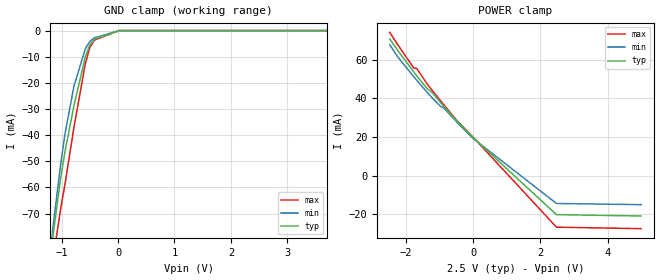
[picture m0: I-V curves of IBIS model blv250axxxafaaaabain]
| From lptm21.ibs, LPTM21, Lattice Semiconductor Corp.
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|   Model blv250axxxafaaaabain
[Model]   blv250axxxafaaaabain
Model_type   Input
Polarity   Non-Inverting
Enable   Active-Low
Vinl =   1.1500V
Vinh =   1.3500V
C_comp   4.2000pF   3.8000pF   7.5000pF
[Temperature Range]   25.0000   0.1050k   -40.0000
[Voltage Range]   2.5000V   2.3800V   2.6300V
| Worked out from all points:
|   GND clamp passes 1 mA (typ) near -0.13 V on its own axis
[GND_clamp]
|Voltage   I(typ)   I(min)   I(max)
-2.5V     -558.7mA   -538.8mA   -577.3mA
-1.22V    -91.65mA   -88.51mA   -100.2mA
-1.18V    -84.01mA   -80.7mA    -92.85mA
-1.14V    -76.64mA   -73.08mA   -85.95mA
-1.02V    -56.82mA   -51.79mA   -68.7mA
-940mV    -46.33mA   -39.59mA   -58.84mA
-780mV    -28.68mA   -21.23mA   -36.93mA
-580mV    -10.13mA   -7.016mA   -12.79mA
-500mV    -5.522mA   -4.164mA   -6.524mA
-420mV    -3.293mA   -2.799mA   -3.655mA
20mV      0A         0A         0A
5V        0A         0A         0A
[POWER_clamp]
|Voltage   I(typ)   I(min)   I(max)
-2.48V    70.8mA     67.79mA    74.22mA
-2.24V    64.81mA    61.5mA     67.79mA
-1.76V    53.56mA    51.12mA    55.62mA
-1.68V    51.75mA    49.46mA    55.62mA
-1.36V    44.95mA    43.02mA    47.29mA
-1.2V     42.73mA    39.97mA    43.79mA
-960mV    37.69mA    35.72mA    38.61mA
-880mV    36.09mA    35.18mA    36.9mA
-480mV    28.21mA    27.66mA    28.47mA
0V        19.67mA    19.21mA    19.91mA
2.48V     -20.27mA   -14.48mA   -26.76mA
5V        -20.96mA   -15.08mA   -27.53mA
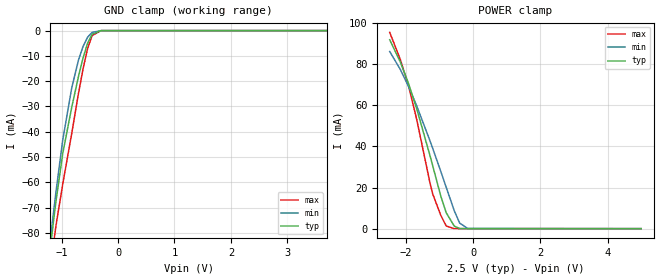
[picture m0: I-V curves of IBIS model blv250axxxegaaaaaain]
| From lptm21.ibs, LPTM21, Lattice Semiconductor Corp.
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|   Model blv250axxxegaaaaaain
[Model]   blv250axxxegaaaaaain
Model_type   Input
Polarity   Non-Inverting
Enable   Active-Low
Vinl =   1.1500V
Vinh =   1.3500V
C_comp   4.2000pF   3.8000pF   7.5000pF
[Temperature Range]   25.0000   0.1050k   -40.0000
[Voltage Range]   2.5000V   2.3800V   2.6300V
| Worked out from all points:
|   GND clamp passes 1 mA (typ) near -0.44 V on its own axis
|   POWER clamp passes 1 mA (typ) near -0.54 V on its own axis
[GND_clamp]
|Voltage   I(typ)   I(min)   I(max)
-2.5V     -564.7mA   -543.1mA   -585.2mA
-1.18V    -82.35mA   -79.03mA   -91.15mA
-1.14V    -74.88mA   -71.38mA   -83.96mA
-1.1V     -67.69mA   -63.94mA   -77.25mA
-980mV    -48.66mA   -43.36mA   -60.79mA
-820mV    -30.34mA   -22.65mA   -40.66mA
-700mV    -18.09mA   -11.63mA   -24.79mA
-620mV    -10.87mA   -6.335mA   -15.23mA
-540mV    -5.061mA   -2.654mA   -7.227mA
-460mV    -1.446mA   -714.8uA   -1.98mA
-300mV    -18.71uA   -15.93uA   -16.53uA
5V        0A         0A         0A
[POWER_clamp]
|Voltage   I(typ)   I(min)   I(max)
-2.48V    91.96mA    86.23mA    95.54mA
-2.16V    80.94mA    77.35mA    82.15mA
-1.92V    70.61mA    69.17mA    69.43mA
-1.68V    58.52mA    59.9mA     53.37mA
-1.28V    35.44mA    42.67mA    22.07mA
-1.2V     30.53mA    39.03mA    16.84mA
-960mV    15.8mA     27.82mA    6.447mA
-800mV    7.76mA     20.14mA    1.303mA
-560mV    1.23mA     8.728mA    11.53uA
-400mV    83.98uA    2.726mA    532.6nA
-160mV    776.1nA    102uA      144nA
5V        -44.09nA   -38.33nA   -118.7nA
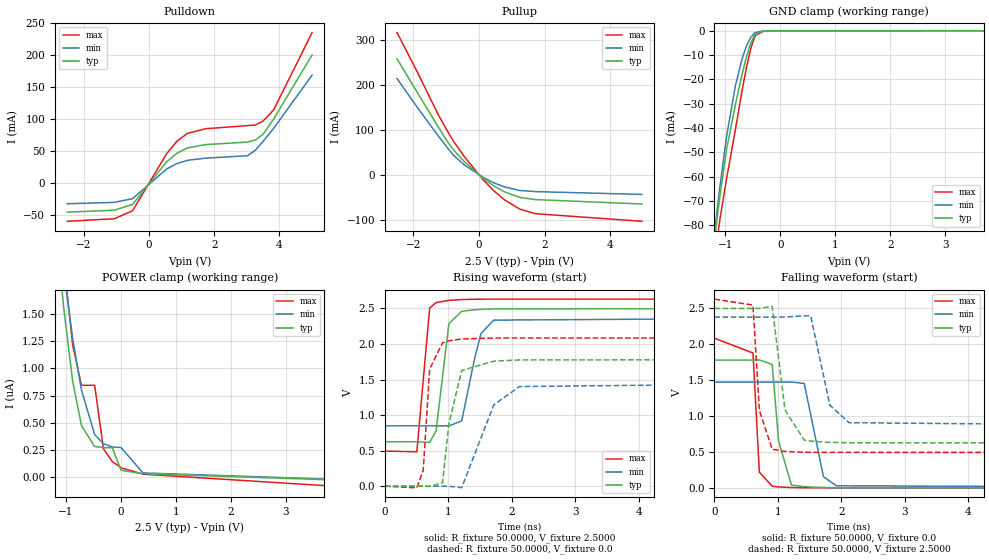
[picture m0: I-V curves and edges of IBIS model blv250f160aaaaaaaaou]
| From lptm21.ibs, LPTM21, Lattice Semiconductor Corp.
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|   Model blv250f160aaaaaaaaou
[Model]   blv250f160aaaaaaaaou
Model_type   Output
Polarity   Non-Inverting
Enable   Active-Low
Vmeas =   1.2500V
Cref =   3.0000pF
Rref =   50.0000
Vref =   1.2500V
C_comp   4.2000pF   3.8000pF   7.5000pF
[Temperature Range]   25.0000   0.1050k   -40.0000
[Voltage Range]   2.5000V   2.3800V   2.6300V
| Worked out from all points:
|   slope of the pulldown table from 0 to 0.375 V, typ, clamps not added: 15.3 ohm
|   slope of the pullup table from 0 to 0.375 V, typ, clamps not added: 18 ohm
|   GND clamp passes 1 mA (typ) near -0.44 V on its own axis
|   rising waveform, R_fixture 50.0000, V_fixture 2.5000: 20-80 % time 151ps typ, 227ps min, 128ps max; typ from 0.625 V to 2.5 V
|   rising waveform, R_fixture 50.0000, V_fixture 0.0: 20-80 % time 162ps typ, 247ps min, 94.8ps max; typ from 0 V to 1.78 V
|   falling waveform, R_fixture 50.0000, V_fixture 0.0: 20-80 % time 129ps typ, 166ps min, 76.1ps max; typ from 1.78 V to 0 V
|   falling waveform, R_fixture 50.0000, V_fixture 2.5000: 20-80 % time 161ps typ, 218ps min, 111ps max; typ from 2.5 V to 0.625 V
[Pulldown]
|Voltage   I(typ)   I(min)   I(max)
-2.5V     -45.01mA   -31.89mA   -59.32mA
-1.06V    -42.02mA   -29.78mA   -55.34mA
-500mV    -32.92mA   -23.97mA   -42.85mA
540mV     33.4mA     22.28mA    46.08mA
860mV     47.04mA    30.89mA    65.83mA
1.18V     55.26mA    35.92mA    77.97mA
1.74V     60.53mA    39.31mA    85.33mA
3.02V     64.43mA    43.11mA    90.12mA
3.26V     67.48mA    51.68mA    91mA
3.5V      76.79mA    65.62mA    97.37mA
3.82V     100.3mA    85.69mA    114.5mA
5V        200.4mA    169mA      235.5mA
[Pullup]
|Voltage   I(typ)   I(min)   I(max)
-2.5V     258.2mA    214.4mA    316.6mA
-1.88V    183.3mA    150mA      228.6mA
-1.24V    106.2mA    86.52mA    133.5mA
-920mV    69.28mA    56.27mA    92.01mA
-760mV    54.09mA    42.32mA    72.99mA
-440mV    29.04mA    21.78mA    39.92mA
120mV     -7.175mA   -5.214mA   -10.22mA
440mV     -23.93mA   -17.18mA   -34.6mA
760mV     -37.13mA   -26.3mA    -54.62mA
1.24V     -50.01mA   -34.55mA   -75.93mA
1.72V     -54.85mA   -37.09mA   -86.23mA
4.96V     -64.63mA   -43.33mA   -103.1mA
[GND_clamp]
|Voltage   I(typ)   I(min)   I(max)
-2.5V     -564.7mA   -543.1mA   -585.2mA
-1.18V    -82.35mA   -79.03mA   -91.15mA
-1.14V    -74.88mA   -71.38mA   -83.96mA
-1.1V     -67.69mA   -63.94mA   -77.25mA
-980mV    -48.66mA   -43.36mA   -60.79mA
-820mV    -30.34mA   -22.65mA   -40.66mA
-700mV    -18.09mA   -11.63mA   -24.79mA
-620mV    -10.87mA   -6.335mA   -15.23mA
-540mV    -5.061mA   -2.654mA   -7.227mA
-460mV    -1.446mA   -714.8uA   -1.98mA
-300mV    -18.71uA   -15.93uA   -16.53uA
5V        0A         0A         0A
[POWER_clamp]
|Voltage   I(typ)   I(min)   I(max)
-2.48V    16.67uA    13.46uA    27.27uA
-1.2V     2.437uA    2.654uA    3.193uA
-1.12V    1.961uA    2.256uA    2.523uA
-1.04V    1.543uA    1.893uA    1.968uA
-880mV    882.5nA    1.274uA    1.214uA
-720mV    473.9nA    800.3nA    844.3nA
-480mV    282.1nA    391.2nA    844.3nA
-320mV    271.3nA    307.6nA    260.6nA
-160mV    271.3nA    277.8nA    144nA
0V        63.22nA    272nA      86.34nA
400mV     31.61nA    39.07nA    27.38nA
5V        -44.09nA   -38.33nA   -118.7nA
[Ramp]
| variable   typ   min   max
dV/dt_r  1.0688/0.1604n   0.8847/0.2443n   1.2507/93.8258p
dV/dt_f  1.1250/0.1592n   0.9191/0.2160n   1.2817/0.1102n
R_load = 50.0000
[Rising Waveform]
R_fixture=   50.0000
V_fixture=   2.5000
V_fixture_min=   2.3800
V_fixture_max=   2.6300
|time   V(typ)   V(min)   V(max)
0s        625.1mV    848.2mV    493.8mV
505.1ps   625.1mV    848.2mV    483.9mV
707.1ps   617.1mV    848.2mV    2.504V
808.1ps   777mV      848.3mV    2.581V
1.01ns    2.285V     846.8mV    2.613V
1.212ns   2.459V     919.1mV    2.624V
1.414ns   2.481V     1.791V     2.628V
1.515ns   2.486V     2.145V     2.629V
1.717ns   2.493V     2.335V     2.63V
10ns      2.5V       2.38V      2.63V
[Rising Waveform]
R_fixture=   50.0000
V_fixture=   0.0
V_fixture_min=   0.0
V_fixture_max=   0.0
|time   V(typ)   V(min)   V(max)
0s        394.5nV    565.3nV    312nV
505.1ps   17.53uV    728.7nV    -23.3mV
606.1ps   -153.3uV   722.6nV    227.1mV
707.1ps   -3.764mV   9.302uV    1.646V
909.1ps   47.24mV    -32.83uV   2.015V
1.01ns    876.9mV    -402.3uV   2.044V
1.212ns   1.627V     -20.32mV   2.07V
1.717ns   1.758V     1.143V     2.083V
2.121ns   1.775V     1.401V     2.084V
10ns      1.781V     1.474V     2.084V
[Falling Waveform]
R_fixture=   50.0000
V_fixture=   0.0
V_fixture_min=   0.0
V_fixture_max=   0.0
|time   V(typ)   V(min)   V(max)
0s        1.781V     1.474V     2.085V
606.1ps   1.781V     1.474V     1.879V
707.1ps   1.782V     1.474V     218.8mV
909.1ps   1.721V     1.474V     23.28mV
1.01ns    651.4mV    1.474V     13.07mV
1.212ns   38.57mV    1.475V     4.117mV
1.414ns   15.95mV    1.455V     1.284mV
1.717ns   5.3mV      156.1mV    203.4uV
1.919ns   2.469mV    29.32mV    71.82uV
10ns      15.52uV    -1.266uV   20.45uV
[Falling Waveform]
R_fixture=   50.0000
V_fixture=   2.5000
V_fixture_min=   2.3800
V_fixture_max=   2.6300
|time   V(typ)   V(min)   V(max)
0s        2.5V       2.38V      2.63V
606.1ps   2.5V       2.38V      2.547V
707.1ps   2.501V     2.38V      1.082V
909.1ps   2.529V     2.38V      538.3mV
1.111ns   1.085V     2.381V     507.8mV
1.414ns   665.1mV    2.397V     496.4mV
1.515ns   652.2mV    2.397V     495.3mV
1.818ns   634.3mV    1.151V     494.1mV
2.121ns   628.4mV    907.9mV    493.9mV
10ns      625.1mV    848.2mV    493.8mV
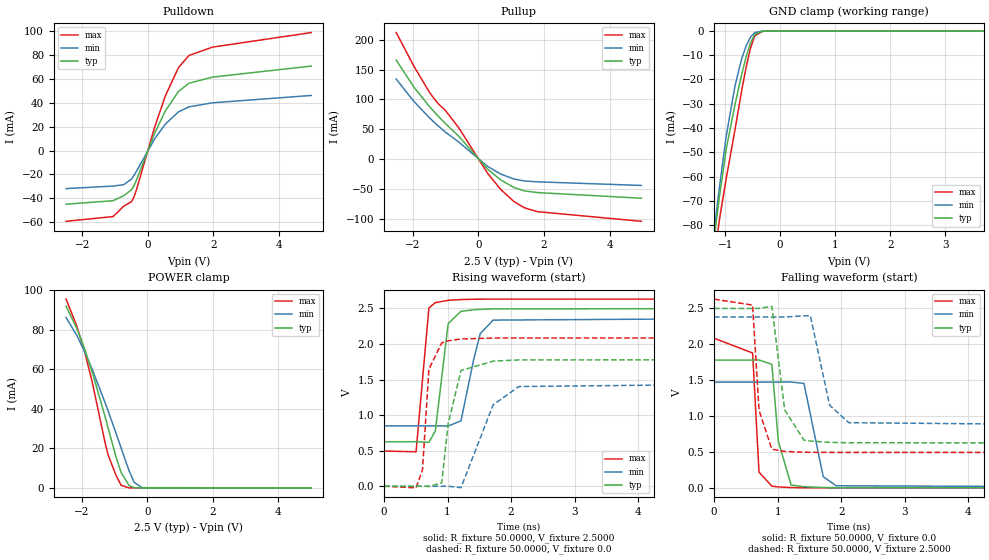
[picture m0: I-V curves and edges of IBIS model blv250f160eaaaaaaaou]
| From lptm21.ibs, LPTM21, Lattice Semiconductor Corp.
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|   Model blv250f160eaaaaaaaou
[Model]   blv250f160eaaaaaaaou
Model_type   Output
Polarity   Non-Inverting
Enable   Active-Low
Vmeas =   1.2500V
Cref =   3.0000pF
Rref =   50.0000
Vref =   1.2500V
C_comp   4.2000pF   3.8000pF   7.5000pF
[Temperature Range]   25.0000   0.1050k   -40.0000
[Voltage Range]   2.5000V   2.3800V   2.6300V
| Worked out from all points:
|   slope of the pulldown table from 0 to 0.375 V, typ, clamps not added: 15.3 ohm
|   slope of the pullup table from 0 to 0.375 V, typ, clamps not added: 18 ohm
|   GND clamp passes 1 mA (typ) near -0.44 V on its own axis
|   POWER clamp passes 1 mA (typ) near -0.54 V on its own axis
|   rising waveform, R_fixture 50.0000, V_fixture 2.5000: 20-80 % time 151ps typ, 227ps min, 128ps max; typ from 0.625 V to 2.5 V
|   rising waveform, R_fixture 50.0000, V_fixture 0.0: 20-80 % time 162ps typ, 247ps min, 94.8ps max; typ from 0 V to 1.78 V
|   falling waveform, R_fixture 50.0000, V_fixture 0.0: 20-80 % time 129ps typ, 166ps min, 76.1ps max; typ from 1.78 V to 0 V
|   falling waveform, R_fixture 50.0000, V_fixture 2.5000: 20-80 % time 161ps typ, 218ps min, 111ps max; typ from 2.5 V to 0.625 V
[Pulldown]
|Voltage   I(typ)   I(min)   I(max)
-2.5V     -45.01mA   -31.89mA   -59.32mA
-1.06V    -42.02mA   -29.78mA   -55.34mA
-740mV    -37.94mA   -28.65mA   -46.63mA
-500mV    -32.92mA   -23.97mA   -42.85mA
-420mV    -29.33mA   -20.8mA    -38.83mA
-340mV    -24.22mA   -16.99mA   -32.2mA
220mV     15.1mA     10.24mA    20.53mA
540mV     33.4mA     22.28mA    46.08mA
940mV     49.63mA    32.48mA    69.67mA
1.26V     56.49mA    36.69mA    79.75mA
1.98V     61.61mA    40.05mA    86.74mA
5V        70.84mA    46.21mA    98.95mA
[Pullup]
|Voltage   I(typ)   I(min)   I(max)
-2.5V     165.7mA    134mA      211.6mA
-1.96V    120.5mA    96.72mA    155.3mA
-1.48V    87.72mA    68.96mA    111.3mA
-1.24V    73.19mA    56.8mA     94mA
-1V       59.8mA     45.49mA    81.65mA
-600mV    38.92mA    29.24mA    53.03mA
280mV     -15.99mA   -11.55mA   -22.94mA
680mV     -34.17mA   -24.29mA   -50.04mA
1.08V     -46.66mA   -32.52mA   -70.04mA
1.4V      -52.41mA   -35.87mA   -80.58mA
1.8V      -55.2mA    -37.28mA   -87.03mA
4.96V     -64.63mA   -43.33mA   -103.1mA
[GND_clamp]
|Voltage   I(typ)   I(min)   I(max)
-2.5V     -564.7mA   -543.1mA   -585.2mA
-1.18V    -82.35mA   -79.03mA   -91.15mA
-1.14V    -74.88mA   -71.38mA   -83.96mA
-1.1V     -67.69mA   -63.94mA   -77.25mA
-980mV    -48.66mA   -43.36mA   -60.79mA
-820mV    -30.34mA   -22.65mA   -40.66mA
-700mV    -18.09mA   -11.63mA   -24.79mA
-620mV    -10.87mA   -6.335mA   -15.23mA
-540mV    -5.061mA   -2.654mA   -7.227mA
-460mV    -1.446mA   -714.8uA   -1.98mA
-300mV    -18.71uA   -15.93uA   -16.53uA
5V        0A         0A         0A
[POWER_clamp]
|Voltage   I(typ)   I(min)   I(max)
-2.48V    91.96mA    86.23mA    95.54mA
-2.16V    80.94mA    77.35mA    82.15mA
-1.92V    70.61mA    69.17mA    69.43mA
-1.68V    58.52mA    59.9mA     53.37mA
-1.28V    35.44mA    42.67mA    22.07mA
-1.2V     30.53mA    39.03mA    16.84mA
-960mV    15.8mA     27.82mA    6.447mA
-800mV    7.76mA     20.14mA    1.303mA
-560mV    1.23mA     8.728mA    11.53uA
-400mV    83.98uA    2.726mA    532.6nA
-160mV    776.1nA    102uA      144nA
5V        -44.09nA   -38.33nA   -118.7nA
[Ramp]
| variable   typ   min   max
dV/dt_r  1.0688/0.1604n   0.8847/0.2443n   1.2507/93.8258p
dV/dt_f  1.1250/0.1592n   0.9191/0.2160n   1.2817/0.1102n
R_load = 50.0000
[Rising Waveform]
R_fixture=   50.0000
V_fixture=   2.5000
V_fixture_min=   2.3800
V_fixture_max=   2.6300
|time   V(typ)   V(min)   V(max)
0s        625.1mV    848.2mV    493.8mV
505.1ps   625.1mV    848.2mV    483.9mV
707.1ps   617.1mV    848.2mV    2.504V
808.1ps   777mV      848.3mV    2.581V
1.01ns    2.285V     846.8mV    2.613V
1.212ns   2.459V     919.1mV    2.624V
1.414ns   2.481V     1.791V     2.628V
1.515ns   2.486V     2.145V     2.629V
1.717ns   2.493V     2.335V     2.63V
10ns      2.5V       2.38V      2.63V
[Rising Waveform]
R_fixture=   50.0000
V_fixture=   0.0
V_fixture_min=   0.0
V_fixture_max=   0.0
|time   V(typ)   V(min)   V(max)
0s        394.5nV    565.3nV    312nV
505.1ps   17.53uV    728.7nV    -23.3mV
606.1ps   -153.3uV   722.6nV    227.1mV
707.1ps   -3.764mV   9.302uV    1.646V
909.1ps   47.24mV    -32.83uV   2.015V
1.01ns    876.9mV    -402.3uV   2.044V
1.212ns   1.627V     -20.32mV   2.07V
1.717ns   1.758V     1.143V     2.083V
2.121ns   1.775V     1.401V     2.084V
10ns      1.781V     1.474V     2.084V
[Falling Waveform]
R_fixture=   50.0000
V_fixture=   0.0
V_fixture_min=   0.0
V_fixture_max=   0.0
|time   V(typ)   V(min)   V(max)
0s        1.781V     1.474V     2.085V
606.1ps   1.781V     1.474V     1.879V
707.1ps   1.782V     1.474V     218.8mV
909.1ps   1.721V     1.474V     23.28mV
1.01ns    651.4mV    1.474V     13.07mV
1.212ns   38.57mV    1.475V     4.117mV
1.414ns   15.95mV    1.455V     1.284mV
1.717ns   5.3mV      156.1mV    203.4uV
1.919ns   2.469mV    29.32mV    71.82uV
10ns      15.52uV    -1.266uV   20.45uV
[Falling Waveform]
R_fixture=   50.0000
V_fixture=   2.5000
V_fixture_min=   2.3800
V_fixture_max=   2.6300
|time   V(typ)   V(min)   V(max)
0s        2.5V       2.38V      2.63V
606.1ps   2.5V       2.38V      2.547V
707.1ps   2.501V     2.38V      1.082V
909.1ps   2.529V     2.38V      538.3mV
1.111ns   1.085V     2.381V     507.8mV
1.414ns   665.1mV    2.397V     496.4mV
1.515ns   652.2mV    2.397V     495.3mV
1.818ns   634.3mV    1.151V     494.1mV
2.121ns   628.4mV    907.9mV    493.9mV
10ns      625.1mV    848.2mV    493.8mV
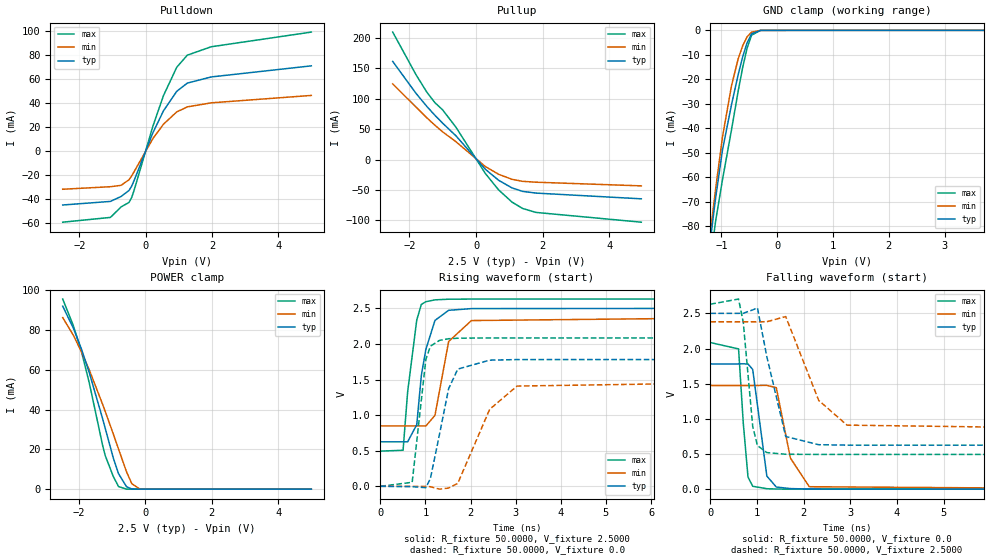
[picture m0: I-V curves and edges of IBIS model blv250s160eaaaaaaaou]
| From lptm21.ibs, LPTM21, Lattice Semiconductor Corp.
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|   Model blv250s160eaaaaaaaou
[Model]   blv250s160eaaaaaaaou
Model_type   Output
Polarity   Non-Inverting
Enable   Active-Low
Vmeas =   1.2500V
Cref =   3.0000pF
Rref =   50.0000
Vref =   1.2500V
C_comp   4.2000pF   3.8000pF   7.5000pF
[Temperature Range]   25.0000   0.1050k   -40.0000
[Voltage Range]   2.5000V   2.3800V   2.6300V
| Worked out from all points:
|   slope of the pulldown table from 0 to 0.375 V, typ, clamps not added: 15.3 ohm
|   slope of the pullup table from 0 to 0.375 V, typ, clamps not added: 18 ohm
|   GND clamp passes 1 mA (typ) near -0.44 V on its own axis
|   POWER clamp passes 1 mA (typ) near -0.54 V on its own axis
|   rising waveform, R_fixture 50.0000, V_fixture 2.5000: 20-80 % time 272ps typ, 308ps min, 221ps max; typ from 0.625 V to 2.5 V
|   rising waveform, R_fixture 50.0000, V_fixture 0.0: 20-80 % time 340ps typ, 590ps min, 210ps max; typ from 0 V to 1.78 V
|   falling waveform, R_fixture 50.0000, V_fixture 0.0: 20-80 % time 209ps typ, 295ps min, 139ps max; typ from 1.78 V to 0 V
|   falling waveform, R_fixture 50.0000, V_fixture 2.5000: 20-80 % time 297ps typ, 529ps min, 177ps max; typ from 2.5 V to 0.625 V
[Pulldown]
|Voltage   I(typ)   I(min)   I(max)
-2.5V     -45.01mA   -31.89mA   -59.32mA
-1.06V    -42.02mA   -29.78mA   -55.34mA
-740mV    -37.94mA   -28.65mA   -46.63mA
-500mV    -32.92mA   -23.97mA   -42.85mA
-420mV    -29.33mA   -20.8mA    -38.83mA
-340mV    -24.22mA   -16.99mA   -32.2mA
220mV     15.1mA     10.24mA    20.53mA
540mV     33.4mA     22.28mA    46.08mA
940mV     49.63mA    32.48mA    69.67mA
1.26V     56.49mA    36.69mA    79.75mA
1.98V     61.61mA    40.05mA    86.74mA
5V        70.84mA    46.21mA    98.95mA
[Pullup]
|Voltage   I(typ)   I(min)   I(max)
-2.5V     161.5mA    124.6mA    209.8mA
-1.8V     108.9mA    86.32mA    139.6mA
-1.48V    87.72mA    68.93mA    111.3mA
-1.24V    73.19mA    56.8mA     94mA
-1V       59.8mA     45.49mA    81.65mA
-600mV    38.92mA    29.24mA    53.03mA
280mV     -15.99mA   -11.55mA   -22.94mA
680mV     -34.17mA   -24.29mA   -50.04mA
1.08V     -46.66mA   -32.52mA   -70.04mA
1.4V      -52.41mA   -35.87mA   -80.58mA
1.8V      -55.2mA    -37.28mA   -87.03mA
4.96V     -64.63mA   -43.33mA   -103.1mA
[GND_clamp]
|Voltage   I(typ)   I(min)   I(max)
-2.5V     -564.7mA   -543.1mA   -585.2mA
-1.18V    -82.35mA   -79.03mA   -91.15mA
-1.14V    -74.88mA   -71.38mA   -83.96mA
-1.1V     -67.69mA   -63.94mA   -77.25mA
-980mV    -48.66mA   -43.36mA   -60.79mA
-820mV    -30.34mA   -22.65mA   -40.66mA
-700mV    -18.09mA   -11.63mA   -24.79mA
-620mV    -10.87mA   -6.335mA   -15.23mA
-540mV    -5.061mA   -2.654mA   -7.227mA
-460mV    -1.446mA   -714.8uA   -1.98mA
-300mV    -18.71uA   -15.93uA   -16.53uA
5V        0A         0A         0A
[POWER_clamp]
|Voltage   I(typ)   I(min)   I(max)
-2.48V    91.96mA    86.23mA    95.54mA
-2.16V    80.94mA    77.35mA    82.15mA
-1.92V    70.61mA    69.17mA    69.43mA
-1.68V    58.52mA    59.9mA     53.37mA
-1.28V    35.44mA    42.67mA    22.07mA
-1.2V     30.53mA    39.03mA    16.84mA
-960mV    15.8mA     27.82mA    6.447mA
-800mV    7.76mA     20.14mA    1.303mA
-560mV    1.23mA     8.728mA    11.53uA
-400mV    83.98uA    2.726mA    532.6nA
-160mV    776.1nA    102uA      144nA
5V        -44.09nA   -38.33nA   -118.7nA
[Ramp]
| variable   typ   min   max
dV/dt_r  1.0688/0.3361n   0.8847/0.5844n   1.2507/0.2078n
dV/dt_f  1.1250/0.2937n   0.9191/0.5242n   1.2817/0.1754n
R_load = 50.0000
[Rising Waveform]
R_fixture=   50.0000
V_fixture=   2.5000
V_fixture_min=   2.3800
V_fixture_max=   2.6300
|time   V(typ)   V(min)   V(max)
0s        625.1mV    848.2mV    493.8mV
505.1ps   625.1mV    848.2mV    506.6mV
606.1ps   625.1mV    848.2mV    1.325V
808.1ps   864.9mV    848.3mV    2.336V
909.1ps   1.554V     848.7mV    2.554V
1.01ns    1.922V     847.3mV    2.593V
1.212ns   2.33V      996.3mV    2.619V
1.515ns   2.472V     2.034V     2.628V
2.02ns    2.496V     2.328V     2.63V
10ns      2.5V       2.38V      2.63V
[Rising Waveform]
R_fixture=   50.0000
V_fixture=   0.0
V_fixture_min=   0.0
V_fixture_max=   0.0
|time   V(typ)   V(min)   V(max)
0s        394.5nV    565.3nV    312nV
707.1ps   -5.27mV    7.859uV    56.14mV
1.01ns    -19.04mV   -648.7uV   1.782V
1.111ns   109.3mV    -5.939mV   1.968V
1.313ns   731.5mV    -40.24mV   2.05V
1.515ns   1.372V     -24.24mV   2.073V
1.717ns   1.646V     41.02mV    2.08V
2.424ns   1.772V     1.081V     2.084V
3.03ns    1.78V      1.408V     2.084V
10ns      1.781V     1.474V     2.084V
[Falling Waveform]
R_fixture=   50.0000
V_fixture=   0.0
V_fixture_min=   0.0
V_fixture_max=   0.0
|time   V(typ)   V(min)   V(max)
0s        1.781V     1.474V     2.085V
606.1ps   1.781V     1.474V     1.994V
707.1ps   1.782V     1.474V     937.7mV
808.1ps   1.78V      1.474V     171.8mV
909.1ps   1.702V     1.474V     41.12mV
1.212ns   185.6mV    1.475V     6.403mV
1.414ns   30.45mV    1.443V     1.915mV
1.717ns   8.322mV    441.2mV    357.2uV
2.121ns   1.731mV    34.79mV    86.71uV
10ns      -26.63uV   17.43uV    -15.71uV
[Falling Waveform]
R_fixture=   50.0000
V_fixture=   2.5000
V_fixture_min=   2.3800
V_fixture_max=   2.6300
|time   V(typ)   V(min)   V(max)
0s        2.5V       2.38V      2.63V
606.1ps   2.5V       2.38V      2.703V
707.1ps   2.501V     2.38V      2.371V
909.1ps   2.549V     2.38V      891mV
1.01ns    2.579V     2.38V      620.9mV
1.212ns   1.882V     2.381V     520mV
1.616ns   748.9mV    2.454V     496.3mV
2.323ns   631.9mV    1.262V     493.9mV
2.929ns   625.8mV    910.5mV    493.8mV
10ns      625.1mV    848.2mV    493.8mV
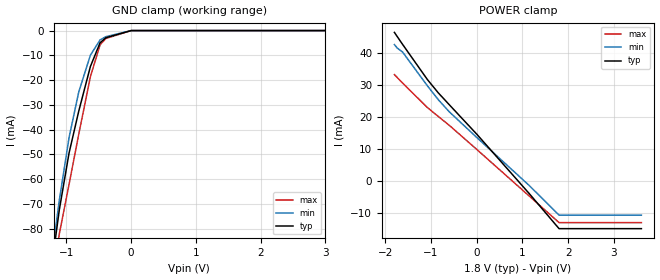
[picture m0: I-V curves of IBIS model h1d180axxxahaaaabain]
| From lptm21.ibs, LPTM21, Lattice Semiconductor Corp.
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|   Model h1d180axxxahaaaabain
[Model]   h1d180axxxahaaaabain
Model_type   Input
Polarity   Non-Inverting
Enable   Active-Low
Vinl =   0.8000V
Vinh =   1.0000V
C_comp   4.2000pF   3.8000pF   7.5000pF
[Temperature Range]   25.0000   0.1050k   -40.0000
[Voltage Range]   1.8000V   1.7100V   1.8900V
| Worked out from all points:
|   GND clamp passes 1 mA (typ) near -0.15 V on its own axis
[GND_clamp]
|Voltage   I(typ)   I(min)   I(max)
-1.8V     -238.8mA   -229.8mA   -251mA
-1.68V    -195.8mA   -191.3mA   -205.4mA
-1.59V    -171.3mA   -168.3mA   -180.2mA
-1.32V    -112.7mA   -109.7mA   -121.2mA
-1.11V    -72.3mA    -68.46mA   -82.04mA
-960mV    -49.45mA   -43.22mA   -62.1mA
-810mV    -32.53mA   -24.78mA   -41.85mA
-630mV    -14.51mA   -9.933mA   -18.63mA
-480mV    -4.901mA   -3.748mA   -5.697mA
-390mV    -2.877mA   -2.46mA    -3.176mA
0V        0A         0A         0A
3.6V      0A         0A         0A
[POWER_clamp]
|Voltage   I(typ)   I(min)   I(max)
-1.8V     46.34mA    42.53mA    33.16mA
-1.74V    45.07mA    41.47mA    32.27mA
-1.62V    42.57mA    40.18mA    30.5mA
-1.08V    31.63mA    29.68mA    22.88mA
-840mV    27.44mA    25.31mA    20.07mA
-600mV    23.74mA    21.53mA    17.3mA
0V        14.55mA    13.52mA    9.788mA
1.14V     -3.886mA   -1.395mA   -4.684mA
1.8V      -14.97mA   -10.75mA   -13.08mA
3.6V      -14.97mA   -10.75mA   -13.08mA
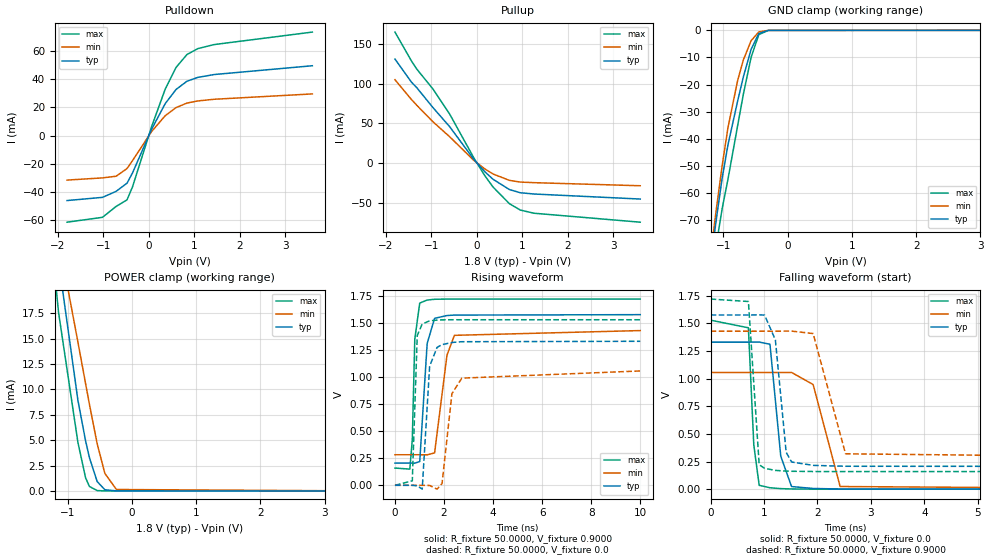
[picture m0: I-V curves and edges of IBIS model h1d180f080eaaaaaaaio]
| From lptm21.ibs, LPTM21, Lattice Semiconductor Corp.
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|   Model h1d180f080eaaaaaaaio
[Model]   h1d180f080eaaaaaaaio
Model_type   I/O
Polarity   Non-Inverting
Enable   Active-Low
Vinl =   0.8000V
Vinh =   1.0000V
Vmeas =   0.9000V
Cref =   20.0000pF
Rref =   50.0000
Vref =   0.9000V
C_comp   4.2000pF   3.8000pF   7.5000pF
[Temperature Range]   25.0000   0.1050k   -40.0000
[Voltage Range]   1.8000V   1.7100V   1.8900V
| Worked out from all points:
|   slope of the pulldown table from 0 to 0.27 V, typ, clamps not added: 15.3 ohm
|   slope of the pullup table from 0 to 0.27 V, typ, clamps not added: 16.6 ohm
|   GND clamp passes 1 mA (typ) near -0.44 V on its own axis
|   POWER clamp passes 1 mA (typ) near -0.54 V on its own axis
|   rising waveform, R_fixture 50.0000, V_fixture 0.9000: 20-80 % time 180ps typ, 330ps min, 116ps max; typ from 0.205 V to 1.58 V
|   rising waveform, R_fixture 50.0000, V_fixture 0.0: 20-80 % time 193ps typ, 313ps min, 138ps max; typ from 0 V to 1.33 V
|   falling waveform, R_fixture 50.0000, V_fixture 0.0: 20-80 % time 150ps typ, 219ps min, 105ps max; typ from 1.33 V to 0 V
|   falling waveform, R_fixture 50.0000, V_fixture 0.9000: 20-80 % time 157ps typ, 228ps min, 123ps max; typ from 1.58 V to 0.205 V
[Pulldown]
|Voltage   I(typ)   I(min)   I(max)
-1.8V     -45.94mA   -31.47mA   -61.23mA
-1.02V    -43.68mA   -29.93mA   -57.79mA
-720mV    -39.44mA   -28.75mA   -50.1mA
-480mV    -33.68mA   -23.32mA   -45.45mA
-360mV    -26.52mA   -17.8mA    -36.39mA
60mV      4.338mA    2.763mA    6.157mA
360mV     22.51mA    13.97mA    32.68mA
600mV     32.57mA    19.77mA    48.13mA
840mV     38.38mA    22.95mA    57.28mA
1.08V     41.11mA    24.46mA    61.43mA
1.44V     43.12mA    25.64mA    64.3mA
3.6V      49.33mA    29.42mA    73.11mA
[Pullup]
|Voltage   I(typ)   I(min)   I(max)
-1.8V     130.8mA    104.8mA    164.8mA
-1.44V    101.9mA    80.06mA    128.7mA
-1.32V    94.74mA    72.59mA    118.2mA
-960mV    69.42mA    51.57mA    92.77mA
-600mV    45.83mA    33.12mA    61.9mA
-60mV     4.151mA    2.888mA    5.883mA
180mV     -11.32mA   -7.745mA   -16.38mA
360mV     -20.77mA   -14.04mA   -30.53mA
720mV     -33.7mA    -22.13mA   -51.5mA
960mV     -37.7mA    -24.23mA   -59.52mA
1.26V     -39.29mA   -24.99mA   -63.51mA
3.6V      -45.64mA   -28.87mA   -74.81mA
[GND_clamp]
|Voltage   I(typ)   I(min)   I(max)
-1.8V     -240.2mA   -229.4mA   -254.3mA
-1.2V     -86.16mA   -82.91mA   -94.88mA
-1.17V    -80.45mA   -77.09mA   -89.3mA
-1.11V    -69.45mA   -65.77mA   -78.87mA
-1.02V    -54.48mA   -49.86mA   -65.69mA
-930mV    -42.25mA   -35.9mA    -54.92mA
-780mV    -26.14mA   -18.58mA   -35.25mA
-690mV    -17.13mA   -10.87mA   -23.53mA
-570mV    -7.024mA   -3.834mA   -9.978mA
-450mV    -1.176mA   -584.6uA   -1.582mA
-300mV    -18.65uA   -15.9uA    -16.44uA
3.6V      0A         0A         0A
[POWER_clamp]
|Voltage   I(typ)   I(min)   I(max)
-1.8V     52.51mA    44.24mA    59.69mA
-1.68V    47.44mA    41.17mA    52.62mA
-1.5V     39.45mA    36.1mA     41.14mA
-1.26V    28.3mA     28.66mA    24.99mA
-1.14V    22.57mA    24.76mA    17.52mA
-840mV    8.928mA    14.66mA    4.779mA
-720mV    4.91mA     10.55mA    1.28mA
-660mV    3.265mA    8.507mA    435.9uA
-540mV    921.6uA    4.64mA     35.01uA
-420mV    115.2uA    1.718mA    2.184uA
-240mV    3.289uA    139.9uA    57.44nA
3.6V      -31nA      -27.04nA   -40.53nA
[Ramp]
| variable   typ   min   max
dV/dt_r  0.7825/0.1911n   0.6334/0.3102n   0.9175/0.1364n
dV/dt_f  0.8078/0.1690n   0.6265/0.2657n   0.9309/0.1315n
R_load = 50.0000
[Rising Waveform]
R_fixture=   50.0000
V_fixture=   0.9000
V_fixture_min=   0.8560
V_fixture_max=   0.9460
|time   V(typ)   V(min)   V(max)
0s        205.4mV    282.1mV    159.2mV
606.1ps   205.5mV    282.1mV    149.5mV
707.1ps   205.5mV    282.1mV    420.4mV
808.1ps   204.2mV    282.1mV    1.349V
1.01ns    219.3mV    282.1mV    1.683V
1.313ns   1.31V      281.2mV    1.711V
1.616ns   1.542V     299.4mV    1.718V
2.121ns   1.568V     1.202V     1.72V
2.424ns   1.572V     1.385V     1.72V
10ns      1.576V     1.429V     1.72V
[Rising Waveform]
R_fixture=   50.0000
V_fixture=   0.0
V_fixture_min=   0.0
V_fixture_max=   0.0
|time   V(typ)   V(min)   V(max)
0s        291.2nV    449.5nV    213.5nV
707.1ps   -66.11uV   471.6nV    41.17mV
909.1ps   -5.379mV   13.43uV    1.383V
1.111ns   -35.38mV   1.878uV    1.49V
1.414ns   1.1V       -1.561mV   1.519V
1.717ns   1.274V     -35.75mV   1.526V
1.919ns   1.299V     16.28mV    1.528V
2.323ns   1.319V     846.2mV    1.529V
2.727ns   1.326V     989.7mV    1.529V
10ns      1.33V      1.056V     1.529V
[Falling Waveform]
R_fixture=   50.0000
V_fixture=   0.0
V_fixture_min=   0.0
V_fixture_max=   0.0
|time   V(typ)   V(min)   V(max)
0s        1.33V      1.056V     1.529V
707.1ps   1.33V      1.056V     1.46V
808.1ps   1.331V     1.056V     400.6mV
909.1ps   1.331V     1.056V     34.93mV
1.111ns   1.311V     1.056V     12.68mV
1.313ns   298.2mV    1.056V     4.841mV
1.515ns   23.7mV     1.056V     1.873mV
1.919ns   6.253mV    946.7mV    286.4uV
2.424ns   1.457mV    23.95mV    46.04uV
10ns      -31.16uV   8.476uV    8.918uV
[Falling Waveform]
R_fixture=   50.0000
V_fixture=   0.9000
V_fixture_min=   0.8560
V_fixture_max=   0.9460
|time   V(typ)   V(min)   V(max)
0s        1.576V     1.429V     1.72V
707.1ps   1.576V     1.429V     1.698V
909.1ps   1.577V     1.429V     221.1mV
1.01ns    1.575V     1.429V     188.4mV
1.212ns   1.351V     1.429V     169.9mV
1.414ns   334mV      1.43V      163.3mV
1.515ns   245.8mV    1.43V      161.8mV
1.919ns   215.3mV    1.408V     159.7mV
2.525ns   207.2mV    320mV      159.3mV
10ns      205.4mV    282.1mV    159.2mV
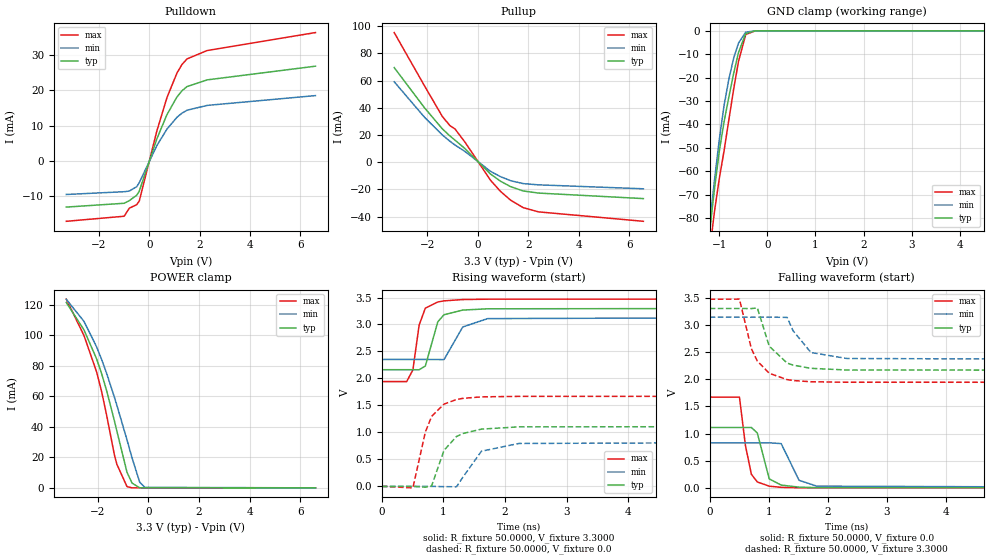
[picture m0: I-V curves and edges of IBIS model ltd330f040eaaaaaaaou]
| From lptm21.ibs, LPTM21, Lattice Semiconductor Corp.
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|   Model ltd330f040eaaaaaaaou
[Model]   ltd330f040eaaaaaaaou
Model_type   Output
Polarity   Non-Inverting
Enable   Active-Low
Vmeas =   1.6500V
Cref =   0.0F
Rref =   1.0000M
Vref =   0.0V
C_comp   4.2000pF   3.8000pF   7.5000pF
[Temperature Range]   25.0000   0.1050k   -40.0000
[Voltage Range]   3.3000V   3.1400V   3.4700V
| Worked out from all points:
|   slope of the pulldown table from 0 to 0.495 V, typ, clamps not added: 50.3 ohm
|   slope of the pullup table from 0 to 0.495 V, typ, clamps not added: 58.2 ohm
|   GND clamp passes 1 mA (typ) near -0.44 V on its own axis
|   POWER clamp passes 1 mA (typ) near -0.54 V on its own axis
|   rising waveform, R_fixture 50.0000, V_fixture 3.3000: 20-80 % time 185ps typ, 254ps min, 147ps max; typ from 2.16 V to 3.3 V
|   rising waveform, R_fixture 50.0000, V_fixture 0.0: 20-80 % time 304ps typ, 324ps min, 246ps max; typ from 0 V to 1.11 V
|   falling waveform, R_fixture 50.0000, V_fixture 0.0: 20-80 % time 159ps typ, 213ps min, 148ps max; typ from 1.11 V to 0 V
|   falling waveform, R_fixture 50.0000, V_fixture 3.3000: 20-80 % time 297ps typ, 309ps min, 289ps max; typ from 3.3 V to 2.16 V
[Pulldown]
|Voltage   I(typ)   I(min)   I(max)
-3.3V     -13.05mA   -9.484mA   -17.07mA
-1V       -11.97mA   -8.699mA   -15.64mA
-800mV    -11.24mA   -8.53mA    -13.38mA
-500mV    -9.688mA   -7.272mA   -12.36mA
-400mV    -8.535mA   -6.131mA   -11.32mA
300mV     6.289mA    4.363mA    8.526mA
700mV     13.11mA    9.021mA    17.92mA
1.1V      18.13mA    12.38mA    24.92mA
1.3V      19.87mA    13.54mA    27.32mA
1.5V      21.05mA    14.35mA    28.88mA
2.3V      22.94mA    15.72mA    31.24mA
6.6V      26.81mA    18.49mA    36.32mA
[Pullup]
|Voltage   I(typ)   I(min)   I(max)
-3.3V     69.63mA    59.18mA    95.38mA
-2.1V     40mA       33.06mA    56.09mA
-1.4V     24.61mA    20.13mA    33.74mA
-1.1V     19.35mA    15.48mA    26.98mA
-900mV    16.32mA    12.69mA    24.53mA
-500mV    9.988mA    7.902mA    14.72mA
500mV     -8.587mA   -6.601mA   -13.09mA
900mV     -13.93mA   -10.61mA   -21.42mA
1.3V      -17.94mA   -13.54mA   -27.88mA
1.8V      -21.14mA   -15.73mA   -33.39mA
2.4V      -22.68mA   -16.63mA   -36.5mA
6.55V     -26.75mA   -19.54mA   -43.45mA
[GND_clamp]
|Voltage   I(typ)   I(min)   I(max)
-3.3V     -955.3mA   -930.3mA   -978mA
-1.2V     -86.18mA   -82.93mA   -94.91mA
-1.15V    -76.73mA   -73.29mA   -85.74mA
-1.1V     -67.71mA   -63.95mA   -77.28mA
-1V       -51.52mA   -46.57mA   -63.21mA
-900mV    -38.87mA   -31.88mA   -51.26mA
-800mV    -28.25mA   -20.58mA   -37.97mA
-700mV    -18.1mA    -11.63mA   -24.81mA
-600mV    -9.267mA   -5.265mA   -13.06mA
-450mV    -1.181mA   -586.6uA   -1.592mA
-250mV    -3.532uA   -4.055uA   -3.003uA
6.6V      0A         0A         0A
[POWER_clamp]
|Voltage   I(typ)   I(min)   I(max)
-3.25V    121.6mA    123.7mA    123.8mA
-2.55V    103.6mA    109.2mA    99.91mA
-2.05V    84.55mA    92.42mA    76.01mA
-1.85V    74.75mA    84.09mA    62.98mA
-1.65V    63.47mA    74.86mA    47.24mA
-1.35V    44.14mA    59.56mA    21.79mA
-1.25V    37.23mA    54.16mA    15.46mA
-850mV    10.22mA    31.49mA    813uA
-650mV    3.122mA    19.66mA    19.66uA
-350mV    37.56uA    3.815mA    1.535uA
-150mV    934.2nA    336.7uA    1.026uA
6.6V      -57.56nA   -49.34nA   -232.5nA
[Ramp]
| variable   typ   min   max
dV/dt_r  0.7027/0.3013n   0.4966/0.3205n   1.0018/0.2438n
dV/dt_f  0.6827/0.2942n   0.4730/0.3057n   0.9168/0.2859n
R_load = 50.0000
[Rising Waveform]
R_fixture=   50.0000
V_fixture=   3.3000
V_fixture_min=   3.1400
V_fixture_max=   3.4700
|time   V(typ)   V(min)   V(max)
0s        2.162V     2.352V     1.942V
404ps     2.162V     2.352V     1.942V
505.1ps   2.162V     2.352V     2.158V
606.1ps   2.161V     2.352V     2.988V
707.1ps   2.231V     2.352V     3.303V
909.1ps   3.05V      2.351V     3.417V
1.01ns    3.181V     2.35V      3.438V
1.313ns   3.267V     2.954V     3.462V
1.717ns   3.291V     3.109V     3.469V
10ns      3.3V       3.14V      3.47V
[Rising Waveform]
R_fixture=   50.0000
V_fixture=   0.0
V_fixture_min=   0.0
V_fixture_max=   0.0
|time   V(typ)   V(min)   V(max)
0s        1.288uV    1.554uV    1.323uV
505.1ps   26.26uV    1.514uV    -27.26mV
707.1ps   -14.34mV   18.68uV    1.008V
808.1ps   7.053mV    87.81uV    1.296V
1.01ns    669mV      -4.761mV   1.525V
1.212ns   924mV      -7.52mV    1.61V
1.313ns   979.6mV    165.4mV    1.631V
1.616ns   1.061V     651.6mV    1.659V
2.222ns   1.103V     795.2mV    1.668V
10ns      1.111V     827.7mV    1.67V
[Falling Waveform]
R_fixture=   50.0000
V_fixture=   0.0
V_fixture_min=   0.0
V_fixture_max=   0.0
|time   V(typ)   V(min)   V(max)
0s        1.111V     827.7mV    1.67V
505.1ps   1.111V     827.7mV    1.669V
606.1ps   1.111V     827.7mV    781.7mV
707.1ps   1.111V     827.7mV    249.6mV
808.1ps   1.008V     827.7mV    108.5mV
1.01ns    164.9mV    828.2mV    31.11mV
1.212ns   51.1mV     814.5mV    9.451mV
1.515ns   13.32mV    139.2mV    1.692mV
1.818ns   3.881mV    31.12mV    402.4uV
10ns      -16.78uV   26.97uV    -5.658uV
[Falling Waveform]
R_fixture=   50.0000
V_fixture=   3.3000
V_fixture_min=   3.1400
V_fixture_max=   3.4700
|time   V(typ)   V(min)   V(max)
0s        3.3V       3.14V      3.47V
505.1ps   3.3V       3.14V      3.472V
707.1ps   3.298V     3.14V      2.56V
808.1ps   3.311V     3.14V      2.332V
1.01ns    2.606V     3.141V     2.108V
1.313ns   2.296V     3.136V     1.991V
1.414ns   2.258V     2.89V      1.975V
1.717ns   2.199V     2.49V      1.952V
2.323ns   2.168V     2.38V      1.943V
10ns      2.162V     2.352V     1.942V
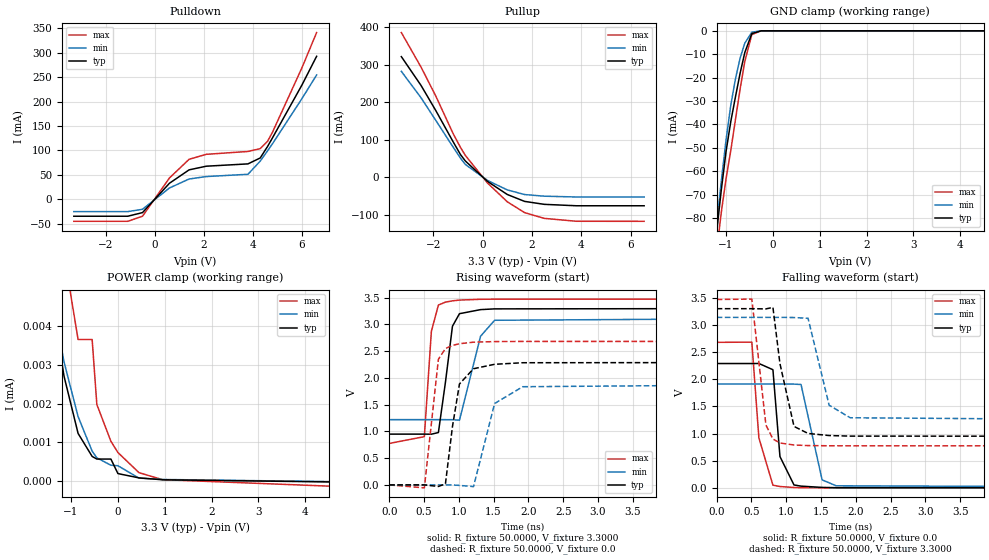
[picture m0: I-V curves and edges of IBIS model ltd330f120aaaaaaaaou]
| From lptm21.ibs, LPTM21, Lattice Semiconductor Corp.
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|   Model ltd330f120aaaaaaaaou
[Model]   ltd330f120aaaaaaaaou
Model_type   Output
Polarity   Non-Inverting
Enable   Active-Low
Vmeas =   1.6500V
Cref =   0.0F
Rref =   1.0000M
Vref =   0.0V
C_comp   4.2000pF   3.8000pF   7.5000pF
[Temperature Range]   25.0000   0.1050k   -40.0000
[Voltage Range]   3.3000V   3.1400V   3.4700V
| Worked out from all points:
|   slope of the pulldown table from 0 to 0.495 V, typ, clamps not added: 17.9 ohm
|   slope of the pullup table from 0 to 0.495 V, typ, clamps not added: 19.6 ohm
|   GND clamp passes 1 mA (typ) near -0.44 V on its own axis
|   rising waveform, R_fixture 50.0000, V_fixture 3.3000: 20-80 % time 142ps typ, 189ps min, 92.9ps max; typ from 0.948 V to 3.3 V
|   rising waveform, R_fixture 50.0000, V_fixture 0.0: 20-80 % time 154ps typ, 219ps min, 135ps max; typ from 0 V to 2.29 V
|   falling waveform, R_fixture 50.0000, V_fixture 0.0: 20-80 % time 106ps typ, 152ps min, 119ps max; typ from 2.29 V to 0 V
|   falling waveform, R_fixture 50.0000, V_fixture 3.3000: 20-80 % time 162ps typ, 221ps min, 138ps max; typ from 3.3 V to 0.948 V
[Pulldown]
|Voltage   I(typ)   I(min)   I(max)
-3.3V     -35.06mA   -25.56mA   -45.46mA
-1.1V     -35.06mA   -25.56mA   -45.46mA
-500mV    -27.6mA    -20.84mA   -35.05mA
600mV     32.61mA    22.93mA    43.45mA
1.4V      60.04mA    41.26mA    81.68mA
2.1V      67.54mA    46.31mA    91.93mA
3.8V      72.28mA    50.96mA    97.72mA
4.3V      84.4mA     77.91mA    103.6mA
4.6V      108mA      99.08mA    118.6mA
4.8V      125.6mA    113.5mA    137.2mA
6V        233.9mA    206mA      269.2mA
6.6V      292.9mA    254.6mA    341.6mA
[Pullup]
|Voltage   I(typ)   I(min)   I(max)
-3.3V     322mA      282.8mA    386.1mA
-2.5V     245.1mA    212.2mA    294mA
-1.9V     178mA      151.9mA    216.6mA
-1.2V     95.13mA    80.94mA    116.9mA
-900mV    60.91mA    51.43mA    79.98mA
-700mV    43.64mA    34.47mA    58.43mA
200mV     -10.87mA   -8.125mA   -15.16mA
1V        -45.47mA   -33.26mA   -64.98mA
1.7V      -63.84mA   -45.59mA   -93.77mA
2.5V      -71.72mA   -49.99mA   -109.1mA
3.8V      -75.49mA   -52.1mA    -116.8mA
6.55V     -75.49mA   -52.1mA    -116.9mA
[GND_clamp]
|Voltage   I(typ)   I(min)   I(max)
-3.3V     -955.3mA   -930.3mA   -978mA
-1.2V     -86.18mA   -82.93mA   -94.91mA
-1.15V    -76.73mA   -73.29mA   -85.74mA
-1.1V     -67.71mA   -63.95mA   -77.28mA
-1V       -51.52mA   -46.57mA   -63.21mA
-900mV    -38.87mA   -31.88mA   -51.26mA
-800mV    -28.25mA   -20.58mA   -37.97mA
-700mV    -18.1mA    -11.63mA   -24.81mA
-600mV    -9.267mA   -5.265mA   -13.06mA
-450mV    -1.181mA   -586.6uA   -1.592mA
-250mV    -3.532uA   -4.055uA   -3.003uA
6.6V      0A         0A         0A
[POWER_clamp]
|Voltage   I(typ)   I(min)   I(max)
-3.25V    664.8uA    749.4uA    597.1uA
-1.55V    5.917uA    5.715uA    11.4uA
-1.45V    4.99uA     4.976uA    9.754uA
-1.15V    2.706uA    3.076uA    5.866uA
-850mV    1.228uA    1.664uA    3.657uA
-550mV    633.7nA    768.9nA    3.657uA
-450mV    565.9nA    597.8nA    1.977uA
-150mV    565.9nA    406.5nA    1.026uA
0V        190.5nA    393.3nA    734.7nA
450mV     79.23nA    72.94nA    213.9nA
950mV     30.32nA    38.42nA    33.55nA
6.6V      -57.56nA   -49.34nA   -232.5nA
[Ramp]
| variable   typ   min   max
dV/dt_r  1.3741/0.1523n   1.1475/0.2167n   1.6081/0.1334n
dV/dt_f  1.4109/0.1604n   1.1528/0.2187n   1.6174/0.1371n
R_load = 50.0000
[Rising Waveform]
R_fixture=   50.0000
V_fixture=   3.3000
V_fixture_min=   3.1400
V_fixture_max=   3.4700
|time   V(typ)   V(min)   V(max)
0s        948.5mV    1.219V     774.4mV
505.1ps   948.6mV    1.219V     901.5mV
606.1ps   947.4mV    1.219V     2.868V
707.1ps   978.4mV    1.219V     3.359V
808.1ps   1.916V     1.219V     3.414V
909.1ps   2.964V     1.218V     3.438V
1.01ns    3.198V     1.209V     3.452V
1.313ns   3.274V     2.777V     3.467V
1.515ns   3.288V     3.075V     3.469V
10ns      3.3V       3.14V      3.47V
[Rising Waveform]
R_fixture=   50.0000
V_fixture=   0.0
V_fixture_min=   0.0
V_fixture_max=   0.0
|time   V(typ)   V(min)   V(max)
0s        612.2nV    810.3nV    586nV
505.1ps   6.89uV     581.8nV    -55.02mV
707.1ps   -28.66mV   21.56uV    2.347V
808.1ps   19.37mV    33.24uV    2.547V
909.1ps   1.09V      -246uV     2.605V
1.01ns    1.886V     -9.334mV   2.637V
1.212ns   2.17V      -31.42mV   2.666V
1.515ns   2.253V     1.521V     2.677V
1.919ns   2.282V     1.834V     2.68V
10ns      2.29V      1.913V     2.68V
[Falling Waveform]
R_fixture=   50.0000
V_fixture=   0.0
V_fixture_min=   0.0
V_fixture_max=   0.0
|time   V(typ)   V(min)   V(max)
0s        2.29V      1.913V     2.68V
505.1ps   2.29V      1.913V     2.684V
606.1ps   2.291V     1.913V     921.4mV
808.1ps   2.176V     1.913V     48.9mV
909.1ps   576.5mV    1.913V     24.86mV
1.111ns   53.25mV    1.911V     6.882mV
1.212ns   31.86mV    1.903V     3.558mV
1.515ns   8.387mV    147.3mV    528.7uV
1.717ns   3.408mV    38.01mV    195.1uV
10ns      -6.496uV   -3.412uV   -8.132uV
[Falling Waveform]
R_fixture=   50.0000
V_fixture=   3.3000
V_fixture_min=   3.1400
V_fixture_max=   3.4700
|time   V(typ)   V(min)   V(max)
0s        3.3V       3.14V      3.47V
505.1ps   3.3V       3.14V      3.476V
707.1ps   3.296V     3.14V      1.158V
808.1ps   3.324V     3.14V      900.6mV
909.1ps   2.287V     3.14V      826.5mV
1.111ns   1.132V     3.137V     789.5mV
1.313ns   1.002V     3.123V     778.8mV
1.616ns   963.4mV    1.522V     775.1mV
1.919ns   953mV      1.291V     774.6mV
10ns      948.5mV    1.219V     774.4mV
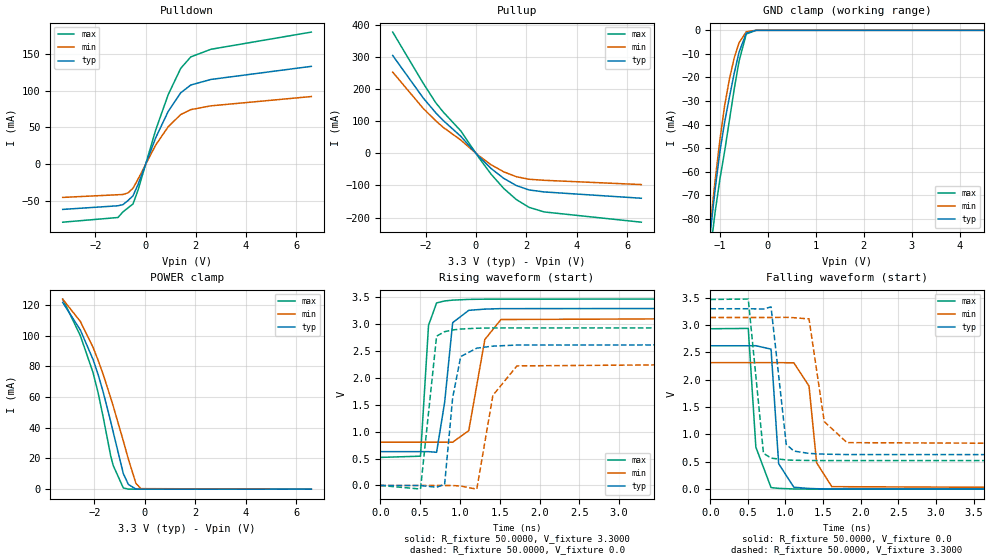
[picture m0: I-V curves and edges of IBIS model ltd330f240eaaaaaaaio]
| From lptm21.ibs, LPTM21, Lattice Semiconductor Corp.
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|   Model ltd330f240eaaaaaaaio
[Model]   ltd330f240eaaaaaaaio
Model_type   I/O
Polarity   Non-Inverting
Enable   Active-Low
Vinl =   0.8000V
Vinh =   2.0000V
Vmeas =   1.6500V
Cref =   0.0F
Rref =   1.0000M
Vref =   0.0V
C_comp   4.2000pF   3.8000pF   7.5000pF
[Temperature Range]   25.0000   0.1050k   -40.0000
[Voltage Range]   3.3000V   3.1400V   3.4700V
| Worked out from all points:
|   slope of the pulldown table from 0 to 0.495 V, typ, clamps not added: 11.5 ohm
|   slope of the pullup table from 0 to 0.495 V, typ, clamps not added: 12.5 ohm
|   GND clamp passes 1 mA (typ) near -0.44 V on its own axis
|   POWER clamp passes 1 mA (typ) near -0.54 V on its own axis
|   rising waveform, R_fixture 50.0000, V_fixture 3.3000: 20-80 % time 125ps typ, 166ps min, 73.3ps max; typ from 0.63 V to 3.3 V
|   rising waveform, R_fixture 50.0000, V_fixture 0.0: 20-80 % time 131ps typ, 168ps min, 125ps max; typ from 0 V to 2.62 V
|   falling waveform, R_fixture 50.0000, V_fixture 0.0: 20-80 % time 75.9ps typ, 104ps min, 99.7ps max; typ from 2.62 V to 0 V
|   falling waveform, R_fixture 50.0000, V_fixture 3.3000: 20-80 % time 129ps typ, 155ps min, 127ps max; typ from 3.3 V to 0.63 V
[Pulldown]
|Voltage   I(typ)   I(min)   I(max)
-3.3V     -62.13mA   -45.75mA   -79.59mA
-1.1V     -57.16mA   -42.08mA   -73.18mA
-900mV    -55.55mA   -41.75mA   -65.47mA
-700mV    -49.99mA   -39.59mA   -60.04mA
-500mV    -43.5mA    -33.15mA   -54.62mA
-300mV    -28.07mA   -20.76mA   -35.77mA
400mV     35.55mA    25.66mA    46.07mA
900mV     71.69mA    50.77mA    94.53mA
1.4V      97.22mA    67.5mA     130.6mA
1.8V      107.8mA    74.21mA    146.2mA
2.6V      115.4mA    79.34mA    156.6mA
6.6V      133.3mA    92.06mA    180.1mA
[Pullup]
|Voltage   I(typ)   I(min)   I(max)
-3.3V     305.6mA    253.6mA    378.6mA
-2.1V     173.9mA    141.2mA    220mA
-1.6V     127.2mA    102.2mA    158.8mA
-1.3V     102.8mA    81.41mA    129.4mA
-600mV    53.25mA    41.48mA    70.05mA
100mV     -8.617mA   -6.568mA   -11.67mA
600mV     -47.18mA   -35.45mA   -64.98mA
1.1V      -77.9mA    -57.55mA   -109.4mA
1.6V      -100.3mA   -72.65mA   -144.1mA
2.1V      -113.9mA   -80.61mA   -168.2mA
2.7V      -120.2mA   -83.87mA   -182.6mA
6.55V     -139.9mA   -97.22mA   -214.6mA
[GND_clamp]
|Voltage   I(typ)   I(min)   I(max)
-3.3V     -955.3mA   -930.3mA   -978mA
-1.2V     -86.18mA   -82.93mA   -94.91mA
-1.15V    -76.73mA   -73.29mA   -85.74mA
-1.1V     -67.71mA   -63.95mA   -77.28mA
-1V       -51.52mA   -46.57mA   -63.21mA
-900mV    -38.87mA   -31.88mA   -51.26mA
-800mV    -28.25mA   -20.58mA   -37.97mA
-700mV    -18.1mA    -11.63mA   -24.81mA
-600mV    -9.267mA   -5.265mA   -13.06mA
-450mV    -1.181mA   -586.6uA   -1.592mA
-250mV    -3.532uA   -4.055uA   -3.003uA
6.6V      0A         0A         0A
[POWER_clamp]
|Voltage   I(typ)   I(min)   I(max)
-3.25V    121.6mA    123.7mA    123.8mA
-2.55V    103.6mA    109.2mA    99.91mA
-2.05V    84.55mA    92.42mA    76.01mA
-1.85V    74.75mA    84.09mA    62.98mA
-1.65V    63.47mA    74.86mA    47.24mA
-1.35V    44.14mA    59.56mA    21.79mA
-1.25V    37.23mA    54.16mA    15.46mA
-850mV    10.22mA    31.49mA    813uA
-650mV    3.122mA    19.66mA    19.66uA
-350mV    37.56uA    3.815mA    1.535uA
-150mV    934.2nA    336.7uA    1.026uA
6.6V      -57.56nA   -49.34nA   -232.5nA
[Ramp]
| variable   typ   min   max
dV/dt_r  1.5736/0.1294n   1.3885/0.1665n   1.7602/0.1234n
dV/dt_f  1.6018/0.1273n   1.4002/0.1530n   1.7684/0.1254n
R_load = 50.0000
[Rising Waveform]
R_fixture=   50.0000
V_fixture=   3.3000
V_fixture_min=   3.1400
V_fixture_max=   3.4700
|time   V(typ)   V(min)   V(max)
0s        630.4mV    806.4mV    522.7mV
505.1ps   630.4mV    806.4mV    545.1mV
606.1ps   629.4mV    806.4mV    2.982V
707.1ps   617.4mV    806.4mV    3.398V
808.1ps   1.546V     806.7mV    3.435V
909.1ps   3.031V     805.7mV    3.45V
1.111ns   3.26V      1.021V     3.464V
1.313ns   3.283V     2.717V     3.468V
1.515ns   3.292V     3.089V     3.469V
10ns      3.3V       3.14V      3.47V
[Rising Waveform]
R_fixture=   50.0000
V_fixture=   0.0
V_fixture_min=   0.0
V_fixture_max=   0.0
|time   V(typ)   V(min)   V(max)
0s        401.5nV    548nV      376.4nV
505.1ps   -3.491uV   225.2nV    -66.27mV
707.1ps   -33.52mV   22.87uV    2.78V
808.1ps   22.39mV    2.363uV    2.863V
909.1ps   1.635V     -332.3uV   2.895V
1.01ns    2.4V       -10.53mV   2.912V
1.212ns   2.556V     -68.72mV   2.927V
1.414ns   2.594V     1.678V     2.932V
1.717ns   2.614V     2.226V     2.933V
10ns      2.623V     2.314V     2.934V
[Falling Waveform]
R_fixture=   50.0000
V_fixture=   0.0
V_fixture_min=   0.0
V_fixture_max=   0.0
|time   V(typ)   V(min)   V(max)
0s        2.623V     2.314V     2.934V
505.1ps   2.623V     2.314V     2.94V
606.1ps   2.624V     2.314V     767.1mV
808.1ps   2.561V     2.314V     29.09mV
909.1ps   465.6mV    2.314V     14.73mV
1.111ns   35.21mV    2.311V     3.87mV
1.313ns   13.04mV    1.886V     989.1uV
1.414ns   8.239mV    482mV      457.3uV
1.616ns   3.311mV    45.79mV    127.1uV
10ns      -17.41uV   5.463uV    -12.38uV
[Falling Waveform]
R_fixture=   50.0000
V_fixture=   3.3000
V_fixture_min=   3.1400
V_fixture_max=   3.4700
|time   V(typ)   V(min)   V(max)
0s        3.3V       3.14V      3.47V
505.1ps   3.3V       3.14V      3.477V
707.1ps   3.295V     3.14V      656.7mV
808.1ps   3.334V     3.14V      568mV
1.01ns    820.7mV    3.142V     534.4mV
1.111ns   697mV      3.136V     528.8mV
1.313ns   653.9mV    3.114V     524.3mV
1.515ns   640.1mV    1.236V     523.2mV
1.818ns   632.9mV    850.9mV    522.8mV
10ns      630.4mV    806.4mV    522.7mV
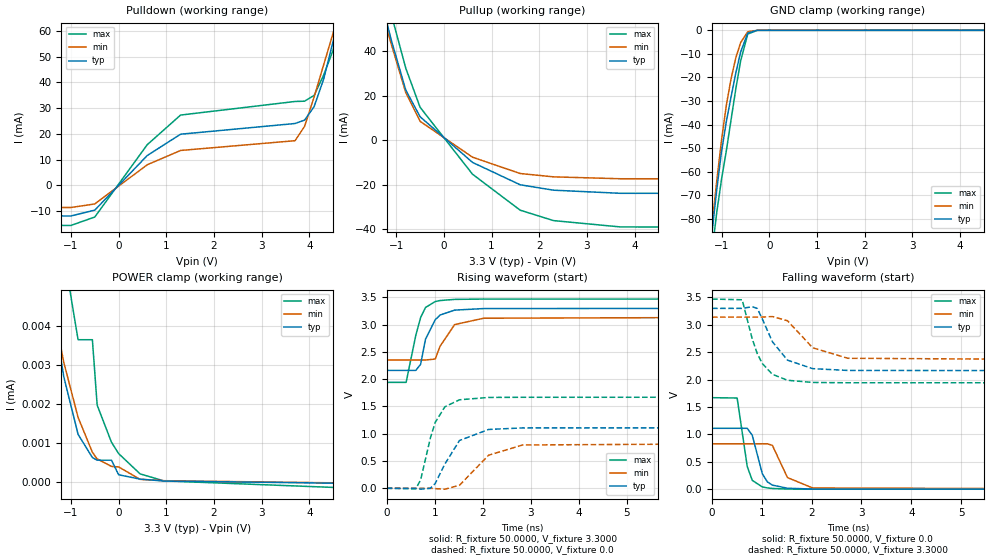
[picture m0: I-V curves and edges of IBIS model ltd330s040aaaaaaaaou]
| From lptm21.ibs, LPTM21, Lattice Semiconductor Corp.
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|   Model ltd330s040aaaaaaaaou
[Model]   ltd330s040aaaaaaaaou
Model_type   Output
Polarity   Non-Inverting
Enable   Active-Low
Vmeas =   1.6500V
Cref =   0.0F
Rref =   1.0000M
Vref =   0.0V
C_comp   4.2000pF   3.8000pF   7.5000pF
[Temperature Range]   25.0000   0.1050k   -40.0000
[Voltage Range]   3.3000V   3.1400V   3.4700V
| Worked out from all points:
|   slope of the pulldown table from 0 to 0.495 V, typ, clamps not added: 50.3 ohm
|   slope of the pullup table from 0 to 0.495 V, typ, clamps not added: 58.2 ohm
|   GND clamp passes 1 mA (typ) near -0.44 V on its own axis
|   rising waveform, R_fixture 50.0000, V_fixture 3.3000: 20-80 % time 264ps typ, 311ps min, 218ps max; typ from 2.16 V to 3.3 V
|   rising waveform, R_fixture 50.0000, V_fixture 0.0: 20-80 % time 438ps typ, 579ps min, 327ps max; typ from 0 V to 1.11 V
|   falling waveform, R_fixture 50.0000, V_fixture 0.0: 20-80 % time 219ps typ, 291ps min, 181ps max; typ from 1.11 V to 0 V
|   falling waveform, R_fixture 50.0000, V_fixture 3.3000: 20-80 % time 443ps typ, 565ps min, 361ps max; typ from 3.3 V to 2.16 V
[Pulldown]
|Voltage   I(typ)   I(min)   I(max)
-3.3V     -11.95mA   -8.665mA   -15.64mA
-1V       -11.95mA   -8.665mA   -15.64mA
-500mV    -9.688mA   -7.272mA   -12.36mA
600mV     11.57mA    7.979mA    15.78mA
1.3V      19.87mA    13.54mA    27.32mA
3.7V      24.03mA    17.34mA    32.61mA
3.9V      25.35mA    22.92mA    32.72mA
4.1V      30.57mA    34.32mA    34.98mA
4.3V      41.28mA    46.83mA    42.85mA
4.5V      56.15mA    59.31mA    52.63mA
4.6V      63.78mA    65.49mA    60.83mA
6.6V      186.7mA    170.5mA    212.2mA
[Pullup]
|Voltage   I(typ)   I(min)   I(max)
-3.3V     181.9mA    129.8mA    219mA
-1.4V     69.7mA     64.85mA    88.33mA
-1.3V     61.4mA     57.55mA    77.61mA
-1.2V     53.01mA    50.21mA    66.78mA
-1.1V     44.61mA    42.84mA    56.18mA
-800mV    22.47mA    21.3mA     32.3mA
-500mV    10.48mA    8.431mA    14.74mA
600mV     -10.05mA   -7.708mA   -15.35mA
1.6V      -20.1mA    -15.04mA   -31.52mA
2.3V      -22.53mA   -16.54mA   -36.2mA
3.7V      -23.93mA   -17.39mA   -39.04mA
6.55V     -23.93mA   -17.39mA   -39.15mA
[GND_clamp]
|Voltage   I(typ)   I(min)   I(max)
-3.3V     -955.3mA   -930.3mA   -978mA
-1.2V     -86.18mA   -82.93mA   -94.91mA
-1.15V    -76.73mA   -73.29mA   -85.74mA
-1.1V     -67.71mA   -63.95mA   -77.28mA
-1V       -51.52mA   -46.57mA   -63.21mA
-900mV    -38.87mA   -31.88mA   -51.26mA
-800mV    -28.25mA   -20.58mA   -37.97mA
-700mV    -18.1mA    -11.63mA   -24.81mA
-600mV    -9.267mA   -5.265mA   -13.06mA
-450mV    -1.181mA   -586.6uA   -1.592mA
-250mV    -3.532uA   -4.055uA   -3.003uA
6.6V      0A         0A         0A
[POWER_clamp]
|Voltage   I(typ)   I(min)   I(max)
-3.25V    664.8uA    749.4uA    597.1uA
-1.55V    5.916uA    5.714uA    11.4uA
-1.45V    4.989uA    4.975uA    9.753uA
-1.15V    2.705uA    3.075uA    5.865uA
-850mV    1.227uA    1.663uA    3.656uA
-550mV    632.7nA    767.9nA    3.656uA
-450mV    564.9nA    596.8nA    1.977uA
-150mV    564.9nA    405.6nA    1.026uA
0V        190.5nA    392.4nA    734.7nA
450mV     79.23nA    72.94nA    213.9nA
950mV     30.32nA    38.42nA    33.55nA
6.6V      -57.56nA   -49.34nA   -232.5nA
[Ramp]
| variable   typ   min   max
dV/dt_r  0.7026/0.4330n   0.4966/0.5731n   1.0018/0.3242n
dV/dt_f  0.6827/0.4387n   0.4730/0.5599n   0.9168/0.3576n
R_load = 50.0000
[Rising Waveform]
R_fixture=   50.0000
V_fixture=   3.3000
V_fixture_min=   3.1400
V_fixture_max=   3.4700
|time   V(typ)   V(min)   V(max)
0s        2.162V     2.352V     1.942V
404ps     2.162V     2.352V     1.942V
606.1ps   2.162V     2.352V     2.806V
707.1ps   2.276V     2.352V     3.134V
808.1ps   2.736V     2.352V     3.316V
1.01ns    3.091V     2.37V      3.424V
1.111ns   3.177V     2.605V     3.443V
1.414ns   3.267V     3.002V     3.464V
2.02ns    3.296V     3.119V     3.47V
10ns      3.3V       3.14V      3.47V
[Rising Waveform]
R_fixture=   50.0000
V_fixture=   0.0
V_fixture_min=   0.0
V_fixture_max=   0.0
|time   V(typ)   V(min)   V(max)
0s        1.288uV    1.554uV    1.323uV
606.1ps   -395.5uV   2.808uV    -9.94mV
707.1ps   -15.72mV   17.67uV    156.1mV
909.1ps   -458.6uV   -207.2uV   922.6mV
1.01ns    88.34mV    -6.184mV   1.209V
1.212ns   447.1mV    -16.04mV   1.495V
1.515ns   876.6mV    55.59mV    1.623V
2.121ns   1.079V     606.6mV    1.666V
2.828ns   1.107V     794.2mV    1.669V
10ns      1.111V     827.7mV    1.67V
[Falling Waveform]
R_fixture=   50.0000
V_fixture=   0.0
V_fixture_min=   0.0
V_fixture_max=   0.0
|time   V(typ)   V(min)   V(max)
0s        1.111V     827.7mV    1.67V
505.1ps   1.111V     827.7mV    1.664V
707.1ps   1.111V     827.7mV    415.7mV
808.1ps   985.1mV    827.7mV    161.2mV
1.01ns    281.4mV    828.2mV    40.87mV
1.111ns   132.9mV    828.5mV    22.94mV
1.212ns   73.68mV    799.7mV    12.45mV
1.515ns   17.1mV     211.6mV    2.151mV
2.02ns    2.152mV    21.8mV     239.2uV
10ns      -1.071uV   8.416uV    -6.671uV
[Falling Waveform]
R_fixture=   50.0000
V_fixture=   3.3000
V_fixture_min=   3.1400
V_fixture_max=   3.4700
|time   V(typ)   V(min)   V(max)
0s        3.3V       3.14V      3.47V
606.1ps   3.3V       3.14V      3.457V
808.1ps   3.33V      3.14V      2.74V
909.1ps   3.299V     3.14V      2.475V
1.01ns    3.108V     3.141V     2.293V
1.212ns   2.692V     3.151V     2.097V
1.515ns   2.355V     3.075V     1.988V
2.02ns    2.2V       2.581V     1.948V
2.727ns   2.167V     2.389V     1.942V
10ns      2.162V     2.352V     1.942V
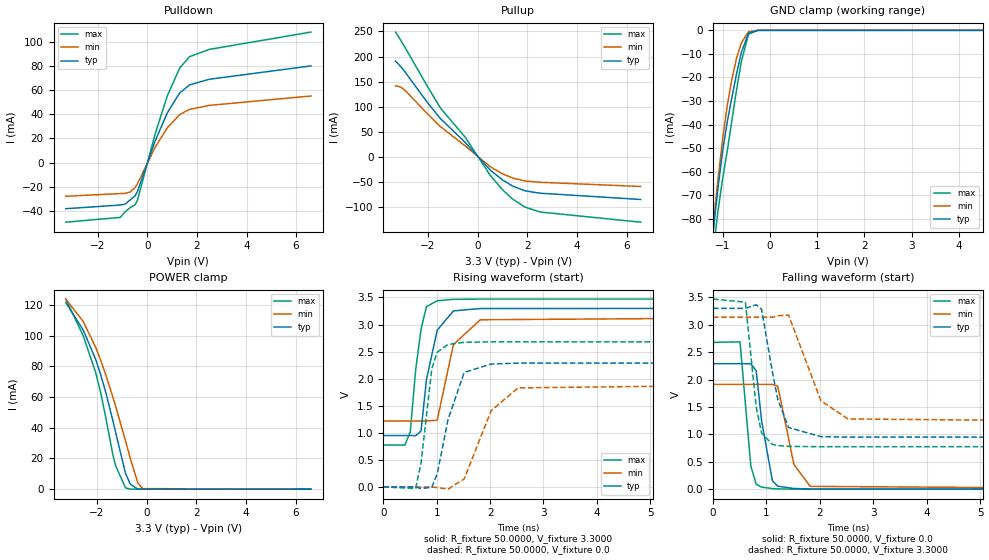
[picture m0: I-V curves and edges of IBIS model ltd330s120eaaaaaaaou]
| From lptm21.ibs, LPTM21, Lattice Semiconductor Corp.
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|   Model ltd330s120eaaaaaaaou
[Model]   ltd330s120eaaaaaaaou
Model_type   Output
Polarity   Non-Inverting
Enable   Active-Low
Vmeas =   1.6500V
Cref =   0.0F
Rref =   1.0000M
Vref =   0.0V
C_comp   4.2000pF   3.8000pF   7.5000pF
[Temperature Range]   25.0000   0.1050k   -40.0000
[Voltage Range]   3.3000V   3.1400V   3.4700V
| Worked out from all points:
|   slope of the pulldown table from 0 to 0.495 V, typ, clamps not added: 17.9 ohm
|   slope of the pullup table from 0 to 0.495 V, typ, clamps not added: 19.6 ohm
|   GND clamp passes 1 mA (typ) near -0.44 V on its own axis
|   POWER clamp passes 1 mA (typ) near -0.54 V on its own axis
|   rising waveform, R_fixture 50.0000, V_fixture 3.3000: 20-80 % time 244ps typ, 294ps min, 180ps max; typ from 0.948 V to 3.3 V
|   rising waveform, R_fixture 50.0000, V_fixture 0.0: 20-80 % time 304ps typ, 473ps min, 186ps max; typ from 0 V to 2.29 V
|   falling waveform, R_fixture 50.0000, V_fixture 0.0: 20-80 % time 168ps typ, 249ps min, 132ps max; typ from 2.29 V to 0 V
|   falling waveform, R_fixture 50.0000, V_fixture 3.3000: 20-80 % time 283ps typ, 451ps min, 193ps max; typ from 3.3 V to 0.948 V
[Pulldown]
|Voltage   I(typ)   I(min)   I(max)
-3.3V     -38.33mA   -27.99mA   -49.53mA
-1.1V     -35.27mA   -25.76mA   -45.55mA
-900mV    -34.49mA   -25.56mA   -40.86mA
-700mV    -31.05mA   -24.42mA   -37.39mA
-500mV    -27.6mA    -20.84mA   -35.05mA
-400mV    -23.76mA   -17.38mA   -30.85mA
300mV     17.51mA    12.42mA    23.12mA
800mV     41.31mA    28.86mA    55.36mA
1.3V      57.8mA     39.8mA     78.5mA
1.7V      64.56mA    44.24mA    87.98mA
2.5V      69.21mA    47.52mA    94.04mA
6.6V      80.3mA     55.3mA     108.4mA
[Pullup]
|Voltage   I(typ)   I(min)   I(max)
-3.3V     191mA      142.1mA    248.7mA
-3.1V     180.6mA    139.6mA    233.1mA
-2.9V     168.2mA    131.9mA    216.5mA
-2V       107.2mA    85.2mA     139.1mA
-1.5V     76.98mA    60.87mA    97.85mA
-500mV    29.12mA    22.27mA    39.58mA
500mV     -25.52mA   -18.93mA   -35.89mA
1V        -45.47mA   -33.26mA   -64.98mA
1.4V      -57.34mA   -41.4mA    -83.18mA
1.9V      -67.01mA   -47.47mA   -99.35mA
2.5V      -71.72mA   -49.99mA   -109.1mA
6.55V     -84.23mA   -58.44mA   -129.4mA
[GND_clamp]
|Voltage   I(typ)   I(min)   I(max)
-3.3V     -955.3mA   -930.3mA   -978mA
-1.2V     -86.18mA   -82.93mA   -94.91mA
-1.15V    -76.73mA   -73.29mA   -85.74mA
-1.1V     -67.71mA   -63.95mA   -77.28mA
-1V       -51.52mA   -46.57mA   -63.21mA
-900mV    -38.87mA   -31.88mA   -51.26mA
-800mV    -28.25mA   -20.58mA   -37.97mA
-700mV    -18.1mA    -11.63mA   -24.81mA
-600mV    -9.267mA   -5.265mA   -13.06mA
-450mV    -1.181mA   -586.6uA   -1.592mA
-250mV    -3.532uA   -4.055uA   -3.003uA
6.6V      0A         0A         0A
[POWER_clamp]
|Voltage   I(typ)   I(min)   I(max)
-3.25V    121.6mA    123.7mA    123.8mA
-2.55V    103.6mA    109.2mA    99.91mA
-2.05V    84.55mA    92.42mA    76.01mA
-1.85V    74.75mA    84.09mA    62.98mA
-1.65V    63.47mA    74.86mA    47.24mA
-1.35V    44.14mA    59.56mA    21.79mA
-1.25V    37.23mA    54.16mA    15.46mA
-850mV    10.22mA    31.49mA    813uA
-650mV    3.122mA    19.66mA    19.66uA
-350mV    37.56uA    3.815mA    1.535uA
-150mV    934.2nA    336.7uA    1.026uA
6.6V      -57.56nA   -49.34nA   -232.5nA
[Ramp]
| variable   typ   min   max
dV/dt_r  1.3741/0.3012n   1.1475/0.4684n   1.6081/0.1845n
dV/dt_f  1.4109/0.2806n   1.1527/0.4461n   1.6174/0.1908n
R_load = 50.0000
[Rising Waveform]
R_fixture=   50.0000
V_fixture=   3.3000
V_fixture_min=   3.1400
V_fixture_max=   3.4700
|time   V(typ)   V(min)   V(max)
0s        948.5mV    1.219V     774.4mV
404ps     948.5mV    1.219V     773.7mV
505.1ps   948.6mV    1.219V     1.014V
606.1ps   947.4mV    1.219V     2.161V
707.1ps   1.032V     1.219V     2.914V
808.1ps   1.981V     1.219V     3.33V
1.01ns    2.895V     1.232V     3.439V
1.313ns   3.251V     2.63V      3.465V
1.818ns   3.295V     3.088V     3.47V
10ns      3.3V       3.14V      3.47V
[Rising Waveform]
R_fixture=   50.0000
V_fixture=   0.0
V_fixture_min=   0.0
V_fixture_max=   0.0
|time   V(typ)   V(min)   V(max)
0s        612.2nV    810.3nV    586nV
606.1ps   -814.1uV   2.155uV    -28.5mV
707.1ps   -31.91mV   19.12uV    442.4mV
909.1ps   -3.978mV   -498.9uV   2.189V
1.01ns    240.4mV    -12.47mV   2.489V
1.212ns   1.244V     -41.1mV    2.631V
1.515ns   2.115V     148mV      2.671V
2.02ns    2.27V      1.408V     2.68V
2.525ns   2.287V     1.83V      2.68V
10ns      2.29V      1.913V     2.68V
[Falling Waveform]
R_fixture=   50.0000
V_fixture=   0.0
V_fixture_min=   0.0
V_fixture_max=   0.0
|time   V(typ)   V(min)   V(max)
0s        2.29V      1.913V     2.68V
505.1ps   2.29V      1.913V     2.689V
707.1ps   2.288V     1.913V     423.2mV
808.1ps   2.161V     1.913V     89.39mV
909.1ps   1.25V      1.913V     38.11mV
1.111ns   154.6mV    1.911V     10.1mV
1.212ns   54.48mV    1.881V     5.298mV
1.515ns   12.41mV    450.5mV    742.1uV
1.818ns   3.109mV    50.96mV    174.6uV
10ns      3.259uV    2.082uV    -608.2nV
[Falling Waveform]
R_fixture=   50.0000
V_fixture=   3.3000
V_fixture_min=   3.1400
V_fixture_max=   3.4700
|time   V(typ)   V(min)   V(max)
0s        3.3V       3.14V      3.47V
606.1ps   3.301V     3.14V      3.413V
808.1ps   3.366V     3.14V      1.496V
909.1ps   3.282V     3.14V      1.025V
1.111ns   2.142V     3.137V     816.9mV
1.212ns   1.64V      3.165V     797mV
1.414ns   1.125V     3.177V     781mV
2.02ns    958.8mV    1.614V     774.6mV
2.525ns   949.9mV    1.282V     774.5mV
10ns      948.5mV    1.219V     774.4mV
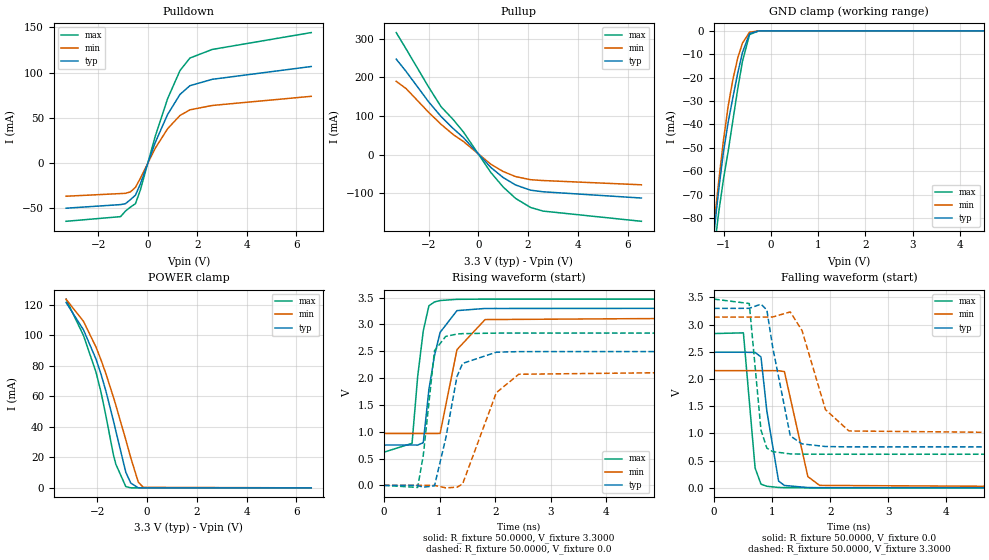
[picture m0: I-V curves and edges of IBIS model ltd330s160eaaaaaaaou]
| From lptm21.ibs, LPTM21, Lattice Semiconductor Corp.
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|   Model ltd330s160eaaaaaaaou
[Model]   ltd330s160eaaaaaaaou
Model_type   Output
Polarity   Non-Inverting
Enable   Active-Low
Vmeas =   1.6500V
Cref =   0.0F
Rref =   1.0000M
Vref =   0.0V
C_comp   4.2000pF   3.8000pF   7.5000pF
[Temperature Range]   25.0000   0.1050k   -40.0000
[Voltage Range]   3.3000V   3.1400V   3.4700V
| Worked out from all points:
|   slope of the pulldown table from 0 to 0.495 V, typ, clamps not added: 13.9 ohm
|   slope of the pullup table from 0 to 0.495 V, typ, clamps not added: 15.1 ohm
|   GND clamp passes 1 mA (typ) near -0.44 V on its own axis
|   POWER clamp passes 1 mA (typ) near -0.54 V on its own axis
|   rising waveform, R_fixture 50.0000, V_fixture 3.3000: 20-80 % time 241ps typ, 285ps min, 173ps max; typ from 0.752 V to 3.3 V
|   rising waveform, R_fixture 50.0000, V_fixture 0.0: 20-80 % time 262ps typ, 413ps min, 170ps max; typ from 0 V to 2.49 V
|   falling waveform, R_fixture 50.0000, V_fixture 0.0: 20-80 % time 158ps typ, 236ps min, 124ps max; typ from 2.49 V to 0 V
|   falling waveform, R_fixture 50.0000, V_fixture 3.3000: 20-80 % time 230ps typ, 378ps min, 152ps max; typ from 3.3 V to 0.752 V
[Pulldown]
|Voltage   I(typ)   I(min)   I(max)
-3.3V     -50.23mA   -36.96mA   -64.72mA
-1.1V     -46.23mA   -34.01mA   -59.55mA
-900mV    -45.2mA    -33.74mA   -53.38mA
-700mV    -40.7mA    -32.12mA   -48.95mA
-500mV    -35.8mA    -27.15mA   -45.23mA
-300mV    -23.31mA   -17.07mA   -30.01mA
300mV     22.52mA    16.15mA    29.41mA
800mV     53.61mA    37.79mA    71.12mA
1.3V      75.8mA     52.5mA     102.2mA
1.7V      85.44mA    58.7mA     116.1mA
2.6V      92.52mA    63.57mA    125.6mA
6.6V      106.7mA    73.69mA    144.3mA
[Pullup]
|Voltage   I(typ)   I(min)   I(max)
-3.3V     246.9mA    189.6mA    315.5mA
-2.9V     214.8mA    170.6mA    272.9mA
-2V       136.7mA    109.6mA    175mA
-1.5V     98.69mA    78.52mA    124.1mA
-1V       66.86mA    51.35mA    89.96mA
-600mV    44.14mA    34.11mA    58.68mA
500mV     -33.02mA   -24.69mA   -45.86mA
1V        -59.26mA   -43.64mA   -83.75mA
1.5V      -78.43mA   -56.74mA   -113.2mA
2.1V      -91.79mA   -64.71mA   -136.5mA
2.6V      -95.92mA   -66.88mA   -145.8mA
6.55V     -112.1mA   -77.85mA   -172.2mA
[GND_clamp]
|Voltage   I(typ)   I(min)   I(max)
-3.3V     -955.3mA   -930.3mA   -978mA
-1.2V     -86.18mA   -82.93mA   -94.91mA
-1.15V    -76.73mA   -73.29mA   -85.74mA
-1.1V     -67.71mA   -63.95mA   -77.28mA
-1V       -51.52mA   -46.57mA   -63.21mA
-900mV    -38.87mA   -31.88mA   -51.26mA
-800mV    -28.25mA   -20.58mA   -37.97mA
-700mV    -18.1mA    -11.63mA   -24.81mA
-600mV    -9.267mA   -5.265mA   -13.06mA
-450mV    -1.181mA   -586.6uA   -1.592mA
-250mV    -3.532uA   -4.055uA   -3.003uA
6.6V      0A         0A         0A
[POWER_clamp]
|Voltage   I(typ)   I(min)   I(max)
-3.25V    121.6mA    123.7mA    123.8mA
-2.55V    103.6mA    109.2mA    99.91mA
-2.05V    84.55mA    92.42mA    76.01mA
-1.85V    74.75mA    84.09mA    62.98mA
-1.65V    63.47mA    74.86mA    47.24mA
-1.35V    44.14mA    59.56mA    21.79mA
-1.25V    37.23mA    54.16mA    15.46mA
-850mV    10.22mA    31.49mA    813uA
-650mV    3.122mA    19.66mA    19.66uA
-350mV    37.56uA    3.815mA    1.535uA
-150mV    934.2nA    336.7uA    1.026uA
6.6V      -57.56nA   -49.34nA   -232.5nA
[Ramp]
| variable   typ   min   max
dV/dt_r  1.4966/0.2592n   1.2936/0.4087n   1.7021/0.1678n
dV/dt_f  1.5290/0.2281n   1.3043/0.3741n   1.7112/0.1501n
R_load = 50.0000
[Rising Waveform]
R_fixture=   50.0000
V_fixture=   3.3000
V_fixture_min=   3.1400
V_fixture_max=   3.4700
|time   V(typ)   V(min)   V(max)
0s        751.6mV    966.1mV    618mV
505.1ps   751.7mV    966.1mV    782.9mV
606.1ps   750.5mV    966.1mV    2.026V
707.1ps   795mV      966.1mV    2.88V
808.1ps   1.786V     966.4mV    3.346V
909.1ps   2.419V     965.5mV    3.418V
1.01ns    2.851V     968.1mV    3.444V
1.313ns   3.256V     2.529V     3.466V
1.818ns   3.296V     3.089V     3.47V
10ns      3.3V       3.14V      3.47V
[Rising Waveform]
R_fixture=   50.0000
V_fixture=   0.0
V_fixture_min=   0.0
V_fixture_max=   0.0
|time   V(typ)   V(min)   V(max)
0s        484.9nV    653.8nV    458.4nV
606.1ps   -928.3uV   2.015uV    -38.81mV
707.1ps   -36.03mV   19.4uV     559mV
909.1ps   -7.501mV   -591.8uV   2.51V
1.111ns   876.5mV    -46.71mV   2.776V
1.313ns   2.029V     -34.83mV   2.819V
1.414ns   2.272V     25.73mV    2.827V
2.02ns    2.481V     1.727V     2.837V
2.424ns   2.492V     2.07V      2.837V
10ns      2.494V     2.156V     2.837V
[Falling Waveform]
R_fixture=   50.0000
V_fixture=   0.0
V_fixture_min=   0.0
V_fixture_max=   0.0
|time   V(typ)   V(min)   V(max)
0s        2.494V     2.156V     2.837V
505.1ps   2.494V     2.156V     2.85V
707.1ps   2.49V      2.156V     363.7mV
808.1ps   2.407V     2.156V     67.81mV
909.1ps   1.413V     2.156V     29.42mV
1.111ns   126.2mV    2.154V     7.547mV
1.212ns   43.67mV    2.138V     3.842mV
1.616ns   6.181mV    206.6mV    298.8uV
1.818ns   2.479mV    45.08mV    130.9uV
10ns      9.129uV    5.31uV     7.474uV
[Falling Waveform]
R_fixture=   50.0000
V_fixture=   3.3000
V_fixture_min=   3.1400
V_fixture_max=   3.4700
|time   V(typ)   V(min)   V(max)
0s        3.3V       3.14V      3.47V
606.1ps   3.301V     3.14V      3.389V
808.1ps   3.378V     3.14V      1.064V
909.1ps   3.27V      3.14V      731.6mV
1.01ns    2.584V     3.142V     666.6mV
1.313ns   955.6mV    3.235V     624.4mV
1.515ns   808.3mV    2.893V     619.6mV
1.919ns   760.1mV    1.439V     618.1mV
2.323ns   753.1mV    1.046V     618mV
10ns      751.7mV    966.1mV    618mV
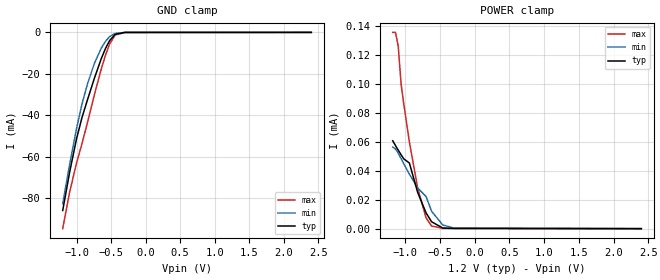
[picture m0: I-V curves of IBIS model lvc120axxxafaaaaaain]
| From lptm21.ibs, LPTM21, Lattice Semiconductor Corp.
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|   Model lvc120axxxafaaaaaain
[Model]   lvc120axxxafaaaaaain
Model_type   Input
Polarity   Non-Inverting
Enable   Active-Low
Vinl =   0.4200V
Vinh =   0.7800V
C_comp   4.2000pF   3.8000pF   7.5000pF
[Temperature Range]   25.0000   0.1050k   -40.0000
[Voltage Range]   1.2000V   1.1400V   1.2600V
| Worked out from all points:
|   GND clamp passes 1 mA (typ) near -0.44 V on its own axis
[GND_clamp]
|Voltage   I(typ)   I(min)   I(max)
-1.2V     -86.07mA   -82.81mA   -94.84mA
-1.1V     -67.62mA   -63.85mA   -77.22mA
-1V       -51.44mA   -46.49mA   -63.16mA
-920mV    -41.05mA   -34.47mA   -53.69mA
-840mV    -32.43mA   -24.76mA   -43.33mA
-740mV    -22.02mA   -14.88mA   -29.93mA
-640mV    -12.55mA   -7.499mA   -17.49mA
-580mV    -7.732mA   -4.278mA   -10.96mA
-520mV    -3.911mA   -2mA       -5.586mA
-440mV    -943.9uA   -474.2uA   -1.243mA
-300mV    -18.55uA   -15.85uA   -16.32uA
2.4V      0A         0A         0A
[POWER_clamp]
|Voltage   I(typ)   I(min)   I(max)
-1.18V    60.64uA    56.26uA    135.4uA
-1.14V    57.31uA    54.99uA    135.4uA
-1.1V     54.11uA    52uA       125.7uA
-1.06V    51.03uA    48.39uA    100.1uA
-1.02V    48.09uA    44.69uA    85.81uA
-940mV    45.28uA    37.56uA    59.84uA
-820mV    24.89uA    28uA       27.91uA
-700mV    10.88uA    22.15uA    7.487uA
-620mV    4.733uA    12.01uA    1.786uA
-460mV    415.9nA    2.532uA    159.1nA
-300mV    127.7nA    366.9nA    159.1nA
2.4V      -20.81nA   -18.5nA    -25.04nA
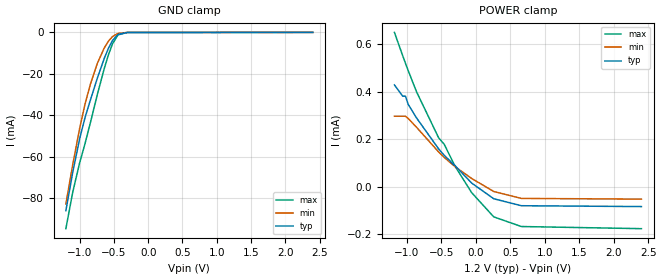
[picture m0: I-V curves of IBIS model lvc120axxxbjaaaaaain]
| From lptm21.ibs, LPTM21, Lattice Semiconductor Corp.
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|   Model lvc120axxxbjaaaaaain
[Model]   lvc120axxxbjaaaaaain
Model_type   Input
Polarity   Non-Inverting
Enable   Active-Low
Vinl =   0.4200V
Vinh =   0.7800V
C_comp   4.2000pF   3.8000pF   7.5000pF
[Temperature Range]   25.0000   0.1050k   -40.0000
[Voltage Range]   1.2000V   1.1400V   1.2600V
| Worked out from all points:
|   GND clamp passes 1 mA (typ) near -0.44 V on its own axis
[GND_clamp]
|Voltage   I(typ)   I(min)   I(max)
-1.2V     -86.02mA   -82.79mA   -94.71mA
-1.1V     -67.56mA   -63.82mA   -77.09mA
-1V       -51.39mA   -46.46mA   -63.03mA
-920mV    -41mA      -34.44mA   -53.57mA
-840mV    -32.38mA   -24.74mA   -43.21mA
-740mV    -21.97mA   -14.85mA   -29.81mA
-640mV    -12.51mA   -7.478mA   -17.38mA
-580mV    -7.694mA   -4.26mA    -10.86mA
-520mV    -3.881mA   -1.989mA   -5.509mA
-440mV    -930.4uA   -470.4uA   -1.205mA
-300mV    -18.88uA   -16.34uA   -15.3uA
2.4V      0A         0A         0A
[POWER_clamp]
|Voltage   I(typ)   I(min)   I(max)
-1.18V    428.9uA    296.9uA    650.2uA
-1.06V    381.4uA    296.9uA    551.8uA
-1.02V    381.4uA    296.9uA    520uA
-980mV    346.6uA    287.3uA    488.9uA
-860mV    289.9uA    250.4uA    400uA
-540mV    159.6uA    146.6uA    206.4uA
-460mV    132.4uA    123.9uA    179.3uA
-300mV    88.01uA    83.86uA    85.61uA
-60mV     15.09uA    34.5uA     -25.38uA
260mV     -50.94uA   -20.29uA   -127.3uA
660mV     -80.25uA   -49.46uA   -167.9uA
2.4V      -83.82uA   -52.45uA   -176.9uA
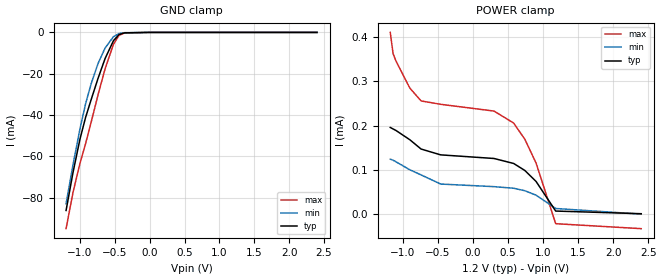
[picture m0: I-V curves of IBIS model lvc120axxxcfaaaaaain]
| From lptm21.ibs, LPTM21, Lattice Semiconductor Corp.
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|   Model lvc120axxxcfaaaaaain
[Model]   lvc120axxxcfaaaaaain
Model_type   Input
Polarity   Non-Inverting
Enable   Active-Low
Vinl =   0.4200V
Vinh =   0.7800V
C_comp   4.2000pF   3.8000pF   7.5000pF
[Temperature Range]   25.0000   0.1050k   -40.0000
[Voltage Range]   1.2000V   1.1400V   1.2600V
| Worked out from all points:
|   GND clamp passes 1 mA (typ) near -0.44 V on its own axis
[GND_clamp]
|Voltage   I(typ)   I(min)   I(max)
-1.2V     -86.12mA   -82.85mA   -94.91mA
-1.1V     -67.67mA   -63.89mA   -77.29mA
-1V       -51.5mA    -46.53mA   -63.23mA
-920mV    -41.11mA   -34.51mA   -53.77mA
-840mV    -32.49mA   -24.81mA   -43.41mA
-740mV    -22.08mA   -14.92mA   -30.01mA
-640mV    -12.62mA   -7.552mA   -17.58mA
-520mV    -4.002mA   -2.066mA   -5.717mA
-440mV    -1.052mA   -544.2uA   -1.412mA
-360mV    -224.4uA   -137uA     -297.4uA
0V        0A         0A         0A
2.4V      0A         0A         0A
[POWER_clamp]
|Voltage   I(typ)   I(min)   I(max)
-1.18V    195.7uA    123.7uA    411.4uA
-1.14V    192.3uA    121.4uA    363.5uA
-1.1V     189uA      117.9uA    346.9uA
-900mV    167.7uA    99.59uA    284.8uA
-740mV    146.7uA    87.99uA    255.9uA
-460mV    133.5uA    67.27uA    248.2uA
300mV     125.3uA    61.39uA    232.9uA
580mV     114uA      57.74uA    205.7uA
740mV     98.07uA    52.14uA    168.9uA
900mV     73.23uA    42.07uA    115uA
1.18V     6.005uA    11.83uA    -22.68uA
2.4V      -20.2nA    -1.007uA   -33.94uA
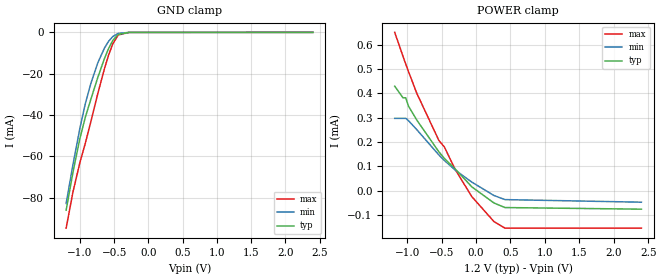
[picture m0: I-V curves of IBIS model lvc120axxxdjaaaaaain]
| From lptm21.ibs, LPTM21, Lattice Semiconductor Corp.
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|   Model lvc120axxxdjaaaaaain
[Model]   lvc120axxxdjaaaaaain
Model_type   Input
Polarity   Non-Inverting
Enable   Active-Low
Vinl =   0.4200V
Vinh =   0.7800V
C_comp   4.2000pF   3.8000pF   7.5000pF
[Temperature Range]   25.0000   0.1050k   -40.0000
[Voltage Range]   1.2000V   1.1400V   1.2600V
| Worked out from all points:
|   GND clamp passes 1 mA (typ) near -0.44 V on its own axis
[GND_clamp]
|Voltage   I(typ)   I(min)   I(max)
-1.2V     -86.05mA   -82.8mA    -94.75mA
-1.1V     -67.59mA   -63.84mA   -77.13mA
-1V       -51.42mA   -46.49mA   -63.08mA
-920mV    -41.03mA   -34.46mA   -53.61mA
-840mV    -32.42mA   -24.76mA   -43.26mA
-740mV    -22.01mA   -14.88mA   -29.85mA
-640mV    -12.55mA   -7.505mA   -17.43mA
-580mV    -7.735mA   -4.289mA   -10.91mA
-520mV    -3.926mA   -2.018mA   -5.563mA
-440mV    -975.9uA   -496.4uA   -1.258mA
-280mV    -21.15uA   -10.37uA   -5.4uA
2.4V      0A         0A         0A
[POWER_clamp]
|Voltage   I(typ)   I(min)   I(max)
-1.18V    428.9uA    296.9uA    650.2uA
-1.06V    381.4uA    296.9uA    551.8uA
-1.02V    381.4uA    296.9uA    520uA
-980mV    346.6uA    287.3uA    488.9uA
-860mV    289.9uA    250.4uA    400uA
-540mV    159.6uA    146.6uA    206.4uA
-460mV    132.4uA    123.9uA    179.3uA
-300mV    88.01uA    83.86uA    85.61uA
-60mV     15.09uA    34.5uA     -25.38uA
260mV     -50.94uA   -20.29uA   -127.3uA
420mV     -69.79uA   -37.12uA   -154.4uA
2.4V      -76.46uA   -47.78uA   -154.4uA
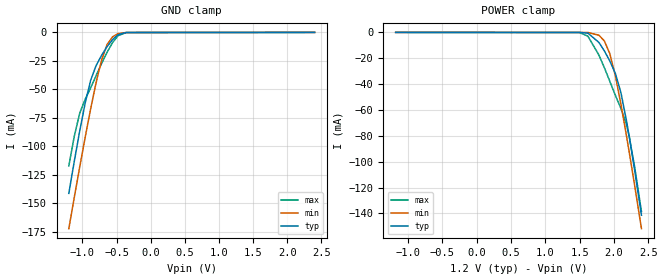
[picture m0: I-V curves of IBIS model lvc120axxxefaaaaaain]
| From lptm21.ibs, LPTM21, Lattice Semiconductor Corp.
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|   Model lvc120axxxefaaaaaain
[Model]   lvc120axxxefaaaaaain
Model_type   Input
Polarity   Non-Inverting
Enable   Active-Low
Vinl =   0.4200V
Vinh =   0.7800V
C_comp   4.2000pF   3.8000pF   7.5000pF
[Temperature Range]   25.0000   0.1050k   -40.0000
[Voltage Range]   1.2000V   1.1400V   1.2600V
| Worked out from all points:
|   GND clamp passes 1 mA (typ) near -0.44 V on its own axis
[GND_clamp]
|Voltage   I(typ)   I(min)   I(max)
-1.2V     -141.4mA   -172.4mA   -117.3mA
-1.12V    -113.3mA   -145mA     -91.23mA
-1.04V    -86.46mA   -118.1mA   -70.9mA
-960mV    -61.91mA   -92.06mA   -58.68mA
-880mV    -42.05mA   -67.11mA   -48.69mA
-800mV    -29.11mA   -44.02mA   -37.96mA
-720mV    -20.14mA   -24.33mA   -27.35mA
-640mV    -12.58mA   -10.7mA    -17.51mA
-560mV    -6.344mA   -3.935mA   -9.033mA
-480mV    -2.108mA   -1.103mA   -2.957mA
-360mV    -118.7uA   -77.16uA   -122.3uA
2.4V      271.4nA    296nA      292.1nA
[POWER_clamp]
|Voltage   I(typ)   I(min)   I(max)
-1.18V    263.8nA    310.3nA    245.7nA
1.5V      -19.41uA   -3.716uA   -122.3uA
1.62V     -595.5uA   -77.16uA   -2.957mA
1.78V     -7.749mA   -2.189mA   -17.51mA
1.86V     -14.36mA   -6.624mA   -27.35mA
1.94V     -22.22mA   -16.59mA   -37.96mA
2.02V     -31.79mA   -33.61mA   -48.69mA
2.1V      -46.39mA   -55.26mA   -58.68mA
2.18V     -67.73mA   -79.41mA   -70.9mA
2.22V     -80.04mA   -92.06mA   -80.05mA
2.3V      -106.4mA   -118.1mA   -103.8mA
2.4V      -141.4mA   -151.8mA   -138.6mA
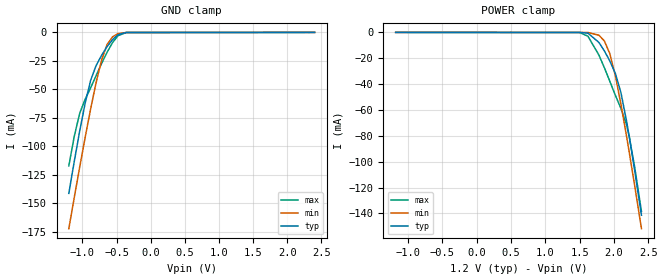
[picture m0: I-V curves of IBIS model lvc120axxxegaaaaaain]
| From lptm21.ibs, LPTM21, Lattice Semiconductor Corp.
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|   Model lvc120axxxegaaaaaain
[Model]   lvc120axxxegaaaaaain
Model_type   Input
Polarity   Non-Inverting
Enable   Active-Low
Vinl =   0.4200V
Vinh =   0.7800V
C_comp   4.2000pF   3.8000pF   7.5000pF
[Temperature Range]   25.0000   0.1050k   -40.0000
[Voltage Range]   1.2000V   1.1400V   1.2600V
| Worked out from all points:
|   GND clamp passes 1 mA (typ) near -0.44 V on its own axis
[GND_clamp]
|Voltage   I(typ)   I(min)   I(max)
-1.2V     -141.4mA   -172.4mA   -117.3mA
-1.12V    -113.3mA   -145mA     -91.22mA
-1.04V    -86.45mA   -118.1mA   -70.88mA
-960mV    -61.9mA    -92.06mA   -58.66mA
-880mV    -42.04mA   -67.11mA   -48.67mA
-800mV    -29.1mA    -44.02mA   -37.94mA
-720mV    -20.13mA   -24.33mA   -27.34mA
-640mV    -12.57mA   -10.7mA    -17.5mA
-560mV    -6.337mA   -3.932mA   -9.021mA
-480mV    -2.103mA   -1.101mA   -2.949mA
-360mV    -117.9uA   -76.82uA   -121.1uA
2.4V      409.8nA    468.7nA    437.2nA
[POWER_clamp]
|Voltage   I(typ)   I(min)   I(max)
-1.18V    402.1nA    556.8nA    390.7nA
1.5V      -19.17uA   -3.577uA   -121.1uA
1.62V     -593.2uA   -76.82uA   -2.949mA
1.78V     -7.741mA   -2.186mA   -17.5mA
1.86V     -14.35mA   -6.62mA    -27.34mA
1.94V     -22.2mA    -16.59mA   -37.94mA
2.02V     -31.78mA   -33.6mA    -48.67mA
2.1V      -46.38mA   -55.26mA   -58.66mA
2.18V     -67.72mA   -79.4mA    -70.88mA
2.22V     -80.03mA   -92.06mA   -80.03mA
2.3V      -106.4mA   -118.1mA   -103.8mA
2.4V      -141.4mA   -151.8mA   -138.5mA
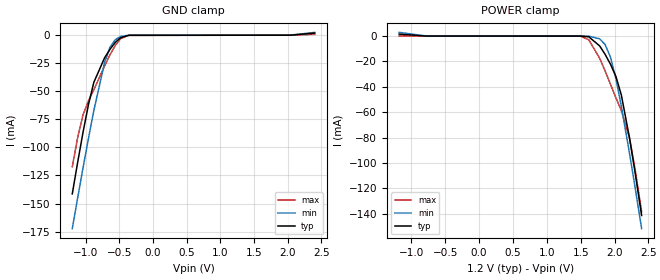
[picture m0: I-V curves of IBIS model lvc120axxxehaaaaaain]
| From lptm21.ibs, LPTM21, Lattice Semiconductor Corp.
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|   Model lvc120axxxehaaaaaain
[Model]   lvc120axxxehaaaaaain
Model_type   Input
Polarity   Non-Inverting
Enable   Active-Low
Vinl =   0.4200V
Vinh =   0.7800V
C_comp   4.2000pF   3.8000pF   7.5000pF
[Temperature Range]   25.0000   0.1050k   -40.0000
[Voltage Range]   1.2000V   1.1400V   1.2600V
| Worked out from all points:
|   GND clamp passes 1 mA (typ) near -0.44 V on its own axis
|   POWER clamp passes 1 mA (typ) near -1.15 V on its own axis
[GND_clamp]
|Voltage   I(typ)   I(min)   I(max)
-1.2V     -141.4mA   -172.4mA   -117.3mA
-1.12V    -113.3mA   -145mA     -91.21mA
-1.04V    -86.44mA   -118.1mA   -70.88mA
-960mV    -61.9mA    -92.05mA   -58.65mA
-880mV    -42.03mA   -67.1mA    -48.67mA
-720mV    -20.13mA   -24.33mA   -27.33mA
-640mV    -12.57mA   -10.7mA    -17.49mA
-560mV    -6.333mA   -3.93mA    -9.017mA
-480mV    -2.101mA   -1.1mA     -2.946mA
-360mV    -117.5uA   -76.58uA   -120.4uA
2.04V     3.654uA    34.92uA    621.6nA
2.4V      1.893mA    2.49mA     777.4uA
[POWER_clamp]
|Voltage   I(typ)   I(min)   I(max)
-1.18V    1.532mA    2.889mA    151.8uA
-780mV    1.282uA    34.92uA    351.1nA
1.5V      -19uA      -3.455uA   -120.4uA
1.62V     -592.1uA   -76.58uA   -2.946mA
1.78V     -7.737mA   -2.185mA   -17.49mA
1.86V     -14.35mA   -6.618mA   -27.33mA
1.94V     -22.2mA    -16.59mA   -37.94mA
2.02V     -31.77mA   -33.6mA    -48.67mA
2.1V      -46.37mA   -55.26mA   -58.65mA
2.22V     -80.03mA   -92.05mA   -80.02mA
2.3V      -106.4mA   -118.1mA   -103.8mA
2.4V      -141.4mA   -151.8mA   -138.5mA
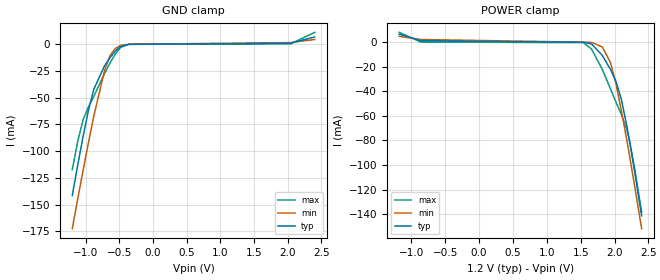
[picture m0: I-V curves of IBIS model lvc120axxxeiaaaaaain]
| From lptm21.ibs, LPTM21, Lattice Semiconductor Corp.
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|   Model lvc120axxxeiaaaaaain
[Model]   lvc120axxxeiaaaaaain
Model_type   Input
Polarity   Non-Inverting
Enable   Active-Low
Vinl =   0.4200V
Vinh =   0.7800V
C_comp   4.2000pF   3.8000pF   7.5000pF
[Temperature Range]   25.0000   0.1050k   -40.0000
[Voltage Range]   1.2000V   1.1400V   1.2600V
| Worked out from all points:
|   GND clamp passes 1 mA (typ) near -0.44 V on its own axis
|   POWER clamp passes 1 mA (typ) near -0.85 V on its own axis
[GND_clamp]
|Voltage   I(typ)   I(min)   I(max)
-1.2V     -141.4mA   -172.4mA   -117.3mA
-1.12V    -113.3mA   -145mA     -91.21mA
-1.04V    -86.44mA   -118.1mA   -70.88mA
-960mV    -61.9mA    -92.05mA   -58.65mA
-880mV    -42.03mA   -67.1mA    -48.66mA
-720mV    -20.13mA   -24.33mA   -27.33mA
-640mV    -12.57mA   -10.7mA    -17.49mA
-560mV    -6.332mA   -3.929mA   -9.015mA
-480mV    -2.1mA     -1.1mA     -2.945mA
-360mV    -117.3uA   -76.48uA   -120.2uA
2.04V     908.1uA    1.518mA    282.2uA
2.4V      6.725mA    4.384mA    11.02mA
[POWER_clamp]
|Voltage   I(typ)   I(min)   I(max)
-1.18V    6.432mA    4.704mA    7.939mA
-860mV    1.183mA    2.143mA    119.1uA
1.54V     -65.08uA   -9.731uA   -417.6uA
1.66V     -1.442mA   -201.1uA   -5.588mA
1.82V     -10.86mA   -3.929mA   -22.28mA
1.94V     -22.2mA    -16.59mA   -37.93mA
2.02V     -31.77mA   -33.6mA    -48.66mA
2.1V      -46.37mA   -55.26mA   -58.65mA
2.18V     -67.72mA   -79.4mA    -70.88mA
2.22V     -80.03mA   -92.05mA   -80.02mA
2.3V      -106.4mA   -118.1mA   -103.8mA
2.4V      -141.4mA   -151.8mA   -138.5mA
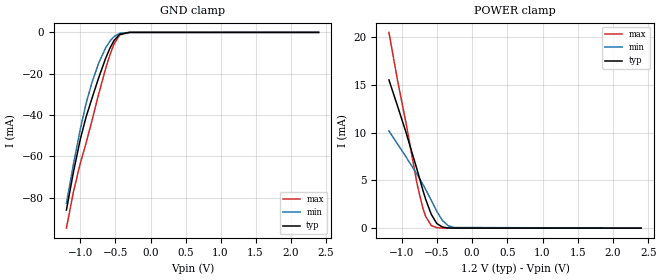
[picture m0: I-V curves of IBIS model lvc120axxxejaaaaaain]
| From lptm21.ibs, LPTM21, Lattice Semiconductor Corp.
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|   Model lvc120axxxejaaaaaain
[Model]   lvc120axxxejaaaaaain
Model_type   Input
Polarity   Non-Inverting
Enable   Active-Low
Vinl =   0.4200V
Vinh =   0.7800V
C_comp   4.2000pF   3.8000pF   7.5000pF
[Temperature Range]   25.0000   0.1050k   -40.0000
[Voltage Range]   1.2000V   1.1400V   1.2600V
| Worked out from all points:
|   GND clamp passes 1 mA (typ) near -0.44 V on its own axis
|   POWER clamp passes 1 mA (typ) near -0.55 V on its own axis
[GND_clamp]
|Voltage   I(typ)   I(min)   I(max)
-1.2V     -86.07mA   -82.81mA   -94.84mA
-1.1V     -67.62mA   -63.85mA   -77.22mA
-1V       -51.44mA   -46.49mA   -63.16mA
-920mV    -41.05mA   -34.47mA   -53.69mA
-840mV    -32.43mA   -24.76mA   -43.33mA
-740mV    -22.02mA   -14.88mA   -29.93mA
-640mV    -12.55mA   -7.499mA   -17.49mA
-580mV    -7.732mA   -4.278mA   -10.96mA
-520mV    -3.911mA   -2mA       -5.586mA
-440mV    -943.9uA   -474.2uA   -1.243mA
-300mV    -18.55uA   -15.85uA   -16.32uA
2.4V      0A         0A         0A
[POWER_clamp]
|Voltage   I(typ)   I(min)   I(max)
-1.18V    15.54mA    10.19mA    20.52mA
-1.06V    12.84mA    8.851mA    15.57mA
-940mV    10.09mA    7.491mA    11.12mA
-780mV    6.115mA    5.629mA    4.606mA
-700mV    4.023mA    4.616mA    2.131mA
-660mV    3.056mA    4.076mA    1.241mA
-580mV    1.457mA    2.922mA    275.5uA
-500mV    478.5uA    1.748mA    47.96uA
-420mV    109.5uA    796.1uA    7.509uA
-340mV    22.62uA    261.6uA    1.074uA
-260mV    4.285uA    65.97uA    166.7nA
2.4V      -20.81nA   -18.5nA    -25.04nA
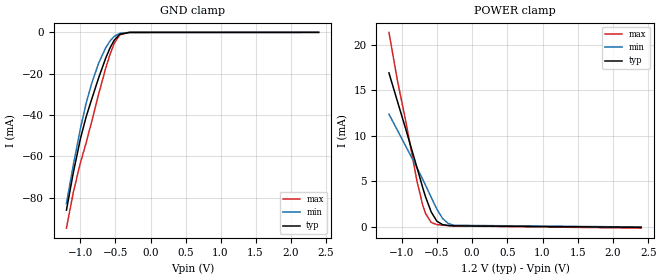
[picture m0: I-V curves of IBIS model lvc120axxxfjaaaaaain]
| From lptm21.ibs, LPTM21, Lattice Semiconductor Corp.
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|   Model lvc120axxxfjaaaaaain
[Model]   lvc120axxxfjaaaaaain
Model_type   Input
Polarity   Non-Inverting
Enable   Active-Low
Vinl =   0.4200V
Vinh =   0.7800V
C_comp   4.2000pF   3.8000pF   7.5000pF
[Temperature Range]   25.0000   0.1050k   -40.0000
[Voltage Range]   1.2000V   1.1400V   1.2600V
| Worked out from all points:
|   GND clamp passes 1 mA (typ) near -0.44 V on its own axis
|   POWER clamp passes 1 mA (typ) near -0.54 V on its own axis
[GND_clamp]
|Voltage   I(typ)   I(min)   I(max)
-1.2V     -86.02mA   -82.79mA   -94.71mA
-1.1V     -67.56mA   -63.82mA   -77.09mA
-1V       -51.39mA   -46.46mA   -63.03mA
-920mV    -41mA      -34.44mA   -53.57mA
-840mV    -32.38mA   -24.74mA   -43.21mA
-740mV    -21.97mA   -14.85mA   -29.81mA
-640mV    -12.51mA   -7.478mA   -17.38mA
-580mV    -7.694mA   -4.26mA    -10.86mA
-520mV    -3.881mA   -1.989mA   -5.509mA
-440mV    -930.4uA   -470.4uA   -1.205mA
-300mV    -18.88uA   -16.34uA   -15.3uA
2.4V      0A         0A         0A
[POWER_clamp]
|Voltage   I(typ)   I(min)   I(max)
-1.18V    16.9mA     12.36mA    21.36mA
-1.06V    13.79mA    10.6mA     16.09mA
-940mV    10.69mA    8.822mA    11.54mA
-780mV    6.439mA    6.432mA    4.901mA
-700mV    4.263mA    5.185mA    2.349mA
-660mV    3.26mA     4.54mA     1.432mA
-580mV    1.601mA    3.213mA    447.8uA
-500mV    588.9uA    1.919mA    217.5uA
-420mV    211.3uA    900.6uA    152uA
-340mV    113.8uA    341.1uA    106.5uA
-260mV    75.42uA    135.6uA    65.45uA
2.4V      -83.82uA   -52.45uA   -176.9uA
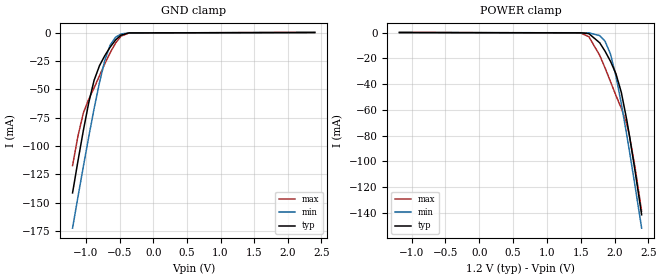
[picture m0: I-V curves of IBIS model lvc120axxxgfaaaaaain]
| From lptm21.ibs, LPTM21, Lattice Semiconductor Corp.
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|   Model lvc120axxxgfaaaaaain
[Model]   lvc120axxxgfaaaaaain
Model_type   Input
Polarity   Non-Inverting
Enable   Active-Low
Vinl =   0.4200V
Vinh =   0.7800V
C_comp   4.2000pF   3.8000pF   7.5000pF
[Temperature Range]   25.0000   0.1050k   -40.0000
[Voltage Range]   1.2000V   1.1400V   1.2600V
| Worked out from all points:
|   GND clamp passes 1 mA (typ) near -0.44 V on its own axis
[GND_clamp]
|Voltage   I(typ)   I(min)   I(max)
-1.2V     -141.4mA   -172.5mA   -117.3mA
-1.12V    -113.3mA   -145mA     -91.27mA
-1.04V    -86.48mA   -118.2mA   -70.96mA
-960mV    -61.94mA   -92.07mA   -58.75mA
-880mV    -42.09mA   -67.12mA   -48.77mA
-800mV    -29.16mA   -44.04mA   -38.03mA
-720mV    -20.2mA    -24.36mA   -27.43mA
-640mV    -12.65mA   -10.75mA   -17.6mA
-560mV    -6.424mA   -3.992mA   -9.143mA
-480mV    -2.205mA   -1.171mA   -3.1mA
-360mV    -225.5uA   -139.6uA   -298.5uA
2.4V      138.5uA    67.97uA    256uA
[POWER_clamp]
|Voltage   I(typ)   I(min)   I(max)
-1.18V    138.3uA    68.12uA    255.2uA
1.5V      -113uA     -45.17uA   -298.5uA
1.62V     -704.2uA   -139.6uA   -3.1mA
1.78V     -7.824mA   -2.252mA   -17.6mA
1.86V     -14.43mA   -6.673mA   -27.43mA
1.94V     -22.27mA   -16.63mA   -38.03mA
2.02V     -31.84mA   -33.63mA   -48.77mA
2.1V      -46.43mA   -55.28mA   -58.75mA
2.18V     -67.76mA   -79.42mA   -70.96mA
2.22V     -80.06mA   -92.07mA   -80.09mA
2.3V      -106.5mA   -118.2mA   -103.8mA
2.4V      -141.4mA   -151.8mA   -138.6mA
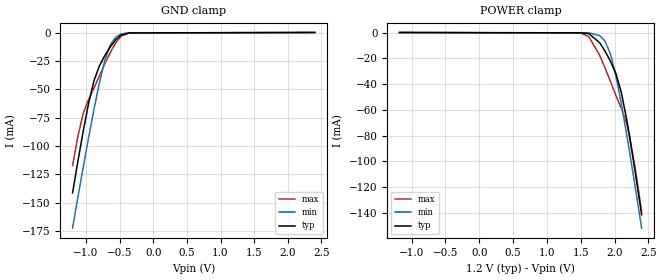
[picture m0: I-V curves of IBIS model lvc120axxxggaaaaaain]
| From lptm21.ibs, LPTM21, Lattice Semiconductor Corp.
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|   Model lvc120axxxggaaaaaain
[Model]   lvc120axxxggaaaaaain
Model_type   Input
Polarity   Non-Inverting
Enable   Active-Low
Vinl =   0.4200V
Vinh =   0.7800V
C_comp   4.2000pF   3.8000pF   7.5000pF
[Temperature Range]   25.0000   0.1050k   -40.0000
[Voltage Range]   1.2000V   1.1400V   1.2600V
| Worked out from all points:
|   GND clamp passes 1 mA (typ) near -0.44 V on its own axis
[GND_clamp]
|Voltage   I(typ)   I(min)   I(max)
-1.2V     -141.4mA   -172.5mA   -117.3mA
-1.12V    -113.3mA   -145mA     -91.26mA
-1.04V    -86.47mA   -118.2mA   -70.94mA
-960mV    -61.93mA   -92.07mA   -58.73mA
-880mV    -42.08mA   -67.12mA   -48.75mA
-800mV    -29.15mA   -44.04mA   -38.02mA
-720mV    -20.19mA   -24.36mA   -27.42mA
-640mV    -12.64mA   -10.74mA   -17.59mA
-560mV    -6.418mA   -3.989mA   -9.135mA
-480mV    -2.202mA   -1.169mA   -3.096mA
-360mV    -225.2uA   -139.4uA   -298.1uA
2.4V      138.6uA    68.13uA    256.2uA
[POWER_clamp]
|Voltage   I(typ)   I(min)   I(max)
-1.18V    138.5uA    68.33uA    255.3uA
1.5V      -112.9uA   -45.04uA   -298.1uA
1.62V     -703uA     -139.4uA   -3.096mA
1.78V     -7.818mA   -2.25mA    -17.59mA
1.86V     -14.42mA   -6.67mA    -27.42mA
1.94V     -22.26mA   -16.62mA   -38.02mA
2.02V     -31.83mA   -33.63mA   -48.75mA
2.1V      -46.42mA   -55.28mA   -58.73mA
2.18V     -67.75mA   -79.42mA   -70.94mA
2.22V     -80.06mA   -92.07mA   -80.07mA
2.3V      -106.5mA   -118.2mA   -103.8mA
2.4V      -141.4mA   -151.8mA   -138.6mA
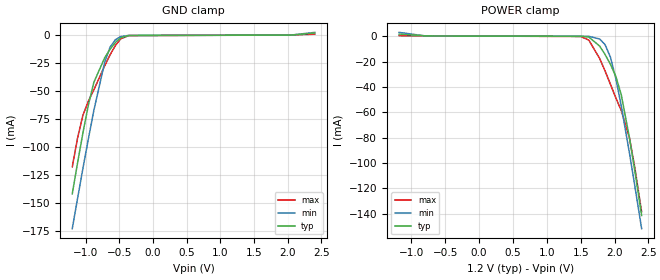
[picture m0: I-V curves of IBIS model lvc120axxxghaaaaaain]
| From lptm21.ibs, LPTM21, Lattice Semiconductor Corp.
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|   Model lvc120axxxghaaaaaain
[Model]   lvc120axxxghaaaaaain
Model_type   Input
Polarity   Non-Inverting
Enable   Active-Low
Vinl =   0.4200V
Vinh =   0.7800V
C_comp   4.2000pF   3.8000pF   7.5000pF
[Temperature Range]   25.0000   0.1050k   -40.0000
[Voltage Range]   1.2000V   1.1400V   1.2600V
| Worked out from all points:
|   GND clamp passes 1 mA (typ) near -0.44 V on its own axis
|   POWER clamp passes 1 mA (typ) near -1.14 V on its own axis
[GND_clamp]
|Voltage   I(typ)   I(min)   I(max)
-1.2V     -141.4mA   -172.5mA   -117.3mA
-1.12V    -113.3mA   -145mA     -91.25mA
-1.04V    -86.47mA   -118.2mA   -70.93mA
-960mV    -61.93mA   -92.07mA   -58.73mA
-880mV    -42.08mA   -67.12mA   -48.74mA
-720mV    -20.19mA   -24.36mA   -27.41mA
-640mV    -12.64mA   -10.74mA   -17.59mA
-560mV    -6.415mA   -3.988mA   -9.132mA
-480mV    -2.201mA   -1.169mA   -3.095mA
-360mV    -224.9uA   -139.2uA   -297.8uA
2.04V     138uA      97.33uA    252.5uA
2.4V      1.997mA    2.552mA    947uA
[POWER_clamp]
|Voltage   I(typ)   I(min)   I(max)
-1.18V    1.633mA    2.953mA    352.9uA
-780mV    136.3uA    97.33uA    251.1uA
1.5V      -112.7uA   -44.92uA   -297.8uA
1.62V     -702.4uA   -139.2uA   -3.095mA
1.78V     -7.815mA   -2.249mA   -17.59mA
1.86V     -14.42mA   -6.668mA   -27.41mA
1.94V     -22.26mA   -16.62mA   -38.01mA
2.02V     -31.82mA   -33.63mA   -48.74mA
2.1V      -46.41mA   -55.28mA   -58.73mA
2.22V     -80.05mA   -92.07mA   -80.07mA
2.3V      -106.4mA   -118.2mA   -103.8mA
2.4V      -141.4mA   -151.8mA   -138.6mA
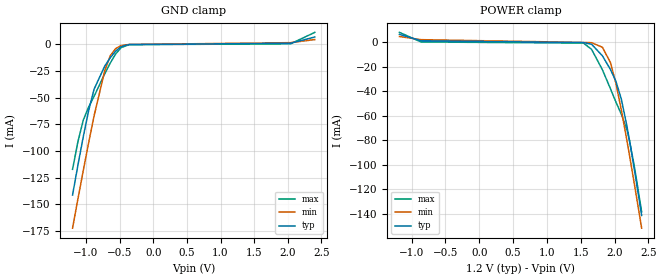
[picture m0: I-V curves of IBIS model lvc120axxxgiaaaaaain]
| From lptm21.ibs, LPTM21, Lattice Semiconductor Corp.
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|   Model lvc120axxxgiaaaaaain
[Model]   lvc120axxxgiaaaaaain
Model_type   Input
Polarity   Non-Inverting
Enable   Active-Low
Vinl =   0.4200V
Vinh =   0.7800V
C_comp   4.2000pF   3.8000pF   7.5000pF
[Temperature Range]   25.0000   0.1050k   -40.0000
[Voltage Range]   1.2000V   1.1400V   1.2600V
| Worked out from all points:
|   GND clamp passes 1 mA (typ) near -0.44 V on its own axis
|   POWER clamp passes 1 mA (typ) near -0.84 V on its own axis
[GND_clamp]
|Voltage   I(typ)   I(min)   I(max)
-1.2V     -141.4mA   -172.5mA   -117.3mA
-1.12V    -113.3mA   -145mA     -91.25mA
-1.04V    -86.47mA   -118.2mA   -70.93mA
-960mV    -61.93mA   -92.06mA   -58.72mA
-880mV    -42.07mA   -67.12mA   -48.74mA
-720mV    -20.19mA   -24.36mA   -27.41mA
-640mV    -12.64mA   -10.74mA   -17.58mA
-560mV    -6.414mA   -3.987mA   -9.13mA
-480mV    -2.2mA     -1.168mA   -3.094mA
-360mV    -224.8uA   -139.1uA   -297.7uA
2.04V     1.009mA    1.579mA    468uA
2.4V      6.866mA    4.471mA    11.23mA
[POWER_clamp]
|Voltage   I(typ)   I(min)   I(max)
-1.18V    6.57mA     4.794mA    8.172mA
-860mV    1.287mA    2.21mA     324.2uA
1.54V     -168.8uA   -58.61uA   -596.5uA
1.66V     -1.547mA   -268.6uA   -5.719mA
1.82V     -10.94mA   -3.987mA   -22.37mA
1.94V     -22.26mA   -16.62mA   -38.01mA
2.02V     -31.82mA   -33.63mA   -48.74mA
2.1V      -46.41mA   -55.27mA   -58.72mA
2.18V     -67.75mA   -79.42mA   -70.93mA
2.22V     -80.05mA   -92.06mA   -80.07mA
2.3V      -106.4mA   -118.2mA   -103.8mA
2.4V      -141.4mA   -151.8mA   -138.6mA
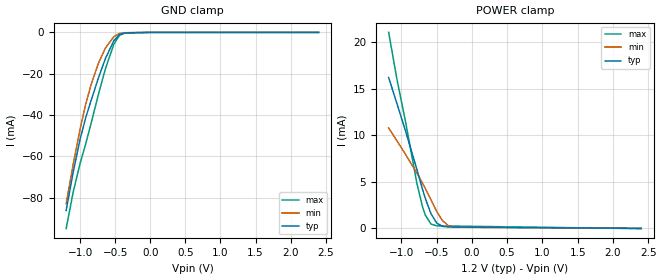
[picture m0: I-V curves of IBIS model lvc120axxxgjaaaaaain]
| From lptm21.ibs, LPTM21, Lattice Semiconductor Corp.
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|   Model lvc120axxxgjaaaaaain
[Model]   lvc120axxxgjaaaaaain
Model_type   Input
Polarity   Non-Inverting
Enable   Active-Low
Vinl =   0.4200V
Vinh =   0.7800V
C_comp   4.2000pF   3.8000pF   7.5000pF
[Temperature Range]   25.0000   0.1050k   -40.0000
[Voltage Range]   1.2000V   1.1400V   1.2600V
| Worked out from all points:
|   GND clamp passes 1 mA (typ) near -0.44 V on its own axis
|   POWER clamp passes 1 mA (typ) near -0.54 V on its own axis
[GND_clamp]
|Voltage   I(typ)   I(min)   I(max)
-1.2V     -86.12mA   -82.85mA   -94.91mA
-1.1V     -67.67mA   -63.89mA   -77.29mA
-1V       -51.5mA    -46.53mA   -63.23mA
-920mV    -41.11mA   -34.51mA   -53.77mA
-840mV    -32.49mA   -24.81mA   -43.41mA
-740mV    -22.08mA   -14.92mA   -30.01mA
-640mV    -12.62mA   -7.552mA   -17.58mA
-520mV    -4.002mA   -2.066mA   -5.717mA
-440mV    -1.052mA   -544.2uA   -1.412mA
-360mV    -224.4uA   -137uA     -297.4uA
0V        0A         0A         0A
2.4V      0A         0A         0A
[POWER_clamp]
|Voltage   I(typ)   I(min)   I(max)
-1.18V    16.21mA    10.79mA    21.06mA
-1.06V    13.35mA    9.386mA    15.93mA
-940mV    10.45mA    7.942mA    11.44mA
-780mV    6.343mA    5.946mA    4.852mA
-700mV    4.202mA    4.86mA     2.326mA
-660mV    3.213mA    4.284mA    1.42mA
-580mV    1.577mA    3.065mA    461uA
-500mV    580.8uA    1.84mA     269.7uA
-420mV    220.7uA    858.6uA    248.9uA
-340mV    147uA      315.9uA    245.9uA
-260mV    134.1uA    123.8uA    244.6uA
2.4V      -20.2nA    -1.007uA   -33.94uA
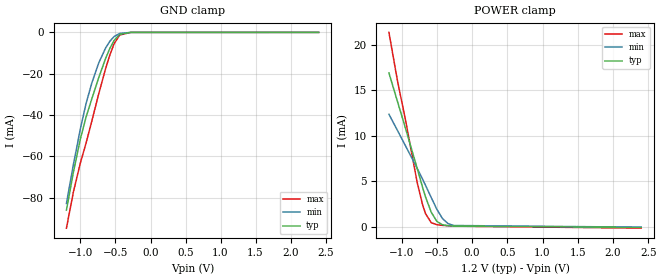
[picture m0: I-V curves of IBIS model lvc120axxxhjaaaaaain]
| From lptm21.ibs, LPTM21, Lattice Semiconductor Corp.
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|   Model lvc120axxxhjaaaaaain
[Model]   lvc120axxxhjaaaaaain
Model_type   Input
Polarity   Non-Inverting
Enable   Active-Low
Vinl =   0.4200V
Vinh =   0.7800V
C_comp   4.2000pF   3.8000pF   7.5000pF
[Temperature Range]   25.0000   0.1050k   -40.0000
[Voltage Range]   1.2000V   1.1400V   1.2600V
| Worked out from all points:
|   GND clamp passes 1 mA (typ) near -0.44 V on its own axis
|   POWER clamp passes 1 mA (typ) near -0.54 V on its own axis
[GND_clamp]
|Voltage   I(typ)   I(min)   I(max)
-1.2V     -86.05mA   -82.8mA    -94.75mA
-1.1V     -67.59mA   -63.84mA   -77.13mA
-1V       -51.42mA   -46.49mA   -63.08mA
-920mV    -41.03mA   -34.46mA   -53.61mA
-840mV    -32.42mA   -24.76mA   -43.26mA
-740mV    -22.01mA   -14.88mA   -29.85mA
-640mV    -12.55mA   -7.505mA   -17.43mA
-580mV    -7.735mA   -4.289mA   -10.91mA
-520mV    -3.926mA   -2.018mA   -5.563mA
-440mV    -975.9uA   -496.4uA   -1.258mA
-280mV    -21.15uA   -10.37uA   -5.4uA
2.4V      0A         0A         0A
[POWER_clamp]
|Voltage   I(typ)   I(min)   I(max)
-1.18V    16.9mA     12.36mA    21.36mA
-1.06V    13.79mA    10.6mA     16.09mA
-940mV    10.69mA    8.822mA    11.54mA
-780mV    6.439mA    6.432mA    4.901mA
-700mV    4.263mA    5.185mA    2.349mA
-660mV    3.26mA     4.54mA     1.432mA
-580mV    1.601mA    3.213mA    447.8uA
-500mV    588.9uA    1.919mA    217.5uA
-420mV    211.3uA    900.6uA    152uA
-340mV    113.8uA    341.1uA    106.5uA
-260mV    75.42uA    135.6uA    65.45uA
2.4V      -76.46uA   -47.78uA   -154.4uA
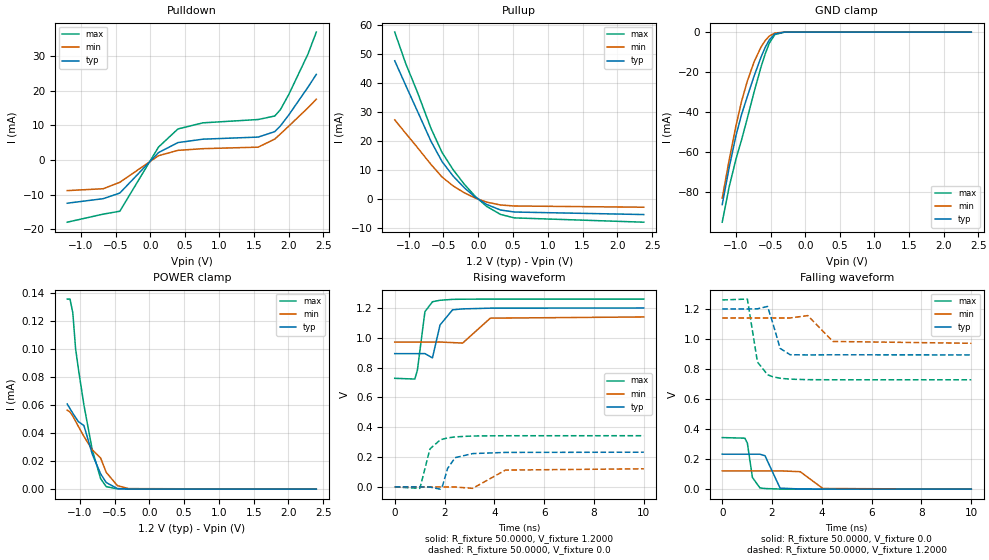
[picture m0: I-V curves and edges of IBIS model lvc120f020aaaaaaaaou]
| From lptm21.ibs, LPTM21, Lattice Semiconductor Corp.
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|   Model lvc120f020aaaaaaaaou
[Model]   lvc120f020aaaaaaaaou
Model_type   Output
Polarity   Non-Inverting
Enable   Active-Low
Vmeas =   0.6000V
Cref =   0.0F
Rref =   1.0000M
Vref =   0.0V
C_comp   4.2000pF   3.8000pF   7.5000pF
[Temperature Range]   25.0000   0.1050k   -40.0000
[Voltage Range]   1.2000V   1.1400V   1.2600V
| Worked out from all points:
|   slope of the pulldown table from 0 to 0.18 V, typ, clamps not added: 60.4 ohm
|   slope of the pullup table from 0 to 0.18 V, typ, clamps not added: 72.7 ohm
|   GND clamp passes 1 mA (typ) near -0.44 V on its own axis
|   rising waveform, R_fixture 50.0000, V_fixture 1.2000: 20-80 % time 320ps typ, 422ps min, 245ps max; typ from 0.894 V to 1.2 V
|   rising waveform, R_fixture 50.0000, V_fixture 0.0: 20-80 % time 349ps typ, 458ps min, 350ps max; typ from 0 V to 0.233 V
|   falling waveform, R_fixture 50.0000, V_fixture 0.0: 20-80 % time 223ps typ, 409ps min, 191ps max; typ from 0.233 V to 0 V
|   falling waveform, R_fixture 50.0000, V_fixture 1.2000: 20-80 % time 280ps typ, 411ps min, 299ps max; typ from 1.2 V to 0.894 V
[Pulldown]
|Voltage   I(typ)   I(min)   I(max)
-1.2V     -12.49mA   -8.854mA   -17.97mA
-680mV    -11.18mA   -8.31mA    -15.64mA
-440mV    -9.56mA    -6.459mA   -14.81mA
120mV     2.13mA     1.226mA    3.733mA
400mV     5.009mA    2.767mA    8.943mA
760mV     5.996mA    3.254mA    10.71mA
1.56V     6.602mA    3.693mA    11.67mA
1.8V      8.173mA    6.028mA    12.69mA
1.88V     9.796mA    7.482mA    14.48mA
2V        12.92mA    9.725mA    18.81mA
2.28V     21.01mA    15.06mA    30.57mA
2.4V      24.69mA    17.53mA    36.91mA
[Pullup]
|Voltage   I(typ)   I(min)   I(max)
-1.2V     47.59mA    27.28mA    57.45mA
-1.04V    39.03mA    22.6mA     46.51mA
-880mV    30.6mA     17.97mA    37.16mA
-680mV    19.99mA    12mA       24.41mA
-520mV    12.95mA    7.652mA    16.09mA
-360mV    7.951mA    4.572mA    10.14mA
-200mV    3.954mA    2.226mA    5.162mA
-40mV     694.9uA    382uA      933uA
120mV     -1.773mA   -961.5uA   -2.432mA
320mV     -3.686mA   -1.972mA   -5.2mA
520mV     -4.384mA   -2.311mA   -6.401mA
2.38V     -5.256mA   -2.734mA   -7.878mA
[GND_clamp]
|Voltage   I(typ)   I(min)   I(max)
-1.2V     -86.07mA   -82.81mA   -94.84mA
-1.1V     -67.62mA   -63.85mA   -77.22mA
-1V       -51.44mA   -46.49mA   -63.16mA
-920mV    -41.05mA   -34.47mA   -53.69mA
-840mV    -32.43mA   -24.76mA   -43.33mA
-740mV    -22.02mA   -14.88mA   -29.93mA
-640mV    -12.55mA   -7.499mA   -17.49mA
-580mV    -7.732mA   -4.278mA   -10.96mA
-520mV    -3.911mA   -2mA       -5.586mA
-440mV    -943.9uA   -474.2uA   -1.243mA
-300mV    -18.55uA   -15.85uA   -16.32uA
2.4V      0A         0A         0A
[POWER_clamp]
|Voltage   I(typ)   I(min)   I(max)
-1.18V    60.64uA    56.26uA    135.4uA
-1.14V    57.31uA    54.99uA    135.4uA
-1.1V     54.11uA    52uA       125.7uA
-1.06V    51.03uA    48.39uA    100.1uA
-1.02V    48.09uA    44.69uA    85.81uA
-940mV    45.28uA    37.56uA    59.84uA
-820mV    24.89uA    28uA       27.91uA
-700mV    10.88uA    22.15uA    7.486uA
-620mV    4.733uA    12.01uA    1.786uA
-460mV    415.3nA    2.532uA    158.5nA
-300mV    127.1nA    366.3nA    158.5nA
2.4V      -20.81nA   -18.5nA    -25.04nA
[Ramp]
| variable   typ   min   max
dV/dt_r  0.1165/0.3611n   73.0256m/0.4532n   0.2061/0.3466n
dV/dt_f  0.1955/0.3228n   0.1011/0.4074n   0.3190/0.2964n
R_load = 50.0000
[Rising Waveform]
R_fixture=   50.0000
V_fixture=   1.2000
V_fixture_min=   1.1400
V_fixture_max=   1.2600
|time   V(typ)   V(min)   V(max)
0s        894.1mV    971.4mV    728.4mV
808.1ps   894mV      971.4mV    723.7mV
909.1ps   894mV      971.4mV    782.4mV
1.212ns   894.3mV    971.4mV    1.175V
1.515ns   865.4mV    971.4mV    1.242V
1.818ns   1.086V     972mV      1.252V
2.323ns   1.188V     968mV      1.258V
2.727ns   1.194V     964.9mV    1.259V
3.838ns   1.199V     1.132V     1.26V
10ns      1.2V       1.14V      1.26V
[Rising Waveform]
R_fixture=   50.0000
V_fixture=   0.0
V_fixture_min=   0.0
V_fixture_max=   0.0
|time   V(typ)   V(min)   V(max)
0s        481.1nV    691.4nV    368.7nV
1.01ns    40.78uV    727.1nV    -9.713mV
1.414ns   -639.1uV   3.422uV    255mV
1.818ns   -14.89mV   22.38uV    314.3mV
1.919ns   7.356mV    -31.46uV   320.3mV
2.121ns   123.5mV    -199.6uV   328.7mV
2.424ns   196.3mV    -337.2uV   335.8mV
3.131ns   223.8mV    -9.31mV    341.8mV
4.444ns   231.6mV    113.1mV    343.5mV
10ns      233mV      121.7mV    343.6mV
[Falling Waveform]
R_fixture=   50.0000
V_fixture=   0.0
V_fixture_min=   0.0
V_fixture_max=   0.0
|time   V(typ)   V(min)   V(max)
0s        233mV      121.8mV    343.6mV
909.1ps   233mV      121.8mV    339.6mV
1.01ns    233mV      121.8mV    306.1mV
1.212ns   233mV      121.8mV    78.01mV
1.515ns   232.9mV    121.8mV    8.158mV
1.717ns   222.6mV    121.8mV    4.289mV
2.323ns   6.832mV    122mV      763.5uV
3.131ns   1.248mV    116.4mV    88.61uV
4.04ns    313.7uV    4.448mV    22.68uV
10ns      11.06uV    4.348uV    25.72uV
[Falling Waveform]
R_fixture=   50.0000
V_fixture=   1.2000
V_fixture_min=   1.1400
V_fixture_max=   1.2600
|time   V(typ)   V(min)   V(max)
0s        1.2V       1.14V      1.26V
1.01ns    1.2V       1.14V      1.266V
1.414ns   1.201V     1.14V      846.9mV
1.818ns   1.217V     1.14V      762.2mV
2.02ns    1.112V     1.14V      749.1mV
2.323ns   937.9mV    1.14V      738.7mV
2.727ns   895.3mV    1.14V      732.5mV
3.434ns   894.1mV    1.156V     729.2mV
4.444ns   894.8mV    983.6mV    728.5mV
10ns      894.1mV    971.5mV    728.4mV
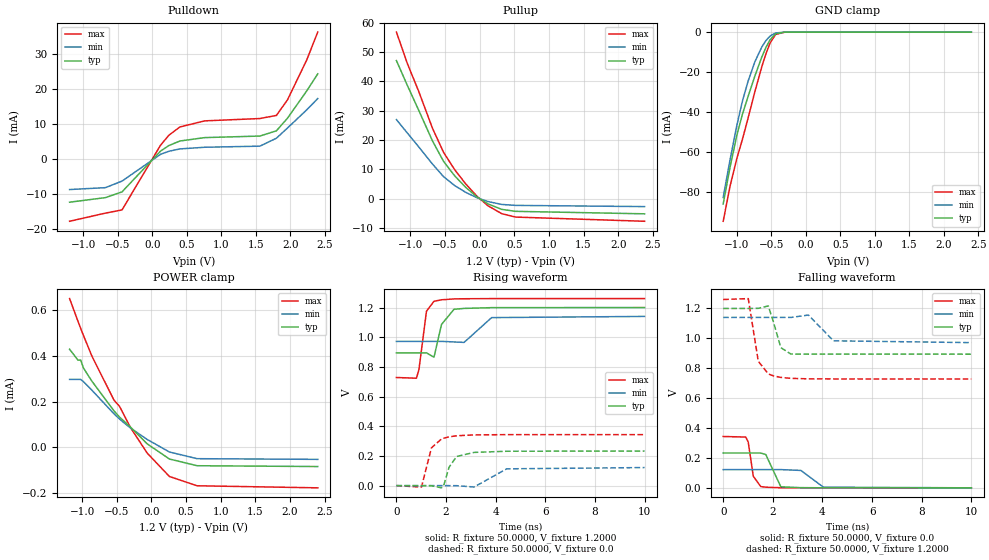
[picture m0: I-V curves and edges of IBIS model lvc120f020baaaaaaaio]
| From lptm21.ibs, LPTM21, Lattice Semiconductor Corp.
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|   Model lvc120f020baaaaaaaio
[Model]   lvc120f020baaaaaaaio
Model_type   I/O
Polarity   Non-Inverting
Enable   Active-Low
Vinl =   0.4200V
Vinh =   0.7800V
Vmeas =   0.6000V
Cref =   0.0F
Rref =   1.0000M
Vref =   0.0V
C_comp   4.2000pF   3.8000pF   7.5000pF
[Temperature Range]   25.0000   0.1050k   -40.0000
[Voltage Range]   1.2000V   1.1400V   1.2600V
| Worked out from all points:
|   slope of the pulldown table from 0 to 0.18 V, typ, clamps not added: 60.5 ohm
|   slope of the pullup table from 0 to 0.18 V, typ, clamps not added: 73.2 ohm
|   GND clamp passes 1 mA (typ) near -0.44 V on its own axis
|   rising waveform, R_fixture 50.0000, V_fixture 1.2000: 20-80 % time 320ps typ, 422ps min, 245ps max; typ from 0.894 V to 1.2 V
|   rising waveform, R_fixture 50.0000, V_fixture 0.0: 20-80 % time 349ps typ, 458ps min, 350ps max; typ from 0 V to 0.233 V
|   falling waveform, R_fixture 50.0000, V_fixture 0.0: 20-80 % time 223ps typ, 409ps min, 191ps max; typ from 0.233 V to 0 V
|   falling waveform, R_fixture 50.0000, V_fixture 1.2000: 20-80 % time 280ps typ, 411ps min, 299ps max; typ from 1.2 V to 0.894 V
[Pulldown]
|Voltage   I(typ)   I(min)   I(max)
-1.2V     -12.45mA   -8.826mA   -17.92mA
-680mV    -11.14mA   -8.281mA   -15.58mA
-440mV    -9.494mA   -6.411mA   -14.67mA
120mV     2.209mA    1.278mA    3.907mA
240mV     3.785mA    2.148mA    6.735mA
400mV     5.085mA    2.818mA    9.112mA
760mV     6.063mA    3.297mA    10.86mA
1.56V     6.508mA    3.61mA     11.53mA
1.8V      8.006mA    5.887mA    12.42mA
1.96V     11.61mA    8.8mA      16.86mA
2.24V     19.44mA    14.02mA    28.31mA
2.4V      24.34mA    17.26mA    36.32mA
[Pullup]
|Voltage   I(typ)   I(min)   I(max)
-1.2V     47.14mA    27.01mA    56.86mA
-1.04V    38.56mA    22.36mA    46.01mA
-880mV    30.28mA    17.77mA    36.74mA
-680mV    19.75mA    11.85mA    24.08mA
-520mV    12.77mA    7.545mA    15.84mA
-360mV    7.83mA     4.502mA    9.941mA
-200mV    3.89mA     2.189mA    5.067mA
-40mV     683uA      375.2uA    915.1uA
120mV     -1.742mA   -943.7uA   -2.383mA
320mV     -3.615mA   -1.934mA   -5.087mA
520mV     -4.292mA   -2.262mA   -6.249mA
2.38V     -5.138mA   -2.671mA   -7.678mA
[GND_clamp]
|Voltage   I(typ)   I(min)   I(max)
-1.2V     -86.02mA   -82.79mA   -94.71mA
-1.1V     -67.56mA   -63.82mA   -77.09mA
-1V       -51.39mA   -46.46mA   -63.03mA
-920mV    -41mA      -34.44mA   -53.57mA
-840mV    -32.38mA   -24.74mA   -43.21mA
-740mV    -21.97mA   -14.85mA   -29.81mA
-640mV    -12.51mA   -7.478mA   -17.38mA
-580mV    -7.694mA   -4.26mA    -10.86mA
-520mV    -3.881mA   -1.989mA   -5.509mA
-440mV    -930.4uA   -470.4uA   -1.205mA
-300mV    -18.88uA   -16.34uA   -15.3uA
2.4V      0A         0A         0A
[POWER_clamp]
|Voltage   I(typ)   I(min)   I(max)
-1.18V    428.9uA    296.9uA    650.2uA
-1.06V    381.4uA    296.9uA    551.8uA
-1.02V    381.4uA    296.9uA    520uA
-980mV    346.6uA    287.3uA    488.9uA
-860mV    289.9uA    250.4uA    400uA
-540mV    159.6uA    146.6uA    206.4uA
-460mV    132.4uA    123.9uA    179.3uA
-300mV    88.01uA    83.86uA    85.61uA
-60mV     15.09uA    34.5uA     -25.38uA
260mV     -50.94uA   -20.29uA   -127.3uA
660mV     -80.25uA   -49.46uA   -167.9uA
2.4V      -83.82uA   -52.45uA   -176.9uA
[Ramp]
| variable   typ   min   max
dV/dt_r  0.1165/0.3611n   73.0256m/0.4532n   0.2061/0.3466n
dV/dt_f  0.1955/0.3228n   0.1011/0.4074n   0.3190/0.2964n
R_load = 50.0000
[Rising Waveform]
R_fixture=   50.0000
V_fixture=   1.2000
V_fixture_min=   1.1400
V_fixture_max=   1.2600
|time   V(typ)   V(min)   V(max)
0s        894.1mV    971.4mV    728.4mV
808.1ps   894mV      971.4mV    723.7mV
909.1ps   894mV      971.4mV    782.4mV
1.212ns   894.3mV    971.4mV    1.175V
1.515ns   865.4mV    971.4mV    1.242V
1.818ns   1.086V     972mV      1.252V
2.323ns   1.188V     968mV      1.258V
2.727ns   1.194V     964.9mV    1.259V
3.838ns   1.199V     1.132V     1.26V
10ns      1.2V       1.14V      1.26V
[Rising Waveform]
R_fixture=   50.0000
V_fixture=   0.0
V_fixture_min=   0.0
V_fixture_max=   0.0
|time   V(typ)   V(min)   V(max)
0s        481.1nV    691.4nV    368.7nV
1.01ns    40.78uV    727.1nV    -9.713mV
1.414ns   -639.1uV   3.422uV    255mV
1.818ns   -14.89mV   22.38uV    314.3mV
1.919ns   7.356mV    -31.46uV   320.3mV
2.121ns   123.5mV    -199.6uV   328.7mV
2.424ns   196.3mV    -337.2uV   335.8mV
3.131ns   223.8mV    -9.31mV    341.8mV
4.444ns   231.6mV    113.1mV    343.5mV
10ns      233mV      121.7mV    343.6mV
[Falling Waveform]
R_fixture=   50.0000
V_fixture=   0.0
V_fixture_min=   0.0
V_fixture_max=   0.0
|time   V(typ)   V(min)   V(max)
0s        233mV      121.8mV    343.6mV
909.1ps   233mV      121.8mV    339.6mV
1.01ns    233mV      121.8mV    306.1mV
1.212ns   233mV      121.8mV    78.01mV
1.515ns   232.9mV    121.8mV    8.158mV
1.717ns   222.6mV    121.8mV    4.289mV
2.323ns   6.832mV    122mV      763.5uV
3.131ns   1.248mV    116.4mV    88.61uV
4.04ns    313.7uV    4.448mV    22.68uV
10ns      11.06uV    4.348uV    25.72uV
[Falling Waveform]
R_fixture=   50.0000
V_fixture=   1.2000
V_fixture_min=   1.1400
V_fixture_max=   1.2600
|time   V(typ)   V(min)   V(max)
0s        1.2V       1.14V      1.26V
1.01ns    1.2V       1.14V      1.266V
1.414ns   1.201V     1.14V      846.9mV
1.818ns   1.217V     1.14V      762.2mV
2.02ns    1.112V     1.14V      749.1mV
2.323ns   937.9mV    1.14V      738.7mV
2.727ns   895.3mV    1.14V      732.5mV
3.434ns   894.1mV    1.156V     729.2mV
4.444ns   894.8mV    983.6mV    728.5mV
10ns      894.1mV    971.5mV    728.4mV
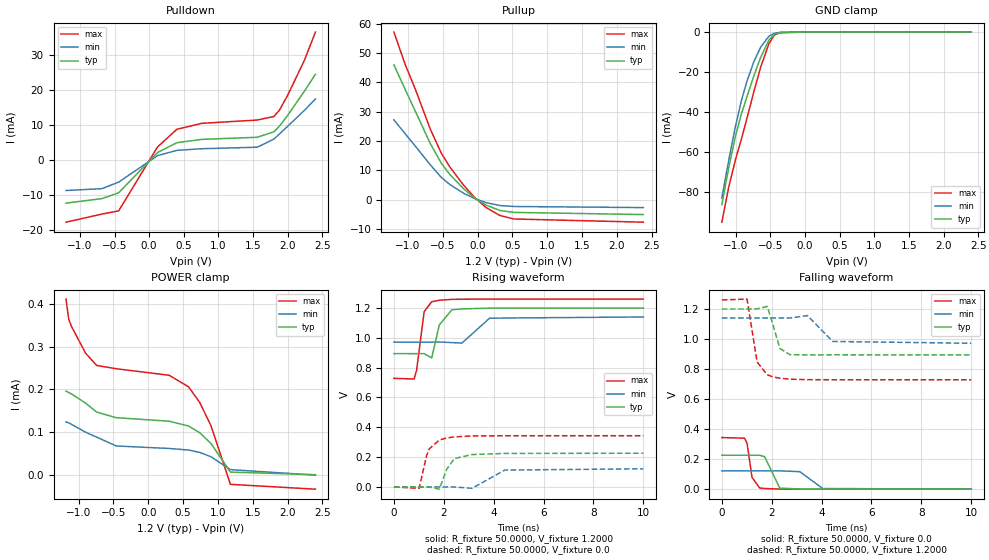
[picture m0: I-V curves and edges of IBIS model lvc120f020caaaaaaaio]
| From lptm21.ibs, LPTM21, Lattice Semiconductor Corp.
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|   Model lvc120f020caaaaaaaio
[Model]   lvc120f020caaaaaaaio
Model_type   I/O
Polarity   Non-Inverting
Enable   Active-Low
Vinl =   0.4200V
Vinh =   0.7800V
Vmeas =   0.6000V
Cref =   0.0F
Rref =   1.0000M
Vref =   0.0V
C_comp   4.2000pF   3.8000pF   7.5000pF
[Temperature Range]   25.0000   0.1050k   -40.0000
[Voltage Range]   1.2000V   1.1400V   1.2600V
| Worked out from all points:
|   slope of the pulldown table from 0 to 0.18 V, typ, clamps not added: 61.4 ohm
|   slope of the pullup table from 0 to 0.18 V, typ, clamps not added: 75 ohm
|   GND clamp passes 1 mA (typ) near -0.44 V on its own axis
|   rising waveform, R_fixture 50.0000, V_fixture 1.2000: 20-80 % time 320ps typ, 422ps min, 245ps max; typ from 0.894 V to 1.2 V
|   rising waveform, R_fixture 50.0000, V_fixture 0.0: 20-80 % time 351ps typ, 458ps min, 350ps max; typ from 0 V to 0.226 V
|   falling waveform, R_fixture 50.0000, V_fixture 0.0: 20-80 % time 228ps typ, 409ps min, 191ps max; typ from 0.226 V to 0 V
|   falling waveform, R_fixture 50.0000, V_fixture 1.2000: 20-80 % time 280ps typ, 411ps min, 299ps max; typ from 1.2 V to 0.894 V
[Pulldown]
|Voltage   I(typ)   I(min)   I(max)
-1.2V     -12.42mA   -8.806mA   -17.89mA
-680mV    -11.12mA   -8.26mA    -15.55mA
-440mV    -9.458mA   -6.389mA   -14.64mA
120mV     2.099mA    1.208mA    3.67mA
400mV     4.924mA    2.722mA    8.774mA
760mV     5.881mA    3.195mA    10.48mA
1.56V     6.478mA    3.628mA    11.43mA
1.8V      8.048mA    5.963mA    12.44mA
1.88V     9.671mA    7.418mA    14.24mA
2V        12.79mA    9.659mA    18.58mA
2.24V     19.69mA    14.2mA     28.54mA
2.4V      24.56mA    17.46mA    36.67mA
[Pullup]
|Voltage   I(typ)   I(min)   I(max)
-1.2V     46.01mA    27.21mA    57.21mA
-1.04V    37.7mA     22.53mA    46.27mA
-880mV    29.53mA    17.9mA     36.93mA
-680mV    19.24mA    11.93mA    24.17mA
-520mV    12.4mA     7.587mA    15.85mA
-400mV    8.649mA    5.186mA    11.22mA
-200mV    3.684mA    2.163mA    4.918mA
-40mV     523.1uA    319.2uA    689.8uA
120mV     -1.869mA   -1.023mA   -2.673mA
320mV     -3.721mA   -2.032mA   -5.436mA
520mV     -4.389mA   -2.367mA   -6.629mA
2.38V     -5.119mA   -2.743mA   -7.729mA
[GND_clamp]
|Voltage   I(typ)   I(min)   I(max)
-1.2V     -86.12mA   -82.85mA   -94.91mA
-1.1V     -67.67mA   -63.89mA   -77.29mA
-1V       -51.5mA    -46.53mA   -63.23mA
-920mV    -41.11mA   -34.51mA   -53.77mA
-840mV    -32.49mA   -24.81mA   -43.41mA
-740mV    -22.08mA   -14.92mA   -30.01mA
-640mV    -12.62mA   -7.552mA   -17.58mA
-520mV    -4.002mA   -2.066mA   -5.717mA
-440mV    -1.052mA   -544.2uA   -1.412mA
-360mV    -224.4uA   -137uA     -297.4uA
0V        0A         0A         0A
2.4V      0A         0A         0A
[POWER_clamp]
|Voltage   I(typ)   I(min)   I(max)
-1.18V    195.7uA    123.7uA    411.4uA
-1.14V    192.3uA    121.4uA    363.5uA
-1.1V     189uA      117.9uA    346.9uA
-900mV    167.7uA    99.59uA    284.8uA
-740mV    146.7uA    87.99uA    255.9uA
-460mV    133.5uA    67.27uA    248.2uA
300mV     125.3uA    61.39uA    232.9uA
580mV     114uA      57.74uA    205.7uA
740mV     98.07uA    52.14uA    168.9uA
900mV     73.23uA    42.07uA    115uA
1.18V     6.005uA    11.83uA    -22.68uA
2.4V      -20.2nA    -1.007uA   -33.94uA
[Ramp]
| variable   typ   min   max
dV/dt_r  0.1165/0.3611n   73.0256m/0.4532n   0.2061/0.3466n
dV/dt_f  0.1955/0.3228n   0.1011/0.4074n   0.3190/0.2964n
R_load = 50.0000
[Rising Waveform]
R_fixture=   50.0000
V_fixture=   1.2000
V_fixture_min=   1.1400
V_fixture_max=   1.2600
|time   V(typ)   V(min)   V(max)
0s        894.1mV    971.4mV    728.4mV
808.1ps   894mV      971.4mV    723.7mV
909.1ps   894mV      971.4mV    782.4mV
1.212ns   894.3mV    971.4mV    1.175V
1.515ns   865.4mV    971.4mV    1.242V
1.818ns   1.086V     972mV      1.252V
2.323ns   1.188V     968mV      1.258V
2.727ns   1.194V     964.9mV    1.259V
3.838ns   1.199V     1.132V     1.26V
10ns      1.2V       1.14V      1.26V
[Rising Waveform]
R_fixture=   50.0000
V_fixture=   0.0
V_fixture_min=   0.0
V_fixture_max=   0.0
|time   V(typ)   V(min)   V(max)
0s        481.1nV    691.4nV    368.7nV
1.01ns    40.78uV    727.1nV    -9.713mV
1.313ns   -263.2uV   2.297uV    212.4mV
1.414ns   -639.1uV   3.422uV    255mV
1.818ns   -14.89mV   22.38uV    314.3mV
2.121ns   119.8mV    -199.6uV   328.7mV
2.424ns   190.4mV    -337.2uV   335.8mV
3.131ns   217.1mV    -9.31mV    341.8mV
4.444ns   224.7mV    113.1mV    343.5mV
10ns      226mV      121.7mV    343.6mV
[Falling Waveform]
R_fixture=   50.0000
V_fixture=   0.0
V_fixture_min=   0.0
V_fixture_max=   0.0
|time   V(typ)   V(min)   V(max)
0s        226mV      121.8mV    343.6mV
909.1ps   226mV      121.8mV    339.6mV
1.01ns    226mV      121.8mV    306.1mV
1.212ns   226mV      121.8mV    78.01mV
1.515ns   225.9mV    121.8mV    8.158mV
1.717ns   215.9mV    121.8mV    4.289mV
2.323ns   6.832mV    122mV      763.5uV
3.131ns   1.248mV    116.4mV    88.61uV
4.04ns    313.7uV    4.448mV    22.68uV
10ns      11.06uV    4.348uV    25.72uV
[Falling Waveform]
R_fixture=   50.0000
V_fixture=   1.2000
V_fixture_min=   1.1400
V_fixture_max=   1.2600
|time   V(typ)   V(min)   V(max)
0s        1.2V       1.14V      1.26V
1.01ns    1.2V       1.14V      1.266V
1.414ns   1.201V     1.14V      846.9mV
1.818ns   1.217V     1.14V      762.2mV
2.02ns    1.112V     1.14V      749.1mV
2.323ns   937.9mV    1.14V      738.7mV
2.727ns   895.3mV    1.14V      732.5mV
3.434ns   894.1mV    1.156V     729.2mV
4.444ns   894.8mV    983.6mV    728.5mV
10ns      894.1mV    971.5mV    728.4mV
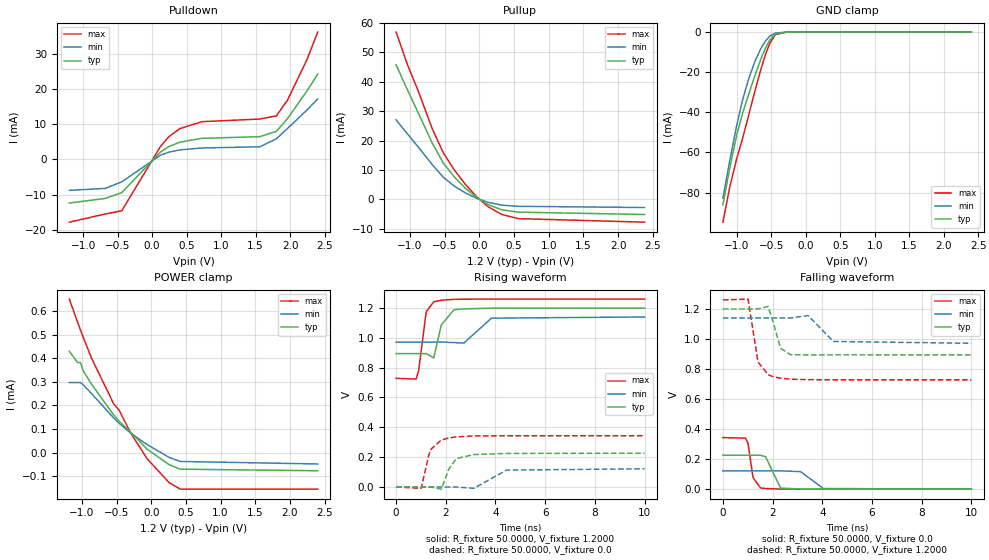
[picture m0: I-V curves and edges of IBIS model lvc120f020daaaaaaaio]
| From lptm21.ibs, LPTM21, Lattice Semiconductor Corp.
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|   Model lvc120f020daaaaaaaio
[Model]   lvc120f020daaaaaaaio
Model_type   I/O
Polarity   Non-Inverting
Enable   Active-Low
Vinl =   0.4200V
Vinh =   0.7800V
Vmeas =   0.6000V
Cref =   0.0F
Rref =   1.0000M
Vref =   0.0V
C_comp   4.2000pF   3.8000pF   7.5000pF
[Temperature Range]   25.0000   0.1050k   -40.0000
[Voltage Range]   1.2000V   1.1400V   1.2600V
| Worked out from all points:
|   slope of the pulldown table from 0 to 0.18 V, typ, clamps not added: 61.4 ohm
|   slope of the pullup table from 0 to 0.18 V, typ, clamps not added: 75.5 ohm
|   GND clamp passes 1 mA (typ) near -0.44 V on its own axis
|   rising waveform, R_fixture 50.0000, V_fixture 1.2000: 20-80 % time 320ps typ, 422ps min, 245ps max; typ from 0.894 V to 1.2 V
|   rising waveform, R_fixture 50.0000, V_fixture 0.0: 20-80 % time 351ps typ, 458ps min, 350ps max; typ from 0 V to 0.226 V
|   falling waveform, R_fixture 50.0000, V_fixture 0.0: 20-80 % time 228ps typ, 409ps min, 191ps max; typ from 0.226 V to 0 V
|   falling waveform, R_fixture 50.0000, V_fixture 1.2000: 20-80 % time 280ps typ, 411ps min, 299ps max; typ from 1.2 V to 0.894 V
[Pulldown]
|Voltage   I(typ)   I(min)   I(max)
-1.2V     -12.42mA   -8.806mA   -17.89mA
-680mV    -11.12mA   -8.26mA    -15.55mA
-440mV    -9.458mA   -6.389mA   -14.64mA
120mV     2.099mA    1.208mA    3.67mA
240mV     3.65mA     2.064mA    6.447mA
400mV     4.924mA    2.722mA    8.774mA
720mV     6.01mA     3.27mA     10.77mA
1.56V     6.508mA    3.61mA     11.53mA
1.8V      8.006mA    5.887mA    12.42mA
1.96V     11.61mA    8.8mA      16.86mA
2.24V     19.44mA    14.02mA    28.31mA
2.4V      24.34mA    17.26mA    36.32mA
[Pullup]
|Voltage   I(typ)   I(min)   I(max)
-1.2V     45.73mA    27.01mA    56.86mA
-1.04V    37.4mA     22.36mA    46.01mA
-880mV    29.38mA    17.77mA    36.74mA
-680mV    19.16mA    11.85mA    24.08mA
-520mV    12.38mA    7.545mA    15.84mA
-360mV    7.596mA    4.502mA    9.941mA
-200mV    3.773mA    2.189mA    5.067mA
-40mV     662.5uA    375.2uA    915.1uA
120mV     -1.689mA   -943.7uA   -2.383mA
320mV     -3.507mA   -1.933mA   -5.087mA
560mV     -4.313mA   -2.334mA   -6.518mA
2.38V     -5.119mA   -2.743mA   -7.729mA
[GND_clamp]
|Voltage   I(typ)   I(min)   I(max)
-1.2V     -86.05mA   -82.8mA    -94.75mA
-1.1V     -67.59mA   -63.84mA   -77.13mA
-1V       -51.42mA   -46.49mA   -63.08mA
-920mV    -41.03mA   -34.46mA   -53.61mA
-840mV    -32.42mA   -24.76mA   -43.26mA
-740mV    -22.01mA   -14.88mA   -29.85mA
-640mV    -12.55mA   -7.505mA   -17.43mA
-580mV    -7.735mA   -4.289mA   -10.91mA
-520mV    -3.926mA   -2.018mA   -5.563mA
-440mV    -975.9uA   -496.4uA   -1.258mA
-280mV    -21.15uA   -10.37uA   -5.4uA
2.4V      0A         0A         0A
[POWER_clamp]
|Voltage   I(typ)   I(min)   I(max)
-1.18V    428.9uA    296.9uA    650.2uA
-1.06V    381.4uA    296.9uA    551.8uA
-1.02V    381.4uA    296.9uA    520uA
-980mV    346.6uA    287.3uA    488.9uA
-860mV    289.9uA    250.4uA    400uA
-540mV    159.6uA    146.6uA    206.4uA
-460mV    132.4uA    123.9uA    179.3uA
-300mV    88.01uA    83.86uA    85.61uA
-60mV     15.09uA    34.5uA     -25.38uA
260mV     -50.94uA   -20.29uA   -127.3uA
420mV     -69.79uA   -37.12uA   -154.4uA
2.4V      -76.46uA   -47.78uA   -154.4uA
[Ramp]
| variable   typ   min   max
dV/dt_r  0.1165/0.3611n   73.0256m/0.4532n   0.2061/0.3466n
dV/dt_f  0.1955/0.3228n   0.1011/0.4074n   0.3190/0.2964n
R_load = 50.0000
[Rising Waveform]
R_fixture=   50.0000
V_fixture=   1.2000
V_fixture_min=   1.1400
V_fixture_max=   1.2600
|time   V(typ)   V(min)   V(max)
0s        894.1mV    971.4mV    728.4mV
808.1ps   894mV      971.4mV    723.7mV
909.1ps   894mV      971.4mV    782.4mV
1.212ns   894.3mV    971.4mV    1.175V
1.515ns   865.4mV    971.4mV    1.242V
1.818ns   1.086V     972mV      1.252V
2.323ns   1.188V     968mV      1.258V
2.727ns   1.194V     964.9mV    1.259V
3.838ns   1.199V     1.132V     1.26V
10ns      1.2V       1.14V      1.26V
[Rising Waveform]
R_fixture=   50.0000
V_fixture=   0.0
V_fixture_min=   0.0
V_fixture_max=   0.0
|time   V(typ)   V(min)   V(max)
0s        481.1nV    691.4nV    368.7nV
1.01ns    40.78uV    727.1nV    -9.713mV
1.313ns   -263.2uV   2.297uV    212.4mV
1.414ns   -639.1uV   3.422uV    255mV
1.818ns   -14.89mV   22.38uV    314.3mV
2.121ns   119.8mV    -199.6uV   328.7mV
2.424ns   190.4mV    -337.2uV   335.8mV
3.131ns   217.1mV    -9.31mV    341.8mV
4.444ns   224.7mV    113.1mV    343.5mV
10ns      226mV      121.7mV    343.6mV
[Falling Waveform]
R_fixture=   50.0000
V_fixture=   0.0
V_fixture_min=   0.0
V_fixture_max=   0.0
|time   V(typ)   V(min)   V(max)
0s        226mV      121.8mV    343.6mV
909.1ps   226mV      121.8mV    339.6mV
1.01ns    226mV      121.8mV    306.1mV
1.212ns   226mV      121.8mV    78.01mV
1.515ns   225.9mV    121.8mV    8.158mV
1.717ns   215.9mV    121.8mV    4.289mV
2.323ns   6.832mV    122mV      763.5uV
3.131ns   1.248mV    116.4mV    88.61uV
4.04ns    313.7uV    4.448mV    22.68uV
10ns      11.06uV    4.348uV    25.72uV
[Falling Waveform]
R_fixture=   50.0000
V_fixture=   1.2000
V_fixture_min=   1.1400
V_fixture_max=   1.2600
|time   V(typ)   V(min)   V(max)
0s        1.2V       1.14V      1.26V
1.01ns    1.2V       1.14V      1.266V
1.414ns   1.201V     1.14V      846.9mV
1.818ns   1.217V     1.14V      762.2mV
2.02ns    1.112V     1.14V      749.1mV
2.323ns   937.9mV    1.14V      738.7mV
2.727ns   895.3mV    1.14V      732.5mV
3.434ns   894.1mV    1.156V     729.2mV
4.444ns   894.8mV    983.6mV    728.5mV
10ns      894.1mV    971.5mV    728.4mV
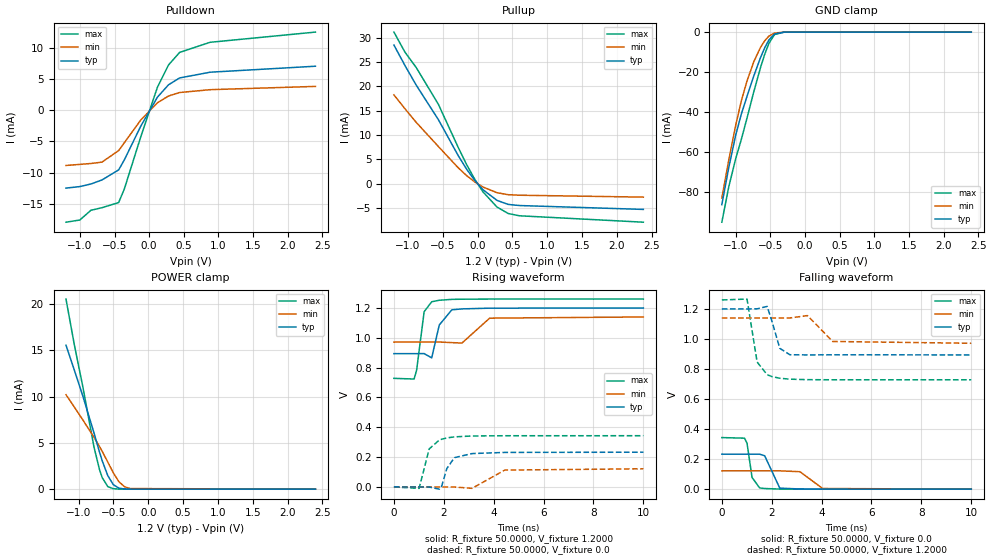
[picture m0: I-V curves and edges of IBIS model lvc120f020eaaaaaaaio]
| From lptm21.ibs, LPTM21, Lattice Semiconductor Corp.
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|   Model lvc120f020eaaaaaaaio
[Model]   lvc120f020eaaaaaaaio
Model_type   I/O
Polarity   Non-Inverting
Enable   Active-Low
Vinl =   0.4200V
Vinh =   0.7800V
Vmeas =   0.6000V
Cref =   0.0F
Rref =   1.0000M
Vref =   0.0V
C_comp   4.2000pF   3.8000pF   7.5000pF
[Temperature Range]   25.0000   0.1050k   -40.0000
[Voltage Range]   1.2000V   1.1400V   1.2600V
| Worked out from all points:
|   slope of the pulldown table from 0 to 0.18 V, typ, clamps not added: 60.4 ohm
|   slope of the pullup table from 0 to 0.18 V, typ, clamps not added: 72.7 ohm
|   GND clamp passes 1 mA (typ) near -0.44 V on its own axis
|   POWER clamp passes 1 mA (typ) near -0.55 V on its own axis
|   rising waveform, R_fixture 50.0000, V_fixture 1.2000: 20-80 % time 320ps typ, 422ps min, 245ps max; typ from 0.894 V to 1.2 V
|   rising waveform, R_fixture 50.0000, V_fixture 0.0: 20-80 % time 349ps typ, 458ps min, 350ps max; typ from 0 V to 0.233 V
|   falling waveform, R_fixture 50.0000, V_fixture 0.0: 20-80 % time 223ps typ, 409ps min, 191ps max; typ from 0.233 V to 0 V
|   falling waveform, R_fixture 50.0000, V_fixture 1.2000: 20-80 % time 280ps typ, 411ps min, 299ps max; typ from 1.2 V to 0.894 V
[Pulldown]
|Voltage   I(typ)   I(min)   I(max)
-1.2V     -12.49mA   -8.854mA   -17.97mA
-1V       -12.25mA   -8.683mA   -17.62mA
-840mV    -11.83mA   -8.537mA   -16.05mA
-680mV    -11.18mA   -8.31mA    -15.64mA
-440mV    -9.56mA    -6.459mA   -14.81mA
-360mV    -7.997mA   -5.224mA   -12.69mA
-120mV    -2.519mA   -1.54mA    -4.218mA
120mV     2.13mA     1.226mA    3.733mA
280mV     4.114mA    2.312mA    7.304mA
440mV     5.212mA    2.867mA    9.314mA
880mV     6.133mA    3.326mA    10.94mA
2.4V      7.094mA    3.851mA    12.58mA
[Pullup]
|Voltage   I(typ)   I(min)   I(max)
-1.2V     28.47mA    18.25mA    31.13mA
-1.04V    24.23mA    15.37mA    26.98mA
-880mV    20.25mA    12.61mA    23.86mA
-560mV    13.12mA    7.623mA    16.26mA
-280mV    5.853mA    3.325mA    7.553mA
-160mV    3.071mA    1.719mA    4.034mA
-40mV     694.9uA    382uA      933uA
80mV      -1.235mA   -670.8uA   -1.685mA
280mV     -3.408mA   -1.829mA   -4.776mA
440mV     -4.227mA   -2.24mA    -6.093mA
600mV     -4.46mA    -2.344mA   -6.562mA
2.38V     -5.256mA   -2.734mA   -7.878mA
[GND_clamp]
|Voltage   I(typ)   I(min)   I(max)
-1.2V     -86.07mA   -82.81mA   -94.84mA
-1.1V     -67.62mA   -63.85mA   -77.22mA
-1V       -51.44mA   -46.49mA   -63.16mA
-920mV    -41.05mA   -34.47mA   -53.69mA
-840mV    -32.43mA   -24.76mA   -43.33mA
-740mV    -22.02mA   -14.88mA   -29.93mA
-640mV    -12.55mA   -7.499mA   -17.49mA
-580mV    -7.732mA   -4.278mA   -10.96mA
-520mV    -3.911mA   -2mA       -5.586mA
-440mV    -943.9uA   -474.2uA   -1.243mA
-300mV    -18.55uA   -15.85uA   -16.32uA
2.4V      0A         0A         0A
[POWER_clamp]
|Voltage   I(typ)   I(min)   I(max)
-1.18V    15.54mA    10.19mA    20.52mA
-1.06V    12.84mA    8.851mA    15.57mA
-940mV    10.09mA    7.491mA    11.12mA
-780mV    6.115mA    5.629mA    4.606mA
-700mV    4.023mA    4.616mA    2.131mA
-660mV    3.056mA    4.076mA    1.241mA
-580mV    1.457mA    2.922mA    275.5uA
-500mV    478.5uA    1.748mA    47.96uA
-420mV    109.5uA    796.1uA    7.509uA
-340mV    22.62uA    261.6uA    1.074uA
-260mV    4.285uA    65.97uA    166.7nA
2.4V      -20.81nA   -18.5nA    -25.04nA
[Ramp]
| variable   typ   min   max
dV/dt_r  0.1165/0.3611n   73.0256m/0.4532n   0.2061/0.3466n
dV/dt_f  0.1955/0.3228n   0.1011/0.4074n   0.3190/0.2964n
R_load = 50.0000
[Rising Waveform]
R_fixture=   50.0000
V_fixture=   1.2000
V_fixture_min=   1.1400
V_fixture_max=   1.2600
|time   V(typ)   V(min)   V(max)
0s        894.1mV    971.4mV    728.4mV
808.1ps   894mV      971.4mV    723.7mV
909.1ps   894mV      971.4mV    782.4mV
1.212ns   894.3mV    971.4mV    1.175V
1.515ns   865.4mV    971.4mV    1.242V
1.818ns   1.086V     972mV      1.252V
2.323ns   1.188V     968mV      1.258V
2.727ns   1.194V     964.9mV    1.259V
3.838ns   1.199V     1.132V     1.26V
10ns      1.2V       1.14V      1.26V
[Rising Waveform]
R_fixture=   50.0000
V_fixture=   0.0
V_fixture_min=   0.0
V_fixture_max=   0.0
|time   V(typ)   V(min)   V(max)
0s        481.1nV    691.4nV    368.7nV
1.01ns    40.78uV    727.1nV    -9.713mV
1.414ns   -639.1uV   3.422uV    255mV
1.818ns   -14.89mV   22.38uV    314.3mV
1.919ns   7.356mV    -31.46uV   320.3mV
2.121ns   123.5mV    -199.6uV   328.7mV
2.424ns   196.3mV    -337.2uV   335.8mV
3.131ns   223.8mV    -9.31mV    341.8mV
4.444ns   231.6mV    113.1mV    343.5mV
10ns      233mV      121.7mV    343.6mV
[Falling Waveform]
R_fixture=   50.0000
V_fixture=   0.0
V_fixture_min=   0.0
V_fixture_max=   0.0
|time   V(typ)   V(min)   V(max)
0s        233mV      121.8mV    343.6mV
909.1ps   233mV      121.8mV    339.6mV
1.01ns    233mV      121.8mV    306.1mV
1.212ns   233mV      121.8mV    78.01mV
1.515ns   232.9mV    121.8mV    8.158mV
1.717ns   222.6mV    121.8mV    4.289mV
2.323ns   6.832mV    122mV      763.5uV
3.131ns   1.248mV    116.4mV    88.61uV
4.04ns    313.7uV    4.448mV    22.68uV
10ns      11.06uV    4.348uV    25.72uV
[Falling Waveform]
R_fixture=   50.0000
V_fixture=   1.2000
V_fixture_min=   1.1400
V_fixture_max=   1.2600
|time   V(typ)   V(min)   V(max)
0s        1.2V       1.14V      1.26V
1.01ns    1.2V       1.14V      1.266V
1.414ns   1.201V     1.14V      846.9mV
1.818ns   1.217V     1.14V      762.2mV
2.02ns    1.112V     1.14V      749.1mV
2.323ns   937.9mV    1.14V      738.7mV
2.727ns   895.3mV    1.14V      732.5mV
3.434ns   894.1mV    1.156V     729.2mV
4.444ns   894.8mV    983.6mV    728.5mV
10ns      894.1mV    971.5mV    728.4mV
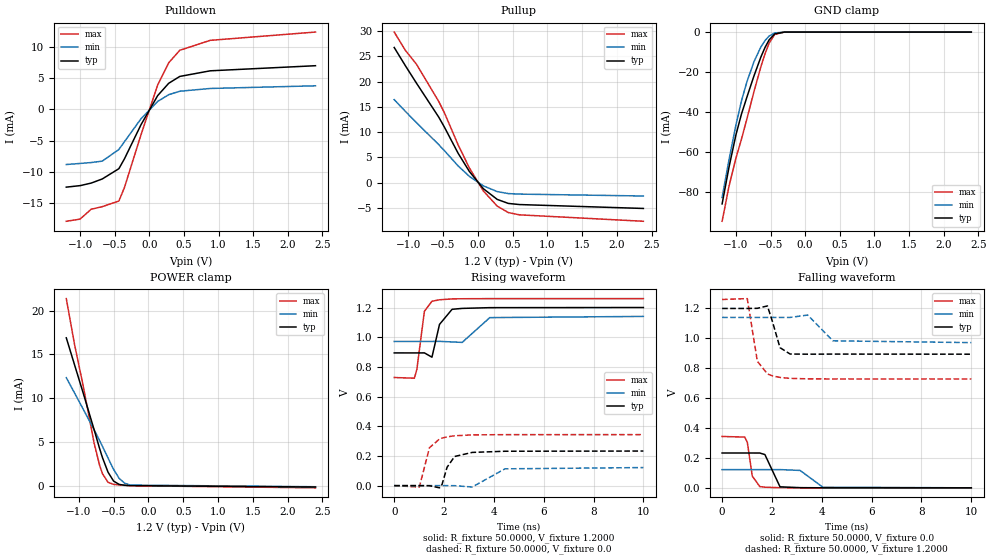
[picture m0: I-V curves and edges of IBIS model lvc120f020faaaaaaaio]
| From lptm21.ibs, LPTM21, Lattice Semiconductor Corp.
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|   Model lvc120f020faaaaaaaio
[Model]   lvc120f020faaaaaaaio
Model_type   I/O
Polarity   Non-Inverting
Enable   Active-Low
Vinl =   0.4200V
Vinh =   0.7800V
Vmeas =   0.6000V
Cref =   0.0F
Rref =   1.0000M
Vref =   0.0V
C_comp   4.2000pF   3.8000pF   7.5000pF
[Temperature Range]   25.0000   0.1050k   -40.0000
[Voltage Range]   1.2000V   1.1400V   1.2600V
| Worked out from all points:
|   slope of the pulldown table from 0 to 0.18 V, typ, clamps not added: 60.5 ohm
|   slope of the pullup table from 0 to 0.18 V, typ, clamps not added: 73.2 ohm
|   GND clamp passes 1 mA (typ) near -0.44 V on its own axis
|   POWER clamp passes 1 mA (typ) near -0.54 V on its own axis
|   rising waveform, R_fixture 50.0000, V_fixture 1.2000: 20-80 % time 320ps typ, 422ps min, 245ps max; typ from 0.894 V to 1.2 V
|   rising waveform, R_fixture 50.0000, V_fixture 0.0: 20-80 % time 349ps typ, 458ps min, 350ps max; typ from 0 V to 0.233 V
|   falling waveform, R_fixture 50.0000, V_fixture 0.0: 20-80 % time 223ps typ, 409ps min, 191ps max; typ from 0.233 V to 0 V
|   falling waveform, R_fixture 50.0000, V_fixture 1.2000: 20-80 % time 280ps typ, 411ps min, 299ps max; typ from 1.2 V to 0.894 V
[Pulldown]
|Voltage   I(typ)   I(min)   I(max)
-1.2V     -12.45mA   -8.826mA   -17.92mA
-1V       -12.21mA   -8.655mA   -17.57mA
-840mV    -11.8mA    -8.509mA   -15.99mA
-680mV    -11.14mA   -8.281mA   -15.58mA
-440mV    -9.494mA   -6.411mA   -14.67mA
-360mV    -7.921mA   -5.171mA   -12.52mA
-120mV    -2.44mA    -1.487mA   -4.04mA
120mV     2.209mA    1.278mA    3.907mA
280mV     4.192mA    2.363mA    7.476mA
440mV     5.289mA    2.918mA    9.483mA
880mV     6.189mA    3.36mA     11.07mA
2.4V      7.005mA    3.785mA    12.4mA
[Pullup]
|Voltage   I(typ)   I(min)   I(max)
-1.2V     26.76mA    16.43mA    29.82mA
-1.04V    23.16mA    14.11mA    26.2mA
-880mV    19.69mA    11.87mA    23.44mA
-560mV    12.96mA    7.506mA    16.06mA
-480mV    11.01mA    6.337mA    13.86mA
-280mV    5.76mA     3.271mA    7.418mA
-120mV    2.195mA    1.221mA    2.896mA
80mV      -1.213mA   -658.5uA   -1.652mA
280mV     -3.343mA   -1.793mA   -4.674mA
440mV     -4.141mA   -2.193mA   -5.953mA
600mV     -4.365mA   -2.294mA   -6.402mA
2.38V     -5.138mA   -2.671mA   -7.678mA
[GND_clamp]
|Voltage   I(typ)   I(min)   I(max)
-1.2V     -86.02mA   -82.79mA   -94.71mA
-1.1V     -67.56mA   -63.82mA   -77.09mA
-1V       -51.39mA   -46.46mA   -63.03mA
-920mV    -41mA      -34.44mA   -53.57mA
-840mV    -32.38mA   -24.74mA   -43.21mA
-740mV    -21.97mA   -14.85mA   -29.81mA
-640mV    -12.51mA   -7.478mA   -17.38mA
-580mV    -7.694mA   -4.26mA    -10.86mA
-520mV    -3.881mA   -1.989mA   -5.509mA
-440mV    -930.4uA   -470.4uA   -1.205mA
-300mV    -18.88uA   -16.34uA   -15.3uA
2.4V      0A         0A         0A
[POWER_clamp]
|Voltage   I(typ)   I(min)   I(max)
-1.18V    16.9mA     12.36mA    21.36mA
-1.06V    13.79mA    10.6mA     16.09mA
-940mV    10.69mA    8.822mA    11.54mA
-780mV    6.439mA    6.432mA    4.901mA
-700mV    4.263mA    5.185mA    2.349mA
-660mV    3.26mA     4.54mA     1.432mA
-580mV    1.601mA    3.213mA    447.8uA
-500mV    588.9uA    1.919mA    217.5uA
-420mV    211.3uA    900.6uA    152uA
-340mV    113.8uA    341.1uA    106.5uA
-260mV    75.42uA    135.6uA    65.45uA
2.4V      -83.82uA   -52.45uA   -176.9uA
[Ramp]
| variable   typ   min   max
dV/dt_r  0.1165/0.3611n   73.0256m/0.4532n   0.2061/0.3466n
dV/dt_f  0.1955/0.3228n   0.1011/0.4074n   0.3190/0.2964n
R_load = 50.0000
[Rising Waveform]
R_fixture=   50.0000
V_fixture=   1.2000
V_fixture_min=   1.1400
V_fixture_max=   1.2600
|time   V(typ)   V(min)   V(max)
0s        894.1mV    971.4mV    728.4mV
808.1ps   894mV      971.4mV    723.7mV
909.1ps   894mV      971.4mV    782.4mV
1.212ns   894.3mV    971.4mV    1.175V
1.515ns   865.4mV    971.4mV    1.242V
1.818ns   1.086V     972mV      1.252V
2.323ns   1.188V     968mV      1.258V
2.727ns   1.194V     964.9mV    1.259V
3.838ns   1.199V     1.132V     1.26V
10ns      1.2V       1.14V      1.26V
[Rising Waveform]
R_fixture=   50.0000
V_fixture=   0.0
V_fixture_min=   0.0
V_fixture_max=   0.0
|time   V(typ)   V(min)   V(max)
0s        481.1nV    691.4nV    368.7nV
1.01ns    40.78uV    727.1nV    -9.713mV
1.414ns   -639.1uV   3.422uV    255mV
1.818ns   -14.89mV   22.38uV    314.3mV
1.919ns   7.356mV    -31.46uV   320.3mV
2.121ns   123.5mV    -199.6uV   328.7mV
2.424ns   196.3mV    -337.2uV   335.8mV
3.131ns   223.8mV    -9.31mV    341.8mV
4.444ns   231.6mV    113.1mV    343.5mV
10ns      233mV      121.7mV    343.6mV
[Falling Waveform]
R_fixture=   50.0000
V_fixture=   0.0
V_fixture_min=   0.0
V_fixture_max=   0.0
|time   V(typ)   V(min)   V(max)
0s        233mV      121.8mV    343.6mV
909.1ps   233mV      121.8mV    339.6mV
1.01ns    233mV      121.8mV    306.1mV
1.212ns   233mV      121.8mV    78.01mV
1.515ns   232.9mV    121.8mV    8.158mV
1.717ns   222.6mV    121.8mV    4.289mV
2.323ns   6.832mV    122mV      763.5uV
3.131ns   1.248mV    116.4mV    88.61uV
4.04ns    313.7uV    4.448mV    22.68uV
10ns      11.06uV    4.348uV    25.72uV
[Falling Waveform]
R_fixture=   50.0000
V_fixture=   1.2000
V_fixture_min=   1.1400
V_fixture_max=   1.2600
|time   V(typ)   V(min)   V(max)
0s        1.2V       1.14V      1.26V
1.01ns    1.2V       1.14V      1.266V
1.414ns   1.201V     1.14V      846.9mV
1.818ns   1.217V     1.14V      762.2mV
2.02ns    1.112V     1.14V      749.1mV
2.323ns   937.9mV    1.14V      738.7mV
2.727ns   895.3mV    1.14V      732.5mV
3.434ns   894.1mV    1.156V     729.2mV
4.444ns   894.8mV    983.6mV    728.5mV
10ns      894.1mV    971.5mV    728.4mV
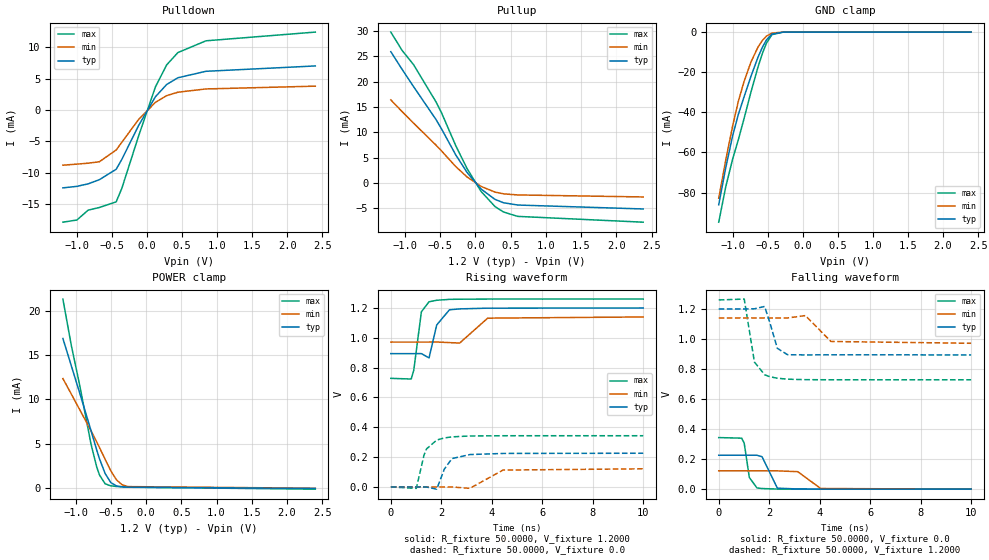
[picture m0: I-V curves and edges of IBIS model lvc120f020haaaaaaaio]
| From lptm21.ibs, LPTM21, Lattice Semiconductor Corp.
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|   Model lvc120f020haaaaaaaio
[Model]   lvc120f020haaaaaaaio
Model_type   I/O
Polarity   Non-Inverting
Enable   Active-Low
Vinl =   0.4200V
Vinh =   0.7800V
Vmeas =   0.6000V
Cref =   0.0F
Rref =   1.0000M
Vref =   0.0V
C_comp   4.2000pF   3.8000pF   7.5000pF
[Temperature Range]   25.0000   0.1050k   -40.0000
[Voltage Range]   1.2000V   1.1400V   1.2600V
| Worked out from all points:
|   slope of the pulldown table from 0 to 0.18 V, typ, clamps not added: 61.4 ohm
|   slope of the pullup table from 0 to 0.18 V, typ, clamps not added: 75.5 ohm
|   GND clamp passes 1 mA (typ) near -0.44 V on its own axis
|   POWER clamp passes 1 mA (typ) near -0.54 V on its own axis
|   rising waveform, R_fixture 50.0000, V_fixture 1.2000: 20-80 % time 320ps typ, 422ps min, 245ps max; typ from 0.894 V to 1.2 V
|   rising waveform, R_fixture 50.0000, V_fixture 0.0: 20-80 % time 351ps typ, 458ps min, 350ps max; typ from 0 V to 0.226 V
|   falling waveform, R_fixture 50.0000, V_fixture 0.0: 20-80 % time 228ps typ, 409ps min, 191ps max; typ from 0.226 V to 0 V
|   falling waveform, R_fixture 50.0000, V_fixture 1.2000: 20-80 % time 280ps typ, 411ps min, 299ps max; typ from 1.2 V to 0.894 V
[Pulldown]
|Voltage   I(typ)   I(min)   I(max)
-1.2V     -12.42mA   -8.806mA   -17.89mA
-1V       -12.18mA   -8.636mA   -17.54mA
-840mV    -11.78mA   -8.49mA    -15.97mA
-680mV    -11.12mA   -8.26mA    -15.55mA
-440mV    -9.458mA   -6.389mA   -14.64mA
-360mV    -7.896mA   -5.161mA   -12.51mA
-120mV    -2.484mA   -1.52mA    -4.151mA
120mV     2.099mA    1.208mA    3.67mA
280mV     4.049mA    2.276mA    7.174mA
440mV     5.122mA    2.819mA    9.134mA
840mV     6.151mA    3.341mA    11.01mA
2.4V      7.005mA    3.785mA    12.4mA
[Pullup]
|Voltage   I(typ)   I(min)   I(max)
-1.2V     25.95mA    16.43mA    29.82mA
-1.04V    22.46mA    14.11mA    26.2mA
-880mV    19.1mA     11.87mA    23.44mA
-560mV    12.57mA    7.506mA    16.06mA
-480mV    10.68mA    6.337mA    13.86mA
-280mV    5.588mA    3.271mA    7.418mA
-120mV    2.129mA    1.221mA    2.896mA
80mV      -1.176mA   -658.5uA   -1.652mA
280mV     -3.243mA   -1.793mA   -4.674mA
400mV     -3.892mA   -2.132mA   -5.725mA
600mV     -4.341mA   -2.347mA   -6.582mA
2.38V     -5.119mA   -2.743mA   -7.729mA
[GND_clamp]
|Voltage   I(typ)   I(min)   I(max)
-1.2V     -86.05mA   -82.8mA    -94.75mA
-1.1V     -67.59mA   -63.84mA   -77.13mA
-1V       -51.42mA   -46.49mA   -63.08mA
-920mV    -41.03mA   -34.46mA   -53.61mA
-840mV    -32.42mA   -24.76mA   -43.26mA
-740mV    -22.01mA   -14.88mA   -29.85mA
-640mV    -12.55mA   -7.505mA   -17.43mA
-580mV    -7.735mA   -4.289mA   -10.91mA
-520mV    -3.926mA   -2.018mA   -5.563mA
-440mV    -975.9uA   -496.4uA   -1.258mA
-280mV    -21.15uA   -10.37uA   -5.4uA
2.4V      0A         0A         0A
[POWER_clamp]
|Voltage   I(typ)   I(min)   I(max)
-1.18V    16.9mA     12.36mA    21.36mA
-1.06V    13.79mA    10.6mA     16.09mA
-940mV    10.69mA    8.822mA    11.54mA
-780mV    6.439mA    6.432mA    4.901mA
-700mV    4.263mA    5.185mA    2.349mA
-660mV    3.26mA     4.54mA     1.432mA
-580mV    1.601mA    3.213mA    447.8uA
-500mV    588.9uA    1.919mA    217.5uA
-420mV    211.3uA    900.6uA    152uA
-340mV    113.8uA    341.1uA    106.5uA
-260mV    75.42uA    135.6uA    65.45uA
2.4V      -76.46uA   -47.78uA   -154.4uA
[Ramp]
| variable   typ   min   max
dV/dt_r  0.1165/0.3611n   73.0256m/0.4532n   0.2061/0.3466n
dV/dt_f  0.1955/0.3228n   0.1011/0.4074n   0.3190/0.2964n
R_load = 50.0000
[Rising Waveform]
R_fixture=   50.0000
V_fixture=   1.2000
V_fixture_min=   1.1400
V_fixture_max=   1.2600
|time   V(typ)   V(min)   V(max)
0s        894.1mV    971.4mV    728.4mV
808.1ps   894mV      971.4mV    723.7mV
909.1ps   894mV      971.4mV    782.4mV
1.212ns   894.3mV    971.4mV    1.175V
1.515ns   865.4mV    971.4mV    1.242V
1.818ns   1.086V     972mV      1.252V
2.323ns   1.188V     968mV      1.258V
2.727ns   1.194V     964.9mV    1.259V
3.838ns   1.199V     1.132V     1.26V
10ns      1.2V       1.14V      1.26V
[Rising Waveform]
R_fixture=   50.0000
V_fixture=   0.0
V_fixture_min=   0.0
V_fixture_max=   0.0
|time   V(typ)   V(min)   V(max)
0s        481.1nV    691.4nV    368.7nV
1.01ns    40.78uV    727.1nV    -9.713mV
1.313ns   -263.2uV   2.297uV    212.4mV
1.414ns   -639.1uV   3.422uV    255mV
1.818ns   -14.89mV   22.38uV    314.3mV
2.121ns   119.8mV    -199.6uV   328.7mV
2.424ns   190.4mV    -337.2uV   335.8mV
3.131ns   217.1mV    -9.31mV    341.8mV
4.444ns   224.7mV    113.1mV    343.5mV
10ns      226mV      121.7mV    343.6mV
[Falling Waveform]
R_fixture=   50.0000
V_fixture=   0.0
V_fixture_min=   0.0
V_fixture_max=   0.0
|time   V(typ)   V(min)   V(max)
0s        226mV      121.8mV    343.6mV
909.1ps   226mV      121.8mV    339.6mV
1.01ns    226mV      121.8mV    306.1mV
1.212ns   226mV      121.8mV    78.01mV
1.515ns   225.9mV    121.8mV    8.158mV
1.717ns   215.9mV    121.8mV    4.289mV
2.323ns   6.832mV    122mV      763.5uV
3.131ns   1.248mV    116.4mV    88.61uV
4.04ns    313.7uV    4.448mV    22.68uV
10ns      11.06uV    4.348uV    25.72uV
[Falling Waveform]
R_fixture=   50.0000
V_fixture=   1.2000
V_fixture_min=   1.1400
V_fixture_max=   1.2600
|time   V(typ)   V(min)   V(max)
0s        1.2V       1.14V      1.26V
1.01ns    1.2V       1.14V      1.266V
1.414ns   1.201V     1.14V      846.9mV
1.818ns   1.217V     1.14V      762.2mV
2.02ns    1.112V     1.14V      749.1mV
2.323ns   937.9mV    1.14V      738.7mV
2.727ns   895.3mV    1.14V      732.5mV
3.434ns   894.1mV    1.156V     729.2mV
4.444ns   894.8mV    983.6mV    728.5mV
10ns      894.1mV    971.5mV    728.4mV
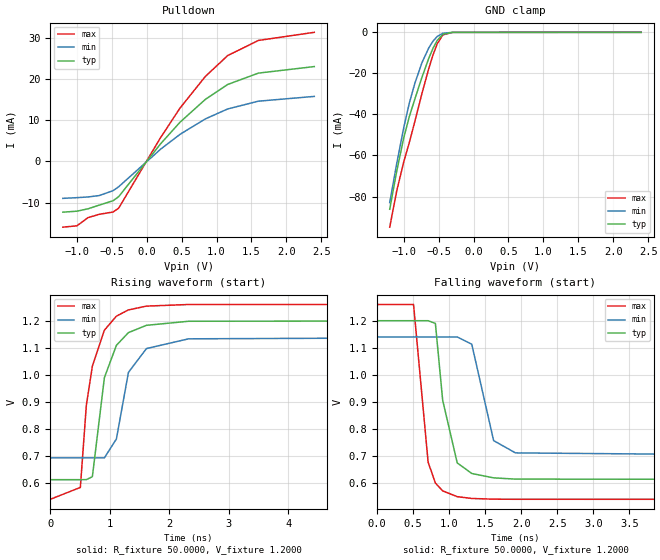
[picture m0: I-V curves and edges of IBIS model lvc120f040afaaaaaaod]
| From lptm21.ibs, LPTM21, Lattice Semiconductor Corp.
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|   Model lvc120f040afaaaaaaod
[Model]   lvc120f040afaaaaaaod
Model_type   I/O_open_drain
Polarity   Non-Inverting
Enable   Active-Low
Vinl =   0.4200V
Vinh =   0.7800V
Vmeas =   0.6000V
Cref =   0.0F
Rref =   1.0000M
Vref =   0.0V
C_comp   4.2000pF   3.8000pF   7.5000pF
[Temperature Range]   25.0000   0.1050k   -40.0000
[Voltage Range]   1.2000V   1.1400V   1.2600V
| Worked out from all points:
|   slope of the pulldown table from 0 to 0.18 V, typ, clamps not added: 46.2 ohm
|   GND clamp passes 1 mA (typ) near -0.44 V on its own axis
|   rising waveform, R_fixture 50.0000, V_fixture 1.2000: 20-80 % time 292ps typ, 283ps min, 269ps max; typ from 0.612 V to 1.2 V
|   falling waveform, R_fixture 50.0000, V_fixture 1.2000: 20-80 % time 179ps typ, 221ps min, 158ps max; typ from 1.2 V to 0.612 V
[Pulldown]
|Voltage   I(typ)   I(min)   I(max)
-1.2V     -12.32mA   -8.965mA   -15.96mA
-1V       -12.08mA   -8.792mA   -15.64mA
-840mV    -11.5mA    -8.628mA   -13.65mA
-680mV    -10.61mA   -8.29mA    -12.84mA
-480mV    -9.536mA   -7.087mA   -12.28mA
-400mV    -8.535mA   -6.131mA   -11.32mA
200mV     4.305mA    2.992mA    5.824mA
480mV     9.58mA     6.621mA    13.03mA
840mV     15.08mA    10.34mA    20.66mA
1.16V     18.71mA    12.76mA    25.73mA
1.6V      21.47mA    14.65mA    29.41mA
2.4V      23.06mA    15.81mA    31.38mA
[GND_clamp]
|Voltage   I(typ)   I(min)   I(max)
-1.2V     -86.19mA   -82.94mA   -94.91mA
-1.1V     -67.71mA   -63.95mA   -77.28mA
-1V       -51.52mA   -46.57mA   -63.21mA
-920mV    -41.11mA   -34.53mA   -53.74mA
-840mV    -32.47mA   -24.81mA   -43.38mA
-740mV    -22.05mA   -14.9mA    -29.96mA
-640mV    -12.58mA   -7.515mA   -17.52mA
-580mV    -7.752mA   -4.29mA    -10.99mA
-520mV    -3.927mA   -2.008mA   -5.609mA
-440mV    -951.3uA   -477uA     -1.256mA
-300mV    -18.83uA   -15.98uA   -16.74uA
2.4V      0A         0A         0A
[Ramp]
| variable   typ   min   max
dV/dt_r  0.3529/0.2894n   0.2684/0.2806n   0.4325/0.2665n
dV/dt_f  0.3529/0.1769n   0.2684/0.2190n   0.4325/0.1560n
R_load = 50.0000
[Rising Waveform]
R_fixture=   50.0000
V_fixture=   1.2000
V_fixture_min=   1.1400
V_fixture_max=   1.2600
|time   V(typ)   V(min)   V(max)
0s        611.9mV    692.6mV    539.2mV
505.1ps   611.9mV    692.6mV    583.3mV
606.1ps   612mV      692.6mV    887.7mV
707.1ps   623mV      692.7mV    1.032V
909.1ps   989.6mV    692.8mV    1.165V
1.111ns   1.109V     762.7mV    1.217V
1.313ns   1.156V     1.009V     1.24V
1.616ns   1.183V     1.097V     1.254V
2.323ns   1.198V     1.133V     1.26V
10ns      1.2V       1.14V      1.26V
[Falling Waveform]
R_fixture=   50.0000
V_fixture=   1.2000
V_fixture_min=   1.1400
V_fixture_max=   1.2600
|time   V(typ)   V(min)   V(max)
0s        1.2V       1.14V      1.26V
505.1ps   1.2V       1.14V      1.26V
707.1ps   1.2V       1.14V      676.8mV
808.1ps   1.19V      1.14V      599.5mV
909.1ps   906mV      1.14V      570.5mV
1.111ns   674mV      1.14V      549.1mV
1.313ns   634.8mV    1.113V     542.4mV
1.616ns   618.6mV    756.5mV    539.8mV
1.919ns   614mV      711mV      539.4mV
10ns      611.9mV    692.6mV    539.2mV
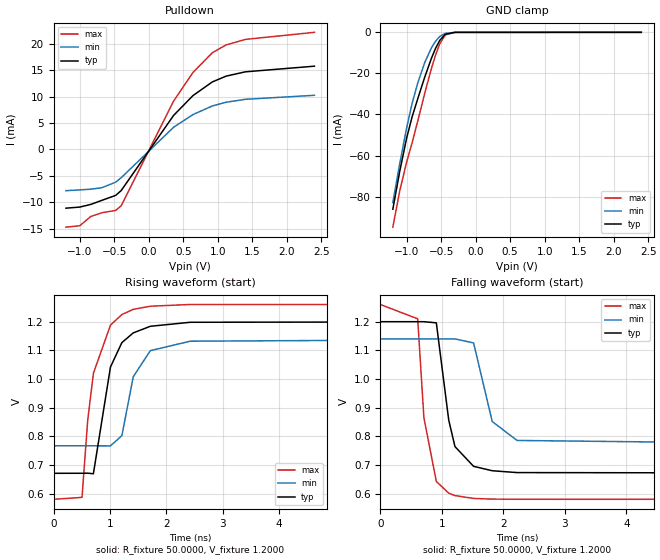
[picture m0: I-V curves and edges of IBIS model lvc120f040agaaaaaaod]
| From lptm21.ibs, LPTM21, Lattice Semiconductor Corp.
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|   Model lvc120f040agaaaaaaod
[Model]   lvc120f040agaaaaaaod
Model_type   I/O_open_drain
Polarity   Non-Inverting
Enable   Active-Low
Vinl =   0.4200V
Vinh =   0.7800V
Vmeas =   0.6000V
Cref =   0.0F
Rref =   1.0000M
Vref =   0.0V
C_comp   4.2000pF   3.8000pF   7.5000pF
[Temperature Range]   25.0000   0.1050k   -40.0000
[Voltage Range]   1.2000V   1.1400V   1.2600V
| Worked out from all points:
|   slope of the pulldown table from 0 to 0.18 V, typ, clamps not added: 52 ohm
|   GND clamp passes 1 mA (typ) near -0.44 V on its own axis
|   rising waveform, R_fixture 50.0000, V_fixture 1.2000: 20-80 % time 288ps typ, 301ps min, 293ps max; typ from 0.671 V to 1.2 V
|   falling waveform, R_fixture 50.0000, V_fixture 1.2000: 20-80 % time 222ps typ, 265ps min, 169ps max; typ from 1.2 V to 0.671 V
[Pulldown]
|Voltage   I(typ)   I(min)   I(max)
-1.2V     -11.13mA   -7.815mA   -14.73mA
-1V       -10.92mA   -7.664mA   -14.46mA
-840mV    -10.42mA   -7.527mA   -12.7mA
-680mV    -9.647mA   -7.252mA   -12mA
-480mV    -8.706mA   -6.207mA   -11.56mA
-400mV    -7.794mA   -5.358mA   -10.68mA
360mV     6.469mA    4.221mA    9.187mA
640mV     10.22mA    6.618mA    14.61mA
920mV     12.81mA    8.253mA    18.34mA
1.12V     13.91mA    8.964mA    19.83mA
1.4V      14.73mA    9.515mA    20.88mA
2.4V      15.8mA     10.28mA    22.22mA
[GND_clamp]
|Voltage   I(typ)   I(min)   I(max)
-1.2V     -86.17mA   -82.93mA   -94.89mA
-1.1V     -67.7mA    -63.94mA   -77.26mA
-1V       -51.5mA    -46.57mA   -63.19mA
-920mV    -41.09mA   -34.53mA   -53.72mA
-840mV    -32.46mA   -24.8mA    -43.36mA
-740mV    -22.04mA   -14.89mA   -29.94mA
-640mV    -12.57mA   -7.509mA   -17.5mA
-580mV    -7.744mA   -4.285mA   -10.97mA
-520mV    -3.92mA    -2.005mA   -5.598mA
-440mV    -948.2uA   -476uA     -1.25mA
-300mV    -18.71uA   -15.93uA   -16.55uA
2.4V      0A         0A         0A
[Ramp]
| variable   typ   min   max
dV/dt_r  0.3172/0.2849n   0.2237/0.2981n   0.4077/0.2902n
dV/dt_f  0.3172/0.2197n   0.2237/0.2626n   0.4077/0.1677n
R_load = 50.0000
[Rising Waveform]
R_fixture=   50.0000
V_fixture=   1.2000
V_fixture_min=   1.1400
V_fixture_max=   1.2600
|time   V(typ)   V(min)   V(max)
0s        671.3mV    767.2mV    580.5mV
505.1ps   671.4mV    767.2mV    587.3mV
606.1ps   671.7mV    767.2mV    855.8mV
707.1ps   669.7mV    767.2mV    1.02V
1.01ns    1.042V     767mV      1.188V
1.212ns   1.127V     802.5mV    1.225V
1.414ns   1.161V     1.008V     1.243V
1.717ns   1.184V     1.099V     1.254V
2.424ns   1.198V     1.132V     1.26V
10ns      1.2V       1.14V      1.26V
[Falling Waveform]
R_fixture=   50.0000
V_fixture=   1.2000
V_fixture_min=   1.1400
V_fixture_max=   1.2600
|time   V(typ)   V(min)   V(max)
0s        1.2V       1.14V      1.26V
606.1ps   1.2V       1.14V      1.21V
707.1ps   1.2V       1.14V      865.1mV
909.1ps   1.196V     1.14V      642.8mV
1.111ns   856.7mV    1.14V      601.8mV
1.212ns   764.4mV    1.14V      593.5mV
1.515ns   695.5mV    1.126V     583.5mV
1.818ns   680.1mV    851.7mV    581.2mV
2.222ns   673.7mV    785.8mV    580.6mV
10ns      671.3mV    767.2mV    580.4mV
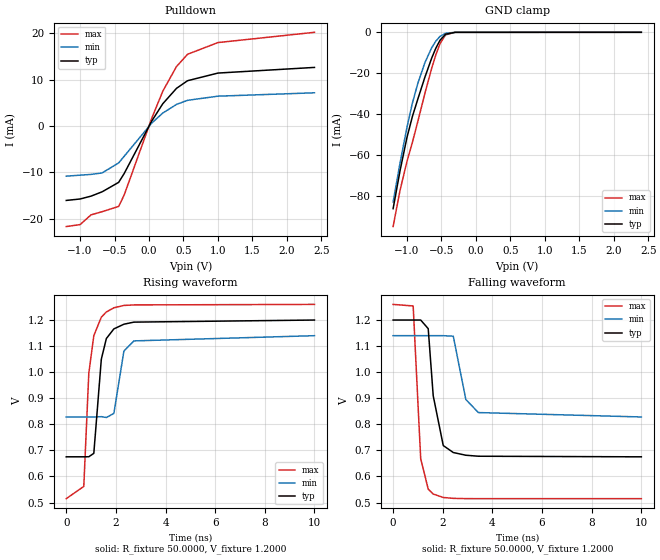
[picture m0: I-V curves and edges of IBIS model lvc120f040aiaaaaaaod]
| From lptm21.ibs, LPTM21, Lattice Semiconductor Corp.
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|   Model lvc120f040aiaaaaaaod
[Model]   lvc120f040aiaaaaaaod
Model_type   I/O_open_drain
Polarity   Non-Inverting
Enable   Active-Low
Vinl =   0.4200V
Vinh =   0.7800V
Vmeas =   0.6000V
Cref =   0.0F
Rref =   1.0000M
Vref =   0.0V
C_comp   4.2000pF   3.8000pF   7.5000pF
[Temperature Range]   25.0000   0.1050k   -40.0000
[Voltage Range]   1.2000V   1.1400V   1.2600V
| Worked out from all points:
|   slope of the pulldown table from 0 to 0.18 V, typ, clamps not added: 40.9 ohm
|   GND clamp passes 1 mA (typ) near -0.44 V on its own axis
|   rising waveform, R_fixture 50.0000, V_fixture 1.2000: 20-80 % time 306ps typ, 321ps min, 306ps max; typ from 0.675 V to 1.2 V
|   falling waveform, R_fixture 50.0000, V_fixture 1.2000: 20-80 % time 307ps typ, 370ps min, 229ps max; typ from 1.2 V to 0.675 V
[Pulldown]
|Voltage   I(typ)   I(min)   I(max)
-1.2V     -16.05mA   -10.81mA   -21.69mA
-1V       -15.74mA   -10.6mA    -21.27mA
-840mV    -15.12mA   -10.43mA   -19.16mA
-680mV    -14.19mA   -10.12mA   -18.48mA
-440mV    -12.15mA   -7.957mA   -17.34mA
-360mV    -10.25mA   -6.525mA   -14.9mA
40mV      1.083mA    639.4uA    1.672mA
200mV     4.818mA    2.81mA     7.514mA
400mV     8.156mA    4.68mA     12.87mA
560mV     9.792mA    5.559mA    15.5mA
1V        11.44mA    6.452mA    18.02mA
2.4V      12.66mA    7.182mA    20.24mA
[GND_clamp]
|Voltage   I(typ)   I(min)   I(max)
-1.2V     -86.15mA   -82.88mA   -94.87mA
-1.1V     -67.68mA   -63.91mA   -77.24mA
-1V       -51.49mA   -46.55mA   -63.18mA
-920mV    -41.08mA   -34.52mA   -53.71mA
-840mV    -32.45mA   -24.79mA   -43.35mA
-740mV    -22.03mA   -14.89mA   -29.94mA
-640mV    -12.56mA   -7.505mA   -17.5mA
-580mV    -7.739mA   -4.282mA   -10.97mA
-520mV    -3.916mA   -2.003mA   -5.593mA
-440mV    -946.1uA   -475uA     -1.247mA
-300mV    -18.63uA   -15.88uA   -16.42uA
2.4V      0A         0A         0A
[Ramp]
| variable   typ   min   max
dV/dt_r  0.3148/0.3028n   0.1871/0.3178n   0.4471/0.3030n
dV/dt_f  0.3148/0.3037n   0.1871/0.3661n   0.4471/0.2267n
R_load = 50.0000
[Rising Waveform]
R_fixture=   50.0000
V_fixture=   1.2000
V_fixture_min=   1.1400
V_fixture_max=   1.2600
|time   V(typ)   V(min)   V(max)
0s        675.3mV    828.2mV    514.8mV
707.1ps   675.4mV    828.2mV    561.8mV
909.1ps   675.6mV    828.2mV    995.7mV
1.111ns   688.6mV    828.1mV    1.14V
1.414ns   1.05V      829.4mV    1.211V
1.616ns   1.129V     826.2mV    1.231V
1.919ns   1.166V     841.7mV    1.247V
2.323ns   1.184V     1.081V     1.256V
2.727ns   1.192V     1.12V      1.258V
10ns      1.2V       1.14V      1.26V
[Falling Waveform]
R_fixture=   50.0000
V_fixture=   1.2000
V_fixture_min=   1.1400
V_fixture_max=   1.2600
|time   V(typ)   V(min)   V(max)
0s        1.2V       1.14V      1.26V
808.1ps   1.2V       1.14V      1.254V
1.111ns   1.2V       1.14V      668.5mV
1.414ns   1.167V     1.14V      551.4mV
1.616ns   909.2mV    1.14V      532.6mV
2.02ns    718.6mV    1.14V      519.4mV
2.424ns   691.8mV    1.138V     516mV
2.929ns   681.4mV    895.5mV    515mV
3.434ns   677.6mV    845.1mV    514.8mV
10ns      675.3mV    828.2mV    514.8mV
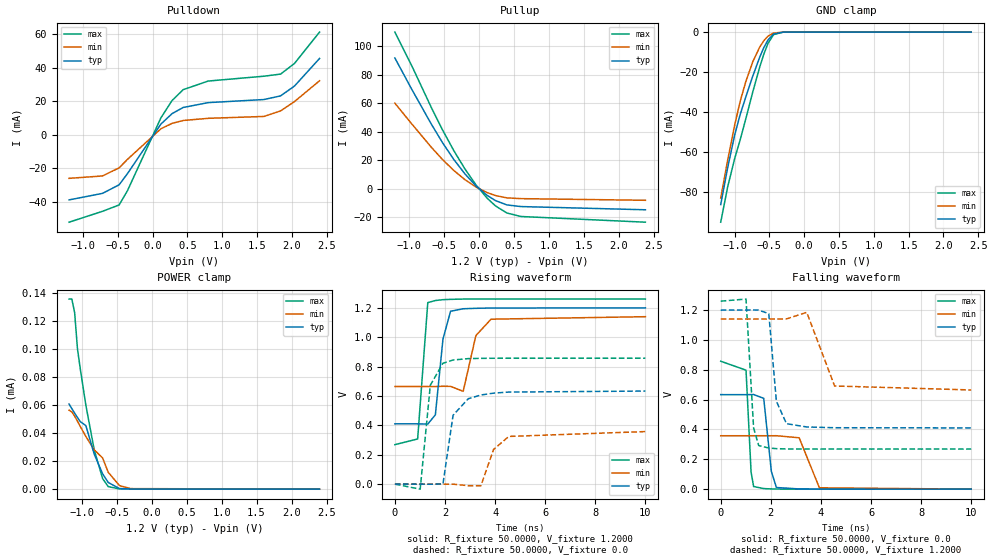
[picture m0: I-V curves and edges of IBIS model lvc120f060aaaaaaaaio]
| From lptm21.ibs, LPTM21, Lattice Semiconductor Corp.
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|   Model lvc120f060aaaaaaaaio
[Model]   lvc120f060aaaaaaaaio
Model_type   I/O
Polarity   Non-Inverting
Enable   Active-Low
Vinl =   0.4200V
Vinh =   0.7800V
Vmeas =   0.6000V
Cref =   0.0F
Rref =   1.0000M
Vref =   0.0V
C_comp   3.0000pF   2.7000pF   3.3000pF
[Temperature Range]   25.0000   0.1050k   -40.0000
[Voltage Range]   1.2000V   1.1400V   1.2600V
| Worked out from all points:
|   slope of the pulldown table from 0 to 0.18 V, typ, clamps not added: 20 ohm
|   slope of the pullup table from 0 to 0.18 V, typ, clamps not added: 26.6 ohm
|   GND clamp passes 1 mA (typ) near -0.44 V on its own axis
|   rising waveform, R_fixture 50.0000, V_fixture 1.2000: 20-80 % time 305ps typ, 426ps min, 204ps max; typ from 0.41 V to 1.2 V
|   rising waveform, R_fixture 50.0000, V_fixture 0.0: 20-80 % time 415ps typ, 518ps min, 281ps max; typ from 0 V to 0.634 V
|   falling waveform, R_fixture 50.0000, V_fixture 0.0: 20-80 % time 210ps typ, 375ps min, 152ps max; typ from 0.634 V to 0 V
|   falling waveform, R_fixture 50.0000, V_fixture 1.2000: 20-80 % time 264ps typ, 418ps min, 166ps max; typ from 1.2 V to 0.41 V
[Pulldown]
|Voltage   I(typ)   I(min)   I(max)
-1.2V     -38.96mA   -26.08mA   -52.29mA
-720mV    -35.07mA   -24.65mA   -45.8mA
-480mV    -29.93mA   -19.79mA   -41.97mA
-360mV    -23.22mA   -14.7mA    -33.4mA
120mV     6.376mA    3.552mA    10.08mA
280mV     12.61mA    6.797mA    20.43mA
440mV     16.3mA     8.521mA    26.95mA
800mV     19.2mA     9.815mA    32.1mA
1.6V      21.04mA    10.93mA    34.99mA
1.84V     23.22mA    14.24mA    36.25mA
2.04V     29.13mA    19.83mA    42.64mA
2.4V      45.61mA    32.28mA    61.37mA
[Pullup]
|Voltage   I(typ)   I(min)   I(max)
-1.2V     91.7mA     59.97mA    109.9mA
-960mV    69.84mA    45.51mA    86.39mA
-680mV    45.34mA    29.11mA    57.02mA
-520mV    32.33mA    20.46mA    41.29mA
-360mV    20.61mA    12.83mA    26.86mA
-200mV    10.41mA    6.349mA    13.9mA
-40mV     1.856mA    1.102mA    2.554mA
120mV     -4.812mA   -2.807mA   -6.806mA
240mV     -8.453mA   -4.875mA   -12.21mA
400mV     -11.43mA   -6.477mA   -17.09mA
600mV     -12.59mA   -7.023mA   -19.56mA
2.38V     -14.84mA   -8.183mA   -23.56mA
[GND_clamp]
|Voltage   I(typ)   I(min)   I(max)
-1.2V     -86.07mA   -82.81mA   -94.84mA
-1.1V     -67.62mA   -63.85mA   -77.22mA
-1V       -51.44mA   -46.49mA   -63.16mA
-920mV    -41.05mA   -34.47mA   -53.69mA
-840mV    -32.43mA   -24.76mA   -43.33mA
-740mV    -22.02mA   -14.88mA   -29.93mA
-640mV    -12.55mA   -7.499mA   -17.49mA
-580mV    -7.732mA   -4.278mA   -10.96mA
-520mV    -3.911mA   -2mA       -5.586mA
-440mV    -943.9uA   -474.2uA   -1.243mA
-300mV    -18.55uA   -15.85uA   -16.32uA
2.4V      0A         0A         0A
[POWER_clamp]
|Voltage   I(typ)   I(min)   I(max)
-1.18V    60.64uA    56.26uA    135.4uA
-1.14V    57.31uA    54.99uA    135.4uA
-1.1V     54.11uA    52uA       125.7uA
-1.06V    51.03uA    48.39uA    100.1uA
-1.02V    48.09uA    44.69uA    85.81uA
-940mV    45.28uA    37.56uA    59.84uA
-820mV    24.89uA    28uA       27.91uA
-700mV    10.88uA    22.15uA    7.487uA
-620mV    4.733uA    12.01uA    1.786uA
-460mV    415.9nA    2.532uA    159.1nA
-300mV    127.7nA    366.9nA    159.1nA
2.4V      -20.81nA   -18.5nA    -25.04nA
[Ramp]
| variable   typ   min   max
dV/dt_r  0.3358/0.4103n   0.2147/0.5128n   0.5144/0.2778n
dV/dt_f  0.4737/0.2611n   0.2851/0.4142n   0.5948/0.1638n
R_load = 50.0000
[Rising Waveform]
R_fixture=   50.0000
V_fixture=   1.2000
V_fixture_min=   1.1400
V_fixture_max=   1.2600
|time   V(typ)   V(min)   V(max)
0s        410.5mV    664.7mV    268.8mV
909.1ps   410.4mV    664.7mV    307.5mV
1.313ns   408.9mV    664.6mV    1.236V
1.616ns   471.8mV    664.5mV    1.25V
1.919ns   987.2mV    666.3mV    1.256V
2.222ns   1.177V     665.6mV    1.258V
2.727ns   1.194V     631.8mV    1.26V
3.232ns   1.197V     1.011V     1.26V
3.838ns   1.199V     1.123V     1.26V
10ns      1.2V       1.14V      1.26V
[Rising Waveform]
R_fixture=   50.0000
V_fixture=   0.0
V_fixture_min=   0.0
V_fixture_max=   0.0
|time   V(typ)   V(min)   V(max)
0s        231.9nV    390.7nV    158.8nV
1.01ns    24.41uV    189.3nV    -34.26mV
1.414ns   -738.6uV   4.55uV     673.1mV
1.919ns   1.27mV     -62.63uV   823mV
2.323ns   469mV      -222.1uV   845.1mV
2.929ns   581.4mV    -10.49mV   854.5mV
3.434ns   606.9mV    -10.68mV   856.4mV
3.939ns   619.5mV    236mV      857mV
4.546ns   626.9mV    324.8mV    857.2mV
10ns      633.6mV    357.8mV    857.3mV
[Falling Waveform]
R_fixture=   50.0000
V_fixture=   0.0
V_fixture_min=   0.0
V_fixture_max=   0.0
|time   V(typ)   V(min)   V(max)
0s        633.6mV    358mV      857.3mV
1.01ns    633.6mV    358mV      797.5mV
1.212ns   633.7mV    358mV      115.8mV
1.313ns   634.3mV    358mV      17.73mV
1.717ns   608.8mV    358.1mV    3.975mV
2.02ns    120.1mV    358mV      1.603mV
2.222ns   11.17mV    358.2mV    882.6uV
3.131ns   1.497mV    344.3mV    61.03uV
3.939ns   383.8uV    9.171mV    6.77uV
10ns      -593.6nV   -12.19uV   21.12uV
[Falling Waveform]
R_fixture=   50.0000
V_fixture=   1.2000
V_fixture_min=   1.1400
V_fixture_max=   1.2600
|time   V(typ)   V(min)   V(max)
0s        1.2V       1.14V      1.26V
1.01ns    1.2V       1.14V      1.274V
1.313ns   1.201V     1.14V      410.1mV
1.515ns   1.2V       1.14V      292.5mV
1.919ns   1.176V     1.14V      275.7mV
2.222ns   589.1mV    1.14V      271.6mV
2.626ns   438.8mV    1.141V     269.6mV
3.434ns   416.9mV    1.185V     268.9mV
4.546ns   411.7mV    691.5mV    268.8mV
10ns      410.5mV    664.8mV    268.8mV
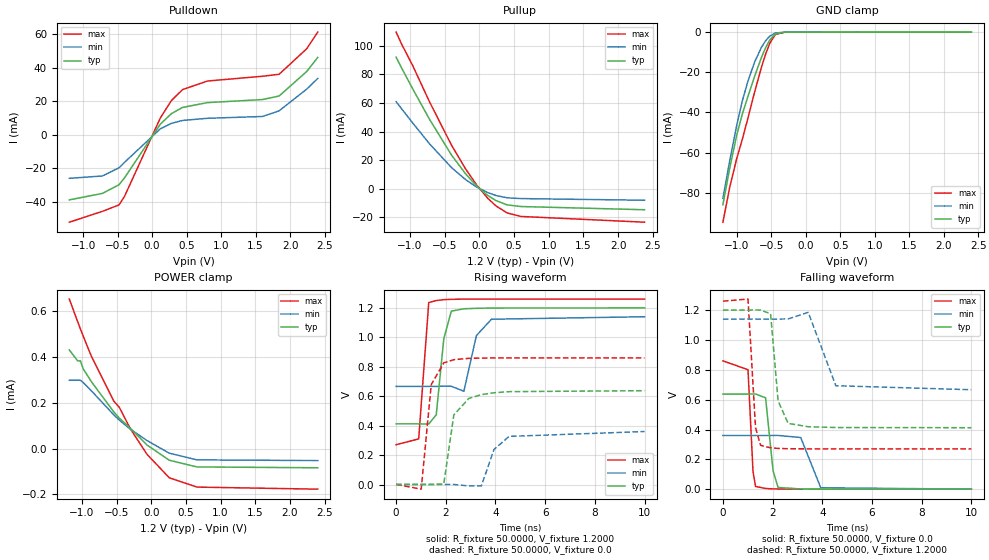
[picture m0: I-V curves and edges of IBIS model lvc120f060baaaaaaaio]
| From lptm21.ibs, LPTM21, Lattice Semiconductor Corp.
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|   Model lvc120f060baaaaaaaio
[Model]   lvc120f060baaaaaaaio
Model_type   I/O
Polarity   Non-Inverting
Enable   Active-Low
Vinl =   0.4200V
Vinh =   0.7800V
Vmeas =   0.6000V
Cref =   0.0F
Rref =   1.0000M
Vref =   0.0V
C_comp   3.0000pF   2.7000pF   3.3000pF
[Temperature Range]   25.0000   0.1050k   -40.0000
[Voltage Range]   1.2000V   1.1400V   1.2600V
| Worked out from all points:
|   slope of the pulldown table from 0 to 0.18 V, typ, clamps not added: 20 ohm
|   slope of the pullup table from 0 to 0.18 V, typ, clamps not added: 26.6 ohm
|   GND clamp passes 1 mA (typ) near -0.44 V on its own axis
|   rising waveform, R_fixture 50.0000, V_fixture 1.2000: 20-80 % time 303ps typ, 423ps min, 204ps max; typ from 0.412 V to 1.2 V
|   rising waveform, R_fixture 50.0000, V_fixture 0.0: 20-80 % time 415ps typ, 520ps min, 277ps max; typ from 0.001 V to 0.638 V
|   falling waveform, R_fixture 50.0000, V_fixture 0.0: 20-80 % time 210ps typ, 377ps min, 152ps max; typ from 0.638 V to 0.001 V
|   falling waveform, R_fixture 50.0000, V_fixture 1.2000: 20-80 % time 265ps typ, 418ps min, 166ps max; typ from 1.2 V to 0.412 V
[Pulldown]
|Voltage   I(typ)   I(min)   I(max)
-1.2V     -38.96mA   -26.08mA   -52.3mA
-720mV    -35.08mA   -24.66mA   -45.82mA
-480mV    -29.93mA   -19.79mA   -41.98mA
-400mV    -25.78mA   -16.51mA   -36.85mA
120mV     6.384mA    3.555mA    10.11mA
280mV     12.61mA    6.799mA    20.45mA
440mV     16.3mA     8.522mA    26.96mA
800mV     19.19mA    9.813mA    32.09mA
1.6V      21.03mA    10.91mA    34.96mA
1.84V     23.14mA    14.28mA    36.13mA
2.24V     37.79mA    27.26mA    51.4mA
2.4V      46.2mA     33.62mA    61.36mA
[Pullup]
|Voltage   I(typ)   I(min)   I(max)
-1.2V     92.06mA    60.98mA    109.7mA
-1.12V    84.48mA    55.88mA    101.2mA
-960mV    69.83mA    45.93mA    86.12mA
-720mV    48.68mA    31.45mA    60.96mA
-400mV    23.37mA    14.62mA    30.27mA
-200mV    10.4mA     6.343mA    13.88mA
-40mV     1.854mA    1.101mA    2.55mA
120mV     -4.808mA   -2.805mA   -6.796mA
240mV     -8.448mA   -4.873mA   -12.19mA
400mV     -11.43mA   -6.476mA   -17.07mA
600mV     -12.59mA   -7.023mA   -19.55mA
2.38V     -14.84mA   -8.183mA   -23.57mA
[GND_clamp]
|Voltage   I(typ)   I(min)   I(max)
-1.2V     -86.02mA   -82.79mA   -94.71mA
-1.1V     -67.56mA   -63.82mA   -77.09mA
-1V       -51.39mA   -46.46mA   -63.03mA
-920mV    -41mA      -34.44mA   -53.57mA
-840mV    -32.38mA   -24.74mA   -43.21mA
-740mV    -21.97mA   -14.85mA   -29.81mA
-640mV    -12.51mA   -7.478mA   -17.38mA
-580mV    -7.694mA   -4.26mA    -10.86mA
-520mV    -3.881mA   -1.989mA   -5.509mA
-440mV    -930.4uA   -470.4uA   -1.205mA
-300mV    -18.88uA   -16.34uA   -15.3uA
2.4V      0A         0A         0A
[POWER_clamp]
|Voltage   I(typ)   I(min)   I(max)
-1.18V    428.9uA    296.9uA    650.2uA
-1.06V    381.4uA    296.9uA    551.8uA
-1.02V    381.4uA    296.9uA    520uA
-980mV    346.6uA    287.3uA    488.9uA
-860mV    289.9uA    250.4uA    400uA
-540mV    159.6uA    146.6uA    206.4uA
-460mV    132.4uA    123.9uA    179.3uA
-300mV    88.01uA    83.86uA    85.61uA
-60mV     15.09uA    34.5uA     -25.38uA
260mV     -50.94uA   -20.29uA   -127.3uA
660mV     -80.25uA   -49.46uA   -167.9uA
2.4V      -83.82uA   -52.45uA   -176.9uA
[Ramp]
| variable   typ   min   max
dV/dt_r  0.3374/0.4108n   0.2156/0.5142n   0.5153/0.2738n
dV/dt_f  0.4725/0.2619n   0.2839/0.4142n   0.5935/0.1640n
R_load = 50.0000
[Rising Waveform]
R_fixture=   50.0000
V_fixture=   1.2000
V_fixture_min=   1.1400
V_fixture_max=   1.2600
|time   V(typ)   V(min)   V(max)
0s        412.5mV    666.8mV    270.8mV
909.1ps   412.4mV    666.8mV    310.1mV
1.313ns   410.9mV    666.7mV    1.236V
1.616ns   474.2mV    666.6mV    1.25V
1.919ns   990.2mV    668.4mV    1.256V
2.222ns   1.178V     667.7mV    1.258V
2.727ns   1.194V     633.9mV    1.26V
3.232ns   1.197V     1.012V     1.26V
3.838ns   1.199V     1.123V     1.26V
10ns      1.2V       1.14V      1.26V
[Rising Waveform]
R_fixture=   50.0000
V_fixture=   0.0
V_fixture_min=   0.0
V_fixture_max=   0.0
|time   V(typ)   V(min)   V(max)
0s        934.8uV    915.3uV    1.287mV
1.01ns    959.2uV    915.1uV    -31.21mV
1.414ns   177.6uV    919.4uV    679.1mV
1.919ns   4.394mV    854.2uV    826.7mV
2.323ns   472.8mV    688.2uV    848.3mV
2.929ns   585.4mV    -9.374mV   857.4mV
3.434ns   610.9mV    -8.295mV   859.3mV
3.939ns   623.6mV    238.3mV    859.9mV
4.546ns   631.1mV    327.1mV    860.1mV
10ns      637.7mV    360.3mV    860.1mV
[Falling Waveform]
R_fixture=   50.0000
V_fixture=   0.0
V_fixture_min=   0.0
V_fixture_max=   0.0
|time   V(typ)   V(min)   V(max)
0s        637.7mV    360.5mV    860.1mV
1.01ns    637.7mV    360.5mV    800.9mV
1.212ns   637.9mV    360.5mV    118.7mV
1.313ns   638.3mV    360.5mV    19.43mV
1.717ns   613mV      360.5mV    5.365mV
2.02ns    122.9mV    360.5mV    2.869mV
2.222ns   12.3mV     360.7mV    2.14mV
3.131ns   2.458mV    346.8mV    1.383mV
3.939ns   1.324mV    10.32mV    1.326mV
10ns      933.9uV    915uV      1.319mV
[Falling Waveform]
R_fixture=   50.0000
V_fixture=   1.2000
V_fixture_min=   1.1400
V_fixture_max=   1.2600
|time   V(typ)   V(min)   V(max)
0s        1.2V       1.14V      1.26V
1.01ns    1.2V       1.14V      1.274V
1.313ns   1.201V     1.14V      412.7mV
1.515ns   1.2V       1.14V      294.8mV
1.919ns   1.176V     1.14V      277.9mV
2.222ns   591.2mV    1.14V      273.8mV
2.626ns   441.2mV    1.141V     271.7mV
3.434ns   419mV      1.185V     270.9mV
4.546ns   413.7mV    693.5mV    270.8mV
10ns      412.5mV    666.9mV    270.8mV
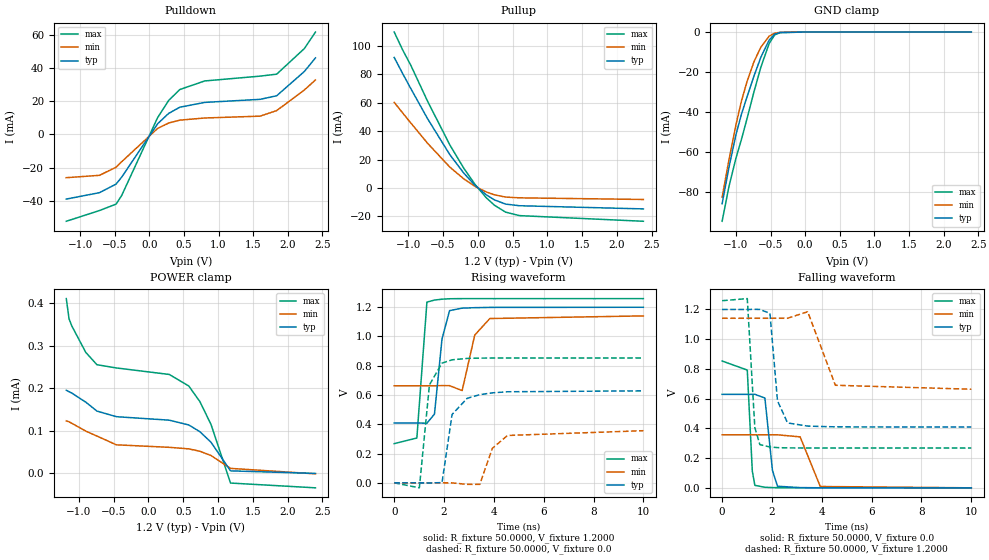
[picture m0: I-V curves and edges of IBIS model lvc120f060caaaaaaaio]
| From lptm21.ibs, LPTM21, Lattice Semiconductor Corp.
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|   Model lvc120f060caaaaaaaio
[Model]   lvc120f060caaaaaaaio
Model_type   I/O
Polarity   Non-Inverting
Enable   Active-Low
Vinl =   0.4200V
Vinh =   0.7800V
Vmeas =   0.6000V
Cref =   0.0F
Rref =   1.0000M
Vref =   0.0V
C_comp   3.0000pF   2.7000pF   3.3000pF
[Temperature Range]   25.0000   0.1050k   -40.0000
[Voltage Range]   1.2000V   1.1400V   1.2600V
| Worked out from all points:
|   slope of the pulldown table from 0 to 0.18 V, typ, clamps not added: 20 ohm
|   slope of the pullup table from 0 to 0.18 V, typ, clamps not added: 26.6 ohm
|   GND clamp passes 1 mA (typ) near -0.44 V on its own axis
|   rising waveform, R_fixture 50.0000, V_fixture 1.2000: 20-80 % time 307ps typ, 433ps min, 204ps max; typ from 0.408 V to 1.2 V
|   rising waveform, R_fixture 50.0000, V_fixture 0.0: 20-80 % time 411ps typ, 516ps min, 282ps max; typ from 0 V to 0.628 V
|   falling waveform, R_fixture 50.0000, V_fixture 0.0: 20-80 % time 210ps typ, 374ps min, 152ps max; typ from 0.628 V to 0 V
|   falling waveform, R_fixture 50.0000, V_fixture 1.2000: 20-80 % time 262ps typ, 418ps min, 165ps max; typ from 1.2 V to 0.408 V
[Pulldown]
|Voltage   I(typ)   I(min)   I(max)
-1.2V     -38.95mA   -26.08mA   -52.29mA
-720mV    -35.08mA   -24.66mA   -45.82mA
-480mV    -29.92mA   -19.78mA   -41.97mA
-400mV    -25.77mA   -16.5mA    -36.83mA
120mV     6.37mA     3.55mA     10.06mA
280mV     12.6mA     6.795mA    20.4mA
440mV     16.29mA    8.519mA    26.93mA
800mV     19.19mA    9.814mA    32.09mA
1.6V      21.03mA    10.92mA    34.99mA
1.84V     23.18mA    14.27mA    36.17mA
2.24V     37.81mA    26.68mA    51.59mA
2.4V      45.96mA    32.69mA    61.5mA
[Pullup]
|Voltage   I(typ)   I(min)   I(max)
-1.2V     91.97mA    60.32mA    109.9mA
-1.08V    80.77mA    52.94mA    97.45mA
-960mV    69.89mA    45.7mA     86.3mA
-720mV    48.74mA    31.44mA    61.05mA
-400mV    23.37mA    14.62mA    30.24mA
-200mV    10.4mA     6.344mA    13.86mA
-40mV     1.843mA    1.099mA    2.523mA
120mV     -4.821mA   -2.809mA   -6.83mA
240mV     -8.459mA   -4.877mA   -12.23mA
400mV     -11.43mA   -6.478mA   -17.1mA
600mV     -12.59mA   -7.023mA   -19.56mA
2.38V     -14.83mA   -8.18mA    -23.55mA
[GND_clamp]
|Voltage   I(typ)   I(min)   I(max)
-1.2V     -86.12mA   -82.85mA   -94.91mA
-1.1V     -67.67mA   -63.89mA   -77.29mA
-1V       -51.5mA    -46.53mA   -63.23mA
-920mV    -41.11mA   -34.51mA   -53.77mA
-840mV    -32.49mA   -24.81mA   -43.41mA
-740mV    -22.08mA   -14.92mA   -30.01mA
-640mV    -12.62mA   -7.552mA   -17.58mA
-520mV    -4.002mA   -2.066mA   -5.717mA
-440mV    -1.052mA   -544.2uA   -1.412mA
-360mV    -224.4uA   -137uA     -297.4uA
0V        0A         0A         0A
2.4V      0A         0A         0A
[POWER_clamp]
|Voltage   I(typ)   I(min)   I(max)
-1.18V    195.7uA    123.7uA    411.4uA
-1.14V    192.3uA    121.4uA    363.5uA
-1.1V     189uA      117.9uA    346.9uA
-900mV    167.7uA    99.59uA    284.8uA
-740mV    146.7uA    87.99uA    255.9uA
-460mV    133.5uA    67.27uA    248.2uA
300mV     125.3uA    61.39uA    232.9uA
580mV     114uA      57.74uA    205.7uA
740mV     98.07uA    52.14uA    168.9uA
900mV     73.23uA    42.07uA    115uA
1.18V     6.005uA    11.83uA    -22.68uA
2.4V      -20.2nA    -1.007uA   -33.94uA
[Ramp]
| variable   typ   min   max
dV/dt_r  0.3327/0.4071n   0.2134/0.5106n   0.5111/0.2789n
dV/dt_f  0.4738/0.2595n   0.2858/0.4140n   0.5940/0.1632n
R_load = 50.0000
[Rising Waveform]
R_fixture=   50.0000
V_fixture=   1.2000
V_fixture_min=   1.1400
V_fixture_max=   1.2600
|time   V(typ)   V(min)   V(max)
0s        408.3mV    662.2mV    267.4mV
909.1ps   408.2mV    662.2mV    305.9mV
1.313ns   406.7mV    662.1mV    1.233V
1.616ns   469.3mV    662mV      1.247V
1.919ns   982.2mV    663.8mV    1.253V
2.222ns   1.175V     663.1mV    1.256V
2.727ns   1.192V     629.4mV    1.257V
3.232ns   1.195V     1.008V     1.257V
3.838ns   1.197V     1.121V     1.257V
10ns      1.198V     1.139V     1.257V
[Rising Waveform]
R_fixture=   50.0000
V_fixture=   0.0
V_fixture_min=   0.0
V_fixture_max=   0.0
|time   V(typ)   V(min)   V(max)
0s        224.5nV    383.5nV    150.3nV
1.01ns    24.35uV    182.3nV    -34.08mV
1.414ns   -735.7uV   4.538uV    668.5mV
1.919ns   1.542mV    -62.58uV   817mV
2.323ns   466.5mV    -221uV     839.4mV
2.929ns   576.8mV    -10.47mV   849mV
3.434ns   601.7mV    -10.53mV   851mV
3.939ns   614mV      235.3mV    851.6mV
4.546ns   621.4mV    323.2mV    851.8mV
10ns      627.7mV    355.7mV    851.8mV
[Falling Waveform]
R_fixture=   50.0000
V_fixture=   0.0
V_fixture_min=   0.0
V_fixture_max=   0.0
|time   V(typ)   V(min)   V(max)
0s        627.8mV    356mV      851.9mV
1.01ns    627.8mV    356mV      791mV
1.212ns   627.9mV    356mV      112.3mV
1.313ns   628.5mV    356mV      16.66mV
1.717ns   603mV      356mV      3.779mV
2.02ns    117.2mV    355.9mV    1.59mV
2.222ns   10.79mV    356.1mV    892.9uV
3.131ns   1.461mV    342.3mV    22.75uV
3.939ns   375uV      8.969mV    -26.18uV
10ns      12.94uV    10.96uV    22.43uV
[Falling Waveform]
R_fixture=   50.0000
V_fixture=   1.2000
V_fixture_min=   1.1400
V_fixture_max=   1.2600
|time   V(typ)   V(min)   V(max)
0s        1.198V     1.139V     1.257V
1.01ns    1.198V     1.139V     1.271V
1.313ns   1.199V     1.139V     405.1mV
1.515ns   1.198V     1.139V     290.4mV
1.919ns   1.172V     1.139V     274.2mV
2.222ns   584.7mV    1.139V     270.2mV
2.626ns   436mV      1.139V     268.3mV
3.434ns   414.6mV    1.183V     267.5mV
4.546ns   409.5mV    688.9mV    267.4mV
10ns      408.3mV    662.3mV    267.4mV
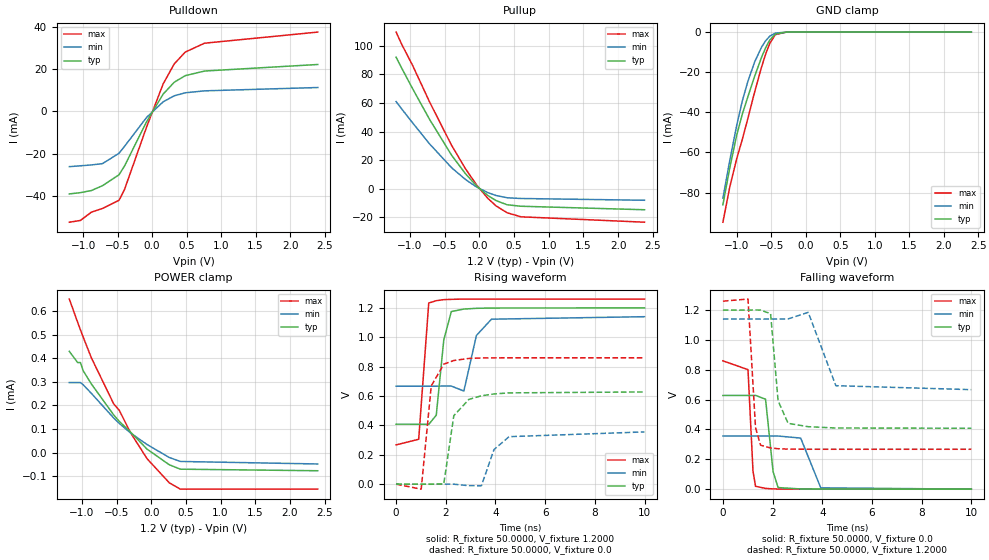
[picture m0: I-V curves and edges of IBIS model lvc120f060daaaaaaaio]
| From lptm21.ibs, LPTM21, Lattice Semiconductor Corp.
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|   Model lvc120f060daaaaaaaio
[Model]   lvc120f060daaaaaaaio
Model_type   I/O
Polarity   Non-Inverting
Enable   Active-Low
Vinl =   0.4200V
Vinh =   0.7800V
Vmeas =   0.6000V
Cref =   0.0F
Rref =   1.0000M
Vref =   0.0V
C_comp   3.0000pF   2.7000pF   3.3000pF
[Temperature Range]   25.0000   0.1050k   -40.0000
[Voltage Range]   1.2000V   1.1400V   1.2600V
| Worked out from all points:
|   slope of the pulldown table from 0 to 0.18 V, typ, clamps not added: 20 ohm
|   slope of the pullup table from 0 to 0.18 V, typ, clamps not added: 26.8 ohm
|   GND clamp passes 1 mA (typ) near -0.44 V on its own axis
|   rising waveform, R_fixture 50.0000, V_fixture 1.2000: 20-80 % time 308ps typ, 423ps min, 205ps max; typ from 0.408 V to 1.2 V
|   rising waveform, R_fixture 50.0000, V_fixture 0.0: 20-80 % time 411ps typ, 516ps min, 292ps max; typ from 0 V to 0.628 V
|   falling waveform, R_fixture 50.0000, V_fixture 0.0: 20-80 % time 210ps typ, 374ps min, 152ps max; typ from 0.628 V to 0 V
|   falling waveform, R_fixture 50.0000, V_fixture 1.2000: 20-80 % time 268ps typ, 418ps min, 167ps max; typ from 1.2 V to 0.408 V
[Pulldown]
|Voltage   I(typ)   I(min)   I(max)
-1.2V     -38.95mA   -26.08mA   -52.29mA
-1.04V    -38.35mA   -25.68mA   -51.47mA
-880mV    -37.35mA   -25.27mA   -47.56mA
-720mV    -35.08mA   -24.66mA   -45.82mA
-480mV    -29.92mA   -19.78mA   -41.97mA
-400mV    -25.77mA   -16.5mA    -36.83mA
-80mV     -4.846mA   -2.846mA   -7.361mA
160mV     8.172mA    4.519mA    12.99mA
320mV     13.75mA    7.353mA    22.4mA
480mV     16.87mA    8.775mA    27.99mA
760mV     19.04mA    9.693mA    32.18mA
2.4V      22.13mA    11.26mA    37.42mA
[Pullup]
|Voltage   I(typ)   I(min)   I(max)
-1.2V     92.06mA    60.98mA    109.7mA
-1.12V    84.48mA    55.88mA    101.2mA
-960mV    69.83mA    45.93mA    86.12mA
-720mV    48.68mA    31.45mA    60.96mA
-400mV    23.37mA    14.62mA    30.27mA
-200mV    10.4mA     6.343mA    13.88mA
-40mV     1.854mA    1.101mA    2.55mA
120mV     -4.782mA   -2.789mA   -6.757mA
240mV     -8.398mA   -4.843mA   -12.12mA
400mV     -11.35mA   -6.433mA   -16.96mA
600mV     -12.37mA   -6.936mA   -19.78mA
2.38V     -14.83mA   -8.18mA    -23.55mA
[GND_clamp]
|Voltage   I(typ)   I(min)   I(max)
-1.2V     -86.05mA   -82.8mA    -94.75mA
-1.1V     -67.59mA   -63.84mA   -77.13mA
-1V       -51.42mA   -46.49mA   -63.08mA
-920mV    -41.03mA   -34.46mA   -53.61mA
-840mV    -32.42mA   -24.76mA   -43.26mA
-740mV    -22.01mA   -14.88mA   -29.85mA
-640mV    -12.55mA   -7.505mA   -17.43mA
-580mV    -7.735mA   -4.289mA   -10.91mA
-520mV    -3.926mA   -2.018mA   -5.563mA
-440mV    -975.9uA   -496.4uA   -1.258mA
-280mV    -21.15uA   -10.37uA   -5.4uA
2.4V      0A         0A         0A
[POWER_clamp]
|Voltage   I(typ)   I(min)   I(max)
-1.18V    428.9uA    296.9uA    650.2uA
-1.06V    381.4uA    296.9uA    551.8uA
-1.02V    381.4uA    296.9uA    520uA
-980mV    346.6uA    287.3uA    488.9uA
-860mV    289.9uA    250.4uA    400uA
-540mV    159.6uA    146.6uA    206.4uA
-460mV    132.4uA    123.9uA    179.3uA
-300mV    88.01uA    83.86uA    85.61uA
-60mV     15.09uA    34.5uA     -25.38uA
260mV     -50.94uA   -20.29uA   -127.3uA
420mV     -69.79uA   -37.12uA   -154.4uA
2.4V      -76.46uA   -47.78uA   -154.4uA
[Ramp]
| variable   typ   min   max
dV/dt_r  0.3327/0.4071n   0.2134/0.5106n   0.5161/0.2890n
dV/dt_f  0.4750/0.2658n   0.2839/0.4142n   0.5955/0.1648n
R_load = 50.0000
[Rising Waveform]
R_fixture=   50.0000
V_fixture=   1.2000
V_fixture_min=   1.1400
V_fixture_max=   1.2600
|time   V(typ)   V(min)   V(max)
0s        408.3mV    666.8mV    267.4mV
909.1ps   408.2mV    666.8mV    305.9mV
1.313ns   406.7mV    666.7mV    1.233V
1.616ns   469.3mV    666.6mV    1.249V
1.919ns   982.2mV    668.4mV    1.256V
2.222ns   1.175V     667.7mV    1.258V
2.727ns   1.192V     633.9mV    1.26V
3.232ns   1.197V     1.012V     1.26V
3.838ns   1.199V     1.123V     1.26V
10ns      1.2V       1.14V      1.26V
[Rising Waveform]
R_fixture=   50.0000
V_fixture=   0.0
V_fixture_min=   0.0
V_fixture_max=   0.0
|time   V(typ)   V(min)   V(max)
0s        224.5nV    383.5nV    150.3nV
1.01ns    24.35uV    182.3nV    -34.08mV
1.414ns   -735.7uV   4.538uV    668.5mV
1.919ns   1.542mV    -62.58uV   817mV
2.323ns   466.5mV    -221uV     841.9mV
2.929ns   576.8mV    -10.47mV   855.7mV
3.434ns   601.7mV    -10.53mV   859.2mV
3.939ns   614mV      235.3mV    859.8mV
4.546ns   621.4mV    323.2mV    860.1mV
10ns      627.7mV    355.7mV    860.1mV
[Falling Waveform]
R_fixture=   50.0000
V_fixture=   0.0
V_fixture_min=   0.0
V_fixture_max=   0.0
|time   V(typ)   V(min)   V(max)
0s        627.8mV    356mV      860.1mV
1.01ns    627.8mV    356mV      800.9mV
1.212ns   627.9mV    356mV      118.7mV
1.313ns   628.5mV    356mV      19.43mV
1.717ns   603mV      356mV      5.037mV
2.02ns    117.2mV    355.9mV    1.889mV
2.222ns   10.79mV    356.1mV    987.1uV
3.131ns   1.461mV    342.3mV    62.26uV
3.939ns   375uV      8.969mV    4.473uV
10ns      12.94uV    10.96uV    19.66uV
[Falling Waveform]
R_fixture=   50.0000
V_fixture=   1.2000
V_fixture_min=   1.1400
V_fixture_max=   1.2600
|time   V(typ)   V(min)   V(max)
0s        1.2V       1.14V      1.26V
1.01ns    1.2V       1.14V      1.274V
1.313ns   1.201V     1.14V      412.7mV
1.515ns   1.2V       1.14V      294.8mV
1.919ns   1.176V     1.14V      276.3mV
2.222ns   591.2mV    1.14V      271mV
2.626ns   441.2mV    1.141V     268.4mV
3.434ns   418.7mV    1.185V     267.5mV
4.546ns   409.8mV    693.5mV    267.4mV
10ns      408.3mV    666.9mV    267.4mV
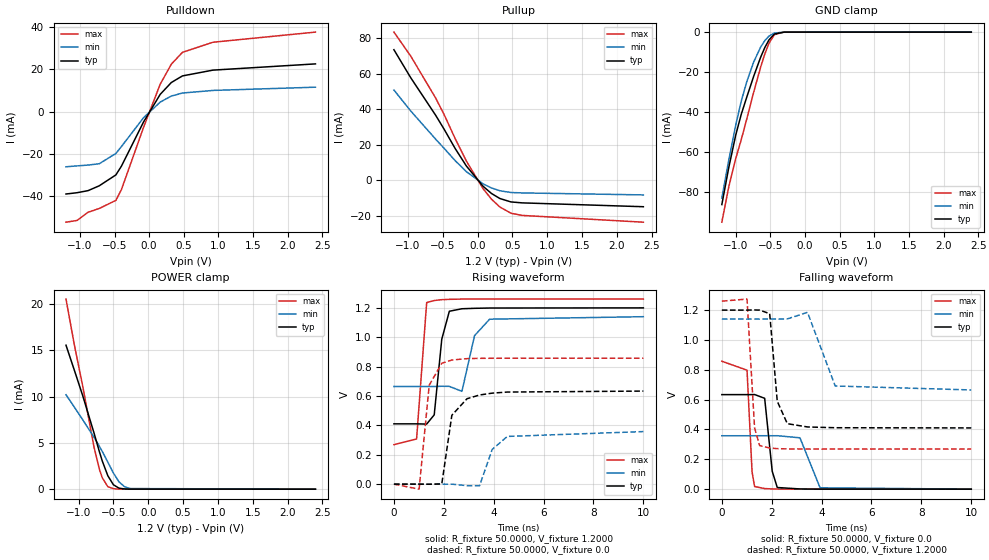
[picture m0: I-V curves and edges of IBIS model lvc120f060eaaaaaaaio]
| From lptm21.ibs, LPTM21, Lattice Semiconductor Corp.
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|   Model lvc120f060eaaaaaaaio
[Model]   lvc120f060eaaaaaaaio
Model_type   I/O
Polarity   Non-Inverting
Enable   Active-Low
Vinl =   0.4200V
Vinh =   0.7800V
Vmeas =   0.6000V
Cref =   0.0F
Rref =   1.0000M
Vref =   0.0V
C_comp   3.0000pF   2.7000pF   3.3000pF
[Temperature Range]   25.0000   0.1050k   -40.0000
[Voltage Range]   1.2000V   1.1400V   1.2600V
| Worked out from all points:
|   slope of the pulldown table from 0 to 0.18 V, typ, clamps not added: 20 ohm
|   slope of the pullup table from 0 to 0.18 V, typ, clamps not added: 26.6 ohm
|   GND clamp passes 1 mA (typ) near -0.44 V on its own axis
|   POWER clamp passes 1 mA (typ) near -0.55 V on its own axis
|   rising waveform, R_fixture 50.0000, V_fixture 1.2000: 20-80 % time 305ps typ, 426ps min, 204ps max; typ from 0.41 V to 1.2 V
|   rising waveform, R_fixture 50.0000, V_fixture 0.0: 20-80 % time 414ps typ, 518ps min, 281ps max; typ from 0 V to 0.634 V
|   falling waveform, R_fixture 50.0000, V_fixture 0.0: 20-80 % time 210ps typ, 375ps min, 152ps max; typ from 0.634 V to 0 V
|   falling waveform, R_fixture 50.0000, V_fixture 1.2000: 20-80 % time 264ps typ, 418ps min, 166ps max; typ from 1.2 V to 0.41 V
[Pulldown]
|Voltage   I(typ)   I(min)   I(max)
-1.2V     -38.96mA   -26.08mA   -52.29mA
-1.04V    -38.35mA   -25.67mA   -51.47mA
-880mV    -37.35mA   -25.27mA   -47.56mA
-720mV    -35.07mA   -24.65mA   -45.8mA
-480mV    -29.93mA   -19.79mA   -41.97mA
-400mV    -25.79mA   -16.51mA   -36.87mA
-80mV     -4.851mA   -2.848mA   -7.377mA
160mV     8.179mA    4.521mA    13.01mA
320mV     13.76mA    7.355mA    22.43mA
480mV     16.88mA    8.777mA    28.01mA
920mV     19.62mA    10.02mA    32.8mA
2.4V      22.57mA    11.55mA    37.61mA
[Pullup]
|Voltage   I(typ)   I(min)   I(max)
-1.2V     73.66mA    50.94mA    83.59mA
-960mV    57.95mA    39.19mA    70.14mA
-600mV    36.65mA    23.19mA    46.34mA
-480mV    28.88mA    18.09mA    37.13mA
-320mV    17.9mA     11.08mA    23.47mA
-160mV    8.111mA    4.917mA    10.9mA
80mV      -3.336mA   -1.952mA   -4.689mA
200mV     -7.372mA   -4.268mA   -10.57mA
320mV     -10.21mA   -5.84mA    -14.99mA
480mV     -12.14mA   -6.823mA   -18.5mA
640mV     -12.67mA   -7.06mA    -19.74mA
2.38V     -14.84mA   -8.183mA   -23.56mA
[GND_clamp]
|Voltage   I(typ)   I(min)   I(max)
-1.2V     -86.07mA   -82.81mA   -94.84mA
-1.1V     -67.62mA   -63.85mA   -77.22mA
-1V       -51.44mA   -46.49mA   -63.16mA
-920mV    -41.05mA   -34.47mA   -53.69mA
-840mV    -32.43mA   -24.76mA   -43.33mA
-740mV    -22.02mA   -14.88mA   -29.93mA
-640mV    -12.55mA   -7.499mA   -17.49mA
-580mV    -7.732mA   -4.278mA   -10.96mA
-520mV    -3.911mA   -2mA       -5.586mA
-440mV    -943.9uA   -474.2uA   -1.243mA
-300mV    -18.55uA   -15.85uA   -16.32uA
2.4V      0A         0A         0A
[POWER_clamp]
|Voltage   I(typ)   I(min)   I(max)
-1.18V    15.54mA    10.19mA    20.52mA
-1.06V    12.84mA    8.851mA    15.57mA
-940mV    10.09mA    7.491mA    11.12mA
-780mV    6.115mA    5.629mA    4.606mA
-700mV    4.023mA    4.616mA    2.131mA
-660mV    3.056mA    4.076mA    1.241mA
-580mV    1.457mA    2.922mA    275.5uA
-500mV    478.5uA    1.748mA    47.96uA
-420mV    109.5uA    796.1uA    7.509uA
-340mV    22.62uA    261.6uA    1.074uA
-260mV    4.285uA    65.97uA    166.7nA
2.4V      -20.81nA   -18.5nA    -25.04nA
[Ramp]
| variable   typ   min   max
dV/dt_r  0.3358/0.4103n   0.2147/0.5128n   0.5144/0.2778n
dV/dt_f  0.4737/0.2612n   0.2851/0.4143n   0.5948/0.1638n
R_load = 50.0000
[Rising Waveform]
R_fixture=   50.0000
V_fixture=   1.2000
V_fixture_min=   1.1400
V_fixture_max=   1.2600
|time   V(typ)   V(min)   V(max)
0s        410.5mV    664.7mV    268.8mV
909.1ps   410.4mV    664.7mV    307.5mV
1.313ns   408.9mV    664.6mV    1.236V
1.616ns   471.8mV    664.5mV    1.25V
1.919ns   987.2mV    666.3mV    1.256V
2.222ns   1.177V     665.6mV    1.258V
2.727ns   1.194V     631.8mV    1.26V
3.232ns   1.197V     1.011V     1.26V
3.838ns   1.199V     1.123V     1.26V
10ns      1.2V       1.14V      1.26V
[Rising Waveform]
R_fixture=   50.0000
V_fixture=   0.0
V_fixture_min=   0.0
V_fixture_max=   0.0
|time   V(typ)   V(min)   V(max)
0s        231.9nV    390.7nV    158.8nV
1.01ns    24.41uV    189.3nV    -34.26mV
1.414ns   -738.5uV   4.55uV     673.1mV
1.919ns   1.27mV     -62.63uV   823mV
2.323ns   469mV      -222.1uV   845.1mV
2.929ns   581.4mV    -10.49mV   854.5mV
3.434ns   606.9mV    -10.68mV   856.4mV
3.939ns   619.5mV    236mV      857mV
4.546ns   626.9mV    324.8mV    857.2mV
10ns      633.5mV    357.8mV    857.3mV
[Falling Waveform]
R_fixture=   50.0000
V_fixture=   0.0
V_fixture_min=   0.0
V_fixture_max=   0.0
|time   V(typ)   V(min)   V(max)
0s        633.6mV    358mV      857.3mV
1.01ns    633.6mV    358mV      797.5mV
1.212ns   633.7mV    358mV      115.8mV
1.313ns   634.3mV    358mV      17.73mV
1.717ns   608.8mV    358.1mV    3.975mV
2.02ns    120.1mV    358mV      1.603mV
2.222ns   11.17mV    358.2mV    882.6uV
3.131ns   1.497mV    344.3mV    61.03uV
3.939ns   383.8uV    9.171mV    6.771uV
10ns      9.635uV    3uV        21.34uV
[Falling Waveform]
R_fixture=   50.0000
V_fixture=   1.2000
V_fixture_min=   1.1400
V_fixture_max=   1.2600
|time   V(typ)   V(min)   V(max)
0s        1.2V       1.14V      1.26V
1.01ns    1.2V       1.14V      1.274V
1.313ns   1.201V     1.14V      410.1mV
1.515ns   1.2V       1.14V      292.5mV
1.919ns   1.176V     1.14V      275.7mV
2.222ns   589.1mV    1.14V      271.6mV
2.626ns   438.8mV    1.141V     269.6mV
3.434ns   416.9mV    1.185V     268.9mV
4.546ns   411.7mV    691.5mV    268.8mV
10ns      410.4mV    664.8mV    268.8mV
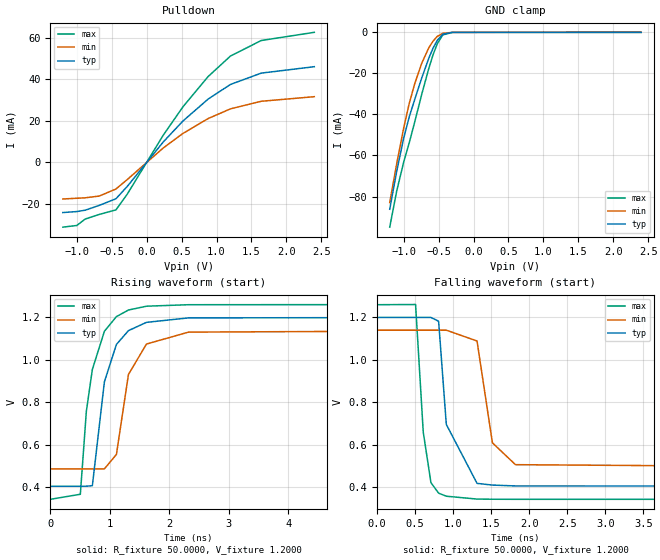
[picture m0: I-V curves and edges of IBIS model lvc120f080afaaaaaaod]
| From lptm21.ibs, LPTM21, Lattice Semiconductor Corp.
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|   Model lvc120f080afaaaaaaod
[Model]   lvc120f080afaaaaaaod
Model_type   I/O_open_drain
Polarity   Non-Inverting
Enable   Active-Low
Vinl =   0.4200V
Vinh =   0.7800V
Vmeas =   0.6000V
Cref =   0.0F
Rref =   1.0000M
Vref =   0.0V
C_comp   4.2000pF   3.8000pF   7.5000pF
[Temperature Range]   25.0000   0.1050k   -40.0000
[Voltage Range]   1.2000V   1.1400V   1.2600V
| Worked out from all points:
|   slope of the pulldown table from 0 to 0.18 V, typ, clamps not added: 24.1 ohm
|   GND clamp passes 1 mA (typ) near -0.44 V on its own axis
|   rising waveform, R_fixture 50.0000, V_fixture 1.2000: 20-80 % time 298ps typ, 285ps min, 277ps max; typ from 0.404 V to 1.2 V
|   falling waveform, R_fixture 50.0000, V_fixture 1.2000: 20-80 % time 138ps typ, 171ps min, 127ps max; typ from 1.2 V to 0.405 V
[Pulldown]
|Voltage   I(typ)   I(min)   I(max)
-1.2V     -24.3mA    -17.75mA   -31.34mA
-1V       -23.83mA   -17.41mA   -30.53mA
-880mV    -23.16mA   -17.2mA    -27.43mA
-680mV    -20.86mA   -16.36mA   -25.22mA
-440mV    -17.66mA   -12.95mA   -23.01mA
-280mV    -11.79mA   -8.451mA   -15.54mA
240mV     9.83mA     6.91mA     13.13mA
520mV     19.85mA    13.85mA    26.7mA
880mV     30.42mA    21.02mA    41.27mA
1.2V      37.47mA    25.7mA     51.17mA
1.64V     42.92mA    29.35mA    58.64mA
2.4V      46.02mA    31.56mA    62.59mA
[GND_clamp]
|Voltage   I(typ)   I(min)   I(max)
-1.2V     -86.19mA   -82.94mA   -94.91mA
-1.1V     -67.71mA   -63.95mA   -77.28mA
-1V       -51.52mA   -46.57mA   -63.21mA
-920mV    -41.11mA   -34.53mA   -53.74mA
-840mV    -32.47mA   -24.81mA   -43.38mA
-740mV    -22.05mA   -14.9mA    -29.96mA
-640mV    -12.58mA   -7.515mA   -17.52mA
-580mV    -7.752mA   -4.29mA    -10.99mA
-520mV    -3.927mA   -2.008mA   -5.609mA
-440mV    -951.3uA   -477uA     -1.256mA
-300mV    -18.83uA   -15.98uA   -16.74uA
2.4V      0A         0A         0A
[Ramp]
| variable   typ   min   max
dV/dt_r  0.4773/0.2949n   0.3923/0.2817n   0.5502/0.2743n
dV/dt_f  0.4772/0.1369n   0.3923/0.1695n   0.5502/0.1253n
R_load = 50.0000
[Rising Waveform]
R_fixture=   50.0000
V_fixture=   1.2000
V_fixture_min=   1.1400
V_fixture_max=   1.2600
|time   V(typ)   V(min)   V(max)
0s        404.5mV    486.1mV    343mV
505.1ps   404.6mV    486.1mV    366.8mV
606.1ps   404.8mV    486.1mV    757.5mV
707.1ps   407.4mV    486.1mV    954.7mV
909.1ps   896mV      486.4mV    1.134V
1.111ns   1.072V     554.2mV    1.203V
1.313ns   1.137V     930.6mV    1.234V
1.616ns   1.176V     1.074V     1.252V
2.323ns   1.197V     1.13V      1.259V
10ns      1.2V       1.14V      1.26V
[Falling Waveform]
R_fixture=   50.0000
V_fixture=   1.2000
V_fixture_min=   1.1400
V_fixture_max=   1.2600
|time   V(typ)   V(min)   V(max)
0s        1.2V       1.14V      1.26V
505.1ps   1.2V       1.14V      1.261V
606.1ps   1.2V       1.14V      659.4mV
707.1ps   1.2V       1.14V      421.5mV
808.1ps   1.182V     1.14V      372.1mV
909.1ps   696.1mV    1.14V      357.7mV
1.313ns   418.2mV    1.089V     344.2mV
1.515ns   410.2mV    609.4mV    343.4mV
1.818ns   406.1mV    506.3mV    343.1mV
10ns      404.6mV    486.1mV    343mV
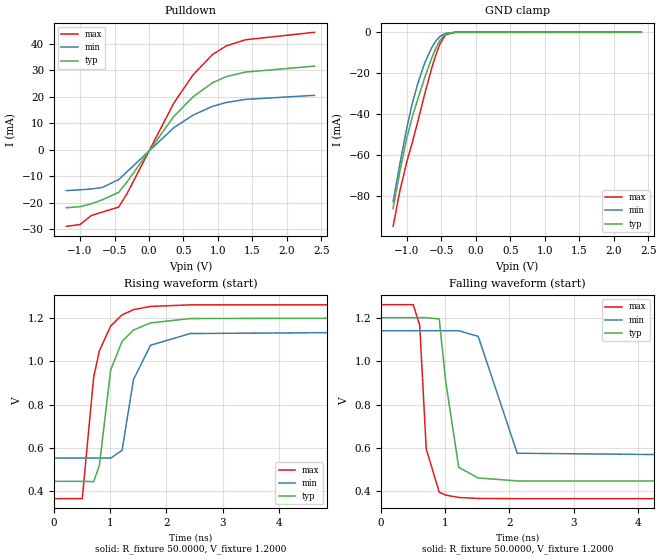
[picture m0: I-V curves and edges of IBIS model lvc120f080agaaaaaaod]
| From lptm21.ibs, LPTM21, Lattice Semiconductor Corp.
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|   Model lvc120f080agaaaaaaod
[Model]   lvc120f080agaaaaaaod
Model_type   I/O_open_drain
Polarity   Non-Inverting
Enable   Active-Low
Vinl =   0.4200V
Vinh =   0.7800V
Vmeas =   0.6000V
Cref =   0.0F
Rref =   1.0000M
Vref =   0.0V
C_comp   4.2000pF   3.8000pF   7.5000pF
[Temperature Range]   25.0000   0.1050k   -40.0000
[Voltage Range]   1.2000V   1.1400V   1.2600V
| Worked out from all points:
|   slope of the pulldown table from 0 to 0.18 V, typ, clamps not added: 26.9 ohm
|   GND clamp passes 1 mA (typ) near -0.44 V on its own axis
|   rising waveform, R_fixture 50.0000, V_fixture 1.2000: 20-80 % time 292ps typ, 304ps min, 296ps max; typ from 0.447 V to 1.2 V
|   falling waveform, R_fixture 50.0000, V_fixture 1.2000: 20-80 % time 167ps typ, 218ps min, 117ps max; typ from 1.2 V to 0.447 V
[Pulldown]
|Voltage   I(typ)   I(min)   I(max)
-1.2V     -21.98mA   -15.5mA    -29mA
-1V       -21.56mA   -15.2mA    -28.34mA
-840mV    -20.52mA   -14.9mA    -24.97mA
-680mV    -19.01mA   -14.34mA   -23.64mA
-440mV    -16.17mA   -11.36mA   -21.73mA
-320mV    -12.28mA   -8.42mA    -16.72mA
360mV     12.55mA    8.278mA    17.59mA
640mV     19.98mA    13.05mA    28.27mA
920mV     25.26mA    16.36mA    35.94mA
1.12V     27.59mA    17.83mA    39.21mA
1.4V      29.33mA    18.98mA    41.54mA
2.4V      31.57mA    20.53mA    44.37mA
[GND_clamp]
|Voltage   I(typ)   I(min)   I(max)
-1.2V     -86.17mA   -82.93mA   -94.89mA
-1.1V     -67.7mA    -63.94mA   -77.26mA
-1V       -51.5mA    -46.57mA   -63.19mA
-920mV    -41.09mA   -34.53mA   -53.72mA
-840mV    -32.46mA   -24.8mA    -43.36mA
-740mV    -22.04mA   -14.89mA   -29.94mA
-640mV    -12.57mA   -7.509mA   -17.5mA
-580mV    -7.744mA   -4.285mA   -10.97mA
-520mV    -3.92mA    -2.005mA   -5.598mA
-440mV    -948.2uA   -476uA     -1.25mA
-300mV    -18.71uA   -15.93uA   -16.55uA
2.4V      0A         0A         0A
[Ramp]
| variable   typ   min   max
dV/dt_r  0.4520/0.2894n   0.3519/0.3005n   0.5361/0.2932n
dV/dt_f  0.4520/0.1656n   0.3519/0.2162n   0.5361/0.1162n
R_load = 50.0000
[Rising Waveform]
R_fixture=   50.0000
V_fixture=   1.2000
V_fixture_min=   1.1400
V_fixture_max=   1.2600
|time   V(typ)   V(min)   V(max)
0s        446.6mV    553.5mV    366.5mV
505.1ps   446.6mV    553.5mV    366.9mV
707.1ps   445mV      553.5mV    925.6mV
808.1ps   518.7mV    553.6mV    1.047V
1.01ns    959.7mV    553.4mV    1.162V
1.212ns   1.091V     588.9mV    1.213V
1.414ns   1.143V     915mV      1.237V
1.717ns   1.176V     1.073V     1.252V
2.424ns   1.196V     1.127V     1.259V
10ns      1.2V       1.14V      1.26V
[Falling Waveform]
R_fixture=   50.0000
V_fixture=   1.2000
V_fixture_min=   1.1400
V_fixture_max=   1.2600
|time   V(typ)   V(min)   V(max)
0s        1.2V       1.14V      1.26V
505.1ps   1.2V       1.14V      1.26V
606.1ps   1.2V       1.14V      1.165V
707.1ps   1.2V       1.14V      596.2mV
909.1ps   1.194V     1.14V      396.6mV
1.01ns    906.5mV    1.14V      383.1mV
1.212ns   510.7mV    1.14V      372.1mV
1.515ns   462mV      1.114V     367.6mV
2.121ns   448.4mV    575.8mV    366.6mV
10ns      446.6mV    553.5mV    366.5mV
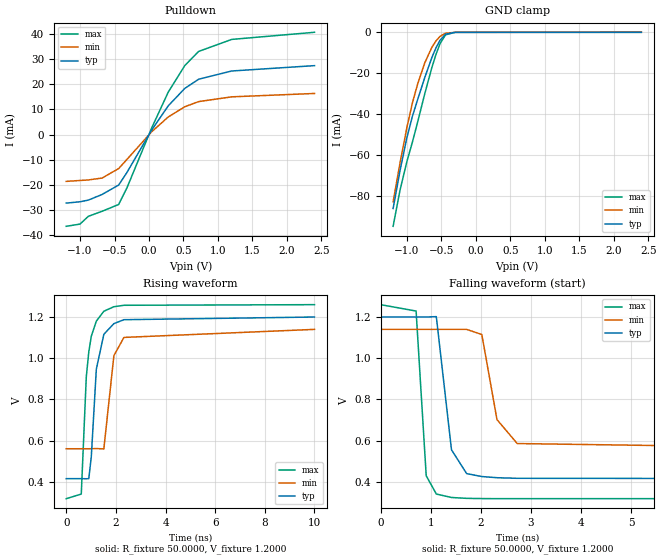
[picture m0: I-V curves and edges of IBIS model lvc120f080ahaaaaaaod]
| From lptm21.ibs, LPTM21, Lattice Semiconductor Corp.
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|   Model lvc120f080ahaaaaaaod
[Model]   lvc120f080ahaaaaaaod
Model_type   I/O_open_drain
Polarity   Non-Inverting
Enable   Active-Low
Vinl =   0.4200V
Vinh =   0.7800V
Vmeas =   0.6000V
Cref =   0.0F
Rref =   1.0000M
Vref =   0.0V
C_comp   4.2000pF   3.8000pF   7.5000pF
[Temperature Range]   25.0000   0.1050k   -40.0000
[Voltage Range]   1.2000V   1.1400V   1.2600V
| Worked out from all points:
|   slope of the pulldown table from 0 to 0.18 V, typ, clamps not added: 23.2 ohm
|   GND clamp passes 1 mA (typ) near -0.44 V on its own axis
|   rising waveform, R_fixture 50.0000, V_fixture 1.2000: 20-80 % time 297ps typ, 305ps min, 305ps max; typ from 0.415 V to 1.2 V
|   falling waveform, R_fixture 50.0000, V_fixture 1.2000: 20-80 % time 174ps typ, 267ps min, 145ps max; typ from 1.2 V to 0.415 V
[Pulldown]
|Voltage   I(typ)   I(min)   I(max)
-1.2V     -27.21mA   -18.58mA   -36.43mA
-1V       -26.68mA   -18.22mA   -35.54mA
-880mV    -26.03mA   -18.01mA   -32.47mA
-680mV    -23.78mA   -17.26mA   -30.46mA
-440mV    -20.04mA   -13.49mA   -27.75mA
-320mV    -15.06mA   -9.867mA   -21.18mA
40mV      1.857mA    1.159mA    2.701mA
280mV     11.46mA    7.034mA    16.91mA
520mV     18.37mA    11.08mA    27.46mA
720mV     22mA       13.12mA    33.05mA
1.2V      25.28mA    15.01mA    37.83mA
2.4V      27.41mA    16.35mA    40.66mA
[GND_clamp]
|Voltage   I(typ)   I(min)   I(max)
-1.2V     -86.17mA   -82.92mA   -94.88mA
-1.1V     -67.69mA   -63.94mA   -77.25mA
-1V       -51.5mA    -46.56mA   -63.18mA
-920mV    -41.08mA   -34.52mA   -53.71mA
-840mV    -32.45mA   -24.8mA    -43.35mA
-740mV    -22.04mA   -14.89mA   -29.94mA
-640mV    -12.56mA   -7.506mA   -17.5mA
-580mV    -7.74mA    -4.283mA   -10.97mA
-520mV    -3.917mA   -2.003mA   -5.594mA
-440mV    -946.7uA   -475.3uA   -1.248mA
-300mV    -18.65uA   -15.9uA    -16.46uA
2.4V      0A         0A         0A
[Ramp]
| variable   typ   min   max
dV/dt_r  0.4708/0.2937n   0.3477/0.3017n   0.5651/0.3020n
dV/dt_f  0.4708/0.1721n   0.3477/0.2644n   0.5651/0.1431n
R_load = 50.0000
[Rising Waveform]
R_fixture=   50.0000
V_fixture=   1.2000
V_fixture_min=   1.1400
V_fixture_max=   1.2600
|time   V(typ)   V(min)   V(max)
0s        415.4mV    560.5mV    318.1mV
606.1ps   415.4mV    560.5mV    340.5mV
808.1ps   414.8mV    560.5mV    909.8mV
909.1ps   415.4mV    560.5mV    1.031V
1.01ns    522.5mV    560.6mV    1.107V
1.212ns   946.7mV    561.5mV    1.18V
1.515ns   1.116V     559.6mV    1.228V
1.919ns   1.168V     1.012V     1.25V
2.323ns   1.187V     1.101V     1.257V
10ns      1.2V       1.14V      1.26V
[Falling Waveform]
R_fixture=   50.0000
V_fixture=   1.2000
V_fixture_min=   1.1400
V_fixture_max=   1.2600
|time   V(typ)   V(min)   V(max)
0s        1.2V       1.14V      1.26V
707.1ps   1.2V       1.14V      1.229V
909.1ps   1.2V       1.14V      429.5mV
1.111ns   1.202V     1.14V      340.6mV
1.414ns   555.5mV    1.14V      324mV
1.717ns   439.8mV    1.14V      319.7mV
2.02ns    425.6mV    1.115V     318.6mV
2.323ns   419.9mV    701.9mV    318.3mV
2.727ns   417mV      585.8mV    318.2mV
10ns      415.4mV    560.5mV    318.1mV
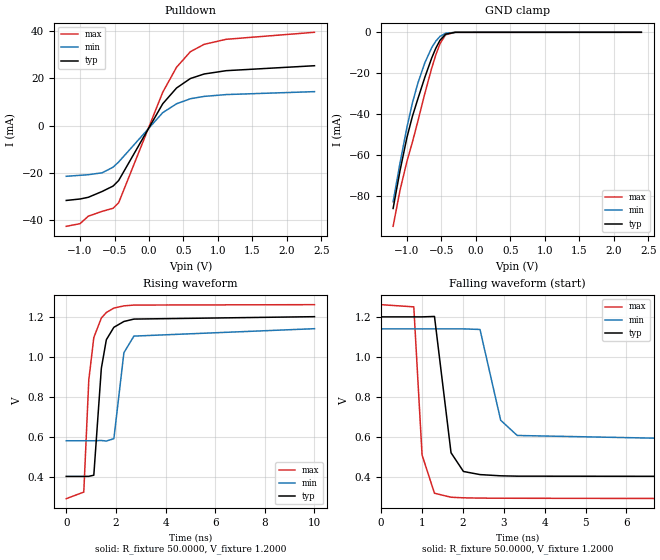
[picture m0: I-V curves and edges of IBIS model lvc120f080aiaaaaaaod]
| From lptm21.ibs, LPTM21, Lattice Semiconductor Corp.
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|   Model lvc120f080aiaaaaaaod
[Model]   lvc120f080aiaaaaaaod
Model_type   I/O_open_drain
Polarity   Non-Inverting
Enable   Active-Low
Vinl =   0.4200V
Vinh =   0.7800V
Vmeas =   0.6000V
Cref =   0.0F
Rref =   1.0000M
Vref =   0.0V
C_comp   4.2000pF   3.8000pF   7.5000pF
[Temperature Range]   25.0000   0.1050k   -40.0000
[Voltage Range]   1.2000V   1.1400V   1.2600V
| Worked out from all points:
|   slope of the pulldown table from 0 to 0.18 V, typ, clamps not added: 21.3 ohm
|   GND clamp passes 1 mA (typ) near -0.44 V on its own axis
|   rising waveform, R_fixture 50.0000, V_fixture 1.2000: 20-80 % time 303ps typ, 319ps min, 306ps max; typ from 0.402 V to 1.2 V
|   falling waveform, R_fixture 50.0000, V_fixture 1.2000: 20-80 % time 229ps typ, 334ps min, 165ps max; typ from 1.2 V to 0.402 V
[Pulldown]
|Voltage   I(typ)   I(min)   I(max)
-1.2V     -31.59mA   -21.4mA    -42.51mA
-1V       -30.98mA   -20.98mA   -41.41mA
-880mV    -30.26mA   -20.73mA   -38.23mA
-680mV    -27.81mA   -19.92mA   -36.21mA
-520mV    -25.51mA   -17.54mA   -34.87mA
-440mV    -23.18mA   -15.36mA   -32.59mA
200mV     9.256mA    5.491mA    14.11mA
400mV     15.89mA    9.227mA    24.66mA
600mV     19.88mA    11.34mA    31.21mA
800mV     21.8mA     12.34mA    34.32mA
1.12V     23.2mA     13.11mA    36.45mA
2.4V      25.29mA    14.35mA    39.41mA
[GND_clamp]
|Voltage   I(typ)   I(min)   I(max)
-1.2V     -86.15mA   -82.88mA   -94.87mA
-1.1V     -67.68mA   -63.91mA   -77.24mA
-1V       -51.49mA   -46.55mA   -63.18mA
-920mV    -41.08mA   -34.52mA   -53.71mA
-840mV    -32.45mA   -24.79mA   -43.35mA
-740mV    -22.03mA   -14.89mA   -29.94mA
-640mV    -12.56mA   -7.505mA   -17.5mA
-580mV    -7.739mA   -4.282mA   -10.97mA
-520mV    -3.916mA   -2.003mA   -5.593mA
-440mV    -946.1uA   -475uA     -1.247mA
-300mV    -18.63uA   -15.88uA   -16.42uA
2.4V      0A         0A         0A
[Ramp]
| variable   typ   min   max
dV/dt_r  0.4786/0.3001n   0.3357/0.3161n   0.5813/0.3033n
dV/dt_f  0.4785/0.2265n   0.3358/0.3308n   0.5813/0.1571n
R_load = 50.0000
[Rising Waveform]
R_fixture=   50.0000
V_fixture=   1.2000
V_fixture_min=   1.1400
V_fixture_max=   1.2600
|time   V(typ)   V(min)   V(max)
0s        402.4mV    580.4mV    291.1mV
707.1ps   402.4mV    580.4mV    324.2mV
909.1ps   402.7mV    580.4mV    884.1mV
1.111ns   408.4mV    580.3mV    1.096V
1.414ns   941.8mV    581.8mV    1.193V
1.616ns   1.085V     578.9mV    1.221V
1.919ns   1.147V     590.8mV    1.243V
2.323ns   1.176V     1.02V      1.254V
2.727ns   1.188V     1.103V     1.258V
10ns      1.2V       1.14V      1.26V
[Falling Waveform]
R_fixture=   50.0000
V_fixture=   1.2000
V_fixture_min=   1.1400
V_fixture_max=   1.2600
|time   V(typ)   V(min)   V(max)
0s        1.2V       1.14V      1.261V
808.1ps   1.2V       1.14V      1.25V
1.01ns    1.2V       1.14V      509.4mV
1.313ns   1.202V     1.14V      318.4mV
1.717ns   520.8mV    1.14V      298.4mV
2.02ns    427.2mV    1.14V      295.5mV
2.424ns   411.6mV    1.137V     294.1mV
2.929ns   405.5mV    683.2mV    293.5mV
3.333ns   403.8mV    607.1mV    293.3mV
10ns      402.4mV    580.4mV    291.2mV
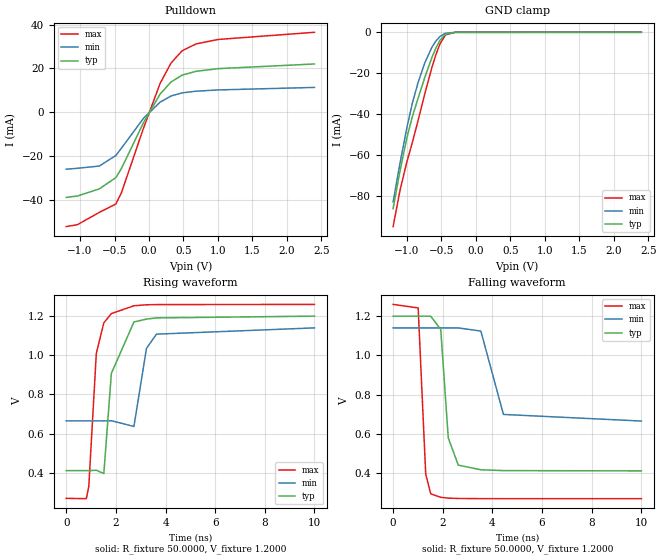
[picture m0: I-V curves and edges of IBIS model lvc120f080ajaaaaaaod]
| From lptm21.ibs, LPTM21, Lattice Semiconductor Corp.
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|   Model lvc120f080ajaaaaaaod
[Model]   lvc120f080ajaaaaaaod
Model_type   I/O_open_drain
Polarity   Non-Inverting
Enable   Active-Low
Vinl =   0.4200V
Vinh =   0.7800V
Vmeas =   0.6000V
Cref =   0.0F
Rref =   1.0000M
Vref =   0.0V
C_comp   4.2000pF   3.8000pF   7.5000pF
[Temperature Range]   25.0000   0.1050k   -40.0000
[Voltage Range]   1.2000V   1.1400V   1.2600V
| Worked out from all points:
|   slope of the pulldown table from 0 to 0.18 V, typ, clamps not added: 20 ohm
|   GND clamp passes 1 mA (typ) near -0.44 V on its own axis
|   rising waveform, R_fixture 50.0000, V_fixture 1.2000: 20-80 % time 303ps typ, 347ps min, 309ps max; typ from 0.41 V to 1.2 V
|   falling waveform, R_fixture 50.0000, V_fixture 1.2000: 20-80 % time 272ps typ, 426ps min, 173ps max; typ from 1.2 V to 0.41 V
[Pulldown]
|Voltage   I(typ)   I(min)   I(max)
-1.2V     -38.96mA   -26.08mA   -52.29mA
-1.04V    -38.35mA   -25.67mA   -51.47mA
-720mV    -35.07mA   -24.65mA   -45.8mA
-480mV    -29.92mA   -19.79mA   -41.97mA
-400mV    -25.79mA   -16.51mA   -36.87mA
-80mV     -4.851mA   -2.848mA   -7.377mA
160mV     8.179mA    4.521mA    13.01mA
320mV     13.76mA    7.355mA    22.43mA
480mV     16.88mA    8.777mA    28.01mA
680mV     18.62mA    9.547mA    31.12mA
1V        19.85mA    10.13mA    33.18mA
2.4V      21.99mA    11.28mA    36.46mA
[GND_clamp]
|Voltage   I(typ)   I(min)   I(max)
-1.2V     -86.08mA   -82.82mA   -94.85mA
-1.1V     -67.63mA   -63.86mA   -77.23mA
-1V       -51.45mA   -46.5mA    -63.17mA
-920mV    -41.06mA   -34.48mA   -53.7mA
-840mV    -32.44mA   -24.77mA   -43.34mA
-740mV    -22.03mA   -14.88mA   -29.93mA
-640mV    -12.56mA   -7.503mA   -17.49mA
-580mV    -7.737mA   -4.281mA   -10.96mA
-520mV    -3.915mA   -2.002mA   -5.591mA
-440mV    -945.4uA   -474.8uA   -1.246mA
-300mV    -18.6uA    -15.87uA   -16.39uA
2.4V      0A         0A         0A
[Ramp]
| variable   typ   min   max
dV/dt_r  0.4737/0.3000n   0.2851/0.3437n   0.5947/0.3057n
dV/dt_f  0.4731/0.2448n   0.2837/0.3780n   0.5940/0.1634n
R_load = 50.0000
[Rising Waveform]
R_fixture=   50.0000
V_fixture=   1.2000
V_fixture_min=   1.1400
V_fixture_max=   1.2600
|time   V(typ)   V(min)   V(max)
0s        410.5mV    664.7mV    268.8mV
808.1ps   410.4mV    664.7mV    267.1mV
909.1ps   410.4mV    664.7mV    329.7mV
1.212ns   412.4mV    664.7mV    1.01V
1.515ns   395.6mV    664.5mV    1.166V
1.818ns   907.4mV    665.5mV    1.213V
2.727ns   1.17V      636.1mV    1.253V
3.232ns   1.185V     1.035V     1.258V
3.636ns   1.191V     1.108V     1.259V
10ns      1.2V       1.14V      1.26V
[Falling Waveform]
R_fixture=   50.0000
V_fixture=   1.2000
V_fixture_min=   1.1400
V_fixture_max=   1.2600
|time   V(typ)   V(min)   V(max)
0s        1.2V       1.14V      1.26V
1.01ns    1.2V       1.14V      1.242V
1.313ns   1.2V       1.14V      394.4mV
1.515ns   1.2V       1.14V      293.4mV
1.919ns   1.132V     1.14V      275.6mV
2.222ns   578.7mV    1.14V      271.6mV
2.626ns   439.9mV    1.14V      269.7mV
3.535ns   416.2mV    1.124V     268.9mV
4.444ns   411.9mV    698.5mV    268.7mV
10ns      410.5mV    664.8mV    268.7mV
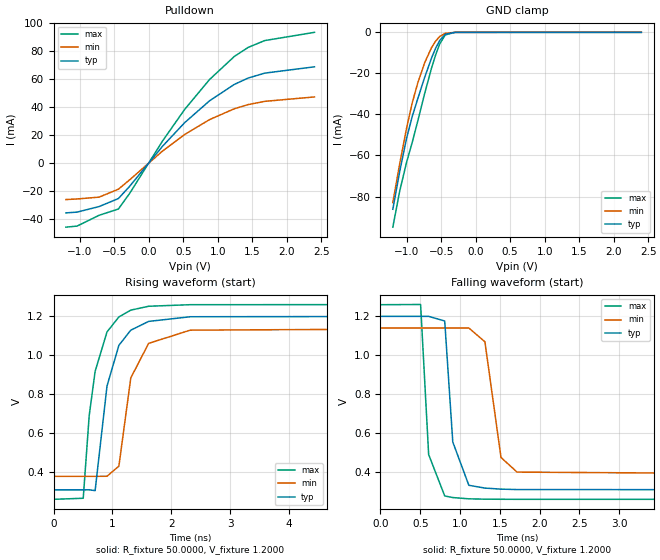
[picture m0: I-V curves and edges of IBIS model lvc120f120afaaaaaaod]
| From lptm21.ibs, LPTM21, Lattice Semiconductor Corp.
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|   Model lvc120f120afaaaaaaod
[Model]   lvc120f120afaaaaaaod
Model_type   I/O_open_drain
Polarity   Non-Inverting
Enable   Active-Low
Vinl =   0.4200V
Vinh =   0.7800V
Vmeas =   0.6000V
Cref =   0.0F
Rref =   1.0000M
Vref =   0.0V
C_comp   4.2000pF   3.8000pF   7.5000pF
[Temperature Range]   25.0000   0.1050k   -40.0000
[Voltage Range]   1.2000V   1.1400V   1.2600V
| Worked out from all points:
|   slope of the pulldown table from 0 to 0.18 V, typ, clamps not added: 16.7 ohm
|   GND clamp passes 1 mA (typ) near -0.44 V on its own axis
|   rising waveform, R_fixture 50.0000, V_fixture 1.2000: 20-80 % time 301ps typ, 293ps min, 279ps max; typ from 0.307 V to 1.2 V
|   falling waveform, R_fixture 50.0000, V_fixture 1.2000: 20-80 % time 113ps typ, 152ps min, 91ps max; typ from 1.2 V to 0.307 V
[Pulldown]
|Voltage   I(typ)   I(min)   I(max)
-1.2V     -35.91mA   -26.33mA   -46.13mA
-1.04V    -35.35mA   -25.92mA   -45.37mA
-720mV    -31.36mA   -24.6mA    -37.64mA
-440mV    -25.61mA   -18.91mA   -33.09mA
-280mV    -16.99mA   -12.31mA   -22.13mA
200mV     11.94mA    8.495mA    15.72mA
520mV     28.82mA    20.32mA    38.31mA
880mV     44.47mA    31mA       59.74mA
1.24V     56.27mA    38.8mA     76.33mA
1.44V     60.82mA    41.77mA    82.79mA
1.68V     64.34mA    44.1mA     87.69mA
2.4V      68.86mA    47.26mA    93.6mA
[GND_clamp]
|Voltage   I(typ)   I(min)   I(max)
-1.2V     -86.19mA   -82.94mA   -94.91mA
-1.1V     -67.71mA   -63.95mA   -77.28mA
-1V       -51.52mA   -46.57mA   -63.21mA
-920mV    -41.11mA   -34.53mA   -53.74mA
-840mV    -32.47mA   -24.81mA   -43.38mA
-740mV    -22.05mA   -14.9mA    -29.96mA
-640mV    -12.58mA   -7.515mA   -17.52mA
-580mV    -7.752mA   -4.29mA    -10.99mA
-520mV    -3.927mA   -2.008mA   -5.609mA
-440mV    -951.3uA   -477uA     -1.256mA
-300mV    -18.83uA   -15.98uA   -16.74uA
2.4V      0A         0A         0A
[Ramp]
| variable   typ   min   max
dV/dt_r  0.5360/0.2981n   0.4583/0.2901n   0.6013/0.2763n
dV/dt_f  0.5360/0.1116n   0.4583/0.1509n   0.6013/90.1348p
R_load = 50.0000
[Rising Waveform]
R_fixture=   50.0000
V_fixture=   1.2000
V_fixture_min=   1.1400
V_fixture_max=   1.2600
|time   V(typ)   V(min)   V(max)
0s        306.6mV    376.2mV    257.9mV
505.1ps   306.6mV    376.2mV    263.5mV
606.1ps   307mV      376.2mV    688.2mV
707.1ps   302.6mV    376.2mV    916.3mV
909.1ps   840.9mV    376.6mV    1.119V
1.111ns   1.05V      428.6mV    1.196V
1.313ns   1.128V     882.2mV    1.231V
1.616ns   1.173V     1.06V      1.251V
2.323ns   1.197V     1.128V     1.259V
10ns      1.2V       1.14V      1.26V
[Falling Waveform]
R_fixture=   50.0000
V_fixture=   1.2000
V_fixture_min=   1.1400
V_fixture_max=   1.2600
|time   V(typ)   V(min)   V(max)
0s        1.2V       1.14V      1.26V
505.1ps   1.2V       1.14V      1.261V
606.1ps   1.2V       1.14V      488.4mV
808.1ps   1.176V     1.14V      275.1mV
909.1ps   553.3mV    1.14V      267mV
1.111ns   330.1mV    1.14V      260.4mV
1.313ns   315.7mV    1.069V     258.6mV
1.515ns   310.3mV    473.3mV    258.1mV
1.717ns   308.1mV    398mV      257.9mV
10ns      306.6mV    376.2mV    257.8mV
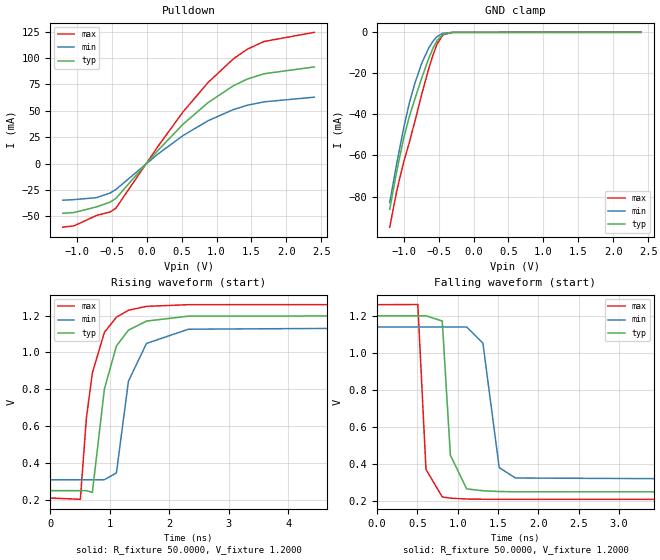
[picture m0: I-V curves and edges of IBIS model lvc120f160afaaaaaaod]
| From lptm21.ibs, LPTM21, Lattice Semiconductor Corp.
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|   Model lvc120f160afaaaaaaod
[Model]   lvc120f160afaaaaaaod
Model_type   I/O_open_drain
Polarity   Non-Inverting
Enable   Active-Low
Vinl =   0.4200V
Vinh =   0.7800V
Vmeas =   0.6000V
Cref =   0.0F
Rref =   1.0000M
Vref =   0.0V
C_comp   4.2000pF   3.8000pF   7.5000pF
[Temperature Range]   25.0000   0.1050k   -40.0000
[Voltage Range]   1.2000V   1.1400V   1.2600V
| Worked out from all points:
|   slope of the pulldown table from 0 to 0.18 V, typ, clamps not added: 13 ohm
|   GND clamp passes 1 mA (typ) near -0.44 V on its own axis
|   rising waveform, R_fixture 50.0000, V_fixture 1.2000: 20-80 % time 301ps typ, 298ps min, 282ps max; typ from 0.25 V to 1.2 V
|   falling waveform, R_fixture 50.0000, V_fixture 1.2000: 20-80 % time 83.9ps typ, 136ps min, 71.5ps max; typ from 1.2 V to 0.25 V
[Pulldown]
|Voltage   I(typ)   I(min)   I(max)
-1.2V     -47.17mA   -34.75mA   -60.31mA
-1.04V    -46.43mA   -34.21mA   -59.06mA
-720mV    -41.11mA   -32.38mA   -49.29mA
-520mV    -36.49mA   -27.87mA   -45.84mA
-440mV    -33.02mA   -24.56mA   -42.27mA
160mV     12.36mA    8.907mA    16.07mA
520mV     37.22mA    26.5mA     48.93mA
880mV     57.8mA     40.62mA    76.89mA
1.24V     73.68mA    51.13mA    99.18mA
1.44V     80.05mA    55.23mA    108.4mA
1.68V     85.13mA    58.5mA     115.7mA
2.4V      91.58mA    62.9mA     124.4mA
[GND_clamp]
|Voltage   I(typ)   I(min)   I(max)
-1.2V     -86.19mA   -82.94mA   -94.91mA
-1.1V     -67.71mA   -63.95mA   -77.28mA
-1V       -51.52mA   -46.57mA   -63.21mA
-920mV    -41.11mA   -34.53mA   -53.74mA
-840mV    -32.47mA   -24.81mA   -43.38mA
-740mV    -22.05mA   -14.9mA    -29.96mA
-640mV    -12.58mA   -7.515mA   -17.52mA
-580mV    -7.752mA   -4.29mA    -10.99mA
-520mV    -3.927mA   -2.008mA   -5.609mA
-440mV    -951.3uA   -477uA     -1.256mA
-300mV    -18.83uA   -15.98uA   -16.74uA
2.4V      0A         0A         0A
[Ramp]
| variable   typ   min   max
dV/dt_r  0.5698/0.2980n   0.4984/0.2952n   0.6296/0.2796n
dV/dt_f  0.5698/83.0919p   0.4984/0.1343n   0.6295/70.8316p
R_load = 50.0000
[Rising Waveform]
R_fixture=   50.0000
V_fixture=   1.2000
V_fixture_min=   1.1400
V_fixture_max=   1.2600
|time   V(typ)   V(min)   V(max)
0s        250.4mV    309.3mV    210.7mV
505.1ps   250.4mV    309.3mV    203.4mV
606.1ps   250.8mV    309.3mV    643.2mV
707.1ps   241.1mV    309.3mV    889.3mV
909.1ps   801.6mV    309.7mV    1.109V
1.111ns   1.035V     346.6mV    1.191V
1.313ns   1.121V     844.3mV    1.229V
1.616ns   1.17V      1.049V     1.25V
2.323ns   1.197V     1.126V     1.259V
10ns      1.2V       1.14V      1.26V
[Falling Waveform]
R_fixture=   50.0000
V_fixture=   1.2000
V_fixture_min=   1.1400
V_fixture_max=   1.2600
|time   V(typ)   V(min)   V(max)
0s        1.2V       1.14V      1.26V
505.1ps   1.2V       1.14V      1.261V
606.1ps   1.2V       1.14V      372.3mV
808.1ps   1.172V     1.14V      223.6mV
909.1ps   448.8mV    1.14V      217.2mV
1.111ns   267mV      1.14V      212.5mV
1.313ns   257.1mV    1.053V     211.2mV
1.515ns   253mV      382mV      210.9mV
1.717ns   251.5mV    325.7mV    210.8mV
10ns      250.3mV    309.3mV    210.8mV
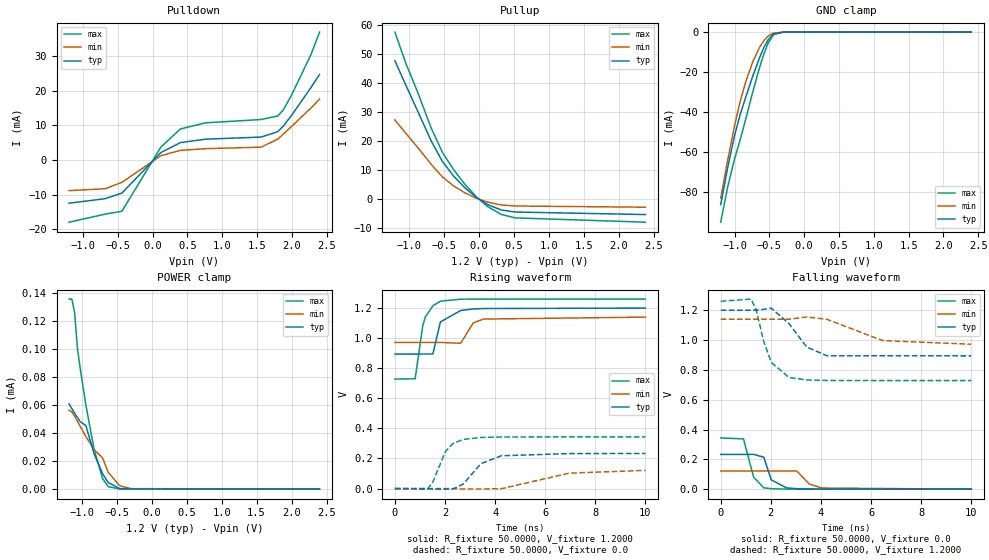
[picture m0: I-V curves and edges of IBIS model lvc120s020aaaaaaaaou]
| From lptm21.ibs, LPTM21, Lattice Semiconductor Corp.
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|   Model lvc120s020aaaaaaaaou
[Model]   lvc120s020aaaaaaaaou
Model_type   Output
Polarity   Non-Inverting
Enable   Active-Low
Vmeas =   0.6000V
Cref =   0.0F
Rref =   1.0000M
Vref =   0.0V
C_comp   4.2000pF   3.8000pF   7.5000pF
[Temperature Range]   25.0000   0.1050k   -40.0000
[Voltage Range]   1.2000V   1.1400V   1.2600V
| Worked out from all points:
|   slope of the pulldown table from 0 to 0.18 V, typ, clamps not added: 60.4 ohm
|   slope of the pullup table from 0 to 0.18 V, typ, clamps not added: 72.7 ohm
|   GND clamp passes 1 mA (typ) near -0.44 V on its own axis
|   rising waveform, R_fixture 50.0000, V_fixture 1.2000: 20-80 % time 314ps typ, 361ps min, 325ps max; typ from 0.894 V to 1.2 V
|   rising waveform, R_fixture 50.0000, V_fixture 0.0: 20-80 % time 802ps typ, 1.53ns min, 577ps max; typ from 0 V to 0.233 V
|   falling waveform, R_fixture 50.0000, V_fixture 0.0: 20-80 % time 318ps typ, 415ps min, 320ps max; typ from 0.233 V to 0 V
|   falling waveform, R_fixture 50.0000, V_fixture 1.2000: 20-80 % time 793ps typ, 1.33ns min, 586ps max; typ from 1.2 V to 0.894 V
[Pulldown]
|Voltage   I(typ)   I(min)   I(max)
-1.2V     -12.49mA   -8.854mA   -17.97mA
-680mV    -11.18mA   -8.31mA    -15.64mA
-440mV    -9.56mA    -6.459mA   -14.81mA
120mV     2.13mA     1.226mA    3.733mA
400mV     5.009mA    2.767mA    8.943mA
760mV     5.996mA    3.254mA    10.71mA
1.56V     6.602mA    3.693mA    11.67mA
1.8V      8.173mA    6.027mA    12.69mA
1.88V     9.796mA    7.482mA    14.48mA
2V        12.92mA    9.725mA    18.81mA
2.28V     21.01mA    15.06mA    30.57mA
2.4V      24.69mA    17.53mA    36.91mA
[Pullup]
|Voltage   I(typ)   I(min)   I(max)
-1.2V     47.59mA    27.24mA    57.45mA
-1.04V    39.03mA    22.59mA    46.51mA
-880mV    30.6mA     17.97mA    37.16mA
-680mV    19.99mA    12mA       24.41mA
-520mV    12.95mA    7.652mA    16.09mA
-360mV    7.951mA    4.572mA    10.14mA
-200mV    3.954mA    2.226mA    5.162mA
-40mV     694.9uA    381.9uA    933uA
120mV     -1.773mA   -961.4uA   -2.432mA
320mV     -3.686mA   -1.972mA   -5.2mA
520mV     -4.384mA   -2.311mA   -6.401mA
2.38V     -5.256mA   -2.733mA   -7.878mA
[GND_clamp]
|Voltage   I(typ)   I(min)   I(max)
-1.2V     -86.07mA   -82.81mA   -94.84mA
-1.1V     -67.62mA   -63.85mA   -77.22mA
-1V       -51.44mA   -46.49mA   -63.16mA
-920mV    -41.05mA   -34.47mA   -53.69mA
-840mV    -32.43mA   -24.76mA   -43.33mA
-740mV    -22.02mA   -14.88mA   -29.93mA
-640mV    -12.55mA   -7.499mA   -17.49mA
-580mV    -7.732mA   -4.278mA   -10.96mA
-520mV    -3.911mA   -2mA       -5.586mA
-440mV    -943.9uA   -474.2uA   -1.243mA
-300mV    -18.55uA   -15.85uA   -16.32uA
2.4V      0A         0A         0A
[POWER_clamp]
|Voltage   I(typ)   I(min)   I(max)
-1.18V    60.64uA    56.26uA    135.4uA
-1.14V    57.31uA    54.99uA    135.4uA
-1.1V     54.11uA    52uA       125.7uA
-1.06V    51.03uA    48.39uA    100.1uA
-1.02V    48.09uA    44.69uA    85.81uA
-940mV    45.28uA    37.56uA    59.84uA
-820mV    24.89uA    27.99uA    27.91uA
-700mV    10.88uA    22.15uA    7.486uA
-620mV    4.732uA    12.01uA    1.785uA
-460mV    414.6nA    2.531uA    157.8nA
-300mV    126.5nA    365.7nA    157.8nA
2.4V      -20.81nA   -18.5nA    -25.04nA
[Ramp]
| variable   typ   min   max
dV/dt_r  0.1165/0.8416n   72.6656m/1.5158n   0.2061/0.5713n
dV/dt_f  0.1956/0.8992n   0.1008/1.4168n   0.3189/0.5805n
R_load = 50.0000
[Rising Waveform]
R_fixture=   50.0000
V_fixture=   1.2000
V_fixture_min=   1.1400
V_fixture_max=   1.2600
|time   V(typ)   V(min)   V(max)
0s        894.1mV    971.4mV    728.4mV
808.1ps   894.1mV    971.4mV    729.9mV
1.111ns   894.6mV    971.4mV    1.081V
1.212ns   894.8mV    971.4mV    1.14V
1.515ns   894.9mV    971.4mV    1.215V
1.818ns   1.108V     971.7mV    1.246V
2.626ns   1.184V     966mV      1.259V
3.131ns   1.194V     1.102V     1.26V
3.535ns   1.197V     1.127V     1.26V
10ns      1.2V       1.14V      1.26V
[Rising Waveform]
R_fixture=   50.0000
V_fixture=   0.0
V_fixture_min=   0.0
V_fixture_max=   0.0
|time   V(typ)   V(min)   V(max)
0s        481.1nV    691.4nV    368.7nV
1.313ns   -390.8uV   1.767uV    -2.199mV
1.515ns   -3.162mV   10.89uV    44mV
2.02ns    -3.918mV   -153.5uV   247.7mV
2.323ns   -2.339mV   -298uV     299.9mV
2.727ns   29.79mV    -2.742mV   326.8mV
3.434ns   165.6mV    -2.355mV   340mV
4.242ns   217.8mV    -1.019mV   342.9mV
6.97ns    232.9mV    102.7mV    343.6mV
10ns      233mV      121.1mV    343.6mV
[Falling Waveform]
R_fixture=   50.0000
V_fixture=   0.0
V_fixture_min=   0.0
V_fixture_max=   0.0
|time   V(typ)   V(min)   V(max)
0s        233mV      121.8mV    343.6mV
909.1ps   233mV      121.8mV    337.1mV
1.313ns   233.4mV    121.8mV    81.19mV
1.717ns   214.4mV    121.8mV    9.228mV
2.02ns    62.32mV    121.7mV    2.953mV
2.626ns   8.825mV    121.5mV    478.3uV
3.03ns    3.152mV    122.6mV    155uV
3.535ns   1.157mV    34.4mV     41.61uV
4.04ns    459.7uV    7.434mV    18.66uV
10ns      20.93uV    682.7nV    25.58uV
[Falling Waveform]
R_fixture=   50.0000
V_fixture=   1.2000
V_fixture_min=   1.1400
V_fixture_max=   1.2600
|time   V(typ)   V(min)   V(max)
0s        1.2V       1.14V      1.26V
1.212ns   1.2V       1.14V      1.275V
1.414ns   1.201V     1.14V      1.204V
1.717ns   1.206V     1.14V      990.9mV
2.02ns    1.214V     1.14V      849.8mV
2.727ns   1.11V      1.14V      749.1mV
3.434ns   953.1mV    1.155V     732.4mV
4.242ns   894.3mV    1.139V     729.1mV
6.465ns   894.7mV    996.5mV    728.4mV
10ns      894.1mV    972.1mV    728.4mV
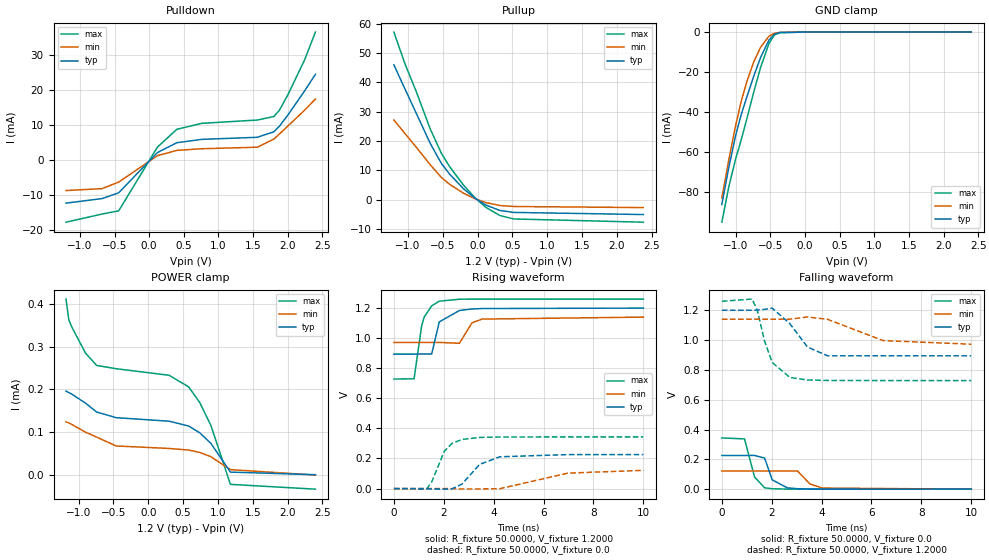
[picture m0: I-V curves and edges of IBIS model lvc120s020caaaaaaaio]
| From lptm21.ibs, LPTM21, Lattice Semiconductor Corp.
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|   Model lvc120s020caaaaaaaio
[Model]   lvc120s020caaaaaaaio
Model_type   I/O
Polarity   Non-Inverting
Enable   Active-Low
Vinl =   0.4200V
Vinh =   0.7800V
Vmeas =   0.6000V
Cref =   0.0F
Rref =   1.0000M
Vref =   0.0V
C_comp   4.2000pF   3.8000pF   7.5000pF
[Temperature Range]   25.0000   0.1050k   -40.0000
[Voltage Range]   1.2000V   1.1400V   1.2600V
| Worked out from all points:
|   slope of the pulldown table from 0 to 0.18 V, typ, clamps not added: 61.4 ohm
|   slope of the pullup table from 0 to 0.18 V, typ, clamps not added: 75 ohm
|   GND clamp passes 1 mA (typ) near -0.44 V on its own axis
|   rising waveform, R_fixture 50.0000, V_fixture 1.2000: 20-80 % time 314ps typ, 361ps min, 325ps max; typ from 0.894 V to 1.2 V
|   rising waveform, R_fixture 50.0000, V_fixture 0.0: 20-80 % time 811ps typ, 1.53ns min, 577ps max; typ from 0 V to 0.226 V
|   falling waveform, R_fixture 50.0000, V_fixture 0.0: 20-80 % time 324ps typ, 415ps min, 320ps max; typ from 0.226 V to 0 V
|   falling waveform, R_fixture 50.0000, V_fixture 1.2000: 20-80 % time 793ps typ, 1.33ns min, 586ps max; typ from 1.2 V to 0.894 V
[Pulldown]
|Voltage   I(typ)   I(min)   I(max)
-1.2V     -12.42mA   -8.806mA   -17.89mA
-680mV    -11.12mA   -8.26mA    -15.55mA
-440mV    -9.458mA   -6.389mA   -14.64mA
120mV     2.099mA    1.208mA    3.67mA
400mV     4.924mA    2.722mA    8.774mA
760mV     5.881mA    3.195mA    10.48mA
1.56V     6.478mA    3.628mA    11.43mA
1.8V      8.048mA    5.963mA    12.44mA
1.88V     9.671mA    7.418mA    14.24mA
2V        12.79mA    9.659mA    18.58mA
2.24V     19.69mA    14.2mA     28.54mA
2.4V      24.56mA    17.46mA    36.67mA
[Pullup]
|Voltage   I(typ)   I(min)   I(max)
-1.2V     46.01mA    27.17mA    57.21mA
-1.04V    37.7mA     22.53mA    46.27mA
-880mV    29.53mA    17.9mA     36.93mA
-680mV    19.24mA    11.93mA    24.17mA
-520mV    12.4mA     7.587mA    15.85mA
-400mV    8.649mA    5.186mA    11.22mA
-200mV    3.684mA    2.163mA    4.918mA
-40mV     523.1uA    319.2uA    689.8uA
120mV     -1.869mA   -1.023mA   -2.673mA
320mV     -3.721mA   -2.032mA   -5.436mA
520mV     -4.389mA   -2.367mA   -6.629mA
2.38V     -5.119mA   -2.743mA   -7.729mA
[GND_clamp]
|Voltage   I(typ)   I(min)   I(max)
-1.2V     -86.12mA   -82.85mA   -94.91mA
-1.1V     -67.67mA   -63.89mA   -77.29mA
-1V       -51.5mA    -46.53mA   -63.23mA
-920mV    -41.11mA   -34.51mA   -53.77mA
-840mV    -32.49mA   -24.81mA   -43.41mA
-740mV    -22.08mA   -14.92mA   -30.01mA
-640mV    -12.62mA   -7.552mA   -17.58mA
-520mV    -4.002mA   -2.066mA   -5.717mA
-440mV    -1.052mA   -544.2uA   -1.412mA
-360mV    -224.4uA   -137uA     -297.4uA
0V        0A         0A         0A
2.4V      0A         0A         0A
[POWER_clamp]
|Voltage   I(typ)   I(min)   I(max)
-1.18V    195.7uA    123.7uA    411.4uA
-1.14V    192.3uA    121.4uA    363.5uA
-1.1V     189uA      117.9uA    346.9uA
-900mV    167.7uA    99.59uA    284.8uA
-740mV    146.7uA    87.99uA    255.9uA
-460mV    133.5uA    67.27uA    248.2uA
300mV     125.3uA    61.39uA    232.9uA
580mV     114uA      57.74uA    205.7uA
740mV     98.07uA    52.14uA    168.9uA
900mV     73.23uA    42.07uA    115uA
1.18V     6.005uA    11.83uA    -22.68uA
2.4V      -20.2nA    -1.007uA   -33.94uA
[Ramp]
| variable   typ   min   max
dV/dt_r  0.1165/0.8416n   72.6656m/1.5158n   0.2061/0.5713n
dV/dt_f  0.1956/0.8992n   0.1008/1.4168n   0.3189/0.5805n
R_load = 50.0000
[Rising Waveform]
R_fixture=   50.0000
V_fixture=   1.2000
V_fixture_min=   1.1400
V_fixture_max=   1.2600
|time   V(typ)   V(min)   V(max)
0s        894.1mV    971.4mV    728.4mV
808.1ps   894.1mV    971.4mV    729.9mV
1.111ns   894.6mV    971.4mV    1.081V
1.212ns   894.8mV    971.4mV    1.14V
1.515ns   894.9mV    971.4mV    1.215V
1.818ns   1.108V     971.7mV    1.246V
2.626ns   1.184V     966mV      1.259V
3.131ns   1.194V     1.102V     1.26V
3.535ns   1.197V     1.127V     1.26V
10ns      1.2V       1.14V      1.26V
[Rising Waveform]
R_fixture=   50.0000
V_fixture=   0.0
V_fixture_min=   0.0
V_fixture_max=   0.0
|time   V(typ)   V(min)   V(max)
0s        481.1nV    691.4nV    368.7nV
1.313ns   -390.8uV   1.767uV    -2.199mV
1.515ns   -3.162mV   10.89uV    44mV
2.02ns    -3.918mV   -153.5uV   247.7mV
2.323ns   -2.339mV   -298uV     299.9mV
2.727ns   29.79mV    -2.742mV   326.8mV
3.434ns   160.6mV    -2.355mV   340mV
4.242ns   211.3mV    -1.019mV   342.9mV
6.97ns    225.9mV    102.7mV    343.6mV
10ns      226mV      121.1mV    343.6mV
[Falling Waveform]
R_fixture=   50.0000
V_fixture=   0.0
V_fixture_min=   0.0
V_fixture_max=   0.0
|time   V(typ)   V(min)   V(max)
0s        226mV      121.8mV    343.6mV
909.1ps   226mV      121.8mV    337.1mV
1.313ns   226.4mV    121.8mV    81.19mV
1.717ns   208mV      121.8mV    9.228mV
2.02ns    62.32mV    121.7mV    2.953mV
2.626ns   8.825mV    121.5mV    478.3uV
3.03ns    3.152mV    122.6mV    155uV
3.535ns   1.157mV    34.4mV     41.61uV
4.04ns    459.7uV    7.434mV    18.66uV
10ns      20.93uV    682.7nV    25.58uV
[Falling Waveform]
R_fixture=   50.0000
V_fixture=   1.2000
V_fixture_min=   1.1400
V_fixture_max=   1.2600
|time   V(typ)   V(min)   V(max)
0s        1.2V       1.14V      1.26V
1.212ns   1.2V       1.14V      1.275V
1.414ns   1.201V     1.14V      1.204V
1.717ns   1.206V     1.14V      990.9mV
2.02ns    1.214V     1.14V      849.8mV
2.727ns   1.11V      1.14V      749.1mV
3.434ns   953.1mV    1.155V     732.4mV
4.242ns   894.3mV    1.139V     729.1mV
6.465ns   894.7mV    996.5mV    728.4mV
10ns      894.1mV    972.1mV    728.4mV
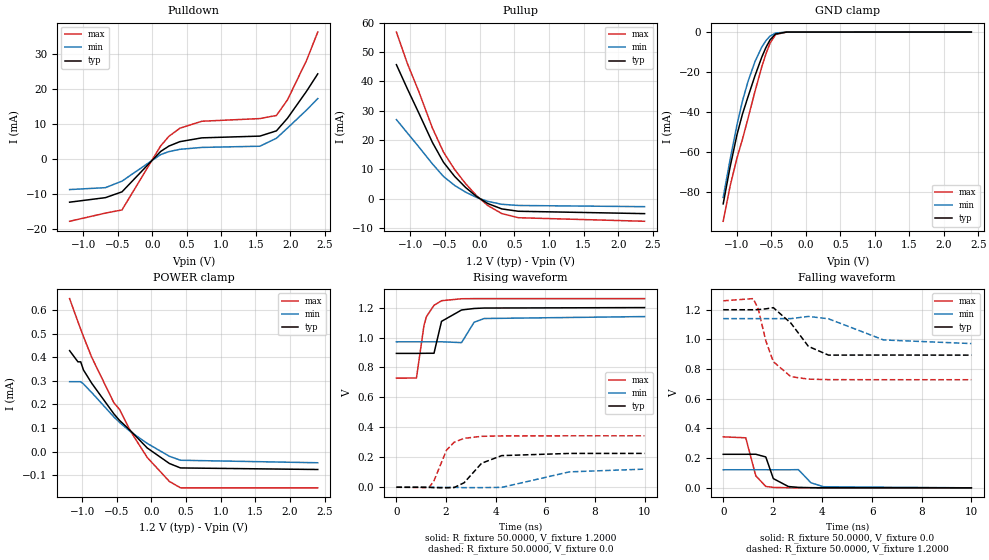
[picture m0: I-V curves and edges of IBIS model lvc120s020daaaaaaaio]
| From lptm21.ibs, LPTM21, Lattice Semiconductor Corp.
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|   Model lvc120s020daaaaaaaio
[Model]   lvc120s020daaaaaaaio
Model_type   I/O
Polarity   Non-Inverting
Enable   Active-Low
Vinl =   0.4200V
Vinh =   0.7800V
Vmeas =   0.6000V
Cref =   0.0F
Rref =   1.0000M
Vref =   0.0V
C_comp   4.2000pF   3.8000pF   7.5000pF
[Temperature Range]   25.0000   0.1050k   -40.0000
[Voltage Range]   1.2000V   1.1400V   1.2600V
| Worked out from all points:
|   slope of the pulldown table from 0 to 0.18 V, typ, clamps not added: 61.4 ohm
|   slope of the pullup table from 0 to 0.18 V, typ, clamps not added: 75.5 ohm
|   GND clamp passes 1 mA (typ) near -0.44 V on its own axis
|   rising waveform, R_fixture 50.0000, V_fixture 1.2000: 20-80 % time 314ps typ, 361ps min, 325ps max; typ from 0.894 V to 1.2 V
|   rising waveform, R_fixture 50.0000, V_fixture 0.0: 20-80 % time 811ps typ, 1.53ns min, 577ps max; typ from 0 V to 0.226 V
|   falling waveform, R_fixture 50.0000, V_fixture 0.0: 20-80 % time 324ps typ, 415ps min, 320ps max; typ from 0.226 V to 0 V
|   falling waveform, R_fixture 50.0000, V_fixture 1.2000: 20-80 % time 793ps typ, 1.33ns min, 586ps max; typ from 1.2 V to 0.894 V
[Pulldown]
|Voltage   I(typ)   I(min)   I(max)
-1.2V     -12.42mA   -8.806mA   -17.89mA
-680mV    -11.12mA   -8.26mA    -15.55mA
-440mV    -9.458mA   -6.389mA   -14.64mA
120mV     2.099mA    1.208mA    3.67mA
240mV     3.65mA     2.064mA    6.447mA
400mV     4.924mA    2.722mA    8.774mA
720mV     6.01mA     3.27mA     10.77mA
1.56V     6.508mA    3.61mA     11.53mA
1.8V      8.006mA    5.887mA    12.42mA
1.96V     11.61mA    8.8mA      16.86mA
2.24V     19.44mA    14.02mA    28.31mA
2.4V      24.34mA    17.26mA    36.32mA
[Pullup]
|Voltage   I(typ)   I(min)   I(max)
-1.2V     45.73mA    26.98mA    56.86mA
-1.04V    37.4mA     22.36mA    46.01mA
-880mV    29.38mA    17.76mA    36.74mA
-680mV    19.16mA    11.85mA    24.08mA
-520mV    12.38mA    7.545mA    15.84mA
-360mV    7.596mA    4.502mA    9.941mA
-200mV    3.773mA    2.188mA    5.067mA
-40mV     662.5uA    375.2uA    915.1uA
120mV     -1.689mA   -943.7uA   -2.383mA
320mV     -3.507mA   -1.933mA   -5.087mA
560mV     -4.313mA   -2.334mA   -6.518mA
2.38V     -5.119mA   -2.743mA   -7.729mA
[GND_clamp]
|Voltage   I(typ)   I(min)   I(max)
-1.2V     -86.05mA   -82.8mA    -94.75mA
-1.1V     -67.59mA   -63.84mA   -77.13mA
-1V       -51.42mA   -46.49mA   -63.08mA
-920mV    -41.03mA   -34.46mA   -53.61mA
-840mV    -32.42mA   -24.76mA   -43.26mA
-740mV    -22.01mA   -14.88mA   -29.85mA
-640mV    -12.55mA   -7.505mA   -17.43mA
-580mV    -7.735mA   -4.289mA   -10.91mA
-520mV    -3.926mA   -2.018mA   -5.563mA
-440mV    -975.9uA   -496.4uA   -1.258mA
-280mV    -21.15uA   -10.37uA   -5.4uA
2.4V      0A         0A         0A
[POWER_clamp]
|Voltage   I(typ)   I(min)   I(max)
-1.18V    428.9uA    296.9uA    650.2uA
-1.06V    381.4uA    296.9uA    551.8uA
-1.02V    381.4uA    296.9uA    520uA
-980mV    346.6uA    287.3uA    488.9uA
-860mV    289.9uA    250.4uA    400uA
-540mV    159.6uA    146.6uA    206.4uA
-460mV    132.4uA    123.9uA    179.3uA
-300mV    88.01uA    83.86uA    85.61uA
-60mV     15.09uA    34.5uA     -25.38uA
260mV     -50.94uA   -20.29uA   -127.3uA
420mV     -69.79uA   -37.12uA   -154.4uA
2.4V      -76.46uA   -47.78uA   -154.4uA
[Ramp]
| variable   typ   min   max
dV/dt_r  0.1165/0.8416n   72.6656m/1.5158n   0.2061/0.5713n
dV/dt_f  0.1956/0.8992n   0.1008/1.4168n   0.3189/0.5805n
R_load = 50.0000
[Rising Waveform]
R_fixture=   50.0000
V_fixture=   1.2000
V_fixture_min=   1.1400
V_fixture_max=   1.2600
|time   V(typ)   V(min)   V(max)
0s        894.1mV    971.4mV    728.4mV
808.1ps   894.1mV    971.4mV    729.9mV
1.111ns   894.6mV    971.4mV    1.081V
1.212ns   894.8mV    971.4mV    1.14V
1.515ns   894.9mV    971.4mV    1.215V
1.818ns   1.108V     971.7mV    1.246V
2.626ns   1.184V     966mV      1.259V
3.131ns   1.194V     1.102V     1.26V
3.535ns   1.197V     1.127V     1.26V
10ns      1.2V       1.14V      1.26V
[Rising Waveform]
R_fixture=   50.0000
V_fixture=   0.0
V_fixture_min=   0.0
V_fixture_max=   0.0
|time   V(typ)   V(min)   V(max)
0s        481.1nV    691.4nV    368.7nV
1.313ns   -390.8uV   1.767uV    -2.199mV
1.515ns   -3.162mV   10.89uV    44mV
2.02ns    -3.918mV   -153.5uV   247.7mV
2.323ns   -2.339mV   -298uV     299.9mV
2.727ns   29.79mV    -2.742mV   326.8mV
3.434ns   160.6mV    -2.355mV   340mV
4.242ns   211.3mV    -1.019mV   342.9mV
6.97ns    225.9mV    102.7mV    343.6mV
10ns      226mV      121.1mV    343.6mV
[Falling Waveform]
R_fixture=   50.0000
V_fixture=   0.0
V_fixture_min=   0.0
V_fixture_max=   0.0
|time   V(typ)   V(min)   V(max)
0s        226mV      121.8mV    343.6mV
909.1ps   226mV      121.8mV    337.1mV
1.313ns   226.4mV    121.8mV    81.19mV
1.717ns   208mV      121.8mV    9.228mV
2.02ns    62.32mV    121.7mV    2.953mV
2.626ns   8.825mV    121.5mV    478.3uV
3.03ns    3.152mV    122.6mV    155uV
3.535ns   1.157mV    34.4mV     41.61uV
4.04ns    459.7uV    7.434mV    18.66uV
10ns      20.93uV    682.7nV    25.58uV
[Falling Waveform]
R_fixture=   50.0000
V_fixture=   1.2000
V_fixture_min=   1.1400
V_fixture_max=   1.2600
|time   V(typ)   V(min)   V(max)
0s        1.2V       1.14V      1.26V
1.212ns   1.2V       1.14V      1.275V
1.414ns   1.201V     1.14V      1.204V
1.717ns   1.206V     1.14V      990.9mV
2.02ns    1.214V     1.14V      849.8mV
2.727ns   1.11V      1.14V      749.1mV
3.434ns   953.1mV    1.155V     732.4mV
4.242ns   894.3mV    1.139V     729.1mV
6.465ns   894.7mV    996.5mV    728.4mV
10ns      894.1mV    972.1mV    728.4mV
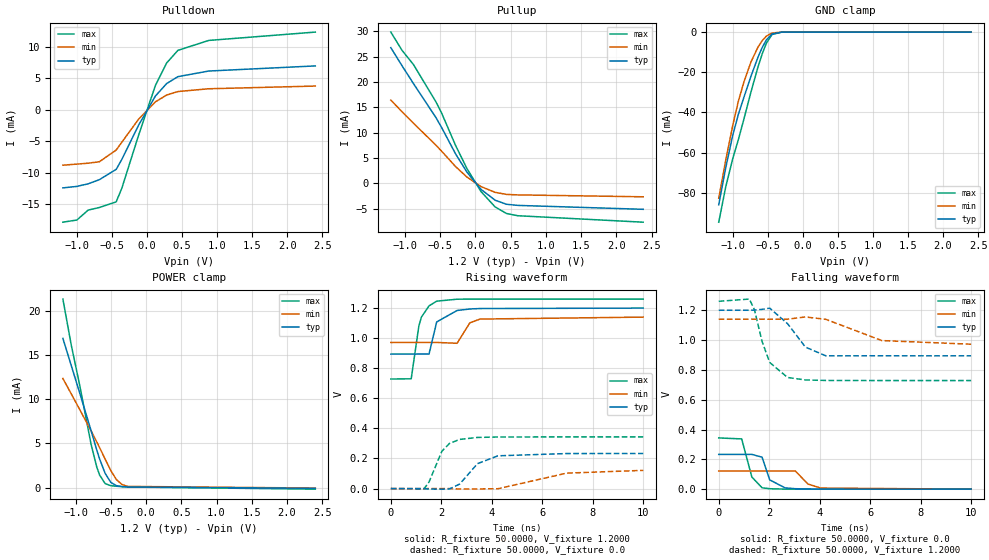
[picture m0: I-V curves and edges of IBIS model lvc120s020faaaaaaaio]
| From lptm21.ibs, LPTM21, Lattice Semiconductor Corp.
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|   Model lvc120s020faaaaaaaio
[Model]   lvc120s020faaaaaaaio
Model_type   I/O
Polarity   Non-Inverting
Enable   Active-Low
Vinl =   0.4200V
Vinh =   0.7800V
Vmeas =   0.6000V
Cref =   0.0F
Rref =   1.0000M
Vref =   0.0V
C_comp   4.2000pF   3.8000pF   7.5000pF
[Temperature Range]   25.0000   0.1050k   -40.0000
[Voltage Range]   1.2000V   1.1400V   1.2600V
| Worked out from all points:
|   slope of the pulldown table from 0 to 0.18 V, typ, clamps not added: 60.5 ohm
|   slope of the pullup table from 0 to 0.18 V, typ, clamps not added: 73.2 ohm
|   GND clamp passes 1 mA (typ) near -0.44 V on its own axis
|   POWER clamp passes 1 mA (typ) near -0.54 V on its own axis
|   rising waveform, R_fixture 50.0000, V_fixture 1.2000: 20-80 % time 314ps typ, 361ps min, 325ps max; typ from 0.894 V to 1.2 V
|   rising waveform, R_fixture 50.0000, V_fixture 0.0: 20-80 % time 802ps typ, 1.53ns min, 577ps max; typ from 0 V to 0.233 V
|   falling waveform, R_fixture 50.0000, V_fixture 0.0: 20-80 % time 318ps typ, 415ps min, 320ps max; typ from 0.233 V to 0 V
|   falling waveform, R_fixture 50.0000, V_fixture 1.2000: 20-80 % time 793ps typ, 1.33ns min, 586ps max; typ from 1.2 V to 0.894 V
[Pulldown]
|Voltage   I(typ)   I(min)   I(max)
-1.2V     -12.45mA   -8.826mA   -17.92mA
-1V       -12.21mA   -8.655mA   -17.57mA
-840mV    -11.8mA    -8.509mA   -15.99mA
-680mV    -11.14mA   -8.281mA   -15.58mA
-440mV    -9.494mA   -6.411mA   -14.67mA
-360mV    -7.921mA   -5.171mA   -12.52mA
-120mV    -2.44mA    -1.487mA   -4.04mA
120mV     2.209mA    1.278mA    3.907mA
280mV     4.192mA    2.363mA    7.476mA
440mV     5.289mA    2.918mA    9.483mA
880mV     6.189mA    3.36mA     11.07mA
2.4V      7.005mA    3.792mA    12.4mA
[Pullup]
|Voltage   I(typ)   I(min)   I(max)
-1.2V     26.75mA    16.4mA     29.82mA
-1.04V    23.16mA    14.1mA     26.2mA
-880mV    19.69mA    11.87mA    23.44mA
-560mV    12.96mA    7.506mA    16.06mA
-480mV    11.01mA    6.337mA    13.86mA
-280mV    5.76mA     3.271mA    7.418mA
-120mV    2.195mA    1.221mA    2.896mA
80mV      -1.213mA   -658.5uA   -1.652mA
280mV     -3.343mA   -1.793mA   -4.674mA
440mV     -4.141mA   -2.193mA   -5.953mA
600mV     -4.365mA   -2.293mA   -6.402mA
2.38V     -5.138mA   -2.671mA   -7.678mA
[GND_clamp]
|Voltage   I(typ)   I(min)   I(max)
-1.2V     -86.02mA   -82.79mA   -94.71mA
-1.1V     -67.56mA   -63.82mA   -77.09mA
-1V       -51.39mA   -46.46mA   -63.03mA
-920mV    -41mA      -34.44mA   -53.57mA
-840mV    -32.38mA   -24.74mA   -43.21mA
-740mV    -21.97mA   -14.85mA   -29.81mA
-640mV    -12.51mA   -7.478mA   -17.38mA
-580mV    -7.694mA   -4.26mA    -10.86mA
-520mV    -3.881mA   -1.989mA   -5.509mA
-440mV    -930.4uA   -470.4uA   -1.205mA
-300mV    -18.88uA   -16.34uA   -15.3uA
2.4V      0A         0A         0A
[POWER_clamp]
|Voltage   I(typ)   I(min)   I(max)
-1.18V    16.9mA     12.36mA    21.36mA
-1.06V    13.79mA    10.6mA     16.09mA
-940mV    10.69mA    8.822mA    11.54mA
-780mV    6.439mA    6.432mA    4.901mA
-700mV    4.263mA    5.185mA    2.349mA
-660mV    3.26mA     4.54mA     1.432mA
-580mV    1.601mA    3.213mA    447.8uA
-500mV    588.9uA    1.919mA    217.5uA
-420mV    211.3uA    900.6uA    152uA
-340mV    113.8uA    341.1uA    106.5uA
-260mV    75.42uA    135.6uA    65.45uA
2.4V      -83.82uA   -52.45uA   -176.9uA
[Ramp]
| variable   typ   min   max
dV/dt_r  0.1165/0.8416n   72.6656m/1.5158n   0.2061/0.5713n
dV/dt_f  0.1956/0.8992n   0.1008/1.4168n   0.3189/0.5805n
R_load = 50.0000
[Rising Waveform]
R_fixture=   50.0000
V_fixture=   1.2000
V_fixture_min=   1.1400
V_fixture_max=   1.2600
|time   V(typ)   V(min)   V(max)
0s        894.1mV    971.4mV    728.4mV
808.1ps   894.1mV    971.4mV    729.9mV
1.111ns   894.6mV    971.4mV    1.081V
1.212ns   894.8mV    971.4mV    1.14V
1.515ns   894.9mV    971.4mV    1.215V
1.818ns   1.108V     971.7mV    1.246V
2.626ns   1.184V     966mV      1.259V
3.131ns   1.194V     1.102V     1.26V
3.535ns   1.197V     1.127V     1.26V
10ns      1.2V       1.14V      1.26V
[Rising Waveform]
R_fixture=   50.0000
V_fixture=   0.0
V_fixture_min=   0.0
V_fixture_max=   0.0
|time   V(typ)   V(min)   V(max)
0s        481.1nV    691.4nV    368.7nV
1.313ns   -390.8uV   1.767uV    -2.199mV
1.515ns   -3.162mV   10.89uV    44mV
2.02ns    -3.918mV   -153.5uV   247.7mV
2.323ns   -2.339mV   -298uV     299.9mV
2.727ns   29.79mV    -2.742mV   326.8mV
3.434ns   165.6mV    -2.355mV   340mV
4.242ns   217.8mV    -1.019mV   342.9mV
6.97ns    232.9mV    102.7mV    343.6mV
10ns      233mV      121.1mV    343.6mV
[Falling Waveform]
R_fixture=   50.0000
V_fixture=   0.0
V_fixture_min=   0.0
V_fixture_max=   0.0
|time   V(typ)   V(min)   V(max)
0s        233mV      121.8mV    343.6mV
909.1ps   233mV      121.8mV    337.1mV
1.313ns   233.4mV    121.8mV    81.19mV
1.717ns   214.4mV    121.8mV    9.228mV
2.02ns    62.32mV    121.7mV    2.953mV
2.626ns   8.825mV    121.5mV    478.3uV
3.03ns    3.152mV    122.6mV    155uV
3.535ns   1.157mV    34.4mV     41.61uV
4.04ns    459.7uV    7.434mV    18.66uV
10ns      20.93uV    682.7nV    25.58uV
[Falling Waveform]
R_fixture=   50.0000
V_fixture=   1.2000
V_fixture_min=   1.1400
V_fixture_max=   1.2600
|time   V(typ)   V(min)   V(max)
0s        1.2V       1.14V      1.26V
1.212ns   1.2V       1.14V      1.275V
1.414ns   1.201V     1.14V      1.204V
1.717ns   1.206V     1.14V      990.9mV
2.02ns    1.214V     1.14V      849.8mV
2.727ns   1.11V      1.14V      749.1mV
3.434ns   953.1mV    1.155V     732.4mV
4.242ns   894.3mV    1.139V     729.1mV
6.465ns   894.7mV    996.5mV    728.4mV
10ns      894.1mV    972.1mV    728.4mV
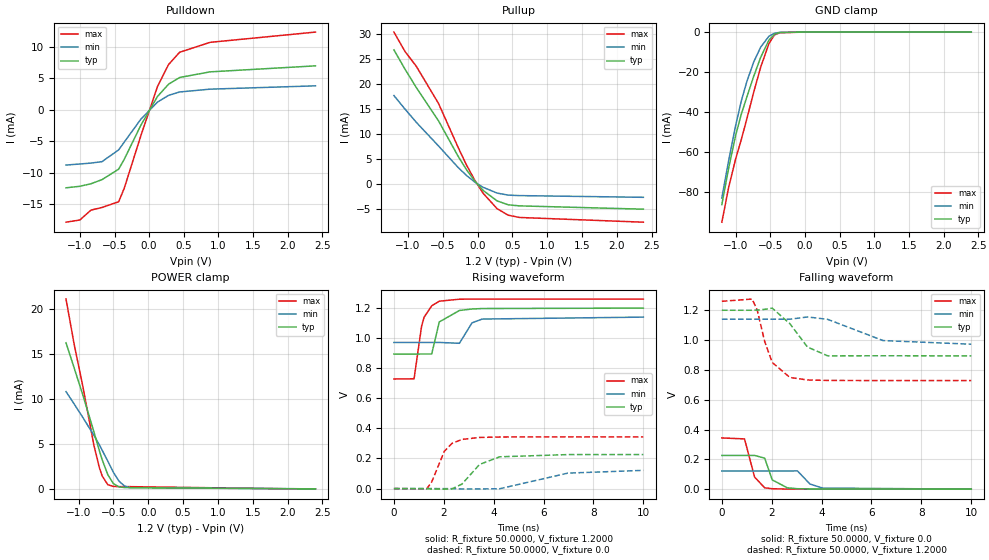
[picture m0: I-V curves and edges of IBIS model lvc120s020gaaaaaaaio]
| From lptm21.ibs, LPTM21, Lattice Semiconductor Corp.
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|   Model lvc120s020gaaaaaaaio
[Model]   lvc120s020gaaaaaaaio
Model_type   I/O
Polarity   Non-Inverting
Enable   Active-Low
Vinl =   0.4200V
Vinh =   0.7800V
Vmeas =   0.6000V
Cref =   0.0F
Rref =   1.0000M
Vref =   0.0V
C_comp   4.2000pF   3.8000pF   7.5000pF
[Temperature Range]   25.0000   0.1050k   -40.0000
[Voltage Range]   1.2000V   1.1400V   1.2600V
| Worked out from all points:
|   slope of the pulldown table from 0 to 0.18 V, typ, clamps not added: 61.4 ohm
|   slope of the pullup table from 0 to 0.18 V, typ, clamps not added: 75 ohm
|   GND clamp passes 1 mA (typ) near -0.44 V on its own axis
|   POWER clamp passes 1 mA (typ) near -0.54 V on its own axis
|   rising waveform, R_fixture 50.0000, V_fixture 1.2000: 20-80 % time 314ps typ, 361ps min, 325ps max; typ from 0.894 V to 1.2 V
|   rising waveform, R_fixture 50.0000, V_fixture 0.0: 20-80 % time 811ps typ, 1.53ns min, 577ps max; typ from 0 V to 0.226 V
|   falling waveform, R_fixture 50.0000, V_fixture 0.0: 20-80 % time 324ps typ, 415ps min, 320ps max; typ from 0.226 V to 0 V
|   falling waveform, R_fixture 50.0000, V_fixture 1.2000: 20-80 % time 793ps typ, 1.33ns min, 586ps max; typ from 1.2 V to 0.894 V
[Pulldown]
|Voltage   I(typ)   I(min)   I(max)
-1.2V     -12.42mA   -8.806mA   -17.89mA
-1V       -12.18mA   -8.636mA   -17.54mA
-840mV    -11.78mA   -8.49mA    -15.97mA
-680mV    -11.12mA   -8.26mA    -15.55mA
-440mV    -9.458mA   -6.389mA   -14.64mA
-360mV    -7.896mA   -5.161mA   -12.51mA
-120mV    -2.484mA   -1.52mA    -4.151mA
120mV     2.099mA    1.208mA    3.67mA
280mV     4.049mA    2.276mA    7.174mA
440mV     5.122mA    2.819mA    9.134mA
880mV     6.016mA    3.265mA    10.71mA
2.4V      6.97mA     3.792mA    12.34mA
[Pullup]
|Voltage   I(typ)   I(min)   I(max)
-1.2V     26.81mA    17.66mA    30.38mA
-1.04V    22.93mA    14.93mA    26.47mA
-880mV    19.29mA    12.31mA    23.55mA
-560mV    12.59mA    7.555mA    16.08mA
-280mV    5.527mA    3.262mA    7.31mA
-160mV    2.826mA    1.656mA    3.789mA
-40mV     523.1uA    319.2uA    689.8uA
80mV      -1.347mA   -732.8uA   -1.927mA
280mV     -3.452mA   -1.889mA   -5.013mA
440mV     -4.242mA   -2.298mA   -6.325mA
600mV     -4.457mA   -2.397mA   -6.782mA
2.38V     -5.119mA   -2.743mA   -7.729mA
[GND_clamp]
|Voltage   I(typ)   I(min)   I(max)
-1.2V     -86.12mA   -82.85mA   -94.91mA
-1.1V     -67.67mA   -63.89mA   -77.29mA
-1V       -51.5mA    -46.53mA   -63.23mA
-920mV    -41.11mA   -34.51mA   -53.77mA
-840mV    -32.49mA   -24.81mA   -43.41mA
-740mV    -22.08mA   -14.92mA   -30.01mA
-640mV    -12.62mA   -7.552mA   -17.58mA
-520mV    -4.002mA   -2.066mA   -5.717mA
-440mV    -1.052mA   -544.2uA   -1.412mA
-360mV    -224.4uA   -137uA     -297.4uA
0V        0A         0A         0A
2.4V      0A         0A         0A
[POWER_clamp]
|Voltage   I(typ)   I(min)   I(max)
-1.18V    16.21mA    10.79mA    21.06mA
-1.06V    13.35mA    9.386mA    15.93mA
-940mV    10.45mA    7.942mA    11.44mA
-780mV    6.343mA    5.946mA    4.852mA
-700mV    4.202mA    4.86mA     2.326mA
-660mV    3.213mA    4.284mA    1.42mA
-580mV    1.577mA    3.065mA    461uA
-500mV    580.8uA    1.84mA     269.7uA
-420mV    220.7uA    858.6uA    248.9uA
-340mV    147uA      315.9uA    245.9uA
-260mV    134.1uA    123.8uA    244.6uA
2.4V      -20.2nA    -1.007uA   -33.94uA
[Ramp]
| variable   typ   min   max
dV/dt_r  0.1165/0.8416n   72.6656m/1.5158n   0.2061/0.5713n
dV/dt_f  0.1956/0.8992n   0.1008/1.4168n   0.3189/0.5805n
R_load = 50.0000
[Rising Waveform]
R_fixture=   50.0000
V_fixture=   1.2000
V_fixture_min=   1.1400
V_fixture_max=   1.2600
|time   V(typ)   V(min)   V(max)
0s        894.1mV    971.4mV    728.4mV
808.1ps   894.1mV    971.4mV    729.9mV
1.111ns   894.6mV    971.4mV    1.081V
1.212ns   894.8mV    971.4mV    1.14V
1.515ns   894.9mV    971.4mV    1.215V
1.818ns   1.108V     971.7mV    1.246V
2.626ns   1.184V     966mV      1.259V
3.131ns   1.194V     1.102V     1.26V
3.535ns   1.197V     1.127V     1.26V
10ns      1.2V       1.14V      1.26V
[Rising Waveform]
R_fixture=   50.0000
V_fixture=   0.0
V_fixture_min=   0.0
V_fixture_max=   0.0
|time   V(typ)   V(min)   V(max)
0s        481.1nV    691.4nV    368.7nV
1.313ns   -390.8uV   1.767uV    -2.199mV
1.515ns   -3.162mV   10.89uV    44mV
2.02ns    -3.918mV   -153.5uV   247.7mV
2.323ns   -2.339mV   -298uV     299.9mV
2.727ns   29.79mV    -2.742mV   326.8mV
3.434ns   160.6mV    -2.355mV   340mV
4.242ns   211.3mV    -1.019mV   342.9mV
6.97ns    225.9mV    102.7mV    343.6mV
10ns      226mV      121.1mV    343.6mV
[Falling Waveform]
R_fixture=   50.0000
V_fixture=   0.0
V_fixture_min=   0.0
V_fixture_max=   0.0
|time   V(typ)   V(min)   V(max)
0s        226mV      121.8mV    343.6mV
909.1ps   226mV      121.8mV    337.1mV
1.313ns   226.4mV    121.8mV    81.19mV
1.717ns   208mV      121.8mV    9.228mV
2.02ns    62.32mV    121.7mV    2.953mV
2.626ns   8.825mV    121.5mV    478.3uV
3.03ns    3.152mV    122.6mV    155uV
3.535ns   1.157mV    34.4mV     41.61uV
4.04ns    459.7uV    7.434mV    18.66uV
10ns      20.93uV    682.7nV    25.58uV
[Falling Waveform]
R_fixture=   50.0000
V_fixture=   1.2000
V_fixture_min=   1.1400
V_fixture_max=   1.2600
|time   V(typ)   V(min)   V(max)
0s        1.2V       1.14V      1.26V
1.212ns   1.2V       1.14V      1.275V
1.414ns   1.201V     1.14V      1.204V
1.717ns   1.206V     1.14V      990.9mV
2.02ns    1.214V     1.14V      849.8mV
2.727ns   1.11V      1.14V      749.1mV
3.434ns   953.1mV    1.155V     732.4mV
4.242ns   894.3mV    1.139V     729.1mV
6.465ns   894.7mV    996.5mV    728.4mV
10ns      894.1mV    972.1mV    728.4mV
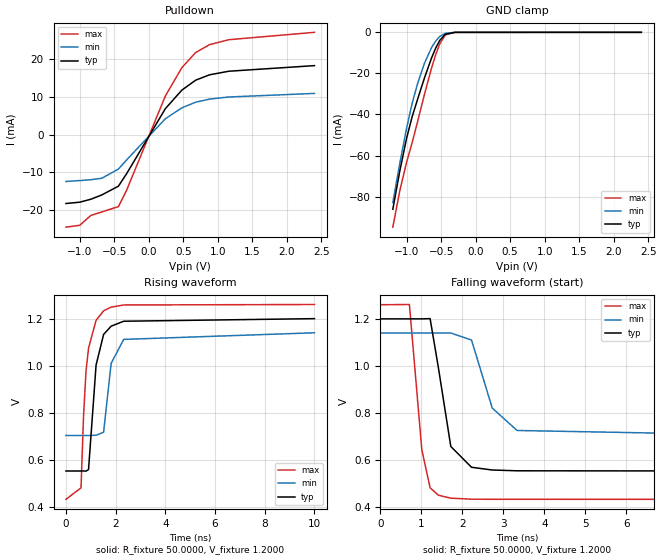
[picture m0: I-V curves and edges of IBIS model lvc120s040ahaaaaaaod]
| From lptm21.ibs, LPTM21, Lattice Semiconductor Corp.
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|   Model lvc120s040ahaaaaaaod
[Model]   lvc120s040ahaaaaaaod
Model_type   I/O_open_drain
Polarity   Non-Inverting
Enable   Active-Low
Vinl =   0.4200V
Vinh =   0.7800V
Vmeas =   0.6000V
Cref =   0.0F
Rref =   1.0000M
Vref =   0.0V
C_comp   4.2000pF   3.8000pF   7.5000pF
[Temperature Range]   25.0000   0.1050k   -40.0000
[Voltage Range]   1.2000V   1.1400V   1.2600V
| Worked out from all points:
|   slope of the pulldown table from 0 to 0.18 V, typ, clamps not added: 33.8 ohm
|   GND clamp passes 1 mA (typ) near -0.44 V on its own axis
|   rising waveform, R_fixture 50.0000, V_fixture 1.2000: 20-80 % time 301ps typ, 304ps min, 299ps max; typ from 0.554 V to 1.2 V
|   falling waveform, R_fixture 50.0000, V_fixture 1.2000: 20-80 % time 321ps typ, 500ps min, 223ps max; typ from 1.2 V to 0.554 V
[Pulldown]
|Voltage   I(typ)   I(min)   I(max)
-1.2V     -18.32mA   -12.47mA   -24.6mA
-1V       -17.97mA   -12.23mA   -24.1mA
-840mV    -17.19mA   -12.01mA   -21.49mA
-680mV    -16.04mA   -11.61mA   -20.56mA
-440mV    -13.72mA   -9.175mA   -19.14mA
-320mV    -10.37mA   -6.721mA   -14.74mA
240mV     6.859mA    4.183mA    10.22mA
480mV     11.8mA     7.089mA    17.77mA
680mV     14.43mA    8.584mA    21.78mA
880mV     15.85mA    9.395mA    23.85mA
1.16V     16.8mA     9.961mA    25.17mA
2.4V      18.29mA    10.91mA    27.13mA
[GND_clamp]
|Voltage   I(typ)   I(min)   I(max)
-1.2V     -86.17mA   -82.92mA   -94.88mA
-1.1V     -67.69mA   -63.94mA   -77.25mA
-1V       -51.5mA    -46.56mA   -63.18mA
-920mV    -41.08mA   -34.52mA   -53.71mA
-840mV    -32.45mA   -24.8mA    -43.35mA
-740mV    -22.04mA   -14.89mA   -29.94mA
-640mV    -12.56mA   -7.506mA   -17.5mA
-580mV    -7.74mA    -4.283mA   -10.97mA
-520mV    -3.917mA   -2.003mA   -5.594mA
-440mV    -946.7uA   -475.3uA   -1.248mA
-300mV    -18.65uA   -15.9uA    -16.46uA
2.4V      0A         0A         0A
[Ramp]
| variable   typ   min   max
dV/dt_r  0.3878/0.2979n   0.2614/0.3009n   0.4959/0.2962n
dV/dt_f  0.3878/0.3174n   0.2614/0.4944n   0.4959/0.2206n
R_load = 50.0000
[Rising Waveform]
R_fixture=   50.0000
V_fixture=   1.2000
V_fixture_min=   1.1400
V_fixture_max=   1.2600
|time   V(typ)   V(min)   V(max)
0s        553.7mV    704.3mV    433.5mV
606.1ps   553.7mV    704.3mV    482.1mV
707.1ps   554mV      704.3mV    784.9mV
808.1ps   553mV      704.3mV    978.5mV
909.1ps   559.9mV    704.3mV    1.075V
1.212ns   1.003V     705.2mV    1.193V
1.515ns   1.133V     718.3mV    1.233V
1.818ns   1.168V     1.01V      1.249V
2.323ns   1.189V     1.112V     1.258V
10ns      1.2V       1.14V      1.26V
[Falling Waveform]
R_fixture=   50.0000
V_fixture=   1.2000
V_fixture_min=   1.1400
V_fixture_max=   1.2600
|time   V(typ)   V(min)   V(max)
0s        1.2V       1.14V      1.26V
707.1ps   1.2V       1.14V      1.261V
1.01ns    1.2V       1.14V      644mV
1.212ns   1.201V     1.14V      482.4mV
1.414ns   992.9mV    1.14V      451.1mV
1.717ns   657.8mV    1.14V      438.4mV
2.222ns   569.7mV    1.11V      434.2mV
2.727ns   558mV      821.2mV    433.6mV
3.333ns   554.7mV    725.9mV    433.6mV
10ns      553.7mV    704.3mV    433.5mV
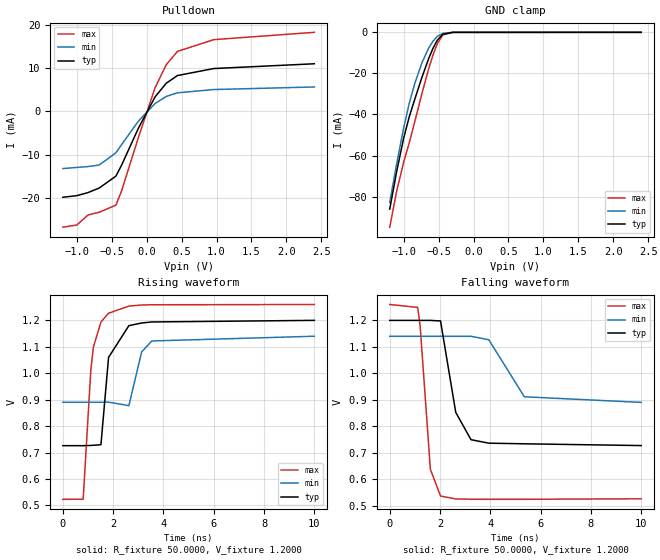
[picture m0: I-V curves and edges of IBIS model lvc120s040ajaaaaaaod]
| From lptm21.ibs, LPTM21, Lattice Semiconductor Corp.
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|   Model lvc120s040ajaaaaaaod
[Model]   lvc120s040ajaaaaaaod
Model_type   I/O_open_drain
Polarity   Non-Inverting
Enable   Active-Low
Vinl =   0.4200V
Vinh =   0.7800V
Vmeas =   0.6000V
Cref =   0.0F
Rref =   1.0000M
Vref =   0.0V
C_comp   4.2000pF   3.8000pF   7.5000pF
[Temperature Range]   25.0000   0.1050k   -40.0000
[Voltage Range]   1.2000V   1.1400V   1.2600V
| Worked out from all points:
|   slope of the pulldown table from 0 to 0.18 V, typ, clamps not added: 38.4 ohm
|   GND clamp passes 1 mA (typ) near -0.44 V on its own axis
|   rising waveform, R_fixture 50.0000, V_fixture 1.2000: 20-80 % time 300ps typ, 351ps min, 306ps max; typ from 0.726 V to 1.2 V
|   falling waveform, R_fixture 50.0000, V_fixture 1.2000: 20-80 % time 493ps typ, 830ps min, 320ps max; typ from 1.2 V to 0.728 V
[Pulldown]
|Voltage   I(typ)   I(min)   I(max)
-1.2V     -19.83mA   -13.2mA    -26.73mA
-1V       -19.45mA   -12.94mA   -26.24mA
-840mV    -18.75mA   -12.74mA   -23.92mA
-680mV    -17.7mA    -12.39mA   -23.29mA
-440mV    -14.94mA   -9.541mA   -21.64mA
-360mV    -12.45mA   -7.709mA   -18.4mA
-120mV    -3.929mA   -2.278mA   -6.111mA
120mV     3.345mA    1.822mA    5.45mA
280mV     6.5mA      3.45mA     10.77mA
440mV     8.276mA    4.29mA     13.85mA
960mV     9.897mA    5.047mA    16.57mA
2.4V      11mA       5.643mA    18.26mA
[GND_clamp]
|Voltage   I(typ)   I(min)   I(max)
-1.2V     -86.08mA   -82.82mA   -94.85mA
-1.1V     -67.63mA   -63.86mA   -77.23mA
-1V       -51.45mA   -46.5mA    -63.17mA
-920mV    -41.06mA   -34.48mA   -53.7mA
-840mV    -32.44mA   -24.77mA   -43.34mA
-740mV    -22.03mA   -14.88mA   -29.93mA
-640mV    -12.56mA   -7.503mA   -17.49mA
-580mV    -7.737mA   -4.281mA   -10.96mA
-520mV    -3.915mA   -2.002mA   -5.591mA
-440mV    -945.4uA   -474.8uA   -1.246mA
-300mV    -18.6uA    -15.87uA   -16.39uA
2.4V      0A         0A         0A
[Ramp]
| variable   typ   min   max
dV/dt_r  0.2844/0.2974n   0.1498/0.3471n   0.4421/0.3025n
dV/dt_f  0.2841/0.4740n   0.1497/0.8268n   0.4421/0.3746n
R_load = 50.0000
[Rising Waveform]
R_fixture=   50.0000
V_fixture=   1.2000
V_fixture_min=   1.1400
V_fixture_max=   1.2600
|time   V(typ)   V(min)   V(max)
0s        726.1mV    890.3mV    523.1mV
808.1ps   726mV      890.3mV    523.8mV
1.111ns   726.9mV    890.3mV    1.01V
1.212ns   727.6mV    890.3mV    1.098V
1.515ns   729.7mV    890.2mV    1.194V
1.818ns   1.06V      890.7mV    1.227V
2.626ns   1.18V      877.4mV    1.254V
3.131ns   1.19V      1.08V      1.258V
3.535ns   1.194V     1.122V     1.259V
10ns      1.2V       1.14V      1.26V
[Falling Waveform]
R_fixture=   50.0000
V_fixture=   1.2000
V_fixture_min=   1.1400
V_fixture_max=   1.2600
|time   V(typ)   V(min)   V(max)
0s        1.2V       1.14V      1.26V
1.111ns   1.2V       1.14V      1.249V
1.212ns   1.2V       1.14V      1.177V
1.616ns   1.2V       1.14V      638.3mV
2.02ns    1.198V     1.14V      537mV
2.626ns   852.8mV    1.14V      526.1mV
3.232ns   749.7mV    1.14V      525mV
3.939ns   736.6mV    1.127V     524.6mV
5.354ns   734.2mV    911.7mV    524.8mV
10ns      727.5mV    890.5mV    526.6mV
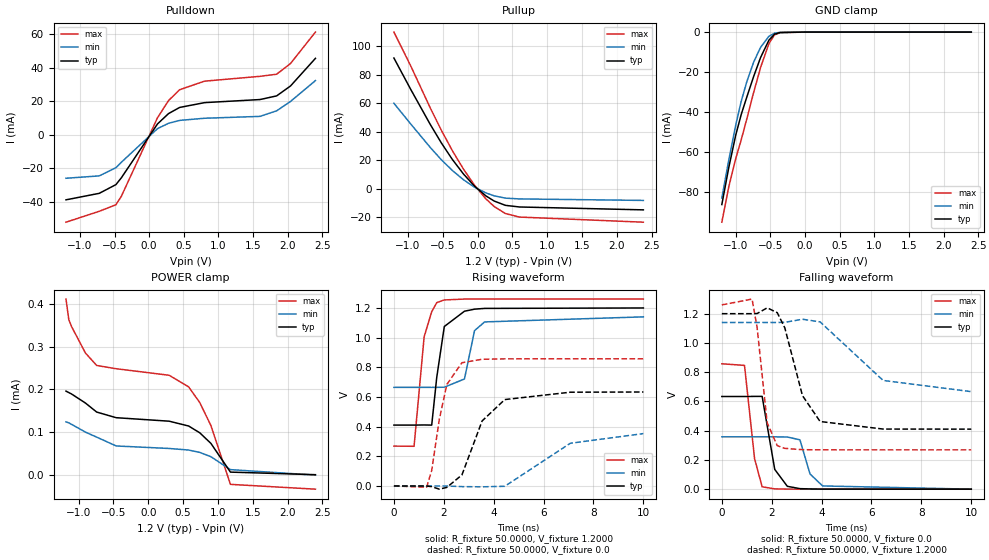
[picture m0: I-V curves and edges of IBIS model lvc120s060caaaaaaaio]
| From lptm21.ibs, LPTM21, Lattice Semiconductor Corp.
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|   Model lvc120s060caaaaaaaio
[Model]   lvc120s060caaaaaaaio
Model_type   I/O
Polarity   Non-Inverting
Enable   Active-Low
Vinl =   0.4200V
Vinh =   0.7800V
Vmeas =   0.6000V
Cref =   0.0F
Rref =   1.0000M
Vref =   0.0V
C_comp   3.0000pF   2.7000pF   3.3000pF
[Temperature Range]   25.0000   0.1050k   -40.0000
[Voltage Range]   1.2000V   1.1400V   1.2600V
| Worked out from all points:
|   slope of the pulldown table from 0 to 0.18 V, typ, clamps not added: 20.1 ohm
|   slope of the pullup table from 0 to 0.18 V, typ, clamps not added: 26.6 ohm
|   GND clamp passes 1 mA (typ) near -0.44 V on its own axis
|   rising waveform, R_fixture 50.0000, V_fixture 1.2000: 20-80 % time 317ps typ, 358ps min, 329ps max; typ from 0.41 V to 1.2 V
|   rising waveform, R_fixture 50.0000, V_fixture 0.0: 20-80 % time 1.01ns typ, 1.73ns min, 548ps max; typ from 0 V to 0.634 V
|   falling waveform, R_fixture 50.0000, V_fixture 0.0: 20-80 % time 354ps typ, 414ps min, 305ps max; typ from 0.634 V to 0 V
|   falling waveform, R_fixture 50.0000, V_fixture 1.2000: 20-80 % time 802ps typ, 1.41ns min, 368ps max; typ from 1.2 V to 0.41 V
[Pulldown]
|Voltage   I(typ)   I(min)   I(max)
-1.2V     -38.89mA   -26.03mA   -52.22mA
-720mV    -35.01mA   -24.61mA   -45.72mA
-480mV    -29.83mA   -19.72mA   -41.82mA
-400mV    -25.68mA   -16.44mA   -36.69mA
120mV     6.343mA    3.535mA    10.02mA
280mV     12.54mA    6.762mA    20.3mA
440mV     16.2mA     8.473mA    26.77mA
800mV     19.07mA    9.755mA    31.87mA
1.6V      20.91mA    10.87mA    34.75mA
1.84V     23.09mA    14.18mA    36.01mA
2.04V     29mA       19.77mA    42.4mA
2.4V      45.47mA    32.21mA    61.13mA
[Pullup]
|Voltage   I(typ)   I(min)   I(max)
-1.2V     91.54mA    59.87mA    109.7mA
-960mV    69.69mA    45.44mA    86.15mA
-680mV    45.19mA    29.04mA    56.78mA
-520mV    32.17mA    20.39mA    41.04mA
-360mV    20.46mA    12.77mA    26.6mA
-200mV    10.26mA    6.285mA    13.66mA
-40mV     1.709mA    1.039mA    2.311mA
120mV     -4.957mA   -2.868mA   -7.046mA
240mV     -8.596mA   -4.936mA   -12.45mA
400mV     -11.57mA   -6.536mA   -17.32mA
600mV     -12.72mA   -7.076mA   -19.78mA
2.38V     -14.74mA   -8.132mA   -23.37mA
[GND_clamp]
|Voltage   I(typ)   I(min)   I(max)
-1.2V     -86.12mA   -82.85mA   -94.91mA
-1.1V     -67.67mA   -63.89mA   -77.29mA
-1V       -51.5mA    -46.53mA   -63.23mA
-920mV    -41.11mA   -34.51mA   -53.77mA
-840mV    -32.49mA   -24.81mA   -43.41mA
-740mV    -22.08mA   -14.92mA   -30.01mA
-640mV    -12.62mA   -7.552mA   -17.58mA
-520mV    -4.002mA   -2.066mA   -5.717mA
-440mV    -1.052mA   -544.2uA   -1.412mA
-360mV    -224.4uA   -137uA     -297.4uA
0V        0A         0A         0A
2.4V      0A         0A         0A
[POWER_clamp]
|Voltage   I(typ)   I(min)   I(max)
-1.18V    195.7uA    123.7uA    411.4uA
-1.14V    192.3uA    121.4uA    363.5uA
-1.1V     189uA      117.9uA    346.9uA
-900mV    167.7uA    99.59uA    284.8uA
-740mV    146.7uA    87.99uA    255.9uA
-460mV    133.5uA    67.27uA    248.2uA
300mV     125.3uA    61.39uA    232.9uA
580mV     114uA      57.74uA    205.7uA
740mV     98.07uA    52.14uA    168.9uA
900mV     73.23uA    42.07uA    115uA
1.18V     6.005uA    11.83uA    -22.68uA
2.4V      -20.2nA    -1.007uA   -33.94uA
[Ramp]
| variable   typ   min   max
dV/dt_r  0.3358/0.9992n   0.2119/1.7173n   0.5144/0.5428n
dV/dt_f  0.4737/0.7939n   0.2838/1.4939n   0.5947/0.3645n
R_load = 50.0000
[Rising Waveform]
R_fixture=   50.0000
V_fixture=   1.2000
V_fixture_min=   1.1400
V_fixture_max=   1.2600
|time   V(typ)   V(min)   V(max)
0s        410.5mV    664.7mV    268.8mV
808.1ps   410.4mV    664.7mV    267.5mV
1.212ns   411.3mV    664.7mV    1.006V
1.515ns   410.3mV    664.5mV    1.175V
1.717ns   732.2mV    664.7mV    1.236V
2.02ns    1.075V     665.9mV    1.254V
2.828ns   1.178V     721.4mV    1.26V
3.232ns   1.192V     1.047V     1.26V
3.636ns   1.197V     1.106V     1.26V
10ns      1.2V       1.14V      1.26V
[Rising Waveform]
R_fixture=   50.0000
V_fixture=   0.0
V_fixture_min=   0.0
V_fixture_max=   0.0
|time   V(typ)   V(min)   V(max)
0s        231.9nV    390.7nV    158.8nV
1.313ns   -481.2uV   2.349uV    -8.377mV
1.515ns   -4.577mV   9.668uV    104.6mV
1.818ns   -21.53mV   11.11uV    446.9mV
2.121ns   -9.601mV   -355.6uV   684.2mV
2.727ns   74.64mV    -4.326mV   831mV
3.535ns   438.2mV    -5.924mV   854.1mV
4.444ns   582.5mV    -2.12mV    856.9mV
7.071ns   632.1mV    287.9mV    857.3mV
10ns      633.5mV    353.1mV    857.3mV
[Falling Waveform]
R_fixture=   50.0000
V_fixture=   0.0
V_fixture_min=   0.0
V_fixture_max=   0.0
|time   V(typ)   V(min)   V(max)
0s        633.6mV    358mV      857.3mV
909.1ps   633.6mV    358mV      846.5mV
1.313ns   634.3mV    358mV      208.2mV
1.616ns   634.6mV    358mV      16.31mV
2.121ns   135.2mV    358mV      2.021mV
2.626ns   19.44mV    356.7mV    419.9uV
3.131ns   3.598mV    337.3mV    77.69uV
3.535ns   1.522mV    104mV      20.84uV
4.04ns    573.9uV    22.04mV    26.66uV
10ns      1.994uV    5.359uV    -9.394uV
[Falling Waveform]
R_fixture=   50.0000
V_fixture=   1.2000
V_fixture_min=   1.1400
V_fixture_max=   1.2600
|time   V(typ)   V(min)   V(max)
0s        1.2V       1.14V      1.26V
1.212ns   1.2V       1.14V      1.3V
1.414ns   1.201V     1.14V      1.106V
1.818ns   1.24V      1.14V      453.5mV
2.222ns   1.207V     1.14V      297.6mV
2.525ns   1.103V     1.141V     279mV
3.232ns   639.7mV    1.162V     269.9mV
3.939ns   462.7mV    1.144V     268.9mV
6.465ns   411mV      743.6mV    268.8mV
10ns      410.5mV    666.9mV    268.8mV
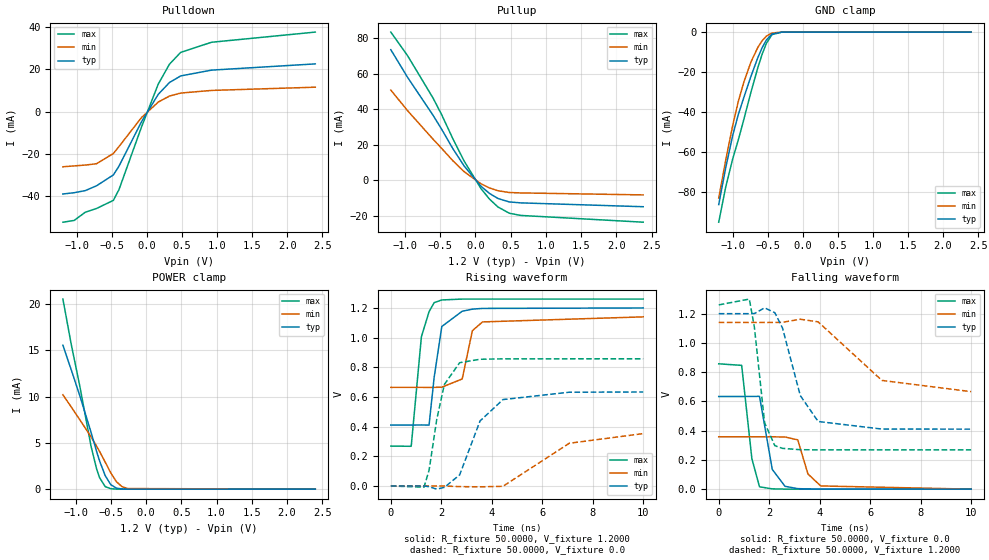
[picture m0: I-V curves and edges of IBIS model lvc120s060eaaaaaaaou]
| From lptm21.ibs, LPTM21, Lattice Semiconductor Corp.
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|   Model lvc120s060eaaaaaaaou
[Model]   lvc120s060eaaaaaaaou
Model_type   Output
Polarity   Non-Inverting
Enable   Active-Low
Vmeas =   0.6000V
Cref =   0.0F
Rref =   1.0000M
Vref =   0.0V
C_comp   3.0000pF   2.7000pF   3.3000pF
[Temperature Range]   25.0000   0.1050k   -40.0000
[Voltage Range]   1.2000V   1.1400V   1.2600V
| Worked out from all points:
|   slope of the pulldown table from 0 to 0.18 V, typ, clamps not added: 20 ohm
|   slope of the pullup table from 0 to 0.18 V, typ, clamps not added: 26.6 ohm
|   GND clamp passes 1 mA (typ) near -0.44 V on its own axis
|   POWER clamp passes 1 mA (typ) near -0.55 V on its own axis
|   rising waveform, R_fixture 50.0000, V_fixture 1.2000: 20-80 % time 317ps typ, 358ps min, 329ps max; typ from 0.41 V to 1.2 V
|   rising waveform, R_fixture 50.0000, V_fixture 0.0: 20-80 % time 1.01ns typ, 1.73ns min, 548ps max; typ from 0 V to 0.634 V
|   falling waveform, R_fixture 50.0000, V_fixture 0.0: 20-80 % time 354ps typ, 414ps min, 305ps max; typ from 0.634 V to 0 V
|   falling waveform, R_fixture 50.0000, V_fixture 1.2000: 20-80 % time 802ps typ, 1.41ns min, 368ps max; typ from 1.2 V to 0.41 V
[Pulldown]
|Voltage   I(typ)   I(min)   I(max)
-1.2V     -38.96mA   -26.08mA   -52.29mA
-1.04V    -38.35mA   -25.67mA   -51.47mA
-880mV    -37.35mA   -25.27mA   -47.56mA
-720mV    -35.07mA   -24.65mA   -45.8mA
-480mV    -29.93mA   -19.79mA   -41.97mA
-400mV    -25.79mA   -16.51mA   -36.87mA
-80mV     -4.851mA   -2.848mA   -7.377mA
160mV     8.179mA    4.521mA    13.01mA
320mV     13.76mA    7.355mA    22.43mA
480mV     16.88mA    8.777mA    28.01mA
920mV     19.62mA    10.02mA    32.8mA
2.4V      22.57mA    11.55mA    37.61mA
[Pullup]
|Voltage   I(typ)   I(min)   I(max)
-1.2V     73.66mA    50.91mA    83.59mA
-960mV    57.95mA    39.19mA    70.14mA
-600mV    36.65mA    23.19mA    46.34mA
-480mV    28.88mA    18.09mA    37.13mA
-320mV    17.9mA     11.08mA    23.47mA
-160mV    8.111mA    4.917mA    10.9mA
80mV      -3.336mA   -1.952mA   -4.689mA
200mV     -7.372mA   -4.268mA   -10.57mA
320mV     -10.21mA   -5.839mA   -14.99mA
480mV     -12.14mA   -6.822mA   -18.5mA
640mV     -12.67mA   -7.059mA   -19.74mA
2.38V     -14.84mA   -8.182mA   -23.56mA
[GND_clamp]
|Voltage   I(typ)   I(min)   I(max)
-1.2V     -86.07mA   -82.81mA   -94.84mA
-1.1V     -67.62mA   -63.85mA   -77.22mA
-1V       -51.44mA   -46.49mA   -63.16mA
-920mV    -41.05mA   -34.47mA   -53.69mA
-840mV    -32.43mA   -24.76mA   -43.33mA
-740mV    -22.02mA   -14.88mA   -29.93mA
-640mV    -12.55mA   -7.499mA   -17.49mA
-580mV    -7.732mA   -4.278mA   -10.96mA
-520mV    -3.911mA   -2mA       -5.586mA
-440mV    -943.9uA   -474.2uA   -1.243mA
-300mV    -18.55uA   -15.85uA   -16.32uA
2.4V      0A         0A         0A
[POWER_clamp]
|Voltage   I(typ)   I(min)   I(max)
-1.18V    15.54mA    10.19mA    20.52mA
-1.06V    12.84mA    8.851mA    15.57mA
-940mV    10.09mA    7.491mA    11.12mA
-780mV    6.115mA    5.629mA    4.606mA
-700mV    4.023mA    4.616mA    2.131mA
-660mV    3.056mA    4.076mA    1.241mA
-580mV    1.457mA    2.922mA    275.5uA
-500mV    478.5uA    1.748mA    47.96uA
-420mV    109.5uA    796.1uA    7.509uA
-340mV    22.62uA    261.6uA    1.074uA
-260mV    4.285uA    65.97uA    166.7nA
2.4V      -20.81nA   -18.5nA    -25.04nA
[Ramp]
| variable   typ   min   max
dV/dt_r  0.3358/0.9992n   0.2119/1.7173n   0.5144/0.5428n
dV/dt_f  0.4737/0.7939n   0.2838/1.4939n   0.5947/0.3645n
R_load = 50.0000
[Rising Waveform]
R_fixture=   50.0000
V_fixture=   1.2000
V_fixture_min=   1.1400
V_fixture_max=   1.2600
|time   V(typ)   V(min)   V(max)
0s        410.5mV    664.7mV    268.8mV
808.1ps   410.4mV    664.7mV    267.5mV
1.212ns   411.3mV    664.7mV    1.006V
1.515ns   410.3mV    664.5mV    1.175V
1.717ns   732.2mV    664.7mV    1.236V
2.02ns    1.075V     665.9mV    1.254V
2.828ns   1.178V     721.4mV    1.26V
3.232ns   1.192V     1.047V     1.26V
3.636ns   1.197V     1.106V     1.26V
10ns      1.2V       1.14V      1.26V
[Rising Waveform]
R_fixture=   50.0000
V_fixture=   0.0
V_fixture_min=   0.0
V_fixture_max=   0.0
|time   V(typ)   V(min)   V(max)
0s        231.9nV    390.7nV    158.8nV
1.313ns   -481.2uV   2.349uV    -8.377mV
1.515ns   -4.577mV   9.668uV    104.6mV
1.818ns   -21.53mV   11.11uV    446.9mV
2.121ns   -9.601mV   -355.6uV   684.2mV
2.727ns   74.64mV    -4.326mV   831mV
3.535ns   438.2mV    -5.924mV   854.1mV
4.444ns   582.5mV    -2.12mV    856.9mV
7.071ns   632.1mV    287.9mV    857.3mV
10ns      633.5mV    353.1mV    857.3mV
[Falling Waveform]
R_fixture=   50.0000
V_fixture=   0.0
V_fixture_min=   0.0
V_fixture_max=   0.0
|time   V(typ)   V(min)   V(max)
0s        633.6mV    358mV      857.3mV
909.1ps   633.6mV    358mV      846.5mV
1.313ns   634.3mV    358mV      208.2mV
1.616ns   634.6mV    358mV      16.31mV
2.121ns   135.2mV    358mV      2.021mV
2.626ns   19.44mV    356.7mV    419.9uV
3.131ns   3.598mV    337.3mV    77.69uV
3.535ns   1.522mV    104mV      20.84uV
4.04ns    573.9uV    22.04mV    26.66uV
10ns      1.994uV    5.359uV    -9.394uV
[Falling Waveform]
R_fixture=   50.0000
V_fixture=   1.2000
V_fixture_min=   1.1400
V_fixture_max=   1.2600
|time   V(typ)   V(min)   V(max)
0s        1.2V       1.14V      1.26V
1.212ns   1.2V       1.14V      1.3V
1.414ns   1.201V     1.14V      1.106V
1.818ns   1.24V      1.14V      453.5mV
2.222ns   1.207V     1.14V      297.6mV
2.525ns   1.103V     1.141V     279mV
3.232ns   639.7mV    1.162V     269.9mV
3.939ns   462.7mV    1.144V     268.9mV
6.465ns   411mV      743.6mV    268.8mV
10ns      410.5mV    666.9mV    268.8mV
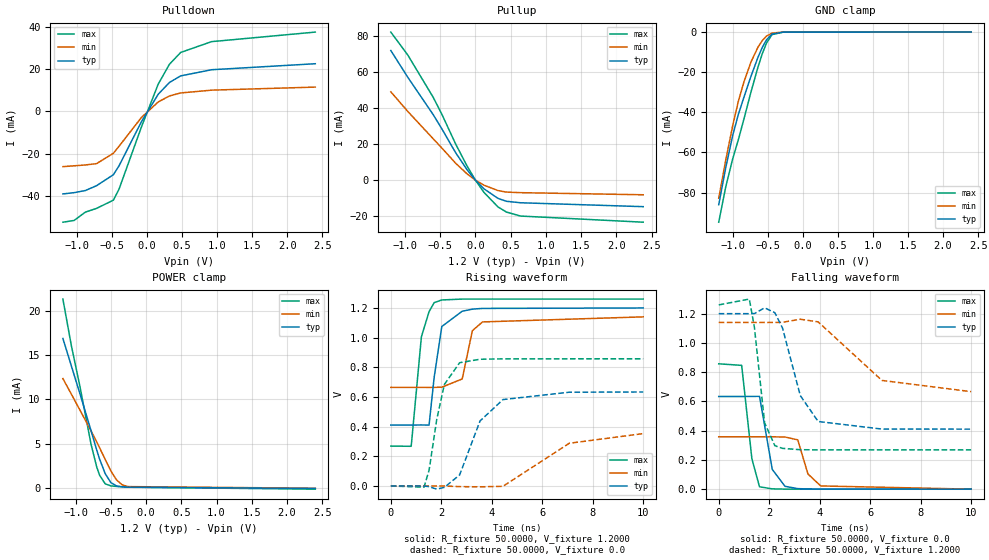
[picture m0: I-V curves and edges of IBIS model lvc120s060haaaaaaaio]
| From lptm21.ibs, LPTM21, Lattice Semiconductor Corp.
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|   Model lvc120s060haaaaaaaio
[Model]   lvc120s060haaaaaaaio
Model_type   I/O
Polarity   Non-Inverting
Enable   Active-Low
Vinl =   0.4200V
Vinh =   0.7800V
Vmeas =   0.6000V
Cref =   0.0F
Rref =   1.0000M
Vref =   0.0V
C_comp   3.0000pF   2.7000pF   3.3000pF
[Temperature Range]   25.0000   0.1050k   -40.0000
[Voltage Range]   1.2000V   1.1400V   1.2600V
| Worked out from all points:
|   slope of the pulldown table from 0 to 0.18 V, typ, clamps not added: 20.1 ohm
|   slope of the pullup table from 0 to 0.18 V, typ, clamps not added: 26.8 ohm
|   GND clamp passes 1 mA (typ) near -0.44 V on its own axis
|   POWER clamp passes 1 mA (typ) near -0.54 V on its own axis
|   rising waveform, R_fixture 50.0000, V_fixture 1.2000: 20-80 % time 317ps typ, 358ps min, 329ps max; typ from 0.41 V to 1.2 V
|   rising waveform, R_fixture 50.0000, V_fixture 0.0: 20-80 % time 1.01ns typ, 1.73ns min, 548ps max; typ from 0 V to 0.634 V
|   falling waveform, R_fixture 50.0000, V_fixture 0.0: 20-80 % time 354ps typ, 414ps min, 305ps max; typ from 0.634 V to 0 V
|   falling waveform, R_fixture 50.0000, V_fixture 1.2000: 20-80 % time 802ps typ, 1.41ns min, 368ps max; typ from 1.2 V to 0.41 V
[Pulldown]
|Voltage   I(typ)   I(min)   I(max)
-1.2V     -38.89mA   -26.03mA   -52.22mA
-1.04V    -38.29mA   -25.63mA   -51.4mA
-880mV    -37.29mA   -25.23mA   -47.48mA
-720mV    -35.01mA   -24.61mA   -45.72mA
-480mV    -29.83mA   -19.72mA   -41.82mA
-400mV    -25.68mA   -16.44mA   -36.69mA
-80mV     -4.827mA   -2.835mA   -7.331mA
160mV     8.136mA    4.499mA    12.93mA
320mV     13.68mA    7.316mA    22.28mA
480mV     16.78mA    8.727mA    27.82mA
920mV     19.67mA    10.05mA    32.92mA
2.4V      22.51mA    11.49mA    37.43mA
[Pullup]
|Voltage   I(typ)   I(min)   I(max)
-1.2V     72.04mA    49.09mA    82.28mA
-960mV    57.21mA    38.2mA     69.58mA
-600mV    36.47mA    23.04mA    46.11mA
-480mV    28.76mA    18.01mA    36.95mA
-280mV    15.22mA    9.379mA    20.05mA
-120mV    5.881mA    3.543mA    7.957mA
0V        -1.469nA   -1.14nA    -2.202nA
120mV     -4.782mA   -2.789mA   -6.757mA
320mV     -10.14mA   -5.8mA     -14.88mA
440mV     -11.76mA   -6.635mA   -17.74mA
640mV     -12.57mA   -6.96mA    -19.96mA
2.38V     -14.74mA   -8.132mA   -23.37mA
[GND_clamp]
|Voltage   I(typ)   I(min)   I(max)
-1.2V     -86.05mA   -82.8mA    -94.75mA
-1.1V     -67.59mA   -63.84mA   -77.13mA
-1V       -51.42mA   -46.49mA   -63.08mA
-920mV    -41.03mA   -34.46mA   -53.61mA
-840mV    -32.42mA   -24.76mA   -43.26mA
-740mV    -22.01mA   -14.88mA   -29.85mA
-640mV    -12.55mA   -7.505mA   -17.43mA
-580mV    -7.735mA   -4.289mA   -10.91mA
-520mV    -3.926mA   -2.018mA   -5.563mA
-440mV    -975.9uA   -496.4uA   -1.258mA
-280mV    -21.15uA   -10.37uA   -5.4uA
2.4V      0A         0A         0A
[POWER_clamp]
|Voltage   I(typ)   I(min)   I(max)
-1.18V    16.9mA     12.36mA    21.36mA
-1.06V    13.79mA    10.6mA     16.09mA
-940mV    10.69mA    8.822mA    11.54mA
-780mV    6.439mA    6.432mA    4.901mA
-700mV    4.263mA    5.185mA    2.349mA
-660mV    3.26mA     4.54mA     1.432mA
-580mV    1.601mA    3.213mA    447.8uA
-500mV    588.9uA    1.919mA    217.5uA
-420mV    211.3uA    900.6uA    152uA
-340mV    113.8uA    341.1uA    106.5uA
-260mV    75.42uA    135.6uA    65.45uA
2.4V      -76.46uA   -47.78uA   -154.4uA
[Ramp]
| variable   typ   min   max
dV/dt_r  0.3358/0.9992n   0.2119/1.7173n   0.5144/0.5428n
dV/dt_f  0.4737/0.7939n   0.2838/1.4939n   0.5947/0.3645n
R_load = 50.0000
[Rising Waveform]
R_fixture=   50.0000
V_fixture=   1.2000
V_fixture_min=   1.1400
V_fixture_max=   1.2600
|time   V(typ)   V(min)   V(max)
0s        410.5mV    664.7mV    268.8mV
808.1ps   410.4mV    664.7mV    267.5mV
1.212ns   411.3mV    664.7mV    1.006V
1.515ns   410.3mV    664.5mV    1.175V
1.717ns   732.2mV    664.7mV    1.236V
2.02ns    1.075V     665.9mV    1.254V
2.828ns   1.178V     721.4mV    1.26V
3.232ns   1.192V     1.047V     1.26V
3.636ns   1.197V     1.106V     1.26V
10ns      1.2V       1.14V      1.26V
[Rising Waveform]
R_fixture=   50.0000
V_fixture=   0.0
V_fixture_min=   0.0
V_fixture_max=   0.0
|time   V(typ)   V(min)   V(max)
0s        231.9nV    390.7nV    158.8nV
1.313ns   -481.2uV   2.349uV    -8.377mV
1.515ns   -4.577mV   9.668uV    104.6mV
1.818ns   -21.53mV   11.11uV    446.9mV
2.121ns   -9.601mV   -355.6uV   684.2mV
2.727ns   74.64mV    -4.326mV   831mV
3.535ns   438.2mV    -5.924mV   854.1mV
4.444ns   582.5mV    -2.12mV    856.9mV
7.071ns   632.1mV    287.9mV    857.3mV
10ns      633.5mV    353.1mV    857.3mV
[Falling Waveform]
R_fixture=   50.0000
V_fixture=   0.0
V_fixture_min=   0.0
V_fixture_max=   0.0
|time   V(typ)   V(min)   V(max)
0s        633.6mV    358mV      857.3mV
909.1ps   633.6mV    358mV      846.5mV
1.313ns   634.3mV    358mV      208.2mV
1.616ns   634.6mV    358mV      16.31mV
2.121ns   135.2mV    358mV      2.021mV
2.626ns   19.44mV    356.7mV    419.9uV
3.131ns   3.598mV    337.3mV    77.69uV
3.535ns   1.522mV    104mV      20.84uV
4.04ns    573.9uV    22.04mV    26.66uV
10ns      1.994uV    5.359uV    -9.394uV
[Falling Waveform]
R_fixture=   50.0000
V_fixture=   1.2000
V_fixture_min=   1.1400
V_fixture_max=   1.2600
|time   V(typ)   V(min)   V(max)
0s        1.2V       1.14V      1.26V
1.212ns   1.2V       1.14V      1.3V
1.414ns   1.201V     1.14V      1.106V
1.818ns   1.24V      1.14V      453.5mV
2.222ns   1.207V     1.14V      297.6mV
2.525ns   1.103V     1.141V     279mV
3.232ns   639.7mV    1.162V     269.9mV
3.939ns   462.7mV    1.144V     268.9mV
6.465ns   411mV      743.6mV    268.8mV
10ns      410.5mV    666.9mV    268.8mV
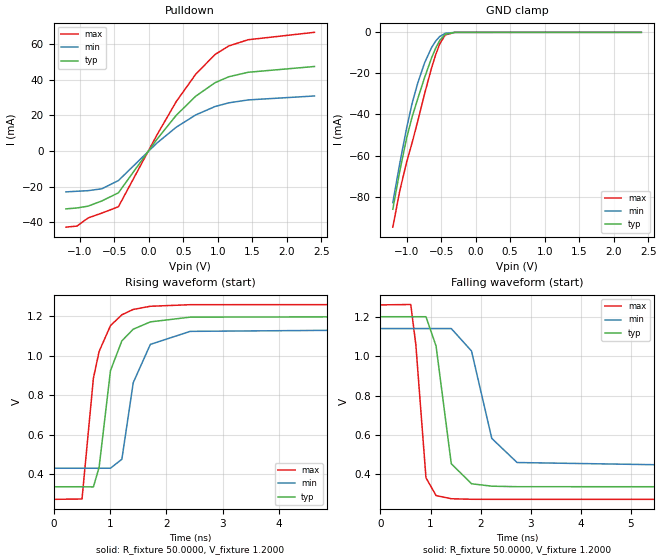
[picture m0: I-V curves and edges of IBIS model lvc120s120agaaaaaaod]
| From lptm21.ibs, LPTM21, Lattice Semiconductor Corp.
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|   Model lvc120s120agaaaaaaod
[Model]   lvc120s120agaaaaaaod
Model_type   I/O_open_drain
Polarity   Non-Inverting
Enable   Active-Low
Vinl =   0.4200V
Vinh =   0.7800V
Vmeas =   0.6000V
Cref =   0.0F
Rref =   1.0000M
Vref =   0.0V
C_comp   4.2000pF   3.8000pF   7.5000pF
[Temperature Range]   25.0000   0.1050k   -40.0000
[Voltage Range]   1.2000V   1.1400V   1.2600V
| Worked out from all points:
|   slope of the pulldown table from 0 to 0.18 V, typ, clamps not added: 18.6 ohm
|   GND clamp passes 1 mA (typ) near -0.44 V on its own axis
|   rising waveform, R_fixture 50.0000, V_fixture 1.2000: 20-80 % time 292ps typ, 305ps min, 299ps max; typ from 0.337 V to 1.2 V
|   falling waveform, R_fixture 50.0000, V_fixture 1.2000: 20-80 % time 248ps typ, 402ps min, 168ps max; typ from 1.2 V to 0.337 V
[Pulldown]
|Voltage   I(typ)   I(min)   I(max)
-1.2V     -32.53mA   -23.01mA   -42.78mA
-1.04V    -32.02mA   -22.65mA   -42.16mA
-880mV    -31.01mA   -22.33mA   -37.64mA
-680mV    -28.09mA   -21.26mA   -34.89mA
-440mV    -23.52mA   -16.65mA   -31.34mA
120mV     6.591mA    4.438mA    9.035mA
400mV     20.02mA    13.32mA    27.76mA
680mV     30.64mA    20.14mA    42.97mA
960mV     38.21mA    24.85mA    54.03mA
1.16V     41.54mA    26.93mA    58.83mA
1.44V     44.06mA    28.55mA    62.3mA
2.4V      47.29mA    30.77mA    66.45mA
[GND_clamp]
|Voltage   I(typ)   I(min)   I(max)
-1.2V     -86.17mA   -82.93mA   -94.89mA
-1.1V     -67.7mA    -63.94mA   -77.26mA
-1V       -51.5mA    -46.57mA   -63.19mA
-920mV    -41.09mA   -34.53mA   -53.72mA
-840mV    -32.46mA   -24.8mA    -43.36mA
-740mV    -22.04mA   -14.89mA   -29.94mA
-640mV    -12.57mA   -7.509mA   -17.5mA
-580mV    -7.744mA   -4.285mA   -10.97mA
-520mV    -3.92mA    -2.005mA   -5.598mA
-440mV    -948.2uA   -476uA     -1.25mA
-300mV    -18.71uA   -15.93uA   -16.55uA
2.4V      0A         0A         0A
[Ramp]
| variable   typ   min   max
dV/dt_r  0.5176/0.2891n   0.4253/0.3015n   0.5918/0.2956n
dV/dt_f  0.5176/0.2460n   0.4254/0.3979n   0.5918/0.1665n
R_load = 50.0000
[Rising Waveform]
R_fixture=   50.0000
V_fixture=   1.2000
V_fixture_min=   1.1400
V_fixture_max=   1.2600
|time   V(typ)   V(min)   V(max)
0s        337.3mV    431.1mV    273.7mV
505.1ps   337.4mV    431.1mV    275.3mV
707.1ps   336.4mV    431.1mV    886.6mV
808.1ps   435.4mV    431.1mV    1.022V
1.01ns    925.3mV    431.2mV    1.153V
1.212ns   1.076V     476.6mV    1.208V
1.414ns   1.135V     864.6mV    1.235V
1.717ns   1.172V     1.058V     1.251V
2.424ns   1.196V     1.124V     1.259V
10ns      1.2V       1.14V      1.26V
[Falling Waveform]
R_fixture=   50.0000
V_fixture=   1.2000
V_fixture_min=   1.1400
V_fixture_max=   1.2600
|time   V(typ)   V(min)   V(max)
0s        1.2V       1.14V      1.26V
606.1ps   1.2V       1.14V      1.262V
707.1ps   1.2V       1.14V      1.058V
909.1ps   1.2V       1.14V      383.3mV
1.111ns   1.051V     1.14V      292.7mV
1.414ns   454.4mV    1.14V      276.7mV
1.818ns   352.7mV    1.026V     274mV
2.222ns   340.4mV    582.9mV    273.7mV
2.727ns   337.8mV    460.4mV    273.7mV
10ns      337.3mV    431.1mV    273.7mV
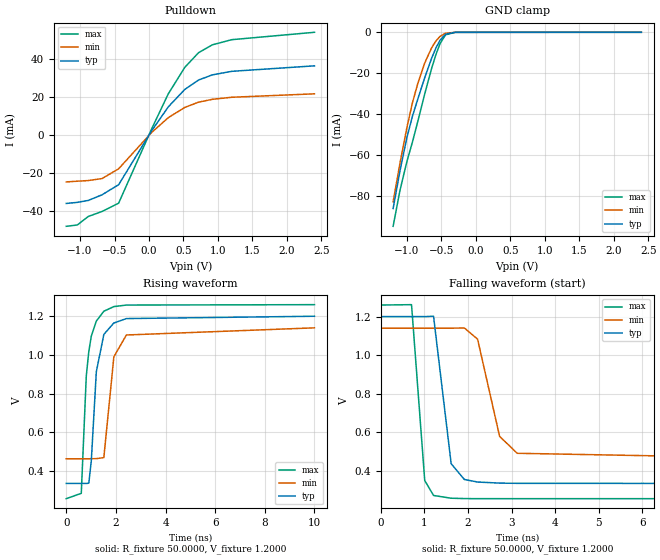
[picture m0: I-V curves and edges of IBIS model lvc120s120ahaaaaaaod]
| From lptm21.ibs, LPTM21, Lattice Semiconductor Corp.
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|   Model lvc120s120ahaaaaaaod
[Model]   lvc120s120ahaaaaaaod
Model_type   I/O_open_drain
Polarity   Non-Inverting
Enable   Active-Low
Vinl =   0.4200V
Vinh =   0.7800V
Vmeas =   0.6000V
Cref =   0.0F
Rref =   1.0000M
Vref =   0.0V
C_comp   4.2000pF   3.8000pF   7.5000pF
[Temperature Range]   25.0000   0.1050k   -40.0000
[Voltage Range]   1.2000V   1.1400V   1.2600V
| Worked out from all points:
|   slope of the pulldown table from 0 to 0.18 V, typ, clamps not added: 17.8 ohm
|   GND clamp passes 1 mA (typ) near -0.44 V on its own axis
|   rising waveform, R_fixture 50.0000, V_fixture 1.2000: 20-80 % time 302ps typ, 305ps min, 305ps max; typ from 0.334 V to 1.2 V
|   falling waveform, R_fixture 50.0000, V_fixture 1.2000: 20-80 % time 227ps typ, 400ps min, 164ps max; typ from 1.2 V to 0.334 V
[Pulldown]
|Voltage   I(typ)   I(min)   I(max)
-1.2V     -35.88mA   -24.56mA   -47.91mA
-1.04V    -35.32mA   -24.18mA   -47.22mA
-880mV    -34.3mA    -23.84mA   -42.73mA
-680mV    -31.32mA   -22.79mA   -40.09mA
-440mV    -26.02mA   -17.64mA   -35.73mA
40mV      2.403mA    1.517mA    3.448mA
280mV     14.93mA    9.25mA     21.78mA
520mV     24.12mA    14.65mA    35.75mA
720mV     29.07mA    17.41mA    43.46mA
920mV     31.77mA    18.91mA    47.58mA
1.2V      33.63mA    19.98mA    50.28mA
2.4V      36.52mA    21.79mA    54.17mA
[GND_clamp]
|Voltage   I(typ)   I(min)   I(max)
-1.2V     -86.17mA   -82.92mA   -94.88mA
-1.1V     -67.69mA   -63.94mA   -77.25mA
-1V       -51.5mA    -46.56mA   -63.18mA
-920mV    -41.08mA   -34.52mA   -53.71mA
-840mV    -32.45mA   -24.8mA    -43.35mA
-740mV    -22.04mA   -14.89mA   -29.94mA
-640mV    -12.56mA   -7.506mA   -17.5mA
-580mV    -7.74mA    -4.283mA   -10.97mA
-520mV    -3.917mA   -2.003mA   -5.594mA
-440mV    -946.7uA   -475.3uA   -1.248mA
-300mV    -18.65uA   -15.9uA    -16.46uA
2.4V      0A         0A         0A
[Ramp]
| variable   typ   min   max
dV/dt_r  0.5194/0.2991n   0.4067/0.3024n   0.6028/0.3024n
dV/dt_f  0.5194/0.2251n   0.4067/0.3959n   0.6028/0.1625n
R_load = 50.0000
[Rising Waveform]
R_fixture=   50.0000
V_fixture=   1.2000
V_fixture_min=   1.1400
V_fixture_max=   1.2600
|time   V(typ)   V(min)   V(max)
0s        334.4mV    462.1mV    255.4mV
606.1ps   334.4mV    462.1mV    283.2mV
808.1ps   334.1mV    462.1mV    891.7mV
909.1ps   335.9mV    462.1mV    1.017V
1.01ns    452.4mV    462.1mV    1.097V
1.212ns   912.3mV    462.8mV    1.175V
1.515ns   1.106V     468mV      1.226V
1.919ns   1.165V     990.2mV    1.25V
2.424ns   1.188V     1.103V     1.258V
10ns      1.2V       1.14V      1.26V
[Falling Waveform]
R_fixture=   50.0000
V_fixture=   1.2000
V_fixture_min=   1.1400
V_fixture_max=   1.2600
|time   V(typ)   V(min)   V(max)
0s        1.2V       1.14V      1.26V
707.1ps   1.2V       1.14V      1.262V
1.01ns    1.2V       1.14V      349.6mV
1.212ns   1.202V     1.14V      272.1mV
1.616ns   436.9mV    1.14V      257.8mV
1.919ns   355.1mV    1.141V     256mV
2.222ns   341.8mV    1.083V     255.5mV
2.727ns   336.2mV    578.7mV    255.4mV
3.131ns   335mV      490.9mV    255.4mV
10ns      334.4mV    462.1mV    255.4mV
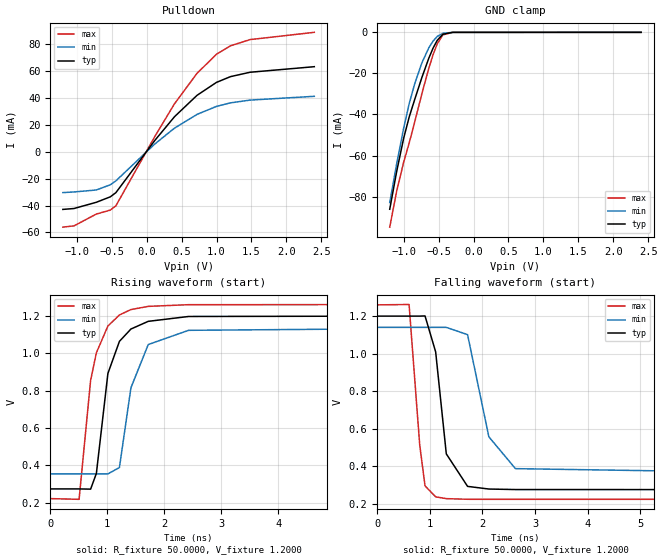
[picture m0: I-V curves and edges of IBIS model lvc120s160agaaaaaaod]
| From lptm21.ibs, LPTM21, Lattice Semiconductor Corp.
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|   Model lvc120s160agaaaaaaod
[Model]   lvc120s160agaaaaaaod
Model_type   I/O_open_drain
Polarity   Non-Inverting
Enable   Active-Low
Vinl =   0.4200V
Vinh =   0.7800V
Vmeas =   0.6000V
Cref =   0.0F
Rref =   1.0000M
Vref =   0.0V
C_comp   4.2000pF   3.8000pF   7.5000pF
[Temperature Range]   25.0000   0.1050k   -40.0000
[Voltage Range]   1.2000V   1.1400V   1.2600V
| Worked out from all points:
|   slope of the pulldown table from 0 to 0.18 V, typ, clamps not added: 14.4 ohm
|   GND clamp passes 1 mA (typ) near -0.44 V on its own axis
|   rising waveform, R_fixture 50.0000, V_fixture 1.2000: 20-80 % time 297ps typ, 304ps min, 301ps max; typ from 0.274 V to 1.2 V
|   falling waveform, R_fixture 50.0000, V_fixture 1.2000: 20-80 % time 211ps typ, 357ps min, 159ps max; typ from 1.2 V to 0.274 V
[Pulldown]
|Voltage   I(typ)   I(min)   I(max)
-1.2V     -42.89mA   -30.43mA   -56.05mA
-1.04V    -42.22mA   -29.95mA   -55.08mA
-720mV    -37.59mA   -28.47mA   -46.33mA
-520mV    -33.54mA   -24.61mA   -43.38mA
-440mV    -30.41mA   -21.68mA   -40.15mA
120mV     8.488mA    5.781mA    11.49mA
400mV     25.94mA    17.43mA    35.56mA
720mV     41.68mA    27.56mA    57.99mA
1V        51.34mA    33.53mA    72.2mA
1.2V      55.59mA    36.13mA    78.45mA
1.48V     58.84mA    38.19mA    83.05mA
2.4V      62.96mA    40.99mA    88.45mA
[GND_clamp]
|Voltage   I(typ)   I(min)   I(max)
-1.2V     -86.17mA   -82.93mA   -94.89mA
-1.1V     -67.7mA    -63.94mA   -77.26mA
-1V       -51.5mA    -46.57mA   -63.19mA
-920mV    -41.09mA   -34.53mA   -53.72mA
-840mV    -32.46mA   -24.8mA    -43.36mA
-740mV    -22.04mA   -14.89mA   -29.94mA
-640mV    -12.57mA   -7.509mA   -17.5mA
-580mV    -7.744mA   -4.285mA   -10.97mA
-520mV    -3.92mA    -2.005mA   -5.598mA
-440mV    -948.2uA   -476uA     -1.25mA
-300mV    -18.71uA   -15.93uA   -16.55uA
2.4V      0A         0A         0A
[Ramp]
| variable   typ   min   max
dV/dt_r  0.5555/0.2935n   0.4713/0.3013n   0.6225/0.2977n
dV/dt_f  0.5555/0.2090n   0.4714/0.3531n   0.6225/0.1574n
R_load = 50.0000
[Rising Waveform]
R_fixture=   50.0000
V_fixture=   1.2000
V_fixture_min=   1.1400
V_fixture_max=   1.2600
|time   V(typ)   V(min)   V(max)
0s        274.2mV    354.4mV    222.5mV
505.1ps   274.2mV    354.4mV    218.6mV
707.1ps   273.1mV    354.4mV    854.6mV
808.1ps   357.1mV    354.4mV    1.002V
1.01ns    891.5mV    354.5mV    1.145V
1.212ns   1.063V     388.6mV    1.204V
1.414ns   1.129V     815.5mV    1.233V
1.717ns   1.17V      1.046V     1.25V
2.424ns   1.196V     1.122V     1.259V
10ns      1.2V       1.14V      1.26V
[Falling Waveform]
R_fixture=   50.0000
V_fixture=   1.2000
V_fixture_min=   1.1400
V_fixture_max=   1.2600
|time   V(typ)   V(min)   V(max)
0s        1.2V       1.14V      1.26V
606.1ps   1.2V       1.14V      1.262V
808.1ps   1.2V       1.14V      512.8mV
909.1ps   1.201V     1.14V      294.3mV
1.111ns   1.009V     1.14V      235.7mV
1.313ns   465mV      1.14V      226.2mV
1.717ns   291.6mV    1.101V     222.8mV
2.121ns   277.4mV    556mV      222.5mV
2.626ns   274.7mV    386.2mV    222.5mV
10ns      274.2mV    354.4mV    222.5mV
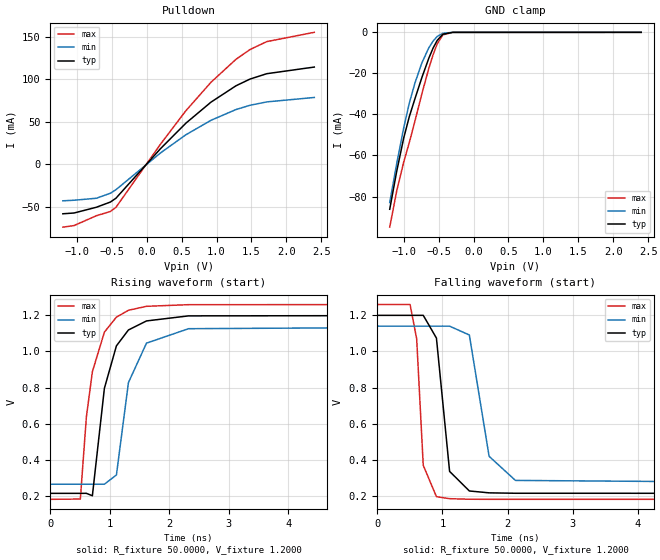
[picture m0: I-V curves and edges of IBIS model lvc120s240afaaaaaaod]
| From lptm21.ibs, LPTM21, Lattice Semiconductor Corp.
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|   Model lvc120s240afaaaaaaod
[Model]   lvc120s240afaaaaaaod
Model_type   I/O_open_drain
Polarity   Non-Inverting
Enable   Active-Low
Vinl =   0.4200V
Vinh =   0.7800V
Vmeas =   0.6000V
Cref =   0.0F
Rref =   1.0000M
Vref =   0.0V
C_comp   4.2000pF   3.8000pF   7.5000pF
[Temperature Range]   25.0000   0.1050k   -40.0000
[Voltage Range]   1.2000V   1.1400V   1.2600V
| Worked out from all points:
|   slope of the pulldown table from 0 to 0.18 V, typ, clamps not added: 10.8 ohm
|   GND clamp passes 1 mA (typ) near -0.44 V on its own axis
|   rising waveform, R_fixture 50.0000, V_fixture 1.2000: 20-80 % time 301ps typ, 297ps min, 278ps max; typ from 0.214 V to 1.2 V
|   falling waveform, R_fixture 50.0000, V_fixture 1.2000: 20-80 % time 160ps typ, 231ps min, 93.2ps max; typ from 1.2 V to 0.214 V
[Pulldown]
|Voltage   I(typ)   I(min)   I(max)
-1.2V     -58.19mA   -42.94mA   -73.91mA
-1.04V    -57.28mA   -42.27mA   -72.04mA
-720mV    -50.52mA   -39.95mA   -60.48mA
-520mV    -44.42mA   -34.08mA   -55.51mA
-440mV    -39.92mA   -29.91mA   -50.64mA
200mV     18.48mA    13.43mA    23.8mA
560mV     48.15mA    34.55mA    62.73mA
920mV     72.93mA    51.6mA     96.24mA
1.28V     92.25mA    64.33mA    123.4mA
1.48V     100.1mA    69.3mA     134.8mA
1.72V     106.4mA    73.26mA    144.1mA
2.4V      114.2mA    78.47mA    155mA
[GND_clamp]
|Voltage   I(typ)   I(min)   I(max)
-1.2V     -86.19mA   -82.94mA   -94.91mA
-1.1V     -67.71mA   -63.95mA   -77.28mA
-1V       -51.52mA   -46.57mA   -63.21mA
-920mV    -41.11mA   -34.53mA   -53.74mA
-840mV    -32.47mA   -24.81mA   -43.38mA
-740mV    -22.05mA   -14.9mA    -29.96mA
-640mV    -12.58mA   -7.515mA   -17.52mA
-580mV    -7.752mA   -4.29mA    -10.99mA
-520mV    -3.927mA   -2.008mA   -5.609mA
-440mV    -951.3uA   -477uA     -1.256mA
-300mV    -18.83uA   -15.98uA   -16.74uA
2.4V      0A         0A         0A
[Ramp]
| variable   typ   min   max
dV/dt_r  0.5916/0.2977n   0.5253/0.2938n   0.6475/0.2750n
dV/dt_f  0.5916/0.1580n   0.5253/0.2284n   0.6475/92.2982p
R_load = 50.0000
[Rising Waveform]
R_fixture=   50.0000
V_fixture=   1.2000
V_fixture_min=   1.1400
V_fixture_max=   1.2600
|time   V(typ)   V(min)   V(max)
0s        214mV      264.5mV    180.9mV
505.1ps   214mV      264.5mV    182.5mV
606.1ps   214.2mV    264.5mV    635.7mV
707.1ps   200.6mV    264.5mV    887.8mV
909.1ps   796mV      264.7mV    1.107V
1.111ns   1.031V     315.8mV    1.19V
1.313ns   1.119V     827.5mV    1.228V
1.616ns   1.169V     1.046V     1.25V
2.323ns   1.197V     1.126V     1.259V
10ns      1.2V       1.14V      1.26V
[Falling Waveform]
R_fixture=   50.0000
V_fixture=   1.2000
V_fixture_min=   1.1400
V_fixture_max=   1.2600
|time   V(typ)   V(min)   V(max)
0s        1.2V       1.14V      1.26V
505.1ps   1.2V       1.14V      1.26V
606.1ps   1.2V       1.14V      1.07V
707.1ps   1.2V       1.14V      368.9mV
909.1ps   1.074V     1.14V      195.5mV
1.111ns   335.6mV    1.14V      184.4mV
1.414ns   227.1mV    1.091V     181.3mV
1.717ns   216.7mV    419mV      180.9mV
2.121ns   214.4mV    285.6mV    180.9mV
10ns      213.9mV    264.5mV    180.8mV
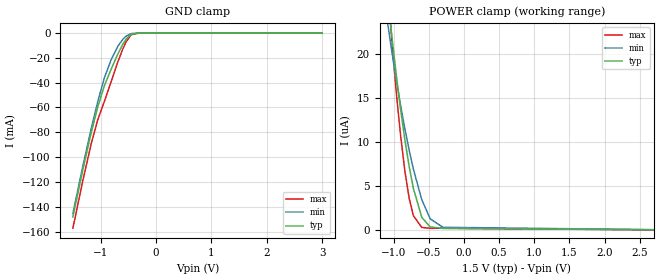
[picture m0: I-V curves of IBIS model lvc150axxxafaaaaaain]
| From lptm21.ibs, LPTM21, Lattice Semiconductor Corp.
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|   Model lvc150axxxafaaaaaain
[Model]   lvc150axxxafaaaaaain
Model_type   Input
Polarity   Non-Inverting
Enable   Active-Low
Vinl =   0.3750V
Vinh =   1.1250V
C_comp   4.2000pF   3.8000pF   7.5000pF
[Temperature Range]   25.0000   0.1050k   -40.0000
[Voltage Range]   1.5000V   1.4300V   1.5800V
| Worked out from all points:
|   GND clamp passes 1 mA (typ) near -0.44 V on its own axis
[GND_clamp]
|Voltage   I(typ)   I(min)   I(max)
-1.5V     -148mA     -145.1mA   -157.1mA
-1.32V    -110mA     -107mA     -118.7mA
-1.17V    -80.44mA   -77.06mA   -89.3mA
-1.05V    -59.22mA   -54.98mA   -69.71mA
-930mV    -42.25mA   -35.9mA    -54.91mA
-810mV    -29.28mA   -21.6mA    -39.29mA
-690mV    -17.12mA   -10.87mA   -23.53mA
-600mV    -9.252mA   -5.256mA   -13.04mA
-540mV    -5.056mA   -2.651mA   -7.221mA
-450mV    -1.176mA   -584.3uA   -1.582mA
-300mV    -18.62uA   -15.88uA   -16.42uA
3V        0A         0A         0A
[POWER_clamp]
|Voltage   I(typ)   I(min)   I(max)
-1.5V     65.71uA    49.01uA    83.9uA
-1.08V    26.11uA    23.2uA     27.01uA
-1.02V    21.59uA    19.96uA    20.86uA
-960mV    17.41uA    16.92uA    15.37uA
-900mV    13.6uA     14.08uA    10.6uA
-840mV    10.19uA    11.46uA    6.628uA
-780mV    7.212uA    9.063uA    3.588uA
-720mV    4.71uA     6.904uA    1.593uA
-600mV    1.399uA    3.406uA    253nA
-480mV    305.8nA    1.235uA    164nA
-300mV    148.5nA    272.9nA    164nA
3V        -25.84nA   -23.03nA   -33.01nA
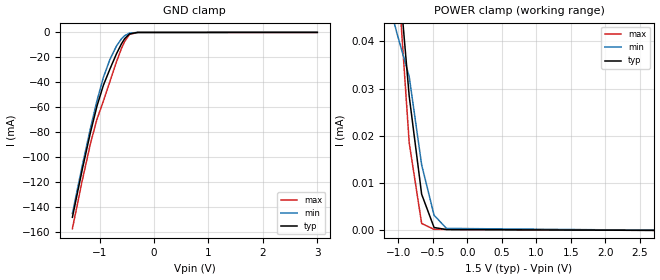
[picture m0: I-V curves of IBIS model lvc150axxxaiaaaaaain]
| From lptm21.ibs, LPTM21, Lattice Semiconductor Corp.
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|   Model lvc150axxxaiaaaaaain
[Model]   lvc150axxxaiaaaaaain
Model_type   Input
Polarity   Non-Inverting
Enable   Active-Low
Vinl =   0.3750V
Vinh =   1.1250V
C_comp   4.2000pF   3.8000pF   7.5000pF
[Temperature Range]   25.0000   0.1050k   -40.0000
[Voltage Range]   1.5000V   1.4300V   1.5800V
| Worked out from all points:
|   GND clamp passes 1 mA (typ) near -0.44 V on its own axis
[GND_clamp]
|Voltage   I(typ)   I(min)   I(max)
-1.5V     -148mA     -145mA     -157.1mA
-1.32V    -110mA     -106.9mA   -118.7mA
-1.17V    -80.43mA   -77.05mA   -89.29mA
-1.05V    -59.21mA   -54.97mA   -69.7mA
-930mV    -42.23mA   -35.89mA   -54.9mA
-810mV    -29.27mA   -21.59mA   -39.28mA
-690mV    -17.12mA   -10.87mA   -23.52mA
-600mV    -9.247mA   -5.253mA   -13.03mA
-540mV    -5.052mA   -2.649mA   -7.216mA
-450mV    -1.174mA   -583.6uA   -1.579mA
-300mV    -18.57uA   -15.86uA   -16.35uA
3V        0A         0A         0A
[POWER_clamp]
|Voltage   I(typ)   I(min)   I(max)
-1.5V     116.1uA    71.29uA    180.3uA
-1.44V    109.7uA    67.84uA    171.7uA
-1.32V    97.51uA    59.87uA    171.7uA
-1.26V    91.78uA    55.96uA    135.4uA
-1.2V     86.56uA    52.18uA    110.4uA
-1.14V    86.56uA    48.56uA    91.27uA
-1.02V    59.13uA    41.85uA    57.26uA
-840mV    28.38uA    32.53uA    18.54uA
-660mV    7.64uA     13.88uA    1.451uA
-480mV    597.8nA    3.189uA    202.3nA
-300mV    158.7nA    405.9nA    191.9nA
3V        -25.99nA   -23.13nA   -33.18nA
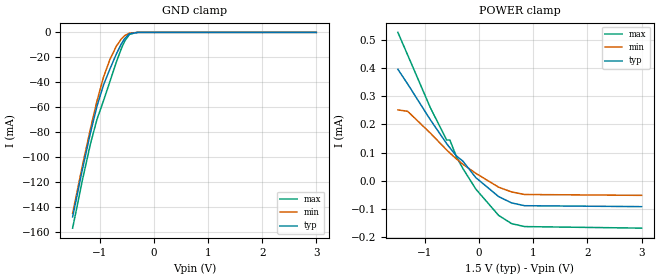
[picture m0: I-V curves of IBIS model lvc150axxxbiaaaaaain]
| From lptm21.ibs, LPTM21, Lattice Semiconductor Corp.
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|   Model lvc150axxxbiaaaaaain
[Model]   lvc150axxxbiaaaaaain
Model_type   Input
Polarity   Non-Inverting
Enable   Active-Low
Vinl =   0.3750V
Vinh =   1.1250V
C_comp   4.2000pF   3.8000pF   7.5000pF
[Temperature Range]   25.0000   0.1050k   -40.0000
[Voltage Range]   1.5000V   1.4300V   1.5800V
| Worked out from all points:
|   GND clamp passes 1 mA (typ) near -0.44 V on its own axis
[GND_clamp]
|Voltage   I(typ)   I(min)   I(max)
-1.5V     -147.9mA   -145mA     -156.9mA
-1.32V    -109.9mA   -106.9mA   -118.5mA
-1.17V    -80.37mA   -77.03mA   -89.17mA
-1.05V    -59.15mA   -54.95mA   -69.59mA
-930mV    -42.18mA   -35.87mA   -54.79mA
-810mV    -29.22mA   -21.57mA   -39.18mA
-690mV    -17.07mA   -10.85mA   -23.42mA
-600mV    -9.207mA   -5.237mA   -12.94mA
-540mV    -5.019mA   -2.637mA   -7.138mA
-450mV    -1.157mA   -579.1uA   -1.537mA
-300mV    -18.25uA   -15.97uA   -13.7uA
3V        0A         0A         0A
[POWER_clamp]
|Voltage   I(typ)   I(min)   I(max)
-1.5V     395.4uA    251.6uA    526.1uA
-1.32V    343.5uA    246.7uA    446.2uA
-900mV    216.4uA    169.3uA    259.1uA
-600mV    132.4uA    109.9uA    145uA
-540mV    117.3uA    98.92uA    145uA
-420mV    88.66uA    78.23uA    86.09uA
-300mV    70.18uA    59.14uA    44.18uA
-60mV     11.57uA    26.89uA    -29.01uA
360mV     -55.31uA   -22.01uA   -121.9uA
600mV     -77.75uA   -38.9uA    -151.1uA
840mV     -87.68uA   -48uA      -161.6uA
3V        -90.95uA   -50.99uA   -167.1uA
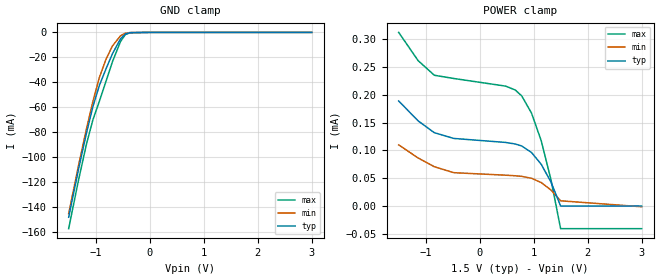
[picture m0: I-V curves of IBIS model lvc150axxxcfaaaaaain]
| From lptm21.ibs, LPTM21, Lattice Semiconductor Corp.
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|   Model lvc150axxxcfaaaaaain
[Model]   lvc150axxxcfaaaaaain
Model_type   Input
Polarity   Non-Inverting
Enable   Active-Low
Vinl =   0.3750V
Vinh =   1.1250V
C_comp   4.2000pF   3.8000pF   7.5000pF
[Temperature Range]   25.0000   0.1050k   -40.0000
[Voltage Range]   1.5000V   1.4300V   1.5800V
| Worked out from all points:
|   GND clamp passes 1 mA (typ) near -0.44 V on its own axis
[GND_clamp]
|Voltage   I(typ)   I(min)   I(max)
-1.5V     -148mA     -145.1mA   -157.1mA
-1.32V    -110mA     -107mA     -118.7mA
-1.17V    -80.48mA   -77.09mA   -89.35mA
-1.05V    -59.26mA   -55.01mA   -69.77mA
-930mV    -42.29mA   -35.93mA   -54.98mA
-810mV    -29.33mA   -21.63mA   -39.36mA
-690mV    -17.18mA   -10.91mA   -23.6mA
-540mV    -5.131mA   -2.707mA   -7.327mA
-450mV    -1.269mA   -646.6uA   -1.725mA
-360mV    -213.6uA   -130.7uA   -279.5uA
0V        0A         0A         0A
3V        0A         0A         0A
[POWER_clamp]
|Voltage   I(typ)   I(min)   I(max)
-1.5V     188.7uA    109.8uA    311.9uA
-1.14V    153uA      86.3uA     261.2uA
-840mV    131.7uA    70.61uA    234.9uA
-480mV    121.4uA    59.86uA    229.1uA
480mV     114.2uA    55.36uA    215.4uA
660mV     111.4uA    54.29uA    208.4uA
780mV     107.8uA    53.22uA    197.7uA
960mV     96.18uA    49.83uA    167uA
1.14V     75.06uA    42.11uA    117.4uA
1.32V     43.25uA    28.83uA    47.75uA
1.5V      -25.18nA   9.33uA     -40.71uA
3V        -25.18nA   -1.33uA    -40.71uA
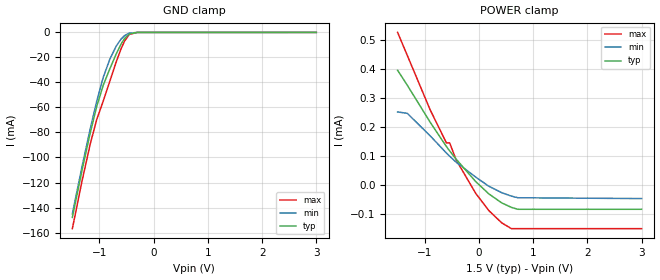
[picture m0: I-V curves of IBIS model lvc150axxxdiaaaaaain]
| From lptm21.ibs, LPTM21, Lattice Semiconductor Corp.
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|   Model lvc150axxxdiaaaaaain
[Model]   lvc150axxxdiaaaaaain
Model_type   Input
Polarity   Non-Inverting
Enable   Active-Low
Vinl =   0.3750V
Vinh =   1.1250V
C_comp   4.2000pF   3.8000pF   7.5000pF
[Temperature Range]   25.0000   0.1050k   -40.0000
[Voltage Range]   1.5000V   1.4300V   1.5800V
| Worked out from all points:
|   GND clamp passes 1 mA (typ) near -0.44 V on its own axis
[GND_clamp]
|Voltage   I(typ)   I(min)   I(max)
-1.5V     -147.9mA   -145.1mA   -156.9mA
-1.32V    -109.9mA   -107mA     -118.5mA
-1.17V    -80.39mA   -77.05mA   -89.2mA
-1.05V    -59.17mA   -54.96mA   -69.62mA
-930mV    -42.2mA    -35.88mA   -54.83mA
-810mV    -29.25mA   -21.58mA   -39.21mA
-690mV    -17.09mA   -10.87mA   -23.45mA
-600mV    -9.233mA   -5.258mA   -12.98mA
-540mV    -5.047mA   -2.659mA   -7.175mA
-450mV    -1.185mA   -599.1uA   -1.573mA
-300mV    -18.73uA   -15.61uA   -8.8uA
3V        0A         0A         0A
[POWER_clamp]
|Voltage   I(typ)   I(min)   I(max)
-1.5V     395.4uA    251.6uA    526.1uA
-1.32V    343.5uA    246.7uA    446.2uA
-900mV    216.4uA    169.3uA    259.1uA
-600mV    132.4uA    109.9uA    145uA
-540mV    117.3uA    98.92uA    145uA
-420mV    88.66uA    78.23uA    86.09uA
-60mV     11.57uA    26.89uA    -29.01uA
180mV     -30.73uA   -4.427uA   -88.14uA
420mV     -62.06uA   -26.95uA   -131uA
600mV     -77.75uA   -38.9uA    -151.1uA
720mV     -84.27uA   -44.44uA   -151.1uA
3V        -84.27uA   -47.29uA   -151.1uA
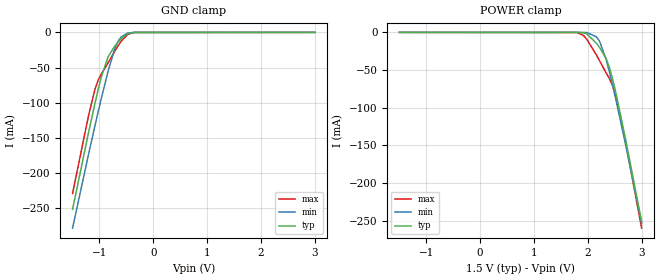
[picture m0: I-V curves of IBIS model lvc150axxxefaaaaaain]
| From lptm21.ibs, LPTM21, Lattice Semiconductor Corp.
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|   Model lvc150axxxefaaaaaain
[Model]   lvc150axxxefaaaaaain
Model_type   Input
Polarity   Non-Inverting
Enable   Active-Low
Vinl =   0.3750V
Vinh =   1.1250V
C_comp   4.2000pF   3.8000pF   7.5000pF
[Temperature Range]   25.0000   0.1050k   -40.0000
[Voltage Range]   1.5000V   1.4300V   1.5800V
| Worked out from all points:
|   GND clamp passes 1 mA (typ) near -0.44 V on its own axis
[GND_clamp]
|Voltage   I(typ)   I(min)   I(max)
-1.5V     -251.7mA   -278.5mA   -229.1mA
-1.2V     -141.4mA   -172.4mA   -117.3mA
-1.08V    -99.67mA   -131.5mA   -80.05mA
-1.02V    -80.04mA   -111.5mA   -67.21mA
-960mV    -61.91mA   -92.06mA   -58.68mA
-840mV    -34.79mA   -55.26mA   -43.37mA
-720mV    -20.14mA   -24.33mA   -27.35mA
-660mV    -14.36mA   -13.41mA   -19.87mA
-600mV    -9.264mA   -6.624mA   -13.05mA
-480mV    -2.108mA   -1.103mA   -2.957mA
-360mV    -118.6uA   -77.16uA   -122.3uA
3V        530.6nA    522.4nA    933.8nA
[POWER_clamp]
|Voltage   I(typ)   I(min)   I(max)
-1.5V     530.6nA    554.4nA    807.4nA
1.8V      -19.41uA   -2.946uA   -230.2uA
1.92V     -595.4uA   -60.19uA   -4.17mA
1.98V     -2.108mA   -255.1uA   -9.033mA
2.16V     -14.36mA   -5.841mA   -29.95mA
2.22V     -20.14mA   -12mA      -37.96mA
2.34V     -34.79mA   -36.12mA   -53.78mA
2.4V      -46.39mA   -52.39mA   -61.24mA
2.46V     -61.91mA   -70.14mA   -70.9mA
2.52V     -80.04mA   -88.87mA   -85.42mA
2.7V      -141.4mA   -148.4mA   -145.8mA
3V        -251.7mA   -253.4mA   -260.1mA
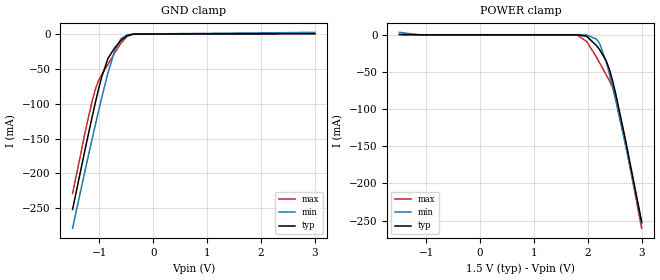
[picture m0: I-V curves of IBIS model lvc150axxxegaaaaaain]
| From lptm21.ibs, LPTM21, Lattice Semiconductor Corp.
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|   Model lvc150axxxegaaaaaain
[Model]   lvc150axxxegaaaaaain
Model_type   Input
Polarity   Non-Inverting
Enable   Active-Low
Vinl =   0.3750V
Vinh =   1.1250V
C_comp   4.2000pF   3.8000pF   7.5000pF
[Temperature Range]   25.0000   0.1050k   -40.0000
[Voltage Range]   1.5000V   1.4300V   1.5800V
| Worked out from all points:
|   GND clamp passes 1 mA (typ) near -0.44 V on its own axis
[GND_clamp]
|Voltage   I(typ)   I(min)   I(max)
-1.5V     -251.7mA   -278.5mA   -229mA
-1.26V    -162.9mA   -193.3mA   -138.5mA
-1.14V    -120.2mA   -151.8mA   -97.38mA
-1.08V    -99.67mA   -131.5mA   -80.03mA
-1.02V    -80.03mA   -111.5mA   -67.19mA
-960mV    -61.9mA    -92.06mA   -58.66mA
-840mV    -34.78mA   -55.26mA   -43.35mA
-720mV    -20.13mA   -24.33mA   -27.34mA
-600mV    -9.255mA   -6.62mA    -13.04mA
-480mV    -2.103mA   -1.101mA   -2.949mA
-360mV    -117.9uA   -76.82uA   -121uA
3V        510.9uA    2.326mA    50.14uA
[POWER_clamp]
|Voltage   I(typ)   I(min)   I(max)
-1.5V     510.9uA    3.27mA     9.767uA
-1.14V    952.4nA    36.87uA    550.6nA
1.8V      -19.17uA   -2.808uA   -228.2uA
1.98V     -2.103mA   -254.3uA   -9.021mA
2.16V     -14.35mA   -5.837mA   -29.94mA
2.22V     -20.13mA   -11.99mA   -37.94mA
2.34V     -34.78mA   -36.12mA   -53.76mA
2.4V      -46.38mA   -52.39mA   -61.22mA
2.46V     -61.9mA    -70.14mA   -70.88mA
2.52V     -80.03mA   -88.86mA   -85.41mA
2.7V      -141.4mA   -148.4mA   -145.8mA
3V        -251.7mA   -253.4mA   -260.1mA
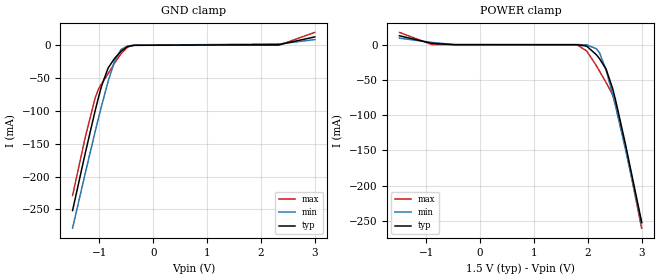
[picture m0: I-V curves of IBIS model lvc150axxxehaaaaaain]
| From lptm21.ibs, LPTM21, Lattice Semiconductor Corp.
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|   Model lvc150axxxehaaaaaain
[Model]   lvc150axxxehaaaaaain
Model_type   Input
Polarity   Non-Inverting
Enable   Active-Low
Vinl =   0.3750V
Vinh =   1.1250V
C_comp   4.2000pF   3.8000pF   7.5000pF
[Temperature Range]   25.0000   0.1050k   -40.0000
[Voltage Range]   1.5000V   1.4300V   1.5800V
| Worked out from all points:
|   GND clamp passes 1 mA (typ) near -0.44 V on its own axis
|   POWER clamp passes 1 mA (typ) near -0.84 V on its own axis
[GND_clamp]
|Voltage   I(typ)   I(min)   I(max)
-1.5V     -251.7mA   -278.5mA   -229mA
-1.26V    -162.9mA   -193.3mA   -138.5mA
-1.08V    -99.67mA   -131.5mA   -80.02mA
-1.02V    -80.03mA   -111.5mA   -67.18mA
-960mV    -61.9mA    -92.05mA   -58.65mA
-840mV    -34.77mA   -55.26mA   -43.34mA
-720mV    -20.13mA   -24.33mA   -27.33mA
-600mV    -9.252mA   -6.618mA   -13.03mA
-480mV    -2.101mA   -1.1mA     -2.946mA
-360mV    -117.5uA   -76.58uA   -120.4uA
2.34V     923.5uA    1.902mA    232.4uA
3V        12.62mA    8.573mA    19.57mA
[POWER_clamp]
|Voltage   I(typ)   I(min)   I(max)
-1.5V     12.62mA    9.257mA    17.43mA
-900mV    1.893mA    3.19mA     151.8uA
-480mV    1.282uA    43.16uA    340.2nA
1.8V      -19uA      -2.688uA   -227.3uA
1.98V     -2.101mA   -253.9uA   -9.017mA
2.16V     -14.35mA   -5.835mA   -29.93mA
2.22V     -20.13mA   -11.99mA   -37.94mA
2.34V     -34.77mA   -36.12mA   -53.75mA
2.46V     -61.9mA    -70.14mA   -70.88mA
2.52V     -80.03mA   -88.86mA   -85.4mA
2.7V      -141.4mA   -148.4mA   -145.8mA
3V        -251.7mA   -253.4mA   -260.1mA
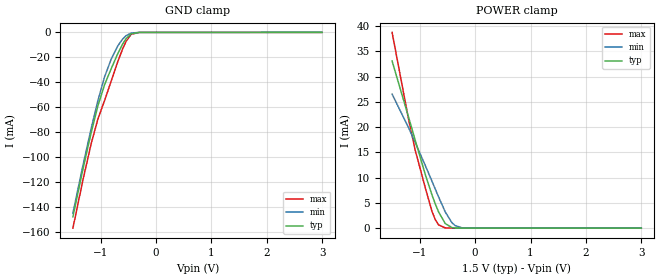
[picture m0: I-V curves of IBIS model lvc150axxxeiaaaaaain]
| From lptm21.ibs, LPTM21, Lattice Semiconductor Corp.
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|   Model lvc150axxxeiaaaaaain
[Model]   lvc150axxxeiaaaaaain
Model_type   Input
Polarity   Non-Inverting
Enable   Active-Low
Vinl =   0.3750V
Vinh =   1.1250V
C_comp   4.2000pF   3.8000pF   7.5000pF
[Temperature Range]   25.0000   0.1050k   -40.0000
[Voltage Range]   1.5000V   1.4300V   1.5800V
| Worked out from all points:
|   GND clamp passes 1 mA (typ) near -0.44 V on its own axis
|   POWER clamp passes 1 mA (typ) near -0.55 V on its own axis
[GND_clamp]
|Voltage   I(typ)   I(min)   I(max)
-1.5V     -148mA     -145.1mA   -157.1mA
-1.32V    -110mA     -107mA     -118.7mA
-1.17V    -80.44mA   -77.06mA   -89.3mA
-1.05V    -59.22mA   -54.98mA   -69.71mA
-930mV    -42.25mA   -35.9mA    -54.91mA
-810mV    -29.28mA   -21.6mA    -39.29mA
-690mV    -17.12mA   -10.87mA   -23.53mA
-600mV    -9.252mA   -5.256mA   -13.04mA
-540mV    -5.056mA   -2.651mA   -7.221mA
-450mV    -1.176mA   -584.3uA   -1.582mA
-300mV    -18.62uA   -15.88uA   -16.42uA
3V        0A         0A         0A
[POWER_clamp]
|Voltage   I(typ)   I(min)   I(max)
-1.5V     33.09mA    26.54mA    38.76mA
-1.2V     21.88mA    19.83mA    21.41mA
-1.08V    17.31mA    16.9mA     15.33mA
-900mV    10.59mA    12.38mA    7.966mA
-780mV    6.585mA    9.294mA    3.343mA
-720mV    4.798mA    7.731mA    1.687mA
-660mV    3.201mA    6.172mA    637.9uA
-540mV    907.7uA    3.212mA    50.7uA
-420mV    112.6uA    1.073mA    3.157uA
-360mV    35.33uA    495.5uA    755.6nA
-240mV    3.045uA    67.64uA    60.85nA
3V        -25.84nA   -23.03nA   -33.01nA
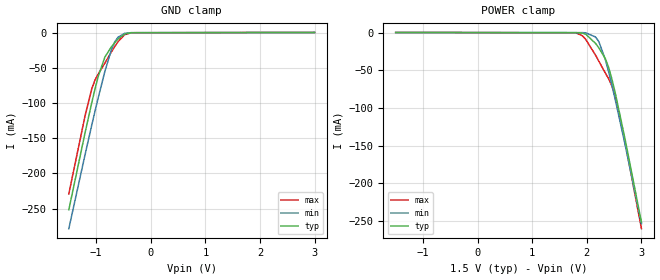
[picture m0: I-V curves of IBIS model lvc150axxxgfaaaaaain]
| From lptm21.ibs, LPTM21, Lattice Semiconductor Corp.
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|   Model lvc150axxxgfaaaaaain
[Model]   lvc150axxxgfaaaaaain
Model_type   Input
Polarity   Non-Inverting
Enable   Active-Low
Vinl =   0.3750V
Vinh =   1.1250V
C_comp   4.2000pF   3.8000pF   7.5000pF
[Temperature Range]   25.0000   0.1050k   -40.0000
[Voltage Range]   1.5000V   1.4300V   1.5800V
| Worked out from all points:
|   GND clamp passes 1 mA (typ) near -0.43 V on its own axis
[GND_clamp]
|Voltage   I(typ)   I(min)   I(max)
-1.5V     -251.7mA   -278.5mA   -229.1mA
-1.2V     -141.4mA   -172.5mA   -117.3mA
-1.08V    -99.69mA   -131.5mA   -80.08mA
-1.02V    -80.06mA   -111.5mA   -67.26mA
-960mV    -61.93mA   -92.07mA   -58.74mA
-840mV    -34.83mA   -55.28mA   -43.43mA
-720mV    -20.2mA    -24.36mA   -27.42mA
-660mV    -14.42mA   -13.44mA   -19.95mA
-600mV    -9.328mA   -6.667mA   -13.14mA
-480mV    -2.194mA   -1.163mA   -3.083mA
-360mV    -214.6uA   -133.3uA   -280.5uA
3V        126.9uA    61.94uA    238.3uA
[POWER_clamp]
|Voltage   I(typ)   I(min)   I(max)
-1.5V     126.9uA    62.16uA    237.5uA
1.8V      -103.7uA   -38.55uA   -389.1uA
1.92V     -692.3uA   -115uA     -4.287mA
1.98V     -2.194mA   -316uA     -9.129mA
2.16V     -14.42mA   -5.886mA   -30.02mA
2.22V     -20.2mA    -12.03mA   -38.02mA
2.34V     -34.83mA   -36.14mA   -53.84mA
2.4V      -46.42mA   -52.4mA    -61.3mA
2.46V     -61.93mA   -70.16mA   -70.95mA
2.52V     -80.06mA   -88.88mA   -85.46mA
2.7V      -141.4mA   -148.4mA   -145.9mA
3V        -251.7mA   -253.4mA   -260.1mA
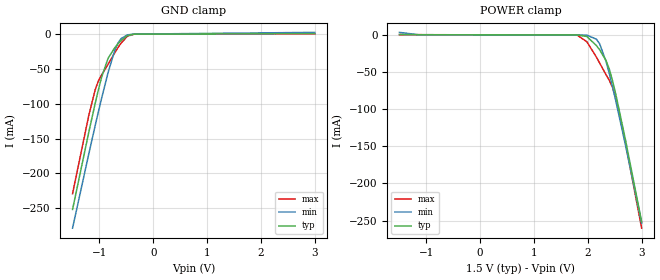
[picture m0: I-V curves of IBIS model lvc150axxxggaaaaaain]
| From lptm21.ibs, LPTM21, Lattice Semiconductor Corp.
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|   Model lvc150axxxggaaaaaain
[Model]   lvc150axxxggaaaaaain
Model_type   Input
Polarity   Non-Inverting
Enable   Active-Low
Vinl =   0.3750V
Vinh =   1.1250V
C_comp   4.2000pF   3.8000pF   7.5000pF
[Temperature Range]   25.0000   0.1050k   -40.0000
[Voltage Range]   1.5000V   1.4300V   1.5800V
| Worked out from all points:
|   GND clamp passes 1 mA (typ) near -0.43 V on its own axis
[GND_clamp]
|Voltage   I(typ)   I(min)   I(max)
-1.5V     -251.7mA   -278.5mA   -229.1mA
-1.2V     -141.4mA   -172.5mA   -117.3mA
-1.08V    -99.69mA   -131.5mA   -80.07mA
-1.02V    -80.05mA   -111.5mA   -67.24mA
-960mV    -61.93mA   -92.06mA   -58.72mA
-840mV    -34.82mA   -55.27mA   -43.42mA
-720mV    -20.18mA   -24.35mA   -27.41mA
-660mV    -14.41mA   -13.44mA   -19.93mA
-600mV    -9.32mA    -6.664mA   -13.13mA
-480mV    -2.191mA   -1.162mA   -3.079mA
-360mV    -214.1uA   -133uA     -280.1uA
3V        600.1uA    2.376mA    260.2uA
[POWER_clamp]
|Voltage   I(typ)   I(min)   I(max)
-1.5V     600.1uA    3.322mA    240.3uA
-1.14V    125.3uA    93.51uA    234.2uA
1.8V      -103.5uA   -38.42uA   -388.4uA
1.98V     -2.191mA   -315.4uA   -9.121mA
2.16V     -14.41mA   -5.883mA   -30.01mA
2.22V     -20.18mA   -12.03mA   -38.01mA
2.34V     -34.82mA   -36.13mA   -53.82mA
2.4V      -46.41mA   -52.4mA    -61.28mA
2.46V     -61.93mA   -70.15mA   -70.93mA
2.52V     -80.05mA   -88.87mA   -85.44mA
2.7V      -141.4mA   -148.4mA   -145.8mA
3V        -251.7mA   -253.4mA   -260.1mA
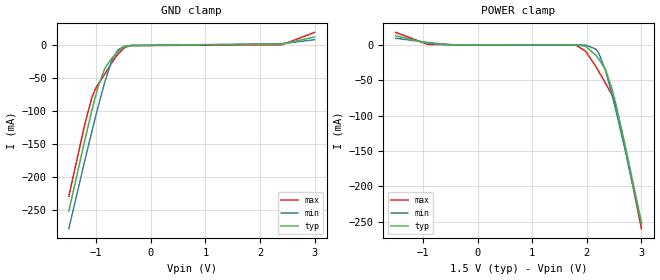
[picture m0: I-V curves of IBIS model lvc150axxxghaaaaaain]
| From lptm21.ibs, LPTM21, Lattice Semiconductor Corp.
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|   Model lvc150axxxghaaaaaain
[Model]   lvc150axxxghaaaaaain
Model_type   Input
Polarity   Non-Inverting
Enable   Active-Low
Vinl =   0.3750V
Vinh =   1.1250V
C_comp   4.2000pF   3.8000pF   7.5000pF
[Temperature Range]   25.0000   0.1050k   -40.0000
[Voltage Range]   1.5000V   1.4300V   1.5800V
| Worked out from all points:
|   GND clamp passes 1 mA (typ) near -0.43 V on its own axis
|   POWER clamp passes 1 mA (typ) near -0.84 V on its own axis
[GND_clamp]
|Voltage   I(typ)   I(min)   I(max)
-1.5V     -251.7mA   -278.5mA   -229.1mA
-1.2V     -141.4mA   -172.5mA   -117.3mA
-1.08V    -99.68mA   -131.5mA   -80.06mA
-1.02V    -80.05mA   -111.5mA   -67.24mA
-960mV    -61.92mA   -92.06mA   -58.72mA
-840mV    -34.81mA   -55.27mA   -43.41mA
-720mV    -20.18mA   -24.35mA   -27.4mA
-600mV    -9.317mA   -6.662mA   -13.12mA
-480mV    -2.189mA   -1.161mA   -3.077mA
-360mV    -213.9uA   -132.8uA   -279.8uA
2.4V      1.986mA    2.546mA    930.6uA
3V        12.76mA    8.66mA     19.77mA
[POWER_clamp]
|Voltage   I(typ)   I(min)   I(max)
-1.5V     12.76mA    9.346mA    17.61mA
-900mV    1.986mA    3.248mA    333.3uA
-480mV    122uA      97.87uA    228.2uA
1.8V      -103.4uA   -38.3uA    -388uA
1.98V     -2.189mA   -315.1uA   -9.117mA
2.16V     -14.41mA   -5.881mA   -30mA
2.22V     -20.18mA   -12.03mA   -38mA
2.34V     -34.81mA   -36.13mA   -53.82mA
2.46V     -61.92mA   -70.15mA   -70.93mA
2.52V     -80.05mA   -88.87mA   -85.44mA
2.7V      -141.4mA   -148.4mA   -145.8mA
3V        -251.7mA   -253.4mA   -260.1mA
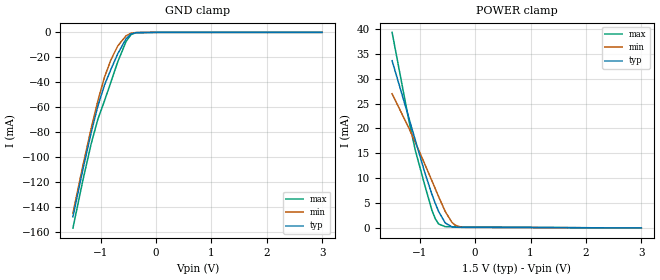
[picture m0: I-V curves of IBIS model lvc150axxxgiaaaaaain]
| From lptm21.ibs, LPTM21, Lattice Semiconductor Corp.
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|   Model lvc150axxxgiaaaaaain
[Model]   lvc150axxxgiaaaaaain
Model_type   Input
Polarity   Non-Inverting
Enable   Active-Low
Vinl =   0.3750V
Vinh =   1.1250V
C_comp   4.2000pF   3.8000pF   7.5000pF
[Temperature Range]   25.0000   0.1050k   -40.0000
[Voltage Range]   1.5000V   1.4300V   1.5800V
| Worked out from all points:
|   GND clamp passes 1 mA (typ) near -0.44 V on its own axis
|   POWER clamp passes 1 mA (typ) near -0.54 V on its own axis
[GND_clamp]
|Voltage   I(typ)   I(min)   I(max)
-1.5V     -148mA     -145.1mA   -157.1mA
-1.32V    -110mA     -107mA     -118.7mA
-1.17V    -80.48mA   -77.09mA   -89.35mA
-1.05V    -59.26mA   -55.01mA   -69.77mA
-930mV    -42.29mA   -35.93mA   -54.98mA
-810mV    -29.33mA   -21.63mA   -39.36mA
-690mV    -17.18mA   -10.91mA   -23.6mA
-540mV    -5.131mA   -2.707mA   -7.327mA
-450mV    -1.269mA   -646.6uA   -1.725mA
-360mV    -213.6uA   -130.7uA   -279.5uA
0V        0A         0A         0A
3V        0A         0A         0A
[POWER_clamp]
|Voltage   I(typ)   I(min)   I(max)
-1.5V     33.6mA     26.96mA    39.3mA
-1.2V     22.23mA    20.13mA    21.75mA
-1.08V    17.59mA    17.16mA    15.56mA
-900mV    10.78mA    12.58mA    8.18mA
-780mV    6.728mA    9.453mA    3.516mA
-720mV    4.925mA    7.87mA     1.844mA
-660mV    3.313mA    6.291mA    793.6uA
-540mV    997.8uA    3.293mA    253uA
-420mV    212.5uA    1.125mA    228.2uA
-360mV    145.3uA    543uA      226.9uA
-240mV    121.5uA    119.5uA    225.5uA
3V        -25.18nA   -1.33uA    -40.71uA
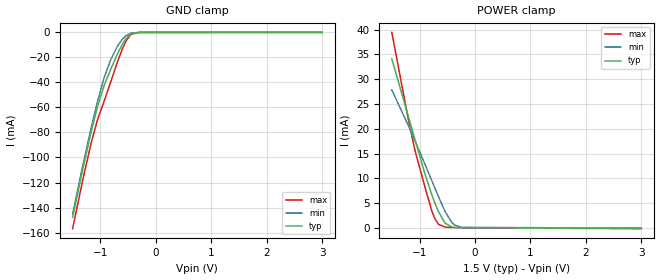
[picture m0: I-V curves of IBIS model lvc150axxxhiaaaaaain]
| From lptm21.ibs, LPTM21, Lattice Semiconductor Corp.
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|   Model lvc150axxxhiaaaaaain
[Model]   lvc150axxxhiaaaaaain
Model_type   Input
Polarity   Non-Inverting
Enable   Active-Low
Vinl =   0.3750V
Vinh =   1.1250V
C_comp   4.2000pF   3.8000pF   7.5000pF
[Temperature Range]   25.0000   0.1050k   -40.0000
[Voltage Range]   1.5000V   1.4300V   1.5800V
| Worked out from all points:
|   GND clamp passes 1 mA (typ) near -0.44 V on its own axis
|   POWER clamp passes 1 mA (typ) near -0.54 V on its own axis
[GND_clamp]
|Voltage   I(typ)   I(min)   I(max)
-1.5V     -147.9mA   -145.1mA   -156.9mA
-1.32V    -109.9mA   -107mA     -118.5mA
-1.17V    -80.39mA   -77.05mA   -89.2mA
-1.05V    -59.17mA   -54.96mA   -69.62mA
-930mV    -42.2mA    -35.88mA   -54.83mA
-810mV    -29.25mA   -21.58mA   -39.21mA
-690mV    -17.09mA   -10.87mA   -23.45mA
-600mV    -9.233mA   -5.258mA   -12.98mA
-540mV    -5.047mA   -2.659mA   -7.175mA
-450mV    -1.185mA   -599.1uA   -1.573mA
-300mV    -18.73uA   -15.61uA   -8.8uA
3V        0A         0A         0A
[POWER_clamp]
|Voltage   I(typ)   I(min)   I(max)
-1.5V     34.08mA    27.83mA    39.45mA
-1.2V     22.44mA    20.61mA    21.74mA
-1.08V    17.72mA    17.52mA    15.53mA
-900mV    10.82mA    12.79mA    8.145mA
-780mV    6.739mA    9.58mA     3.478mA
-720mV    4.93mA     7.965mA    1.803mA
-660mV    3.313mA    6.359mA    743.4uA
-540mV    987.9uA    3.323mA    158.4uA
-420mV    184.8uA    1.136mA    86.1uA
-360mV    103.6uA    547.9uA    64.36uA
-240mV    51.4uA     112.2uA    24.82uA
3V        -84.27uA   -47.29uA   -151.1uA
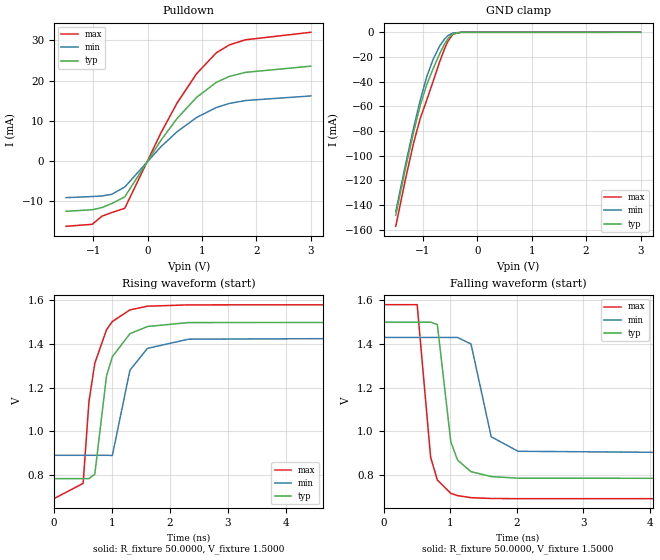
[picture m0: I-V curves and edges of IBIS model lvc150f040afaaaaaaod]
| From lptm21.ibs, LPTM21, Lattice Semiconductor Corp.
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|   Model lvc150f040afaaaaaaod
[Model]   lvc150f040afaaaaaaod
Model_type   I/O_open_drain
Polarity   Non-Inverting
Enable   Active-Low
Vinl =   0.3750V
Vinh =   1.1250V
Vmeas =   0.7500V
Cref =   0.0F
Rref =   1.0000M
Vref =   0.0V
C_comp   4.2000pF   3.8000pF   7.5000pF
[Temperature Range]   25.0000   0.1050k   -40.0000
[Voltage Range]   1.5000V   1.4300V   1.5800V
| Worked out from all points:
|   slope of the pulldown table from 0 to 0.225 V, typ, clamps not added: 46.8 ohm
|   GND clamp passes 1 mA (typ) near -0.44 V on its own axis
|   rising waveform, R_fixture 50.0000, V_fixture 1.5000: 20-80 % time 287ps typ, 282ps min, 269ps max; typ from 0.784 V to 1.5 V
|   falling waveform, R_fixture 50.0000, V_fixture 1.5000: 20-80 % time 191ps typ, 231ps min, 169ps max; typ from 1.5 V to 0.784 V
[Pulldown]
|Voltage   I(typ)   I(min)   I(max)
-1.5V     -12.44mA   -9.05mA    -16.17mA
-1.02V    -12.06mA   -8.773mA   -15.67mA
-840mV    -11.51mA   -8.628mA   -13.65mA
-660mV    -10.51mA   -8.22mA    -12.76mA
-420mV    -8.853mA   -6.399mA   -11.69mA
240mV     5.112mA    3.55mA     6.922mA
540mV     10.6mA     7.314mA    14.44mA
900mV     15.86mA    10.86mA    21.74mA
1.26V     19.57mA    13.34mA    26.91mA
1.5V      21.05mA    14.35mA    28.88mA
1.8V      22.08mA    15.08mA    30.17mA
3V        23.61mA    16.22mA    32.03mA
[GND_clamp]
|Voltage   I(typ)   I(min)   I(max)
-1.5V     -148.1mA   -145.2mA   -157.1mA
-1.32V    -110.1mA   -107mA     -118.7mA
-1.17V    -80.47mA   -77.11mA   -89.33mA
-1.05V    -59.24mA   -55.01mA   -69.75mA
-930mV    -42.27mA   -35.92mA   -54.95mA
-810mV    -29.3mA    -21.61mA   -39.32mA
-690mV    -17.14mA   -10.88mA   -23.55mA
-600mV    -9.267mA   -5.265mA   -13.06mA
-540mV    -5.068mA   -2.658mA   -7.239mA
-450mV    -1.182mA   -586.7uA   -1.592mA
-300mV    -18.83uA   -15.98uA   -16.74uA
3V        0A         0A         0A
[Ramp]
| variable   typ   min   max
dV/dt_r  0.4296/0.2842n   0.3235/0.2797n   0.5327/0.2663n
dV/dt_f  0.4296/0.1896n   0.3235/0.2286n   0.5327/0.1669n
R_load = 50.0000
[Rising Waveform]
R_fixture=   50.0000
V_fixture=   1.5000
V_fixture_min=   1.4300
V_fixture_max=   1.5800
|time   V(typ)   V(min)   V(max)
0s        784mV      890.8mV    692.2mV
505.1ps   784mV      890.8mV    762.1mV
606.1ps   784.1mV    890.8mV    1.136V
707.1ps   804.1mV    890.8mV    1.312V
909.1ps   1.253V     890.8mV    1.465V
1.01ns    1.342V     889.9mV    1.503V
1.313ns   1.447V     1.28V      1.556V
1.616ns   1.48V      1.38V      1.573V
2.323ns   1.498V     1.422V     1.579V
10ns      1.5V       1.43V      1.58V
[Falling Waveform]
R_fixture=   50.0000
V_fixture=   1.5000
V_fixture_min=   1.4300
V_fixture_max=   1.5800
|time   V(typ)   V(min)   V(max)
0s        1.5V       1.43V      1.58V
505.1ps   1.5V       1.43V      1.58V
707.1ps   1.5V       1.43V      881.9mV
808.1ps   1.489V     1.43V      777.3mV
1.01ns    952.3mV    1.43V      716.9mV
1.111ns   869.1mV    1.43V      706.2mV
1.313ns   815.8mV    1.4V       696.8mV
1.616ns   793.4mV    975.4mV    693.1mV
2.02ns    786mV      909.1mV    692.3mV
10ns      784mV      890.8mV    692.2mV
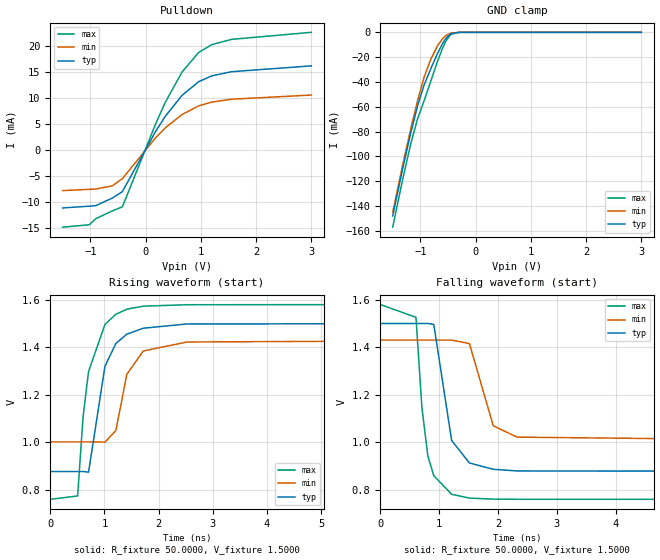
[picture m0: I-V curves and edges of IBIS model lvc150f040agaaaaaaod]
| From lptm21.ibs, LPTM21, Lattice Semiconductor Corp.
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|   Model lvc150f040agaaaaaaod
[Model]   lvc150f040agaaaaaaod
Model_type   I/O_open_drain
Polarity   Non-Inverting
Enable   Active-Low
Vinl =   0.3750V
Vinh =   1.1250V
Vmeas =   0.7500V
Cref =   0.0F
Rref =   1.0000M
Vref =   0.0V
C_comp   4.2000pF   3.8000pF   7.5000pF
[Temperature Range]   25.0000   0.1050k   -40.0000
[Voltage Range]   1.5000V   1.4300V   1.5800V
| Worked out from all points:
|   slope of the pulldown table from 0 to 0.225 V, typ, clamps not added: 52.9 ohm
|   GND clamp passes 1 mA (typ) near -0.44 V on its own axis
|   rising waveform, R_fixture 50.0000, V_fixture 1.5000: 20-80 % time 287ps typ, 295ps min, 287ps max; typ from 0.876 V to 1.5 V
|   falling waveform, R_fixture 50.0000, V_fixture 1.5000: 20-80 % time 243ps typ, 287ps min, 195ps max; typ from 1.5 V to 0.876 V
[Pulldown]
|Voltage   I(typ)   I(min)   I(max)
-1.5V     -11.23mA   -7.89mA    -14.93mA
-1.02V    -10.89mA   -7.649mA   -14.47mA
-900mV    -10.78mA   -7.588mA   -13.29mA
-600mV    -9.318mA   -6.96mA    -11.79mA
-420mV    -8.084mA   -5.596mA   -11.02mA
180mV     3.467mA    2.274mA    4.899mA
360mV     6.469mA    4.221mA    9.187mA
660mV     10.45mA    6.76mA     14.94mA
960mV     13.08mA    8.424mA    18.71mA
1.2V      14.21mA    9.162mA    20.22mA
1.56V     15.01mA    9.71mA     21.24mA
3V        16.13mA    10.51mA    22.59mA
[GND_clamp]
|Voltage   I(typ)   I(min)   I(max)
-1.5V     -148.1mA   -145.1mA   -157.1mA
-1.32V    -110mA     -107mA     -118.7mA
-1.17V    -80.46mA   -77.1mA    -89.31mA
-1.05V    -59.23mA   -55mA      -69.72mA
-930mV    -42.26mA   -35.91mA   -54.92mA
-810mV    -29.29mA   -21.6mA    -39.3mA
-690mV    -17.13mA   -10.88mA   -23.54mA
-600mV    -9.258mA   -5.26mA    -13.05mA
-540mV    -5.061mA   -2.654mA   -7.228mA
-450mV    -1.178mA   -585.4uA   -1.585mA
-300mV    -18.71uA   -15.93uA   -16.54uA
3V        0A         0A         0A
[Ramp]
| variable   typ   min   max
dV/dt_r  0.3746/0.2839n   0.2575/0.2921n   0.4927/0.2840n
dV/dt_f  0.3746/0.2402n   0.2575/0.2843n   0.4927/0.1934n
R_load = 50.0000
[Rising Waveform]
R_fixture=   50.0000
V_fixture=   1.5000
V_fixture_min=   1.4300
V_fixture_max=   1.5800
|time   V(typ)   V(min)   V(max)
0s        875.7mV    1.001V     758.8mV
505.1ps   875.7mV    1.001V     773mV
606.1ps   876.1mV    1.001V     1.108V
707.1ps   873.4mV    1.001V     1.298V
1.01ns    1.32V      1V         1.496V
1.212ns   1.416V     1.049V     1.539V
1.414ns   1.455V     1.286V     1.56V
1.717ns   1.48V      1.384V     1.573V
2.525ns   1.498V     1.422V     1.579V
10ns      1.5V       1.43V      1.58V
[Falling Waveform]
R_fixture=   50.0000
V_fixture=   1.5000
V_fixture_min=   1.4300
V_fixture_max=   1.5800
|time   V(typ)   V(min)   V(max)
0s        1.5V       1.43V      1.58V
606.1ps   1.5V       1.43V      1.526V
707.1ps   1.5V       1.43V      1.146V
808.1ps   1.5V       1.43V      941.5mV
909.1ps   1.496V     1.43V      858.5mV
1.212ns   1.007V     1.43V      780.2mV
1.515ns   911.9mV    1.415V     764mV
1.919ns   885.5mV    1.069V     759.6mV
2.323ns   878.5mV    1.021V     759mV
10ns      875.6mV    1.001V     758.8mV
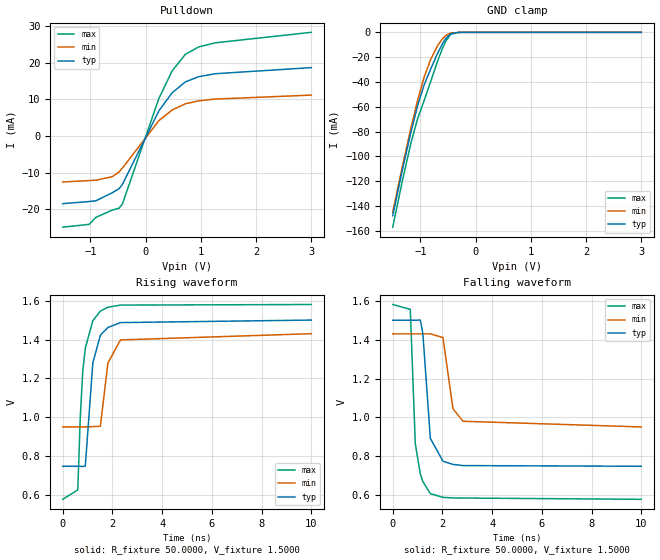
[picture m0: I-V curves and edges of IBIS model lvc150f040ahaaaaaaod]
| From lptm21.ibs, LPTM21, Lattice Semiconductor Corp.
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|   Model lvc150f040ahaaaaaaod
[Model]   lvc150f040ahaaaaaaod
Model_type   I/O_open_drain
Polarity   Non-Inverting
Enable   Active-Low
Vinl =   0.3750V
Vinh =   1.1250V
Vmeas =   0.7500V
Cref =   0.0F
Rref =   1.0000M
Vref =   0.0V
C_comp   4.2000pF   3.8000pF   7.5000pF
[Temperature Range]   25.0000   0.1050k   -40.0000
[Voltage Range]   1.5000V   1.4300V   1.5800V
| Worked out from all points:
|   slope of the pulldown table from 0 to 0.225 V, typ, clamps not added: 34.7 ohm
|   GND clamp passes 1 mA (typ) near -0.44 V on its own axis
|   rising waveform, R_fixture 50.0000, V_fixture 1.5000: 20-80 % time 293ps typ, 297ps min, 298ps max; typ from 0.749 V to 1.5 V
|   falling waveform, R_fixture 50.0000, V_fixture 1.5000: 20-80 % time 261ps typ, 313ps min, 236ps max; typ from 1.5 V to 0.749 V
[Pulldown]
|Voltage   I(typ)   I(min)   I(max)
-1.5V     -18.51mA   -12.59mA   -24.94mA
-1.02V    -17.94mA   -12.2mA    -24.17mA
-900mV    -17.73mA   -12.1mA    -22.27mA
-600mV    -15.51mA   -11.12mA   -20.25mA
-480mV    -14.4mA    -9.834mA   -19.76mA
-420mV    -13.27mA   -8.803mA   -18.63mA
240mV     6.859mA    4.183mA    10.22mA
480mV     11.8mA     7.089mA    17.77mA
720mV     14.79mA    8.792mA    22.32mA
960mV     16.2mA     9.6mA      24.34mA
1.26V     17.02mA    10.09mA    25.47mA
3V        18.69mA    11.17mA    28.34mA
[GND_clamp]
|Voltage   I(typ)   I(min)   I(max)
-1.5V     -148mA     -145.1mA   -157.1mA
-1.32V    -110mA     -107mA     -118.7mA
-1.17V    -80.45mA   -77.09mA   -89.3mA
-1.05V    -59.22mA   -54.99mA   -69.72mA
-930mV    -42.25mA   -35.9mA    -54.92mA
-810mV    -29.28mA   -21.6mA    -39.3mA
-690mV    -17.13mA   -10.87mA   -23.53mA
-600mV    -9.254mA   -5.257mA   -13.04mA
-540mV    -5.058mA   -2.652mA   -7.223mA
-450mV    -1.176mA   -584.6uA   -1.583mA
-300mV    -18.65uA   -15.9uA    -16.45uA
3V        0A         0A         0A
[Ramp]
| variable   typ   min   max
dV/dt_r  0.4508/0.2899n   0.2874/0.2936n   0.6007/0.2946n
dV/dt_f  0.4508/0.2581n   0.2874/0.3101n   0.6012/0.2337n
R_load = 50.0000
[Rising Waveform]
R_fixture=   50.0000
V_fixture=   1.5000
V_fixture_min=   1.4300
V_fixture_max=   1.5800
|time   V(typ)   V(min)   V(max)
0s        748.6mV    951mV      578.8mV
606.1ps   748.7mV    951.1mV    627.2mV
707.1ps   749.2mV    951.1mV    1.002V
808.1ps   747.2mV    951mV      1.239V
909.1ps   750.2mV    951mV      1.356V
1.212ns   1.28V      952.4mV    1.497V
1.515ns   1.422V     954.2mV    1.546V
1.818ns   1.462V     1.279V     1.566V
2.323ns   1.487V     1.398V     1.577V
10ns      1.5V       1.43V      1.58V
[Falling Waveform]
R_fixture=   50.0000
V_fixture=   1.5000
V_fixture_min=   1.4300
V_fixture_max=   1.5800
|time   V(typ)   V(min)   V(max)
0s        1.5V       1.43V      1.581V
707.1ps   1.5V       1.43V      1.556V
909.1ps   1.5V       1.43V      864.1mV
1.111ns   1.501V     1.43V      708.9mV
1.212ns   1.432V     1.43V      670.6mV
1.515ns   892mV      1.43V      607.9mV
2.02ns    774.9mV    1.411V     588.8mV
2.424ns   758.4mV    1.045V     586mV
2.828ns   752.4mV    980.3mV    585.4mV
10ns      748.7mV    951.1mV    578.7mV
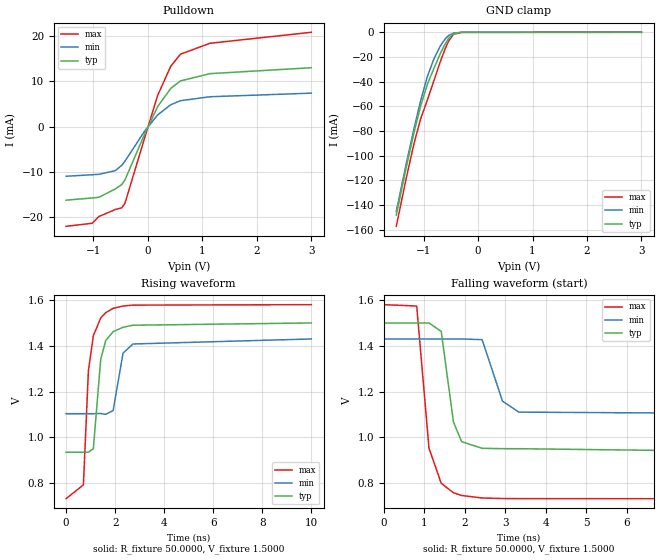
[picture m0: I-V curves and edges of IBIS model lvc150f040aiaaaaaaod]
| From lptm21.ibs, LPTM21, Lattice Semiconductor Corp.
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|   Model lvc150f040aiaaaaaaod
[Model]   lvc150f040aiaaaaaaod
Model_type   I/O_open_drain
Polarity   Non-Inverting
Enable   Active-Low
Vinl =   0.3750V
Vinh =   1.1250V
Vmeas =   0.7500V
Cref =   0.0F
Rref =   1.0000M
Vref =   0.0V
C_comp   4.2000pF   3.8000pF   7.5000pF
[Temperature Range]   25.0000   0.1050k   -40.0000
[Voltage Range]   1.5000V   1.4300V   1.5800V
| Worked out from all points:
|   slope of the pulldown table from 0 to 0.225 V, typ, clamps not added: 42.4 ohm
|   GND clamp passes 1 mA (typ) near -0.44 V on its own axis
|   rising waveform, R_fixture 50.0000, V_fixture 1.5000: 20-80 % time 308ps typ, 322ps min, 306ps max; typ from 0.934 V to 1.5 V
|   falling waveform, R_fixture 50.0000, V_fixture 1.5000: 20-80 % time 275ps typ, 325ps min, 280ps max; typ from 1.5 V to 0.936 V
[Pulldown]
|Voltage   I(typ)   I(min)   I(max)
-1.5V     -16.19mA   -10.92mA   -21.94mA
-1.02V    -15.7mA    -10.59mA   -21.27mA
-900mV    -15.56mA   -10.5mA    -19.8mA
-600mV    -13.74mA   -9.7mA     -18.26mA
-480mV    -12.77mA   -8.548mA   -17.88mA
-420mV    -11.75mA   -7.622mA   -16.89mA
-60mV     -1.68mA    -1.008mA   -2.556mA
180mV     4.403mA    2.572mA    6.858mA
420mV     8.409mA    4.818mA    13.28mA
600mV     10.07mA    5.709mA    15.95mA
1.14V     11.66mA    6.58mA     18.35mA
3V        12.97mA    7.372mA    20.77mA
[GND_clamp]
|Voltage   I(typ)   I(min)   I(max)
-1.5V     -148mA     -145.1mA   -157.1mA
-1.32V    -110mA     -107mA     -118.7mA
-1.17V    -80.44mA   -77.06mA   -89.3mA
-1.05V    -59.22mA   -54.98mA   -69.71mA
-930mV    -42.25mA   -35.9mA    -54.91mA
-810mV    -29.28mA   -21.6mA    -39.29mA
-690mV    -17.12mA   -10.87mA   -23.53mA
-600mV    -9.252mA   -5.256mA   -13.04mA
-540mV    -5.056mA   -2.651mA   -7.221mA
-450mV    -1.176mA   -584.3uA   -1.582mA
-300mV    -18.62uA   -15.88uA   -16.42uA
3V        0A         0A         0A
[Ramp]
| variable   typ   min   max
dV/dt_r  0.3394/0.3046n   0.1964/0.3190n   0.5091/0.3033n
dV/dt_f  0.3394/0.3230n   0.1947/0.3246n   0.5091/0.2772n
R_load = 50.0000
[Rising Waveform]
R_fixture=   50.0000
V_fixture=   1.5000
V_fixture_min=   1.4300
V_fixture_max=   1.5800
|time   V(typ)   V(min)   V(max)
0s        934.4mV    1.103V     731.4mV
707.1ps   934.5mV    1.103V     792.1mV
909.1ps   934.8mV    1.103V     1.289V
1.111ns   949.7mV    1.103V     1.444V
1.414ns   1.342V     1.104V     1.522V
1.616ns   1.423V     1.1V       1.545V
1.919ns   1.462V     1.117V     1.564V
2.323ns   1.481V     1.368V     1.574V
2.727ns   1.49V      1.408V     1.578V
10ns      1.5V       1.43V      1.58V
[Falling Waveform]
R_fixture=   50.0000
V_fixture=   1.5000
V_fixture_min=   1.4300
V_fixture_max=   1.5800
|time   V(typ)   V(min)   V(max)
0s        1.5V       1.43V      1.58V
808.1ps   1.5V       1.43V      1.574V
1.111ns   1.5V       1.43V      952.8mV
1.414ns   1.463V     1.43V      799mV
1.717ns   1.066V     1.43V      757.3mV
1.919ns   980.8mV    1.43V      745.5mV
2.424ns   951.8mV    1.427V     734.6mV
2.929ns   950.2mV    1.158V     732.2mV
3.333ns   950.1mV    1.11V      731.7mV
10ns      935.7mV    1.103V     731.5mV
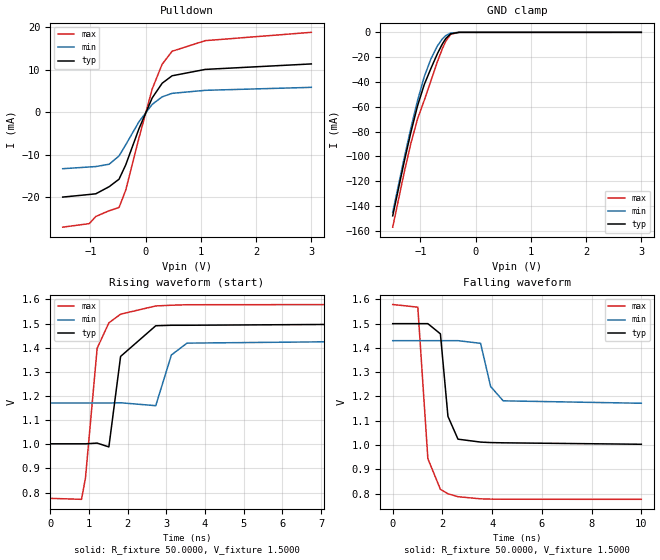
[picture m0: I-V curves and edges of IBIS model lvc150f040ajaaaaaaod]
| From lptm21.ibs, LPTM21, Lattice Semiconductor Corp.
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|   Model lvc150f040ajaaaaaaod
[Model]   lvc150f040ajaaaaaaod
Model_type   I/O_open_drain
Polarity   Non-Inverting
Enable   Active-Low
Vinl =   0.3750V
Vinh =   1.1250V
Vmeas =   0.7500V
Cref =   0.0F
Rref =   1.0000M
Vref =   0.0V
C_comp   4.2000pF   3.8000pF   7.5000pF
[Temperature Range]   25.0000   0.1050k   -40.0000
[Voltage Range]   1.5000V   1.4300V   1.5800V
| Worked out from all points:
|   slope of the pulldown table from 0 to 0.225 V, typ, clamps not added: 40.5 ohm
|   GND clamp passes 1 mA (typ) near -0.44 V on its own axis
|   rising waveform, R_fixture 50.0000, V_fixture 1.5000: 20-80 % time 252ps typ, 302ps min, 310ps max; typ from 1 V to 1.5 V
|   falling waveform, R_fixture 50.0000, V_fixture 1.5000: 20-80 % time 290ps typ, 376ps min, 293ps max; typ from 1.5 V to 1 V
[Pulldown]
|Voltage   I(typ)   I(min)   I(max)
-1.5V     -20.01mA   -13.33mA   -27.09mA
-1.02V    -19.4mA    -12.92mA   -26.26mA
-900mV    -19.23mA   -12.82mA   -24.57mA
-660mV    -17.57mA   -12.28mA   -23.23mA
-480mV    -15.79mA   -10.32mA   -22.45mA
-360mV    -12.45mA   -7.709mA   -18.4mA
-120mV    -3.929mA   -2.278mA   -6.111mA
120mV     3.345mA    1.822mA    5.45mA
300mV     6.792mA    3.593mA    11.27mA
480mV     8.549mA    4.413mA    14.32mA
1.08V     10.05mA    5.125mA    16.82mA
3V        11.34mA    5.826mA    18.78mA
[GND_clamp]
|Voltage   I(typ)   I(min)   I(max)
-1.5V     -147.9mA   -145mA     -157mA
-1.29V    -103.8mA   -100.8mA   -112.5mA
-1.17V    -80.38mA   -77mA      -89.28mA
-1.05V    -59.17mA   -54.93mA   -69.71mA
-930mV    -42.22mA   -35.86mA   -54.91mA
-810mV    -29.28mA   -21.58mA   -39.29mA
-690mV    -17.12mA   -10.87mA   -23.53mA
-600mV    -9.251mA   -5.255mA   -13.04mA
-540mV    -5.055mA   -2.651mA   -7.219mA
-450mV    -1.175mA   -584uA     -1.58mA
-300mV    -18.6uA    -15.87uA   -16.38uA
3V        0A         0A         0A
[Ramp]
| variable   typ   min   max
dV/dt_r  0.2977/0.2498n   0.1547/0.2991n   0.4820/0.3065n
dV/dt_f  0.2980/0.2868n   0.1547/0.3718n   0.4820/0.2900n
R_load = 50.0000
[Rising Waveform]
R_fixture=   50.0000
V_fixture=   1.5000
V_fixture_min=   1.4300
V_fixture_max=   1.5800
|time   V(typ)   V(min)   V(max)
0s        1.002V     1.171V     776.1mV
808.1ps   1.002V     1.171V     772.1mV
909.1ps   1.002V     1.171V     859.9mV
1.212ns   1.005V     1.171V     1.398V
1.515ns   989.1mV    1.171V     1.503V
1.818ns   1.364V     1.172V     1.539V
2.727ns   1.491V     1.16V      1.573V
3.131ns   1.493V     1.37V      1.576V
3.535ns   1.493V     1.419V     1.578V
10ns      1.499V     1.429V     1.579V
[Falling Waveform]
R_fixture=   50.0000
V_fixture=   1.5000
V_fixture_min=   1.4300
V_fixture_max=   1.5800
|time   V(typ)   V(min)   V(max)
0s        1.5V       1.43V      1.579V
1.01ns    1.5V       1.43V      1.568V
1.414ns   1.5V       1.43V      943.8mV
1.919ns   1.458V     1.43V      817.2mV
2.222ns   1.118V     1.43V      799.1mV
2.626ns   1.024V     1.43V      786.9mV
3.535ns   1.012V     1.419V     778.1mV
3.939ns   1.01V      1.241V     777mV
4.444ns   1.009V     1.182V     776.5mV
10ns      1.003V     1.172V     776.1mV
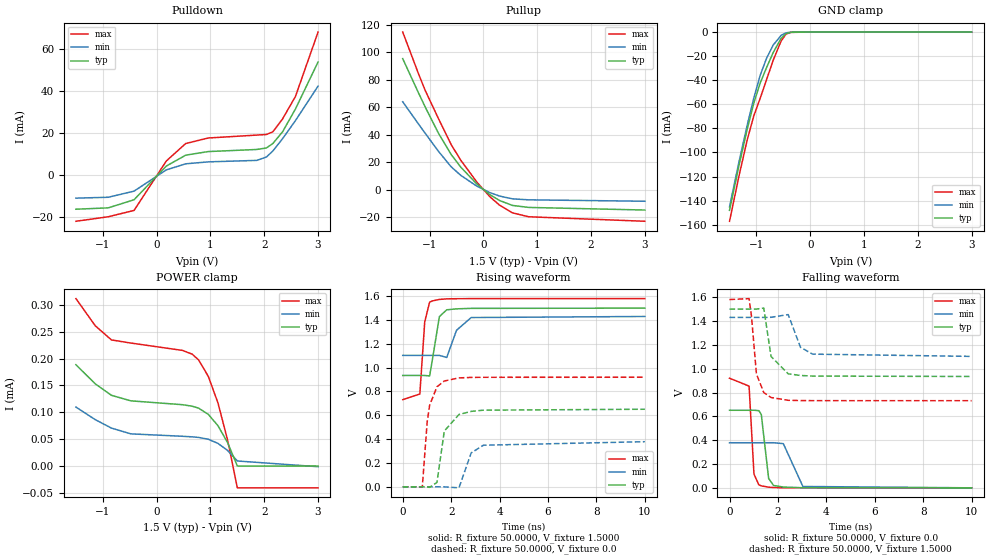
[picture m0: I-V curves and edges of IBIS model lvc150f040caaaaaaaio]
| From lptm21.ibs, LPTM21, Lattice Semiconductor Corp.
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|   Model lvc150f040caaaaaaaio
[Model]   lvc150f040caaaaaaaio
Model_type   I/O
Polarity   Non-Inverting
Enable   Active-Low
Vinl =   0.3750V
Vinh =   1.1250V
Vmeas =   0.7500V
Cref =   0.0F
Rref =   1.0000M
Vref =   0.0V
C_comp   3.0000pF   2.7000pF   3.3000pF
[Temperature Range]   25.0000   0.1050k   -40.0000
[Voltage Range]   1.5000V   1.4300V   1.5800V
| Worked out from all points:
|   slope of the pulldown table from 0 to 0.225 V, typ, clamps not added: 42.8 ohm
|   slope of the pullup table from 0 to 0.225 V, typ, clamps not added: 36.2 ohm
|   GND clamp passes 1 mA (typ) near -0.44 V on its own axis
|   rising waveform, R_fixture 50.0000, V_fixture 1.5000: 20-80 % time 262ps typ, 394ps min, 178ps max; typ from 0.934 V to 1.5 V
|   rising waveform, R_fixture 50.0000, V_fixture 0.0: 20-80 % time 359ps typ, 425ps min, 296ps max; typ from 0 V to 0.651 V
|   falling waveform, R_fixture 50.0000, V_fixture 0.0: 20-80 % time 209ps typ, 312ps min, 152ps max; typ from 0.651 V to 0 V
|   falling waveform, R_fixture 50.0000, V_fixture 1.5000: 20-80 % time 298ps typ, 359ps min, 263ps max; typ from 1.5 V to 0.934 V
[Pulldown]
|Voltage   I(typ)   I(min)   I(max)
-1.5V     -16.15mA   -10.89mA   -21.88mA
-900mV    -15.51mA   -10.47mA   -19.73mA
-420mV    -11.65mA   -7.561mA   -16.73mA
180mV     4.36mA     2.55mA     6.777mA
540mV     9.538mA    5.428mA    15.07mA
960mV     11.25mA    6.355mA    17.7mA
1.86V     12.24mA    7.056mA    19.08mA
2.04V     12.97mA    8.653mA    19.36mA
2.16V     15.08mA    11.52mA    20.63mA
2.34V     20.61mA    17.37mA    26.74mA
2.58V     31.49mA    25.98mA    37.46mA
3V        53.83mA    42.34mA    68.05mA
[Pullup]
|Voltage   I(typ)   I(min)   I(max)
-1.5V     95.49mA    64.04mA    114.9mA
-1.2V     69.96mA    47.45mA    83.78mA
-1.08V    60.05mA    40.95mA    72.14mA
-840mV    41.42mA    28.13mA    52.1mA
-600mV    25.59mA    16.62mA    32.85mA
-420mV    16.32mA    10.35mA    21.33mA
-120mV    3.987mA    2.469mA    5.382mA
120mV     -3.716mA   -2.21mA    -5.232mA
300mV     -7.977mA   -4.726mA   -11.38mA
540mV     -11.56mA   -6.751mA   -16.96mA
840mV     -13.01mA   -7.475mA   -19.82mA
3V        -14.91mA   -8.505mA   -23.11mA
[GND_clamp]
|Voltage   I(typ)   I(min)   I(max)
-1.5V     -148mA     -145.1mA   -157.1mA
-1.32V    -110mA     -107mA     -118.7mA
-1.17V    -80.48mA   -77.09mA   -89.35mA
-1.05V    -59.26mA   -55.01mA   -69.77mA
-930mV    -42.29mA   -35.93mA   -54.98mA
-810mV    -29.33mA   -21.63mA   -39.36mA
-690mV    -17.18mA   -10.91mA   -23.6mA
-540mV    -5.131mA   -2.707mA   -7.327mA
-450mV    -1.269mA   -646.6uA   -1.725mA
-360mV    -213.6uA   -130.7uA   -279.5uA
0V        0A         0A         0A
3V        0A         0A         0A
[POWER_clamp]
|Voltage   I(typ)   I(min)   I(max)
-1.5V     188.7uA    109.8uA    311.9uA
-1.14V    153uA      86.3uA     261.2uA
-840mV    131.7uA    70.61uA    234.9uA
-480mV    121.4uA    59.86uA    229.1uA
480mV     114.2uA    55.36uA    215.4uA
660mV     111.4uA    54.29uA    208.4uA
780mV     107.8uA    53.22uA    197.7uA
960mV     96.18uA    49.83uA    167uA
1.14V     75.06uA    42.11uA    117.4uA
1.32V     43.25uA    28.83uA    47.75uA
1.5V      -25.18nA   9.33uA     -40.71uA
3V        -25.18nA   -1.33uA    -40.71uA
[Ramp]
| variable   typ   min   max
dV/dt_r  0.3479/0.3566n   0.2270/0.4205n   0.5518/0.2935n
dV/dt_f  0.3393/0.2952n   0.1964/0.3558n   0.5091/0.2603n
R_load = 50.0000
[Rising Waveform]
R_fixture=   50.0000
V_fixture=   1.5000
V_fixture_min=   1.4300
V_fixture_max=   1.5800
|time   V(typ)   V(min)   V(max)
0s        934.4mV    1.103V     731.4mV
707.1ps   934.5mV    1.103V     778.8mV
909.1ps   934.3mV    1.103V     1.385V
1.111ns   930.9mV    1.103V     1.55V
1.212ns   1.051V     1.103V     1.56V
1.515ns   1.429V     1.103V     1.573V
1.818ns   1.486V     1.086V     1.578V
2.222ns   1.494V     1.314V     1.579V
2.828ns   1.498V     1.421V     1.58V
10ns      1.5V       1.43V      1.58V
[Rising Waveform]
R_fixture=   50.0000
V_fixture=   0.0
V_fixture_min=   0.0
V_fixture_max=   0.0
|time   V(typ)   V(min)   V(max)
0s        510.1nV    728.2nV    394.5nV
808.1ps   16.55uV    729.1nV    -2.471mV
1.01ns    -1.181mV   4.906uV    544.3mV
1.111ns   -4.804mV   13.28uV    683.8mV
1.414ns   36.79mV    -95.87uV   840.1mV
1.717ns   467.7mV    -1.056mV   888.2mV
2.323ns   607mV      -8.972mV   914.2mV
2.828ns   632.8mV    284.6mV    918.2mV
3.333ns   643.2mV    348.9mV    919.3mV
10ns      651mV      378.4mV    919.7mV
[Falling Waveform]
R_fixture=   50.0000
V_fixture=   0.0
V_fixture_min=   0.0
V_fixture_max=   0.0
|time   V(typ)   V(min)   V(max)
0s        651mV      378.4mV    919.7mV
808.1ps   651mV      378.4mV    853.7mV
1.01ns    651.4mV    378.4mV    115.5mV
1.212ns   647.7mV    378.4mV    24.95mV
1.313ns   615.3mV    378.4mV    16.43mV
1.616ns   78.33mV    378.4mV    5.492mV
1.818ns   20mV       378.6mV    2.627mV
2.222ns   6.495mV    370.9mV    611.3uV
3.03ns    1.111mV    11.44mV    66.9uV
10ns      5.629uV    8.525uV    25.17uV
[Falling Waveform]
R_fixture=   50.0000
V_fixture=   1.5000
V_fixture_min=   1.4300
V_fixture_max=   1.5800
|time   V(typ)   V(min)   V(max)
0s        1.5V       1.43V      1.58V
808.1ps   1.5V       1.43V      1.588V
909.1ps   1.5V       1.43V      1.437V
1.111ns   1.5V       1.43V      956.1mV
1.414ns   1.508V     1.43V      799.6mV
1.717ns   1.102V     1.431V     757.7mV
2.424ns   956.8mV    1.454V     734.6mV
2.929ns   943mV      1.18V      732.3mV
3.434ns   937.8mV    1.122V     731.7mV
10ns      934.4mV    1.103V     731.4mV
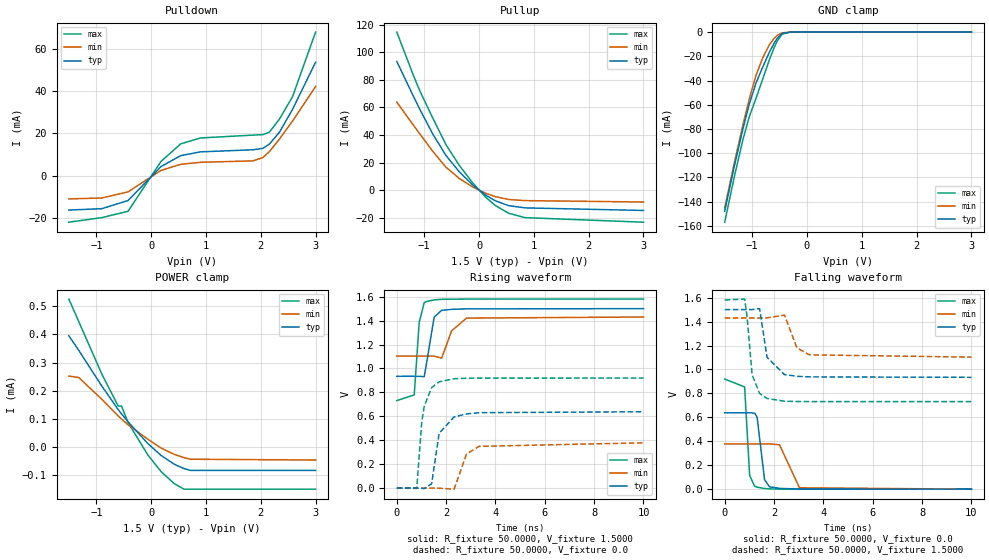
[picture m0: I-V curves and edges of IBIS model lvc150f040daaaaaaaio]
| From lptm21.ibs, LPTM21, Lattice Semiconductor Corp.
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|   Model lvc150f040daaaaaaaio
[Model]   lvc150f040daaaaaaaio
Model_type   I/O
Polarity   Non-Inverting
Enable   Active-Low
Vinl =   0.3750V
Vinh =   1.1250V
Vmeas =   0.7500V
Cref =   0.0F
Rref =   1.0000M
Vref =   0.0V
C_comp   3.0000pF   2.7000pF   3.3000pF
[Temperature Range]   25.0000   0.1050k   -40.0000
[Voltage Range]   1.5000V   1.4300V   1.5800V
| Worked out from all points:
|   slope of the pulldown table from 0 to 0.225 V, typ, clamps not added: 42.8 ohm
|   slope of the pullup table from 0 to 0.225 V, typ, clamps not added: 37.2 ohm
|   GND clamp passes 1 mA (typ) near -0.44 V on its own axis
|   rising waveform, R_fixture 50.0000, V_fixture 1.5000: 20-80 % time 262ps typ, 394ps min, 178ps max; typ from 0.934 V to 1.5 V
|   rising waveform, R_fixture 50.0000, V_fixture 0.0: 20-80 % time 359ps typ, 425ps min, 296ps max; typ from 0 V to 0.638 V
|   falling waveform, R_fixture 50.0000, V_fixture 0.0: 20-80 % time 210ps typ, 312ps min, 152ps max; typ from 0.638 V to 0 V
|   falling waveform, R_fixture 50.0000, V_fixture 1.5000: 20-80 % time 298ps typ, 359ps min, 263ps max; typ from 1.5 V to 0.934 V
[Pulldown]
|Voltage   I(typ)   I(min)   I(max)
-1.5V     -16.15mA   -10.89mA   -21.88mA
-900mV    -15.51mA   -10.47mA   -19.73mA
-420mV    -11.65mA   -7.561mA   -16.73mA
180mV     4.36mA     2.55mA     6.777mA
540mV     9.538mA    5.428mA    15.07mA
900mV     11.31mA    6.38mA     17.87mA
1.86V     12.29mA    7.057mA    19.21mA
2.04V     12.98mA    8.626mA    19.43mA
2.16V     15.06mA    11.47mA    20.67mA
2.34V     20.54mA    17.3mA     26.71mA
2.58V     31.37mA    25.87mA    37.35mA
3V        53.63mA    42.19mA    67.82mA
[Pullup]
|Voltage   I(typ)   I(min)   I(max)
-1.5V     93.35mA    63.89mA    114.6mA
-1.2V     68.4mA     47.33mA    83.61mA
-1.08V    58.71mA    40.85mA    72mA
-840mV    40.51mA    28.06mA    52.05mA
-600mV    25.07mA    16.6mA     32.88mA
-360mV    13.39mA    8.597mA    18.05mA
-120mV    4.012mA    2.512mA    5.57mA
120mV     -3.489mA   -2.141mA   -4.974mA
300mV     -7.638mA   -4.642mA   -11.08mA
540mV     -11.12mA   -6.654mA   -16.62mA
840mV     -12.75mA   -7.475mA   -19.82mA
3V        -14.61mA   -8.505mA   -23.11mA
[GND_clamp]
|Voltage   I(typ)   I(min)   I(max)
-1.5V     -147.9mA   -145.1mA   -156.9mA
-1.32V    -109.9mA   -107mA     -118.5mA
-1.17V    -80.39mA   -77.05mA   -89.2mA
-1.05V    -59.17mA   -54.96mA   -69.62mA
-930mV    -42.2mA    -35.88mA   -54.83mA
-810mV    -29.25mA   -21.58mA   -39.21mA
-690mV    -17.09mA   -10.87mA   -23.45mA
-600mV    -9.233mA   -5.258mA   -12.98mA
-540mV    -5.047mA   -2.659mA   -7.175mA
-450mV    -1.185mA   -599.1uA   -1.573mA
-300mV    -18.73uA   -15.61uA   -8.8uA
3V        0A         0A         0A
[POWER_clamp]
|Voltage   I(typ)   I(min)   I(max)
-1.5V     395.4uA    251.6uA    526.1uA
-1.32V    343.5uA    246.7uA    446.2uA
-900mV    216.4uA    169.3uA    259.1uA
-600mV    132.4uA    109.9uA    145uA
-540mV    117.3uA    98.92uA    145uA
-420mV    88.66uA    78.23uA    86.09uA
-60mV     11.57uA    26.89uA    -29.01uA
180mV     -30.73uA   -4.427uA   -88.14uA
420mV     -62.06uA   -26.95uA   -131uA
600mV     -77.75uA   -38.9uA    -151.1uA
720mV     -84.27uA   -44.44uA   -151.1uA
3V        -84.27uA   -47.29uA   -151.1uA
[Ramp]
| variable   typ   min   max
dV/dt_r  0.3479/0.3566n   0.2270/0.4205n   0.5518/0.2935n
dV/dt_f  0.3393/0.2952n   0.1964/0.3558n   0.5091/0.2603n
R_load = 50.0000
[Rising Waveform]
R_fixture=   50.0000
V_fixture=   1.5000
V_fixture_min=   1.4300
V_fixture_max=   1.5800
|time   V(typ)   V(min)   V(max)
0s        934.4mV    1.103V     731.4mV
707.1ps   934.5mV    1.103V     778.8mV
909.1ps   934.3mV    1.103V     1.385V
1.111ns   930.9mV    1.103V     1.55V
1.212ns   1.051V     1.103V     1.56V
1.515ns   1.429V     1.103V     1.573V
1.818ns   1.486V     1.086V     1.578V
2.222ns   1.494V     1.314V     1.579V
2.828ns   1.498V     1.421V     1.58V
10ns      1.5V       1.43V      1.58V
[Rising Waveform]
R_fixture=   50.0000
V_fixture=   0.0
V_fixture_min=   0.0
V_fixture_max=   0.0
|time   V(typ)   V(min)   V(max)
0s        510.1nV    728.2nV    394.5nV
808.1ps   16.55uV    729.1nV    -2.471mV
1.01ns    -1.181mV   4.906uV    544.3mV
1.111ns   -4.804mV   13.28uV    683.8mV
1.414ns   36.79mV    -95.87uV   840.1mV
1.717ns   458.3mV    -1.056mV   888.2mV
2.323ns   594.9mV    -8.972mV   914.2mV
2.828ns   620.1mV    284.6mV    918.2mV
3.333ns   630.3mV    348.9mV    919.3mV
10ns      638mV      378.4mV    919.7mV
[Falling Waveform]
R_fixture=   50.0000
V_fixture=   0.0
V_fixture_min=   0.0
V_fixture_max=   0.0
|time   V(typ)   V(min)   V(max)
0s        638mV      378.4mV    919.7mV
808.1ps   638mV      378.4mV    853.7mV
1.01ns    638.4mV    378.4mV    115.5mV
1.212ns   634.7mV    378.4mV    24.95mV
1.313ns   603mV      378.4mV    16.43mV
1.616ns   78.33mV    378.4mV    5.492mV
1.818ns   20mV       378.6mV    2.627mV
2.222ns   6.495mV    370.9mV    611.3uV
3.03ns    1.111mV    11.44mV    66.9uV
10ns      5.629uV    8.525uV    25.17uV
[Falling Waveform]
R_fixture=   50.0000
V_fixture=   1.5000
V_fixture_min=   1.4300
V_fixture_max=   1.5800
|time   V(typ)   V(min)   V(max)
0s        1.5V       1.43V      1.58V
808.1ps   1.5V       1.43V      1.588V
909.1ps   1.5V       1.43V      1.437V
1.111ns   1.5V       1.43V      956.1mV
1.414ns   1.508V     1.43V      799.6mV
1.717ns   1.102V     1.431V     757.7mV
2.424ns   956.8mV    1.454V     734.6mV
2.929ns   943mV      1.18V      732.3mV
3.434ns   937.8mV    1.122V     731.7mV
10ns      934.4mV    1.103V     731.4mV
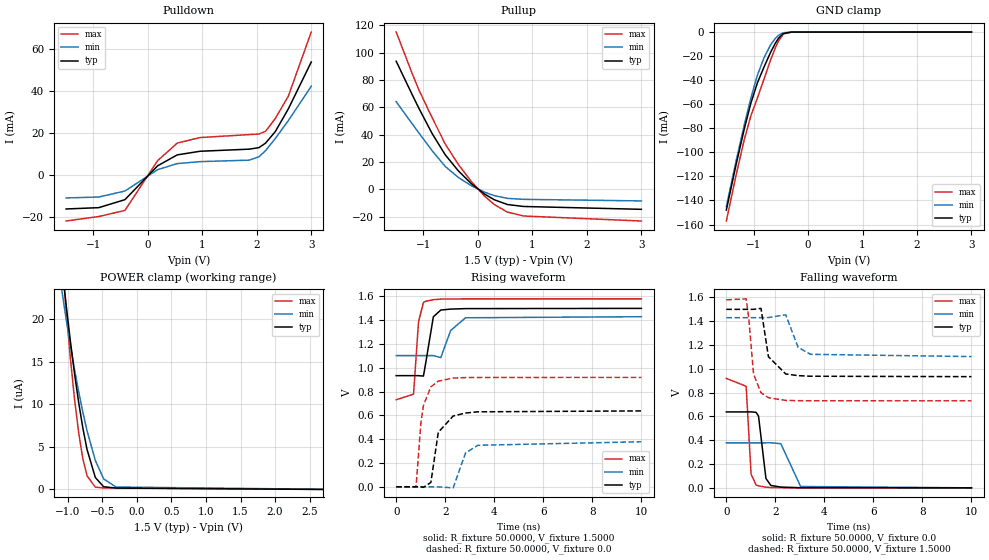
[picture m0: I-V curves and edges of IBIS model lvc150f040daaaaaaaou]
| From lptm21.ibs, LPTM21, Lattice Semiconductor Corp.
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|   Model lvc150f040daaaaaaaou
[Model]   lvc150f040daaaaaaaou
Model_type   Output
Polarity   Non-Inverting
Enable   Active-Low
Vmeas =   0.7500V
Cref =   0.0F
Rref =   1.0000M
Vref =   0.0V
C_comp   3.0000pF   2.7000pF   3.3000pF
[Temperature Range]   25.0000   0.1050k   -40.0000
[Voltage Range]   1.5000V   1.4300V   1.5800V
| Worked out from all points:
|   slope of the pulldown table from 0 to 0.225 V, typ, clamps not added: 42.4 ohm
|   slope of the pullup table from 0 to 0.225 V, typ, clamps not added: 36.9 ohm
|   GND clamp passes 1 mA (typ) near -0.44 V on its own axis
|   rising waveform, R_fixture 50.0000, V_fixture 1.5000: 20-80 % time 262ps typ, 394ps min, 178ps max; typ from 0.934 V to 1.5 V
|   rising waveform, R_fixture 50.0000, V_fixture 0.0: 20-80 % time 359ps typ, 425ps min, 296ps max; typ from 0 V to 0.638 V
|   falling waveform, R_fixture 50.0000, V_fixture 0.0: 20-80 % time 210ps typ, 312ps min, 152ps max; typ from 0.638 V to 0 V
|   falling waveform, R_fixture 50.0000, V_fixture 1.5000: 20-80 % time 298ps typ, 359ps min, 263ps max; typ from 1.5 V to 0.934 V
[Pulldown]
|Voltage   I(typ)   I(min)   I(max)
-1.5V     -16.19mA   -10.92mA   -21.94mA
-900mV    -15.56mA   -10.5mA    -19.8mA
-420mV    -11.75mA   -7.622mA   -16.89mA
180mV     4.403mA    2.572mA    6.858mA
540mV     9.634mA    5.475mA    15.25mA
960mV     11.36mA    6.409mA    17.91mA
1.86V     12.36mA    7.114mA    19.3mA
2.04V     13.09mA    8.711mA    19.59mA
2.16V     15.21mA    11.58mA    20.86mA
2.34V     20.73mA    17.43mA    26.97mA
2.58V     31.61mA    26.04mA    37.69mA
3V        53.96mA    42.4mA     68.28mA
[Pullup]
|Voltage   I(typ)   I(min)   I(max)
-1.5V     93.71mA    64.1mA     115.1mA
-1.2V     68.69mA    47.51mA    84.01mA
-1.08V    58.98mA    41.01mA    72.36mA
-840mV    40.72mA    28.19mA    52.33mA
-600mV    25.21mA    16.68mA    33.08mA
-360mV    13.47mA    8.644mA    18.16mA
-120mV    4.038mA    2.527mA    5.608mA
120mV     -3.512mA   -2.154mA   -5.009mA
300mV     -7.69mA    -4.67mA    -11.16mA
540mV     -11.2mA    -6.697mA   -16.74mA
840mV     -12.64mA   -7.425mA   -19.62mA
3V        -14.72mA   -8.563mA   -23.28mA
[GND_clamp]
|Voltage   I(typ)   I(min)   I(max)
-1.5V     -148mA     -145.1mA   -157.1mA
-1.32V    -110mA     -107mA     -118.7mA
-1.17V    -80.44mA   -77.06mA   -89.3mA
-1.05V    -59.22mA   -54.98mA   -69.71mA
-930mV    -42.25mA   -35.9mA    -54.91mA
-810mV    -29.28mA   -21.6mA    -39.29mA
-690mV    -17.12mA   -10.87mA   -23.53mA
-600mV    -9.252mA   -5.256mA   -13.04mA
-540mV    -5.056mA   -2.651mA   -7.221mA
-450mV    -1.176mA   -584.3uA   -1.582mA
-300mV    -18.62uA   -15.88uA   -16.42uA
3V        0A         0A         0A
[POWER_clamp]
|Voltage   I(typ)   I(min)   I(max)
-1.5V     65.71uA    49.01uA    83.9uA
-1.08V    26.1uA     23.2uA     27.01uA
-1.02V    21.58uA    19.96uA    20.86uA
-960mV    17.41uA    16.92uA    15.37uA
-900mV    13.6uA     14.08uA    10.59uA
-840mV    10.19uA    11.46uA    6.627uA
-780mV    7.211uA    9.062uA    3.587uA
-720mV    4.708uA    6.903uA    1.592uA
-600mV    1.397uA    3.405uA    252nA
-480mV    304.8nA    1.234uA    163nA
-300mV    147.6nA    271.9nA    163nA
3V        -25.84nA   -23.03nA   -33.01nA
[Ramp]
| variable   typ   min   max
dV/dt_r  0.3479/0.3566n   0.2270/0.4205n   0.5518/0.2935n
dV/dt_f  0.3393/0.2952n   0.1964/0.3558n   0.5091/0.2603n
R_load = 50.0000
[Rising Waveform]
R_fixture=   50.0000
V_fixture=   1.5000
V_fixture_min=   1.4300
V_fixture_max=   1.5800
|time   V(typ)   V(min)   V(max)
0s        934.4mV    1.103V     731.4mV
707.1ps   934.5mV    1.103V     778.8mV
909.1ps   934.3mV    1.103V     1.385V
1.111ns   930.9mV    1.103V     1.55V
1.212ns   1.051V     1.103V     1.56V
1.515ns   1.429V     1.103V     1.573V
1.818ns   1.486V     1.086V     1.578V
2.222ns   1.494V     1.314V     1.579V
2.828ns   1.498V     1.421V     1.58V
10ns      1.5V       1.43V      1.58V
[Rising Waveform]
R_fixture=   50.0000
V_fixture=   0.0
V_fixture_min=   0.0
V_fixture_max=   0.0
|time   V(typ)   V(min)   V(max)
0s        510.1nV    728.2nV    394.5nV
808.1ps   16.55uV    729.1nV    -2.471mV
1.01ns    -1.181mV   4.906uV    544.3mV
1.111ns   -4.804mV   13.28uV    683.8mV
1.414ns   36.79mV    -95.87uV   840.1mV
1.717ns   458.3mV    -1.056mV   888.2mV
2.323ns   594.9mV    -8.972mV   914.2mV
2.828ns   620.1mV    284.6mV    918.2mV
3.333ns   630.3mV    348.9mV    919.3mV
10ns      638mV      378.4mV    919.7mV
[Falling Waveform]
R_fixture=   50.0000
V_fixture=   0.0
V_fixture_min=   0.0
V_fixture_max=   0.0
|time   V(typ)   V(min)   V(max)
0s        638mV      378.4mV    919.7mV
808.1ps   638mV      378.4mV    853.7mV
1.01ns    638.4mV    378.4mV    115.5mV
1.212ns   634.7mV    378.4mV    24.95mV
1.313ns   603mV      378.4mV    16.43mV
1.616ns   78.33mV    378.4mV    5.492mV
1.818ns   20mV       378.6mV    2.627mV
2.222ns   6.495mV    370.9mV    611.3uV
3.03ns    1.111mV    11.44mV    66.9uV
10ns      5.629uV    8.525uV    25.17uV
[Falling Waveform]
R_fixture=   50.0000
V_fixture=   1.5000
V_fixture_min=   1.4300
V_fixture_max=   1.5800
|time   V(typ)   V(min)   V(max)
0s        1.5V       1.43V      1.58V
808.1ps   1.5V       1.43V      1.588V
909.1ps   1.5V       1.43V      1.437V
1.111ns   1.5V       1.43V      956.1mV
1.414ns   1.508V     1.43V      799.6mV
1.717ns   1.102V     1.431V     757.7mV
2.424ns   956.8mV    1.454V     734.6mV
2.929ns   943mV      1.18V      732.3mV
3.434ns   937.8mV    1.122V     731.7mV
10ns      934.4mV    1.103V     731.4mV
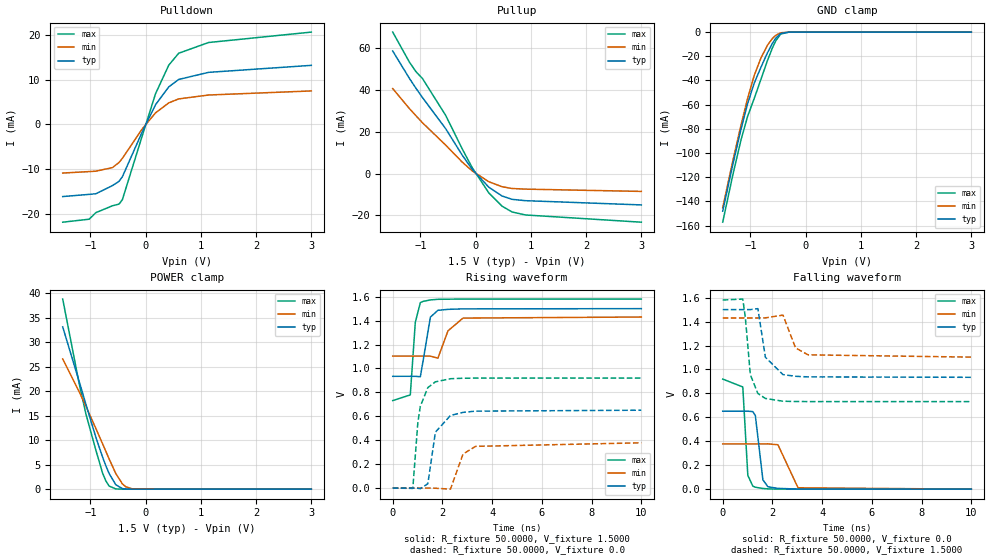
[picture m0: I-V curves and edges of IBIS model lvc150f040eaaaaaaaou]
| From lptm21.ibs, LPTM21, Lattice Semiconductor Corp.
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|   Model lvc150f040eaaaaaaaou
[Model]   lvc150f040eaaaaaaaou
Model_type   Output
Polarity   Non-Inverting
Enable   Active-Low
Vmeas =   0.7500V
Cref =   0.0F
Rref =   1.0000M
Vref =   0.0V
C_comp   3.0000pF   2.7000pF   3.3000pF
[Temperature Range]   25.0000   0.1050k   -40.0000
[Voltage Range]   1.5000V   1.4300V   1.5800V
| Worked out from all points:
|   slope of the pulldown table from 0 to 0.225 V, typ, clamps not added: 42.4 ohm
|   slope of the pullup table from 0 to 0.225 V, typ, clamps not added: 36.2 ohm
|   GND clamp passes 1 mA (typ) near -0.44 V on its own axis
|   POWER clamp passes 1 mA (typ) near -0.55 V on its own axis
|   rising waveform, R_fixture 50.0000, V_fixture 1.5000: 20-80 % time 262ps typ, 394ps min, 178ps max; typ from 0.934 V to 1.5 V
|   rising waveform, R_fixture 50.0000, V_fixture 0.0: 20-80 % time 359ps typ, 425ps min, 296ps max; typ from 0 V to 0.651 V
|   falling waveform, R_fixture 50.0000, V_fixture 0.0: 20-80 % time 209ps typ, 312ps min, 152ps max; typ from 0.651 V to 0 V
|   falling waveform, R_fixture 50.0000, V_fixture 1.5000: 20-80 % time 298ps typ, 359ps min, 263ps max; typ from 1.5 V to 0.934 V
[Pulldown]
|Voltage   I(typ)   I(min)   I(max)
-1.5V     -16.19mA   -10.92mA   -21.94mA
-1.02V    -15.7mA    -10.59mA   -21.27mA
-900mV    -15.56mA   -10.5mA    -19.8mA
-600mV    -13.74mA   -9.7mA     -18.26mA
-480mV    -12.77mA   -8.548mA   -17.88mA
-420mV    -11.75mA   -7.622mA   -16.89mA
-60mV     -1.68mA    -1.008mA   -2.556mA
180mV     4.403mA    2.572mA    6.858mA
420mV     8.409mA    4.818mA    13.28mA
600mV     10.07mA    5.709mA    15.95mA
1.14V     11.66mA    6.58mA     18.35mA
3V        13.23mA    7.494mA    20.69mA
[Pullup]
|Voltage   I(typ)   I(min)   I(max)
-1.5V     58.55mA    40.59mA    67.61mA
-1.2V     45.58mA    31.13mA    53.37mA
-1.08V    40.79mA    27.63mA    48.71mA
-960mV    36.27mA    24.24mA    45.37mA
-540mV    21.37mA    13.54mA    27.73mA
-240mV    8.702mA    5.403mA    11.68mA
-60mV     2mA        1.218mA    2.744mA
240mV     -6.575mA   -3.927mA   -9.294mA
480mV     -10.76mA   -6.331mA   -15.63mA
660mV     -12.34mA   -7.164mA   -18.39mA
900mV     -12.99mA   -7.471mA   -19.82mA
3V        -15.02mA   -8.563mA   -23.28mA
[GND_clamp]
|Voltage   I(typ)   I(min)   I(max)
-1.5V     -148mA     -145.1mA   -157.1mA
-1.32V    -110mA     -107mA     -118.7mA
-1.17V    -80.44mA   -77.06mA   -89.3mA
-1.05V    -59.22mA   -54.98mA   -69.71mA
-930mV    -42.25mA   -35.9mA    -54.91mA
-810mV    -29.28mA   -21.6mA    -39.29mA
-690mV    -17.12mA   -10.87mA   -23.53mA
-600mV    -9.252mA   -5.256mA   -13.04mA
-540mV    -5.056mA   -2.651mA   -7.221mA
-450mV    -1.176mA   -584.3uA   -1.582mA
-300mV    -18.62uA   -15.88uA   -16.42uA
3V        0A         0A         0A
[POWER_clamp]
|Voltage   I(typ)   I(min)   I(max)
-1.5V     33.09mA    26.54mA    38.76mA
-1.2V     21.88mA    19.83mA    21.41mA
-1.08V    17.31mA    16.9mA     15.33mA
-900mV    10.59mA    12.38mA    7.966mA
-780mV    6.585mA    9.294mA    3.343mA
-720mV    4.798mA    7.731mA    1.687mA
-660mV    3.201mA    6.172mA    637.9uA
-540mV    907.7uA    3.212mA    50.7uA
-420mV    112.6uA    1.073mA    3.157uA
-360mV    35.33uA    495.5uA    755.6nA
-240mV    3.045uA    67.64uA    60.85nA
3V        -25.84nA   -23.03nA   -33.01nA
[Ramp]
| variable   typ   min   max
dV/dt_r  0.3479/0.3566n   0.2270/0.4205n   0.5518/0.2935n
dV/dt_f  0.3393/0.2952n   0.1964/0.3558n   0.5091/0.2603n
R_load = 50.0000
[Rising Waveform]
R_fixture=   50.0000
V_fixture=   1.5000
V_fixture_min=   1.4300
V_fixture_max=   1.5800
|time   V(typ)   V(min)   V(max)
0s        934.4mV    1.103V     731.4mV
707.1ps   934.5mV    1.103V     778.8mV
909.1ps   934.3mV    1.103V     1.385V
1.111ns   930.9mV    1.103V     1.55V
1.212ns   1.051V     1.103V     1.56V
1.515ns   1.429V     1.103V     1.573V
1.818ns   1.486V     1.086V     1.578V
2.222ns   1.494V     1.314V     1.579V
2.828ns   1.498V     1.421V     1.58V
10ns      1.5V       1.43V      1.58V
[Rising Waveform]
R_fixture=   50.0000
V_fixture=   0.0
V_fixture_min=   0.0
V_fixture_max=   0.0
|time   V(typ)   V(min)   V(max)
0s        510.1nV    728.2nV    394.5nV
808.1ps   16.55uV    729.1nV    -2.471mV
1.01ns    -1.181mV   4.906uV    544.3mV
1.111ns   -4.804mV   13.28uV    683.8mV
1.414ns   36.79mV    -95.87uV   840.1mV
1.717ns   467.7mV    -1.056mV   888.2mV
2.323ns   607mV      -8.972mV   914.2mV
2.828ns   632.8mV    284.6mV    918.2mV
3.333ns   643.2mV    348.9mV    919.3mV
10ns      651mV      378.4mV    919.7mV
[Falling Waveform]
R_fixture=   50.0000
V_fixture=   0.0
V_fixture_min=   0.0
V_fixture_max=   0.0
|time   V(typ)   V(min)   V(max)
0s        651mV      378.4mV    919.7mV
808.1ps   651mV      378.4mV    853.7mV
1.01ns    651.4mV    378.4mV    115.5mV
1.212ns   647.7mV    378.4mV    24.95mV
1.313ns   615.3mV    378.4mV    16.43mV
1.616ns   78.33mV    378.4mV    5.492mV
1.818ns   20mV       378.6mV    2.627mV
2.222ns   6.495mV    370.9mV    611.3uV
3.03ns    1.111mV    11.44mV    66.9uV
10ns      5.629uV    8.525uV    25.17uV
[Falling Waveform]
R_fixture=   50.0000
V_fixture=   1.5000
V_fixture_min=   1.4300
V_fixture_max=   1.5800
|time   V(typ)   V(min)   V(max)
0s        1.5V       1.43V      1.58V
808.1ps   1.5V       1.43V      1.588V
909.1ps   1.5V       1.43V      1.437V
1.111ns   1.5V       1.43V      956.1mV
1.414ns   1.508V     1.43V      799.6mV
1.717ns   1.102V     1.431V     757.7mV
2.424ns   956.8mV    1.454V     734.6mV
2.929ns   943mV      1.18V      732.3mV
3.434ns   937.8mV    1.122V     731.7mV
10ns      934.4mV    1.103V     731.4mV
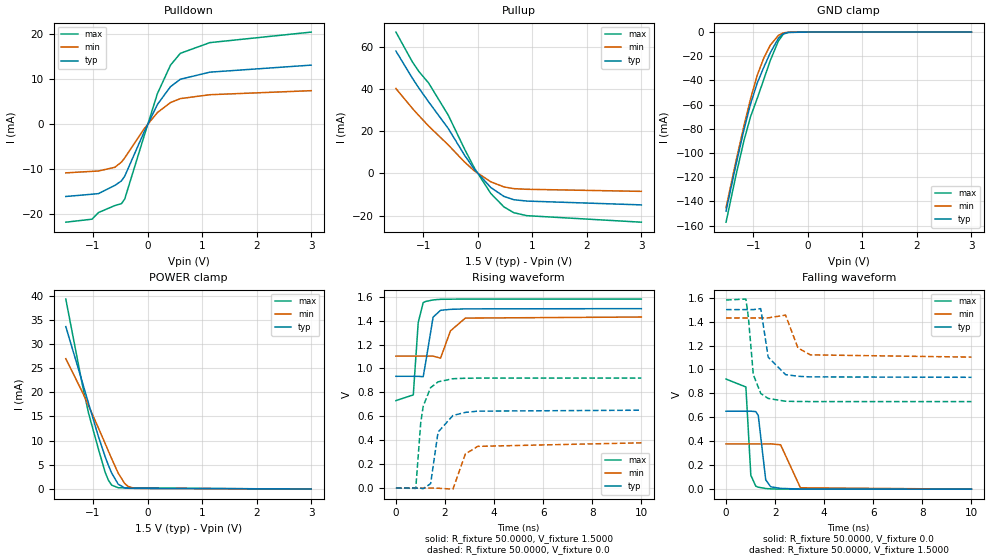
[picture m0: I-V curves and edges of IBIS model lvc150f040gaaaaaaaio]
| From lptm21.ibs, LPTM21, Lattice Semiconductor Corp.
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|   Model lvc150f040gaaaaaaaio
[Model]   lvc150f040gaaaaaaaio
Model_type   I/O
Polarity   Non-Inverting
Enable   Active-Low
Vinl =   0.3750V
Vinh =   1.1250V
Vmeas =   0.7500V
Cref =   0.0F
Rref =   1.0000M
Vref =   0.0V
C_comp   3.0000pF   2.7000pF   3.3000pF
[Temperature Range]   25.0000   0.1050k   -40.0000
[Voltage Range]   1.5000V   1.4300V   1.5800V
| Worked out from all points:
|   slope of the pulldown table from 0 to 0.225 V, typ, clamps not added: 42.8 ohm
|   slope of the pullup table from 0 to 0.225 V, typ, clamps not added: 36.2 ohm
|   GND clamp passes 1 mA (typ) near -0.44 V on its own axis
|   POWER clamp passes 1 mA (typ) near -0.54 V on its own axis
|   rising waveform, R_fixture 50.0000, V_fixture 1.5000: 20-80 % time 262ps typ, 394ps min, 178ps max; typ from 0.934 V to 1.5 V
|   rising waveform, R_fixture 50.0000, V_fixture 0.0: 20-80 % time 359ps typ, 425ps min, 296ps max; typ from 0 V to 0.651 V
|   falling waveform, R_fixture 50.0000, V_fixture 0.0: 20-80 % time 209ps typ, 312ps min, 152ps max; typ from 0.651 V to 0 V
|   falling waveform, R_fixture 50.0000, V_fixture 1.5000: 20-80 % time 298ps typ, 359ps min, 263ps max; typ from 1.5 V to 0.934 V
[Pulldown]
|Voltage   I(typ)   I(min)   I(max)
-1.5V     -16.15mA   -10.89mA   -21.88mA
-1.02V    -15.65mA   -10.55mA   -21.21mA
-900mV    -15.51mA   -10.47mA   -19.73mA
-600mV    -13.68mA   -9.651mA   -18.17mA
-480mV    -12.68mA   -8.487mA   -17.75mA
-420mV    -11.65mA   -7.561mA   -16.73mA
-60mV     -1.663mA   -999.7uA   -2.526mA
180mV     4.36mA     2.55mA     6.777mA
420mV     8.326mA    4.776mA    13.12mA
600mV     9.972mA    5.659mA    15.75mA
1.14V     11.55mA    6.524mA    18.13mA
3V        13.12mA    7.426mA    20.48mA
[Pullup]
|Voltage   I(typ)   I(min)   I(max)
-1.5V     57.98mA    40.23mA    66.97mA
-1.2V     45.18mA    30.87mA    52.92mA
-1.08V    40.47mA    27.41mA    48.34mA
-900mV    33.9mA     22.44mA    42.82mA
-540mV    21.27mA    13.49mA    27.58mA
-240mV    8.569mA    5.346mA    11.45mA
-60mV     1.867mA    1.161mA    2.519mA
240mV     -6.706mA   -3.982mA   -9.516mA
480mV     -10.89mA   -6.386mA   -15.85mA
660mV     -12.46mA   -7.217mA   -18.61mA
900mV     -13.1mA    -7.518mA   -20.02mA
3V        -14.91mA   -8.505mA   -23.11mA
[GND_clamp]
|Voltage   I(typ)   I(min)   I(max)
-1.5V     -148mA     -145.1mA   -157.1mA
-1.32V    -110mA     -107mA     -118.7mA
-1.17V    -80.48mA   -77.09mA   -89.35mA
-1.05V    -59.26mA   -55.01mA   -69.77mA
-930mV    -42.29mA   -35.93mA   -54.98mA
-810mV    -29.33mA   -21.63mA   -39.36mA
-690mV    -17.18mA   -10.91mA   -23.6mA
-540mV    -5.131mA   -2.707mA   -7.327mA
-450mV    -1.269mA   -646.6uA   -1.725mA
-360mV    -213.6uA   -130.7uA   -279.5uA
0V        0A         0A         0A
3V        0A         0A         0A
[POWER_clamp]
|Voltage   I(typ)   I(min)   I(max)
-1.5V     33.6mA     26.96mA    39.3mA
-1.2V     22.23mA    20.13mA    21.75mA
-1.08V    17.59mA    17.16mA    15.56mA
-900mV    10.78mA    12.58mA    8.18mA
-780mV    6.728mA    9.453mA    3.516mA
-720mV    4.925mA    7.87mA     1.844mA
-660mV    3.313mA    6.291mA    793.6uA
-540mV    997.8uA    3.293mA    253uA
-420mV    212.5uA    1.125mA    228.2uA
-360mV    145.3uA    543uA      226.9uA
-240mV    121.5uA    119.5uA    225.5uA
3V        -25.18nA   -1.33uA    -40.71uA
[Ramp]
| variable   typ   min   max
dV/dt_r  0.3479/0.3566n   0.2270/0.4205n   0.5518/0.2935n
dV/dt_f  0.3393/0.2952n   0.1964/0.3558n   0.5091/0.2603n
R_load = 50.0000
[Rising Waveform]
R_fixture=   50.0000
V_fixture=   1.5000
V_fixture_min=   1.4300
V_fixture_max=   1.5800
|time   V(typ)   V(min)   V(max)
0s        934.4mV    1.103V     731.4mV
707.1ps   934.5mV    1.103V     778.8mV
909.1ps   934.3mV    1.103V     1.385V
1.111ns   930.9mV    1.103V     1.55V
1.212ns   1.051V     1.103V     1.56V
1.515ns   1.429V     1.103V     1.573V
1.818ns   1.486V     1.086V     1.578V
2.222ns   1.494V     1.314V     1.579V
2.828ns   1.498V     1.421V     1.58V
10ns      1.5V       1.43V      1.58V
[Rising Waveform]
R_fixture=   50.0000
V_fixture=   0.0
V_fixture_min=   0.0
V_fixture_max=   0.0
|time   V(typ)   V(min)   V(max)
0s        510.1nV    728.2nV    394.5nV
808.1ps   16.55uV    729.1nV    -2.471mV
1.01ns    -1.181mV   4.906uV    544.3mV
1.111ns   -4.804mV   13.28uV    683.8mV
1.414ns   36.79mV    -95.87uV   840.1mV
1.717ns   467.7mV    -1.056mV   888.2mV
2.323ns   607mV      -8.972mV   914.2mV
2.828ns   632.8mV    284.6mV    918.2mV
3.333ns   643.2mV    348.9mV    919.3mV
10ns      651mV      378.4mV    919.7mV
[Falling Waveform]
R_fixture=   50.0000
V_fixture=   0.0
V_fixture_min=   0.0
V_fixture_max=   0.0
|time   V(typ)   V(min)   V(max)
0s        651mV      378.4mV    919.7mV
808.1ps   651mV      378.4mV    853.7mV
1.01ns    651.4mV    378.4mV    115.5mV
1.212ns   647.7mV    378.4mV    24.95mV
1.313ns   615.3mV    378.4mV    16.43mV
1.616ns   78.33mV    378.4mV    5.492mV
1.818ns   20mV       378.6mV    2.627mV
2.222ns   6.495mV    370.9mV    611.3uV
3.03ns    1.111mV    11.44mV    66.9uV
10ns      5.629uV    8.525uV    25.17uV
[Falling Waveform]
R_fixture=   50.0000
V_fixture=   1.5000
V_fixture_min=   1.4300
V_fixture_max=   1.5800
|time   V(typ)   V(min)   V(max)
0s        1.5V       1.43V      1.58V
808.1ps   1.5V       1.43V      1.588V
909.1ps   1.5V       1.43V      1.437V
1.111ns   1.5V       1.43V      956.1mV
1.414ns   1.508V     1.43V      799.6mV
1.717ns   1.102V     1.431V     757.7mV
2.424ns   956.8mV    1.454V     734.6mV
2.929ns   943mV      1.18V      732.3mV
3.434ns   937.8mV    1.122V     731.7mV
10ns      934.4mV    1.103V     731.4mV
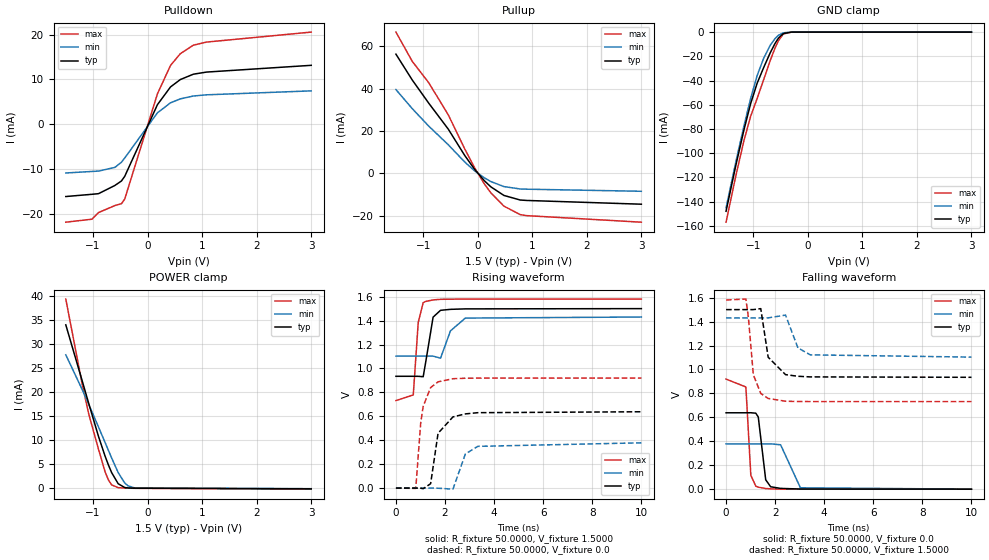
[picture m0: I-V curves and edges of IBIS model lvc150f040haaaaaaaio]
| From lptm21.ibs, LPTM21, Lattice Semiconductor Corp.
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|   Model lvc150f040haaaaaaaio
[Model]   lvc150f040haaaaaaaio
Model_type   I/O
Polarity   Non-Inverting
Enable   Active-Low
Vinl =   0.3750V
Vinh =   1.1250V
Vmeas =   0.7500V
Cref =   0.0F
Rref =   1.0000M
Vref =   0.0V
C_comp   3.0000pF   2.7000pF   3.3000pF
[Temperature Range]   25.0000   0.1050k   -40.0000
[Voltage Range]   1.5000V   1.4300V   1.5800V
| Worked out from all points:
|   slope of the pulldown table from 0 to 0.225 V, typ, clamps not added: 42.8 ohm
|   slope of the pullup table from 0 to 0.225 V, typ, clamps not added: 37.2 ohm
|   GND clamp passes 1 mA (typ) near -0.44 V on its own axis
|   POWER clamp passes 1 mA (typ) near -0.54 V on its own axis
|   rising waveform, R_fixture 50.0000, V_fixture 1.5000: 20-80 % time 262ps typ, 394ps min, 178ps max; typ from 0.934 V to 1.5 V
|   rising waveform, R_fixture 50.0000, V_fixture 0.0: 20-80 % time 359ps typ, 425ps min, 296ps max; typ from 0 V to 0.638 V
|   falling waveform, R_fixture 50.0000, V_fixture 0.0: 20-80 % time 210ps typ, 312ps min, 152ps max; typ from 0.638 V to 0 V
|   falling waveform, R_fixture 50.0000, V_fixture 1.5000: 20-80 % time 298ps typ, 359ps min, 263ps max; typ from 1.5 V to 0.934 V
[Pulldown]
|Voltage   I(typ)   I(min)   I(max)
-1.5V     -16.15mA   -10.89mA   -21.88mA
-1.02V    -15.65mA   -10.55mA   -21.21mA
-900mV    -15.51mA   -10.47mA   -19.73mA
-600mV    -13.68mA   -9.651mA   -18.17mA
-480mV    -12.68mA   -8.487mA   -17.75mA
-420mV    -11.65mA   -7.561mA   -16.73mA
180mV     4.36mA     2.55mA     6.777mA
420mV     8.326mA    4.776mA    13.12mA
600mV     9.972mA    5.659mA    15.75mA
840mV     11.17mA    6.299mA    17.65mA
1.08V     11.64mA    6.561mA    18.34mA
3V        13.15mA    7.444mA    20.57mA
[Pullup]
|Voltage   I(typ)   I(min)   I(max)
-1.5V     56.29mA    39.55mA    66.71mA
-1.2V     44.05mA    30.53mA    52.86mA
-900mV    33.18mA    22.32mA    42.84mA
-540mV    20.85mA    13.48mA    27.62mA
-240mV    8.475mA    5.373mA    11.6mA
-60mV     1.948mA    1.211mA    2.726mA
120mV     -3.489mA   -2.141mA   -4.974mA
240mV     -6.4mA     -3.903mA   -9.229mA
480mV     -10.47mA   -6.291mA   -15.52mA
780mV     -12.64mA   -7.42mA    -19.55mA
900mV     -12.84mA   -7.518mA   -20.02mA
3V        -14.61mA   -8.505mA   -23.11mA
[GND_clamp]
|Voltage   I(typ)   I(min)   I(max)
-1.5V     -147.9mA   -145.1mA   -156.9mA
-1.32V    -109.9mA   -107mA     -118.5mA
-1.17V    -80.39mA   -77.05mA   -89.2mA
-1.05V    -59.17mA   -54.96mA   -69.62mA
-930mV    -42.2mA    -35.88mA   -54.83mA
-810mV    -29.25mA   -21.58mA   -39.21mA
-690mV    -17.09mA   -10.87mA   -23.45mA
-600mV    -9.233mA   -5.258mA   -12.98mA
-540mV    -5.047mA   -2.659mA   -7.175mA
-450mV    -1.185mA   -599.1uA   -1.573mA
-300mV    -18.73uA   -15.61uA   -8.8uA
3V        0A         0A         0A
[POWER_clamp]
|Voltage   I(typ)   I(min)   I(max)
-1.5V     34.08mA    27.83mA    39.45mA
-1.2V     22.44mA    20.61mA    21.74mA
-1.08V    17.72mA    17.52mA    15.53mA
-900mV    10.82mA    12.79mA    8.145mA
-780mV    6.739mA    9.58mA     3.478mA
-720mV    4.93mA     7.965mA    1.803mA
-660mV    3.313mA    6.359mA    743.4uA
-540mV    987.9uA    3.323mA    158.4uA
-420mV    184.8uA    1.136mA    86.1uA
-360mV    103.6uA    547.9uA    64.36uA
-240mV    51.4uA     112.2uA    24.82uA
3V        -84.27uA   -47.29uA   -151.1uA
[Ramp]
| variable   typ   min   max
dV/dt_r  0.3479/0.3566n   0.2270/0.4205n   0.5518/0.2935n
dV/dt_f  0.3393/0.2952n   0.1964/0.3558n   0.5091/0.2603n
R_load = 50.0000
[Rising Waveform]
R_fixture=   50.0000
V_fixture=   1.5000
V_fixture_min=   1.4300
V_fixture_max=   1.5800
|time   V(typ)   V(min)   V(max)
0s        934.4mV    1.103V     731.4mV
707.1ps   934.5mV    1.103V     778.8mV
909.1ps   934.3mV    1.103V     1.385V
1.111ns   930.9mV    1.103V     1.55V
1.212ns   1.051V     1.103V     1.56V
1.515ns   1.429V     1.103V     1.573V
1.818ns   1.486V     1.086V     1.578V
2.222ns   1.494V     1.314V     1.579V
2.828ns   1.498V     1.421V     1.58V
10ns      1.5V       1.43V      1.58V
[Rising Waveform]
R_fixture=   50.0000
V_fixture=   0.0
V_fixture_min=   0.0
V_fixture_max=   0.0
|time   V(typ)   V(min)   V(max)
0s        510.1nV    728.2nV    394.5nV
808.1ps   16.55uV    729.1nV    -2.471mV
1.01ns    -1.181mV   4.906uV    544.3mV
1.111ns   -4.804mV   13.28uV    683.8mV
1.414ns   36.79mV    -95.87uV   840.1mV
1.717ns   458.3mV    -1.056mV   888.2mV
2.323ns   594.9mV    -8.972mV   914.2mV
2.828ns   620.1mV    284.6mV    918.2mV
3.333ns   630.3mV    348.9mV    919.3mV
10ns      638mV      378.4mV    919.7mV
[Falling Waveform]
R_fixture=   50.0000
V_fixture=   0.0
V_fixture_min=   0.0
V_fixture_max=   0.0
|time   V(typ)   V(min)   V(max)
0s        638mV      378.4mV    919.7mV
808.1ps   638mV      378.4mV    853.7mV
1.01ns    638.4mV    378.4mV    115.5mV
1.212ns   634.7mV    378.4mV    24.95mV
1.313ns   603mV      378.4mV    16.43mV
1.616ns   78.33mV    378.4mV    5.492mV
1.818ns   20mV       378.6mV    2.627mV
2.222ns   6.495mV    370.9mV    611.3uV
3.03ns    1.111mV    11.44mV    66.9uV
10ns      5.629uV    8.525uV    25.17uV
[Falling Waveform]
R_fixture=   50.0000
V_fixture=   1.5000
V_fixture_min=   1.4300
V_fixture_max=   1.5800
|time   V(typ)   V(min)   V(max)
0s        1.5V       1.43V      1.58V
808.1ps   1.5V       1.43V      1.588V
909.1ps   1.5V       1.43V      1.437V
1.111ns   1.5V       1.43V      956.1mV
1.414ns   1.508V     1.43V      799.6mV
1.717ns   1.102V     1.431V     757.7mV
2.424ns   956.8mV    1.454V     734.6mV
2.929ns   943mV      1.18V      732.3mV
3.434ns   937.8mV    1.122V     731.7mV
10ns      934.4mV    1.103V     731.4mV
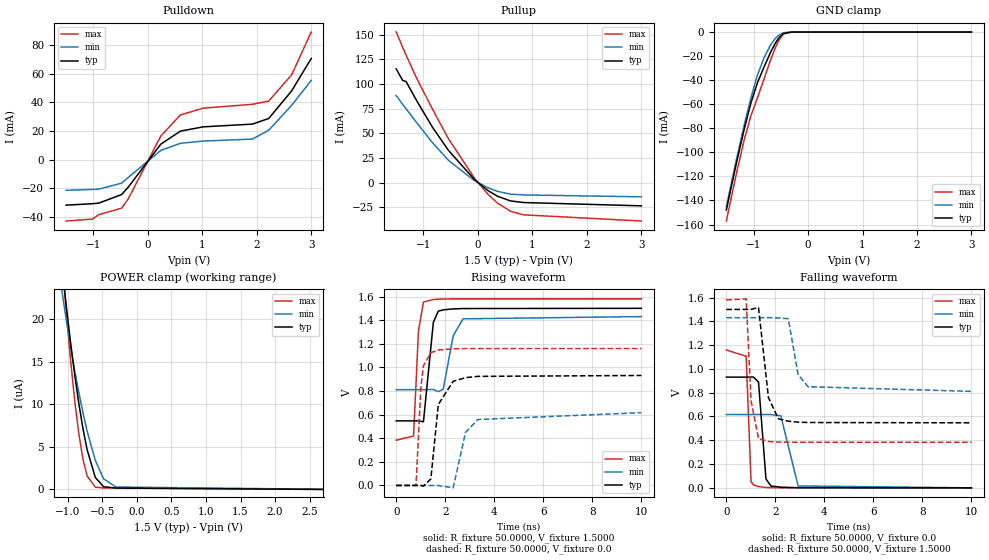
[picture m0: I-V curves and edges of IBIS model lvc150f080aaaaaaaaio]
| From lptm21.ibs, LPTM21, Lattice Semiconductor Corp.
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|   Model lvc150f080aaaaaaaaio
[Model]   lvc150f080aaaaaaaaio
Model_type   I/O
Polarity   Non-Inverting
Enable   Active-Low
Vinl =   0.3750V
Vinh =   1.1250V
Vmeas =   0.7500V
Cref =   0.0F
Rref =   1.0000M
Vref =   0.0V
C_comp   4.2000pF   3.8000pF   7.5000pF
[Temperature Range]   25.0000   0.1050k   -40.0000
[Voltage Range]   1.5000V   1.4300V   1.5800V
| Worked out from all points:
|   slope of the pulldown table from 0 to 0.225 V, typ, clamps not added: 22 ohm
|   slope of the pullup table from 0 to 0.225 V, typ, clamps not added: 23.8 ohm
|   GND clamp passes 1 mA (typ) near -0.44 V on its own axis
|   rising waveform, R_fixture 50.0000, V_fixture 1.5000: 20-80 % time 245ps typ, 366ps min, 159ps max; typ from 0.547 V to 1.5 V
|   rising waveform, R_fixture 50.0000, V_fixture 0.0: 20-80 % time 331ps typ, 448ps min, 190ps max; typ from 0 V to 0.931 V
|   falling waveform, R_fixture 50.0000, V_fixture 0.0: 20-80 % time 189ps typ, 282ps min, 132ps max; typ from 0.931 V to 0 V
|   falling waveform, R_fixture 50.0000, V_fixture 1.5000: 20-80 % time 244ps typ, 352ps min, 164ps max; typ from 1.5 V to 0.547 V
[Pulldown]
|Voltage   I(typ)   I(min)   I(max)
-1.5V     -31.94mA   -21.59mA   -43.05mA
-1.02V    -30.96mA   -20.93mA   -41.73mA
-900mV    -30.53mA   -20.76mA   -38.64mA
-480mV    -24.53mA   -16.55mA   -34.07mA
-360mV    -19.4mA    -12.57mA   -27.61mA
240mV     10.79mA    6.377mA    16.51mA
600mV     19.88mA    11.34mA    31.21mA
1.02V     22.87mA    12.92mA    35.96mA
1.92V     24.77mA    14.29mA    38.63mA
2.22V     28.71mA    20.51mA    40.92mA
2.64V     48.01mA    37.89mA    59.29mA
3V        70.72mA    55.4mA     89.22mA
[Pullup]
|Voltage   I(typ)   I(min)   I(max)
-1.5V     115.2mA    88.18mA    152.5mA
-1.38V    103.4mA    79.27mA    136.9mA
-1.32V    102.5mA    74.88mA    129.3mA
-1.14V    84.56mA    61.92mA    107.4mA
-840mV    56.63mA    40.92mA    75.08mA
-540mV    32.65mA    22.61mA    44.4mA
-60mV     2.996mA    1.975mA    4.306mA
180mV     -7.802mA   -5.046mA   -11.52mA
360mV     -13.69mA   -8.747mA   -20.66mA
600mV     -18.46mA   -11.56mA   -28.88mA
840mV     -20.06mA   -12.36mA   -32.51mA
3V        -23.39mA   -14.27mA   -38.75mA
[GND_clamp]
|Voltage   I(typ)   I(min)   I(max)
-1.5V     -148mA     -145.1mA   -157.1mA
-1.32V    -110mA     -107mA     -118.7mA
-1.17V    -80.44mA   -77.06mA   -89.3mA
-1.05V    -59.22mA   -54.98mA   -69.71mA
-930mV    -42.25mA   -35.9mA    -54.91mA
-810mV    -29.28mA   -21.6mA    -39.29mA
-690mV    -17.12mA   -10.87mA   -23.53mA
-600mV    -9.252mA   -5.256mA   -13.04mA
-540mV    -5.056mA   -2.651mA   -7.221mA
-450mV    -1.176mA   -584.3uA   -1.582mA
-300mV    -18.62uA   -15.88uA   -16.42uA
3V        0A         0A         0A
[POWER_clamp]
|Voltage   I(typ)   I(min)   I(max)
-1.5V     65.71uA    49.01uA    83.9uA
-1.08V    26.11uA    23.2uA     27.01uA
-1.02V    21.59uA    19.96uA    20.86uA
-960mV    17.41uA    16.92uA    15.37uA
-900mV    13.6uA     14.08uA    10.6uA
-840mV    10.19uA    11.46uA    6.628uA
-780mV    7.212uA    9.063uA    3.588uA
-720mV    4.71uA     6.904uA    1.593uA
-600mV    1.399uA    3.406uA    253nA
-480mV    305.8nA    1.235uA    164nA
-300mV    148.5nA    272.9nA    164nA
3V        -25.84nA   -23.03nA   -33.01nA
[Ramp]
| variable   typ   min   max
dV/dt_r  0.5321/0.3282n   0.3696/0.4432n   0.6955/0.1881n
dV/dt_f  0.5719/0.2417n   0.3713/0.3486n   0.7179/0.1621n
R_load = 50.0000
[Rising Waveform]
R_fixture=   50.0000
V_fixture=   1.5000
V_fixture_min=   1.4300
V_fixture_max=   1.5800
|time   V(typ)   V(min)   V(max)
0s        546.8mV    811.1mV    383.5mV
707.1ps   546.9mV    811.1mV    418.6mV
909.1ps   546.9mV    811.1mV    1.31V
1.111ns   539mV      810.9mV    1.553V
1.515ns   1.381V     812.7mV    1.575V
1.717ns   1.476V     794mV      1.577V
1.919ns   1.487V     815.2mV    1.579V
2.323ns   1.495V     1.267V     1.58V
2.727ns   1.498V     1.411V     1.58V
10ns      1.5V       1.43V      1.58V
[Rising Waveform]
R_fixture=   50.0000
V_fixture=   0.0
V_fixture_min=   0.0
V_fixture_max=   0.0
|time   V(typ)   V(min)   V(max)
0s        317.8nV    495.5nV    230.8nV
808.1ps   -23.16uV   344.4nV    34.73uV
1.01ns    -1.136mV   5.897uV    841.5mV
1.111ns   -5.649mV   12.27uV    1.013V
1.414ns   55.26mV    -129.9uV   1.124V
1.717ns   685.7mV    -990.7uV   1.147V
2.323ns   881.7mV    -20.42mV   1.157V
2.828ns   912.6mV    448.9mV    1.159V
3.333ns   923.7mV    558.4mV    1.159V
10ns      931.1mV    616.1mV    1.159V
[Falling Waveform]
R_fixture=   50.0000
V_fixture=   0.0
V_fixture_min=   0.0
V_fixture_max=   0.0
|time   V(typ)   V(min)   V(max)
0s        931.1mV    616.1mV    1.159V
808.1ps   931.1mV    616.1mV    1.107V
1.01ns    931.9mV    616.1mV    51.87mV
1.111ns   931.2mV    616.1mV    24.85mV
1.313ns   889.8mV    616.1mV    10.44mV
1.616ns   75.74mV    616.2mV    3.319mV
1.818ns   15.45mV    616.2mV    1.49mV
2.222ns   5.655mV    605.6mV    297.8uV
2.929ns   1.2mV      15.92mV    72.72uV
10ns      6.63uV     10.1uV     -20.07uV
[Falling Waveform]
R_fixture=   50.0000
V_fixture=   1.5000
V_fixture_min=   1.4300
V_fixture_max=   1.5800
|time   V(typ)   V(min)   V(max)
0s        1.5V       1.43V      1.58V
808.1ps   1.5V       1.43V      1.589V
1.01ns    1.501V     1.43V      730.1mV
1.313ns   1.516V     1.43V      414.1mV
1.717ns   759.8mV    1.431V     389.9mV
2.121ns   581.4mV    1.429V     385mV
2.525ns   560.2mV    1.422V     383.9mV
2.929ns   552.6mV    952.1mV    383.6mV
3.333ns   549.3mV    850.4mV    383.5mV
10ns      546.8mV    811.1mV    383.5mV
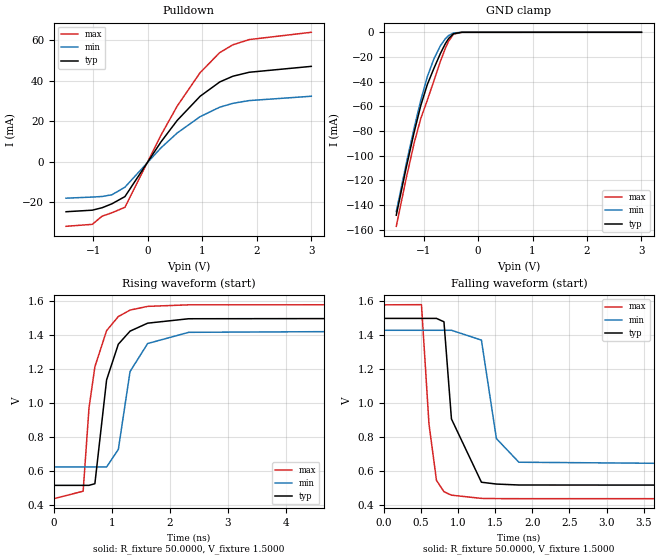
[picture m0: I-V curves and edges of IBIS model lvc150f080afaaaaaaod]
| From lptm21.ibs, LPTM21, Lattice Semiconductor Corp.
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|   Model lvc150f080afaaaaaaod
[Model]   lvc150f080afaaaaaaod
Model_type   I/O_open_drain
Polarity   Non-Inverting
Enable   Active-Low
Vinl =   0.3750V
Vinh =   1.1250V
Vmeas =   0.7500V
Cref =   0.0F
Rref =   1.0000M
Vref =   0.0V
C_comp   4.2000pF   3.8000pF   7.5000pF
[Temperature Range]   25.0000   0.1050k   -40.0000
[Voltage Range]   1.5000V   1.4300V   1.5800V
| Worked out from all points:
|   slope of the pulldown table from 0 to 0.225 V, typ, clamps not added: 24.3 ohm
|   GND clamp passes 1 mA (typ) near -0.44 V on its own axis
|   rising waveform, R_fixture 50.0000, V_fixture 1.5000: 20-80 % time 291ps typ, 280ps min, 269ps max; typ from 0.515 V to 1.5 V
|   falling waveform, R_fixture 50.0000, V_fixture 1.5000: 20-80 % time 144ps typ, 179ps min, 132ps max; typ from 1.5 V to 0.515 V
[Pulldown]
|Voltage   I(typ)   I(min)   I(max)
-1.5V     -24.56mA   -17.88mA   -31.75mA
-1.02V    -23.8mA    -17.33mA   -30.78mA
-840mV    -22.6mA    -17.05mA   -26.77mA
-660mV    -20.66mA   -16.21mA   -25.08mA
-420mV    -17.09mA   -12.45mA   -22.36mA
240mV     9.83mA     6.91mA     13.13mA
540mV     20.51mA    14.3mA     27.59mA
960mV     32.4mA     22.34mA    44.05mA
1.32V     39.45mA    27.01mA    53.94mA
1.56V     42.27mA    28.9mA     57.78mA
1.86V     44.23mA    30.26mA    60.35mA
3V        47.14mA    32.4mA     63.95mA
[GND_clamp]
|Voltage   I(typ)   I(min)   I(max)
-1.5V     -148.1mA   -145.2mA   -157.1mA
-1.32V    -110.1mA   -107mA     -118.7mA
-1.17V    -80.47mA   -77.11mA   -89.33mA
-1.05V    -59.24mA   -55.01mA   -69.75mA
-930mV    -42.27mA   -35.92mA   -54.95mA
-810mV    -29.3mA    -21.61mA   -39.32mA
-690mV    -17.14mA   -10.88mA   -23.55mA
-600mV    -9.267mA   -5.265mA   -13.06mA
-540mV    -5.068mA   -2.658mA   -7.239mA
-450mV    -1.182mA   -586.7uA   -1.592mA
-300mV    -18.83uA   -15.98uA   -16.74uA
3V        0A         0A         0A
[Ramp]
| variable   typ   min   max
dV/dt_r  0.5908/0.2883n   0.4837/0.2770n   0.6859/0.2660n
dV/dt_f  0.5908/0.1423n   0.4837/0.1775n   0.6859/0.1311n
R_load = 50.0000
[Rising Waveform]
R_fixture=   50.0000
V_fixture=   1.5000
V_fixture_min=   1.4300
V_fixture_max=   1.5800
|time   V(typ)   V(min)   V(max)
0s        515.3mV    623.8mV    436.8mV
505.1ps   515.3mV    623.8mV    480.9mV
606.1ps   515.5mV    623.8mV    972mV
707.1ps   525mV      623.8mV    1.214V
909.1ps   1.137V     624mV      1.427V
1.111ns   1.347V     726.8mV    1.51V
1.313ns   1.424V     1.186V     1.548V
1.616ns   1.471V     1.351V     1.57V
2.323ns   1.497V     1.417V     1.579V
10ns      1.5V       1.43V      1.58V
[Falling Waveform]
R_fixture=   50.0000
V_fixture=   1.5000
V_fixture_min=   1.4300
V_fixture_max=   1.5800
|time   V(typ)   V(min)   V(max)
0s        1.5V       1.43V      1.58V
505.1ps   1.5V       1.43V      1.581V
606.1ps   1.5V       1.43V      877.2mV
707.1ps   1.5V       1.43V      544.9mV
808.1ps   1.48V      1.43V      478mV
909.1ps   907mV      1.43V      457.5mV
1.313ns   533.9mV    1.372V     438.5mV
1.515ns   523.1mV    791.2mV    437.3mV
1.818ns   517.5mV    651.8mV    436.9mV
10ns      515.3mV    623.8mV    436.8mV
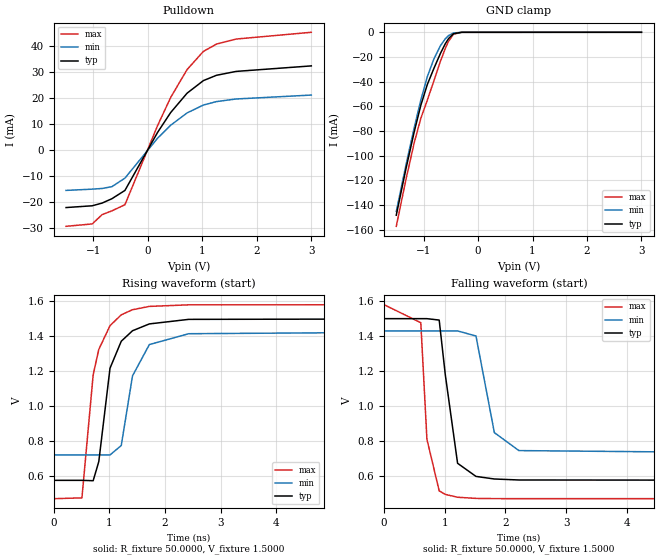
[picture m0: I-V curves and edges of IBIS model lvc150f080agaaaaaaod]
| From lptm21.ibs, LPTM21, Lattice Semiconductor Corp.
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|   Model lvc150f080agaaaaaaod
[Model]   lvc150f080agaaaaaaod
Model_type   I/O_open_drain
Polarity   Non-Inverting
Enable   Active-Low
Vinl =   0.3750V
Vinh =   1.1250V
Vmeas =   0.7500V
Cref =   0.0F
Rref =   1.0000M
Vref =   0.0V
C_comp   4.2000pF   3.8000pF   7.5000pF
[Temperature Range]   25.0000   0.1050k   -40.0000
[Voltage Range]   1.5000V   1.4300V   1.5800V
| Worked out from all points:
|   slope of the pulldown table from 0 to 0.225 V, typ, clamps not added: 27.4 ohm
|   GND clamp passes 1 mA (typ) near -0.44 V on its own axis
|   rising waveform, R_fixture 50.0000, V_fixture 1.5000: 20-80 % time 280ps typ, 298ps min, 293ps max; typ from 0.576 V to 1.5 V
|   falling waveform, R_fixture 50.0000, V_fixture 1.5000: 20-80 % time 186ps typ, 230ps min, 133ps max; typ from 1.5 V to 0.576 V
[Pulldown]
|Voltage   I(typ)   I(min)   I(max)
-1.5V     -22.23mA   -15.64mA   -29.44mA
-1.02V    -21.55mA   -15.16mA   -28.53mA
-840mV    -20.52mA   -14.9mA    -24.97mA
-660mV    -18.84mA   -14.21mA   -23.51mA
-420mV    -15.65mA   -10.92mA   -21.14mA
180mV     6.692mA    4.443mA    9.321mA
420mV     14.31mA    9.422mA    20.11mA
720mV     21.72mA    14.14mA    30.8mA
1.02V     26.57mA    17.18mA    37.8mA
1.26V     28.61mA    18.5mA     40.6mA
1.62V     30.1mA     19.5mA     42.54mA
3V        32.22mA    21.01mA    45.14mA
[GND_clamp]
|Voltage   I(typ)   I(min)   I(max)
-1.5V     -148.1mA   -145.1mA   -157.1mA
-1.32V    -110mA     -107mA     -118.7mA
-1.17V    -80.46mA   -77.1mA    -89.31mA
-1.05V    -59.23mA   -55mA      -69.72mA
-930mV    -42.26mA   -35.91mA   -54.92mA
-810mV    -29.29mA   -21.6mA    -39.3mA
-690mV    -17.13mA   -10.88mA   -23.54mA
-600mV    -9.258mA   -5.26mA    -13.05mA
-540mV    -5.061mA   -2.654mA   -7.228mA
-450mV    -1.178mA   -585.4uA   -1.585mA
-300mV    -18.71uA   -15.93uA   -16.54uA
3V        0A         0A         0A
[Ramp]
| variable   typ   min   max
dV/dt_r  0.5542/0.2774n   0.4250/0.2949n   0.6651/0.2897n
dV/dt_f  0.5542/0.1841n   0.4249/0.2280n   0.6651/0.1315n
R_load = 50.0000
[Rising Waveform]
R_fixture=   50.0000
V_fixture=   1.5000
V_fixture_min=   1.4300
V_fixture_max=   1.5800
|time   V(typ)   V(min)   V(max)
0s        576.3mV    721.7mV    471.5mV
505.1ps   576.3mV    721.7mV    476.1mV
707.1ps   574.2mV    721.7mV    1.179V
808.1ps   683.1mV    721.8mV    1.324V
1.01ns    1.217V     721.5mV    1.46V
1.212ns   1.371V     775.2mV    1.522V
1.414ns   1.431V     1.173V     1.551V
1.717ns   1.47V      1.352V     1.57V
2.424ns   1.496V     1.414V     1.579V
10ns      1.5V       1.43V      1.58V
[Falling Waveform]
R_fixture=   50.0000
V_fixture=   1.5000
V_fixture_min=   1.4300
V_fixture_max=   1.5800
|time   V(typ)   V(min)   V(max)
0s        1.5V       1.43V      1.58V
606.1ps   1.5V       1.43V      1.477V
707.1ps   1.5V       1.43V      810.8mV
909.1ps   1.492V     1.43V      516.3mV
1.01ns    1.179V     1.43V      495.9mV
1.212ns   673.7mV    1.43V      479.7mV
1.515ns   598.8mV    1.401V     473.1mV
1.818ns   584mV      849mV      471.9mV
2.222ns   578.3mV    746.3mV    471.6mV
10ns      576.3mV    721.7mV    471.5mV
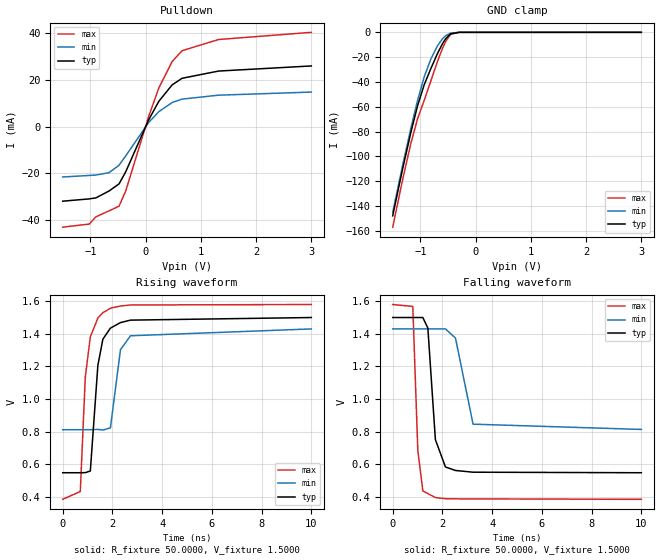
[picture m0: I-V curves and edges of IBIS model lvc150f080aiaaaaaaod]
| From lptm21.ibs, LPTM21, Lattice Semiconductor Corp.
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|   Model lvc150f080aiaaaaaaod
[Model]   lvc150f080aiaaaaaaod
Model_type   I/O_open_drain
Polarity   Non-Inverting
Enable   Active-Low
Vinl =   0.3750V
Vinh =   1.1250V
Vmeas =   0.7500V
Cref =   0.0F
Rref =   1.0000M
Vref =   0.0V
C_comp   4.2000pF   3.8000pF   7.5000pF
[Temperature Range]   25.0000   0.1050k   -40.0000
[Voltage Range]   1.5000V   1.4300V   1.5800V
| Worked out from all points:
|   slope of the pulldown table from 0 to 0.225 V, typ, clamps not added: 22 ohm
|   GND clamp passes 1 mA (typ) near -0.44 V on its own axis
|   rising waveform, R_fixture 50.0000, V_fixture 1.5000: 20-80 % time 297ps typ, 315ps min, 305ps max; typ from 0.547 V to 1.5 V
|   falling waveform, R_fixture 50.0000, V_fixture 1.5000: 20-80 % time 262ps typ, 330ps min, 170ps max; typ from 1.5 V to 0.547 V
[Pulldown]
|Voltage   I(typ)   I(min)   I(max)
-1.5V     -31.94mA   -21.59mA   -43.05mA
-1.02V    -30.96mA   -20.93mA   -41.73mA
-900mV    -30.53mA   -20.76mA   -38.64mA
-660mV    -27.57mA   -19.73mA   -36.06mA
-480mV    -24.53mA   -16.55mA   -34.07mA
-360mV    -19.4mA    -12.57mA   -27.61mA
60mV      3.049mA    1.834mA    4.587mA
240mV     10.79mA    6.377mA    16.51mA
480mV     17.79mA    10.25mA    27.78mA
660mV     20.62mA    11.72mA    32.42mA
1.32V     23.72mA    13.4mA     37.21mA
3V        25.91mA    14.73mA    40.29mA
[GND_clamp]
|Voltage   I(typ)   I(min)   I(max)
-1.5V     -148mA     -145.1mA   -157.1mA
-1.32V    -110mA     -107mA     -118.7mA
-1.17V    -80.44mA   -77.06mA   -89.3mA
-1.05V    -59.22mA   -54.98mA   -69.71mA
-930mV    -42.25mA   -35.9mA    -54.91mA
-810mV    -29.28mA   -21.6mA    -39.29mA
-690mV    -17.12mA   -10.87mA   -23.53mA
-600mV    -9.252mA   -5.256mA   -13.04mA
-540mV    -5.056mA   -2.651mA   -7.221mA
-450mV    -1.176mA   -584.3uA   -1.582mA
-300mV    -18.62uA   -15.88uA   -16.42uA
3V        0A         0A         0A
[Ramp]
| variable   typ   min   max
dV/dt_r  0.5719/0.2944n   0.3713/0.3115n   0.7179/0.3018n
dV/dt_f  0.5719/0.2591n   0.3713/0.3666n   0.7179/0.1824n
R_load = 50.0000
[Rising Waveform]
R_fixture=   50.0000
V_fixture=   1.5000
V_fixture_min=   1.4300
V_fixture_max=   1.5800
|time   V(typ)   V(min)   V(max)
0s        546.8mV    811.1mV    383.5mV
707.1ps   546.9mV    811.1mV    431.4mV
909.1ps   547.4mV    811.1mV    1.135V
1.111ns   557.4mV    810.9mV    1.381V
1.414ns   1.206V     813mV      1.497V
1.616ns   1.367V     809.1mV    1.53V
1.919ns   1.435V     822.5mV    1.557V
2.323ns   1.469V     1.302V     1.571V
2.727ns   1.484V     1.388V     1.577V
10ns      1.5V       1.43V      1.58V
[Falling Waveform]
R_fixture=   50.0000
V_fixture=   1.5000
V_fixture_min=   1.4300
V_fixture_max=   1.5800
|time   V(typ)   V(min)   V(max)
0s        1.5V       1.43V      1.58V
808.1ps   1.5V       1.43V      1.568V
1.01ns    1.5V       1.43V      684.1mV
1.212ns   1.5V       1.43V      435mV
1.414ns   1.435V     1.43V      418.6mV
1.717ns   749.9mV    1.43V      394.4mV
2.121ns   582.3mV    1.43V      387.5mV
2.525ns   560.7mV    1.374V     386.4mV
3.232ns   550.1mV    845.1mV    386.2mV
10ns      546.8mV    812.7mV    383.5mV
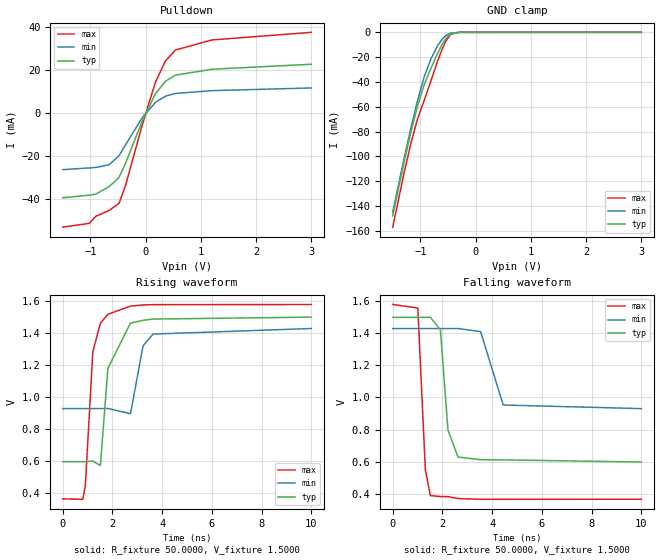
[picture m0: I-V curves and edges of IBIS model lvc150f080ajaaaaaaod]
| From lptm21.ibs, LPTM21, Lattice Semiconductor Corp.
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|   Model lvc150f080ajaaaaaaod
[Model]   lvc150f080ajaaaaaaod
Model_type   I/O_open_drain
Polarity   Non-Inverting
Enable   Active-Low
Vinl =   0.3750V
Vinh =   1.1250V
Vmeas =   0.7500V
Cref =   0.0F
Rref =   1.0000M
Vref =   0.0V
C_comp   4.2000pF   3.8000pF   7.5000pF
[Temperature Range]   25.0000   0.1050k   -40.0000
[Voltage Range]   1.5000V   1.4300V   1.5800V
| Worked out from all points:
|   slope of the pulldown table from 0 to 0.225 V, typ, clamps not added: 21 ohm
|   GND clamp passes 1 mA (typ) near -0.44 V on its own axis
|   rising waveform, R_fixture 50.0000, V_fixture 1.5000: 20-80 % time 299ps typ, 345ps min, 306ps max; typ from 0.597 V to 1.5 V
|   falling waveform, R_fixture 50.0000, V_fixture 1.5000: 20-80 % time 280ps typ, 382ps min, 179ps max; typ from 1.5 V to 0.598 V
[Pulldown]
|Voltage   I(typ)   I(min)   I(max)
-1.5V     -39.38mA   -26.31mA   -53.02mA
-1.02V    -38.16mA   -25.51mA   -51.27mA
-900mV    -37.65mA   -25.3mA    -47.97mA
-660mV    -34.19mA   -24.03mA   -45.25mA
-480mV    -29.92mA   -19.79mA   -41.97mA
-360mV    -23.22mA   -14.7mA    -33.4mA
-60mV     -3.617mA   -2.108mA   -5.527mA
180mV     9.019mA    4.965mA    14.39mA
360mV     14.75mA    7.822mA    24.18mA
540mV     17.57mA    9.078mA    29.25mA
1.2V      20.32mA    10.38mA    33.93mA
3V        22.64mA    11.64mA    37.47mA
[GND_clamp]
|Voltage   I(typ)   I(min)   I(max)
-1.5V     -147.9mA   -145mA     -157mA
-1.29V    -103.8mA   -100.8mA   -112.5mA
-1.17V    -80.38mA   -77mA      -89.28mA
-1.05V    -59.17mA   -54.93mA   -69.71mA
-930mV    -42.22mA   -35.86mA   -54.91mA
-810mV    -29.28mA   -21.58mA   -39.29mA
-690mV    -17.12mA   -10.87mA   -23.53mA
-600mV    -9.251mA   -5.255mA   -13.04mA
-540mV    -5.055mA   -2.651mA   -7.219mA
-450mV    -1.175mA   -584uA     -1.58mA
-300mV    -18.6uA    -15.87uA   -16.38uA
3V        0A         0A         0A
[Ramp]
| variable   typ   min   max
dV/dt_r  0.5417/0.2960n   0.3005/0.3421n   0.7294/0.3031n
dV/dt_f  0.5415/0.2776n   0.2996/0.3786n   0.7287/0.1768n
R_load = 50.0000
[Rising Waveform]
R_fixture=   50.0000
V_fixture=   1.5000
V_fixture_min=   1.4300
V_fixture_max=   1.5800
|time   V(typ)   V(min)   V(max)
0s        596.6mV    928.4mV    363.7mV
808.1ps   596.5mV    928.4mV    361mV
909.1ps   596.4mV    928.4mV    445.6mV
1.212ns   599.7mV    928.3mV    1.284V
1.515ns   572.3mV    928.1mV    1.462V
1.818ns   1.18V      929.3mV    1.518V
2.727ns   1.463V     895.9mV    1.569V
3.232ns   1.48V      1.321V     1.576V
3.636ns   1.488V     1.394V     1.578V
10ns      1.5V       1.429V     1.579V
[Falling Waveform]
R_fixture=   50.0000
V_fixture=   1.5000
V_fixture_min=   1.4300
V_fixture_max=   1.5800
|time   V(typ)   V(min)   V(max)
0s        1.5V       1.43V      1.58V
1.01ns    1.5V       1.43V      1.558V
1.313ns   1.5V       1.43V      549mV
1.515ns   1.5V       1.43V      388.4mV
1.919ns   1.422V     1.43V      382.4mV
2.222ns   797.9mV    1.43V      381.5mV
2.626ns   628.6mV    1.43V      369.8mV
3.535ns   612.1mV    1.411V     365.1mV
4.444ns   610.9mV    953mV      364.9mV
10ns      597.5mV    930.7mV    365.5mV
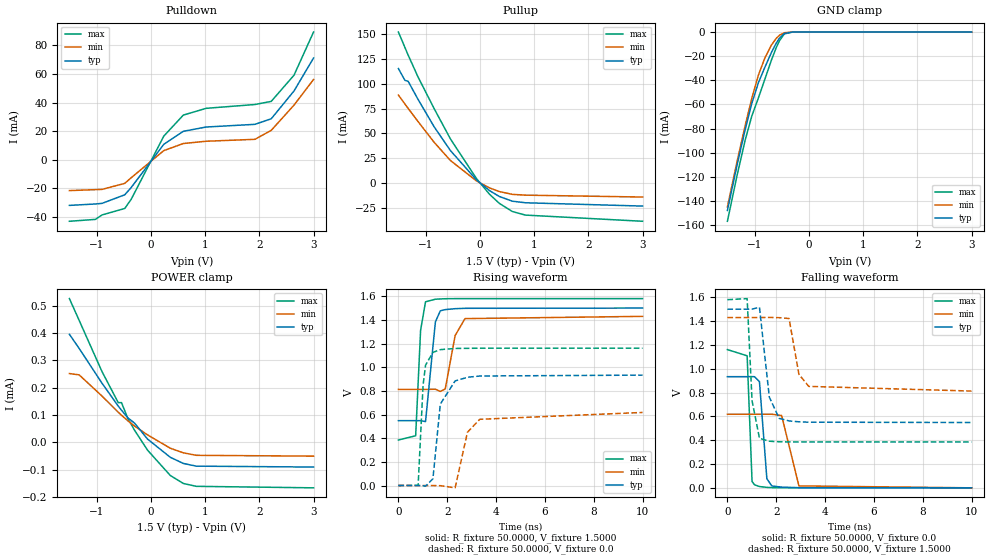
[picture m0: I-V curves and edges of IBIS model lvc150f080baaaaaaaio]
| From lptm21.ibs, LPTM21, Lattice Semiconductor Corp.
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|   Model lvc150f080baaaaaaaio
[Model]   lvc150f080baaaaaaaio
Model_type   I/O
Polarity   Non-Inverting
Enable   Active-Low
Vinl =   0.3750V
Vinh =   1.1250V
Vmeas =   0.7500V
Cref =   0.0F
Rref =   1.0000M
Vref =   0.0V
C_comp   4.2000pF   3.8000pF   7.5000pF
[Temperature Range]   25.0000   0.1050k   -40.0000
[Voltage Range]   1.5000V   1.4300V   1.5800V
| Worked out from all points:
|   slope of the pulldown table from 0 to 0.225 V, typ, clamps not added: 22 ohm
|   slope of the pullup table from 0 to 0.225 V, typ, clamps not added: 23.9 ohm
|   GND clamp passes 1 mA (typ) near -0.44 V on its own axis
|   rising waveform, R_fixture 50.0000, V_fixture 1.5000: 20-80 % time 244ps typ, 366ps min, 158ps max; typ from 0.549 V to 1.5 V
|   rising waveform, R_fixture 50.0000, V_fixture 0.0: 20-80 % time 330ps typ, 448ps min, 189ps max; typ from 0.001 V to 0.934 V
|   falling waveform, R_fixture 50.0000, V_fixture 0.0: 20-80 % time 190ps typ, 283ps min, 132ps max; typ from 0.934 V to 0.001 V
|   falling waveform, R_fixture 50.0000, V_fixture 1.5000: 20-80 % time 245ps typ, 352ps min, 164ps max; typ from 1.5 V to 0.549 V
[Pulldown]
|Voltage   I(typ)   I(min)   I(max)
-1.5V     -31.94mA   -21.59mA   -43.05mA
-1.02V    -30.96mA   -20.93mA   -41.73mA
-900mV    -30.53mA   -20.76mA   -38.64mA
-480mV    -24.54mA   -16.55mA   -34.09mA
-360mV    -19.39mA   -12.56mA   -27.6mA
240mV     10.8mA     6.379mA    16.53mA
600mV     19.88mA    11.34mA    31.22mA
1.02V     22.87mA    12.92mA    35.95mA
1.92V     24.75mA    14.27mA    38.61mA
2.22V     28.63mA    20.54mA    40.8mA
2.64V     48.1mA     38.21mA    59.12mA
3V        71.15mA    56.11mA    89.3mA
[Pullup]
|Voltage   I(typ)   I(min)   I(max)
-1.5V     115.5mA    88.73mA    152.4mA
-1.38V    103.6mA    79.69mA    136.8mA
-1.32V    102.6mA    75.24mA    129.1mA
-1.14V    84.57mA    62.12mA    107.2mA
-840mV    56.55mA    40.94mA    74.93mA
-540mV    32.6mA     22.59mA    44.32mA
-60mV     2.994mA    1.974mA    4.301mA
180mV     -7.798mA   -5.045mA   -11.51mA
360mV     -13.69mA   -8.745mA   -20.64mA
600mV     -18.46mA   -11.56mA   -28.87mA
840mV     -20.06mA   -12.36mA   -32.5mA
3V        -23.4mA    -14.27mA   -38.75mA
[GND_clamp]
|Voltage   I(typ)   I(min)   I(max)
-1.5V     -147.9mA   -145mA     -156.9mA
-1.32V    -109.9mA   -106.9mA   -118.5mA
-1.17V    -80.37mA   -77.03mA   -89.17mA
-1.05V    -59.15mA   -54.95mA   -69.59mA
-930mV    -42.18mA   -35.87mA   -54.79mA
-810mV    -29.22mA   -21.57mA   -39.18mA
-690mV    -17.07mA   -10.85mA   -23.42mA
-600mV    -9.207mA   -5.237mA   -12.94mA
-540mV    -5.019mA   -2.637mA   -7.138mA
-450mV    -1.157mA   -579.1uA   -1.537mA
-300mV    -18.25uA   -15.97uA   -13.7uA
3V        0A         0A         0A
[POWER_clamp]
|Voltage   I(typ)   I(min)   I(max)
-1.5V     395.4uA    251.6uA    526.1uA
-1.32V    343.5uA    246.7uA    446.2uA
-900mV    216.4uA    169.3uA    259.1uA
-600mV    132.4uA    109.9uA    145uA
-540mV    117.3uA    98.92uA    145uA
-420mV    88.66uA    78.23uA    86.09uA
-300mV    70.18uA    59.14uA    44.18uA
-60mV     11.57uA    26.89uA    -29.01uA
360mV     -55.31uA   -22.01uA   -121.9uA
600mV     -77.75uA   -38.9uA    -151.1uA
840mV     -87.68uA   -48uA      -161.6uA
3V        -90.95uA   -50.99uA   -167.1uA
[Ramp]
| variable   typ   min   max
dV/dt_r  0.5328/0.3271n   0.3705/0.4434n   0.6956/0.1871n
dV/dt_f  0.5705/0.2423n   0.3701/0.3488n   0.7165/0.1625n
R_load = 50.0000
[Rising Waveform]
R_fixture=   50.0000
V_fixture=   1.5000
V_fixture_min=   1.4300
V_fixture_max=   1.5800
|time   V(typ)   V(min)   V(max)
0s        549.2mV    813.1mV    385.8mV
707.1ps   549.2mV    813.1mV    421.3mV
909.1ps   549.2mV    813.1mV    1.313V
1.111ns   541.3mV    812.9mV    1.553V
1.515ns   1.383V     814.6mV    1.575V
1.717ns   1.477V     796mV      1.577V
1.919ns   1.487V     817.2mV    1.579V
2.323ns   1.495V     1.268V     1.58V
2.727ns   1.498V     1.411V     1.58V
10ns      1.5V       1.43V      1.58V
[Rising Waveform]
R_fixture=   50.0000
V_fixture=   0.0
V_fixture_min=   0.0
V_fixture_max=   0.0
|time   V(typ)   V(min)   V(max)
0s        1.119mV    921.9uV    1.42mV
808.1ps   1.097mV    921.7uV    3.157mV
1.01ns    -23.12uV   927.3uV    846.5mV
1.111ns   -4.526mV   933.6uV    1.017V
1.414ns   58.34mV    793.5uV    1.126V
1.717ns   689.3mV    -79.86uV   1.149V
2.323ns   884.7mV    -18.39mV   1.159V
2.828ns   915.3mV    451.1mV    1.16V
3.333ns   926.3mV    560.6mV    1.161V
10ns      933.7mV    618.4mV    1.161V
[Falling Waveform]
R_fixture=   50.0000
V_fixture=   0.0
V_fixture_min=   0.0
V_fixture_max=   0.0
|time   V(typ)   V(min)   V(max)
0s        933.7mV    618.4mV    1.161V
808.1ps   933.7mV    618.4mV    1.109V
1.01ns    934.4mV    618.4mV    54.07mV
1.111ns   933.8mV    618.4mV    26.49mV
1.313ns   892.5mV    618.4mV    11.91mV
1.616ns   77.56mV    618.5mV    4.743mV
1.818ns   16.72mV    618.5mV    2.922mV
2.222ns   6.805mV    607.8mV    1.716mV
2.929ns   2.313mV    17.02mV    1.495mV
10ns      1.128mV    928.5uV    1.44mV
[Falling Waveform]
R_fixture=   50.0000
V_fixture=   1.5000
V_fixture_min=   1.4300
V_fixture_max=   1.5800
|time   V(typ)   V(min)   V(max)
0s        1.5V       1.43V      1.58V
808.1ps   1.5V       1.43V      1.589V
1.01ns    1.501V     1.43V      732.3mV
1.313ns   1.516V     1.43V      416.7mV
1.717ns   762.1mV    1.431V     392.2mV
2.121ns   584mV      1.429V     387.4mV
2.525ns   562.7mV    1.422V     386.2mV
2.929ns   555mV      953.6mV    385.9mV
3.333ns   551.7mV    852.3mV    385.8mV
10ns      549.2mV    813.1mV    385.8mV
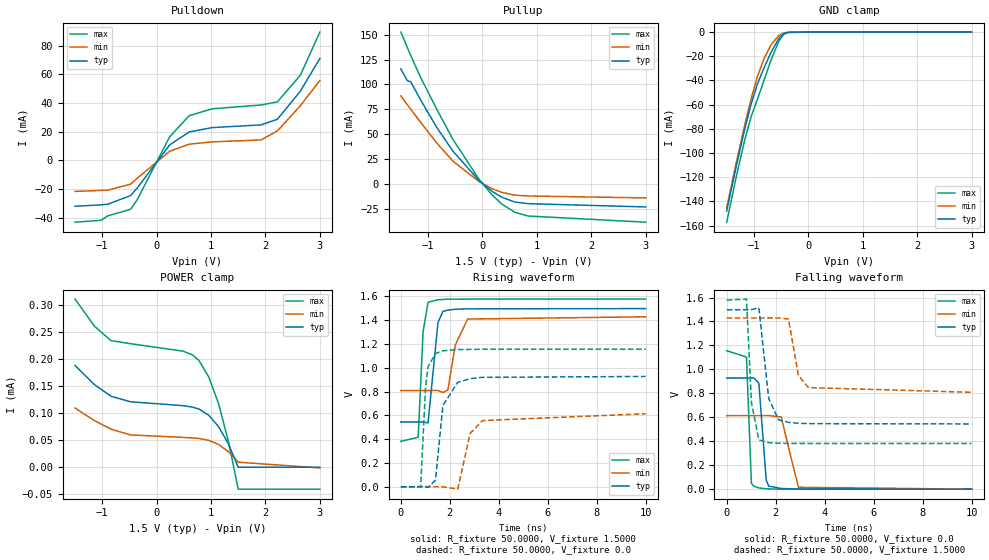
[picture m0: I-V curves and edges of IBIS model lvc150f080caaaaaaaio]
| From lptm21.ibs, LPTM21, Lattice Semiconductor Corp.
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|   Model lvc150f080caaaaaaaio
[Model]   lvc150f080caaaaaaaio
Model_type   I/O
Polarity   Non-Inverting
Enable   Active-Low
Vinl =   0.3750V
Vinh =   1.1250V
Vmeas =   0.7500V
Cref =   0.0F
Rref =   1.0000M
Vref =   0.0V
C_comp   4.2000pF   3.8000pF   7.5000pF
[Temperature Range]   25.0000   0.1050k   -40.0000
[Voltage Range]   1.5000V   1.4300V   1.5800V
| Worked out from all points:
|   slope of the pulldown table from 0 to 0.225 V, typ, clamps not added: 22.1 ohm
|   slope of the pullup table from 0 to 0.225 V, typ, clamps not added: 23.8 ohm
|   GND clamp passes 1 mA (typ) near -0.44 V on its own axis
|   rising waveform, R_fixture 50.0000, V_fixture 1.5000: 20-80 % time 245ps typ, 368ps min, 160ps max; typ from 0.544 V to 1.5 V
|   rising waveform, R_fixture 50.0000, V_fixture 0.0: 20-80 % time 331ps typ, 446ps min, 190ps max; typ from 0 V to 0.928 V
|   falling waveform, R_fixture 50.0000, V_fixture 0.0: 20-80 % time 189ps typ, 282ps min, 132ps max; typ from 0.928 V to 0 V
|   falling waveform, R_fixture 50.0000, V_fixture 1.5000: 20-80 % time 243ps typ, 352ps min, 163ps max; typ from 1.5 V to 0.544 V
[Pulldown]
|Voltage   I(typ)   I(min)   I(max)
-1.5V     -31.94mA   -21.59mA   -43.05mA
-1.02V    -30.96mA   -20.93mA   -41.74mA
-900mV    -30.53mA   -20.76mA   -38.64mA
-480mV    -24.53mA   -16.55mA   -34.08mA
-360mV    -19.38mA   -12.56mA   -27.58mA
240mV     10.79mA    6.374mA    16.49mA
600mV     19.87mA    11.34mA    31.19mA
1.02V     22.87mA    12.92mA    35.96mA
1.92V     24.76mA    14.28mA    38.64mA
2.22V     28.67mA    20.55mA    40.83mA
2.64V     48.13mA    38.05mA    59.27mA
3V        71.01mA    55.66mA    89.43mA
[Pullup]
|Voltage   I(typ)   I(min)   I(max)
-1.5V     115.5mA    88.41mA    152.6mA
-1.38V    103.6mA    79.47mA    137mA
-1.32V    102.7mA    75.06mA    129.3mA
-1.14V    84.64mA    62.04mA    107.3mA
-840mV    56.62mA    40.96mA    75.01mA
-540mV    32.61mA    22.6mA     44.32mA
-60mV     2.984mA    1.971mA    4.273mA
180mV     -7.811mA   -5.049mA   -11.54mA
360mV     -13.7mA    -8.749mA   -20.68mA
600mV     -18.47mA   -11.56mA   -28.89mA
840mV     -20.06mA   -12.36mA   -32.51mA
3V        -23.38mA   -14.26mA   -38.72mA
[GND_clamp]
|Voltage   I(typ)   I(min)   I(max)
-1.5V     -148mA     -145.1mA   -157.1mA
-1.32V    -110mA     -107mA     -118.7mA
-1.17V    -80.48mA   -77.09mA   -89.35mA
-1.05V    -59.26mA   -55.01mA   -69.77mA
-930mV    -42.29mA   -35.93mA   -54.98mA
-810mV    -29.33mA   -21.63mA   -39.36mA
-690mV    -17.18mA   -10.91mA   -23.6mA
-540mV    -5.131mA   -2.707mA   -7.327mA
-450mV    -1.269mA   -646.6uA   -1.725mA
-360mV    -213.6uA   -130.7uA   -279.5uA
0V        0A         0A         0A
3V        0A         0A         0A
[POWER_clamp]
|Voltage   I(typ)   I(min)   I(max)
-1.5V     188.7uA    109.8uA    311.9uA
-1.14V    153uA      86.3uA     261.2uA
-840mV    131.7uA    70.61uA    234.9uA
-480mV    121.4uA    59.86uA    229.1uA
480mV     114.2uA    55.36uA    215.4uA
660mV     111.4uA    54.29uA    208.4uA
780mV     107.8uA    53.22uA    197.7uA
960mV     96.18uA    49.83uA    167uA
1.14V     75.06uA    42.11uA    117.4uA
1.32V     43.25uA    28.83uA    47.75uA
1.5V      -25.18nA   9.33uA     -40.71uA
3V        -25.18nA   -1.33uA    -40.71uA
[Ramp]
| variable   typ   min   max
dV/dt_r  0.5300/0.3284n   0.3682/0.4418n   0.6935/0.1884n
dV/dt_f  0.5724/0.2407n   0.3721/0.3485n   0.7178/0.1614n
R_load = 50.0000
[Rising Waveform]
R_fixture=   50.0000
V_fixture=   1.5000
V_fixture_min=   1.4300
V_fixture_max=   1.5800
|time   V(typ)   V(min)   V(max)
0s        544.4mV    808.9mV    381.6mV
707.1ps   544.4mV    808.9mV    416.4mV
909.1ps   544.5mV    808.8mV    1.305V
1.111ns   536.7mV    808.7mV    1.551V
1.515ns   1.379V     810.4mV    1.572V
1.717ns   1.475V     791.8mV    1.575V
1.919ns   1.485V     812.9mV    1.577V
2.222ns   1.492V     1.191V     1.577V
2.727ns   1.496V     1.41V      1.578V
10ns      1.498V     1.429V     1.578V
[Rising Waveform]
R_fixture=   50.0000
V_fixture=   0.0
V_fixture_min=   0.0
V_fixture_max=   0.0
|time   V(typ)   V(min)   V(max)
0s        308.7nV    487.3nV    219.7nV
808.1ps   -23.19uV   336.3nV    188uV
1.01ns    -1.133mV   5.885uV    838.9mV
1.111ns   -5.638mV   12.26uV    1.009V
1.414ns   55.4mV     -129.8uV   1.12V
1.717ns   683.3mV    -988.6uV   1.143V
2.323ns   877.8mV    -20.29mV   1.154V
2.828ns   908.7mV    447.7mV    1.155V
3.333ns   919.9mV    556.5mV    1.156V
10ns      927.5mV    613.7mV    1.156V
[Falling Waveform]
R_fixture=   50.0000
V_fixture=   0.0
V_fixture_min=   0.0
V_fixture_max=   0.0
|time   V(typ)   V(min)   V(max)
0s        927.5mV    613.8mV    1.156V
808.1ps   927.5mV    613.8mV    1.103V
1.01ns    928.1mV    613.8mV    49.56mV
1.111ns   927.6mV    613.8mV    24.1mV
1.313ns   885.8mV    613.8mV    10.23mV
1.616ns   74.16mV    613.9mV    3.23mV
1.717ns   25.35mV    614.2mV    2.221mV
2.222ns   5.568mV    603.2mV    269.9uV
2.929ns   1.163mV    15.66mV    85.69uV
10ns      10.06uV    -24.41uV   -22.16uV
[Falling Waveform]
R_fixture=   50.0000
V_fixture=   1.5000
V_fixture_min=   1.4300
V_fixture_max=   1.5800
|time   V(typ)   V(min)   V(max)
0s        1.498V     1.429V     1.578V
808.1ps   1.498V     1.429V     1.587V
1.01ns    1.499V     1.429V     724.3mV
1.313ns   1.514V     1.429V     411.5mV
1.717ns   755.8mV    1.43V      388.1mV
2.121ns   578.4mV    1.429V     383.1mV
2.525ns   557.6mV    1.42V      382mV
2.929ns   550.1mV    949.7mV    381.7mV
3.333ns   546.8mV    848mV      381.6mV
10ns      544.4mV    808.8mV    381.6mV
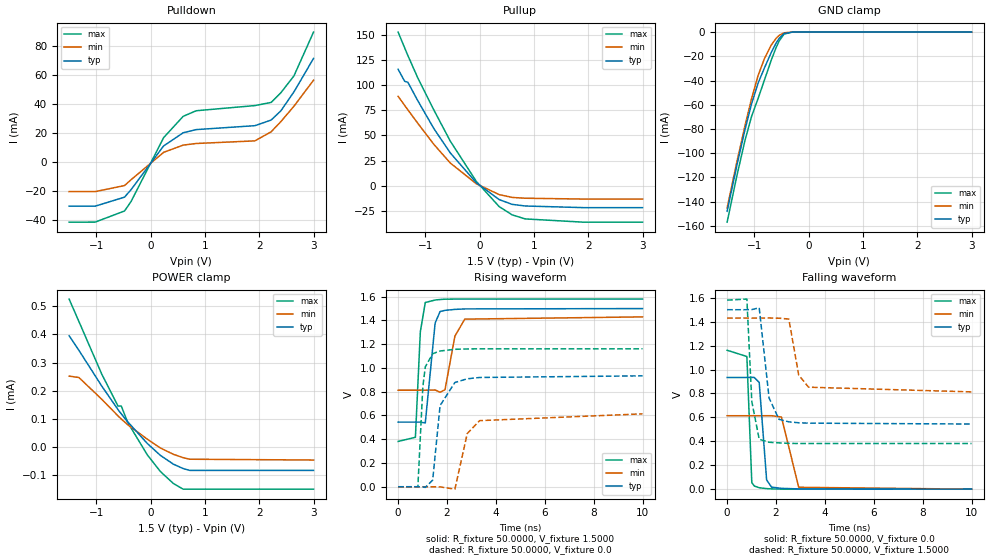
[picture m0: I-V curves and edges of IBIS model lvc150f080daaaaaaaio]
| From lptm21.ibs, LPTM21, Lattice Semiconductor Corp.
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|   Model lvc150f080daaaaaaaio
[Model]   lvc150f080daaaaaaaio
Model_type   I/O
Polarity   Non-Inverting
Enable   Active-Low
Vinl =   0.3750V
Vinh =   1.1250V
Vmeas =   0.7500V
Cref =   0.0F
Rref =   1.0000M
Vref =   0.0V
C_comp   4.2000pF   3.8000pF   7.5000pF
[Temperature Range]   25.0000   0.1050k   -40.0000
[Voltage Range]   1.5000V   1.4300V   1.5800V
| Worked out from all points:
|   slope of the pulldown table from 0 to 0.225 V, typ, clamps not added: 22.1 ohm
|   slope of the pullup table from 0 to 0.225 V, typ, clamps not added: 23.9 ohm
|   GND clamp passes 1 mA (typ) near -0.44 V on its own axis
|   rising waveform, R_fixture 50.0000, V_fixture 1.5000: 20-80 % time 246ps typ, 366ps min, 160ps max; typ from 0.544 V to 1.5 V
|   rising waveform, R_fixture 50.0000, V_fixture 0.0: 20-80 % time 337ps typ, 446ps min, 192ps max; typ from 0 V to 0.934 V
|   falling waveform, R_fixture 50.0000, V_fixture 0.0: 20-80 % time 190ps typ, 282ps min, 133ps max; typ from 0.934 V to 0 V
|   falling waveform, R_fixture 50.0000, V_fixture 1.5000: 20-80 % time 248ps typ, 352ps min, 165ps max; typ from 1.5 V to 0.544 V
[Pulldown]
|Voltage   I(typ)   I(min)   I(max)
-1.5V     -30.77mA   -20.72mA   -41.81mA
-1.02V    -30.77mA   -20.72mA   -41.74mA
-480mV    -24.53mA   -16.55mA   -34.08mA
-360mV    -19.38mA   -12.56mA   -27.58mA
240mV     10.79mA    6.374mA    16.49mA
600mV     19.87mA    11.34mA    31.19mA
840mV     22.05mA    12.47mA    35.06mA
1.92V     24.75mA    14.27mA    38.61mA
2.22V     28.63mA    20.54mA    40.8mA
2.4V      35.06mA    27.62mA    47.54mA
2.64V     48.1mA     38.21mA    59.12mA
3V        71.15mA    56.11mA    89.3mA
[Pullup]
|Voltage   I(typ)   I(min)   I(max)
-1.5V     115.5mA    88.73mA    152.4mA
-1.38V    103.6mA    79.69mA    136.8mA
-1.32V    102.6mA    75.24mA    129.1mA
-1.14V    84.57mA    62.12mA    107.2mA
-840mV    56.55mA    40.94mA    74.93mA
-540mV    32.6mA     22.59mA    44.32mA
-60mV     2.994mA    1.974mA    4.301mA
360mV     -13.69mA   -8.745mA   -20.64mA
600mV     -18.46mA   -11.56mA   -28.87mA
840mV     -20.06mA   -12.36mA   -32.87mA
1.92V     -21.69mA   -13.18mA   -36.12mA
3V        -21.69mA   -13.18mA   -36.12mA
[GND_clamp]
|Voltage   I(typ)   I(min)   I(max)
-1.5V     -147.9mA   -145.1mA   -156.9mA
-1.32V    -109.9mA   -107mA     -118.5mA
-1.17V    -80.39mA   -77.05mA   -89.2mA
-1.05V    -59.17mA   -54.96mA   -69.62mA
-930mV    -42.2mA    -35.88mA   -54.83mA
-810mV    -29.25mA   -21.58mA   -39.21mA
-690mV    -17.09mA   -10.87mA   -23.45mA
-600mV    -9.233mA   -5.258mA   -12.98mA
-540mV    -5.047mA   -2.659mA   -7.175mA
-450mV    -1.185mA   -599.1uA   -1.573mA
-300mV    -18.73uA   -15.61uA   -8.8uA
3V        0A         0A         0A
[POWER_clamp]
|Voltage   I(typ)   I(min)   I(max)
-1.5V     395.4uA    251.6uA    526.1uA
-1.32V    343.5uA    246.7uA    446.2uA
-900mV    216.4uA    169.3uA    259.1uA
-600mV    132.4uA    109.9uA    145uA
-540mV    117.3uA    98.92uA    145uA
-420mV    88.66uA    78.23uA    86.09uA
-60mV     11.57uA    26.89uA    -29.01uA
180mV     -30.73uA   -4.427uA   -88.14uA
420mV     -62.06uA   -26.95uA   -131uA
600mV     -77.75uA   -38.9uA    -151.1uA
720mV     -84.27uA   -44.44uA   -151.1uA
3V        -84.27uA   -47.29uA   -151.1uA
[Ramp]
| variable   typ   min   max
dV/dt_r  0.5335/0.3346n   0.3682/0.4418n   0.6964/0.1905n
dV/dt_f  0.5734/0.2459n   0.3701/0.3488n   0.7190/0.1637n
R_load = 50.0000
[Rising Waveform]
R_fixture=   50.0000
V_fixture=   1.5000
V_fixture_min=   1.4300
V_fixture_max=   1.5800
|time   V(typ)   V(min)   V(max)
0s        544.4mV    813.1mV    381.6mV
707.1ps   544.4mV    813.1mV    416.4mV
909.1ps   544.5mV    813.1mV    1.305V
1.111ns   536.7mV    812.9mV    1.551V
1.515ns   1.379V     814.6mV    1.572V
1.717ns   1.475V     796mV      1.576V
1.919ns   1.485V     817.2mV    1.579V
2.323ns   1.493V     1.268V     1.58V
2.727ns   1.497V     1.411V     1.58V
10ns      1.5V       1.43V      1.58V
[Rising Waveform]
R_fixture=   50.0000
V_fixture=   0.0
V_fixture_min=   0.0
V_fixture_max=   0.0
|time   V(typ)   V(min)   V(max)
0s        308.7nV    487.3nV    219.7nV
808.1ps   -23.19uV   336.3nV    188uV
1.01ns    -1.133mV   5.885uV    838.9mV
1.111ns   -5.638mV   12.26uV    1.009V
1.414ns   55.4mV     -129.8uV   1.12V
1.717ns   683.3mV    -988.6uV   1.143V
2.323ns   877.8mV    -20.29mV   1.157V
2.828ns   908.7mV    447.7mV    1.16V
3.333ns   919.9mV    556.5mV    1.161V
10ns      933.7mV    613.7mV    1.161V
[Falling Waveform]
R_fixture=   50.0000
V_fixture=   0.0
V_fixture_min=   0.0
V_fixture_max=   0.0
|time   V(typ)   V(min)   V(max)
0s        933.7mV    613.8mV    1.161V
808.1ps   933.7mV    613.8mV    1.109V
1.01ns    934.4mV    613.8mV    54.07mV
1.111ns   933.8mV    613.8mV    26.49mV
1.313ns   892.5mV    613.8mV    11.91mV
1.616ns   77.56mV    613.9mV    4.743mV
1.818ns   16.72mV    613.9mV    2.399mV
2.222ns   6.805mV    603.2mV    542uV
2.929ns   2.185mV    15.66mV    33.25uV
10ns      6.023uV    -24.41uV   -14.89uV
[Falling Waveform]
R_fixture=   50.0000
V_fixture=   1.5000
V_fixture_min=   1.4300
V_fixture_max=   1.5800
|time   V(typ)   V(min)   V(max)
0s        1.5V       1.43V      1.58V
808.1ps   1.5V       1.43V      1.589V
1.01ns    1.501V     1.43V      732.3mV
1.313ns   1.516V     1.43V      416.7mV
1.717ns   762.1mV    1.431V     392.2mV
2.121ns   584mV      1.429V     387mV
2.525ns   562.7mV    1.422V     382.6mV
2.929ns   555mV      953.6mV    381.8mV
3.333ns   551.7mV    852.3mV    381.7mV
10ns      544.4mV    813.1mV    381.6mV
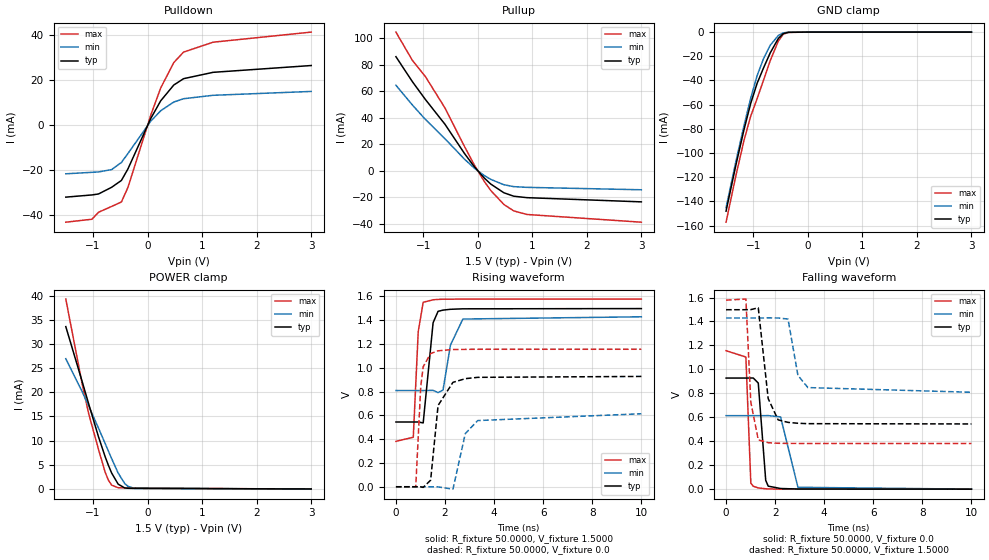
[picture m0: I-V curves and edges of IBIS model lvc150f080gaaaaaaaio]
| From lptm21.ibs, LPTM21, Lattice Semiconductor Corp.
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|   Model lvc150f080gaaaaaaaio
[Model]   lvc150f080gaaaaaaaio
Model_type   I/O
Polarity   Non-Inverting
Enable   Active-Low
Vinl =   0.3750V
Vinh =   1.1250V
Vmeas =   0.7500V
Cref =   0.0F
Rref =   1.0000M
Vref =   0.0V
C_comp   4.2000pF   3.8000pF   7.5000pF
[Temperature Range]   25.0000   0.1050k   -40.0000
[Voltage Range]   1.5000V   1.4300V   1.5800V
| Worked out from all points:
|   slope of the pulldown table from 0 to 0.225 V, typ, clamps not added: 22.1 ohm
|   slope of the pullup table from 0 to 0.225 V, typ, clamps not added: 23.8 ohm
|   GND clamp passes 1 mA (typ) near -0.44 V on its own axis
|   POWER clamp passes 1 mA (typ) near -0.54 V on its own axis
|   rising waveform, R_fixture 50.0000, V_fixture 1.5000: 20-80 % time 245ps typ, 368ps min, 160ps max; typ from 0.544 V to 1.5 V
|   rising waveform, R_fixture 50.0000, V_fixture 0.0: 20-80 % time 331ps typ, 446ps min, 190ps max; typ from 0 V to 0.928 V
|   falling waveform, R_fixture 50.0000, V_fixture 0.0: 20-80 % time 189ps typ, 282ps min, 132ps max; typ from 0.928 V to 0 V
|   falling waveform, R_fixture 50.0000, V_fixture 1.5000: 20-80 % time 243ps typ, 352ps min, 163ps max; typ from 1.5 V to 0.544 V
[Pulldown]
|Voltage   I(typ)   I(min)   I(max)
-1.5V     -31.94mA   -21.59mA   -43.05mA
-1.02V    -30.96mA   -20.93mA   -41.74mA
-900mV    -30.53mA   -20.76mA   -38.64mA
-660mV    -27.57mA   -19.73mA   -36.07mA
-480mV    -24.53mA   -16.55mA   -34.08mA
-360mV    -19.38mA   -12.56mA   -27.58mA
60mV      3.046mA    1.833mA    4.579mA
240mV     10.79mA    6.374mA    16.49mA
480mV     17.79mA    10.25mA    27.75mA
660mV     20.61mA    11.72mA    32.41mA
1.2V      23.42mA    13.23mA    36.78mA
3V        26.44mA    14.95mA    41.27mA
[Pullup]
|Voltage   I(typ)   I(min)   I(max)
-1.5V     86.14mA    64.6mA     104.7mA
-1.2V     67.41mA    49.77mA    83.49mA
-960mV    53.88mA    38.85mA    71.17mA
-600mV    35.11mA    24.2mA     47.39mA
-240mV    12.94mA    8.707mA    18.16mA
-60mV     2.984mA    1.971mA    4.273mA
120mV     -5.42mA    -3.515mA   -7.964mA
240mV     -9.99mA    -6.433mA   -14.86mA
480mV     -16.53mA   -10.46mA   -25.37mA
660mV     -19.11mA   -11.9mA    -30.21mA
900mV     -20.21mA   -12.44mA   -32.89mA
3V        -23.38mA   -14.26mA   -38.72mA
[GND_clamp]
|Voltage   I(typ)   I(min)   I(max)
-1.5V     -148mA     -145.1mA   -157.1mA
-1.32V    -110mA     -107mA     -118.7mA
-1.17V    -80.48mA   -77.09mA   -89.35mA
-1.05V    -59.26mA   -55.01mA   -69.77mA
-930mV    -42.29mA   -35.93mA   -54.98mA
-810mV    -29.33mA   -21.63mA   -39.36mA
-690mV    -17.18mA   -10.91mA   -23.6mA
-540mV    -5.131mA   -2.707mA   -7.327mA
-450mV    -1.269mA   -646.6uA   -1.725mA
-360mV    -213.6uA   -130.7uA   -279.5uA
0V        0A         0A         0A
3V        0A         0A         0A
[POWER_clamp]
|Voltage   I(typ)   I(min)   I(max)
-1.5V     33.6mA     26.96mA    39.3mA
-1.2V     22.23mA    20.13mA    21.75mA
-1.08V    17.59mA    17.16mA    15.56mA
-900mV    10.78mA    12.58mA    8.18mA
-780mV    6.728mA    9.453mA    3.516mA
-720mV    4.925mA    7.87mA     1.844mA
-660mV    3.313mA    6.291mA    793.6uA
-540mV    997.8uA    3.293mA    253uA
-420mV    212.5uA    1.125mA    228.2uA
-360mV    145.3uA    543uA      226.9uA
-240mV    121.5uA    119.5uA    225.5uA
3V        -25.18nA   -1.33uA    -40.71uA
[Ramp]
| variable   typ   min   max
dV/dt_r  0.5300/0.3284n   0.3682/0.4418n   0.6935/0.1884n
dV/dt_f  0.5724/0.2407n   0.3721/0.3485n   0.7178/0.1614n
R_load = 50.0000
[Rising Waveform]
R_fixture=   50.0000
V_fixture=   1.5000
V_fixture_min=   1.4300
V_fixture_max=   1.5800
|time   V(typ)   V(min)   V(max)
0s        544.4mV    808.9mV    381.6mV
707.1ps   544.4mV    808.9mV    416.4mV
909.1ps   544.5mV    808.8mV    1.305V
1.111ns   536.7mV    808.7mV    1.551V
1.515ns   1.379V     810.4mV    1.572V
1.717ns   1.475V     791.8mV    1.575V
1.919ns   1.485V     812.9mV    1.577V
2.222ns   1.492V     1.191V     1.577V
2.727ns   1.496V     1.41V      1.578V
10ns      1.498V     1.429V     1.578V
[Rising Waveform]
R_fixture=   50.0000
V_fixture=   0.0
V_fixture_min=   0.0
V_fixture_max=   0.0
|time   V(typ)   V(min)   V(max)
0s        308.7nV    487.3nV    219.7nV
808.1ps   -23.19uV   336.3nV    188uV
1.01ns    -1.133mV   5.885uV    838.9mV
1.111ns   -5.638mV   12.26uV    1.009V
1.414ns   55.4mV     -129.8uV   1.12V
1.717ns   683.3mV    -988.6uV   1.143V
2.323ns   877.8mV    -20.29mV   1.154V
2.828ns   908.7mV    447.7mV    1.155V
3.333ns   919.9mV    556.5mV    1.156V
10ns      927.5mV    613.7mV    1.156V
[Falling Waveform]
R_fixture=   50.0000
V_fixture=   0.0
V_fixture_min=   0.0
V_fixture_max=   0.0
|time   V(typ)   V(min)   V(max)
0s        927.5mV    613.8mV    1.156V
808.1ps   927.5mV    613.8mV    1.103V
1.01ns    928.1mV    613.8mV    49.56mV
1.111ns   927.6mV    613.8mV    24.1mV
1.313ns   885.8mV    613.8mV    10.23mV
1.616ns   74.16mV    613.9mV    3.23mV
1.717ns   25.35mV    614.2mV    2.221mV
2.222ns   5.568mV    603.2mV    269.9uV
2.929ns   1.163mV    15.66mV    85.69uV
10ns      10.09uV    5.657uV    -22.13uV
[Falling Waveform]
R_fixture=   50.0000
V_fixture=   1.5000
V_fixture_min=   1.4300
V_fixture_max=   1.5800
|time   V(typ)   V(min)   V(max)
0s        1.498V     1.429V     1.578V
808.1ps   1.498V     1.429V     1.587V
1.01ns    1.499V     1.429V     724.3mV
1.313ns   1.514V     1.429V     411.5mV
1.717ns   755.8mV    1.43V      388.1mV
2.121ns   578.4mV    1.429V     383.1mV
2.525ns   557.6mV    1.42V      382mV
2.929ns   550.1mV    949.7mV    381.7mV
3.333ns   546.8mV    848mV      381.6mV
10ns      544.4mV    808.9mV    381.6mV
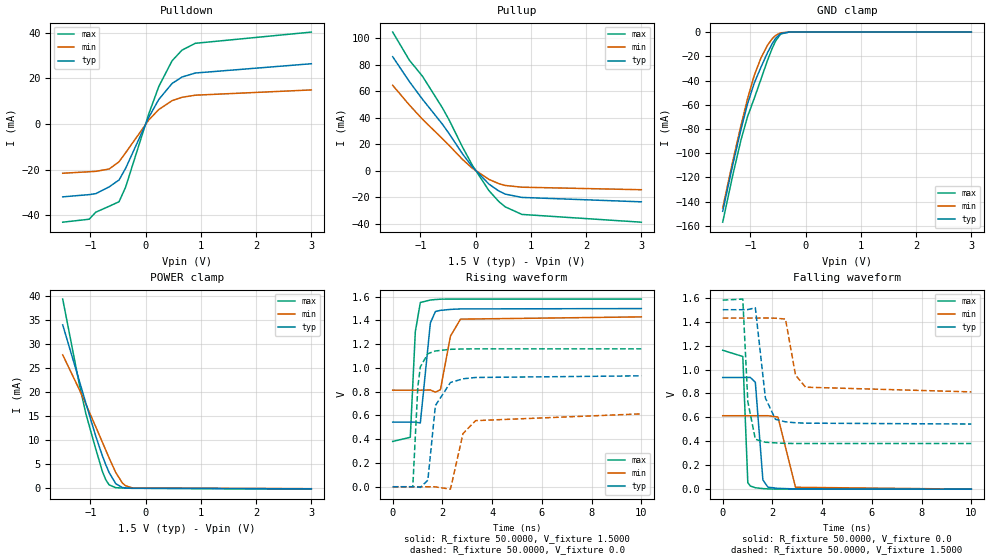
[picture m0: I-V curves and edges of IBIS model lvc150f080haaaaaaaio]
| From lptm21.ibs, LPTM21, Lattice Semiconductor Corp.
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|   Model lvc150f080haaaaaaaio
[Model]   lvc150f080haaaaaaaio
Model_type   I/O
Polarity   Non-Inverting
Enable   Active-Low
Vinl =   0.3750V
Vinh =   1.1250V
Vmeas =   0.7500V
Cref =   0.0F
Rref =   1.0000M
Vref =   0.0V
C_comp   4.2000pF   3.8000pF   7.5000pF
[Temperature Range]   25.0000   0.1050k   -40.0000
[Voltage Range]   1.5000V   1.4300V   1.5800V
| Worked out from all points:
|   slope of the pulldown table from 0 to 0.225 V, typ, clamps not added: 22.1 ohm
|   slope of the pullup table from 0 to 0.225 V, typ, clamps not added: 23.9 ohm
|   GND clamp passes 1 mA (typ) near -0.44 V on its own axis
|   POWER clamp passes 1 mA (typ) near -0.54 V on its own axis
|   rising waveform, R_fixture 50.0000, V_fixture 1.5000: 20-80 % time 246ps typ, 366ps min, 160ps max; typ from 0.544 V to 1.5 V
|   rising waveform, R_fixture 50.0000, V_fixture 0.0: 20-80 % time 337ps typ, 446ps min, 192ps max; typ from 0 V to 0.934 V
|   falling waveform, R_fixture 50.0000, V_fixture 0.0: 20-80 % time 190ps typ, 282ps min, 133ps max; typ from 0.934 V to 0 V
|   falling waveform, R_fixture 50.0000, V_fixture 1.5000: 20-80 % time 248ps typ, 352ps min, 165ps max; typ from 1.5 V to 0.544 V
[Pulldown]
|Voltage   I(typ)   I(min)   I(max)
-1.5V     -31.94mA   -21.59mA   -43.05mA
-1.02V    -30.96mA   -20.93mA   -41.74mA
-900mV    -30.53mA   -20.76mA   -38.64mA
-660mV    -27.57mA   -19.73mA   -36.07mA
-480mV    -24.53mA   -16.55mA   -34.08mA
-360mV    -19.38mA   -12.56mA   -27.58mA
60mV      3.046mA    1.833mA    4.579mA
240mV     10.79mA    6.374mA    16.49mA
480mV     17.79mA    10.25mA    27.75mA
660mV     20.61mA    11.72mA    32.41mA
900mV     22.36mA    12.64mA    35.39mA
3V        26.43mA    14.95mA    40.31mA
[Pullup]
|Voltage   I(typ)   I(min)   I(max)
-1.5V     85.91mA    64.39mA    104.5mA
-1.2V     67.29mA    49.66mA    83.42mA
-960mV    53.84mA    38.79mA    71.17mA
-600mV    35.1mA     24.19mA    47.39mA
-480mV    28.01mA    19.18mA    38.4mA
-240mV    12.94mA    8.707mA    18.17mA
-60mV     2.994mA    1.974mA    4.301mA
240mV     -9.977mA   -6.429mA   -14.83mA
420mV     -15.22mA   -9.675mA   -23.14mA
540mV     -17.6mA    -11.08mA   -27.25mA
840mV     -20.06mA   -12.36mA   -32.87mA
3V        -23.38mA   -14.26mA   -38.72mA
[GND_clamp]
|Voltage   I(typ)   I(min)   I(max)
-1.5V     -147.9mA   -145.1mA   -156.9mA
-1.32V    -109.9mA   -107mA     -118.5mA
-1.17V    -80.39mA   -77.05mA   -89.2mA
-1.05V    -59.17mA   -54.96mA   -69.62mA
-930mV    -42.2mA    -35.88mA   -54.83mA
-810mV    -29.25mA   -21.58mA   -39.21mA
-690mV    -17.09mA   -10.87mA   -23.45mA
-600mV    -9.233mA   -5.258mA   -12.98mA
-540mV    -5.047mA   -2.659mA   -7.175mA
-450mV    -1.185mA   -599.1uA   -1.573mA
-300mV    -18.73uA   -15.61uA   -8.8uA
3V        0A         0A         0A
[POWER_clamp]
|Voltage   I(typ)   I(min)   I(max)
-1.5V     34.08mA    27.83mA    39.45mA
-1.2V     22.44mA    20.61mA    21.74mA
-1.08V    17.72mA    17.52mA    15.53mA
-900mV    10.82mA    12.79mA    8.145mA
-780mV    6.739mA    9.58mA     3.478mA
-720mV    4.93mA     7.965mA    1.803mA
-660mV    3.313mA    6.359mA    743.4uA
-540mV    987.9uA    3.323mA    158.4uA
-420mV    184.8uA    1.136mA    86.1uA
-360mV    103.6uA    547.9uA    64.36uA
-240mV    51.4uA     112.2uA    24.82uA
3V        -84.27uA   -47.29uA   -151.1uA
[Ramp]
| variable   typ   min   max
dV/dt_r  0.5335/0.3346n   0.3682/0.4418n   0.6964/0.1905n
dV/dt_f  0.5734/0.2459n   0.3702/0.3488n   0.7190/0.1637n
R_load = 50.0000
[Rising Waveform]
R_fixture=   50.0000
V_fixture=   1.5000
V_fixture_min=   1.4300
V_fixture_max=   1.5800
|time   V(typ)   V(min)   V(max)
0s        544.4mV    813.1mV    381.6mV
707.1ps   544.4mV    813.1mV    416.4mV
909.1ps   544.5mV    813.1mV    1.305V
1.111ns   536.7mV    812.9mV    1.551V
1.515ns   1.379V     814.6mV    1.572V
1.717ns   1.475V     796mV      1.576V
1.919ns   1.485V     817.2mV    1.579V
2.323ns   1.493V     1.268V     1.58V
2.727ns   1.497V     1.411V     1.58V
10ns      1.5V       1.43V      1.58V
[Rising Waveform]
R_fixture=   50.0000
V_fixture=   0.0
V_fixture_min=   0.0
V_fixture_max=   0.0
|time   V(typ)   V(min)   V(max)
0s        308.7nV    487.3nV    219.7nV
808.1ps   -23.19uV   336.3nV    188uV
1.01ns    -1.133mV   5.885uV    838.9mV
1.111ns   -5.638mV   12.26uV    1.009V
1.414ns   55.4mV     -129.8uV   1.12V
1.717ns   683.3mV    -988.6uV   1.143V
2.323ns   877.8mV    -20.29mV   1.157V
2.828ns   908.7mV    447.7mV    1.16V
3.333ns   919.9mV    556.5mV    1.161V
10ns      933.7mV    613.7mV    1.161V
[Falling Waveform]
R_fixture=   50.0000
V_fixture=   0.0
V_fixture_min=   0.0
V_fixture_max=   0.0
|time   V(typ)   V(min)   V(max)
0s        933.7mV    613.8mV    1.161V
808.1ps   933.7mV    613.8mV    1.109V
1.01ns    934.4mV    613.8mV    54.07mV
1.111ns   933.8mV    613.8mV    26.49mV
1.313ns   892.5mV    613.8mV    11.91mV
1.616ns   77.56mV    613.9mV    4.743mV
1.818ns   16.72mV    613.9mV    2.399mV
2.222ns   6.805mV    603.2mV    542uV
2.929ns   2.185mV    15.66mV    33.25uV
10ns      -3.025uV   5.657uV    -15.77uV
[Falling Waveform]
R_fixture=   50.0000
V_fixture=   1.5000
V_fixture_min=   1.4300
V_fixture_max=   1.5800
|time   V(typ)   V(min)   V(max)
0s        1.5V       1.43V      1.58V
808.1ps   1.5V       1.43V      1.589V
1.01ns    1.501V     1.43V      732.3mV
1.313ns   1.516V     1.43V      416.7mV
1.717ns   762.1mV    1.431V     392.2mV
2.121ns   584mV      1.429V     387mV
2.525ns   562.7mV    1.422V     382.6mV
2.929ns   555mV      953.6mV    381.8mV
3.333ns   551.7mV    852.3mV    381.7mV
10ns      544.4mV    813.1mV    381.6mV
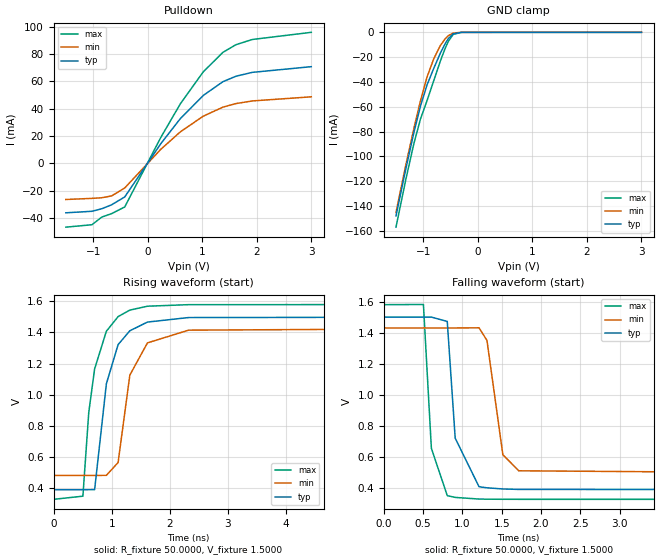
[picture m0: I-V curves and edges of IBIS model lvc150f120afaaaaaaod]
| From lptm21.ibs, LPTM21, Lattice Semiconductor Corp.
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|   Model lvc150f120afaaaaaaod
[Model]   lvc150f120afaaaaaaod
Model_type   I/O_open_drain
Polarity   Non-Inverting
Enable   Active-Low
Vinl =   0.3750V
Vinh =   1.1250V
Vmeas =   0.7500V
Cref =   0.0F
Rref =   1.0000M
Vref =   0.0V
C_comp   4.2000pF   3.8000pF   7.5000pF
[Temperature Range]   25.0000   0.1050k   -40.0000
[Voltage Range]   1.5000V   1.4300V   1.5800V
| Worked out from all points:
|   slope of the pulldown table from 0 to 0.225 V, typ, clamps not added: 16.9 ohm
|   GND clamp passes 1 mA (typ) near -0.44 V on its own axis
|   rising waveform, R_fixture 50.0000, V_fixture 1.5000: 20-80 % time 296ps typ, 285ps min, 272ps max; typ from 0.389 V to 1.5 V
|   falling waveform, R_fixture 50.0000, V_fixture 1.5000: 20-80 % time 119ps typ, 157ps min, 103ps max; typ from 1.5 V to 0.389 V
[Pulldown]
|Voltage   I(typ)   I(min)   I(max)
-1.5V     -36.33mA   -26.58mA   -46.82mA
-1.02V    -35.21mA   -25.76mA   -45.04mA
-840mV    -33.33mA   -25.3mA    -39.43mA
-660mV    -30.45mA   -23.96mA   -36.92mA
-420mV    -24.73mA   -18.16mA   -32.05mA
240mV     14.2mA     10.09mA    18.72mA
600mV     32.61mA    22.93mA    43.45mA
1.02V     49.55mA    34.38mA    66.84mA
1.38V     59.62mA    40.99mA    81.09mA
1.62V     63.63mA    43.62mA    86.71mA
1.92V     66.45mA    45.54mA    90.51mA
3V        70.61mA    48.55mA    95.74mA
[GND_clamp]
|Voltage   I(typ)   I(min)   I(max)
-1.5V     -148.1mA   -145.2mA   -157.1mA
-1.32V    -110.1mA   -107mA     -118.7mA
-1.17V    -80.47mA   -77.11mA   -89.33mA
-1.05V    -59.24mA   -55.01mA   -69.75mA
-930mV    -42.27mA   -35.92mA   -54.95mA
-810mV    -29.3mA    -21.61mA   -39.32mA
-690mV    -17.14mA   -10.88mA   -23.55mA
-600mV    -9.267mA   -5.265mA   -13.06mA
-540mV    -5.068mA   -2.658mA   -7.239mA
-450mV    -1.182mA   -586.7uA   -1.592mA
-300mV    -18.83uA   -15.98uA   -16.74uA
3V        0A         0A         0A
[Ramp]
| variable   typ   min   max
dV/dt_r  0.6668/0.2934n   0.5695/0.2827n   0.7519/0.2694n
dV/dt_f  0.6668/0.1177n   0.5695/0.1551n   0.7519/0.1020n
R_load = 50.0000
[Rising Waveform]
R_fixture=   50.0000
V_fixture=   1.5000
V_fixture_min=   1.4300
V_fixture_max=   1.5800
|time   V(typ)   V(min)   V(max)
0s        388.7mV    480.7mV    326.9mV
505.1ps   388.7mV    480.7mV    347.2mV
606.1ps   389.1mV    480.7mV    885.2mV
707.1ps   389.5mV    480.7mV    1.166V
909.1ps   1.07V      481.1mV    1.408V
1.111ns   1.322V     563.5mV    1.502V
1.313ns   1.411V     1.126V     1.544V
1.616ns   1.467V     1.333V     1.569V
2.323ns   1.496V     1.415V     1.579V
10ns      1.5V       1.43V      1.58V
[Falling Waveform]
R_fixture=   50.0000
V_fixture=   1.5000
V_fixture_min=   1.4300
V_fixture_max=   1.5800
|time   V(typ)   V(min)   V(max)
0s        1.5V       1.43V      1.58V
505.1ps   1.5V       1.43V      1.581V
606.1ps   1.5V       1.43V      655.5mV
808.1ps   1.472V     1.43V      350.6mV
909.1ps   720.5mV    1.43V      339.3mV
1.212ns   408.1mV    1.431V     328.7mV
1.313ns   401mV      1.35V      327.8mV
1.515ns   393.7mV    614.4mV    327.2mV
1.717ns   390.7mV    510.6mV    327mV
10ns      388.7mV    480.7mV    326.9mV
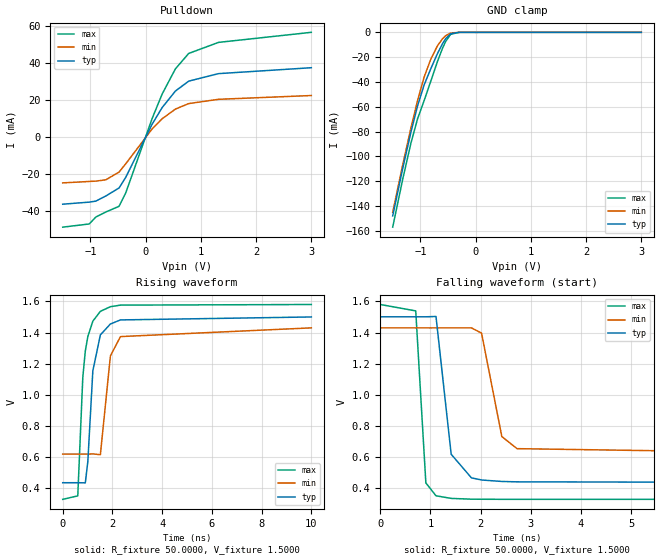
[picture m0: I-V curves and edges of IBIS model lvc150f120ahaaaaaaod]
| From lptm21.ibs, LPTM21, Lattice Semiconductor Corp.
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|   Model lvc150f120ahaaaaaaod
[Model]   lvc150f120ahaaaaaaod
Model_type   I/O_open_drain
Polarity   Non-Inverting
Enable   Active-Low
Vinl =   0.3750V
Vinh =   1.1250V
Vmeas =   0.7500V
Cref =   0.0F
Rref =   1.0000M
Vref =   0.0V
C_comp   4.2000pF   3.8000pF   7.5000pF
[Temperature Range]   25.0000   0.1050k   -40.0000
[Voltage Range]   1.5000V   1.4300V   1.5800V
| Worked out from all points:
|   slope of the pulldown table from 0 to 0.225 V, typ, clamps not added: 18.2 ohm
|   GND clamp passes 1 mA (typ) near -0.44 V on its own axis
|   rising waveform, R_fixture 50.0000, V_fixture 1.5000: 20-80 % time 294ps typ, 300ps min, 302ps max; typ from 0.436 V to 1.5 V
|   falling waveform, R_fixture 50.0000, V_fixture 1.5000: 20-80 % time 173ps typ, 271ps min, 137ps max; typ from 1.5 V to 0.437 V
[Pulldown]
|Voltage   I(typ)   I(min)   I(max)
-1.5V     -36.29mA   -24.8mA    -48.68mA
-1.02V    -35.18mA   -24.04mA   -46.96mA
-900mV    -34.63mA   -23.85mA   -43.22mA
-720mV    -31.87mA   -23.14mA   -40.51mA
-480mV    -27.54mA   -18.97mA   -37.42mA
-360mV    -21.84mA   -14.53mA   -30.28mA
120mV     6.941mA    4.355mA    10.02mA
300mV     15.83mA    9.789mA    23.12mA
540mV     24.73mA    14.99mA    36.7mA
780mV     30.08mA    17.97mA    45.01mA
1.32V     34.13mA    20.28mA    50.98mA
3V        37.32mA    22.32mA    56.41mA
[GND_clamp]
|Voltage   I(typ)   I(min)   I(max)
-1.5V     -148mA     -145.1mA   -157.1mA
-1.32V    -110mA     -107mA     -118.7mA
-1.17V    -80.45mA   -77.09mA   -89.3mA
-1.05V    -59.22mA   -54.99mA   -69.72mA
-930mV    -42.25mA   -35.9mA    -54.92mA
-810mV    -29.28mA   -21.6mA    -39.3mA
-690mV    -17.13mA   -10.87mA   -23.53mA
-600mV    -9.254mA   -5.257mA   -13.04mA
-540mV    -5.058mA   -2.652mA   -7.223mA
-450mV    -1.176mA   -584.6uA   -1.583mA
-300mV    -18.65uA   -15.9uA    -16.45uA
3V        0A         0A         0A
[Ramp]
| variable   typ   min   max
dV/dt_r  0.6385/0.2911n   0.4863/0.2970n   0.7505/0.2989n
dV/dt_f  0.6386/0.1713n   0.4863/0.2682n   0.7505/0.1360n
R_load = 50.0000
[Rising Waveform]
R_fixture=   50.0000
V_fixture=   1.5000
V_fixture_min=   1.4300
V_fixture_max=   1.5800
|time   V(typ)   V(min)   V(max)
0s        435.8mV    619.5mV    329.1mV
606.1ps   435.8mV    619.5mV    351.2mV
808.1ps   435.2mV    619.5mV    1.112V
909.1ps   434.9mV    619.4mV    1.281V
1.01ns    570.2mV    619.5mV    1.374V
1.212ns   1.154V     620.9mV    1.473V
1.515ns   1.385V     615.8mV    1.536V
1.919ns   1.455V     1.25V      1.566V
2.323ns   1.481V     1.374V     1.576V
10ns      1.5V       1.43V      1.58V
[Falling Waveform]
R_fixture=   50.0000
V_fixture=   1.5000
V_fixture_min=   1.4300
V_fixture_max=   1.5800
|time   V(typ)   V(min)   V(max)
0s        1.501V     1.43V      1.58V
707.1ps   1.501V     1.43V      1.539V
909.1ps   1.501V     1.43V      434.4mV
1.111ns   1.503V     1.43V      351.9mV
1.414ns   618.7mV    1.43V      335.1mV
1.818ns   467mV      1.43V      330.1mV
2.02ns    453.2mV    1.396V     329.6mV
2.424ns   443.8mV    732.4mV    329.2mV
2.727ns   441.4mV    654.5mV    329.2mV
10ns      436.7mV    619.5mV    329.1mV
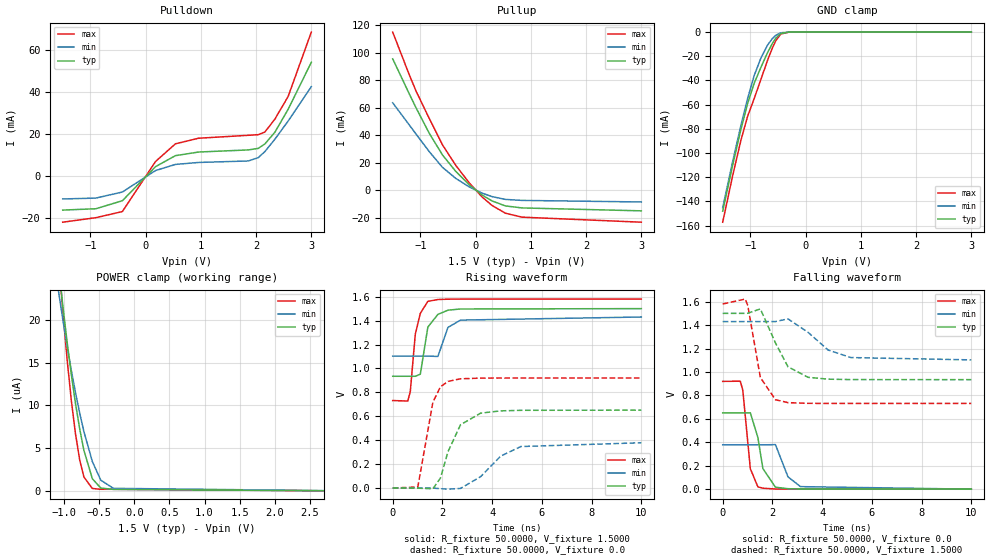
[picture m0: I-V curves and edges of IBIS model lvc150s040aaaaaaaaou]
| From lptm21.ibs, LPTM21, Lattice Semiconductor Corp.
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|   Model lvc150s040aaaaaaaaou
[Model]   lvc150s040aaaaaaaaou
Model_type   Output
Polarity   Non-Inverting
Enable   Active-Low
Vmeas =   0.7500V
Cref =   0.0F
Rref =   1.0000M
Vref =   0.0V
C_comp   3.0000pF   2.7000pF   3.3000pF
[Temperature Range]   25.0000   0.1050k   -40.0000
[Voltage Range]   1.5000V   1.4300V   1.5800V
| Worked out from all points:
|   slope of the pulldown table from 0 to 0.225 V, typ, clamps not added: 42.4 ohm
|   slope of the pullup table from 0 to 0.225 V, typ, clamps not added: 36.2 ohm
|   GND clamp passes 1 mA (typ) near -0.44 V on its own axis
|   rising waveform, R_fixture 50.0000, V_fixture 1.5000: 20-80 % time 322ps typ, 339ps min, 303ps max; typ from 0.934 V to 1.5 V
|   rising waveform, R_fixture 50.0000, V_fixture 0.0: 20-80 % time 719ps typ, 1.17ns min, 468ps max; typ from 0 V to 0.651 V
|   falling waveform, R_fixture 50.0000, V_fixture 0.0: 20-80 % time 330ps typ, 378ps min, 256ps max; typ from 0.651 V to 0 V
|   falling waveform, R_fixture 50.0000, V_fixture 1.5000: 20-80 % time 707ps typ, 1.1ns min, 466ps max; typ from 1.5 V to 0.934 V
[Pulldown]
|Voltage   I(typ)   I(min)   I(max)
-1.5V     -16.19mA   -10.92mA   -21.94mA
-900mV    -15.56mA   -10.5mA    -19.8mA
-420mV    -11.75mA   -7.622mA   -16.89mA
180mV     4.403mA    2.572mA    6.858mA
540mV     9.634mA    5.475mA    15.25mA
960mV     11.36mA    6.409mA    17.91mA
1.86V     12.36mA    7.114mA    19.3mA
2.04V     13.09mA    8.711mA    19.59mA
2.16V     15.21mA    11.58mA    20.86mA
2.34V     20.73mA    17.43mA    26.97mA
2.58V     31.61mA    26.04mA    37.69mA
3V        53.95mA    42.39mA    68.28mA
[Pullup]
|Voltage   I(typ)   I(min)   I(max)
-1.5V     95.61mA    63.63mA    115.1mA
-1.2V     70.1mA     47.5mA     84.01mA
-1.08V    60.19mA    41.01mA    72.36mA
-840mV    41.55mA    28.18mA    52.33mA
-600mV    25.73mA    16.68mA    33.08mA
-360mV    13.75mA    8.644mA    18.16mA
-120mV    4.12mA     2.526mA    5.608mA
120mV     -3.584mA   -2.154mA   -5.009mA
300mV     -7.847mA   -4.67mA    -11.16mA
540mV     -11.43mA   -6.696mA   -16.74mA
840mV     -12.9mA    -7.425mA   -19.62mA
3V        -15.02mA   -8.563mA   -23.28mA
[GND_clamp]
|Voltage   I(typ)   I(min)   I(max)
-1.5V     -148mA     -145.1mA   -157.1mA
-1.32V    -110mA     -107mA     -118.7mA
-1.17V    -80.44mA   -77.06mA   -89.3mA
-1.05V    -59.22mA   -54.98mA   -69.71mA
-930mV    -42.25mA   -35.9mA    -54.91mA
-810mV    -29.28mA   -21.6mA    -39.29mA
-690mV    -17.12mA   -10.87mA   -23.53mA
-600mV    -9.252mA   -5.256mA   -13.04mA
-540mV    -5.056mA   -2.651mA   -7.221mA
-450mV    -1.176mA   -584.3uA   -1.582mA
-300mV    -18.62uA   -15.88uA   -16.42uA
3V        0A         0A         0A
[POWER_clamp]
|Voltage   I(typ)   I(min)   I(max)
-1.5V     65.7uA     49.01uA    83.9uA
-1.08V    26.1uA     23.2uA     27.01uA
-1.02V    21.58uA    19.96uA    20.86uA
-960mV    17.41uA    16.92uA    15.37uA
-900mV    13.6uA     14.08uA    10.59uA
-840mV    10.19uA    11.46uA    6.626uA
-780mV    7.21uA     9.061uA    3.586uA
-720mV    4.707uA    6.902uA    1.591uA
-600mV    1.397uA    3.404uA    251.1nA
-480mV    304nA      1.233uA    162.2nA
-300mV    146.9nA    271.2nA    162.2nA
3V        -25.84nA   -23.03nA   -33.01nA
[Ramp]
| variable   typ   min   max
dV/dt_r  0.3479/0.7174n   0.2270/1.1600n   0.5518/0.4629n
dV/dt_f  0.3393/0.7002n   0.1964/1.0879n   0.5091/0.4615n
R_load = 50.0000
[Rising Waveform]
R_fixture=   50.0000
V_fixture=   1.5000
V_fixture_min=   1.4300
V_fixture_max=   1.5800
|time   V(typ)   V(min)   V(max)
0s        934.4mV    1.103V     731.4mV
606.1ps   934.4mV    1.103V     727mV
707.1ps   934.5mV    1.103V     806.3mV
909.1ps   934.2mV    1.103V     1.287V
1.111ns   951.6mV    1.103V     1.461V
1.414ns   1.346V     1.103V     1.561V
1.818ns   1.452V     1.1V       1.576V
2.222ns   1.487V     1.343V     1.579V
2.727ns   1.497V     1.404V     1.58V
10ns      1.5V       1.43V      1.58V
[Rising Waveform]
R_fixture=   50.0000
V_fixture=   0.0
V_fixture_min=   0.0
V_fixture_max=   0.0
|time   V(typ)   V(min)   V(max)
0s        510.1nV    728.2nV    394.5nV
1.01ns    -1.515mV   4.149uV    8.18mV
1.616ns   -6.47mV    -638.9uV   717mV
1.919ns   82.42mV    -6.075mV   846.4mV
2.222ns   302.8mV    -9.841mV   891.2mV
2.727ns   528.6mV    -3.695mV   913.2mV
3.535ns   625.8mV    94.3mV     918.9mV
4.343ns   644.9mV    266.7mV    919.6mV
5.152ns   649.6mV    346.6mV    919.7mV
10ns      651mV      378.3mV    919.7mV
[Falling Waveform]
R_fixture=   50.0000
V_fixture=   0.0
V_fixture_min=   0.0
V_fixture_max=   0.0
|time   V(typ)   V(min)   V(max)
0s        651mV      378.4mV    919.7mV
707.1ps   651mV      378.4mV    921.3mV
808.1ps   651mV      378.4mV    845mV
1.111ns   651.3mV    378.4mV    174.6mV
1.414ns   441.7mV    378.3mV    19.62mV
1.616ns   176mV      378.3mV    8.27mV
2.121ns   16.7mV     379.9mV    1.212mV
2.626ns   3.936mV    104.9mV    215uV
3.131ns   1.205mV    21.66mV    60.66uV
10ns      -12.95uV   14.81uV    3.658uV
[Falling Waveform]
R_fixture=   50.0000
V_fixture=   1.5000
V_fixture_min=   1.4300
V_fixture_max=   1.5800
|time   V(typ)   V(min)   V(max)
0s        1.5V       1.43V      1.58V
909.1ps   1.5V       1.43V      1.622V
1.01ns    1.501V     1.43V      1.565V
1.515ns   1.538V     1.43V      952.7mV
2.121ns   1.248V     1.43V      763.1mV
2.626ns   1.044V     1.453V     738.4mV
3.434ns   954.4mV    1.338V     732.2mV
4.242ns   938.5mV    1.187V     731.6mV
5.152ns   935mV      1.123V     731.6mV
10ns      934.4mV    1.103V     731.5mV
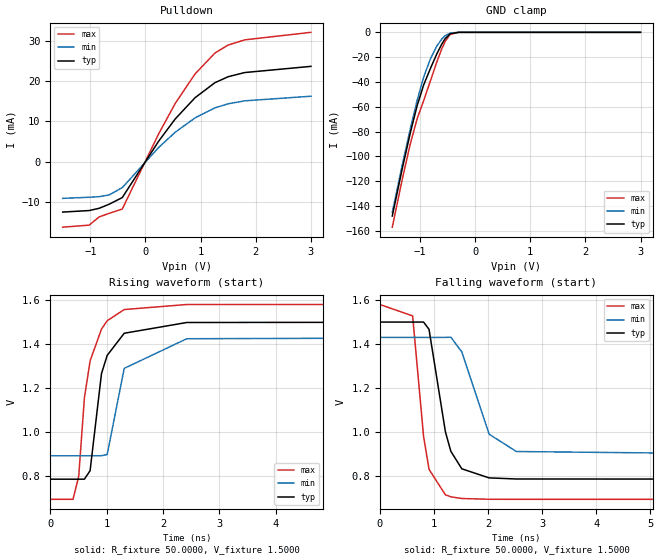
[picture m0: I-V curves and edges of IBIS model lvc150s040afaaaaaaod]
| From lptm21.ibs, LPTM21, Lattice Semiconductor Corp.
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|   Model lvc150s040afaaaaaaod
[Model]   lvc150s040afaaaaaaod
Model_type   I/O_open_drain
Polarity   Non-Inverting
Enable   Active-Low
Vinl =   0.3750V
Vinh =   1.1250V
Vmeas =   0.7500V
Cref =   0.0F
Rref =   1.0000M
Vref =   0.0V
C_comp   4.2000pF   3.8000pF   7.5000pF
[Temperature Range]   25.0000   0.1050k   -40.0000
[Voltage Range]   1.5000V   1.4300V   1.5800V
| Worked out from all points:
|   slope of the pulldown table from 0 to 0.225 V, typ, clamps not added: 46.8 ohm
|   GND clamp passes 1 mA (typ) near -0.44 V on its own axis
|   rising waveform, R_fixture 50.0000, V_fixture 1.5000: 20-80 % time 284ps typ, 295ps min, 272ps max; typ from 0.784 V to 1.5 V
|   falling waveform, R_fixture 50.0000, V_fixture 1.5000: 20-80 % time 309ps typ, 435ps min, 231ps max; typ from 1.5 V to 0.784 V
[Pulldown]
|Voltage   I(typ)   I(min)   I(max)
-1.5V     -12.44mA   -9.05mA    -16.17mA
-1.02V    -12.06mA   -8.773mA   -15.67mA
-840mV    -11.51mA   -8.628mA   -13.65mA
-660mV    -10.51mA   -8.22mA    -12.76mA
-420mV    -8.853mA   -6.399mA   -11.69mA
240mV     5.112mA    3.55mA     6.922mA
540mV     10.6mA     7.314mA    14.44mA
900mV     15.86mA    10.86mA    21.74mA
1.26V     19.57mA    13.34mA    26.91mA
1.5V      21.05mA    14.35mA    28.88mA
1.8V      22.08mA    15.08mA    30.17mA
3V        23.61mA    16.22mA    32.03mA
[GND_clamp]
|Voltage   I(typ)   I(min)   I(max)
-1.5V     -148.1mA   -145.2mA   -157.1mA
-1.32V    -110.1mA   -107mA     -118.7mA
-1.17V    -80.47mA   -77.11mA   -89.33mA
-1.05V    -59.24mA   -55.01mA   -69.75mA
-930mV    -42.27mA   -35.92mA   -54.95mA
-810mV    -29.3mA    -21.61mA   -39.32mA
-690mV    -17.14mA   -10.88mA   -23.55mA
-600mV    -9.267mA   -5.265mA   -13.06mA
-540mV    -5.068mA   -2.658mA   -7.239mA
-450mV    -1.182mA   -586.7uA   -1.592mA
-300mV    -18.83uA   -15.98uA   -16.74uA
3V        0A         0A         0A
[Ramp]
| variable   typ   min   max
dV/dt_r  0.4296/0.2816n   0.3235/0.2918n   0.5327/0.2692n
dV/dt_f  0.4296/0.3063n   0.3235/0.4311n   0.5327/0.2285n
R_load = 50.0000
[Rising Waveform]
R_fixture=   50.0000
V_fixture=   1.5000
V_fixture_min=   1.4300
V_fixture_max=   1.5800
|time   V(typ)   V(min)   V(max)
0s        784mV      890.8mV    692.2mV
404ps     784mV      890.8mV    692.3mV
505.1ps   784mV      890.8mV    798mV
606.1ps   784.1mV    890.8mV    1.155V
707.1ps   822.8mV    890.8mV    1.323V
909.1ps   1.265V     891mV      1.468V
1.01ns    1.348V     896.2mV    1.506V
1.313ns   1.449V     1.289V     1.557V
2.424ns   1.498V     1.424V     1.58V
10ns      1.5V       1.43V      1.58V
[Falling Waveform]
R_fixture=   50.0000
V_fixture=   1.5000
V_fixture_min=   1.4300
V_fixture_max=   1.5800
|time   V(typ)   V(min)   V(max)
0s        1.5V       1.43V      1.58V
606.1ps   1.5V       1.43V      1.528V
808.1ps   1.5V       1.43V      979.4mV
909.1ps   1.467V     1.43V      829.1mV
1.212ns   1V         1.43V      712.7mV
1.313ns   911mV      1.431V     703.7mV
1.515ns   831.3mV    1.364V     695.9mV
2.02ns    789.9mV    989.1mV    692.5mV
2.525ns   784.9mV    910.1mV    692.2mV
10ns      784mV      890.8mV    692.2mV
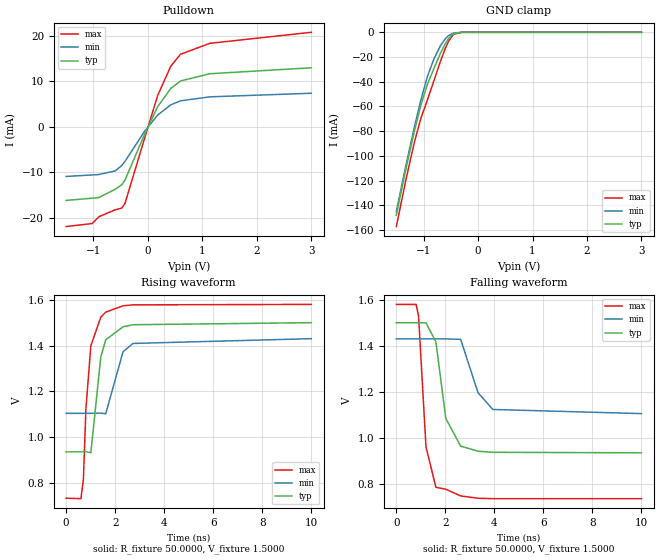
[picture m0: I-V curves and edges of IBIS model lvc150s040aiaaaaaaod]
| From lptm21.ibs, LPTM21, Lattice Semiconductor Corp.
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|   Model lvc150s040aiaaaaaaod
[Model]   lvc150s040aiaaaaaaod
Model_type   I/O_open_drain
Polarity   Non-Inverting
Enable   Active-Low
Vinl =   0.3750V
Vinh =   1.1250V
Vmeas =   0.7500V
Cref =   0.0F
Rref =   1.0000M
Vref =   0.0V
C_comp   4.2000pF   3.8000pF   7.5000pF
[Temperature Range]   25.0000   0.1050k   -40.0000
[Voltage Range]   1.5000V   1.4300V   1.5800V
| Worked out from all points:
|   slope of the pulldown table from 0 to 0.225 V, typ, clamps not added: 42.4 ohm
|   GND clamp passes 1 mA (typ) near -0.44 V on its own axis
|   rising waveform, R_fixture 50.0000, V_fixture 1.5000: 20-80 % time 313ps typ, 329ps min, 297ps max; typ from 0.934 V to 1.5 V
|   falling waveform, R_fixture 50.0000, V_fixture 1.5000: 20-80 % time 464ps typ, 583ps min, 293ps max; typ from 1.5 V to 0.934 V
[Pulldown]
|Voltage   I(typ)   I(min)   I(max)
-1.5V     -16.19mA   -10.92mA   -21.94mA
-1.02V    -15.7mA    -10.59mA   -21.27mA
-900mV    -15.56mA   -10.5mA    -19.8mA
-600mV    -13.74mA   -9.7mA     -18.26mA
-480mV    -12.77mA   -8.548mA   -17.88mA
-420mV    -11.75mA   -7.622mA   -16.89mA
-60mV     -1.68mA    -1.008mA   -2.556mA
180mV     4.403mA    2.572mA    6.858mA
420mV     8.409mA    4.818mA    13.28mA
600mV     10.07mA    5.709mA    15.95mA
1.14V     11.66mA    6.58mA     18.35mA
3V        12.97mA    7.372mA    20.77mA
[GND_clamp]
|Voltage   I(typ)   I(min)   I(max)
-1.5V     -148mA     -145.1mA   -157.1mA
-1.32V    -110mA     -107mA     -118.7mA
-1.17V    -80.44mA   -77.06mA   -89.3mA
-1.05V    -59.22mA   -54.98mA   -69.71mA
-930mV    -42.25mA   -35.9mA    -54.91mA
-810mV    -29.28mA   -21.6mA    -39.29mA
-690mV    -17.12mA   -10.87mA   -23.53mA
-600mV    -9.252mA   -5.256mA   -13.04mA
-540mV    -5.056mA   -2.651mA   -7.221mA
-450mV    -1.176mA   -584.3uA   -1.582mA
-300mV    -18.62uA   -15.88uA   -16.42uA
3V        0A         0A         0A
[Ramp]
| variable   typ   min   max
dV/dt_r  0.3394/0.3102n   0.1964/0.3257n   0.5091/0.2942n
dV/dt_f  0.3386/0.4002n   0.1964/0.6473n   0.5070/0.2902n
R_load = 50.0000
[Rising Waveform]
R_fixture=   50.0000
V_fixture=   1.5000
V_fixture_min=   1.4300
V_fixture_max=   1.5800
|time   V(typ)   V(min)   V(max)
0s        934.4mV    1.103V     731.4mV
606.1ps   934.4mV    1.103V     729.3mV
707.1ps   934.5mV    1.103V     815mV
808.1ps   934.9mV    1.103V     1.122V
1.01ns    930.7mV    1.103V     1.399V
1.414ns   1.349V     1.104V     1.524V
1.616ns   1.425V     1.101V     1.546V
2.323ns   1.482V     1.373V     1.574V
2.727ns   1.491V     1.409V     1.578V
10ns      1.5V       1.43V      1.58V
[Falling Waveform]
R_fixture=   50.0000
V_fixture=   1.5000
V_fixture_min=   1.4300
V_fixture_max=   1.5800
|time   V(typ)   V(min)   V(max)
0s        1.5V       1.43V      1.58V
808.1ps   1.5V       1.43V      1.58V
909.1ps   1.5V       1.43V      1.529V
1.212ns   1.5V       1.43V      959.6mV
1.616ns   1.417V     1.43V      784.4mV
2.02ns    1.084V     1.43V      776mV
2.626ns   963.5mV    1.428V     747mV
3.333ns   941.5mV    1.196V     736.8mV
3.939ns   936.7mV    1.123V     735mV
10ns      934.4mV    1.105V     735mV
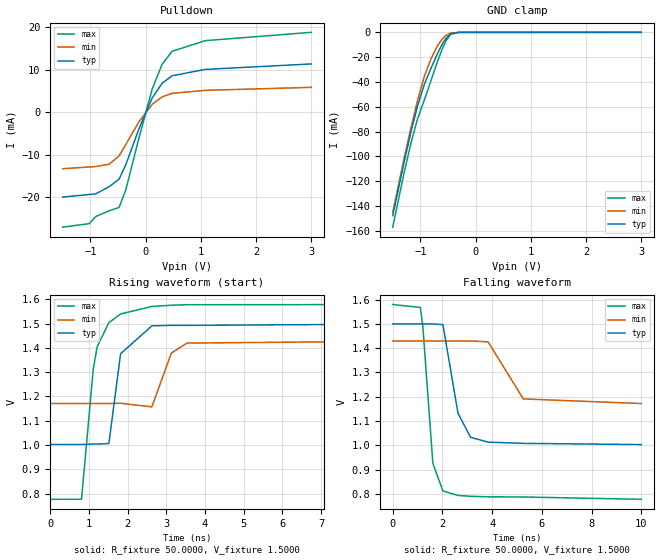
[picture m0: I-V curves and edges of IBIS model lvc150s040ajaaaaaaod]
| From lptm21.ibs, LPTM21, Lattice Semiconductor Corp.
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|   Model lvc150s040ajaaaaaaod
[Model]   lvc150s040ajaaaaaaod
Model_type   I/O_open_drain
Polarity   Non-Inverting
Enable   Active-Low
Vinl =   0.3750V
Vinh =   1.1250V
Vmeas =   0.7500V
Cref =   0.0F
Rref =   1.0000M
Vref =   0.0V
C_comp   4.2000pF   3.8000pF   7.5000pF
[Temperature Range]   25.0000   0.1050k   -40.0000
[Voltage Range]   1.5000V   1.4300V   1.5800V
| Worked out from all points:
|   slope of the pulldown table from 0 to 0.225 V, typ, clamps not added: 40.5 ohm
|   GND clamp passes 1 mA (typ) near -0.44 V on its own axis
|   rising waveform, R_fixture 50.0000, V_fixture 1.5000: 20-80 % time 258ps typ, 302ps min, 307ps max; typ from 1 V to 1.5 V
|   falling waveform, R_fixture 50.0000, V_fixture 1.5000: 20-80 % time 492ps typ, 756ps min, 346ps max; typ from 1.5 V to 1 V
[Pulldown]
|Voltage   I(typ)   I(min)   I(max)
-1.5V     -20.01mA   -13.33mA   -27.09mA
-1.02V    -19.4mA    -12.92mA   -26.26mA
-900mV    -19.23mA   -12.82mA   -24.57mA
-660mV    -17.57mA   -12.28mA   -23.23mA
-480mV    -15.79mA   -10.32mA   -22.45mA
-360mV    -12.45mA   -7.709mA   -18.4mA
-120mV    -3.929mA   -2.278mA   -6.111mA
120mV     3.345mA    1.822mA    5.45mA
300mV     6.792mA    3.593mA    11.27mA
480mV     8.549mA    4.413mA    14.32mA
1.08V     10.05mA    5.125mA    16.82mA
3V        11.34mA    5.826mA    18.78mA
[GND_clamp]
|Voltage   I(typ)   I(min)   I(max)
-1.5V     -147.9mA   -145mA     -157mA
-1.29V    -103.8mA   -100.8mA   -112.5mA
-1.17V    -80.38mA   -77mA      -89.28mA
-1.05V    -59.17mA   -54.93mA   -69.71mA
-930mV    -42.22mA   -35.86mA   -54.91mA
-810mV    -29.28mA   -21.58mA   -39.29mA
-690mV    -17.12mA   -10.87mA   -23.53mA
-600mV    -9.251mA   -5.255mA   -13.04mA
-540mV    -5.055mA   -2.651mA   -7.219mA
-450mV    -1.175mA   -584uA     -1.58mA
-300mV    -18.6uA    -15.87uA   -16.38uA
3V        0A         0A         0A
[Ramp]
| variable   typ   min   max
dV/dt_r  0.2983/0.3011n   0.1548/0.2990n   0.4820/0.3043n
dV/dt_f  0.2980/0.4867n   0.1546/0.7480n   0.4816/0.3423n
R_load = 50.0000
[Rising Waveform]
R_fixture=   50.0000
V_fixture=   1.5000
V_fixture_min=   1.4300
V_fixture_max=   1.5800
|time   V(typ)   V(min)   V(max)
0s        1.002V     1.171V     776.1mV
808.1ps   1.002V     1.171V     776.6mV
1.111ns   1.004V     1.171V     1.313V
1.212ns   1.004V     1.171V     1.405V
1.515ns   1.006V     1.171V     1.504V
1.818ns   1.376V     1.172V     1.54V
2.626ns   1.491V     1.157V     1.571V
3.131ns   1.493V     1.379V     1.576V
3.535ns   1.493V     1.42V      1.578V
10ns      1.499V     1.429V     1.579V
[Falling Waveform]
R_fixture=   50.0000
V_fixture=   1.5000
V_fixture_min=   1.4300
V_fixture_max=   1.5800
|time   V(typ)   V(min)   V(max)
0s        1.5V       1.43V      1.58V
1.111ns   1.5V       1.43V      1.568V
1.212ns   1.5V       1.43V      1.49V
1.616ns   1.5V       1.43V      925.3mV
2.02ns    1.497V     1.43V      811.7mV
2.626ns   1.132V     1.43V      793.4mV
3.131ns   1.033V     1.43V      789.9mV
3.838ns   1.013V     1.426V     787.8mV
5.253ns   1.008V     1.191V     787.1mV
10ns      1.003V     1.172V     777.4mV
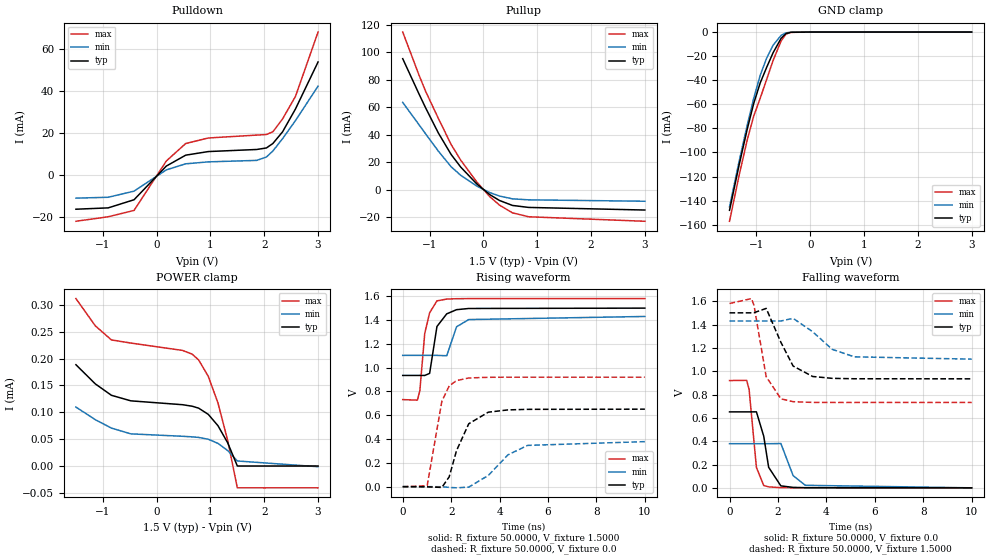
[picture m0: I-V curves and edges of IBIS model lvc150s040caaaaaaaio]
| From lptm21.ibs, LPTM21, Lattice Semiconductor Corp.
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|   Model lvc150s040caaaaaaaio
[Model]   lvc150s040caaaaaaaio
Model_type   I/O
Polarity   Non-Inverting
Enable   Active-Low
Vinl =   0.3750V
Vinh =   1.1250V
Vmeas =   0.7500V
Cref =   0.0F
Rref =   1.0000M
Vref =   0.0V
C_comp   3.0000pF   2.7000pF   3.3000pF
[Temperature Range]   25.0000   0.1050k   -40.0000
[Voltage Range]   1.5000V   1.4300V   1.5800V
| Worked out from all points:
|   slope of the pulldown table from 0 to 0.225 V, typ, clamps not added: 42.8 ohm
|   slope of the pullup table from 0 to 0.225 V, typ, clamps not added: 36.2 ohm
|   GND clamp passes 1 mA (typ) near -0.44 V on its own axis
|   rising waveform, R_fixture 50.0000, V_fixture 1.5000: 20-80 % time 322ps typ, 339ps min, 303ps max; typ from 0.934 V to 1.5 V
|   rising waveform, R_fixture 50.0000, V_fixture 0.0: 20-80 % time 719ps typ, 1.17ns min, 468ps max; typ from 0 V to 0.651 V
|   falling waveform, R_fixture 50.0000, V_fixture 0.0: 20-80 % time 330ps typ, 378ps min, 256ps max; typ from 0.651 V to 0 V
|   falling waveform, R_fixture 50.0000, V_fixture 1.5000: 20-80 % time 707ps typ, 1.1ns min, 466ps max; typ from 1.5 V to 0.934 V
[Pulldown]
|Voltage   I(typ)   I(min)   I(max)
-1.5V     -16.15mA   -10.89mA   -21.88mA
-900mV    -15.51mA   -10.47mA   -19.73mA
-420mV    -11.65mA   -7.561mA   -16.73mA
180mV     4.36mA     2.55mA     6.777mA
540mV     9.538mA    5.428mA    15.07mA
960mV     11.25mA    6.355mA    17.7mA
1.86V     12.24mA    7.056mA    19.08mA
2.04V     12.97mA    8.653mA    19.36mA
2.16V     15.08mA    11.52mA    20.63mA
2.34V     20.61mA    17.37mA    26.74mA
2.58V     31.49mA    25.98mA    37.46mA
3V        53.83mA    42.33mA    68.05mA
[Pullup]
|Voltage   I(typ)   I(min)   I(max)
-1.5V     95.47mA    63.57mA    114.9mA
-1.2V     69.96mA    47.44mA    83.78mA
-1.08V    60.05mA    40.95mA    72.14mA
-840mV    41.42mA    28.13mA    52.1mA
-600mV    25.59mA    16.62mA    32.85mA
-420mV    16.32mA    10.35mA    21.33mA
-120mV    3.987mA    2.469mA    5.382mA
120mV     -3.716mA   -2.21mA    -5.232mA
300mV     -7.977mA   -4.726mA   -11.38mA
540mV     -11.56mA   -6.75mA    -16.96mA
840mV     -13.01mA   -7.474mA   -19.82mA
3V        -14.91mA   -8.505mA   -23.11mA
[GND_clamp]
|Voltage   I(typ)   I(min)   I(max)
-1.5V     -148mA     -145.1mA   -157.1mA
-1.32V    -110mA     -107mA     -118.7mA
-1.17V    -80.48mA   -77.09mA   -89.35mA
-1.05V    -59.26mA   -55.01mA   -69.77mA
-930mV    -42.29mA   -35.93mA   -54.98mA
-810mV    -29.33mA   -21.63mA   -39.36mA
-690mV    -17.18mA   -10.91mA   -23.6mA
-540mV    -5.131mA   -2.707mA   -7.327mA
-450mV    -1.269mA   -646.6uA   -1.725mA
-360mV    -213.6uA   -130.7uA   -279.5uA
0V        0A         0A         0A
3V        0A         0A         0A
[POWER_clamp]
|Voltage   I(typ)   I(min)   I(max)
-1.5V     188.7uA    109.8uA    311.9uA
-1.14V    153uA      86.3uA     261.2uA
-840mV    131.7uA    70.61uA    234.9uA
-480mV    121.4uA    59.86uA    229.1uA
480mV     114.2uA    55.36uA    215.4uA
660mV     111.4uA    54.29uA    208.4uA
780mV     107.8uA    53.22uA    197.7uA
960mV     96.18uA    49.83uA    167uA
1.14V     75.06uA    42.11uA    117.4uA
1.32V     43.25uA    28.83uA    47.75uA
1.5V      -25.18nA   9.33uA     -40.71uA
3V        -25.18nA   -1.33uA    -40.71uA
[Ramp]
| variable   typ   min   max
dV/dt_r  0.3479/0.7174n   0.2270/1.1600n   0.5518/0.4629n
dV/dt_f  0.3393/0.7002n   0.1964/1.0879n   0.5091/0.4615n
R_load = 50.0000
[Rising Waveform]
R_fixture=   50.0000
V_fixture=   1.5000
V_fixture_min=   1.4300
V_fixture_max=   1.5800
|time   V(typ)   V(min)   V(max)
0s        934.4mV    1.103V     731.4mV
606.1ps   934.4mV    1.103V     727mV
707.1ps   934.5mV    1.103V     806.3mV
909.1ps   934.2mV    1.103V     1.287V
1.111ns   951.6mV    1.103V     1.461V
1.414ns   1.346V     1.103V     1.561V
1.818ns   1.452V     1.1V       1.576V
2.222ns   1.487V     1.343V     1.579V
2.727ns   1.497V     1.404V     1.58V
10ns      1.5V       1.43V      1.58V
[Rising Waveform]
R_fixture=   50.0000
V_fixture=   0.0
V_fixture_min=   0.0
V_fixture_max=   0.0
|time   V(typ)   V(min)   V(max)
0s        510.1nV    728.2nV    394.5nV
1.01ns    -1.515mV   4.149uV    8.18mV
1.616ns   -6.47mV    -638.9uV   717mV
1.919ns   82.42mV    -6.075mV   846.4mV
2.222ns   302.8mV    -9.841mV   891.2mV
2.727ns   528.6mV    -3.695mV   913.2mV
3.535ns   625.8mV    94.3mV     918.9mV
4.343ns   644.9mV    266.7mV    919.6mV
5.152ns   649.6mV    346.6mV    919.7mV
10ns      651mV      378.3mV    919.7mV
[Falling Waveform]
R_fixture=   50.0000
V_fixture=   0.0
V_fixture_min=   0.0
V_fixture_max=   0.0
|time   V(typ)   V(min)   V(max)
0s        651mV      378.4mV    919.7mV
707.1ps   651mV      378.4mV    921.3mV
808.1ps   651mV      378.4mV    845mV
1.111ns   651.3mV    378.4mV    174.6mV
1.414ns   441.7mV    378.3mV    19.62mV
1.616ns   176mV      378.3mV    8.27mV
2.121ns   16.7mV     379.9mV    1.212mV
2.626ns   3.936mV    104.9mV    215uV
3.131ns   1.205mV    21.66mV    60.66uV
10ns      -12.95uV   14.81uV    3.658uV
[Falling Waveform]
R_fixture=   50.0000
V_fixture=   1.5000
V_fixture_min=   1.4300
V_fixture_max=   1.5800
|time   V(typ)   V(min)   V(max)
0s        1.5V       1.43V      1.58V
909.1ps   1.5V       1.43V      1.622V
1.01ns    1.501V     1.43V      1.565V
1.515ns   1.538V     1.43V      952.7mV
2.121ns   1.248V     1.43V      763.1mV
2.626ns   1.044V     1.453V     738.4mV
3.434ns   954.4mV    1.338V     732.2mV
4.242ns   938.5mV    1.187V     731.6mV
5.152ns   935mV      1.123V     731.6mV
10ns      934.4mV    1.103V     731.5mV
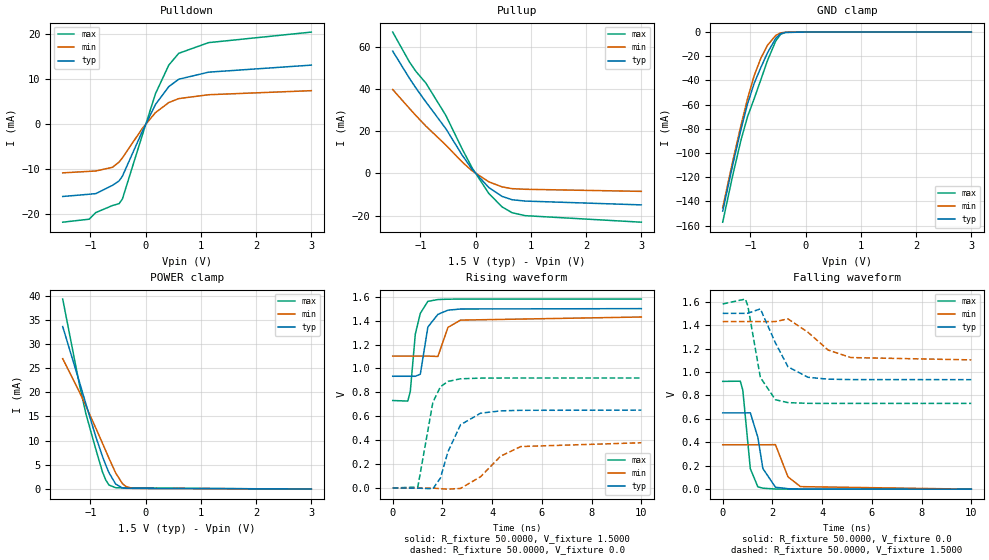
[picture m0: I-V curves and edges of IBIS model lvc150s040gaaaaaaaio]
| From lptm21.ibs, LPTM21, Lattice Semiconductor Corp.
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|   Model lvc150s040gaaaaaaaio
[Model]   lvc150s040gaaaaaaaio
Model_type   I/O
Polarity   Non-Inverting
Enable   Active-Low
Vinl =   0.3750V
Vinh =   1.1250V
Vmeas =   0.7500V
Cref =   0.0F
Rref =   1.0000M
Vref =   0.0V
C_comp   3.0000pF   2.7000pF   3.3000pF
[Temperature Range]   25.0000   0.1050k   -40.0000
[Voltage Range]   1.5000V   1.4300V   1.5800V
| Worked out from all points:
|   slope of the pulldown table from 0 to 0.225 V, typ, clamps not added: 42.8 ohm
|   slope of the pullup table from 0 to 0.225 V, typ, clamps not added: 36.2 ohm
|   GND clamp passes 1 mA (typ) near -0.44 V on its own axis
|   POWER clamp passes 1 mA (typ) near -0.54 V on its own axis
|   rising waveform, R_fixture 50.0000, V_fixture 1.5000: 20-80 % time 322ps typ, 339ps min, 303ps max; typ from 0.934 V to 1.5 V
|   rising waveform, R_fixture 50.0000, V_fixture 0.0: 20-80 % time 719ps typ, 1.17ns min, 468ps max; typ from 0 V to 0.651 V
|   falling waveform, R_fixture 50.0000, V_fixture 0.0: 20-80 % time 330ps typ, 378ps min, 256ps max; typ from 0.651 V to 0 V
|   falling waveform, R_fixture 50.0000, V_fixture 1.5000: 20-80 % time 707ps typ, 1.1ns min, 466ps max; typ from 1.5 V to 0.934 V
[Pulldown]
|Voltage   I(typ)   I(min)   I(max)
-1.5V     -16.15mA   -10.89mA   -21.88mA
-1.02V    -15.65mA   -10.55mA   -21.21mA
-900mV    -15.51mA   -10.47mA   -19.73mA
-600mV    -13.68mA   -9.651mA   -18.17mA
-480mV    -12.68mA   -8.487mA   -17.75mA
-420mV    -11.65mA   -7.561mA   -16.73mA
-60mV     -1.663mA   -999.7uA   -2.526mA
180mV     4.36mA     2.55mA     6.777mA
420mV     8.326mA    4.776mA    13.12mA
600mV     9.972mA    5.659mA    15.75mA
1.14V     11.55mA    6.524mA    18.13mA
3V        13.12mA    7.426mA    20.48mA
[Pullup]
|Voltage   I(typ)   I(min)   I(max)
-1.5V     57.96mA    39.76mA    66.97mA
-1.2V     45.18mA    30.87mA    52.92mA
-1.08V    40.47mA    27.41mA    48.34mA
-900mV    33.9mA     22.44mA    42.82mA
-540mV    21.27mA    13.49mA    27.58mA
-240mV    8.569mA    5.346mA    11.45mA
-60mV     1.867mA    1.161mA    2.519mA
240mV     -6.706mA   -3.982mA   -9.516mA
480mV     -10.89mA   -6.386mA   -15.85mA
660mV     -12.46mA   -7.217mA   -18.61mA
900mV     -13.1mA    -7.518mA   -20.02mA
3V        -14.91mA   -8.505mA   -23.11mA
[GND_clamp]
|Voltage   I(typ)   I(min)   I(max)
-1.5V     -148mA     -145.1mA   -157.1mA
-1.32V    -110mA     -107mA     -118.7mA
-1.17V    -80.48mA   -77.09mA   -89.35mA
-1.05V    -59.26mA   -55.01mA   -69.77mA
-930mV    -42.29mA   -35.93mA   -54.98mA
-810mV    -29.33mA   -21.63mA   -39.36mA
-690mV    -17.18mA   -10.91mA   -23.6mA
-540mV    -5.131mA   -2.707mA   -7.327mA
-450mV    -1.269mA   -646.6uA   -1.725mA
-360mV    -213.6uA   -130.7uA   -279.5uA
0V        0A         0A         0A
3V        0A         0A         0A
[POWER_clamp]
|Voltage   I(typ)   I(min)   I(max)
-1.5V     33.6mA     26.96mA    39.3mA
-1.2V     22.23mA    20.13mA    21.75mA
-1.08V    17.59mA    17.16mA    15.56mA
-900mV    10.78mA    12.58mA    8.18mA
-780mV    6.728mA    9.453mA    3.516mA
-720mV    4.925mA    7.87mA     1.844mA
-660mV    3.313mA    6.291mA    793.6uA
-540mV    997.8uA    3.293mA    253uA
-420mV    212.5uA    1.125mA    228.2uA
-360mV    145.3uA    543uA      226.9uA
-240mV    121.5uA    119.5uA    225.5uA
3V        -25.18nA   -1.33uA    -40.71uA
[Ramp]
| variable   typ   min   max
dV/dt_r  0.3479/0.7174n   0.2270/1.1600n   0.5518/0.4629n
dV/dt_f  0.3393/0.7002n   0.1964/1.0879n   0.5091/0.4615n
R_load = 50.0000
[Rising Waveform]
R_fixture=   50.0000
V_fixture=   1.5000
V_fixture_min=   1.4300
V_fixture_max=   1.5800
|time   V(typ)   V(min)   V(max)
0s        934.4mV    1.103V     731.4mV
606.1ps   934.4mV    1.103V     727mV
707.1ps   934.5mV    1.103V     806.3mV
909.1ps   934.2mV    1.103V     1.287V
1.111ns   951.6mV    1.103V     1.461V
1.414ns   1.346V     1.103V     1.561V
1.818ns   1.452V     1.1V       1.576V
2.222ns   1.487V     1.343V     1.579V
2.727ns   1.497V     1.404V     1.58V
10ns      1.5V       1.43V      1.58V
[Rising Waveform]
R_fixture=   50.0000
V_fixture=   0.0
V_fixture_min=   0.0
V_fixture_max=   0.0
|time   V(typ)   V(min)   V(max)
0s        510.1nV    728.2nV    394.5nV
1.01ns    -1.515mV   4.149uV    8.18mV
1.616ns   -6.47mV    -638.9uV   717mV
1.919ns   82.42mV    -6.075mV   846.4mV
2.222ns   302.8mV    -9.841mV   891.2mV
2.727ns   528.6mV    -3.695mV   913.2mV
3.535ns   625.8mV    94.3mV     918.9mV
4.343ns   644.9mV    266.7mV    919.6mV
5.152ns   649.6mV    346.6mV    919.7mV
10ns      651mV      378.3mV    919.7mV
[Falling Waveform]
R_fixture=   50.0000
V_fixture=   0.0
V_fixture_min=   0.0
V_fixture_max=   0.0
|time   V(typ)   V(min)   V(max)
0s        651mV      378.4mV    919.7mV
707.1ps   651mV      378.4mV    921.3mV
808.1ps   651mV      378.4mV    845mV
1.111ns   651.3mV    378.4mV    174.6mV
1.414ns   441.7mV    378.3mV    19.62mV
1.616ns   176mV      378.3mV    8.27mV
2.121ns   16.7mV     379.9mV    1.212mV
2.626ns   3.936mV    104.9mV    215uV
3.131ns   1.205mV    21.66mV    60.66uV
10ns      -12.95uV   14.81uV    3.658uV
[Falling Waveform]
R_fixture=   50.0000
V_fixture=   1.5000
V_fixture_min=   1.4300
V_fixture_max=   1.5800
|time   V(typ)   V(min)   V(max)
0s        1.5V       1.43V      1.58V
909.1ps   1.5V       1.43V      1.622V
1.01ns    1.501V     1.43V      1.565V
1.515ns   1.538V     1.43V      952.7mV
2.121ns   1.248V     1.43V      763.1mV
2.626ns   1.044V     1.453V     738.4mV
3.434ns   954.4mV    1.338V     732.2mV
4.242ns   938.5mV    1.187V     731.6mV
5.152ns   935mV      1.123V     731.6mV
10ns      934.4mV    1.103V     731.5mV
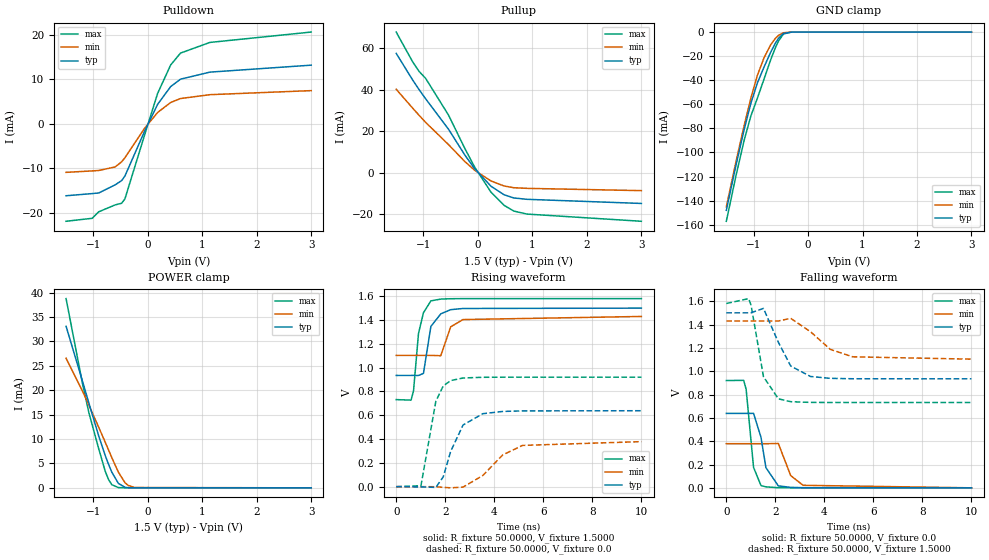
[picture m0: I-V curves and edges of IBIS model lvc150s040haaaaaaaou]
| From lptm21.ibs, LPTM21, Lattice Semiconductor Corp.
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|   Model lvc150s040haaaaaaaou
[Model]   lvc150s040haaaaaaaou
Model_type   Output
Polarity   Non-Inverting
Enable   Active-Low
Vmeas =   0.7500V
Cref =   0.0F
Rref =   1.0000M
Vref =   0.0V
C_comp   3.0000pF   2.7000pF   3.3000pF
[Temperature Range]   25.0000   0.1050k   -40.0000
[Voltage Range]   1.5000V   1.4300V   1.5800V
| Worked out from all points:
|   slope of the pulldown table from 0 to 0.225 V, typ, clamps not added: 42.4 ohm
|   slope of the pullup table from 0 to 0.225 V, typ, clamps not added: 36.9 ohm
|   GND clamp passes 1 mA (typ) near -0.44 V on its own axis
|   POWER clamp passes 1 mA (typ) near -0.55 V on its own axis
|   rising waveform, R_fixture 50.0000, V_fixture 1.5000: 20-80 % time 322ps typ, 339ps min, 303ps max; typ from 0.934 V to 1.5 V
|   rising waveform, R_fixture 50.0000, V_fixture 0.0: 20-80 % time 720ps typ, 1.17ns min, 468ps max; typ from 0 V to 0.638 V
|   falling waveform, R_fixture 50.0000, V_fixture 0.0: 20-80 % time 330ps typ, 378ps min, 256ps max; typ from 0.638 V to 0 V
|   falling waveform, R_fixture 50.0000, V_fixture 1.5000: 20-80 % time 707ps typ, 1.1ns min, 466ps max; typ from 1.5 V to 0.934 V
[Pulldown]
|Voltage   I(typ)   I(min)   I(max)
-1.5V     -16.19mA   -10.92mA   -21.94mA
-1.02V    -15.7mA    -10.59mA   -21.27mA
-900mV    -15.56mA   -10.5mA    -19.8mA
-600mV    -13.74mA   -9.7mA     -18.26mA
-480mV    -12.77mA   -8.548mA   -17.88mA
-420mV    -11.75mA   -7.622mA   -16.89mA
-60mV     -1.68mA    -1.008mA   -2.556mA
180mV     4.403mA    2.572mA    6.858mA
420mV     8.409mA    4.818mA    13.28mA
600mV     10.07mA    5.709mA    15.95mA
1.14V     11.66mA    6.58mA     18.35mA
3V        13.23mA    7.494mA    20.69mA
[Pullup]
|Voltage   I(typ)   I(min)   I(max)
-1.5V     57.37mA    40.12mA    67.61mA
-1.2V     44.66mA    31.12mA    53.37mA
-1.08V    39.97mA    27.63mA    48.71mA
-960mV    35.54mA    24.24mA    45.37mA
-540mV    20.94mA    13.54mA    27.73mA
-240mV    8.528mA    5.403mA    11.68mA
-60mV     1.96mA     1.218mA    2.744mA
240mV     -6.444mA   -3.927mA   -9.294mA
480mV     -10.55mA   -6.331mA   -15.63mA
660mV     -12.09mA   -7.164mA   -18.39mA
900mV     -12.73mA   -7.471mA   -19.82mA
3V        -14.72mA   -8.563mA   -23.28mA
[GND_clamp]
|Voltage   I(typ)   I(min)   I(max)
-1.5V     -148mA     -145.1mA   -157.1mA
-1.32V    -110mA     -107mA     -118.7mA
-1.17V    -80.44mA   -77.06mA   -89.3mA
-1.05V    -59.22mA   -54.98mA   -69.71mA
-930mV    -42.25mA   -35.9mA    -54.91mA
-810mV    -29.28mA   -21.6mA    -39.29mA
-690mV    -17.12mA   -10.87mA   -23.53mA
-600mV    -9.252mA   -5.256mA   -13.04mA
-540mV    -5.056mA   -2.651mA   -7.221mA
-450mV    -1.176mA   -584.3uA   -1.582mA
-300mV    -18.62uA   -15.88uA   -16.42uA
3V        0A         0A         0A
[POWER_clamp]
|Voltage   I(typ)   I(min)   I(max)
-1.5V     33.09mA    26.54mA    38.76mA
-1.2V     21.88mA    19.83mA    21.41mA
-1.08V    17.31mA    16.9mA     15.33mA
-900mV    10.59mA    12.38mA    7.966mA
-780mV    6.585mA    9.294mA    3.343mA
-720mV    4.798mA    7.731mA    1.687mA
-660mV    3.201mA    6.172mA    637.9uA
-540mV    907.7uA    3.212mA    50.7uA
-420mV    112.6uA    1.073mA    3.157uA
-360mV    35.33uA    495.5uA    755.6nA
-240mV    3.045uA    67.64uA    60.85nA
3V        -25.84nA   -23.03nA   -33.01nA
[Ramp]
| variable   typ   min   max
dV/dt_r  0.3479/0.7174n   0.2270/1.1600n   0.5518/0.4629n
dV/dt_f  0.3393/0.7002n   0.1964/1.0879n   0.5091/0.4615n
R_load = 50.0000
[Rising Waveform]
R_fixture=   50.0000
V_fixture=   1.5000
V_fixture_min=   1.4300
V_fixture_max=   1.5800
|time   V(typ)   V(min)   V(max)
0s        934.4mV    1.103V     731.4mV
606.1ps   934.4mV    1.103V     727mV
707.1ps   934.5mV    1.103V     806.3mV
909.1ps   934.2mV    1.103V     1.287V
1.111ns   951.6mV    1.103V     1.461V
1.414ns   1.346V     1.103V     1.561V
1.818ns   1.452V     1.1V       1.576V
2.222ns   1.487V     1.343V     1.579V
2.727ns   1.497V     1.404V     1.58V
10ns      1.5V       1.43V      1.58V
[Rising Waveform]
R_fixture=   50.0000
V_fixture=   0.0
V_fixture_min=   0.0
V_fixture_max=   0.0
|time   V(typ)   V(min)   V(max)
0s        510.1nV    728.2nV    394.5nV
1.01ns    -1.515mV   4.149uV    8.18mV
1.616ns   -6.47mV    -638.9uV   717mV
1.919ns   82.42mV    -6.075mV   846.4mV
2.222ns   296.7mV    -9.841mV   891.2mV
2.727ns   518mV      -3.695mV   913.2mV
3.535ns   613.3mV    94.3mV     918.9mV
4.343ns   632mV      266.7mV    919.6mV
5.152ns   636.6mV    346.6mV    919.7mV
10ns      638mV      378.3mV    919.7mV
[Falling Waveform]
R_fixture=   50.0000
V_fixture=   0.0
V_fixture_min=   0.0
V_fixture_max=   0.0
|time   V(typ)   V(min)   V(max)
0s        638mV      378.4mV    919.7mV
707.1ps   638mV      378.4mV    921.3mV
808.1ps   638mV      378.4mV    845mV
1.111ns   638.3mV    378.4mV    174.6mV
1.414ns   432.9mV    378.3mV    19.62mV
1.616ns   172.5mV    378.3mV    8.27mV
2.121ns   16.7mV     379.9mV    1.212mV
2.626ns   3.936mV    104.9mV    215uV
3.131ns   1.205mV    21.66mV    60.66uV
10ns      -12.95uV   14.81uV    3.658uV
[Falling Waveform]
R_fixture=   50.0000
V_fixture=   1.5000
V_fixture_min=   1.4300
V_fixture_max=   1.5800
|time   V(typ)   V(min)   V(max)
0s        1.5V       1.43V      1.58V
909.1ps   1.5V       1.43V      1.622V
1.01ns    1.501V     1.43V      1.565V
1.515ns   1.538V     1.43V      952.7mV
2.121ns   1.248V     1.43V      763.1mV
2.626ns   1.044V     1.453V     738.4mV
3.434ns   954.4mV    1.338V     732.2mV
4.242ns   938.5mV    1.187V     731.6mV
5.152ns   935mV      1.123V     731.6mV
10ns      934.4mV    1.103V     731.5mV
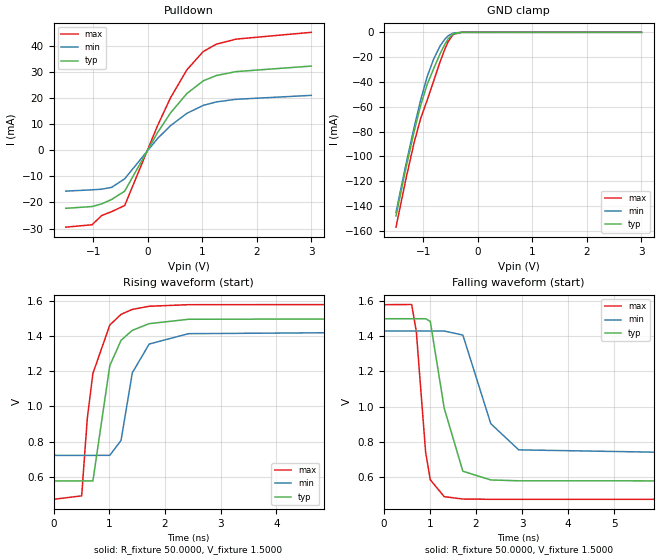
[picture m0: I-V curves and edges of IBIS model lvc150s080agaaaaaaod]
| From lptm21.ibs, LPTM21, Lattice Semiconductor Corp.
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|   Model lvc150s080agaaaaaaod
[Model]   lvc150s080agaaaaaaod
Model_type   I/O_open_drain
Polarity   Non-Inverting
Enable   Active-Low
Vinl =   0.3750V
Vinh =   1.1250V
Vmeas =   0.7500V
Cref =   0.0F
Rref =   1.0000M
Vref =   0.0V
C_comp   4.2000pF   3.8000pF   7.5000pF
[Temperature Range]   25.0000   0.1050k   -40.0000
[Voltage Range]   1.5000V   1.4300V   1.5800V
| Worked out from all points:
|   slope of the pulldown table from 0 to 0.225 V, typ, clamps not added: 27.4 ohm
|   GND clamp passes 1 mA (typ) near -0.44 V on its own axis
|   rising waveform, R_fixture 50.0000, V_fixture 1.5000: 20-80 % time 287ps typ, 295ps min, 288ps max; typ from 0.576 V to 1.5 V
|   falling waveform, R_fixture 50.0000, V_fixture 1.5000: 20-80 % time 326ps typ, 522ps min, 213ps max; typ from 1.5 V to 0.576 V
[Pulldown]
|Voltage   I(typ)   I(min)   I(max)
-1.5V     -22.23mA   -15.64mA   -29.44mA
-1.02V    -21.55mA   -15.16mA   -28.53mA
-840mV    -20.52mA   -14.9mA    -24.97mA
-660mV    -18.84mA   -14.21mA   -23.51mA
-420mV    -15.65mA   -10.92mA   -21.14mA
180mV     6.692mA    4.443mA    9.321mA
420mV     14.31mA    9.422mA    20.11mA
720mV     21.72mA    14.14mA    30.8mA
1.02V     26.57mA    17.18mA    37.8mA
1.26V     28.61mA    18.5mA     40.6mA
1.62V     30.1mA     19.5mA     42.54mA
3V        32.22mA    21.01mA    45.14mA
[GND_clamp]
|Voltage   I(typ)   I(min)   I(max)
-1.5V     -148.1mA   -145.1mA   -157.1mA
-1.32V    -110mA     -107mA     -118.7mA
-1.17V    -80.46mA   -77.1mA    -89.31mA
-1.05V    -59.23mA   -55mA      -69.72mA
-930mV    -42.26mA   -35.91mA   -54.92mA
-810mV    -29.29mA   -21.6mA    -39.3mA
-690mV    -17.13mA   -10.88mA   -23.54mA
-600mV    -9.258mA   -5.26mA    -13.05mA
-540mV    -5.061mA   -2.654mA   -7.228mA
-450mV    -1.178mA   -585.4uA   -1.585mA
-300mV    -18.71uA   -15.93uA   -16.54uA
3V        0A         0A         0A
[Ramp]
| variable   typ   min   max
dV/dt_r  0.5542/0.2843n   0.4250/0.2918n   0.6651/0.2853n
dV/dt_f  0.5542/0.3229n   0.4250/0.5172n   0.6651/0.2113n
R_load = 50.0000
[Rising Waveform]
R_fixture=   50.0000
V_fixture=   1.5000
V_fixture_min=   1.4300
V_fixture_max=   1.5800
|time   V(typ)   V(min)   V(max)
0s        576.3mV    721.7mV    471.5mV
505.1ps   576.3mV    721.7mV    491.3mV
606.1ps   576.6mV    721.7mV    931.8mV
707.1ps   576.3mV    721.7mV    1.188V
1.01ns    1.232V     721.8mV    1.463V
1.212ns   1.376V     806.5mV    1.524V
1.414ns   1.433V     1.191V     1.552V
1.717ns   1.471V     1.355V     1.57V
2.424ns   1.496V     1.414V     1.579V
10ns      1.5V       1.43V      1.58V
[Falling Waveform]
R_fixture=   50.0000
V_fixture=   1.5000
V_fixture_min=   1.4300
V_fixture_max=   1.5800
|time   V(typ)   V(min)   V(max)
0s        1.5V       1.43V      1.58V
606.1ps   1.5V       1.43V      1.581V
707.1ps   1.5V       1.43V      1.428V
909.1ps   1.5V       1.43V      739.9mV
1.01ns    1.485V     1.43V      582.7mV
1.313ns   989.8mV    1.43V      486.6mV
1.717ns   631.5mV    1.407V     473.2mV
2.323ns   581.8mV    902.2mV    471.6mV
2.929ns   577mV      753.2mV    471.5mV
10ns      576.3mV    721.7mV    471.5mV
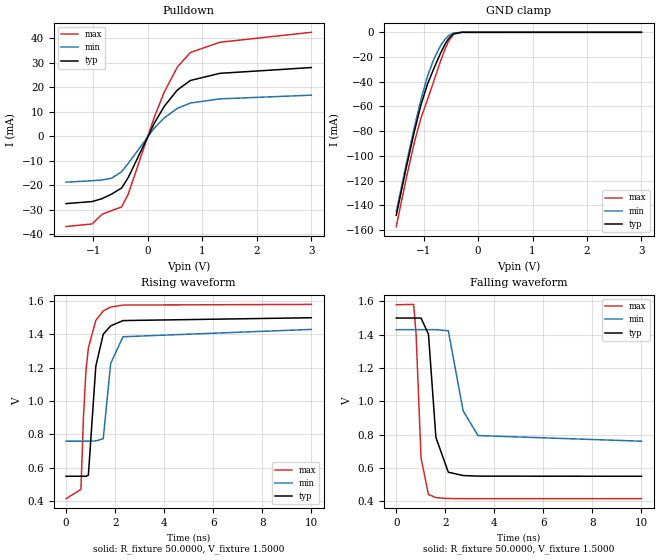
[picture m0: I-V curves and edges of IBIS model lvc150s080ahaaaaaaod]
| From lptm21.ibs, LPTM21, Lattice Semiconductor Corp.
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|   Model lvc150s080ahaaaaaaod
[Model]   lvc150s080ahaaaaaaod
Model_type   I/O_open_drain
Polarity   Non-Inverting
Enable   Active-Low
Vinl =   0.3750V
Vinh =   1.1250V
Vmeas =   0.7500V
Cref =   0.0F
Rref =   1.0000M
Vref =   0.0V
C_comp   4.2000pF   3.8000pF   7.5000pF
[Temperature Range]   25.0000   0.1050k   -40.0000
[Voltage Range]   1.5000V   1.4300V   1.5800V
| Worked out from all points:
|   slope of the pulldown table from 0 to 0.225 V, typ, clamps not added: 23.7 ohm
|   GND clamp passes 1 mA (typ) near -0.44 V on its own axis
|   rising waveform, R_fixture 50.0000, V_fixture 1.5000: 20-80 % time 296ps typ, 296ps min, 297ps max; typ from 0.549 V to 1.5 V
|   falling waveform, R_fixture 50.0000, V_fixture 1.5000: 20-80 % time 304ps typ, 509ps min, 196ps max; typ from 1.5 V to 0.549 V
[Pulldown]
|Voltage   I(typ)   I(min)   I(max)
-1.5V     -27.51mA   -18.75mA   -36.88mA
-1.02V    -26.67mA   -18.17mA   -35.8mA
-840mV    -25.49mA   -17.88mA   -31.86mA
-660mV    -23.57mA   -17.1mA    -30.33mA
-480mV    -21.13mA   -14.49mA   -28.87mA
-360mV    -16.89mA   -11.13mA   -23.66mA
120mV     5.351mA    3.322mA    7.82mA
300mV     12.14mA    7.44mA     17.93mA
540mV     18.82mA    11.34mA    28.16mA
780mV     22.73mA    13.53mA    34.14mA
1.32V     25.65mA    15.23mA    38.33mA
3V        28.01mA    16.74mA    42.4mA
[GND_clamp]
|Voltage   I(typ)   I(min)   I(max)
-1.5V     -148mA     -145.1mA   -157.1mA
-1.32V    -110mA     -107mA     -118.7mA
-1.17V    -80.45mA   -77.09mA   -89.3mA
-1.05V    -59.22mA   -54.99mA   -69.72mA
-930mV    -42.25mA   -35.9mA    -54.92mA
-810mV    -29.28mA   -21.6mA    -39.3mA
-690mV    -17.13mA   -10.87mA   -23.53mA
-600mV    -9.254mA   -5.257mA   -13.04mA
-540mV    -5.058mA   -2.652mA   -7.223mA
-450mV    -1.176mA   -584.6uA   -1.583mA
-300mV    -18.65uA   -15.9uA    -16.45uA
3V        0A         0A         0A
[Ramp]
| variable   typ   min   max
dV/dt_r  0.5706/0.2931n   0.4021/0.2930n   0.6992/0.2941n
dV/dt_f  0.5699/0.3183n   0.4021/0.5040n   0.6992/0.1939n
R_load = 50.0000
[Rising Waveform]
R_fixture=   50.0000
V_fixture=   1.5000
V_fixture_min=   1.4300
V_fixture_max=   1.5800
|time   V(typ)   V(min)   V(max)
0s        549.1mV    759.9mV    414.6mV
606.1ps   549.1mV    759.9mV    470.4mV
707.1ps   549.4mV    759.9mV    897.9mV
808.1ps   548.4mV    759.9mV    1.179V
909.1ps   555.5mV    759.8mV    1.319V
1.212ns   1.209V     761.1mV    1.484V
1.515ns   1.401V     774.3mV    1.541V
1.818ns   1.451V     1.226V     1.564V
2.323ns   1.483V     1.386V     1.576V
10ns      1.5V       1.43V      1.58V
[Falling Waveform]
R_fixture=   50.0000
V_fixture=   1.5000
V_fixture_min=   1.4300
V_fixture_max=   1.5800
|time   V(typ)   V(min)   V(max)
0s        1.5V       1.43V      1.58V
707.1ps   1.5V       1.43V      1.582V
808.1ps   1.5V       1.43V      1.403V
1.01ns    1.5V       1.43V      659.2mV
1.313ns   1.403V     1.43V      439.6mV
1.616ns   782.6mV    1.43V      420.9mV
2.121ns   573.8mV    1.424V     415.4mV
2.727ns   553.7mV    942.4mV    414.7mV
3.333ns   550.1mV    793.9mV    414.6mV
10ns      549.1mV    759.9mV    414.6mV
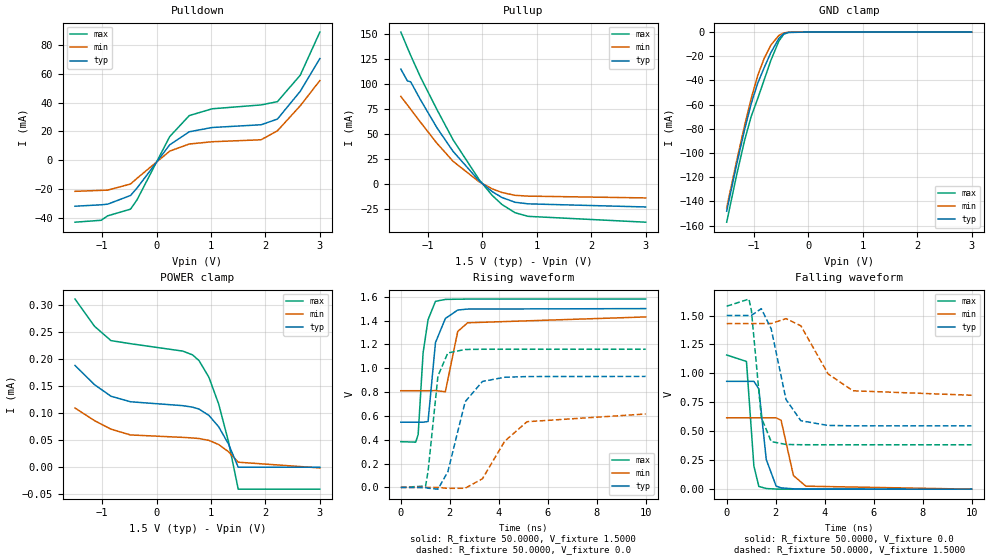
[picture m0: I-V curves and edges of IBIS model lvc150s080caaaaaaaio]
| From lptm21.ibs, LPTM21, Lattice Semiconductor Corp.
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|   Model lvc150s080caaaaaaaio
[Model]   lvc150s080caaaaaaaio
Model_type   I/O
Polarity   Non-Inverting
Enable   Active-Low
Vinl =   0.3750V
Vinh =   1.1250V
Vmeas =   0.7500V
Cref =   0.0F
Rref =   1.0000M
Vref =   0.0V
C_comp   4.2000pF   3.8000pF   7.5000pF
[Temperature Range]   25.0000   0.1050k   -40.0000
[Voltage Range]   1.5000V   1.4300V   1.5800V
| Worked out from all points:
|   slope of the pulldown table from 0 to 0.225 V, typ, clamps not added: 22.2 ohm
|   slope of the pullup table from 0 to 0.225 V, typ, clamps not added: 23.8 ohm
|   GND clamp passes 1 mA (typ) near -0.44 V on its own axis
|   rising waveform, R_fixture 50.0000, V_fixture 1.5000: 20-80 % time 308ps typ, 333ps min, 302ps max; typ from 0.547 V to 1.5 V
|   rising waveform, R_fixture 50.0000, V_fixture 0.0: 20-80 % time 710ps typ, 1.26ns min, 352ps max; typ from 0 V to 0.931 V
|   falling waveform, R_fixture 50.0000, V_fixture 0.0: 20-80 % time 326ps typ, 377ps min, 235ps max; typ from 0.931 V to 0 V
|   falling waveform, R_fixture 50.0000, V_fixture 1.5000: 20-80 % time 609ps typ, 1.11ns min, 313ps max; typ from 1.5 V to 0.547 V
[Pulldown]
|Voltage   I(typ)   I(min)   I(max)
-1.5V     -31.9mA    -21.56mA   -42.99mA
-1.02V    -30.91mA   -20.89mA   -41.67mA
-900mV    -30.48mA   -20.73mA   -38.58mA
-480mV    -24.44mA   -16.49mA   -33.94mA
-360mV    -19.3mA    -12.51mA   -27.45mA
240mV     10.74mA    6.349mA    16.41mA
600mV     19.78mA    11.29mA    31.02mA
1.02V     22.75mA    12.86mA    35.74mA
1.92V     24.65mA    14.23mA    38.42mA
2.22V     28.59mA    20.45mA    40.69mA
2.64V     47.88mA    37.83mA    59.06mA
3V        70.6mA     55.33mA    88.99mA
[Pullup]
|Voltage   I(typ)   I(min)   I(max)
-1.5V     115.1mA    87.71mA    152.3mA
-1.38V    103.3mA    79.12mA    136.7mA
-1.32V    102.4mA    74.78mA    129mA
-1.14V    84.43mA    61.86mA    107.2mA
-840mV    56.51mA    40.86mA    74.85mA
-540mV    32.52mA    22.55mA    44.18mA
-60mV     2.872mA    1.918mA    4.08mA
180mV     -7.925mA   -5.102mA   -11.74mA
360mV     -13.82mA   -8.802mA   -20.88mA
600mV     -18.58mA   -11.61mA   -29.1mA
840mV     -20.17mA   -12.41mA   -32.72mA
3V        -23.29mA   -14.21mA   -38.58mA
[GND_clamp]
|Voltage   I(typ)   I(min)   I(max)
-1.5V     -148mA     -145.1mA   -157.1mA
-1.32V    -110mA     -107mA     -118.7mA
-1.17V    -80.48mA   -77.09mA   -89.35mA
-1.05V    -59.26mA   -55.01mA   -69.77mA
-930mV    -42.29mA   -35.93mA   -54.98mA
-810mV    -29.33mA   -21.63mA   -39.36mA
-690mV    -17.18mA   -10.91mA   -23.6mA
-540mV    -5.131mA   -2.707mA   -7.327mA
-450mV    -1.269mA   -646.6uA   -1.725mA
-360mV    -213.6uA   -130.7uA   -279.5uA
0V        0A         0A         0A
3V        0A         0A         0A
[POWER_clamp]
|Voltage   I(typ)   I(min)   I(max)
-1.5V     188.7uA    109.8uA    311.9uA
-1.14V    153uA      86.3uA     261.2uA
-840mV    131.7uA    70.61uA    234.9uA
-480mV    121.4uA    59.86uA    229.1uA
480mV     114.2uA    55.36uA    215.4uA
660mV     111.4uA    54.29uA    208.4uA
780mV     107.8uA    53.22uA    197.7uA
960mV     96.18uA    49.83uA    167uA
1.14V     75.06uA    42.11uA    117.4uA
1.32V     43.25uA    28.83uA    47.75uA
1.5V      -25.18nA   9.33uA     -40.71uA
3V        -25.18nA   -1.33uA    -40.71uA
[Ramp]
| variable   typ   min   max
dV/dt_r  0.5321/0.7031n   0.3695/1.2521n   0.6955/0.3480n
dV/dt_f  0.5719/0.6025n   0.3713/1.0970n   0.7179/0.3094n
R_load = 50.0000
[Rising Waveform]
R_fixture=   50.0000
V_fixture=   1.5000
V_fixture_min=   1.4300
V_fixture_max=   1.5800
|time   V(typ)   V(min)   V(max)
0s        546.8mV    811.1mV    383.5mV
606.1ps   546.8mV    811.1mV    379.9mV
707.1ps   546.9mV    811.1mV    443.6mV
909.1ps   546.6mV    811.1mV    1.13V
1.111ns   553mV      811mV      1.407V
1.414ns   1.215V     812.1mV    1.561V
1.818ns   1.417V     802.5mV    1.577V
2.323ns   1.488V     1.308V     1.579V
2.727ns   1.496V     1.381V     1.58V
10ns      1.5V       1.43V      1.58V
[Rising Waveform]
R_fixture=   50.0000
V_fixture=   0.0
V_fixture_min=   0.0
V_fixture_max=   0.0
|time   V(typ)   V(min)   V(max)
0s        317.8nV    495.5nV    230.8nV
1.01ns    -1.573mV   4.676uV    11.35mV
1.111ns   -6.67mV    12.66uV    133.5mV
1.515ns   -14.72mV   -426.5uV   934.3mV
1.919ns   131mV      -7.982mV   1.128V
2.626ns   718.5mV    -6.986mV   1.157V
3.333ns   888.9mV    72.93mV    1.159V
4.242ns   924.1mV    387.3mV    1.159V
5.152ns   929.9mV    551.1mV    1.159V
10ns      931.1mV    615.8mV    1.159V
[Falling Waveform]
R_fixture=   50.0000
V_fixture=   0.0
V_fixture_min=   0.0
V_fixture_max=   0.0
|time   V(typ)   V(min)   V(max)
0s        931.1mV    616.1mV    1.159V
808.1ps   931.1mV    616.1mV    1.103V
1.111ns   931.5mV    616.1mV    199.6mV
1.313ns   866mV      616.1mV    23.79mV
1.616ns   256.5mV    616.2mV    5.489mV
2.02ns    26.33mV    616.1mV    1.088mV
2.222ns   11.36mV    595.1mV    502uV
2.727ns   2.894mV    117.4mV    77.08uV
3.232ns   866.9uV    25.77mV    39.91uV
10ns      -3.498uV   24.86uV    -16.26uV
[Falling Waveform]
R_fixture=   50.0000
V_fixture=   1.5000
V_fixture_min=   1.4300
V_fixture_max=   1.5800
|time   V(typ)   V(min)   V(max)
0s        1.5V       1.43V      1.58V
909.1ps   1.5V       1.43V      1.642V
1.01ns    1.501V     1.43V      1.542V
1.414ns   1.559V     1.43V      619.4mV
1.818ns   1.385V     1.431V     411.1mV
2.424ns   774.5mV    1.473V     386.1mV
3.03ns    590.9mV    1.411V     383.8mV
4.141ns   550.3mV    995.7mV    383.5mV
5.152ns   547.3mV    850mV      383.5mV
10ns      546.8mV    811.1mV    383.5mV
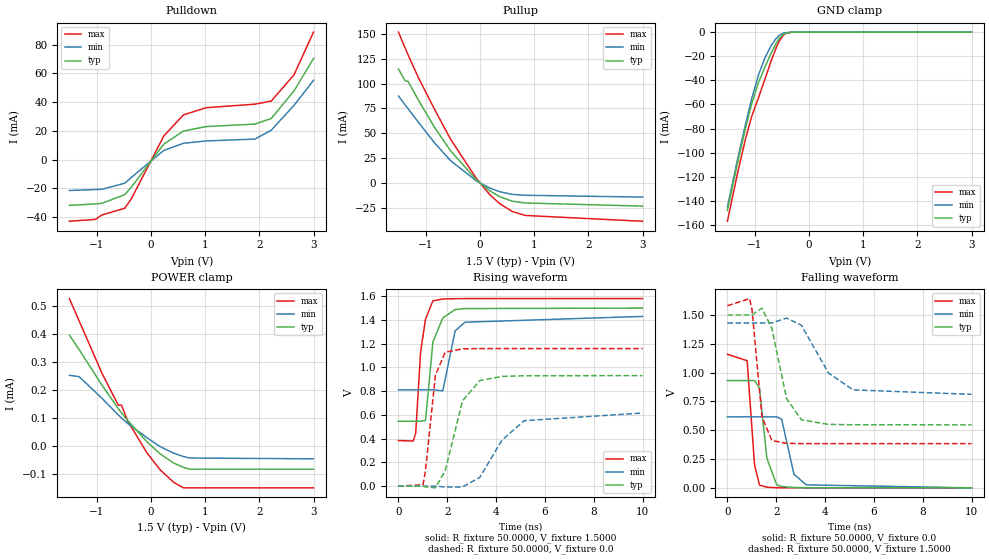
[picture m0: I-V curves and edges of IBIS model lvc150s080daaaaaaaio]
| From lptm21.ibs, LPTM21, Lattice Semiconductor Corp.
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|   Model lvc150s080daaaaaaaio
[Model]   lvc150s080daaaaaaaio
Model_type   I/O
Polarity   Non-Inverting
Enable   Active-Low
Vinl =   0.3750V
Vinh =   1.1250V
Vmeas =   0.7500V
Cref =   0.0F
Rref =   1.0000M
Vref =   0.0V
C_comp   4.2000pF   3.8000pF   7.5000pF
[Temperature Range]   25.0000   0.1050k   -40.0000
[Voltage Range]   1.5000V   1.4300V   1.5800V
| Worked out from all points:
|   slope of the pulldown table from 0 to 0.225 V, typ, clamps not added: 22.2 ohm
|   slope of the pullup table from 0 to 0.225 V, typ, clamps not added: 23.9 ohm
|   GND clamp passes 1 mA (typ) near -0.44 V on its own axis
|   rising waveform, R_fixture 50.0000, V_fixture 1.5000: 20-80 % time 308ps typ, 333ps min, 302ps max; typ from 0.547 V to 1.5 V
|   rising waveform, R_fixture 50.0000, V_fixture 0.0: 20-80 % time 710ps typ, 1.26ns min, 352ps max; typ from 0 V to 0.931 V
|   falling waveform, R_fixture 50.0000, V_fixture 0.0: 20-80 % time 326ps typ, 377ps min, 235ps max; typ from 0.931 V to 0 V
|   falling waveform, R_fixture 50.0000, V_fixture 1.5000: 20-80 % time 609ps typ, 1.11ns min, 313ps max; typ from 1.5 V to 0.547 V
[Pulldown]
|Voltage   I(typ)   I(min)   I(max)
-1.5V     -31.9mA    -21.56mA   -42.99mA
-1.02V    -30.91mA   -20.89mA   -41.67mA
-900mV    -30.48mA   -20.73mA   -38.58mA
-480mV    -24.44mA   -16.49mA   -33.94mA
-360mV    -19.3mA    -12.51mA   -27.45mA
240mV     10.74mA    6.349mA    16.41mA
600mV     19.78mA    11.29mA    31.02mA
1.02V     22.94mA    12.95mA    36.09mA
1.92V     24.69mA    14.23mA    38.53mA
2.22V     28.55mA    20.4mA     40.7mA
2.64V     47.75mA    37.71mA    58.93mA
3V        70.39mA    55.17mA    88.75mA
[Pullup]
|Voltage   I(typ)   I(min)   I(max)
-1.5V     114.9mA    87.56mA    152mA
-1.38V    103.1mA    78.98mA    136.5mA
-1.32V    102.2mA    74.65mA    128.8mA
-1.14V    84.28mA    61.75mA    107mA
-840mV    56.43mA    40.79mA    74.8mA
-540mV    32.53mA    22.54mA    44.23mA
-60mV     2.984mA    1.968mA    4.287mA
180mV     -7.77mA    -5.028mA   -11.47mA
360mV     -13.64mA   -8.714mA   -20.57mA
600mV     -18.38mA   -11.51mA   -28.75mA
840mV     -20.17mA   -12.41mA   -32.72mA
3V        -23.29mA   -14.21mA   -38.58mA
[GND_clamp]
|Voltage   I(typ)   I(min)   I(max)
-1.5V     -147.9mA   -145.1mA   -156.9mA
-1.32V    -109.9mA   -107mA     -118.5mA
-1.17V    -80.39mA   -77.05mA   -89.2mA
-1.05V    -59.17mA   -54.96mA   -69.62mA
-930mV    -42.2mA    -35.88mA   -54.83mA
-810mV    -29.25mA   -21.58mA   -39.21mA
-690mV    -17.09mA   -10.87mA   -23.45mA
-600mV    -9.233mA   -5.258mA   -12.98mA
-540mV    -5.047mA   -2.659mA   -7.175mA
-450mV    -1.185mA   -599.1uA   -1.573mA
-300mV    -18.73uA   -15.61uA   -8.8uA
3V        0A         0A         0A
[POWER_clamp]
|Voltage   I(typ)   I(min)   I(max)
-1.5V     395.4uA    251.6uA    526.1uA
-1.32V    343.5uA    246.7uA    446.2uA
-900mV    216.4uA    169.3uA    259.1uA
-600mV    132.4uA    109.9uA    145uA
-540mV    117.3uA    98.92uA    145uA
-420mV    88.66uA    78.23uA    86.09uA
-60mV     11.57uA    26.89uA    -29.01uA
180mV     -30.73uA   -4.427uA   -88.14uA
420mV     -62.06uA   -26.95uA   -131uA
600mV     -77.75uA   -38.9uA    -151.1uA
720mV     -84.27uA   -44.44uA   -151.1uA
3V        -84.27uA   -47.29uA   -151.1uA
[Ramp]
| variable   typ   min   max
dV/dt_r  0.5321/0.7031n   0.3695/1.2521n   0.6955/0.3480n
dV/dt_f  0.5719/0.6025n   0.3713/1.0970n   0.7179/0.3094n
R_load = 50.0000
[Rising Waveform]
R_fixture=   50.0000
V_fixture=   1.5000
V_fixture_min=   1.4300
V_fixture_max=   1.5800
|time   V(typ)   V(min)   V(max)
0s        546.8mV    811.1mV    383.5mV
606.1ps   546.8mV    811.1mV    379.9mV
707.1ps   546.9mV    811.1mV    443.6mV
909.1ps   546.6mV    811.1mV    1.13V
1.111ns   553mV      811mV      1.407V
1.414ns   1.215V     812.1mV    1.561V
1.818ns   1.417V     802.5mV    1.577V
2.323ns   1.488V     1.308V     1.579V
2.727ns   1.496V     1.381V     1.58V
10ns      1.5V       1.43V      1.58V
[Rising Waveform]
R_fixture=   50.0000
V_fixture=   0.0
V_fixture_min=   0.0
V_fixture_max=   0.0
|time   V(typ)   V(min)   V(max)
0s        317.8nV    495.5nV    230.8nV
1.01ns    -1.573mV   4.676uV    11.35mV
1.111ns   -6.67mV    12.66uV    133.5mV
1.515ns   -14.72mV   -426.5uV   934.3mV
1.919ns   131mV      -7.982mV   1.128V
2.626ns   718.5mV    -6.986mV   1.157V
3.333ns   888.9mV    72.93mV    1.159V
4.242ns   924.1mV    387.3mV    1.159V
5.152ns   929.9mV    551.1mV    1.159V
10ns      931.1mV    615.8mV    1.159V
[Falling Waveform]
R_fixture=   50.0000
V_fixture=   0.0
V_fixture_min=   0.0
V_fixture_max=   0.0
|time   V(typ)   V(min)   V(max)
0s        931.1mV    616.1mV    1.159V
808.1ps   931.1mV    616.1mV    1.103V
1.111ns   931.5mV    616.1mV    199.6mV
1.313ns   866mV      616.1mV    23.79mV
1.616ns   256.5mV    616.2mV    5.489mV
2.02ns    26.33mV    616.1mV    1.088mV
2.222ns   11.36mV    595.1mV    502uV
2.727ns   2.894mV    117.4mV    77.08uV
3.232ns   866.9uV    25.77mV    39.91uV
10ns      -3.498uV   24.86uV    -16.26uV
[Falling Waveform]
R_fixture=   50.0000
V_fixture=   1.5000
V_fixture_min=   1.4300
V_fixture_max=   1.5800
|time   V(typ)   V(min)   V(max)
0s        1.5V       1.43V      1.58V
909.1ps   1.5V       1.43V      1.642V
1.01ns    1.501V     1.43V      1.542V
1.414ns   1.559V     1.43V      619.4mV
1.818ns   1.385V     1.431V     411.1mV
2.424ns   774.5mV    1.473V     386.1mV
3.03ns    590.9mV    1.411V     383.8mV
4.141ns   550.3mV    995.7mV    383.5mV
5.152ns   547.3mV    850mV      383.5mV
10ns      546.8mV    811.1mV    383.5mV
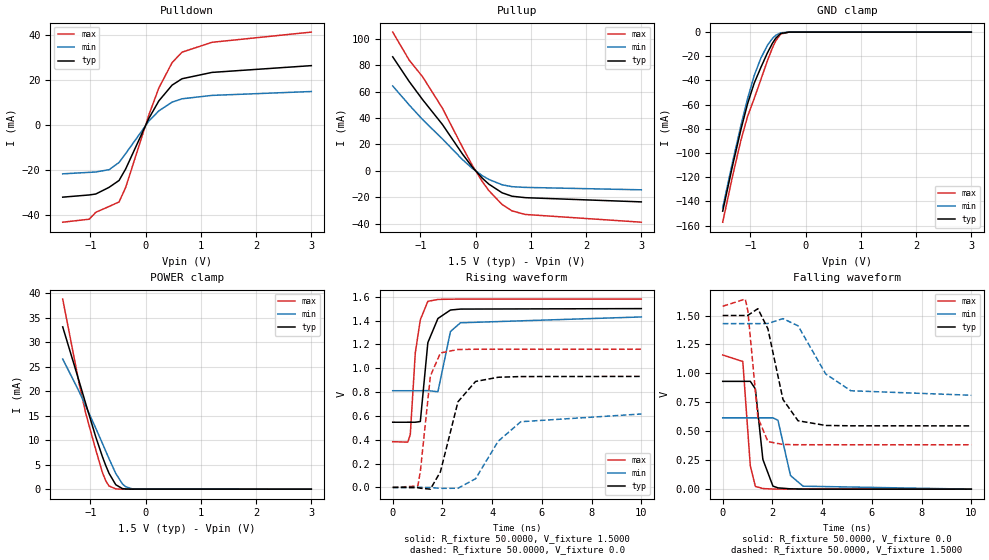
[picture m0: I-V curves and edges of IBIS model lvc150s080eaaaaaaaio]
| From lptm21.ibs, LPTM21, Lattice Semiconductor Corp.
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|   Model lvc150s080eaaaaaaaio
[Model]   lvc150s080eaaaaaaaio
Model_type   I/O
Polarity   Non-Inverting
Enable   Active-Low
Vinl =   0.3750V
Vinh =   1.1250V
Vmeas =   0.7500V
Cref =   0.0F
Rref =   1.0000M
Vref =   0.0V
C_comp   4.2000pF   3.8000pF   7.5000pF
[Temperature Range]   25.0000   0.1050k   -40.0000
[Voltage Range]   1.5000V   1.4300V   1.5800V
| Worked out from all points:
|   slope of the pulldown table from 0 to 0.225 V, typ, clamps not added: 22 ohm
|   slope of the pullup table from 0 to 0.225 V, typ, clamps not added: 23.8 ohm
|   GND clamp passes 1 mA (typ) near -0.44 V on its own axis
|   POWER clamp passes 1 mA (typ) near -0.55 V on its own axis
|   rising waveform, R_fixture 50.0000, V_fixture 1.5000: 20-80 % time 308ps typ, 333ps min, 302ps max; typ from 0.547 V to 1.5 V
|   rising waveform, R_fixture 50.0000, V_fixture 0.0: 20-80 % time 710ps typ, 1.26ns min, 352ps max; typ from 0 V to 0.931 V
|   falling waveform, R_fixture 50.0000, V_fixture 0.0: 20-80 % time 326ps typ, 377ps min, 235ps max; typ from 0.931 V to 0 V
|   falling waveform, R_fixture 50.0000, V_fixture 1.5000: 20-80 % time 609ps typ, 1.11ns min, 313ps max; typ from 1.5 V to 0.547 V
[Pulldown]
|Voltage   I(typ)   I(min)   I(max)
-1.5V     -31.94mA   -21.59mA   -43.05mA
-1.02V    -30.96mA   -20.93mA   -41.73mA
-900mV    -30.53mA   -20.76mA   -38.64mA
-660mV    -27.57mA   -19.73mA   -36.06mA
-480mV    -24.53mA   -16.55mA   -34.07mA
-360mV    -19.4mA    -12.57mA   -27.61mA
60mV      3.049mA    1.834mA    4.587mA
240mV     10.79mA    6.377mA    16.51mA
480mV     17.79mA    10.25mA    27.78mA
660mV     20.62mA    11.72mA    32.42mA
1.2V      23.43mA    13.23mA    36.79mA
3V        26.44mA    14.95mA    41.33mA
[Pullup]
|Voltage   I(typ)   I(min)   I(max)
-1.5V     86.3mA     64.26mA    105mA
-1.2V     67.54mA    49.82mA    83.72mA
-960mV    53.98mA    38.89mA    71.29mA
-600mV    35.13mA    24.21mA    47.42mA
-240mV    12.95mA    8.711mA    18.19mA
-60mV     2.996mA    1.975mA    4.306mA
120mV     -5.41mA    -3.512mA   -7.936mA
240mV     -9.982mA   -6.431mA   -14.84mA
480mV     -16.52mA   -10.45mA   -25.36mA
660mV     -19.11mA   -11.9mA    -30.2mA
900mV     -20.21mA   -12.44mA   -32.9mA
3V        -23.39mA   -14.27mA   -38.75mA
[GND_clamp]
|Voltage   I(typ)   I(min)   I(max)
-1.5V     -148mA     -145.1mA   -157.1mA
-1.32V    -110mA     -107mA     -118.7mA
-1.17V    -80.44mA   -77.06mA   -89.3mA
-1.05V    -59.22mA   -54.98mA   -69.71mA
-930mV    -42.25mA   -35.9mA    -54.91mA
-810mV    -29.28mA   -21.6mA    -39.29mA
-690mV    -17.12mA   -10.87mA   -23.53mA
-600mV    -9.252mA   -5.256mA   -13.04mA
-540mV    -5.056mA   -2.651mA   -7.221mA
-450mV    -1.176mA   -584.3uA   -1.582mA
-300mV    -18.62uA   -15.88uA   -16.42uA
3V        0A         0A         0A
[POWER_clamp]
|Voltage   I(typ)   I(min)   I(max)
-1.5V     33.09mA    26.54mA    38.76mA
-1.2V     21.88mA    19.83mA    21.41mA
-1.08V    17.31mA    16.9mA     15.33mA
-900mV    10.59mA    12.38mA    7.966mA
-780mV    6.585mA    9.294mA    3.343mA
-720mV    4.798mA    7.731mA    1.687mA
-660mV    3.201mA    6.172mA    637.9uA
-540mV    907.7uA    3.212mA    50.7uA
-420mV    112.6uA    1.073mA    3.157uA
-360mV    35.33uA    495.5uA    755.6nA
-240mV    3.045uA    67.64uA    60.85nA
3V        -25.84nA   -23.03nA   -33.01nA
[Ramp]
| variable   typ   min   max
dV/dt_r  0.5321/0.7031n   0.3695/1.2521n   0.6955/0.3480n
dV/dt_f  0.5719/0.6025n   0.3713/1.0970n   0.7179/0.3094n
R_load = 50.0000
[Rising Waveform]
R_fixture=   50.0000
V_fixture=   1.5000
V_fixture_min=   1.4300
V_fixture_max=   1.5800
|time   V(typ)   V(min)   V(max)
0s        546.8mV    811.1mV    383.5mV
606.1ps   546.8mV    811.1mV    379.9mV
707.1ps   546.9mV    811.1mV    443.6mV
909.1ps   546.6mV    811.1mV    1.13V
1.111ns   553mV      811mV      1.407V
1.414ns   1.215V     812.1mV    1.561V
1.818ns   1.417V     802.5mV    1.577V
2.323ns   1.488V     1.308V     1.579V
2.727ns   1.496V     1.381V     1.58V
10ns      1.5V       1.43V      1.58V
[Rising Waveform]
R_fixture=   50.0000
V_fixture=   0.0
V_fixture_min=   0.0
V_fixture_max=   0.0
|time   V(typ)   V(min)   V(max)
0s        317.8nV    495.5nV    230.8nV
1.01ns    -1.573mV   4.676uV    11.35mV
1.111ns   -6.67mV    12.66uV    133.5mV
1.515ns   -14.72mV   -426.5uV   934.3mV
1.919ns   131mV      -7.982mV   1.128V
2.626ns   718.5mV    -6.986mV   1.157V
3.333ns   888.9mV    72.93mV    1.159V
4.242ns   924.1mV    387.3mV    1.159V
5.152ns   929.9mV    551.1mV    1.159V
10ns      931.1mV    615.8mV    1.159V
[Falling Waveform]
R_fixture=   50.0000
V_fixture=   0.0
V_fixture_min=   0.0
V_fixture_max=   0.0
|time   V(typ)   V(min)   V(max)
0s        931.1mV    616.1mV    1.159V
808.1ps   931.1mV    616.1mV    1.103V
1.111ns   931.5mV    616.1mV    199.6mV
1.313ns   866mV      616.1mV    23.79mV
1.616ns   256.5mV    616.2mV    5.489mV
2.02ns    26.33mV    616.1mV    1.088mV
2.222ns   11.36mV    595.1mV    502uV
2.727ns   2.894mV    117.4mV    77.08uV
3.232ns   866.9uV    25.77mV    39.91uV
10ns      -3.498uV   24.86uV    -16.26uV
[Falling Waveform]
R_fixture=   50.0000
V_fixture=   1.5000
V_fixture_min=   1.4300
V_fixture_max=   1.5800
|time   V(typ)   V(min)   V(max)
0s        1.5V       1.43V      1.58V
909.1ps   1.5V       1.43V      1.642V
1.01ns    1.501V     1.43V      1.542V
1.414ns   1.559V     1.43V      619.4mV
1.818ns   1.385V     1.431V     411.1mV
2.424ns   774.5mV    1.473V     386.1mV
3.03ns    590.9mV    1.411V     383.8mV
4.141ns   550.3mV    995.7mV    383.5mV
5.152ns   547.3mV    850mV      383.5mV
10ns      546.8mV    811.1mV    383.5mV
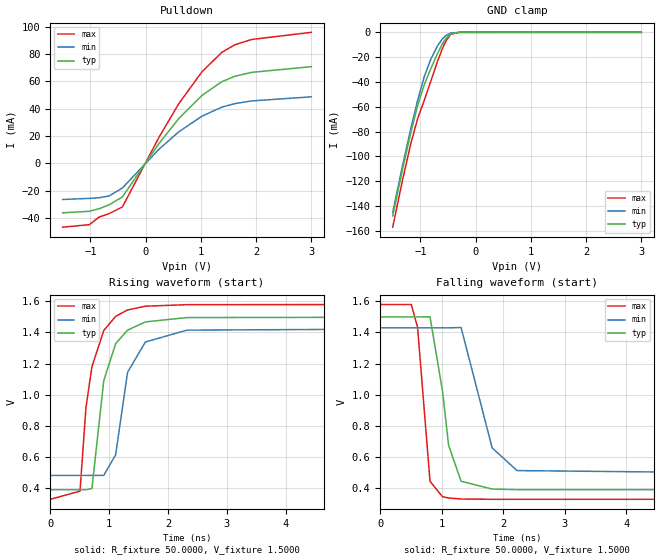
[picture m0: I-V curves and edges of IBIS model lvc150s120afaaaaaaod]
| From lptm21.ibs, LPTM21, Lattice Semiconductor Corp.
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|   Model lvc150s120afaaaaaaod
[Model]   lvc150s120afaaaaaaod
Model_type   I/O_open_drain
Polarity   Non-Inverting
Enable   Active-Low
Vinl =   0.3750V
Vinh =   1.1250V
Vmeas =   0.7500V
Cref =   0.0F
Rref =   1.0000M
Vref =   0.0V
C_comp   4.2000pF   3.8000pF   7.5000pF
[Temperature Range]   25.0000   0.1050k   -40.0000
[Voltage Range]   1.5000V   1.4300V   1.5800V
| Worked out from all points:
|   slope of the pulldown table from 0 to 0.225 V, typ, clamps not added: 16.9 ohm
|   GND clamp passes 1 mA (typ) near -0.44 V on its own axis
|   rising waveform, R_fixture 50.0000, V_fixture 1.5000: 20-80 % time 292ps typ, 280ps min, 267ps max; typ from 0.389 V to 1.5 V
|   falling waveform, R_fixture 50.0000, V_fixture 1.5000: 20-80 % time 204ps typ, 291ps min, 146ps max; typ from 1.5 V to 0.389 V
[Pulldown]
|Voltage   I(typ)   I(min)   I(max)
-1.5V     -36.33mA   -26.58mA   -46.82mA
-1.02V    -35.21mA   -25.76mA   -45.04mA
-840mV    -33.33mA   -25.3mA    -39.43mA
-660mV    -30.45mA   -23.96mA   -36.92mA
-420mV    -24.73mA   -18.16mA   -32.05mA
240mV     14.2mA     10.09mA    18.72mA
600mV     32.61mA    22.93mA    43.45mA
1.02V     49.55mA    34.38mA    66.84mA
1.38V     59.62mA    40.99mA    81.09mA
1.62V     63.63mA    43.62mA    86.71mA
1.92V     66.45mA    45.54mA    90.51mA
3V        70.61mA    48.55mA    95.74mA
[GND_clamp]
|Voltage   I(typ)   I(min)   I(max)
-1.5V     -148.1mA   -145.2mA   -157.1mA
-1.32V    -110.1mA   -107mA     -118.7mA
-1.17V    -80.47mA   -77.11mA   -89.33mA
-1.05V    -59.24mA   -55.01mA   -69.75mA
-930mV    -42.27mA   -35.92mA   -54.95mA
-810mV    -29.3mA    -21.61mA   -39.32mA
-690mV    -17.14mA   -10.88mA   -23.55mA
-600mV    -9.267mA   -5.265mA   -13.06mA
-540mV    -5.068mA   -2.658mA   -7.239mA
-450mV    -1.182mA   -586.7uA   -1.592mA
-300mV    -18.83uA   -15.98uA   -16.74uA
3V        0A         0A         0A
[Ramp]
| variable   typ   min   max
dV/dt_r  0.6668/0.2894n   0.5695/0.2769n   0.7519/0.2648n
dV/dt_f  0.6668/0.2022n   0.5695/0.2880n   0.7519/0.1442n
R_load = 50.0000
[Rising Waveform]
R_fixture=   50.0000
V_fixture=   1.5000
V_fixture_min=   1.4300
V_fixture_max=   1.5800
|time   V(typ)   V(min)   V(max)
0s        388.7mV    480.7mV    326.9mV
505.1ps   388.7mV    480.7mV    379.8mV
606.1ps   388.9mV    480.7mV    916.8mV
707.1ps   395.9mV    480.8mV    1.179V
909.1ps   1.091V     481mV      1.413V
1.111ns   1.328V     613.9mV    1.504V
1.313ns   1.415V     1.144V     1.545V
1.616ns   1.468V     1.339V     1.569V
2.323ns   1.496V     1.415V     1.579V
10ns      1.5V       1.43V      1.58V
[Falling Waveform]
R_fixture=   50.0000
V_fixture=   1.5000
V_fixture_min=   1.4300
V_fixture_max=   1.5800
|time   V(typ)   V(min)   V(max)
0s        1.5V       1.43V      1.58V
505.1ps   1.5V       1.43V      1.58V
606.1ps   1.5V       1.43V      1.433V
808.1ps   1.501V     1.43V      443.1mV
1.01ns    1.026V     1.43V      343.9mV
1.111ns   674.1mV    1.43V      335.5mV
1.313ns   443.3mV    1.432V     329.1mV
1.818ns   392.9mV    657.6mV    327mV
2.222ns   389.4mV    511.8mV    326.9mV
10ns      388.7mV    480.7mV    326.9mV
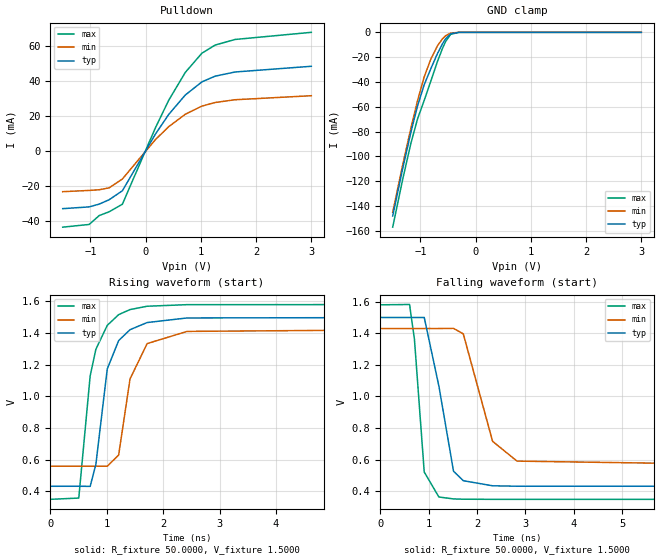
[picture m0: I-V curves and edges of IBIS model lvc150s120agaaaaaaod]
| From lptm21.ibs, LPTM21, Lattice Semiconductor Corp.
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|   Model lvc150s120agaaaaaaod
[Model]   lvc150s120agaaaaaaod
Model_type   I/O_open_drain
Polarity   Non-Inverting
Enable   Active-Low
Vinl =   0.3750V
Vinh =   1.1250V
Vmeas =   0.7500V
Cref =   0.0F
Rref =   1.0000M
Vref =   0.0V
C_comp   4.2000pF   3.8000pF   7.5000pF
[Temperature Range]   25.0000   0.1050k   -40.0000
[Voltage Range]   1.5000V   1.4300V   1.5800V
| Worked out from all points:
|   slope of the pulldown table from 0 to 0.225 V, typ, clamps not added: 18.8 ohm
|   GND clamp passes 1 mA (typ) near -0.44 V on its own axis
|   rising waveform, R_fixture 50.0000, V_fixture 1.5000: 20-80 % time 283ps typ, 299ps min, 292ps max; typ from 0.432 V to 1.5 V
|   falling waveform, R_fixture 50.0000, V_fixture 1.5000: 20-80 % time 266ps typ, 444ps min, 174ps max; typ from 1.5 V to 0.432 V
[Pulldown]
|Voltage   I(typ)   I(min)   I(max)
-1.5V     -32.91mA   -23.23mA   -43.46mA
-1.02V    -31.9mA    -22.52mA   -41.92mA
-840mV    -30.32mA   -22.14mA   -36.85mA
-660mV    -27.83mA   -21.05mA   -34.7mA
-420mV    -22.72mA   -15.98mA   -30.38mA
180mV     9.699mA    6.515mA    13.33mA
420mV     20.87mA    13.88mA    28.97mA
720mV     31.92mA    20.94mA    44.83mA
1.02V     39.39mA    25.58mA    55.75mA
1.26V     42.65mA    27.63mA    60.38mA
1.62V     45.02mA    29.2mA     63.57mA
3V        48.28mA    31.49mA    67.64mA
[GND_clamp]
|Voltage   I(typ)   I(min)   I(max)
-1.5V     -148.1mA   -145.1mA   -157.1mA
-1.32V    -110mA     -107mA     -118.7mA
-1.17V    -80.46mA   -77.1mA    -89.31mA
-1.05V    -59.23mA   -55mA      -69.72mA
-930mV    -42.26mA   -35.91mA   -54.92mA
-810mV    -29.29mA   -21.6mA    -39.3mA
-690mV    -17.13mA   -10.88mA   -23.54mA
-600mV    -9.258mA   -5.26mA    -13.05mA
-540mV    -5.061mA   -2.654mA   -7.228mA
-450mV    -1.178mA   -585.4uA   -1.585mA
-300mV    -18.71uA   -15.93uA   -16.54uA
3V        0A         0A         0A
[Ramp]
| variable   typ   min   max
dV/dt_r  0.6410/0.2803n   0.5229/0.2960n   0.7385/0.2887n
dV/dt_f  0.6410/0.2633n   0.5229/0.4393n   0.7384/0.1728n
R_load = 50.0000
[Rising Waveform]
R_fixture=   50.0000
V_fixture=   1.5000
V_fixture_min=   1.4300
V_fixture_max=   1.5800
|time   V(typ)   V(min)   V(max)
0s        431.7mV    558.4mV    349.2mV
505.1ps   431.8mV    558.4mV    357.2mV
707.1ps   431.1mV    558.4mV    1.129V
808.1ps   569.6mV    558.5mV    1.297V
1.01ns    1.173V     558.5mV    1.448V
1.212ns   1.352V     629mV      1.516V
1.414ns   1.421V     1.11V      1.548V
1.717ns   1.466V     1.333V     1.569V
2.424ns   1.495V     1.41V      1.579V
10ns      1.5V       1.43V      1.58V
[Falling Waveform]
R_fixture=   50.0000
V_fixture=   1.5000
V_fixture_min=   1.4300
V_fixture_max=   1.5800
|time   V(typ)   V(min)   V(max)
0s        1.5V       1.43V      1.58V
606.1ps   1.5V       1.43V      1.582V
707.1ps   1.5V       1.43V      1.36V
909.1ps   1.5V       1.43V      522.2mV
1.212ns   1.066V     1.43V      364.1mV
1.515ns   527.3mV    1.431V     351.8mV
1.717ns   467.2mV    1.396V     350mV
2.323ns   434.9mV    716.2mV    349.3mV
2.828ns   432.3mV    591.1mV    349.3mV
10ns      431.7mV    558.5mV    349.3mV
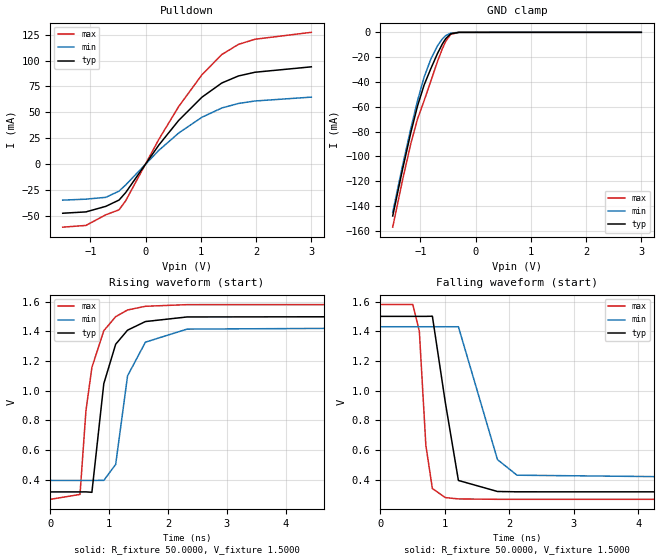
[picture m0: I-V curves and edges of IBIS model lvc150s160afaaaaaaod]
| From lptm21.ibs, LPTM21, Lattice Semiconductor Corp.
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|   Model lvc150s160afaaaaaaod
[Model]   lvc150s160afaaaaaaod
Model_type   I/O_open_drain
Polarity   Non-Inverting
Enable   Active-Low
Vinl =   0.3750V
Vinh =   1.1250V
Vmeas =   0.7500V
Cref =   0.0F
Rref =   1.0000M
Vref =   0.0V
C_comp   4.2000pF   3.8000pF   7.5000pF
[Temperature Range]   25.0000   0.1050k   -40.0000
[Voltage Range]   1.5000V   1.4300V   1.5800V
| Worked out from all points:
|   slope of the pulldown table from 0 to 0.225 V, typ, clamps not added: 13.1 ohm
|   GND clamp passes 1 mA (typ) near -0.44 V on its own axis
|   rising waveform, R_fixture 50.0000, V_fixture 1.5000: 20-80 % time 295ps typ, 280ps min, 268ps max; typ from 0.316 V to 1.5 V
|   falling waveform, R_fixture 50.0000, V_fixture 1.5000: 20-80 % time 172ps typ, 265ps min, 125ps max; typ from 1.5 V to 0.316 V
[Pulldown]
|Voltage   I(typ)   I(min)   I(max)
-1.5V     -47.78mA   -35.09mA   -61.26mA
-1.08V    -46.49mA   -34.15mA   -59.6mA
-720mV    -41.11mA   -32.38mA   -49.29mA
-480mV    -35mA      -26.35mA   -44.46mA
-360mV    -27.76mA   -20.4mA    -35.71mA
240mV     18.25mA    13.11mA    23.78mA
600mV     42.17mA    29.94mA    55.58mA
1.02V     64.58mA    45.16mA    86.31mA
1.38V     78.35mA    54.14mA    105.9mA
1.68V     85.13mA    58.5mA     115.7mA
1.98V     88.74mA    60.91mA    120.7mA
3V        93.99mA    64.65mA    127.4mA
[GND_clamp]
|Voltage   I(typ)   I(min)   I(max)
-1.5V     -148.1mA   -145.2mA   -157.1mA
-1.32V    -110.1mA   -107mA     -118.7mA
-1.17V    -80.47mA   -77.11mA   -89.33mA
-1.05V    -59.24mA   -55.01mA   -69.75mA
-930mV    -42.27mA   -35.92mA   -54.95mA
-810mV    -29.3mA    -21.61mA   -39.32mA
-690mV    -17.14mA   -10.88mA   -23.55mA
-600mV    -9.267mA   -5.265mA   -13.06mA
-540mV    -5.068mA   -2.658mA   -7.239mA
-450mV    -1.182mA   -586.7uA   -1.592mA
-300mV    -18.83uA   -15.98uA   -16.74uA
3V        0A         0A         0A
[Ramp]
| variable   typ   min   max
dV/dt_r  0.7102/0.2917n   0.6217/0.2775n   0.7881/0.2650n
dV/dt_f  0.7102/0.1704n   0.6217/0.2625n   0.7882/0.1240n
R_load = 50.0000
[Rising Waveform]
R_fixture=   50.0000
V_fixture=   1.5000
V_fixture_min=   1.4300
V_fixture_max=   1.5800
|time   V(typ)   V(min)   V(max)
0s        316.4mV    393.9mV    266.4mV
505.1ps   316.4mV    393.9mV    299.4mV
606.1ps   316.6mV    393.9mV    864.4mV
707.1ps   313.7mV    393.9mV    1.156V
909.1ps   1.046V     394.1mV    1.403V
1.111ns   1.312V     501.7mV    1.498V
1.313ns   1.407V     1.099V     1.543V
1.616ns   1.465V     1.326V     1.568V
2.323ns   1.496V     1.414V     1.579V
10ns      1.5V       1.43V      1.58V
[Falling Waveform]
R_fixture=   50.0000
V_fixture=   1.5000
V_fixture_min=   1.4300
V_fixture_max=   1.5800
|time   V(typ)   V(min)   V(max)
0s        1.5V       1.43V      1.58V
505.1ps   1.5V       1.43V      1.58V
606.1ps   1.5V       1.43V      1.399V
707.1ps   1.5V       1.43V      630.2mV
808.1ps   1.501V     1.43V      339.1mV
1.01ns    916.7mV    1.43V      278mV
1.212ns   393.7mV    1.43V      269.2mV
1.818ns   319.3mV    534.2mV    266.5mV
2.121ns   317.1mV    429.1mV    266.5mV
10ns      316.4mV    393.9mV    266.4mV
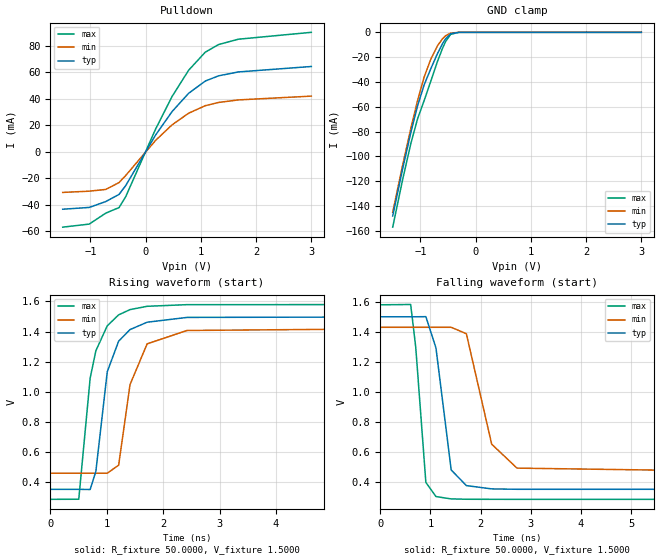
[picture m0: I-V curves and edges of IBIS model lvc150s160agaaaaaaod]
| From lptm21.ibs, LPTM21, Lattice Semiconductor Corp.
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|   Model lvc150s160agaaaaaaod
[Model]   lvc150s160agaaaaaaod
Model_type   I/O_open_drain
Polarity   Non-Inverting
Enable   Active-Low
Vinl =   0.3750V
Vinh =   1.1250V
Vmeas =   0.7500V
Cref =   0.0F
Rref =   1.0000M
Vref =   0.0V
C_comp   4.2000pF   3.8000pF   7.5000pF
[Temperature Range]   25.0000   0.1050k   -40.0000
[Voltage Range]   1.5000V   1.4300V   1.5800V
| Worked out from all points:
|   slope of the pulldown table from 0 to 0.225 V, typ, clamps not added: 14.6 ohm
|   GND clamp passes 1 mA (typ) near -0.44 V on its own axis
|   rising waveform, R_fixture 50.0000, V_fixture 1.5000: 20-80 % time 289ps typ, 300ps min, 295ps max; typ from 0.349 V to 1.5 V
|   falling waveform, R_fixture 50.0000, V_fixture 1.5000: 20-80 % time 234ps typ, 383ps min, 163ps max; typ from 1.5 V to 0.349 V
[Pulldown]
|Voltage   I(typ)   I(min)   I(max)
-1.5V     -43.39mA   -30.72mA   -56.93mA
-1.02V    -42.05mA   -29.78mA   -54.61mA
-720mV    -37.59mA   -28.47mA   -46.33mA
-480mV    -32.21mA   -23.27mA   -42.16mA
-360mV    -25.58mA   -17.97mA   -33.97mA
180mV     12.51mA    8.495mA    16.97mA
480mV     30.31mA    20.29mA    41.7mA
780mV     44.1mA     29.07mA    61.52mA
1.08V     53.3mA     34.72mA    75.1mA
1.32V     57.26mA    37.17mA    80.85mA
1.68V     60.2mA     39.09mA    84.9mA
3V        64.31mA    41.95mA    90.09mA
[GND_clamp]
|Voltage   I(typ)   I(min)   I(max)
-1.5V     -148.1mA   -145.1mA   -157.1mA
-1.32V    -110mA     -107mA     -118.7mA
-1.17V    -80.46mA   -77.1mA    -89.31mA
-1.05V    -59.23mA   -55mA      -69.72mA
-930mV    -42.26mA   -35.91mA   -54.92mA
-810mV    -29.29mA   -21.6mA    -39.3mA
-690mV    -17.13mA   -10.88mA   -23.54mA
-600mV    -9.258mA   -5.26mA    -13.05mA
-540mV    -5.061mA   -2.654mA   -7.228mA
-450mV    -1.178mA   -585.4uA   -1.585mA
-300mV    -18.71uA   -15.93uA   -16.54uA
3V        0A         0A         0A
[Ramp]
| variable   typ   min   max
dV/dt_r  0.6905/0.2861n   0.5841/0.2969n   0.7784/0.2923n
dV/dt_f  0.6905/0.2321n   0.5841/0.3788n   0.7784/0.1615n
R_load = 50.0000
[Rising Waveform]
R_fixture=   50.0000
V_fixture=   1.5000
V_fixture_min=   1.4300
V_fixture_max=   1.5800
|time   V(typ)   V(min)   V(max)
0s        349.1mV    456.5mV    282.6mV
505.1ps   349.1mV    456.5mV    283.2mV
707.1ps   348.1mV    456.5mV    1.09V
808.1ps   468.6mV    456.5mV    1.272V
1.01ns    1.132V     456.7mV    1.438V
1.212ns   1.336V     509.9mV    1.511V
1.414ns   1.413V     1.047V     1.546V
1.717ns   1.462V     1.318V     1.568V
2.424ns   1.494V     1.407V     1.579V
10ns      1.5V       1.43V      1.58V
[Falling Waveform]
R_fixture=   50.0000
V_fixture=   1.5000
V_fixture_min=   1.4300
V_fixture_max=   1.5800
|time   V(typ)   V(min)   V(max)
0s        1.5V       1.43V      1.58V
606.1ps   1.5V       1.43V      1.582V
707.1ps   1.5V       1.43V      1.298V
909.1ps   1.501V     1.43V      395.7mV
1.111ns   1.292V     1.43V      300.9mV
1.414ns   478.6mV    1.43V      285.5mV
1.717ns   374.2mV    1.387V     283.1mV
2.222ns   352.2mV    650.4mV    282.7mV
2.727ns   349.6mV    490.7mV    282.6mV
10ns      349.1mV    456.5mV    282.6mV
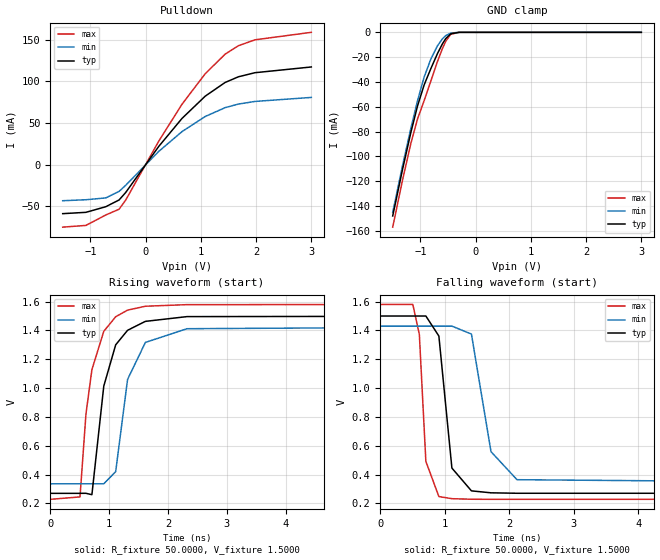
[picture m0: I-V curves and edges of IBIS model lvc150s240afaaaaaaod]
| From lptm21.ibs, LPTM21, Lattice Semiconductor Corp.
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|   Model lvc150s240afaaaaaaod
[Model]   lvc150s240afaaaaaaod
Model_type   I/O_open_drain
Polarity   Non-Inverting
Enable   Active-Low
Vinl =   0.3750V
Vinh =   1.1250V
Vmeas =   0.7500V
Cref =   0.0F
Rref =   1.0000M
Vref =   0.0V
C_comp   4.2000pF   3.8000pF   7.5000pF
[Temperature Range]   25.0000   0.1050k   -40.0000
[Voltage Range]   1.5000V   1.4300V   1.5800V
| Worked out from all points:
|   slope of the pulldown table from 0 to 0.225 V, typ, clamps not added: 10.9 ohm
|   GND clamp passes 1 mA (typ) near -0.44 V on its own axis
|   rising waveform, R_fixture 50.0000, V_fixture 1.5000: 20-80 % time 295ps typ, 286ps min, 271ps max; typ from 0.27 V to 1.5 V
|   falling waveform, R_fixture 50.0000, V_fixture 1.5000: 20-80 % time 163ps typ, 235ps min, 93.1ps max; typ from 1.5 V to 0.27 V
[Pulldown]
|Voltage   I(typ)   I(min)   I(max)
-1.5V     -58.88mA   -43.34mA   -75.09mA
-1.08V    -57.29mA   -42.17mA   -73mA
-720mV    -50.52mA   -39.95mA   -60.48mA
-480mV    -42.45mA   -32.15mA   -53.52mA
-360mV    -33.46mA   -24.81mA   -42.61mA
240mV     22.01mA    15.98mA    28.37mA
660mV     55.54mA    39.7mA     72.61mA
1.08V     82.25mA    57.82mA    109.2mA
1.44V     98.69mA    68.43mA    132.7mA
1.68V     105.5mA    72.73mA    142.8mA
1.98V     110.4mA    75.9mA     149.9mA
3V        117.3mA    80.72mA    158.9mA
[GND_clamp]
|Voltage   I(typ)   I(min)   I(max)
-1.5V     -148.1mA   -145.2mA   -157.1mA
-1.32V    -110.1mA   -107mA     -118.7mA
-1.17V    -80.47mA   -77.11mA   -89.33mA
-1.05V    -59.24mA   -55.01mA   -69.75mA
-930mV    -42.27mA   -35.92mA   -54.95mA
-810mV    -29.3mA    -21.61mA   -39.32mA
-690mV    -17.14mA   -10.88mA   -23.55mA
-600mV    -9.267mA   -5.265mA   -13.06mA
-540mV    -5.068mA   -2.658mA   -7.239mA
-450mV    -1.182mA   -586.7uA   -1.592mA
-300mV    -18.83uA   -15.98uA   -16.74uA
3V        0A         0A         0A
[Ramp]
| variable   typ   min   max
dV/dt_r  0.7381/0.2924n   0.6564/0.2834n   0.8110/0.2685n
dV/dt_f  0.7381/0.1614n   0.6564/0.2327n   0.8110/92.1376p
R_load = 50.0000
[Rising Waveform]
R_fixture=   50.0000
V_fixture=   1.5000
V_fixture_min=   1.4300
V_fixture_max=   1.5800
|time   V(typ)   V(min)   V(max)
0s        269.8mV    336mV      228.2mV
505.1ps   269.8mV    336mV      245mV
606.1ps   270mV      336mV      819.9mV
707.1ps   260.5mV    336mV      1.128V
909.1ps   1.014V     336.2mV    1.394V
1.111ns   1.3V       420.2mV    1.495V
1.313ns   1.401V     1.06V      1.541V
1.616ns   1.463V     1.317V     1.568V
2.323ns   1.496V     1.412V     1.579V
10ns      1.5V       1.43V      1.58V
[Falling Waveform]
R_fixture=   50.0000
V_fixture=   1.5000
V_fixture_min=   1.4300
V_fixture_max=   1.5800
|time   V(typ)   V(min)   V(max)
0s        1.5V       1.43V      1.58V
505.1ps   1.5V       1.43V      1.58V
606.1ps   1.5V       1.43V      1.372V
707.1ps   1.5V       1.43V      491.4mV
909.1ps   1.361V     1.43V      247.4mV
1.111ns   445.1mV    1.43V      232.7mV
1.414ns   287mV      1.375V     228.8mV
1.717ns   273.4mV    559.2mV    228.3mV
2.121ns   270.3mV    364.4mV    228.3mV
10ns      269.8mV    336mV      228.2mV
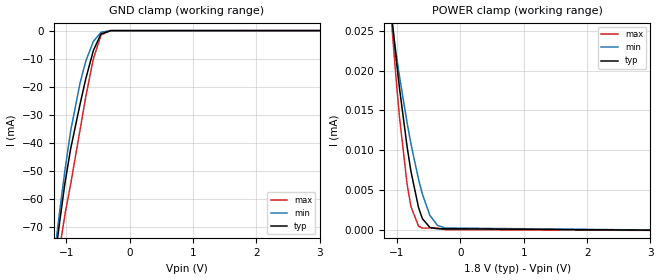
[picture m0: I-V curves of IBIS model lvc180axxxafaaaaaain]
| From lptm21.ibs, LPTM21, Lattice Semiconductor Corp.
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|   Model lvc180axxxafaaaaaain
[Model]   lvc180axxxafaaaaaain
Model_type   Input
Polarity   Non-Inverting
Enable   Active-Low
Vinl =   0.6300V
Vinh =   1.1700V
C_comp   4.2000pF   3.8000pF   7.5000pF
[Temperature Range]   25.0000   0.1050k   -40.0000
[Voltage Range]   1.8000V   1.7100V   1.8900V
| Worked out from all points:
|   GND clamp passes 1 mA (typ) near -0.44 V on its own axis
[GND_clamp]
|Voltage   I(typ)   I(min)   I(max)
-1.8V     -240.2mA   -229.4mA   -254.3mA
-1.2V     -86.16mA   -82.91mA   -94.88mA
-1.17V    -80.45mA   -77.09mA   -89.3mA
-1.11V    -69.45mA   -65.77mA   -78.87mA
-1.02V    -54.48mA   -49.86mA   -65.69mA
-930mV    -42.25mA   -35.9mA    -54.92mA
-780mV    -26.14mA   -18.58mA   -35.25mA
-690mV    -17.13mA   -10.87mA   -23.53mA
-570mV    -7.024mA   -3.834mA   -9.978mA
-450mV    -1.176mA   -584.6uA   -1.582mA
-300mV    -18.65uA   -15.9uA    -16.44uA
3.6V      0A         0A         0A
[POWER_clamp]
|Voltage   I(typ)   I(min)   I(max)
-1.8V     102.4uA    78.03uA    133.9uA
-1.08V    26.57uA    25.91uA    25.52uA
-1.02V    21.97uA    22.48uA    19.47uA
-960mV    17.73uA    19.24uA    14.09uA
-840mV    10.4uA     13.41uA    5.722uA
-780mV    7.368uA    10.82uA    2.954uA
-660mV    2.829uA    6.357uA    503.7nA
-600mV    1.451uA    4.527uA    262.8nA
-480mV    333.1nA    1.844uA    262.8nA
-360mV    178.5nA    588.1nA    262.8nA
-240mV    178.5nA    271.5nA    57.44nA
3.6V      -31nA      -27.04nA   -40.53nA
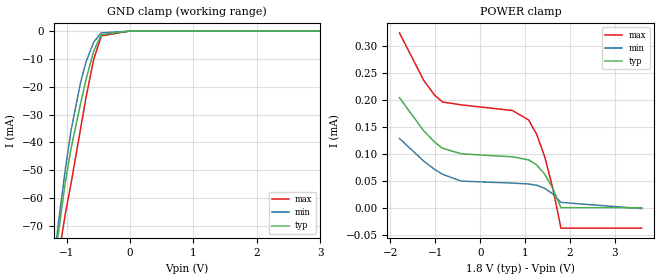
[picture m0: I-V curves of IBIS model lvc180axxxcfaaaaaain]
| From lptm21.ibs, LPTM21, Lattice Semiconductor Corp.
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|   Model lvc180axxxcfaaaaaain
[Model]   lvc180axxxcfaaaaaain
Model_type   Input
Polarity   Non-Inverting
Enable   Active-Low
Vinl =   0.6300V
Vinh =   1.1700V
C_comp   4.2000pF   3.8000pF   7.5000pF
[Temperature Range]   25.0000   0.1050k   -40.0000
[Voltage Range]   1.8000V   1.7100V   1.8900V
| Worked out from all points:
|   GND clamp passes 1 mA (typ) near -0.44 V on its own axis
[GND_clamp]
|Voltage   I(typ)   I(min)   I(max)
-1.8V     -240.2mA   -229.4mA   -254.3mA
-1.2V     -86.19mA   -82.93mA   -94.91mA
-1.17V    -80.47mA   -77.11mA   -89.34mA
-1.11V    -69.48mA   -65.79mA   -78.91mA
-1.02V    -54.51mA   -49.88mA   -65.73mA
-930mV    -42.28mA   -35.92mA   -54.97mA
-780mV    -26.18mA   -18.61mA   -35.3mA
-690mV    -17.17mA   -10.9mA    -23.59mA
-570mV    -7.078mA   -3.876mA   -10.05mA
-450mV    -1.251mA   -635.5uA   -1.696mA
0V        0A         0A         0A
3.6V      0A         0A         0A
[POWER_clamp]
|Voltage   I(typ)   I(min)   I(max)
-1.8V     203.7uA    128.2uA    323.8uA
-1.26V    142.4uA    86.29uA    236uA
-1.02V    121.8uA    71.14uA    208.7uA
-840mV    110.1uA    61.88uA    195.8uA
-420mV    99.75uA    49.18uA    190.5uA
720mV     94.2uA     45.56uA    180uA
1.08V     88.67uA    43.9uA     162.5uA
1.26V     79.17uA    41.55uA    135.8uA
1.44V     61.82uA    35.76uA    94.02uA
1.62V     35.65uA    25.36uA    35.72uA
1.8V      -30.34nA   9.798uA    -37.95uA
3.6V      -30.34nA   -1.798uA   -37.95uA
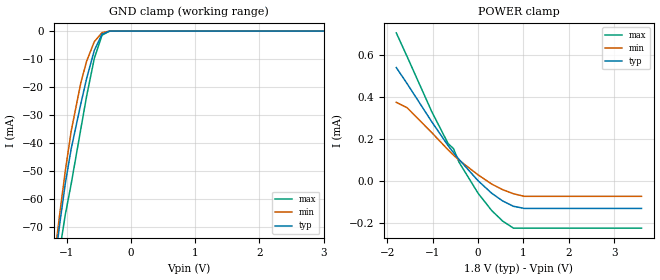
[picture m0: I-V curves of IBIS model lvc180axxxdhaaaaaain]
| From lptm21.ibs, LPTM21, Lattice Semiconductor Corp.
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|   Model lvc180axxxdhaaaaaain
[Model]   lvc180axxxdhaaaaaain
Model_type   Input
Polarity   Non-Inverting
Enable   Active-Low
Vinl =   0.6300V
Vinh =   1.1700V
C_comp   4.2000pF   3.8000pF   7.5000pF
[Temperature Range]   25.0000   0.1050k   -40.0000
[Voltage Range]   1.8000V   1.7100V   1.8900V
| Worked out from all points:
|   GND clamp passes 1 mA (typ) near -0.44 V on its own axis
[GND_clamp]
|Voltage   I(typ)   I(min)   I(max)
-1.8V     -240.1mA   -229.3mA   -254.1mA
-1.2V     -86.06mA   -82.86mA   -94.69mA
-1.17V    -80.34mA   -77.04mA   -89.11mA
-1.11V    -69.35mA   -65.72mA   -78.69mA
-1.02V    -54.38mA   -49.81mA   -65.51mA
-930mV    -42.15mA   -35.85mA   -54.74mA
-780mV    -26.05mA   -18.53mA   -35.08mA
-690mV    -17.04mA   -10.83mA   -23.36mA
-570mV    -6.946mA   -3.801mA   -9.827mA
-450mV    -1.119mA   -561.2uA   -1.47mA
-330mV    0A         -3.874uA   0A
3.6V      0A         0A         0A
[POWER_clamp]
|Voltage   I(typ)   I(min)   I(max)
-1.8V     538.6uA    373.2uA    703.6uA
-1.56V    461.4uA    347.2uA    589.9uA
-1.02V    280.9uA    229uA      329.2uA
-660mV    167.1uA    147.2uA    177.1uA
-540mV    133.5uA    121.8uA    152.7uA
-420mV    101.7uA    98.16uA    88.49uA
0V        38.11nA    27.94uA    -59.25uA
300mV     -59.54uA   -15.82uA   -141.8uA
540mV     -96.02uA   -42.44uA   -191.8uA
780mV     -121.8uA   -62.04uA   -225.9uA
1.02V     -132uA     -74.33uA   -225.9uA
3.6V      -132uA     -74.33uA   -225.9uA
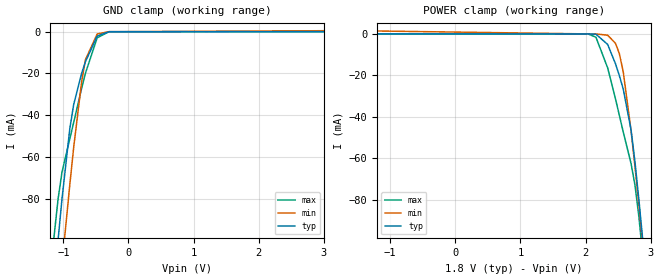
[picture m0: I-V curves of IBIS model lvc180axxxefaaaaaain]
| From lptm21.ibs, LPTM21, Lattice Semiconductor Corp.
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|   Model lvc180axxxefaaaaaain
[Model]   lvc180axxxefaaaaaain
Model_type   Input
Polarity   Non-Inverting
Enable   Active-Low
Vinl =   0.6300V
Vinh =   1.1700V
C_comp   4.2000pF   3.8000pF   7.5000pF
[Temperature Range]   25.0000   0.1050k   -40.0000
[Voltage Range]   1.8000V   1.7100V   1.8900V
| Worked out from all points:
|   GND clamp passes 1 mA (typ) near -0.44 V on its own axis
[GND_clamp]
|Voltage   I(typ)   I(min)   I(max)
-1.8V     -365.5mA   -387.4mA   -346.6mA
-1.2V     -141.4mA   -172.4mA   -117.3mA
-1.14V    -120.2mA   -151.8mA   -97.39mA
-1.08V    -99.68mA   -131.5mA   -80.05mA
-1.02V    -80.04mA   -111.5mA   -67.22mA
-900mV    -46.39mA   -73.21mA   -51.28mA
-840mV    -34.79mA   -55.27mA   -43.38mA
-720mV    -20.15mA   -24.34mA   -27.36mA
-660mV    -14.37mA   -13.41mA   -19.88mA
-480mV    -2.111mA   -1.105mA   -2.962mA
-300mV    -19.49uA   -16.9uA    -17.45uA
3.6V      15.74uA    548uA      2.733uA
[POWER_clamp]
|Voltage   I(typ)   I(min)   I(max)
-1.8V     15.74uA    1.672mA    2.197uA
2.04V     -3.145uA   -819.4nA   -46.53uA
2.16V     -119.1uA   -7.821uA   -1.593mA
2.34V     -5.068mA   -613uA     -16.37mA
2.46V     -14.37mA   -4.507mA   -31.28mA
2.52V     -20.15mA   -9.529mA   -39.32mA
2.58V     -26.67mA   -18.37mA   -47.39mA
2.7V      -46.39mA   -46.77mA   -62.61mA
2.76V     -61.91mA   -64.1mA    -72.98mA
2.82V     -80.04mA   -82.54mA   -88.29mA
2.88V     -99.68mA   -101.7mA   -107.1mA
3.6V      -365.5mA   -354.5mA   -382.3mA
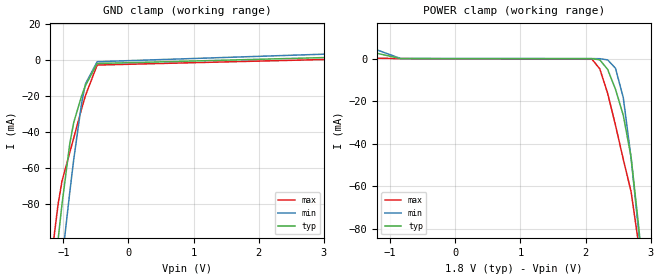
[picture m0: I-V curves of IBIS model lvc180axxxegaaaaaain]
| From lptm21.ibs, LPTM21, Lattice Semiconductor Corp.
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|   Model lvc180axxxegaaaaaain
[Model]   lvc180axxxegaaaaaain
Model_type   Input
Polarity   Non-Inverting
Enable   Active-Low
Vinl =   0.6300V
Vinh =   1.1700V
C_comp   4.2000pF   3.8000pF   7.5000pF
[Temperature Range]   25.0000   0.1050k   -40.0000
[Voltage Range]   1.8000V   1.7100V   1.8900V
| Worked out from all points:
|   GND clamp passes 1 mA (typ) near -0.44 V on its own axis
|   POWER clamp passes 1 mA (typ) near -1.24 V on its own axis
[GND_clamp]
|Voltage   I(typ)   I(min)   I(max)
-1.8V     -365.5mA   -387.4mA   -346.6mA
-1.2V     -141.4mA   -172.4mA   -117.3mA
-1.14V    -120.2mA   -151.8mA   -97.38mA
-1.08V    -99.67mA   -131.5mA   -80.04mA
-1.02V    -80.04mA   -111.5mA   -67.2mA
-900mV    -46.38mA   -73.21mA   -51.26mA
-840mV    -34.78mA   -55.26mA   -43.36mA
-720mV    -20.14mA   -24.33mA   -27.34mA
-660mV    -14.36mA   -13.41mA   -19.86mA
-480mV    -2.106mA   -1.103mA   -2.953mA
3.06V     1.235mA    3.133mA    161.7uA
3.6V      13.15mA    10.82mA    16.75mA
[POWER_clamp]
|Voltage   I(typ)   I(min)   I(max)
-1.8V     13.15mA    12.1mA     13.7mA
-1.38V    3.737mA    6.084mA    299.2uA
-840mV    952.3nA    56.04uA    542.5nA
2.1V      -19.24uA   -1.787uA   -311.8uA
2.22V     -594.5uA   -36.2uA    -4.856mA
2.34V     -5.062mA   -611.7uA   -16.35mA
2.46V     -14.36mA   -4.503mA   -31.26mA
2.58V     -26.66mA   -18.36mA   -47.37mA
2.7V      -46.38mA   -46.77mA   -62.59mA
2.82V     -80.04mA   -82.54mA   -88.27mA
2.88V     -99.67mA   -101.7mA   -107.1mA
3.6V      -365.5mA   -354.5mA   -382.3mA
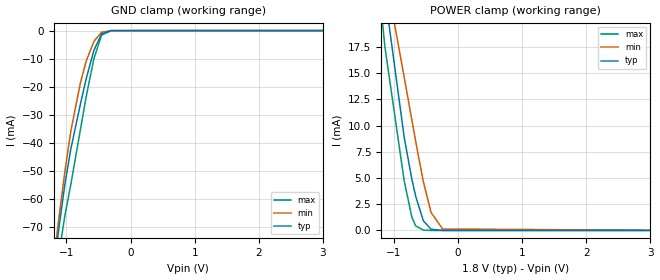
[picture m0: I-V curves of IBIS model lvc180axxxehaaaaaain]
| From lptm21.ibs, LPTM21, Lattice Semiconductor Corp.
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|   Model lvc180axxxehaaaaaain
[Model]   lvc180axxxehaaaaaain
Model_type   Input
Polarity   Non-Inverting
Enable   Active-Low
Vinl =   0.6300V
Vinh =   1.1700V
C_comp   4.2000pF   3.8000pF   7.5000pF
[Temperature Range]   25.0000   0.1050k   -40.0000
[Voltage Range]   1.8000V   1.7100V   1.8900V
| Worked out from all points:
|   GND clamp passes 1 mA (typ) near -0.44 V on its own axis
|   POWER clamp passes 1 mA (typ) near -0.54 V on its own axis
[GND_clamp]
|Voltage   I(typ)   I(min)   I(max)
-1.8V     -240.2mA   -229.4mA   -254.3mA
-1.2V     -86.16mA   -82.91mA   -94.88mA
-1.17V    -80.45mA   -77.09mA   -89.3mA
-1.11V    -69.45mA   -65.77mA   -78.87mA
-1.02V    -54.48mA   -49.86mA   -65.69mA
-930mV    -42.25mA   -35.9mA    -54.92mA
-780mV    -26.14mA   -18.58mA   -35.25mA
-690mV    -17.13mA   -10.87mA   -23.53mA
-570mV    -7.024mA   -3.834mA   -9.978mA
-450mV    -1.176mA   -584.6uA   -1.582mA
-300mV    -18.65uA   -15.9uA    -16.44uA
3.6V      0A         0A         0A
[POWER_clamp]
|Voltage   I(typ)   I(min)   I(max)
-1.8V     52.51mA    44.24mA    59.69mA
-1.68V    47.44mA    41.17mA    52.62mA
-1.5V     39.45mA    36.1mA     41.14mA
-1.26V    28.3mA     28.66mA    24.99mA
-1.14V    22.57mA    24.76mA    17.52mA
-840mV    8.928mA    14.66mA    4.779mA
-720mV    4.91mA     10.55mA    1.28mA
-660mV    3.265mA    8.507mA    435.9uA
-540mV    921.6uA    4.64mA     35.01uA
-420mV    115.2uA    1.718mA    2.184uA
-240mV    3.289uA    139.9uA    57.44nA
3.6V      -31nA      -27.04nA   -40.53nA
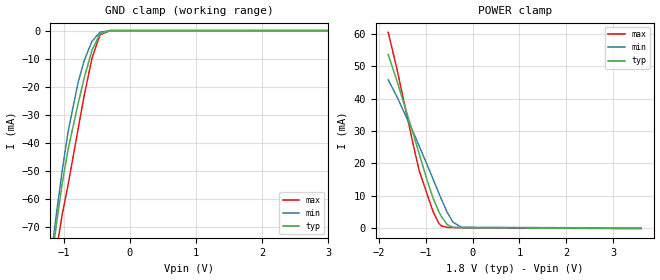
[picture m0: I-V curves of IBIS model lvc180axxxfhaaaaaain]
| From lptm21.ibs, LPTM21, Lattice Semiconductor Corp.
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|   Model lvc180axxxfhaaaaaain
[Model]   lvc180axxxfhaaaaaain
Model_type   Input
Polarity   Non-Inverting
Enable   Active-Low
Vinl =   0.6300V
Vinh =   1.1700V
C_comp   4.2000pF   3.8000pF   7.5000pF
[Temperature Range]   25.0000   0.1050k   -40.0000
[Voltage Range]   1.8000V   1.7100V   1.8900V
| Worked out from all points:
|   GND clamp passes 1 mA (typ) near -0.44 V on its own axis
|   POWER clamp passes 1 mA (typ) near -0.54 V on its own axis
[GND_clamp]
|Voltage   I(typ)   I(min)   I(max)
-1.8V     -240.1mA   -229.3mA   -254mA
-1.2V     -86.06mA   -82.86mA   -94.68mA
-1.17V    -80.34mA   -77.04mA   -89.1mA
-1.11V    -69.35mA   -65.72mA   -78.68mA
-1.02V    -54.38mA   -49.81mA   -65.5mA
-930mV    -42.15mA   -35.85mA   -54.73mA
-780mV    -26.05mA   -18.53mA   -35.07mA
-690mV    -17.04mA   -10.83mA   -23.37mA
-570mV    -6.958mA   -3.808mA   -9.842mA
-450mV    -1.149mA   -576.7uA   -1.52mA
-300mV    -18.2uA    -16.01uA   -13uA
3.6V      0A         0A         0A
[POWER_clamp]
|Voltage   I(typ)   I(min)   I(max)
-1.8V     53.66mA    45.8mA     60.51mA
-1.62V    45.76mA    40.78mA    49.57mA
-1.26V    28.84mA    29.42mA    25.34mA
-1.14V    22.99mA    25.38mA    17.77mA
-960mV    14.31mA    19.19mA    10.02mA
-840mV    9.109mA    15mA       4.931mA
-720mV    5.041mA    10.79mA    1.399mA
-660mV    3.38mA     8.712mA    551.7uA
-540mV    1.01mA     4.773mA    153.1uA
-420mV    197.6uA    1.797mA    88.49uA
-240mV    59.36uA    194.4uA    21.2uA
3.6V      -142.9uA   -81.03uA   -252.6uA
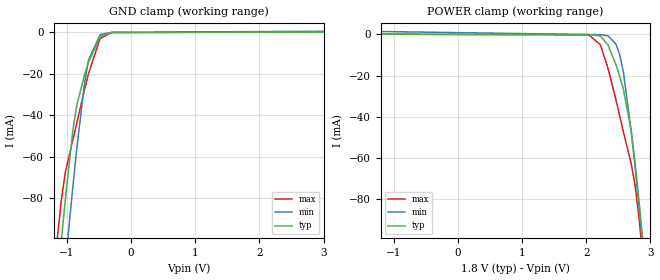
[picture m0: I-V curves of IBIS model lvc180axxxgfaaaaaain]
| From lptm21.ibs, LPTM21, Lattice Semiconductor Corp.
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|   Model lvc180axxxgfaaaaaain
[Model]   lvc180axxxgfaaaaaain
Model_type   Input
Polarity   Non-Inverting
Enable   Active-Low
Vinl =   0.6300V
Vinh =   1.1700V
C_comp   4.2000pF   3.8000pF   7.5000pF
[Temperature Range]   25.0000   0.1050k   -40.0000
[Voltage Range]   1.8000V   1.7100V   1.8900V
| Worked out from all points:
|   GND clamp passes 1 mA (typ) near -0.43 V on its own axis
[GND_clamp]
|Voltage   I(typ)   I(min)   I(max)
-1.8V     -365.5mA   -387.4mA   -346.6mA
-1.2V     -141.4mA   -172.5mA   -117.3mA
-1.14V    -120.2mA   -151.8mA   -97.42mA
-1.08V    -99.69mA   -131.5mA   -80.08mA
-1.02V    -80.06mA   -111.5mA   -67.26mA
-900mV    -46.42mA   -73.22mA   -51.33mA
-840mV    -34.83mA   -55.28mA   -43.43mA
-720mV    -20.19mA   -24.35mA   -27.41mA
-660mV    -14.41mA   -13.44mA   -19.94mA
-480mV    -2.179mA   -1.153mA   -3.06mA
-300mV    -89.25uA   -56.23uA   -136.3uA
3.6V      115.4uA    588.8uA    201.7uA
[POWER_clamp]
|Voltage   I(typ)   I(min)   I(max)
-1.8V     115.4uA    1.712mA    200.5uA
2.04V     -59.59uA   -19.59uA   -171.9uA
2.22V     -674.9uA   -79.63uA   -4.953mA
2.34V     -5.125mA   -663.2uA   -16.43mA
2.46V     -14.41mA   -4.545mA   -31.33mA
2.52V     -20.19mA   -9.558mA   -39.37mA
2.58V     -26.7mA    -18.39mA   -47.44mA
2.7V      -46.42mA   -46.78mA   -62.65mA
2.76V     -61.93mA   -64.11mA   -73.01mA
2.82V     -80.06mA   -82.55mA   -88.31mA
2.88V     -99.69mA   -101.7mA   -107.1mA
3.6V      -365.5mA   -354.5mA   -382.3mA
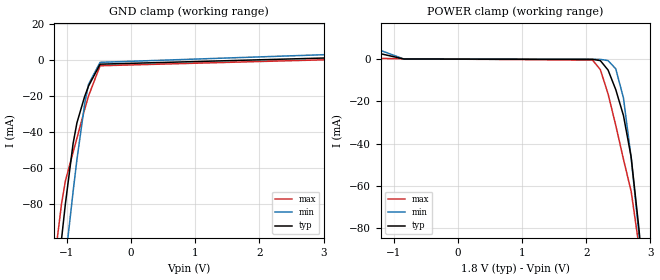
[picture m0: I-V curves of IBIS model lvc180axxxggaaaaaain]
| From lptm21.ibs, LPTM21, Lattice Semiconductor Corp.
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|   Model lvc180axxxggaaaaaain
[Model]   lvc180axxxggaaaaaain
Model_type   Input
Polarity   Non-Inverting
Enable   Active-Low
Vinl =   0.6300V
Vinh =   1.1700V
C_comp   4.2000pF   3.8000pF   7.5000pF
[Temperature Range]   25.0000   0.1050k   -40.0000
[Voltage Range]   1.8000V   1.7100V   1.8900V
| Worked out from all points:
|   GND clamp passes 1 mA (typ) near -0.43 V on its own axis
|   POWER clamp passes 1 mA (typ) near -1.23 V on its own axis
[GND_clamp]
|Voltage   I(typ)   I(min)   I(max)
-1.8V     -365.5mA   -387.4mA   -346.6mA
-1.2V     -141.4mA   -172.5mA   -117.3mA
-1.14V    -120.2mA   -151.8mA   -97.4mA
-1.08V    -99.69mA   -131.5mA   -80.07mA
-1.02V    -80.05mA   -111.5mA   -67.24mA
-900mV    -46.41mA   -73.22mA   -51.31mA
-840mV    -34.81mA   -55.27mA   -43.41mA
-720mV    -20.18mA   -24.35mA   -27.4mA
-660mV    -14.4mA    -13.43mA   -19.92mA
-480mV    -2.175mA   -1.151mA   -3.054mA
3.06V     1.305mA    3.175mA    310.5uA
3.6V      13.24mA    10.88mA    16.89mA
[POWER_clamp]
|Voltage   I(typ)   I(min)   I(max)
-1.8V     13.24mA    12.16mA    13.83mA
-1.38V    3.811mA    6.131mA    436.9uA
-840mV    101.8uA    100.9uA    192.8uA
2.1V      -89.05uA   -28.7uA    -440.3uA
2.22V     -673.3uA   -79.43uA   -4.946mA
2.34V     -5.12mA    -662.2uA   -16.42mA
2.46V     -14.4mA    -4.542mA   -31.31mA
2.58V     -26.69mA   -18.38mA   -47.42mA
2.7V      -46.41mA   -46.78mA   -62.63mA
2.82V     -80.05mA   -82.55mA   -88.3mA
2.88V     -99.69mA   -101.7mA   -107.1mA
3.6V      -365.5mA   -354.5mA   -382.3mA
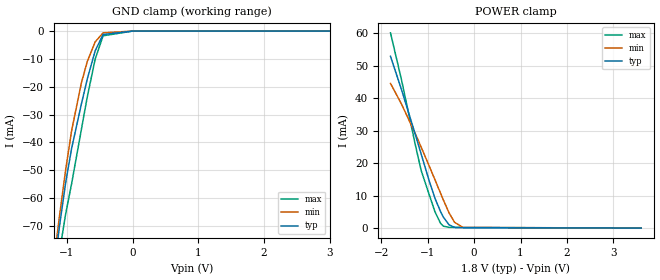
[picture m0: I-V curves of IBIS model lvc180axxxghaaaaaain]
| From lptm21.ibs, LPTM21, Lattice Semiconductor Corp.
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|   Model lvc180axxxghaaaaaain
[Model]   lvc180axxxghaaaaaain
Model_type   Input
Polarity   Non-Inverting
Enable   Active-Low
Vinl =   0.6300V
Vinh =   1.1700V
C_comp   4.2000pF   3.8000pF   7.5000pF
[Temperature Range]   25.0000   0.1050k   -40.0000
[Voltage Range]   1.8000V   1.7100V   1.8900V
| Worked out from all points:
|   GND clamp passes 1 mA (typ) near -0.44 V on its own axis
|   POWER clamp passes 1 mA (typ) near -0.54 V on its own axis
[GND_clamp]
|Voltage   I(typ)   I(min)   I(max)
-1.8V     -240.2mA   -229.4mA   -254.3mA
-1.2V     -86.19mA   -82.93mA   -94.91mA
-1.17V    -80.47mA   -77.11mA   -89.34mA
-1.11V    -69.48mA   -65.79mA   -78.91mA
-1.02V    -54.51mA   -49.88mA   -65.73mA
-930mV    -42.28mA   -35.92mA   -54.97mA
-780mV    -26.18mA   -18.61mA   -35.3mA
-690mV    -17.17mA   -10.9mA    -23.59mA
-570mV    -7.078mA   -3.876mA   -10.05mA
-450mV    -1.251mA   -635.5uA   -1.696mA
0V        0A         0A         0A
3.6V      0A         0A         0A
[POWER_clamp]
|Voltage   I(typ)   I(min)   I(max)
-1.8V     52.89mA    44.55mA    60.11mA
-1.56V    42.48mA    38.1mA     45.43mA
-1.26V    28.54mA    28.86mA    25.25mA
-1.14V    22.78mA    24.93mA    17.72mA
-960mV    14.19mA    18.89mA    9.998mA
-840mV    9.044mA    14.79mA    4.921mA
-720mV    5.001mA    10.65mA    1.403mA
-660mV    3.348mA    8.596mA    566.5uA
-540mV    992.7uA    4.706mA    207.6uA
-420mV    196.7uA    1.763mA    190.5uA
-240mV    100.9uA    180.2uA    188.6uA
3.6V      -30.34nA   -1.798uA   -37.95uA
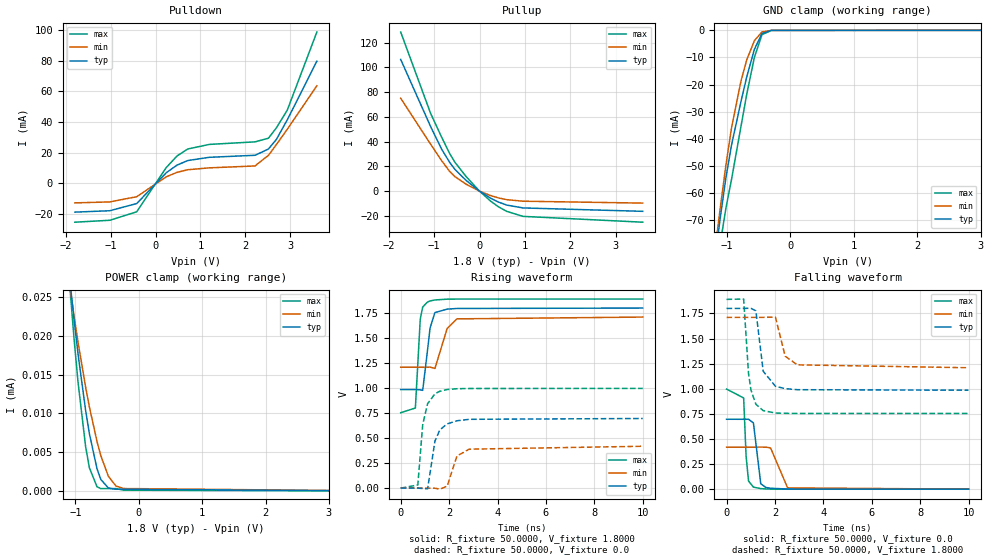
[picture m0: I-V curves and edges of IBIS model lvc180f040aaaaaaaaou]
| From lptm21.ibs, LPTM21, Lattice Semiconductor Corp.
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|   Model lvc180f040aaaaaaaaou
[Model]   lvc180f040aaaaaaaaou
Model_type   Output
Polarity   Non-Inverting
Enable   Active-Low
Vmeas =   0.9000V
Cref =   0.0F
Rref =   1.0000M
Vref =   0.0V
C_comp   4.2000pF   3.8000pF   7.5000pF
[Temperature Range]   25.0000   0.1050k   -40.0000
[Voltage Range]   1.8000V   1.7100V   1.8900V
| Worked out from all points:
|   slope of the pulldown table from 0 to 0.27 V, typ, clamps not added: 35.7 ohm
|   slope of the pullup table from 0 to 0.27 V, typ, clamps not added: 43.5 ohm
|   GND clamp passes 1 mA (typ) near -0.44 V on its own axis
|   rising waveform, R_fixture 50.0000, V_fixture 1.8000: 20-80 % time 226ps typ, 322ps min, 156ps max; typ from 0.985 V to 1.8 V
|   rising waveform, R_fixture 50.0000, V_fixture 0.0: 20-80 % time 342ps typ, 383ps min, 295ps max; typ from 0 V to 0.696 V
|   falling waveform, R_fixture 50.0000, V_fixture 0.0: 20-80 % time 185ps typ, 263ps min, 134ps max; typ from 0.696 V to 0 V
|   falling waveform, R_fixture 50.0000, V_fixture 1.8000: 20-80 % time 289ps typ, 336ps min, 246ps max; typ from 1.8 V to 0.985 V
[Pulldown]
|Voltage   I(typ)   I(min)   I(max)
-1.8V     -18.86mA   -12.83mA   -25.42mA
-1.02V    -17.94mA   -12.2mA    -24.17mA
-420mV    -13.27mA   -8.803mA   -18.63mA
240mV     6.859mA    4.183mA    10.22mA
480mV     11.8mA     7.089mA    17.77mA
720mV     14.79mA    8.792mA    22.32mA
1.2V      16.89mA    10.02mA    25.3mA
2.22V     18.21mA    11.25mA    26.96mA
2.52V     22.3mA     18.23mA    29.35mA
2.7V      28.7mA     25.29mA    36.22mA
2.94V     41.31mA    35.2mA     47.65mA
3.6V      79.58mA    63.51mA    98.55mA
[Pullup]
|Voltage   I(typ)   I(min)   I(max)
-1.74V    106.5mA    75.09mA    128.6mA
-1.08V    52.19mA    37.94mA    62.86mA
-840mV    34.13mA    24.81mA    43.88mA
-660mV    23.3mA     16mA       30.46mA
-540mV    17.49mA    11.68mA    23.16mA
-300mV    8.802mA    5.707mA    11.97mA
0V        -1.899nA   -1.714nA   -2.809nA
240mV     -5.62mA    -3.504mA   -7.961mA
420mV     -8.851mA   -5.472mA   -12.69mA
600mV     -11.24mA   -6.879mA   -16.33mA
960mV     -13.56mA   -8.118mA   -20.38mA
3.6V      -16.3mA    -9.648mA   -25.08mA
[GND_clamp]
|Voltage   I(typ)   I(min)   I(max)
-1.8V     -240.2mA   -229.4mA   -254.3mA
-1.2V     -86.16mA   -82.91mA   -94.88mA
-1.17V    -80.45mA   -77.09mA   -89.3mA
-1.11V    -69.45mA   -65.77mA   -78.87mA
-1.02V    -54.48mA   -49.86mA   -65.69mA
-930mV    -42.25mA   -35.9mA    -54.92mA
-780mV    -26.14mA   -18.58mA   -35.25mA
-690mV    -17.13mA   -10.87mA   -23.53mA
-570mV    -7.024mA   -3.834mA   -9.978mA
-450mV    -1.176mA   -584.6uA   -1.582mA
-300mV    -18.65uA   -15.9uA    -16.44uA
3.6V      0A         0A         0A
[POWER_clamp]
|Voltage   I(typ)   I(min)   I(max)
-1.8V     102.4uA    78.03uA    133.9uA
-1.08V    26.57uA    25.91uA    25.52uA
-1.02V    21.97uA    22.48uA    19.46uA
-960mV    17.73uA    19.24uA    14.09uA
-840mV    10.4uA     13.41uA    5.722uA
-780mV    7.367uA    10.82uA    2.953uA
-660mV    2.829uA    6.356uA    503.2nA
-600mV    1.45uA     4.527uA    262.3nA
-480mV    332.6nA    1.844uA    262.3nA
-360mV    178.1nA    587.7nA    262.3nA
-240mV    178.1nA    271.1nA    57.44nA
3.6V      -31nA      -27.04nA   -40.53nA
[Ramp]
| variable   typ   min   max
dV/dt_r  0.3835/0.3388n   0.2511/0.3796n   0.5981/0.2919n
dV/dt_f  0.4887/0.2859n   0.3008/0.3326n   0.6817/0.2435n
R_load = 50.0000
[Rising Waveform]
R_fixture=   50.0000
V_fixture=   1.8000
V_fixture_min=   1.7100
V_fixture_max=   1.8900
|time   V(typ)   V(min)   V(max)
0s        985.4mV    1.209V     753.8mV
606.1ps   985.5mV    1.209V     800.8mV
808.1ps   982.4mV    1.209V     1.69V
909.1ps   977.4mV    1.208V     1.811V
1.111ns   1.385V     1.209V     1.861V
1.212ns   1.6V       1.21V      1.871V
1.414ns   1.755V     1.196V     1.881V
1.919ns   1.789V     1.596V     1.889V
2.323ns   1.796V     1.692V     1.89V
10ns      1.8V       1.71V      1.89V
[Rising Waveform]
R_fixture=   50.0000
V_fixture=   0.0
V_fixture_min=   0.0
V_fixture_max=   0.0
|time   V(typ)   V(min)   V(max)
0s        551.1nV    773.6nV    431.5nV
707.1ps   -1.87uV    1.052uV    31.45mV
909.1ps   -3.608mV   12.81uV    635.8mV
1.111ns   -7.309mV   42.81uV    843.2mV
1.414ns   469.3mV    -1.116mV   942.7mV
1.616ns   582mV      -10.43mV   968.7mV
1.919ns   642.1mV    19.49mV    986mV
2.323ns   673.2mV    320.3mV    993.5mV
2.828ns   687.9mV    389.4mV    995.9mV
10ns      696.1mV    418.5mV    996.8mV
[Falling Waveform]
R_fixture=   50.0000
V_fixture=   0.0
V_fixture_min=   0.0
V_fixture_max=   0.0
|time   V(typ)   V(min)   V(max)
0s        696.1mV    418.5mV    996.8mV
707.1ps   696mV      418.5mV    908.3mV
808.1ps   696.1mV    418.5mV    329.1mV
909.1ps   696.4mV    418.5mV    81.02mV
1.111ns   659.7mV    418.5mV    20.39mV
1.414ns   54.24mV    418.8mV    5.526mV
1.616ns   17.56mV    418.3mV    2.28mV
1.818ns   9.098mV    411.5mV    956.7uV
2.525ns   1.367mV    12.84mV    86.45uV
10ns      30.2uV     4.654uV    -875.3nV
[Falling Waveform]
R_fixture=   50.0000
V_fixture=   1.8000
V_fixture_min=   1.7100
V_fixture_max=   1.8900
|time   V(typ)   V(min)   V(max)
0s        1.8V       1.71V      1.89V
707.1ps   1.8V       1.71V      1.893V
909.1ps   1.801V     1.71V      1.15V
1.01ns    1.8V       1.71V      986.7mV
1.212ns   1.776V     1.71V      846mV
1.515ns   1.174V     1.711V     782.2mV
2.02ns    1.025V     1.713V     758.2mV
2.424ns   1.001V     1.324V     755.1mV
2.929ns   990.4mV    1.238V     754.2mV
10ns      985.4mV    1.209V     753.8mV
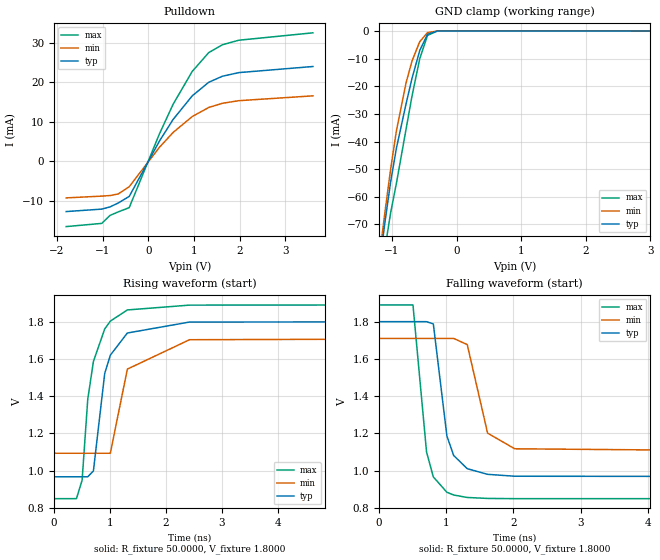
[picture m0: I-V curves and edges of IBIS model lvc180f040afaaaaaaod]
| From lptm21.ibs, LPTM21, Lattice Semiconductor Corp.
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|   Model lvc180f040afaaaaaaod
[Model]   lvc180f040afaaaaaaod
Model_type   I/O_open_drain
Polarity   Non-Inverting
Enable   Active-Low
Vinl =   0.6300V
Vinh =   1.1700V
Vmeas =   0.9000V
Cref =   0.0F
Rref =   1.0000M
Vref =   0.0V
C_comp   4.2000pF   3.8000pF   7.5000pF
[Temperature Range]   25.0000   0.1050k   -40.0000
[Voltage Range]   1.8000V   1.7100V   1.8900V
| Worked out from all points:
|   slope of the pulldown table from 0 to 0.27 V, typ, clamps not added: 47.4 ohm
|   GND clamp passes 1 mA (typ) near -0.44 V on its own axis
|   rising waveform, R_fixture 50.0000, V_fixture 1.8000: 20-80 % time 284ps typ, 284ps min, 265ps max; typ from 0.967 V to 1.8 V
|   falling waveform, R_fixture 50.0000, V_fixture 1.8000: 20-80 % time 208ps typ, 242ps min, 185ps max; typ from 1.8 V to 0.967 V
[Pulldown]
|Voltage   I(typ)   I(min)   I(max)
-1.8V     -12.68mA   -9.223mA   -16.48mA
-1.02V    -12.06mA   -8.773mA   -15.67mA
-840mV    -11.5mA    -8.628mA   -13.65mA
-660mV    -10.51mA   -8.221mA   -12.76mA
-420mV    -8.853mA   -6.399mA   -11.69mA
240mV     5.112mA    3.55mA     6.922mA
540mV     10.6mA     7.314mA    14.44mA
960mV     16.59mA    11.35mA    22.77mA
1.32V     20.01mA    13.64mA    27.51mA
1.62V     21.54mA    14.7mA     29.5mA
1.98V     22.46mA    15.36mA    30.65mA
3.6V      24mA       16.58mA    32.52mA
[GND_clamp]
|Voltage   I(typ)   I(min)   I(max)
-1.8V     -240.2mA   -229.4mA   -254.3mA
-1.2V     -86.18mA   -82.93mA   -94.91mA
-1.17V    -80.47mA   -77.11mA   -89.33mA
-1.11V    -69.47mA   -65.79mA   -78.9mA
-1.02V    -54.51mA   -49.88mA   -65.72mA
-930mV    -42.27mA   -35.92mA   -54.95mA
-780mV    -26.16mA   -18.59mA   -35.28mA
-690mV    -17.14mA   -10.88mA   -23.55mA
-570mV    -7.035mA   -3.841mA   -9.995mA
-450mV    -1.181mA   -586.6uA   -1.592mA
-300mV    -18.83uA   -15.98uA   -16.73uA
3.6V      0A         0A         0A
[Ramp]
| variable   typ   min   max
dV/dt_r  0.5000/0.2809n   0.3699/0.2815n   0.6247/0.2628n
dV/dt_f  0.5000/0.2064n   0.3699/0.2393n   0.6247/0.1833n
R_load = 50.0000
[Rising Waveform]
R_fixture=   50.0000
V_fixture=   1.8000
V_fixture_min=   1.7100
V_fixture_max=   1.8900
|time   V(typ)   V(min)   V(max)
0s        966.6mV    1.093V     848.8mV
404ps     966.6mV    1.093V     849.1mV
505.1ps   966.7mV    1.093V     947.9mV
606.1ps   966.6mV    1.093V     1.383V
707.1ps   997.7mV    1.093V     1.586V
909.1ps   1.522V     1.093V     1.761V
1.01ns    1.62V      1.093V     1.803V
1.313ns   1.739V     1.545V     1.863V
2.424ns   1.798V     1.703V     1.889V
10ns      1.8V       1.71V      1.89V
[Falling Waveform]
R_fixture=   50.0000
V_fixture=   1.8000
V_fixture_min=   1.7100
V_fixture_max=   1.8900
|time   V(typ)   V(min)   V(max)
0s        1.8V       1.71V      1.89V
505.1ps   1.8V       1.71V      1.89V
707.1ps   1.8V       1.71V      1.1V
808.1ps   1.788V     1.71V      965.8mV
1.01ns    1.186V     1.71V      883.3mV
1.111ns   1.081V     1.71V      868.6mV
1.313ns   1.01V      1.677V     855.4mV
1.616ns   979.7mV    1.201V     850.2mV
2.02ns    969.5mV    1.117V     849mV
10ns      966.6mV    1.093V     848.8mV
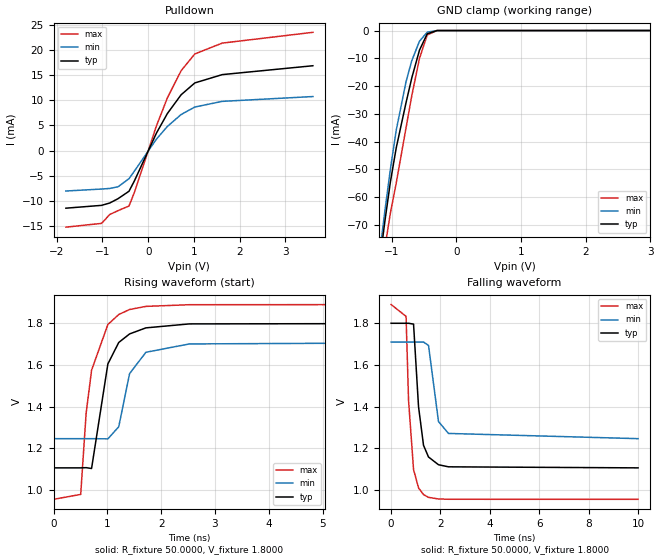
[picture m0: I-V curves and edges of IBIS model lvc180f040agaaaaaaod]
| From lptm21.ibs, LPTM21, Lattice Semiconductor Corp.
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|   Model lvc180f040agaaaaaaod
[Model]   lvc180f040agaaaaaaod
Model_type   I/O_open_drain
Polarity   Non-Inverting
Enable   Active-Low
Vinl =   0.6300V
Vinh =   1.1700V
Vmeas =   0.9000V
Cref =   0.0F
Rref =   1.0000M
Vref =   0.0V
C_comp   4.2000pF   3.8000pF   7.5000pF
[Temperature Range]   25.0000   0.1050k   -40.0000
[Voltage Range]   1.8000V   1.7100V   1.8900V
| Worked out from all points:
|   slope of the pulldown table from 0 to 0.27 V, typ, clamps not added: 53.8 ohm
|   GND clamp passes 1 mA (typ) near -0.44 V on its own axis
|   rising waveform, R_fixture 50.0000, V_fixture 1.8000: 20-80 % time 287ps typ, 293ps min, 287ps max; typ from 1.11 V to 1.8 V
|   falling waveform, R_fixture 50.0000, V_fixture 1.8000: 20-80 % time 275ps typ, 303ps min, 228ps max; typ from 1.8 V to 1.11 V
[Pulldown]
|Voltage   I(typ)   I(min)   I(max)
-1.8V     -11.45mA   -8.041mA   -15.22mA
-1.02V    -10.89mA   -7.649mA   -14.47mA
-840mV    -10.42mA   -7.527mA   -12.7mA
-660mV    -9.564mA   -7.194mA   -11.94mA
-420mV    -8.084mA   -5.596mA   -11.02mA
-300mV    -5.993mA   -4.055mA   -8.278mA
180mV     3.467mA    2.274mA    4.899mA
420mV     7.367mA    4.799mA    10.48mA
720mV     11.09mA    7.163mA    15.87mA
1.02V     13.44mA    8.653mA    19.2mA
1.62V     15.09mA    9.771mA    21.35mA
3.6V      16.85mA    10.73mA    23.49mA
[GND_clamp]
|Voltage   I(typ)   I(min)   I(max)
-1.8V     -240.2mA   -229.4mA   -254.3mA
-1.2V     -86.17mA   -82.92mA   -94.88mA
-1.17V    -80.46mA   -77.1mA    -89.31mA
-1.11V    -69.46mA   -65.78mA   -78.88mA
-1.02V    -54.49mA   -49.87mA   -65.69mA
-930mV    -42.26mA   -35.91mA   -54.92mA
-780mV    -26.15mA   -18.58mA   -35.26mA
-690mV    -17.13mA   -10.88mA   -23.54mA
-570mV    -7.027mA   -3.837mA   -9.983mA
-450mV    -1.178mA   -585.4uA   -1.585mA
-300mV    -18.71uA   -15.93uA   -16.53uA
3.6V      0A         0A         0A
[Ramp]
| variable   typ   min   max
dV/dt_r  0.4157/0.2842n   0.2778/0.2898n   0.5603/0.2844n
dV/dt_f  0.4157/0.2719n   0.2778/0.3001n   0.5603/0.2260n
R_load = 50.0000
[Rising Waveform]
R_fixture=   50.0000
V_fixture=   1.8000
V_fixture_min=   1.7100
V_fixture_max=   1.8900
|time   V(typ)   V(min)   V(max)
0s        1.107V     1.247V     956.2mV
505.1ps   1.107V     1.247V     979.8mV
606.1ps   1.108V     1.247V     1.369V
707.1ps   1.104V     1.247V     1.575V
1.01ns    1.605V     1.246V     1.794V
1.212ns   1.708V     1.304V     1.842V
1.414ns   1.749V     1.559V     1.866V
1.717ns   1.778V     1.661V     1.881V
2.525ns   1.797V     1.701V     1.889V
10ns      1.8V       1.71V      1.89V
[Falling Waveform]
R_fixture=   50.0000
V_fixture=   1.8000
V_fixture_min=   1.7100
V_fixture_max=   1.8900
|time   V(typ)   V(min)   V(max)
0s        1.8V       1.71V      1.89V
606.1ps   1.8V       1.71V      1.833V
707.1ps   1.8V       1.71V      1.43V
909.1ps   1.796V     1.71V      1.099V
1.111ns   1.4V       1.71V      1.011V
1.313ns   1.215V     1.71V      978.9mV
1.515ns   1.159V     1.694V     965.7mV
1.919ns   1.122V     1.329V     957.9mV
2.323ns   1.112V     1.272V     956.5mV
10ns      1.107V     1.247V     956.2mV
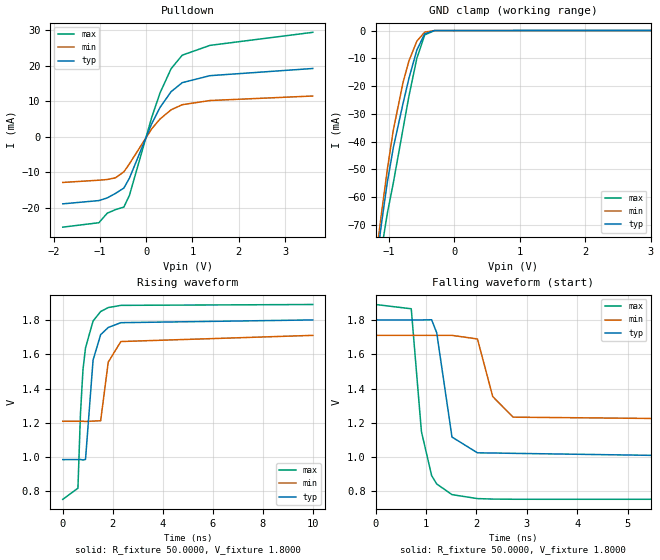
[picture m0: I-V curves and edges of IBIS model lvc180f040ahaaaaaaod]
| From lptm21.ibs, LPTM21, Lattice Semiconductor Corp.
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|   Model lvc180f040ahaaaaaaod
[Model]   lvc180f040ahaaaaaaod
Model_type   I/O_open_drain
Polarity   Non-Inverting
Enable   Active-Low
Vinl =   0.6300V
Vinh =   1.1700V
Vmeas =   0.9000V
Cref =   0.0F
Rref =   1.0000M
Vref =   0.0V
C_comp   4.2000pF   3.8000pF   7.5000pF
[Temperature Range]   25.0000   0.1050k   -40.0000
[Voltage Range]   1.8000V   1.7100V   1.8900V
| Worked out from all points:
|   slope of the pulldown table from 0 to 0.27 V, typ, clamps not added: 35.7 ohm
|   GND clamp passes 1 mA (typ) near -0.44 V on its own axis
|   rising waveform, R_fixture 50.0000, V_fixture 1.8000: 20-80 % time 294ps typ, 299ps min, 300ps max; typ from 0.985 V to 1.8 V
|   falling waveform, R_fixture 50.0000, V_fixture 1.8000: 20-80 % time 238ps typ, 290ps min, 247ps max; typ from 1.8 V to 0.991 V
[Pulldown]
|Voltage   I(typ)   I(min)   I(max)
-1.8V     -18.86mA   -12.83mA   -25.42mA
-1.02V    -17.94mA   -12.2mA    -24.17mA
-840mV    -17.19mA   -12.01mA   -21.49mA
-660mV    -15.91mA   -11.52mA   -20.48mA
-480mV    -14.4mA    -9.834mA   -19.76mA
-360mV    -11.61mA   -7.578mA   -16.45mA
120mV     3.67mA     2.253mA    5.436mA
300mV     8.275mA    5.027mA    12.37mA
540mV     12.73mA    7.623mA    19.2mA
780mV     15.26mA    9.056mA    23mA
1.38V     17.23mA    10.23mA    25.76mA
3.6V      19.25mA    11.5mA     29.43mA
[GND_clamp]
|Voltage   I(typ)   I(min)   I(max)
-1.8V     -240.2mA   -229.4mA   -254.3mA
-1.2V     -86.16mA   -82.91mA   -94.88mA
-1.17V    -80.45mA   -77.09mA   -89.3mA
-1.11V    -69.45mA   -65.77mA   -78.87mA
-1.02V    -54.48mA   -49.86mA   -65.69mA
-930mV    -42.25mA   -35.9mA    -54.92mA
-780mV    -26.14mA   -18.58mA   -35.25mA
-690mV    -17.13mA   -10.87mA   -23.53mA
-570mV    -7.024mA   -3.834mA   -9.978mA
-450mV    -1.176mA   -584.6uA   -1.582mA
-300mV    -18.65uA   -15.9uA    -16.44uA
3.6V      0A         0A         0A
[Ramp]
| variable   typ   min   max
dV/dt_r  0.4887/0.2912n   0.3008/0.2956n   0.6817/0.2968n
dV/dt_f  0.4887/0.2920n   0.2981/0.2782n   0.6817/0.2444n
R_load = 50.0000
[Rising Waveform]
R_fixture=   50.0000
V_fixture=   1.8000
V_fixture_min=   1.7100
V_fixture_max=   1.8900
|time   V(typ)   V(min)   V(max)
0s        985.4mV    1.209V     753.8mV
606.1ps   985.5mV    1.209V     818.7mV
707.1ps   986.1mV    1.209V     1.253V
808.1ps   983.5mV    1.209V     1.51V
909.1ps   986.5mV    1.208V     1.637V
1.212ns   1.566V     1.21V      1.794V
1.515ns   1.714V     1.212V     1.849V
1.818ns   1.756V     1.554V     1.872V
2.323ns   1.784V     1.674V     1.885V
10ns      1.8V       1.71V      1.89V
[Falling Waveform]
R_fixture=   50.0000
V_fixture=   1.8000
V_fixture_min=   1.7100
V_fixture_max=   1.8900
|time   V(typ)   V(min)   V(max)
0s        1.8V       1.71V      1.89V
707.1ps   1.8V       1.71V      1.865V
909.1ps   1.8V       1.71V      1.149V
1.111ns   1.801V     1.71V      892.4mV
1.212ns   1.725V     1.71V      843.4mV
1.515ns   1.117V     1.71V      781.3mV
2.02ns    1.025V     1.689V     758.1mV
2.323ns   1.024V     1.353V     755.3mV
2.727ns   1.022V     1.233V     754.2mV
10ns      990.9mV    1.213V     753.8mV
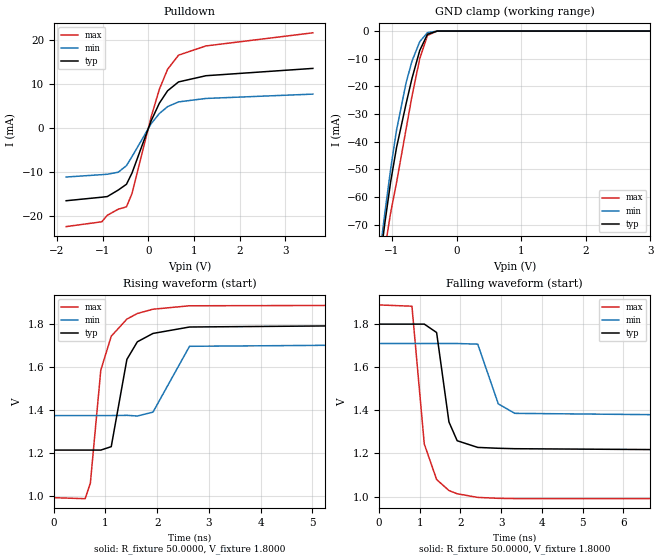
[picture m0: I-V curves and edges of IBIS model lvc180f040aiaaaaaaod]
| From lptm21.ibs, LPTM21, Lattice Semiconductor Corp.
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|   Model lvc180f040aiaaaaaaod
[Model]   lvc180f040aiaaaaaaod
Model_type   I/O_open_drain
Polarity   Non-Inverting
Enable   Active-Low
Vinl =   0.6300V
Vinh =   1.1700V
Vmeas =   0.9000V
Cref =   0.0F
Rref =   1.0000M
Vref =   0.0V
C_comp   4.2000pF   3.8000pF   7.5000pF
[Temperature Range]   25.0000   0.1050k   -40.0000
[Voltage Range]   1.8000V   1.7100V   1.8900V
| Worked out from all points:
|   slope of the pulldown table from 0 to 0.27 V, typ, clamps not added: 44 ohm
|   GND clamp passes 1 mA (typ) near -0.44 V on its own axis
|   rising waveform, R_fixture 50.0000, V_fixture 1.8000: 20-80 % time 313ps typ, 280ps min, 310ps max; typ from 1.21 V to 1.8 V
|   falling waveform, R_fixture 50.0000, V_fixture 1.8000: 20-80 % time 271ps typ, 325ps min, 301ps max; typ from 1.8 V to 1.21 V
[Pulldown]
|Voltage   I(typ)   I(min)   I(max)
-1.8V     -16.5mA    -11.13mA   -22.36mA
-1.02V    -15.7mA    -10.59mA   -21.27mA
-900mV    -15.56mA   -10.5mA    -19.8mA
-660mV    -14.08mA   -10.04mA   -18.42mA
-480mV    -12.77mA   -8.548mA   -17.88mA
-360mV    -10.25mA   -6.525mA   -14.9mA
60mV      1.602mA    944.5uA    2.476mA
240mV     5.603mA    3.257mA    8.761mA
420mV     8.409mA    4.818mA    13.28mA
660mV     10.42mA    5.892mA    16.48mA
1.26V     11.82mA    6.67mA     18.57mA
3.6V      13.48mA    7.653mA    21.54mA
[GND_clamp]
|Voltage   I(typ)   I(min)   I(max)
-1.8V     -240.2mA   -229.3mA   -254.3mA
-1.2V     -86.15mA   -82.88mA   -94.87mA
-1.17V    -80.44mA   -77.06mA   -89.3mA
-1.11V    -69.45mA   -65.75mA   -78.87mA
-1.02V    -54.48mA   -49.85mA   -65.68mA
-930mV    -42.24mA   -35.9mA    -54.91mA
-780mV    -26.14mA   -18.58mA   -35.25mA
-690mV    -17.12mA   -10.87mA   -23.53mA
-570mV    -7.022mA   -3.833mA   -9.976mA
-450mV    -1.175mA   -584.3uA   -1.581mA
-300mV    -18.62uA   -15.88uA   -16.41uA
3.6V      0A         0A         0A
[Ramp]
| variable   typ   min   max
dV/dt_r  0.3524/0.3100n   0.2020/0.2705n   0.5396/0.3071n
dV/dt_f  0.3517/0.2684n   0.2017/0.3219n   0.5396/0.2980n
R_load = 50.0000
[Rising Waveform]
R_fixture=   50.0000
V_fixture=   1.8000
V_fixture_min=   1.7100
V_fixture_max=   1.8900
|time   V(typ)   V(min)   V(max)
0s        1.212V     1.373V     990.1mV
606.1ps   1.212V     1.373V     985.3mV
707.1ps   1.212V     1.373V     1.058V
909.1ps   1.212V     1.373V     1.585V
1.111ns   1.228V     1.373V     1.743V
1.414ns   1.635V     1.374V     1.823V
1.616ns   1.717V     1.371V     1.849V
1.919ns   1.756V     1.389V     1.869V
2.626ns   1.786V     1.696V     1.885V
10ns      1.8V       1.709V     1.889V
[Falling Waveform]
R_fixture=   50.0000
V_fixture=   1.8000
V_fixture_min=   1.7100
V_fixture_max=   1.8900
|time   V(typ)   V(min)   V(max)
0s        1.8V       1.71V      1.889V
808.1ps   1.8V       1.71V      1.883V
1.111ns   1.8V       1.71V      1.244V
1.414ns   1.761V     1.71V      1.079V
1.717ns   1.346V     1.71V      1.028V
1.919ns   1.259V     1.71V      1.013V
2.424ns   1.228V     1.707V     996.1mV
2.929ns   1.224V     1.43V      991.8mV
3.333ns   1.222V     1.386V     990.7mV
10ns      1.214V     1.374V     990.1mV
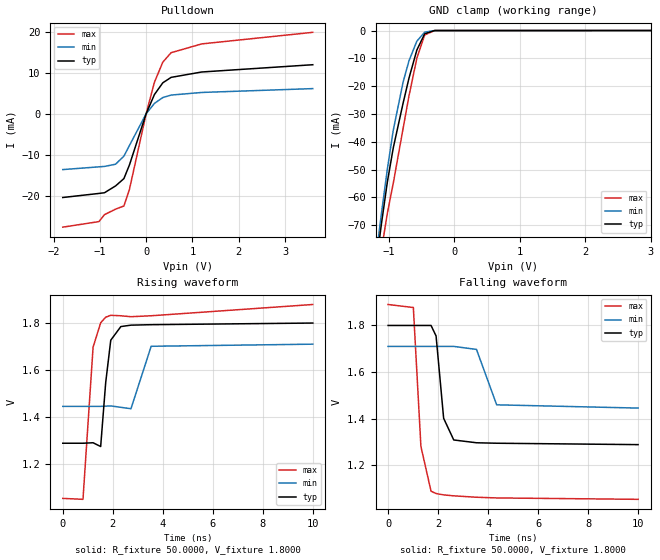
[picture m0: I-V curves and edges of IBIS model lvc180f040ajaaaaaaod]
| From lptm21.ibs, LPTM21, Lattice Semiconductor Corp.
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|   Model lvc180f040ajaaaaaaod
[Model]   lvc180f040ajaaaaaaod
Model_type   I/O_open_drain
Polarity   Non-Inverting
Enable   Active-Low
Vinl =   0.6300V
Vinh =   1.1700V
Vmeas =   0.9000V
Cref =   0.0F
Rref =   1.0000M
Vref =   0.0V
C_comp   4.2000pF   3.8000pF   7.5000pF
[Temperature Range]   25.0000   0.1050k   -40.0000
[Voltage Range]   1.8000V   1.7100V   1.8900V
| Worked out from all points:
|   slope of the pulldown table from 0 to 0.27 V, typ, clamps not added: 42.7 ohm
|   GND clamp passes 1 mA (typ) near -0.44 V on its own axis
|   rising waveform, R_fixture 50.0000, V_fixture 1.8000: 20-80 % time 246ps typ, 294ps min, 303ps max; typ from 1.29 V to 1.8 V
|   falling waveform, R_fixture 50.0000, V_fixture 1.8000: 20-80 % time 282ps typ, 370ps min, 242ps max; typ from 1.8 V to 1.29 V
[Pulldown]
|Voltage   I(typ)   I(min)   I(max)
-1.8V     -20.39mA   -13.59mA   -27.61mA
-1.02V    -19.4mA    -12.92mA   -26.26mA
-900mV    -19.23mA   -12.82mA   -24.57mA
-660mV    -17.57mA   -12.28mA   -23.23mA
-480mV    -15.79mA   -10.32mA   -22.45mA
-360mV    -12.45mA   -7.709mA   -18.4mA
0V        1.3nA      780pA      2.185nA
180mV     4.7mA      2.537mA    7.708mA
360mV     7.543mA    3.952mA    12.57mA
540mV     8.87mA     4.559mA    14.88mA
1.2V      10.18mA    5.194mA    17.02mA
3.6V      11.95mA    6.134mA    19.84mA
[GND_clamp]
|Voltage   I(typ)   I(min)   I(max)
-1.8V     -240.2mA   -229.3mA   -254.2mA
-1.2V     -86.08mA   -82.81mA   -94.85mA
-1.17V    -80.37mA   -77mA      -89.28mA
-1.11V    -69.39mA   -65.69mA   -78.86mA
-1.02V    -54.44mA   -49.8mA    -65.68mA
-930mV    -42.22mA   -35.86mA   -54.91mA
-780mV    -26.13mA   -18.57mA   -35.24mA
-690mV    -17.12mA   -10.87mA   -23.53mA
-570mV    -7.021mA   -3.832mA   -9.974mA
-450mV    -1.175mA   -584uA     -1.58mA
-300mV    -18.6uA    -15.87uA   -16.37uA
3.6V      0A         0A         0A
[Ramp]
| variable   typ   min   max
dV/dt_r  0.2991/0.2816n   0.1588/0.2909n   0.5023/0.2387n
dV/dt_f  0.3074/0.2789n   0.1588/0.3660n   0.5024/0.2398n
R_load = 50.0000
[Rising Waveform]
R_fixture=   50.0000
V_fixture=   1.8000
V_fixture_min=   1.7100
V_fixture_max=   1.8900
|time   V(typ)   V(min)   V(max)
0s        1.287V     1.444V     1.052V
808.1ps   1.287V     1.444V     1.048V
1.212ns   1.289V     1.444V     1.696V
1.515ns   1.273V     1.444V     1.8V
1.717ns   1.546V     1.445V     1.824V
1.919ns   1.726V     1.446V     1.832V
2.323ns   1.784V     1.44V      1.83V
2.727ns   1.79V      1.434V     1.826V
3.535ns   1.792V     1.7V       1.83V
10ns      1.799V     1.709V     1.878V
[Falling Waveform]
R_fixture=   50.0000
V_fixture=   1.8000
V_fixture_min=   1.7100
V_fixture_max=   1.8900
|time   V(typ)   V(min)   V(max)
0s        1.8V       1.71V      1.89V
1.01ns    1.8V       1.71V      1.877V
1.313ns   1.8V       1.71V      1.28V
1.717ns   1.8V       1.71V      1.088V
1.919ns   1.755V     1.71V      1.078V
2.222ns   1.401V     1.71V      1.072V
2.626ns   1.308V     1.71V      1.068V
3.535ns   1.296V     1.697V     1.062V
4.343ns   1.294V     1.459V     1.059V
10ns      1.288V     1.445V     1.053V
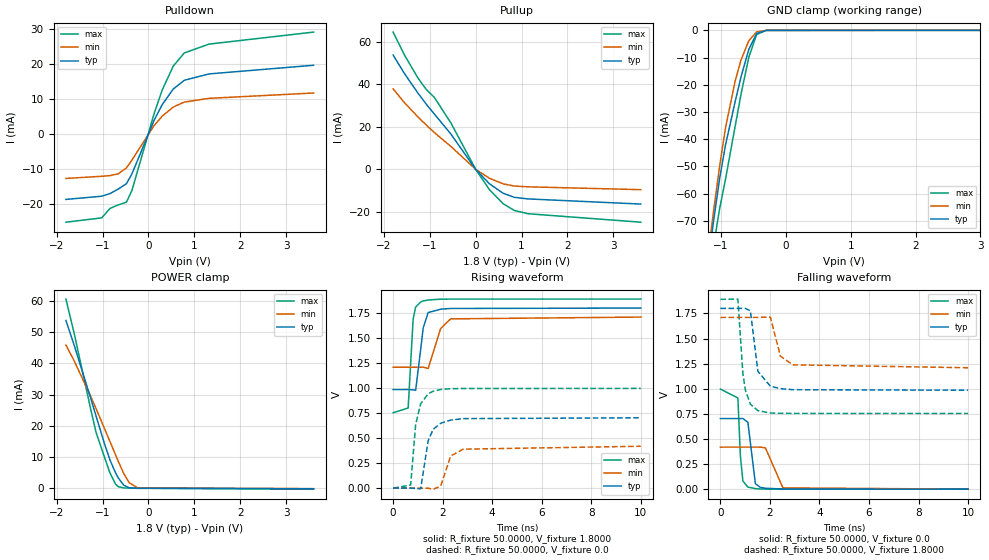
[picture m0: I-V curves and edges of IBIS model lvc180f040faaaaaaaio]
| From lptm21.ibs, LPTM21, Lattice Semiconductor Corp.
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|   Model lvc180f040faaaaaaaio
[Model]   lvc180f040faaaaaaaio
Model_type   I/O
Polarity   Non-Inverting
Enable   Active-Low
Vinl =   0.6300V
Vinh =   1.1700V
Vmeas =   0.9000V
Cref =   0.0F
Rref =   1.0000M
Vref =   0.0V
C_comp   4.2000pF   3.8000pF   7.5000pF
[Temperature Range]   25.0000   0.1050k   -40.0000
[Voltage Range]   1.8000V   1.7100V   1.8900V
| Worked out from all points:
|   slope of the pulldown table from 0 to 0.27 V, typ, clamps not added: 35.7 ohm
|   slope of the pullup table from 0 to 0.27 V, typ, clamps not added: 43.5 ohm
|   GND clamp passes 1 mA (typ) near -0.44 V on its own axis
|   POWER clamp passes 1 mA (typ) near -0.54 V on its own axis
|   rising waveform, R_fixture 50.0000, V_fixture 1.8000: 20-80 % time 226ps typ, 322ps min, 156ps max; typ from 0.985 V to 1.8 V
|   rising waveform, R_fixture 50.0000, V_fixture 0.0: 20-80 % time 342ps typ, 383ps min, 295ps max; typ from 0 V to 0.703 V
|   falling waveform, R_fixture 50.0000, V_fixture 0.0: 20-80 % time 185ps typ, 263ps min, 134ps max; typ from 0.703 V to 0 V
|   falling waveform, R_fixture 50.0000, V_fixture 1.8000: 20-80 % time 289ps typ, 336ps min, 246ps max; typ from 1.8 V to 0.985 V
[Pulldown]
|Voltage   I(typ)   I(min)   I(max)
-1.8V     -18.81mA   -12.79mA   -25.35mA
-1.02V    -17.89mA   -12.17mA   -24.11mA
-840mV    -17.14mA   -11.98mA   -21.42mA
-660mV    -15.85mA   -11.47mA   -20.39mA
-480mV    -14.3mA    -9.765mA   -19.59mA
-360mV    -11.47mA   -7.497mA   -16.22mA
120mV     3.812mA    2.334mA    5.687mA
300mV     8.416mA    5.108mA    12.62mA
540mV     12.87mA    7.703mA    19.45mA
780mV     15.39mA    9.133mA    23.24mA
1.32V     17.22mA    10.21mA    25.78mA
3.6V      19.71mA    11.74mA    29.23mA
[Pullup]
|Voltage   I(typ)   I(min)   I(max)
-1.8V     53.68mA    37.8mA     64.47mA
-1.56V    45.22mA    31.5mA     53.95mA
-1.26V    35.84mA    24.63mA    42.93mA
-1.08V    30.67mA    20.85mA    37.56mA
-900mV    25.95mA    17.26mA    33.76mA
-540mV    16.56mA    10.75mA    21.77mA
0V        -1.054nA   -772pA     -1.857nA
300mV     -6.794mA   -4.186mA   -9.561mA
600mV     -11.24mA   -6.817mA   -16.16mA
840mV     -13.12mA   -7.834mA   -19.28mA
1.14V     -13.88mA   -8.195mA   -20.84mA
3.6V      -16.3mA    -9.54mA    -24.81mA
[GND_clamp]
|Voltage   I(typ)   I(min)   I(max)
-1.8V     -240.1mA   -229.3mA   -254mA
-1.2V     -86.06mA   -82.86mA   -94.68mA
-1.17V    -80.34mA   -77.04mA   -89.1mA
-1.11V    -69.35mA   -65.72mA   -78.68mA
-1.02V    -54.38mA   -49.81mA   -65.5mA
-930mV    -42.15mA   -35.85mA   -54.73mA
-780mV    -26.05mA   -18.53mA   -35.07mA
-690mV    -17.04mA   -10.83mA   -23.37mA
-570mV    -6.958mA   -3.808mA   -9.842mA
-450mV    -1.149mA   -576.7uA   -1.52mA
-300mV    -18.2uA    -16.01uA   -13uA
3.6V      0A         0A         0A
[POWER_clamp]
|Voltage   I(typ)   I(min)   I(max)
-1.8V     53.66mA    45.8mA     60.51mA
-1.62V    45.76mA    40.78mA    49.57mA
-1.26V    28.84mA    29.42mA    25.34mA
-1.14V    22.99mA    25.38mA    17.77mA
-960mV    14.31mA    19.19mA    10.02mA
-840mV    9.109mA    15mA       4.931mA
-720mV    5.041mA    10.79mA    1.399mA
-660mV    3.38mA     8.712mA    551.7uA
-540mV    1.01mA     4.773mA    153.1uA
-420mV    197.6uA    1.797mA    88.49uA
-240mV    59.36uA    194.4uA    21.2uA
3.6V      -142.9uA   -81.03uA   -252.6uA
[Ramp]
| variable   typ   min   max
dV/dt_r  0.3835/0.3388n   0.2511/0.3796n   0.5981/0.2919n
dV/dt_f  0.4887/0.2859n   0.3008/0.3326n   0.6817/0.2435n
R_load = 50.0000
[Rising Waveform]
R_fixture=   50.0000
V_fixture=   1.8000
V_fixture_min=   1.7100
V_fixture_max=   1.8900
|time   V(typ)   V(min)   V(max)
0s        985.4mV    1.209V     753.8mV
606.1ps   985.5mV    1.209V     800.8mV
808.1ps   982.4mV    1.209V     1.69V
909.1ps   977.4mV    1.208V     1.811V
1.111ns   1.385V     1.209V     1.861V
1.212ns   1.6V       1.21V      1.871V
1.414ns   1.755V     1.196V     1.881V
1.919ns   1.789V     1.596V     1.889V
2.323ns   1.796V     1.692V     1.89V
10ns      1.8V       1.71V      1.89V
[Rising Waveform]
R_fixture=   50.0000
V_fixture=   0.0
V_fixture_min=   0.0
V_fixture_max=   0.0
|time   V(typ)   V(min)   V(max)
0s        551.1nV    773.6nV    431.5nV
707.1ps   -1.87uV    1.052uV    31.45mV
909.1ps   -3.608mV   12.81uV    635.8mV
1.111ns   -7.309mV   42.81uV    843.2mV
1.414ns   474mV      -1.116mV   942.7mV
1.616ns   587.8mV    -10.43mV   968.7mV
1.919ns   648.6mV    19.49mV    986mV
2.323ns   680mV      320.3mV    993.5mV
2.828ns   694.9mV    389.4mV    995.9mV
10ns      703.1mV    418.5mV    996.8mV
[Falling Waveform]
R_fixture=   50.0000
V_fixture=   0.0
V_fixture_min=   0.0
V_fixture_max=   0.0
|time   V(typ)   V(min)   V(max)
0s        703.1mV    418.5mV    996.8mV
707.1ps   703mV      418.5mV    908.3mV
808.1ps   703.1mV    418.5mV    329.1mV
909.1ps   703.5mV    418.5mV    81.02mV
1.111ns   666.4mV    418.5mV    20.39mV
1.414ns   54.24mV    418.8mV    5.526mV
1.616ns   17.56mV    418.3mV    2.28mV
1.818ns   9.098mV    411.5mV    956.7uV
2.525ns   1.367mV    12.84mV    86.45uV
10ns      30.2uV     4.654uV    -875.3nV
[Falling Waveform]
R_fixture=   50.0000
V_fixture=   1.8000
V_fixture_min=   1.7100
V_fixture_max=   1.8900
|time   V(typ)   V(min)   V(max)
0s        1.8V       1.71V      1.89V
707.1ps   1.8V       1.71V      1.893V
909.1ps   1.801V     1.71V      1.15V
1.01ns    1.8V       1.71V      986.7mV
1.212ns   1.776V     1.71V      846mV
1.515ns   1.174V     1.711V     782.2mV
2.02ns    1.025V     1.713V     758.2mV
2.424ns   1.001V     1.324V     755.1mV
2.929ns   990.4mV    1.238V     754.2mV
10ns      985.4mV    1.209V     753.8mV
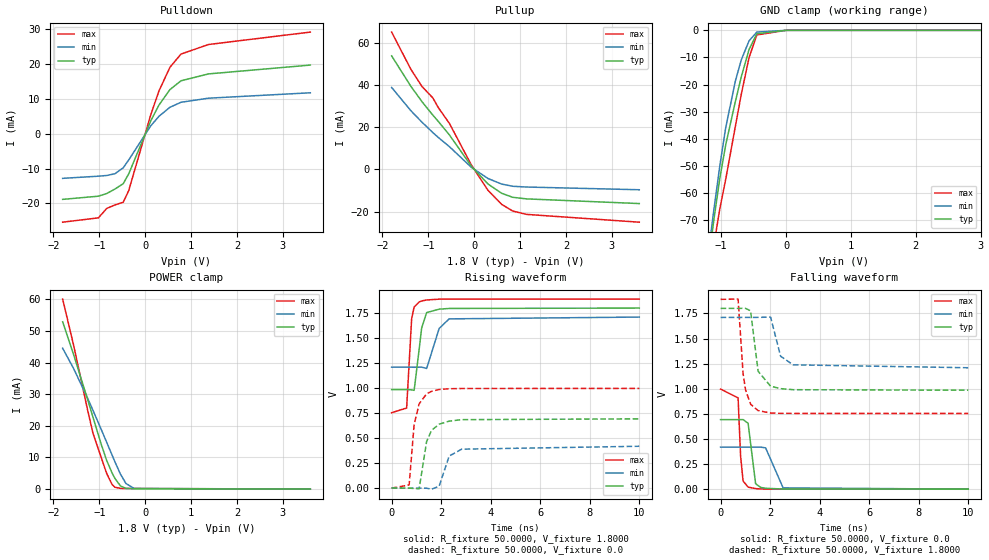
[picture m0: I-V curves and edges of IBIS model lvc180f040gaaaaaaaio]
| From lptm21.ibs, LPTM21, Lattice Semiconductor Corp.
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|   Model lvc180f040gaaaaaaaio
[Model]   lvc180f040gaaaaaaaio
Model_type   I/O
Polarity   Non-Inverting
Enable   Active-Low
Vinl =   0.6300V
Vinh =   1.1700V
Vmeas =   0.9000V
Cref =   0.0F
Rref =   1.0000M
Vref =   0.0V
C_comp   4.2000pF   3.8000pF   7.5000pF
[Temperature Range]   25.0000   0.1050k   -40.0000
[Voltage Range]   1.8000V   1.7100V   1.8900V
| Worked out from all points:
|   slope of the pulldown table from 0 to 0.27 V, typ, clamps not added: 35.9 ohm
|   slope of the pullup table from 0 to 0.27 V, typ, clamps not added: 43.7 ohm
|   GND clamp passes 1 mA (typ) near -0.44 V on its own axis
|   POWER clamp passes 1 mA (typ) near -0.54 V on its own axis
|   rising waveform, R_fixture 50.0000, V_fixture 1.8000: 20-80 % time 226ps typ, 322ps min, 156ps max; typ from 0.985 V to 1.8 V
|   rising waveform, R_fixture 50.0000, V_fixture 0.0: 20-80 % time 342ps typ, 383ps min, 295ps max; typ from 0 V to 0.693 V
|   falling waveform, R_fixture 50.0000, V_fixture 0.0: 20-80 % time 185ps typ, 263ps min, 134ps max; typ from 0.693 V to 0 V
|   falling waveform, R_fixture 50.0000, V_fixture 1.8000: 20-80 % time 289ps typ, 336ps min, 246ps max; typ from 1.8 V to 0.985 V
[Pulldown]
|Voltage   I(typ)   I(min)   I(max)
-1.8V     -18.83mA   -12.8mA    -25.37mA
-1.02V    -17.91mA   -12.18mA   -24.12mA
-840mV    -17.16mA   -11.98mA   -21.44mA
-660mV    -15.87mA   -11.48mA   -20.42mA
-480mV    -14.33mA   -9.784mA   -19.66mA
-360mV    -11.53mA   -7.531mA   -16.32mA
120mV     3.645mA    2.241mA    5.39mA
300mV     8.221mA    5mA        12.27mA
540mV     12.65mA    7.584mA    19.05mA
780mV     15.17mA    9.012mA    22.83mA
1.38V     17.14mA    10.18mA    25.57mA
3.6V      19.67mA    11.73mA    29.13mA
[Pullup]
|Voltage   I(typ)   I(min)   I(max)
-1.8V     53.71mA    38.78mA    64.95mA
-1.38V    39.31mA    27.77mA    47.34mA
-1.14V    32.1mA     22.39mA    39.28mA
-900mV    25.65mA    17.4mA     33.79mA
-780mV    22.65mA    15.08mA    29.18mA
-540mV    16.33mA    10.78mA    21.76mA
-60mV     1.513mA    983.3uA    2.072mA
300mV     -6.862mA   -4.269mA   -9.842mA
600mV     -11.28mA   -6.924mA   -16.51mA
840mV     -13.16mA   -7.953mA   -19.67mA
1.14V     -13.92mA   -8.315mA   -21.25mA
3.6V      -16.13mA   -9.599mA   -24.94mA
[GND_clamp]
|Voltage   I(typ)   I(min)   I(max)
-1.8V     -240.2mA   -229.4mA   -254.3mA
-1.2V     -86.19mA   -82.93mA   -94.91mA
-1.17V    -80.47mA   -77.11mA   -89.34mA
-1.11V    -69.48mA   -65.79mA   -78.91mA
-1.02V    -54.51mA   -49.88mA   -65.73mA
-930mV    -42.28mA   -35.92mA   -54.97mA
-780mV    -26.18mA   -18.61mA   -35.3mA
-690mV    -17.17mA   -10.9mA    -23.59mA
-570mV    -7.078mA   -3.876mA   -10.05mA
-450mV    -1.251mA   -635.5uA   -1.696mA
0V        0A         0A         0A
3.6V      0A         0A         0A
[POWER_clamp]
|Voltage   I(typ)   I(min)   I(max)
-1.8V     52.89mA    44.55mA    60.11mA
-1.56V    42.48mA    38.1mA     45.43mA
-1.26V    28.54mA    28.86mA    25.25mA
-1.14V    22.78mA    24.93mA    17.72mA
-960mV    14.19mA    18.89mA    9.998mA
-840mV    9.044mA    14.79mA    4.921mA
-720mV    5.001mA    10.65mA    1.403mA
-660mV    3.348mA    8.596mA    566.5uA
-540mV    992.7uA    4.706mA    207.6uA
-420mV    196.7uA    1.763mA    190.5uA
-240mV    100.9uA    180.2uA    188.6uA
3.6V      -30.34nA   -1.798uA   -37.95uA
[Ramp]
| variable   typ   min   max
dV/dt_r  0.3835/0.3388n   0.2511/0.3796n   0.5981/0.2919n
dV/dt_f  0.4887/0.2859n   0.3008/0.3326n   0.6817/0.2435n
R_load = 50.0000
[Rising Waveform]
R_fixture=   50.0000
V_fixture=   1.8000
V_fixture_min=   1.7100
V_fixture_max=   1.8900
|time   V(typ)   V(min)   V(max)
0s        985.4mV    1.209V     753.8mV
606.1ps   985.5mV    1.209V     800.8mV
808.1ps   982.4mV    1.209V     1.69V
909.1ps   977.4mV    1.208V     1.811V
1.111ns   1.385V     1.209V     1.861V
1.212ns   1.6V       1.21V      1.871V
1.414ns   1.755V     1.196V     1.881V
1.919ns   1.789V     1.596V     1.889V
2.323ns   1.796V     1.692V     1.89V
10ns      1.8V       1.71V      1.89V
[Rising Waveform]
R_fixture=   50.0000
V_fixture=   0.0
V_fixture_min=   0.0
V_fixture_max=   0.0
|time   V(typ)   V(min)   V(max)
0s        551.1nV    773.6nV    431.5nV
707.1ps   -1.87uV    1.052uV    31.45mV
909.1ps   -3.608mV   12.81uV    635.8mV
1.111ns   -7.309mV   42.81uV    843.2mV
1.414ns   466.9mV    -1.116mV   942.7mV
1.616ns   579mV      -10.43mV   968.7mV
1.919ns   638.8mV    19.49mV    986mV
2.323ns   669.8mV    320.3mV    993.5mV
2.828ns   684.4mV    389.4mV    995.9mV
10ns      692.6mV    418.5mV    996.8mV
[Falling Waveform]
R_fixture=   50.0000
V_fixture=   0.0
V_fixture_min=   0.0
V_fixture_max=   0.0
|time   V(typ)   V(min)   V(max)
0s        692.6mV    418.5mV    996.8mV
707.1ps   692.5mV    418.5mV    908.3mV
808.1ps   692.6mV    418.5mV    329.1mV
909.1ps   692.9mV    418.5mV    81.02mV
1.111ns   656.4mV    418.5mV    20.39mV
1.414ns   54.24mV    418.8mV    5.526mV
1.616ns   17.56mV    418.3mV    2.28mV
1.818ns   9.098mV    411.5mV    956.7uV
2.525ns   1.367mV    12.84mV    86.45uV
10ns      30.2uV     4.654uV    -875.3nV
[Falling Waveform]
R_fixture=   50.0000
V_fixture=   1.8000
V_fixture_min=   1.7100
V_fixture_max=   1.8900
|time   V(typ)   V(min)   V(max)
0s        1.8V       1.71V      1.89V
707.1ps   1.8V       1.71V      1.893V
909.1ps   1.801V     1.71V      1.15V
1.01ns    1.8V       1.71V      986.7mV
1.212ns   1.776V     1.71V      846mV
1.515ns   1.174V     1.711V     782.2mV
2.02ns    1.025V     1.713V     758.2mV
2.424ns   1.001V     1.324V     755.1mV
2.929ns   990.4mV    1.238V     754.2mV
10ns      985.4mV    1.209V     753.8mV
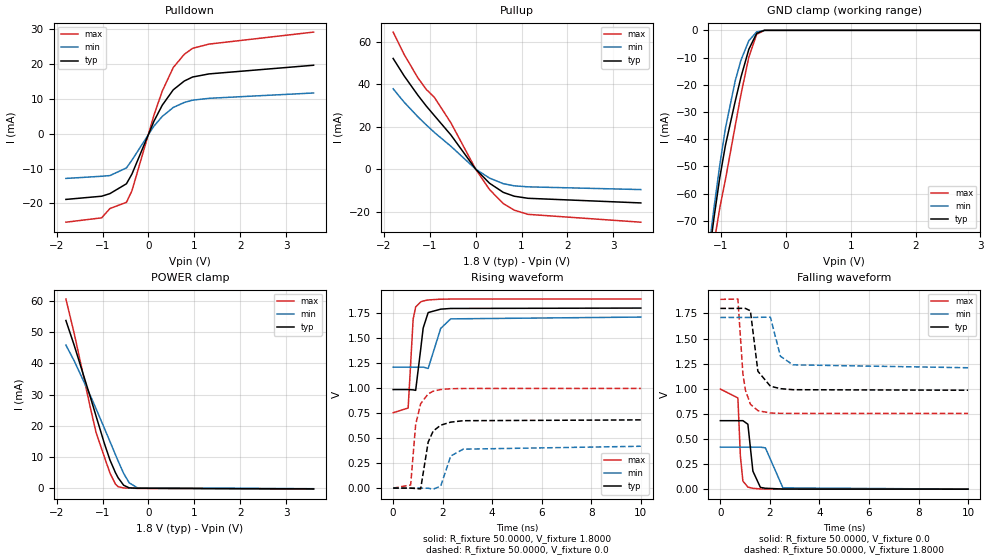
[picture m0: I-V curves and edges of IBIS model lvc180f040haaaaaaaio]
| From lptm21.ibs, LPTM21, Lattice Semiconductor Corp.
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|   Model lvc180f040haaaaaaaio
[Model]   lvc180f040haaaaaaaio
Model_type   I/O
Polarity   Non-Inverting
Enable   Active-Low
Vinl =   0.6300V
Vinh =   1.1700V
Vmeas =   0.9000V
Cref =   0.0F
Rref =   1.0000M
Vref =   0.0V
C_comp   4.2000pF   3.8000pF   7.5000pF
[Temperature Range]   25.0000   0.1050k   -40.0000
[Voltage Range]   1.8000V   1.7100V   1.8900V
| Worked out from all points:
|   slope of the pulldown table from 0 to 0.27 V, typ, clamps not added: 35.9 ohm
|   slope of the pullup table from 0 to 0.27 V, typ, clamps not added: 44.8 ohm
|   GND clamp passes 1 mA (typ) near -0.44 V on its own axis
|   POWER clamp passes 1 mA (typ) near -0.54 V on its own axis
|   rising waveform, R_fixture 50.0000, V_fixture 1.8000: 20-80 % time 226ps typ, 322ps min, 156ps max; typ from 0.985 V to 1.8 V
|   rising waveform, R_fixture 50.0000, V_fixture 0.0: 20-80 % time 342ps typ, 383ps min, 295ps max; typ from 0 V to 0.682 V
|   falling waveform, R_fixture 50.0000, V_fixture 0.0: 20-80 % time 186ps typ, 263ps min, 134ps max; typ from 0.682 V to 0 V
|   falling waveform, R_fixture 50.0000, V_fixture 1.8000: 20-80 % time 289ps typ, 336ps min, 246ps max; typ from 1.8 V to 0.985 V
[Pulldown]
|Voltage   I(typ)   I(min)   I(max)
-1.8V     -18.83mA   -12.8mA    -25.37mA
-1.02V    -17.91mA   -12.18mA   -24.12mA
-840mV    -17.16mA   -11.98mA   -21.44mA
-480mV    -14.33mA   -9.784mA   -19.66mA
-360mV    -11.53mA   -7.531mA   -16.32mA
120mV     3.645mA    2.241mA    5.39mA
300mV     8.221mA    5mA        12.27mA
540mV     12.65mA    7.584mA    19.05mA
780mV     15.17mA    9.012mA    22.83mA
960mV     16.32mA    9.67mA     24.56mA
1.32V     17.22mA    10.21mA    25.78mA
3.6V      19.71mA    11.74mA    29.23mA
[Pullup]
|Voltage   I(typ)   I(min)   I(max)
-1.8V     52.07mA    37.8mA     64.47mA
-1.56V    43.86mA    31.5mA     53.95mA
-1.26V    34.76mA    24.63mA    42.93mA
-1.08V    29.75mA    20.85mA    37.56mA
-900mV    25.17mA    17.26mA    33.76mA
-540mV    16.06mA    10.75mA    21.77mA
0V        -1.054nA   -772pA     -1.857nA
300mV     -6.591mA   -4.186mA   -9.561mA
600mV     -10.9mA    -6.817mA   -16.16mA
840mV     -12.72mA   -7.834mA   -19.28mA
1.14V     -13.7mA    -8.315mA   -21.25mA
3.6V      -15.88mA   -9.599mA   -24.94mA
[GND_clamp]
|Voltage   I(typ)   I(min)   I(max)
-1.8V     -240.1mA   -229.3mA   -254.1mA
-1.2V     -86.06mA   -82.86mA   -94.69mA
-1.17V    -80.34mA   -77.04mA   -89.11mA
-1.11V    -69.35mA   -65.72mA   -78.69mA
-1.02V    -54.38mA   -49.81mA   -65.51mA
-930mV    -42.15mA   -35.85mA   -54.74mA
-780mV    -26.05mA   -18.53mA   -35.08mA
-690mV    -17.04mA   -10.83mA   -23.36mA
-570mV    -6.946mA   -3.801mA   -9.827mA
-450mV    -1.119mA   -561.2uA   -1.47mA
-330mV    0A         -3.874uA   0A
3.6V      0A         0A         0A
[POWER_clamp]
|Voltage   I(typ)   I(min)   I(max)
-1.8V     53.66mA    45.8mA     60.51mA
-1.62V    45.76mA    40.78mA    49.57mA
-1.26V    28.84mA    29.42mA    25.34mA
-1.14V    22.99mA    25.38mA    17.77mA
-960mV    14.31mA    19.19mA    10.02mA
-840mV    9.109mA    15mA       4.931mA
-720mV    5.041mA    10.79mA    1.399mA
-660mV    3.38mA     8.712mA    551.7uA
-540mV    1.01mA     4.773mA    153.1uA
-420mV    197.6uA    1.797mA    88.49uA
-240mV    59.36uA    194.4uA    21.2uA
3.6V      -132uA     -74.33uA   -225.9uA
[Ramp]
| variable   typ   min   max
dV/dt_r  0.3835/0.3388n   0.2511/0.3796n   0.5981/0.2919n
dV/dt_f  0.4887/0.2859n   0.3008/0.3326n   0.6817/0.2435n
R_load = 50.0000
[Rising Waveform]
R_fixture=   50.0000
V_fixture=   1.8000
V_fixture_min=   1.7100
V_fixture_max=   1.8900
|time   V(typ)   V(min)   V(max)
0s        985.4mV    1.209V     753.8mV
606.1ps   985.5mV    1.209V     800.8mV
808.1ps   982.4mV    1.209V     1.69V
909.1ps   977.4mV    1.208V     1.811V
1.111ns   1.385V     1.209V     1.861V
1.212ns   1.6V       1.21V      1.871V
1.414ns   1.755V     1.196V     1.881V
1.919ns   1.789V     1.596V     1.889V
2.323ns   1.796V     1.692V     1.89V
10ns      1.8V       1.71V      1.89V
[Rising Waveform]
R_fixture=   50.0000
V_fixture=   0.0
V_fixture_min=   0.0
V_fixture_max=   0.0
|time   V(typ)   V(min)   V(max)
0s        551.1nV    773.6nV    431.5nV
707.1ps   -1.87uV    1.052uV    31.45mV
909.1ps   -3.608mV   12.81uV    635.8mV
1.111ns   -7.309mV   42.81uV    843.2mV
1.414ns   459.8mV    -1.116mV   942.7mV
1.616ns   570.2mV    -10.43mV   968.7mV
1.919ns   629.1mV    19.49mV    986mV
2.323ns   659.6mV    320.3mV    993.5mV
2.828ns   674mV      389.4mV    995.9mV
10ns      682mV      418.5mV    996.8mV
[Falling Waveform]
R_fixture=   50.0000
V_fixture=   0.0
V_fixture_min=   0.0
V_fixture_max=   0.0
|time   V(typ)   V(min)   V(max)
0s        682mV      418.5mV    996.8mV
707.1ps   681.9mV    418.5mV    908.3mV
808.1ps   682mV      418.5mV    329.1mV
909.1ps   682.3mV    418.5mV    81.02mV
1.111ns   646.4mV    418.5mV    20.39mV
1.313ns   179.6mV    418.5mV    8.492mV
1.616ns   17.56mV    418.3mV    2.28mV
1.818ns   9.098mV    411.5mV    956.7uV
2.525ns   1.367mV    12.84mV    86.45uV
10ns      30.2uV     4.654uV    -875.3nV
[Falling Waveform]
R_fixture=   50.0000
V_fixture=   1.8000
V_fixture_min=   1.7100
V_fixture_max=   1.8900
|time   V(typ)   V(min)   V(max)
0s        1.8V       1.71V      1.89V
707.1ps   1.8V       1.71V      1.893V
909.1ps   1.801V     1.71V      1.15V
1.01ns    1.8V       1.71V      986.7mV
1.212ns   1.776V     1.71V      846mV
1.515ns   1.174V     1.711V     782.2mV
2.02ns    1.025V     1.713V     758.2mV
2.424ns   1.001V     1.324V     755.1mV
2.929ns   990.4mV    1.238V     754.2mV
10ns      985.4mV    1.209V     753.8mV
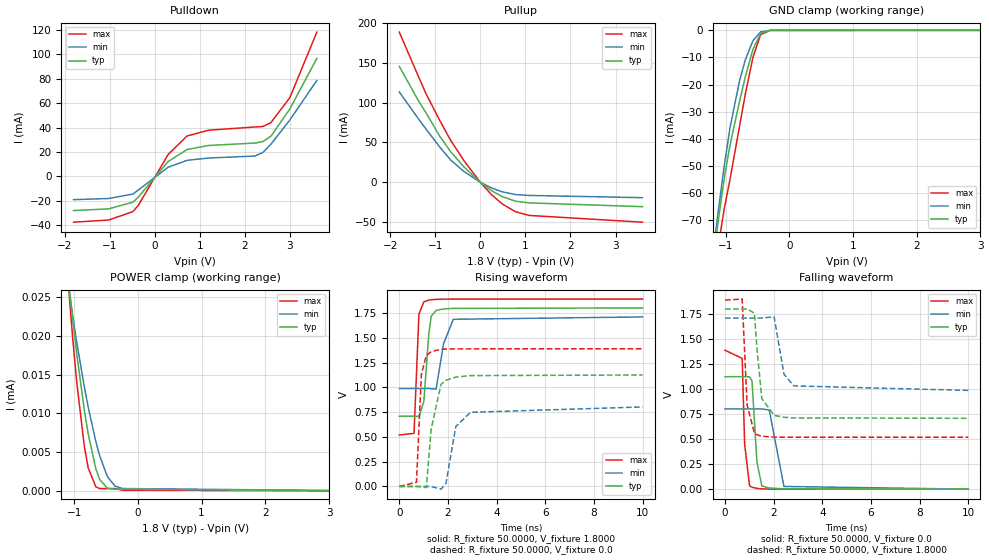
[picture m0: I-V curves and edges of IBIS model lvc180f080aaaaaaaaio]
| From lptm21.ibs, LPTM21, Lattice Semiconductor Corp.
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|   Model lvc180f080aaaaaaaaio
[Model]   lvc180f080aaaaaaaaio
Model_type   I/O
Polarity   Non-Inverting
Enable   Active-Low
Vinl =   0.6300V
Vinh =   1.1700V
Vmeas =   0.9000V
Cref =   0.0F
Rref =   1.0000M
Vref =   0.0V
C_comp   4.2000pF   3.8000pF   7.5000pF
[Temperature Range]   25.0000   0.1050k   -40.0000
[Voltage Range]   1.8000V   1.7100V   1.8900V
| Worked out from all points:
|   slope of the pulldown table from 0 to 0.27 V, typ, clamps not added: 24.3 ohm
|   slope of the pullup table from 0 to 0.27 V, typ, clamps not added: 24.1 ohm
|   GND clamp passes 1 mA (typ) near -0.44 V on its own axis
|   rising waveform, R_fixture 50.0000, V_fixture 1.8000: 20-80 % time 208ps typ, 314ps min, 136ps max; typ from 0.708 V to 1.8 V
|   rising waveform, R_fixture 50.0000, V_fixture 0.0: 20-80 % time 276ps typ, 394ps min, 161ps max; typ from 0 V to 1.12 V
|   falling waveform, R_fixture 50.0000, V_fixture 0.0: 20-80 % time 168ps typ, 247ps min, 125ps max; typ from 1.12 V to 0 V
|   falling waveform, R_fixture 50.0000, V_fixture 1.8000: 20-80 % time 240ps typ, 322ps min, 173ps max; typ from 1.8 V to 0.708 V
[Pulldown]
|Voltage   I(typ)   I(min)   I(max)
-1.8V     -28.04mA   -19.11mA   -37.59mA
-1.02V    -26.67mA   -18.17mA   -35.8mA
-480mV    -21.13mA   -14.49mA   -28.87mA
-360mV    -16.89mA   -11.13mA   -23.66mA
300mV     12.14mA    7.44mA     17.93mA
720mV     22mA       13.12mA    33.05mA
1.2V      25.28mA    15.01mA    37.83mA
2.22V     27.25mA    16.59mA    40.4mA
2.4V      28.42mA    19.5mA     40.82mA
2.58V     32.82mA    26.26mA    43.97mA
3V        55.16mA    46.16mA    64.46mA
3.6V      96.67mA    78.6mA     118.2mA
[Pullup]
|Voltage   I(typ)   I(min)   I(max)
-1.8V     145.4mA    113.2mA    188.3mA
-1.38V    102.7mA    79.96mA    133.3mA
-1.2V     86.47mA    66.31mA    110.3mA
-900mV    57.64mA    44.09mA    77.35mA
-660mV    38.42mA    28.01mA    52.66mA
-360mV    19.03mA    13.42mA    26.77mA
0V        -3.621nA   -3.321nA   -5.23nA
240mV     -10.15mA   -6.836mA   -15.04mA
480mV     -17.78mA   -11.81mA   -26.87mA
780mV     -23.67mA   -15.37mA   -36.89mA
1.08V     -25.78mA   -16.44mA   -41.49mA
3.6V      -30.51mA   -19.25mA   -49.97mA
[GND_clamp]
|Voltage   I(typ)   I(min)   I(max)
-1.8V     -240.2mA   -229.4mA   -254.3mA
-1.2V     -86.16mA   -82.91mA   -94.88mA
-1.17V    -80.45mA   -77.09mA   -89.3mA
-1.11V    -69.45mA   -65.77mA   -78.87mA
-1.02V    -54.48mA   -49.86mA   -65.69mA
-930mV    -42.25mA   -35.9mA    -54.92mA
-780mV    -26.14mA   -18.58mA   -35.25mA
-690mV    -17.13mA   -10.87mA   -23.53mA
-570mV    -7.024mA   -3.834mA   -9.978mA
-450mV    -1.176mA   -584.6uA   -1.582mA
-300mV    -18.65uA   -15.9uA    -16.44uA
3.6V      0A         0A         0A
[POWER_clamp]
|Voltage   I(typ)   I(min)   I(max)
-1.8V     102.4uA    78.03uA    133.9uA
-1.08V    26.57uA    25.91uA    25.52uA
-1.02V    21.97uA    22.48uA    19.47uA
-960mV    17.73uA    19.24uA    14.09uA
-840mV    10.4uA     13.41uA    5.722uA
-780mV    7.368uA    10.82uA    2.954uA
-660mV    2.829uA    6.357uA    503.7nA
-600mV    1.451uA    4.527uA    262.8nA
-480mV    333.1nA    1.844uA    262.8nA
-360mV    178.5nA    588.1nA    262.8nA
-240mV    178.5nA    271.5nA    57.44nA
3.6V      -31nA      -27.04nA   -40.53nA
[Ramp]
| variable   typ   min   max
dV/dt_r  0.6610/0.2727n   0.4811/0.3899n   0.8331/0.1596n
dV/dt_f  0.6551/0.2377n   0.4337/0.3185n   0.8227/0.1713n
R_load = 50.0000
[Rising Waveform]
R_fixture=   50.0000
V_fixture=   1.8000
V_fixture_min=   1.7100
V_fixture_max=   1.8900
|time   V(typ)   V(min)   V(max)
0s        708.2mV    987.1mV    518.8mV
606.1ps   708.2mV    987.1mV    535.6mV
808.1ps   705.1mV    987.1mV    1.738V
1.01ns    857.5mV    987.1mV    1.863V
1.212ns   1.533V     988.7mV    1.879V
1.313ns   1.717V     984.6mV    1.883V
1.515ns   1.776V     982.4mV    1.887V
1.818ns   1.79V      1.438V     1.889V
2.222ns   1.796V     1.686V     1.89V
10ns      1.8V       1.71V      1.89V
[Rising Waveform]
R_fixture=   50.0000
V_fixture=   0.0
V_fixture_min=   0.0
V_fixture_max=   0.0
|time   V(typ)   V(min)   V(max)
0s        416.8nV    613.5nV    315.6nV
707.1ps   -43.83uV   739.1nV    42.13mV
909.1ps   -4.797mV   13.25uV    1.131V
1.111ns   -12.22mV   23.29uV    1.321V
1.313ns   582.7mV    -542uV     1.36V
1.717ns   1.031V     -27.73mV   1.383V
1.919ns   1.071V     30.53mV    1.386V
2.323ns   1.103V     603.9mV    1.388V
2.929ns   1.118V     747.5mV    1.388V
10ns      1.124V     801.8mV    1.389V
[Falling Waveform]
R_fixture=   50.0000
V_fixture=   0.0
V_fixture_min=   0.0
V_fixture_max=   0.0
|time   V(typ)   V(min)   V(max)
0s        1.124V     801.8mV    1.389V
707.1ps   1.124V     801.8mV    1.307V
808.1ps   1.124V     801.8mV    450.3mV
1.01ns    1.123V     801.8mV    33.5mV
1.111ns   1.083V     801.8mV    19.63mV
1.313ns   272.3mV    801.9mV    7.872mV
1.515ns   31.84mV    802.1mV    3.154mV
1.818ns   11.39mV    791mV      801.3uV
2.424ns   2.244mV    27.1mV     89.53uV
10ns      16.85uV    -10.34uV   -6.094uV
[Falling Waveform]
R_fixture=   50.0000
V_fixture=   1.8000
V_fixture_min=   1.7100
V_fixture_max=   1.8900
|time   V(typ)   V(min)   V(max)
0s        1.8V       1.71V      1.89V
707.1ps   1.8V       1.71V      1.9V
909.1ps   1.801V     1.71V      842.5mV
1.212ns   1.758V     1.71V      558mV
1.313ns   1.403V     1.71V      543.3mV
1.515ns   905.4mV    1.711V     529mV
2.02ns    737.8mV    1.722V     520.2mV
2.424ns   718.8mV    1.149V     519.1mV
2.828ns   712.1mV    1.032V     518.9mV
10ns      708.2mV    987.1mV    518.8mV
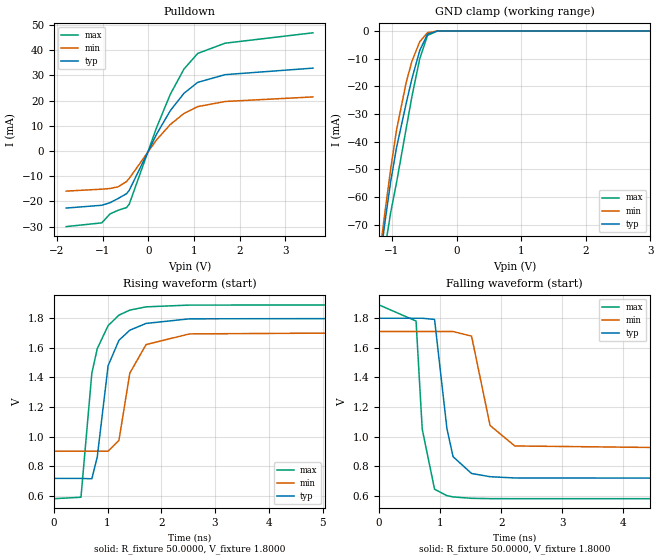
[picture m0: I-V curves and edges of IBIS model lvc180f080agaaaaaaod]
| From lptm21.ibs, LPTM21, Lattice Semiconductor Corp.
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|   Model lvc180f080agaaaaaaod
[Model]   lvc180f080agaaaaaaod
Model_type   I/O_open_drain
Polarity   Non-Inverting
Enable   Active-Low
Vinl =   0.6300V
Vinh =   1.1700V
Vmeas =   0.9000V
Cref =   0.0F
Rref =   1.0000M
Vref =   0.0V
C_comp   4.2000pF   3.8000pF   7.5000pF
[Temperature Range]   25.0000   0.1050k   -40.0000
[Voltage Range]   1.8000V   1.7100V   1.8900V
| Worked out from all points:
|   slope of the pulldown table from 0 to 0.27 V, typ, clamps not added: 27.8 ohm
|   GND clamp passes 1 mA (typ) near -0.44 V on its own axis
|   rising waveform, R_fixture 50.0000, V_fixture 1.8000: 20-80 % time 283ps typ, 294ps min, 290ps max; typ from 0.717 V to 1.8 V
|   falling waveform, R_fixture 50.0000, V_fixture 1.8000: 20-80 % time 203ps typ, 253ps min, 147ps max; typ from 1.8 V to 0.717 V
[Pulldown]
|Voltage   I(typ)   I(min)   I(max)
-1.8V     -22.66mA   -15.94mA   -30.01mA
-1.02V    -21.55mA   -15.16mA   -28.53mA
-840mV    -20.52mA   -14.9mA    -24.97mA
-660mV    -18.84mA   -14.21mA   -23.51mA
-480mV    -16.98mA   -12.15mA   -22.48mA
-420mV    -15.65mA   -10.92mA   -21.14mA
180mV     6.692mA    4.443mA    9.321mA
480mV     15.99mA    10.5mA     22.5mA
780mV     22.91mA    14.89mA    32.53mA
1.08V     27.21mA    17.59mA    38.69mA
1.68V     30.27mA    19.62mA    42.75mA
3.6V      32.85mA    21.43mA    46.86mA
[GND_clamp]
|Voltage   I(typ)   I(min)   I(max)
-1.8V     -240.2mA   -229.4mA   -254.3mA
-1.2V     -86.17mA   -82.92mA   -94.88mA
-1.17V    -80.46mA   -77.1mA    -89.31mA
-1.11V    -69.46mA   -65.78mA   -78.88mA
-1.02V    -54.49mA   -49.87mA   -65.69mA
-930mV    -42.26mA   -35.91mA   -54.92mA
-780mV    -26.15mA   -18.58mA   -35.26mA
-690mV    -17.13mA   -10.88mA   -23.54mA
-570mV    -7.027mA   -3.837mA   -9.983mA
-450mV    -1.178mA   -585.4uA   -1.585mA
-300mV    -18.71uA   -15.93uA   -16.53uA
3.6V      0A         0A         0A
[Ramp]
| variable   typ   min   max
dV/dt_r  0.6498/0.2800n   0.4854/0.2913n   0.7862/0.2868n
dV/dt_f  0.6498/0.2007n   0.4854/0.2509n   0.7862/0.1454n
R_load = 50.0000
[Rising Waveform]
R_fixture=   50.0000
V_fixture=   1.8000
V_fixture_min=   1.7100
V_fixture_max=   1.8900
|time   V(typ)   V(min)   V(max)
0s        717mV      901mV      579.7mV
505.1ps   717mV      901mV      589.5mV
707.1ps   714.2mV    901mV      1.428V
808.1ps   861.7mV    901.1mV    1.594V
1.01ns    1.479V     900.5mV    1.75V
1.212ns   1.651V     974.3mV    1.821V
1.414ns   1.719V     1.429V     1.855V
1.717ns   1.765V     1.622V     1.877V
2.525ns   1.796V     1.694V     1.889V
10ns      1.8V       1.71V      1.89V
[Falling Waveform]
R_fixture=   50.0000
V_fixture=   1.8000
V_fixture_min=   1.7100
V_fixture_max=   1.8900
|time   V(typ)   V(min)   V(max)
0s        1.8V       1.71V      1.89V
606.1ps   1.8V       1.71V      1.781V
707.1ps   1.8V       1.71V      1.05V
909.1ps   1.792V     1.71V      643.7mV
1.111ns   1.055V     1.71V      600.2mV
1.212ns   863.8mV    1.71V      591.7mV
1.515ns   750.1mV    1.679V     582.2mV
1.818ns   728.4mV    1.075V     580.2mV
2.222ns   719.9mV    936.3mV    579.8mV
10ns      716.9mV    901mV      579.7mV
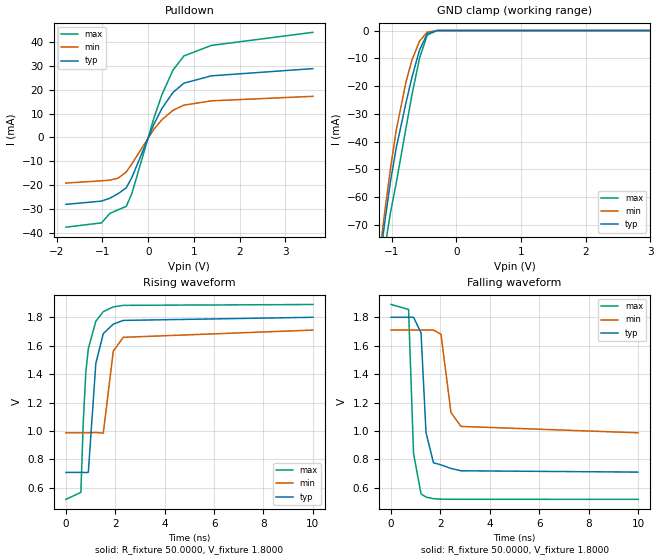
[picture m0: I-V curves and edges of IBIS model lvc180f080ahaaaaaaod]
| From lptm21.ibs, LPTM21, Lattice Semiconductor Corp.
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|   Model lvc180f080ahaaaaaaod
[Model]   lvc180f080ahaaaaaaod
Model_type   I/O_open_drain
Polarity   Non-Inverting
Enable   Active-Low
Vinl =   0.6300V
Vinh =   1.1700V
Vmeas =   0.9000V
Cref =   0.0F
Rref =   1.0000M
Vref =   0.0V
C_comp   4.2000pF   3.8000pF   7.5000pF
[Temperature Range]   25.0000   0.1050k   -40.0000
[Voltage Range]   1.8000V   1.7100V   1.8900V
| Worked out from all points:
|   slope of the pulldown table from 0 to 0.27 V, typ, clamps not added: 24.3 ohm
|   GND clamp passes 1 mA (typ) near -0.44 V on its own axis
|   rising waveform, R_fixture 50.0000, V_fixture 1.8000: 20-80 % time 290ps typ, 296ps min, 298ps max; typ from 0.708 V to 1.8 V
|   falling waveform, R_fixture 50.0000, V_fixture 1.8000: 20-80 % time 214ps typ, 315ps min, 183ps max; typ from 1.8 V to 0.71 V
[Pulldown]
|Voltage   I(typ)   I(min)   I(max)
-1.8V     -28.04mA   -19.11mA   -37.59mA
-1.02V    -26.67mA   -18.17mA   -35.8mA
-840mV    -25.49mA   -17.88mA   -31.86mA
-660mV    -23.57mA   -17.1mA    -30.33mA
-480mV    -21.13mA   -14.49mA   -28.87mA
-360mV    -16.89mA   -11.13mA   -23.66mA
120mV     5.351mA    3.322mA    7.82mA
300mV     12.14mA    7.44mA     17.93mA
540mV     18.82mA    11.34mA    28.16mA
780mV     22.73mA    13.53mA    34.14mA
1.38V     25.81mA    15.33mA    38.55mA
3.6V      28.83mA    17.23mA    44.04mA
[GND_clamp]
|Voltage   I(typ)   I(min)   I(max)
-1.8V     -240.2mA   -229.4mA   -254.3mA
-1.2V     -86.16mA   -82.91mA   -94.88mA
-1.17V    -80.45mA   -77.09mA   -89.3mA
-1.11V    -69.45mA   -65.77mA   -78.87mA
-1.02V    -54.48mA   -49.86mA   -65.69mA
-930mV    -42.25mA   -35.9mA    -54.92mA
-780mV    -26.14mA   -18.58mA   -35.25mA
-690mV    -17.13mA   -10.87mA   -23.53mA
-570mV    -7.024mA   -3.834mA   -9.978mA
-450mV    -1.176mA   -584.6uA   -1.582mA
-300mV    -18.65uA   -15.9uA    -16.44uA
3.6V      0A         0A         0A
[Ramp]
| variable   typ   min   max
dV/dt_r  0.6551/0.2874n   0.4337/0.2933n   0.8227/0.2951n
dV/dt_f  0.6551/0.2443n   0.4325/0.2773n   0.8227/0.1551n
R_load = 50.0000
[Rising Waveform]
R_fixture=   50.0000
V_fixture=   1.8000
V_fixture_min=   1.7100
V_fixture_max=   1.8900
|time   V(typ)   V(min)   V(max)
0s        708.2mV    987.1mV    518.8mV
606.1ps   708.2mV    987.1mV    567.4mV
707.1ps   708.8mV    987.1mV    1.074V
808.1ps   706.7mV    987.1mV    1.414V
909.1ps   709.1mV    987mV      1.579V
1.212ns   1.474V     989mV      1.772V
1.515ns   1.685V     984.9mV    1.84V
1.919ns   1.752V     1.561V     1.873V
2.323ns   1.778V     1.659V     1.884V
10ns      1.8V       1.71V      1.89V
[Falling Waveform]
R_fixture=   50.0000
V_fixture=   1.8000
V_fixture_min=   1.7100
V_fixture_max=   1.8900
|time   V(typ)   V(min)   V(max)
0s        1.8V       1.71V      1.89V
707.1ps   1.8V       1.71V      1.855V
909.1ps   1.8V       1.71V      841.4mV
1.212ns   1.691V     1.71V      557mV
1.414ns   987.6mV    1.71V      534.4mV
1.717ns   775.9mV    1.71V      523.2mV
2.02ns    761.6mV    1.681V     520.1mV
2.424ns   736mV      1.13V      519.1mV
2.828ns   719.7mV    1.032V     518.9mV
10ns      710.5mV    987.1mV    518.8mV
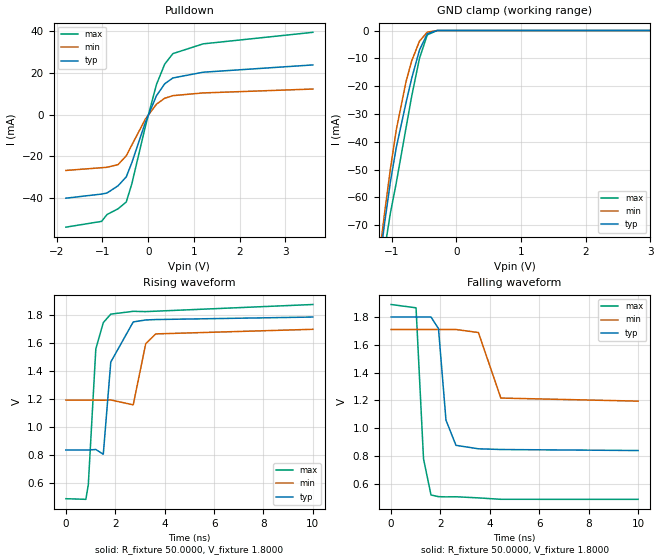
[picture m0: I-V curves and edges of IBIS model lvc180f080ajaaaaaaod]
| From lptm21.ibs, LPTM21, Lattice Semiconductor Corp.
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|   Model lvc180f080ajaaaaaaod
[Model]   lvc180f080ajaaaaaaod
Model_type   I/O_open_drain
Polarity   Non-Inverting
Enable   Active-Low
Vinl =   0.6300V
Vinh =   1.1700V
Vmeas =   0.9000V
Cref =   0.0F
Rref =   1.0000M
Vref =   0.0V
C_comp   4.2000pF   3.8000pF   7.5000pF
[Temperature Range]   25.0000   0.1050k   -40.0000
[Voltage Range]   1.8000V   1.7100V   1.8900V
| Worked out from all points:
|   slope of the pulldown table from 0 to 0.27 V, typ, clamps not added: 22 ohm
|   GND clamp passes 1 mA (typ) near -0.44 V on its own axis
|   rising waveform, R_fixture 50.0000, V_fixture 1.8000: 20-80 % time 288ps typ, 333ps min, 296ps max; typ from 0.834 V to 1.79 V
|   falling waveform, R_fixture 50.0000, V_fixture 1.8000: 20-80 % time 287ps typ, 376ps min, 197ps max; typ from 1.8 V to 0.838 V
[Pulldown]
|Voltage   I(typ)   I(min)   I(max)
-1.8V     -40.14mA   -26.82mA   -54.04mA
-1.02V    -38.16mA   -25.51mA   -51.27mA
-900mV    -37.65mA   -25.3mA    -47.97mA
-660mV    -34.19mA   -24.03mA   -45.25mA
-480mV    -29.92mA   -19.79mA   -41.97mA
-360mV    -23.22mA   -14.7mA    -33.4mA
-60mV     -3.617mA   -2.108mA   -5.527mA
180mV     9.019mA    4.965mA    14.39mA
360mV     14.75mA    7.822mA    24.18mA
540mV     17.57mA    9.078mA    29.25mA
1.2V      20.32mA    10.38mA    33.93mA
3.6V      23.82mA    12.25mA    39.47mA
[GND_clamp]
|Voltage   I(typ)   I(min)   I(max)
-1.8V     -240.2mA   -229.3mA   -254.2mA
-1.2V     -86.08mA   -82.81mA   -94.85mA
-1.17V    -80.37mA   -77mA      -89.28mA
-1.11V    -69.39mA   -65.69mA   -78.86mA
-1.02V    -54.44mA   -49.8mA    -65.68mA
-930mV    -42.22mA   -35.86mA   -54.91mA
-780mV    -26.13mA   -18.57mA   -35.24mA
-690mV    -17.12mA   -10.87mA   -23.53mA
-570mV    -7.021mA   -3.832mA   -9.974mA
-450mV    -1.175mA   -584uA     -1.58mA
-300mV    -18.6uA    -15.87uA   -16.37uA
3.6V      0A         0A         0A
[Ramp]
| variable   typ   min   max
dV/dt_r  0.5727/0.2850n   0.3099/0.3022n   0.8359/0.2931n
dV/dt_f  0.5771/0.2840n   0.3098/0.3726n   0.8421/0.1947n
R_load = 50.0000
[Rising Waveform]
R_fixture=   50.0000
V_fixture=   1.8000
V_fixture_min=   1.7100
V_fixture_max=   1.8900
|time   V(typ)   V(min)   V(max)
0s        833.7mV    1.192V     484.4mV
808.1ps   833.7mV    1.192V     479.9mV
909.1ps   833.5mV    1.192V     586.5mV
1.212ns   837.5mV    1.192V     1.559V
1.515ns   803.4mV    1.191V     1.748V
1.818ns   1.465V     1.193V     1.809V
2.727ns   1.753V     1.158V     1.829V
3.232ns   1.767V     1.596V     1.827V
3.636ns   1.77V      1.667V     1.83V
10ns      1.788V     1.7V       1.878V
[Falling Waveform]
R_fixture=   50.0000
V_fixture=   1.8000
V_fixture_min=   1.7100
V_fixture_max=   1.8900
|time   V(typ)   V(min)   V(max)
0s        1.8V       1.71V      1.89V
1.01ns    1.8V       1.71V      1.866V
1.313ns   1.8V       1.71V      778.2mV
1.616ns   1.8V       1.71V      517.9mV
1.919ns   1.716V     1.71V      505.9mV
2.222ns   1.057V     1.71V      504.2mV
2.626ns   875.5mV    1.71V      505.1mV
3.535ns   850.7mV    1.688V     497mV
4.444ns   845.4mV    1.216V     486.8mV
10ns      838.1mV    1.194V     486.6mV
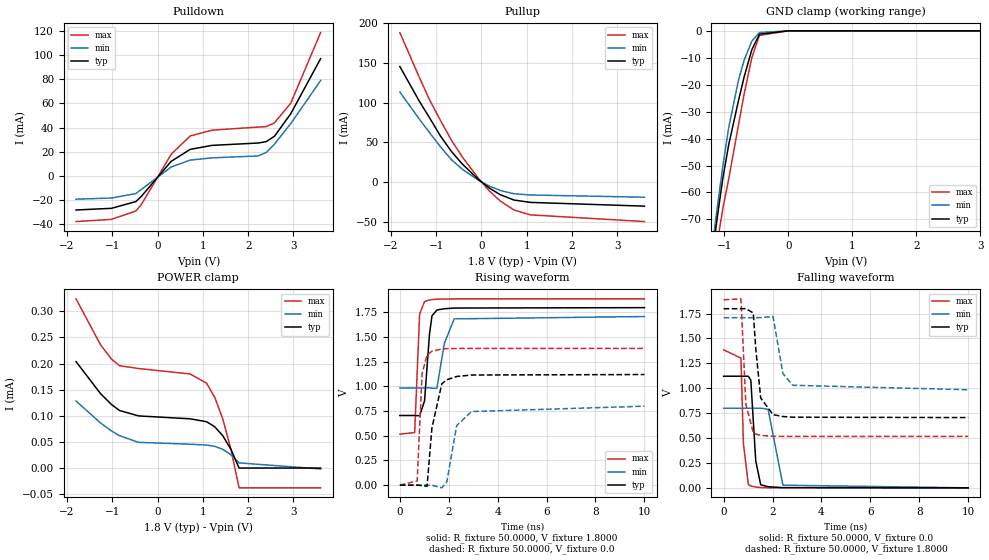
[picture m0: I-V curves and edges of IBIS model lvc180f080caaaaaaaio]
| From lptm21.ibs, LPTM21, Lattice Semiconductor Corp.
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|   Model lvc180f080caaaaaaaio
[Model]   lvc180f080caaaaaaaio
Model_type   I/O
Polarity   Non-Inverting
Enable   Active-Low
Vinl =   0.6300V
Vinh =   1.1700V
Vmeas =   0.9000V
Cref =   0.0F
Rref =   1.0000M
Vref =   0.0V
C_comp   4.2000pF   3.8000pF   7.5000pF
[Temperature Range]   25.0000   0.1050k   -40.0000
[Voltage Range]   1.8000V   1.7100V   1.8900V
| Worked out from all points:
|   slope of the pulldown table from 0 to 0.27 V, typ, clamps not added: 24.4 ohm
|   slope of the pullup table from 0 to 0.27 V, typ, clamps not added: 24.1 ohm
|   GND clamp passes 1 mA (typ) near -0.44 V on its own axis
|   rising waveform, R_fixture 50.0000, V_fixture 1.8000: 20-80 % time 208ps typ, 315ps min, 136ps max; typ from 0.706 V to 1.8 V
|   rising waveform, R_fixture 50.0000, V_fixture 0.0: 20-80 % time 276ps typ, 394ps min, 161ps max; typ from 0 V to 1.12 V
|   falling waveform, R_fixture 50.0000, V_fixture 0.0: 20-80 % time 168ps typ, 247ps min, 124ps max; typ from 1.12 V to 0 V
|   falling waveform, R_fixture 50.0000, V_fixture 1.8000: 20-80 % time 240ps typ, 322ps min, 172ps max; typ from 1.8 V to 0.706 V
[Pulldown]
|Voltage   I(typ)   I(min)   I(max)
-1.8V     -28.04mA   -19.11mA   -37.59mA
-1.02V    -26.67mA   -18.17mA   -35.8mA
-480mV    -21.13mA   -14.49mA   -28.88mA
-360mV    -16.88mA   -11.12mA   -23.63mA
300mV     12.13mA    7.438mA    17.91mA
720mV     21.99mA    13.12mA    33.04mA
1.2V      25.28mA    15mA       37.83mA
2.22V     27.24mA    16.57mA    40.4mA
2.4V      28.39mA    19.5mA     40.78mA
2.58V     32.79mA    26.29mA    43.89mA
2.94V     51.36mA    43.26mA    60.07mA
3.6V      96.88mA    78.79mA    118.4mA
[Pullup]
|Voltage   I(typ)   I(min)   I(max)
-1.8V     145.6mA    113.4mA    188.4mA
-1.38V    102.8mA    80.07mA    133.3mA
-1.14V    80.53mA    61.88mA    103.1mA
-900mV    57.63mA    44.12mA    77.3mA
-660mV    38.39mA    28.01mA    52.58mA
-420mV    22.56mA    16.01mA    31.52mA
-60mV     2.891mA    1.987mA    4.173mA
180mV     -7.851mA   -5.303mA   -11.59mA
420mV     -16.12mA   -10.74mA   -24.24mA
720mV     -22.82mA   -14.89mA   -35.34mA
1.08V     -25.78mA   -16.44mA   -41.49mA
3.6V      -30.5mA    -19.25mA   -49.95mA
[GND_clamp]
|Voltage   I(typ)   I(min)   I(max)
-1.8V     -240.2mA   -229.4mA   -254.3mA
-1.2V     -86.19mA   -82.93mA   -94.91mA
-1.17V    -80.47mA   -77.11mA   -89.34mA
-1.11V    -69.48mA   -65.79mA   -78.91mA
-1.02V    -54.51mA   -49.88mA   -65.73mA
-930mV    -42.28mA   -35.92mA   -54.97mA
-780mV    -26.18mA   -18.61mA   -35.3mA
-690mV    -17.17mA   -10.9mA    -23.59mA
-570mV    -7.078mA   -3.876mA   -10.05mA
-450mV    -1.251mA   -635.5uA   -1.696mA
0V        0A         0A         0A
3.6V      0A         0A         0A
[POWER_clamp]
|Voltage   I(typ)   I(min)   I(max)
-1.8V     203.7uA    128.2uA    323.8uA
-1.26V    142.4uA    86.29uA    236uA
-1.02V    121.8uA    71.14uA    208.7uA
-840mV    110.1uA    61.88uA    195.8uA
-420mV    99.75uA    49.18uA    190.5uA
720mV     94.2uA     45.56uA    180uA
1.08V     88.67uA    43.9uA     162.5uA
1.26V     79.17uA    41.55uA    135.8uA
1.44V     61.82uA    35.76uA    94.02uA
1.62V     35.65uA    25.36uA    35.72uA
1.8V      -30.34nA   9.798uA    -37.95uA
3.6V      -30.34nA   -1.798uA   -37.95uA
[Ramp]
| variable   typ   min   max
dV/dt_r  0.6595/0.2731n   0.4800/0.3897n   0.8315/0.1598n
dV/dt_f  0.6558/0.2373n   0.4344/0.3184n   0.8230/0.1701n
R_load = 50.0000
[Rising Waveform]
R_fixture=   50.0000
V_fixture=   1.8000
V_fixture_min=   1.7100
V_fixture_max=   1.8900
|time   V(typ)   V(min)   V(max)
0s        705.7mV    985.2mV    516.5mV
606.1ps   705.7mV    985.2mV    533mV
808.1ps   702.7mV    985.2mV    1.735V
1.01ns    854.5mV    985.2mV    1.861V
1.212ns   1.53V      986.7mV    1.877V
1.313ns   1.715V     982.7mV    1.881V
1.515ns   1.775V     980.5mV    1.885V
1.818ns   1.788V     1.436V     1.887V
2.222ns   1.795V     1.685V     1.888V
10ns      1.799V     1.709V     1.888V
[Rising Waveform]
R_fixture=   50.0000
V_fixture=   0.0
V_fixture_min=   0.0
V_fixture_max=   0.0
|time   V(typ)   V(min)   V(max)
0s        406.8nV    605nV      302.9nV
707.1ps   -44.05uV   730.6nV    42.27mV
909.1ps   -4.79mV    13.23uV    1.128V
1.111ns   -12.1mV    23.23uV    1.318V
1.313ns   581.8mV    -541.2uV   1.357V
1.717ns   1.028V     -27.68mV   1.38V
1.919ns   1.068V     30.61mV    1.383V
2.323ns   1.101V     602.8mV    1.385V
2.929ns   1.116V     745.8mV    1.386V
10ns      1.121V     799.9mV    1.386V
[Falling Waveform]
R_fixture=   50.0000
V_fixture=   0.0
V_fixture_min=   0.0
V_fixture_max=   0.0
|time   V(typ)   V(min)   V(max)
0s        1.121V     800mV      1.386V
707.1ps   1.121V     800mV      1.303V
808.1ps   1.121V     800mV      446.4mV
1.01ns    1.121V     800mV      32.71mV
1.111ns   1.081V     800mV      19.26mV
1.313ns   269.8mV    800mV      7.705mV
1.515ns   31.28mV    800.3mV    3.12mV
1.818ns   11.26mV    789.1mV    796.5uV
2.424ns   2.171mV    26.73mV    92.1uV
10ns      -16.23uV   -10.35uV   184.5nV
[Falling Waveform]
R_fixture=   50.0000
V_fixture=   1.8000
V_fixture_min=   1.7100
V_fixture_max=   1.8900
|time   V(typ)   V(min)   V(max)
0s        1.799V     1.709V     1.888V
707.1ps   1.799V     1.709V     1.898V
909.1ps   1.8V       1.709V     837.3mV
1.212ns   1.756V     1.709V     555mV
1.313ns   1.4V       1.709V     540.6mV
1.515ns   902.1mV    1.71V      526.7mV
2.02ns    735mV      1.721V     517.8mV
2.424ns   716.2mV    1.147V     516.8mV
2.828ns   709.5mV    1.03V      516.6mV
10ns      705.7mV    985.2mV    516.5mV
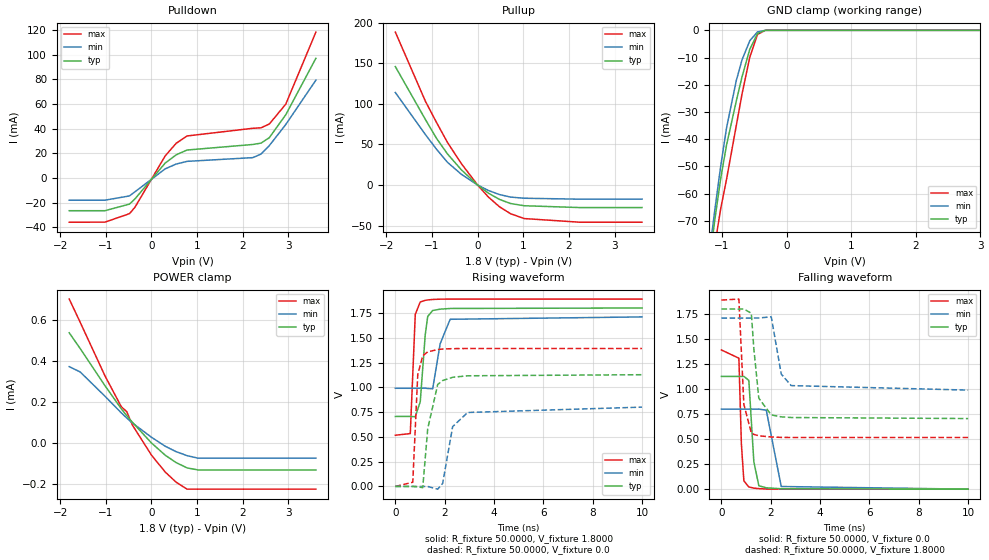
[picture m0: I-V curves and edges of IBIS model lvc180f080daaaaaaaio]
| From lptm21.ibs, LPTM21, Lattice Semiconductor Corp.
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|   Model lvc180f080daaaaaaaio
[Model]   lvc180f080daaaaaaaio
Model_type   I/O
Polarity   Non-Inverting
Enable   Active-Low
Vinl =   0.6300V
Vinh =   1.1700V
Vmeas =   0.9000V
Cref =   0.0F
Rref =   1.0000M
Vref =   0.0V
C_comp   4.2000pF   3.8000pF   7.5000pF
[Temperature Range]   25.0000   0.1050k   -40.0000
[Voltage Range]   1.8000V   1.7100V   1.8900V
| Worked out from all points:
|   slope of the pulldown table from 0 to 0.27 V, typ, clamps not added: 24.4 ohm
|   slope of the pullup table from 0 to 0.27 V, typ, clamps not added: 24.1 ohm
|   GND clamp passes 1 mA (typ) near -0.44 V on its own axis
|   rising waveform, R_fixture 50.0000, V_fixture 1.8000: 20-80 % time 209ps typ, 313ps min, 136ps max; typ from 0.706 V to 1.8 V
|   rising waveform, R_fixture 50.0000, V_fixture 0.0: 20-80 % time 279ps typ, 394ps min, 162ps max; typ from 0 V to 1.13 V
|   falling waveform, R_fixture 50.0000, V_fixture 0.0: 20-80 % time 169ps typ, 247ps min, 126ps max; typ from 1.13 V to 0 V
|   falling waveform, R_fixture 50.0000, V_fixture 1.8000: 20-80 % time 243ps typ, 321ps min, 176ps max; typ from 1.8 V to 0.706 V
[Pulldown]
|Voltage   I(typ)   I(min)   I(max)
-1.8V     -26.51mA   -17.99mA   -35.82mA
-1.02V    -26.51mA   -17.99mA   -35.8mA
-480mV    -21.13mA   -14.49mA   -28.88mA
-360mV    -16.88mA   -11.12mA   -23.63mA
300mV     12.13mA    7.438mA    17.91mA
540mV     18.81mA    11.34mA    28.14mA
780mV     22.72mA    13.53mA    34.13mA
2.22V     27.23mA    16.56mA    40.37mA
2.4V      28.35mA    19.48mA    40.75mA
2.58V     32.73mA    26.3mA     43.83mA
2.94V     51.33mA    43.41mA    59.91mA
3.6V      97.14mA    79.42mA    118.4mA
[Pullup]
|Voltage   I(typ)   I(min)   I(max)
-1.8V     145.8mA    113.9mA    188.3mA
-1.14V    80.46mA    61.95mA    102.9mA
-900mV    57.55mA    44.12mA    77.17mA
-660mV    38.35mA    27.98mA    52.52mA
-360mV    18.98mA    13.41mA    26.74mA
0V        -3.54nA    -3.258nA   -5.095nA
240mV     -10.14mA   -6.833mA   -15.02mA
480mV     -17.77mA   -11.8mA    -26.85mA
720mV     -22.81mA   -14.89mA   -35.3mA
1.02V     -25.57mA   -16.33mA   -41.35mA
2.22V     -27.78mA   -17.47mA   -45.81mA
3.6V      -27.78mA   -17.47mA   -45.83mA
[GND_clamp]
|Voltage   I(typ)   I(min)   I(max)
-1.8V     -240.1mA   -229.3mA   -254.1mA
-1.2V     -86.06mA   -82.86mA   -94.69mA
-1.17V    -80.34mA   -77.04mA   -89.11mA
-1.11V    -69.35mA   -65.72mA   -78.69mA
-1.02V    -54.38mA   -49.81mA   -65.51mA
-930mV    -42.15mA   -35.85mA   -54.74mA
-780mV    -26.05mA   -18.53mA   -35.08mA
-690mV    -17.04mA   -10.83mA   -23.36mA
-570mV    -6.946mA   -3.801mA   -9.827mA
-450mV    -1.119mA   -561.2uA   -1.47mA
-330mV    0A         -3.874uA   0A
3.6V      0A         0A         0A
[POWER_clamp]
|Voltage   I(typ)   I(min)   I(max)
-1.8V     538.6uA    373.2uA    703.6uA
-1.56V    461.4uA    347.2uA    589.9uA
-1.02V    280.9uA    229uA      329.2uA
-660mV    167.1uA    147.2uA    177.1uA
-540mV    133.5uA    121.8uA    152.7uA
-420mV    101.7uA    98.16uA    88.49uA
0V        38.11nA    27.94uA    -59.25uA
300mV     -59.54uA   -15.82uA   -141.8uA
540mV     -96.02uA   -42.44uA   -191.8uA
780mV     -121.8uA   -62.04uA   -225.9uA
1.02V     -132uA     -74.33uA   -225.9uA
3.6V      -132uA     -74.33uA   -225.9uA
[Ramp]
| variable   typ   min   max
dV/dt_r  0.6627/0.2764n   0.4800/0.3897n   0.8343/0.1605n
dV/dt_f  0.6566/0.2407n   0.4319/0.3182n   0.8241/0.1744n
R_load = 50.0000
[Rising Waveform]
R_fixture=   50.0000
V_fixture=   1.8000
V_fixture_min=   1.7100
V_fixture_max=   1.8900
|time   V(typ)   V(min)   V(max)
0s        705.7mV    990.1mV    516.5mV
606.1ps   705.7mV    990.1mV    533mV
808.1ps   702.7mV    990.1mV    1.735V
1.01ns    854.5mV    990.1mV    1.861V
1.212ns   1.53V      991.7mV    1.877V
1.313ns   1.715V     987.6mV    1.881V
1.515ns   1.775V     985.5mV    1.886V
1.818ns   1.788V     1.44V      1.889V
2.222ns   1.795V     1.686V     1.89V
10ns      1.8V       1.71V      1.89V
[Rising Waveform]
R_fixture=   50.0000
V_fixture=   0.0
V_fixture_min=   0.0
V_fixture_max=   0.0
|time   V(typ)   V(min)   V(max)
0s        406.8nV    605nV      302.9nV
707.1ps   -44.05uV   730.6nV    42.27mV
909.1ps   -4.79mV    13.23uV    1.128V
1.111ns   -12.1mV    23.23uV    1.318V
1.313ns   581.8mV    -541.2uV   1.357V
1.717ns   1.028V     -27.68mV   1.381V
1.919ns   1.068V     30.61mV    1.386V
2.323ns   1.101V     602.8mV    1.39V
2.929ns   1.116V     745.8mV    1.391V
10ns      1.127V     799.9mV    1.391V
[Falling Waveform]
R_fixture=   50.0000
V_fixture=   0.0
V_fixture_min=   0.0
V_fixture_max=   0.0
|time   V(typ)   V(min)   V(max)
0s        1.127V     800mV      1.391V
707.1ps   1.127V     800mV      1.309V
808.1ps   1.127V     800mV      454.3mV
909.1ps   1.127V     800mV      82.83mV
1.111ns   1.087V     800mV      22.14mV
1.313ns   276.1mV    800mV      10.37mV
1.515ns   34.13mV    800.3mV    5.31mV
1.818ns   13.37mV    789.1mV    1.531mV
2.424ns   4.191mV    26.73mV    119.1uV
10ns      11.79uV    -10.35uV   -8.485uV
[Falling Waveform]
R_fixture=   50.0000
V_fixture=   1.8000
V_fixture_min=   1.7100
V_fixture_max=   1.8900
|time   V(typ)   V(min)   V(max)
0s        1.8V       1.71V      1.89V
707.1ps   1.8V       1.71V      1.9V
909.1ps   1.801V     1.71V      846.4mV
1.212ns   1.758V     1.71V      562.6mV
1.313ns   1.404V     1.71V      547.8mV
1.515ns   909mV      1.711V     533.1mV
2.02ns    742mV      1.722V     521.8mV
2.424ns   722.8mV    1.151V     517.3mV
2.828ns   716.1mV    1.035V     516.7mV
10ns      705.7mV    990.1mV    516.6mV
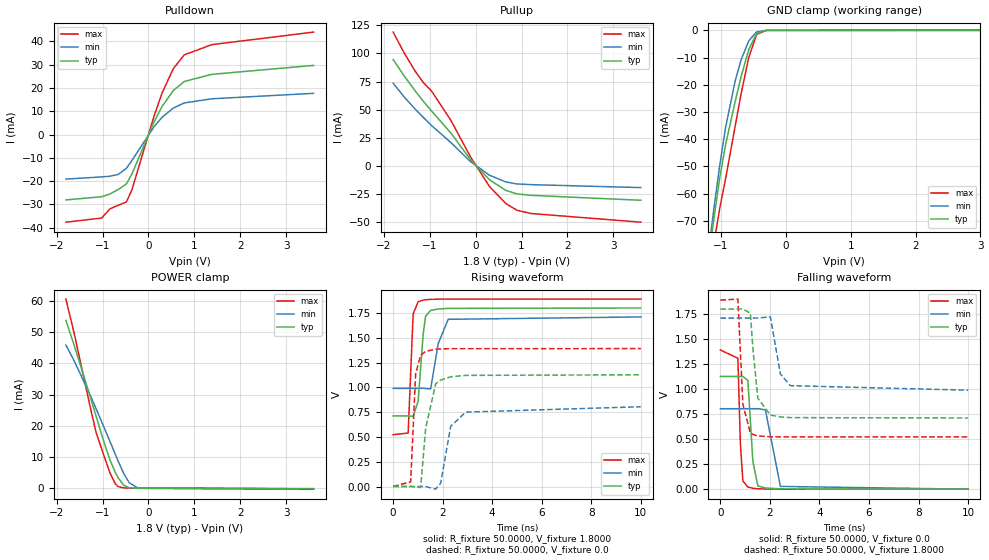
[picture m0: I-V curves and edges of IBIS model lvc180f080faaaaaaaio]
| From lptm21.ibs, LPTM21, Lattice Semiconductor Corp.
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|   Model lvc180f080faaaaaaaio
[Model]   lvc180f080faaaaaaaio
Model_type   I/O
Polarity   Non-Inverting
Enable   Active-Low
Vinl =   0.6300V
Vinh =   1.1700V
Vmeas =   0.9000V
Cref =   0.0F
Rref =   1.0000M
Vref =   0.0V
C_comp   4.2000pF   3.8000pF   7.5000pF
[Temperature Range]   25.0000   0.1050k   -40.0000
[Voltage Range]   1.8000V   1.7100V   1.8900V
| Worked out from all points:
|   slope of the pulldown table from 0 to 0.27 V, typ, clamps not added: 24.4 ohm
|   slope of the pullup table from 0 to 0.27 V, typ, clamps not added: 24.1 ohm
|   GND clamp passes 1 mA (typ) near -0.44 V on its own axis
|   POWER clamp passes 1 mA (typ) near -0.54 V on its own axis
|   rising waveform, R_fixture 50.0000, V_fixture 1.8000: 20-80 % time 207ps typ, 313ps min, 136ps max; typ from 0.712 V to 1.8 V
|   rising waveform, R_fixture 50.0000, V_fixture 0.0: 20-80 % time 275ps typ, 394ps min, 161ps max; typ from 0.002 V to 1.13 V
|   falling waveform, R_fixture 50.0000, V_fixture 0.0: 20-80 % time 169ps typ, 247ps min, 125ps max; typ from 1.13 V to 0.002 V
|   falling waveform, R_fixture 50.0000, V_fixture 1.8000: 20-80 % time 240ps typ, 321ps min, 174ps max; typ from 1.8 V to 0.712 V
[Pulldown]
|Voltage   I(typ)   I(min)   I(max)
-1.8V     -28.04mA   -19.11mA   -37.59mA
-1.02V    -26.67mA   -18.17mA   -35.8mA
-840mV    -25.49mA   -17.88mA   -31.86mA
-660mV    -23.58mA   -17.1mA    -30.34mA
-480mV    -21.14mA   -14.49mA   -28.89mA
-360mV    -16.88mA   -11.12mA   -23.64mA
120mV     5.363mA    3.327mA    7.851mA
300mV     12.15mA    7.443mA    17.96mA
540mV     18.83mA    11.34mA    28.18mA
780mV     22.73mA    13.53mA    34.15mA
1.38V     25.8mA     15.32mA    38.53mA
3.6V      29.63mA    17.66mA    43.92mA
[Pullup]
|Voltage   I(typ)   I(min)   I(max)
-1.8V     94.52mA    73.43mA    118.9mA
-1.56V    79.99mA    61.31mA    100.4mA
-1.32V    66.68mA    50.51mA    84.19mA
-1.14V    57.34mA    42.97mA    73.98mA
-960mV    48.67mA    35.8mA     66.37mA
-540mV    29.17mA    20.74mA    40.46mA
-120mV    5.906mA    4.078mA    8.497mA
300mV     -12.29mA   -8.251mA   -18.28mA
660mV     -21.8mA    -14.29mA   -33.52mA
900mV     -24.88mA   -16mA      -39.33mA
1.2V      -26.11mA   -16.61mA   -42.24mA
3.6V      -30.51mA   -19.25mA   -49.98mA
[GND_clamp]
|Voltage   I(typ)   I(min)   I(max)
-1.8V     -240.1mA   -229.3mA   -254mA
-1.2V     -86.06mA   -82.86mA   -94.68mA
-1.17V    -80.34mA   -77.04mA   -89.1mA
-1.11V    -69.35mA   -65.72mA   -78.68mA
-1.02V    -54.38mA   -49.81mA   -65.5mA
-930mV    -42.15mA   -35.85mA   -54.73mA
-780mV    -26.05mA   -18.53mA   -35.07mA
-690mV    -17.04mA   -10.83mA   -23.37mA
-570mV    -6.958mA   -3.808mA   -9.842mA
-450mV    -1.149mA   -576.7uA   -1.52mA
-300mV    -18.2uA    -16.01uA   -13uA
3.6V      0A         0A         0A
[POWER_clamp]
|Voltage   I(typ)   I(min)   I(max)
-1.8V     53.66mA    45.8mA     60.51mA
-1.62V    45.76mA    40.78mA    49.57mA
-1.26V    28.84mA    29.42mA    25.34mA
-1.14V    22.99mA    25.38mA    17.77mA
-960mV    14.31mA    19.19mA    10.02mA
-840mV    9.109mA    15mA       4.931mA
-720mV    5.041mA    10.79mA    1.399mA
-660mV    3.38mA     8.712mA    551.7uA
-540mV    1.01mA     4.773mA    153.1uA
-420mV    197.6uA    1.797mA    88.49uA
-240mV    59.36uA    194.4uA    21.2uA
3.6V      -142.9uA   -81.03uA   -252.6uA
[Ramp]
| variable   typ   min   max
dV/dt_r  0.6615/0.2719n   0.4821/0.3897n   0.8328/0.1592n
dV/dt_f  0.6527/0.2380n   0.4319/0.3182n   0.8202/0.1719n
R_load = 50.0000
[Rising Waveform]
R_fixture=   50.0000
V_fixture=   1.8000
V_fixture_min=   1.7100
V_fixture_max=   1.8900
|time   V(typ)   V(min)   V(max)
0s        712.2mV    990.1mV    523mV
606.1ps   712.2mV    990.1mV    540.2mV
808.1ps   709.1mV    990.1mV    1.741V
1.01ns    862.2mV    990.1mV    1.863V
1.212ns   1.537V     991.7mV    1.879V
1.313ns   1.719V     987.6mV    1.883V
1.515ns   1.776V     985.5mV    1.887V
1.818ns   1.79V      1.44V      1.889V
2.222ns   1.796V     1.686V     1.89V
10ns      1.8V       1.71V      1.89V
[Rising Waveform]
R_fixture=   50.0000
V_fixture=   0.0
V_fixture_min=   0.0
V_fixture_max=   0.0
|time   V(typ)   V(min)   V(max)
0s        1.923mV    1.54mV     2.453mV
707.1ps   1.879mV    1.541mV    47.58mV
909.1ps   -2.884mV   1.553mV    1.137V
1.111ns   -8.391mV   1.564mV    1.324V
1.313ns   588.3mV    995.9uV    1.363V
1.717ns   1.035V     -25.54mV   1.385V
1.919ns   1.074V     33.78mV    1.388V
2.323ns   1.107V     607.4mV    1.39V
2.929ns   1.121V     750.9mV    1.39V
10ns      1.127V     805mV      1.391V
[Falling Waveform]
R_fixture=   50.0000
V_fixture=   0.0
V_fixture_min=   0.0
V_fixture_max=   0.0
|time   V(typ)   V(min)   V(max)
0s        1.127V     805mV      1.391V
707.1ps   1.127V     805mV      1.309V
808.1ps   1.127V     805mV      454.3mV
909.1ps   1.127V     805mV      82.83mV
1.111ns   1.087V     805mV      22.14mV
1.313ns   276.1mV    805mV      10.37mV
1.515ns   34.13mV    805.3mV    5.669mV
1.818ns   13.37mV    794.2mV    3.272mV
2.424ns   4.198mV    28.84mV    2.543mV
10ns      1.934mV    1.543mV    2.443mV
[Falling Waveform]
R_fixture=   50.0000
V_fixture=   1.8000
V_fixture_min=   1.7100
V_fixture_max=   1.8900
|time   V(typ)   V(min)   V(max)
0s        1.8V       1.71V      1.89V
707.1ps   1.8V       1.71V      1.9V
909.1ps   1.801V     1.71V      846.4mV
1.212ns   1.758V     1.71V      562.6mV
1.313ns   1.404V     1.71V      547.8mV
1.515ns   909mV      1.711V     533.1mV
2.02ns    742mV      1.722V     524.4mV
2.424ns   722.8mV    1.151V     523.3mV
2.828ns   716.1mV    1.035V     523mV
10ns      712.2mV    990.1mV    522.9mV
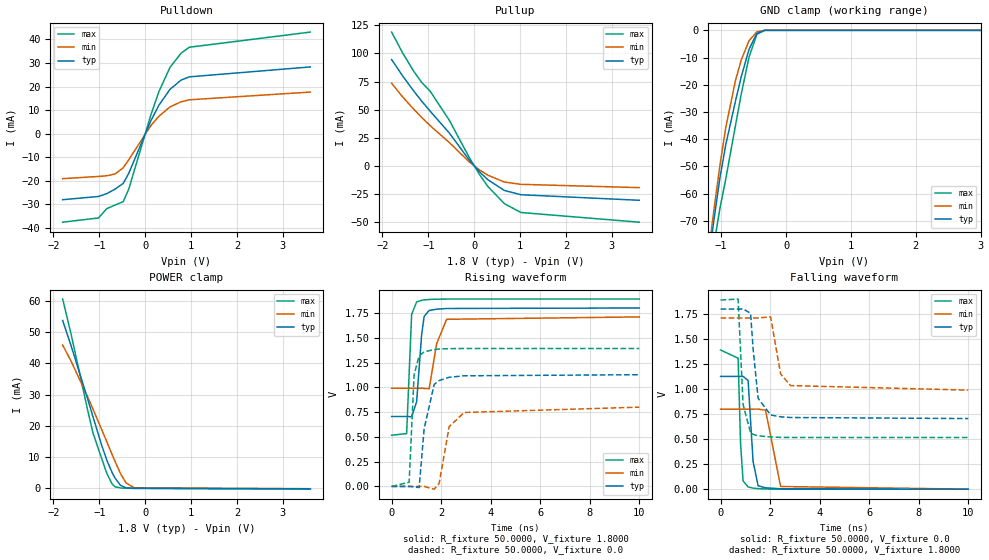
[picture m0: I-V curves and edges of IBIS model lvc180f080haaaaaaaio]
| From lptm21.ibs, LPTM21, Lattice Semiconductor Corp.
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|   Model lvc180f080haaaaaaaio
[Model]   lvc180f080haaaaaaaio
Model_type   I/O
Polarity   Non-Inverting
Enable   Active-Low
Vinl =   0.6300V
Vinh =   1.1700V
Vmeas =   0.9000V
Cref =   0.0F
Rref =   1.0000M
Vref =   0.0V
C_comp   4.2000pF   3.8000pF   7.5000pF
[Temperature Range]   25.0000   0.1050k   -40.0000
[Voltage Range]   1.8000V   1.7100V   1.8900V
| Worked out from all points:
|   slope of the pulldown table from 0 to 0.27 V, typ, clamps not added: 24.4 ohm
|   slope of the pullup table from 0 to 0.27 V, typ, clamps not added: 24.1 ohm
|   GND clamp passes 1 mA (typ) near -0.44 V on its own axis
|   POWER clamp passes 1 mA (typ) near -0.54 V on its own axis
|   rising waveform, R_fixture 50.0000, V_fixture 1.8000: 20-80 % time 209ps typ, 313ps min, 136ps max; typ from 0.706 V to 1.8 V
|   rising waveform, R_fixture 50.0000, V_fixture 0.0: 20-80 % time 279ps typ, 394ps min, 162ps max; typ from 0 V to 1.13 V
|   falling waveform, R_fixture 50.0000, V_fixture 0.0: 20-80 % time 169ps typ, 247ps min, 126ps max; typ from 1.13 V to 0 V
|   falling waveform, R_fixture 50.0000, V_fixture 1.8000: 20-80 % time 243ps typ, 321ps min, 176ps max; typ from 1.8 V to 0.706 V
[Pulldown]
|Voltage   I(typ)   I(min)   I(max)
-1.8V     -28.04mA   -19.11mA   -37.59mA
-1.02V    -26.67mA   -18.17mA   -35.8mA
-840mV    -25.49mA   -17.88mA   -31.86mA
-660mV    -23.58mA   -17.1mA    -30.33mA
-480mV    -21.13mA   -14.49mA   -28.88mA
-360mV    -16.88mA   -11.12mA   -23.63mA
120mV     5.347mA    3.321mA    7.81mA
300mV     12.13mA    7.438mA    17.91mA
540mV     18.81mA    11.34mA    28.14mA
780mV     22.72mA    13.53mA    34.13mA
960mV     24.12mA    14.37mA    36.7mA
3.6V      28.34mA    17.66mA    43.13mA
[Pullup]
|Voltage   I(typ)   I(min)   I(max)
-1.8V     94.52mA    73.43mA    118.9mA
-1.56V    79.99mA    61.31mA    100.4mA
-1.32V    66.68mA    50.51mA    84.19mA
-1.14V    57.34mA    42.97mA    73.98mA
-960mV    48.67mA    35.8mA     66.37mA
-540mV    29.17mA    20.74mA    40.46mA
-120mV    5.906mA    4.078mA    8.497mA
120mV     -5.379mA   -3.648mA   -7.897mA
300mV     -12.29mA   -8.251mA   -18.28mA
660mV     -21.8mA    -14.29mA   -33.52mA
1.02V     -25.57mA   -16.33mA   -41.35mA
3.6V      -30.5mA    -19.25mA   -49.95mA
[GND_clamp]
|Voltage   I(typ)   I(min)   I(max)
-1.8V     -240.1mA   -229.3mA   -254.1mA
-1.2V     -86.06mA   -82.86mA   -94.69mA
-1.17V    -80.34mA   -77.04mA   -89.11mA
-1.11V    -69.35mA   -65.72mA   -78.69mA
-1.02V    -54.38mA   -49.81mA   -65.51mA
-930mV    -42.15mA   -35.85mA   -54.74mA
-780mV    -26.05mA   -18.53mA   -35.08mA
-690mV    -17.04mA   -10.83mA   -23.36mA
-570mV    -6.946mA   -3.801mA   -9.827mA
-450mV    -1.119mA   -561.2uA   -1.47mA
-330mV    0A         -3.874uA   0A
3.6V      0A         0A         0A
[POWER_clamp]
|Voltage   I(typ)   I(min)   I(max)
-1.8V     53.66mA    45.8mA     60.51mA
-1.62V    45.76mA    40.78mA    49.57mA
-1.26V    28.84mA    29.42mA    25.34mA
-1.14V    22.99mA    25.38mA    17.77mA
-960mV    14.31mA    19.19mA    10.02mA
-840mV    9.109mA    15mA       4.931mA
-720mV    5.041mA    10.79mA    1.399mA
-660mV    3.38mA     8.712mA    551.7uA
-540mV    1.01mA     4.773mA    153.1uA
-420mV    197.6uA    1.797mA    88.49uA
-240mV    59.36uA    194.4uA    21.2uA
3.6V      -132uA     -74.33uA   -225.9uA
[Ramp]
| variable   typ   min   max
dV/dt_r  0.6627/0.2764n   0.4800/0.3897n   0.8343/0.1605n
dV/dt_f  0.6566/0.2407n   0.4319/0.3182n   0.8241/0.1744n
R_load = 50.0000
[Rising Waveform]
R_fixture=   50.0000
V_fixture=   1.8000
V_fixture_min=   1.7100
V_fixture_max=   1.8900
|time   V(typ)   V(min)   V(max)
0s        705.7mV    990.1mV    516.5mV
606.1ps   705.7mV    990.1mV    533mV
808.1ps   702.7mV    990.1mV    1.735V
1.01ns    854.5mV    990.1mV    1.861V
1.212ns   1.53V      991.7mV    1.877V
1.313ns   1.715V     987.6mV    1.881V
1.515ns   1.775V     985.5mV    1.886V
1.818ns   1.788V     1.44V      1.889V
2.222ns   1.795V     1.686V     1.89V
10ns      1.8V       1.71V      1.89V
[Rising Waveform]
R_fixture=   50.0000
V_fixture=   0.0
V_fixture_min=   0.0
V_fixture_max=   0.0
|time   V(typ)   V(min)   V(max)
0s        406.8nV    605nV      302.9nV
707.1ps   -44.05uV   730.6nV    42.27mV
909.1ps   -4.79mV    13.23uV    1.128V
1.111ns   -12.1mV    23.23uV    1.318V
1.313ns   581.8mV    -541.2uV   1.357V
1.717ns   1.028V     -27.68mV   1.381V
1.919ns   1.068V     30.61mV    1.386V
2.323ns   1.101V     602.8mV    1.39V
2.929ns   1.116V     745.8mV    1.391V
10ns      1.127V     799.9mV    1.391V
[Falling Waveform]
R_fixture=   50.0000
V_fixture=   0.0
V_fixture_min=   0.0
V_fixture_max=   0.0
|time   V(typ)   V(min)   V(max)
0s        1.127V     800mV      1.391V
707.1ps   1.127V     800mV      1.309V
808.1ps   1.127V     800mV      454.3mV
909.1ps   1.127V     800mV      82.83mV
1.111ns   1.087V     800mV      22.14mV
1.313ns   276.1mV    800mV      10.37mV
1.515ns   34.13mV    800.3mV    5.31mV
1.818ns   13.37mV    789.1mV    1.531mV
2.424ns   4.191mV    26.73mV    119.1uV
10ns      6.875uV    -14.25uV   -8.239uV
[Falling Waveform]
R_fixture=   50.0000
V_fixture=   1.8000
V_fixture_min=   1.7100
V_fixture_max=   1.8900
|time   V(typ)   V(min)   V(max)
0s        1.8V       1.71V      1.89V
707.1ps   1.8V       1.71V      1.9V
909.1ps   1.801V     1.71V      846.4mV
1.212ns   1.758V     1.71V      562.6mV
1.313ns   1.404V     1.71V      547.8mV
1.515ns   909mV      1.711V     533.1mV
2.02ns    742mV      1.722V     521.8mV
2.424ns   722.8mV    1.151V     517.3mV
2.828ns   716.1mV    1.035V     516.7mV
10ns      705.7mV    990.1mV    516.6mV
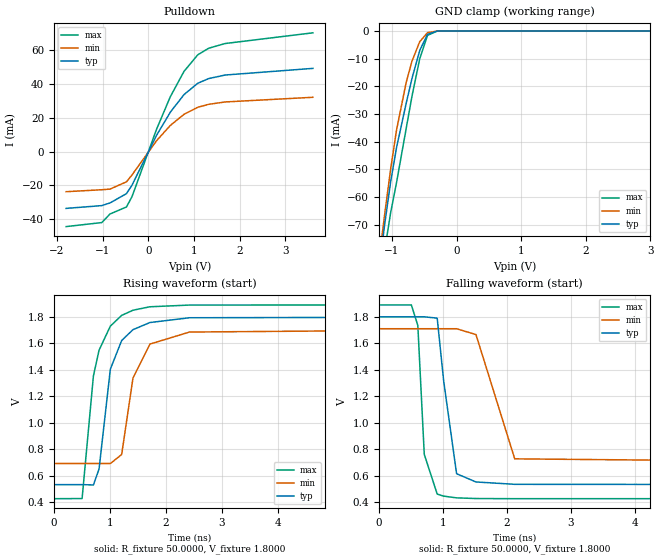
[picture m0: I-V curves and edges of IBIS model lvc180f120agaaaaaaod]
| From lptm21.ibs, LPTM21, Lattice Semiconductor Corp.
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|   Model lvc180f120agaaaaaaod
[Model]   lvc180f120agaaaaaaod
Model_type   I/O_open_drain
Polarity   Non-Inverting
Enable   Active-Low
Vinl =   0.6300V
Vinh =   1.1700V
Vmeas =   0.9000V
Cref =   0.0F
Rref =   1.0000M
Vref =   0.0V
C_comp   4.2000pF   3.8000pF   7.5000pF
[Temperature Range]   25.0000   0.1050k   -40.0000
[Voltage Range]   1.8000V   1.7100V   1.8900V
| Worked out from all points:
|   slope of the pulldown table from 0 to 0.27 V, typ, clamps not added: 19.1 ohm
|   GND clamp passes 1 mA (typ) near -0.44 V on its own axis
|   rising waveform, R_fixture 50.0000, V_fixture 1.8000: 20-80 % time 280ps typ, 299ps min, 293ps max; typ from 0.532 V to 1.8 V
|   falling waveform, R_fixture 50.0000, V_fixture 1.8000: 20-80 % time 151ps typ, 216ps min, 103ps max; typ from 1.8 V to 0.532 V
[Pulldown]
|Voltage   I(typ)   I(min)   I(max)
-1.8V     -33.54mA   -23.67mA   -44.3mA
-1.02V    -31.9mA    -22.52mA   -41.92mA
-840mV    -30.32mA   -22.14mA   -36.85mA
-480mV    -24.82mA   -17.84mA   -32.7mA
-360mV    -19.86mA   -13.82mA   -26.67mA
180mV     9.699mA    6.515mA    13.33mA
480mV     23.34mA    15.48mA    32.48mA
780mV     33.72mA    22.07mA    47.46mA
1.08V     40.41mA    26.21mA    57.22mA
1.32V     43.19mA    27.98mA    61.12mA
1.68V     45.28mA    29.37mA    63.91mA
3.6V      49.21mA    32.13mA    70.23mA
[GND_clamp]
|Voltage   I(typ)   I(min)   I(max)
-1.8V     -240.2mA   -229.4mA   -254.3mA
-1.2V     -86.17mA   -82.92mA   -94.88mA
-1.17V    -80.46mA   -77.1mA    -89.31mA
-1.11V    -69.46mA   -65.78mA   -78.88mA
-1.02V    -54.49mA   -49.87mA   -65.69mA
-930mV    -42.26mA   -35.91mA   -54.92mA
-780mV    -26.15mA   -18.58mA   -35.26mA
-690mV    -17.13mA   -10.88mA   -23.54mA
-570mV    -7.027mA   -3.837mA   -9.983mA
-450mV    -1.178mA   -585.4uA   -1.585mA
-300mV    -18.71uA   -15.93uA   -16.53uA
3.6V      0A         0A         0A
[Ramp]
| variable   typ   min   max
dV/dt_r  0.7610/0.2772n   0.6111/0.2958n   0.8787/0.2900n
dV/dt_f  0.7610/0.1492n   0.6111/0.2136n   0.8787/0.1022n
R_load = 50.0000
[Rising Waveform]
R_fixture=   50.0000
V_fixture=   1.8000
V_fixture_min=   1.7100
V_fixture_max=   1.8900
|time   V(typ)   V(min)   V(max)
0s        531.6mV    691.5mV    425.4mV
505.1ps   531.6mV    691.5mV    426.5mV
707.1ps   529.3mV    691.4mV    1.353V
808.1ps   650.1mV    691.5mV    1.548V
1.01ns    1.405V     691.2mV    1.73V
1.212ns   1.621V     759.4mV    1.811V
1.414ns   1.703V     1.338V     1.85V
1.717ns   1.757V     1.594V     1.876V
2.424ns   1.793V     1.685V     1.889V
10ns      1.8V       1.71V      1.89V
[Falling Waveform]
R_fixture=   50.0000
V_fixture=   1.8000
V_fixture_min=   1.7100
V_fixture_max=   1.8900
|time   V(typ)   V(min)   V(max)
0s        1.8V       1.71V      1.89V
505.1ps   1.8V       1.71V      1.89V
606.1ps   1.8V       1.71V      1.735V
707.1ps   1.8V       1.71V      760mV
909.1ps   1.79V      1.71V      460.5mV
1.01ns    1.316V     1.71V      444.7mV
1.212ns   614.3mV    1.71V      431.7mV
1.515ns   551.9mV    1.666V     426.6mV
2.121ns   534mV      726.6mV    425.5mV
10ns      531.6mV    691.5mV    425.4mV
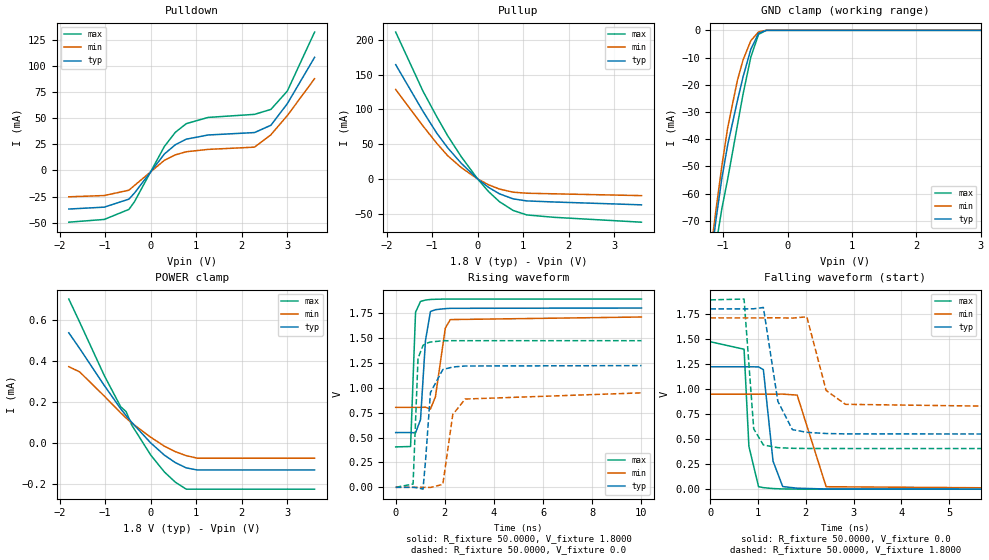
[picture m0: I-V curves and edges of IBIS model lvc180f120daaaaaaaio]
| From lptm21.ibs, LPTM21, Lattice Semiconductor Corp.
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|   Model lvc180f120daaaaaaaio
[Model]   lvc180f120daaaaaaaio
Model_type   I/O
Polarity   Non-Inverting
Enable   Active-Low
Vinl =   0.6300V
Vinh =   1.1700V
Vmeas =   0.9000V
Cref =   0.0F
Rref =   1.0000M
Vref =   0.0V
C_comp   4.2000pF   3.8000pF   7.5000pF
[Temperature Range]   25.0000   0.1050k   -40.0000
[Voltage Range]   1.8000V   1.7100V   1.8900V
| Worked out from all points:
|   slope of the pulldown table from 0 to 0.27 V, typ, clamps not added: 18.8 ohm
|   slope of the pullup table from 0 to 0.27 V, typ, clamps not added: 20.1 ohm
|   GND clamp passes 1 mA (typ) near -0.44 V on its own axis
|   rising waveform, R_fixture 50.0000, V_fixture 1.8000: 20-80 % time 202ps typ, 308ps min, 128ps max; typ from 0.55 V to 1.8 V
|   rising waveform, R_fixture 50.0000, V_fixture 0.0: 20-80 % time 229ps typ, 363ps min, 143ps max; typ from 0 V to 1.22 V
|   falling waveform, R_fixture 50.0000, V_fixture 0.0: 20-80 % time 157ps typ, 235ps min, 114ps max; typ from 1.22 V to 0 V
|   falling waveform, R_fixture 50.0000, V_fixture 1.8000: 20-80 % time 203ps typ, 295ps min, 139ps max; typ from 1.8 V to 0.55 V
[Pulldown]
|Voltage   I(typ)   I(min)   I(max)
-1.8V     -36.96mA   -25.25mA   -49.57mA
-1.02V    -35.15mA   -24.02mA   -46.92mA
-480mV    -27.47mA   -18.92mA   -37.31mA
-360mV    -21.77mA   -14.48mA   -30.15mA
300mV     15.77mA    9.762mA    23.02mA
540mV     24.65mA    14.95mA    36.55mA
780mV     29.98mA    17.92mA    44.84mA
1.26V     33.99mA    20.19mA    50.82mA
2.28V     36.32mA    22.34mA    53.77mA
2.64V     43.31mA    34.21mA    58.5mA
3V        63.95mA    52.53mA    76.03mA
3.6V      108.4mA    87.98mA    132.6mA
[Pullup]
|Voltage   I(typ)   I(min)   I(max)
-1.8V     164.5mA    128.8mA    211.4mA
-1.2V     97.3mA     76.26mA    126.3mA
-900mV    66.15mA    51.48mA    89.91mA
-660mV    45.02mA    33.58mA    62.38mA
-360mV    22.55mA    16.37mA    32.07mA
0V        -3.578nA   -3.138nA   -5.367nA
240mV     -12.17mA   -8.411mA   -18.2mA
480mV     -21.42mA   -14.58mA   -32.75mA
780mV     -28.7mA    -19.07mA   -45.35mA
1.08V     -31.64mA   -20.57mA   -51.83mA
1.68V     -33.19mA   -21.42mA   -55.25mA
3.6V      -37.29mA   -24.01mA   -62.27mA
[GND_clamp]
|Voltage   I(typ)   I(min)   I(max)
-1.8V     -240.1mA   -229.3mA   -254.1mA
-1.2V     -86.06mA   -82.86mA   -94.69mA
-1.17V    -80.34mA   -77.04mA   -89.11mA
-1.11V    -69.35mA   -65.72mA   -78.69mA
-1.02V    -54.38mA   -49.81mA   -65.51mA
-930mV    -42.15mA   -35.85mA   -54.74mA
-780mV    -26.05mA   -18.53mA   -35.08mA
-690mV    -17.04mA   -10.83mA   -23.36mA
-570mV    -6.946mA   -3.801mA   -9.827mA
-450mV    -1.119mA   -561.2uA   -1.47mA
-330mV    0A         -3.874uA   0A
3.6V      0A         0A         0A
[POWER_clamp]
|Voltage   I(typ)   I(min)   I(max)
-1.8V     538.6uA    373.2uA    703.6uA
-1.56V    461.4uA    347.2uA    589.9uA
-1.02V    280.9uA    229uA      329.2uA
-660mV    167.1uA    147.2uA    177.1uA
-540mV    133.5uA    121.8uA    152.7uA
-420mV    101.7uA    98.16uA    88.49uA
0V        38.11nA    27.94uA    -59.25uA
300mV     -59.54uA   -15.82uA   -141.8uA
540mV     -96.02uA   -42.44uA   -191.8uA
780mV     -121.8uA   -62.04uA   -225.9uA
1.02V     -132uA     -74.33uA   -225.9uA
3.6V      -132uA     -74.33uA   -225.9uA
[Ramp]
| variable   typ   min   max
dV/dt_r  0.7331/0.2268n   0.5691/0.3594n   0.8835/0.1420n
dV/dt_f  0.7502/0.2007n   0.5444/0.2916n   0.8906/0.1381n
R_load = 50.0000
[Rising Waveform]
R_fixture=   50.0000
V_fixture=   1.8000
V_fixture_min=   1.7100
V_fixture_max=   1.8900
|time   V(typ)   V(min)   V(max)
0s        549.6mV    802.6mV    405.7mV
606.1ps   549.6mV    802.6mV    409.8mV
808.1ps   547.2mV    802.6mV    1.758V
1.01ns    679.3mV    802.6mV    1.866V
1.212ns   1.474V     804.2mV    1.88V
1.414ns   1.765V     785.4mV    1.886V
1.616ns   1.783V     908.3mV    1.888V
2.02ns    1.794V     1.599V     1.89V
2.222ns   1.797V     1.684V     1.89V
10ns      1.8V       1.71V      1.89V
[Rising Waveform]
R_fixture=   50.0000
V_fixture=   0.0
V_fixture_min=   0.0
V_fixture_max=   0.0
|time   V(typ)   V(min)   V(max)
0s        335.1nV    508.3nV    248.8nV
707.1ps   -57.36uV   614.4nV    32.97mV
909.1ps   -4.993mV   13.4uV     1.296V
1.111ns   -18.57mV   11.2uV     1.424V
1.212ns   258.9mV    -255.2uV   1.442V
1.414ns   951.4mV    -1.605mV   1.459V
1.919ns   1.183V     30mV       1.471V
2.323ns   1.208V     731mV      1.472V
2.828ns   1.218V     886.2mV    1.472V
10ns      1.222V     948.4mV    1.472V
[Falling Waveform]
R_fixture=   50.0000
V_fixture=   0.0
V_fixture_min=   0.0
V_fixture_max=   0.0
|time   V(typ)   V(min)   V(max)
0s        1.222V     948.4mV    1.472V
707.1ps   1.222V     948.4mV    1.397V
808.1ps   1.222V     948.4mV    427.5mV
1.01ns    1.221V     948.4mV    24.99mV
1.111ns   1.193V     948.4mV    15.28mV
1.313ns   279.8mV    948.5mV    6.02mV
1.515ns   26.18mV    948.9mV    2.383mV
1.818ns   9.629mV    939mV      586.8uV
2.424ns   1.858mV    24.36mV    67.33uV
10ns      -7.862uV   -27.3uV    22uV
[Falling Waveform]
R_fixture=   50.0000
V_fixture=   1.8000
V_fixture_min=   1.7100
V_fixture_max=   1.8900
|time   V(typ)   V(min)   V(max)
0s        1.8V       1.71V      1.89V
707.1ps   1.8V       1.71V      1.898V
909.1ps   1.801V     1.71V      601.8mV
1.111ns   1.814V     1.71V      441.1mV
1.414ns   877.3mV    1.711V     414.3mV
1.717ns   594.6mV    1.708V     408.1mV
2.02ns    567.4mV    1.721V     406.3mV
2.424ns   555.7mV    985.7mV    405.8mV
2.828ns   551.9mV    847mV      405.7mV
10ns      549.6mV    802.7mV    405.7mV
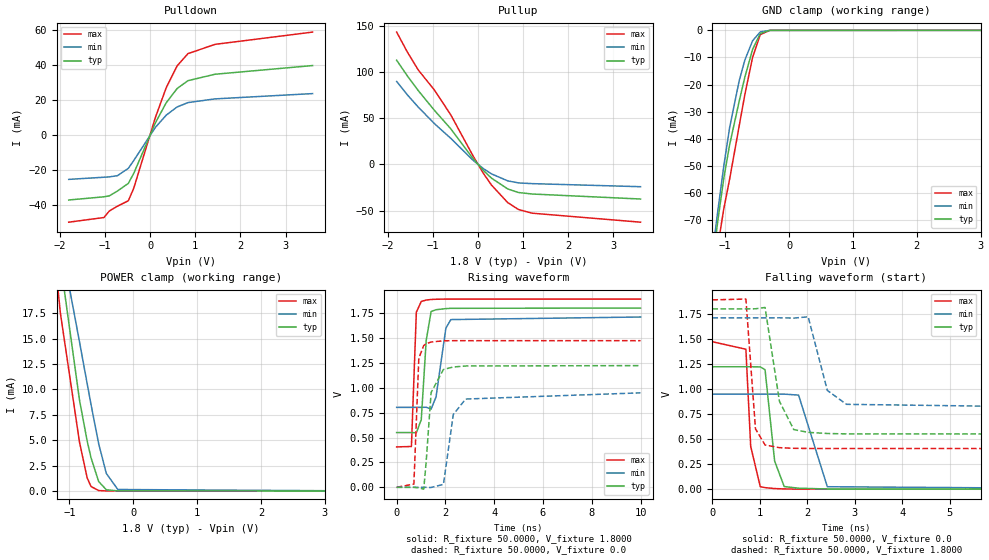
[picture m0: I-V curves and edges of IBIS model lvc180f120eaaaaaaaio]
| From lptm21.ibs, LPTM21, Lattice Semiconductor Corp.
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|   Model lvc180f120eaaaaaaaio
[Model]   lvc180f120eaaaaaaaio
Model_type   I/O
Polarity   Non-Inverting
Enable   Active-Low
Vinl =   0.6300V
Vinh =   1.1700V
Vmeas =   0.9000V
Cref =   0.0F
Rref =   1.0000M
Vref =   0.0V
C_comp   4.2000pF   3.8000pF   7.5000pF
[Temperature Range]   25.0000   0.1050k   -40.0000
[Voltage Range]   1.8000V   1.7100V   1.8900V
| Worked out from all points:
|   slope of the pulldown table from 0 to 0.27 V, typ, clamps not added: 18.7 ohm
|   slope of the pullup table from 0 to 0.27 V, typ, clamps not added: 20 ohm
|   GND clamp passes 1 mA (typ) near -0.44 V on its own axis
|   POWER clamp passes 1 mA (typ) near -0.54 V on its own axis
|   rising waveform, R_fixture 50.0000, V_fixture 1.8000: 20-80 % time 202ps typ, 308ps min, 128ps max; typ from 0.55 V to 1.8 V
|   rising waveform, R_fixture 50.0000, V_fixture 0.0: 20-80 % time 229ps typ, 363ps min, 143ps max; typ from 0 V to 1.22 V
|   falling waveform, R_fixture 50.0000, V_fixture 0.0: 20-80 % time 157ps typ, 235ps min, 114ps max; typ from 1.22 V to 0 V
|   falling waveform, R_fixture 50.0000, V_fixture 1.8000: 20-80 % time 203ps typ, 295ps min, 139ps max; typ from 1.8 V to 0.55 V
[Pulldown]
|Voltage   I(typ)   I(min)   I(max)
-1.8V     -36.99mA   -25.27mA   -49.62mA
-1.02V    -35.18mA   -24.04mA   -46.96mA
-900mV    -34.63mA   -23.85mA   -43.22mA
-720mV    -31.87mA   -23.14mA   -40.51mA
-480mV    -27.54mA   -18.97mA   -37.42mA
-360mV    -21.84mA   -14.53mA   -30.28mA
120mV     6.941mA    4.355mA    10.02mA
360mV     18.37mA    11.31mA    26.96mA
600mV     26.4mA     15.94mA    39.3mA
840mV     30.9mA     18.42mA    46.27mA
1.44V     34.55mA    20.53mA    51.55mA
3.6V      39.49mA    23.54mA    58.53mA
[Pullup]
|Voltage   I(typ)   I(min)   I(max)
-1.8V     112.6mA    89.66mA    143mA
-1.56V    95.47mA    75.02mA    121.2mA
-1.32V    79.68mA    61.9mA     102mA
-960mV    58.24mA    43.92mA    80.12mA
-600mV    38.45mA    28.15mA    53.46mA
-120mV    7.067mA    5.012mA    10.26mA
120mV     -6.463mA   -4.498mA   -9.583mA
300mV     -14.82mA   -10.2mA    -22.29mA
660mV     -26.48mA   -17.77mA   -41.26mA
900mV     -30.38mA   -19.97mA   -48.76mA
1.2V      -31.96mA   -20.75mA   -52.67mA
3.6V      -37.37mA   -24.06mA   -62.41mA
[GND_clamp]
|Voltage   I(typ)   I(min)   I(max)
-1.8V     -240.2mA   -229.4mA   -254.3mA
-1.2V     -86.16mA   -82.91mA   -94.88mA
-1.17V    -80.45mA   -77.09mA   -89.3mA
-1.11V    -69.45mA   -65.77mA   -78.87mA
-1.02V    -54.48mA   -49.86mA   -65.69mA
-930mV    -42.25mA   -35.9mA    -54.92mA
-780mV    -26.14mA   -18.58mA   -35.25mA
-690mV    -17.13mA   -10.87mA   -23.53mA
-570mV    -7.024mA   -3.834mA   -9.978mA
-450mV    -1.176mA   -584.6uA   -1.582mA
-300mV    -18.65uA   -15.9uA    -16.44uA
3.6V      0A         0A         0A
[POWER_clamp]
|Voltage   I(typ)   I(min)   I(max)
-1.8V     52.51mA    44.24mA    59.69mA
-1.68V    47.44mA    41.17mA    52.62mA
-1.5V     39.45mA    36.1mA     41.14mA
-1.26V    28.3mA     28.66mA    24.99mA
-1.14V    22.57mA    24.76mA    17.52mA
-840mV    8.928mA    14.66mA    4.779mA
-720mV    4.91mA     10.55mA    1.28mA
-660mV    3.265mA    8.507mA    435.9uA
-540mV    921.6uA    4.64mA     35.01uA
-420mV    115.2uA    1.718mA    2.184uA
-240mV    3.289uA    139.9uA    57.44nA
3.6V      -31nA      -27.04nA   -40.53nA
[Ramp]
| variable   typ   min   max
dV/dt_r  0.7331/0.2268n   0.5691/0.3594n   0.8835/0.1420n
dV/dt_f  0.7502/0.2007n   0.5444/0.2916n   0.8906/0.1381n
R_load = 50.0000
[Rising Waveform]
R_fixture=   50.0000
V_fixture=   1.8000
V_fixture_min=   1.7100
V_fixture_max=   1.8900
|time   V(typ)   V(min)   V(max)
0s        549.6mV    802.6mV    405.7mV
606.1ps   549.6mV    802.6mV    409.8mV
808.1ps   547.2mV    802.6mV    1.758V
1.01ns    679.3mV    802.6mV    1.866V
1.212ns   1.474V     804.2mV    1.88V
1.414ns   1.765V     785.4mV    1.886V
1.616ns   1.783V     908.3mV    1.888V
2.02ns    1.794V     1.599V     1.89V
2.222ns   1.797V     1.684V     1.89V
10ns      1.8V       1.71V      1.89V
[Rising Waveform]
R_fixture=   50.0000
V_fixture=   0.0
V_fixture_min=   0.0
V_fixture_max=   0.0
|time   V(typ)   V(min)   V(max)
0s        335.1nV    508.3nV    248.8nV
707.1ps   -57.36uV   614.4nV    32.97mV
909.1ps   -4.993mV   13.4uV     1.296V
1.111ns   -18.57mV   11.2uV     1.424V
1.212ns   258.9mV    -255.2uV   1.442V
1.414ns   951.4mV    -1.605mV   1.459V
1.919ns   1.183V     30mV       1.471V
2.323ns   1.208V     731mV      1.472V
2.828ns   1.218V     886.2mV    1.472V
10ns      1.222V     948.4mV    1.472V
[Falling Waveform]
R_fixture=   50.0000
V_fixture=   0.0
V_fixture_min=   0.0
V_fixture_max=   0.0
|time   V(typ)   V(min)   V(max)
0s        1.222V     948.4mV    1.472V
707.1ps   1.222V     948.4mV    1.397V
808.1ps   1.222V     948.4mV    427.5mV
1.01ns    1.221V     948.4mV    24.99mV
1.111ns   1.193V     948.4mV    15.28mV
1.313ns   279.8mV    948.5mV    6.02mV
1.515ns   26.18mV    948.9mV    2.383mV
1.818ns   9.629mV    939mV      586.8uV
2.424ns   1.858mV    24.36mV    67.33uV
10ns      -7.862uV   -27.3uV    22uV
[Falling Waveform]
R_fixture=   50.0000
V_fixture=   1.8000
V_fixture_min=   1.7100
V_fixture_max=   1.8900
|time   V(typ)   V(min)   V(max)
0s        1.8V       1.71V      1.89V
707.1ps   1.8V       1.71V      1.898V
909.1ps   1.801V     1.71V      601.8mV
1.111ns   1.814V     1.71V      441.1mV
1.414ns   877.3mV    1.711V     414.3mV
1.717ns   594.6mV    1.708V     408.1mV
2.02ns    567.4mV    1.721V     406.3mV
2.424ns   555.7mV    985.7mV    405.8mV
2.828ns   551.9mV    847mV      405.7mV
10ns      549.6mV    802.7mV    405.7mV
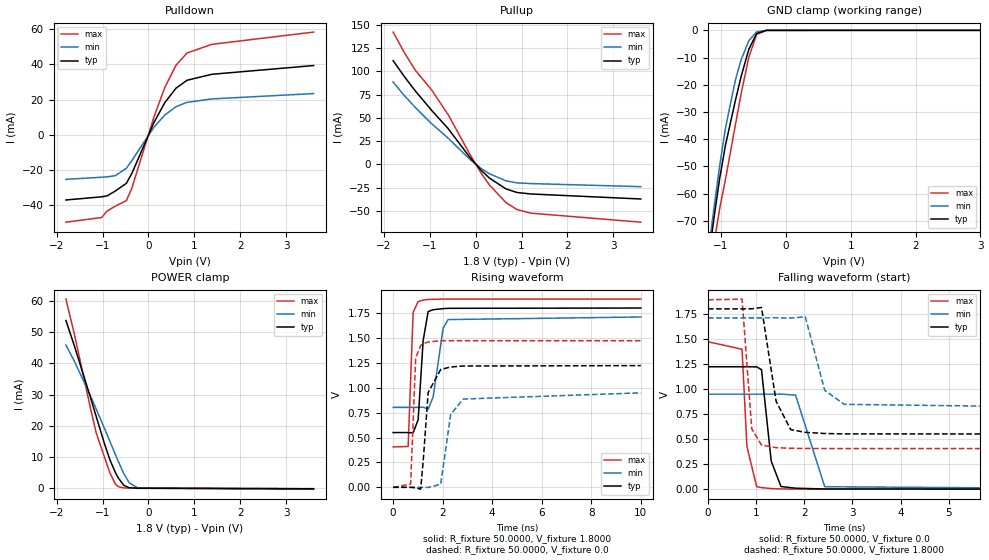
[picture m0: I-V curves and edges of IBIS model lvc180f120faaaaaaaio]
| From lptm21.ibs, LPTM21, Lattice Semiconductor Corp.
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|   Model lvc180f120faaaaaaaio
[Model]   lvc180f120faaaaaaaio
Model_type   I/O
Polarity   Non-Inverting
Enable   Active-Low
Vinl =   0.6300V
Vinh =   1.1700V
Vmeas =   0.9000V
Cref =   0.0F
Rref =   1.0000M
Vref =   0.0V
C_comp   4.2000pF   3.8000pF   7.5000pF
[Temperature Range]   25.0000   0.1050k   -40.0000
[Voltage Range]   1.8000V   1.7100V   1.8900V
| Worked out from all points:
|   slope of the pulldown table from 0 to 0.27 V, typ, clamps not added: 18.7 ohm
|   slope of the pullup table from 0 to 0.27 V, typ, clamps not added: 20.1 ohm
|   GND clamp passes 1 mA (typ) near -0.44 V on its own axis
|   POWER clamp passes 1 mA (typ) near -0.54 V on its own axis
|   rising waveform, R_fixture 50.0000, V_fixture 1.8000: 20-80 % time 202ps typ, 308ps min, 128ps max; typ from 0.55 V to 1.8 V
|   rising waveform, R_fixture 50.0000, V_fixture 0.0: 20-80 % time 229ps typ, 363ps min, 143ps max; typ from 0 V to 1.22 V
|   falling waveform, R_fixture 50.0000, V_fixture 0.0: 20-80 % time 157ps typ, 235ps min, 114ps max; typ from 1.22 V to 0 V
|   falling waveform, R_fixture 50.0000, V_fixture 1.8000: 20-80 % time 203ps typ, 295ps min, 139ps max; typ from 1.8 V to 0.55 V
[Pulldown]
|Voltage   I(typ)   I(min)   I(max)
-1.8V     -36.94mA   -25.24mA   -49.55mA
-1.02V    -35.14mA   -24.01mA   -46.9mA
-900mV    -34.58mA   -23.82mA   -43.15mA
-720mV    -31.81mA   -23.1mA    -40.42mA
-480mV    -27.43mA   -18.9mA    -37.25mA
-360mV    -21.71mA   -14.45mA   -30.04mA
120mV     7.084mA    4.436mA    10.27mA
360mV     18.51mA    11.39mA    27.2mA
600mV     26.54mA    16.01mA    39.55mA
840mV     31.04mA    18.5mA     46.51mA
1.38V     34.43mA    20.45mA    51.43mA
3.6V      39.4mA     23.48mA    58.4mA
[Pullup]
|Voltage   I(typ)   I(min)   I(max)
-1.8V     111.4mA    88.42mA    142.1mA
-1.56V    94.6mA     74.12mA    120.4mA
-1.32V    79.08mA    61.28mA    101.4mA
-960mV    57.98mA    43.63mA    79.88mA
-600mV    38.35mA    28.07mA    53.32mA
-120mV    7.04mA     4.994mA    10.22mA
120mV     -6.437mA   -4.482mA   -9.543mA
300mV     -14.76mA   -10.17mA   -22.19mA
660mV     -26.37mA   -17.71mA   -41.08mA
900mV     -30.25mA   -19.89mA   -48.54mA
1.2V      -31.82mA   -20.66mA   -52.43mA
3.6V      -37.22mA   -23.97mA   -62.15mA
[GND_clamp]
|Voltage   I(typ)   I(min)   I(max)
-1.8V     -240.1mA   -229.3mA   -254mA
-1.2V     -86.06mA   -82.86mA   -94.68mA
-1.17V    -80.34mA   -77.04mA   -89.1mA
-1.11V    -69.35mA   -65.72mA   -78.68mA
-1.02V    -54.38mA   -49.81mA   -65.5mA
-930mV    -42.15mA   -35.85mA   -54.73mA
-780mV    -26.05mA   -18.53mA   -35.07mA
-690mV    -17.04mA   -10.83mA   -23.37mA
-570mV    -6.958mA   -3.808mA   -9.842mA
-450mV    -1.149mA   -576.7uA   -1.52mA
-300mV    -18.2uA    -16.01uA   -13uA
3.6V      0A         0A         0A
[POWER_clamp]
|Voltage   I(typ)   I(min)   I(max)
-1.8V     53.66mA    45.8mA     60.51mA
-1.62V    45.76mA    40.78mA    49.57mA
-1.26V    28.84mA    29.42mA    25.34mA
-1.14V    22.99mA    25.38mA    17.77mA
-960mV    14.31mA    19.19mA    10.02mA
-840mV    9.109mA    15mA       4.931mA
-720mV    5.041mA    10.79mA    1.399mA
-660mV    3.38mA     8.712mA    551.7uA
-540mV    1.01mA     4.773mA    153.1uA
-420mV    197.6uA    1.797mA    88.49uA
-240mV    59.36uA    194.4uA    21.2uA
3.6V      -142.9uA   -81.03uA   -252.6uA
[Ramp]
| variable   typ   min   max
dV/dt_r  0.7331/0.2268n   0.5691/0.3594n   0.8835/0.1420n
dV/dt_f  0.7502/0.2007n   0.5444/0.2916n   0.8906/0.1381n
R_load = 50.0000
[Rising Waveform]
R_fixture=   50.0000
V_fixture=   1.8000
V_fixture_min=   1.7100
V_fixture_max=   1.8900
|time   V(typ)   V(min)   V(max)
0s        549.6mV    802.6mV    405.7mV
606.1ps   549.6mV    802.6mV    409.8mV
808.1ps   547.2mV    802.6mV    1.758V
1.01ns    679.3mV    802.6mV    1.866V
1.212ns   1.474V     804.2mV    1.88V
1.414ns   1.765V     785.4mV    1.886V
1.616ns   1.783V     908.3mV    1.888V
2.02ns    1.794V     1.599V     1.89V
2.222ns   1.797V     1.684V     1.89V
10ns      1.8V       1.71V      1.89V
[Rising Waveform]
R_fixture=   50.0000
V_fixture=   0.0
V_fixture_min=   0.0
V_fixture_max=   0.0
|time   V(typ)   V(min)   V(max)
0s        335.1nV    508.3nV    248.8nV
707.1ps   -57.36uV   614.4nV    32.97mV
909.1ps   -4.993mV   13.4uV     1.296V
1.111ns   -18.57mV   11.2uV     1.424V
1.212ns   258.9mV    -255.2uV   1.442V
1.414ns   951.4mV    -1.605mV   1.459V
1.919ns   1.183V     30mV       1.471V
2.323ns   1.208V     731mV      1.472V
2.828ns   1.218V     886.2mV    1.472V
10ns      1.222V     948.4mV    1.472V
[Falling Waveform]
R_fixture=   50.0000
V_fixture=   0.0
V_fixture_min=   0.0
V_fixture_max=   0.0
|time   V(typ)   V(min)   V(max)
0s        1.222V     948.4mV    1.472V
707.1ps   1.222V     948.4mV    1.397V
808.1ps   1.222V     948.4mV    427.5mV
1.01ns    1.221V     948.4mV    24.99mV
1.111ns   1.193V     948.4mV    15.28mV
1.313ns   279.8mV    948.5mV    6.02mV
1.515ns   26.18mV    948.9mV    2.383mV
1.818ns   9.629mV    939mV      586.8uV
2.424ns   1.858mV    24.36mV    67.33uV
10ns      -7.862uV   -27.3uV    22uV
[Falling Waveform]
R_fixture=   50.0000
V_fixture=   1.8000
V_fixture_min=   1.7100
V_fixture_max=   1.8900
|time   V(typ)   V(min)   V(max)
0s        1.8V       1.71V      1.89V
707.1ps   1.8V       1.71V      1.898V
909.1ps   1.801V     1.71V      601.8mV
1.111ns   1.814V     1.71V      441.1mV
1.414ns   877.3mV    1.711V     414.3mV
1.717ns   594.6mV    1.708V     408.1mV
2.02ns    567.4mV    1.721V     406.3mV
2.424ns   555.7mV    985.7mV    405.8mV
2.828ns   551.9mV    847mV      405.7mV
10ns      549.6mV    802.7mV    405.7mV
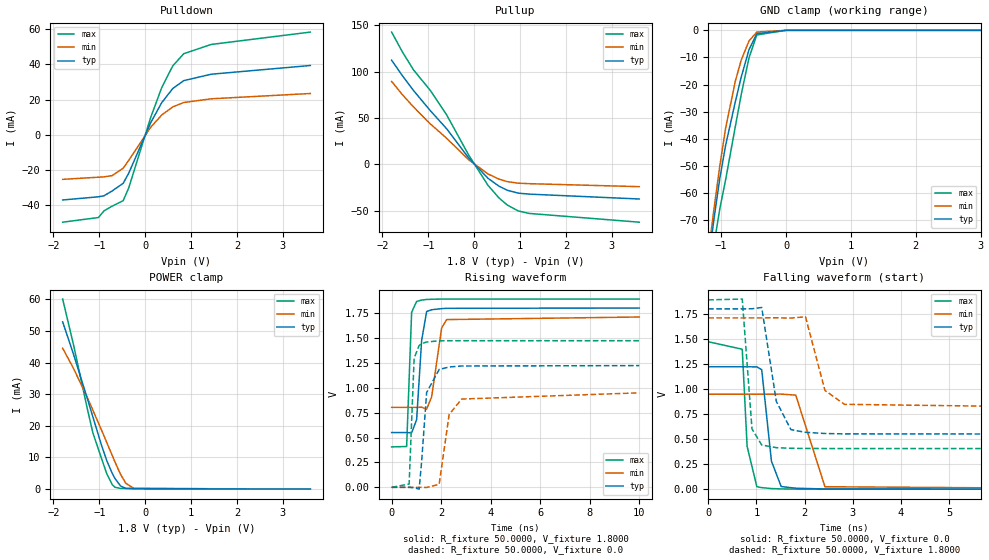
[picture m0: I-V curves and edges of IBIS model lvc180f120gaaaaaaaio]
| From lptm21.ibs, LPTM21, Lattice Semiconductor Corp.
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|   Model lvc180f120gaaaaaaaio
[Model]   lvc180f120gaaaaaaaio
Model_type   I/O
Polarity   Non-Inverting
Enable   Active-Low
Vinl =   0.6300V
Vinh =   1.1700V
Vmeas =   0.9000V
Cref =   0.0F
Rref =   1.0000M
Vref =   0.0V
C_comp   4.2000pF   3.8000pF   7.5000pF
[Temperature Range]   25.0000   0.1050k   -40.0000
[Voltage Range]   1.8000V   1.7100V   1.8900V
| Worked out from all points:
|   slope of the pulldown table from 0 to 0.27 V, typ, clamps not added: 18.8 ohm
|   slope of the pullup table from 0 to 0.27 V, typ, clamps not added: 20 ohm
|   GND clamp passes 1 mA (typ) near -0.44 V on its own axis
|   POWER clamp passes 1 mA (typ) near -0.54 V on its own axis
|   rising waveform, R_fixture 50.0000, V_fixture 1.8000: 20-80 % time 202ps typ, 308ps min, 128ps max; typ from 0.55 V to 1.8 V
|   rising waveform, R_fixture 50.0000, V_fixture 0.0: 20-80 % time 229ps typ, 363ps min, 143ps max; typ from 0 V to 1.22 V
|   falling waveform, R_fixture 50.0000, V_fixture 0.0: 20-80 % time 157ps typ, 235ps min, 114ps max; typ from 1.22 V to 0 V
|   falling waveform, R_fixture 50.0000, V_fixture 1.8000: 20-80 % time 203ps typ, 295ps min, 139ps max; typ from 1.8 V to 0.55 V
[Pulldown]
|Voltage   I(typ)   I(min)   I(max)
-1.8V     -36.96mA   -25.25mA   -49.57mA
-1.02V    -35.15mA   -24.02mA   -46.92mA
-900mV    -34.59mA   -23.83mA   -43.17mA
-720mV    -31.83mA   -23.11mA   -40.45mA
-480mV    -27.47mA   -18.92mA   -37.31mA
-360mV    -21.77mA   -14.48mA   -30.15mA
120mV     6.916mA    4.342mA    9.968mA
360mV     18.31mA    11.28mA    26.84mA
600mV     26.32mA    15.89mA    39.15mA
840mV     30.81mA    18.38mA    46.1mA
1.44V     34.45mA    20.49mA    51.36mA
3.6V      39.4mA     23.5mA     58.37mA
[Pullup]
|Voltage   I(typ)   I(min)   I(max)
-1.8V     112.2mA    89.39mA    142.5mA
-1.56V    95.15mA    74.8mA     120.7mA
-1.32V    79.42mA    61.72mA    101.6mA
-960mV    58.09mA    43.81mA    79.92mA
-600mV    38.38mA    28.11mA    53.33mA
-120mV    6.969mA    4.965mA    10.07mA
300mV     -14.91mA   -10.25mA   -22.47mA
540mV     -23.46mA   -15.87mA   -36.12mA
720mV     -27.84mA   -18.57mA   -43.72mA
960mV     -30.99mA   -20.26mA   -50.15mA
1.2V      -32.04mA   -20.78mA   -52.84mA
3.6V      -37.29mA   -24.01mA   -62.27mA
[GND_clamp]
|Voltage   I(typ)   I(min)   I(max)
-1.8V     -240.2mA   -229.4mA   -254.3mA
-1.2V     -86.19mA   -82.93mA   -94.91mA
-1.17V    -80.47mA   -77.11mA   -89.34mA
-1.11V    -69.48mA   -65.79mA   -78.91mA
-1.02V    -54.51mA   -49.88mA   -65.73mA
-930mV    -42.28mA   -35.92mA   -54.97mA
-780mV    -26.18mA   -18.61mA   -35.3mA
-690mV    -17.17mA   -10.9mA    -23.59mA
-570mV    -7.078mA   -3.876mA   -10.05mA
-450mV    -1.251mA   -635.5uA   -1.696mA
0V        0A         0A         0A
3.6V      0A         0A         0A
[POWER_clamp]
|Voltage   I(typ)   I(min)   I(max)
-1.8V     52.89mA    44.55mA    60.11mA
-1.56V    42.48mA    38.1mA     45.43mA
-1.26V    28.54mA    28.86mA    25.25mA
-1.14V    22.78mA    24.93mA    17.72mA
-960mV    14.19mA    18.89mA    9.998mA
-840mV    9.044mA    14.79mA    4.921mA
-720mV    5.001mA    10.65mA    1.403mA
-660mV    3.348mA    8.596mA    566.5uA
-540mV    992.7uA    4.706mA    207.6uA
-420mV    196.7uA    1.763mA    190.5uA
-240mV    100.9uA    180.2uA    188.6uA
3.6V      -30.34nA   -1.798uA   -37.95uA
[Ramp]
| variable   typ   min   max
dV/dt_r  0.7331/0.2268n   0.5691/0.3594n   0.8835/0.1420n
dV/dt_f  0.7502/0.2007n   0.5444/0.2916n   0.8906/0.1381n
R_load = 50.0000
[Rising Waveform]
R_fixture=   50.0000
V_fixture=   1.8000
V_fixture_min=   1.7100
V_fixture_max=   1.8900
|time   V(typ)   V(min)   V(max)
0s        549.6mV    802.6mV    405.7mV
606.1ps   549.6mV    802.6mV    409.8mV
808.1ps   547.2mV    802.6mV    1.758V
1.01ns    679.3mV    802.6mV    1.866V
1.212ns   1.474V     804.2mV    1.88V
1.414ns   1.765V     785.4mV    1.886V
1.616ns   1.783V     908.3mV    1.888V
2.02ns    1.794V     1.599V     1.89V
2.222ns   1.797V     1.684V     1.89V
10ns      1.8V       1.71V      1.89V
[Rising Waveform]
R_fixture=   50.0000
V_fixture=   0.0
V_fixture_min=   0.0
V_fixture_max=   0.0
|time   V(typ)   V(min)   V(max)
0s        335.1nV    508.3nV    248.8nV
707.1ps   -57.36uV   614.4nV    32.97mV
909.1ps   -4.993mV   13.4uV     1.296V
1.111ns   -18.57mV   11.2uV     1.424V
1.212ns   258.9mV    -255.2uV   1.442V
1.414ns   951.4mV    -1.605mV   1.459V
1.919ns   1.183V     30mV       1.471V
2.323ns   1.208V     731mV      1.472V
2.828ns   1.218V     886.2mV    1.472V
10ns      1.222V     948.4mV    1.472V
[Falling Waveform]
R_fixture=   50.0000
V_fixture=   0.0
V_fixture_min=   0.0
V_fixture_max=   0.0
|time   V(typ)   V(min)   V(max)
0s        1.222V     948.4mV    1.472V
707.1ps   1.222V     948.4mV    1.397V
808.1ps   1.222V     948.4mV    427.5mV
1.01ns    1.221V     948.4mV    24.99mV
1.111ns   1.193V     948.4mV    15.28mV
1.313ns   279.8mV    948.5mV    6.02mV
1.515ns   26.18mV    948.9mV    2.383mV
1.818ns   9.629mV    939mV      586.8uV
2.424ns   1.858mV    24.36mV    67.33uV
10ns      -7.862uV   -27.3uV    22uV
[Falling Waveform]
R_fixture=   50.0000
V_fixture=   1.8000
V_fixture_min=   1.7100
V_fixture_max=   1.8900
|time   V(typ)   V(min)   V(max)
0s        1.8V       1.71V      1.89V
707.1ps   1.8V       1.71V      1.898V
909.1ps   1.801V     1.71V      601.8mV
1.111ns   1.814V     1.71V      441.1mV
1.414ns   877.3mV    1.711V     414.3mV
1.717ns   594.6mV    1.708V     408.1mV
2.02ns    567.4mV    1.721V     406.3mV
2.424ns   555.7mV    985.7mV    405.8mV
2.828ns   551.9mV    847mV      405.7mV
10ns      549.6mV    802.7mV    405.7mV
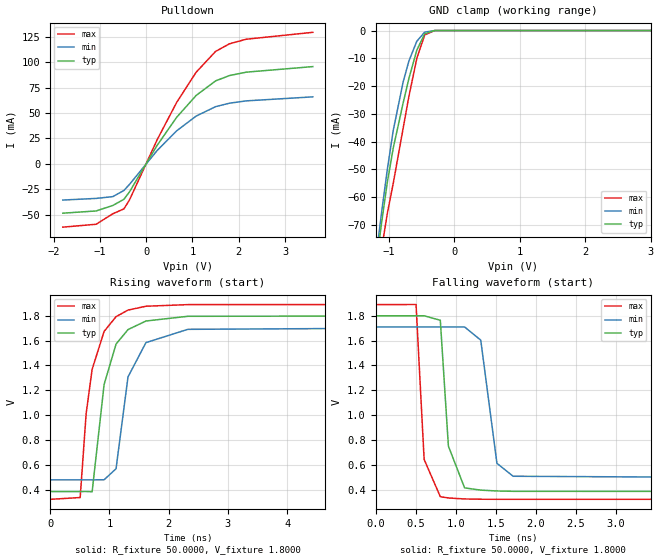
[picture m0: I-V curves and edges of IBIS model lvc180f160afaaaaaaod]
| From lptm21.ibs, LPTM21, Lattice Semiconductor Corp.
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|   Model lvc180f160afaaaaaaod
[Model]   lvc180f160afaaaaaaod
Model_type   I/O_open_drain
Polarity   Non-Inverting
Enable   Active-Low
Vinl =   0.6300V
Vinh =   1.1700V
Vmeas =   0.9000V
Cref =   0.0F
Rref =   1.0000M
Vref =   0.0V
C_comp   4.2000pF   3.8000pF   7.5000pF
[Temperature Range]   25.0000   0.1050k   -40.0000
[Voltage Range]   1.8000V   1.7100V   1.8900V
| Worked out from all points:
|   slope of the pulldown table from 0 to 0.27 V, typ, clamps not added: 13.2 ohm
|   GND clamp passes 1 mA (typ) near -0.44 V on its own axis
|   rising waveform, R_fixture 50.0000, V_fixture 1.8000: 20-80 % time 295ps typ, 286ps min, 271ps max; typ from 0.384 V to 1.8 V
|   falling waveform, R_fixture 50.0000, V_fixture 1.8000: 20-80 % time 105ps typ, 146ps min, 78.5ps max; typ from 1.8 V to 0.384 V
[Pulldown]
|Voltage   I(typ)   I(min)   I(max)
-1.8V     -48.7mA    -35.76mA   -62.45mA
-1.08V    -46.49mA   -34.15mA   -59.6mA
-720mV    -41.11mA   -32.38mA   -49.29mA
-480mV    -35mA      -26.35mA   -44.46mA
-360mV    -27.76mA   -20.4mA    -35.71mA
240mV     18.25mA    13.11mA    23.78mA
660mV     45.74mA    32.41mA    60.41mA
1.08V     67.25mA    46.93mA    90.07mA
1.5V      81.57mA    56.2mA     110.6mA
1.8V      86.83mA    59.62mA    118.1mA
2.16V     90.16mA    61.89mA    122.6mA
3.6V      95.65mA    65.86mA    129.4mA
[GND_clamp]
|Voltage   I(typ)   I(min)   I(max)
-1.8V     -240.2mA   -229.4mA   -254.3mA
-1.2V     -86.18mA   -82.93mA   -94.91mA
-1.17V    -80.47mA   -77.11mA   -89.33mA
-1.11V    -69.47mA   -65.79mA   -78.9mA
-1.02V    -54.51mA   -49.88mA   -65.72mA
-930mV    -42.27mA   -35.92mA   -54.95mA
-780mV    -26.16mA   -18.59mA   -35.28mA
-690mV    -17.14mA   -10.88mA   -23.55mA
-570mV    -7.035mA   -3.841mA   -9.995mA
-450mV    -1.181mA   -586.6uA   -1.592mA
-300mV    -18.83uA   -15.98uA   -16.73uA
3.6V      0A         0A         0A
[Ramp]
| variable   typ   min   max
dV/dt_r  0.8496/0.2920n   0.7390/0.2828n   0.9412/0.2678n
dV/dt_f  0.8496/0.1036n   0.7390/0.1443n   0.9412/77.6883p
R_load = 50.0000
[Rising Waveform]
R_fixture=   50.0000
V_fixture=   1.8000
V_fixture_min=   1.7100
V_fixture_max=   1.8900
|time   V(typ)   V(min)   V(max)
0s        384mV      478.3mV    321.3mV
505.1ps   384mV      478.3mV    335.8mV
606.1ps   384.4mV    478.3mV    1.012V
707.1ps   382.1mV    478.3mV    1.368V
909.1ps   1.246V     478.7mV    1.673V
1.111ns   1.571V     567.7mV    1.792V
1.313ns   1.688V     1.307V     1.845V
1.616ns   1.757V     1.583V     1.876V
2.323ns   1.795V     1.69V      1.889V
10ns      1.8V       1.71V      1.89V
[Falling Waveform]
R_fixture=   50.0000
V_fixture=   1.8000
V_fixture_min=   1.7100
V_fixture_max=   1.8900
|time   V(typ)   V(min)   V(max)
0s        1.8V       1.71V      1.89V
505.1ps   1.8V       1.71V      1.891V
606.1ps   1.8V       1.71V      642.9mV
808.1ps   1.764V     1.71V      342.5mV
909.1ps   750.1mV    1.71V      332.3mV
1.111ns   413.7mV    1.71V      324.3mV
1.313ns   395.4mV    1.604V     322.1mV
1.515ns   388.6mV    611.6mV    321.6mV
1.717ns   385.9mV    507.2mV    321.4mV
10ns      384mV      478.3mV    321.3mV
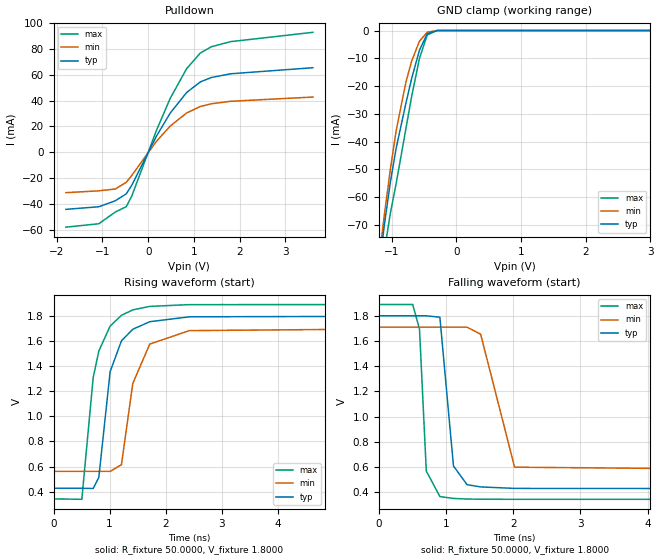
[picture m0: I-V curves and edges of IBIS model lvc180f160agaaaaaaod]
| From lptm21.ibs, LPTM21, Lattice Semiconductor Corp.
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|   Model lvc180f160agaaaaaaod
[Model]   lvc180f160agaaaaaaod
Model_type   I/O_open_drain
Polarity   Non-Inverting
Enable   Active-Low
Vinl =   0.6300V
Vinh =   1.1700V
Vmeas =   0.9000V
Cref =   0.0F
Rref =   1.0000M
Vref =   0.0V
C_comp   4.2000pF   3.8000pF   7.5000pF
[Temperature Range]   25.0000   0.1050k   -40.0000
[Voltage Range]   1.8000V   1.7100V   1.8900V
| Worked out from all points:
|   slope of the pulldown table from 0 to 0.27 V, typ, clamps not added: 14.8 ohm
|   GND clamp passes 1 mA (typ) near -0.44 V on its own axis
|   rising waveform, R_fixture 50.0000, V_fixture 1.8000: 20-80 % time 284ps typ, 296ps min, 294ps max; typ from 0.427 V to 1.8 V
|   falling waveform, R_fixture 50.0000, V_fixture 1.8000: 20-80 % time 142ps typ, 189ps min, 83.2ps max; typ from 1.8 V to 0.427 V
[Pulldown]
|Voltage   I(typ)   I(min)   I(max)
-1.8V     -44.23mA   -31.31mA   -58.03mA
-1.08V    -42.22mA   -29.89mA   -55.39mA
-720mV    -37.59mA   -28.47mA   -46.33mA
-480mV    -32.21mA   -23.27mA   -42.16mA
-360mV    -25.58mA   -17.97mA   -33.97mA
180mV     12.51mA    8.495mA    16.97mA
480mV     30.31mA    20.29mA    41.7mA
840mV     46.33mA    30.45mA    64.8mA
1.14V     54.53mA    35.48mA    76.92mA
1.38V     57.92mA    37.59mA    81.78mA
1.8V      60.83mA    39.51mA    85.73mA
3.6V      65.53mA    42.8mA     92.96mA
[GND_clamp]
|Voltage   I(typ)   I(min)   I(max)
-1.8V     -240.2mA   -229.4mA   -254.3mA
-1.2V     -86.17mA   -82.92mA   -94.88mA
-1.17V    -80.46mA   -77.1mA    -89.31mA
-1.11V    -69.46mA   -65.78mA   -78.88mA
-1.02V    -54.49mA   -49.87mA   -65.69mA
-930mV    -42.26mA   -35.91mA   -54.92mA
-780mV    -26.15mA   -18.58mA   -35.26mA
-690mV    -17.13mA   -10.88mA   -23.54mA
-570mV    -7.027mA   -3.837mA   -9.983mA
-450mV    -1.178mA   -585.4uA   -1.585mA
-300mV    -18.71uA   -15.93uA   -16.53uA
3.6V      0A         0A         0A
[Ramp]
| variable   typ   min   max
dV/dt_r  0.8237/0.2807n   0.6891/0.2931n   0.9284/0.2913n
dV/dt_f  0.8237/0.1402n   0.6891/0.1874n   0.9284/82.3770p
R_load = 50.0000
[Rising Waveform]
R_fixture=   50.0000
V_fixture=   1.8000
V_fixture_min=   1.7100
V_fixture_max=   1.8900
|time   V(typ)   V(min)   V(max)
0s        427.2mV    561.5mV    342.6mV
505.1ps   427.2mV    561.5mV    338.9mV
707.1ps   425.3mV    561.5mV    1.306V
808.1ps   512.8mV    561.5mV    1.519V
1.01ns    1.355V     561.4mV    1.718V
1.212ns   1.601V     615mV      1.804V
1.414ns   1.693V     1.261V     1.847V
1.717ns   1.753V     1.575V     1.875V
2.424ns   1.792V     1.682V     1.889V
10ns      1.8V       1.71V      1.89V
[Falling Waveform]
R_fixture=   50.0000
V_fixture=   1.8000
V_fixture_min=   1.7100
V_fixture_max=   1.8900
|time   V(typ)   V(min)   V(max)
0s        1.8V       1.71V      1.89V
505.1ps   1.8V       1.71V      1.89V
606.1ps   1.8V       1.71V      1.694V
707.1ps   1.8V       1.71V      567.2mV
909.1ps   1.789V     1.71V      364.9mV
1.111ns   607.7mV    1.71V      349.7mV
1.313ns   459mV      1.71V      344.9mV
1.515ns   441.3mV    1.654V     343.4mV
2.02ns    429.4mV    597.8mV    342.7mV
10ns      427.2mV    561.5mV    342.6mV
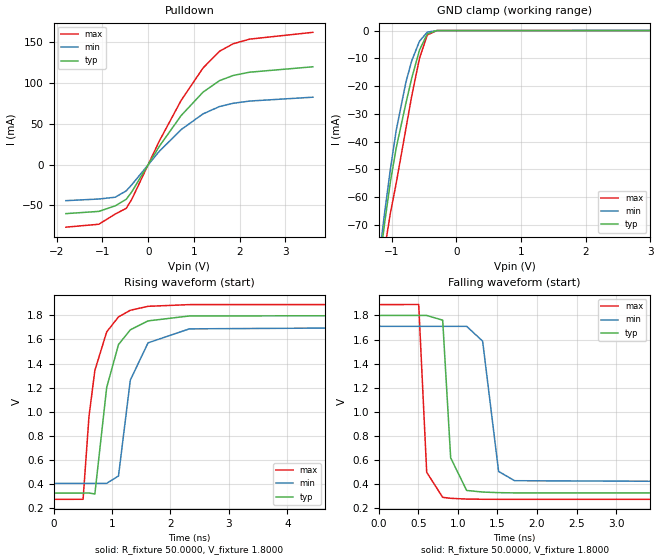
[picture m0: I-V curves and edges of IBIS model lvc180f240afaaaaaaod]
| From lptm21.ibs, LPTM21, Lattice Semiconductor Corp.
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|   Model lvc180f240afaaaaaaod
[Model]   lvc180f240afaaaaaaod
Model_type   I/O_open_drain
Polarity   Non-Inverting
Enable   Active-Low
Vinl =   0.6300V
Vinh =   1.1700V
Vmeas =   0.9000V
Cref =   0.0F
Rref =   1.0000M
Vref =   0.0V
C_comp   4.2000pF   3.8000pF   7.5000pF
[Temperature Range]   25.0000   0.1050k   -40.0000
[Voltage Range]   1.8000V   1.7100V   1.8900V
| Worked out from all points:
|   slope of the pulldown table from 0 to 0.27 V, typ, clamps not added: 11 ohm
|   GND clamp passes 1 mA (typ) near -0.44 V on its own axis
|   rising waveform, R_fixture 50.0000, V_fixture 1.8000: 20-80 % time 293ps typ, 289ps min, 273ps max; typ from 0.327 V to 1.8 V
|   falling waveform, R_fixture 50.0000, V_fixture 1.8000: 20-80 % time 78.2ps typ, 132ps min, 70.3ps max; typ from 1.8 V to 0.327 V
[Pulldown]
|Voltage   I(typ)   I(min)   I(max)
-1.8V     -60.02mA   -44.17mA   -76.55mA
-1.08V    -57.29mA   -42.17mA   -73mA
-720mV    -50.52mA   -39.95mA   -60.48mA
-480mV    -42.45mA   -32.15mA   -53.52mA
-360mV    -33.46mA   -24.81mA   -42.61mA
240mV     22.01mA    15.98mA    28.37mA
720mV     59.79mA    42.64mA    78.33mA
1.2V      88.49mA    61.91mA    118mA
1.56V     102.5mA    70.84mA    138.4mA
1.86V     108.8mA    74.83mA    147.6mA
2.22V     112.8mA    77.53mA    153.2mA
3.6V      119.4mA    82.24mA    161.5mA
[GND_clamp]
|Voltage   I(typ)   I(min)   I(max)
-1.8V     -240.2mA   -229.4mA   -254.3mA
-1.2V     -86.18mA   -82.93mA   -94.91mA
-1.17V    -80.47mA   -77.11mA   -89.33mA
-1.11V    -69.47mA   -65.79mA   -78.9mA
-1.02V    -54.51mA   -49.88mA   -65.72mA
-930mV    -42.27mA   -35.92mA   -54.95mA
-780mV    -26.16mA   -18.59mA   -35.28mA
-690mV    -17.14mA   -10.88mA   -23.55mA
-570mV    -7.035mA   -3.841mA   -9.995mA
-450mV    -1.181mA   -586.6uA   -1.592mA
-300mV    -18.83uA   -15.98uA   -16.73uA
3.6V      0A         0A         0A
[Ramp]
| variable   typ   min   max
dV/dt_r  0.8840/0.2904n   0.7818/0.2857n   0.9691/0.2704n
dV/dt_f  0.8839/77.4003p   0.7818/0.1303n   0.9691/69.6157p
R_load = 50.0000
[Rising Waveform]
R_fixture=   50.0000
V_fixture=   1.8000
V_fixture_min=   1.7100
V_fixture_max=   1.8900
|time   V(typ)   V(min)   V(max)
0s        326.7mV    406.9mV    274.8mV
505.1ps   326.7mV    406.9mV    275.1mV
606.1ps   327.2mV    406.9mV    960.7mV
707.1ps   319.1mV    407mV      1.344V
909.1ps   1.202V     407.4mV    1.663V
1.111ns   1.558V     468.4mV    1.787V
1.313ns   1.68V      1.263V     1.842V
1.616ns   1.754V     1.572V     1.875V
2.323ns   1.795V     1.688V     1.889V
10ns      1.8V       1.71V      1.89V
[Falling Waveform]
R_fixture=   50.0000
V_fixture=   1.8000
V_fixture_min=   1.7100
V_fixture_max=   1.8900
|time   V(typ)   V(min)   V(max)
0s        1.8V       1.71V      1.89V
505.1ps   1.8V       1.71V      1.891V
606.1ps   1.8V       1.71V      499.2mV
808.1ps   1.761V     1.71V      291.4mV
909.1ps   618.7mV    1.71V      283.2mV
1.111ns   348.5mV    1.71V      277.1mV
1.313ns   335.3mV    1.587V     275.4mV
1.515ns   330.2mV    506.1mV    275mV
1.717ns   328.2mV    429.3mV    274.8mV
10ns      326.7mV    407mV      274.8mV
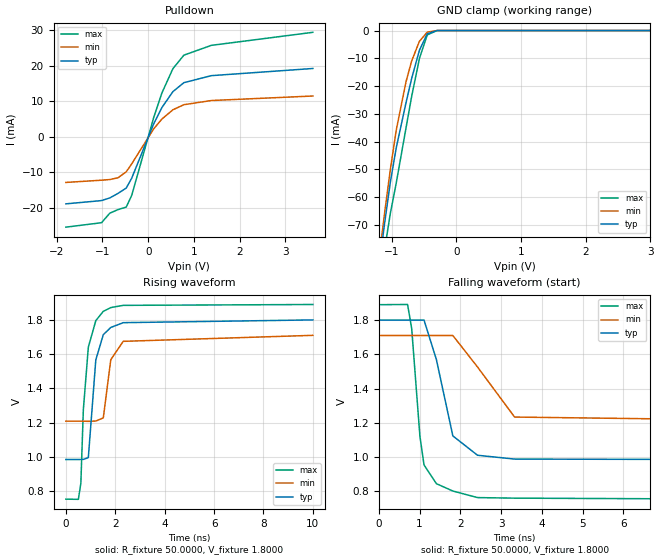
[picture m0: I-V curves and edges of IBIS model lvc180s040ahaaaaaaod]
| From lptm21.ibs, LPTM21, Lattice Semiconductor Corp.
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|   Model lvc180s040ahaaaaaaod
[Model]   lvc180s040ahaaaaaaod
Model_type   I/O_open_drain
Polarity   Non-Inverting
Enable   Active-Low
Vinl =   0.6300V
Vinh =   1.1700V
Vmeas =   0.9000V
Cref =   0.0F
Rref =   1.0000M
Vref =   0.0V
C_comp   4.2000pF   3.8000pF   7.5000pF
[Temperature Range]   25.0000   0.1050k   -40.0000
[Voltage Range]   1.8000V   1.7100V   1.8900V
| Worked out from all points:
|   slope of the pulldown table from 0 to 0.27 V, typ, clamps not added: 35.7 ohm
|   GND clamp passes 1 mA (typ) near -0.44 V on its own axis
|   rising waveform, R_fixture 50.0000, V_fixture 1.8000: 20-80 % time 307ps typ, 309ps min, 300ps max; typ from 0.985 V to 1.8 V
|   falling waveform, R_fixture 50.0000, V_fixture 1.8000: 20-80 % time 405ps typ, 486ps min, 260ps max; typ from 1.8 V to 0.985 V
[Pulldown]
|Voltage   I(typ)   I(min)   I(max)
-1.8V     -18.86mA   -12.83mA   -25.42mA
-1.02V    -17.94mA   -12.2mA    -24.17mA
-840mV    -17.19mA   -12.01mA   -21.49mA
-660mV    -15.91mA   -11.52mA   -20.48mA
-480mV    -14.4mA    -9.834mA   -19.76mA
-360mV    -11.61mA   -7.578mA   -16.45mA
120mV     3.67mA     2.253mA    5.436mA
300mV     8.275mA    5.027mA    12.37mA
540mV     12.73mA    7.623mA    19.2mA
780mV     15.26mA    9.056mA    23mA
1.38V     17.23mA    10.23mA    25.76mA
3.6V      19.25mA    11.5mA     29.43mA
[GND_clamp]
|Voltage   I(typ)   I(min)   I(max)
-1.8V     -240.2mA   -229.4mA   -254.3mA
-1.2V     -86.16mA   -82.91mA   -94.88mA
-1.17V    -80.45mA   -77.09mA   -89.3mA
-1.11V    -69.45mA   -65.77mA   -78.87mA
-1.02V    -54.48mA   -49.86mA   -65.69mA
-930mV    -42.25mA   -35.9mA    -54.92mA
-780mV    -26.14mA   -18.58mA   -35.25mA
-690mV    -17.13mA   -10.87mA   -23.53mA
-570mV    -7.024mA   -3.834mA   -9.978mA
-450mV    -1.176mA   -584.6uA   -1.582mA
-300mV    -18.65uA   -15.9uA    -16.44uA
3.6V      0A         0A         0A
[Ramp]
| variable   typ   min   max
dV/dt_r  0.4887/0.3036n   0.3008/0.3058n   0.6817/0.2969n
dV/dt_f  0.4887/0.4004n   0.3009/0.5542n   0.6817/0.2997n
R_load = 50.0000
[Rising Waveform]
R_fixture=   50.0000
V_fixture=   1.8000
V_fixture_min=   1.7100
V_fixture_max=   1.8900
|time   V(typ)   V(min)   V(max)
0s        985.4mV    1.209V     753.8mV
505.1ps   985.4mV    1.209V     752.9mV
606.1ps   985.5mV    1.209V     845.3mV
707.1ps   986mV      1.209V     1.275V
909.1ps   996.4mV    1.208V     1.641V
1.212ns   1.567V     1.21V      1.796V
1.515ns   1.714V     1.228V     1.85V
1.818ns   1.756V     1.568V     1.872V
2.323ns   1.784V     1.675V     1.885V
10ns      1.8V       1.71V      1.89V
[Falling Waveform]
R_fixture=   50.0000
V_fixture=   1.8000
V_fixture_min=   1.7100
V_fixture_max=   1.8900
|time   V(typ)   V(min)   V(max)
0s        1.8V       1.71V      1.89V
707.1ps   1.8V       1.71V      1.891V
808.1ps   1.8V       1.71V      1.752V
1.01ns    1.8V       1.71V      1.122V
1.111ns   1.8V       1.71V      954.6mV
1.414ns   1.57V      1.71V      845.2mV
1.818ns   1.124V     1.71V      802.3mV
2.424ns   1.011V     1.526V     764mV
3.333ns   988.7mV    1.234V     760.7mV
10ns      985.4mV    1.214V     753.8mV
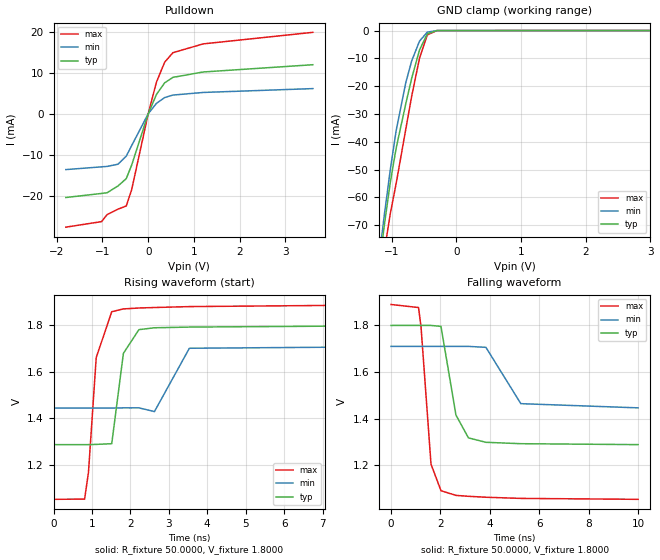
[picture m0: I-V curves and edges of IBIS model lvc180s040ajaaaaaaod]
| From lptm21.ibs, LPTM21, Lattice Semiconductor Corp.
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|   Model lvc180s040ajaaaaaaod
[Model]   lvc180s040ajaaaaaaod
Model_type   I/O_open_drain
Polarity   Non-Inverting
Enable   Active-Low
Vinl =   0.6300V
Vinh =   1.1700V
Vmeas =   0.9000V
Cref =   0.0F
Rref =   1.0000M
Vref =   0.0V
C_comp   4.2000pF   3.8000pF   7.5000pF
[Temperature Range]   25.0000   0.1050k   -40.0000
[Voltage Range]   1.8000V   1.7100V   1.8900V
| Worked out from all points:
|   slope of the pulldown table from 0 to 0.27 V, typ, clamps not added: 42.7 ohm
|   GND clamp passes 1 mA (typ) near -0.44 V on its own axis
|   rising waveform, R_fixture 50.0000, V_fixture 1.8000: 20-80 % time 252ps typ, 299ps min, 240ps max; typ from 1.29 V to 1.8 V
|   falling waveform, R_fixture 50.0000, V_fixture 1.8000: 20-80 % time 482ps typ, 742ps min, 344ps max; typ from 1.8 V to 1.29 V
[Pulldown]
|Voltage   I(typ)   I(min)   I(max)
-1.8V     -20.39mA   -13.59mA   -27.61mA
-1.02V    -19.4mA    -12.92mA   -26.26mA
-900mV    -19.23mA   -12.82mA   -24.57mA
-660mV    -17.57mA   -12.28mA   -23.23mA
-480mV    -15.79mA   -10.32mA   -22.45mA
-360mV    -12.45mA   -7.709mA   -18.4mA
0V        1.3nA      780pA      2.185nA
180mV     4.7mA      2.537mA    7.708mA
360mV     7.543mA    3.952mA    12.57mA
540mV     8.87mA     4.559mA    14.88mA
1.2V      10.18mA    5.194mA    17.02mA
3.6V      11.95mA    6.134mA    19.84mA
[GND_clamp]
|Voltage   I(typ)   I(min)   I(max)
-1.8V     -240.2mA   -229.3mA   -254.2mA
-1.2V     -86.08mA   -82.81mA   -94.85mA
-1.17V    -80.37mA   -77mA      -89.28mA
-1.11V    -69.39mA   -65.69mA   -78.86mA
-1.02V    -54.44mA   -49.8mA    -65.68mA
-930mV    -42.22mA   -35.86mA   -54.91mA
-780mV    -26.13mA   -18.57mA   -35.24mA
-690mV    -17.12mA   -10.87mA   -23.53mA
-570mV    -7.021mA   -3.832mA   -9.974mA
-450mV    -1.175mA   -584uA     -1.58mA
-300mV    -18.6uA    -15.87uA   -16.37uA
3.6V      0A         0A         0A
[Ramp]
| variable   typ   min   max
dV/dt_r  0.3074/0.2492n   0.1589/0.2961n   0.4956/0.2975n
dV/dt_f  0.3074/0.4774n   0.1586/0.7341n   0.5024/0.3406n
R_load = 50.0000
[Rising Waveform]
R_fixture=   50.0000
V_fixture=   1.8000
V_fixture_min=   1.7100
V_fixture_max=   1.8900
|time   V(typ)   V(min)   V(max)
0s        1.287V     1.444V     1.052V
808.1ps   1.287V     1.444V     1.053V
909.1ps   1.287V     1.444V     1.167V
1.111ns   1.288V     1.444V     1.661V
1.515ns   1.291V     1.444V     1.858V
1.818ns   1.679V     1.445V     1.87V
2.222ns   1.781V     1.445V     1.874V
2.626ns   1.789V     1.429V     1.876V
3.535ns   1.792V     1.701V     1.88V
10ns      1.799V     1.709V     1.889V
[Falling Waveform]
R_fixture=   50.0000
V_fixture=   1.8000
V_fixture_min=   1.7100
V_fixture_max=   1.8900
|time   V(typ)   V(min)   V(max)
0s        1.8V       1.71V      1.89V
1.111ns   1.8V       1.71V      1.877V
1.212ns   1.8V       1.71V      1.794V
1.616ns   1.8V       1.71V      1.204V
2.02ns    1.796V     1.71V      1.09V
2.626ns   1.415V     1.71V      1.07V
3.131ns   1.317V     1.71V      1.066V
3.838ns   1.298V     1.706V     1.062V
5.253ns   1.292V     1.464V     1.057V
10ns      1.288V     1.446V     1.053V
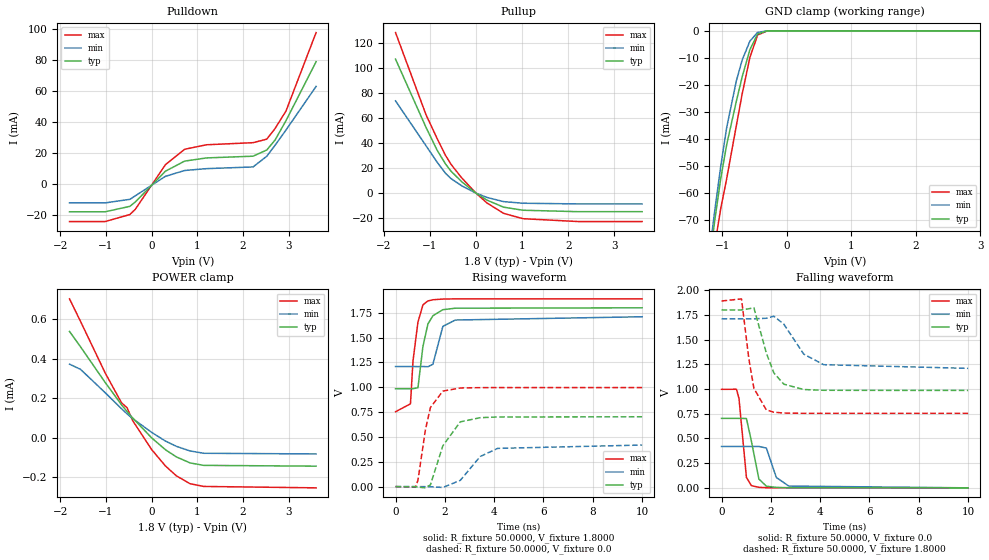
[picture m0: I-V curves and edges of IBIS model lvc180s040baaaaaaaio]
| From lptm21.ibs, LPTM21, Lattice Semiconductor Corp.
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|   Model lvc180s040baaaaaaaio
[Model]   lvc180s040baaaaaaaio
Model_type   I/O
Polarity   Non-Inverting
Enable   Active-Low
Vinl =   0.6300V
Vinh =   1.1700V
Vmeas =   0.9000V
Cref =   0.0F
Rref =   1.0000M
Vref =   0.0V
C_comp   4.2000pF   3.8000pF   7.5000pF
[Temperature Range]   25.0000   0.1050k   -40.0000
[Voltage Range]   1.8000V   1.7100V   1.8900V
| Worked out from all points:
|   slope of the pulldown table from 0 to 0.27 V, typ, clamps not added: 35.7 ohm
|   slope of the pullup table from 0 to 0.27 V, typ, clamps not added: 43.5 ohm
|   GND clamp passes 1 mA (typ) near -0.44 V on its own axis
|   rising waveform, R_fixture 50.0000, V_fixture 1.8000: 20-80 % time 316ps typ, 320ps min, 273ps max; typ from 0.985 V to 1.8 V
|   rising waveform, R_fixture 50.0000, V_fixture 0.0: 20-80 % time 605ps typ, 927ps min, 417ps max; typ from 0 V to 0.703 V
|   falling waveform, R_fixture 50.0000, V_fixture 0.0: 20-80 % time 292ps typ, 366ps min, 216ps max; typ from 0.703 V to 0 V
|   falling waveform, R_fixture 50.0000, V_fixture 1.8000: 20-80 % time 600ps typ, 912ps min, 394ps max; typ from 1.8 V to 0.985 V
[Pulldown]
|Voltage   I(typ)   I(min)   I(max)
-1.8V     -17.79mA   -12.05mA   -24.11mA
-1.02V    -17.79mA   -12.05mA   -24.11mA
-480mV    -14.3mA    -9.765mA   -19.59mA
-360mV    -11.47mA   -7.497mA   -16.22mA
300mV     8.416mA    5.108mA    12.62mA
720mV     14.93mA    8.87mA     22.57mA
1.2V      17mA       10.07mA    25.48mA
2.22V     18.11mA    11.17mA    26.84mA
2.52V     22.12mA    18.09mA    29.11mA
2.7V      28.48mA    25.12mA    35.92mA
2.94V     41.02mA    34.99mA    47.26mA
3.6V      79.13mA    63.17mA    97.95mA
[Pullup]
|Voltage   I(typ)   I(min)   I(max)
-1.74V    106.8mA    73.53mA    128mA
-1.08V    52.41mA    37.75mA    62.46mA
-840mV    34.24mA    24.67mA    43.57mA
-660mV    23.36mA    15.89mA    30.21mA
-540mV    17.52mA    11.6mA     22.97mA
-300mV    8.814mA    5.648mA    11.86mA
0V        -1.053nA   -765pA     -1.857nA
240mV     -5.624mA   -3.474mA   -7.884mA
600mV     -11.24mA   -6.816mA   -16.16mA
1.02V     -13.69mA   -8.102mA   -20.44mA
2.22V     -14.84mA   -8.658mA   -22.72mA
3.6V      -14.84mA   -8.658mA   -22.72mA
[GND_clamp]
|Voltage   I(typ)   I(min)   I(max)
-1.8V     -240.1mA   -229.3mA   -254mA
-1.2V     -86.06mA   -82.86mA   -94.68mA
-1.17V    -80.34mA   -77.04mA   -89.1mA
-1.11V    -69.35mA   -65.72mA   -78.68mA
-1.02V    -54.38mA   -49.81mA   -65.5mA
-930mV    -42.15mA   -35.85mA   -54.73mA
-780mV    -26.05mA   -18.53mA   -35.07mA
-690mV    -17.04mA   -10.83mA   -23.37mA
-570mV    -6.958mA   -3.808mA   -9.842mA
-450mV    -1.149mA   -576.7uA   -1.52mA
-300mV    -18.2uA    -16.01uA   -13uA
3.6V      0A         0A         0A
[POWER_clamp]
|Voltage   I(typ)   I(min)   I(max)
-1.8V     538.6uA    373.2uA    703.6uA
-1.56V    461.4uA    347.2uA    589.9uA
-1.02V    280.9uA    229uA      329.2uA
-660mV    167.1uA    147.2uA    177.1uA
-540mV    133.5uA    121.8uA    152.7uA
-420mV    101.7uA    98.16uA    88.49uA
0V        38.11nA    27.94uA    -59.25uA
300mV     -59.54uA   -15.82uA   -141.8uA
540mV     -96.02uA   -42.44uA   -191.8uA
840mV     -126.4uA   -65.81uA   -231.7uA
1.14V     -138.9uA   -77.7uA    -245.5uA
3.6V      -142.9uA   -81.03uA   -252.6uA
[Ramp]
| variable   typ   min   max
dV/dt_r  0.3835/0.6002n   0.2511/0.9175n   0.5981/0.4134n
dV/dt_f  0.4887/0.5938n   0.3008/0.9028n   0.6817/0.3902n
R_load = 50.0000
[Rising Waveform]
R_fixture=   50.0000
V_fixture=   1.8000
V_fixture_min=   1.7100
V_fixture_max=   1.8900
|time   V(typ)   V(min)   V(max)
0s        985.4mV    1.209V     753.8mV
606.1ps   985.5mV    1.209V     833.5mV
707.1ps   985.8mV    1.209V     1.263V
909.1ps   995.1mV    1.208V     1.657V
1.111ns   1.411V     1.209V     1.829V
1.313ns   1.637V     1.207V     1.869V
1.515ns   1.72V      1.232V     1.881V
1.919ns   1.781V     1.613V     1.888V
2.424ns   1.796V     1.677V     1.89V
10ns      1.8V       1.71V      1.89V
[Rising Waveform]
R_fixture=   50.0000
V_fixture=   0.0
V_fixture_min=   0.0
V_fixture_max=   0.0
|time   V(typ)   V(min)   V(max)
0s        551.1nV    773.6nV    431.5nV
808.1ps   -676.1uV   1.137uV    -5.572mV
909.1ps   -4.556mV   11.92uV    64.26mV
1.212ns   -12.34mV   -127.3uV   572.3mV
1.414ns   17.64mV    -1.571mV   795.9mV
1.919ns   411.4mV    -8.516mV   961.7mV
2.626ns   652mV      62.91mV    992.9mV
3.434ns   694mV      303.2mV    996.3mV
4.141ns   700.9mV    384.9mV    996.7mV
10ns      703mV      418.5mV    996.8mV
[Falling Waveform]
R_fixture=   50.0000
V_fixture=   0.0
V_fixture_min=   0.0
V_fixture_max=   0.0
|time   V(typ)   V(min)   V(max)
0s        703.1mV    418.5mV    996.8mV
606.1ps   703.1mV    418.5mV    997.5mV
707.1ps   703mV      418.5mV    905.3mV
1.01ns    701.4mV    418.5mV    105.1mV
1.212ns   471.7mV    418.5mV    22.1mV
1.515ns   89.09mV    418.9mV    5.28mV
1.818ns   16.88mV    402.4mV    1.353mV
2.222ns   4.48mV     105.3mV    263.1uV
2.727ns   1.104mV    17.89mV    67.09uV
10ns      5.228uV    -1.51uV    13.75uV
[Falling Waveform]
R_fixture=   50.0000
V_fixture=   1.8000
V_fixture_min=   1.7100
V_fixture_max=   1.8900
|time   V(typ)   V(min)   V(max)
0s        1.8V       1.71V      1.89V
808.1ps   1.8V       1.71V      1.912V
1.111ns   1.812V     1.71V      1.301V
1.313ns   1.822V     1.71V      1.006V
1.818ns   1.363V     1.716V     788.4mV
2.121ns   1.163V     1.736V     765.3mV
2.525ns   1.049V     1.657V     756.7mV
3.333ns   994.7mV    1.353V     754.1mV
4.141ns   987mV      1.246V     753.8mV
10ns      985.4mV    1.209V     753.8mV
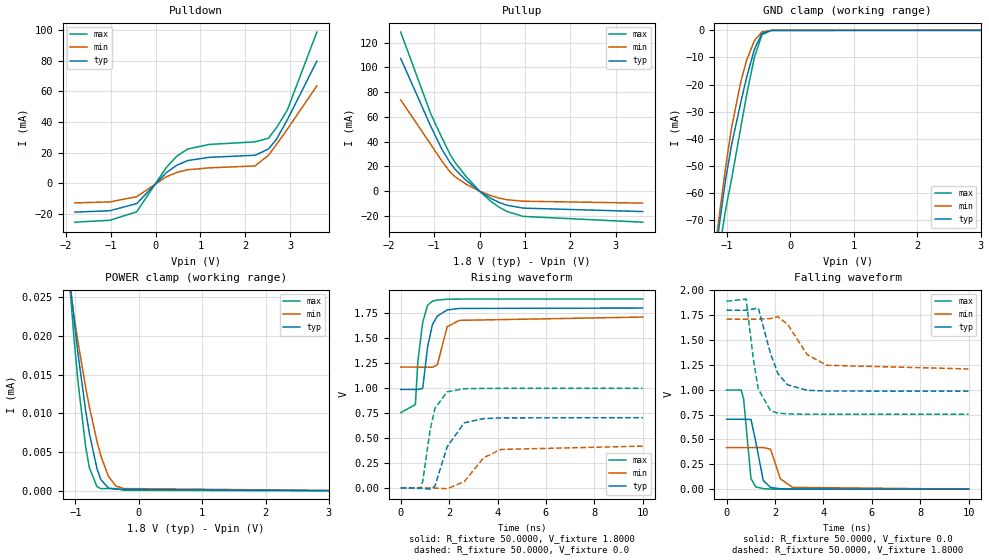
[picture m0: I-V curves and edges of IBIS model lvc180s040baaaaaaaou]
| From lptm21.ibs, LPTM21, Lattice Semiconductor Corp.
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|   Model lvc180s040baaaaaaaou
[Model]   lvc180s040baaaaaaaou
Model_type   Output
Polarity   Non-Inverting
Enable   Active-Low
Vmeas =   0.9000V
Cref =   0.0F
Rref =   1.0000M
Vref =   0.0V
C_comp   4.2000pF   3.8000pF   7.5000pF
[Temperature Range]   25.0000   0.1050k   -40.0000
[Voltage Range]   1.8000V   1.7100V   1.8900V
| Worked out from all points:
|   slope of the pulldown table from 0 to 0.27 V, typ, clamps not added: 35.7 ohm
|   slope of the pullup table from 0 to 0.27 V, typ, clamps not added: 43.1 ohm
|   GND clamp passes 1 mA (typ) near -0.44 V on its own axis
|   rising waveform, R_fixture 50.0000, V_fixture 1.8000: 20-80 % time 316ps typ, 320ps min, 273ps max; typ from 0.985 V to 1.8 V
|   rising waveform, R_fixture 50.0000, V_fixture 0.0: 20-80 % time 605ps typ, 927ps min, 417ps max; typ from 0 V to 0.703 V
|   falling waveform, R_fixture 50.0000, V_fixture 0.0: 20-80 % time 292ps typ, 366ps min, 216ps max; typ from 0.703 V to 0 V
|   falling waveform, R_fixture 50.0000, V_fixture 1.8000: 20-80 % time 600ps typ, 912ps min, 394ps max; typ from 1.8 V to 0.985 V
[Pulldown]
|Voltage   I(typ)   I(min)   I(max)
-1.8V     -18.86mA   -12.83mA   -25.42mA
-1.02V    -17.94mA   -12.2mA    -24.17mA
-420mV    -13.27mA   -8.803mA   -18.63mA
240mV     6.859mA    4.183mA    10.22mA
480mV     11.8mA     7.089mA    17.77mA
720mV     14.79mA    8.792mA    22.32mA
1.2V      16.89mA    10.02mA    25.3mA
2.22V     18.21mA    11.25mA    26.96mA
2.52V     22.3mA     18.23mA    29.35mA
2.7V      28.7mA     25.29mA    36.22mA
2.94V     41.31mA    35.2mA     47.65mA
3.6V      79.56mA    63.47mA    98.55mA
[Pullup]
|Voltage   I(typ)   I(min)   I(max)
-1.74V    107.3mA    73.81mA    128.6mA
-1.08V    52.71mA    37.94mA    62.86mA
-840mV    34.47mA    24.81mA    43.88mA
-660mV    23.54mA    16mA       30.46mA
-540mV    17.67mA    11.68mA    23.16mA
-300mV    8.89mA     5.707mA    11.97mA
0V        -1.899nA   -1.713nA   -2.809nA
240mV     -5.677mA   -3.504mA   -7.961mA
420mV     -8.941mA   -5.471mA   -12.69mA
600mV     -11.35mA   -6.879mA   -16.33mA
960mV     -13.7mA    -8.118mA   -20.38mA
3.6V      -16.47mA   -9.647mA   -25.08mA
[GND_clamp]
|Voltage   I(typ)   I(min)   I(max)
-1.8V     -240.2mA   -229.4mA   -254.3mA
-1.2V     -86.16mA   -82.91mA   -94.88mA
-1.17V    -80.45mA   -77.09mA   -89.3mA
-1.11V    -69.45mA   -65.77mA   -78.87mA
-1.02V    -54.48mA   -49.86mA   -65.69mA
-930mV    -42.25mA   -35.9mA    -54.92mA
-780mV    -26.14mA   -18.58mA   -35.25mA
-690mV    -17.13mA   -10.87mA   -23.53mA
-570mV    -7.024mA   -3.834mA   -9.978mA
-450mV    -1.176mA   -584.6uA   -1.582mA
-300mV    -18.65uA   -15.9uA    -16.44uA
3.6V      0A         0A         0A
[POWER_clamp]
|Voltage   I(typ)   I(min)   I(max)
-1.8V     102.4uA    78.03uA    133.9uA
-1.08V    26.57uA    25.91uA    25.52uA
-1.02V    21.97uA    22.48uA    19.46uA
-960mV    17.73uA    19.24uA    14.09uA
-840mV    10.4uA     13.4uA     5.721uA
-780mV    7.366uA    10.82uA    2.952uA
-660mV    2.828uA    6.355uA    502.3nA
-600mV    1.449uA    4.526uA    261.4nA
-480mV    331.7nA    1.843uA    261.4nA
-360mV    177.2nA    586.8nA    261.4nA
-240mV    177.2nA    270.3nA    57.44nA
3.6V      -31nA      -27.04nA   -40.53nA
[Ramp]
| variable   typ   min   max
dV/dt_r  0.3835/0.6002n   0.2511/0.9175n   0.5981/0.4134n
dV/dt_f  0.4887/0.5938n   0.3008/0.9028n   0.6817/0.3902n
R_load = 50.0000
[Rising Waveform]
R_fixture=   50.0000
V_fixture=   1.8000
V_fixture_min=   1.7100
V_fixture_max=   1.8900
|time   V(typ)   V(min)   V(max)
0s        985.4mV    1.209V     753.8mV
606.1ps   985.5mV    1.209V     833.5mV
707.1ps   985.8mV    1.209V     1.263V
909.1ps   995.1mV    1.208V     1.657V
1.111ns   1.411V     1.209V     1.829V
1.313ns   1.637V     1.207V     1.869V
1.515ns   1.72V      1.232V     1.881V
1.919ns   1.781V     1.613V     1.888V
2.424ns   1.796V     1.677V     1.89V
10ns      1.8V       1.71V      1.89V
[Rising Waveform]
R_fixture=   50.0000
V_fixture=   0.0
V_fixture_min=   0.0
V_fixture_max=   0.0
|time   V(typ)   V(min)   V(max)
0s        551.1nV    773.6nV    431.5nV
808.1ps   -676.1uV   1.137uV    -5.572mV
909.1ps   -4.556mV   11.92uV    64.26mV
1.212ns   -12.34mV   -127.3uV   572.3mV
1.414ns   17.64mV    -1.571mV   795.9mV
1.919ns   411.4mV    -8.516mV   961.7mV
2.626ns   652mV      62.91mV    992.9mV
3.434ns   694mV      303.2mV    996.3mV
4.141ns   700.9mV    384.9mV    996.7mV
10ns      703mV      418.5mV    996.8mV
[Falling Waveform]
R_fixture=   50.0000
V_fixture=   0.0
V_fixture_min=   0.0
V_fixture_max=   0.0
|time   V(typ)   V(min)   V(max)
0s        703.1mV    418.5mV    996.8mV
606.1ps   703.1mV    418.5mV    997.5mV
707.1ps   703mV      418.5mV    905.3mV
1.01ns    701.4mV    418.5mV    105.1mV
1.212ns   471.7mV    418.5mV    22.1mV
1.515ns   89.09mV    418.9mV    5.28mV
1.818ns   16.88mV    402.4mV    1.353mV
2.222ns   4.48mV     105.3mV    263.1uV
2.727ns   1.104mV    17.89mV    67.09uV
10ns      5.228uV    -1.51uV    13.75uV
[Falling Waveform]
R_fixture=   50.0000
V_fixture=   1.8000
V_fixture_min=   1.7100
V_fixture_max=   1.8900
|time   V(typ)   V(min)   V(max)
0s        1.8V       1.71V      1.89V
808.1ps   1.8V       1.71V      1.912V
1.111ns   1.812V     1.71V      1.301V
1.313ns   1.822V     1.71V      1.006V
1.818ns   1.363V     1.716V     788.4mV
2.121ns   1.163V     1.736V     765.3mV
2.525ns   1.049V     1.657V     756.7mV
3.333ns   994.7mV    1.353V     754.1mV
4.141ns   987mV      1.246V     753.8mV
10ns      985.4mV    1.209V     753.8mV
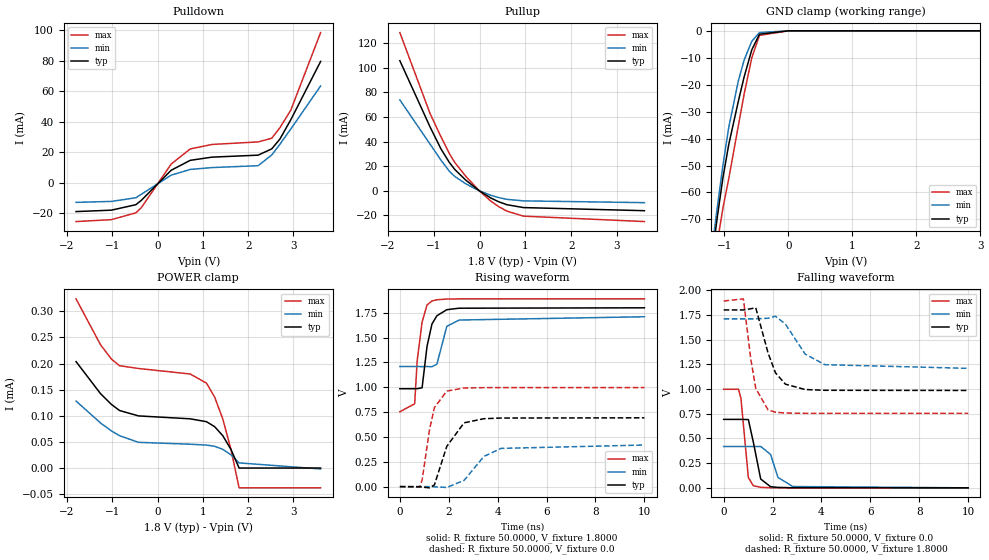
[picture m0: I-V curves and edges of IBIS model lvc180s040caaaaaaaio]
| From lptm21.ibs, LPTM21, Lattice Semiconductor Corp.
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|   Model lvc180s040caaaaaaaio
[Model]   lvc180s040caaaaaaaio
Model_type   I/O
Polarity   Non-Inverting
Enable   Active-Low
Vinl =   0.6300V
Vinh =   1.1700V
Vmeas =   0.9000V
Cref =   0.0F
Rref =   1.0000M
Vref =   0.0V
C_comp   4.2000pF   3.8000pF   7.5000pF
[Temperature Range]   25.0000   0.1050k   -40.0000
[Voltage Range]   1.8000V   1.7100V   1.8900V
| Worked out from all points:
|   slope of the pulldown table from 0 to 0.27 V, typ, clamps not added: 35.9 ohm
|   slope of the pullup table from 0 to 0.27 V, typ, clamps not added: 43.7 ohm
|   GND clamp passes 1 mA (typ) near -0.44 V on its own axis
|   rising waveform, R_fixture 50.0000, V_fixture 1.8000: 20-80 % time 316ps typ, 320ps min, 273ps max; typ from 0.985 V to 1.8 V
|   rising waveform, R_fixture 50.0000, V_fixture 0.0: 20-80 % time 605ps typ, 927ps min, 417ps max; typ from 0 V to 0.692 V
|   falling waveform, R_fixture 50.0000, V_fixture 0.0: 20-80 % time 293ps typ, 366ps min, 216ps max; typ from 0.693 V to 0 V
|   falling waveform, R_fixture 50.0000, V_fixture 1.8000: 20-80 % time 600ps typ, 912ps min, 394ps max; typ from 1.8 V to 0.985 V
[Pulldown]
|Voltage   I(typ)   I(min)   I(max)
-1.8V     -18.83mA   -12.8mA    -25.37mA
-1.02V    -17.91mA   -12.18mA   -24.12mA
-480mV    -14.33mA   -9.784mA   -19.66mA
-360mV    -11.53mA   -7.531mA   -16.32mA
300mV     8.221mA    5mA        12.27mA
720mV     14.71mA    8.749mA    22.15mA
1.2V      16.8mA     9.971mA    25.11mA
2.22V     18.11mA    11.2mA     26.78mA
2.52V     22.2mA     18.18mA    29.16mA
2.7V      28.6mA     25.24mA    36.03mA
2.94V     41.21mA    35.15mA    47.46mA
3.6V      79.46mA    63.42mA    98.36mA
[Pullup]
|Voltage   I(typ)   I(min)   I(max)
-1.74V    105.6mA    73.76mA    128.4mA
-1.08V    51.81mA    37.89mA    62.67mA
-840mV    33.85mA    24.76mA    43.69mA
-660mV    23.08mA    15.95mA    30.27mA
-540mV    17.3mA     11.64mA    22.97mA
-300mV    8.653mA    5.646mA    11.78mA
0V        -97.91uA   -46.98uA   -188.2uA
240mV     -5.697mA   -3.55mA    -8.148mA
420mV     -8.911mA   -5.517mA   -12.87mA
600mV     -11.28mA   -6.924mA   -16.51mA
960mV     -13.6mA    -8.161mA   -20.55mA
3.6V      -16.13mA   -9.599mA   -24.94mA
[GND_clamp]
|Voltage   I(typ)   I(min)   I(max)
-1.8V     -240.2mA   -229.4mA   -254.3mA
-1.2V     -86.19mA   -82.93mA   -94.91mA
-1.17V    -80.47mA   -77.11mA   -89.34mA
-1.11V    -69.48mA   -65.79mA   -78.91mA
-1.02V    -54.51mA   -49.88mA   -65.73mA
-930mV    -42.28mA   -35.92mA   -54.97mA
-780mV    -26.18mA   -18.61mA   -35.3mA
-690mV    -17.17mA   -10.9mA    -23.59mA
-570mV    -7.078mA   -3.876mA   -10.05mA
-450mV    -1.251mA   -635.5uA   -1.696mA
0V        0A         0A         0A
3.6V      0A         0A         0A
[POWER_clamp]
|Voltage   I(typ)   I(min)   I(max)
-1.8V     203.7uA    128.2uA    323.8uA
-1.26V    142.4uA    86.29uA    236uA
-1.02V    121.8uA    71.14uA    208.7uA
-840mV    110.1uA    61.88uA    195.8uA
-420mV    99.75uA    49.18uA    190.5uA
720mV     94.2uA     45.56uA    180uA
1.08V     88.67uA    43.9uA     162.5uA
1.26V     79.17uA    41.55uA    135.8uA
1.44V     61.82uA    35.76uA    94.02uA
1.62V     35.65uA    25.36uA    35.72uA
1.8V      -30.34nA   9.798uA    -37.95uA
3.6V      -30.34nA   -1.798uA   -37.95uA
[Ramp]
| variable   typ   min   max
dV/dt_r  0.3835/0.6002n   0.2511/0.9175n   0.5981/0.4134n
dV/dt_f  0.4887/0.5938n   0.3008/0.9028n   0.6817/0.3902n
R_load = 50.0000
[Rising Waveform]
R_fixture=   50.0000
V_fixture=   1.8000
V_fixture_min=   1.7100
V_fixture_max=   1.8900
|time   V(typ)   V(min)   V(max)
0s        985.4mV    1.209V     753.8mV
606.1ps   985.5mV    1.209V     833.5mV
707.1ps   985.8mV    1.209V     1.263V
909.1ps   995.1mV    1.208V     1.657V
1.111ns   1.411V     1.209V     1.829V
1.313ns   1.637V     1.207V     1.869V
1.515ns   1.72V      1.232V     1.881V
1.919ns   1.781V     1.613V     1.888V
2.424ns   1.796V     1.677V     1.89V
10ns      1.8V       1.71V      1.89V
[Rising Waveform]
R_fixture=   50.0000
V_fixture=   0.0
V_fixture_min=   0.0
V_fixture_max=   0.0
|time   V(typ)   V(min)   V(max)
0s        551.1nV    773.6nV    431.5nV
808.1ps   -676.1uV   1.137uV    -5.572mV
909.1ps   -4.556mV   11.92uV    64.26mV
1.212ns   -12.34mV   -127.3uV   572.3mV
1.414ns   17.64mV    -1.571mV   795.9mV
1.919ns   405.2mV    -8.516mV   961.7mV
2.626ns   642.2mV    62.91mV    992.9mV
3.434ns   683.6mV    303.2mV    996.3mV
4.141ns   690.4mV    384.9mV    996.7mV
10ns      692.5mV    418.5mV    996.8mV
[Falling Waveform]
R_fixture=   50.0000
V_fixture=   0.0
V_fixture_min=   0.0
V_fixture_max=   0.0
|time   V(typ)   V(min)   V(max)
0s        692.6mV    418.5mV    996.8mV
606.1ps   692.6mV    418.5mV    997.5mV
707.1ps   692.5mV    418.5mV    905.3mV
1.01ns    690.8mV    418.5mV    105.1mV
1.212ns   464.6mV    418.5mV    22.1mV
1.515ns   89.09mV    418.9mV    5.28mV
1.919ns   11.5mV     337.8mV    876.3uV
2.222ns   4.48mV     105.3mV    263.1uV
2.828ns   834.7uV    13.29mV    53.28uV
10ns      5.228uV    -1.51uV    13.75uV
[Falling Waveform]
R_fixture=   50.0000
V_fixture=   1.8000
V_fixture_min=   1.7100
V_fixture_max=   1.8900
|time   V(typ)   V(min)   V(max)
0s        1.8V       1.71V      1.89V
808.1ps   1.8V       1.71V      1.912V
1.111ns   1.812V     1.71V      1.301V
1.313ns   1.822V     1.71V      1.006V
1.818ns   1.363V     1.716V     788.4mV
2.121ns   1.163V     1.736V     765.3mV
2.525ns   1.049V     1.657V     756.7mV
3.333ns   994.7mV    1.353V     754.1mV
4.141ns   987mV      1.246V     753.8mV
10ns      985.4mV    1.209V     753.8mV
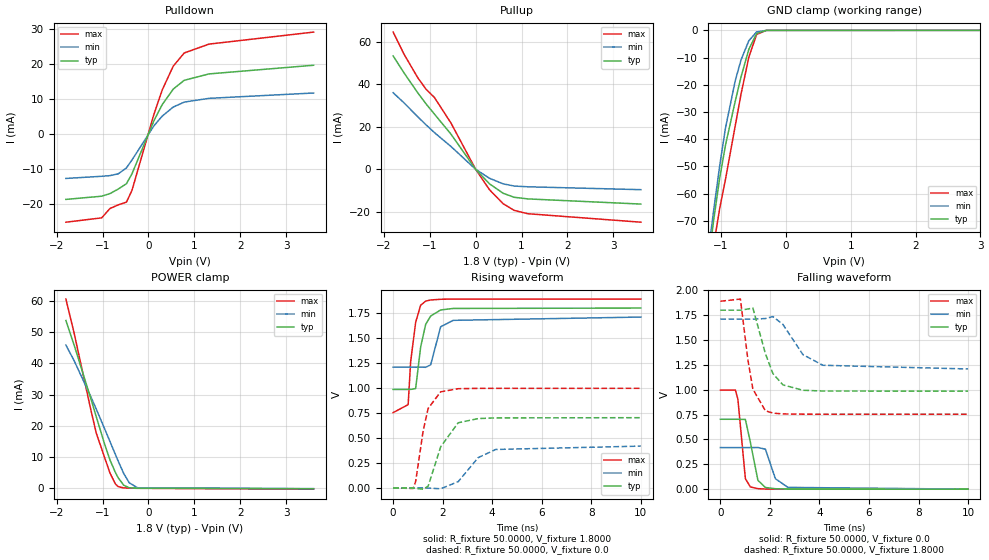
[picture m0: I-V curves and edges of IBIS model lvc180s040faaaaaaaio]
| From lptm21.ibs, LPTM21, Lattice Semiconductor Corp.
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|   Model lvc180s040faaaaaaaio
[Model]   lvc180s040faaaaaaaio
Model_type   I/O
Polarity   Non-Inverting
Enable   Active-Low
Vinl =   0.6300V
Vinh =   1.1700V
Vmeas =   0.9000V
Cref =   0.0F
Rref =   1.0000M
Vref =   0.0V
C_comp   4.2000pF   3.8000pF   7.5000pF
[Temperature Range]   25.0000   0.1050k   -40.0000
[Voltage Range]   1.8000V   1.7100V   1.8900V
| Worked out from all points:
|   slope of the pulldown table from 0 to 0.27 V, typ, clamps not added: 35.7 ohm
|   slope of the pullup table from 0 to 0.27 V, typ, clamps not added: 43.5 ohm
|   GND clamp passes 1 mA (typ) near -0.44 V on its own axis
|   POWER clamp passes 1 mA (typ) near -0.54 V on its own axis
|   rising waveform, R_fixture 50.0000, V_fixture 1.8000: 20-80 % time 316ps typ, 320ps min, 273ps max; typ from 0.985 V to 1.8 V
|   rising waveform, R_fixture 50.0000, V_fixture 0.0: 20-80 % time 605ps typ, 927ps min, 417ps max; typ from 0 V to 0.703 V
|   falling waveform, R_fixture 50.0000, V_fixture 0.0: 20-80 % time 292ps typ, 366ps min, 216ps max; typ from 0.703 V to 0 V
|   falling waveform, R_fixture 50.0000, V_fixture 1.8000: 20-80 % time 600ps typ, 912ps min, 394ps max; typ from 1.8 V to 0.985 V
[Pulldown]
|Voltage   I(typ)   I(min)   I(max)
-1.8V     -18.81mA   -12.79mA   -25.35mA
-1.02V    -17.89mA   -12.17mA   -24.11mA
-840mV    -17.14mA   -11.98mA   -21.42mA
-660mV    -15.85mA   -11.47mA   -20.39mA
-480mV    -14.3mA    -9.765mA   -19.59mA
-360mV    -11.47mA   -7.497mA   -16.22mA
120mV     3.812mA    2.334mA    5.687mA
300mV     8.416mA    5.108mA    12.62mA
540mV     12.87mA    7.703mA    19.45mA
780mV     15.39mA    9.133mA    23.24mA
1.32V     17.22mA    10.21mA    25.78mA
3.6V      19.71mA    11.74mA    29.23mA
[Pullup]
|Voltage   I(typ)   I(min)   I(max)
-1.8V     53.25mA    35.99mA    64.45mA
-1.56V    45.2mA     31.17mA    53.95mA
-1.26V    35.84mA    24.62mA    42.93mA
-1.08V    30.67mA    20.85mA    37.56mA
-900mV    25.95mA    17.26mA    33.76mA
-540mV    16.56mA    10.75mA    21.77mA
0V        -1.054nA   -771pA     -1.857nA
300mV     -6.794mA   -4.186mA   -9.561mA
600mV     -11.24mA   -6.816mA   -16.16mA
840mV     -13.12mA   -7.834mA   -19.28mA
1.14V     -13.88mA   -8.194mA   -20.84mA
3.6V      -16.3mA    -9.54mA    -24.81mA
[GND_clamp]
|Voltage   I(typ)   I(min)   I(max)
-1.8V     -240.1mA   -229.3mA   -254mA
-1.2V     -86.06mA   -82.86mA   -94.68mA
-1.17V    -80.34mA   -77.04mA   -89.1mA
-1.11V    -69.35mA   -65.72mA   -78.68mA
-1.02V    -54.38mA   -49.81mA   -65.5mA
-930mV    -42.15mA   -35.85mA   -54.73mA
-780mV    -26.05mA   -18.53mA   -35.07mA
-690mV    -17.04mA   -10.83mA   -23.37mA
-570mV    -6.958mA   -3.808mA   -9.842mA
-450mV    -1.149mA   -576.7uA   -1.52mA
-300mV    -18.2uA    -16.01uA   -13uA
3.6V      0A         0A         0A
[POWER_clamp]
|Voltage   I(typ)   I(min)   I(max)
-1.8V     53.66mA    45.8mA     60.51mA
-1.62V    45.76mA    40.78mA    49.57mA
-1.26V    28.84mA    29.42mA    25.34mA
-1.14V    22.99mA    25.38mA    17.77mA
-960mV    14.31mA    19.19mA    10.02mA
-840mV    9.109mA    15mA       4.931mA
-720mV    5.041mA    10.79mA    1.399mA
-660mV    3.38mA     8.712mA    551.7uA
-540mV    1.01mA     4.773mA    153.1uA
-420mV    197.6uA    1.797mA    88.49uA
-240mV    59.36uA    194.4uA    21.2uA
3.6V      -142.9uA   -81.03uA   -252.6uA
[Ramp]
| variable   typ   min   max
dV/dt_r  0.3835/0.6002n   0.2511/0.9175n   0.5981/0.4134n
dV/dt_f  0.4887/0.5938n   0.3008/0.9028n   0.6817/0.3902n
R_load = 50.0000
[Rising Waveform]
R_fixture=   50.0000
V_fixture=   1.8000
V_fixture_min=   1.7100
V_fixture_max=   1.8900
|time   V(typ)   V(min)   V(max)
0s        985.4mV    1.209V     753.8mV
606.1ps   985.5mV    1.209V     833.5mV
707.1ps   985.8mV    1.209V     1.263V
909.1ps   995.1mV    1.208V     1.657V
1.111ns   1.411V     1.209V     1.829V
1.313ns   1.637V     1.207V     1.869V
1.515ns   1.72V      1.232V     1.881V
1.919ns   1.781V     1.613V     1.888V
2.424ns   1.796V     1.677V     1.89V
10ns      1.8V       1.71V      1.89V
[Rising Waveform]
R_fixture=   50.0000
V_fixture=   0.0
V_fixture_min=   0.0
V_fixture_max=   0.0
|time   V(typ)   V(min)   V(max)
0s        551.1nV    773.6nV    431.5nV
808.1ps   -676.1uV   1.137uV    -5.572mV
909.1ps   -4.556mV   11.92uV    64.26mV
1.212ns   -12.34mV   -127.3uV   572.3mV
1.414ns   17.64mV    -1.571mV   795.9mV
1.919ns   411.4mV    -8.516mV   961.7mV
2.626ns   652mV      62.91mV    992.9mV
3.434ns   694mV      303.2mV    996.3mV
4.141ns   700.9mV    384.9mV    996.7mV
10ns      703mV      418.5mV    996.8mV
[Falling Waveform]
R_fixture=   50.0000
V_fixture=   0.0
V_fixture_min=   0.0
V_fixture_max=   0.0
|time   V(typ)   V(min)   V(max)
0s        703.1mV    418.5mV    996.8mV
606.1ps   703.1mV    418.5mV    997.5mV
707.1ps   703mV      418.5mV    905.3mV
1.01ns    701.4mV    418.5mV    105.1mV
1.212ns   471.7mV    418.5mV    22.1mV
1.515ns   89.09mV    418.9mV    5.28mV
1.818ns   16.88mV    402.4mV    1.353mV
2.222ns   4.48mV     105.3mV    263.1uV
2.727ns   1.104mV    17.89mV    67.09uV
10ns      5.228uV    -1.51uV    13.75uV
[Falling Waveform]
R_fixture=   50.0000
V_fixture=   1.8000
V_fixture_min=   1.7100
V_fixture_max=   1.8900
|time   V(typ)   V(min)   V(max)
0s        1.8V       1.71V      1.89V
808.1ps   1.8V       1.71V      1.912V
1.111ns   1.812V     1.71V      1.301V
1.313ns   1.822V     1.71V      1.006V
1.818ns   1.363V     1.716V     788.4mV
2.121ns   1.163V     1.736V     765.3mV
2.525ns   1.049V     1.657V     756.7mV
3.333ns   994.7mV    1.353V     754.1mV
4.141ns   987mV      1.246V     753.8mV
10ns      985.4mV    1.209V     753.8mV
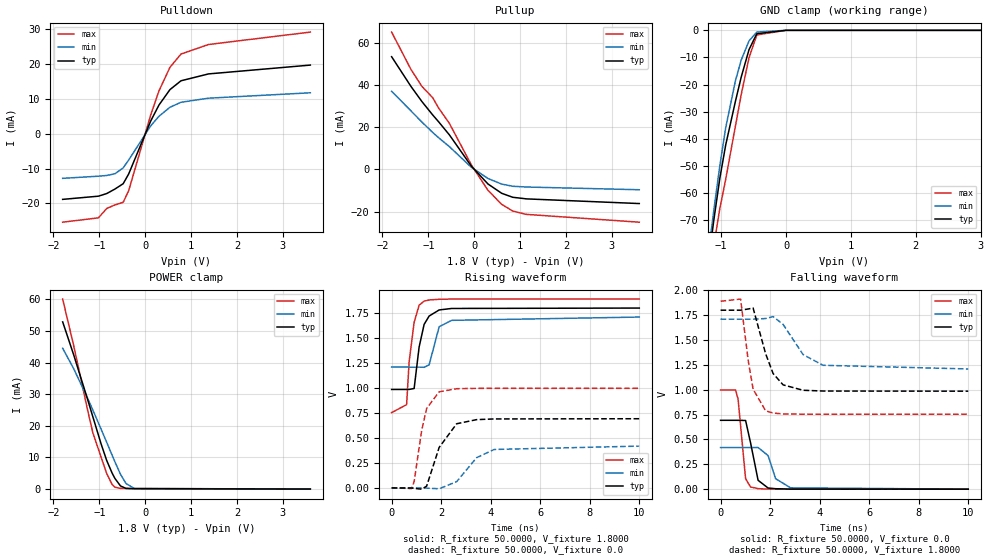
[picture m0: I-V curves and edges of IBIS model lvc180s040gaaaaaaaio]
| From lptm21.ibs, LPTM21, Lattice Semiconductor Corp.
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|   Model lvc180s040gaaaaaaaio
[Model]   lvc180s040gaaaaaaaio
Model_type   I/O
Polarity   Non-Inverting
Enable   Active-Low
Vinl =   0.6300V
Vinh =   1.1700V
Vmeas =   0.9000V
Cref =   0.0F
Rref =   1.0000M
Vref =   0.0V
C_comp   4.2000pF   3.8000pF   7.5000pF
[Temperature Range]   25.0000   0.1050k   -40.0000
[Voltage Range]   1.8000V   1.7100V   1.8900V
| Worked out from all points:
|   slope of the pulldown table from 0 to 0.27 V, typ, clamps not added: 35.9 ohm
|   slope of the pullup table from 0 to 0.27 V, typ, clamps not added: 43.7 ohm
|   GND clamp passes 1 mA (typ) near -0.44 V on its own axis
|   POWER clamp passes 1 mA (typ) near -0.54 V on its own axis
|   rising waveform, R_fixture 50.0000, V_fixture 1.8000: 20-80 % time 316ps typ, 320ps min, 273ps max; typ from 0.985 V to 1.8 V
|   rising waveform, R_fixture 50.0000, V_fixture 0.0: 20-80 % time 605ps typ, 927ps min, 417ps max; typ from 0 V to 0.692 V
|   falling waveform, R_fixture 50.0000, V_fixture 0.0: 20-80 % time 293ps typ, 366ps min, 216ps max; typ from 0.693 V to 0 V
|   falling waveform, R_fixture 50.0000, V_fixture 1.8000: 20-80 % time 600ps typ, 912ps min, 394ps max; typ from 1.8 V to 0.985 V
[Pulldown]
|Voltage   I(typ)   I(min)   I(max)
-1.8V     -18.83mA   -12.8mA    -25.37mA
-1.02V    -17.91mA   -12.18mA   -24.12mA
-840mV    -17.16mA   -11.98mA   -21.44mA
-660mV    -15.87mA   -11.48mA   -20.42mA
-480mV    -14.33mA   -9.784mA   -19.66mA
-360mV    -11.53mA   -7.531mA   -16.32mA
120mV     3.645mA    2.241mA    5.39mA
300mV     8.221mA    5mA        12.27mA
540mV     12.65mA    7.584mA    19.05mA
780mV     15.17mA    9.012mA    22.83mA
1.38V     17.14mA    10.18mA    25.57mA
3.6V      19.67mA    11.73mA    29.13mA
[Pullup]
|Voltage   I(typ)   I(min)   I(max)
-1.8V     53.29mA    36.97mA    64.93mA
-1.38V    39.3mA     27.73mA    47.34mA
-1.14V    32.1mA     22.39mA    39.28mA
-900mV    25.65mA    17.4mA     33.79mA
-780mV    22.65mA    15.08mA    29.18mA
-540mV    16.33mA    10.78mA    21.76mA
-60mV     1.513mA    983.3uA    2.072mA
300mV     -6.862mA   -4.269mA   -9.842mA
600mV     -11.28mA   -6.924mA   -16.51mA
840mV     -13.16mA   -7.953mA   -19.67mA
1.14V     -13.92mA   -8.314mA   -21.25mA
3.6V      -16.13mA   -9.599mA   -24.94mA
[GND_clamp]
|Voltage   I(typ)   I(min)   I(max)
-1.8V     -240.2mA   -229.4mA   -254.3mA
-1.2V     -86.19mA   -82.93mA   -94.91mA
-1.17V    -80.47mA   -77.11mA   -89.34mA
-1.11V    -69.48mA   -65.79mA   -78.91mA
-1.02V    -54.51mA   -49.88mA   -65.73mA
-930mV    -42.28mA   -35.92mA   -54.97mA
-780mV    -26.18mA   -18.61mA   -35.3mA
-690mV    -17.17mA   -10.9mA    -23.59mA
-570mV    -7.078mA   -3.876mA   -10.05mA
-450mV    -1.251mA   -635.5uA   -1.696mA
0V        0A         0A         0A
3.6V      0A         0A         0A
[POWER_clamp]
|Voltage   I(typ)   I(min)   I(max)
-1.8V     52.89mA    44.55mA    60.11mA
-1.56V    42.48mA    38.1mA     45.43mA
-1.26V    28.54mA    28.86mA    25.25mA
-1.14V    22.78mA    24.93mA    17.72mA
-960mV    14.19mA    18.89mA    9.998mA
-840mV    9.044mA    14.79mA    4.921mA
-720mV    5.001mA    10.65mA    1.403mA
-660mV    3.348mA    8.596mA    566.5uA
-540mV    992.7uA    4.706mA    207.6uA
-420mV    196.7uA    1.763mA    190.5uA
-240mV    100.9uA    180.2uA    188.6uA
3.6V      -30.34nA   -1.798uA   -37.95uA
[Ramp]
| variable   typ   min   max
dV/dt_r  0.3835/0.6002n   0.2511/0.9175n   0.5981/0.4134n
dV/dt_f  0.4887/0.5938n   0.3008/0.9028n   0.6817/0.3902n
R_load = 50.0000
[Rising Waveform]
R_fixture=   50.0000
V_fixture=   1.8000
V_fixture_min=   1.7100
V_fixture_max=   1.8900
|time   V(typ)   V(min)   V(max)
0s        985.4mV    1.209V     753.8mV
606.1ps   985.5mV    1.209V     833.5mV
707.1ps   985.8mV    1.209V     1.263V
909.1ps   995.1mV    1.208V     1.657V
1.111ns   1.411V     1.209V     1.829V
1.313ns   1.637V     1.207V     1.869V
1.515ns   1.72V      1.232V     1.881V
1.919ns   1.781V     1.613V     1.888V
2.424ns   1.796V     1.677V     1.89V
10ns      1.8V       1.71V      1.89V
[Rising Waveform]
R_fixture=   50.0000
V_fixture=   0.0
V_fixture_min=   0.0
V_fixture_max=   0.0
|time   V(typ)   V(min)   V(max)
0s        551.1nV    773.6nV    431.5nV
808.1ps   -676.1uV   1.137uV    -5.572mV
909.1ps   -4.556mV   11.92uV    64.26mV
1.212ns   -12.34mV   -127.3uV   572.3mV
1.414ns   17.64mV    -1.571mV   795.9mV
1.919ns   405.2mV    -8.516mV   961.7mV
2.626ns   642.2mV    62.91mV    992.9mV
3.434ns   683.6mV    303.2mV    996.3mV
4.141ns   690.4mV    384.9mV    996.7mV
10ns      692.5mV    418.5mV    996.8mV
[Falling Waveform]
R_fixture=   50.0000
V_fixture=   0.0
V_fixture_min=   0.0
V_fixture_max=   0.0
|time   V(typ)   V(min)   V(max)
0s        692.6mV    418.5mV    996.8mV
606.1ps   692.6mV    418.5mV    997.5mV
707.1ps   692.5mV    418.5mV    905.3mV
1.01ns    690.8mV    418.5mV    105.1mV
1.212ns   464.6mV    418.5mV    22.1mV
1.515ns   89.09mV    418.9mV    5.28mV
1.919ns   11.5mV     337.8mV    876.3uV
2.222ns   4.48mV     105.3mV    263.1uV
2.828ns   834.7uV    13.29mV    53.28uV
10ns      5.228uV    -1.51uV    13.75uV
[Falling Waveform]
R_fixture=   50.0000
V_fixture=   1.8000
V_fixture_min=   1.7100
V_fixture_max=   1.8900
|time   V(typ)   V(min)   V(max)
0s        1.8V       1.71V      1.89V
808.1ps   1.8V       1.71V      1.912V
1.111ns   1.812V     1.71V      1.301V
1.313ns   1.822V     1.71V      1.006V
1.818ns   1.363V     1.716V     788.4mV
2.121ns   1.163V     1.736V     765.3mV
2.525ns   1.049V     1.657V     756.7mV
3.333ns   994.7mV    1.353V     754.1mV
4.141ns   987mV      1.246V     753.8mV
10ns      985.4mV    1.209V     753.8mV
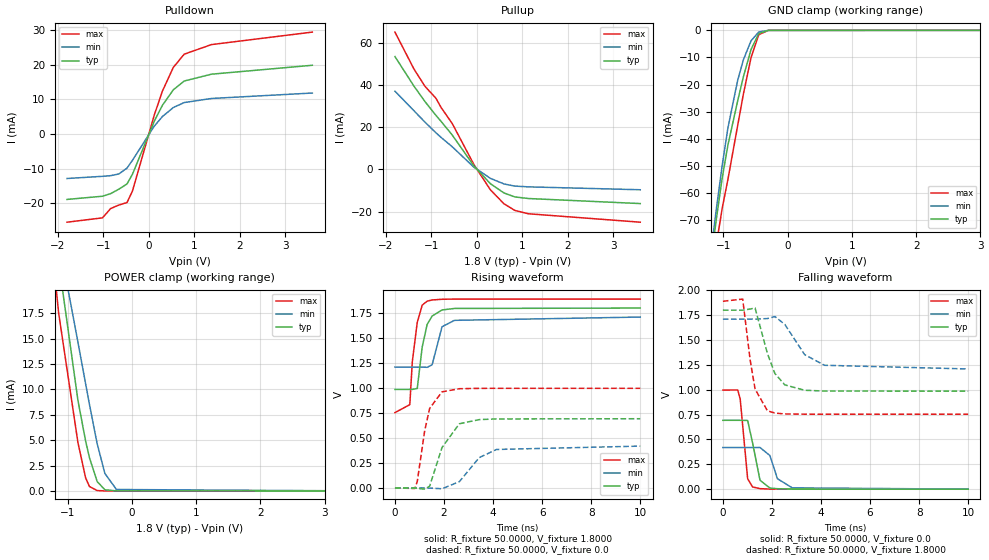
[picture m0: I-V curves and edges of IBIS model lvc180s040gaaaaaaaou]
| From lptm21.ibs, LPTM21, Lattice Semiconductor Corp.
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|   Model lvc180s040gaaaaaaaou
[Model]   lvc180s040gaaaaaaaou
Model_type   Output
Polarity   Non-Inverting
Enable   Active-Low
Vmeas =   0.9000V
Cref =   0.0F
Rref =   1.0000M
Vref =   0.0V
C_comp   4.2000pF   3.8000pF   7.5000pF
[Temperature Range]   25.0000   0.1050k   -40.0000
[Voltage Range]   1.8000V   1.7100V   1.8900V
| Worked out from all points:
|   slope of the pulldown table from 0 to 0.27 V, typ, clamps not added: 35.7 ohm
|   slope of the pullup table from 0 to 0.27 V, typ, clamps not added: 43.7 ohm
|   GND clamp passes 1 mA (typ) near -0.44 V on its own axis
|   POWER clamp passes 1 mA (typ) near -0.54 V on its own axis
|   rising waveform, R_fixture 50.0000, V_fixture 1.8000: 20-80 % time 316ps typ, 320ps min, 273ps max; typ from 0.985 V to 1.8 V
|   rising waveform, R_fixture 50.0000, V_fixture 0.0: 20-80 % time 605ps typ, 927ps min, 417ps max; typ from 0 V to 0.692 V
|   falling waveform, R_fixture 50.0000, V_fixture 0.0: 20-80 % time 293ps typ, 366ps min, 216ps max; typ from 0.693 V to 0 V
|   falling waveform, R_fixture 50.0000, V_fixture 1.8000: 20-80 % time 600ps typ, 912ps min, 394ps max; typ from 1.8 V to 0.985 V
[Pulldown]
|Voltage   I(typ)   I(min)   I(max)
-1.8V     -18.86mA   -12.83mA   -25.42mA
-1.02V    -17.94mA   -12.2mA    -24.17mA
-840mV    -17.19mA   -12.01mA   -21.49mA
-660mV    -15.91mA   -11.52mA   -20.48mA
-480mV    -14.4mA    -9.834mA   -19.76mA
-360mV    -11.61mA   -7.578mA   -16.45mA
120mV     3.67mA     2.253mA    5.436mA
300mV     8.275mA    5.027mA    12.37mA
540mV     12.73mA    7.623mA    19.2mA
780mV     15.26mA    9.056mA    23mA
1.38V     17.23mA    10.23mA    25.76mA
3.6V      19.8mA     11.8mA     29.36mA
[Pullup]
|Voltage   I(typ)   I(min)   I(max)
-1.8V     53.7mA     37.24mA    65.36mA
-1.38V    39.6mA     27.91mA    47.71mA
-1.14V    32.33mA    22.53mA    39.57mA
-900mV    25.8mA     17.5mA     33.95mA
-780mV    22.76mA    15.16mA    29.34mA
-540mV    16.41mA    10.82mA    21.89mA
-60mV     1.619mA    1.03mA     2.26mA
300mV     -6.757mA   -4.222mA   -9.656mA
600mV     -11.18mA   -6.879mA   -16.33mA
840mV     -13.06mA   -7.908mA   -19.49mA
1.14V     -13.82mA   -8.274mA   -21.08mA
3.6V      -16.22mA   -9.647mA   -25.08mA
[GND_clamp]
|Voltage   I(typ)   I(min)   I(max)
-1.8V     -240.2mA   -229.4mA   -254.3mA
-1.2V     -86.16mA   -82.91mA   -94.88mA
-1.17V    -80.45mA   -77.09mA   -89.3mA
-1.11V    -69.45mA   -65.77mA   -78.87mA
-1.02V    -54.48mA   -49.86mA   -65.69mA
-930mV    -42.25mA   -35.9mA    -54.92mA
-780mV    -26.14mA   -18.58mA   -35.25mA
-690mV    -17.13mA   -10.87mA   -23.53mA
-570mV    -7.024mA   -3.834mA   -9.978mA
-450mV    -1.176mA   -584.6uA   -1.582mA
-300mV    -18.65uA   -15.9uA    -16.44uA
3.6V      0A         0A         0A
[POWER_clamp]
|Voltage   I(typ)   I(min)   I(max)
-1.8V     52.51mA    44.24mA    59.69mA
-1.68V    47.44mA    41.17mA    52.62mA
-1.5V     39.45mA    36.1mA     41.14mA
-1.26V    28.3mA     28.66mA    24.99mA
-1.14V    22.57mA    24.76mA    17.52mA
-840mV    8.928mA    14.66mA    4.779mA
-720mV    4.91mA     10.55mA    1.28mA
-660mV    3.265mA    8.507mA    435.9uA
-540mV    921.6uA    4.64mA     35.01uA
-420mV    115.2uA    1.718mA    2.184uA
-240mV    3.289uA    139.9uA    57.44nA
3.6V      -31nA      -27.04nA   -40.53nA
[Ramp]
| variable   typ   min   max
dV/dt_r  0.3835/0.6002n   0.2511/0.9175n   0.5981/0.4134n
dV/dt_f  0.4887/0.5938n   0.3008/0.9028n   0.6817/0.3902n
R_load = 50.0000
[Rising Waveform]
R_fixture=   50.0000
V_fixture=   1.8000
V_fixture_min=   1.7100
V_fixture_max=   1.8900
|time   V(typ)   V(min)   V(max)
0s        985.4mV    1.209V     753.8mV
606.1ps   985.5mV    1.209V     833.5mV
707.1ps   985.8mV    1.209V     1.263V
909.1ps   995.1mV    1.208V     1.657V
1.111ns   1.411V     1.209V     1.829V
1.313ns   1.637V     1.207V     1.869V
1.515ns   1.72V      1.232V     1.881V
1.919ns   1.781V     1.613V     1.888V
2.424ns   1.796V     1.677V     1.89V
10ns      1.8V       1.71V      1.89V
[Rising Waveform]
R_fixture=   50.0000
V_fixture=   0.0
V_fixture_min=   0.0
V_fixture_max=   0.0
|time   V(typ)   V(min)   V(max)
0s        551.1nV    773.6nV    431.5nV
808.1ps   -676.1uV   1.137uV    -5.572mV
909.1ps   -4.556mV   11.92uV    64.26mV
1.212ns   -12.34mV   -127.3uV   572.3mV
1.414ns   17.64mV    -1.571mV   795.9mV
1.919ns   405.2mV    -8.516mV   961.7mV
2.626ns   642.2mV    62.91mV    992.9mV
3.434ns   683.6mV    303.2mV    996.3mV
4.141ns   690.4mV    384.9mV    996.7mV
10ns      692.5mV    418.5mV    996.8mV
[Falling Waveform]
R_fixture=   50.0000
V_fixture=   0.0
V_fixture_min=   0.0
V_fixture_max=   0.0
|time   V(typ)   V(min)   V(max)
0s        692.6mV    418.5mV    996.8mV
606.1ps   692.6mV    418.5mV    997.5mV
707.1ps   692.5mV    418.5mV    905.3mV
1.01ns    690.8mV    418.5mV    105.1mV
1.212ns   464.6mV    418.5mV    22.1mV
1.515ns   89.09mV    418.9mV    5.28mV
1.919ns   11.5mV     337.8mV    876.3uV
2.222ns   4.48mV     105.3mV    263.1uV
2.828ns   834.7uV    13.29mV    53.28uV
10ns      5.228uV    -1.51uV    13.75uV
[Falling Waveform]
R_fixture=   50.0000
V_fixture=   1.8000
V_fixture_min=   1.7100
V_fixture_max=   1.8900
|time   V(typ)   V(min)   V(max)
0s        1.8V       1.71V      1.89V
808.1ps   1.8V       1.71V      1.912V
1.111ns   1.812V     1.71V      1.301V
1.313ns   1.822V     1.71V      1.006V
1.818ns   1.363V     1.716V     788.4mV
2.121ns   1.163V     1.736V     765.3mV
2.525ns   1.049V     1.657V     756.7mV
3.333ns   994.7mV    1.353V     754.1mV
4.141ns   987mV      1.246V     753.8mV
10ns      985.4mV    1.209V     753.8mV
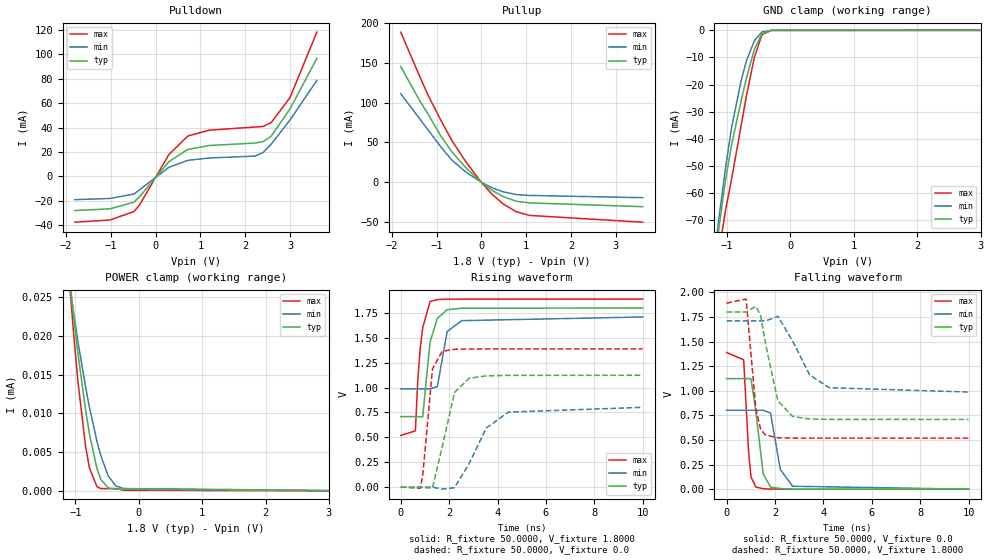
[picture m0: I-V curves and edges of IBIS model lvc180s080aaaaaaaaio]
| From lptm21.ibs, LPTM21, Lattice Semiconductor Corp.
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|   Model lvc180s080aaaaaaaaio
[Model]   lvc180s080aaaaaaaaio
Model_type   I/O
Polarity   Non-Inverting
Enable   Active-Low
Vinl =   0.6300V
Vinh =   1.1700V
Vmeas =   0.9000V
Cref =   0.0F
Rref =   1.0000M
Vref =   0.0V
C_comp   4.2000pF   3.8000pF   7.5000pF
[Temperature Range]   25.0000   0.1050k   -40.0000
[Voltage Range]   1.8000V   1.7100V   1.8900V
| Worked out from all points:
|   slope of the pulldown table from 0 to 0.27 V, typ, clamps not added: 24.3 ohm
|   slope of the pullup table from 0 to 0.27 V, typ, clamps not added: 24.1 ohm
|   GND clamp passes 1 mA (typ) near -0.44 V on its own axis
|   rising waveform, R_fixture 50.0000, V_fixture 1.8000: 20-80 % time 317ps typ, 313ps min, 267ps max; typ from 0.708 V to 1.8 V
|   rising waveform, R_fixture 50.0000, V_fixture 0.0: 20-80 % time 550ps typ, 995ps min, 303ps max; typ from 0 V to 1.12 V
|   falling waveform, R_fixture 50.0000, V_fixture 0.0: 20-80 % time 290ps typ, 361ps min, 202ps max; typ from 1.12 V to 0 V
|   falling waveform, R_fixture 50.0000, V_fixture 1.8000: 20-80 % time 532ps typ, 904ps min, 295ps max; typ from 1.8 V to 0.708 V
[Pulldown]
|Voltage   I(typ)   I(min)   I(max)
-1.8V     -28.04mA   -19.11mA   -37.59mA
-1.02V    -26.67mA   -18.17mA   -35.8mA
-480mV    -21.13mA   -14.49mA   -28.87mA
-360mV    -16.89mA   -11.13mA   -23.66mA
300mV     12.14mA    7.44mA     17.93mA
720mV     22mA       13.12mA    33.05mA
1.2V      25.28mA    15.01mA    37.83mA
2.22V     27.25mA    16.59mA    40.4mA
2.4V      28.42mA    19.5mA     40.82mA
2.58V     32.82mA    26.26mA    43.97mA
3V        55.16mA    46.16mA    64.46mA
3.6V      96.65mA    78.54mA    118.2mA
[Pullup]
|Voltage   I(typ)   I(min)   I(max)
-1.8V     145.2mA    111mA      188.3mA
-1.38V    102.7mA    79.92mA    133.3mA
-1.2V     86.47mA    66.31mA    110.3mA
-900mV    57.64mA    44.09mA    77.35mA
-660mV    38.42mA    28.01mA    52.66mA
-360mV    19.03mA    13.42mA    26.77mA
0V        -3.621nA   -3.321nA   -5.23nA
240mV     -10.15mA   -6.836mA   -15.04mA
480mV     -17.78mA   -11.81mA   -26.87mA
780mV     -23.67mA   -15.37mA   -36.89mA
1.08V     -25.78mA   -16.44mA   -41.49mA
3.6V      -30.51mA   -19.25mA   -49.97mA
[GND_clamp]
|Voltage   I(typ)   I(min)   I(max)
-1.8V     -240.2mA   -229.4mA   -254.3mA
-1.2V     -86.16mA   -82.91mA   -94.88mA
-1.17V    -80.45mA   -77.09mA   -89.3mA
-1.11V    -69.45mA   -65.77mA   -78.87mA
-1.02V    -54.48mA   -49.86mA   -65.69mA
-930mV    -42.25mA   -35.9mA    -54.92mA
-780mV    -26.14mA   -18.58mA   -35.25mA
-690mV    -17.13mA   -10.87mA   -23.53mA
-570mV    -7.024mA   -3.834mA   -9.978mA
-450mV    -1.176mA   -584.6uA   -1.582mA
-300mV    -18.65uA   -15.9uA    -16.44uA
3.6V      0A         0A         0A
[POWER_clamp]
|Voltage   I(typ)   I(min)   I(max)
-1.8V     102.4uA    78.03uA    133.9uA
-1.08V    26.57uA    25.91uA    25.52uA
-1.02V    21.97uA    22.48uA    19.46uA
-960mV    17.73uA    19.24uA    14.09uA
-840mV    10.4uA     13.41uA    5.721uA
-780mV    7.367uA    10.82uA    2.953uA
-660mV    2.828uA    6.356uA    502.7nA
-600mV    1.45uA     4.526uA    261.9nA
-480mV    332.2nA    1.843uA    261.9nA
-360mV    177.6nA    587.2nA    261.9nA
-240mV    177.6nA    270.7nA    57.44nA
3.6V      -31nA      -27.04nA   -40.53nA
[Ramp]
| variable   typ   min   max
dV/dt_r  0.6610/0.5441n   0.4811/0.9851n   0.8331/0.2999n
dV/dt_f  0.6551/0.5269n   0.4337/0.8944n   0.8227/0.2917n
R_load = 50.0000
[Rising Waveform]
R_fixture=   50.0000
V_fixture=   1.8000
V_fixture_min=   1.7100
V_fixture_max=   1.8900
|time   V(typ)   V(min)   V(max)
0s        708.2mV    987.1mV    518.8mV
606.1ps   708.2mV    987.1mV    565.4mV
707.1ps   708.5mV    987.1mV    1.08V
808.1ps   705.9mV    987.1mV    1.399V
909.1ps   707mV      987.1mV    1.601V
1.212ns   1.459V     988.1mV    1.865V
1.515ns   1.696V     1.011V     1.885V
1.919ns   1.783V     1.564V     1.889V
2.525ns   1.798V     1.673V     1.89V
10ns      1.8V       1.71V      1.89V
[Rising Waveform]
R_fixture=   50.0000
V_fixture=   0.0
V_fixture_min=   0.0
V_fixture_max=   0.0
|time   V(typ)   V(min)   V(max)
0s        416.8nV    613.5nV    315.6nV
808.1ps   -1.039mV   1.182uV    -11.37mV
909.1ps   -6.19mV    12.11uV    116.2mV
1.313ns   -8.391mV   -721.4uV   1.187V
1.717ns   406.1mV    -20.81mV   1.365V
2.222ns   950.3mV    -5.742mV   1.385V
2.828ns   1.094V     235.6mV    1.388V
3.535ns   1.118V     593.3mV    1.389V
4.444ns   1.123V     753.5mV    1.389V
10ns      1.124V     801.8mV    1.389V
[Falling Waveform]
R_fixture=   50.0000
V_fixture=   0.0
V_fixture_min=   0.0
V_fixture_max=   0.0
|time   V(typ)   V(min)   V(max)
0s        1.124V     801.8mV    1.389V
707.1ps   1.124V     801.8mV    1.315V
909.1ps   1.124V     801.8mV    387.8mV
1.01ns    1.122V     801.8mV    123.7mV
1.212ns   788.3mV    801.8mV    21.25mV
1.515ns   155.1mV    802.2mV    4.899mV
1.818ns   22.23mV    773.6mV    1.2mV
2.222ns   5.808mV    201.3mV    223.4uV
2.727ns   1.36mV     29.64mV    55.95uV
10ns      -7.639uV   31.92uV    -3.753uV
[Falling Waveform]
R_fixture=   50.0000
V_fixture=   1.8000
V_fixture_min=   1.7100
V_fixture_max=   1.8900
|time   V(typ)   V(min)   V(max)
0s        1.8V       1.71V      1.89V
808.1ps   1.8V       1.71V      1.932V
1.212ns   1.857V     1.71V      814.1mV
1.414ns   1.761V     1.711V     603.6mV
1.616ns   1.471V     1.71V      549.8mV
2.121ns   896.9mV    1.757V     522.5mV
2.727ns   739.1mV    1.507V     519.2mV
3.434ns   713.1mV    1.161V     518.9mV
4.242ns   709mV      1.031V     518.8mV
10ns      708.2mV    987.1mV    518.8mV
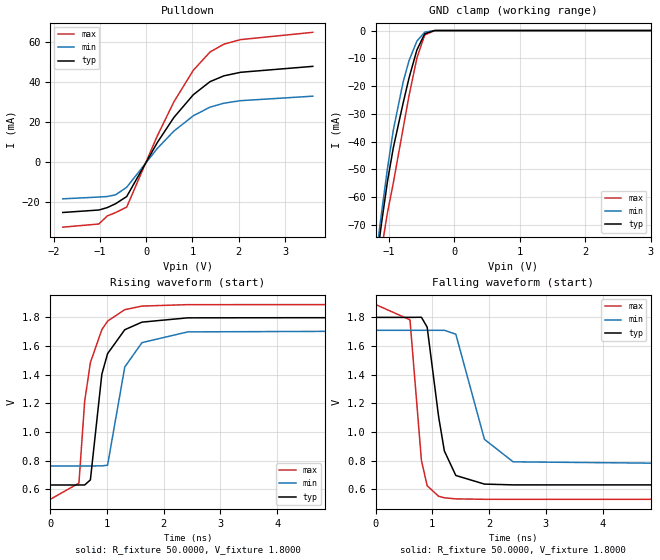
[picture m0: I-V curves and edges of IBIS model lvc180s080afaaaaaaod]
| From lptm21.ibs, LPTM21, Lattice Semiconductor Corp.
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|   Model lvc180s080afaaaaaaod
[Model]   lvc180s080afaaaaaaod
Model_type   I/O_open_drain
Polarity   Non-Inverting
Enable   Active-Low
Vinl =   0.6300V
Vinh =   1.1700V
Vmeas =   0.9000V
Cref =   0.0F
Rref =   1.0000M
Vref =   0.0V
C_comp   4.2000pF   3.8000pF   7.5000pF
[Temperature Range]   25.0000   0.1050k   -40.0000
[Voltage Range]   1.8000V   1.7100V   1.8900V
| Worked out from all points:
|   slope of the pulldown table from 0 to 0.27 V, typ, clamps not added: 24.6 ohm
|   GND clamp passes 1 mA (typ) near -0.44 V on its own axis
|   rising waveform, R_fixture 50.0000, V_fixture 1.8000: 20-80 % time 283ps typ, 283ps min, 267ps max; typ from 0.631 V to 1.8 V
|   falling waveform, R_fixture 50.0000, V_fixture 1.8000: 20-80 % time 249ps typ, 370ps min, 171ps max; typ from 1.8 V to 0.631 V
[Pulldown]
|Voltage   I(typ)   I(min)   I(max)
-1.8V     -25.03mA   -18.22mA   -32.36mA
-1.02V    -23.8mA    -17.33mA   -30.78mA
-840mV    -22.6mA    -17.06mA   -26.77mA
-660mV    -20.66mA   -16.21mA   -25.08mA
-420mV    -17.09mA   -12.45mA   -22.36mA
240mV     9.83mA     6.91mA     13.13mA
600mV     22.43mA    15.62mA    30.22mA
1.02V     33.79mA    23.27mA    46mA
1.38V     40.3mA     27.57mA    55.11mA
1.68V     43.2mA     29.54mA    59.02mA
2.04V     44.97mA    30.8mA     61.29mA
3.6V      47.94mA    33.04mA    64.93mA
[GND_clamp]
|Voltage   I(typ)   I(min)   I(max)
-1.8V     -240.2mA   -229.4mA   -254.3mA
-1.2V     -86.18mA   -82.93mA   -94.91mA
-1.17V    -80.47mA   -77.11mA   -89.33mA
-1.11V    -69.47mA   -65.79mA   -78.9mA
-1.02V    -54.51mA   -49.88mA   -65.72mA
-930mV    -42.27mA   -35.92mA   -54.95mA
-780mV    -26.16mA   -18.59mA   -35.28mA
-690mV    -17.14mA   -10.88mA   -23.55mA
-570mV    -7.035mA   -3.841mA   -9.995mA
-450mV    -1.181mA   -586.6uA   -1.592mA
-300mV    -18.83uA   -15.98uA   -16.73uA
3.6V      0A         0A         0A
[Ramp]
| variable   typ   min   max
dV/dt_r  0.7015/0.2800n   0.5677/0.2803n   0.8155/0.2642n
dV/dt_f  0.7015/0.2465n   0.5677/0.3663n   0.8155/0.1698n
R_load = 50.0000
[Rising Waveform]
R_fixture=   50.0000
V_fixture=   1.8000
V_fixture_min=   1.7100
V_fixture_max=   1.8900
|time   V(typ)   V(min)   V(max)
0s        630.8mV    763.8mV    530.8mV
505.1ps   630.8mV    763.8mV    643.9mV
606.1ps   631mV      763.8mV    1.214V
707.1ps   666.4mV    763.8mV    1.485V
909.1ps   1.404V     764mV      1.715V
1.01ns    1.547V     768.9mV    1.774V
1.313ns   1.714V     1.454V     1.854V
1.616ns   1.767V     1.624V     1.879V
2.424ns   1.797V     1.699V     1.889V
10ns      1.8V       1.71V      1.89V
[Falling Waveform]
R_fixture=   50.0000
V_fixture=   1.8000
V_fixture_min=   1.7100
V_fixture_max=   1.8900
|time   V(typ)   V(min)   V(max)
0s        1.8V       1.71V      1.89V
606.1ps   1.8V       1.71V      1.783V
808.1ps   1.801V     1.71V      802.2mV
909.1ps   1.732V     1.71V      625.6mV
1.111ns   1.107V     1.71V      551.9mV
1.212ns   868.6mV    1.71V      541.6mV
1.414ns   697.2mV    1.683V     533.9mV
1.919ns   637.1mV    949.3mV    531mV
2.424ns   631.6mV    792.4mV    530.9mV
10ns      630.8mV    763.8mV    530.8mV
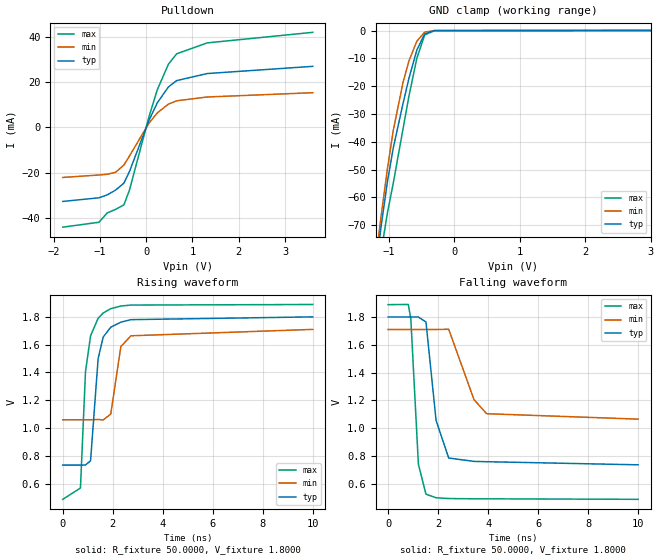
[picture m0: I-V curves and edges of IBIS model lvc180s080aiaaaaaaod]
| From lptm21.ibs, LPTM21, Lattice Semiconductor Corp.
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|   Model lvc180s080aiaaaaaaod
[Model]   lvc180s080aiaaaaaaod
Model_type   I/O_open_drain
Polarity   Non-Inverting
Enable   Active-Low
Vinl =   0.6300V
Vinh =   1.1700V
Vmeas =   0.9000V
Cref =   0.0F
Rref =   1.0000M
Vref =   0.0V
C_comp   4.2000pF   3.8000pF   7.5000pF
[Temperature Range]   25.0000   0.1050k   -40.0000
[Voltage Range]   1.8000V   1.7100V   1.8900V
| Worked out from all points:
|   slope of the pulldown table from 0 to 0.27 V, typ, clamps not added: 22.8 ohm
|   GND clamp passes 1 mA (typ) near -0.44 V on its own axis
|   rising waveform, R_fixture 50.0000, V_fixture 1.8000: 20-80 % time 305ps typ, 326ps min, 301ps max; typ from 0.734 V to 1.8 V
|   falling waveform, R_fixture 50.0000, V_fixture 1.8000: 20-80 % time 386ps typ, 598ps min, 240ps max; typ from 1.8 V to 0.736 V
[Pulldown]
|Voltage   I(typ)   I(min)   I(max)
-1.8V     -32.56mA   -22mA      -43.88mA
-1.02V    -30.96mA   -20.93mA   -41.73mA
-840mV    -29.69mA   -20.61mA   -37.62mA
-660mV    -27.57mA   -19.73mA   -36.06mA
-480mV    -24.53mA   -16.55mA   -34.07mA
-360mV    -19.4mA    -12.57mA   -27.61mA
60mV      3.049mA    1.834mA    4.587mA
240mV     10.79mA    6.377mA    16.51mA
480mV     17.79mA    10.25mA    27.78mA
660mV     20.62mA    11.72mA    32.42mA
1.32V     23.72mA    13.4mA     37.21mA
3.6V      26.89mA    15.29mA    41.86mA
[GND_clamp]
|Voltage   I(typ)   I(min)   I(max)
-1.8V     -240.2mA   -229.3mA   -254.3mA
-1.2V     -86.15mA   -82.88mA   -94.87mA
-1.17V    -80.44mA   -77.06mA   -89.3mA
-1.11V    -69.45mA   -65.75mA   -78.87mA
-1.02V    -54.48mA   -49.85mA   -65.68mA
-930mV    -42.24mA   -35.9mA    -54.91mA
-780mV    -26.14mA   -18.58mA   -35.25mA
-690mV    -17.12mA   -10.87mA   -23.53mA
-570mV    -7.022mA   -3.833mA   -9.976mA
-450mV    -1.175mA   -584.3uA   -1.581mA
-300mV    -18.62uA   -15.88uA   -16.41uA
3.6V      0A         0A         0A
[Ramp]
| variable   typ   min   max
dV/dt_r  0.6393/0.3021n   0.3896/0.3230n   0.8410/0.2976n
dV/dt_f  0.6383/0.3817n   0.3870/0.5925n   0.8412/0.2336n
R_load = 50.0000
[Rising Waveform]
R_fixture=   50.0000
V_fixture=   1.8000
V_fixture_min=   1.7100
V_fixture_max=   1.8900
|time   V(typ)   V(min)   V(max)
0s        734mV      1.06V      487.8mV
707.1ps   734mV      1.06V      569.1mV
909.1ps   734.5mV    1.06V      1.407V
1.111ns   765.2mV    1.06V      1.664V
1.414ns   1.5V       1.062V     1.79V
1.616ns   1.655V     1.059V     1.828V
1.919ns   1.726V     1.101V     1.859V
2.323ns   1.762V     1.587V     1.878V
2.727ns   1.78V      1.664V     1.885V
10ns      1.8V       1.71V      1.889V
[Falling Waveform]
R_fixture=   50.0000
V_fixture=   1.8000
V_fixture_min=   1.7100
V_fixture_max=   1.8900
|time   V(typ)   V(min)   V(max)
0s        1.8V       1.71V      1.889V
808.1ps   1.8V       1.71V      1.89V
909.1ps   1.8V       1.71V      1.788V
1.212ns   1.8V       1.71V      739.5mV
1.515ns   1.764V     1.71V      524.7mV
1.919ns   1.056V     1.71V      499.2mV
2.424ns   785mV      1.712V     493.5mV
3.434ns   760.9mV    1.206V     491.6mV
3.939ns   758.6mV    1.104V     491.5mV
10ns      736.2mV    1.065V     487.8mV
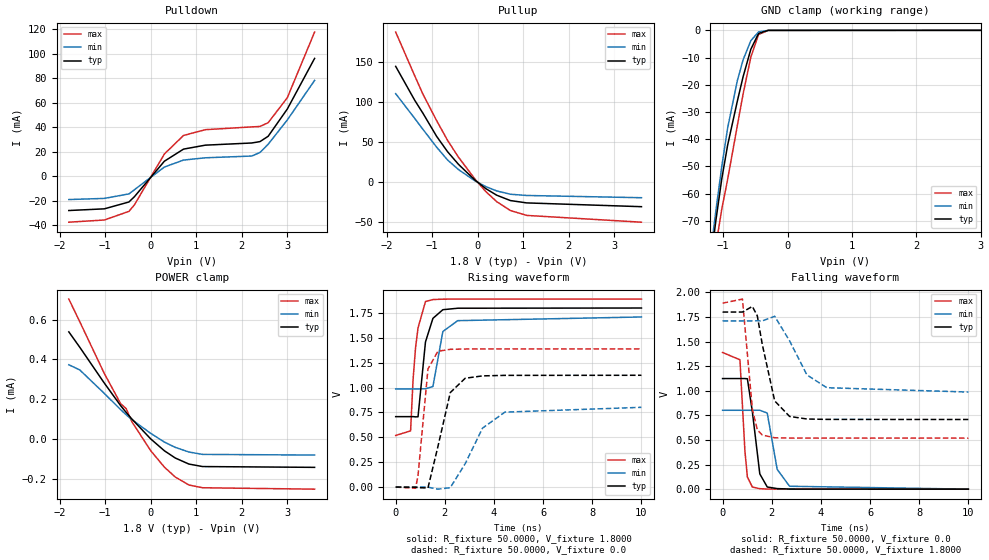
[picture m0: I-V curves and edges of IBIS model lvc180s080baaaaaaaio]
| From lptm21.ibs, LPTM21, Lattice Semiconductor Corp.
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|   Model lvc180s080baaaaaaaio
[Model]   lvc180s080baaaaaaaio
Model_type   I/O
Polarity   Non-Inverting
Enable   Active-Low
Vinl =   0.6300V
Vinh =   1.1700V
Vmeas =   0.9000V
Cref =   0.0F
Rref =   1.0000M
Vref =   0.0V
C_comp   4.2000pF   3.8000pF   7.5000pF
[Temperature Range]   25.0000   0.1050k   -40.0000
[Voltage Range]   1.8000V   1.7100V   1.8900V
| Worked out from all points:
|   slope of the pulldown table from 0 to 0.27 V, typ, clamps not added: 24.4 ohm
|   slope of the pullup table from 0 to 0.27 V, typ, clamps not added: 24.2 ohm
|   GND clamp passes 1 mA (typ) near -0.44 V on its own axis
|   rising waveform, R_fixture 50.0000, V_fixture 1.8000: 20-80 % time 317ps typ, 313ps min, 267ps max; typ from 0.708 V to 1.8 V
|   rising waveform, R_fixture 50.0000, V_fixture 0.0: 20-80 % time 550ps typ, 995ps min, 303ps max; typ from 0 V to 1.12 V
|   falling waveform, R_fixture 50.0000, V_fixture 0.0: 20-80 % time 290ps typ, 361ps min, 202ps max; typ from 1.12 V to 0 V
|   falling waveform, R_fixture 50.0000, V_fixture 1.8000: 20-80 % time 532ps typ, 904ps min, 295ps max; typ from 1.8 V to 0.708 V
[Pulldown]
|Voltage   I(typ)   I(min)   I(max)
-1.8V     -27.99mA   -19.03mA   -37.52mA
-1.02V    -26.62mA   -18.1mA    -35.74mA
-480mV    -21.03mA   -14.42mA   -28.71mA
-360mV    -16.75mA   -11.05mA   -23.42mA
300mV     12.28mA    7.521mA    18.18mA
720mV     22.14mA    13.2mA     33.29mA
1.2V      25.38mA    15.06mA    38.02mA
2.22V     27.15mA    16.5mA     40.28mA
2.4V      28.27mA    19.39mA    40.64mA
2.58V     32.63mA    26.11mA    43.72mA
3V        54.85mA    45.93mA    64.05mA
3.6V      96.21mA    78.24mA    117.7mA
[Pullup]
|Voltage   I(typ)   I(min)   I(max)
-1.8V     144.8mA    110.7mA    187.6mA
-1.38V    102.3mA    79.69mA    132.8mA
-1.2V     86.16mA    66.1mA     109.9mA
-900mV    57.4mA     43.94mA    77.02mA
-660mV    38.26mA    27.91mA    52.42mA
-420mV    22.48mA    15.95mA    31.41mA
-60mV     2.887mA    1.982mA    4.179mA
180mV     -7.805mA   -5.278mA   -11.51mA
420mV     -16.03mA   -10.69mA   -24.1mA
720mV     -22.7mA    -14.82mA   -35.13mA
1.08V     -25.64mA   -16.36mA   -41.26mA
3.6V      -30.35mA   -19.16mA   -49.71mA
[GND_clamp]
|Voltage   I(typ)   I(min)   I(max)
-1.8V     -240.1mA   -229.3mA   -254mA
-1.2V     -86.06mA   -82.86mA   -94.68mA
-1.17V    -80.34mA   -77.04mA   -89.1mA
-1.11V    -69.35mA   -65.72mA   -78.68mA
-1.02V    -54.38mA   -49.81mA   -65.5mA
-930mV    -42.15mA   -35.85mA   -54.73mA
-780mV    -26.05mA   -18.53mA   -35.07mA
-690mV    -17.04mA   -10.83mA   -23.37mA
-570mV    -6.958mA   -3.808mA   -9.842mA
-450mV    -1.149mA   -576.7uA   -1.52mA
-300mV    -18.2uA    -16.01uA   -13uA
3.6V      0A         0A         0A
[POWER_clamp]
|Voltage   I(typ)   I(min)   I(max)
-1.8V     538.6uA    373.2uA    703.6uA
-1.56V    461.4uA    347.2uA    589.9uA
-1.02V    280.9uA    229uA      329.2uA
-660mV    167.1uA    147.2uA    177.1uA
-540mV    133.5uA    121.8uA    152.7uA
-420mV    101.7uA    98.16uA    88.49uA
0V        38.11nA    27.94uA    -59.25uA
300mV     -59.54uA   -15.82uA   -141.8uA
540mV     -96.02uA   -42.44uA   -191.8uA
840mV     -126.4uA   -65.81uA   -231.7uA
1.14V     -138.9uA   -77.7uA    -245.5uA
3.6V      -142.9uA   -81.03uA   -252.6uA
[Ramp]
| variable   typ   min   max
dV/dt_r  0.6610/0.5441n   0.4811/0.9851n   0.8331/0.2999n
dV/dt_f  0.6551/0.5269n   0.4337/0.8944n   0.8227/0.2917n
R_load = 50.0000
[Rising Waveform]
R_fixture=   50.0000
V_fixture=   1.8000
V_fixture_min=   1.7100
V_fixture_max=   1.8900
|time   V(typ)   V(min)   V(max)
0s        708.2mV    987.1mV    518.8mV
606.1ps   708.2mV    987.1mV    565.4mV
707.1ps   708.5mV    987.1mV    1.08V
808.1ps   705.9mV    987.1mV    1.399V
909.1ps   707mV      987.1mV    1.601V
1.212ns   1.459V     988.1mV    1.865V
1.515ns   1.696V     1.011V     1.885V
1.919ns   1.783V     1.564V     1.889V
2.525ns   1.798V     1.673V     1.89V
10ns      1.8V       1.71V      1.89V
[Rising Waveform]
R_fixture=   50.0000
V_fixture=   0.0
V_fixture_min=   0.0
V_fixture_max=   0.0
|time   V(typ)   V(min)   V(max)
0s        416.8nV    613.5nV    315.6nV
808.1ps   -1.039mV   1.182uV    -11.37mV
909.1ps   -6.19mV    12.11uV    116.2mV
1.313ns   -8.391mV   -721.4uV   1.187V
1.717ns   406.1mV    -20.81mV   1.365V
2.222ns   950.3mV    -5.742mV   1.385V
2.828ns   1.094V     235.6mV    1.388V
3.535ns   1.118V     593.3mV    1.389V
4.444ns   1.123V     753.5mV    1.389V
10ns      1.124V     801.8mV    1.389V
[Falling Waveform]
R_fixture=   50.0000
V_fixture=   0.0
V_fixture_min=   0.0
V_fixture_max=   0.0
|time   V(typ)   V(min)   V(max)
0s        1.124V     801.8mV    1.389V
707.1ps   1.124V     801.8mV    1.315V
909.1ps   1.124V     801.8mV    387.8mV
1.01ns    1.122V     801.8mV    123.7mV
1.212ns   788.3mV    801.8mV    21.25mV
1.515ns   155.1mV    802.2mV    4.899mV
1.818ns   22.23mV    773.6mV    1.2mV
2.222ns   5.808mV    201.3mV    223.4uV
2.727ns   1.36mV     29.64mV    55.95uV
10ns      -7.639uV   31.92uV    -3.753uV
[Falling Waveform]
R_fixture=   50.0000
V_fixture=   1.8000
V_fixture_min=   1.7100
V_fixture_max=   1.8900
|time   V(typ)   V(min)   V(max)
0s        1.8V       1.71V      1.89V
808.1ps   1.8V       1.71V      1.932V
1.212ns   1.857V     1.71V      814.1mV
1.414ns   1.761V     1.711V     603.6mV
1.616ns   1.471V     1.71V      549.8mV
2.121ns   896.9mV    1.757V     522.5mV
2.727ns   739.1mV    1.507V     519.2mV
3.434ns   713.1mV    1.161V     518.9mV
4.242ns   709mV      1.031V     518.8mV
10ns      708.2mV    987.1mV    518.8mV
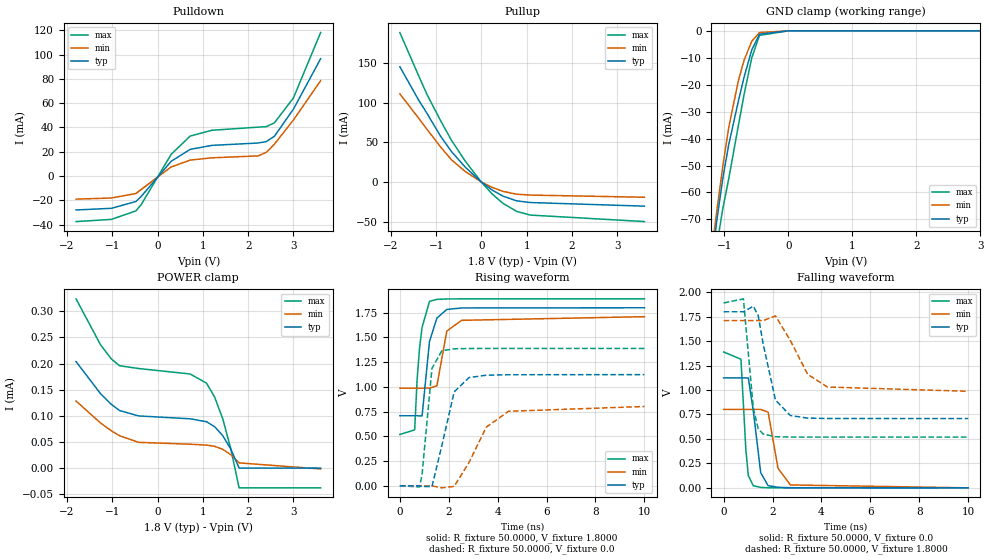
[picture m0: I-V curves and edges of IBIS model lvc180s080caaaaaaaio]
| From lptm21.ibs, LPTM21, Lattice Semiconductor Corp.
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|   Model lvc180s080caaaaaaaio
[Model]   lvc180s080caaaaaaaio
Model_type   I/O
Polarity   Non-Inverting
Enable   Active-Low
Vinl =   0.6300V
Vinh =   1.1700V
Vmeas =   0.9000V
Cref =   0.0F
Rref =   1.0000M
Vref =   0.0V
C_comp   4.2000pF   3.8000pF   7.5000pF
[Temperature Range]   25.0000   0.1050k   -40.0000
[Voltage Range]   1.8000V   1.7100V   1.8900V
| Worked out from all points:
|   slope of the pulldown table from 0 to 0.27 V, typ, clamps not added: 24.5 ohm
|   slope of the pullup table from 0 to 0.27 V, typ, clamps not added: 24.1 ohm
|   GND clamp passes 1 mA (typ) near -0.44 V on its own axis
|   rising waveform, R_fixture 50.0000, V_fixture 1.8000: 20-80 % time 317ps typ, 313ps min, 267ps max; typ from 0.708 V to 1.8 V
|   rising waveform, R_fixture 50.0000, V_fixture 0.0: 20-80 % time 550ps typ, 995ps min, 303ps max; typ from 0 V to 1.12 V
|   falling waveform, R_fixture 50.0000, V_fixture 0.0: 20-80 % time 290ps typ, 361ps min, 202ps max; typ from 1.12 V to 0 V
|   falling waveform, R_fixture 50.0000, V_fixture 1.8000: 20-80 % time 532ps typ, 904ps min, 295ps max; typ from 1.8 V to 0.708 V
[Pulldown]
|Voltage   I(typ)   I(min)   I(max)
-1.8V     -28.01mA   -19.08mA   -37.54mA
-1.02V    -26.63mA   -18.15mA   -35.76mA
-480mV    -21.06mA   -14.44mA   -28.77mA
-360mV    -16.81mA   -11.08mA   -23.53mA
300mV     12.08mA    7.413mA    17.83mA
720mV     21.91mA    13.08mA    32.88mA
1.2V      25.19mA    14.96mA    37.65mA
2.22V     27.15mA    16.54mA    40.22mA
2.4V      28.32mA    19.46mA    40.63mA
2.58V     32.72mA    26.21mA    43.78mA
3V        55.06mA    46.11mA    64.27mA
3.6V      96.55mA    78.49mA    118.1mA
[Pullup]
|Voltage   I(typ)   I(min)   I(max)
-1.8V     145.1mA    111mA      188.1mA
-1.38V    102.6mA    79.87mA    133.1mA
-1.2V     86.37mA    66.26mA    110.1mA
-900mV    57.53mA    44.04mA    77.17mA
-660mV    38.32mA    27.97mA    52.47mA
-360mV    18.9mA     13.37mA    26.59mA
0V        -97.92uA   -46.98uA   -188.2uA
240mV     -10.25mA   -6.882mA   -15.22mA
480mV     -17.88mA   -11.85mA   -27.06mA
780mV     -23.76mA   -15.41mA   -37.07mA
1.08V     -25.87mA   -16.48mA   -41.67mA
3.6V      -30.43mA   -19.23mA   -49.83mA
[GND_clamp]
|Voltage   I(typ)   I(min)   I(max)
-1.8V     -240.2mA   -229.4mA   -254.3mA
-1.2V     -86.19mA   -82.93mA   -94.91mA
-1.17V    -80.47mA   -77.11mA   -89.34mA
-1.11V    -69.48mA   -65.79mA   -78.91mA
-1.02V    -54.51mA   -49.88mA   -65.73mA
-930mV    -42.28mA   -35.92mA   -54.97mA
-780mV    -26.18mA   -18.61mA   -35.3mA
-690mV    -17.17mA   -10.9mA    -23.59mA
-570mV    -7.078mA   -3.876mA   -10.05mA
-450mV    -1.251mA   -635.5uA   -1.696mA
0V        0A         0A         0A
3.6V      0A         0A         0A
[POWER_clamp]
|Voltage   I(typ)   I(min)   I(max)
-1.8V     203.7uA    128.2uA    323.8uA
-1.26V    142.4uA    86.29uA    236uA
-1.02V    121.8uA    71.14uA    208.7uA
-840mV    110.1uA    61.88uA    195.8uA
-420mV    99.75uA    49.18uA    190.5uA
720mV     94.2uA     45.56uA    180uA
1.08V     88.67uA    43.9uA     162.5uA
1.26V     79.17uA    41.55uA    135.8uA
1.44V     61.82uA    35.76uA    94.02uA
1.62V     35.65uA    25.36uA    35.72uA
1.8V      -30.34nA   9.798uA    -37.95uA
3.6V      -30.34nA   -1.798uA   -37.95uA
[Ramp]
| variable   typ   min   max
dV/dt_r  0.6610/0.5441n   0.4811/0.9851n   0.8331/0.2999n
dV/dt_f  0.6551/0.5269n   0.4337/0.8944n   0.8227/0.2917n
R_load = 50.0000
[Rising Waveform]
R_fixture=   50.0000
V_fixture=   1.8000
V_fixture_min=   1.7100
V_fixture_max=   1.8900
|time   V(typ)   V(min)   V(max)
0s        708.2mV    987.1mV    518.8mV
606.1ps   708.2mV    987.1mV    565.4mV
707.1ps   708.5mV    987.1mV    1.08V
808.1ps   705.9mV    987.1mV    1.399V
909.1ps   707mV      987.1mV    1.601V
1.212ns   1.459V     988.1mV    1.865V
1.515ns   1.696V     1.011V     1.885V
1.919ns   1.783V     1.564V     1.889V
2.525ns   1.798V     1.673V     1.89V
10ns      1.8V       1.71V      1.89V
[Rising Waveform]
R_fixture=   50.0000
V_fixture=   0.0
V_fixture_min=   0.0
V_fixture_max=   0.0
|time   V(typ)   V(min)   V(max)
0s        416.8nV    613.5nV    315.6nV
808.1ps   -1.039mV   1.182uV    -11.37mV
909.1ps   -6.19mV    12.11uV    116.2mV
1.313ns   -8.391mV   -721.4uV   1.187V
1.717ns   406.1mV    -20.81mV   1.365V
2.222ns   950.3mV    -5.742mV   1.385V
2.828ns   1.094V     235.6mV    1.388V
3.535ns   1.118V     593.3mV    1.389V
4.444ns   1.123V     753.5mV    1.389V
10ns      1.124V     801.8mV    1.389V
[Falling Waveform]
R_fixture=   50.0000
V_fixture=   0.0
V_fixture_min=   0.0
V_fixture_max=   0.0
|time   V(typ)   V(min)   V(max)
0s        1.124V     801.8mV    1.389V
707.1ps   1.124V     801.8mV    1.315V
909.1ps   1.124V     801.8mV    387.8mV
1.01ns    1.122V     801.8mV    123.7mV
1.212ns   788.3mV    801.8mV    21.25mV
1.515ns   155.1mV    802.2mV    4.899mV
1.818ns   22.23mV    773.6mV    1.2mV
2.222ns   5.808mV    201.3mV    223.4uV
2.727ns   1.36mV     29.64mV    55.95uV
10ns      -7.639uV   31.92uV    -3.753uV
[Falling Waveform]
R_fixture=   50.0000
V_fixture=   1.8000
V_fixture_min=   1.7100
V_fixture_max=   1.8900
|time   V(typ)   V(min)   V(max)
0s        1.8V       1.71V      1.89V
808.1ps   1.8V       1.71V      1.932V
1.212ns   1.857V     1.71V      814.1mV
1.414ns   1.761V     1.711V     603.6mV
1.616ns   1.471V     1.71V      549.8mV
2.121ns   896.9mV    1.757V     522.5mV
2.727ns   739.1mV    1.507V     519.2mV
3.434ns   713.1mV    1.161V     518.9mV
4.242ns   709mV      1.031V     518.8mV
10ns      708.2mV    987.1mV    518.8mV
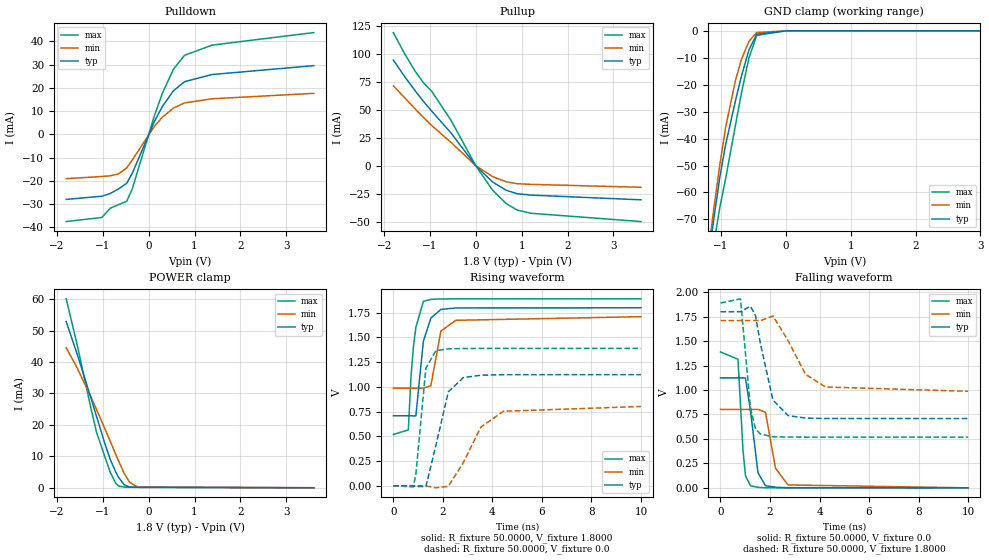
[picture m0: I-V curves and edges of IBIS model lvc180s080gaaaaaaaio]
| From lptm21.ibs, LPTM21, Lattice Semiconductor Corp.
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|   Model lvc180s080gaaaaaaaio
[Model]   lvc180s080gaaaaaaaio
Model_type   I/O
Polarity   Non-Inverting
Enable   Active-Low
Vinl =   0.6300V
Vinh =   1.1700V
Vmeas =   0.9000V
Cref =   0.0F
Rref =   1.0000M
Vref =   0.0V
C_comp   4.2000pF   3.8000pF   7.5000pF
[Temperature Range]   25.0000   0.1050k   -40.0000
[Voltage Range]   1.8000V   1.7100V   1.8900V
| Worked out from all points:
|   slope of the pulldown table from 0 to 0.27 V, typ, clamps not added: 24.5 ohm
|   slope of the pullup table from 0 to 0.27 V, typ, clamps not added: 24.1 ohm
|   GND clamp passes 1 mA (typ) near -0.44 V on its own axis
|   POWER clamp passes 1 mA (typ) near -0.54 V on its own axis
|   rising waveform, R_fixture 50.0000, V_fixture 1.8000: 20-80 % time 317ps typ, 313ps min, 267ps max; typ from 0.708 V to 1.8 V
|   rising waveform, R_fixture 50.0000, V_fixture 0.0: 20-80 % time 550ps typ, 995ps min, 303ps max; typ from 0 V to 1.12 V
|   falling waveform, R_fixture 50.0000, V_fixture 0.0: 20-80 % time 290ps typ, 361ps min, 202ps max; typ from 1.12 V to 0 V
|   falling waveform, R_fixture 50.0000, V_fixture 1.8000: 20-80 % time 532ps typ, 904ps min, 295ps max; typ from 1.8 V to 0.708 V
[Pulldown]
|Voltage   I(typ)   I(min)   I(max)
-1.8V     -28.01mA   -19.08mA   -37.54mA
-1.02V    -26.63mA   -18.15mA   -35.76mA
-840mV    -25.45mA   -17.85mA   -31.8mA
-660mV    -23.53mA   -17.07mA   -30.27mA
-480mV    -21.06mA   -14.44mA   -28.77mA
-360mV    -16.81mA   -11.08mA   -23.53mA
120mV     5.327mA    3.309mA    7.774mA
300mV     12.08mA    7.413mA    17.83mA
540mV     18.74mA    11.3mA     28.01mA
780mV     22.63mA    13.49mA    33.97mA
1.38V     25.71mA    15.28mA    38.36mA
3.6V      29.54mA    17.62mA    43.76mA
[Pullup]
|Voltage   I(typ)   I(min)   I(max)
-1.8V     94.27mA    71.26mA    118.8mA
-1.56V    79.95mA    60.96mA    100.3mA
-1.32V    66.63mA    50.46mA    84.1mA
-1.14V    57.28mA    42.93mA    73.91mA
-960mV    48.61mA    35.76mA    66.26mA
-540mV    29.11mA    20.71mA    40.35mA
0V        -97.92uA   -46.98uA   -188.2uA
360mV     -14.38mA   -9.602mA   -21.55mA
660mV     -21.9mA    -14.34mA   -33.72mA
900mV     -24.98mA   -16.05mA   -39.53mA
1.2V      -26.2mA    -16.64mA   -42.42mA
3.6V      -30.43mA   -19.23mA   -49.83mA
[GND_clamp]
|Voltage   I(typ)   I(min)   I(max)
-1.8V     -240.2mA   -229.4mA   -254.3mA
-1.2V     -86.19mA   -82.93mA   -94.91mA
-1.17V    -80.47mA   -77.11mA   -89.34mA
-1.11V    -69.48mA   -65.79mA   -78.91mA
-1.02V    -54.51mA   -49.88mA   -65.73mA
-930mV    -42.28mA   -35.92mA   -54.97mA
-780mV    -26.18mA   -18.61mA   -35.3mA
-690mV    -17.17mA   -10.9mA    -23.59mA
-570mV    -7.078mA   -3.876mA   -10.05mA
-450mV    -1.251mA   -635.5uA   -1.696mA
0V        0A         0A         0A
3.6V      0A         0A         0A
[POWER_clamp]
|Voltage   I(typ)   I(min)   I(max)
-1.8V     52.89mA    44.55mA    60.11mA
-1.56V    42.48mA    38.1mA     45.43mA
-1.26V    28.54mA    28.86mA    25.25mA
-1.14V    22.78mA    24.93mA    17.72mA
-960mV    14.19mA    18.89mA    9.998mA
-840mV    9.044mA    14.79mA    4.921mA
-720mV    5.001mA    10.65mA    1.403mA
-660mV    3.348mA    8.596mA    566.5uA
-540mV    992.7uA    4.706mA    207.6uA
-420mV    196.7uA    1.763mA    190.5uA
-240mV    100.9uA    180.2uA    188.6uA
3.6V      -30.34nA   -1.798uA   -37.95uA
[Ramp]
| variable   typ   min   max
dV/dt_r  0.6610/0.5441n   0.4811/0.9851n   0.8331/0.2999n
dV/dt_f  0.6551/0.5269n   0.4337/0.8944n   0.8227/0.2917n
R_load = 50.0000
[Rising Waveform]
R_fixture=   50.0000
V_fixture=   1.8000
V_fixture_min=   1.7100
V_fixture_max=   1.8900
|time   V(typ)   V(min)   V(max)
0s        708.2mV    987.1mV    518.8mV
606.1ps   708.2mV    987.1mV    565.4mV
707.1ps   708.5mV    987.1mV    1.08V
808.1ps   705.9mV    987.1mV    1.399V
909.1ps   707mV      987.1mV    1.601V
1.212ns   1.459V     988.1mV    1.865V
1.515ns   1.696V     1.011V     1.885V
1.919ns   1.783V     1.564V     1.889V
2.525ns   1.798V     1.673V     1.89V
10ns      1.8V       1.71V      1.89V
[Rising Waveform]
R_fixture=   50.0000
V_fixture=   0.0
V_fixture_min=   0.0
V_fixture_max=   0.0
|time   V(typ)   V(min)   V(max)
0s        416.8nV    613.5nV    315.6nV
808.1ps   -1.039mV   1.182uV    -11.37mV
909.1ps   -6.19mV    12.11uV    116.2mV
1.313ns   -8.391mV   -721.4uV   1.187V
1.717ns   406.1mV    -20.81mV   1.365V
2.222ns   950.3mV    -5.742mV   1.385V
2.828ns   1.094V     235.6mV    1.388V
3.535ns   1.118V     593.3mV    1.389V
4.444ns   1.123V     753.5mV    1.389V
10ns      1.124V     801.8mV    1.389V
[Falling Waveform]
R_fixture=   50.0000
V_fixture=   0.0
V_fixture_min=   0.0
V_fixture_max=   0.0
|time   V(typ)   V(min)   V(max)
0s        1.124V     801.8mV    1.389V
707.1ps   1.124V     801.8mV    1.315V
909.1ps   1.124V     801.8mV    387.8mV
1.01ns    1.122V     801.8mV    123.7mV
1.212ns   788.3mV    801.8mV    21.25mV
1.515ns   155.1mV    802.2mV    4.899mV
1.818ns   22.23mV    773.6mV    1.2mV
2.222ns   5.808mV    201.3mV    223.4uV
2.727ns   1.36mV     29.64mV    55.95uV
10ns      -7.639uV   31.92uV    -3.753uV
[Falling Waveform]
R_fixture=   50.0000
V_fixture=   1.8000
V_fixture_min=   1.7100
V_fixture_max=   1.8900
|time   V(typ)   V(min)   V(max)
0s        1.8V       1.71V      1.89V
808.1ps   1.8V       1.71V      1.932V
1.212ns   1.857V     1.71V      814.1mV
1.414ns   1.761V     1.711V     603.6mV
1.616ns   1.471V     1.71V      549.8mV
2.121ns   896.9mV    1.757V     522.5mV
2.727ns   739.1mV    1.507V     519.2mV
3.434ns   713.1mV    1.161V     518.9mV
4.242ns   709mV      1.031V     518.8mV
10ns      708.2mV    987.1mV    518.8mV
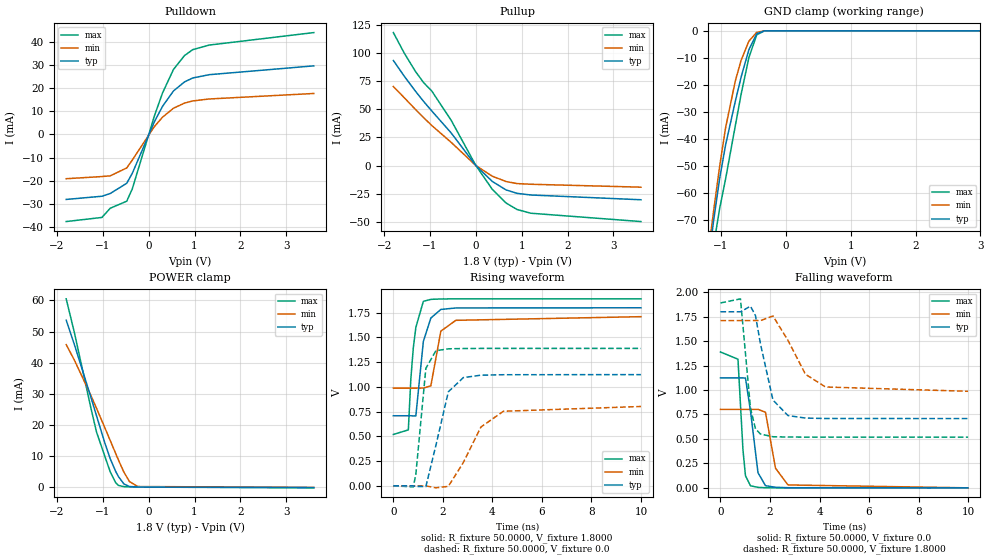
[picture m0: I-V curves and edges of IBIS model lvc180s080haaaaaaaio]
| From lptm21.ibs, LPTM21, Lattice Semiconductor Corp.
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|   Model lvc180s080haaaaaaaio
[Model]   lvc180s080haaaaaaaio
Model_type   I/O
Polarity   Non-Inverting
Enable   Active-Low
Vinl =   0.6300V
Vinh =   1.1700V
Vmeas =   0.9000V
Cref =   0.0F
Rref =   1.0000M
Vref =   0.0V
C_comp   4.2000pF   3.8000pF   7.5000pF
[Temperature Range]   25.0000   0.1050k   -40.0000
[Voltage Range]   1.8000V   1.7100V   1.8900V
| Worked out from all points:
|   slope of the pulldown table from 0 to 0.27 V, typ, clamps not added: 24.5 ohm
|   slope of the pullup table from 0 to 0.27 V, typ, clamps not added: 24.2 ohm
|   GND clamp passes 1 mA (typ) near -0.44 V on its own axis
|   POWER clamp passes 1 mA (typ) near -0.54 V on its own axis
|   rising waveform, R_fixture 50.0000, V_fixture 1.8000: 20-80 % time 317ps typ, 313ps min, 267ps max; typ from 0.708 V to 1.8 V
|   rising waveform, R_fixture 50.0000, V_fixture 0.0: 20-80 % time 550ps typ, 995ps min, 303ps max; typ from 0 V to 1.12 V
|   falling waveform, R_fixture 50.0000, V_fixture 0.0: 20-80 % time 290ps typ, 361ps min, 202ps max; typ from 1.12 V to 0 V
|   falling waveform, R_fixture 50.0000, V_fixture 1.8000: 20-80 % time 532ps typ, 904ps min, 295ps max; typ from 1.8 V to 0.708 V
[Pulldown]
|Voltage   I(typ)   I(min)   I(max)
-1.8V     -28.01mA   -19.08mA   -37.54mA
-1.02V    -26.63mA   -18.15mA   -35.76mA
-840mV    -25.45mA   -17.85mA   -31.8mA
-480mV    -21.06mA   -14.44mA   -28.77mA
-360mV    -16.81mA   -11.08mA   -23.53mA
120mV     5.327mA    3.309mA    7.774mA
300mV     12.08mA    7.413mA    17.83mA
540mV     18.74mA    11.3mA     28.01mA
780mV     22.63mA    13.49mA    33.97mA
960mV     24.33mA    14.44mA    36.53mA
1.32V     25.74mA    15.27mA    38.5mA
3.6V      29.54mA    17.64mA    43.88mA
[Pullup]
|Voltage   I(typ)   I(min)   I(max)
-1.8V     93.48mA    70.29mA    118.3mA
-1.56V    79.39mA    60.28mA    99.91mA
-1.32V    66.27mA    50.02mA    83.88mA
-1.14V    57.06mA    42.64mA    73.79mA
-960mV    48.5mA     35.58mA    66.22mA
-540mV    29.09mA    20.68mA    40.36mA
0V        -2.776nA   -2.379nA   -4.278nA
360mV     -14.21mA   -9.513mA   -21.25mA
660mV     -21.69mA   -14.23mA   -33.36mA
900mV     -24.75mA   -16.05mA   -39.13mA
1.2V      -26.2mA    -16.64mA   -42.42mA
3.6V      -30.43mA   -19.23mA   -49.83mA
[GND_clamp]
|Voltage   I(typ)   I(min)   I(max)
-1.8V     -240.1mA   -229.3mA   -254.1mA
-1.2V     -86.06mA   -82.86mA   -94.69mA
-1.17V    -80.34mA   -77.04mA   -89.11mA
-1.11V    -69.35mA   -65.72mA   -78.69mA
-1.02V    -54.38mA   -49.81mA   -65.51mA
-930mV    -42.15mA   -35.85mA   -54.74mA
-780mV    -26.05mA   -18.53mA   -35.08mA
-690mV    -17.04mA   -10.83mA   -23.36mA
-570mV    -6.946mA   -3.801mA   -9.827mA
-450mV    -1.119mA   -561.2uA   -1.47mA
-330mV    0A         -3.874uA   0A
3.6V      0A         0A         0A
[POWER_clamp]
|Voltage   I(typ)   I(min)   I(max)
-1.8V     53.66mA    45.8mA     60.51mA
-1.62V    45.76mA    40.78mA    49.57mA
-1.26V    28.84mA    29.42mA    25.34mA
-1.14V    22.99mA    25.38mA    17.77mA
-960mV    14.31mA    19.19mA    10.02mA
-840mV    9.109mA    15mA       4.931mA
-720mV    5.041mA    10.79mA    1.399mA
-660mV    3.38mA     8.712mA    551.7uA
-540mV    1.01mA     4.773mA    153.1uA
-420mV    197.6uA    1.797mA    88.49uA
-240mV    59.36uA    194.4uA    21.2uA
3.6V      -132uA     -74.33uA   -225.9uA
[Ramp]
| variable   typ   min   max
dV/dt_r  0.6610/0.5441n   0.4811/0.9851n   0.8331/0.2999n
dV/dt_f  0.6551/0.5269n   0.4337/0.8944n   0.8227/0.2917n
R_load = 50.0000
[Rising Waveform]
R_fixture=   50.0000
V_fixture=   1.8000
V_fixture_min=   1.7100
V_fixture_max=   1.8900
|time   V(typ)   V(min)   V(max)
0s        708.2mV    987.1mV    518.8mV
606.1ps   708.2mV    987.1mV    565.4mV
707.1ps   708.5mV    987.1mV    1.08V
808.1ps   705.9mV    987.1mV    1.399V
909.1ps   707mV      987.1mV    1.601V
1.212ns   1.459V     988.1mV    1.865V
1.515ns   1.696V     1.011V     1.885V
1.919ns   1.783V     1.564V     1.889V
2.525ns   1.798V     1.673V     1.89V
10ns      1.8V       1.71V      1.89V
[Rising Waveform]
R_fixture=   50.0000
V_fixture=   0.0
V_fixture_min=   0.0
V_fixture_max=   0.0
|time   V(typ)   V(min)   V(max)
0s        416.8nV    613.5nV    315.6nV
808.1ps   -1.039mV   1.182uV    -11.37mV
909.1ps   -6.19mV    12.11uV    116.2mV
1.313ns   -8.391mV   -721.4uV   1.187V
1.717ns   406.1mV    -20.81mV   1.365V
2.222ns   950.3mV    -5.742mV   1.385V
2.828ns   1.094V     235.6mV    1.388V
3.535ns   1.118V     593.3mV    1.389V
4.444ns   1.123V     753.5mV    1.389V
10ns      1.124V     801.8mV    1.389V
[Falling Waveform]
R_fixture=   50.0000
V_fixture=   0.0
V_fixture_min=   0.0
V_fixture_max=   0.0
|time   V(typ)   V(min)   V(max)
0s        1.124V     801.8mV    1.389V
707.1ps   1.124V     801.8mV    1.315V
909.1ps   1.124V     801.8mV    387.8mV
1.01ns    1.122V     801.8mV    123.7mV
1.212ns   788.3mV    801.8mV    21.25mV
1.515ns   155.1mV    802.2mV    4.899mV
1.818ns   22.23mV    773.6mV    1.2mV
2.222ns   5.808mV    201.3mV    223.4uV
2.727ns   1.36mV     29.64mV    55.95uV
10ns      -7.639uV   31.92uV    -3.753uV
[Falling Waveform]
R_fixture=   50.0000
V_fixture=   1.8000
V_fixture_min=   1.7100
V_fixture_max=   1.8900
|time   V(typ)   V(min)   V(max)
0s        1.8V       1.71V      1.89V
808.1ps   1.8V       1.71V      1.932V
1.212ns   1.857V     1.71V      814.1mV
1.414ns   1.761V     1.711V     603.6mV
1.616ns   1.471V     1.71V      549.8mV
2.121ns   896.9mV    1.757V     522.5mV
2.727ns   739.1mV    1.507V     519.2mV
3.434ns   713.1mV    1.161V     518.9mV
4.242ns   709mV      1.031V     518.8mV
10ns      708.2mV    987.1mV    518.8mV
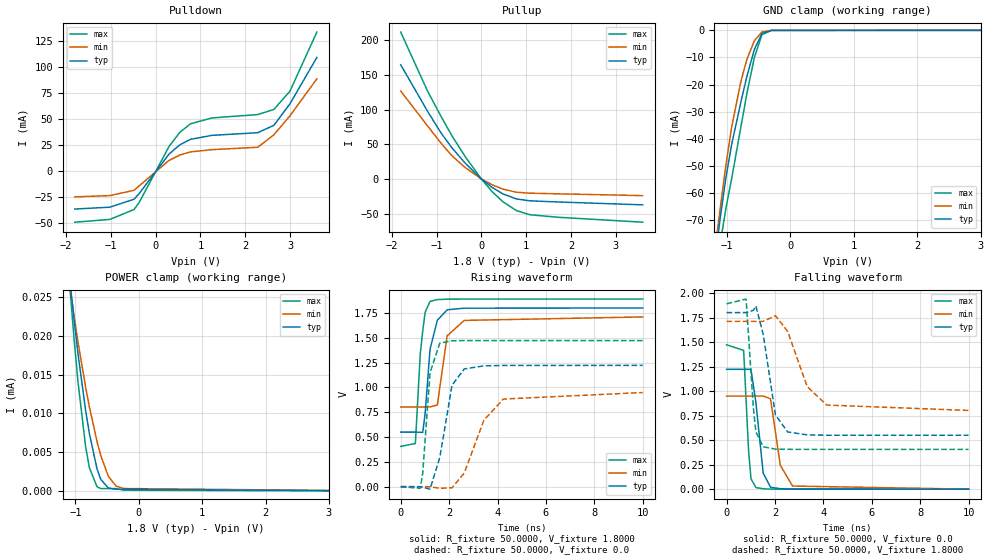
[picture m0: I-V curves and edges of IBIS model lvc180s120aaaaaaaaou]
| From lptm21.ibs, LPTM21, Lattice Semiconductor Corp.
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|   Model lvc180s120aaaaaaaaou
[Model]   lvc180s120aaaaaaaaou
Model_type   Output
Polarity   Non-Inverting
Enable   Active-Low
Vmeas =   0.9000V
Cref =   0.0F
Rref =   1.0000M
Vref =   0.0V
C_comp   4.2000pF   3.8000pF   7.5000pF
[Temperature Range]   25.0000   0.1050k   -40.0000
[Voltage Range]   1.8000V   1.7100V   1.8900V
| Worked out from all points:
|   slope of the pulldown table from 0 to 0.27 V, typ, clamps not added: 18.7 ohm
|   slope of the pullup table from 0 to 0.27 V, typ, clamps not added: 20 ohm
|   GND clamp passes 1 mA (typ) near -0.44 V on its own axis
|   rising waveform, R_fixture 50.0000, V_fixture 1.8000: 20-80 % time 319ps typ, 312ps min, 266ps max; typ from 0.55 V to 1.8 V
|   rising waveform, R_fixture 50.0000, V_fixture 0.0: 20-80 % time 491ps typ, 957ps min, 269ps max; typ from 0 V to 1.22 V
|   falling waveform, R_fixture 50.0000, V_fixture 0.0: 20-80 % time 282ps typ, 360ps min, 192ps max; typ from 1.22 V to 0 V
|   falling waveform, R_fixture 50.0000, V_fixture 1.8000: 20-80 % time 449ps typ, 865ps min, 243ps max; typ from 1.8 V to 0.55 V
[Pulldown]
|Voltage   I(typ)   I(min)   I(max)
-1.8V     -36.99mA   -25.27mA   -49.62mA
-1.02V    -35.18mA   -24.04mA   -46.96mA
-480mV    -27.54mA   -18.97mA   -37.42mA
-360mV    -21.84mA   -14.53mA   -30.28mA
300mV     15.83mA    9.789mA    23.12mA
540mV     24.73mA    14.99mA    36.7mA
780mV     30.08mA    17.97mA    45.01mA
1.26V     33.9mA     20.14mA    50.65mA
2.28V     36.44mA    22.43mA    53.89mA
2.64V     43.52mA    34.37mA    58.78mA
3V        64.26mA    52.75mA    76.44mA
3.6V      108.8mA    88.21mA    133.2mA
[Pullup]
|Voltage   I(typ)   I(min)   I(max)
-1.8V     164.8mA    127mA      212mA
-1.2V     97.61mA    76.46mA    126.7mA
-900mV    66.38mA    51.64mA    90.24mA
-660mV    45.19mA    33.69mA    62.63mA
-360mV    22.67mA    16.42mA    32.18mA
0V        -4.424nA   -4.086nA   -6.319nA
240mV     -12.21mA   -8.441mA   -18.28mA
480mV     -21.51mA   -14.63mA   -32.89mA
780mV     -28.82mA   -19.14mA   -45.55mA
1.08V     -31.55mA   -20.53mA   -51.65mA
1.74V     -33.3mA    -21.5mA    -55.43mA
3.6V      -37.37mA   -24.06mA   -62.41mA
[GND_clamp]
|Voltage   I(typ)   I(min)   I(max)
-1.8V     -240.2mA   -229.4mA   -254.3mA
-1.2V     -86.16mA   -82.91mA   -94.88mA
-1.17V    -80.45mA   -77.09mA   -89.3mA
-1.11V    -69.45mA   -65.77mA   -78.87mA
-1.02V    -54.48mA   -49.86mA   -65.69mA
-930mV    -42.25mA   -35.9mA    -54.92mA
-780mV    -26.14mA   -18.58mA   -35.25mA
-690mV    -17.13mA   -10.87mA   -23.53mA
-570mV    -7.024mA   -3.834mA   -9.978mA
-450mV    -1.176mA   -584.6uA   -1.582mA
-300mV    -18.65uA   -15.9uA    -16.44uA
3.6V      0A         0A         0A
[POWER_clamp]
|Voltage   I(typ)   I(min)   I(max)
-1.8V     102.4uA    78.03uA    133.9uA
-1.08V    26.57uA    25.91uA    25.52uA
-1.02V    21.97uA    22.48uA    19.47uA
-960mV    17.73uA    19.24uA    14.09uA
-840mV    10.4uA     13.41uA    5.722uA
-780mV    7.367uA    10.82uA    2.953uA
-660mV    2.829uA    6.356uA    503.5nA
-600mV    1.451uA    4.527uA    262.6nA
-480mV    332.9nA    1.844uA    262.6nA
-360mV    178.3nA    587.9nA    262.6nA
-240mV    178.3nA    271.4nA    57.44nA
3.6V      -31nA      -27.04nA   -40.53nA
[Ramp]
| variable   typ   min   max
dV/dt_r  0.7331/0.4863n   0.5690/0.9478n   0.8835/0.2663n
dV/dt_f  0.7502/0.4450n   0.5444/0.8564n   0.8906/0.2404n
R_load = 50.0000
[Rising Waveform]
R_fixture=   50.0000
V_fixture=   1.8000
V_fixture_min=   1.7100
V_fixture_max=   1.8900
|time   V(typ)   V(min)   V(max)
0s        549.6mV    802.6mV    405.7mV
606.1ps   549.6mV    802.6mV    435mV
808.1ps   547.6mV    802.6mV    1.336V
909.1ps   545.7mV    802.6mV    1.565V
1.01ns    739mV      802.6mV    1.758V
1.212ns   1.385V     803.6mV    1.866V
1.515ns   1.677V     823mV      1.885V
1.919ns   1.782V     1.52V      1.889V
2.626ns   1.798V     1.675V     1.89V
10ns      1.8V       1.71V      1.89V
[Rising Waveform]
R_fixture=   50.0000
V_fixture=   0.0
V_fixture_min=   0.0
V_fixture_max=   0.0
|time   V(typ)   V(min)   V(max)
0s        335.1nV    508.3nV    248.8nV
808.1ps   -1.082mV   1.168uV    -16.66mV
909.1ps   -6.496mV   11.98uV    135.8mV
1.212ns   -25.35mV   -259.5uV   1.149V
1.616ns   295.2mV    -16.56mV   1.446V
2.121ns   1.022V     -11.34mV   1.47V
2.626ns   1.186V     136.8mV    1.472V
3.434ns   1.217V     668.5mV    1.472V
4.242ns   1.221V     882.6mV    1.472V
10ns      1.222V     948.3mV    1.472V
[Falling Waveform]
R_fixture=   50.0000
V_fixture=   0.0
V_fixture_min=   0.0
V_fixture_max=   0.0
|time   V(typ)   V(min)   V(max)
0s        1.222V     948.4mV    1.472V
707.1ps   1.222V     948.4mV    1.415V
909.1ps   1.222V     948.4mV    397.9mV
1.01ns    1.221V     948.4mV    106.2mV
1.212ns   887.2mV    948.4mV    16.61mV
1.515ns   163.4mV    948.9mV    3.79mV
1.818ns   19.57mV    921.8mV    892.2uV
2.222ns   5.049mV    243.2mV    164.5uV
2.727ns   1.156mV    31.72mV    43.93uV
10ns      23.99uV    18.48uV    3.663uV
[Falling Waveform]
R_fixture=   50.0000
V_fixture=   1.8000
V_fixture_min=   1.7100
V_fixture_max=   1.8900
|time   V(typ)   V(min)   V(max)
0s        1.8V       1.71V      1.89V
808.1ps   1.8V       1.71V      1.938V
1.111ns   1.823V     1.71V      821.3mV
1.212ns   1.867V     1.71V      583.8mV
1.515ns   1.579V     1.711V     432.3mV
2.02ns    757.4mV    1.768V     408.3mV
2.525ns   583.5mV    1.609V     406mV
3.333ns   553.2mV    1.045V     405.7mV
4.141ns   550.1mV    857.4mV    405.7mV
10ns      549.6mV    802.6mV    405.7mV
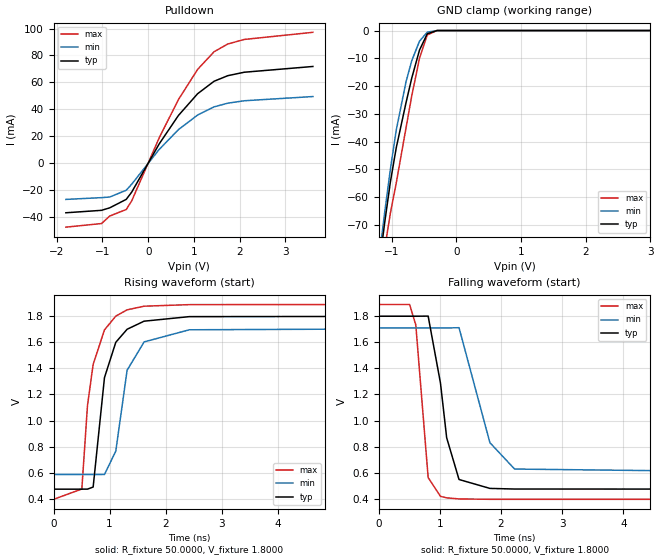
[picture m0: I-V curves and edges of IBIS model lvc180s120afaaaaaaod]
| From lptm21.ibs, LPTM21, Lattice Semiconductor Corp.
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|   Model lvc180s120afaaaaaaod
[Model]   lvc180s120afaaaaaaod
Model_type   I/O_open_drain
Polarity   Non-Inverting
Enable   Active-Low
Vinl =   0.6300V
Vinh =   1.1700V
Vmeas =   0.9000V
Cref =   0.0F
Rref =   1.0000M
Vref =   0.0V
C_comp   4.2000pF   3.8000pF   7.5000pF
[Temperature Range]   25.0000   0.1050k   -40.0000
[Voltage Range]   1.8000V   1.7100V   1.8900V
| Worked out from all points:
|   slope of the pulldown table from 0 to 0.27 V, typ, clamps not added: 17 ohm
|   GND clamp passes 1 mA (typ) near -0.44 V on its own axis
|   rising waveform, R_fixture 50.0000, V_fixture 1.8000: 20-80 % time 287ps typ, 279ps min, 266ps max; typ from 0.473 V to 1.8 V
|   falling waveform, R_fixture 50.0000, V_fixture 1.8000: 20-80 % time 217ps typ, 311ps min, 152ps max; typ from 1.8 V to 0.473 V
[Pulldown]
|Voltage   I(typ)   I(min)   I(max)
-1.8V     -37.03mA   -27.09mA   -47.73mA
-1.02V    -35.21mA   -25.76mA   -45.04mA
-840mV    -33.33mA   -25.3mA    -39.43mA
-480mV    -27.04mA   -20.25mA   -34.57mA
-360mV    -21.62mA   -15.73mA   -28.11mA
240mV     14.2mA     10.09mA    18.72mA
660mV     35.33mA    24.8mA     47.16mA
1.08V     51.54mA    35.7mA     69.64mA
1.44V     60.82mA    41.77mA    82.79mA
1.74V     64.97mA    44.52mA    88.54mA
2.1V      67.54mA    46.31mA    91.93mA
3.6V      71.82mA    49.45mA    97.23mA
[GND_clamp]
|Voltage   I(typ)   I(min)   I(max)
-1.8V     -240.2mA   -229.4mA   -254.3mA
-1.2V     -86.18mA   -82.93mA   -94.91mA
-1.17V    -80.47mA   -77.11mA   -89.33mA
-1.11V    -69.47mA   -65.79mA   -78.9mA
-1.02V    -54.51mA   -49.88mA   -65.72mA
-930mV    -42.27mA   -35.92mA   -54.95mA
-780mV    -26.16mA   -18.59mA   -35.28mA
-690mV    -17.14mA   -10.88mA   -23.55mA
-570mV    -7.035mA   -3.841mA   -9.995mA
-450mV    -1.181mA   -586.6uA   -1.592mA
-300mV    -18.83uA   -15.98uA   -16.73uA
3.6V      0A         0A         0A
[Ramp]
| variable   typ   min   max
dV/dt_r  0.7960/0.2839n   0.6744/0.2765n   0.8968/0.2633n
dV/dt_f  0.7960/0.2146n   0.6744/0.3082n   0.8968/0.1506n
R_load = 50.0000
[Rising Waveform]
R_fixture=   50.0000
V_fixture=   1.8000
V_fixture_min=   1.7100
V_fixture_max=   1.8900
|time   V(typ)   V(min)   V(max)
0s        473.4mV    585.9mV    395.3mV
505.1ps   473.4mV    585.9mV    474.4mV
606.1ps   473.6mV    585.9mV    1.115V
707.1ps   489.7mV    585.9mV    1.431V
909.1ps   1.329V     586.2mV    1.695V
1.111ns   1.6V       764.8mV    1.801V
1.313ns   1.7V       1.386V     1.849V
1.616ns   1.762V     1.603V     1.877V
2.424ns   1.797V     1.696V     1.889V
10ns      1.8V       1.71V      1.89V
[Falling Waveform]
R_fixture=   50.0000
V_fixture=   1.8000
V_fixture_min=   1.7100
V_fixture_max=   1.8900
|time   V(typ)   V(min)   V(max)
0s        1.8V       1.71V      1.89V
505.1ps   1.8V       1.71V      1.89V
606.1ps   1.8V       1.71V      1.733V
808.1ps   1.801V     1.71V      562.3mV
1.01ns    1.286V     1.71V      417.8mV
1.111ns   867.7mV    1.71V      406.8mV
1.313ns   547.4mV    1.712V     398.4mV
1.818ns   479.1mV    830.1mV    395.5mV
2.222ns   474.3mV    627.6mV    395.4mV
10ns      473.4mV    585.9mV    395.3mV
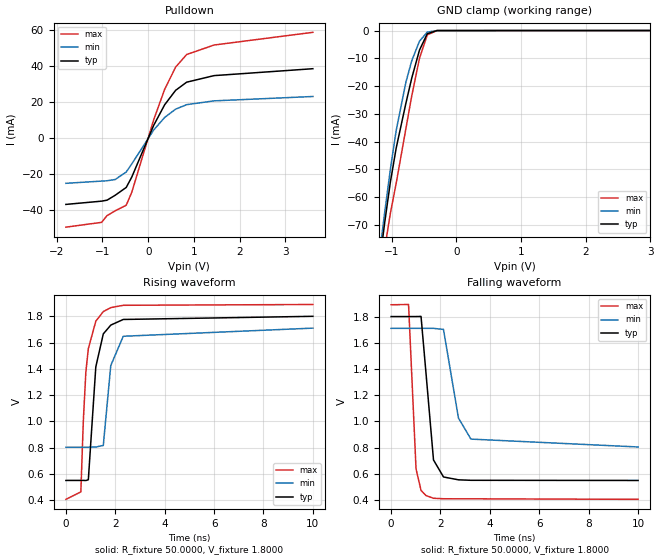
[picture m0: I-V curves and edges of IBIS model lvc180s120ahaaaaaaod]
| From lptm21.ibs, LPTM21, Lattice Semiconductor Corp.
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|   Model lvc180s120ahaaaaaaod
[Model]   lvc180s120ahaaaaaaod
Model_type   I/O_open_drain
Polarity   Non-Inverting
Enable   Active-Low
Vinl =   0.6300V
Vinh =   1.1700V
Vmeas =   0.9000V
Cref =   0.0F
Rref =   1.0000M
Vref =   0.0V
C_comp   4.2000pF   3.8000pF   7.5000pF
[Temperature Range]   25.0000   0.1050k   -40.0000
[Voltage Range]   1.8000V   1.7100V   1.8900V
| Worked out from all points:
|   slope of the pulldown table from 0 to 0.27 V, typ, clamps not added: 18.7 ohm
|   GND clamp passes 1 mA (typ) near -0.44 V on its own axis
|   rising waveform, R_fixture 50.0000, V_fixture 1.8000: 20-80 % time 292ps typ, 293ps min, 298ps max; typ from 0.55 V to 1.8 V
|   falling waveform, R_fixture 50.0000, V_fixture 1.8000: 20-80 % time 293ps typ, 481ps min, 179ps max; typ from 1.8 V to 0.55 V
[Pulldown]
|Voltage   I(typ)   I(min)   I(max)
-1.8V     -36.99mA   -25.27mA   -49.62mA
-1.02V    -35.18mA   -24.04mA   -46.96mA
-900mV    -34.63mA   -23.85mA   -43.22mA
-720mV    -31.87mA   -23.14mA   -40.51mA
-480mV    -27.54mA   -18.97mA   -37.42mA
-360mV    -21.84mA   -14.53mA   -30.28mA
120mV     6.941mA    4.355mA    10.02mA
360mV     18.37mA    11.31mA    26.96mA
600mV     26.4mA     15.93mA    39.3mA
840mV     30.9mA     18.42mA    46.27mA
1.44V     34.55mA    20.53mA    51.55mA
3.6V      38.39mA    22.96mA    58.6mA
[GND_clamp]
|Voltage   I(typ)   I(min)   I(max)
-1.8V     -240.2mA   -229.4mA   -254.3mA
-1.2V     -86.16mA   -82.91mA   -94.88mA
-1.17V    -80.45mA   -77.09mA   -89.3mA
-1.11V    -69.45mA   -65.77mA   -78.87mA
-1.02V    -54.48mA   -49.86mA   -65.69mA
-930mV    -42.25mA   -35.9mA    -54.92mA
-780mV    -26.14mA   -18.58mA   -35.25mA
-690mV    -17.13mA   -10.87mA   -23.53mA
-570mV    -7.024mA   -3.834mA   -9.978mA
-450mV    -1.176mA   -584.6uA   -1.582mA
-300mV    -18.65uA   -15.9uA    -16.44uA
3.6V      0A         0A         0A
[Ramp]
| variable   typ   min   max
dV/dt_r  0.7502/0.2895n   0.5444/0.2901n   0.8906/0.2951n
dV/dt_f  0.7497/0.2628n   0.5429/0.4763n   0.8906/0.1769n
R_load = 50.0000
[Rising Waveform]
R_fixture=   50.0000
V_fixture=   1.8000
V_fixture_min=   1.7100
V_fixture_max=   1.8900
|time   V(typ)   V(min)   V(max)
0s        549.6mV    802.6mV    405.7mV
606.1ps   549.6mV    802.6mV    462.3mV
707.1ps   549.9mV    802.6mV    1.005V
808.1ps   548.9mV    802.6mV    1.374V
909.1ps   554.9mV    802.6mV    1.553V
1.212ns   1.415V     804.2mV    1.763V
1.515ns   1.666V     816.2mV    1.836V
1.818ns   1.733V     1.425V     1.866V
2.323ns   1.776V     1.648V     1.884V
10ns      1.8V       1.71V      1.89V
[Falling Waveform]
R_fixture=   50.0000
V_fixture=   1.8000
V_fixture_min=   1.7100
V_fixture_max=   1.8900
|time   V(typ)   V(min)   V(max)
0s        1.8V       1.71V      1.89V
707.1ps   1.8V       1.71V      1.892V
1.01ns    1.8V       1.71V      637.8mV
1.212ns   1.801V     1.71V      473.6mV
1.414ns   1.366V     1.71V      434.5mV
1.717ns   706.1mV    1.71V      413.7mV
2.121ns   576.3mV    1.702V     410.1mV
2.727ns   554.5mV    1.026V     409.6mV
3.232ns   550.9mV    865.2mV    409.6mV
10ns      549.6mV    805.1mV    405.7mV
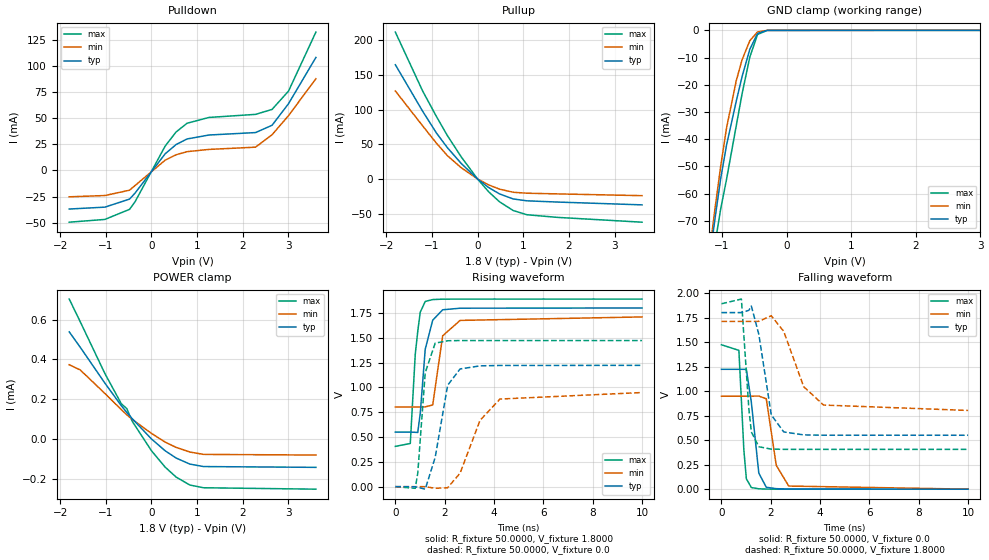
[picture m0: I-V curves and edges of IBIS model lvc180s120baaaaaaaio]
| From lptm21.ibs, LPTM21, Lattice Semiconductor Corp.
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|   Model lvc180s120baaaaaaaio
[Model]   lvc180s120baaaaaaaio
Model_type   I/O
Polarity   Non-Inverting
Enable   Active-Low
Vinl =   0.6300V
Vinh =   1.1700V
Vmeas =   0.9000V
Cref =   0.0F
Rref =   1.0000M
Vref =   0.0V
C_comp   4.2000pF   3.8000pF   7.5000pF
[Temperature Range]   25.0000   0.1050k   -40.0000
[Voltage Range]   1.8000V   1.7100V   1.8900V
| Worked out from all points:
|   slope of the pulldown table from 0 to 0.27 V, typ, clamps not added: 18.7 ohm
|   slope of the pullup table from 0 to 0.27 V, typ, clamps not added: 20.1 ohm
|   GND clamp passes 1 mA (typ) near -0.44 V on its own axis
|   rising waveform, R_fixture 50.0000, V_fixture 1.8000: 20-80 % time 319ps typ, 312ps min, 266ps max; typ from 0.55 V to 1.8 V
|   rising waveform, R_fixture 50.0000, V_fixture 0.0: 20-80 % time 491ps typ, 957ps min, 269ps max; typ from 0 V to 1.22 V
|   falling waveform, R_fixture 50.0000, V_fixture 0.0: 20-80 % time 282ps typ, 360ps min, 192ps max; typ from 1.22 V to 0 V
|   falling waveform, R_fixture 50.0000, V_fixture 1.8000: 20-80 % time 449ps typ, 865ps min, 243ps max; typ from 1.8 V to 0.55 V
[Pulldown]
|Voltage   I(typ)   I(min)   I(max)
-1.8V     -36.94mA   -25.24mA   -49.55mA
-1.02V    -35.14mA   -24.01mA   -46.9mA
-480mV    -27.43mA   -18.9mA    -37.25mA
-360mV    -21.71mA   -14.45mA   -30.04mA
300mV     15.97mA    9.87mA     23.37mA
540mV     24.87mA    15.07mA    36.94mA
780mV     30.21mA    18.04mA    45.25mA
1.26V     33.99mA    20.19mA    50.82mA
2.28V     36.32mA    22.34mA    53.77mA
2.64V     43.31mA    34.21mA    58.5mA
3V        63.95mA    52.53mA    76.03mA
3.6V      108.3mA    87.91mA    132.6mA
[Pullup]
|Voltage   I(typ)   I(min)   I(max)
-1.8V     164.4mA    126.7mA    211.4mA
-1.2V     97.3mA     76.26mA    126.3mA
-900mV    66.15mA    51.48mA    89.91mA
-660mV    45.02mA    33.58mA    62.38mA
-360mV    22.55mA    16.37mA    32.07mA
0V        -3.578nA   -3.138nA   -5.367nA
240mV     -12.17mA   -8.411mA   -18.2mA
480mV     -21.42mA   -14.58mA   -32.75mA
780mV     -28.7mA    -19.07mA   -45.35mA
1.08V     -31.41mA   -20.45mA   -51.42mA
1.74V     -33.15mA   -21.41mA   -55.18mA
3.6V      -37.22mA   -23.97mA   -62.15mA
[GND_clamp]
|Voltage   I(typ)   I(min)   I(max)
-1.8V     -240.1mA   -229.3mA   -254mA
-1.2V     -86.06mA   -82.86mA   -94.68mA
-1.17V    -80.34mA   -77.04mA   -89.1mA
-1.11V    -69.35mA   -65.72mA   -78.68mA
-1.02V    -54.38mA   -49.81mA   -65.5mA
-930mV    -42.15mA   -35.85mA   -54.73mA
-780mV    -26.05mA   -18.53mA   -35.07mA
-690mV    -17.04mA   -10.83mA   -23.37mA
-570mV    -6.958mA   -3.808mA   -9.842mA
-450mV    -1.149mA   -576.7uA   -1.52mA
-300mV    -18.2uA    -16.01uA   -13uA
3.6V      0A         0A         0A
[POWER_clamp]
|Voltage   I(typ)   I(min)   I(max)
-1.8V     538.6uA    373.2uA    703.6uA
-1.56V    461.4uA    347.2uA    589.9uA
-1.02V    280.9uA    229uA      329.2uA
-660mV    167.1uA    147.2uA    177.1uA
-540mV    133.5uA    121.8uA    152.7uA
-420mV    101.7uA    98.16uA    88.49uA
0V        38.11nA    27.94uA    -59.25uA
300mV     -59.54uA   -15.82uA   -141.8uA
540mV     -96.02uA   -42.44uA   -191.8uA
840mV     -126.4uA   -65.81uA   -231.7uA
1.14V     -138.9uA   -77.7uA    -245.5uA
3.6V      -142.9uA   -81.03uA   -252.6uA
[Ramp]
| variable   typ   min   max
dV/dt_r  0.7331/0.4863n   0.5690/0.9478n   0.8835/0.2663n
dV/dt_f  0.7502/0.4450n   0.5444/0.8564n   0.8906/0.2404n
R_load = 50.0000
[Rising Waveform]
R_fixture=   50.0000
V_fixture=   1.8000
V_fixture_min=   1.7100
V_fixture_max=   1.8900
|time   V(typ)   V(min)   V(max)
0s        549.6mV    802.6mV    405.7mV
606.1ps   549.6mV    802.6mV    435mV
808.1ps   547.6mV    802.6mV    1.336V
909.1ps   545.7mV    802.6mV    1.565V
1.01ns    739mV      802.6mV    1.758V
1.212ns   1.385V     803.6mV    1.866V
1.515ns   1.677V     823mV      1.885V
1.919ns   1.782V     1.52V      1.889V
2.626ns   1.798V     1.675V     1.89V
10ns      1.8V       1.71V      1.89V
[Rising Waveform]
R_fixture=   50.0000
V_fixture=   0.0
V_fixture_min=   0.0
V_fixture_max=   0.0
|time   V(typ)   V(min)   V(max)
0s        335.1nV    508.3nV    248.8nV
808.1ps   -1.082mV   1.168uV    -16.66mV
909.1ps   -6.496mV   11.98uV    135.8mV
1.212ns   -25.35mV   -259.5uV   1.149V
1.616ns   295.2mV    -16.56mV   1.446V
2.121ns   1.022V     -11.34mV   1.47V
2.626ns   1.186V     136.8mV    1.472V
3.434ns   1.217V     668.5mV    1.472V
4.242ns   1.221V     882.6mV    1.472V
10ns      1.222V     948.3mV    1.472V
[Falling Waveform]
R_fixture=   50.0000
V_fixture=   0.0
V_fixture_min=   0.0
V_fixture_max=   0.0
|time   V(typ)   V(min)   V(max)
0s        1.222V     948.4mV    1.472V
707.1ps   1.222V     948.4mV    1.415V
909.1ps   1.222V     948.4mV    397.9mV
1.01ns    1.221V     948.4mV    106.2mV
1.212ns   887.2mV    948.4mV    16.61mV
1.515ns   163.4mV    948.9mV    3.79mV
1.818ns   19.57mV    921.8mV    892.2uV
2.222ns   5.049mV    243.2mV    164.5uV
2.727ns   1.156mV    31.72mV    43.93uV
10ns      23.99uV    18.48uV    3.663uV
[Falling Waveform]
R_fixture=   50.0000
V_fixture=   1.8000
V_fixture_min=   1.7100
V_fixture_max=   1.8900
|time   V(typ)   V(min)   V(max)
0s        1.8V       1.71V      1.89V
808.1ps   1.8V       1.71V      1.938V
1.111ns   1.823V     1.71V      821.3mV
1.212ns   1.867V     1.71V      583.8mV
1.515ns   1.579V     1.711V     432.3mV
2.02ns    757.4mV    1.768V     408.3mV
2.525ns   583.5mV    1.609V     406mV
3.333ns   553.2mV    1.045V     405.7mV
4.141ns   550.1mV    857.4mV    405.7mV
10ns      549.6mV    802.6mV    405.7mV
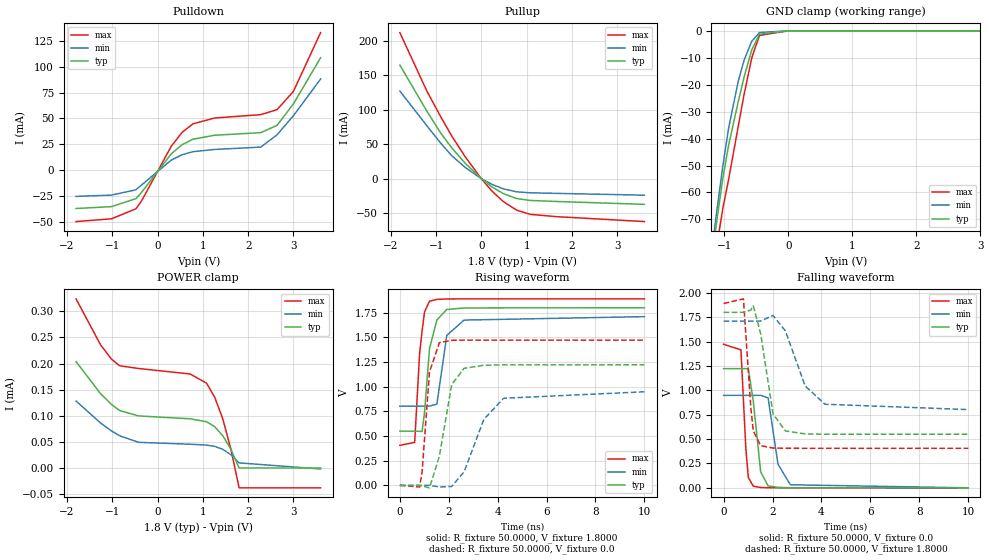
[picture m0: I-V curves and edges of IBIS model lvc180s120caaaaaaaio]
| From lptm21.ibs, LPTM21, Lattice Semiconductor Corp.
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|   Model lvc180s120caaaaaaaio
[Model]   lvc180s120caaaaaaaio
Model_type   I/O
Polarity   Non-Inverting
Enable   Active-Low
Vinl =   0.6300V
Vinh =   1.1700V
Vmeas =   0.9000V
Cref =   0.0F
Rref =   1.0000M
Vref =   0.0V
C_comp   4.2000pF   3.8000pF   7.5000pF
[Temperature Range]   25.0000   0.1050k   -40.0000
[Voltage Range]   1.8000V   1.7100V   1.8900V
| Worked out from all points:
|   slope of the pulldown table from 0 to 0.27 V, typ, clamps not added: 18.8 ohm
|   slope of the pullup table from 0 to 0.27 V, typ, clamps not added: 20 ohm
|   GND clamp passes 1 mA (typ) near -0.44 V on its own axis
|   rising waveform, R_fixture 50.0000, V_fixture 1.8000: 20-80 % time 319ps typ, 312ps min, 266ps max; typ from 0.55 V to 1.8 V
|   rising waveform, R_fixture 50.0000, V_fixture 0.0: 20-80 % time 491ps typ, 957ps min, 269ps max; typ from 0 V to 1.22 V
|   falling waveform, R_fixture 50.0000, V_fixture 0.0: 20-80 % time 282ps typ, 360ps min, 192ps max; typ from 1.22 V to 0 V
|   falling waveform, R_fixture 50.0000, V_fixture 1.8000: 20-80 % time 449ps typ, 865ps min, 243ps max; typ from 1.8 V to 0.55 V
[Pulldown]
|Voltage   I(typ)   I(min)   I(max)
-1.8V     -36.96mA   -25.25mA   -49.57mA
-1.02V    -35.15mA   -24.02mA   -46.92mA
-480mV    -27.47mA   -18.92mA   -37.31mA
-360mV    -21.77mA   -14.48mA   -30.15mA
300mV     15.77mA    9.762mA    23.02mA
540mV     24.65mA    14.95mA    36.55mA
780mV     29.98mA    17.92mA    44.84mA
1.26V     33.8mA     20.09mA    50.46mA
2.28V     36.34mA    22.38mA    53.73mA
2.64V     43.42mA    34.32mA    58.59mA
3V        64.16mA    52.7mA     76.25mA
3.6V      108.7mA    88.16mA    133mA
[Pullup]
|Voltage   I(typ)   I(min)   I(max)
-1.8V     164.7mA    127mA      211.8mA
-1.2V     97.51mA    76.41mA    126.5mA
-900mV    66.28mA    51.59mA    90.05mA
-660mV    45.09mA    33.64mA    62.44mA
-360mV    22.54mA    16.38mA    32.01mA
0V        -97.92uA   -46.98uA   -188.2uA
240mV     -12.31mA   -8.487mA   -18.47mA
480mV     -21.6mA    -14.68mA   -33.07mA
780mV     -28.91mA   -19.19mA   -45.73mA
1.08V     -31.64mA   -20.57mA   -51.83mA
1.68V     -33.19mA   -21.42mA   -55.25mA
3.6V      -37.29mA   -24.01mA   -62.27mA
[GND_clamp]
|Voltage   I(typ)   I(min)   I(max)
-1.8V     -240.2mA   -229.4mA   -254.3mA
-1.2V     -86.19mA   -82.93mA   -94.91mA
-1.17V    -80.47mA   -77.11mA   -89.34mA
-1.11V    -69.48mA   -65.79mA   -78.91mA
-1.02V    -54.51mA   -49.88mA   -65.73mA
-930mV    -42.28mA   -35.92mA   -54.97mA
-780mV    -26.18mA   -18.61mA   -35.3mA
-690mV    -17.17mA   -10.9mA    -23.59mA
-570mV    -7.078mA   -3.876mA   -10.05mA
-450mV    -1.251mA   -635.5uA   -1.696mA
0V        0A         0A         0A
3.6V      0A         0A         0A
[POWER_clamp]
|Voltage   I(typ)   I(min)   I(max)
-1.8V     203.7uA    128.2uA    323.8uA
-1.26V    142.4uA    86.29uA    236uA
-1.02V    121.8uA    71.14uA    208.7uA
-840mV    110.1uA    61.88uA    195.8uA
-420mV    99.75uA    49.18uA    190.5uA
720mV     94.2uA     45.56uA    180uA
1.08V     88.67uA    43.9uA     162.5uA
1.26V     79.17uA    41.55uA    135.8uA
1.44V     61.82uA    35.76uA    94.02uA
1.62V     35.65uA    25.36uA    35.72uA
1.8V      -30.34nA   9.798uA    -37.95uA
3.6V      -30.34nA   -1.798uA   -37.95uA
[Ramp]
| variable   typ   min   max
dV/dt_r  0.7331/0.4863n   0.5690/0.9478n   0.8835/0.2663n
dV/dt_f  0.7502/0.4450n   0.5444/0.8564n   0.8906/0.2404n
R_load = 50.0000
[Rising Waveform]
R_fixture=   50.0000
V_fixture=   1.8000
V_fixture_min=   1.7100
V_fixture_max=   1.8900
|time   V(typ)   V(min)   V(max)
0s        549.6mV    802.6mV    405.7mV
606.1ps   549.6mV    802.6mV    435mV
808.1ps   547.6mV    802.6mV    1.336V
909.1ps   545.7mV    802.6mV    1.565V
1.01ns    739mV      802.6mV    1.758V
1.212ns   1.385V     803.6mV    1.866V
1.515ns   1.677V     823mV      1.885V
1.919ns   1.782V     1.52V      1.889V
2.626ns   1.798V     1.675V     1.89V
10ns      1.8V       1.71V      1.89V
[Rising Waveform]
R_fixture=   50.0000
V_fixture=   0.0
V_fixture_min=   0.0
V_fixture_max=   0.0
|time   V(typ)   V(min)   V(max)
0s        335.1nV    508.3nV    248.8nV
808.1ps   -1.082mV   1.168uV    -16.66mV
909.1ps   -6.496mV   11.98uV    135.8mV
1.212ns   -25.35mV   -259.5uV   1.149V
1.616ns   295.2mV    -16.56mV   1.446V
2.121ns   1.022V     -11.34mV   1.47V
2.626ns   1.186V     136.8mV    1.472V
3.434ns   1.217V     668.5mV    1.472V
4.242ns   1.221V     882.6mV    1.472V
10ns      1.222V     948.3mV    1.472V
[Falling Waveform]
R_fixture=   50.0000
V_fixture=   0.0
V_fixture_min=   0.0
V_fixture_max=   0.0
|time   V(typ)   V(min)   V(max)
0s        1.222V     948.4mV    1.472V
707.1ps   1.222V     948.4mV    1.415V
909.1ps   1.222V     948.4mV    397.9mV
1.01ns    1.221V     948.4mV    106.2mV
1.212ns   887.2mV    948.4mV    16.61mV
1.515ns   163.4mV    948.9mV    3.79mV
1.818ns   19.57mV    921.8mV    892.2uV
2.222ns   5.049mV    243.2mV    164.5uV
2.727ns   1.156mV    31.72mV    43.93uV
10ns      23.99uV    18.48uV    3.663uV
[Falling Waveform]
R_fixture=   50.0000
V_fixture=   1.8000
V_fixture_min=   1.7100
V_fixture_max=   1.8900
|time   V(typ)   V(min)   V(max)
0s        1.8V       1.71V      1.89V
808.1ps   1.8V       1.71V      1.938V
1.111ns   1.823V     1.71V      821.3mV
1.212ns   1.867V     1.71V      583.8mV
1.515ns   1.579V     1.711V     432.3mV
2.02ns    757.4mV    1.768V     408.3mV
2.525ns   583.5mV    1.609V     406mV
3.333ns   553.2mV    1.045V     405.7mV
4.141ns   550.1mV    857.4mV    405.7mV
10ns      549.6mV    802.6mV    405.7mV
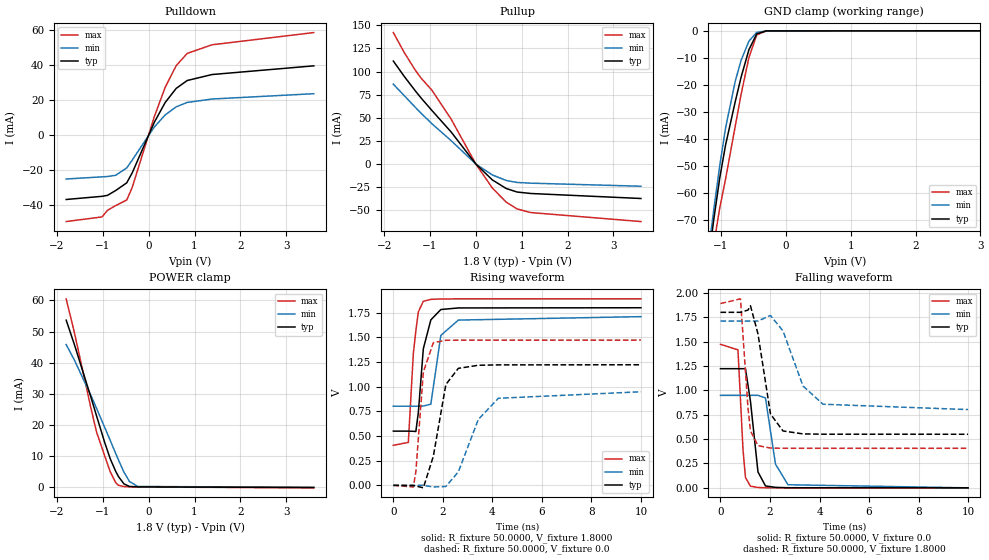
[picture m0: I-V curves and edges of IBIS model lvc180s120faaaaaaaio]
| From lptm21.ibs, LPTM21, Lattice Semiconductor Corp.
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|   Model lvc180s120faaaaaaaio
[Model]   lvc180s120faaaaaaaio
Model_type   I/O
Polarity   Non-Inverting
Enable   Active-Low
Vinl =   0.6300V
Vinh =   1.1700V
Vmeas =   0.9000V
Cref =   0.0F
Rref =   1.0000M
Vref =   0.0V
C_comp   4.2000pF   3.8000pF   7.5000pF
[Temperature Range]   25.0000   0.1050k   -40.0000
[Voltage Range]   1.8000V   1.7100V   1.8900V
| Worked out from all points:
|   slope of the pulldown table from 0 to 0.27 V, typ, clamps not added: 18.7 ohm
|   slope of the pullup table from 0 to 0.27 V, typ, clamps not added: 20.1 ohm
|   GND clamp passes 1 mA (typ) near -0.44 V on its own axis
|   POWER clamp passes 1 mA (typ) near -0.54 V on its own axis
|   rising waveform, R_fixture 50.0000, V_fixture 1.8000: 20-80 % time 319ps typ, 312ps min, 266ps max; typ from 0.55 V to 1.8 V
|   rising waveform, R_fixture 50.0000, V_fixture 0.0: 20-80 % time 491ps typ, 957ps min, 269ps max; typ from 0 V to 1.22 V
|   falling waveform, R_fixture 50.0000, V_fixture 0.0: 20-80 % time 282ps typ, 360ps min, 192ps max; typ from 1.22 V to 0 V
|   falling waveform, R_fixture 50.0000, V_fixture 1.8000: 20-80 % time 449ps typ, 865ps min, 243ps max; typ from 1.8 V to 0.55 V
[Pulldown]
|Voltage   I(typ)   I(min)   I(max)
-1.8V     -36.94mA   -25.24mA   -49.55mA
-1.02V    -35.14mA   -24.01mA   -46.9mA
-900mV    -34.58mA   -23.82mA   -43.15mA
-720mV    -31.81mA   -23.1mA    -40.42mA
-480mV    -27.43mA   -18.9mA    -37.25mA
-360mV    -21.71mA   -14.45mA   -30.04mA
120mV     7.084mA    4.436mA    10.27mA
360mV     18.51mA    11.39mA    27.2mA
600mV     26.54mA    16.01mA    39.55mA
840mV     31.03mA    18.5mA     46.51mA
1.38V     34.43mA    20.45mA    51.43mA
3.6V      39.4mA     23.48mA    58.4mA
[Pullup]
|Voltage   I(typ)   I(min)   I(max)
-1.8V     111.3mA    86.32mA    142.1mA
-1.56V    94.59mA    73.83mA    120.4mA
-1.32V    79.08mA    61.27mA    101.4mA
-1.2V     71.72mA    55.22mA    93.21mA
-960mV    57.98mA    43.63mA    79.88mA
-540mV    34.7mA     25.34mA    48.59mA
0V        -3.579nA   -3.144nA   -5.367nA
360mV     -17.17mA   -11.78mA   -25.95mA
660mV     -26.37mA   -17.71mA   -41.08mA
900mV     -30.25mA   -19.89mA   -48.54mA
1.2V      -31.82mA   -20.66mA   -52.43mA
3.6V      -37.22mA   -23.97mA   -62.15mA
[GND_clamp]
|Voltage   I(typ)   I(min)   I(max)
-1.8V     -240.1mA   -229.3mA   -254mA
-1.2V     -86.06mA   -82.86mA   -94.68mA
-1.17V    -80.34mA   -77.04mA   -89.1mA
-1.11V    -69.35mA   -65.72mA   -78.68mA
-1.02V    -54.38mA   -49.81mA   -65.5mA
-930mV    -42.15mA   -35.85mA   -54.73mA
-780mV    -26.05mA   -18.53mA   -35.07mA
-690mV    -17.04mA   -10.83mA   -23.37mA
-570mV    -6.958mA   -3.808mA   -9.842mA
-450mV    -1.149mA   -576.7uA   -1.52mA
-300mV    -18.2uA    -16.01uA   -13uA
3.6V      0A         0A         0A
[POWER_clamp]
|Voltage   I(typ)   I(min)   I(max)
-1.8V     53.66mA    45.8mA     60.51mA
-1.62V    45.76mA    40.78mA    49.57mA
-1.26V    28.84mA    29.42mA    25.34mA
-1.14V    22.99mA    25.38mA    17.77mA
-960mV    14.31mA    19.19mA    10.02mA
-840mV    9.109mA    15mA       4.931mA
-720mV    5.041mA    10.79mA    1.399mA
-660mV    3.38mA     8.712mA    551.7uA
-540mV    1.01mA     4.773mA    153.1uA
-420mV    197.6uA    1.797mA    88.49uA
-240mV    59.36uA    194.4uA    21.2uA
3.6V      -142.9uA   -81.03uA   -252.6uA
[Ramp]
| variable   typ   min   max
dV/dt_r  0.7331/0.4863n   0.5690/0.9478n   0.8835/0.2663n
dV/dt_f  0.7502/0.4450n   0.5444/0.8564n   0.8906/0.2404n
R_load = 50.0000
[Rising Waveform]
R_fixture=   50.0000
V_fixture=   1.8000
V_fixture_min=   1.7100
V_fixture_max=   1.8900
|time   V(typ)   V(min)   V(max)
0s        549.6mV    802.6mV    405.7mV
606.1ps   549.6mV    802.6mV    435mV
808.1ps   547.6mV    802.6mV    1.336V
909.1ps   545.7mV    802.6mV    1.565V
1.01ns    739mV      802.6mV    1.758V
1.212ns   1.385V     803.6mV    1.866V
1.515ns   1.677V     823mV      1.885V
1.919ns   1.782V     1.52V      1.889V
2.626ns   1.798V     1.675V     1.89V
10ns      1.8V       1.71V      1.89V
[Rising Waveform]
R_fixture=   50.0000
V_fixture=   0.0
V_fixture_min=   0.0
V_fixture_max=   0.0
|time   V(typ)   V(min)   V(max)
0s        335.1nV    508.3nV    248.8nV
808.1ps   -1.082mV   1.168uV    -16.66mV
909.1ps   -6.496mV   11.98uV    135.8mV
1.212ns   -25.35mV   -259.5uV   1.149V
1.616ns   295.2mV    -16.56mV   1.446V
2.121ns   1.022V     -11.34mV   1.47V
2.626ns   1.186V     136.8mV    1.472V
3.434ns   1.217V     668.5mV    1.472V
4.242ns   1.221V     882.6mV    1.472V
10ns      1.222V     948.3mV    1.472V
[Falling Waveform]
R_fixture=   50.0000
V_fixture=   0.0
V_fixture_min=   0.0
V_fixture_max=   0.0
|time   V(typ)   V(min)   V(max)
0s        1.222V     948.4mV    1.472V
707.1ps   1.222V     948.4mV    1.415V
909.1ps   1.222V     948.4mV    397.9mV
1.01ns    1.221V     948.4mV    106.2mV
1.212ns   887.2mV    948.4mV    16.61mV
1.515ns   163.4mV    948.9mV    3.79mV
1.818ns   19.57mV    921.8mV    892.2uV
2.222ns   5.049mV    243.2mV    164.5uV
2.727ns   1.156mV    31.72mV    43.93uV
10ns      23.99uV    18.48uV    3.663uV
[Falling Waveform]
R_fixture=   50.0000
V_fixture=   1.8000
V_fixture_min=   1.7100
V_fixture_max=   1.8900
|time   V(typ)   V(min)   V(max)
0s        1.8V       1.71V      1.89V
808.1ps   1.8V       1.71V      1.938V
1.111ns   1.823V     1.71V      821.3mV
1.212ns   1.867V     1.71V      583.8mV
1.515ns   1.579V     1.711V     432.3mV
2.02ns    757.4mV    1.768V     408.3mV
2.525ns   583.5mV    1.609V     406mV
3.333ns   553.2mV    1.045V     405.7mV
4.141ns   550.1mV    857.4mV    405.7mV
10ns      549.6mV    802.6mV    405.7mV
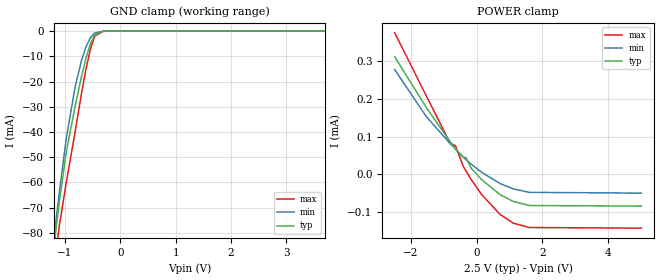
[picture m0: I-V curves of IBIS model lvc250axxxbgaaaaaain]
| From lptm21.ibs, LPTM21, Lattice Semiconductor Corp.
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|   Model lvc250axxxbgaaaaaain
[Model]   lvc250axxxbgaaaaaain
Model_type   Input
Polarity   Non-Inverting
Enable   Active-Low
Vinl =   0.7000V
Vinh =   1.7000V
C_comp   4.2000pF   3.8000pF   7.5000pF
[Temperature Range]   25.0000   0.1050k   -40.0000
[Voltage Range]   2.5000V   2.3800V   2.6300V
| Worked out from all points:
|   GND clamp passes 1 mA (typ) near -0.44 V on its own axis
[GND_clamp]
|Voltage   I(typ)   I(min)   I(max)
-2.5V     -564.6mA   -543.1mA   -585.1mA
-1.18V    -82.28mA   -79mA      -91.03mA
-1.14V    -74.81mA   -71.35mA   -83.85mA
-1.1V     -67.63mA   -63.91mA   -77.15mA
-980mV    -48.6mA    -43.33mA   -60.69mA
-820mV    -30.29mA   -22.62mA   -40.55mA
-700mV    -18.04mA   -11.6mA    -24.7mA
-620mV    -10.82mA   -6.314mA   -15.14mA
-540mV    -5.025mA   -2.64mA    -7.154mA
-460mV    -1.426mA   -708.3uA   -1.934mA
-300mV    -17.76uA   -15.73uA   -12.8uA
5V        0A         0A         0A
[POWER_clamp]
|Voltage   I(typ)   I(min)   I(max)
-2.48V    310.4uA    276.7uA    373.7uA
-1.52V    176.3uA    152.3uA    206.9uA
-800mV    86.61uA    81.35uA    82.18uA
-640mV    66.94uA    66.91uA    75.79uA
-400mV    44.51uA    45.44uA    20.86uA
-320mV    44.51uA    38.99uA    8.918uA
-160mV    16.15uA    26.85uA    -13.85uA
160mV     -14.29uA   5.152uA    -53.97uA
720mV     -53.87uA   -24.56uA   -106.2uA
1.12V     -71.9uA    -38.53uA   -129.1uA
1.6V      -82.26uA   -47.53uA   -140.4uA
5V        -83.86uA   -49.55uA   -142.1uA
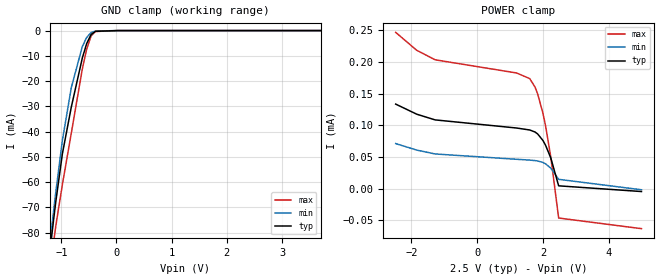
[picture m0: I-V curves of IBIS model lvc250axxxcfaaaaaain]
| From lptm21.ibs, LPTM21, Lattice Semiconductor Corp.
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|   Model lvc250axxxcfaaaaaain
[Model]   lvc250axxxcfaaaaaain
Model_type   Input
Polarity   Non-Inverting
Enable   Active-Low
Vinl =   0.7000V
Vinh =   1.7000V
C_comp   4.2000pF   3.8000pF   7.5000pF
[Temperature Range]   25.0000   0.1050k   -40.0000
[Voltage Range]   2.5000V   2.3800V   2.6300V
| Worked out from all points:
|   GND clamp passes 1 mA (typ) near -0.44 V on its own axis
[GND_clamp]
|Voltage   I(typ)   I(min)   I(max)
-2.5V     -564.7mA   -543.1mA   -585.2mA
-1.18V    -82.37mA   -79.05mA   -91.19mA
-1.14V    -74.91mA   -71.4mA    -84.01mA
-1.1V     -67.72mA   -63.96mA   -77.3mA
-980mV    -48.69mA   -43.39mA   -60.85mA
-820mV    -30.38mA   -22.68mA   -40.71mA
-620mV    -10.92mA   -6.374mA   -15.3mA
-540mV    -5.123mA   -2.7mA     -7.317mA
-460mV    -1.524mA   -767.4uA   -2.097mA
-380mV    -292.5uA   -172.6uA   -366.3uA
20mV      0A         0A         0A
5V        0A         0A         0A
[POWER_clamp]
|Voltage   I(typ)   I(min)   I(max)
-2.48V    133.3uA    71.04uA    246.4uA
-1.84V    117.4uA    60.8uA     218.2uA
-1.28V    108.4uA    54.67uA    203.2uA
1.2V      95.59uA    46.28uA    182.4uA
1.6V      92.47uA    45.01uA    173.5uA
1.76V     89.3uA     44.22uA    160.2uA
1.84V     86.28uA    43.64uA    149.5uA
2V        76.02uA    41.32uA    119.2uA
2.08V     68.53uA    39.17uA    99.45uA
2.24V     48.41uA    32.29uA    50.16uA
2.48V     4.411uA    14.65uA    -46.36uA
5V        -4.578uA   -1.793uA   -63.13uA
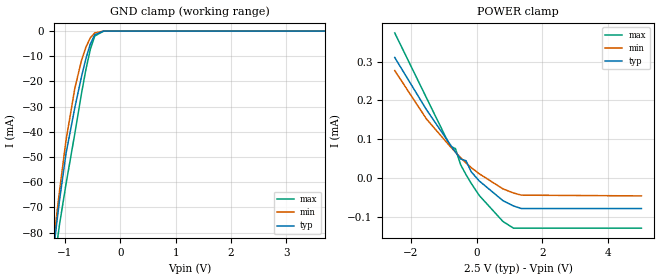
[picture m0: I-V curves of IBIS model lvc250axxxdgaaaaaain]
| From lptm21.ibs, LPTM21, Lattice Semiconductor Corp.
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|   Model lvc250axxxdgaaaaaain
[Model]   lvc250axxxdgaaaaaain
Model_type   Input
Polarity   Non-Inverting
Enable   Active-Low
Vinl =   0.7000V
Vinh =   1.7000V
C_comp   4.2000pF   3.8000pF   7.5000pF
[Temperature Range]   25.0000   0.1050k   -40.0000
[Voltage Range]   2.5000V   2.3800V   2.6300V
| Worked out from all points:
|   GND clamp passes 1 mA (typ) near -0.44 V on its own axis
[GND_clamp]
|Voltage   I(typ)   I(min)   I(max)
-2.5V     -564.6mA   -543.1mA   -585.1mA
-1.18V    -82.29mA   -79mA      -91.05mA
-1.14V    -74.82mA   -71.35mA   -83.87mA
-1.1V     -67.64mA   -63.91mA   -77.16mA
-980mV    -48.61mA   -43.34mA   -60.71mA
-820mV    -30.3mA    -22.63mA   -40.57mA
-700mV    -18.05mA   -11.61mA   -24.72mA
-620mV    -10.84mA   -6.326mA   -15.16mA
-540mV    -5.04mA    -2.652mA   -7.178mA
-460mV    -1.44mA    -719uA     -1.958mA
-300mV    -9.986uA   -9.27uA    -5.3uA
5V        0A         0A         0A
[POWER_clamp]
|Voltage   I(typ)   I(min)   I(max)
-2.48V    310.4uA    276.7uA    373.7uA
-1.52V    176.3uA    152.3uA    206.9uA
-800mV    86.61uA    81.35uA    82.18uA
-640mV    66.94uA    66.91uA    75.79uA
-480mV    48.86uA    52.22uA    34.01uA
-320mV    44.51uA    38.99uA    8.918uA
-160mV    16.15uA    26.85uA    -13.85uA
80mV      -7.284uA   11.17uA    -44.64uA
800mV     -58.16uA   -27.83uA   -111.7uA
1.12V     -71.9uA    -38.53uA   -129.1uA
1.36V     -78.59uA   -44.07uA   -129.1uA
5V        -78.59uA   -46.05uA   -129.1uA
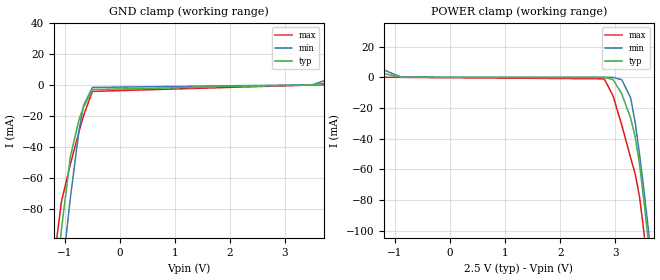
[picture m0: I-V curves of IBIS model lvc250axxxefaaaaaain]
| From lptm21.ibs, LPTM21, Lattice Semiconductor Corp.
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|   Model lvc250axxxefaaaaaain
[Model]   lvc250axxxefaaaaaain
Model_type   Input
Polarity   Non-Inverting
Enable   Active-Low
Vinl =   0.7000V
Vinh =   1.7000V
C_comp   4.2000pF   3.8000pF   7.5000pF
[Temperature Range]   25.0000   0.1050k   -40.0000
[Voltage Range]   2.5000V   2.3800V   2.6300V
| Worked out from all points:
|   GND clamp passes 1 mA (typ) near -0.43 V on its own axis
|   POWER clamp passes 1 mA (typ) near -1.34 V on its own axis
[GND_clamp]
|Voltage   I(typ)   I(min)   I(max)
-2.5V     -636.2mA   -646.6mA   -627.4mA
-1.3V     -177.5mA   -207.3mA   -153.2mA
-1.22V    -148.5mA   -179.4mA   -124.3mA
-1.14V    -120.2mA   -151.8mA   -97.39mA
-1.06V    -93.01mA   -124.8mA   -75.19mA
-900mV    -46.4mA    -73.21mA   -51.29mA
-740mV    -22.22mA   -28.81mA   -29.96mA
-660mV    -14.37mA   -13.41mA   -19.88mA
-500mV    -2.938mA   -1.578mA   -4.175mA
3.5V      2.888uA    72.56uA    2.155uA
3.9V      1.993mA    5.173mA    175.3uA
5V        28.93mA    24.67mA    36.2mA
[POWER_clamp]
|Voltage   I(typ)   I(min)   I(max)
-2.48V    28.48mA    26.33mA    31.35mA
-1.52V    4.936mA    9.466mA    145.3uA
-880mV    876.8nA    72.56uA    1.44uA
2.8V      -19.49uA   -1.147uA   -977uA
2.96V     -1.451mA   -46.93uA   -12.01mA
3.12V     -10.89mA   -1.578mA   -31.28mA
3.28V     -26.67mA   -13.41mA   -52.55mA
3.36V     -38.2mA    -28.81mA   -62.61mA
3.44V     -56.38mA   -49.56mA   -77.55mA
3.52V     -80.05mA   -73.21mA   -100.6mA
3.6V      -106.4mA   -98.49mA   -127.8mA
5V        -636.2mA   -601.8mA   -681.8mA
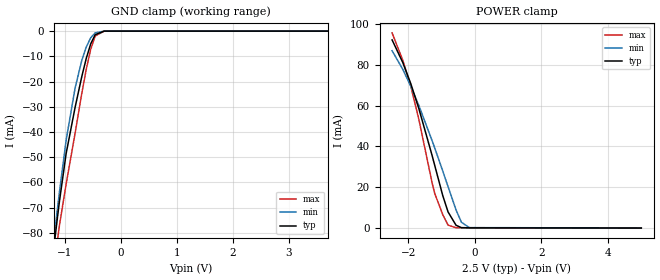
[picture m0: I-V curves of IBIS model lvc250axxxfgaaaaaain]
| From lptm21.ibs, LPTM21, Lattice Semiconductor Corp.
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|   Model lvc250axxxfgaaaaaain
[Model]   lvc250axxxfgaaaaaain
Model_type   Input
Polarity   Non-Inverting
Enable   Active-Low
Vinl =   0.7000V
Vinh =   1.7000V
C_comp   4.2000pF   3.8000pF   7.5000pF
[Temperature Range]   25.0000   0.1050k   -40.0000
[Voltage Range]   2.5000V   2.3800V   2.6300V
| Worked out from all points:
|   GND clamp passes 1 mA (typ) near -0.44 V on its own axis
|   POWER clamp passes 1 mA (typ) near -0.54 V on its own axis
[GND_clamp]
|Voltage   I(typ)   I(min)   I(max)
-2.5V     -564.6mA   -543.1mA   -585.1mA
-1.18V    -82.28mA   -79mA      -91.03mA
-1.14V    -74.81mA   -71.35mA   -83.85mA
-1.1V     -67.63mA   -63.91mA   -77.15mA
-980mV    -48.6mA    -43.33mA   -60.69mA
-820mV    -30.29mA   -22.62mA   -40.55mA
-700mV    -18.04mA   -11.6mA    -24.7mA
-620mV    -10.82mA   -6.314mA   -15.14mA
-540mV    -5.025mA   -2.64mA    -7.154mA
-460mV    -1.426mA   -708.3uA   -1.934mA
-300mV    -17.76uA   -15.73uA   -12.8uA
5V        0A         0A         0A
[POWER_clamp]
|Voltage   I(typ)   I(min)   I(max)
-2.48V    92.38mA    87.03mA    95.82mA
-2.16V    81.29mA    77.94mA    82.39mA
-1.92V    70.92mA    69.63mA    69.65mA
-1.68V    58.78mA    60.26mA    53.56mA
-1.28V    35.62mA    42.91mA    22.18mA
-1.2V     30.69mA    39.25mA    16.92mA
-960mV    15.9mA     27.98mA    6.508mA
-800mV    7.821mA    20.25mA    1.349mA
-560mV    1.267mA    8.796mA    53.58uA
-400mV    117.5uA    2.764mA    20.86uA
-160mV    16.15uA    125.2uA    -13.85uA
5V        -83.86uA   -49.55uA   -142.1uA
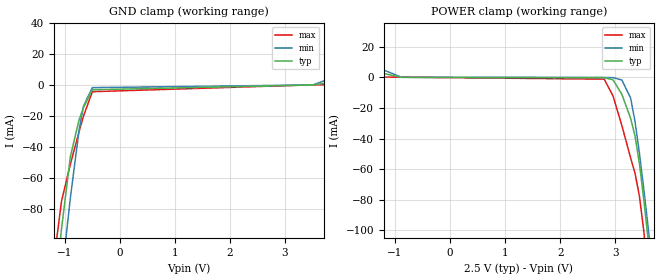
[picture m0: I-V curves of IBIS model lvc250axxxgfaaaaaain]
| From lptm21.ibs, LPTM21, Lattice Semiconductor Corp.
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|   Model lvc250axxxgfaaaaaain
[Model]   lvc250axxxgfaaaaaain
Model_type   Input
Polarity   Non-Inverting
Enable   Active-Low
Vinl =   0.7000V
Vinh =   1.7000V
C_comp   4.2000pF   3.8000pF   7.5000pF
[Temperature Range]   25.0000   0.1050k   -40.0000
[Voltage Range]   2.5000V   2.3800V   2.6300V
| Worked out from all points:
|   GND clamp passes 1 mA (typ) near -0.43 V on its own axis
|   POWER clamp passes 1 mA (typ) near -1.33 V on its own axis
[GND_clamp]
|Voltage   I(typ)   I(min)   I(max)
-2.5V     -636.2mA   -646.6mA   -627.4mA
-1.3V     -177.5mA   -207.3mA   -153.2mA
-1.22V    -148.5mA   -179.4mA   -124.3mA
-1.14V    -120.2mA   -151.8mA   -97.42mA
-1.06V    -93.03mA   -124.8mA   -75.23mA
-900mV    -46.42mA   -73.22mA   -51.33mA
-740mV    -22.26mA   -28.82mA   -30.02mA
-660mV    -14.41mA   -13.44mA   -19.94mA
-500mV    -3.002mA   -1.624mA   -4.265mA
3.5V      106.3uA    118uA      200.4uA
3.9V      2.063mA    5.215mA    326.6uA
5V        29.03mA    24.74mA    36.36mA
[POWER_clamp]
|Voltage   I(typ)   I(min)   I(max)
-2.48V    28.58mA    26.4mA     31.5mA
-1.52V    5.01mA     9.513mA    300.5uA
-880mV    104.5uA    118uA      197.9uA
2.8V      -89.24uA   -23.95uA   -1.094mA
2.96V     -1.523mA   -91.32uA   -12.08mA
3.12V     -10.93mA   -1.624mA   -31.33mA
3.28V     -26.7mA    -13.44mA   -52.6mA
3.36V     -38.23mA   -28.82mA   -62.65mA
3.44V     -56.4mA    -49.57mA   -77.58mA
3.52V     -80.06mA   -73.22mA   -100.6mA
3.6V      -106.5mA   -98.5mA    -127.8mA
5V        -636.2mA   -601.8mA   -681.8mA
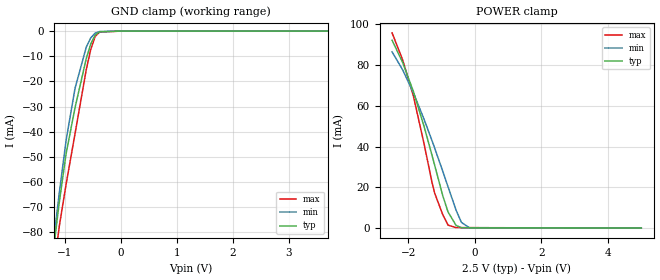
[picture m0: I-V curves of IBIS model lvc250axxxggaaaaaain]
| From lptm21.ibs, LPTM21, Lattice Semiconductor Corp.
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|   Model lvc250axxxggaaaaaain
[Model]   lvc250axxxggaaaaaain
Model_type   Input
Polarity   Non-Inverting
Enable   Active-Low
Vinl =   0.7000V
Vinh =   1.7000V
C_comp   4.2000pF   3.8000pF   7.5000pF
[Temperature Range]   25.0000   0.1050k   -40.0000
[Voltage Range]   2.5000V   2.3800V   2.6300V
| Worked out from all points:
|   GND clamp passes 1 mA (typ) near -0.44 V on its own axis
|   POWER clamp passes 1 mA (typ) near -0.53 V on its own axis
[GND_clamp]
|Voltage   I(typ)   I(min)   I(max)
-2.5V     -564.7mA   -543.1mA   -585.2mA
-1.18V    -82.37mA   -79.05mA   -91.19mA
-1.14V    -74.91mA   -71.4mA    -84.01mA
-1.1V     -67.72mA   -63.96mA   -77.3mA
-980mV    -48.69mA   -43.39mA   -60.85mA
-820mV    -30.38mA   -22.68mA   -40.71mA
-620mV    -10.92mA   -6.374mA   -15.3mA
-540mV    -5.123mA   -2.7mA     -7.317mA
-460mV    -1.524mA   -767.4uA   -2.097mA
-380mV    -292.5uA   -172.6uA   -366.3uA
20mV      0A         0A         0A
5V        0A         0A         0A
[POWER_clamp]
|Voltage   I(typ)   I(min)   I(max)
-2.48V    92.22mA    86.5mA     95.83mA
-2.16V    81.19mA    77.59mA    82.43mA
-1.84V    67mA       66.38mA    64.75mA
-1.52V    49.86mA    53.4mA     41.33mA
-1.28V    35.63mA    42.81mA    22.28mA
-1.2V     30.7mA     39.17mA    17mA
-960mV    15.93mA    27.93mA    6.582mA
-800mV    7.851mA    20.23mA    1.424mA
-560mV    1.299mA    8.796mA    199.2uA
-400mV    169.6uA    2.771mA    193.9uA
-160mV    101.6uA    144.1uA    192.3uA
5V        -4.578uA   -1.793uA   -63.13uA
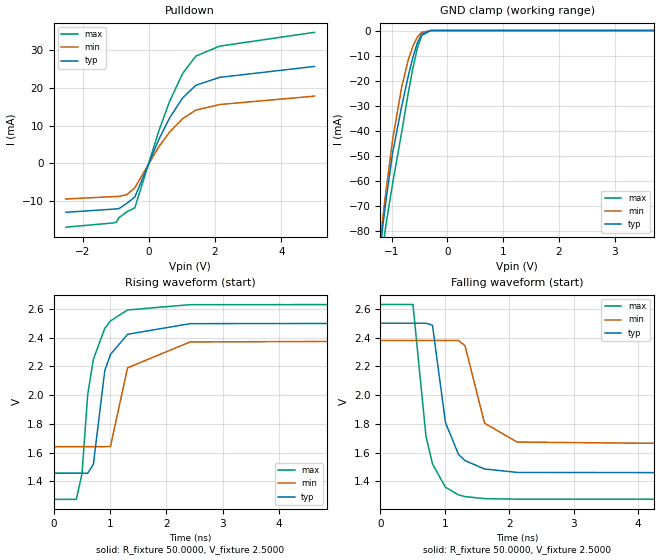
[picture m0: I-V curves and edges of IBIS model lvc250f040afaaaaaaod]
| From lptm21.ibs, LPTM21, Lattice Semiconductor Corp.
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|   Model lvc250f040afaaaaaaod
[Model]   lvc250f040afaaaaaaod
Model_type   I/O_open_drain
Polarity   Non-Inverting
Enable   Active-Low
Vinl =   0.7000V
Vinh =   1.7000V
Vmeas =   1.2500V
Cref =   0.0F
Rref =   1.0000M
Vref =   0.0V
C_comp   4.2000pF   3.8000pF   7.5000pF
[Temperature Range]   25.0000   0.1050k   -40.0000
[Voltage Range]   2.5000V   2.3800V   2.6300V
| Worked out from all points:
|   slope of the pulldown table from 0 to 0.375 V, typ, clamps not added: 48.7 ohm
|   GND clamp passes 1 mA (typ) near -0.44 V on its own axis
|   rising waveform, R_fixture 50.0000, V_fixture 2.5000: 20-80 % time 281ps typ, 292ps min, 268ps max; typ from 1.46 V to 2.5 V
|   falling waveform, R_fixture 50.0000, V_fixture 2.5000: 20-80 % time 246ps typ, 283ps min, 231ps max; typ from 2.5 V to 1.46 V
[Pulldown]
|Voltage   I(typ)   I(min)   I(max)
-2.5V     -12.9mA    -9.383mA   -16.82mA
-1.06V    -12.05mA   -8.76mA    -15.7mA
-980mV    -12mA      -8.725mA   -15.51mA
-900mV    -11.93mA   -8.69mA    -14.31mA
-660mV    -10.51mA   -8.221mA   -12.76mA
-420mV    -8.853mA   -6.399mA   -11.69mA
300mV     6.289mA    4.363mA    8.526mA
620mV     11.89mA    8.194mA    16.22mA
1.02V     17.28mA    11.81mA    23.73mA
1.42V     20.64mA    14.07mA    28.34mA
2.14V     22.73mA    15.56mA    30.97mA
5V        25.61mA    17.77mA    34.62mA
[GND_clamp]
|Voltage   I(typ)   I(min)   I(max)
-2.5V     -564.7mA   -543.1mA   -585.2mA
-1.18V    -82.36mA   -79.04mA   -91.17mA
-1.14V    -74.89mA   -71.39mA   -83.98mA
-1.1V     -67.71mA   -63.95mA   -77.28mA
-980mV    -48.67mA   -43.37mA   -60.82mA
-820mV    -30.36mA   -22.66mA   -40.67mA
-700mV    -18.1mA    -11.63mA   -24.81mA
-620mV    -10.88mA   -6.341mA   -15.24mA
-540mV    -5.068mA   -2.657mA   -7.239mA
-460mV    -1.45mA    -716.2uA   -1.987mA
-300mV    -18.83uA   -15.98uA   -16.73uA
5V        0A         0A         0A
[Ramp]
| variable   typ   min   max
dV/dt_r  0.6254/0.2779n   0.4426/0.2894n   0.8123/0.2649n
dV/dt_f  0.6254/0.2439n   0.4426/0.2801n   0.8123/0.2283n
R_load = 50.0000
[Rising Waveform]
R_fixture=   50.0000
V_fixture=   2.5000
V_fixture_min=   2.3800
V_fixture_max=   2.6300
|time   V(typ)   V(min)   V(max)
0s        1.458V     1.642V     1.276V
404ps     1.458V     1.642V     1.276V
505.1ps   1.458V     1.642V     1.454V
606.1ps   1.457V     1.642V     2.004V
707.1ps   1.52V      1.642V     2.25V
909.1ps   2.171V     1.642V     2.464V
1.01ns    2.283V     1.644V     2.516V
1.313ns   2.423V     2.19V      2.592V
2.424ns   2.497V     2.37V      2.629V
10ns      2.5V       2.38V      2.63V
[Falling Waveform]
R_fixture=   50.0000
V_fixture=   2.5000
V_fixture_min=   2.3800
V_fixture_max=   2.6300
|time   V(typ)   V(min)   V(max)
0s        2.5V       2.38V      2.63V
505.1ps   2.5V       2.38V      2.63V
707.1ps   2.5V       2.38V      1.715V
808.1ps   2.486V     2.38V      1.522V
1.01ns    1.809V     2.38V      1.36V
1.212ns   1.588V     2.38V      1.307V
1.313ns   1.545V     2.344V     1.295V
1.616ns   1.487V     1.805V     1.281V
2.121ns   1.463V     1.674V     1.277V
10ns      1.458V     1.642V     1.276V
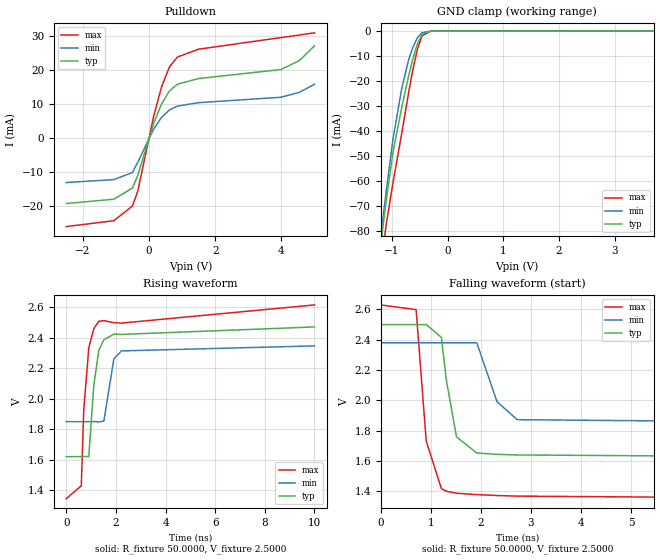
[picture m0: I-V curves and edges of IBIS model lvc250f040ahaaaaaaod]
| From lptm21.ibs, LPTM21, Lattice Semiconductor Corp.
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|   Model lvc250f040ahaaaaaaod
[Model]   lvc250f040ahaaaaaaod
Model_type   I/O_open_drain
Polarity   Non-Inverting
Enable   Active-Low
Vinl =   0.7000V
Vinh =   1.7000V
Vmeas =   1.2500V
Cref =   0.0F
Rref =   1.0000M
Vref =   0.0V
C_comp   4.2000pF   3.8000pF   7.5000pF
[Temperature Range]   25.0000   0.1050k   -40.0000
[Voltage Range]   2.5000V   2.3800V   2.6300V
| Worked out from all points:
|   slope of the pulldown table from 0 to 0.375 V, typ, clamps not added: 37.9 ohm
|   GND clamp passes 1 mA (typ) near -0.44 V on its own axis
|   rising waveform, R_fixture 50.0000, V_fixture 2.5000: 20-80 % time 288ps typ, 277ps min, 304ps max; typ from 1.62 V to 2.47 V
|   falling waveform, R_fixture 50.0000, V_fixture 2.5000: 20-80 % time 237ps typ, 284ps min, 217ps max; typ from 2.5 V to 1.62 V
[Pulldown]
|Voltage   I(typ)   I(min)   I(max)
-2.5V     -19.19mA   -13.05mA   -25.94mA
-1.06V    -17.92mA   -12.18mA   -24.22mA
-500mV    -14.66mA   -10.11mA   -19.91mA
-340mV    -11mA      -7.151mA   -15.61mA
140mV     4.235mA    2.597mA    6.279mA
380mV     9.975mA    6.03mA     14.97mA
620mV     13.78mA    8.219mA    20.81mA
860mV     15.74mA    9.335mA    23.7mA
1.5V      17.41mA    10.34mA    26mA
3.98V     20.03mA    11.92mA    29.38mA
4.54V     22.64mA    13.34mA    30.14mA
5V        26.95mA    15.73mA    30.79mA
[GND_clamp]
|Voltage   I(typ)   I(min)   I(max)
-2.5V     -564.7mA   -543mA     -585.2mA
-1.18V    -82.34mA   -79.02mA   -91.14mA
-1.14V    -74.87mA   -71.37mA   -83.95mA
-1.1V     -67.69mA   -63.93mA   -77.25mA
-980mV    -48.65mA   -43.36mA   -60.78mA
-820mV    -30.34mA   -22.64mA   -40.65mA
-700mV    -18.08mA   -11.62mA   -24.79mA
-620mV    -10.86mA   -6.332mA   -15.22mA
-540mV    -5.058mA   -2.652mA   -7.223mA
-460mV    -1.444mA   -713.9uA   -1.977mA
-300mV    -18.65uA   -15.9uA    -16.44uA
5V        0A         0A         0A
[Ramp]
| variable   typ   min   max
dV/dt_r  0.5264/0.2328n   0.3176/0.2485n   0.7606/0.3013n
dV/dt_f  0.5265/0.2349n   0.3176/0.2807n   0.7682/0.2148n
R_load = 50.0000
[Rising Waveform]
R_fixture=   50.0000
V_fixture=   2.5000
V_fixture_min=   2.3800
V_fixture_max=   2.6300
|time   V(typ)   V(min)   V(max)
0s        1.621V     1.85V      1.346V
606.1ps   1.621V     1.85V      1.43V
707.1ps   1.622V     1.85V      1.932V
909.1ps   1.622V     1.85V      2.333V
1.111ns   2.088V     1.851V     2.46V
1.313ns   2.317V     1.848V     2.507V
1.515ns   2.386V     1.854V     2.511V
1.919ns   2.423V     2.261V     2.498V
2.222ns   2.421V     2.313V     2.495V
10ns      2.47V      2.346V     2.614V
[Falling Waveform]
R_fixture=   50.0000
V_fixture=   2.5000
V_fixture_min=   2.3800
V_fixture_max=   2.6300
|time   V(typ)   V(min)   V(max)
0s        2.5V       2.38V      2.63V
707.1ps   2.5V       2.38V      2.599V
909.1ps   2.5V       2.38V      1.731V
1.212ns   2.416V     2.38V      1.417V
1.313ns   2.129V     2.38V      1.399V
1.515ns   1.758V     2.38V      1.386V
1.919ns   1.652V     2.38V      1.377V
2.323ns   1.643V     1.991V     1.371V
2.727ns   1.639V     1.872V     1.367V
10ns      1.623V     1.851V     1.35V
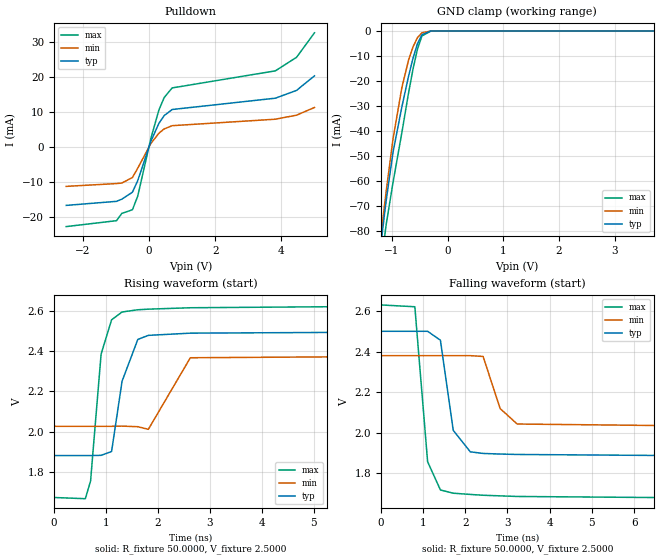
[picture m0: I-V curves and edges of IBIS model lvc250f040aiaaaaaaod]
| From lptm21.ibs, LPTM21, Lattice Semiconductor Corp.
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|   Model lvc250f040aiaaaaaaod
[Model]   lvc250f040aiaaaaaaod
Model_type   I/O_open_drain
Polarity   Non-Inverting
Enable   Active-Low
Vinl =   0.7000V
Vinh =   1.7000V
Vmeas =   1.2500V
Cref =   0.0F
Rref =   1.0000M
Vref =   0.0V
C_comp   4.2000pF   3.8000pF   7.5000pF
[Temperature Range]   25.0000   0.1050k   -40.0000
[Voltage Range]   2.5000V   2.3800V   2.6300V
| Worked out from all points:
|   slope of the pulldown table from 0 to 0.375 V, typ, clamps not added: 47.9 ohm
|   GND clamp passes 1 mA (typ) near -0.44 V on its own axis
|   rising waveform, R_fixture 50.0000, V_fixture 2.5000: 20-80 % time 238ps typ, 266ps min, 220ps max; typ from 1.88 V to 2.5 V
|   falling waveform, R_fixture 50.0000, V_fixture 2.5000: 20-80 % time 260ps typ, 315ps min, 219ps max; typ from 2.5 V to 1.88 V
[Pulldown]
|Voltage   I(typ)   I(min)   I(max)
-2.5V     -16.76mA   -11.33mA   -22.81mA
-980mV    -15.6mA    -10.53mA   -21.12mA
-820mV    -14.98mA   -10.38mA   -19.03mA
-500mV    -13mA      -8.8mA     -18.01mA
-340mV    -9.694mA   -6.145mA   -14.13mA
60mV      1.602mA    944.5uA    2.476mA
300mV     6.67mA     3.859mA    10.47mA
460mV     8.873mA    5.068mA    14.03mA
700mV     10.61mA    5.993mA    16.77mA
3.82V     13.84mA    7.842mA    21.65mA
4.46V     16.07mA    8.997mA    25.52mA
5V        20.22mA    11.19mA    32.5mA
[GND_clamp]
|Voltage   I(typ)   I(min)   I(max)
-2.5V     -564.7mA   -543mA     -585.2mA
-1.18V    -82.33mA   -78.99mA   -91.13mA
-1.14V    -74.86mA   -71.35mA   -83.95mA
-1.1V     -67.68mA   -63.91mA   -77.24mA
-980mV    -48.65mA   -43.35mA   -60.78mA
-820mV    -30.34mA   -22.64mA   -40.65mA
-700mV    -18.08mA   -11.62mA   -24.78mA
-620mV    -10.86mA   -6.331mA   -15.22mA
-540mV    -5.056mA   -2.651mA   -7.221mA
-460mV    -1.444mA   -713.5uA   -1.976mA
-300mV    -18.62uA   -15.88uA   -16.41uA
5V        0A         0A         0A
[Ramp]
| variable   typ   min   max
dV/dt_r  0.3702/0.2352n   0.2111/0.2638n   0.5678/3.9666n
dV/dt_f  0.3702/0.2572n   0.2111/0.3124n   0.5731/0.2171n
R_load = 50.0000
[Rising Waveform]
R_fixture=   50.0000
V_fixture=   2.5000
V_fixture_min=   2.3800
V_fixture_max=   2.6300
|time   V(typ)   V(min)   V(max)
0s        1.882V     2.027V     1.674V
606.1ps   1.882V     2.027V     1.668V
707.1ps   1.882V     2.027V     1.756V
909.1ps   1.883V     2.027V     2.385V
1.111ns   1.902V     2.027V     2.555V
1.313ns   2.251V     2.028V     2.594V
1.616ns   2.458V     2.025V     2.605V
1.818ns   2.478V     2.012V     2.608V
2.626ns   2.489V     2.367V     2.615V
10ns      2.499V     2.379V     2.629V
[Falling Waveform]
R_fixture=   50.0000
V_fixture=   2.5000
V_fixture_min=   2.3800
V_fixture_max=   2.6300
|time   V(typ)   V(min)   V(max)
0s        2.5V       2.38V      2.63V
808.1ps   2.5V       2.38V      2.621V
1.111ns   2.5V       2.38V      1.857V
1.414ns   2.456V     2.38V      1.718V
1.717ns   2.012V     2.38V      1.702V
2.121ns   1.906V     2.38V      1.696V
2.424ns   1.898V     2.376V     1.692V
2.828ns   1.895V     2.119V     1.689V
3.232ns   1.893V     2.043V     1.686V
10ns      1.883V     2.028V     1.675V
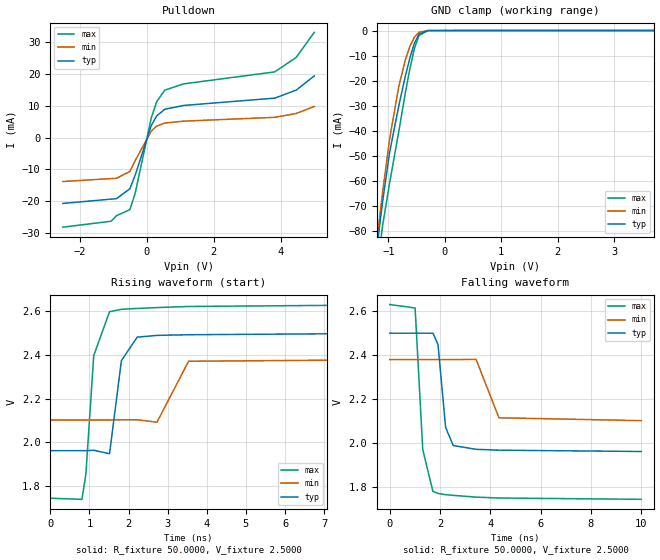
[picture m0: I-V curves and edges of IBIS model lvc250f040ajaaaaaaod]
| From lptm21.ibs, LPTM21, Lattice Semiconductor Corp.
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|   Model lvc250f040ajaaaaaaod
[Model]   lvc250f040ajaaaaaaod
Model_type   I/O_open_drain
Polarity   Non-Inverting
Enable   Active-Low
Vinl =   0.7000V
Vinh =   1.7000V
Vmeas =   1.2500V
Cref =   0.0F
Rref =   1.0000M
Vref =   0.0V
C_comp   4.2000pF   3.8000pF   7.5000pF
[Temperature Range]   25.0000   0.1050k   -40.0000
[Voltage Range]   2.5000V   2.3800V   2.6300V
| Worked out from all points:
|   slope of the pulldown table from 0 to 0.375 V, typ, clamps not added: 48.6 ohm
|   GND clamp passes 1 mA (typ) near -0.44 V on its own axis
|   rising waveform, R_fixture 50.0000, V_fixture 2.5000: 20-80 % time 235ps typ, 281ps min, 229ps max; typ from 1.96 V to 2.5 V
|   falling waveform, R_fixture 50.0000, V_fixture 2.5000: 20-80 % time 269ps typ, 362ps min, 235ps max; typ from 2.5 V to 1.96 V
[Pulldown]
|Voltage   I(typ)   I(min)   I(max)
-2.5V     -20.72mA   -13.83mA   -28.17mA
-1.06V    -19.36mA   -12.91mA   -26.31mA
-900mV    -19.23mA   -12.81mA   -24.57mA
-500mV    -16.11mA   -10.65mA   -22.67mA
-340mV    -11.74mA   -7.229mA   -17.41mA
140mV     3.82mA     2.075mA    6.237mA
300mV     6.792mA    3.593mA    11.27mA
540mV     8.87mA     4.559mA    14.88mA
1.1V      10.07mA    5.137mA    16.85mA
3.82V     12.37mA    6.341mA    20.62mA
4.46V     14.88mA    7.553mA    25.17mA
5V        19.36mA    9.749mA    33.05mA
[GND_clamp]
|Voltage   I(typ)   I(min)   I(max)
-2.5V     -564.7mA   -543mA     -585.2mA
-1.18V    -82.26mA   -78.93mA   -91.11mA
-1.14V    -74.8mA    -71.29mA   -83.93mA
-1.1V     -67.62mA   -63.85mA   -77.23mA
-980mV    -48.61mA   -43.3mA    -60.78mA
-820mV    -30.33mA   -22.62mA   -40.64mA
-700mV    -18.08mA   -11.62mA   -24.78mA
-620mV    -10.86mA   -6.33mA    -15.22mA
-540mV    -5.055mA   -2.65mA    -7.219mA
-460mV    -1.443mA   -713.2uA   -1.975mA
-300mV    -18.6uA    -15.87uA   -16.37uA
5V        0A         0A         0A
[Ramp]
| variable   typ   min   max
dV/dt_r  0.3223/0.2322n   0.1661/0.2782n   0.5303/0.2264n
dV/dt_f  0.3223/0.2666n   0.1660/0.3587n   0.5302/0.2323n
R_load = 50.0000
[Rising Waveform]
R_fixture=   50.0000
V_fixture=   2.5000
V_fixture_min=   2.3800
V_fixture_max=   2.6300
|time   V(typ)   V(min)   V(max)
0s        1.962V     2.102V     1.745V
808.1ps   1.962V     2.102V     1.74V
909.1ps   1.962V     2.102V     1.853V
1.111ns   1.964V     2.102V     2.396V
1.515ns   1.948V     2.102V     2.596V
1.818ns   2.373V     2.103V     2.607V
2.222ns   2.48V      2.103V     2.611V
2.727ns   2.488V     2.092V     2.615V
3.535ns   2.491V     2.37V      2.62V
10ns      2.499V     2.379V     2.629V
[Falling Waveform]
R_fixture=   50.0000
V_fixture=   2.5000
V_fixture_min=   2.3800
V_fixture_max=   2.6300
|time   V(typ)   V(min)   V(max)
0s        2.5V       2.38V      2.63V
1.01ns    2.5V       2.38V      2.614V
1.313ns   2.5V       2.38V      1.972V
1.717ns   2.5V       2.38V      1.782V
1.919ns   2.449V     2.38V      1.773V
2.222ns   2.073V     2.38V      1.767V
2.525ns   1.99V      2.38V      1.764V
3.434ns   1.973V     2.381V     1.756V
4.343ns   1.969V     2.116V     1.752V
10ns      1.963V     2.103V     1.746V
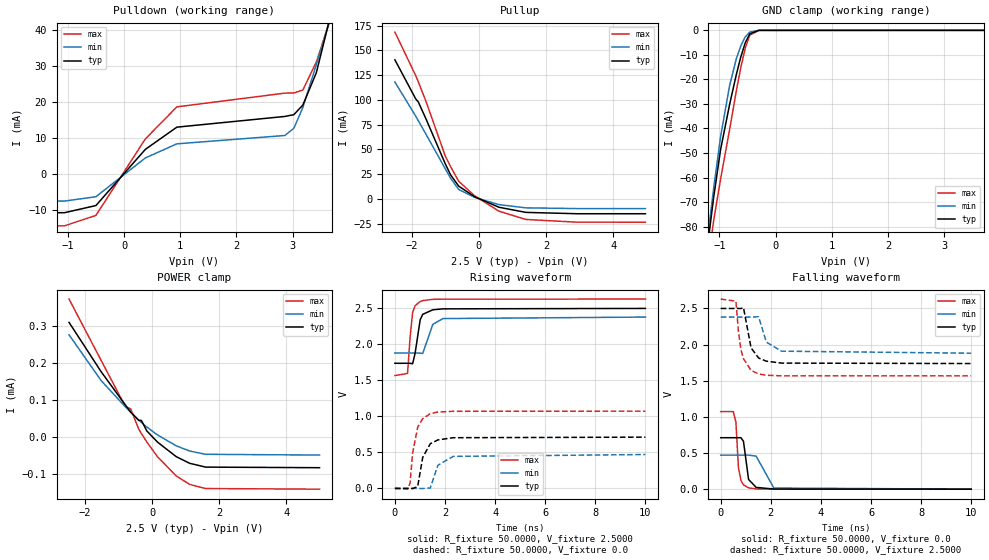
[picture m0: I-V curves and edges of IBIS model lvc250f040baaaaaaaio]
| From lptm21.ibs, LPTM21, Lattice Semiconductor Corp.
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|   Model lvc250f040baaaaaaaio
[Model]   lvc250f040baaaaaaaio
Model_type   I/O
Polarity   Non-Inverting
Enable   Active-Low
Vinl =   0.7000V
Vinh =   1.7000V
Vmeas =   1.2500V
Cref =   0.0F
Rref =   1.0000M
Vref =   0.0V
C_comp   4.2000pF   3.8000pF   7.5000pF
[Temperature Range]   25.0000   0.1050k   -40.0000
[Voltage Range]   2.5000V   2.3800V   2.6300V
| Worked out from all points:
|   slope of the pulldown table from 0 to 0.375 V, typ, clamps not added: 56 ohm
|   slope of the pullup table from 0 to 0.375 V, typ, clamps not added: 65.6 ohm
|   GND clamp passes 1 mA (typ) near -0.44 V on its own axis
|   rising waveform, R_fixture 50.0000, V_fixture 2.5000: 20-80 % time 205ps typ, 280ps min, 158ps max; typ from 1.74 V to 2.5 V
|   rising waveform, R_fixture 50.0000, V_fixture 0.0: 20-80 % time 322ps typ, 342ps min, 281ps max; typ from 0 V to 0.712 V
|   falling waveform, R_fixture 50.0000, V_fixture 0.0: 20-80 % time 170ps typ, 241ps min, 137ps max; typ from 0.712 V to 0 V
|   falling waveform, R_fixture 50.0000, V_fixture 2.5000: 20-80 % time 299ps typ, 318ps min, 290ps max; typ from 2.5 V to 1.74 V
[Pulldown]
|Voltage   I(typ)   I(min)   I(max)
-2.5V     -10.78mA   -7.545mA   -14.44mA
-1.06V    -10.78mA   -7.545mA   -14.44mA
-500mV    -8.787mA   -6.331mA   -11.53mA
380mV     6.858mA    4.468mA    9.767mA
940mV     13.03mA    8.389mA    18.67mA
2.86V     16.01mA    10.71mA    22.5mA
3.02V     16.5mA     12.71mA    22.54mA
3.18V     19.18mA    18.49mA    23.36mA
3.42V     28.18mA    30.42mA    31.16mA
3.66V     43.28mA    42.78mA    42.65mA
4.3V      84.42mA    75.07mA    94.89mA
5V        122mA      106.6mA    138.6mA
[Pullup]
|Voltage   I(typ)   I(min)   I(max)
-2.5V     140.4mA    118mA      168.4mA
-1.88V    101mA      83.57mA    124.5mA
-1.8V     97.75mA    78.84mA    118.1mA
-1.56V    79.68mA    64.46mA    97.19mA
-1V       35.47mA    30.43mA    43.33mA
-840mV    24.26mA    20.87mA    32.53mA
-600mV    12.95mA    9.645mA    17.83mA
-120mV    2.127mA    1.486mA    3.048mA
600mV     -8.404mA   -5.738mA   -12.36mA
1.4V      -13.57mA   -8.996mA   -20.71mA
2.92V     -14.93mA   -9.729mA   -23.45mA
4.96V     -14.93mA   -9.729mA   -23.47mA
[GND_clamp]
|Voltage   I(typ)   I(min)   I(max)
-2.5V     -564.6mA   -543.1mA   -585.1mA
-1.18V    -82.28mA   -79mA      -91.03mA
-1.14V    -74.81mA   -71.35mA   -83.85mA
-1.1V     -67.63mA   -63.91mA   -77.15mA
-980mV    -48.6mA    -43.33mA   -60.69mA
-820mV    -30.29mA   -22.62mA   -40.55mA
-700mV    -18.04mA   -11.6mA    -24.7mA
-620mV    -10.82mA   -6.314mA   -15.14mA
-540mV    -5.025mA   -2.64mA    -7.154mA
-460mV    -1.426mA   -708.3uA   -1.934mA
-300mV    -17.76uA   -15.73uA   -12.8uA
5V        0A         0A         0A
[POWER_clamp]
|Voltage   I(typ)   I(min)   I(max)
-2.48V    310.4uA    276.7uA    373.7uA
-1.52V    176.3uA    152.3uA    206.9uA
-800mV    86.61uA    81.35uA    82.18uA
-640mV    66.94uA    66.91uA    75.79uA
-400mV    44.51uA    45.44uA    20.86uA
-320mV    44.51uA    38.99uA    8.918uA
-160mV    16.15uA    26.85uA    -13.85uA
160mV     -14.29uA   5.152uA    -53.97uA
720mV     -53.87uA   -24.56uA   -106.2uA
1.12V     -71.9uA    -38.53uA   -129.1uA
1.6V      -82.26uA   -47.53uA   -140.4uA
5V        -83.86uA   -49.55uA   -142.1uA
[Ramp]
| variable   typ   min   max
dV/dt_r  0.4167/0.3190n   0.2824/0.3383n   0.6437/0.2781n
dV/dt_f  0.4573/0.2964n   0.2995/0.3146n   0.6376/0.2875n
R_load = 50.0000
[Rising Waveform]
R_fixture=   50.0000
V_fixture=   2.5000
V_fixture_min=   2.3800
V_fixture_max=   2.6300
|time   V(typ)   V(min)   V(max)
0s        1.738V     1.881V     1.567V
505.1ps   1.738V     1.881V     1.597V
606.1ps   1.738V     1.881V     2.097V
707.1ps   1.731V     1.881V     2.442V
808.1ps   1.879V     1.881V     2.538V
1.01ns    2.342V     1.879V     2.596V
1.111ns   2.418V     1.874V     2.608V
1.515ns   2.481V     2.279V     2.626V
1.919ns   2.494V     2.359V     2.629V
10ns      2.5V       2.38V      2.63V
[Rising Waveform]
R_fixture=   50.0000
V_fixture=   0.0
V_fixture_min=   0.0
V_fixture_max=   0.0
|time   V(typ)   V(min)   V(max)
0s        1.018uV    1.278uV    887.5nV
505.1ps   26.57uV    1.795uV    -10.73mV
606.1ps   32.77uV    1.331uV    73.72mV
707.1ps   -2.104mV   7.854uV    487.2mV
909.1ps   24mV       80.3uV     849.4mV
1.111ns   431mV      -2.166mV   969.3mV
1.414ns   620.8mV    5.681mV    1.038V
1.717ns   673.4mV    320.9mV    1.061V
2.323ns   704.1mV    444.3mV    1.071V
10ns      711.8mV    470.7mV    1.073V
[Falling Waveform]
R_fixture=   50.0000
V_fixture=   0.0
V_fixture_min=   0.0
V_fixture_max=   0.0
|time   V(typ)   V(min)   V(max)
0s        711.8mV    470.7mV    1.073V
505.1ps   711.8mV    470.7mV    1.073V
606.1ps   711.7mV    470.7mV    927.3mV
707.1ps   712mV      470.7mV    299mV
808.1ps   712.2mV    470.7mV    119.8mV
909.1ps   660.6mV    470.7mV    59.46mV
1.111ns   135.5mV    470.7mV    18.42mV
1.414ns   24.17mV    457mV      3.819mV
2.121ns   2.008mV    15.67mV    186.1uV
10ns      12.23uV    2.006uV    9.145uV
[Falling Waveform]
R_fixture=   50.0000
V_fixture=   2.5000
V_fixture_min=   2.3800
V_fixture_max=   2.6300
|time   V(typ)   V(min)   V(max)
0s        2.5V       2.38V      2.63V
606.1ps   2.5V       2.38V      2.601V
707.1ps   2.5V       2.38V      2.18V
808.1ps   2.499V     2.38V      1.926V
909.1ps   2.511V     2.38V      1.804V
1.212ns   1.954V     2.381V     1.643V
1.515ns   1.814V     2.385V     1.593V
1.818ns   1.771V     2.036V     1.576V
2.424ns   1.744V     1.909V     1.568V
10ns      1.738V     1.881V     1.567V
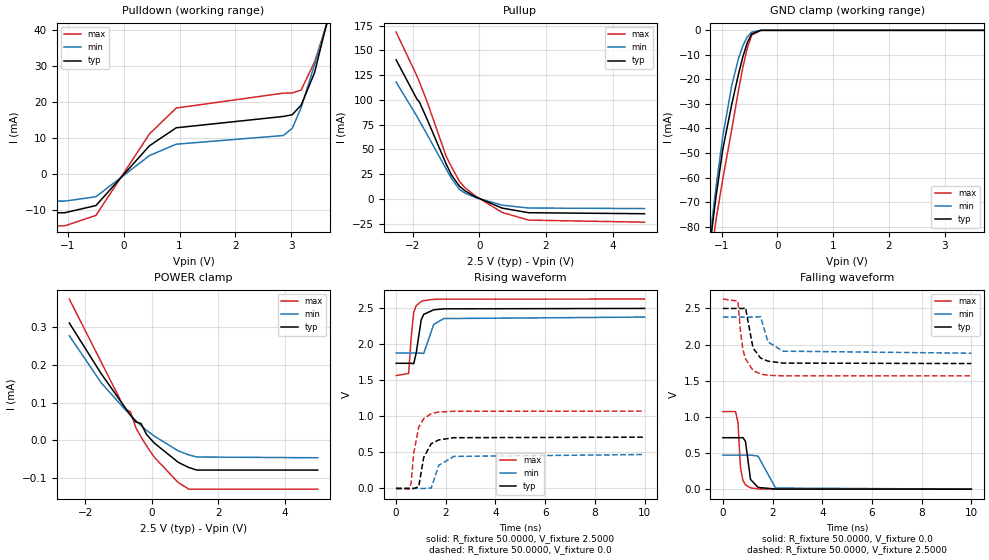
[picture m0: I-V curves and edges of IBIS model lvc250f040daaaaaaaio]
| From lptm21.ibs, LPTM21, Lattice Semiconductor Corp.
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|   Model lvc250f040daaaaaaaio
[Model]   lvc250f040daaaaaaaio
Model_type   I/O
Polarity   Non-Inverting
Enable   Active-Low
Vinl =   0.7000V
Vinh =   1.7000V
Vmeas =   1.2500V
Cref =   0.0F
Rref =   1.0000M
Vref =   0.0V
C_comp   4.2000pF   3.8000pF   7.5000pF
[Temperature Range]   25.0000   0.1050k   -40.0000
[Voltage Range]   2.5000V   2.3800V   2.6300V
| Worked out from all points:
|   slope of the pulldown table from 0 to 0.375 V, typ, clamps not added: 56.5 ohm
|   slope of the pullup table from 0 to 0.375 V, typ, clamps not added: 65.6 ohm
|   GND clamp passes 1 mA (typ) near -0.44 V on its own axis
|   rising waveform, R_fixture 50.0000, V_fixture 2.5000: 20-80 % time 205ps typ, 280ps min, 158ps max; typ from 1.74 V to 2.5 V
|   rising waveform, R_fixture 50.0000, V_fixture 0.0: 20-80 % time 322ps typ, 342ps min, 281ps max; typ from 0 V to 0.712 V
|   falling waveform, R_fixture 50.0000, V_fixture 0.0: 20-80 % time 170ps typ, 241ps min, 137ps max; typ from 0.712 V to 0 V
|   falling waveform, R_fixture 50.0000, V_fixture 2.5000: 20-80 % time 299ps typ, 318ps min, 290ps max; typ from 2.5 V to 1.74 V
[Pulldown]
|Voltage   I(typ)   I(min)   I(max)
-2.5V     -10.78mA   -7.54mA    -14.43mA
-1.06V    -10.78mA   -7.54mA    -14.43mA
-500mV    -8.777mA   -6.322mA   -11.52mA
460mV     7.865mA    5.129mA    11.16mA
940mV     12.86mA    8.296mA    18.35mA
2.86V     16.01mA    10.71mA    22.5mA
3.02V     16.5mA     12.71mA    22.54mA
3.18V     19.18mA    18.49mA    23.36mA
3.42V     28.18mA    30.42mA    31.16mA
3.66V     43.28mA    42.78mA    42.65mA
4.3V      84.42mA    75.07mA    94.89mA
5V        122mA      106.6mA    138.6mA
[Pullup]
|Voltage   I(typ)   I(min)   I(max)
-2.5V     140.4mA    118mA      168.4mA
-1.88V    101mA      83.57mA    124.5mA
-1.8V     97.75mA    78.84mA    118.1mA
-1.56V    79.68mA    64.46mA    97.19mA
-1V       35.47mA    30.43mA    43.33mA
-840mV    24.26mA    20.87mA    32.53mA
-600mV    12.95mA    9.645mA    17.83mA
-440mV    8.387mA    6.028mA    11.57mA
-120mV    2.127mA    1.486mA    3.048mA
680mV     -9.225mA   -6.284mA   -13.6mA
1.48V     -13.92mA   -9.177mA   -21.37mA
4.96V     -14.94mA   -9.733mA   -23.48mA
[GND_clamp]
|Voltage   I(typ)   I(min)   I(max)
-2.5V     -564.6mA   -543.1mA   -585.1mA
-1.18V    -82.29mA   -79mA      -91.05mA
-1.14V    -74.82mA   -71.35mA   -83.87mA
-1.1V     -67.64mA   -63.91mA   -77.16mA
-980mV    -48.61mA   -43.34mA   -60.71mA
-820mV    -30.3mA    -22.63mA   -40.57mA
-700mV    -18.05mA   -11.61mA   -24.72mA
-620mV    -10.84mA   -6.326mA   -15.16mA
-540mV    -5.04mA    -2.652mA   -7.178mA
-460mV    -1.44mA    -719uA     -1.958mA
-300mV    -9.986uA   -9.27uA    -5.3uA
5V        0A         0A         0A
[POWER_clamp]
|Voltage   I(typ)   I(min)   I(max)
-2.48V    310.4uA    276.7uA    373.7uA
-1.52V    176.3uA    152.3uA    206.9uA
-800mV    86.61uA    81.35uA    82.18uA
-640mV    66.94uA    66.91uA    75.79uA
-480mV    48.86uA    52.22uA    34.01uA
-320mV    44.51uA    38.99uA    8.918uA
-160mV    16.15uA    26.85uA    -13.85uA
80mV      -7.284uA   11.17uA    -44.64uA
800mV     -58.16uA   -27.83uA   -111.7uA
1.12V     -71.9uA    -38.53uA   -129.1uA
1.36V     -78.59uA   -44.07uA   -129.1uA
5V        -78.59uA   -46.05uA   -129.1uA
[Ramp]
| variable   typ   min   max
dV/dt_r  0.4167/0.3190n   0.2824/0.3383n   0.6437/0.2781n
dV/dt_f  0.4573/0.2964n   0.2995/0.3146n   0.6376/0.2875n
R_load = 50.0000
[Rising Waveform]
R_fixture=   50.0000
V_fixture=   2.5000
V_fixture_min=   2.3800
V_fixture_max=   2.6300
|time   V(typ)   V(min)   V(max)
0s        1.738V     1.881V     1.567V
505.1ps   1.738V     1.881V     1.597V
606.1ps   1.738V     1.881V     2.097V
707.1ps   1.731V     1.881V     2.442V
808.1ps   1.879V     1.881V     2.538V
1.01ns    2.342V     1.879V     2.596V
1.111ns   2.418V     1.874V     2.608V
1.515ns   2.481V     2.279V     2.626V
1.919ns   2.494V     2.359V     2.629V
10ns      2.5V       2.38V      2.63V
[Rising Waveform]
R_fixture=   50.0000
V_fixture=   0.0
V_fixture_min=   0.0
V_fixture_max=   0.0
|time   V(typ)   V(min)   V(max)
0s        1.018uV    1.278uV    887.5nV
505.1ps   26.57uV    1.795uV    -10.73mV
606.1ps   32.77uV    1.331uV    73.72mV
707.1ps   -2.104mV   7.854uV    487.2mV
909.1ps   24mV       80.3uV     849.4mV
1.111ns   431mV      -2.166mV   969.3mV
1.414ns   620.8mV    5.681mV    1.038V
1.717ns   673.4mV    320.9mV    1.061V
2.323ns   704.1mV    444.3mV    1.071V
10ns      711.8mV    470.7mV    1.073V
[Falling Waveform]
R_fixture=   50.0000
V_fixture=   0.0
V_fixture_min=   0.0
V_fixture_max=   0.0
|time   V(typ)   V(min)   V(max)
0s        711.8mV    470.7mV    1.073V
505.1ps   711.8mV    470.7mV    1.073V
606.1ps   711.7mV    470.7mV    927.3mV
707.1ps   712mV      470.7mV    299mV
808.1ps   712.2mV    470.7mV    119.8mV
909.1ps   660.6mV    470.7mV    59.46mV
1.111ns   135.5mV    470.7mV    18.42mV
1.414ns   24.17mV    457mV      3.819mV
2.121ns   2.008mV    15.67mV    186.1uV
10ns      12.23uV    2.006uV    9.145uV
[Falling Waveform]
R_fixture=   50.0000
V_fixture=   2.5000
V_fixture_min=   2.3800
V_fixture_max=   2.6300
|time   V(typ)   V(min)   V(max)
0s        2.5V       2.38V      2.63V
606.1ps   2.5V       2.38V      2.601V
707.1ps   2.5V       2.38V      2.18V
808.1ps   2.499V     2.38V      1.926V
909.1ps   2.511V     2.38V      1.804V
1.212ns   1.954V     2.381V     1.643V
1.515ns   1.814V     2.385V     1.593V
1.818ns   1.771V     2.036V     1.576V
2.424ns   1.744V     1.909V     1.568V
10ns      1.738V     1.881V     1.567V
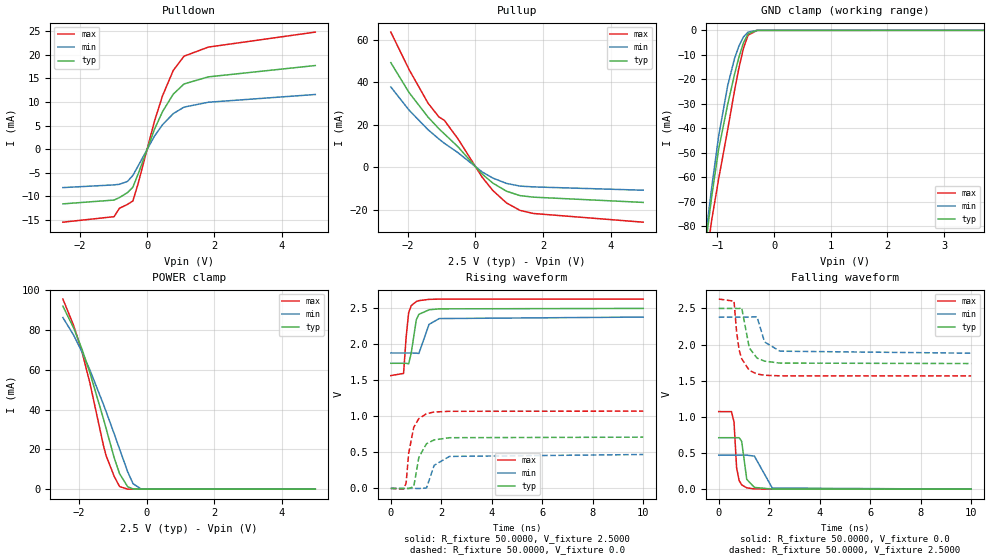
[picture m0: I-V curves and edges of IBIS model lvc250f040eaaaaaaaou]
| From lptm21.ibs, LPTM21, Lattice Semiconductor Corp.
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|   Model lvc250f040eaaaaaaaou
[Model]   lvc250f040eaaaaaaaou
Model_type   Output
Polarity   Non-Inverting
Enable   Active-Low
Vmeas =   1.2500V
Cref =   0.0F
Rref =   1.0000M
Vref =   0.0V
C_comp   4.2000pF   3.8000pF   7.5000pF
[Temperature Range]   25.0000   0.1050k   -40.0000
[Voltage Range]   2.5000V   2.3800V   2.6300V
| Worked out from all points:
|   slope of the pulldown table from 0 to 0.375 V, typ, clamps not added: 56 ohm
|   slope of the pullup table from 0 to 0.375 V, typ, clamps not added: 65.3 ohm
|   GND clamp passes 1 mA (typ) near -0.44 V on its own axis
|   POWER clamp passes 1 mA (typ) near -0.54 V on its own axis
|   rising waveform, R_fixture 50.0000, V_fixture 2.5000: 20-80 % time 205ps typ, 280ps min, 158ps max; typ from 1.74 V to 2.5 V
|   rising waveform, R_fixture 50.0000, V_fixture 0.0: 20-80 % time 322ps typ, 342ps min, 281ps max; typ from 0 V to 0.712 V
|   falling waveform, R_fixture 50.0000, V_fixture 0.0: 20-80 % time 170ps typ, 241ps min, 137ps max; typ from 0.712 V to 0 V
|   falling waveform, R_fixture 50.0000, V_fixture 2.5000: 20-80 % time 299ps typ, 318ps min, 290ps max; typ from 2.5 V to 1.74 V
[Pulldown]
|Voltage   I(typ)   I(min)   I(max)
-2.5V     -11.64mA   -8.183mA   -15.53mA
-980mV    -10.83mA   -7.609mA   -14.36mA
-820mV    -10.3mA    -7.483mA   -12.57mA
-580mV    -9.233mA   -6.865mA   -11.75mA
-420mV    -8.084mA   -5.596mA   -11.02mA
-260mV    -5.215mA   -3.517mA   -7.219mA
220mV     4.174mA    2.735mA    5.905mA
460mV     7.938mA    5.165mA    11.3mA
780mV     11.67mA    7.531mA    16.71mA
1.1V      13.83mA    8.908mA    19.72mA
1.82V     15.33mA    9.94mA     21.65mA
5V        17.74mA    11.59mA    24.84mA
[Pullup]
|Voltage   I(typ)   I(min)   I(max)
-2.5V     49.36mA    37.89mA    63.8mA
-1.96V    35.24mA    26.93mA    46.11mA
-1.4V     23.66mA    17.71mA    30.24mA
-1.08V    18.19mA    13.33mA    23.77mA
-920mV    15.77mA    11.32mA    22.16mA
-520mV    9.714mA    6.924mA    13.53mA
200mV     -3.264mA   -2.251mA   -4.739mA
520mV     -7.556mA   -5.168mA   -11.08mA
920mV     -11.34mA   -7.66mA    -16.89mA
1.32V     -13.43mA   -8.924mA   -20.4mA
1.72V     -14.15mA   -9.307mA   -21.87mA
4.96V     -16.63mA   -10.87mA   -25.97mA
[GND_clamp]
|Voltage   I(typ)   I(min)   I(max)
-2.5V     -564.7mA   -543.1mA   -585.2mA
-1.18V    -82.35mA   -79.03mA   -91.15mA
-1.14V    -74.88mA   -71.38mA   -83.96mA
-1.1V     -67.69mA   -63.94mA   -77.25mA
-980mV    -48.66mA   -43.36mA   -60.79mA
-820mV    -30.34mA   -22.65mA   -40.66mA
-700mV    -18.09mA   -11.63mA   -24.79mA
-620mV    -10.87mA   -6.335mA   -15.23mA
-540mV    -5.061mA   -2.654mA   -7.227mA
-460mV    -1.446mA   -714.8uA   -1.98mA
-300mV    -18.71uA   -15.93uA   -16.53uA
5V        0A         0A         0A
[POWER_clamp]
|Voltage   I(typ)   I(min)   I(max)
-2.48V    91.96mA    86.23mA    95.54mA
-2.16V    80.94mA    77.35mA    82.15mA
-1.92V    70.61mA    69.17mA    69.43mA
-1.68V    58.52mA    59.9mA     53.37mA
-1.28V    35.44mA    42.67mA    22.07mA
-1.2V     30.53mA    39.03mA    16.84mA
-960mV    15.8mA     27.82mA    6.447mA
-800mV    7.76mA     20.14mA    1.303mA
-560mV    1.23mA     8.728mA    11.53uA
-400mV    83.98uA    2.726mA    532.6nA
-160mV    776.1nA    102uA      144nA
5V        -44.09nA   -38.33nA   -118.7nA
[Ramp]
| variable   typ   min   max
dV/dt_r  0.4167/0.3190n   0.2824/0.3383n   0.6437/0.2781n
dV/dt_f  0.4573/0.2964n   0.2995/0.3146n   0.6376/0.2875n
R_load = 50.0000
[Rising Waveform]
R_fixture=   50.0000
V_fixture=   2.5000
V_fixture_min=   2.3800
V_fixture_max=   2.6300
|time   V(typ)   V(min)   V(max)
0s        1.738V     1.881V     1.567V
505.1ps   1.738V     1.881V     1.597V
606.1ps   1.738V     1.881V     2.097V
707.1ps   1.731V     1.881V     2.442V
808.1ps   1.879V     1.881V     2.538V
1.01ns    2.342V     1.879V     2.596V
1.111ns   2.418V     1.874V     2.608V
1.515ns   2.481V     2.279V     2.626V
1.919ns   2.494V     2.359V     2.629V
10ns      2.5V       2.38V      2.63V
[Rising Waveform]
R_fixture=   50.0000
V_fixture=   0.0
V_fixture_min=   0.0
V_fixture_max=   0.0
|time   V(typ)   V(min)   V(max)
0s        1.018uV    1.278uV    887.5nV
505.1ps   26.57uV    1.795uV    -10.73mV
606.1ps   32.77uV    1.331uV    73.72mV
707.1ps   -2.104mV   7.854uV    487.2mV
909.1ps   24mV       80.3uV     849.4mV
1.111ns   431mV      -2.166mV   969.3mV
1.414ns   620.8mV    5.681mV    1.038V
1.717ns   673.4mV    320.9mV    1.061V
2.323ns   704.1mV    444.3mV    1.071V
10ns      711.8mV    470.7mV    1.073V
[Falling Waveform]
R_fixture=   50.0000
V_fixture=   0.0
V_fixture_min=   0.0
V_fixture_max=   0.0
|time   V(typ)   V(min)   V(max)
0s        711.8mV    470.7mV    1.073V
505.1ps   711.8mV    470.7mV    1.073V
606.1ps   711.7mV    470.7mV    927.3mV
707.1ps   712mV      470.7mV    299mV
808.1ps   712.2mV    470.7mV    119.8mV
909.1ps   660.6mV    470.7mV    59.46mV
1.111ns   135.5mV    470.7mV    18.42mV
1.414ns   24.17mV    457mV      3.819mV
2.121ns   2.008mV    15.67mV    186.1uV
10ns      12.23uV    2.006uV    9.145uV
[Falling Waveform]
R_fixture=   50.0000
V_fixture=   2.5000
V_fixture_min=   2.3800
V_fixture_max=   2.6300
|time   V(typ)   V(min)   V(max)
0s        2.5V       2.38V      2.63V
606.1ps   2.5V       2.38V      2.601V
707.1ps   2.5V       2.38V      2.18V
808.1ps   2.499V     2.38V      1.926V
909.1ps   2.511V     2.38V      1.804V
1.212ns   1.954V     2.381V     1.643V
1.515ns   1.814V     2.385V     1.593V
1.818ns   1.771V     2.036V     1.576V
2.424ns   1.744V     1.909V     1.568V
10ns      1.738V     1.881V     1.567V
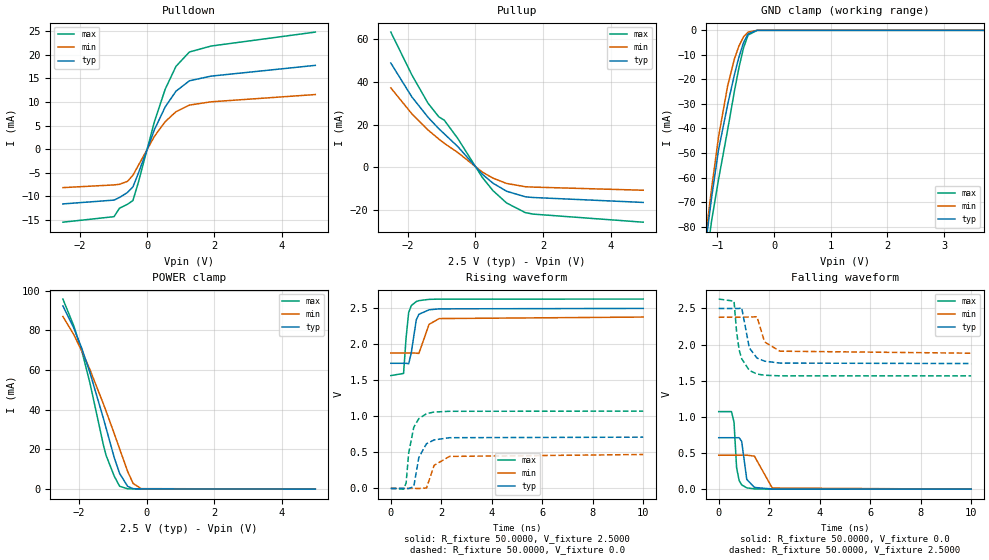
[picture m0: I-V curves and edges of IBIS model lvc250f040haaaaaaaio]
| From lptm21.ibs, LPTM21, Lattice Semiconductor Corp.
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|   Model lvc250f040haaaaaaaio
[Model]   lvc250f040haaaaaaaio
Model_type   I/O
Polarity   Non-Inverting
Enable   Active-Low
Vinl =   0.7000V
Vinh =   1.7000V
Vmeas =   1.2500V
Cref =   0.0F
Rref =   1.0000M
Vref =   0.0V
C_comp   4.2000pF   3.8000pF   7.5000pF
[Temperature Range]   25.0000   0.1050k   -40.0000
[Voltage Range]   2.5000V   2.3800V   2.6300V
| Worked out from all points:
|   slope of the pulldown table from 0 to 0.375 V, typ, clamps not added: 56.5 ohm
|   slope of the pullup table from 0 to 0.375 V, typ, clamps not added: 65.6 ohm
|   GND clamp passes 1 mA (typ) near -0.44 V on its own axis
|   POWER clamp passes 1 mA (typ) near -0.54 V on its own axis
|   rising waveform, R_fixture 50.0000, V_fixture 2.5000: 20-80 % time 205ps typ, 280ps min, 158ps max; typ from 1.74 V to 2.5 V
|   rising waveform, R_fixture 50.0000, V_fixture 0.0: 20-80 % time 322ps typ, 342ps min, 281ps max; typ from 0 V to 0.712 V
|   falling waveform, R_fixture 50.0000, V_fixture 0.0: 20-80 % time 170ps typ, 241ps min, 137ps max; typ from 0.712 V to 0 V
|   falling waveform, R_fixture 50.0000, V_fixture 2.5000: 20-80 % time 299ps typ, 318ps min, 290ps max; typ from 2.5 V to 1.74 V
[Pulldown]
|Voltage   I(typ)   I(min)   I(max)
-2.5V     -11.61mA   -8.157mA   -15.48mA
-980mV    -10.8mA    -7.585mA   -14.31mA
-820mV    -10.26mA   -7.457mA   -12.52mA
-580mV    -9.181mA   -6.825mA   -11.68mA
-420mV    -8.006mA   -5.545mA   -10.9mA
-260mV    -5.154mA   -3.483mA   -7.112mA
220mV     4.131mA    2.713mA    5.825mA
540mV     8.932mA    5.81mA     12.7mA
860mV     12.27mA    7.923mA    17.53mA
1.26V     14.47mA    9.329mA    20.58mA
1.9V      15.46mA    10.02mA    21.83mA
5V        17.74mA    11.56mA    24.79mA
[Pullup]
|Voltage   I(typ)   I(min)   I(max)
-2.5V     48.92mA    37.25mA    63.47mA
-1.88V    33.06mA    25.13mA    43.41mA
-1.4V     23.45mA    17.5mA     30.05mA
-1.08V    18.06mA    13.2mA     23.64mA
-920mV    15.68mA    11.23mA    22.09mA
-520mV    9.678mA    6.897mA    13.48mA
200mV     -3.246mA   -2.24mA    -4.711mA
520mV     -7.513mA   -5.141mA   -11.02mA
920mV     -11.28mA   -7.62mA    -16.79mA
1.48V     -13.92mA   -9.177mA   -21.37mA
1.72V     -14.24mA   -9.349mA   -22.05mA
4.96V     -16.55mA   -10.82mA   -25.83mA
[GND_clamp]
|Voltage   I(typ)   I(min)   I(max)
-2.5V     -564.6mA   -543.1mA   -585.1mA
-1.18V    -82.29mA   -79mA      -91.05mA
-1.14V    -74.82mA   -71.35mA   -83.87mA
-1.1V     -67.64mA   -63.91mA   -77.16mA
-980mV    -48.61mA   -43.34mA   -60.71mA
-820mV    -30.3mA    -22.63mA   -40.57mA
-700mV    -18.05mA   -11.61mA   -24.72mA
-620mV    -10.84mA   -6.326mA   -15.16mA
-540mV    -5.04mA    -2.652mA   -7.178mA
-460mV    -1.44mA    -719uA     -1.958mA
-300mV    -9.986uA   -9.27uA    -5.3uA
5V        0A         0A         0A
[POWER_clamp]
|Voltage   I(typ)   I(min)   I(max)
-2.48V    92.38mA    87.03mA    95.82mA
-2.16V    81.29mA    77.94mA    82.39mA
-1.92V    70.92mA    69.63mA    69.65mA
-1.68V    58.78mA    60.26mA    53.56mA
-1.28V    35.62mA    42.91mA    22.18mA
-1.2V     30.69mA    39.25mA    16.92mA
-960mV    15.9mA     27.98mA    6.508mA
-800mV    7.821mA    20.25mA    1.349mA
-560mV    1.267mA    8.796mA    53.58uA
-400mV    117.5uA    2.764mA    20.86uA
-160mV    16.15uA    125.2uA    -13.85uA
5V        -78.59uA   -46.05uA   -129.1uA
[Ramp]
| variable   typ   min   max
dV/dt_r  0.4167/0.3190n   0.2824/0.3383n   0.6437/0.2781n
dV/dt_f  0.4573/0.2964n   0.2995/0.3146n   0.6376/0.2875n
R_load = 50.0000
[Rising Waveform]
R_fixture=   50.0000
V_fixture=   2.5000
V_fixture_min=   2.3800
V_fixture_max=   2.6300
|time   V(typ)   V(min)   V(max)
0s        1.738V     1.881V     1.567V
505.1ps   1.738V     1.881V     1.597V
606.1ps   1.738V     1.881V     2.097V
707.1ps   1.731V     1.881V     2.442V
808.1ps   1.879V     1.881V     2.538V
1.01ns    2.342V     1.879V     2.596V
1.111ns   2.418V     1.874V     2.608V
1.515ns   2.481V     2.279V     2.626V
1.919ns   2.494V     2.359V     2.629V
10ns      2.5V       2.38V      2.63V
[Rising Waveform]
R_fixture=   50.0000
V_fixture=   0.0
V_fixture_min=   0.0
V_fixture_max=   0.0
|time   V(typ)   V(min)   V(max)
0s        1.018uV    1.278uV    887.5nV
505.1ps   26.57uV    1.795uV    -10.73mV
606.1ps   32.77uV    1.331uV    73.72mV
707.1ps   -2.104mV   7.854uV    487.2mV
909.1ps   24mV       80.3uV     849.4mV
1.111ns   431mV      -2.166mV   969.3mV
1.414ns   620.8mV    5.681mV    1.038V
1.717ns   673.4mV    320.9mV    1.061V
2.323ns   704.1mV    444.3mV    1.071V
10ns      711.8mV    470.7mV    1.073V
[Falling Waveform]
R_fixture=   50.0000
V_fixture=   0.0
V_fixture_min=   0.0
V_fixture_max=   0.0
|time   V(typ)   V(min)   V(max)
0s        711.8mV    470.7mV    1.073V
505.1ps   711.8mV    470.7mV    1.073V
606.1ps   711.7mV    470.7mV    927.3mV
707.1ps   712mV      470.7mV    299mV
808.1ps   712.2mV    470.7mV    119.8mV
909.1ps   660.6mV    470.7mV    59.46mV
1.111ns   135.5mV    470.7mV    18.42mV
1.414ns   24.17mV    457mV      3.819mV
2.121ns   2.008mV    15.67mV    186.1uV
10ns      12.23uV    2.006uV    9.145uV
[Falling Waveform]
R_fixture=   50.0000
V_fixture=   2.5000
V_fixture_min=   2.3800
V_fixture_max=   2.6300
|time   V(typ)   V(min)   V(max)
0s        2.5V       2.38V      2.63V
606.1ps   2.5V       2.38V      2.601V
707.1ps   2.5V       2.38V      2.18V
808.1ps   2.499V     2.38V      1.926V
909.1ps   2.511V     2.38V      1.804V
1.212ns   1.954V     2.381V     1.643V
1.515ns   1.814V     2.385V     1.593V
1.818ns   1.771V     2.036V     1.576V
2.424ns   1.744V     1.909V     1.568V
10ns      1.738V     1.881V     1.567V
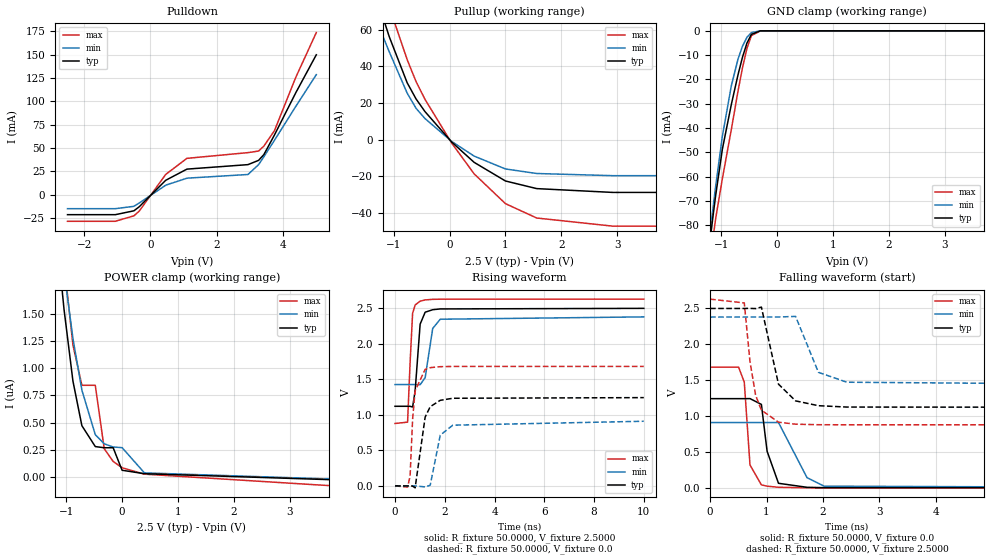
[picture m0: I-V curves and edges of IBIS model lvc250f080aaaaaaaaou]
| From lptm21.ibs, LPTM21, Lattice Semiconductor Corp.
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|   Model lvc250f080aaaaaaaaou
[Model]   lvc250f080aaaaaaaaou
Model_type   Output
Polarity   Non-Inverting
Enable   Active-Low
Vmeas =   1.2500V
Cref =   0.0F
Rref =   1.0000M
Vref =   0.0V
C_comp   4.2000pF   3.8000pF   7.5000pF
[Temperature Range]   25.0000   0.1050k   -40.0000
[Voltage Range]   2.5000V   2.3800V   2.6300V
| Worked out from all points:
|   slope of the pulldown table from 0 to 0.375 V, typ, clamps not added: 28.8 ohm
|   slope of the pullup table from 0 to 0.375 V, typ, clamps not added: 35 ohm
|   GND clamp passes 1 mA (typ) near -0.44 V on its own axis
|   rising waveform, R_fixture 50.0000, V_fixture 2.5000: 20-80 % time 177ps typ, 254ps min, 140ps max; typ from 1.12 V to 2.5 V
|   rising waveform, R_fixture 50.0000, V_fixture 0.0: 20-80 % time 281ps typ, 339ps min, 180ps max; typ from 0 V to 1.24 V
|   falling waveform, R_fixture 50.0000, V_fixture 0.0: 20-80 % time 147ps typ, 204ps min, 88.3ps max; typ from 1.24 V to 0 V
|   falling waveform, R_fixture 50.0000, V_fixture 2.5000: 20-80 % time 254ps typ, 299ps min, 194ps max; typ from 2.5 V to 1.12 V
[Pulldown]
|Voltage   I(typ)   I(min)   I(max)
-2.5V     -21.43mA   -15mA      -28.53mA
-1.06V    -21.43mA   -15mA      -28.53mA
-500mV    -17.29mA   -12.49mA   -22.68mA
-340mV    -13.01mA   -8.939mA   -17.7mA
460mV     15.44mA    10.15mA    21.72mA
1.1V      27.41mA    17.71mA    38.96mA
2.94V     32.22mA    21.64mA    45.09mA
3.26V     36.81mA    32.22mA    46.78mA
3.42V     43.03mA    40.73mA    52.13mA
3.74V     64.12mA    58.4mA     68.73mA
4.38V     109.2mA    94.57mA    125.7mA
5V        150mA      128.7mA    173.8mA
[Pullup]
|Voltage   I(typ)   I(min)   I(max)
-2.5V     183.8mA    153mA      224.3mA
-1.8V     123.7mA    101.4mA    154.8mA
-1.08V    56.2mA     47.99mA    72.47mA
-760mV    31.15mA    25.49mA    43.78mA
-600mV    22.27mA    17.17mA    31.72mA
-440mV    15.37mA    11.59mA    22.04mA
40mV      -1.275mA   -931.8uA   -1.898mA
440mV     -12.3mA    -8.882mA   -18.58mA
1V        -22.45mA   -15.89mA   -34.81mA
1.56V     -26.61mA   -18.37mA   -42.65mA
2.92V     -28.69mA   -19.55mA   -47.08mA
4.96V     -28.69mA   -19.55mA   -47.14mA
[GND_clamp]
|Voltage   I(typ)   I(min)   I(max)
-2.5V     -564.7mA   -543.1mA   -585.2mA
-1.18V    -82.35mA   -79.03mA   -91.15mA
-1.14V    -74.88mA   -71.38mA   -83.96mA
-1.1V     -67.69mA   -63.94mA   -77.25mA
-980mV    -48.66mA   -43.36mA   -60.79mA
-820mV    -30.34mA   -22.65mA   -40.66mA
-700mV    -18.09mA   -11.63mA   -24.79mA
-620mV    -10.87mA   -6.335mA   -15.23mA
-540mV    -5.061mA   -2.654mA   -7.227mA
-460mV    -1.446mA   -714.8uA   -1.98mA
-300mV    -18.71uA   -15.93uA   -16.53uA
5V        0A         0A         0A
[POWER_clamp]
|Voltage   I(typ)   I(min)   I(max)
-2.48V    16.67uA    13.46uA    27.27uA
-1.2V     2.435uA    2.651uA    3.191uA
-1.12V    1.959uA    2.254uA    2.522uA
-1.04V    1.541uA    1.891uA    1.967uA
-880mV    880.7nA    1.272uA    1.212uA
-720mV    472.2nA    798.5nA    842.6nA
-480mV    280.5nA    389.6nA    842.6nA
-320mV    269.7nA    306.1nA    260.6nA
-160mV    269.7nA    276.4nA    144nA
0V        63.22nA    270.6nA    86.34nA
400mV     31.61nA    39.07nA    27.38nA
5V        -44.09nA   -38.33nA   -118.7nA
[Ramp]
| variable   typ   min   max
dV/dt_r  0.7610/0.2778n   0.5462/0.3354n   1.0094/0.1786n
dV/dt_f  0.8277/0.2512n   0.5716/0.2962n   1.0508/0.1921n
R_load = 50.0000
[Rising Waveform]
R_fixture=   50.0000
V_fixture=   2.5000
V_fixture_min=   2.3800
V_fixture_max=   2.6300
|time   V(typ)   V(min)   V(max)
0s        1.121V     1.427V     878.6mV
505.1ps   1.121V     1.427V     897.8mV
606.1ps   1.121V     1.427V     1.734V
707.1ps   1.111V     1.427V     2.431V
808.1ps   1.335V     1.427V     2.547V
1.01ns    2.278V     1.425V     2.601V
1.212ns   2.446V     1.524V     2.619V
1.515ns   2.481V     2.217V     2.627V
1.818ns   2.492V     2.347V     2.629V
10ns      2.5V       2.38V      2.63V
[Rising Waveform]
R_fixture=   50.0000
V_fixture=   0.0
V_fixture_min=   0.0
V_fixture_max=   0.0
|time   V(typ)   V(min)   V(max)
0s        666.9nV    899.8nV    549.6nV
505.1ps   22.6uV     1.285uV    -17.11mV
606.1ps   -46.33uV   988.8nV    136.4mV
707.1ps   -3.152mV   8.393uV    939.9mV
808.1ps   -27.71mV   22.98uV    1.34V
1.212ns   969.8mV    -14.56mV   1.641V
1.414ns   1.115V     9.244mV    1.665V
1.818ns   1.205V     714.8mV    1.679V
2.323ns   1.234V     854.8mV    1.682V
10ns      1.243V     910.3mV    1.682V
[Falling Waveform]
R_fixture=   50.0000
V_fixture=   0.0
V_fixture_min=   0.0
V_fixture_max=   0.0
|time   V(typ)   V(min)   V(max)
0s        1.243V     910.4mV    1.682V
505.1ps   1.243V     910.4mV    1.682V
606.1ps   1.243V     910.4mV    1.473V
707.1ps   1.244V     910.4mV    319.2mV
909.1ps   1.163V     910.3mV    41.68mV
1.01ns    510.6mV    910.3mV    23.4mV
1.212ns   63.63mV    910.5mV    7.931mV
1.717ns   7.747mV    142.5mV    532.8uV
2.02ns    2.628mV    23.7mV     163.4uV
10ns      -3.158uV   12.07uV    18.67uV
[Falling Waveform]
R_fixture=   50.0000
V_fixture=   2.5000
V_fixture_min=   2.3800
V_fixture_max=   2.6300
|time   V(typ)   V(min)   V(max)
0s        2.5V       2.38V      2.63V
606.1ps   2.5V       2.38V      2.577V
707.1ps   2.501V     2.38V      1.757V
808.1ps   2.498V     2.38V      1.287V
909.1ps   2.519V     2.38V      1.083V
1.212ns   1.445V     2.381V     914.9mV
1.515ns   1.212V     2.389V     887.1mV
1.919ns   1.145V     1.61V      880mV
2.424ns   1.126V     1.472V     878.8mV
10ns      1.121V     1.427V     878.6mV
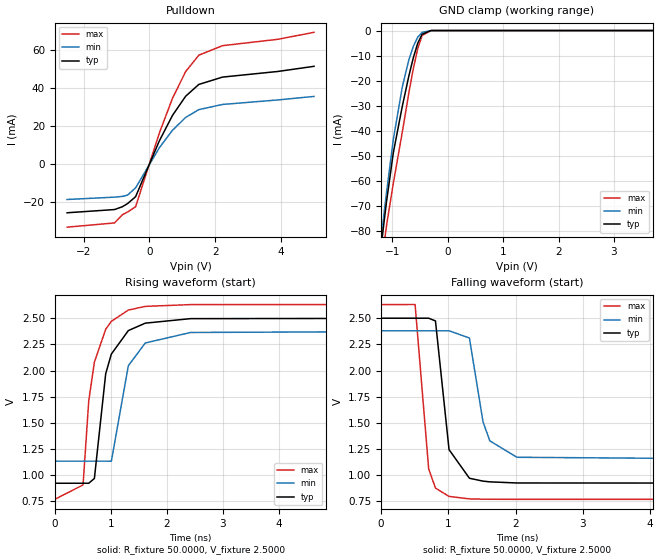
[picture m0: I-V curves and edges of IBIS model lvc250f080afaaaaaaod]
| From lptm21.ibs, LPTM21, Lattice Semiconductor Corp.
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|   Model lvc250f080afaaaaaaod
[Model]   lvc250f080afaaaaaaod
Model_type   I/O_open_drain
Polarity   Non-Inverting
Enable   Active-Low
Vinl =   0.7000V
Vinh =   1.7000V
Vmeas =   1.2500V
Cref =   0.0F
Rref =   1.0000M
Vref =   0.0V
C_comp   4.2000pF   3.8000pF   7.5000pF
[Temperature Range]   25.0000   0.1050k   -40.0000
[Voltage Range]   2.5000V   2.3800V   2.6300V
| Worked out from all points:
|   slope of the pulldown table from 0 to 0.375 V, typ, clamps not added: 25.2 ohm
|   GND clamp passes 1 mA (typ) near -0.44 V on its own axis
|   rising waveform, R_fixture 50.0000, V_fixture 2.5000: 20-80 % time 284ps typ, 279ps min, 263ps max; typ from 0.924 V to 2.5 V
|   falling waveform, R_fixture 50.0000, V_fixture 2.5000: 20-80 % time 165ps typ, 231ps min, 147ps max; typ from 2.5 V to 0.924 V
[Pulldown]
|Voltage   I(typ)   I(min)   I(max)
-2.5V     -25.52mA   -18.56mA   -33.05mA
-1.06V    -23.83mA   -17.33mA   -30.84mA
-820mV    -22.34mA   -16.96mA   -26.51mA
-660mV    -20.66mA   -16.21mA   -25.08mA
-420mV    -17.09mA   -12.45mA   -22.36mA
300mV     12.11mA    8.499mA    16.2mA
700mV     25.46mA    17.68mA    34.4mA
1.1V      35.52mA    24.42mA    48.43mA
1.5V      41.7mA     28.51mA    57.02mA
2.22V     45.55mA    31.22mA    62.01mA
3.9V      48.5mA     33.58mA    65.35mA
5V        51.19mA    35.43mA    69mA
[GND_clamp]
|Voltage   I(typ)   I(min)   I(max)
-2.5V     -564.7mA   -543.1mA   -585.2mA
-1.18V    -82.36mA   -79.04mA   -91.17mA
-1.14V    -74.89mA   -71.39mA   -83.98mA
-1.1V     -67.71mA   -63.95mA   -77.28mA
-980mV    -48.67mA   -43.37mA   -60.82mA
-820mV    -30.36mA   -22.66mA   -40.67mA
-700mV    -18.1mA    -11.63mA   -24.81mA
-620mV    -10.88mA   -6.341mA   -15.24mA
-540mV    -5.068mA   -2.657mA   -7.239mA
-460mV    -1.45mA    -716.2uA   -1.987mA
-300mV    -18.83uA   -15.98uA   -16.73uA
5V        0A         0A         0A
[Ramp]
| variable   typ   min   max
dV/dt_r  0.9456/0.2812n   0.7467/0.2765n   1.1157/0.2606n
dV/dt_f  0.9456/0.1635n   0.7467/0.2288n   1.1157/0.1459n
R_load = 50.0000
[Rising Waveform]
R_fixture=   50.0000
V_fixture=   2.5000
V_fixture_min=   2.3800
V_fixture_max=   2.6300
|time   V(typ)   V(min)   V(max)
0s        923.9mV    1.135V     770.4mV
505.1ps   924mV      1.135V     908mV
606.1ps   924mV      1.135V     1.71V
707.1ps   969.5mV    1.135V     2.08V
909.1ps   1.97V      1.135V     2.394V
1.01ns    2.157V     1.134V     2.469V
1.313ns   2.381V     2.046V     2.577V
1.616ns   2.452V     2.263V     2.612V
2.424ns   2.495V     2.363V     2.629V
10ns      2.5V       2.38V      2.63V
[Falling Waveform]
R_fixture=   50.0000
V_fixture=   2.5000
V_fixture_min=   2.3800
V_fixture_max=   2.6300
|time   V(typ)   V(min)   V(max)
0s        2.5V       2.38V      2.63V
505.1ps   2.5V       2.38V      2.631V
707.1ps   2.5V       2.38V      1.06V
808.1ps   2.474V     2.38V      877.9mV
1.01ns    1.245V     2.38V      798.1mV
1.313ns   971.7mV    2.311V     774.8mV
1.515ns   944.2mV    1.512V     771.8mV
1.616ns   937.3mV    1.329V     771.2mV
2.02ns    926.6mV    1.172V     770.5mV
10ns      924mV      1.135V     770.4mV
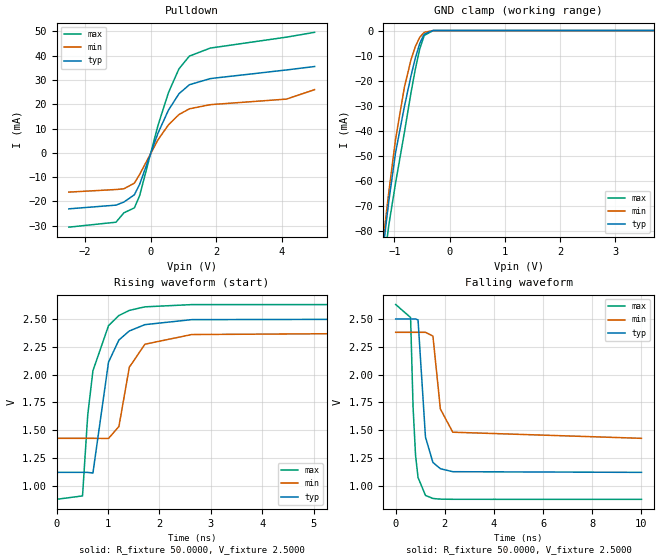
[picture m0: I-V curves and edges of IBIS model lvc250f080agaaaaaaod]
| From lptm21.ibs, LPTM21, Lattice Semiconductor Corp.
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|   Model lvc250f080agaaaaaaod
[Model]   lvc250f080agaaaaaaod
Model_type   I/O_open_drain
Polarity   Non-Inverting
Enable   Active-Low
Vinl =   0.7000V
Vinh =   1.7000V
Vmeas =   1.2500V
Cref =   0.0F
Rref =   1.0000M
Vref =   0.0V
C_comp   4.2000pF   3.8000pF   7.5000pF
[Temperature Range]   25.0000   0.1050k   -40.0000
[Voltage Range]   2.5000V   2.3800V   2.6300V
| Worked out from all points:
|   slope of the pulldown table from 0 to 0.375 V, typ, clamps not added: 28.8 ohm
|   GND clamp passes 1 mA (typ) near -0.44 V on its own axis
|   rising waveform, R_fixture 50.0000, V_fixture 2.5000: 20-80 % time 285ps typ, 295ps min, 292ps max; typ from 1.12 V to 2.5 V
|   falling waveform, R_fixture 50.0000, V_fixture 2.5000: 20-80 % time 262ps typ, 309ps min, 195ps max; typ from 2.5 V to 1.12 V
[Pulldown]
|Voltage   I(typ)   I(min)   I(max)
-2.5V     -23.08mA   -16.19mA   -30.63mA
-1.06V    -21.55mA   -15.12mA   -28.59mA
-820mV    -20.29mA   -14.82mA   -24.74mA
-500mV    -17.29mA   -12.49mA   -22.68mA
-340mV    -13.01mA   -8.939mA   -17.7mA
220mV     8.066mA    5.348mA    11.25mA
540mV     17.57mA    11.51mA    24.77mA
860mV     24.33mA    15.77mA    34.59mA
1.18V     28.07mA    18.15mA    39.87mA
1.82V     30.6mA     19.85mA    43.18mA
4.14V     34.15mA    22.14mA    47.67mA
5V        35.57mA    26.04mA    49.66mA
[GND_clamp]
|Voltage   I(typ)   I(min)   I(max)
-2.5V     -564.7mA   -543.1mA   -585.2mA
-1.18V    -82.35mA   -79.03mA   -91.15mA
-1.14V    -74.88mA   -71.38mA   -83.96mA
-1.1V     -67.69mA   -63.94mA   -77.25mA
-980mV    -48.66mA   -43.36mA   -60.79mA
-820mV    -30.34mA   -22.65mA   -40.66mA
-700mV    -18.09mA   -11.63mA   -24.79mA
-620mV    -10.87mA   -6.335mA   -15.23mA
-540mV    -5.061mA   -2.654mA   -7.227mA
-460mV    -1.446mA   -714.8uA   -1.98mA
-300mV    -18.71uA   -15.93uA   -16.53uA
5V        0A         0A         0A
[Ramp]
| variable   typ   min   max
dV/dt_r  0.8277/0.2820n   0.5716/0.2916n   1.0508/0.2888n
dV/dt_f  0.8277/0.2597n   0.5716/0.3060n   1.0508/0.1800n
R_load = 50.0000
[Rising Waveform]
R_fixture=   50.0000
V_fixture=   2.5000
V_fixture_min=   2.3800
V_fixture_max=   2.6300
|time   V(typ)   V(min)   V(max)
0s        1.121V     1.427V     878.6mV
505.1ps   1.121V     1.427V     909.4mV
606.1ps   1.121V     1.427V     1.636V
707.1ps   1.115V     1.427V     2.034V
1.01ns    2.112V     1.426V     2.44V
1.212ns   2.311V     1.533V     2.531V
1.414ns   2.392V     2.066V     2.577V
1.717ns   2.449V     2.273V     2.609V
2.626ns   2.494V     2.36V      2.629V
10ns      2.5V       2.38V      2.63V
[Falling Waveform]
R_fixture=   50.0000
V_fixture=   2.5000
V_fixture_min=   2.3800
V_fixture_max=   2.6300
|time   V(typ)   V(min)   V(max)
0s        2.5V       2.38V      2.63V
606.1ps   2.5V       2.38V      2.513V
707.1ps   2.5V       2.38V      1.71V
808.1ps   2.5V       2.38V      1.274V
909.1ps   2.491V     2.38V      1.075V
1.212ns   1.438V     2.38V      914mV
1.515ns   1.21V      2.346V     886.3mV
1.818ns   1.154V     1.691V     880.4mV
2.323ns   1.127V     1.482V     878.8mV
10ns      1.121V     1.427V     878.6mV
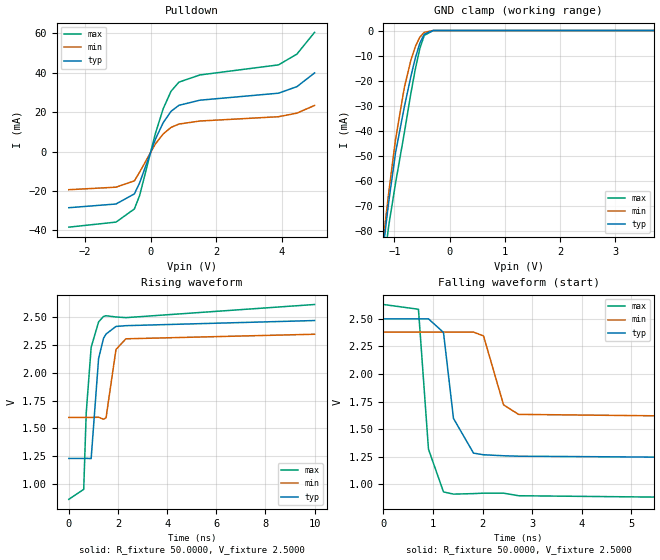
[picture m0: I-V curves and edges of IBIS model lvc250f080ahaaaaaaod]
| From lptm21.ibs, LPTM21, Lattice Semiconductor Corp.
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|   Model lvc250f080ahaaaaaaod
[Model]   lvc250f080ahaaaaaaod
Model_type   I/O_open_drain
Polarity   Non-Inverting
Enable   Active-Low
Vinl =   0.7000V
Vinh =   1.7000V
Vmeas =   1.2500V
Cref =   0.0F
Rref =   1.0000M
Vref =   0.0V
C_comp   4.2000pF   3.8000pF   7.5000pF
[Temperature Range]   25.0000   0.1050k   -40.0000
[Voltage Range]   2.5000V   2.3800V   2.6300V
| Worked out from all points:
|   slope of the pulldown table from 0 to 0.375 V, typ, clamps not added: 25.8 ohm
|   GND clamp passes 1 mA (typ) near -0.44 V on its own axis
|   rising waveform, R_fixture 50.0000, V_fixture 2.5000: 20-80 % time 280ps typ, 277ps min, 295ps max; typ from 1.23 V to 2.47 V
|   falling waveform, R_fixture 50.0000, V_fixture 2.5000: 20-80 % time 235ps typ, 286ps min, 196ps max; typ from 2.5 V to 1.23 V
[Pulldown]
|Voltage   I(typ)   I(min)   I(max)
-2.5V     -28.57mA   -19.41mA   -38.45mA
-1.06V    -26.68mA   -18.13mA   -35.88mA
-500mV    -21.55mA   -14.92mA   -29.2mA
-340mV    -15.98mA   -10.5mA    -22.43mA
140mV     6.179mA    3.831mA    9.041mA
380mV     14.67mA    8.94mA     21.77mA
620mV     20.43mA    12.25mA    30.65mA
860mV     23.49mA    13.96mA    35.27mA
1.5V      26.09mA    15.5mA     38.92mA
3.9V      29.65mA    17.69mA    44.05mA
4.46V     32.97mA    19.51mA    49.51mA
5V        39.95mA    23.43mA    60.59mA
[GND_clamp]
|Voltage   I(typ)   I(min)   I(max)
-2.5V     -564.7mA   -543mA     -585.2mA
-1.18V    -82.34mA   -79.02mA   -91.14mA
-1.14V    -74.87mA   -71.37mA   -83.95mA
-1.1V     -67.69mA   -63.93mA   -77.25mA
-980mV    -48.65mA   -43.36mA   -60.78mA
-820mV    -30.34mA   -22.64mA   -40.65mA
-700mV    -18.08mA   -11.62mA   -24.79mA
-620mV    -10.86mA   -6.332mA   -15.22mA
-540mV    -5.058mA   -2.652mA   -7.223mA
-460mV    -1.444mA   -713.9uA   -1.977mA
-300mV    -18.65uA   -15.9uA    -16.44uA
5V        0A         0A         0A
[Ramp]
| variable   typ   min   max
dV/dt_r  0.7430/0.2777n   0.4483/0.2747n   1.0496/0.2925n
dV/dt_f  0.7600/0.2322n   0.4678/0.2827n   1.0596/0.1944n
R_load = 50.0000
[Rising Waveform]
R_fixture=   50.0000
V_fixture=   2.5000
V_fixture_min=   2.3800
V_fixture_max=   2.6300
|time   V(typ)   V(min)   V(max)
0s        1.231V     1.599V     863.9mV
606.1ps   1.231V     1.599V     953.6mV
707.1ps   1.232V     1.599V     1.636V
909.1ps   1.23V      1.599V     2.229V
1.212ns   2.129V     1.601V     2.457V
1.414ns   2.31V      1.583V     2.506V
1.515ns   2.348V     1.596V     2.512V
1.919ns   2.416V     2.209V     2.501V
2.323ns   2.423V     2.305V     2.495V
10ns      2.469V     2.346V     2.613V
[Falling Waveform]
R_fixture=   50.0000
V_fixture=   2.5000
V_fixture_min=   2.3800
V_fixture_max=   2.6300
|time   V(typ)   V(min)   V(max)
0s        2.5V       2.38V      2.63V
707.1ps   2.5V       2.38V      2.587V
909.1ps   2.5V       2.38V      1.319V
1.212ns   2.377V     2.38V      931.3mV
1.414ns   1.597V     2.38V      911.3mV
1.818ns   1.283V     2.38V      916mV
2.02ns    1.268V     2.345V     920mV
2.424ns   1.259V     1.72V      920.2mV
2.727ns   1.255V     1.634V     896.7mV
10ns      1.233V     1.6V       864.1mV
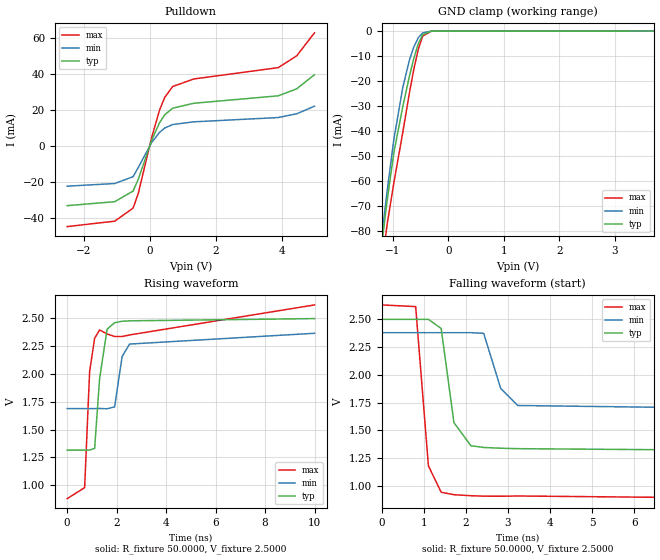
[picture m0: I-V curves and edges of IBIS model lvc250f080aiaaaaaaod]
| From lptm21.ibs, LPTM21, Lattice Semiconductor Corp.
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|   Model lvc250f080aiaaaaaaod
[Model]   lvc250f080aiaaaaaaod
Model_type   I/O_open_drain
Polarity   Non-Inverting
Enable   Active-Low
Vinl =   0.7000V
Vinh =   1.7000V
Vmeas =   1.2500V
Cref =   0.0F
Rref =   1.0000M
Vref =   0.0V
C_comp   4.2000pF   3.8000pF   7.5000pF
[Temperature Range]   25.0000   0.1050k   -40.0000
[Voltage Range]   2.5000V   2.3800V   2.6300V
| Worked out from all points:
|   slope of the pulldown table from 0 to 0.375 V, typ, clamps not added: 24.6 ohm
|   GND clamp passes 1 mA (typ) near -0.44 V on its own axis
|   rising waveform, R_fixture 50.0000, V_fixture 2.5000: 20-80 % time 251ps typ, 336ps min, 315ps max; typ from 1.31 V to 2.5 V
|   falling waveform, R_fixture 50.0000, V_fixture 2.5000: 20-80 % time 263ps typ, 322ps min, 212ps max; typ from 2.5 V to 1.32 V
[Pulldown]
|Voltage   I(typ)   I(min)   I(max)
-2.5V     -33.18mA   -22.35mA   -44.82mA
-1.06V    -30.98mA   -20.88mA   -41.81mA
-500mV    -25.06mA   -17.08mA   -34.54mA
-340mV    -18.33mA   -11.83mA   -26.16mA
60mV      3.049mA    1.834mA    4.587mA
300mV     12.9mA     7.574mA    19.85mA
460mV     17.36mA    10.02mA    27.06mA
700mV     21.02mA    11.93mA    33.07mA
1.34V     23.76mA    13.43mA    37.27mA
3.9V      27.9mA     15.82mA    43.57mA
4.46V     31.8mA     17.89mA    50.14mA
5V        39.64mA    22.15mA    62.93mA
[GND_clamp]
|Voltage   I(typ)   I(min)   I(max)
-2.5V     -564.7mA   -543mA     -585.2mA
-1.18V    -82.33mA   -78.99mA   -91.13mA
-1.14V    -74.86mA   -71.35mA   -83.95mA
-1.1V     -67.68mA   -63.91mA   -77.24mA
-980mV    -48.65mA   -43.35mA   -60.78mA
-820mV    -30.34mA   -22.64mA   -40.65mA
-700mV    -18.08mA   -11.62mA   -24.78mA
-620mV    -10.86mA   -6.331mA   -15.22mA
-540mV    -5.056mA   -2.651mA   -7.221mA
-460mV    -1.444mA   -713.5uA   -1.976mA
-300mV    -18.62uA   -15.88uA   -16.41uA
5V        0A         0A         0A
[Ramp]
| variable   typ   min   max
dV/dt_r  0.7033/0.3080n   0.4059/0.3325n   1.0455/0.3121n
dV/dt_f  0.7101/0.2605n   0.4133/0.3186n   1.0473/0.2098n
R_load = 50.0000
[Rising Waveform]
R_fixture=   50.0000
V_fixture=   2.5000
V_fixture_min=   2.3800
V_fixture_max=   2.6300
|time   V(typ)   V(min)   V(max)
0s        1.315V     1.689V     878.5mV
707.1ps   1.315V     1.689V     978.1mV
909.1ps   1.316V     1.689V     2.023V
1.111ns   1.331V     1.689V     2.321V
1.313ns   1.96V      1.69V      2.396V
1.616ns   2.403V     1.687V     2.36V
1.919ns   2.461V     1.704V     2.337V
2.222ns   2.474V     2.156V     2.337V
2.525ns   2.478V     2.269V     2.351V
10ns      2.498V     2.366V     2.621V
[Falling Waveform]
R_fixture=   50.0000
V_fixture=   2.5000
V_fixture_min=   2.3800
V_fixture_max=   2.6300
|time   V(typ)   V(min)   V(max)
0s        2.5V       2.38V      2.63V
808.1ps   2.5V       2.38V      2.615V
1.111ns   2.5V       2.38V      1.18V
1.414ns   2.418V     2.38V      942.5mV
1.717ns   1.57V      2.38V      920.1mV
2.121ns   1.361V     2.38V      911.1mV
2.424ns   1.346V     2.374V     907.2mV
2.828ns   1.339V     1.878V     906.3mV
3.232ns   1.335V     1.724V     908.7mV
10ns      1.316V     1.691V     884.3mV
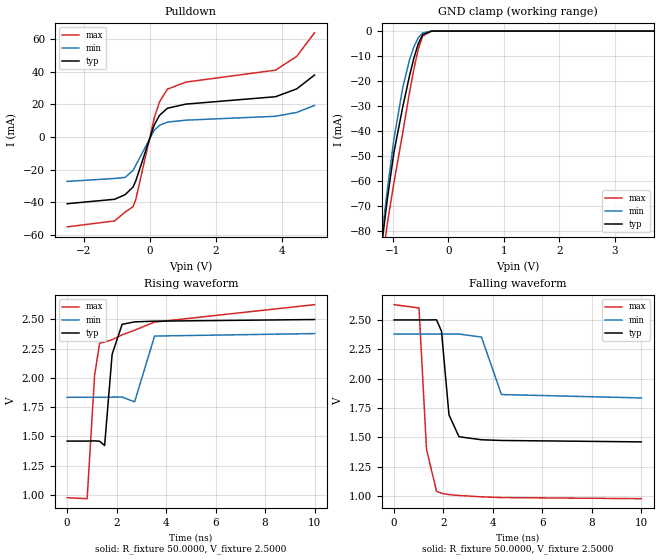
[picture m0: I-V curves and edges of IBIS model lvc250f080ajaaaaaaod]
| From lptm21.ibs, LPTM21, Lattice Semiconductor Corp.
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|   Model lvc250f080ajaaaaaaod
[Model]   lvc250f080ajaaaaaaod
Model_type   I/O_open_drain
Polarity   Non-Inverting
Enable   Active-Low
Vinl =   0.7000V
Vinh =   1.7000V
Vmeas =   1.2500V
Cref =   0.0F
Rref =   1.0000M
Vref =   0.0V
C_comp   4.2000pF   3.8000pF   7.5000pF
[Temperature Range]   25.0000   0.1050k   -40.0000
[Voltage Range]   2.5000V   2.3800V   2.6300V
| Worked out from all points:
|   slope of the pulldown table from 0 to 0.375 V, typ, clamps not added: 24.8 ohm
|   GND clamp passes 1 mA (typ) near -0.44 V on its own axis
|   rising waveform, R_fixture 50.0000, V_fixture 2.5000: 20-80 % time 243ps typ, 297ps min, 358ps max; typ from 1.46 V to 2.5 V
|   falling waveform, R_fixture 50.0000, V_fixture 2.5000: 20-80 % time 284ps typ, 368ps min, 233ps max; typ from 2.5 V to 1.46 V
[Pulldown]
|Voltage   I(typ)   I(min)   I(max)
-2.5V     -40.91mA   -27.25mA   -55.09mA
-1.06V    -38.2mA    -25.45mA   -51.44mA
-740mV    -35.34mA   -24.78mA   -45.98mA
-500mV    -30.67mA   -20.47mA   -42.72mA
-420mV    -26.98mA   -17.39mA   -38.43mA
140mV     7.298mA    4.05mA     11.57mA
300mV     13.2mA     7.088mA    21.46mA
540mV     17.57mA    9.078mA    29.25mA
1.1V      20.1mA     10.26mA    33.58mA
3.82V     24.63mA    12.65mA    40.91mA
4.46V     29.42mA    15.02mA    49.32mA
5V        37.9mA     19.29mA    63.76mA
[GND_clamp]
|Voltage   I(typ)   I(min)   I(max)
-2.5V     -564.7mA   -543mA     -585.2mA
-1.18V    -82.26mA   -78.93mA   -91.11mA
-1.14V    -74.8mA    -71.29mA   -83.93mA
-1.1V     -67.62mA   -63.85mA   -77.23mA
-980mV    -48.61mA   -43.3mA    -60.78mA
-820mV    -30.33mA   -22.62mA   -40.64mA
-700mV    -18.08mA   -11.62mA   -24.78mA
-620mV    -10.86mA   -6.33mA    -15.22mA
-540mV    -5.055mA   -2.65mA    -7.219mA
-460mV    -1.443mA   -713.2uA   -1.975mA
-300mV    -18.6uA    -15.87uA   -16.37uA
5V        0A         0A         0A
[Ramp]
| variable   typ   min   max
dV/dt_r  0.6228/0.2407n   0.3266/0.2945n   0.9893/0.3543n
dV/dt_f  0.6230/0.2816n   0.3265/0.3645n   0.9907/0.2309n
R_load = 50.0000
[Rising Waveform]
R_fixture=   50.0000
V_fixture=   2.5000
V_fixture_min=   2.3800
V_fixture_max=   2.6300
|time   V(typ)   V(min)   V(max)
0s        1.46V      1.834V     976.3mV
808.1ps   1.46V      1.834V     968.1mV
1.111ns   1.462V     1.834V     2.022V
1.313ns   1.459V     1.834V     2.297V
1.515ns   1.422V     1.834V     2.305V
1.818ns   2.201V     1.835V     2.326V
2.222ns   2.457V     1.836V     2.367V
2.727ns   2.478V     1.795V     2.407V
3.535ns   2.484V     2.357V     2.476V
10ns      2.498V     2.378V     2.625V
[Falling Waveform]
R_fixture=   50.0000
V_fixture=   2.5000
V_fixture_min=   2.3800
V_fixture_max=   2.6300
|time   V(typ)   V(min)   V(max)
0s        2.5V       2.38V      2.63V
1.01ns    2.5V       2.38V      2.602V
1.313ns   2.5V       2.38V      1.399V
1.717ns   2.501V     2.38V      1.042V
1.919ns   2.404V     2.38V      1.024V
2.222ns   1.692V     2.38V      1.013V
2.626ns   1.506V     2.38V      1.006V
3.535ns   1.48V      2.354V     994.2mV
4.343ns   1.474V     1.865V     988.1mV
10ns      1.462V     1.836V     978.5mV
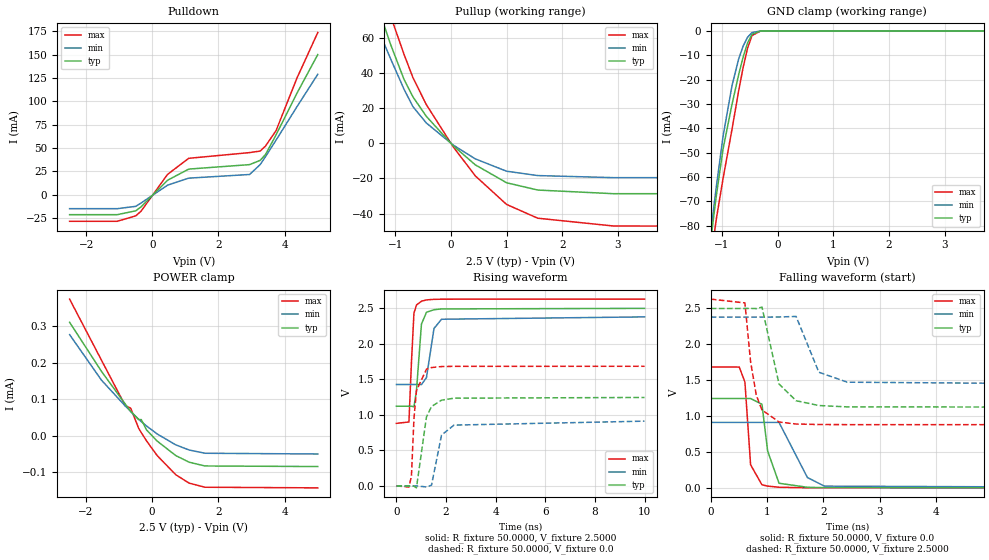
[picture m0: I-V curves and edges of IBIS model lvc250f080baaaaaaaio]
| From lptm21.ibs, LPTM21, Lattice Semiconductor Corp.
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|   Model lvc250f080baaaaaaaio
[Model]   lvc250f080baaaaaaaio
Model_type   I/O
Polarity   Non-Inverting
Enable   Active-Low
Vinl =   0.7000V
Vinh =   1.7000V
Vmeas =   1.2500V
Cref =   0.0F
Rref =   1.0000M
Vref =   0.0V
C_comp   4.2000pF   3.8000pF   7.5000pF
[Temperature Range]   25.0000   0.1050k   -40.0000
[Voltage Range]   2.5000V   2.3800V   2.6300V
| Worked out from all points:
|   slope of the pulldown table from 0 to 0.375 V, typ, clamps not added: 28.8 ohm
|   slope of the pullup table from 0 to 0.375 V, typ, clamps not added: 35 ohm
|   GND clamp passes 1 mA (typ) near -0.44 V on its own axis
|   rising waveform, R_fixture 50.0000, V_fixture 2.5000: 20-80 % time 177ps typ, 254ps min, 140ps max; typ from 1.12 V to 2.5 V
|   rising waveform, R_fixture 50.0000, V_fixture 0.0: 20-80 % time 280ps typ, 339ps min, 180ps max; typ from 0.001 V to 1.25 V
|   falling waveform, R_fixture 50.0000, V_fixture 0.0: 20-80 % time 147ps typ, 204ps min, 88.4ps max; typ from 1.25 V to 0.001 V
|   falling waveform, R_fixture 50.0000, V_fixture 2.5000: 20-80 % time 255ps typ, 300ps min, 195ps max; typ from 2.5 V to 1.12 V
[Pulldown]
|Voltage   I(typ)   I(min)   I(max)
-2.5V     -21.43mA   -15.01mA   -28.53mA
-1.06V    -21.43mA   -15.01mA   -28.53mA
-500mV    -17.29mA   -12.49mA   -22.69mA
-340mV    -13.01mA   -8.936mA   -17.69mA
460mV     15.45mA    10.15mA    21.73mA
1.1V      27.41mA    17.71mA    38.96mA
2.94V     32.21mA    21.63mA    45.08mA
3.26V     36.78mA    32.23mA    46.73mA
3.42V     43mA       40.75mA    52.07mA
3.74V     64.12mA    58.46mA    68.65mA
4.38V     109.3mA    94.75mA    125.6mA
5V        150.1mA    129mA      173.7mA
[Pullup]
|Voltage   I(typ)   I(min)   I(max)
-2.5V     183.9mA    153.3mA    224.1mA
-1.88V    131mA      107.5mA    163.2mA
-1.08V    56.19mA    48.02mA    72.38mA
-840mV    36.35mA    30.78mA    50.62mA
-680mV    26.44mA    20.86mA    37.37mA
-440mV    15.35mA    11.58mA    22.03mA
40mV      -1.275mA   -931.6uA   -1.897mA
440mV     -12.29mA   -8.88mA    -18.57mA
1V        -22.45mA   -15.88mA   -34.8mA
1.56V     -26.61mA   -18.37mA   -42.65mA
2.92V     -28.69mA   -19.55mA   -47.09mA
4.96V     -28.69mA   -19.55mA   -47.15mA
[GND_clamp]
|Voltage   I(typ)   I(min)   I(max)
-2.5V     -564.6mA   -543.1mA   -585.1mA
-1.18V    -82.28mA   -79mA      -91.03mA
-1.14V    -74.81mA   -71.35mA   -83.85mA
-1.1V     -67.63mA   -63.91mA   -77.15mA
-980mV    -48.6mA    -43.33mA   -60.69mA
-820mV    -30.29mA   -22.62mA   -40.55mA
-700mV    -18.04mA   -11.6mA    -24.7mA
-620mV    -10.82mA   -6.314mA   -15.14mA
-540mV    -5.025mA   -2.64mA    -7.154mA
-460mV    -1.426mA   -708.3uA   -1.934mA
-300mV    -17.76uA   -15.73uA   -12.8uA
5V        0A         0A         0A
[POWER_clamp]
|Voltage   I(typ)   I(min)   I(max)
-2.48V    310.4uA    276.7uA    373.7uA
-1.52V    176.3uA    152.3uA    206.9uA
-800mV    86.61uA    81.35uA    82.18uA
-640mV    66.94uA    66.91uA    75.79uA
-400mV    44.51uA    45.44uA    20.86uA
-320mV    44.51uA    38.99uA    8.918uA
-160mV    16.15uA    26.85uA    -13.85uA
160mV     -14.29uA   5.152uA    -53.97uA
720mV     -53.87uA   -24.56uA   -106.2uA
1.12V     -71.9uA    -38.53uA   -129.1uA
1.6V      -82.26uA   -47.53uA   -140.4uA
5V        -83.86uA   -49.55uA   -142.1uA
[Ramp]
| variable   typ   min   max
dV/dt_r  0.7618/0.2773n   0.5469/0.3354n   1.0097/0.1777n
dV/dt_f  0.8261/0.2521n   0.5705/0.2968n   1.0489/0.1930n
R_load = 50.0000
[Rising Waveform]
R_fixture=   50.0000
V_fixture=   2.5000
V_fixture_min=   2.3800
V_fixture_max=   2.6300
|time   V(typ)   V(min)   V(max)
0s        1.123V     1.429V     881.7mV
505.1ps   1.123V     1.429V     901.2mV
606.1ps   1.124V     1.429V     1.738V
707.1ps   1.113V     1.429V     2.432V
808.1ps   1.338V     1.429V     2.547V
1.01ns    2.279V     1.427V     2.601V
1.212ns   2.445V     1.526V     2.619V
1.515ns   2.481V     2.217V     2.627V
1.818ns   2.492V     2.347V     2.629V
10ns      2.5V       2.38V      2.63V
[Rising Waveform]
R_fixture=   50.0000
V_fixture=   0.0
V_fixture_min=   0.0
V_fixture_max=   0.0
|time   V(typ)   V(min)   V(max)
0s        1.298mV    1.013mV    1.693mV
505.1ps   1.321mV    1.013mV    -15.38mV
606.1ps   1.252mV    1.013mV    139.9mV
707.1ps   -1.854mV   1.02mV     944.6mV
808.1ps   -26.22mV   1.035mV    1.344V
1.212ns   972.9mV    -13.48mV   1.644V
1.414ns   1.118V     11mV       1.667V
1.818ns   1.208V     717mV      1.681V
2.323ns   1.236V     857mV      1.684V
10ns      1.246V     912.5mV    1.685V
[Falling Waveform]
R_fixture=   50.0000
V_fixture=   0.0
V_fixture_min=   0.0
V_fixture_max=   0.0
|time   V(typ)   V(min)   V(max)
0s        1.246V     912.5mV    1.685V
505.1ps   1.246V     912.5mV    1.684V
606.1ps   1.246V     912.5mV    1.476V
707.1ps   1.246V     912.5mV    322.5mV
909.1ps   1.165V     912.5mV    43.8mV
1.01ns    513.4mV    912.4mV    25.33mV
1.212ns   65.27mV    912.7mV    9.548mV
1.717ns   9.058mV    144mV      2.209mV
2.02ns    3.919mV    24.81mV    1.868mV
10ns      1.321mV    1.03mV     1.7mV
[Falling Waveform]
R_fixture=   50.0000
V_fixture=   2.5000
V_fixture_min=   2.3800
V_fixture_max=   2.6300
|time   V(typ)   V(min)   V(max)
0s        2.5V       2.38V      2.63V
606.1ps   2.5V       2.38V      2.577V
707.1ps   2.501V     2.38V      1.758V
808.1ps   2.498V     2.38V      1.291V
909.1ps   2.519V     2.38V      1.087V
1.212ns   1.448V     2.381V     918.4mV
1.515ns   1.215V     2.389V     890.2mV
1.919ns   1.148V     1.612V     883.2mV
2.424ns   1.129V     1.473V     882mV
10ns      1.123V     1.429V     881.7mV
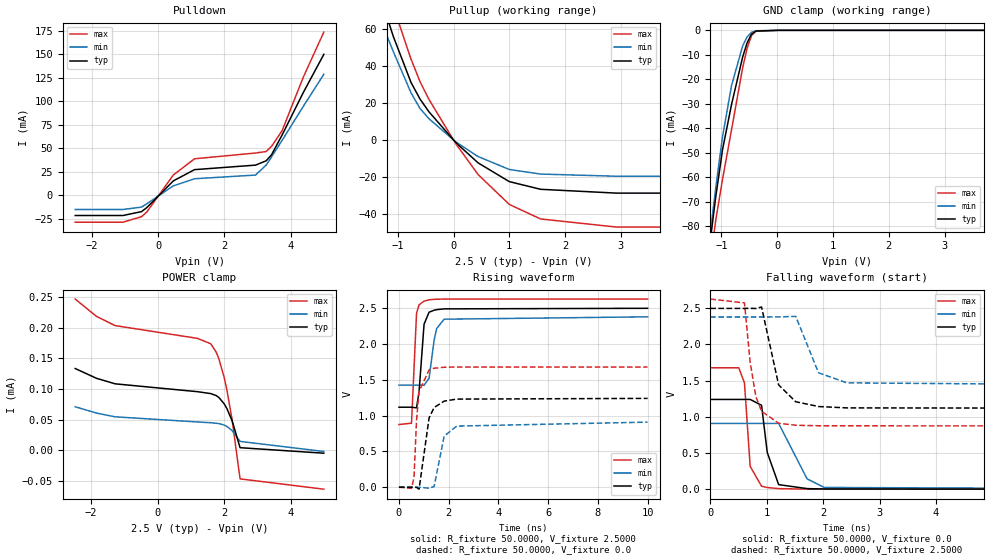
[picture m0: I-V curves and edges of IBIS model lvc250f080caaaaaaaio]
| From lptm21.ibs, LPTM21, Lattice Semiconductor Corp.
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|   Model lvc250f080caaaaaaaio
[Model]   lvc250f080caaaaaaaio
Model_type   I/O
Polarity   Non-Inverting
Enable   Active-Low
Vinl =   0.7000V
Vinh =   1.7000V
Vmeas =   1.2500V
Cref =   0.0F
Rref =   1.0000M
Vref =   0.0V
C_comp   4.2000pF   3.8000pF   7.5000pF
[Temperature Range]   25.0000   0.1050k   -40.0000
[Voltage Range]   2.5000V   2.3800V   2.6300V
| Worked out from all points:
|   slope of the pulldown table from 0 to 0.375 V, typ, clamps not added: 28.8 ohm
|   slope of the pullup table from 0 to 0.375 V, typ, clamps not added: 35 ohm
|   GND clamp passes 1 mA (typ) near -0.44 V on its own axis
|   rising waveform, R_fixture 50.0000, V_fixture 2.5000: 20-80 % time 177ps typ, 254ps min, 140ps max; typ from 1.12 V to 2.5 V
|   rising waveform, R_fixture 50.0000, V_fixture 0.0: 20-80 % time 281ps typ, 338ps min, 181ps max; typ from 0 V to 1.24 V
|   falling waveform, R_fixture 50.0000, V_fixture 0.0: 20-80 % time 147ps typ, 204ps min, 88.2ps max; typ from 1.24 V to 0 V
|   falling waveform, R_fixture 50.0000, V_fixture 2.5000: 20-80 % time 253ps typ, 299ps min, 193ps max; typ from 2.5 V to 1.12 V
[Pulldown]
|Voltage   I(typ)   I(min)   I(max)
-2.5V     -21.43mA   -15.01mA   -28.53mA
-1.06V    -21.43mA   -15.01mA   -28.53mA
-500mV    -17.29mA   -12.49mA   -22.69mA
-340mV    -13mA      -8.934mA   -17.68mA
460mV     15.43mA    10.15mA    21.7mA
1.1V      27.4mA     17.71mA    38.95mA
2.94V     32.21mA    21.63mA    45.1mA
3.26V     36.78mA    32.24mA    46.7mA
3.42V     43.03mA    40.77mA    52.06mA
3.74V     64.17mA    58.46mA    68.72mA
4.38V     109.4mA    94.69mA    125.7mA
5V        150.1mA    128.9mA    173.8mA
[Pullup]
|Voltage   I(typ)   I(min)   I(max)
-2.5V     183.9mA    153.1mA    224.3mA
-1.8V     123.8mA    101.5mA    154.9mA
-1.08V    56.23mA    48.03mA    72.43mA
-760mV    31.13mA    25.5mA     43.71mA
-600mV    22.24mA    17.16mA    31.63mA
-440mV    15.34mA    11.58mA    22.03mA
40mV      -1.281mA   -934.1uA   -1.916mA
440mV     -12.3mA    -8.884mA   -18.59mA
1V        -22.45mA   -15.89mA   -34.81mA
1.56V     -26.61mA   -18.37mA   -42.66mA
2.92V     -28.68mA   -19.54mA   -47.05mA
4.96V     -28.68mA   -19.54mA   -47.11mA
[GND_clamp]
|Voltage   I(typ)   I(min)   I(max)
-2.5V     -564.7mA   -543.1mA   -585.2mA
-1.18V    -82.37mA   -79.05mA   -91.19mA
-1.14V    -74.91mA   -71.4mA    -84.01mA
-1.1V     -67.72mA   -63.96mA   -77.3mA
-980mV    -48.69mA   -43.39mA   -60.85mA
-820mV    -30.38mA   -22.68mA   -40.71mA
-620mV    -10.92mA   -6.374mA   -15.3mA
-540mV    -5.123mA   -2.7mA     -7.317mA
-460mV    -1.524mA   -767.4uA   -2.097mA
-380mV    -292.5uA   -172.6uA   -366.3uA
20mV      0A         0A         0A
5V        0A         0A         0A
[POWER_clamp]
|Voltage   I(typ)   I(min)   I(max)
-2.48V    133.3uA    71.04uA    246.4uA
-1.84V    117.4uA    60.8uA     218.2uA
-1.28V    108.4uA    54.67uA    203.2uA
1.2V      95.59uA    46.28uA    182.4uA
1.6V      92.47uA    45.01uA    173.5uA
1.76V     89.3uA     44.22uA    160.2uA
1.84V     86.28uA    43.64uA    149.5uA
2V        76.02uA    41.32uA    119.2uA
2.08V     68.53uA    39.17uA    99.45uA
2.24V     48.41uA    32.29uA    50.16uA
2.48V     4.411uA    14.65uA    -46.36uA
5V        -4.578uA   -1.793uA   -63.13uA
[Ramp]
| variable   typ   min   max
dV/dt_r  0.7591/0.2779n   0.5450/0.3351n   1.0069/0.1789n
dV/dt_f  0.8285/0.2508n   0.5722/0.2962n   1.0516/0.1910n
R_load = 50.0000
[Rising Waveform]
R_fixture=   50.0000
V_fixture=   2.5000
V_fixture_min=   2.3800
V_fixture_max=   2.6300
|time   V(typ)   V(min)   V(max)
0s        1.117V     1.425V     874.7mV
505.1ps   1.117V     1.425V     893.6mV
707.1ps   1.108V     1.425V     2.427V
808.1ps   1.331V     1.425V     2.546V
1.01ns    2.276V     1.423V     2.598V
1.212ns   2.444V     1.522V     2.616V
1.414ns   2.471V     2.051V     2.623V
1.515ns   2.479V     2.215V     2.625V
1.818ns   2.49V      2.346V     2.627V
10ns      2.498V     2.379V     2.627V
[Rising Waveform]
R_fixture=   50.0000
V_fixture=   0.0
V_fixture_min=   0.0
V_fixture_max=   0.0
|time   V(typ)   V(min)   V(max)
0s        650.7nV    887.2nV    527.1nV
505.1ps   22.56uV    1.272uV    -17.09mV
606.1ps   -46.37uV   976.2nV    136.5mV
707.1ps   -3.149mV   8.377uV    938.1mV
808.1ps   -27.68mV   22.94uV    1.336V
1.212ns   967.4mV    -14.54mV   1.637V
1.414ns   1.112V     9.312mV    1.661V
1.818ns   1.202V     713.5mV    1.675V
2.323ns   1.23V      853mV      1.678V
10ns      1.24V      908.3mV    1.678V
[Falling Waveform]
R_fixture=   50.0000
V_fixture=   0.0
V_fixture_min=   0.0
V_fixture_max=   0.0
|time   V(typ)   V(min)   V(max)
0s        1.24V      908.3mV    1.678V
505.1ps   1.24V      908.3mV    1.677V
606.1ps   1.24V      908.3mV    1.468V
707.1ps   1.24V      908.3mV    315.6mV
909.1ps   1.159V     908.3mV    40.6mV
1.01ns    507.5mV    908.3mV    22.91mV
1.212ns   62.64mV    908.5mV    7.59mV
1.717ns   7.654mV    141.5mV    511.8uV
2.02ns    2.599mV    23.45mV    174.4uV
10ns      -8.793uV   10.84uV    24.47uV
[Falling Waveform]
R_fixture=   50.0000
V_fixture=   2.5000
V_fixture_min=   2.3800
V_fixture_max=   2.6300
|time   V(typ)   V(min)   V(max)
0s        2.498V     2.379V     2.627V
606.1ps   2.498V     2.379V     2.574V
707.1ps   2.499V     2.379V     1.751V
808.1ps   2.497V     2.379V     1.281V
909.1ps   2.517V     2.379V     1.077V
1.212ns   1.441V     2.38V      910.4mV
1.515ns   1.208V     2.388V     883.2mV
1.919ns   1.142V     1.608V     876.1mV
2.424ns   1.123V     1.469V     874.9mV
10ns      1.117V     1.425V     874.7mV
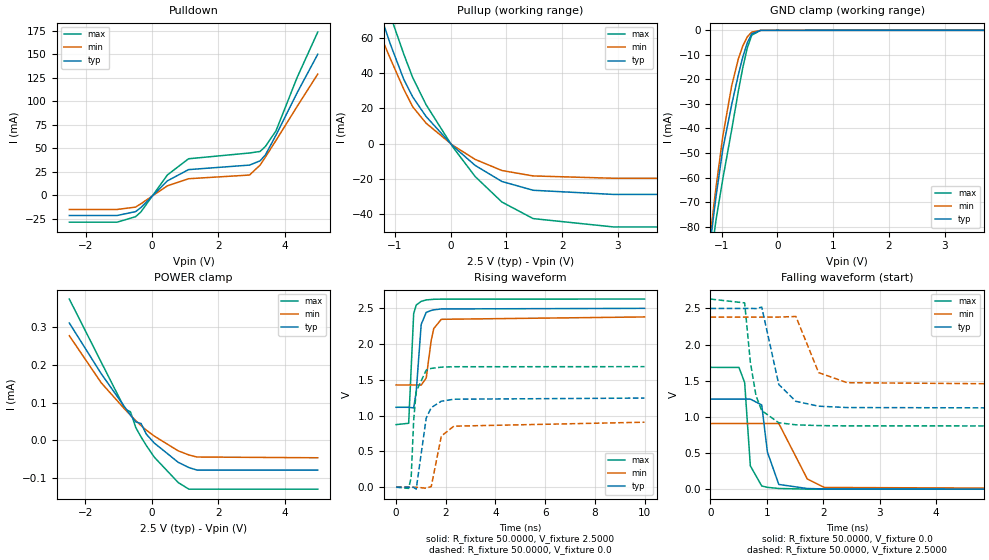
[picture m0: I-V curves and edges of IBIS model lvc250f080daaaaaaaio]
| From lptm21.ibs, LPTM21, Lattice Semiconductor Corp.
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|   Model lvc250f080daaaaaaaio
[Model]   lvc250f080daaaaaaaio
Model_type   I/O
Polarity   Non-Inverting
Enable   Active-Low
Vinl =   0.7000V
Vinh =   1.7000V
Vmeas =   1.2500V
Cref =   0.0F
Rref =   1.0000M
Vref =   0.0V
C_comp   4.2000pF   3.8000pF   7.5000pF
[Temperature Range]   25.0000   0.1050k   -40.0000
[Voltage Range]   2.5000V   2.3800V   2.6300V
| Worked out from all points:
|   slope of the pulldown table from 0 to 0.375 V, typ, clamps not added: 28.8 ohm
|   slope of the pullup table from 0 to 0.375 V, typ, clamps not added: 35 ohm
|   GND clamp passes 1 mA (typ) near -0.44 V on its own axis
|   rising waveform, R_fixture 50.0000, V_fixture 2.5000: 20-80 % time 177ps typ, 254ps min, 140ps max; typ from 1.12 V to 2.5 V
|   rising waveform, R_fixture 50.0000, V_fixture 0.0: 20-80 % time 286ps typ, 339ps min, 184ps max; typ from 0 V to 1.25 V
|   falling waveform, R_fixture 50.0000, V_fixture 0.0: 20-80 % time 148ps typ, 204ps min, 88.5ps max; typ from 1.25 V to 0 V
|   falling waveform, R_fixture 50.0000, V_fixture 2.5000: 20-80 % time 258ps typ, 300ps min, 198ps max; typ from 2.5 V to 1.12 V
[Pulldown]
|Voltage   I(typ)   I(min)   I(max)
-2.5V     -21.43mA   -15.01mA   -28.53mA
-1.06V    -21.43mA   -15.01mA   -28.53mA
-500mV    -17.29mA   -12.49mA   -22.69mA
-340mV    -13mA      -8.934mA   -17.68mA
460mV     15.43mA    10.15mA    21.7mA
1.1V      27.4mA     17.71mA    38.95mA
2.94V     32.21mA    21.63mA    45.08mA
3.26V     36.78mA    32.23mA    46.73mA
3.42V     43mA       40.75mA    52.07mA
3.74V     64.12mA    58.46mA    68.65mA
4.38V     109.3mA    94.75mA    125.6mA
5V        150.1mA    129mA      173.7mA
[Pullup]
|Voltage   I(typ)   I(min)   I(max)
-2.5V     183.9mA    153.3mA    224.1mA
-1.88V    131mA      107.5mA    163.2mA
-1.08V    56.19mA    48.02mA    72.38mA
-840mV    36.35mA    30.78mA    50.62mA
-680mV    26.44mA    20.86mA    37.37mA
-440mV    15.35mA    11.58mA    22.03mA
40mV      -1.275mA   -931.6uA   -1.897mA
440mV     -12.29mA   -8.88mA    -18.57mA
920mV     -21.37mA   -15.17mA   -32.99mA
1.48V     -26.33mA   -18.23mA   -42.34mA
2.92V     -28.68mA   -19.54mA   -47.05mA
4.96V     -28.68mA   -19.54mA   -47.11mA
[GND_clamp]
|Voltage   I(typ)   I(min)   I(max)
-2.5V     -564.6mA   -543.1mA   -585.1mA
-1.18V    -82.29mA   -79mA      -91.05mA
-1.14V    -74.82mA   -71.35mA   -83.87mA
-1.1V     -67.64mA   -63.91mA   -77.16mA
-980mV    -48.61mA   -43.34mA   -60.71mA
-820mV    -30.3mA    -22.63mA   -40.57mA
-700mV    -18.05mA   -11.61mA   -24.72mA
-620mV    -10.84mA   -6.326mA   -15.16mA
-540mV    -5.04mA    -2.652mA   -7.178mA
-460mV    -1.44mA    -719uA     -1.958mA
-300mV    -9.986uA   -9.27uA    -5.3uA
5V        0A         0A         0A
[POWER_clamp]
|Voltage   I(typ)   I(min)   I(max)
-2.48V    310.4uA    276.7uA    373.7uA
-1.52V    176.3uA    152.3uA    206.9uA
-800mV    86.61uA    81.35uA    82.18uA
-640mV    66.94uA    66.91uA    75.79uA
-480mV    48.86uA    52.22uA    34.01uA
-320mV    44.51uA    38.99uA    8.918uA
-160mV    16.15uA    26.85uA    -13.85uA
80mV      -7.284uA   11.17uA    -44.64uA
800mV     -58.16uA   -27.83uA   -111.7uA
1.12V     -71.9uA    -38.53uA   -129.1uA
1.36V     -78.59uA   -44.07uA   -129.1uA
5V        -78.59uA   -46.05uA   -129.1uA
[Ramp]
| variable   typ   min   max
dV/dt_r  0.7626/0.2827n   0.5450/0.3352n   1.0107/0.1819n
dV/dt_f  0.8296/0.2557n   0.5705/0.2968n   1.0532/0.1955n
R_load = 50.0000
[Rising Waveform]
R_fixture=   50.0000
V_fixture=   2.5000
V_fixture_min=   2.3800
V_fixture_max=   2.6300
|time   V(typ)   V(min)   V(max)
0s        1.117V     1.429V     874.7mV
505.1ps   1.117V     1.429V     893.6mV
707.1ps   1.108V     1.429V     2.427V
808.1ps   1.331V     1.429V     2.546V
1.01ns    2.276V     1.427V     2.598V
1.212ns   2.444V     1.526V     2.618V
1.414ns   2.471V     2.054V     2.624V
1.515ns   2.479V     2.217V     2.627V
1.818ns   2.492V     2.347V     2.629V
10ns      2.5V       2.38V      2.63V
[Rising Waveform]
R_fixture=   50.0000
V_fixture=   0.0
V_fixture_min=   0.0
V_fixture_max=   0.0
|time   V(typ)   V(min)   V(max)
0s        650.7nV    887.2nV    527.1nV
505.1ps   22.56uV    1.272uV    -17.09mV
606.1ps   -46.37uV   976.2nV    136.5mV
707.1ps   -3.149mV   8.377uV    938.1mV
808.1ps   -27.68mV   22.94uV    1.336V
1.212ns   967.4mV    -14.54mV   1.637V
1.414ns   1.112V     9.312mV    1.661V
1.818ns   1.202V     713.5mV    1.678V
2.323ns   1.23V      853mV      1.684V
10ns      1.246V     908.4mV    1.685V
[Falling Waveform]
R_fixture=   50.0000
V_fixture=   0.0
V_fixture_min=   0.0
V_fixture_max=   0.0
|time   V(typ)   V(min)   V(max)
0s        1.246V     908.3mV    1.685V
505.1ps   1.246V     908.3mV    1.684V
606.1ps   1.246V     908.3mV    1.476V
707.1ps   1.246V     908.3mV    322.5mV
909.1ps   1.165V     908.3mV    43.8mV
1.01ns    513.4mV    908.3mV    25.33mV
1.212ns   65.27mV    908.5mV    9.487mV
1.717ns   9.058mV    141.5mV    787.9uV
2.02ns    3.166mV    23.45mV    207.2uV
10ns      -10.46uV   10.9uV     31.21nV
[Falling Waveform]
R_fixture=   50.0000
V_fixture=   2.5000
V_fixture_min=   2.3800
V_fixture_max=   2.6300
|time   V(typ)   V(min)   V(max)
0s        2.5V       2.38V      2.63V
606.1ps   2.5V       2.38V      2.577V
707.1ps   2.501V     2.38V      1.758V
808.1ps   2.498V     2.38V      1.291V
909.1ps   2.519V     2.38V      1.087V
1.212ns   1.448V     2.381V     918.4mV
1.515ns   1.215V     2.389V     890.2mV
1.919ns   1.148V     1.612V     879.5mV
2.424ns   1.129V     1.473V     875.2mV
10ns      1.117V     1.429V     874.7mV
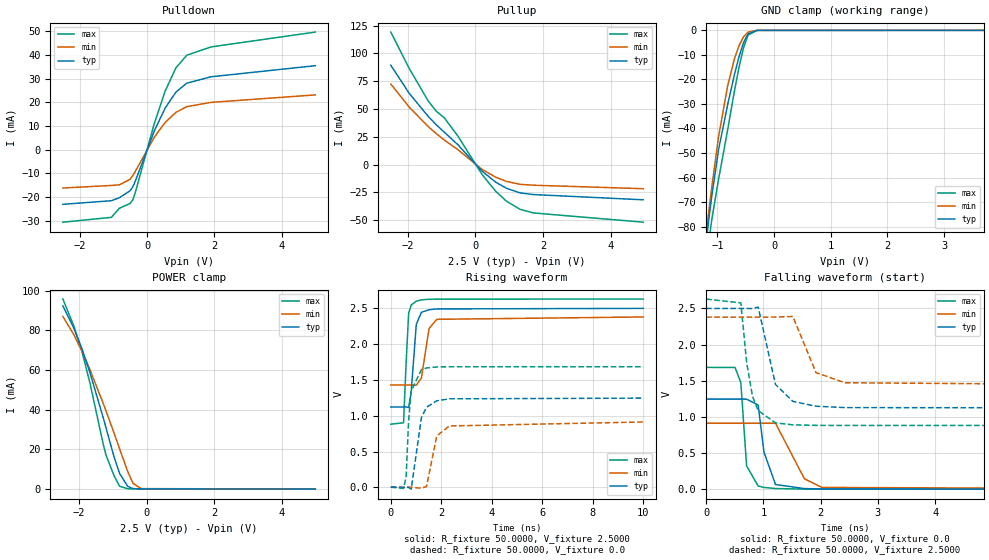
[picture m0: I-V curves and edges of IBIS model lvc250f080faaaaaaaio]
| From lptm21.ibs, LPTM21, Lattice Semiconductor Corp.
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|   Model lvc250f080faaaaaaaio
[Model]   lvc250f080faaaaaaaio
Model_type   I/O
Polarity   Non-Inverting
Enable   Active-Low
Vinl =   0.7000V
Vinh =   1.7000V
Vmeas =   1.2500V
Cref =   0.0F
Rref =   1.0000M
Vref =   0.0V
C_comp   4.2000pF   3.8000pF   7.5000pF
[Temperature Range]   25.0000   0.1050k   -40.0000
[Voltage Range]   2.5000V   2.3800V   2.6300V
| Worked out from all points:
|   slope of the pulldown table from 0 to 0.375 V, typ, clamps not added: 28.8 ohm
|   slope of the pullup table from 0 to 0.375 V, typ, clamps not added: 35 ohm
|   GND clamp passes 1 mA (typ) near -0.44 V on its own axis
|   POWER clamp passes 1 mA (typ) near -0.54 V on its own axis
|   rising waveform, R_fixture 50.0000, V_fixture 2.5000: 20-80 % time 177ps typ, 254ps min, 140ps max; typ from 1.12 V to 2.5 V
|   rising waveform, R_fixture 50.0000, V_fixture 0.0: 20-80 % time 280ps typ, 339ps min, 180ps max; typ from 0.001 V to 1.25 V
|   falling waveform, R_fixture 50.0000, V_fixture 0.0: 20-80 % time 147ps typ, 204ps min, 88.4ps max; typ from 1.25 V to 0.001 V
|   falling waveform, R_fixture 50.0000, V_fixture 2.5000: 20-80 % time 255ps typ, 300ps min, 195ps max; typ from 2.5 V to 1.12 V
[Pulldown]
|Voltage   I(typ)   I(min)   I(max)
-2.5V     -23.08mA   -16.19mA   -30.63mA
-1.06V    -21.56mA   -15.12mA   -28.59mA
-820mV    -20.29mA   -14.82mA   -24.74mA
-500mV    -17.29mA   -12.49mA   -22.69mA
-420mV    -15.65mA   -10.92mA   -21.14mA
-340mV    -13.01mA   -8.936mA   -17.69mA
220mV     8.072mA    5.35mA     11.26mA
540mV     17.57mA    11.51mA    24.78mA
860mV     24.33mA    15.77mA    34.6mA
1.18V     28.07mA    18.15mA    39.87mA
1.9V      30.77mA    19.97mA    43.38mA
5V        35.46mA    23.12mA    49.65mA
[Pullup]
|Voltage   I(typ)   I(min)   I(max)
-2.5V     89.38mA    72.46mA    119.2mA
-1.96V    64.24mA    51.82mA    86.67mA
-1.4V     43.51mA    34.32mA    57.47mA
-1.16V    35.93mA    27.93mA    48.12mA
-920mV    29.14mA    22.04mA    42.1mA
-520mV    17.92mA    13.48mA    25.76mA
200mV     -6.059mA   -4.409mA   -9.069mA
600mV     -15.82mA   -11.37mA   -24.06mA
920mV     -21.37mA   -15.17mA   -32.99mA
1.32V     -25.51mA   -17.78mA   -40.29mA
1.72V     -27mA      -18.59mA   -43.55mA
4.96V     -31.72mA   -21.73mA   -51.86mA
[GND_clamp]
|Voltage   I(typ)   I(min)   I(max)
-2.5V     -564.6mA   -543.1mA   -585.1mA
-1.18V    -82.28mA   -79mA      -91.03mA
-1.14V    -74.81mA   -71.35mA   -83.85mA
-1.1V     -67.63mA   -63.91mA   -77.15mA
-980mV    -48.6mA    -43.33mA   -60.69mA
-820mV    -30.29mA   -22.62mA   -40.55mA
-700mV    -18.04mA   -11.6mA    -24.7mA
-620mV    -10.82mA   -6.314mA   -15.14mA
-540mV    -5.025mA   -2.64mA    -7.154mA
-460mV    -1.426mA   -708.3uA   -1.934mA
-300mV    -17.76uA   -15.73uA   -12.8uA
5V        0A         0A         0A
[POWER_clamp]
|Voltage   I(typ)   I(min)   I(max)
-2.48V    92.38mA    87.03mA    95.82mA
-2.16V    81.29mA    77.94mA    82.39mA
-1.92V    70.92mA    69.63mA    69.65mA
-1.68V    58.78mA    60.26mA    53.56mA
-1.28V    35.62mA    42.91mA    22.18mA
-1.2V     30.69mA    39.25mA    16.92mA
-960mV    15.9mA     27.98mA    6.508mA
-800mV    7.821mA    20.25mA    1.349mA
-560mV    1.267mA    8.796mA    53.58uA
-400mV    117.5uA    2.764mA    20.86uA
-160mV    16.15uA    125.2uA    -13.85uA
5V        -83.86uA   -49.55uA   -142.1uA
[Ramp]
| variable   typ   min   max
dV/dt_r  0.7618/0.2773n   0.5469/0.3354n   1.0097/0.1777n
dV/dt_f  0.8261/0.2521n   0.5705/0.2968n   1.0489/0.1930n
R_load = 50.0000
[Rising Waveform]
R_fixture=   50.0000
V_fixture=   2.5000
V_fixture_min=   2.3800
V_fixture_max=   2.6300
|time   V(typ)   V(min)   V(max)
0s        1.123V     1.429V     881.7mV
505.1ps   1.123V     1.429V     901.2mV
606.1ps   1.124V     1.429V     1.738V
707.1ps   1.113V     1.429V     2.432V
808.1ps   1.338V     1.429V     2.547V
1.01ns    2.279V     1.427V     2.601V
1.212ns   2.445V     1.526V     2.619V
1.515ns   2.481V     2.217V     2.627V
1.818ns   2.492V     2.347V     2.629V
10ns      2.5V       2.38V      2.63V
[Rising Waveform]
R_fixture=   50.0000
V_fixture=   0.0
V_fixture_min=   0.0
V_fixture_max=   0.0
|time   V(typ)   V(min)   V(max)
0s        1.298mV    1.013mV    1.693mV
505.1ps   1.321mV    1.013mV    -15.38mV
606.1ps   1.252mV    1.013mV    139.9mV
707.1ps   -1.854mV   1.02mV     944.6mV
808.1ps   -26.22mV   1.035mV    1.344V
1.212ns   972.9mV    -13.48mV   1.644V
1.414ns   1.118V     11mV       1.667V
1.818ns   1.208V     717mV      1.681V
2.323ns   1.236V     857mV      1.684V
10ns      1.246V     912.5mV    1.685V
[Falling Waveform]
R_fixture=   50.0000
V_fixture=   0.0
V_fixture_min=   0.0
V_fixture_max=   0.0
|time   V(typ)   V(min)   V(max)
0s        1.246V     912.5mV    1.685V
505.1ps   1.246V     912.5mV    1.684V
606.1ps   1.246V     912.5mV    1.476V
707.1ps   1.246V     912.5mV    322.5mV
909.1ps   1.165V     912.5mV    43.8mV
1.01ns    513.4mV    912.4mV    25.33mV
1.212ns   65.27mV    912.7mV    9.548mV
1.717ns   9.058mV    144mV      2.209mV
2.02ns    3.919mV    24.81mV    1.868mV
10ns      1.292mV    1mV        1.7mV
[Falling Waveform]
R_fixture=   50.0000
V_fixture=   2.5000
V_fixture_min=   2.3800
V_fixture_max=   2.6300
|time   V(typ)   V(min)   V(max)
0s        2.5V       2.38V      2.63V
606.1ps   2.5V       2.38V      2.577V
707.1ps   2.501V     2.38V      1.758V
808.1ps   2.498V     2.38V      1.291V
909.1ps   2.519V     2.38V      1.087V
1.212ns   1.448V     2.381V     918.4mV
1.515ns   1.215V     2.389V     890.2mV
1.919ns   1.148V     1.612V     883.2mV
2.424ns   1.129V     1.473V     882mV
10ns      1.123V     1.429V     881.8mV
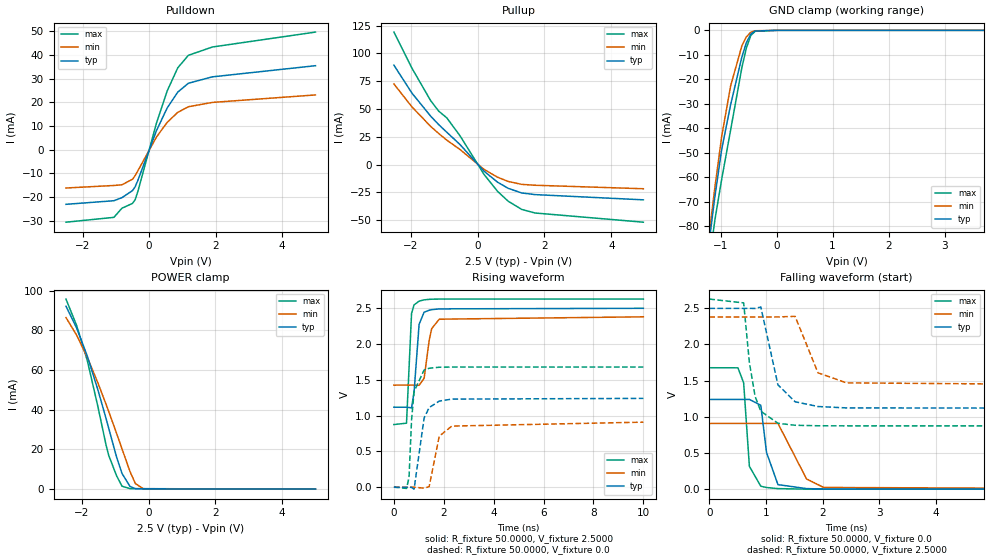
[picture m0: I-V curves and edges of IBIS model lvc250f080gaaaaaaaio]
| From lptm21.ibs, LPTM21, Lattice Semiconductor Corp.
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|   Model lvc250f080gaaaaaaaio
[Model]   lvc250f080gaaaaaaaio
Model_type   I/O
Polarity   Non-Inverting
Enable   Active-Low
Vinl =   0.7000V
Vinh =   1.7000V
Vmeas =   1.2500V
Cref =   0.0F
Rref =   1.0000M
Vref =   0.0V
C_comp   4.2000pF   3.8000pF   7.5000pF
[Temperature Range]   25.0000   0.1050k   -40.0000
[Voltage Range]   2.5000V   2.3800V   2.6300V
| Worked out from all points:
|   slope of the pulldown table from 0 to 0.375 V, typ, clamps not added: 28.8 ohm
|   slope of the pullup table from 0 to 0.375 V, typ, clamps not added: 35 ohm
|   GND clamp passes 1 mA (typ) near -0.44 V on its own axis
|   POWER clamp passes 1 mA (typ) near -0.53 V on its own axis
|   rising waveform, R_fixture 50.0000, V_fixture 2.5000: 20-80 % time 177ps typ, 254ps min, 140ps max; typ from 1.12 V to 2.5 V
|   rising waveform, R_fixture 50.0000, V_fixture 0.0: 20-80 % time 281ps typ, 338ps min, 181ps max; typ from 0 V to 1.24 V
|   falling waveform, R_fixture 50.0000, V_fixture 0.0: 20-80 % time 147ps typ, 204ps min, 88.2ps max; typ from 1.24 V to 0 V
|   falling waveform, R_fixture 50.0000, V_fixture 2.5000: 20-80 % time 253ps typ, 299ps min, 193ps max; typ from 2.5 V to 1.12 V
[Pulldown]
|Voltage   I(typ)   I(min)   I(max)
-2.5V     -23.08mA   -16.19mA   -30.63mA
-1.06V    -21.56mA   -15.12mA   -28.59mA
-820mV    -20.29mA   -14.82mA   -24.74mA
-500mV    -17.29mA   -12.49mA   -22.69mA
-420mV    -15.65mA   -10.91mA   -21.13mA
-340mV    -13mA      -8.934mA   -17.68mA
220mV     8.061mA    5.346mA    11.24mA
540mV     17.56mA    11.51mA    24.75mA
860mV     24.32mA    15.77mA    34.58mA
1.18V     28.07mA    18.14mA    39.87mA
1.9V      30.77mA    19.97mA    43.38mA
5V        35.48mA    23.13mA    49.68mA
[Pullup]
|Voltage   I(typ)   I(min)   I(max)
-2.5V     89.44mA    72.55mA    119.2mA
-1.96V    64.26mA    51.86mA    86.68mA
-1.4V     43.52mA    34.33mA    57.48mA
-1.16V    35.93mA    27.94mA    48.1mA
-920mV    29.14mA    22.04mA    42.09mA
-520mV    17.92mA    13.48mA    25.76mA
200mV     -6.067mA   -4.412mA   -9.09mA
600mV     -15.83mA   -11.37mA   -24.08mA
920mV     -21.38mA   -15.18mA   -33.01mA
1.32V     -25.51mA   -17.78mA   -40.3mA
1.72V     -27mA      -18.59mA   -43.55mA
4.96V     -31.71mA   -21.73mA   -51.82mA
[GND_clamp]
|Voltage   I(typ)   I(min)   I(max)
-2.5V     -564.7mA   -543.1mA   -585.2mA
-1.18V    -82.37mA   -79.05mA   -91.19mA
-1.14V    -74.91mA   -71.4mA    -84.01mA
-1.1V     -67.72mA   -63.96mA   -77.3mA
-980mV    -48.69mA   -43.39mA   -60.85mA
-820mV    -30.38mA   -22.68mA   -40.71mA
-620mV    -10.92mA   -6.374mA   -15.3mA
-540mV    -5.123mA   -2.7mA     -7.317mA
-460mV    -1.524mA   -767.4uA   -2.097mA
-380mV    -292.5uA   -172.6uA   -366.3uA
20mV      0A         0A         0A
5V        0A         0A         0A
[POWER_clamp]
|Voltage   I(typ)   I(min)   I(max)
-2.48V    92.22mA    86.5mA     95.83mA
-2.16V    81.19mA    77.59mA    82.43mA
-1.84V    67mA       66.38mA    64.75mA
-1.52V    49.86mA    53.4mA     41.33mA
-1.28V    35.63mA    42.81mA    22.28mA
-1.2V     30.7mA     39.17mA    17mA
-960mV    15.93mA    27.93mA    6.582mA
-800mV    7.851mA    20.23mA    1.424mA
-560mV    1.299mA    8.796mA    199.2uA
-400mV    169.6uA    2.771mA    193.9uA
-160mV    101.6uA    144.1uA    192.3uA
5V        -4.578uA   -1.793uA   -63.13uA
[Ramp]
| variable   typ   min   max
dV/dt_r  0.7591/0.2779n   0.5450/0.3351n   1.0069/0.1789n
dV/dt_f  0.8285/0.2508n   0.5722/0.2962n   1.0516/0.1910n
R_load = 50.0000
[Rising Waveform]
R_fixture=   50.0000
V_fixture=   2.5000
V_fixture_min=   2.3800
V_fixture_max=   2.6300
|time   V(typ)   V(min)   V(max)
0s        1.117V     1.425V     874.7mV
505.1ps   1.117V     1.425V     893.6mV
707.1ps   1.108V     1.425V     2.427V
808.1ps   1.331V     1.425V     2.546V
1.01ns    2.276V     1.423V     2.598V
1.212ns   2.444V     1.522V     2.616V
1.414ns   2.471V     2.051V     2.623V
1.515ns   2.479V     2.215V     2.625V
1.818ns   2.49V      2.346V     2.627V
10ns      2.498V     2.379V     2.627V
[Rising Waveform]
R_fixture=   50.0000
V_fixture=   0.0
V_fixture_min=   0.0
V_fixture_max=   0.0
|time   V(typ)   V(min)   V(max)
0s        650.7nV    887.2nV    527.1nV
505.1ps   22.56uV    1.272uV    -17.09mV
606.1ps   -46.37uV   976.2nV    136.5mV
707.1ps   -3.149mV   8.377uV    938.1mV
808.1ps   -27.68mV   22.94uV    1.336V
1.212ns   967.4mV    -14.54mV   1.637V
1.414ns   1.112V     9.312mV    1.661V
1.818ns   1.202V     713.5mV    1.675V
2.323ns   1.23V      853mV      1.678V
10ns      1.24V      908.3mV    1.678V
[Falling Waveform]
R_fixture=   50.0000
V_fixture=   0.0
V_fixture_min=   0.0
V_fixture_max=   0.0
|time   V(typ)   V(min)   V(max)
0s        1.24V      908.3mV    1.678V
505.1ps   1.24V      908.3mV    1.677V
606.1ps   1.24V      908.3mV    1.468V
707.1ps   1.24V      908.3mV    315.6mV
909.1ps   1.159V     908.3mV    40.6mV
1.01ns    507.5mV    908.3mV    22.91mV
1.212ns   62.64mV    908.5mV    7.59mV
1.717ns   7.654mV    141.5mV    511.8uV
2.02ns    2.599mV    23.45mV    174.4uV
10ns      -3.134uV   32.03uV    23.73uV
[Falling Waveform]
R_fixture=   50.0000
V_fixture=   2.5000
V_fixture_min=   2.3800
V_fixture_max=   2.6300
|time   V(typ)   V(min)   V(max)
0s        2.498V     2.379V     2.627V
606.1ps   2.498V     2.379V     2.574V
707.1ps   2.499V     2.379V     1.751V
808.1ps   2.497V     2.379V     1.281V
909.1ps   2.517V     2.379V     1.077V
1.212ns   1.441V     2.38V      910.4mV
1.515ns   1.208V     2.388V     883.2mV
1.919ns   1.142V     1.608V     876.1mV
2.424ns   1.123V     1.469V     874.9mV
10ns      1.117V     1.425V     874.8mV
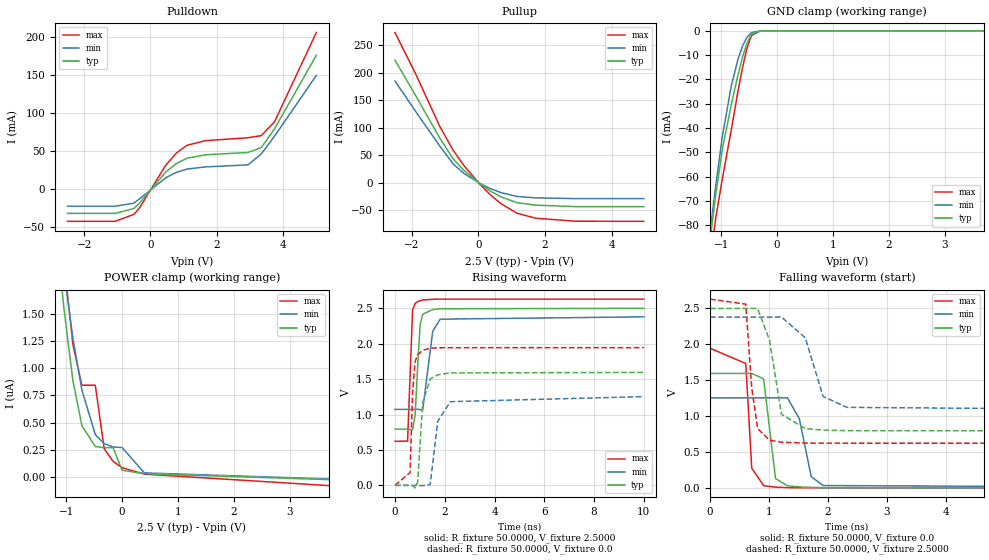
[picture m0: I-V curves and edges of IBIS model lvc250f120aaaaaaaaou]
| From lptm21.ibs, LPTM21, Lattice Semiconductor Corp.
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|   Model lvc250f120aaaaaaaaou
[Model]   lvc250f120aaaaaaaaou
Model_type   Output
Polarity   Non-Inverting
Enable   Active-Low
Vmeas =   1.2500V
Cref =   0.0F
Rref =   1.0000M
Vref =   0.0V
C_comp   4.2000pF   3.8000pF   7.5000pF
[Temperature Range]   25.0000   0.1050k   -40.0000
[Voltage Range]   2.5000V   2.3800V   2.6300V
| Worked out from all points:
|   slope of the pulldown table from 0 to 0.375 V, typ, clamps not added: 19.8 ohm
|   slope of the pullup table from 0 to 0.375 V, typ, clamps not added: 23.5 ohm
|   GND clamp passes 1 mA (typ) near -0.44 V on its own axis
|   rising waveform, R_fixture 50.0000, V_fixture 2.5000: 20-80 % time 162ps typ, 239ps min, 131ps max; typ from 0.794 V to 2.5 V
|   rising waveform, R_fixture 50.0000, V_fixture 0.0: 20-80 % time 213ps typ, 295ps min, 139ps max; typ from 0 V to 1.59 V
|   falling waveform, R_fixture 50.0000, V_fixture 0.0: 20-80 % time 135ps typ, 185ps min, 80.9ps max; typ from 1.59 V to 0 V
|   falling waveform, R_fixture 50.0000, V_fixture 2.5000: 20-80 % time 192ps typ, 268ps min, 138ps max; typ from 2.5 V to 0.794 V
[Pulldown]
|Voltage   I(typ)   I(min)   I(max)
-2.5V     -31.76mA   -22.34mA   -42.19mA
-1.06V    -31.76mA   -22.34mA   -42.19mA
-500mV    -25.32mA   -18.35mA   -33.11mA
-340mV    -18.82mA   -13.07mA   -25.3mA
460mV     22.53mA    14.95mA    31.32mA
780mV     33.72mA    22.07mA    47.46mA
1.1V      40.71mA    26.41mA    57.65mA
1.66V     45.2mA     29.32mA    63.8mA
2.94V     48.23mA    31.93mA    67.56mA
3.34V     54.62mA    46.31mA    70.38mA
3.74V     79.21mA    69.59mA    88.47mA
5V        175.9mA    149.4mA    205.8mA
[Pullup]
|Voltage   I(typ)   I(min)   I(max)
-2.5V     222.8mA    184.9mA    273.1mA
-1.88V    158.2mA    129.4mA    197.7mA
-1.16V    81.22mA    66.69mA    102.5mA
-760mV    43.3mA     34.1mA     58.98mA
-440mV    22.6mA     16.82mA    31.42mA
40mV      -1.891mA   -1.366mA   -2.72mA
360mV     -15.44mA   -11.04mA   -22.5mA
680mV     -26.13mA   -18.46mA   -38.66mA
1.16V     -36.72mA   -25.38mA   -55.86mA
1.72V     -41.23mA   -27.85mA   -65.01mA
2.92V     -43.87mA   -29.3mA    -70.47mA
4.96V     -43.87mA   -29.3mA    -70.59mA
[GND_clamp]
|Voltage   I(typ)   I(min)   I(max)
-2.5V     -564.7mA   -543.1mA   -585.2mA
-1.18V    -82.35mA   -79.03mA   -91.15mA
-1.14V    -74.88mA   -71.38mA   -83.96mA
-1.1V     -67.69mA   -63.94mA   -77.25mA
-980mV    -48.66mA   -43.36mA   -60.79mA
-820mV    -30.34mA   -22.65mA   -40.66mA
-700mV    -18.09mA   -11.63mA   -24.79mA
-620mV    -10.87mA   -6.335mA   -15.23mA
-540mV    -5.061mA   -2.654mA   -7.227mA
-460mV    -1.446mA   -714.8uA   -1.98mA
-300mV    -18.71uA   -15.93uA   -16.53uA
5V        0A         0A         0A
[POWER_clamp]
|Voltage   I(typ)   I(min)   I(max)
-2.48V    16.67uA    13.46uA    27.27uA
-1.2V     2.436uA    2.652uA    3.192uA
-1.12V    1.96uA     2.255uA    2.522uA
-1.04V    1.541uA    1.892uA    1.967uA
-880mV    881.4nA    1.272uA    1.213uA
-720mV    472.9nA    799.2nA    843.2nA
-480mV    281.1nA    390.2nA    843.2nA
-320mV    270.3nA    306.7nA    260.6nA
-160mV    270.3nA    276.9nA    144nA
0V        63.22nA    271.1nA    86.34nA
400mV     31.61nA    39.07nA    27.38nA
5V        -44.09nA   -38.33nA   -118.7nA
[Ramp]
| variable   typ   min   max
dV/dt_r  0.9572/0.2105n   0.7518/0.2919n   1.1669/0.1374n
dV/dt_f  1.0236/0.1898n   0.7843/0.2651n   1.2045/0.1367n
R_load = 50.0000
[Rising Waveform]
R_fixture=   50.0000
V_fixture=   2.5000
V_fixture_min=   2.3800
V_fixture_max=   2.6300
|time   V(typ)   V(min)   V(max)
0s        794.1mV    1.073V     622.4mV
505.1ps   794.1mV    1.073V     624.1mV
707.1ps   785.4mV    1.073V     2.479V
808.1ps   987.4mV    1.073V     2.567V
909.1ps   1.674V     1.074V     2.594V
1.01ns    2.269V     1.071V     2.608V
1.111ns   2.416V     1.06V      2.617V
1.515ns   2.483V     2.175V     2.628V
1.818ns   2.494V     2.347V     2.63V
10ns      2.5V       2.38V      2.63V
[Rising Waveform]
R_fixture=   50.0000
V_fixture=   0.0
V_fixture_min=   0.0
V_fixture_max=   0.0
|time   V(typ)   V(min)   V(max)
0s        495.7nV    694.4nV    398.1nV
606.1ps   -99.1uV    744.1nV    180.6mV
707.1ps   -3.613mV   9.017uV    1.312V
808.1ps   -35.32mV   15.45uV    1.749V
909.1ps   44.28mV    -4.197uV   1.843V
1.111ns   1.166V     -4mV       1.908V
1.414ns   1.503V     11.42mV    1.936V
1.717ns   1.561V     903.9mV    1.943V
2.222ns   1.588V     1.182V     1.944V
10ns      1.595V     1.253V     1.945V
[Falling Waveform]
R_fixture=   50.0000
V_fixture=   0.0
V_fixture_min=   0.0
V_fixture_max=   0.0
|time   V(typ)   V(min)   V(max)
0s        1.595V     1.253V     1.945V
606.1ps   1.595V     1.253V     1.733V
707.1ps   1.596V     1.253V     275.8mV
909.1ps   1.518V     1.253V     30.43mV
1.111ns   129.8mV    1.254V     9.663mV
1.313ns   29.66mV    1.254V     3.015mV
1.515ns   13.34mV    964.2mV    940.4uV
1.717ns   6.448mV    156.6mV    320.5uV
1.919ns   3.103mV    32.8mV     131.1uV
10ns      -15.58uV   3.714uV    -16.25uV
[Falling Waveform]
R_fixture=   50.0000
V_fixture=   2.5000
V_fixture_min=   2.3800
V_fixture_max=   2.6300
|time   V(typ)   V(min)   V(max)
0s        2.5V       2.38V      2.63V
606.1ps   2.5V       2.38V      2.56V
707.1ps   2.501V     2.38V      1.394V
808.1ps   2.498V     2.38V      825.6mV
1.01ns    2.054V     2.38V      664.1mV
1.212ns   1.026V     2.381V     636.3mV
1.616ns   825.4mV    2.091V     624.1mV
1.919ns   804.8mV    1.273V     622.8mV
2.323ns   797.1mV    1.122V     622.5mV
10ns      794.1mV    1.073V     622.4mV
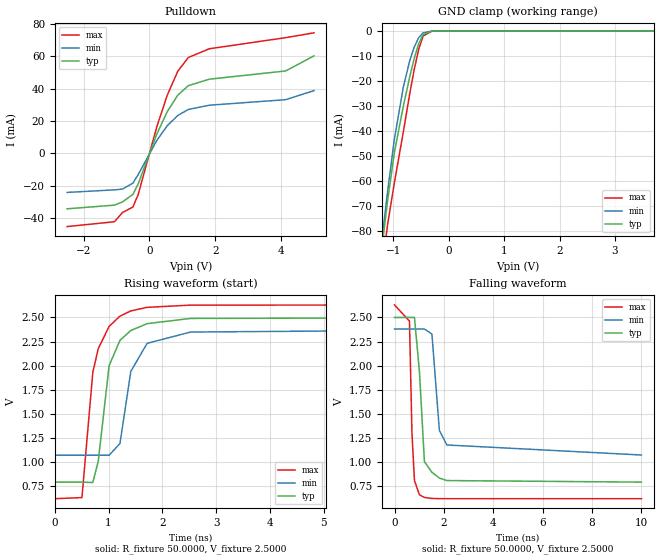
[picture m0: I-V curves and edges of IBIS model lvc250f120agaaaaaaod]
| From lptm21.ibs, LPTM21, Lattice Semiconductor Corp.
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|   Model lvc250f120agaaaaaaod
[Model]   lvc250f120agaaaaaaod
Model_type   I/O_open_drain
Polarity   Non-Inverting
Enable   Active-Low
Vinl =   0.7000V
Vinh =   1.7000V
Vmeas =   1.2500V
Cref =   0.0F
Rref =   1.0000M
Vref =   0.0V
C_comp   4.2000pF   3.8000pF   7.5000pF
[Temperature Range]   25.0000   0.1050k   -40.0000
[Voltage Range]   2.5000V   2.3800V   2.6300V
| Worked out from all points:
|   slope of the pulldown table from 0 to 0.375 V, typ, clamps not added: 19.8 ohm
|   GND clamp passes 1 mA (typ) near -0.44 V on its own axis
|   rising waveform, R_fixture 50.0000, V_fixture 2.5000: 20-80 % time 280ps typ, 294ps min, 291ps max; typ from 0.794 V to 2.5 V
|   falling waveform, R_fixture 50.0000, V_fixture 2.5000: 20-80 % time 194ps typ, 234ps min, 138ps max; typ from 2.5 V to 0.794 V
[Pulldown]
|Voltage   I(typ)   I(min)   I(max)
-2.5V     -34.23mA   -24.11mA   -45.2mA
-1.06V    -31.95mA   -22.52mA   -42.19mA
-820mV    -30mA      -22.04mA   -36.53mA
-500mV    -25.32mA   -18.35mA   -33.11mA
-340mV    -18.82mA   -13.07mA   -25.3mA
220mV     11.7mA     7.847mA    16.11mA
540mV     25.69mA    16.99mA    35.83mA
860mV     35.89mA    23.41mA    50.64mA
1.18V     41.79mA    27.08mA    59.17mA
1.82V     45.8mA     29.73mA    64.58mA
4.14V     50.88mA    33.15mA    71.44mA
5V        60.2mA     38.75mA    74.42mA
[GND_clamp]
|Voltage   I(typ)   I(min)   I(max)
-2.5V     -564.7mA   -543.1mA   -585.2mA
-1.18V    -82.35mA   -79.03mA   -91.15mA
-1.14V    -74.88mA   -71.38mA   -83.96mA
-1.1V     -67.69mA   -63.94mA   -77.25mA
-980mV    -48.66mA   -43.36mA   -60.79mA
-820mV    -30.34mA   -22.65mA   -40.66mA
-700mV    -18.09mA   -11.63mA   -24.79mA
-620mV    -10.87mA   -6.335mA   -15.23mA
-540mV    -5.061mA   -2.654mA   -7.227mA
-460mV    -1.446mA   -714.8uA   -1.98mA
-300mV    -18.71uA   -15.93uA   -16.53uA
5V        0A         0A         0A
[Ramp]
| variable   typ   min   max
dV/dt_r  1.0236/0.2773n   0.7843/0.2912n   1.2045/0.2877n
dV/dt_f  1.0236/0.2006n   0.7831/0.2318n   1.2045/0.1365n
R_load = 50.0000
[Rising Waveform]
R_fixture=   50.0000
V_fixture=   2.5000
V_fixture_min=   2.3800
V_fixture_max=   2.6300
|time   V(typ)   V(min)   V(max)
0s        794.1mV    1.073V     622.4mV
505.1ps   794.1mV    1.073V     633.9mV
707.1ps   790.1mV    1.073V     1.931V
808.1ps   1.009V     1.073V     2.177V
1.01ns    2V         1.072V     2.407V
1.212ns   2.263V     1.194V     2.514V
1.414ns   2.365V     1.941V     2.568V
1.717ns   2.436V     2.232V     2.605V
2.525ns   2.49V      2.349V     2.628V
10ns      2.5V       2.38V      2.63V
[Falling Waveform]
R_fixture=   50.0000
V_fixture=   2.5000
V_fixture_min=   2.3800
V_fixture_max=   2.6300
|time   V(typ)   V(min)   V(max)
0s        2.5V       2.38V      2.63V
606.1ps   2.5V       2.38V      2.462V
707.1ps   2.5V       2.38V      1.302V
808.1ps   2.5V       2.38V      811mV
1.01ns    1.939V     2.38V      662.9mV
1.212ns   1.006V     2.38V      635.5mV
1.515ns   895.8mV    2.329V     625mV
1.818ns   835.9mV    1.329V     623mV
2.121ns   810.4mV    1.179V     622.6mV
10ns      794.1mV    1.075V     622.4mV
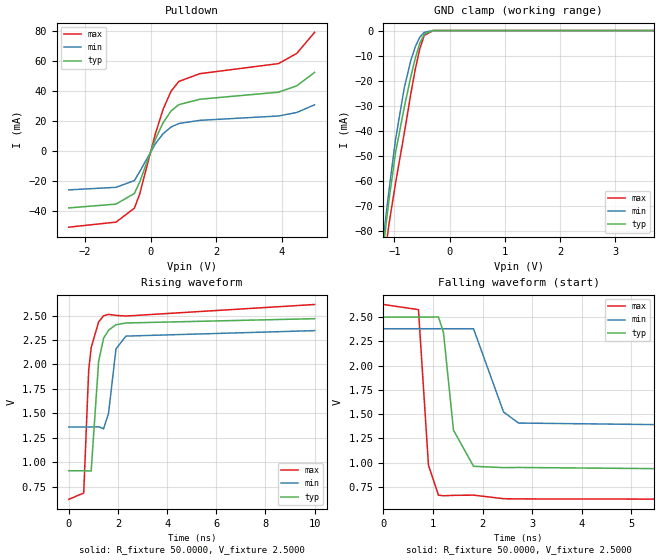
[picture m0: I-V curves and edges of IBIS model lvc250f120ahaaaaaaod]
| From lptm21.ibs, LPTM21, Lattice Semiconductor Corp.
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|   Model lvc250f120ahaaaaaaod
[Model]   lvc250f120ahaaaaaaod
Model_type   I/O_open_drain
Polarity   Non-Inverting
Enable   Active-Low
Vinl =   0.7000V
Vinh =   1.7000V
Vmeas =   1.2500V
Cref =   0.0F
Rref =   1.0000M
Vref =   0.0V
C_comp   4.2000pF   3.8000pF   7.5000pF
[Temperature Range]   25.0000   0.1050k   -40.0000
[Voltage Range]   2.5000V   2.3800V   2.6300V
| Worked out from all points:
|   slope of the pulldown table from 0 to 0.375 V, typ, clamps not added: 19.7 ohm
|   GND clamp passes 1 mA (typ) near -0.44 V on its own axis
|   rising waveform, R_fixture 50.0000, V_fixture 2.5000: 20-80 % time 277ps typ, 275ps min, 293ps max; typ from 0.914 V to 2.47 V
|   falling waveform, R_fixture 50.0000, V_fixture 2.5000: 20-80 % time 220ps typ, 285ps min, 153ps max; typ from 2.5 V to 0.919 V
[Pulldown]
|Voltage   I(typ)   I(min)   I(max)
-2.5V     -37.76mA   -25.74mA   -50.61mA
-1.06V    -35.24mA   -24.04mA   -47.25mA
-500mV    -28.13mA   -19.55mA   -37.97mA
-340mV    -20.67mA   -13.71mA   -28.69mA
140mV     8.019mA    5.024mA    11.59mA
380mV     19.17mA    11.78mA    28.17mA
620mV     26.91mA    16.22mA    40.1mA
860mV     31.14mA    18.55mA    46.64mA
1.5V      34.73mA    20.65mA    51.8mA
3.9V      39.45mA    23.56mA    58.52mA
4.46V     43.71mA    25.93mA    65.39mA
5V        52.66mA    31.04mA    79.38mA
[GND_clamp]
|Voltage   I(typ)   I(min)   I(max)
-2.5V     -564.7mA   -543mA     -585.2mA
-1.18V    -82.34mA   -79.02mA   -91.14mA
-1.14V    -74.87mA   -71.37mA   -83.95mA
-1.1V     -67.69mA   -63.93mA   -77.25mA
-980mV    -48.65mA   -43.36mA   -60.78mA
-820mV    -30.34mA   -22.64mA   -40.65mA
-700mV    -18.08mA   -11.62mA   -24.79mA
-620mV    -10.86mA   -6.332mA   -15.22mA
-540mV    -5.058mA   -2.652mA   -7.223mA
-460mV    -1.444mA   -713.9uA   -1.977mA
-300mV    -18.65uA   -15.9uA    -16.44uA
5V        0A         0A         0A
[Ramp]
| variable   typ   min   max
dV/dt_r  0.9323/0.2746n   0.5909/0.2719n   1.1947/0.2897n
dV/dt_f  0.9488/0.2175n   0.6082/0.2818n   1.2049/0.1518n
R_load = 50.0000
[Rising Waveform]
R_fixture=   50.0000
V_fixture=   2.5000
V_fixture_min=   2.3800
V_fixture_max=   2.6300
|time   V(typ)   V(min)   V(max)
0s        914.1mV    1.361V     621.8mV
606.1ps   914.1mV    1.361V     686.3mV
808.1ps   912mV      1.361V     1.939V
909.1ps   910.9mV    1.361V     2.172V
1.212ns   2.029V     1.364V     2.434V
1.414ns   2.268V     1.343V     2.498V
1.616ns   2.35V      1.5V       2.512V
1.919ns   2.406V     2.159V     2.502V
2.323ns   2.424V     2.29V      2.495V
10ns      2.468V     2.346V     2.613V
[Falling Waveform]
R_fixture=   50.0000
V_fixture=   2.5000
V_fixture_min=   2.3800
V_fixture_max=   2.6300
|time   V(typ)   V(min)   V(max)
0s        2.5V       2.38V      2.63V
707.1ps   2.5V       2.38V      2.577V
909.1ps   2.5V       2.38V      973.8mV
1.111ns   2.502V     2.38V      664.1mV
1.212ns   2.341V     2.38V      658.7mV
1.414ns   1.335V     2.38V      662.6mV
1.818ns   962.4mV    2.38V      665mV
2.424ns   948.5mV    1.522V     628.4mV
2.727ns   950.2mV    1.408V     625.9mV
10ns      918.6mV    1.366V     621.8mV
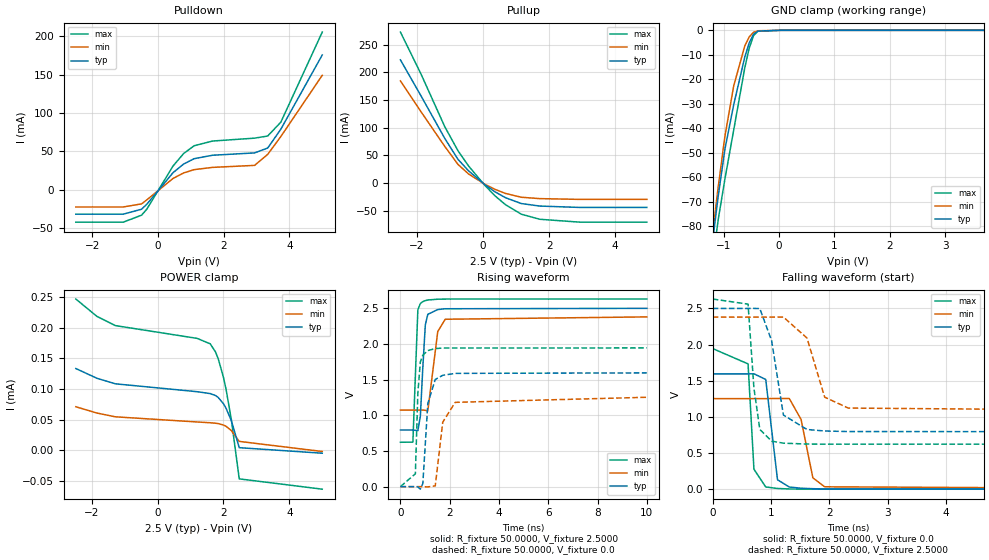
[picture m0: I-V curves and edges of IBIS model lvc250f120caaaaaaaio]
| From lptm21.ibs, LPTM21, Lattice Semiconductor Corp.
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|   Model lvc250f120caaaaaaaio
[Model]   lvc250f120caaaaaaaio
Model_type   I/O
Polarity   Non-Inverting
Enable   Active-Low
Vinl =   0.7000V
Vinh =   1.7000V
Vmeas =   1.2500V
Cref =   0.0F
Rref =   1.0000M
Vref =   0.0V
C_comp   4.2000pF   3.8000pF   7.5000pF
[Temperature Range]   25.0000   0.1050k   -40.0000
[Voltage Range]   2.5000V   2.3800V   2.6300V
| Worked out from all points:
|   slope of the pulldown table from 0 to 0.375 V, typ, clamps not added: 19.9 ohm
|   slope of the pullup table from 0 to 0.375 V, typ, clamps not added: 23.5 ohm
|   GND clamp passes 1 mA (typ) near -0.44 V on its own axis
|   rising waveform, R_fixture 50.0000, V_fixture 2.5000: 20-80 % time 162ps typ, 239ps min, 131ps max; typ from 0.794 V to 2.5 V
|   rising waveform, R_fixture 50.0000, V_fixture 0.0: 20-80 % time 213ps typ, 295ps min, 139ps max; typ from 0 V to 1.59 V
|   falling waveform, R_fixture 50.0000, V_fixture 0.0: 20-80 % time 135ps typ, 185ps min, 80.9ps max; typ from 1.59 V to 0 V
|   falling waveform, R_fixture 50.0000, V_fixture 2.5000: 20-80 % time 192ps typ, 268ps min, 138ps max; typ from 2.5 V to 0.794 V
[Pulldown]
|Voltage   I(typ)   I(min)   I(max)
-2.5V     -31.73mA   -22.32mA   -42.15mA
-1.06V    -31.73mA   -22.32mA   -42.15mA
-500mV    -25.25mA   -18.31mA   -33.02mA
-340mV    -18.74mA   -13.02mA   -25.17mA
460mV     22.46mA    14.92mA    31.19mA
780mV     33.63mA    22.02mA    47.29mA
1.1V      40.62mA    26.36mA    57.47mA
1.66V     45.1mA     29.27mA    63.61mA
2.94V     48.13mA    31.88mA    67.38mA
3.34V     54.52mA    46.26mA    70.18mA
3.74V     79.1mA     69.54mA    88.27mA
5V        175.8mA    149.3mA    205.6mA
[Pullup]
|Voltage   I(typ)   I(min)   I(max)
-2.5V     222.7mA    184.8mA    272.9mA
-1.88V    158mA      129.3mA    197.5mA
-1.16V    81.11mA    66.63mA    102.3mA
-760mV    43.19mA    34.05mA    58.78mA
-440mV    22.5mA     16.77mA    31.27mA
40mV      -1.991mA   -1.415mA   -2.912mA
360mV     -15.53mA   -11.08mA   -22.69mA
680mV     -26.23mA   -18.51mA   -38.85mA
1.16V     -36.81mA   -25.42mA   -56.04mA
1.72V     -41.32mA   -27.89mA   -65.19mA
2.92V     -43.8mA    -29.26mA   -70.35mA
4.96V     -43.8mA    -29.26mA   -70.46mA
[GND_clamp]
|Voltage   I(typ)   I(min)   I(max)
-2.5V     -564.7mA   -543.1mA   -585.2mA
-1.18V    -82.37mA   -79.05mA   -91.19mA
-1.14V    -74.91mA   -71.4mA    -84.01mA
-1.1V     -67.72mA   -63.96mA   -77.3mA
-980mV    -48.69mA   -43.39mA   -60.85mA
-820mV    -30.38mA   -22.68mA   -40.71mA
-620mV    -10.92mA   -6.374mA   -15.3mA
-540mV    -5.123mA   -2.7mA     -7.317mA
-460mV    -1.524mA   -767.4uA   -2.097mA
-380mV    -292.5uA   -172.6uA   -366.3uA
20mV      0A         0A         0A
5V        0A         0A         0A
[POWER_clamp]
|Voltage   I(typ)   I(min)   I(max)
-2.48V    133.3uA    71.04uA    246.4uA
-1.84V    117.4uA    60.8uA     218.2uA
-1.28V    108.4uA    54.67uA    203.2uA
1.2V      95.59uA    46.28uA    182.4uA
1.6V      92.47uA    45.01uA    173.5uA
1.76V     89.3uA     44.22uA    160.2uA
1.84V     86.28uA    43.64uA    149.5uA
2V        76.02uA    41.32uA    119.2uA
2.08V     68.53uA    39.17uA    99.45uA
2.24V     48.41uA    32.29uA    50.16uA
2.48V     4.411uA    14.65uA    -46.36uA
5V        -4.578uA   -1.793uA   -63.13uA
[Ramp]
| variable   typ   min   max
dV/dt_r  0.9572/0.2105n   0.7518/0.2919n   1.1669/0.1374n
dV/dt_f  1.0236/0.1898n   0.7843/0.2651n   1.2045/0.1367n
R_load = 50.0000
[Rising Waveform]
R_fixture=   50.0000
V_fixture=   2.5000
V_fixture_min=   2.3800
V_fixture_max=   2.6300
|time   V(typ)   V(min)   V(max)
0s        794.1mV    1.073V     622.4mV
505.1ps   794.1mV    1.073V     624.1mV
707.1ps   785.4mV    1.073V     2.479V
808.1ps   987.4mV    1.073V     2.567V
909.1ps   1.674V     1.074V     2.594V
1.01ns    2.269V     1.071V     2.608V
1.111ns   2.416V     1.06V      2.617V
1.515ns   2.483V     2.175V     2.628V
1.818ns   2.494V     2.347V     2.63V
10ns      2.5V       2.38V      2.63V
[Rising Waveform]
R_fixture=   50.0000
V_fixture=   0.0
V_fixture_min=   0.0
V_fixture_max=   0.0
|time   V(typ)   V(min)   V(max)
0s        495.7nV    694.4nV    398.1nV
606.1ps   -99.1uV    744.1nV    180.6mV
707.1ps   -3.613mV   9.017uV    1.312V
808.1ps   -35.32mV   15.45uV    1.749V
909.1ps   44.28mV    -4.197uV   1.843V
1.111ns   1.166V     -4mV       1.908V
1.414ns   1.503V     11.42mV    1.936V
1.717ns   1.561V     903.9mV    1.943V
2.222ns   1.588V     1.182V     1.944V
10ns      1.595V     1.253V     1.945V
[Falling Waveform]
R_fixture=   50.0000
V_fixture=   0.0
V_fixture_min=   0.0
V_fixture_max=   0.0
|time   V(typ)   V(min)   V(max)
0s        1.595V     1.253V     1.945V
606.1ps   1.595V     1.253V     1.733V
707.1ps   1.596V     1.253V     275.8mV
909.1ps   1.518V     1.253V     30.43mV
1.111ns   129.8mV    1.254V     9.663mV
1.313ns   29.66mV    1.254V     3.015mV
1.515ns   13.34mV    964.2mV    940.4uV
1.717ns   6.448mV    156.6mV    320.5uV
1.919ns   3.103mV    32.8mV     131.1uV
10ns      -15.58uV   3.714uV    -16.25uV
[Falling Waveform]
R_fixture=   50.0000
V_fixture=   2.5000
V_fixture_min=   2.3800
V_fixture_max=   2.6300
|time   V(typ)   V(min)   V(max)
0s        2.5V       2.38V      2.63V
606.1ps   2.5V       2.38V      2.56V
707.1ps   2.501V     2.38V      1.394V
808.1ps   2.498V     2.38V      825.6mV
1.01ns    2.054V     2.38V      664.1mV
1.212ns   1.026V     2.381V     636.3mV
1.616ns   825.4mV    2.091V     624.1mV
1.919ns   804.8mV    1.273V     622.8mV
2.323ns   797.1mV    1.122V     622.5mV
10ns      794.1mV    1.073V     622.4mV
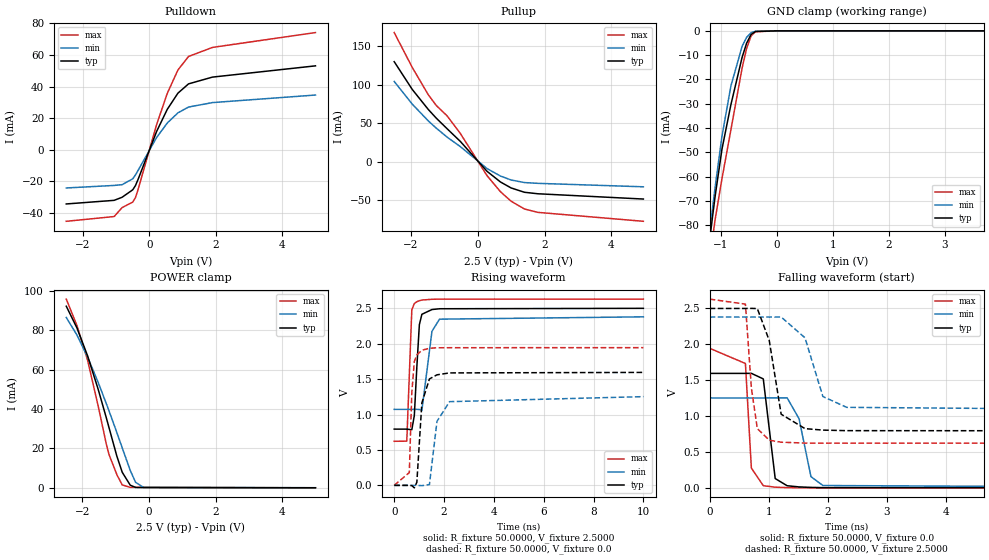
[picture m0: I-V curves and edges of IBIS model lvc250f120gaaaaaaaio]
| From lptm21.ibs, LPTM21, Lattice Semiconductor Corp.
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|   Model lvc250f120gaaaaaaaio
[Model]   lvc250f120gaaaaaaaio
Model_type   I/O
Polarity   Non-Inverting
Enable   Active-Low
Vinl =   0.7000V
Vinh =   1.7000V
Vmeas =   1.2500V
Cref =   0.0F
Rref =   1.0000M
Vref =   0.0V
C_comp   4.2000pF   3.8000pF   7.5000pF
[Temperature Range]   25.0000   0.1050k   -40.0000
[Voltage Range]   2.5000V   2.3800V   2.6300V
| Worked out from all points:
|   slope of the pulldown table from 0 to 0.375 V, typ, clamps not added: 19.9 ohm
|   slope of the pullup table from 0 to 0.375 V, typ, clamps not added: 23.5 ohm
|   GND clamp passes 1 mA (typ) near -0.44 V on its own axis
|   POWER clamp passes 1 mA (typ) near -0.53 V on its own axis
|   rising waveform, R_fixture 50.0000, V_fixture 2.5000: 20-80 % time 162ps typ, 239ps min, 131ps max; typ from 0.794 V to 2.5 V
|   rising waveform, R_fixture 50.0000, V_fixture 0.0: 20-80 % time 213ps typ, 295ps min, 139ps max; typ from 0 V to 1.59 V
|   falling waveform, R_fixture 50.0000, V_fixture 0.0: 20-80 % time 135ps typ, 185ps min, 80.9ps max; typ from 1.59 V to 0 V
|   falling waveform, R_fixture 50.0000, V_fixture 2.5000: 20-80 % time 192ps typ, 268ps min, 138ps max; typ from 2.5 V to 0.794 V
[Pulldown]
|Voltage   I(typ)   I(min)   I(max)
-2.5V     -34.19mA   -24.09mA   -45.15mA
-1.06V    -31.91mA   -22.49mA   -42.15mA
-820mV    -29.96mA   -22.01mA   -36.49mA
-500mV    -25.25mA   -18.31mA   -33.02mA
-420mV    -22.65mA   -15.93mA   -30.26mA
-340mV    -18.74mA   -13.02mA   -25.17mA
220mV     11.66mA    7.825mA    16.03mA
540mV     25.61mA    16.95mA    35.68mA
860mV     35.8mA     23.37mA    50.46mA
1.18V     41.69mA    27.04mA    58.99mA
1.9V      45.96mA    29.86mA    64.72mA
5V        53.07mA    34.63mA    74.1mA
[Pullup]
|Voltage   I(typ)   I(min)   I(max)
-2.5V     130mA      104.3mA    167.8mA
-1.96V    93.95mA    74.88mA    122.6mA
-1.48V    67.96mA    53.11mA    87.04mA
-1.24V    56.6mA     43.66mA    73.07mA
-920mV    43.06mA    32.15mA    59.8mA
-520mV    26.41mA    19.65mA    36.72mA
280mV     -12.41mA   -8.877mA   -18.08mA
680mV     -26.23mA   -18.51mA   -38.85mA
1V        -34.02mA   -23.68mA   -51.27mA
1.4V      -39.64mA   -27.03mA   -61.36mA
1.8V      -41.57mA   -28.04mA   -65.74mA
4.96V     -48.43mA   -32.53mA   -77.34mA
[GND_clamp]
|Voltage   I(typ)   I(min)   I(max)
-2.5V     -564.7mA   -543.1mA   -585.2mA
-1.18V    -82.37mA   -79.05mA   -91.19mA
-1.14V    -74.91mA   -71.4mA    -84.01mA
-1.1V     -67.72mA   -63.96mA   -77.3mA
-980mV    -48.69mA   -43.39mA   -60.85mA
-820mV    -30.38mA   -22.68mA   -40.71mA
-620mV    -10.92mA   -6.374mA   -15.3mA
-540mV    -5.123mA   -2.7mA     -7.317mA
-460mV    -1.524mA   -767.4uA   -2.097mA
-380mV    -292.5uA   -172.6uA   -366.3uA
20mV      0A         0A         0A
5V        0A         0A         0A
[POWER_clamp]
|Voltage   I(typ)   I(min)   I(max)
-2.48V    92.22mA    86.5mA     95.83mA
-2.16V    81.19mA    77.59mA    82.43mA
-1.84V    67mA       66.38mA    64.75mA
-1.52V    49.86mA    53.4mA     41.33mA
-1.28V    35.63mA    42.81mA    22.28mA
-1.2V     30.7mA     39.17mA    17mA
-960mV    15.93mA    27.93mA    6.582mA
-800mV    7.851mA    20.23mA    1.424mA
-560mV    1.299mA    8.796mA    199.2uA
-400mV    169.6uA    2.771mA    193.9uA
-160mV    101.6uA    144.1uA    192.3uA
5V        -4.578uA   -1.793uA   -63.13uA
[Ramp]
| variable   typ   min   max
dV/dt_r  0.9572/0.2105n   0.7518/0.2919n   1.1669/0.1374n
dV/dt_f  1.0236/0.1898n   0.7843/0.2651n   1.2045/0.1367n
R_load = 50.0000
[Rising Waveform]
R_fixture=   50.0000
V_fixture=   2.5000
V_fixture_min=   2.3800
V_fixture_max=   2.6300
|time   V(typ)   V(min)   V(max)
0s        794.1mV    1.073V     622.4mV
505.1ps   794.1mV    1.073V     624.1mV
707.1ps   785.4mV    1.073V     2.479V
808.1ps   987.4mV    1.073V     2.567V
909.1ps   1.674V     1.074V     2.594V
1.01ns    2.269V     1.071V     2.608V
1.111ns   2.416V     1.06V      2.617V
1.515ns   2.483V     2.175V     2.628V
1.818ns   2.494V     2.347V     2.63V
10ns      2.5V       2.38V      2.63V
[Rising Waveform]
R_fixture=   50.0000
V_fixture=   0.0
V_fixture_min=   0.0
V_fixture_max=   0.0
|time   V(typ)   V(min)   V(max)
0s        495.7nV    694.4nV    398.1nV
606.1ps   -99.1uV    744.1nV    180.6mV
707.1ps   -3.613mV   9.017uV    1.312V
808.1ps   -35.32mV   15.45uV    1.749V
909.1ps   44.28mV    -4.197uV   1.843V
1.111ns   1.166V     -4mV       1.908V
1.414ns   1.503V     11.42mV    1.936V
1.717ns   1.561V     903.9mV    1.943V
2.222ns   1.588V     1.182V     1.944V
10ns      1.595V     1.253V     1.945V
[Falling Waveform]
R_fixture=   50.0000
V_fixture=   0.0
V_fixture_min=   0.0
V_fixture_max=   0.0
|time   V(typ)   V(min)   V(max)
0s        1.595V     1.253V     1.945V
606.1ps   1.595V     1.253V     1.733V
707.1ps   1.596V     1.253V     275.8mV
909.1ps   1.518V     1.253V     30.43mV
1.111ns   129.8mV    1.254V     9.663mV
1.313ns   29.66mV    1.254V     3.015mV
1.515ns   13.34mV    964.2mV    940.4uV
1.717ns   6.448mV    156.6mV    320.5uV
1.919ns   3.103mV    32.8mV     131.1uV
10ns      -15.58uV   3.714uV    -16.25uV
[Falling Waveform]
R_fixture=   50.0000
V_fixture=   2.5000
V_fixture_min=   2.3800
V_fixture_max=   2.6300
|time   V(typ)   V(min)   V(max)
0s        2.5V       2.38V      2.63V
606.1ps   2.5V       2.38V      2.56V
707.1ps   2.501V     2.38V      1.394V
808.1ps   2.498V     2.38V      825.6mV
1.01ns    2.054V     2.38V      664.1mV
1.212ns   1.026V     2.381V     636.3mV
1.616ns   825.4mV    2.091V     624.1mV
1.919ns   804.8mV    1.273V     622.8mV
2.323ns   797.1mV    1.122V     622.5mV
10ns      794.1mV    1.073V     622.4mV
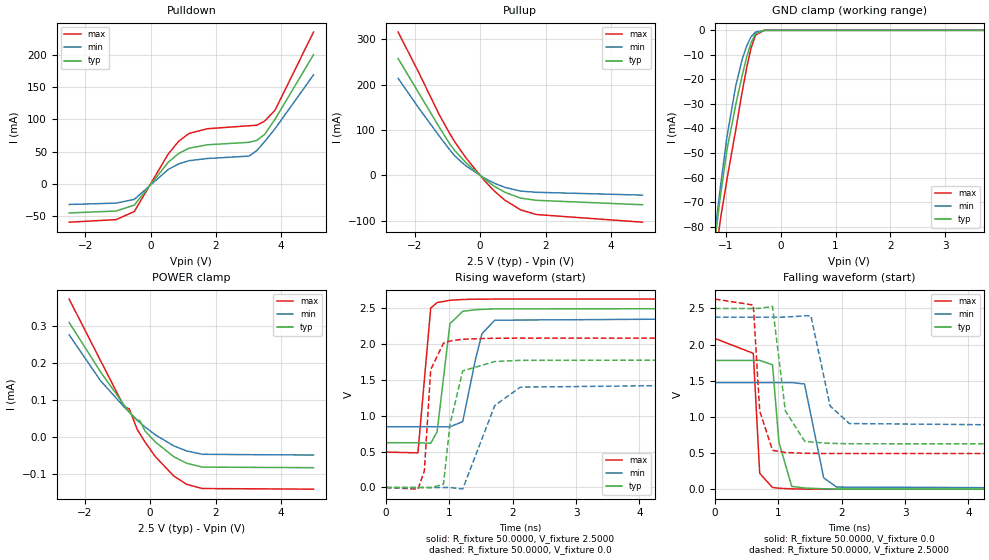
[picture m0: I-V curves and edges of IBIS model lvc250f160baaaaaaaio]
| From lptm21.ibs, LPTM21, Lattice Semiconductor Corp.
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|   Model lvc250f160baaaaaaaio
[Model]   lvc250f160baaaaaaaio
Model_type   I/O
Polarity   Non-Inverting
Enable   Active-Low
Vinl =   0.7000V
Vinh =   1.7000V
Vmeas =   1.2500V
Cref =   0.0F
Rref =   1.0000M
Vref =   0.0V
C_comp   4.2000pF   3.8000pF   7.5000pF
[Temperature Range]   25.0000   0.1050k   -40.0000
[Voltage Range]   2.5000V   2.3800V   2.6300V
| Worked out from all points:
|   slope of the pulldown table from 0 to 0.375 V, typ, clamps not added: 15.3 ohm
|   slope of the pullup table from 0 to 0.375 V, typ, clamps not added: 18.1 ohm
|   GND clamp passes 1 mA (typ) near -0.44 V on its own axis
|   rising waveform, R_fixture 50.0000, V_fixture 2.5000: 20-80 % time 151ps typ, 227ps min, 128ps max; typ from 0.625 V to 2.5 V
|   rising waveform, R_fixture 50.0000, V_fixture 0.0: 20-80 % time 162ps typ, 247ps min, 94.8ps max; typ from 0 V to 1.78 V
|   falling waveform, R_fixture 50.0000, V_fixture 0.0: 20-80 % time 129ps typ, 166ps min, 76.1ps max; typ from 1.78 V to 0 V
|   falling waveform, R_fixture 50.0000, V_fixture 2.5000: 20-80 % time 161ps typ, 218ps min, 111ps max; typ from 2.5 V to 0.625 V
[Pulldown]
|Voltage   I(typ)   I(min)   I(max)
-2.5V     -44.98mA   -31.87mA   -59.28mA
-1.06V    -42mA      -29.76mA   -55.31mA
-500mV    -32.87mA   -23.94mA   -42.77mA
540mV     33.48mA    22.33mA    46.22mA
860mV     47.12mA    30.94mA    65.97mA
1.18V     55.33mA    35.97mA    78.1mA
1.74V     60.59mA    39.34mA    85.43mA
3.02V     64.38mA    43.06mA    90.07mA
3.26V     67.39mA    51.62mA    90.9mA
3.5V      76.68mA    65.54mA    97.24mA
3.82V     100.2mA    85.57mA    114.3mA
5V        200.1mA    168.8mA    235.1mA
[Pullup]
|Voltage   I(typ)   I(min)   I(max)
-2.5V     257.9mA    214.2mA    316.2mA
-1.88V    183.1mA    149.8mA    228.3mA
-1.24V    106mA      86.42mA    133.3mA
-920mV    69.18mA    56.2mA     91.87mA
-760mV    54.01mA    42.27mA    72.88mA
-440mV    28.99mA    21.75mA    39.87mA
120mV     -7.165mA   -5.207mA   -10.2mA
440mV     -23.89mA   -17.16mA   -34.55mA
760mV     -37.08mA   -26.27mA   -54.54mA
1.24V     -49.93mA   -34.5mA    -75.81mA
1.72V     -54.77mA   -37.04mA   -86.09mA
4.96V     -64.54mA   -43.28mA   -103mA
[GND_clamp]
|Voltage   I(typ)   I(min)   I(max)
-2.5V     -564.6mA   -543.1mA   -585.1mA
-1.18V    -82.28mA   -79mA      -91.03mA
-1.14V    -74.81mA   -71.35mA   -83.85mA
-1.1V     -67.63mA   -63.91mA   -77.15mA
-980mV    -48.6mA    -43.33mA   -60.69mA
-820mV    -30.29mA   -22.62mA   -40.55mA
-700mV    -18.04mA   -11.6mA    -24.7mA
-620mV    -10.82mA   -6.314mA   -15.14mA
-540mV    -5.025mA   -2.64mA    -7.154mA
-460mV    -1.426mA   -708.3uA   -1.934mA
-300mV    -17.76uA   -15.73uA   -12.8uA
5V        0A         0A         0A
[POWER_clamp]
|Voltage   I(typ)   I(min)   I(max)
-2.48V    310.4uA    276.7uA    373.7uA
-1.52V    176.3uA    152.3uA    206.9uA
-800mV    86.61uA    81.35uA    82.18uA
-640mV    66.94uA    66.91uA    75.79uA
-400mV    44.51uA    45.44uA    20.86uA
-320mV    44.51uA    38.99uA    8.918uA
-160mV    16.15uA    26.85uA    -13.85uA
160mV     -14.29uA   5.152uA    -53.97uA
720mV     -53.87uA   -24.56uA   -106.2uA
1.12V     -71.9uA    -38.53uA   -129.1uA
1.6V      -82.26uA   -47.53uA   -140.4uA
5V        -83.86uA   -49.55uA   -142.1uA
[Ramp]
| variable   typ   min   max
dV/dt_r  1.0688/0.1604n   0.8847/0.2443n   1.2507/93.8258p
dV/dt_f  1.1250/0.1592n   0.9191/0.2160n   1.2817/0.1102n
R_load = 50.0000
[Rising Waveform]
R_fixture=   50.0000
V_fixture=   2.5000
V_fixture_min=   2.3800
V_fixture_max=   2.6300
|time   V(typ)   V(min)   V(max)
0s        625.1mV    848.2mV    493.8mV
505.1ps   625.1mV    848.2mV    483.9mV
707.1ps   617.1mV    848.2mV    2.504V
808.1ps   777mV      848.3mV    2.581V
1.01ns    2.285V     846.8mV    2.613V
1.212ns   2.459V     919.1mV    2.624V
1.414ns   2.481V     1.791V     2.628V
1.515ns   2.486V     2.145V     2.629V
1.717ns   2.493V     2.335V     2.63V
10ns      2.5V       2.38V      2.63V
[Rising Waveform]
R_fixture=   50.0000
V_fixture=   0.0
V_fixture_min=   0.0
V_fixture_max=   0.0
|time   V(typ)   V(min)   V(max)
0s        394.5nV    565.3nV    312nV
505.1ps   17.53uV    728.7nV    -23.3mV
606.1ps   -153.3uV   722.6nV    227.1mV
707.1ps   -3.764mV   9.302uV    1.646V
909.1ps   47.24mV    -32.83uV   2.015V
1.01ns    876.9mV    -402.3uV   2.044V
1.212ns   1.627V     -20.32mV   2.07V
1.717ns   1.758V     1.143V     2.083V
2.121ns   1.775V     1.401V     2.084V
10ns      1.781V     1.474V     2.084V
[Falling Waveform]
R_fixture=   50.0000
V_fixture=   0.0
V_fixture_min=   0.0
V_fixture_max=   0.0
|time   V(typ)   V(min)   V(max)
0s        1.781V     1.474V     2.085V
606.1ps   1.781V     1.474V     1.879V
707.1ps   1.782V     1.474V     218.8mV
909.1ps   1.721V     1.474V     23.28mV
1.01ns    651.4mV    1.474V     13.07mV
1.212ns   38.57mV    1.475V     4.117mV
1.414ns   15.95mV    1.455V     1.284mV
1.717ns   5.3mV      156.1mV    203.4uV
1.919ns   2.469mV    29.32mV    71.82uV
10ns      15.52uV    -1.266uV   20.45uV
[Falling Waveform]
R_fixture=   50.0000
V_fixture=   2.5000
V_fixture_min=   2.3800
V_fixture_max=   2.6300
|time   V(typ)   V(min)   V(max)
0s        2.5V       2.38V      2.63V
606.1ps   2.5V       2.38V      2.547V
707.1ps   2.501V     2.38V      1.082V
909.1ps   2.529V     2.38V      538.3mV
1.111ns   1.085V     2.381V     507.8mV
1.414ns   665.1mV    2.397V     496.4mV
1.515ns   652.2mV    2.397V     495.3mV
1.818ns   634.3mV    1.151V     494.1mV
2.121ns   628.4mV    907.9mV    493.9mV
10ns      625.1mV    848.2mV    493.8mV
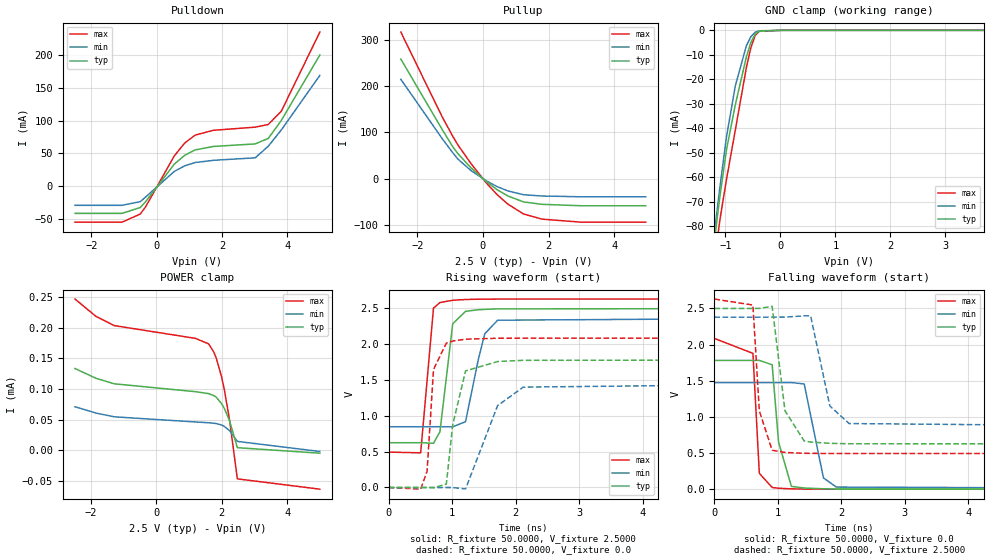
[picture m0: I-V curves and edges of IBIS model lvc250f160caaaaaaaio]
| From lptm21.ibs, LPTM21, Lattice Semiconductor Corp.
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|   Model lvc250f160caaaaaaaio
[Model]   lvc250f160caaaaaaaio
Model_type   I/O
Polarity   Non-Inverting
Enable   Active-Low
Vinl =   0.7000V
Vinh =   1.7000V
Vmeas =   1.2500V
Cref =   0.0F
Rref =   1.0000M
Vref =   0.0V
C_comp   4.2000pF   3.8000pF   7.5000pF
[Temperature Range]   25.0000   0.1050k   -40.0000
[Voltage Range]   2.5000V   2.3800V   2.6300V
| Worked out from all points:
|   slope of the pulldown table from 0 to 0.375 V, typ, clamps not added: 15.3 ohm
|   slope of the pullup table from 0 to 0.375 V, typ, clamps not added: 18 ohm
|   GND clamp passes 1 mA (typ) near -0.44 V on its own axis
|   rising waveform, R_fixture 50.0000, V_fixture 2.5000: 20-80 % time 151ps typ, 227ps min, 128ps max; typ from 0.625 V to 2.5 V
|   rising waveform, R_fixture 50.0000, V_fixture 0.0: 20-80 % time 162ps typ, 247ps min, 94.8ps max; typ from 0 V to 1.78 V
|   falling waveform, R_fixture 50.0000, V_fixture 0.0: 20-80 % time 129ps typ, 166ps min, 76.1ps max; typ from 1.78 V to 0 V
|   falling waveform, R_fixture 50.0000, V_fixture 2.5000: 20-80 % time 161ps typ, 218ps min, 111ps max; typ from 2.5 V to 0.625 V
[Pulldown]
|Voltage   I(typ)   I(min)   I(max)
-2.5V     -41.83mA   -29.52mA   -55.3mA
-1.06V    -41.83mA   -29.52mA   -55.3mA
-500mV    -32.86mA   -23.93mA   -42.76mA
-340mV    -24.15mA   -16.95mA   -32.07mA
540mV     33.32mA    22.25mA    45.93mA
860mV     46.94mA    30.84mA    65.66mA
1.18V     55.16mA    35.88mA    77.79mA
1.74V     60.44mA    39.26mA    85.14mA
3.02V     64.33mA    43.06mA    89.95mA
3.42V     72.65mA    60.74mA    94.03mA
3.82V     100.2mA    85.64mA    114.3mA
5V        200.2mA    169mA      235.2mA
[Pullup]
|Voltage   I(typ)   I(min)   I(max)
-2.5V     258.1mA    214.4mA    316.4mA
-1.24V    106.1mA    86.47mA    133.3mA
-920mV    69.18mA    56.22mA    91.82mA
-760mV    53.99mA    42.27mA    72.8mA
-360mV    23.32mA    17.41mA    32.33mA
120mV     -7.275mA   -5.262mA   -10.41mA
440mV     -24.03mA   -17.23mA   -34.79mA
760mV     -37.23mA   -26.35mA   -54.81mA
1.24V     -50.1mA    -34.59mA   -76.12mA
1.8V      -55.29mA   -37.33mA   -87.21mA
3V        -58.36mA   -39mA      -93.83mA
4.96V     -58.36mA   -39mA      -93.83mA
[GND_clamp]
|Voltage   I(typ)   I(min)   I(max)
-2.5V     -564.7mA   -543.1mA   -585.2mA
-1.18V    -82.37mA   -79.05mA   -91.19mA
-1.14V    -74.91mA   -71.4mA    -84.01mA
-1.1V     -67.72mA   -63.96mA   -77.3mA
-980mV    -48.69mA   -43.39mA   -60.85mA
-820mV    -30.38mA   -22.68mA   -40.71mA
-620mV    -10.92mA   -6.374mA   -15.3mA
-540mV    -5.123mA   -2.7mA     -7.317mA
-460mV    -1.524mA   -767.4uA   -2.097mA
-380mV    -292.5uA   -172.6uA   -366.3uA
20mV      0A         0A         0A
5V        0A         0A         0A
[POWER_clamp]
|Voltage   I(typ)   I(min)   I(max)
-2.48V    133.3uA    71.04uA    246.4uA
-1.84V    117.4uA    60.8uA     218.2uA
-1.28V    108.4uA    54.67uA    203.2uA
1.2V      95.59uA    46.28uA    182.4uA
1.6V      92.47uA    45.01uA    173.5uA
1.76V     89.3uA     44.22uA    160.2uA
1.84V     86.28uA    43.64uA    149.5uA
2V        76.02uA    41.32uA    119.2uA
2.08V     68.53uA    39.17uA    99.45uA
2.24V     48.41uA    32.29uA    50.16uA
2.48V     4.411uA    14.65uA    -46.36uA
5V        -4.578uA   -1.793uA   -63.13uA
[Ramp]
| variable   typ   min   max
dV/dt_r  1.0688/0.1604n   0.8847/0.2443n   1.2507/93.8258p
dV/dt_f  1.1250/0.1592n   0.9191/0.2160n   1.2817/0.1102n
R_load = 50.0000
[Rising Waveform]
R_fixture=   50.0000
V_fixture=   2.5000
V_fixture_min=   2.3800
V_fixture_max=   2.6300
|time   V(typ)   V(min)   V(max)
0s        625.1mV    848.2mV    493.8mV
505.1ps   625.1mV    848.2mV    483.9mV
707.1ps   617.1mV    848.2mV    2.504V
808.1ps   777mV      848.3mV    2.581V
1.01ns    2.285V     846.8mV    2.613V
1.212ns   2.459V     919.1mV    2.624V
1.414ns   2.481V     1.791V     2.628V
1.515ns   2.486V     2.145V     2.629V
1.717ns   2.493V     2.335V     2.63V
10ns      2.5V       2.38V      2.63V
[Rising Waveform]
R_fixture=   50.0000
V_fixture=   0.0
V_fixture_min=   0.0
V_fixture_max=   0.0
|time   V(typ)   V(min)   V(max)
0s        394.5nV    565.3nV    312nV
505.1ps   17.53uV    728.7nV    -23.3mV
606.1ps   -153.3uV   722.6nV    227.1mV
707.1ps   -3.764mV   9.302uV    1.646V
909.1ps   47.24mV    -32.83uV   2.015V
1.01ns    876.9mV    -402.3uV   2.044V
1.212ns   1.627V     -20.32mV   2.07V
1.717ns   1.758V     1.143V     2.083V
2.121ns   1.775V     1.401V     2.084V
10ns      1.781V     1.474V     2.084V
[Falling Waveform]
R_fixture=   50.0000
V_fixture=   0.0
V_fixture_min=   0.0
V_fixture_max=   0.0
|time   V(typ)   V(min)   V(max)
0s        1.781V     1.474V     2.085V
606.1ps   1.781V     1.474V     1.879V
707.1ps   1.782V     1.474V     218.8mV
909.1ps   1.721V     1.474V     23.28mV
1.01ns    651.4mV    1.474V     13.07mV
1.212ns   38.57mV    1.475V     4.117mV
1.414ns   15.95mV    1.455V     1.284mV
1.717ns   5.3mV      156.1mV    203.4uV
1.919ns   2.469mV    29.32mV    71.82uV
10ns      15.52uV    -1.266uV   20.45uV
[Falling Waveform]
R_fixture=   50.0000
V_fixture=   2.5000
V_fixture_min=   2.3800
V_fixture_max=   2.6300
|time   V(typ)   V(min)   V(max)
0s        2.5V       2.38V      2.63V
606.1ps   2.5V       2.38V      2.547V
707.1ps   2.501V     2.38V      1.082V
909.1ps   2.529V     2.38V      538.3mV
1.111ns   1.085V     2.381V     507.8mV
1.414ns   665.1mV    2.397V     496.4mV
1.515ns   652.2mV    2.397V     495.3mV
1.818ns   634.3mV    1.151V     494.1mV
2.121ns   628.4mV    907.9mV    493.9mV
10ns      625.1mV    848.2mV    493.8mV
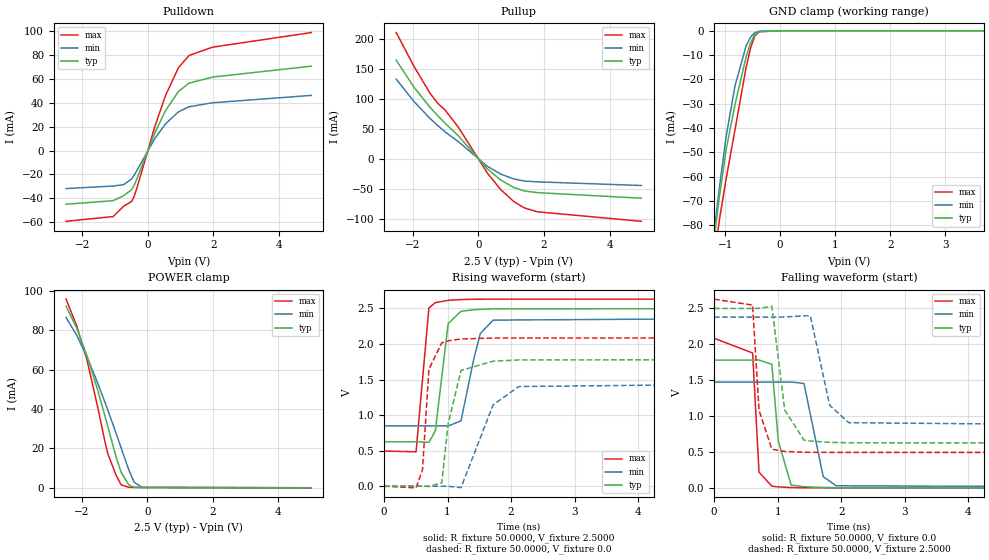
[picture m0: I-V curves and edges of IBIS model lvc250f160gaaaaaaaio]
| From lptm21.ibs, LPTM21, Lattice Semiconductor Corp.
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|   Model lvc250f160gaaaaaaaio
[Model]   lvc250f160gaaaaaaaio
Model_type   I/O
Polarity   Non-Inverting
Enable   Active-Low
Vinl =   0.7000V
Vinh =   1.7000V
Vmeas =   1.2500V
Cref =   0.0F
Rref =   1.0000M
Vref =   0.0V
C_comp   4.2000pF   3.8000pF   7.5000pF
[Temperature Range]   25.0000   0.1050k   -40.0000
[Voltage Range]   2.5000V   2.3800V   2.6300V
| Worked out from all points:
|   slope of the pulldown table from 0 to 0.375 V, typ, clamps not added: 15.3 ohm
|   slope of the pullup table from 0 to 0.375 V, typ, clamps not added: 18 ohm
|   GND clamp passes 1 mA (typ) near -0.44 V on its own axis
|   POWER clamp passes 1 mA (typ) near -0.53 V on its own axis
|   rising waveform, R_fixture 50.0000, V_fixture 2.5000: 20-80 % time 151ps typ, 227ps min, 128ps max; typ from 0.625 V to 2.5 V
|   rising waveform, R_fixture 50.0000, V_fixture 0.0: 20-80 % time 162ps typ, 247ps min, 94.8ps max; typ from 0 V to 1.78 V
|   falling waveform, R_fixture 50.0000, V_fixture 0.0: 20-80 % time 129ps typ, 166ps min, 76.1ps max; typ from 1.78 V to 0 V
|   falling waveform, R_fixture 50.0000, V_fixture 2.5000: 20-80 % time 161ps typ, 218ps min, 111ps max; typ from 2.5 V to 0.625 V
[Pulldown]
|Voltage   I(typ)   I(min)   I(max)
-2.5V     -44.97mA   -31.87mA   -59.27mA
-1.06V    -41.99mA   -29.75mA   -55.3mA
-740mV    -37.9mA    -28.62mA   -46.58mA
-500mV    -32.86mA   -23.93mA   -42.76mA
-420mV    -29.26mA   -20.75mA   -38.7mA
-340mV    -24.15mA   -16.95mA   -32.07mA
220mV     15.06mA    10.22mA    20.45mA
540mV     33.32mA    22.25mA    45.93mA
940mV     49.54mA    32.44mA    69.49mA
1.26V     56.39mA    36.64mA    79.57mA
1.98V     61.51mA    40mA       86.55mA
5V        70.61mA    46.16mA    98.78mA
[Pullup]
|Voltage   I(typ)   I(min)   I(max)
-2.5V     165.4mA    133.8mA    211.3mA
-1.96V    120.3mA    96.53mA    155.1mA
-1.48V    87.51mA    68.82mA    111mA
-1.24V    73.01mA    56.69mA    93.74mA
-1V       59.66mA    45.39mA    81.45mA
-600mV    38.85mA    29.2mA     52.9mA
280mV     -16.09mA   -11.6mA    -23.13mA
680mV     -34.27mA   -24.34mA   -50.23mA
1.08V     -46.75mA   -32.57mA   -70.22mA
1.4V      -52.51mA   -35.91mA   -80.77mA
1.8V      -55.29mA   -37.33mA   -87.21mA
4.96V     -64.54mA   -43.37mA   -103mA
[GND_clamp]
|Voltage   I(typ)   I(min)   I(max)
-2.5V     -564.7mA   -543.1mA   -585.2mA
-1.18V    -82.37mA   -79.05mA   -91.19mA
-1.14V    -74.91mA   -71.4mA    -84.01mA
-1.1V     -67.72mA   -63.96mA   -77.3mA
-980mV    -48.69mA   -43.39mA   -60.85mA
-820mV    -30.38mA   -22.68mA   -40.71mA
-620mV    -10.92mA   -6.374mA   -15.3mA
-540mV    -5.123mA   -2.7mA     -7.317mA
-460mV    -1.524mA   -767.4uA   -2.097mA
-380mV    -292.5uA   -172.6uA   -366.3uA
20mV      0A         0A         0A
5V        0A         0A         0A
[POWER_clamp]
|Voltage   I(typ)   I(min)   I(max)
-2.48V    92.22mA    86.5mA     95.83mA
-2.16V    81.19mA    77.59mA    82.43mA
-1.84V    67mA       66.38mA    64.75mA
-1.52V    49.86mA    53.4mA     41.33mA
-1.28V    35.63mA    42.81mA    22.28mA
-1.2V     30.7mA     39.17mA    17mA
-960mV    15.93mA    27.93mA    6.582mA
-800mV    7.851mA    20.23mA    1.424mA
-560mV    1.299mA    8.796mA    199.2uA
-400mV    169.6uA    2.771mA    193.9uA
-160mV    101.6uA    144.1uA    192.3uA
5V        -4.578uA   -1.793uA   -63.13uA
[Ramp]
| variable   typ   min   max
dV/dt_r  1.0688/0.1604n   0.8847/0.2443n   1.2507/93.8258p
dV/dt_f  1.1250/0.1592n   0.9191/0.2160n   1.2817/0.1102n
R_load = 50.0000
[Rising Waveform]
R_fixture=   50.0000
V_fixture=   2.5000
V_fixture_min=   2.3800
V_fixture_max=   2.6300
|time   V(typ)   V(min)   V(max)
0s        625.1mV    848.2mV    493.8mV
505.1ps   625.1mV    848.2mV    483.9mV
707.1ps   617.1mV    848.2mV    2.504V
808.1ps   777mV      848.3mV    2.581V
1.01ns    2.285V     846.8mV    2.613V
1.212ns   2.459V     919.1mV    2.624V
1.414ns   2.481V     1.791V     2.628V
1.515ns   2.486V     2.145V     2.629V
1.717ns   2.493V     2.335V     2.63V
10ns      2.5V       2.38V      2.63V
[Rising Waveform]
R_fixture=   50.0000
V_fixture=   0.0
V_fixture_min=   0.0
V_fixture_max=   0.0
|time   V(typ)   V(min)   V(max)
0s        394.5nV    565.3nV    312nV
505.1ps   17.53uV    728.7nV    -23.3mV
606.1ps   -153.3uV   722.6nV    227.1mV
707.1ps   -3.764mV   9.302uV    1.646V
909.1ps   47.24mV    -32.83uV   2.015V
1.01ns    876.9mV    -402.3uV   2.044V
1.212ns   1.627V     -20.32mV   2.07V
1.717ns   1.758V     1.143V     2.083V
2.121ns   1.775V     1.401V     2.084V
10ns      1.781V     1.474V     2.084V
[Falling Waveform]
R_fixture=   50.0000
V_fixture=   0.0
V_fixture_min=   0.0
V_fixture_max=   0.0
|time   V(typ)   V(min)   V(max)
0s        1.781V     1.474V     2.085V
606.1ps   1.781V     1.474V     1.879V
707.1ps   1.782V     1.474V     218.8mV
909.1ps   1.721V     1.474V     23.28mV
1.01ns    651.4mV    1.474V     13.07mV
1.212ns   38.57mV    1.475V     4.117mV
1.414ns   15.95mV    1.455V     1.284mV
1.717ns   5.3mV      156.1mV    203.4uV
1.919ns   2.469mV    29.32mV    71.82uV
10ns      15.52uV    -1.266uV   20.45uV
[Falling Waveform]
R_fixture=   50.0000
V_fixture=   2.5000
V_fixture_min=   2.3800
V_fixture_max=   2.6300
|time   V(typ)   V(min)   V(max)
0s        2.5V       2.38V      2.63V
606.1ps   2.5V       2.38V      2.547V
707.1ps   2.501V     2.38V      1.082V
909.1ps   2.529V     2.38V      538.3mV
1.111ns   1.085V     2.381V     507.8mV
1.414ns   665.1mV    2.397V     496.4mV
1.515ns   652.2mV    2.397V     495.3mV
1.818ns   634.3mV    1.151V     494.1mV
2.121ns   628.4mV    907.9mV    493.9mV
10ns      625.1mV    848.2mV    493.8mV
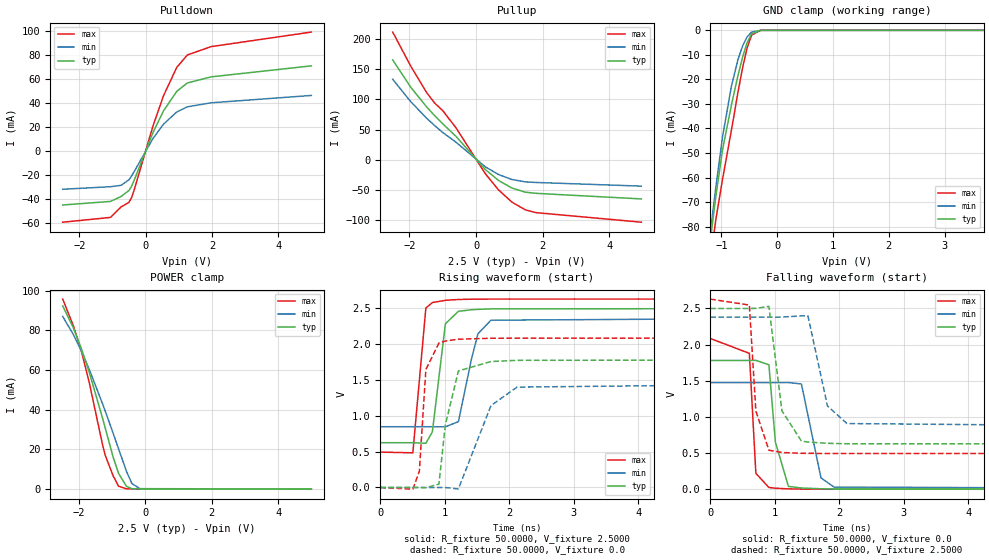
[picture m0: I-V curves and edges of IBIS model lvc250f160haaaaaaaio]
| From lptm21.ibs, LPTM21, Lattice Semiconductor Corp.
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|   Model lvc250f160haaaaaaaio
[Model]   lvc250f160haaaaaaaio
Model_type   I/O
Polarity   Non-Inverting
Enable   Active-Low
Vinl =   0.7000V
Vinh =   1.7000V
Vmeas =   1.2500V
Cref =   0.0F
Rref =   1.0000M
Vref =   0.0V
C_comp   4.2000pF   3.8000pF   7.5000pF
[Temperature Range]   25.0000   0.1050k   -40.0000
[Voltage Range]   2.5000V   2.3800V   2.6300V
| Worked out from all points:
|   slope of the pulldown table from 0 to 0.375 V, typ, clamps not added: 15.3 ohm
|   slope of the pullup table from 0 to 0.375 V, typ, clamps not added: 18.1 ohm
|   GND clamp passes 1 mA (typ) near -0.44 V on its own axis
|   POWER clamp passes 1 mA (typ) near -0.54 V on its own axis
|   rising waveform, R_fixture 50.0000, V_fixture 2.5000: 20-80 % time 151ps typ, 227ps min, 128ps max; typ from 0.625 V to 2.5 V
|   rising waveform, R_fixture 50.0000, V_fixture 0.0: 20-80 % time 162ps typ, 247ps min, 94.8ps max; typ from 0 V to 1.78 V
|   falling waveform, R_fixture 50.0000, V_fixture 0.0: 20-80 % time 129ps typ, 166ps min, 76.1ps max; typ from 1.78 V to 0 V
|   falling waveform, R_fixture 50.0000, V_fixture 2.5000: 20-80 % time 161ps typ, 218ps min, 111ps max; typ from 2.5 V to 0.625 V
[Pulldown]
|Voltage   I(typ)   I(min)   I(max)
-2.5V     -44.97mA   -31.87mA   -59.27mA
-1.06V    -41.99mA   -29.75mA   -55.3mA
-740mV    -37.9mA    -28.62mA   -46.58mA
-500mV    -32.86mA   -23.93mA   -42.76mA
-420mV    -29.26mA   -20.75mA   -38.7mA
-340mV    -24.15mA   -16.95mA   -32.07mA
220mV     15.06mA    10.22mA    20.45mA
540mV     33.32mA    22.25mA    45.93mA
940mV     49.54mA    32.44mA    69.49mA
1.26V     56.56mA    36.73mA    79.88mA
1.98V     61.65mA    40.07mA    86.82mA
5V        70.8mA     46.18mA    98.9mA
[Pullup]
|Voltage   I(typ)   I(min)   I(max)
-2.5V     165.3mA    133.4mA    211.3mA
-1.96V    120.2mA    96.33mA    155.1mA
-1.48V    87.5mA     68.74mA    111.1mA
-1.24V    73.02mA    56.63mA    93.84mA
-1V       59.69mA    45.38mA    81.55mA
-600mV    38.88mA    29.21mA    52.98mA
280mV     -15.97mA   -11.54mA   -22.9mA
680mV     -34.12mA   -24.26mA   -49.96mA
1.08V     -46.59mA   -32.48mA   -69.92mA
1.48V     -53.37mA   -36.34mA   -82.62mA
1.8V      -55.29mA   -37.33mA   -87.21mA
4.96V     -64.54mA   -43.37mA   -103mA
[GND_clamp]
|Voltage   I(typ)   I(min)   I(max)
-2.5V     -564.6mA   -543.1mA   -585.1mA
-1.18V    -82.29mA   -79mA      -91.05mA
-1.14V    -74.82mA   -71.35mA   -83.87mA
-1.1V     -67.64mA   -63.91mA   -77.16mA
-980mV    -48.61mA   -43.34mA   -60.71mA
-820mV    -30.3mA    -22.63mA   -40.57mA
-700mV    -18.05mA   -11.61mA   -24.72mA
-620mV    -10.84mA   -6.326mA   -15.16mA
-540mV    -5.04mA    -2.652mA   -7.178mA
-460mV    -1.44mA    -719uA     -1.958mA
-300mV    -9.986uA   -9.27uA    -5.3uA
5V        0A         0A         0A
[POWER_clamp]
|Voltage   I(typ)   I(min)   I(max)
-2.48V    92.38mA    87.03mA    95.82mA
-2.16V    81.29mA    77.94mA    82.39mA
-1.92V    70.92mA    69.63mA    69.65mA
-1.68V    58.78mA    60.26mA    53.56mA
-1.28V    35.62mA    42.91mA    22.18mA
-1.2V     30.69mA    39.25mA    16.92mA
-960mV    15.9mA     27.98mA    6.508mA
-800mV    7.821mA    20.25mA    1.349mA
-560mV    1.267mA    8.796mA    53.58uA
-400mV    117.5uA    2.764mA    20.86uA
-160mV    16.15uA    125.2uA    -13.85uA
5V        -78.59uA   -46.05uA   -129.1uA
[Ramp]
| variable   typ   min   max
dV/dt_r  1.0688/0.1604n   0.8847/0.2443n   1.2507/93.8258p
dV/dt_f  1.1250/0.1592n   0.9191/0.2160n   1.2817/0.1102n
R_load = 50.0000
[Rising Waveform]
R_fixture=   50.0000
V_fixture=   2.5000
V_fixture_min=   2.3800
V_fixture_max=   2.6300
|time   V(typ)   V(min)   V(max)
0s        625.1mV    848.2mV    493.8mV
505.1ps   625.1mV    848.2mV    483.9mV
707.1ps   617.1mV    848.2mV    2.504V
808.1ps   777mV      848.3mV    2.581V
1.01ns    2.285V     846.8mV    2.613V
1.212ns   2.459V     919.1mV    2.624V
1.414ns   2.481V     1.791V     2.628V
1.515ns   2.486V     2.145V     2.629V
1.717ns   2.493V     2.335V     2.63V
10ns      2.5V       2.38V      2.63V
[Rising Waveform]
R_fixture=   50.0000
V_fixture=   0.0
V_fixture_min=   0.0
V_fixture_max=   0.0
|time   V(typ)   V(min)   V(max)
0s        394.5nV    565.3nV    312nV
505.1ps   17.53uV    728.7nV    -23.3mV
606.1ps   -153.3uV   722.6nV    227.1mV
707.1ps   -3.764mV   9.302uV    1.646V
909.1ps   47.24mV    -32.83uV   2.015V
1.01ns    876.9mV    -402.3uV   2.044V
1.212ns   1.627V     -20.32mV   2.07V
1.717ns   1.758V     1.143V     2.083V
2.121ns   1.775V     1.401V     2.084V
10ns      1.781V     1.474V     2.084V
[Falling Waveform]
R_fixture=   50.0000
V_fixture=   0.0
V_fixture_min=   0.0
V_fixture_max=   0.0
|time   V(typ)   V(min)   V(max)
0s        1.781V     1.474V     2.085V
606.1ps   1.781V     1.474V     1.879V
707.1ps   1.782V     1.474V     218.8mV
909.1ps   1.721V     1.474V     23.28mV
1.01ns    651.4mV    1.474V     13.07mV
1.212ns   38.57mV    1.475V     4.117mV
1.414ns   15.95mV    1.455V     1.284mV
1.717ns   5.3mV      156.1mV    203.4uV
1.919ns   2.469mV    29.32mV    71.82uV
10ns      15.52uV    -1.266uV   20.45uV
[Falling Waveform]
R_fixture=   50.0000
V_fixture=   2.5000
V_fixture_min=   2.3800
V_fixture_max=   2.6300
|time   V(typ)   V(min)   V(max)
0s        2.5V       2.38V      2.63V
606.1ps   2.5V       2.38V      2.547V
707.1ps   2.501V     2.38V      1.082V
909.1ps   2.529V     2.38V      538.3mV
1.111ns   1.085V     2.381V     507.8mV
1.414ns   665.1mV    2.397V     496.4mV
1.515ns   652.2mV    2.397V     495.3mV
1.818ns   634.3mV    1.151V     494.1mV
2.121ns   628.4mV    907.9mV    493.9mV
10ns      625.1mV    848.2mV    493.8mV
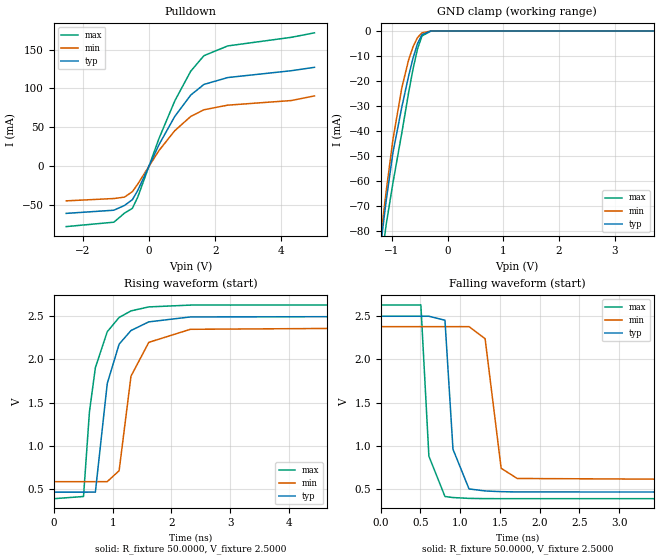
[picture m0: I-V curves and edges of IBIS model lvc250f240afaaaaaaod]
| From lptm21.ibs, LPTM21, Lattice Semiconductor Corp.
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|   Model lvc250f240afaaaaaaod
[Model]   lvc250f240afaaaaaaod
Model_type   I/O_open_drain
Polarity   Non-Inverting
Enable   Active-Low
Vinl =   0.7000V
Vinh =   1.7000V
Vmeas =   1.2500V
Cref =   0.0F
Rref =   1.0000M
Vref =   0.0V
C_comp   4.2000pF   3.8000pF   7.5000pF
[Temperature Range]   25.0000   0.1050k   -40.0000
[Voltage Range]   2.5000V   2.3800V   2.6300V
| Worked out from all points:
|   slope of the pulldown table from 0 to 0.375 V, typ, clamps not added: 11.2 ohm
|   GND clamp passes 1 mA (typ) near -0.44 V on its own axis
|   rising waveform, R_fixture 50.0000, V_fixture 2.5000: 20-80 % time 289ps typ, 273ps min, 267ps max; typ from 0.464 V to 2.5 V
|   falling waveform, R_fixture 50.0000, V_fixture 2.5000: 20-80 % time 98.9ps typ, 141ps min, 85.5ps max; typ from 2.5 V to 0.464 V
[Pulldown]
|Voltage   I(typ)   I(min)   I(max)
-2.5V     -61.25mA   -45.09mA   -78.29mA
-1.06V    -57.16mA   -42.08mA   -72.62mA
-740mV    -51.04mA   -40.26mA   -60.93mA
-500mV    -43.5mA    -33.15mA   -54.62mA
-340mV    -31.69mA   -23.47mA   -40.36mA
300mV     27.2mA     19.7mA     35.13mA
780mV     63.9mA     45.47mA    83.89mA
1.26V     91.34mA    63.75mA    122.1mA
1.66V     105.1mA    72.44mA    142.2mA
2.38V     114mA      78.38mA    154.8mA
4.3V      122.8mA    84.33mA    165.9mA
5V        127.2mA    90.33mA    171.7mA
[GND_clamp]
|Voltage   I(typ)   I(min)   I(max)
-2.5V     -564.7mA   -543.1mA   -585.2mA
-1.18V    -82.36mA   -79.04mA   -91.17mA
-1.14V    -74.89mA   -71.39mA   -83.98mA
-1.1V     -67.71mA   -63.95mA   -77.28mA
-980mV    -48.67mA   -43.37mA   -60.82mA
-820mV    -30.36mA   -22.66mA   -40.67mA
-700mV    -18.1mA    -11.63mA   -24.81mA
-620mV    -10.88mA   -6.341mA   -15.24mA
-540mV    -5.068mA   -2.657mA   -7.239mA
-460mV    -1.45mA    -716.2uA   -1.987mA
-300mV    -18.83uA   -15.98uA   -16.73uA
5V        0A         0A         0A
[Ramp]
| variable   typ   min   max
dV/dt_r  1.2215/0.2862n   1.0767/0.2700n   1.3449/0.2642n
dV/dt_f  1.2215/97.9665p   1.0767/0.1400n   1.3449/84.6680p
R_load = 50.0000
[Rising Waveform]
R_fixture=   50.0000
V_fixture=   2.5000
V_fixture_min=   2.3800
V_fixture_max=   2.6300
|time   V(typ)   V(min)   V(max)
0s        464.1mV    585.4mV    388.5mV
505.1ps   464.1mV    585.4mV    413.9mV
606.1ps   464.6mV    585.4mV    1.393V
707.1ps   464.5mV    585.4mV    1.905V
909.1ps   1.721V     585.8mV    2.32V
1.111ns   2.176V     712.5mV    2.485V
1.313ns   2.334V     1.806V     2.561V
1.616ns   2.434V     2.197V     2.607V
2.323ns   2.491V     2.348V     2.628V
10ns      2.5V       2.38V      2.63V
[Falling Waveform]
R_fixture=   50.0000
V_fixture=   2.5000
V_fixture_min=   2.3800
V_fixture_max=   2.6300
|time   V(typ)   V(min)   V(max)
0s        2.5V       2.38V      2.63V
505.1ps   2.5V       2.38V      2.631V
606.1ps   2.5V       2.38V      880.4mV
808.1ps   2.454V     2.38V      414mV
909.1ps   960.6mV    2.38V      401.8mV
1.111ns   501.6mV    2.38V      392mV
1.313ns   478.3mV    2.24V      389.4mV
1.515ns   469.9mV    740.7mV    388.8mV
1.717ns   466.5mV    622.4mV    388.6mV
10ns      464.1mV    585.4mV    388.5mV
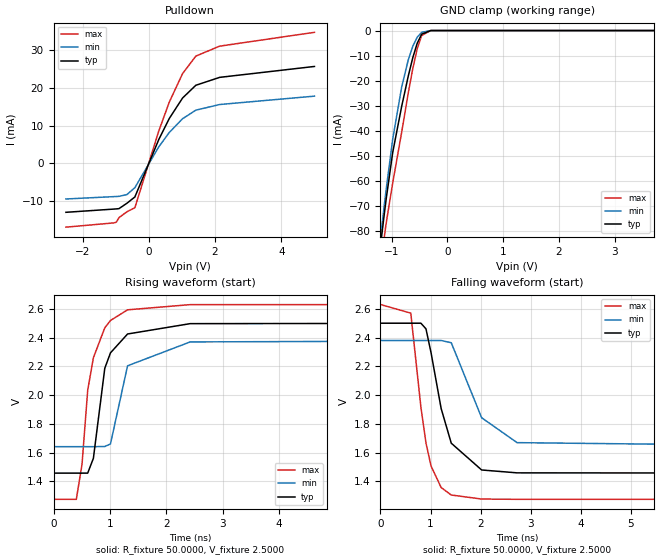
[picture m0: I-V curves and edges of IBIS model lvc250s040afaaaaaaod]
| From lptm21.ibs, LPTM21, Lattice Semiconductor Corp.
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|   Model lvc250s040afaaaaaaod
[Model]   lvc250s040afaaaaaaod
Model_type   I/O_open_drain
Polarity   Non-Inverting
Enable   Active-Low
Vinl =   0.7000V
Vinh =   1.7000V
Vmeas =   1.2500V
Cref =   0.0F
Rref =   1.0000M
Vref =   0.0V
C_comp   4.2000pF   3.8000pF   7.5000pF
[Temperature Range]   25.0000   0.1050k   -40.0000
[Voltage Range]   2.5000V   2.3800V   2.6300V
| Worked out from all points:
|   slope of the pulldown table from 0 to 0.375 V, typ, clamps not added: 48.7 ohm
|   GND clamp passes 1 mA (typ) near -0.44 V on its own axis
|   rising waveform, R_fixture 50.0000, V_fixture 2.5000: 20-80 % time 276ps typ, 296ps min, 273ps max; typ from 1.46 V to 2.5 V
|   falling waveform, R_fixture 50.0000, V_fixture 2.5000: 20-80 % time 401ps typ, 541ps min, 313ps max; typ from 2.5 V to 1.46 V
[Pulldown]
|Voltage   I(typ)   I(min)   I(max)
-2.5V     -12.9mA    -9.383mA   -16.82mA
-1.06V    -12.05mA   -8.76mA    -15.7mA
-980mV    -12mA      -8.725mA   -15.51mA
-900mV    -11.93mA   -8.69mA    -14.31mA
-660mV    -10.51mA   -8.221mA   -12.76mA
-420mV    -8.853mA   -6.399mA   -11.69mA
300mV     6.289mA    4.363mA    8.526mA
620mV     11.89mA    8.194mA    16.22mA
1.02V     17.28mA    11.81mA    23.73mA
1.42V     20.64mA    14.07mA    28.34mA
2.14V     22.73mA    15.56mA    30.97mA
5V        25.61mA    17.77mA    34.62mA
[GND_clamp]
|Voltage   I(typ)   I(min)   I(max)
-2.5V     -564.7mA   -543.1mA   -585.2mA
-1.18V    -82.36mA   -79.04mA   -91.17mA
-1.14V    -74.89mA   -71.39mA   -83.98mA
-1.1V     -67.71mA   -63.95mA   -77.28mA
-980mV    -48.67mA   -43.37mA   -60.82mA
-820mV    -30.36mA   -22.66mA   -40.67mA
-700mV    -18.1mA    -11.63mA   -24.81mA
-620mV    -10.88mA   -6.341mA   -15.24mA
-540mV    -5.068mA   -2.657mA   -7.239mA
-460mV    -1.45mA    -716.2uA   -1.987mA
-300mV    -18.83uA   -15.98uA   -16.73uA
5V        0A         0A         0A
[Ramp]
| variable   typ   min   max
dV/dt_r  0.6254/0.2732n   0.4426/0.2929n   0.8123/0.2708n
dV/dt_f  0.6254/0.3975n   0.4426/0.5356n   0.8123/0.3099n
R_load = 50.0000
[Rising Waveform]
R_fixture=   50.0000
V_fixture=   2.5000
V_fixture_min=   2.3800
V_fixture_max=   2.6300
|time   V(typ)   V(min)   V(max)
0s        1.458V     1.642V     1.276V
404ps     1.458V     1.642V     1.276V
505.1ps   1.458V     1.642V     1.518V
606.1ps   1.458V     1.642V     2.034V
707.1ps   1.561V     1.642V     2.26V
909.1ps   2.187V     1.643V     2.468V
1.01ns    2.294V     1.661V     2.519V
1.313ns   2.425V     2.204V     2.593V
2.424ns   2.497V     2.37V      2.629V
10ns      2.5V       2.38V      2.63V
[Falling Waveform]
R_fixture=   50.0000
V_fixture=   2.5000
V_fixture_min=   2.3800
V_fixture_max=   2.6300
|time   V(typ)   V(min)   V(max)
0s        2.5V       2.38V      2.63V
606.1ps   2.5V       2.38V      2.57V
808.1ps   2.5V       2.38V      1.917V
909.1ps   2.461V     2.38V      1.668V
1.01ns    2.296V     2.38V      1.508V
1.212ns   1.907V     2.38V      1.358V
1.414ns   1.666V     2.364V     1.306V
2.02ns    1.48V      1.843V     1.278V
2.727ns   1.46V      1.67V      1.276V
10ns      1.458V     1.642V     1.276V
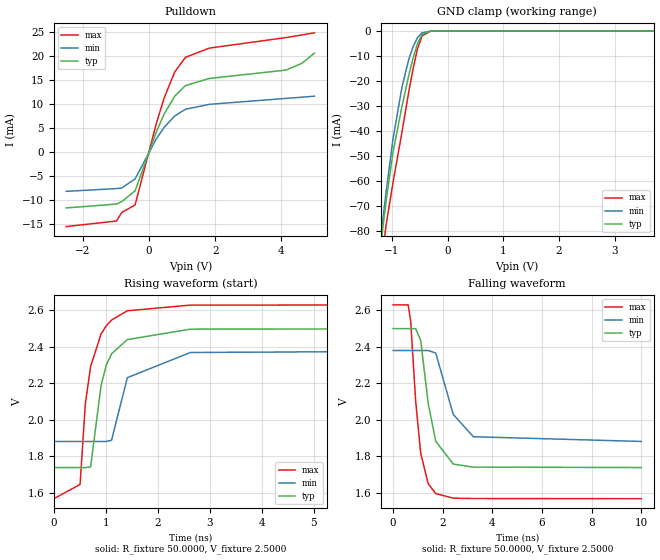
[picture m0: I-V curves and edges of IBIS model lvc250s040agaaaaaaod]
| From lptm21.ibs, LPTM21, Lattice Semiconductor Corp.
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|   Model lvc250s040agaaaaaaod
[Model]   lvc250s040agaaaaaaod
Model_type   I/O_open_drain
Polarity   Non-Inverting
Enable   Active-Low
Vinl =   0.7000V
Vinh =   1.7000V
Vmeas =   1.2500V
Cref =   0.0F
Rref =   1.0000M
Vref =   0.0V
C_comp   4.2000pF   3.8000pF   7.5000pF
[Temperature Range]   25.0000   0.1050k   -40.0000
[Voltage Range]   2.5000V   2.3800V   2.6300V
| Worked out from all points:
|   slope of the pulldown table from 0 to 0.375 V, typ, clamps not added: 56 ohm
|   GND clamp passes 1 mA (typ) near -0.44 V on its own axis
|   rising waveform, R_fixture 50.0000, V_fixture 2.5000: 20-80 % time 303ps typ, 299ps min, 294ps max; typ from 1.74 V to 2.5 V
|   falling waveform, R_fixture 50.0000, V_fixture 2.5000: 20-80 % time 509ps typ, 689ps min, 395ps max; typ from 2.5 V to 1.74 V
[Pulldown]
|Voltage   I(typ)   I(min)   I(max)
-2.5V     -11.64mA   -8.183mA   -15.53mA
-980mV    -10.83mA   -7.609mA   -14.36mA
-820mV    -10.3mA    -7.483mA   -12.57mA
-420mV    -8.084mA   -5.596mA   -11.02mA
220mV     4.174mA    2.735mA    5.905mA
460mV     7.938mA    5.165mA    11.3mA
780mV     11.67mA    7.531mA    16.71mA
1.1V      13.83mA    8.908mA    19.72mA
1.82V     15.33mA    9.94mA     21.65mA
4.14V     17.08mA    11.18mA    23.85mA
4.62V     18.48mA    11.43mA    24.39mA
5V        20.61mA    11.64mA    24.84mA
[GND_clamp]
|Voltage   I(typ)   I(min)   I(max)
-2.5V     -564.7mA   -543.1mA   -585.2mA
-1.18V    -82.35mA   -79.03mA   -91.15mA
-1.14V    -74.88mA   -71.38mA   -83.96mA
-1.1V     -67.69mA   -63.94mA   -77.25mA
-980mV    -48.66mA   -43.36mA   -60.79mA
-820mV    -30.34mA   -22.65mA   -40.66mA
-700mV    -18.09mA   -11.63mA   -24.79mA
-620mV    -10.87mA   -6.335mA   -15.23mA
-540mV    -5.061mA   -2.654mA   -7.227mA
-460mV    -1.446mA   -714.8uA   -1.98mA
-300mV    -18.71uA   -15.93uA   -16.53uA
5V        0A         0A         0A
[Ramp]
| variable   typ   min   max
dV/dt_r  0.4573/0.3004n   0.2995/0.2958n   0.6376/0.2914n
dV/dt_f  0.4573/0.5039n   0.2995/0.6820n   0.6376/0.3915n
R_load = 50.0000
[Rising Waveform]
R_fixture=   50.0000
V_fixture=   2.5000
V_fixture_min=   2.3800
V_fixture_max=   2.6300
|time   V(typ)   V(min)   V(max)
0s        1.738V     1.881V     1.567V
505.1ps   1.738V     1.881V     1.645V
606.1ps   1.738V     1.881V     2.087V
707.1ps   1.741V     1.881V     2.292V
909.1ps   2.188V     1.881V     2.471V
1.01ns    2.301V     1.881V     2.516V
1.111ns   2.362V     1.888V     2.547V
1.414ns   2.44V      2.231V     2.598V
2.626ns   2.497V     2.369V     2.629V
10ns      2.5V       2.38V      2.63V
[Falling Waveform]
R_fixture=   50.0000
V_fixture=   2.5000
V_fixture_min=   2.3800
V_fixture_max=   2.6300
|time   V(typ)   V(min)   V(max)
0s        2.5V       2.38V      2.63V
606.1ps   2.5V       2.38V      2.63V
707.1ps   2.5V       2.38V      2.542V
909.1ps   2.5V       2.38V      2.102V
1.111ns   2.435V     2.38V      1.817V
1.414ns   2.089V     2.38V      1.649V
1.717ns   1.882V     2.366V     1.595V
2.424ns   1.757V     2.029V     1.57V
3.232ns   1.74V      1.907V     1.568V
10ns      1.738V     1.881V     1.567V
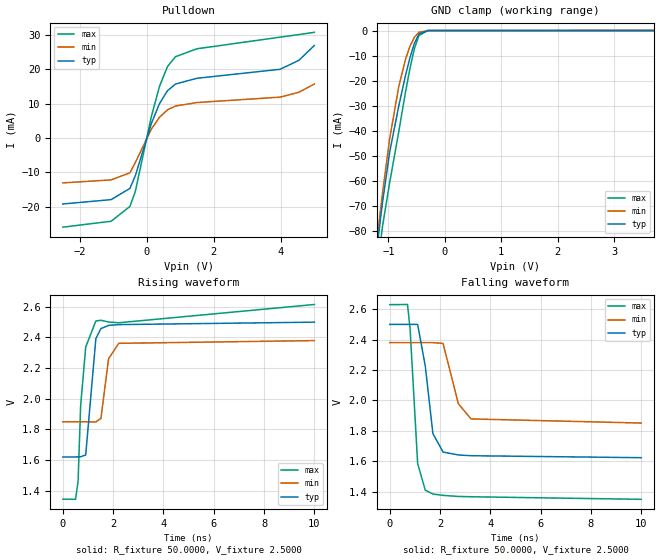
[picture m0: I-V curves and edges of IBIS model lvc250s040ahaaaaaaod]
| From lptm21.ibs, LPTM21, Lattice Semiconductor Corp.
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|   Model lvc250s040ahaaaaaaod
[Model]   lvc250s040ahaaaaaaod
Model_type   I/O_open_drain
Polarity   Non-Inverting
Enable   Active-Low
Vinl =   0.7000V
Vinh =   1.7000V
Vmeas =   1.2500V
Cref =   0.0F
Rref =   1.0000M
Vref =   0.0V
C_comp   4.2000pF   3.8000pF   7.5000pF
[Temperature Range]   25.0000   0.1050k   -40.0000
[Voltage Range]   2.5000V   2.3800V   2.6300V
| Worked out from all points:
|   slope of the pulldown table from 0 to 0.375 V, typ, clamps not added: 37.9 ohm
|   GND clamp passes 1 mA (typ) near -0.44 V on its own axis
|   rising waveform, R_fixture 50.0000, V_fixture 2.5000: 20-80 % time 247ps typ, 256ps min, 305ps max; typ from 1.62 V to 2.5 V
|   falling waveform, R_fixture 50.0000, V_fixture 2.5000: 20-80 % time 338ps typ, 478ps min, 264ps max; typ from 2.5 V to 1.62 V
[Pulldown]
|Voltage   I(typ)   I(min)   I(max)
-2.5V     -19.19mA   -13.05mA   -25.94mA
-1.06V    -17.92mA   -12.18mA   -24.22mA
-500mV    -14.66mA   -10.11mA   -19.91mA
-340mV    -11mA      -7.151mA   -15.61mA
140mV     4.235mA    2.597mA    6.279mA
380mV     9.975mA    6.03mA     14.97mA
620mV     13.78mA    8.219mA    20.81mA
860mV     15.74mA    9.335mA    23.7mA
1.5V      17.41mA    10.34mA    26mA
3.98V     20.03mA    11.92mA    29.38mA
4.54V     22.64mA    13.34mA    30.14mA
5V        26.95mA    15.73mA    30.79mA
[GND_clamp]
|Voltage   I(typ)   I(min)   I(max)
-2.5V     -564.7mA   -543mA     -585.2mA
-1.18V    -82.34mA   -79.02mA   -91.14mA
-1.14V    -74.87mA   -71.37mA   -83.95mA
-1.1V     -67.69mA   -63.93mA   -77.25mA
-980mV    -48.65mA   -43.36mA   -60.78mA
-820mV    -30.34mA   -22.64mA   -40.65mA
-700mV    -18.08mA   -11.62mA   -24.79mA
-620mV    -10.86mA   -6.332mA   -15.22mA
-540mV    -5.058mA   -2.652mA   -7.223mA
-460mV    -1.444mA   -713.9uA   -1.977mA
-300mV    -18.65uA   -15.9uA    -16.44uA
5V        0A         0A         0A
[Ramp]
| variable   typ   min   max
dV/dt_r  0.5264/0.2444n   0.3176/0.2536n   0.7607/0.3023n
dV/dt_f  0.5265/0.3347n   0.3175/0.4729n   0.7684/0.2616n
R_load = 50.0000
[Rising Waveform]
R_fixture=   50.0000
V_fixture=   2.5000
V_fixture_min=   2.3800
V_fixture_max=   2.6300
|time   V(typ)   V(min)   V(max)
0s        1.621V     1.85V      1.346V
505.1ps   1.621V     1.85V      1.345V
606.1ps   1.622V     1.85V      1.463V
707.1ps   1.622V     1.85V      1.954V
909.1ps   1.634V     1.85V      2.337V
1.313ns   2.392V     1.849V     2.507V
1.515ns   2.457V     1.872V     2.511V
1.818ns   2.478V     2.26V      2.5V
2.222ns   2.483V     2.361V     2.495V
10ns      2.499V     2.379V     2.614V
[Falling Waveform]
R_fixture=   50.0000
V_fixture=   2.5000
V_fixture_min=   2.3800
V_fixture_max=   2.6300
|time   V(typ)   V(min)   V(max)
0s        2.5V       2.38V      2.63V
707.1ps   2.5V       2.38V      2.631V
808.1ps   2.5V       2.38V      2.475V
1.111ns   2.5V       2.38V      1.584V
1.414ns   2.226V     2.38V      1.409V
1.717ns   1.782V     2.38V      1.384V
2.121ns   1.66V      2.375V     1.375V
2.727ns   1.641V     1.979V     1.368V
3.232ns   1.636V     1.878V     1.366V
10ns      1.623V     1.851V     1.349V
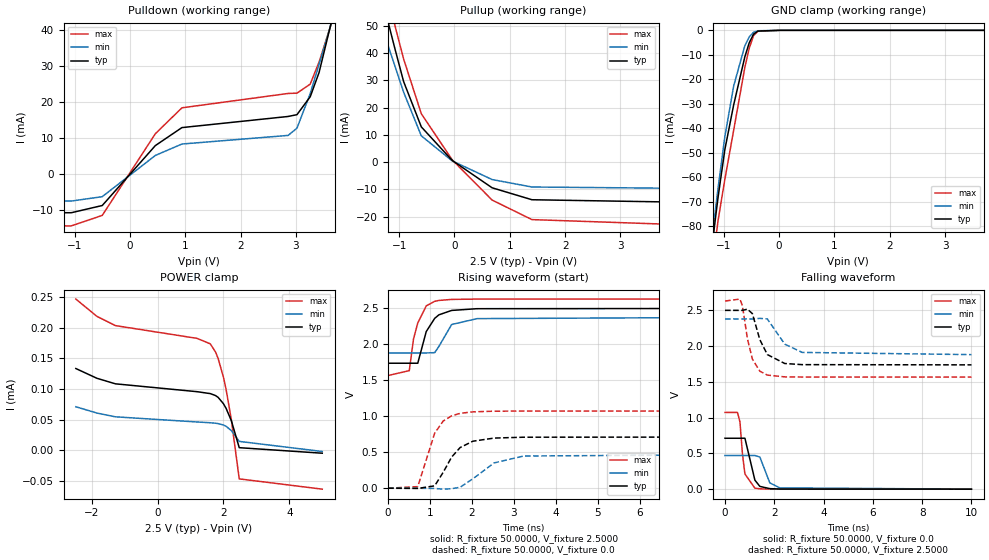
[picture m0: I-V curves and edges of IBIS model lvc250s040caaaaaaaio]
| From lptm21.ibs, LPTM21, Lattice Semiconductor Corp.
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|   Model lvc250s040caaaaaaaio
[Model]   lvc250s040caaaaaaaio
Model_type   I/O
Polarity   Non-Inverting
Enable   Active-Low
Vinl =   0.7000V
Vinh =   1.7000V
Vmeas =   1.2500V
Cref =   0.0F
Rref =   1.0000M
Vref =   0.0V
C_comp   4.2000pF   3.8000pF   7.5000pF
[Temperature Range]   25.0000   0.1050k   -40.0000
[Voltage Range]   2.5000V   2.3800V   2.6300V
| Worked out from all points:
|   slope of the pulldown table from 0 to 0.375 V, typ, clamps not added: 56.5 ohm
|   slope of the pullup table from 0 to 0.375 V, typ, clamps not added: 65.3 ohm
|   GND clamp passes 1 mA (typ) near -0.44 V on its own axis
|   rising waveform, R_fixture 50.0000, V_fixture 2.5000: 20-80 % time 302ps typ, 312ps min, 248ps max; typ from 1.74 V to 2.5 V
|   rising waveform, R_fixture 50.0000, V_fixture 0.0: 20-80 % time 487ps typ, 679ps min, 377ps max; typ from 0 V to 0.712 V
|   falling waveform, R_fixture 50.0000, V_fixture 0.0: 20-80 % time 256ps typ, 325ps min, 183ps max; typ from 0.712 V to 0 V
|   falling waveform, R_fixture 50.0000, V_fixture 2.5000: 20-80 % time 501ps typ, 683ps min, 391ps max; typ from 2.5 V to 1.74 V
[Pulldown]
|Voltage   I(typ)   I(min)   I(max)
-2.5V     -10.78mA   -7.54mA    -14.43mA
-1.06V    -10.78mA   -7.54mA    -14.43mA
-500mV    -8.777mA   -6.322mA   -11.52mA
460mV     7.865mA    5.129mA    11.16mA
940mV     12.86mA    8.296mA    18.35mA
2.86V     15.95mA    10.69mA    22.34mA
3.02V     16.45mA    12.7mA     22.42mA
3.26V     21.44mA    22.32mA    24.94mA
3.42V     28.18mA    30.45mA    31.08mA
3.66V     43.3mA     42.83mA    42.61mA
3.74V     48.62mA    46.93mA    48.81mA
5V        122.1mA    106.8mA    138.8mA
[Pullup]
|Voltage   I(typ)   I(min)   I(max)
-2.5V     137.5mA    112.8mA    166.1mA
-2.12V    116.7mA    96.13mA    142.2mA
-1.88V    101mA      83.12mA    124.6mA
-1.8V     97.75mA    78.56mA    118.2mA
-1.56V    79.75mA    64.46mA    97.23mA
-1.08V    41.75mA    35.35mA    50.23mA
-920mV    29.51mA    25.62mA    37.78mA
-600mV    12.91mA    9.637mA    17.73mA
-40mV     599.8uA    439.9uA    819.5uA
680mV     -9.378mA   -6.363mA   -13.87mA
1.4V      -13.75mA   -9.088mA   -21.02mA
4.96V     -14.94mA   -9.733mA   -23.48mA
[GND_clamp]
|Voltage   I(typ)   I(min)   I(max)
-2.5V     -564.7mA   -543.1mA   -585.2mA
-1.18V    -82.37mA   -79.05mA   -91.19mA
-1.14V    -74.91mA   -71.4mA    -84.01mA
-1.1V     -67.72mA   -63.96mA   -77.3mA
-980mV    -48.69mA   -43.39mA   -60.85mA
-820mV    -30.38mA   -22.68mA   -40.71mA
-620mV    -10.92mA   -6.374mA   -15.3mA
-540mV    -5.123mA   -2.7mA     -7.317mA
-460mV    -1.524mA   -767.4uA   -2.097mA
-380mV    -292.5uA   -172.6uA   -366.3uA
20mV      0A         0A         0A
5V        0A         0A         0A
[POWER_clamp]
|Voltage   I(typ)   I(min)   I(max)
-2.48V    133.3uA    71.04uA    246.4uA
-1.84V    117.4uA    60.8uA     218.2uA
-1.28V    108.4uA    54.67uA    203.2uA
1.2V      95.59uA    46.28uA    182.4uA
1.6V      92.47uA    45.01uA    173.5uA
1.76V     89.3uA     44.22uA    160.2uA
1.84V     86.28uA    43.64uA    149.5uA
2V        76.02uA    41.32uA    119.2uA
2.08V     68.53uA    39.17uA    99.45uA
2.24V     48.41uA    32.29uA    50.16uA
2.48V     4.411uA    14.65uA    -46.36uA
5V        -4.578uA   -1.793uA   -63.13uA
[Ramp]
| variable   typ   min   max
dV/dt_r  0.4166/0.4824n   0.2824/0.6718n   0.6437/0.3733n
dV/dt_f  0.4573/0.4964n   0.2995/0.6757n   0.6376/0.3875n
R_load = 50.0000
[Rising Waveform]
R_fixture=   50.0000
V_fixture=   2.5000
V_fixture_min=   2.3800
V_fixture_max=   2.6300
|time   V(typ)   V(min)   V(max)
0s        1.738V     1.881V     1.567V
505.1ps   1.738V     1.881V     1.635V
606.1ps   1.738V     1.881V     2.076V
707.1ps   1.738V     1.881V     2.297V
909.1ps   2.178V     1.881V     2.535V
1.111ns   2.362V     1.885V     2.599V
1.212ns   2.411V     1.972V     2.611V
1.515ns   2.472V     2.276V     2.625V
2.121ns   2.496V     2.358V     2.63V
10ns      2.5V       2.38V      2.63V
[Rising Waveform]
R_fixture=   50.0000
V_fixture=   0.0
V_fixture_min=   0.0
V_fixture_max=   0.0
|time   V(typ)   V(min)   V(max)
0s        1.018uV    1.278uV    887.5nV
707.1ps   -2.782mV   7.328uV    22.45mV
1.111ns   33.47mV    -2.877mV   766mV
1.313ns   220.9mV    -12.97mV   933.8mV
1.515ns   433.1mV    -6.689mV   1.007V
1.717ns   565.5mV    13.38mV    1.041V
2.02ns    653.5mV    130.8mV    1.062V
2.525ns   697.2mV    351.6mV    1.071V
3.232ns   709.4mV    448mV      1.073V
10ns      711.8mV    470.7mV    1.073V
[Falling Waveform]
R_fixture=   50.0000
V_fixture=   0.0
V_fixture_min=   0.0
V_fixture_max=   0.0
|time   V(typ)   V(min)   V(max)
0s        711.8mV    470.7mV    1.073V
505.1ps   711.8mV    470.7mV    1.073V
606.1ps   711.7mV    470.7mV    941.4mV
707.1ps   712mV      470.7mV    492.5mV
808.1ps   711.9mV    470.7mV    212.4mV
1.212ns   126.5mV    471mV      14.58mV
1.414ns   38.72mV    448.9mV    4.987mV
1.818ns   7.442mV    87.93mV    686.5uV
2.222ns   1.836mV    18.27mV    149.4uV
10ns      12.37uV    -15.81uV   15.14uV
[Falling Waveform]
R_fixture=   50.0000
V_fixture=   2.5000
V_fixture_min=   2.3800
V_fixture_max=   2.6300
|time   V(typ)   V(min)   V(max)
0s        2.5V       2.38V      2.63V
606.1ps   2.5V       2.38V      2.658V
707.1ps   2.5V       2.38V      2.564V
909.1ps   2.517V     2.38V      2.104V
1.111ns   2.454V     2.38V      1.819V
1.414ns   2.09V      2.388V     1.649V
1.717ns   1.882V     2.38V      1.595V
2.424ns   1.757V     2.028V     1.57V
3.131ns   1.741V     1.912V     1.568V
10ns      1.738V     1.881V     1.567V
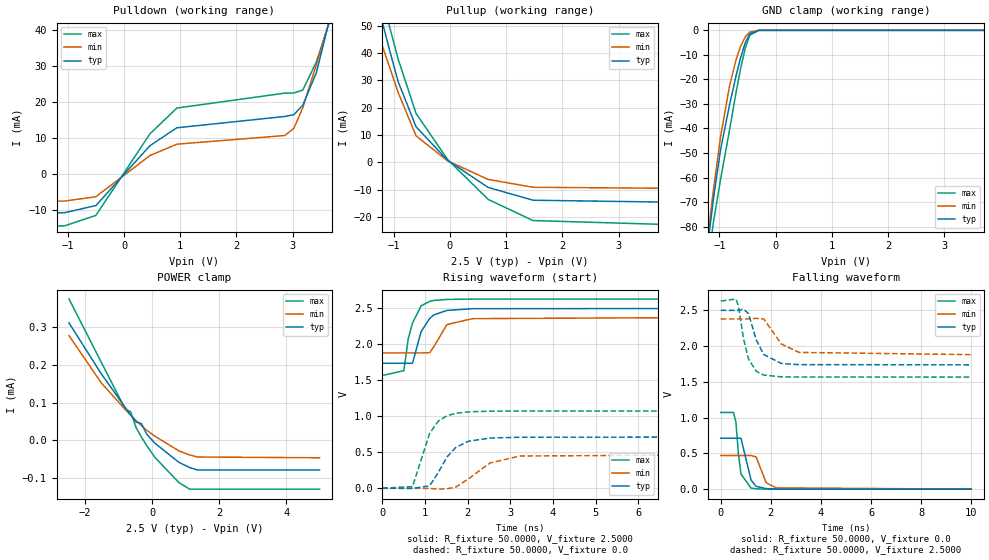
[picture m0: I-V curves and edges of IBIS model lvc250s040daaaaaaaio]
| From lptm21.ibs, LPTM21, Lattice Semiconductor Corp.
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|   Model lvc250s040daaaaaaaio
[Model]   lvc250s040daaaaaaaio
Model_type   I/O
Polarity   Non-Inverting
Enable   Active-Low
Vinl =   0.7000V
Vinh =   1.7000V
Vmeas =   1.2500V
Cref =   0.0F
Rref =   1.0000M
Vref =   0.0V
C_comp   4.2000pF   3.8000pF   7.5000pF
[Temperature Range]   25.0000   0.1050k   -40.0000
[Voltage Range]   2.5000V   2.3800V   2.6300V
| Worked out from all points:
|   slope of the pulldown table from 0 to 0.375 V, typ, clamps not added: 56.5 ohm
|   slope of the pullup table from 0 to 0.375 V, typ, clamps not added: 65.6 ohm
|   GND clamp passes 1 mA (typ) near -0.44 V on its own axis
|   rising waveform, R_fixture 50.0000, V_fixture 2.5000: 20-80 % time 302ps typ, 312ps min, 248ps max; typ from 1.74 V to 2.5 V
|   rising waveform, R_fixture 50.0000, V_fixture 0.0: 20-80 % time 487ps typ, 679ps min, 377ps max; typ from 0 V to 0.712 V
|   falling waveform, R_fixture 50.0000, V_fixture 0.0: 20-80 % time 256ps typ, 325ps min, 183ps max; typ from 0.712 V to 0 V
|   falling waveform, R_fixture 50.0000, V_fixture 2.5000: 20-80 % time 501ps typ, 683ps min, 391ps max; typ from 2.5 V to 1.74 V
[Pulldown]
|Voltage   I(typ)   I(min)   I(max)
-2.5V     -10.78mA   -7.54mA    -14.43mA
-1.06V    -10.78mA   -7.54mA    -14.43mA
-500mV    -8.777mA   -6.322mA   -11.52mA
460mV     7.865mA    5.129mA    11.16mA
940mV     12.86mA    8.296mA    18.35mA
2.86V     16.01mA    10.71mA    22.5mA
3.02V     16.5mA     12.71mA    22.54mA
3.18V     19.18mA    18.49mA    23.36mA
3.42V     28.18mA    30.42mA    31.16mA
3.66V     43.28mA    42.78mA    42.65mA
4.3V      84.42mA    75.05mA    94.89mA
5V        122mA      106.6mA    138.6mA
[Pullup]
|Voltage   I(typ)   I(min)   I(max)
-2.5V     137.3mA    112.7mA    165.9mA
-2.12V    116.6mA    95.99mA    142.1mA
-1.88V    100.9mA    83.01mA    124.5mA
-1.8V     97.65mA    78.47mA    118.1mA
-1.56V    79.68mA    64.39mA    97.19mA
-1.08V    41.73mA    35.31mA    50.26mA
-920mV    29.52mA    25.6mA     37.83mA
-600mV    12.95mA    9.645mA    17.83mA
-40mV     699.2uA    485.9uA    1.007mA
680mV     -9.225mA   -6.284mA   -13.6mA
1.48V     -13.92mA   -9.177mA   -21.37mA
4.96V     -14.94mA   -9.733mA   -23.48mA
[GND_clamp]
|Voltage   I(typ)   I(min)   I(max)
-2.5V     -564.6mA   -543.1mA   -585.1mA
-1.18V    -82.29mA   -79mA      -91.05mA
-1.14V    -74.82mA   -71.35mA   -83.87mA
-1.1V     -67.64mA   -63.91mA   -77.16mA
-980mV    -48.61mA   -43.34mA   -60.71mA
-820mV    -30.3mA    -22.63mA   -40.57mA
-700mV    -18.05mA   -11.61mA   -24.72mA
-620mV    -10.84mA   -6.326mA   -15.16mA
-540mV    -5.04mA    -2.652mA   -7.178mA
-460mV    -1.44mA    -719uA     -1.958mA
-300mV    -9.986uA   -9.27uA    -5.3uA
5V        0A         0A         0A
[POWER_clamp]
|Voltage   I(typ)   I(min)   I(max)
-2.48V    310.4uA    276.7uA    373.7uA
-1.52V    176.3uA    152.3uA    206.9uA
-800mV    86.61uA    81.35uA    82.18uA
-640mV    66.94uA    66.91uA    75.79uA
-480mV    48.86uA    52.22uA    34.01uA
-320mV    44.51uA    38.99uA    8.918uA
-160mV    16.15uA    26.85uA    -13.85uA
80mV      -7.284uA   11.17uA    -44.64uA
800mV     -58.16uA   -27.83uA   -111.7uA
1.12V     -71.9uA    -38.53uA   -129.1uA
1.36V     -78.59uA   -44.07uA   -129.1uA
5V        -78.59uA   -46.05uA   -129.1uA
[Ramp]
| variable   typ   min   max
dV/dt_r  0.4166/0.4824n   0.2824/0.6718n   0.6437/0.3733n
dV/dt_f  0.4573/0.4964n   0.2995/0.6757n   0.6376/0.3875n
R_load = 50.0000
[Rising Waveform]
R_fixture=   50.0000
V_fixture=   2.5000
V_fixture_min=   2.3800
V_fixture_max=   2.6300
|time   V(typ)   V(min)   V(max)
0s        1.738V     1.881V     1.567V
505.1ps   1.738V     1.881V     1.635V
606.1ps   1.738V     1.881V     2.076V
707.1ps   1.738V     1.881V     2.297V
909.1ps   2.178V     1.881V     2.535V
1.111ns   2.362V     1.885V     2.599V
1.212ns   2.411V     1.972V     2.611V
1.515ns   2.472V     2.276V     2.625V
2.121ns   2.496V     2.358V     2.63V
10ns      2.5V       2.38V      2.63V
[Rising Waveform]
R_fixture=   50.0000
V_fixture=   0.0
V_fixture_min=   0.0
V_fixture_max=   0.0
|time   V(typ)   V(min)   V(max)
0s        1.018uV    1.278uV    887.5nV
707.1ps   -2.782mV   7.328uV    22.45mV
1.111ns   33.47mV    -2.877mV   766mV
1.313ns   220.9mV    -12.97mV   933.8mV
1.515ns   433.1mV    -6.689mV   1.007V
1.717ns   565.5mV    13.38mV    1.041V
2.02ns    653.5mV    130.8mV    1.062V
2.525ns   697.2mV    351.6mV    1.071V
3.232ns   709.4mV    448mV      1.073V
10ns      711.8mV    470.7mV    1.073V
[Falling Waveform]
R_fixture=   50.0000
V_fixture=   0.0
V_fixture_min=   0.0
V_fixture_max=   0.0
|time   V(typ)   V(min)   V(max)
0s        711.8mV    470.7mV    1.073V
505.1ps   711.8mV    470.7mV    1.073V
606.1ps   711.7mV    470.7mV    941.4mV
707.1ps   712mV      470.7mV    492.5mV
808.1ps   711.9mV    470.7mV    212.4mV
1.212ns   126.5mV    471mV      14.58mV
1.414ns   38.72mV    448.9mV    4.987mV
1.818ns   7.442mV    87.93mV    686.5uV
2.222ns   1.836mV    18.27mV    149.4uV
10ns      12.37uV    -15.81uV   15.14uV
[Falling Waveform]
R_fixture=   50.0000
V_fixture=   2.5000
V_fixture_min=   2.3800
V_fixture_max=   2.6300
|time   V(typ)   V(min)   V(max)
0s        2.5V       2.38V      2.63V
606.1ps   2.5V       2.38V      2.658V
707.1ps   2.5V       2.38V      2.564V
909.1ps   2.517V     2.38V      2.104V
1.111ns   2.454V     2.38V      1.819V
1.414ns   2.09V      2.388V     1.649V
1.717ns   1.882V     2.38V      1.595V
2.424ns   1.757V     2.028V     1.57V
3.131ns   1.741V     1.912V     1.568V
10ns      1.738V     1.881V     1.567V
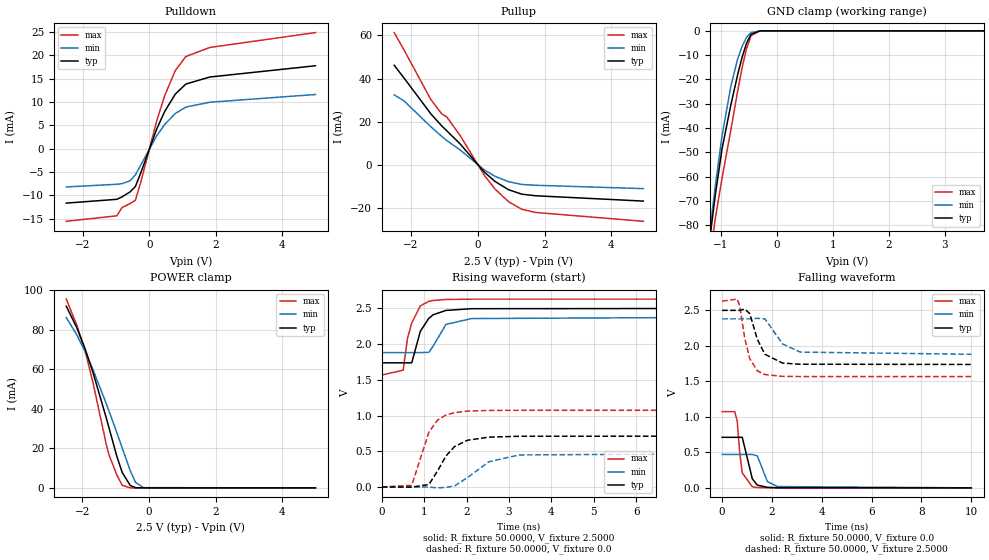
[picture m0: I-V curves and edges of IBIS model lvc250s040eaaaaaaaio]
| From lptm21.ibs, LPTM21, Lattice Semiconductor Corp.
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|   Model lvc250s040eaaaaaaaio
[Model]   lvc250s040eaaaaaaaio
Model_type   I/O
Polarity   Non-Inverting
Enable   Active-Low
Vinl =   0.7000V
Vinh =   1.7000V
Vmeas =   1.2500V
Cref =   0.0F
Rref =   1.0000M
Vref =   0.0V
C_comp   4.2000pF   3.8000pF   7.5000pF
[Temperature Range]   25.0000   0.1050k   -40.0000
[Voltage Range]   2.5000V   2.3800V   2.6300V
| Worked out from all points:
|   slope of the pulldown table from 0 to 0.375 V, typ, clamps not added: 56 ohm
|   slope of the pullup table from 0 to 0.375 V, typ, clamps not added: 65.3 ohm
|   GND clamp passes 1 mA (typ) near -0.44 V on its own axis
|   POWER clamp passes 1 mA (typ) near -0.54 V on its own axis
|   rising waveform, R_fixture 50.0000, V_fixture 2.5000: 20-80 % time 302ps typ, 312ps min, 248ps max; typ from 1.74 V to 2.5 V
|   rising waveform, R_fixture 50.0000, V_fixture 0.0: 20-80 % time 487ps typ, 679ps min, 377ps max; typ from 0 V to 0.712 V
|   falling waveform, R_fixture 50.0000, V_fixture 0.0: 20-80 % time 256ps typ, 325ps min, 183ps max; typ from 0.712 V to 0 V
|   falling waveform, R_fixture 50.0000, V_fixture 2.5000: 20-80 % time 501ps typ, 683ps min, 391ps max; typ from 2.5 V to 1.74 V
[Pulldown]
|Voltage   I(typ)   I(min)   I(max)
-2.5V     -11.64mA   -8.183mA   -15.53mA
-980mV    -10.83mA   -7.609mA   -14.36mA
-820mV    -10.3mA    -7.483mA   -12.57mA
-580mV    -9.233mA   -6.865mA   -11.75mA
-420mV    -8.084mA   -5.596mA   -11.02mA
-260mV    -5.215mA   -3.517mA   -7.219mA
220mV     4.174mA    2.735mA    5.905mA
460mV     7.938mA    5.165mA    11.3mA
780mV     11.67mA    7.531mA    16.71mA
1.1V      13.83mA    8.908mA    19.72mA
1.82V     15.33mA    9.94mA     21.65mA
5V        17.74mA    11.59mA    24.84mA
[Pullup]
|Voltage   I(typ)   I(min)   I(max)
-2.5V     46.16mA    32.51mA    61.28mA
-2.2V     40.15mA    29.61mA    53.07mA
-1.4V     23.66mA    17.7mA     30.24mA
-1.08V    18.19mA    13.33mA    23.77mA
-920mV    15.77mA    11.32mA    22.16mA
-520mV    9.714mA    6.924mA    13.53mA
200mV     -3.264mA   -2.251mA   -4.739mA
520mV     -7.556mA   -5.168mA   -11.08mA
920mV     -11.34mA   -7.66mA    -16.89mA
1.32V     -13.43mA   -8.924mA   -20.4mA
1.72V     -14.15mA   -9.307mA   -21.87mA
4.96V     -16.63mA   -10.87mA   -25.97mA
[GND_clamp]
|Voltage   I(typ)   I(min)   I(max)
-2.5V     -564.7mA   -543.1mA   -585.2mA
-1.18V    -82.35mA   -79.03mA   -91.15mA
-1.14V    -74.88mA   -71.38mA   -83.96mA
-1.1V     -67.69mA   -63.94mA   -77.25mA
-980mV    -48.66mA   -43.36mA   -60.79mA
-820mV    -30.34mA   -22.65mA   -40.66mA
-700mV    -18.09mA   -11.63mA   -24.79mA
-620mV    -10.87mA   -6.335mA   -15.23mA
-540mV    -5.061mA   -2.654mA   -7.227mA
-460mV    -1.446mA   -714.8uA   -1.98mA
-300mV    -18.71uA   -15.93uA   -16.53uA
5V        0A         0A         0A
[POWER_clamp]
|Voltage   I(typ)   I(min)   I(max)
-2.48V    91.96mA    86.23mA    95.54mA
-2.16V    80.94mA    77.35mA    82.15mA
-1.92V    70.61mA    69.17mA    69.43mA
-1.68V    58.52mA    59.9mA     53.37mA
-1.28V    35.44mA    42.67mA    22.07mA
-1.2V     30.53mA    39.03mA    16.84mA
-960mV    15.8mA     27.82mA    6.447mA
-800mV    7.76mA     20.14mA    1.303mA
-560mV    1.23mA     8.728mA    11.53uA
-400mV    83.98uA    2.726mA    532.6nA
-160mV    776.1nA    102uA      144nA
5V        -44.09nA   -38.33nA   -118.7nA
[Ramp]
| variable   typ   min   max
dV/dt_r  0.4166/0.4824n   0.2824/0.6718n   0.6437/0.3733n
dV/dt_f  0.4573/0.4964n   0.2995/0.6757n   0.6376/0.3875n
R_load = 50.0000
[Rising Waveform]
R_fixture=   50.0000
V_fixture=   2.5000
V_fixture_min=   2.3800
V_fixture_max=   2.6300
|time   V(typ)   V(min)   V(max)
0s        1.738V     1.881V     1.567V
505.1ps   1.738V     1.881V     1.635V
606.1ps   1.738V     1.881V     2.076V
707.1ps   1.738V     1.881V     2.297V
909.1ps   2.178V     1.881V     2.535V
1.111ns   2.362V     1.885V     2.599V
1.212ns   2.411V     1.972V     2.611V
1.515ns   2.472V     2.276V     2.625V
2.121ns   2.496V     2.358V     2.63V
10ns      2.5V       2.38V      2.63V
[Rising Waveform]
R_fixture=   50.0000
V_fixture=   0.0
V_fixture_min=   0.0
V_fixture_max=   0.0
|time   V(typ)   V(min)   V(max)
0s        1.018uV    1.278uV    887.5nV
707.1ps   -2.782mV   7.328uV    22.45mV
1.111ns   33.47mV    -2.877mV   766mV
1.313ns   220.9mV    -12.97mV   933.8mV
1.515ns   433.1mV    -6.689mV   1.007V
1.717ns   565.5mV    13.38mV    1.041V
2.02ns    653.5mV    130.8mV    1.062V
2.525ns   697.2mV    351.6mV    1.071V
3.232ns   709.4mV    448mV      1.073V
10ns      711.8mV    470.7mV    1.073V
[Falling Waveform]
R_fixture=   50.0000
V_fixture=   0.0
V_fixture_min=   0.0
V_fixture_max=   0.0
|time   V(typ)   V(min)   V(max)
0s        711.8mV    470.7mV    1.073V
505.1ps   711.8mV    470.7mV    1.073V
606.1ps   711.7mV    470.7mV    941.4mV
707.1ps   712mV      470.7mV    492.5mV
808.1ps   711.9mV    470.7mV    212.4mV
1.212ns   126.5mV    471mV      14.58mV
1.414ns   38.72mV    448.9mV    4.987mV
1.818ns   7.442mV    87.93mV    686.5uV
2.222ns   1.836mV    18.27mV    149.4uV
10ns      12.37uV    -15.81uV   15.14uV
[Falling Waveform]
R_fixture=   50.0000
V_fixture=   2.5000
V_fixture_min=   2.3800
V_fixture_max=   2.6300
|time   V(typ)   V(min)   V(max)
0s        2.5V       2.38V      2.63V
606.1ps   2.5V       2.38V      2.658V
707.1ps   2.5V       2.38V      2.564V
909.1ps   2.517V     2.38V      2.104V
1.111ns   2.454V     2.38V      1.819V
1.414ns   2.09V      2.388V     1.649V
1.717ns   1.882V     2.38V      1.595V
2.424ns   1.757V     2.028V     1.57V
3.131ns   1.741V     1.912V     1.568V
10ns      1.738V     1.881V     1.567V
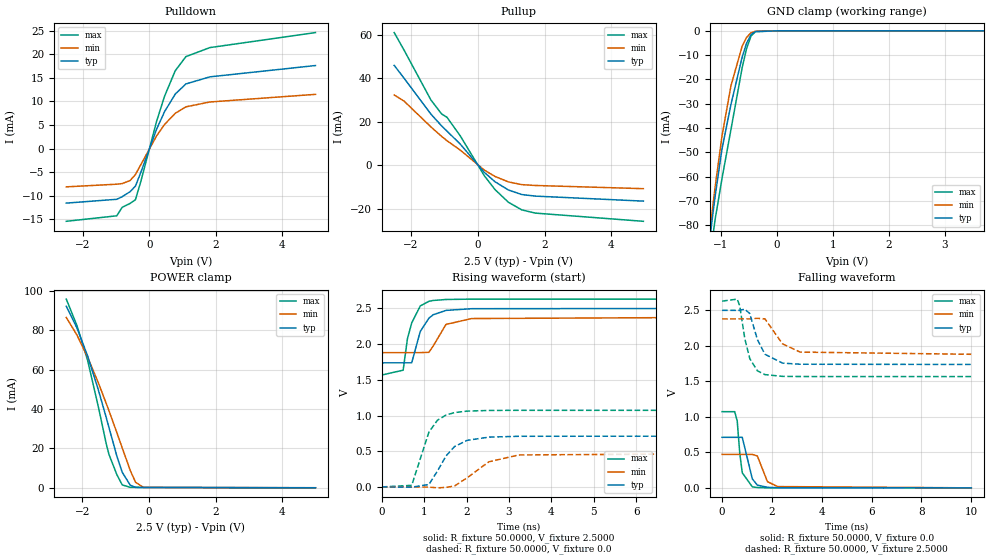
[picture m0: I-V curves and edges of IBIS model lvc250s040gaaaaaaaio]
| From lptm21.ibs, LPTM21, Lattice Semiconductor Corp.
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|   Model lvc250s040gaaaaaaaio
[Model]   lvc250s040gaaaaaaaio
Model_type   I/O
Polarity   Non-Inverting
Enable   Active-Low
Vinl =   0.7000V
Vinh =   1.7000V
Vmeas =   1.2500V
Cref =   0.0F
Rref =   1.0000M
Vref =   0.0V
C_comp   4.2000pF   3.8000pF   7.5000pF
[Temperature Range]   25.0000   0.1050k   -40.0000
[Voltage Range]   2.5000V   2.3800V   2.6300V
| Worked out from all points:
|   slope of the pulldown table from 0 to 0.375 V, typ, clamps not added: 56.5 ohm
|   slope of the pullup table from 0 to 0.375 V, typ, clamps not added: 65.3 ohm
|   GND clamp passes 1 mA (typ) near -0.44 V on its own axis
|   POWER clamp passes 1 mA (typ) near -0.53 V on its own axis
|   rising waveform, R_fixture 50.0000, V_fixture 2.5000: 20-80 % time 302ps typ, 312ps min, 248ps max; typ from 1.74 V to 2.5 V
|   rising waveform, R_fixture 50.0000, V_fixture 0.0: 20-80 % time 487ps typ, 679ps min, 377ps max; typ from 0 V to 0.712 V
|   falling waveform, R_fixture 50.0000, V_fixture 0.0: 20-80 % time 256ps typ, 325ps min, 183ps max; typ from 0.712 V to 0 V
|   falling waveform, R_fixture 50.0000, V_fixture 2.5000: 20-80 % time 501ps typ, 683ps min, 391ps max; typ from 2.5 V to 1.74 V
[Pulldown]
|Voltage   I(typ)   I(min)   I(max)
-2.5V     -11.61mA   -8.157mA   -15.48mA
-980mV    -10.8mA    -7.585mA   -14.31mA
-820mV    -10.26mA   -7.457mA   -12.52mA
-580mV    -9.181mA   -6.825mA   -11.68mA
-420mV    -8.006mA   -5.545mA   -10.9mA
-260mV    -5.154mA   -3.483mA   -7.112mA
220mV     4.131mA    2.713mA    5.825mA
460mV     7.865mA    5.129mA    11.16mA
780mV     11.58mA    7.488mA    16.54mA
1.1V      13.73mA    8.863mA    19.54mA
1.82V     15.24mA    9.893mA    21.46mA
5V        17.65mA    11.52mA    24.66mA
[Pullup]
|Voltage   I(typ)   I(min)   I(max)
-2.5V     45.89mA    32.27mA    60.98mA
-2.2V     39.89mA    29.4mA     52.78mA
-1.4V     23.46mA    17.57mA    29.96mA
-1.08V    18.03mA    13.23mA    23.54mA
-920mV    15.65mA    11.24mA    22.01mA
-520mV    9.642mA    6.886mA    13.41mA
200mV     -3.366mA   -2.299mA   -4.93mA
520mV     -7.657mA   -5.215mA   -11.27mA
920mV     -11.44mA   -7.706mA   -17.08mA
1.32V     -13.52mA   -8.969mA   -20.58mA
1.72V     -14.24mA   -9.349mA   -22.05mA
4.96V     -16.55mA   -10.82mA   -25.83mA
[GND_clamp]
|Voltage   I(typ)   I(min)   I(max)
-2.5V     -564.7mA   -543.1mA   -585.2mA
-1.18V    -82.37mA   -79.05mA   -91.19mA
-1.14V    -74.91mA   -71.4mA    -84.01mA
-1.1V     -67.72mA   -63.96mA   -77.3mA
-980mV    -48.69mA   -43.39mA   -60.85mA
-820mV    -30.38mA   -22.68mA   -40.71mA
-620mV    -10.92mA   -6.374mA   -15.3mA
-540mV    -5.123mA   -2.7mA     -7.317mA
-460mV    -1.524mA   -767.4uA   -2.097mA
-380mV    -292.5uA   -172.6uA   -366.3uA
20mV      0A         0A         0A
5V        0A         0A         0A
[POWER_clamp]
|Voltage   I(typ)   I(min)   I(max)
-2.48V    92.22mA    86.5mA     95.83mA
-2.16V    81.19mA    77.59mA    82.43mA
-1.84V    67mA       66.38mA    64.75mA
-1.52V    49.86mA    53.4mA     41.33mA
-1.28V    35.63mA    42.81mA    22.28mA
-1.2V     30.7mA     39.17mA    17mA
-960mV    15.93mA    27.93mA    6.582mA
-800mV    7.851mA    20.23mA    1.424mA
-560mV    1.299mA    8.796mA    199.2uA
-400mV    169.6uA    2.771mA    193.9uA
-160mV    101.6uA    144.1uA    192.3uA
5V        -4.578uA   -1.793uA   -63.13uA
[Ramp]
| variable   typ   min   max
dV/dt_r  0.4166/0.4824n   0.2824/0.6718n   0.6437/0.3733n
dV/dt_f  0.4573/0.4964n   0.2995/0.6757n   0.6376/0.3875n
R_load = 50.0000
[Rising Waveform]
R_fixture=   50.0000
V_fixture=   2.5000
V_fixture_min=   2.3800
V_fixture_max=   2.6300
|time   V(typ)   V(min)   V(max)
0s        1.738V     1.881V     1.567V
505.1ps   1.738V     1.881V     1.635V
606.1ps   1.738V     1.881V     2.076V
707.1ps   1.738V     1.881V     2.297V
909.1ps   2.178V     1.881V     2.535V
1.111ns   2.362V     1.885V     2.599V
1.212ns   2.411V     1.972V     2.611V
1.515ns   2.472V     2.276V     2.625V
2.121ns   2.496V     2.358V     2.63V
10ns      2.5V       2.38V      2.63V
[Rising Waveform]
R_fixture=   50.0000
V_fixture=   0.0
V_fixture_min=   0.0
V_fixture_max=   0.0
|time   V(typ)   V(min)   V(max)
0s        1.018uV    1.278uV    887.5nV
707.1ps   -2.782mV   7.328uV    22.45mV
1.111ns   33.47mV    -2.877mV   766mV
1.313ns   220.9mV    -12.97mV   933.8mV
1.515ns   433.1mV    -6.689mV   1.007V
1.717ns   565.5mV    13.38mV    1.041V
2.02ns    653.5mV    130.8mV    1.062V
2.525ns   697.2mV    351.6mV    1.071V
3.232ns   709.4mV    448mV      1.073V
10ns      711.8mV    470.7mV    1.073V
[Falling Waveform]
R_fixture=   50.0000
V_fixture=   0.0
V_fixture_min=   0.0
V_fixture_max=   0.0
|time   V(typ)   V(min)   V(max)
0s        711.8mV    470.7mV    1.073V
505.1ps   711.8mV    470.7mV    1.073V
606.1ps   711.7mV    470.7mV    941.4mV
707.1ps   712mV      470.7mV    492.5mV
808.1ps   711.9mV    470.7mV    212.4mV
1.212ns   126.5mV    471mV      14.58mV
1.414ns   38.72mV    448.9mV    4.987mV
1.818ns   7.442mV    87.93mV    686.5uV
2.222ns   1.836mV    18.27mV    149.4uV
10ns      12.37uV    -15.81uV   15.14uV
[Falling Waveform]
R_fixture=   50.0000
V_fixture=   2.5000
V_fixture_min=   2.3800
V_fixture_max=   2.6300
|time   V(typ)   V(min)   V(max)
0s        2.5V       2.38V      2.63V
606.1ps   2.5V       2.38V      2.658V
707.1ps   2.5V       2.38V      2.564V
909.1ps   2.517V     2.38V      2.104V
1.111ns   2.454V     2.38V      1.819V
1.414ns   2.09V      2.388V     1.649V
1.717ns   1.882V     2.38V      1.595V
2.424ns   1.757V     2.028V     1.57V
3.131ns   1.741V     1.912V     1.568V
10ns      1.738V     1.881V     1.567V
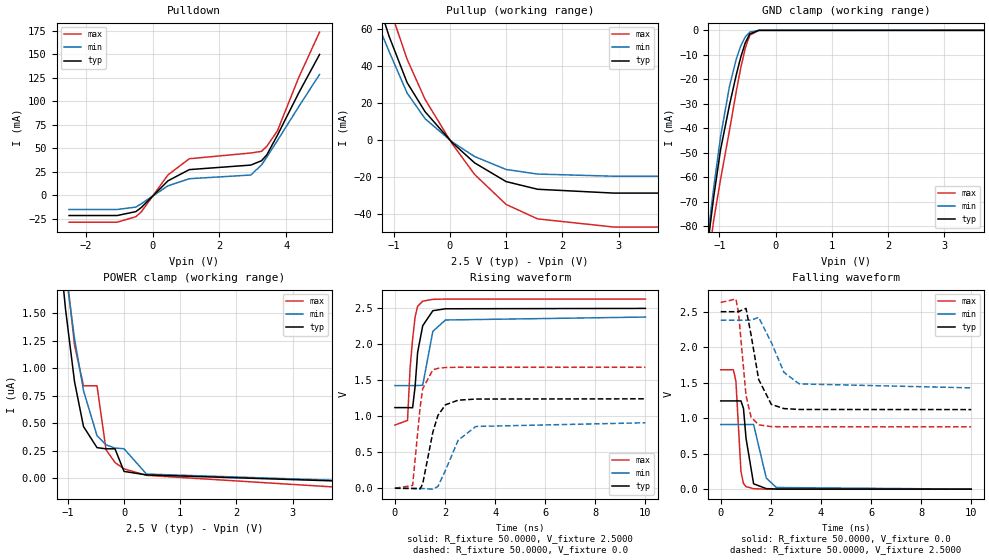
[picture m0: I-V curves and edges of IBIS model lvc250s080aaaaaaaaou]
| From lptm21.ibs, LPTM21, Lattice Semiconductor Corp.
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|   Model lvc250s080aaaaaaaaou
[Model]   lvc250s080aaaaaaaaou
Model_type   Output
Polarity   Non-Inverting
Enable   Active-Low
Vmeas =   1.2500V
Cref =   0.0F
Rref =   1.0000M
Vref =   0.0V
C_comp   4.2000pF   3.8000pF   7.5000pF
[Temperature Range]   25.0000   0.1050k   -40.0000
[Voltage Range]   2.5000V   2.3800V   2.6300V
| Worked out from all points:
|   slope of the pulldown table from 0 to 0.375 V, typ, clamps not added: 28.8 ohm
|   slope of the pullup table from 0 to 0.375 V, typ, clamps not added: 35 ohm
|   GND clamp passes 1 mA (typ) near -0.44 V on its own axis
|   rising waveform, R_fixture 50.0000, V_fixture 2.5000: 20-80 % time 286ps typ, 305ps min, 229ps max; typ from 1.12 V to 2.5 V
|   rising waveform, R_fixture 50.0000, V_fixture 0.0: 20-80 % time 465ps typ, 709ps min, 287ps max; typ from 0 V to 1.24 V
|   falling waveform, R_fixture 50.0000, V_fixture 0.0: 20-80 % time 232ps typ, 311ps min, 161ps max; typ from 1.24 V to 0 V
|   falling waveform, R_fixture 50.0000, V_fixture 2.5000: 20-80 % time 453ps typ, 672ps min, 302ps max; typ from 2.5 V to 1.12 V
[Pulldown]
|Voltage   I(typ)   I(min)   I(max)
-2.5V     -21.43mA   -15mA      -28.53mA
-1.06V    -21.43mA   -15mA      -28.53mA
-500mV    -17.29mA   -12.49mA   -22.68mA
-340mV    -13.01mA   -8.939mA   -17.7mA
460mV     15.44mA    10.15mA    21.72mA
1.1V      27.41mA    17.71mA    38.96mA
2.94V     32.22mA    21.64mA    45.09mA
3.26V     36.81mA    32.22mA    46.78mA
3.42V     43.03mA    40.73mA    52.13mA
3.74V     64.12mA    58.39mA    68.73mA
4.38V     109.2mA    94.54mA    125.7mA
5V        149.9mA    128.6mA    173.7mA
[Pullup]
|Voltage   I(typ)   I(min)   I(max)
-2.5V     179.5mA    144.9mA    221.4mA
-1.96V    137.7mA    112.2mA    171.5mA
-1.64V    109.2mA    89.19mA    137.2mA
-1.08V    56.2mA     47.99mA    72.47mA
-760mV    31.15mA    25.49mA    43.78mA
-440mV    15.37mA    11.59mA    22.04mA
40mV      -1.275mA   -931.8uA   -1.898mA
440mV     -12.3mA    -8.882mA   -18.58mA
1V        -22.45mA   -15.89mA   -34.81mA
1.56V     -26.61mA   -18.37mA   -42.65mA
2.92V     -28.69mA   -19.55mA   -47.08mA
4.96V     -28.69mA   -19.55mA   -47.14mA
[GND_clamp]
|Voltage   I(typ)   I(min)   I(max)
-2.5V     -564.7mA   -543.1mA   -585.2mA
-1.18V    -82.35mA   -79.03mA   -91.15mA
-1.14V    -74.88mA   -71.38mA   -83.96mA
-1.1V     -67.69mA   -63.94mA   -77.25mA
-980mV    -48.66mA   -43.36mA   -60.79mA
-820mV    -30.34mA   -22.65mA   -40.66mA
-700mV    -18.09mA   -11.63mA   -24.79mA
-620mV    -10.87mA   -6.335mA   -15.23mA
-540mV    -5.061mA   -2.654mA   -7.227mA
-460mV    -1.446mA   -714.8uA   -1.98mA
-300mV    -18.71uA   -15.93uA   -16.53uA
5V        0A         0A         0A
[POWER_clamp]
|Voltage   I(typ)   I(min)   I(max)
-2.48V    16.67uA    13.45uA    27.27uA
-1.2V     2.433uA    2.65uA     3.19uA
-1.12V    1.958uA    2.252uA    2.52uA
-1.04V    1.539uA    1.89uA     1.965uA
-880mV    879.3nA    1.27uA     1.211uA
-720mV    470.9nA    797.2nA    841.4nA
-480mV    279.3nA    388.4nA    841.4nA
-320mV    268.6nA    305nA      260.6nA
-160mV    268.6nA    275.3nA    144nA
0V        63.22nA    269.5nA    86.34nA
400mV     31.61nA    39.07nA    27.38nA
5V        -44.09nA   -38.33nA   -118.7nA
[Ramp]
| variable   typ   min   max
dV/dt_r  0.7610/0.4599n   0.5462/0.7020n   1.0094/0.2844n
dV/dt_f  0.8277/0.4481n   0.5716/0.6654n   1.0508/0.2990n
R_load = 50.0000
[Rising Waveform]
R_fixture=   50.0000
V_fixture=   2.5000
V_fixture_min=   2.3800
V_fixture_max=   2.6300
|time   V(typ)   V(min)   V(max)
0s        1.121V     1.427V     878.6mV
505.1ps   1.121V     1.427V     943.1mV
606.1ps   1.121V     1.427V     1.667V
707.1ps   1.119V     1.427V     2.071V
808.1ps   1.418V     1.427V     2.386V
909.1ps   1.892V     1.428V     2.53V
1.111ns   2.259V     1.432V     2.601V
1.515ns   2.468V     2.181V     2.626V
2.02ns    2.495V     2.339V     2.63V
10ns      2.5V       2.38V      2.63V
[Rising Waveform]
R_fixture=   50.0000
V_fixture=   0.0
V_fixture_min=   0.0
V_fixture_max=   0.0
|time   V(typ)   V(min)   V(max)
0s        666.9nV    899.8nV    549.6nV
707.1ps   -4.283mV   7.467uV    38.42mV
1.01ns    -9.285mV   -453.2uV   1.131V
1.111ns   62.83mV    -4.528mV   1.383V
1.515ns   778.6mV    -12.88mV   1.646V
1.717ns   1.012V     24.61mV    1.667V
2.02ns    1.16V      249.2mV    1.678V
2.525ns   1.224V     666.6mV    1.682V
3.232ns   1.24V      859.1mV    1.682V
10ns      1.243V     910.3mV    1.682V
[Falling Waveform]
R_fixture=   50.0000
V_fixture=   0.0
V_fixture_min=   0.0
V_fixture_max=   0.0
|time   V(typ)   V(min)   V(max)
0s        1.243V     910.3mV    1.682V
505.1ps   1.243V     910.3mV    1.682V
606.1ps   1.243V     910.3mV    1.524V
808.1ps   1.243V     910.4mV    247.8mV
909.1ps   1.137V     910.3mV    78.69mV
1.01ns    717.9mV    910.3mV    36.15mV
1.313ns   75.67mV    910.8mV    6.34mV
1.818ns   7.627mV    156mV      434.4uV
2.222ns   1.73mV     23.34mV    116uV
10ns      5.917uV    -6.372uV   -20.54uV
[Falling Waveform]
R_fixture=   50.0000
V_fixture=   2.5000
V_fixture_min=   2.3800
V_fixture_max=   2.6300
|time   V(typ)   V(min)   V(max)
0s        2.5V       2.38V      2.63V
606.1ps   2.5V       2.38V      2.678V
707.1ps   2.501V     2.38V      2.497V
1.01ns    2.546V     2.38V      1.319V
1.212ns   2.172V     2.381V     1.015V
1.515ns   1.545V     2.42V      905.6mV
2.02ns    1.194V     2.067V     881.4mV
2.525ns   1.135V     1.646V     879mV
3.131ns   1.123V     1.483V     878.7mV
10ns      1.121V     1.427V     878.6mV
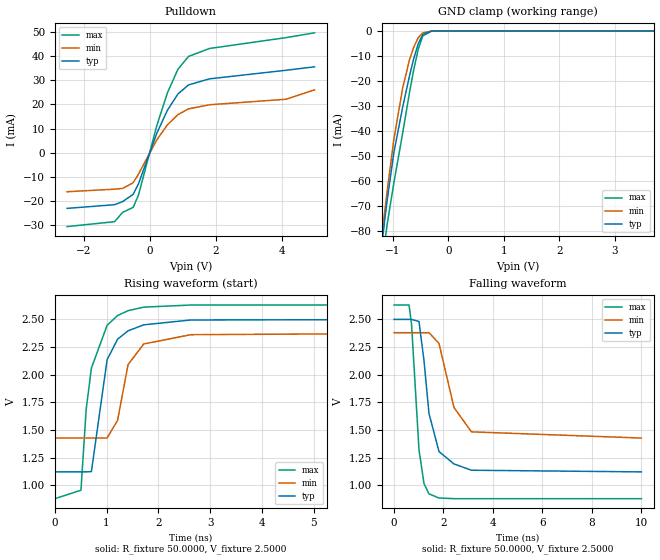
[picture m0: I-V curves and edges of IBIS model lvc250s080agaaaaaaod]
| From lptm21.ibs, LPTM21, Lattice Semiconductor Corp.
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|   Model lvc250s080agaaaaaaod
[Model]   lvc250s080agaaaaaaod
Model_type   I/O_open_drain
Polarity   Non-Inverting
Enable   Active-Low
Vinl =   0.7000V
Vinh =   1.7000V
Vmeas =   1.2500V
Cref =   0.0F
Rref =   1.0000M
Vref =   0.0V
C_comp   4.2000pF   3.8000pF   7.5000pF
[Temperature Range]   25.0000   0.1050k   -40.0000
[Voltage Range]   2.5000V   2.3800V   2.6300V
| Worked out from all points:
|   slope of the pulldown table from 0 to 0.375 V, typ, clamps not added: 28.8 ohm
|   GND clamp passes 1 mA (typ) near -0.44 V on its own axis
|   rising waveform, R_fixture 50.0000, V_fixture 2.5000: 20-80 % time 291ps typ, 291ps min, 287ps max; typ from 1.12 V to 2.5 V
|   falling waveform, R_fixture 50.0000, V_fixture 2.5000: 20-80 % time 456ps typ, 679ps min, 308ps max; typ from 2.5 V to 1.12 V
[Pulldown]
|Voltage   I(typ)   I(min)   I(max)
-2.5V     -23.08mA   -16.19mA   -30.63mA
-1.06V    -21.55mA   -15.12mA   -28.59mA
-820mV    -20.29mA   -14.82mA   -24.74mA
-500mV    -17.29mA   -12.49mA   -22.68mA
-340mV    -13.01mA   -8.939mA   -17.7mA
220mV     8.066mA    5.348mA    11.25mA
540mV     17.57mA    11.51mA    24.77mA
860mV     24.33mA    15.77mA    34.59mA
1.18V     28.07mA    18.15mA    39.87mA
1.82V     30.6mA     19.85mA    43.18mA
4.14V     34.15mA    22.14mA    47.67mA
5V        35.57mA    26.04mA    49.66mA
[GND_clamp]
|Voltage   I(typ)   I(min)   I(max)
-2.5V     -564.7mA   -543.1mA   -585.2mA
-1.18V    -82.35mA   -79.03mA   -91.15mA
-1.14V    -74.88mA   -71.38mA   -83.96mA
-1.1V     -67.69mA   -63.94mA   -77.25mA
-980mV    -48.66mA   -43.36mA   -60.79mA
-820mV    -30.34mA   -22.65mA   -40.66mA
-700mV    -18.09mA   -11.63mA   -24.79mA
-620mV    -10.87mA   -6.335mA   -15.23mA
-540mV    -5.061mA   -2.654mA   -7.227mA
-460mV    -1.446mA   -714.8uA   -1.98mA
-300mV    -18.71uA   -15.93uA   -16.53uA
5V        0A         0A         0A
[Ramp]
| variable   typ   min   max
dV/dt_r  0.8277/0.2881n   0.5716/0.2878n   1.0508/0.2837n
dV/dt_f  0.8277/0.4571n   0.5716/0.6724n   1.0508/0.3051n
R_load = 50.0000
[Rising Waveform]
R_fixture=   50.0000
V_fixture=   2.5000
V_fixture_min=   2.3800
V_fixture_max=   2.6300
|time   V(typ)   V(min)   V(max)
0s        1.121V     1.427V     878.6mV
505.1ps   1.121V     1.427V     955.2mV
606.1ps   1.121V     1.427V     1.686V
707.1ps   1.124V     1.427V     2.059V
1.01ns    2.135V     1.427V     2.446V
1.212ns   2.32V      1.587V     2.534V
1.414ns   2.396V     2.09V      2.578V
1.717ns   2.45V      2.277V     2.61V
2.626ns   2.494V     2.361V     2.629V
10ns      2.5V       2.38V      2.63V
[Falling Waveform]
R_fixture=   50.0000
V_fixture=   2.5000
V_fixture_min=   2.3800
V_fixture_max=   2.6300
|time   V(typ)   V(min)   V(max)
0s        2.5V       2.38V      2.63V
606.1ps   2.5V       2.38V      2.631V
707.1ps   2.5V       2.38V      2.459V
1.01ns    2.481V     2.38V      1.32V
1.212ns   2.126V     2.38V      1.016V
1.414ns   1.649V     2.38V      922.1mV
1.818ns   1.305V     2.283V     884.7mV
2.424ns   1.193V     1.703V     879mV
3.131ns   1.136V     1.483V     878.7mV
10ns      1.121V     1.427V     878.6mV
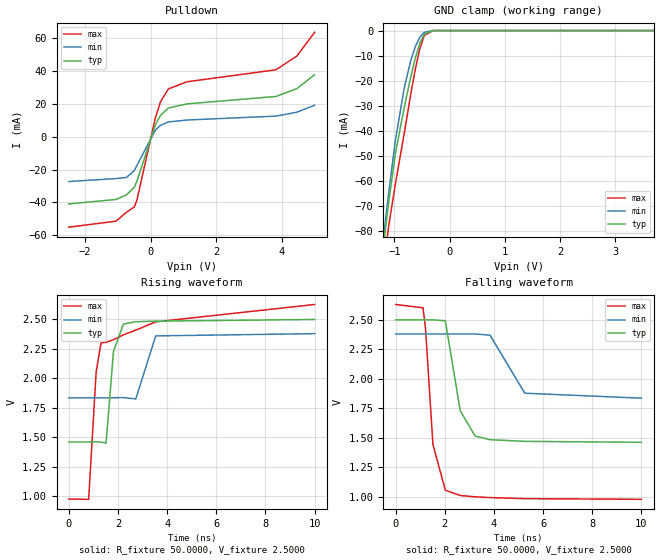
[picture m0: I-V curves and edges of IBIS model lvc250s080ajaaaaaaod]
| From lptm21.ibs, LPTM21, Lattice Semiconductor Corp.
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|   Model lvc250s080ajaaaaaaod
[Model]   lvc250s080ajaaaaaaod
Model_type   I/O_open_drain
Polarity   Non-Inverting
Enable   Active-Low
Vinl =   0.7000V
Vinh =   1.7000V
Vmeas =   1.2500V
Cref =   0.0F
Rref =   1.0000M
Vref =   0.0V
C_comp   4.2000pF   3.8000pF   7.5000pF
[Temperature Range]   25.0000   0.1050k   -40.0000
[Voltage Range]   2.5000V   2.3800V   2.6300V
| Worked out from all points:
|   slope of the pulldown table from 0 to 0.375 V, typ, clamps not added: 24.8 ohm
|   GND clamp passes 1 mA (typ) near -0.44 V on its own axis
|   rising waveform, R_fixture 50.0000, V_fixture 2.5000: 20-80 % time 245ps typ, 302ps min, 363ps max; typ from 1.46 V to 2.5 V
|   falling waveform, R_fixture 50.0000, V_fixture 2.5000: 20-80 % time 501ps typ, 770ps min, 347ps max; typ from 2.5 V to 1.46 V
[Pulldown]
|Voltage   I(typ)   I(min)   I(max)
-2.5V     -40.91mA   -27.25mA   -55.09mA
-1.06V    -38.2mA    -25.45mA   -51.44mA
-740mV    -35.34mA   -24.78mA   -45.98mA
-500mV    -30.67mA   -20.47mA   -42.72mA
-420mV    -26.98mA   -17.39mA   -38.43mA
140mV     7.298mA    4.05mA     11.57mA
300mV     13.2mA     7.088mA    21.46mA
540mV     17.57mA    9.078mA    29.25mA
1.1V      20.1mA     10.26mA    33.58mA
3.82V     24.63mA    12.65mA    40.91mA
4.46V     29.42mA    15.02mA    49.32mA
5V        37.9mA     19.29mA    63.76mA
[GND_clamp]
|Voltage   I(typ)   I(min)   I(max)
-2.5V     -564.7mA   -543mA     -585.2mA
-1.18V    -82.26mA   -78.93mA   -91.11mA
-1.14V    -74.8mA    -71.29mA   -83.93mA
-1.1V     -67.62mA   -63.85mA   -77.23mA
-980mV    -48.61mA   -43.3mA    -60.78mA
-820mV    -30.33mA   -22.62mA   -40.64mA
-700mV    -18.08mA   -11.62mA   -24.78mA
-620mV    -10.86mA   -6.33mA    -15.22mA
-540mV    -5.055mA   -2.65mA    -7.219mA
-460mV    -1.443mA   -713.2uA   -1.975mA
-300mV    -18.6uA    -15.87uA   -16.37uA
5V        0A         0A         0A
[Ramp]
| variable   typ   min   max
dV/dt_r  0.6228/0.2427n   0.3266/0.2991n   0.9893/0.3595n
dV/dt_f  0.6228/0.4956n   0.3262/0.7626n   0.9907/0.3435n
R_load = 50.0000
[Rising Waveform]
R_fixture=   50.0000
V_fixture=   2.5000
V_fixture_min=   2.3800
V_fixture_max=   2.6300
|time   V(typ)   V(min)   V(max)
0s        1.46V      1.834V     976.3mV
808.1ps   1.46V      1.834V     974.1mV
1.111ns   1.462V     1.834V     2.052V
1.313ns   1.459V     1.834V     2.3V
1.515ns   1.451V     1.834V     2.304V
1.818ns   2.228V     1.835V     2.327V
2.222ns   2.459V     1.836V     2.368V
2.727ns   2.479V     1.825V     2.408V
3.535ns   2.484V     2.359V     2.478V
10ns      2.498V     2.378V     2.625V
[Falling Waveform]
R_fixture=   50.0000
V_fixture=   2.5000
V_fixture_min=   2.3800
V_fixture_max=   2.6300
|time   V(typ)   V(min)   V(max)
0s        2.5V       2.38V      2.63V
1.111ns   2.5V       2.38V      2.602V
1.212ns   2.5V       2.38V      2.431V
1.515ns   2.5V       2.38V      1.444V
2.02ns    2.492V     2.38V      1.056V
2.626ns   1.729V     2.38V      1.011V
3.232ns   1.515V     2.38V      999.9mV
3.838ns   1.484V     2.37V      993.3mV
5.253ns   1.47V      1.878V     984.3mV
10ns      1.462V     1.836V     978.6mV
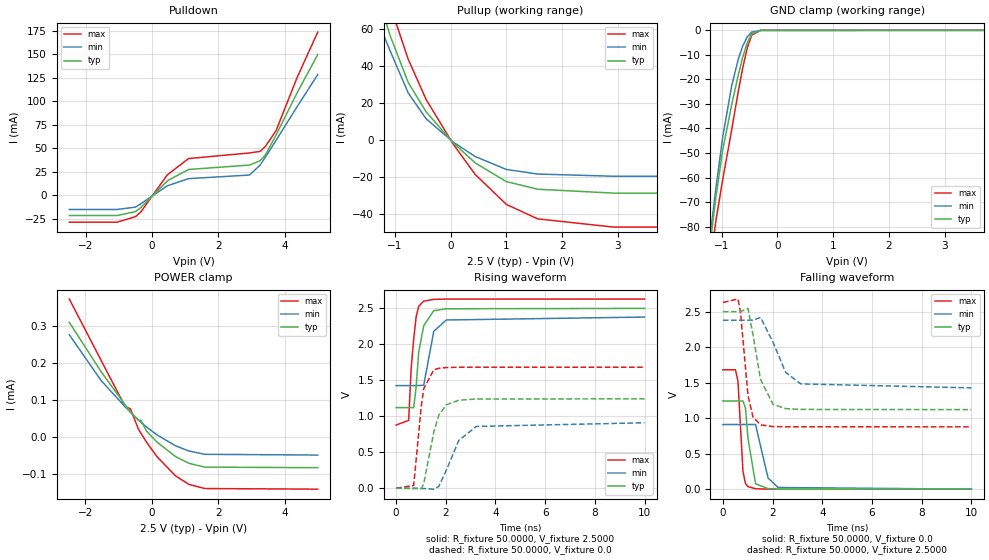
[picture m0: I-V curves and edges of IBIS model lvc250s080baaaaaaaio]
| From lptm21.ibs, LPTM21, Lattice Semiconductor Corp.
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|   Model lvc250s080baaaaaaaio
[Model]   lvc250s080baaaaaaaio
Model_type   I/O
Polarity   Non-Inverting
Enable   Active-Low
Vinl =   0.7000V
Vinh =   1.7000V
Vmeas =   1.2500V
Cref =   0.0F
Rref =   1.0000M
Vref =   0.0V
C_comp   4.2000pF   3.8000pF   7.5000pF
[Temperature Range]   25.0000   0.1050k   -40.0000
[Voltage Range]   2.5000V   2.3800V   2.6300V
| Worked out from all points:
|   slope of the pulldown table from 0 to 0.375 V, typ, clamps not added: 28.8 ohm
|   slope of the pullup table from 0 to 0.375 V, typ, clamps not added: 35.1 ohm
|   GND clamp passes 1 mA (typ) near -0.44 V on its own axis
|   rising waveform, R_fixture 50.0000, V_fixture 2.5000: 20-80 % time 286ps typ, 305ps min, 229ps max; typ from 1.12 V to 2.5 V
|   rising waveform, R_fixture 50.0000, V_fixture 0.0: 20-80 % time 465ps typ, 709ps min, 287ps max; typ from 0 V to 1.24 V
|   falling waveform, R_fixture 50.0000, V_fixture 0.0: 20-80 % time 232ps typ, 311ps min, 161ps max; typ from 1.24 V to 0 V
|   falling waveform, R_fixture 50.0000, V_fixture 2.5000: 20-80 % time 453ps typ, 672ps min, 302ps max; typ from 2.5 V to 1.12 V
[Pulldown]
|Voltage   I(typ)   I(min)   I(max)
-2.5V     -21.4mA    -14.99mA   -28.49mA
-1.06V    -21.4mA    -14.99mA   -28.49mA
-500mV    -17.23mA   -12.45mA   -22.6mA
-340mV    -12.93mA   -8.89mA    -17.57mA
460mV     15.52mA    10.2mA     21.86mA
1.1V      27.48mA    17.76mA    39.09mA
2.94V     32.18mA    21.6mA     45.05mA
3.26V     36.73mA    32.15mA    46.69mA
3.42V     42.93mA    40.65mA    52.01mA
3.74V     63.98mA    58.29mA    68.55mA
4.38V     109mA      94.36mA    125.4mA
5V        149.6mA    128.3mA    173.4mA
[Pullup]
|Voltage   I(typ)   I(min)   I(max)
-2.5V     179.2mA    144.7mA    221mA
-1.96V    137.4mA    112mA      171.2mA
-1.64V    109mA      89.05mA    137mA
-1.08V    56.08mA    47.91mA    72.3mA
-760mV    31.08mA    25.44mA    43.66mA
-440mV    15.32mA    11.56mA    21.99mA
40mV      -1.272mA   -929.5uA   -1.893mA
440mV     -12.26mA   -8.859mA   -18.52mA
1V        -22.39mA   -15.84mA   -34.7mA
1.56V     -26.53mA   -18.32mA   -42.52mA
2.92V     -28.61mA   -19.5mA    -46.95mA
4.96V     -28.61mA   -19.5mA    -47.01mA
[GND_clamp]
|Voltage   I(typ)   I(min)   I(max)
-2.5V     -564.6mA   -543.1mA   -585.1mA
-1.18V    -82.28mA   -79mA      -91.03mA
-1.14V    -74.81mA   -71.35mA   -83.85mA
-1.1V     -67.63mA   -63.91mA   -77.15mA
-980mV    -48.6mA    -43.33mA   -60.69mA
-820mV    -30.29mA   -22.62mA   -40.55mA
-700mV    -18.04mA   -11.6mA    -24.7mA
-620mV    -10.82mA   -6.314mA   -15.14mA
-540mV    -5.025mA   -2.64mA    -7.154mA
-460mV    -1.426mA   -708.3uA   -1.934mA
-300mV    -17.76uA   -15.73uA   -12.8uA
5V        0A         0A         0A
[POWER_clamp]
|Voltage   I(typ)   I(min)   I(max)
-2.48V    310.4uA    276.7uA    373.7uA
-1.52V    176.3uA    152.3uA    206.9uA
-800mV    86.61uA    81.35uA    82.18uA
-640mV    66.94uA    66.91uA    75.79uA
-400mV    44.51uA    45.44uA    20.86uA
-320mV    44.51uA    38.99uA    8.918uA
-160mV    16.15uA    26.85uA    -13.85uA
160mV     -14.29uA   5.152uA    -53.97uA
720mV     -53.87uA   -24.56uA   -106.2uA
1.12V     -71.9uA    -38.53uA   -129.1uA
1.6V      -82.26uA   -47.53uA   -140.4uA
5V        -83.86uA   -49.55uA   -142.1uA
[Ramp]
| variable   typ   min   max
dV/dt_r  0.7610/0.4599n   0.5462/0.7020n   1.0094/0.2844n
dV/dt_f  0.8277/0.4481n   0.5716/0.6654n   1.0508/0.2990n
R_load = 50.0000
[Rising Waveform]
R_fixture=   50.0000
V_fixture=   2.5000
V_fixture_min=   2.3800
V_fixture_max=   2.6300
|time   V(typ)   V(min)   V(max)
0s        1.121V     1.427V     878.6mV
505.1ps   1.121V     1.427V     943.1mV
606.1ps   1.121V     1.427V     1.667V
707.1ps   1.119V     1.427V     2.071V
808.1ps   1.418V     1.427V     2.386V
909.1ps   1.892V     1.428V     2.53V
1.111ns   2.259V     1.432V     2.601V
1.515ns   2.468V     2.181V     2.626V
2.02ns    2.495V     2.339V     2.63V
10ns      2.5V       2.38V      2.63V
[Rising Waveform]
R_fixture=   50.0000
V_fixture=   0.0
V_fixture_min=   0.0
V_fixture_max=   0.0
|time   V(typ)   V(min)   V(max)
0s        666.9nV    899.8nV    549.6nV
707.1ps   -4.283mV   7.467uV    38.42mV
1.01ns    -9.285mV   -453.2uV   1.131V
1.111ns   62.83mV    -4.528mV   1.383V
1.515ns   778.6mV    -12.88mV   1.646V
1.717ns   1.012V     24.61mV    1.667V
2.02ns    1.16V      249.2mV    1.678V
2.525ns   1.224V     666.6mV    1.682V
3.232ns   1.24V      859.1mV    1.682V
10ns      1.243V     910.3mV    1.682V
[Falling Waveform]
R_fixture=   50.0000
V_fixture=   0.0
V_fixture_min=   0.0
V_fixture_max=   0.0
|time   V(typ)   V(min)   V(max)
0s        1.243V     910.3mV    1.682V
505.1ps   1.243V     910.3mV    1.682V
606.1ps   1.243V     910.3mV    1.524V
808.1ps   1.243V     910.4mV    247.8mV
909.1ps   1.137V     910.3mV    78.69mV
1.01ns    717.9mV    910.3mV    36.15mV
1.313ns   75.67mV    910.8mV    6.34mV
1.818ns   7.627mV    156mV      434.4uV
2.222ns   1.73mV     23.34mV    116uV
10ns      5.917uV    -6.372uV   -20.54uV
[Falling Waveform]
R_fixture=   50.0000
V_fixture=   2.5000
V_fixture_min=   2.3800
V_fixture_max=   2.6300
|time   V(typ)   V(min)   V(max)
0s        2.5V       2.38V      2.63V
606.1ps   2.5V       2.38V      2.678V
707.1ps   2.501V     2.38V      2.497V
1.01ns    2.546V     2.38V      1.319V
1.212ns   2.172V     2.381V     1.015V
1.515ns   1.545V     2.42V      905.6mV
2.02ns    1.194V     2.067V     881.4mV
2.525ns   1.135V     1.646V     879mV
3.131ns   1.123V     1.483V     878.7mV
10ns      1.121V     1.427V     878.6mV
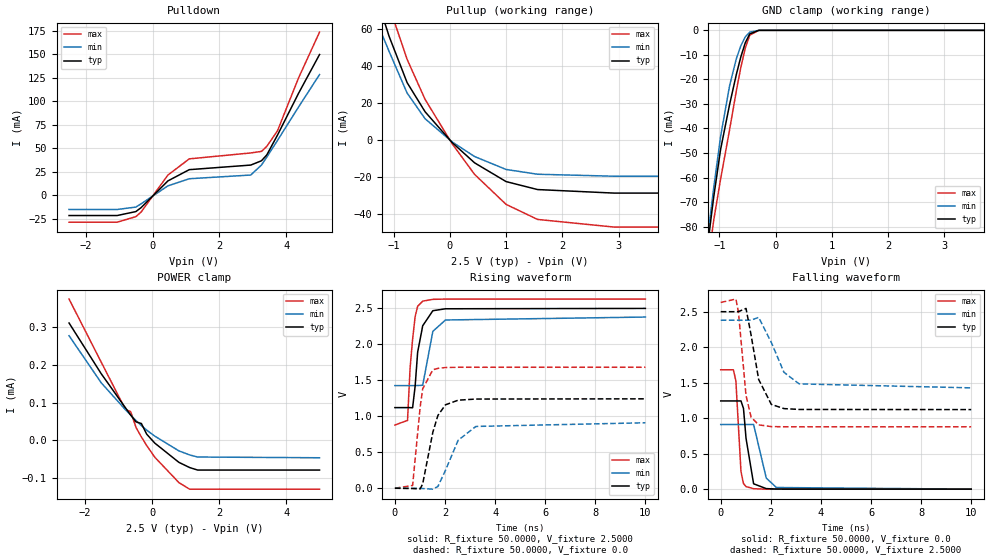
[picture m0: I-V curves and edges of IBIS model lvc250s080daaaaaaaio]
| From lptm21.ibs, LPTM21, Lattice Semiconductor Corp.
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|   Model lvc250s080daaaaaaaio
[Model]   lvc250s080daaaaaaaio
Model_type   I/O
Polarity   Non-Inverting
Enable   Active-Low
Vinl =   0.7000V
Vinh =   1.7000V
Vmeas =   1.2500V
Cref =   0.0F
Rref =   1.0000M
Vref =   0.0V
C_comp   4.2000pF   3.8000pF   7.5000pF
[Temperature Range]   25.0000   0.1050k   -40.0000
[Voltage Range]   2.5000V   2.3800V   2.6300V
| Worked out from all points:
|   slope of the pulldown table from 0 to 0.375 V, typ, clamps not added: 29 ohm
|   slope of the pullup table from 0 to 0.375 V, typ, clamps not added: 35.1 ohm
|   GND clamp passes 1 mA (typ) near -0.44 V on its own axis
|   rising waveform, R_fixture 50.0000, V_fixture 2.5000: 20-80 % time 286ps typ, 305ps min, 229ps max; typ from 1.12 V to 2.5 V
|   rising waveform, R_fixture 50.0000, V_fixture 0.0: 20-80 % time 465ps typ, 709ps min, 287ps max; typ from 0 V to 1.24 V
|   falling waveform, R_fixture 50.0000, V_fixture 0.0: 20-80 % time 232ps typ, 311ps min, 161ps max; typ from 1.24 V to 0 V
|   falling waveform, R_fixture 50.0000, V_fixture 2.5000: 20-80 % time 453ps typ, 672ps min, 302ps max; typ from 2.5 V to 1.12 V
[Pulldown]
|Voltage   I(typ)   I(min)   I(max)
-2.5V     -21.4mA    -14.98mA   -28.48mA
-1.06V    -21.4mA    -14.98mA   -28.48mA
-500mV    -17.22mA   -12.44mA   -22.59mA
-340mV    -12.93mA   -8.894mA   -17.57mA
460mV     15.37mA    10.11mA    21.58mA
1.1V      27.31mA    17.67mA    38.78mA
2.94V     32.18mA    21.6mA     45.05mA
3.26V     36.73mA    32.15mA    46.69mA
3.42V     42.93mA    40.65mA    52.01mA
3.74V     63.98mA    58.29mA    68.55mA
4.38V     109mA      94.36mA    125.4mA
5V        149.6mA    128.3mA    173.4mA
[Pullup]
|Voltage   I(typ)   I(min)   I(max)
-2.5V     179.2mA    144.7mA    221mA
-1.96V    137.4mA    112mA      171.2mA
-1.64V    109mA      89.05mA    137mA
-1.08V    56.08mA    47.91mA    72.3mA
-760mV    31.08mA    25.44mA    43.66mA
-440mV    15.32mA    11.56mA    21.99mA
40mV      -1.272mA   -929.5uA   -1.893mA
440mV     -12.26mA   -8.859mA   -18.52mA
1V        -22.39mA   -15.84mA   -34.7mA
1.56V     -26.7mA    -18.42mA   -42.84mA
2.92V     -28.61mA   -19.5mA    -46.97mA
4.96V     -28.61mA   -19.5mA    -47.02mA
[GND_clamp]
|Voltage   I(typ)   I(min)   I(max)
-2.5V     -564.6mA   -543.1mA   -585.1mA
-1.18V    -82.29mA   -79mA      -91.05mA
-1.14V    -74.82mA   -71.35mA   -83.87mA
-1.1V     -67.64mA   -63.91mA   -77.16mA
-980mV    -48.61mA   -43.34mA   -60.71mA
-820mV    -30.3mA    -22.63mA   -40.57mA
-700mV    -18.05mA   -11.61mA   -24.72mA
-620mV    -10.84mA   -6.326mA   -15.16mA
-540mV    -5.04mA    -2.652mA   -7.178mA
-460mV    -1.44mA    -719uA     -1.958mA
-300mV    -9.986uA   -9.27uA    -5.3uA
5V        0A         0A         0A
[POWER_clamp]
|Voltage   I(typ)   I(min)   I(max)
-2.48V    310.4uA    276.7uA    373.7uA
-1.52V    176.3uA    152.3uA    206.9uA
-800mV    86.61uA    81.35uA    82.18uA
-640mV    66.94uA    66.91uA    75.79uA
-480mV    48.86uA    52.22uA    34.01uA
-320mV    44.51uA    38.99uA    8.918uA
-160mV    16.15uA    26.85uA    -13.85uA
80mV      -7.284uA   11.17uA    -44.64uA
800mV     -58.16uA   -27.83uA   -111.7uA
1.12V     -71.9uA    -38.53uA   -129.1uA
1.36V     -78.59uA   -44.07uA   -129.1uA
5V        -78.59uA   -46.05uA   -129.1uA
[Ramp]
| variable   typ   min   max
dV/dt_r  0.7610/0.4599n   0.5462/0.7020n   1.0094/0.2844n
dV/dt_f  0.8277/0.4481n   0.5716/0.6654n   1.0508/0.2990n
R_load = 50.0000
[Rising Waveform]
R_fixture=   50.0000
V_fixture=   2.5000
V_fixture_min=   2.3800
V_fixture_max=   2.6300
|time   V(typ)   V(min)   V(max)
0s        1.121V     1.427V     878.6mV
505.1ps   1.121V     1.427V     943.1mV
606.1ps   1.121V     1.427V     1.667V
707.1ps   1.119V     1.427V     2.071V
808.1ps   1.418V     1.427V     2.386V
909.1ps   1.892V     1.428V     2.53V
1.111ns   2.259V     1.432V     2.601V
1.515ns   2.468V     2.181V     2.626V
2.02ns    2.495V     2.339V     2.63V
10ns      2.5V       2.38V      2.63V
[Rising Waveform]
R_fixture=   50.0000
V_fixture=   0.0
V_fixture_min=   0.0
V_fixture_max=   0.0
|time   V(typ)   V(min)   V(max)
0s        666.9nV    899.8nV    549.6nV
707.1ps   -4.283mV   7.467uV    38.42mV
1.01ns    -9.285mV   -453.2uV   1.131V
1.111ns   62.83mV    -4.528mV   1.383V
1.515ns   778.6mV    -12.88mV   1.646V
1.717ns   1.012V     24.61mV    1.667V
2.02ns    1.16V      249.2mV    1.678V
2.525ns   1.224V     666.6mV    1.682V
3.232ns   1.24V      859.1mV    1.682V
10ns      1.243V     910.3mV    1.682V
[Falling Waveform]
R_fixture=   50.0000
V_fixture=   0.0
V_fixture_min=   0.0
V_fixture_max=   0.0
|time   V(typ)   V(min)   V(max)
0s        1.243V     910.3mV    1.682V
505.1ps   1.243V     910.3mV    1.682V
606.1ps   1.243V     910.3mV    1.524V
808.1ps   1.243V     910.4mV    247.8mV
909.1ps   1.137V     910.3mV    78.69mV
1.01ns    717.9mV    910.3mV    36.15mV
1.313ns   75.67mV    910.8mV    6.34mV
1.818ns   7.627mV    156mV      434.4uV
2.222ns   1.73mV     23.34mV    116uV
10ns      5.917uV    -6.372uV   -20.54uV
[Falling Waveform]
R_fixture=   50.0000
V_fixture=   2.5000
V_fixture_min=   2.3800
V_fixture_max=   2.6300
|time   V(typ)   V(min)   V(max)
0s        2.5V       2.38V      2.63V
606.1ps   2.5V       2.38V      2.678V
707.1ps   2.501V     2.38V      2.497V
1.01ns    2.546V     2.38V      1.319V
1.212ns   2.172V     2.381V     1.015V
1.515ns   1.545V     2.42V      905.6mV
2.02ns    1.194V     2.067V     881.4mV
2.525ns   1.135V     1.646V     879mV
3.131ns   1.123V     1.483V     878.7mV
10ns      1.121V     1.427V     878.6mV
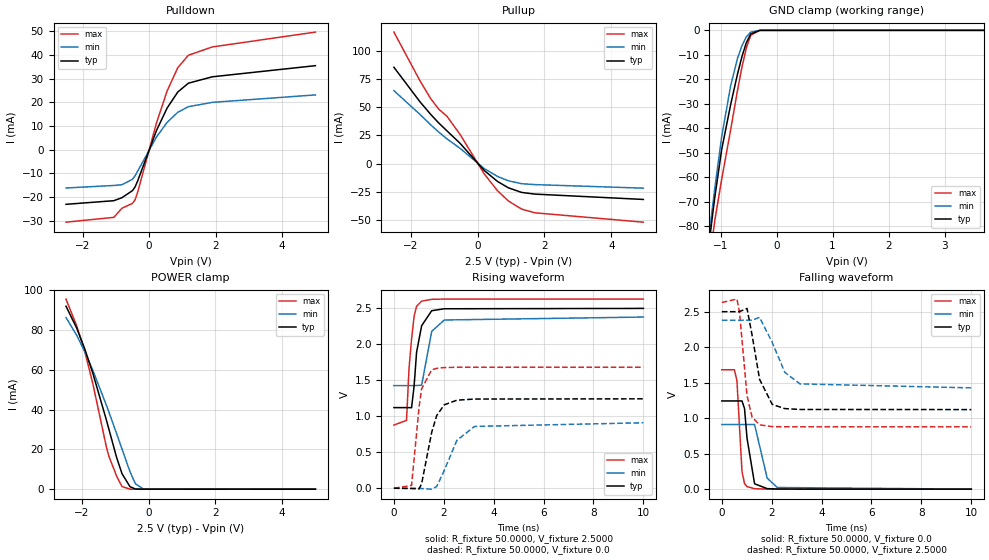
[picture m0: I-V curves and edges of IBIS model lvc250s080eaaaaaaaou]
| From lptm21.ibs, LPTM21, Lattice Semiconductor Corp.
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|   Model lvc250s080eaaaaaaaou
[Model]   lvc250s080eaaaaaaaou
Model_type   Output
Polarity   Non-Inverting
Enable   Active-Low
Vmeas =   1.2500V
Cref =   0.0F
Rref =   1.0000M
Vref =   0.0V
C_comp   4.2000pF   3.8000pF   7.5000pF
[Temperature Range]   25.0000   0.1050k   -40.0000
[Voltage Range]   2.5000V   2.3800V   2.6300V
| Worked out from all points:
|   slope of the pulldown table from 0 to 0.375 V, typ, clamps not added: 28.8 ohm
|   slope of the pullup table from 0 to 0.375 V, typ, clamps not added: 35 ohm
|   GND clamp passes 1 mA (typ) near -0.44 V on its own axis
|   POWER clamp passes 1 mA (typ) near -0.54 V on its own axis
|   rising waveform, R_fixture 50.0000, V_fixture 2.5000: 20-80 % time 286ps typ, 305ps min, 229ps max; typ from 1.12 V to 2.5 V
|   rising waveform, R_fixture 50.0000, V_fixture 0.0: 20-80 % time 465ps typ, 709ps min, 287ps max; typ from 0 V to 1.24 V
|   falling waveform, R_fixture 50.0000, V_fixture 0.0: 20-80 % time 232ps typ, 311ps min, 161ps max; typ from 1.24 V to 0 V
|   falling waveform, R_fixture 50.0000, V_fixture 2.5000: 20-80 % time 453ps typ, 672ps min, 302ps max; typ from 2.5 V to 1.12 V
[Pulldown]
|Voltage   I(typ)   I(min)   I(max)
-2.5V     -23.08mA   -16.19mA   -30.63mA
-1.06V    -21.55mA   -15.12mA   -28.59mA
-820mV    -20.29mA   -14.82mA   -24.74mA
-500mV    -17.29mA   -12.49mA   -22.68mA
-420mV    -15.65mA   -10.92mA   -21.14mA
-340mV    -13.01mA   -8.939mA   -17.7mA
220mV     8.066mA    5.348mA    11.25mA
540mV     17.57mA    11.51mA    24.77mA
860mV     24.33mA    15.77mA    34.59mA
1.18V     28.07mA    18.15mA    39.87mA
1.9V      30.77mA    19.97mA    43.38mA
5V        35.47mA    23.12mA    49.65mA
[Pullup]
|Voltage   I(typ)   I(min)   I(max)
-2.5V     85.26mA    64.56mA    116.4mA
-1.72V    54.7mA     43.52mA    73.27mA
-1.4V     43.55mA    34.33mA    57.52mA
-1.16V    35.96mA    27.95mA    48.16mA
-920mV    29.16mA    22.05mA    42.11mA
-520mV    17.92mA    13.48mA    25.76mA
200mV     -6.061mA   -4.41mA    -9.073mA
600mV     -15.83mA   -11.37mA   -24.07mA
920mV     -21.38mA   -15.18mA   -33mA
1.32V     -25.51mA   -17.78mA   -40.3mA
1.72V     -27mA      -18.59mA   -43.55mA
4.96V     -31.72mA   -21.73mA   -51.85mA
[GND_clamp]
|Voltage   I(typ)   I(min)   I(max)
-2.5V     -564.7mA   -543.1mA   -585.2mA
-1.18V    -82.35mA   -79.03mA   -91.15mA
-1.14V    -74.88mA   -71.38mA   -83.96mA
-1.1V     -67.69mA   -63.94mA   -77.25mA
-980mV    -48.66mA   -43.36mA   -60.79mA
-820mV    -30.34mA   -22.65mA   -40.66mA
-700mV    -18.09mA   -11.63mA   -24.79mA
-620mV    -10.87mA   -6.335mA   -15.23mA
-540mV    -5.061mA   -2.654mA   -7.227mA
-460mV    -1.446mA   -714.8uA   -1.98mA
-300mV    -18.71uA   -15.93uA   -16.53uA
5V        0A         0A         0A
[POWER_clamp]
|Voltage   I(typ)   I(min)   I(max)
-2.48V    91.96mA    86.23mA    95.54mA
-2.16V    80.94mA    77.35mA    82.15mA
-1.92V    70.61mA    69.17mA    69.43mA
-1.68V    58.52mA    59.9mA     53.37mA
-1.28V    35.44mA    42.67mA    22.07mA
-1.2V     30.53mA    39.03mA    16.84mA
-960mV    15.8mA     27.82mA    6.447mA
-800mV    7.76mA     20.14mA    1.303mA
-560mV    1.23mA     8.728mA    11.53uA
-400mV    83.98uA    2.726mA    532.6nA
-160mV    776.1nA    102uA      144nA
5V        -44.09nA   -38.33nA   -118.7nA
[Ramp]
| variable   typ   min   max
dV/dt_r  0.7610/0.4599n   0.5462/0.7020n   1.0094/0.2844n
dV/dt_f  0.8277/0.4481n   0.5716/0.6654n   1.0508/0.2990n
R_load = 50.0000
[Rising Waveform]
R_fixture=   50.0000
V_fixture=   2.5000
V_fixture_min=   2.3800
V_fixture_max=   2.6300
|time   V(typ)   V(min)   V(max)
0s        1.121V     1.427V     878.6mV
505.1ps   1.121V     1.427V     943.1mV
606.1ps   1.121V     1.427V     1.667V
707.1ps   1.119V     1.427V     2.071V
808.1ps   1.418V     1.427V     2.386V
909.1ps   1.892V     1.428V     2.53V
1.111ns   2.259V     1.432V     2.601V
1.515ns   2.468V     2.181V     2.626V
2.02ns    2.495V     2.339V     2.63V
10ns      2.5V       2.38V      2.63V
[Rising Waveform]
R_fixture=   50.0000
V_fixture=   0.0
V_fixture_min=   0.0
V_fixture_max=   0.0
|time   V(typ)   V(min)   V(max)
0s        666.9nV    899.8nV    549.6nV
707.1ps   -4.283mV   7.467uV    38.42mV
1.01ns    -9.285mV   -453.2uV   1.131V
1.111ns   62.83mV    -4.528mV   1.383V
1.515ns   778.6mV    -12.88mV   1.646V
1.717ns   1.012V     24.61mV    1.667V
2.02ns    1.16V      249.2mV    1.678V
2.525ns   1.224V     666.6mV    1.682V
3.232ns   1.24V      859.1mV    1.682V
10ns      1.243V     910.3mV    1.682V
[Falling Waveform]
R_fixture=   50.0000
V_fixture=   0.0
V_fixture_min=   0.0
V_fixture_max=   0.0
|time   V(typ)   V(min)   V(max)
0s        1.243V     910.3mV    1.682V
505.1ps   1.243V     910.3mV    1.682V
606.1ps   1.243V     910.3mV    1.524V
808.1ps   1.243V     910.4mV    247.8mV
909.1ps   1.137V     910.3mV    78.69mV
1.01ns    717.9mV    910.3mV    36.15mV
1.313ns   75.67mV    910.8mV    6.34mV
1.818ns   7.627mV    156mV      434.4uV
2.222ns   1.73mV     23.34mV    116uV
10ns      5.917uV    -6.372uV   -20.54uV
[Falling Waveform]
R_fixture=   50.0000
V_fixture=   2.5000
V_fixture_min=   2.3800
V_fixture_max=   2.6300
|time   V(typ)   V(min)   V(max)
0s        2.5V       2.38V      2.63V
606.1ps   2.5V       2.38V      2.678V
707.1ps   2.501V     2.38V      2.497V
1.01ns    2.546V     2.38V      1.319V
1.212ns   2.172V     2.381V     1.015V
1.515ns   1.545V     2.42V      905.6mV
2.02ns    1.194V     2.067V     881.4mV
2.525ns   1.135V     1.646V     879mV
3.131ns   1.123V     1.483V     878.7mV
10ns      1.121V     1.427V     878.6mV
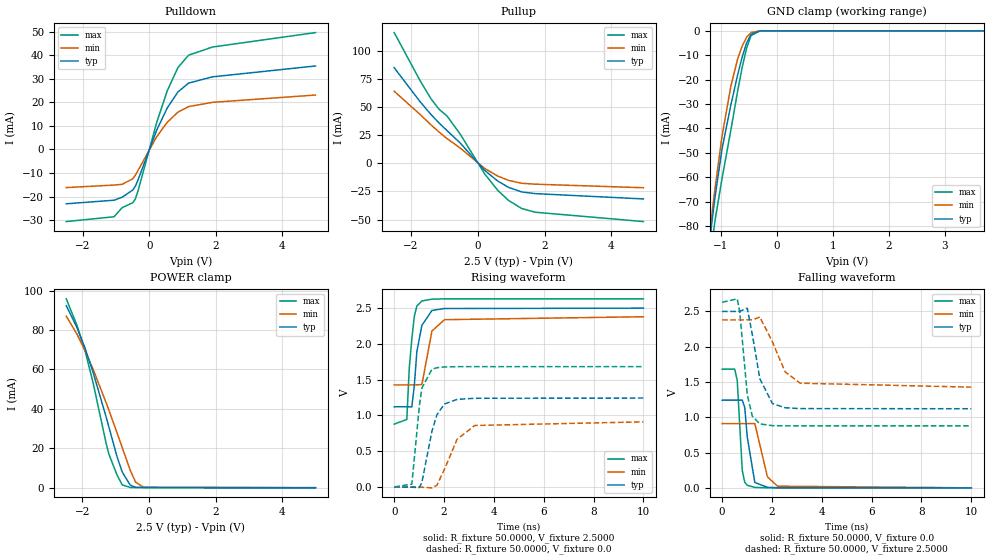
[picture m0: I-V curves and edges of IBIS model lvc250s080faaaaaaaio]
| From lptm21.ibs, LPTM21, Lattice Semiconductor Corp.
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|   Model lvc250s080faaaaaaaio
[Model]   lvc250s080faaaaaaaio
Model_type   I/O
Polarity   Non-Inverting
Enable   Active-Low
Vinl =   0.7000V
Vinh =   1.7000V
Vmeas =   1.2500V
Cref =   0.0F
Rref =   1.0000M
Vref =   0.0V
C_comp   4.2000pF   3.8000pF   7.5000pF
[Temperature Range]   25.0000   0.1050k   -40.0000
[Voltage Range]   2.5000V   2.3800V   2.6300V
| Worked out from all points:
|   slope of the pulldown table from 0 to 0.375 V, typ, clamps not added: 28.8 ohm
|   slope of the pullup table from 0 to 0.375 V, typ, clamps not added: 35.1 ohm
|   GND clamp passes 1 mA (typ) near -0.44 V on its own axis
|   POWER clamp passes 1 mA (typ) near -0.54 V on its own axis
|   rising waveform, R_fixture 50.0000, V_fixture 2.5000: 20-80 % time 286ps typ, 305ps min, 229ps max; typ from 1.12 V to 2.5 V
|   rising waveform, R_fixture 50.0000, V_fixture 0.0: 20-80 % time 465ps typ, 709ps min, 287ps max; typ from 0 V to 1.24 V
|   falling waveform, R_fixture 50.0000, V_fixture 0.0: 20-80 % time 232ps typ, 311ps min, 161ps max; typ from 1.24 V to 0 V
|   falling waveform, R_fixture 50.0000, V_fixture 2.5000: 20-80 % time 453ps typ, 672ps min, 302ps max; typ from 2.5 V to 1.12 V
[Pulldown]
|Voltage   I(typ)   I(min)   I(max)
-2.5V     -23.05mA   -16.17mA   -30.59mA
-1.06V    -21.53mA   -15.1mA    -28.55mA
-820mV    -20.26mA   -14.8mA    -24.7mA
-500mV    -17.23mA   -12.45mA   -22.6mA
-420mV    -15.58mA   -10.87mA   -21.02mA
-340mV    -12.93mA   -8.89mA    -17.57mA
220mV     8.15mA     5.397mA    11.39mA
540mV     17.65mA    11.56mA    24.92mA
860mV     24.41mA    15.82mA    34.73mA
1.18V     28.15mA    18.19mA    40mA
1.9V      30.82mA    19.99mA    43.47mA
5V        35.43mA    23.1mA     49.6mA
[Pullup]
|Voltage   I(typ)   I(min)   I(max)
-2.5V     84.84mA    63.92mA    116mA
-1.72V    54.44mA    43.22mA    73.04mA
-1.4V     43.35mA    34.13mA    57.32mA
-1.16V    35.82mA    27.8mA     48.01mA
-920mV    29.07mA    21.96mA    42.03mA
-520mV    17.88mA    13.45mA    25.72mA
200mV     -6.044mA   -4.398mA   -9.046mA
600mV     -15.78mA   -11.34mA   -23.99mA
920mV     -21.31mA   -15.14mA   -32.9mA
1.32V     -25.43mA   -17.74mA   -40.17mA
1.72V     -26.92mA   -18.54mA   -43.41mA
4.96V     -31.63mA   -21.68mA   -51.71mA
[GND_clamp]
|Voltage   I(typ)   I(min)   I(max)
-2.5V     -564.6mA   -543.1mA   -585.1mA
-1.18V    -82.28mA   -79mA      -91.03mA
-1.14V    -74.81mA   -71.35mA   -83.85mA
-1.1V     -67.63mA   -63.91mA   -77.15mA
-980mV    -48.6mA    -43.33mA   -60.69mA
-820mV    -30.29mA   -22.62mA   -40.55mA
-700mV    -18.04mA   -11.6mA    -24.7mA
-620mV    -10.82mA   -6.314mA   -15.14mA
-540mV    -5.025mA   -2.64mA    -7.154mA
-460mV    -1.426mA   -708.3uA   -1.934mA
-300mV    -17.76uA   -15.73uA   -12.8uA
5V        0A         0A         0A
[POWER_clamp]
|Voltage   I(typ)   I(min)   I(max)
-2.48V    92.38mA    87.03mA    95.82mA
-2.16V    81.29mA    77.94mA    82.39mA
-1.92V    70.92mA    69.63mA    69.65mA
-1.68V    58.78mA    60.26mA    53.56mA
-1.28V    35.62mA    42.91mA    22.18mA
-1.2V     30.69mA    39.25mA    16.92mA
-960mV    15.9mA     27.98mA    6.508mA
-800mV    7.821mA    20.25mA    1.349mA
-560mV    1.267mA    8.796mA    53.58uA
-400mV    117.5uA    2.764mA    20.86uA
-160mV    16.15uA    125.2uA    -13.85uA
5V        -83.86uA   -49.55uA   -142.1uA
[Ramp]
| variable   typ   min   max
dV/dt_r  0.7610/0.4599n   0.5462/0.7020n   1.0094/0.2844n
dV/dt_f  0.8277/0.4481n   0.5716/0.6654n   1.0508/0.2990n
R_load = 50.0000
[Rising Waveform]
R_fixture=   50.0000
V_fixture=   2.5000
V_fixture_min=   2.3800
V_fixture_max=   2.6300
|time   V(typ)   V(min)   V(max)
0s        1.121V     1.427V     878.6mV
505.1ps   1.121V     1.427V     943.1mV
606.1ps   1.121V     1.427V     1.667V
707.1ps   1.119V     1.427V     2.071V
808.1ps   1.418V     1.427V     2.386V
909.1ps   1.892V     1.428V     2.53V
1.111ns   2.259V     1.432V     2.601V
1.515ns   2.468V     2.181V     2.626V
2.02ns    2.495V     2.339V     2.63V
10ns      2.5V       2.38V      2.63V
[Rising Waveform]
R_fixture=   50.0000
V_fixture=   0.0
V_fixture_min=   0.0
V_fixture_max=   0.0
|time   V(typ)   V(min)   V(max)
0s        666.9nV    899.8nV    549.6nV
707.1ps   -4.283mV   7.467uV    38.42mV
1.01ns    -9.285mV   -453.2uV   1.131V
1.111ns   62.83mV    -4.528mV   1.383V
1.515ns   778.6mV    -12.88mV   1.646V
1.717ns   1.012V     24.61mV    1.667V
2.02ns    1.16V      249.2mV    1.678V
2.525ns   1.224V     666.6mV    1.682V
3.232ns   1.24V      859.1mV    1.682V
10ns      1.243V     910.3mV    1.682V
[Falling Waveform]
R_fixture=   50.0000
V_fixture=   0.0
V_fixture_min=   0.0
V_fixture_max=   0.0
|time   V(typ)   V(min)   V(max)
0s        1.243V     910.3mV    1.682V
505.1ps   1.243V     910.3mV    1.682V
606.1ps   1.243V     910.3mV    1.524V
808.1ps   1.243V     910.4mV    247.8mV
909.1ps   1.137V     910.3mV    78.69mV
1.01ns    717.9mV    910.3mV    36.15mV
1.313ns   75.67mV    910.8mV    6.34mV
1.818ns   7.627mV    156mV      434.4uV
2.222ns   1.73mV     23.34mV    116uV
10ns      5.917uV    -6.372uV   -20.54uV
[Falling Waveform]
R_fixture=   50.0000
V_fixture=   2.5000
V_fixture_min=   2.3800
V_fixture_max=   2.6300
|time   V(typ)   V(min)   V(max)
0s        2.5V       2.38V      2.63V
606.1ps   2.5V       2.38V      2.678V
707.1ps   2.501V     2.38V      2.497V
1.01ns    2.546V     2.38V      1.319V
1.212ns   2.172V     2.381V     1.015V
1.515ns   1.545V     2.42V      905.6mV
2.02ns    1.194V     2.067V     881.4mV
2.525ns   1.135V     1.646V     879mV
3.131ns   1.123V     1.483V     878.7mV
10ns      1.121V     1.427V     878.6mV
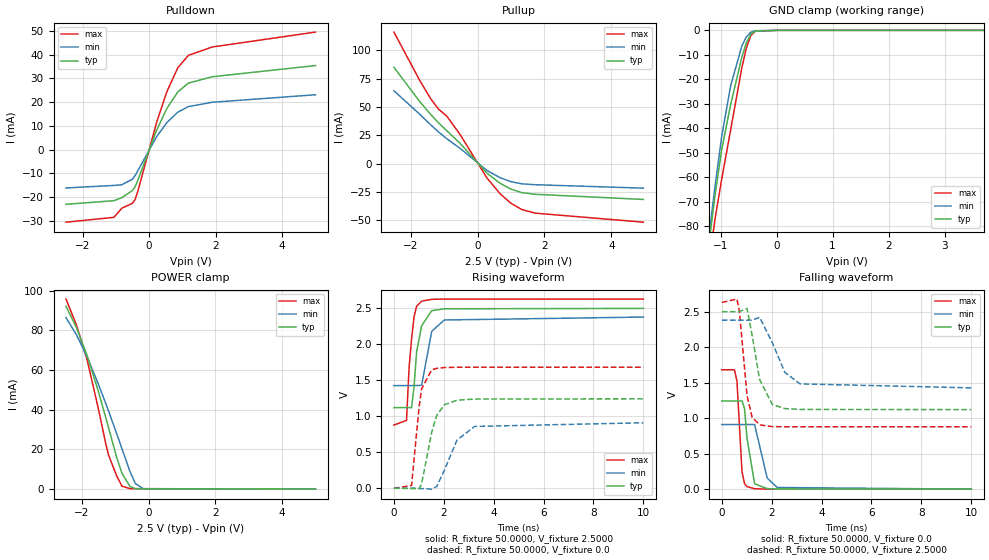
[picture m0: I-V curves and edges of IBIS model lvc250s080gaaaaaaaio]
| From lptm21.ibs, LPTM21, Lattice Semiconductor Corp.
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|   Model lvc250s080gaaaaaaaio
[Model]   lvc250s080gaaaaaaaio
Model_type   I/O
Polarity   Non-Inverting
Enable   Active-Low
Vinl =   0.7000V
Vinh =   1.7000V
Vmeas =   1.2500V
Cref =   0.0F
Rref =   1.0000M
Vref =   0.0V
C_comp   4.2000pF   3.8000pF   7.5000pF
[Temperature Range]   25.0000   0.1050k   -40.0000
[Voltage Range]   2.5000V   2.3800V   2.6300V
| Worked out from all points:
|   slope of the pulldown table from 0 to 0.375 V, typ, clamps not added: 29 ohm
|   slope of the pullup table from 0 to 0.375 V, typ, clamps not added: 35 ohm
|   GND clamp passes 1 mA (typ) near -0.44 V on its own axis
|   POWER clamp passes 1 mA (typ) near -0.53 V on its own axis
|   rising waveform, R_fixture 50.0000, V_fixture 2.5000: 20-80 % time 286ps typ, 305ps min, 229ps max; typ from 1.12 V to 2.5 V
|   rising waveform, R_fixture 50.0000, V_fixture 0.0: 20-80 % time 465ps typ, 709ps min, 287ps max; typ from 0 V to 1.24 V
|   falling waveform, R_fixture 50.0000, V_fixture 0.0: 20-80 % time 232ps typ, 311ps min, 161ps max; typ from 1.24 V to 0 V
|   falling waveform, R_fixture 50.0000, V_fixture 2.5000: 20-80 % time 453ps typ, 672ps min, 302ps max; typ from 2.5 V to 1.12 V
[Pulldown]
|Voltage   I(typ)   I(min)   I(max)
-2.5V     -23.05mA   -16.17mA   -30.58mA
-1.06V    -21.52mA   -15.1mA    -28.54mA
-820mV    -20.26mA   -14.8mA    -24.69mA
-500mV    -17.22mA   -12.44mA   -22.59mA
-420mV    -15.57mA   -10.87mA   -21.01mA
-340mV    -12.93mA   -8.894mA   -17.57mA
220mV     8.024mA    5.326mA    11.17mA
540mV     17.49mA    11.47mA    24.62mA
860mV     24.24mA    15.73mA    34.41mA
1.18V     27.98mA    18.1mA     39.69mA
1.9V      30.67mA    19.92mA    43.2mA
5V        35.37mA    23.08mA    49.47mA
[Pullup]
|Voltage   I(typ)   I(min)   I(max)
-2.5V     85mA       64.32mA    116.1mA
-1.72V    54.47mA    43.36mA    72.98mA
-1.4V     43.35mA    34.2mA     57.24mA
-1.16V    35.8mA     27.84mA    47.91mA
-920mV    29.04mA    21.97mA    41.96mA
-520mV    17.85mA    13.44mA    25.64mA
280mV     -8.363mA   -6.047mA   -12.6mA
680mV     -17.5mA    -12.52mA   -26.75mA
1V        -22.55mA   -15.93mA   -34.99mA
1.32V     -25.6mA    -17.83mA   -40.48mA
1.72V     -27.09mA   -18.63mA   -43.73mA
4.96V     -31.64mA   -21.68mA   -51.72mA
[GND_clamp]
|Voltage   I(typ)   I(min)   I(max)
-2.5V     -564.7mA   -543.1mA   -585.2mA
-1.18V    -82.37mA   -79.05mA   -91.19mA
-1.14V    -74.91mA   -71.4mA    -84.01mA
-1.1V     -67.72mA   -63.96mA   -77.3mA
-980mV    -48.69mA   -43.39mA   -60.85mA
-820mV    -30.38mA   -22.68mA   -40.71mA
-620mV    -10.92mA   -6.374mA   -15.3mA
-540mV    -5.123mA   -2.7mA     -7.317mA
-460mV    -1.524mA   -767.4uA   -2.097mA
-380mV    -292.5uA   -172.6uA   -366.3uA
20mV      0A         0A         0A
5V        0A         0A         0A
[POWER_clamp]
|Voltage   I(typ)   I(min)   I(max)
-2.48V    92.22mA    86.5mA     95.83mA
-2.16V    81.19mA    77.59mA    82.43mA
-1.84V    67mA       66.38mA    64.75mA
-1.52V    49.86mA    53.4mA     41.33mA
-1.28V    35.63mA    42.81mA    22.28mA
-1.2V     30.7mA     39.17mA    17mA
-960mV    15.93mA    27.93mA    6.582mA
-800mV    7.851mA    20.23mA    1.424mA
-560mV    1.299mA    8.796mA    199.2uA
-400mV    169.6uA    2.771mA    193.9uA
-160mV    101.6uA    144.1uA    192.3uA
5V        -4.578uA   -1.793uA   -63.13uA
[Ramp]
| variable   typ   min   max
dV/dt_r  0.7610/0.4599n   0.5462/0.7020n   1.0094/0.2844n
dV/dt_f  0.8277/0.4481n   0.5716/0.6654n   1.0508/0.2990n
R_load = 50.0000
[Rising Waveform]
R_fixture=   50.0000
V_fixture=   2.5000
V_fixture_min=   2.3800
V_fixture_max=   2.6300
|time   V(typ)   V(min)   V(max)
0s        1.121V     1.427V     878.6mV
505.1ps   1.121V     1.427V     943.1mV
606.1ps   1.121V     1.427V     1.667V
707.1ps   1.119V     1.427V     2.071V
808.1ps   1.418V     1.427V     2.386V
909.1ps   1.892V     1.428V     2.53V
1.111ns   2.259V     1.432V     2.601V
1.515ns   2.468V     2.181V     2.626V
2.02ns    2.495V     2.339V     2.63V
10ns      2.5V       2.38V      2.63V
[Rising Waveform]
R_fixture=   50.0000
V_fixture=   0.0
V_fixture_min=   0.0
V_fixture_max=   0.0
|time   V(typ)   V(min)   V(max)
0s        666.9nV    899.8nV    549.6nV
707.1ps   -4.283mV   7.467uV    38.42mV
1.01ns    -9.285mV   -453.2uV   1.131V
1.111ns   62.83mV    -4.528mV   1.383V
1.515ns   778.6mV    -12.88mV   1.646V
1.717ns   1.012V     24.61mV    1.667V
2.02ns    1.16V      249.2mV    1.678V
2.525ns   1.224V     666.6mV    1.682V
3.232ns   1.24V      859.1mV    1.682V
10ns      1.243V     910.3mV    1.682V
[Falling Waveform]
R_fixture=   50.0000
V_fixture=   0.0
V_fixture_min=   0.0
V_fixture_max=   0.0
|time   V(typ)   V(min)   V(max)
0s        1.243V     910.3mV    1.682V
505.1ps   1.243V     910.3mV    1.682V
606.1ps   1.243V     910.3mV    1.524V
808.1ps   1.243V     910.4mV    247.8mV
909.1ps   1.137V     910.3mV    78.69mV
1.01ns    717.9mV    910.3mV    36.15mV
1.313ns   75.67mV    910.8mV    6.34mV
1.818ns   7.627mV    156mV      434.4uV
2.222ns   1.73mV     23.34mV    116uV
10ns      5.917uV    -6.372uV   -20.54uV
[Falling Waveform]
R_fixture=   50.0000
V_fixture=   2.5000
V_fixture_min=   2.3800
V_fixture_max=   2.6300
|time   V(typ)   V(min)   V(max)
0s        2.5V       2.38V      2.63V
606.1ps   2.5V       2.38V      2.678V
707.1ps   2.501V     2.38V      2.497V
1.01ns    2.546V     2.38V      1.319V
1.212ns   2.172V     2.381V     1.015V
1.515ns   1.545V     2.42V      905.6mV
2.02ns    1.194V     2.067V     881.4mV
2.525ns   1.135V     1.646V     879mV
3.131ns   1.123V     1.483V     878.7mV
10ns      1.121V     1.427V     878.6mV
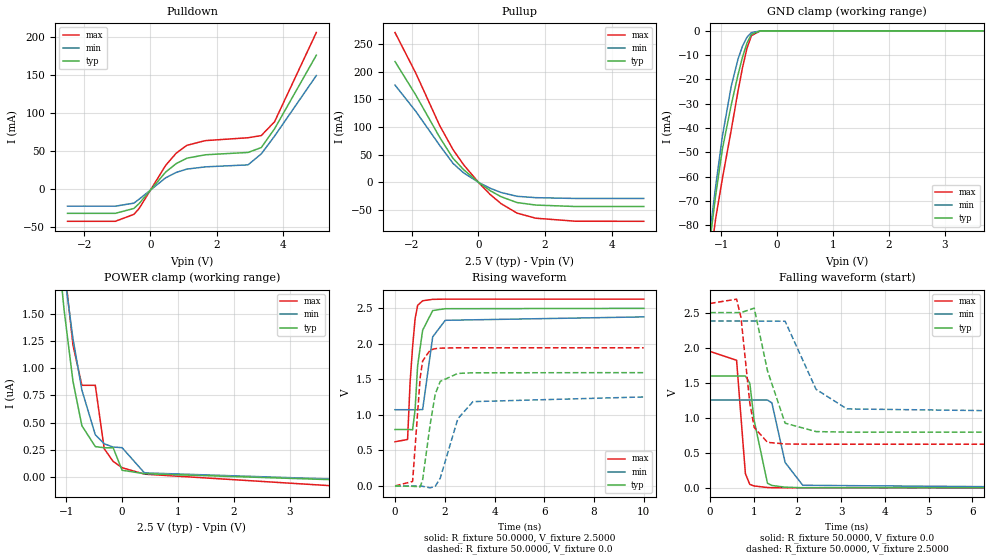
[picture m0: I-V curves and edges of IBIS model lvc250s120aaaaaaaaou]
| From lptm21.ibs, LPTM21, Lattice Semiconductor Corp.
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|   Model lvc250s120aaaaaaaaou
[Model]   lvc250s120aaaaaaaaou
Model_type   Output
Polarity   Non-Inverting
Enable   Active-Low
Vmeas =   1.2500V
Cref =   0.0F
Rref =   1.0000M
Vref =   0.0V
C_comp   4.2000pF   3.8000pF   7.5000pF
[Temperature Range]   25.0000   0.1050k   -40.0000
[Voltage Range]   2.5000V   2.3800V   2.6300V
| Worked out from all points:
|   slope of the pulldown table from 0 to 0.375 V, typ, clamps not added: 19.8 ohm
|   slope of the pullup table from 0 to 0.375 V, typ, clamps not added: 23.5 ohm
|   GND clamp passes 1 mA (typ) near -0.44 V on its own axis
|   rising waveform, R_fixture 50.0000, V_fixture 2.5000: 20-80 % time 276ps typ, 305ps min, 224ps max; typ from 0.794 V to 2.5 V
|   rising waveform, R_fixture 50.0000, V_fixture 0.0: 20-80 % time 387ps typ, 665ps min, 238ps max; typ from 0 V to 1.59 V
|   falling waveform, R_fixture 50.0000, V_fixture 0.0: 20-80 % time 218ps typ, 303ps min, 146ps max; typ from 1.59 V to 0 V
|   falling waveform, R_fixture 50.0000, V_fixture 2.5000: 20-80 % time 355ps typ, 614ps min, 225ps max; typ from 2.5 V to 0.794 V
[Pulldown]
|Voltage   I(typ)   I(min)   I(max)
-2.5V     -31.76mA   -22.34mA   -42.19mA
-1.06V    -31.76mA   -22.34mA   -42.19mA
-500mV    -25.32mA   -18.35mA   -33.11mA
-340mV    -18.82mA   -13.07mA   -25.3mA
460mV     22.53mA    14.95mA    31.32mA
780mV     33.72mA    22.07mA    47.46mA
1.1V      40.71mA    26.41mA    57.65mA
1.66V     45.2mA     29.32mA    63.8mA
2.94V     48.23mA    31.93mA    67.56mA
3.34V     54.62mA    46.31mA    70.38mA
3.74V     79.21mA    69.59mA    88.47mA
5V        175.9mA    149.2mA    205.7mA
[Pullup]
|Voltage   I(typ)   I(min)   I(max)
-2.5V     218.3mA    175.7mA    270.7mA
-1.88V    158mA      128.5mA    197.7mA
-1.16V    81.22mA    66.69mA    102.5mA
-760mV    43.3mA     34.1mA     58.98mA
-440mV    22.6mA     16.82mA    31.42mA
40mV      -1.891mA   -1.366mA   -2.72mA
360mV     -15.44mA   -11.04mA   -22.5mA
680mV     -26.13mA   -18.46mA   -38.66mA
1.16V     -36.72mA   -25.38mA   -55.86mA
1.72V     -41.23mA   -27.85mA   -65.01mA
2.92V     -43.87mA   -29.3mA    -70.47mA
4.96V     -43.87mA   -29.3mA    -70.59mA
[GND_clamp]
|Voltage   I(typ)   I(min)   I(max)
-2.5V     -564.7mA   -543.1mA   -585.2mA
-1.18V    -82.35mA   -79.03mA   -91.15mA
-1.14V    -74.88mA   -71.38mA   -83.96mA
-1.1V     -67.69mA   -63.94mA   -77.25mA
-980mV    -48.66mA   -43.36mA   -60.79mA
-820mV    -30.34mA   -22.65mA   -40.66mA
-700mV    -18.09mA   -11.63mA   -24.79mA
-620mV    -10.87mA   -6.335mA   -15.23mA
-540mV    -5.061mA   -2.654mA   -7.227mA
-460mV    -1.446mA   -714.8uA   -1.98mA
-300mV    -18.71uA   -15.93uA   -16.53uA
5V        0A         0A         0A
[POWER_clamp]
|Voltage   I(typ)   I(min)   I(max)
-2.48V    16.67uA    13.46uA    27.27uA
-1.2V     2.434uA    2.651uA    3.19uA
-1.12V    1.959uA    2.253uA    2.521uA
-1.04V    1.54uA     1.89uA     1.966uA
-880mV    880nA      1.271uA    1.212uA
-720mV    471.6nA    797.9nA    842nA
-480mV    279.9nA    389nA      842nA
-320mV    269.1nA    305.5nA    260.6nA
-160mV    269.1nA    275.8nA    144nA
0V        63.22nA    270.1nA    86.34nA
400mV     31.61nA    39.07nA    27.38nA
5V        -44.09nA   -38.33nA   -118.7nA
[Ramp]
| variable   typ   min   max
dV/dt_r  0.9571/0.3832n   0.7519/0.6587n   1.1669/0.2356n
dV/dt_f  1.0235/0.3517n   0.7843/0.6075n   1.2045/0.2228n
R_load = 50.0000
[Rising Waveform]
R_fixture=   50.0000
V_fixture=   2.5000
V_fixture_min=   2.3800
V_fixture_max=   2.6300
|time   V(typ)   V(min)   V(max)
0s        794.1mV    1.073V     622.4mV
505.1ps   794.1mV    1.073V     653.8mV
606.1ps   794.3mV    1.073V     1.458V
707.1ps   789.8mV    1.073V     1.962V
808.1ps   1.08V      1.073V     2.354V
909.1ps   1.693V     1.073V     2.542V
1.111ns   2.193V     1.076V     2.607V
1.515ns   2.469V     2.099V     2.627V
2.02ns    2.495V     2.332V     2.63V
10ns      2.5V       2.38V      2.63V
[Rising Waveform]
R_fixture=   50.0000
V_fixture=   0.0
V_fixture_min=   0.0
V_fixture_max=   0.0
|time   V(typ)   V(min)   V(max)
0s        495.7nV    694.4nV    398.1nV
707.1ps   -5.014mV   7.798uV    63.61mV
1.01ns    -13.98mV   -566.2uV   1.519V
1.111ns   88.06mV    -5.486mV   1.761V
1.414ns   869.3mV    -26.97mV   1.913V
1.616ns   1.292V     -4.86mV    1.933V
1.818ns   1.472V     109.4mV    1.94V
2.525ns   1.584V     945.6mV    1.945V
3.131ns   1.593V     1.187V     1.945V
10ns      1.595V     1.253V     1.945V
[Falling Waveform]
R_fixture=   50.0000
V_fixture=   0.0
V_fixture_min=   0.0
V_fixture_max=   0.0
|time   V(typ)   V(min)   V(max)
0s        1.595V     1.253V     1.945V
606.1ps   1.595V     1.253V     1.82V
808.1ps   1.595V     1.253V     201.2mV
909.1ps   1.494V     1.253V     49.45mV
1.01ns    957.1mV    1.253V     26.89mV
1.313ns   65.92mV    1.253V     4.655mV
1.414ns   34.48mV    1.212V     2.553mV
1.717ns   9.664mV    362.3mV    474.7uV
2.121ns   2.072mV    36.61mV    99.77uV
10ns      11.74uV    3.842uV    -3.418uV
[Falling Waveform]
R_fixture=   50.0000
V_fixture=   2.5000
V_fixture_min=   2.3800
V_fixture_max=   2.6300
|time   V(typ)   V(min)   V(max)
0s        2.5V       2.38V      2.63V
606.1ps   2.5V       2.38V      2.692V
707.1ps   2.501V     2.38V      2.432V
909.1ps   2.541V     2.38V      1.21V
1.01ns    2.564V     2.38V      861.8mV
1.313ns   1.672V     2.378V     649.3mV
1.717ns   922.7mV    2.377V     625.5mV
2.424ns   802.7mV    1.406V     622.6mV
3.131ns   795mV      1.126V     622.5mV
10ns      794.1mV    1.073V     622.4mV
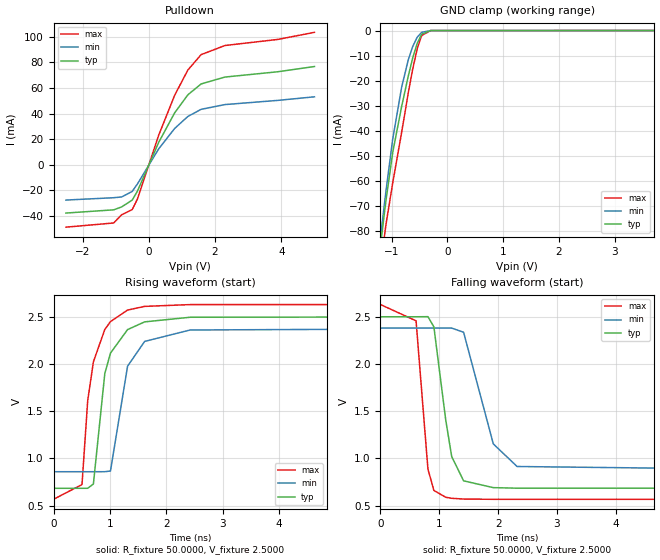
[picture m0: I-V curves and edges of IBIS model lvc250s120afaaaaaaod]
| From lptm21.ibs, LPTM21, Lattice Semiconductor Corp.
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|   Model lvc250s120afaaaaaaod
[Model]   lvc250s120afaaaaaaod
Model_type   I/O_open_drain
Polarity   Non-Inverting
Enable   Active-Low
Vinl =   0.7000V
Vinh =   1.7000V
Vmeas =   1.2500V
Cref =   0.0F
Rref =   1.0000M
Vref =   0.0V
C_comp   4.2000pF   3.8000pF   7.5000pF
[Temperature Range]   25.0000   0.1050k   -40.0000
[Voltage Range]   2.5000V   2.3800V   2.6300V
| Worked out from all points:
|   slope of the pulldown table from 0 to 0.375 V, typ, clamps not added: 17.4 ohm
|   GND clamp passes 1 mA (typ) near -0.44 V on its own axis
|   rising waveform, R_fixture 50.0000, V_fixture 2.5000: 20-80 % time 277ps typ, 280ps min, 265ps max; typ from 0.683 V to 2.5 V
|   falling waveform, R_fixture 50.0000, V_fixture 2.5000: 20-80 % time 240ps typ, 367ps min, 161ps max; typ from 2.5 V to 0.683 V
[Pulldown]
|Voltage   I(typ)   I(min)   I(max)
-2.5V     -37.74mA   -27.59mA   -48.75mA
-1.06V    -35.22mA   -25.76mA   -45.5mA
-820mV    -32.96mA   -25.18mA   -39.07mA
-500mV    -27.6mA    -20.84mA   -35.05mA
-340mV    -20.49mA   -14.89mA   -26.65mA
300mV     17.51mA    12.42mA    23.12mA
780mV     40.49mA    28.31mA    54.23mA
1.18V     54.6mA     37.71mA    73.97mA
1.58V     63.1mA     43.27mA    85.98mA
2.3V      68.47mA    46.98mA    93.11mA
3.9V      72.63mA    50.26mA    97.87mA
5V        76.69mA    53.04mA    103.4mA
[GND_clamp]
|Voltage   I(typ)   I(min)   I(max)
-2.5V     -564.7mA   -543.1mA   -585.2mA
-1.18V    -82.36mA   -79.04mA   -91.17mA
-1.14V    -74.89mA   -71.39mA   -83.98mA
-1.1V     -67.71mA   -63.95mA   -77.28mA
-980mV    -48.67mA   -43.37mA   -60.82mA
-820mV    -30.36mA   -22.66mA   -40.67mA
-700mV    -18.1mA    -11.63mA   -24.81mA
-620mV    -10.88mA   -6.341mA   -15.24mA
-540mV    -5.068mA   -2.657mA   -7.239mA
-460mV    -1.45mA    -716.2uA   -1.987mA
-300mV    -18.83uA   -15.98uA   -16.73uA
5V        0A         0A         0A
[Ramp]
| variable   typ   min   max
dV/dt_r  1.0903/0.2744n   0.9130/0.2769n   1.2385/0.2620n
dV/dt_f  1.0903/0.2372n   0.9130/0.3635n   1.2385/0.1589n
R_load = 50.0000
[Rising Waveform]
R_fixture=   50.0000
V_fixture=   2.5000
V_fixture_min=   2.3800
V_fixture_max=   2.6300
|time   V(typ)   V(min)   V(max)
0s        682.8mV    858.4mV    565.9mV
505.1ps   682.8mV    858.4mV    722.7mV
606.1ps   683mV      858.3mV    1.61V
707.1ps   728mV      858.4mV    2.023V
909.1ps   1.897V     858.7mV    2.365V
1.01ns    2.115V     865.7mV    2.449V
1.313ns   2.364V     1.976V     2.571V
1.616ns   2.446V     2.239V     2.61V
2.424ns   2.495V     2.36V      2.629V
10ns      2.5V       2.38V      2.63V
[Falling Waveform]
R_fixture=   50.0000
V_fixture=   2.5000
V_fixture_min=   2.3800
V_fixture_max=   2.6300
|time   V(typ)   V(min)   V(max)
0s        2.5V       2.38V      2.63V
606.1ps   2.5V       2.38V      2.457V
808.1ps   2.501V     2.38V      885.2mV
909.1ps   2.393V     2.38V      660.1mV
1.111ns   1.404V     2.38V      587.7mV
1.212ns   1.019V     2.38V      577mV
1.414ns   761.9mV    2.336V     568.8mV
1.919ns   689.7mV    1.153V     566.1mV
2.323ns   684mV      913.7mV    566mV
10ns      682.8mV    858.4mV    565.9mV
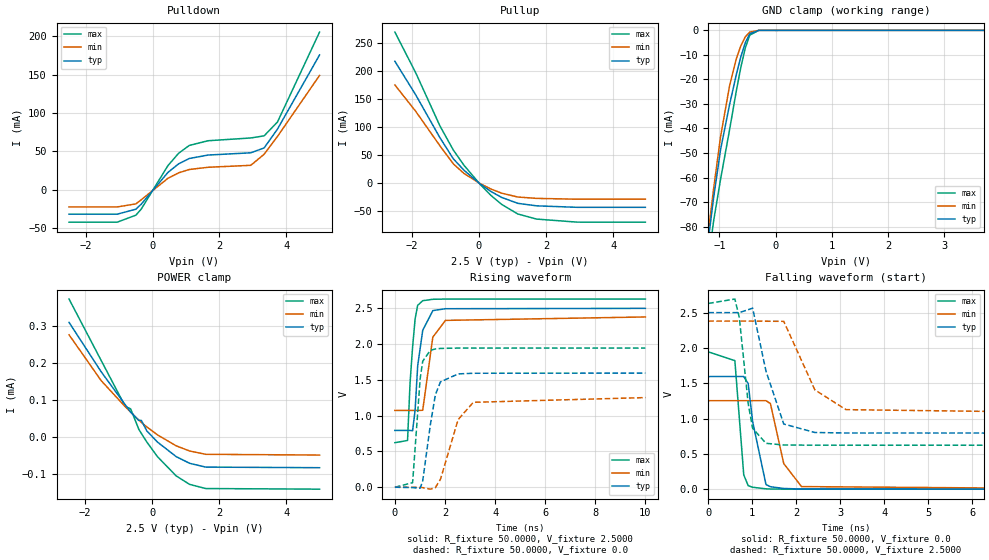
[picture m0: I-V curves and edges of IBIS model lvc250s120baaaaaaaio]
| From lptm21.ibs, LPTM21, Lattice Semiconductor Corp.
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|   Model lvc250s120baaaaaaaio
[Model]   lvc250s120baaaaaaaio
Model_type   I/O
Polarity   Non-Inverting
Enable   Active-Low
Vinl =   0.7000V
Vinh =   1.7000V
Vmeas =   1.2500V
Cref =   0.0F
Rref =   1.0000M
Vref =   0.0V
C_comp   4.2000pF   3.8000pF   7.5000pF
[Temperature Range]   25.0000   0.1050k   -40.0000
[Voltage Range]   2.5000V   2.3800V   2.6300V
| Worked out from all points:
|   slope of the pulldown table from 0 to 0.375 V, typ, clamps not added: 19.8 ohm
|   slope of the pullup table from 0 to 0.375 V, typ, clamps not added: 23.5 ohm
|   GND clamp passes 1 mA (typ) near -0.44 V on its own axis
|   rising waveform, R_fixture 50.0000, V_fixture 2.5000: 20-80 % time 276ps typ, 305ps min, 224ps max; typ from 0.794 V to 2.5 V
|   rising waveform, R_fixture 50.0000, V_fixture 0.0: 20-80 % time 387ps typ, 665ps min, 238ps max; typ from 0 V to 1.59 V
|   falling waveform, R_fixture 50.0000, V_fixture 0.0: 20-80 % time 218ps typ, 303ps min, 146ps max; typ from 1.59 V to 0 V
|   falling waveform, R_fixture 50.0000, V_fixture 2.5000: 20-80 % time 355ps typ, 614ps min, 225ps max; typ from 2.5 V to 0.794 V
[Pulldown]
|Voltage   I(typ)   I(min)   I(max)
-2.5V     -31.73mA   -22.32mA   -42.16mA
-1.06V    -31.73mA   -22.32mA   -42.16mA
-500mV    -25.26mA   -18.32mA   -33.03mA
-340mV    -18.74mA   -13.02mA   -25.16mA
460mV     22.62mA    15mA       31.47mA
780mV     33.8mA     22.11mA    47.6mA
1.1V      40.79mA    26.45mA    57.79mA
1.66V     45.26mA    29.35mA    63.9mA
2.94V     48.19mA    31.89mA    67.52mA
3.34V     54.53mA    46.23mA    70.27mA
3.74V     79.07mA    69.48mA    88.3mA
5V        175.6mA    149mA      205.4mA
[Pullup]
|Voltage   I(typ)   I(min)   I(max)
-2.5V     218mA      175.5mA    270.3mA
-1.88V    157.8mA    128.3mA    197.4mA
-1.16V    81.09mA    66.59mA    102.3mA
-760mV    43.21mA    34.05mA    58.86mA
-440mV    22.55mA    16.79mA    31.37mA
40mV      -1.887mA   -1.364mA   -2.714mA
360mV     -15.4mA    -11.02mA   -22.45mA
680mV     -26.08mA   -18.43mA   -38.58mA
1.16V     -36.64mA   -25.33mA   -55.74mA
1.72V     -41.15mA   -27.8mA    -64.88mA
2.92V     -43.79mA   -29.25mA   -70.33mA
4.96V     -43.79mA   -29.25mA   -70.46mA
[GND_clamp]
|Voltage   I(typ)   I(min)   I(max)
-2.5V     -564.6mA   -543.1mA   -585.1mA
-1.18V    -82.28mA   -79mA      -91.03mA
-1.14V    -74.81mA   -71.35mA   -83.85mA
-1.1V     -67.63mA   -63.91mA   -77.15mA
-980mV    -48.6mA    -43.33mA   -60.69mA
-820mV    -30.29mA   -22.62mA   -40.55mA
-700mV    -18.04mA   -11.6mA    -24.7mA
-620mV    -10.82mA   -6.314mA   -15.14mA
-540mV    -5.025mA   -2.64mA    -7.154mA
-460mV    -1.426mA   -708.3uA   -1.934mA
-300mV    -17.76uA   -15.73uA   -12.8uA
5V        0A         0A         0A
[POWER_clamp]
|Voltage   I(typ)   I(min)   I(max)
-2.48V    310.4uA    276.7uA    373.7uA
-1.52V    176.3uA    152.3uA    206.9uA
-800mV    86.61uA    81.35uA    82.18uA
-640mV    66.94uA    66.91uA    75.79uA
-400mV    44.51uA    45.44uA    20.86uA
-320mV    44.51uA    38.99uA    8.918uA
-160mV    16.15uA    26.85uA    -13.85uA
160mV     -14.29uA   5.152uA    -53.97uA
720mV     -53.87uA   -24.56uA   -106.2uA
1.12V     -71.9uA    -38.53uA   -129.1uA
1.6V      -82.26uA   -47.53uA   -140.4uA
5V        -83.86uA   -49.55uA   -142.1uA
[Ramp]
| variable   typ   min   max
dV/dt_r  0.9571/0.3832n   0.7519/0.6587n   1.1669/0.2356n
dV/dt_f  1.0235/0.3517n   0.7843/0.6075n   1.2045/0.2228n
R_load = 50.0000
[Rising Waveform]
R_fixture=   50.0000
V_fixture=   2.5000
V_fixture_min=   2.3800
V_fixture_max=   2.6300
|time   V(typ)   V(min)   V(max)
0s        794.1mV    1.073V     622.4mV
505.1ps   794.1mV    1.073V     653.8mV
606.1ps   794.3mV    1.073V     1.458V
707.1ps   789.8mV    1.073V     1.962V
808.1ps   1.08V      1.073V     2.354V
909.1ps   1.693V     1.073V     2.542V
1.111ns   2.193V     1.076V     2.607V
1.515ns   2.469V     2.099V     2.627V
2.02ns    2.495V     2.332V     2.63V
10ns      2.5V       2.38V      2.63V
[Rising Waveform]
R_fixture=   50.0000
V_fixture=   0.0
V_fixture_min=   0.0
V_fixture_max=   0.0
|time   V(typ)   V(min)   V(max)
0s        495.7nV    694.4nV    398.1nV
707.1ps   -5.014mV   7.798uV    63.61mV
1.01ns    -13.98mV   -566.2uV   1.519V
1.111ns   88.06mV    -5.486mV   1.761V
1.414ns   869.3mV    -26.97mV   1.913V
1.616ns   1.292V     -4.86mV    1.933V
1.818ns   1.472V     109.4mV    1.94V
2.525ns   1.584V     945.6mV    1.945V
3.131ns   1.593V     1.187V     1.945V
10ns      1.595V     1.253V     1.945V
[Falling Waveform]
R_fixture=   50.0000
V_fixture=   0.0
V_fixture_min=   0.0
V_fixture_max=   0.0
|time   V(typ)   V(min)   V(max)
0s        1.595V     1.253V     1.945V
606.1ps   1.595V     1.253V     1.82V
808.1ps   1.595V     1.253V     201.2mV
909.1ps   1.494V     1.253V     49.45mV
1.01ns    957.1mV    1.253V     26.89mV
1.313ns   65.92mV    1.253V     4.655mV
1.414ns   34.48mV    1.212V     2.553mV
1.717ns   9.664mV    362.3mV    474.7uV
2.121ns   2.072mV    36.61mV    99.77uV
10ns      11.74uV    3.842uV    -3.418uV
[Falling Waveform]
R_fixture=   50.0000
V_fixture=   2.5000
V_fixture_min=   2.3800
V_fixture_max=   2.6300
|time   V(typ)   V(min)   V(max)
0s        2.5V       2.38V      2.63V
606.1ps   2.5V       2.38V      2.692V
707.1ps   2.501V     2.38V      2.432V
909.1ps   2.541V     2.38V      1.21V
1.01ns    2.564V     2.38V      861.8mV
1.313ns   1.672V     2.378V     649.3mV
1.717ns   922.7mV    2.377V     625.5mV
2.424ns   802.7mV    1.406V     622.6mV
3.131ns   795mV      1.126V     622.5mV
10ns      794.1mV    1.073V     622.4mV
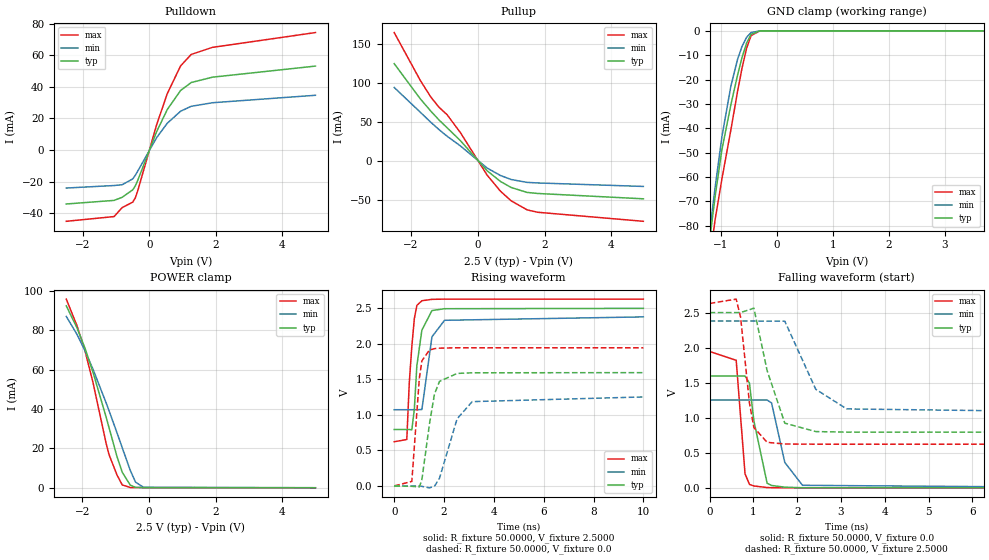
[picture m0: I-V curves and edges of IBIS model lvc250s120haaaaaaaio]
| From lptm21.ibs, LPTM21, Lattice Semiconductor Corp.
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|   Model lvc250s120haaaaaaaio
[Model]   lvc250s120haaaaaaaio
Model_type   I/O
Polarity   Non-Inverting
Enable   Active-Low
Vinl =   0.7000V
Vinh =   1.7000V
Vmeas =   1.2500V
Cref =   0.0F
Rref =   1.0000M
Vref =   0.0V
C_comp   4.2000pF   3.8000pF   7.5000pF
[Temperature Range]   25.0000   0.1050k   -40.0000
[Voltage Range]   2.5000V   2.3800V   2.6300V
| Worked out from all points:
|   slope of the pulldown table from 0 to 0.375 V, typ, clamps not added: 19.9 ohm
|   slope of the pullup table from 0 to 0.375 V, typ, clamps not added: 23.5 ohm
|   GND clamp passes 1 mA (typ) near -0.44 V on its own axis
|   POWER clamp passes 1 mA (typ) near -0.54 V on its own axis
|   rising waveform, R_fixture 50.0000, V_fixture 2.5000: 20-80 % time 276ps typ, 305ps min, 224ps max; typ from 0.794 V to 2.5 V
|   rising waveform, R_fixture 50.0000, V_fixture 0.0: 20-80 % time 387ps typ, 665ps min, 238ps max; typ from 0 V to 1.59 V
|   falling waveform, R_fixture 50.0000, V_fixture 0.0: 20-80 % time 218ps typ, 303ps min, 146ps max; typ from 1.59 V to 0 V
|   falling waveform, R_fixture 50.0000, V_fixture 2.5000: 20-80 % time 355ps typ, 614ps min, 225ps max; typ from 2.5 V to 0.794 V
[Pulldown]
|Voltage   I(typ)   I(min)   I(max)
-2.5V     -34.19mA   -24.09mA   -45.15mA
-1.06V    -31.91mA   -22.49mA   -42.15mA
-820mV    -29.96mA   -22.01mA   -36.49mA
-500mV    -25.25mA   -18.31mA   -33.02mA
-420mV    -22.65mA   -15.93mA   -30.26mA
-340mV    -18.74mA   -13.02mA   -25.17mA
220mV     11.66mA    7.825mA    16.03mA
540mV     25.61mA    16.95mA    35.68mA
940mV     37.69mA    24.54mA    53.23mA
1.26V     42.73mA    27.68mA    60.51mA
1.9V      46.11mA    29.93mA    65mA
5V        53.13mA    34.65mA    74.36mA
[Pullup]
|Voltage   I(typ)   I(min)   I(max)
-2.5V     125.3mA    94.7mA     165.3mA
-1.72V    80.21mA    62.98mA    103.9mA
-1.4V     64.07mA    49.79mA    82.15mA
-1.16V    53.02mA    40.63mA    69.33mA
-920mV    43.09mA    32.14mA    59.87mA
-520mV    26.44mA    19.66mA    36.8mA
280mV     -12.29mA   -8.813mA   -17.85mA
680mV     -26.08mA   -18.43mA   -38.58mA
1V        -33.85mA   -23.59mA   -50.98mA
1.48V     -40.23mA   -27.33mA   -62.64mA
1.8V      -41.57mA   -28.04mA   -65.74mA
4.96V     -48.43mA   -32.53mA   -77.34mA
[GND_clamp]
|Voltage   I(typ)   I(min)   I(max)
-2.5V     -564.6mA   -543.1mA   -585.1mA
-1.18V    -82.29mA   -79mA      -91.05mA
-1.14V    -74.82mA   -71.35mA   -83.87mA
-1.1V     -67.64mA   -63.91mA   -77.16mA
-980mV    -48.61mA   -43.34mA   -60.71mA
-820mV    -30.3mA    -22.63mA   -40.57mA
-700mV    -18.05mA   -11.61mA   -24.72mA
-620mV    -10.84mA   -6.326mA   -15.16mA
-540mV    -5.04mA    -2.652mA   -7.178mA
-460mV    -1.44mA    -719uA     -1.958mA
-300mV    -9.986uA   -9.27uA    -5.3uA
5V        0A         0A         0A
[POWER_clamp]
|Voltage   I(typ)   I(min)   I(max)
-2.48V    92.38mA    87.03mA    95.82mA
-2.16V    81.29mA    77.94mA    82.39mA
-1.92V    70.92mA    69.63mA    69.65mA
-1.68V    58.78mA    60.26mA    53.56mA
-1.28V    35.62mA    42.91mA    22.18mA
-1.2V     30.69mA    39.25mA    16.92mA
-960mV    15.9mA     27.98mA    6.508mA
-800mV    7.821mA    20.25mA    1.349mA
-560mV    1.267mA    8.796mA    53.58uA
-400mV    117.5uA    2.764mA    20.86uA
-160mV    16.15uA    125.2uA    -13.85uA
5V        -78.59uA   -46.05uA   -129.1uA
[Ramp]
| variable   typ   min   max
dV/dt_r  0.9571/0.3832n   0.7519/0.6587n   1.1669/0.2356n
dV/dt_f  1.0235/0.3517n   0.7843/0.6075n   1.2045/0.2228n
R_load = 50.0000
[Rising Waveform]
R_fixture=   50.0000
V_fixture=   2.5000
V_fixture_min=   2.3800
V_fixture_max=   2.6300
|time   V(typ)   V(min)   V(max)
0s        794.1mV    1.073V     622.4mV
505.1ps   794.1mV    1.073V     653.8mV
606.1ps   794.3mV    1.073V     1.458V
707.1ps   789.8mV    1.073V     1.962V
808.1ps   1.08V      1.073V     2.354V
909.1ps   1.693V     1.073V     2.542V
1.111ns   2.193V     1.076V     2.607V
1.515ns   2.469V     2.099V     2.627V
2.02ns    2.495V     2.332V     2.63V
10ns      2.5V       2.38V      2.63V
[Rising Waveform]
R_fixture=   50.0000
V_fixture=   0.0
V_fixture_min=   0.0
V_fixture_max=   0.0
|time   V(typ)   V(min)   V(max)
0s        495.7nV    694.4nV    398.1nV
707.1ps   -5.014mV   7.798uV    63.61mV
1.01ns    -13.98mV   -566.2uV   1.519V
1.111ns   88.06mV    -5.486mV   1.761V
1.414ns   869.3mV    -26.97mV   1.913V
1.616ns   1.292V     -4.86mV    1.933V
1.818ns   1.472V     109.4mV    1.94V
2.525ns   1.584V     945.6mV    1.945V
3.131ns   1.593V     1.187V     1.945V
10ns      1.595V     1.253V     1.945V
[Falling Waveform]
R_fixture=   50.0000
V_fixture=   0.0
V_fixture_min=   0.0
V_fixture_max=   0.0
|time   V(typ)   V(min)   V(max)
0s        1.595V     1.253V     1.945V
606.1ps   1.595V     1.253V     1.82V
808.1ps   1.595V     1.253V     201.2mV
909.1ps   1.494V     1.253V     49.45mV
1.01ns    957.1mV    1.253V     26.89mV
1.313ns   65.92mV    1.253V     4.655mV
1.414ns   34.48mV    1.212V     2.553mV
1.717ns   9.664mV    362.3mV    474.7uV
2.121ns   2.072mV    36.61mV    99.77uV
10ns      11.74uV    3.842uV    -3.418uV
[Falling Waveform]
R_fixture=   50.0000
V_fixture=   2.5000
V_fixture_min=   2.3800
V_fixture_max=   2.6300
|time   V(typ)   V(min)   V(max)
0s        2.5V       2.38V      2.63V
606.1ps   2.5V       2.38V      2.692V
707.1ps   2.501V     2.38V      2.432V
909.1ps   2.541V     2.38V      1.21V
1.01ns    2.564V     2.38V      861.8mV
1.313ns   1.672V     2.378V     649.3mV
1.717ns   922.7mV    2.377V     625.5mV
2.424ns   802.7mV    1.406V     622.6mV
3.131ns   795mV      1.126V     622.5mV
10ns      794.1mV    1.073V     622.4mV
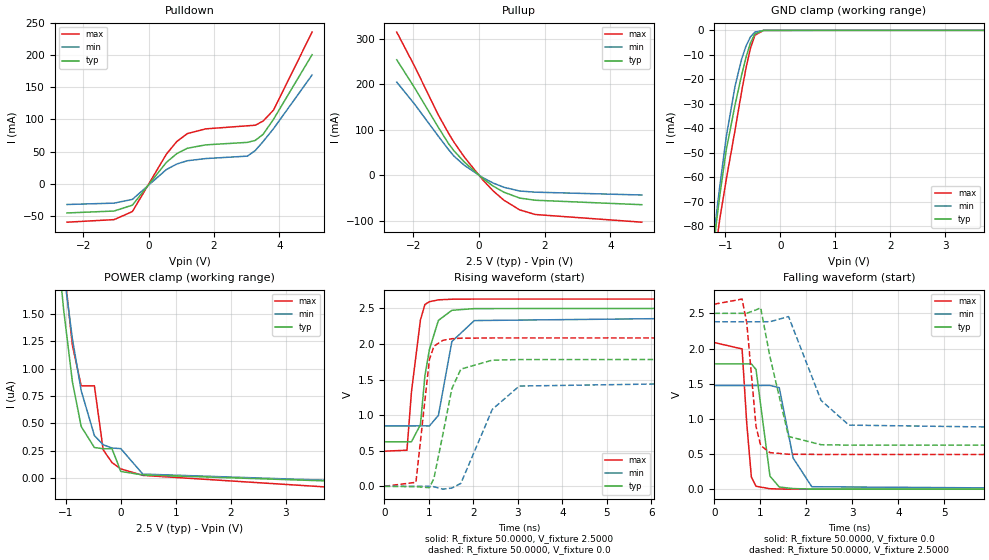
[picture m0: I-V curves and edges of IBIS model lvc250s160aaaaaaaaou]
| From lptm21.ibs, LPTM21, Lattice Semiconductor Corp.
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|   Model lvc250s160aaaaaaaaou
[Model]   lvc250s160aaaaaaaaou
Model_type   Output
Polarity   Non-Inverting
Enable   Active-Low
Vmeas =   1.2500V
Cref =   0.0F
Rref =   1.0000M
Vref =   0.0V
C_comp   4.2000pF   3.8000pF   7.5000pF
[Temperature Range]   25.0000   0.1050k   -40.0000
[Voltage Range]   2.5000V   2.3800V   2.6300V
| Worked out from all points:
|   slope of the pulldown table from 0 to 0.375 V, typ, clamps not added: 15.3 ohm
|   slope of the pullup table from 0 to 0.375 V, typ, clamps not added: 18 ohm
|   GND clamp passes 1 mA (typ) near -0.44 V on its own axis
|   rising waveform, R_fixture 50.0000, V_fixture 2.5000: 20-80 % time 272ps typ, 308ps min, 221ps max; typ from 0.625 V to 2.5 V
|   rising waveform, R_fixture 50.0000, V_fixture 0.0: 20-80 % time 340ps typ, 590ps min, 210ps max; typ from 0 V to 1.78 V
|   falling waveform, R_fixture 50.0000, V_fixture 0.0: 20-80 % time 209ps typ, 295ps min, 139ps max; typ from 1.78 V to 0 V
|   falling waveform, R_fixture 50.0000, V_fixture 2.5000: 20-80 % time 297ps typ, 529ps min, 177ps max; typ from 2.5 V to 0.625 V
[Pulldown]
|Voltage   I(typ)   I(min)   I(max)
-2.5V     -45.01mA   -31.89mA   -59.32mA
-1.06V    -42.02mA   -29.78mA   -55.34mA
-500mV    -32.92mA   -23.97mA   -42.85mA
540mV     33.4mA     22.28mA    46.08mA
860mV     47.04mA    30.89mA    65.83mA
1.18V     55.26mA    35.92mA    77.97mA
1.74V     60.53mA    39.31mA    85.33mA
3.02V     64.43mA    43.11mA    90.12mA
3.26V     67.48mA    51.68mA    91mA
3.5V      76.79mA    65.62mA    97.37mA
3.82V     100.3mA    85.69mA    114.5mA
5V        200.3mA    168.9mA    235.4mA
[Pullup]
|Voltage   I(typ)   I(min)   I(max)
-2.5V     254mA      204.9mA    314.9mA
-1.96V    192.8mA    156.8mA    240.2mA
-1.24V    106.2mA    86.52mA    133.5mA
-920mV    69.28mA    56.27mA    92.01mA
-760mV    54.09mA    42.32mA    72.99mA
-440mV    29.04mA    21.78mA    39.92mA
120mV     -7.175mA   -5.214mA   -10.22mA
440mV     -23.93mA   -17.18mA   -34.6mA
760mV     -37.13mA   -26.3mA    -54.62mA
1.24V     -50.01mA   -34.55mA   -75.93mA
1.72V     -54.85mA   -37.09mA   -86.23mA
4.96V     -64.63mA   -43.33mA   -103.1mA
[GND_clamp]
|Voltage   I(typ)   I(min)   I(max)
-2.5V     -564.7mA   -543.1mA   -585.2mA
-1.18V    -82.35mA   -79.03mA   -91.15mA
-1.14V    -74.88mA   -71.38mA   -83.96mA
-1.1V     -67.69mA   -63.94mA   -77.25mA
-980mV    -48.66mA   -43.36mA   -60.79mA
-820mV    -30.34mA   -22.65mA   -40.66mA
-700mV    -18.09mA   -11.63mA   -24.79mA
-620mV    -10.87mA   -6.335mA   -15.23mA
-540mV    -5.061mA   -2.654mA   -7.227mA
-460mV    -1.446mA   -714.8uA   -1.98mA
-300mV    -18.71uA   -15.93uA   -16.53uA
5V        0A         0A         0A
[POWER_clamp]
|Voltage   I(typ)   I(min)   I(max)
-2.48V    16.67uA    13.46uA    27.27uA
-1.2V     2.435uA    2.652uA    3.191uA
-1.12V    1.96uA     2.254uA    2.522uA
-1.04V    1.541uA    1.891uA    1.967uA
-880mV    881.1nA    1.272uA    1.213uA
-720mV    472.7nA    799nA      843.1nA
-480mV    280.9nA    390nA      843.1nA
-320mV    270.1nA    306.5nA    260.6nA
-160mV    270.1nA    276.7nA    144nA
0V        63.22nA    270.9nA    86.34nA
400mV     31.61nA    39.07nA    27.38nA
5V        -44.09nA   -38.33nA   -118.7nA
[Ramp]
| variable   typ   min   max
dV/dt_r  1.0688/0.3361n   0.8847/0.5844n   1.2507/0.2078n
dV/dt_f  1.1250/0.2937n   0.9191/0.5242n   1.2817/0.1754n
R_load = 50.0000
[Rising Waveform]
R_fixture=   50.0000
V_fixture=   2.5000
V_fixture_min=   2.3800
V_fixture_max=   2.6300
|time   V(typ)   V(min)   V(max)
0s        625.1mV    848.2mV    493.8mV
505.1ps   625.1mV    848.2mV    506.6mV
606.1ps   625.1mV    848.2mV    1.325V
808.1ps   864.9mV    848.3mV    2.336V
909.1ps   1.554V     848.7mV    2.554V
1.01ns    1.922V     847.3mV    2.593V
1.212ns   2.33V      996.3mV    2.619V
1.515ns   2.472V     2.034V     2.628V
2.02ns    2.496V     2.328V     2.63V
10ns      2.5V       2.38V      2.63V
[Rising Waveform]
R_fixture=   50.0000
V_fixture=   0.0
V_fixture_min=   0.0
V_fixture_max=   0.0
|time   V(typ)   V(min)   V(max)
0s        394.5nV    565.3nV    312nV
707.1ps   -5.27mV    7.859uV    56.14mV
1.01ns    -19.04mV   -648.7uV   1.782V
1.111ns   109.3mV    -5.939mV   1.968V
1.313ns   731.5mV    -40.24mV   2.05V
1.515ns   1.372V     -24.24mV   2.073V
1.717ns   1.646V     41.02mV    2.08V
2.424ns   1.772V     1.081V     2.084V
3.03ns    1.78V      1.408V     2.084V
10ns      1.781V     1.474V     2.084V
[Falling Waveform]
R_fixture=   50.0000
V_fixture=   0.0
V_fixture_min=   0.0
V_fixture_max=   0.0
|time   V(typ)   V(min)   V(max)
0s        1.781V     1.474V     2.085V
606.1ps   1.781V     1.474V     1.994V
707.1ps   1.782V     1.474V     937.7mV
808.1ps   1.78V      1.474V     171.8mV
909.1ps   1.702V     1.474V     41.12mV
1.212ns   185.6mV    1.475V     6.403mV
1.414ns   30.45mV    1.443V     1.915mV
1.717ns   8.322mV    441.2mV    357.2uV
2.121ns   1.731mV    34.79mV    86.71uV
10ns      -26.63uV   17.43uV    -15.71uV
[Falling Waveform]
R_fixture=   50.0000
V_fixture=   2.5000
V_fixture_min=   2.3800
V_fixture_max=   2.6300
|time   V(typ)   V(min)   V(max)
0s        2.5V       2.38V      2.63V
606.1ps   2.5V       2.38V      2.703V
707.1ps   2.501V     2.38V      2.371V
909.1ps   2.549V     2.38V      891mV
1.01ns    2.579V     2.38V      620.9mV
1.212ns   1.882V     2.381V     520mV
1.616ns   748.9mV    2.454V     496.3mV
2.323ns   631.9mV    1.262V     493.9mV
2.929ns   625.8mV    910.5mV    493.8mV
10ns      625.1mV    848.2mV    493.8mV
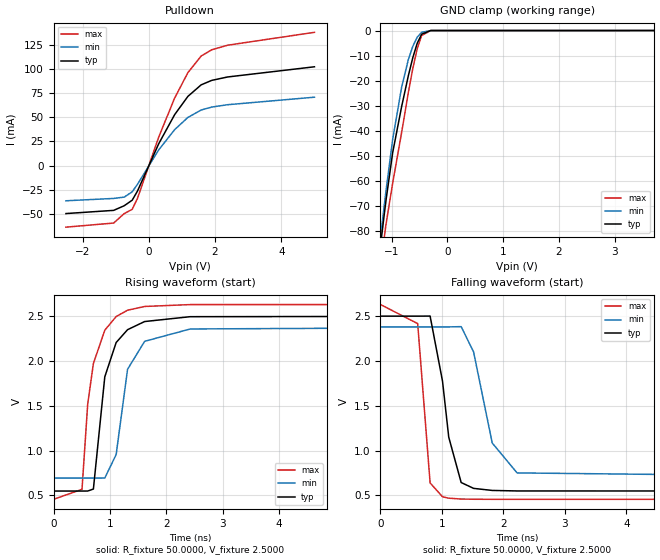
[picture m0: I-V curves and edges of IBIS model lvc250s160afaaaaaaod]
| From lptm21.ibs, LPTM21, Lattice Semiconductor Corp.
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|   Model lvc250s160afaaaaaaod
[Model]   lvc250s160afaaaaaaod
Model_type   I/O_open_drain
Polarity   Non-Inverting
Enable   Active-Low
Vinl =   0.7000V
Vinh =   1.7000V
Vmeas =   1.2500V
Cref =   0.0F
Rref =   1.0000M
Vref =   0.0V
C_comp   4.2000pF   3.8000pF   7.5000pF
[Temperature Range]   25.0000   0.1050k   -40.0000
[Voltage Range]   2.5000V   2.3800V   2.6300V
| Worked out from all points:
|   slope of the pulldown table from 0 to 0.375 V, typ, clamps not added: 13.5 ohm
|   GND clamp passes 1 mA (typ) near -0.44 V on its own axis
|   rising waveform, R_fixture 50.0000, V_fixture 2.5000: 20-80 % time 281ps typ, 277ps min, 264ps max; typ from 0.549 V to 2.5 V
|   falling waveform, R_fixture 50.0000, V_fixture 2.5000: 20-80 % time 215ps typ, 319ps min, 144ps max; typ from 2.5 V to 0.549 V
[Pulldown]
|Voltage   I(typ)   I(min)   I(max)
-2.5V     -49.64mA   -36.43mA   -63.68mA
-1.06V    -46.34mA   -34.01mA   -59.43mA
-740mV    -41.52mA   -32.61mA   -49.64mA
-500mV    -35.8mA    -27.15mA   -45.23mA
-340mV    -26.3mA    -19.3mA    -33.84mA
300mV     22.52mA    16.15mA    29.41mA
780mV     52.53mA    37.05mA    69.64mA
1.18V     71.4mA     49.65mA    95.93mA
1.58V     83.33mA    57.33mA    113.1mA
1.9V      87.97mA    60.39mA    119.6mA
2.38V     91.48mA    62.82mA    124.3mA
5V        102mA      70.58mA    137.6mA
[GND_clamp]
|Voltage   I(typ)   I(min)   I(max)
-2.5V     -564.7mA   -543.1mA   -585.2mA
-1.18V    -82.36mA   -79.04mA   -91.17mA
-1.14V    -74.89mA   -71.39mA   -83.98mA
-1.1V     -67.71mA   -63.95mA   -77.28mA
-980mV    -48.67mA   -43.37mA   -60.82mA
-820mV    -30.36mA   -22.66mA   -40.67mA
-700mV    -18.1mA    -11.63mA   -24.81mA
-620mV    -10.88mA   -6.341mA   -15.24mA
-540mV    -5.068mA   -2.657mA   -7.239mA
-460mV    -1.45mA    -716.2uA   -1.987mA
-300mV    -18.83uA   -15.98uA   -16.73uA
5V        0A         0A         0A
[Ramp]
| variable   typ   min   max
dV/dt_r  1.1707/0.2782n   1.0120/0.2747n   1.3041/0.2611n
dV/dt_f  1.1707/0.2133n   1.0120/0.3154n   1.3041/0.1429n
R_load = 50.0000
[Rising Waveform]
R_fixture=   50.0000
V_fixture=   2.5000
V_fixture_min=   2.3800
V_fixture_max=   2.6300
|time   V(typ)   V(min)   V(max)
0s        548.8mV    693.3mV    456.4mV
505.1ps   548.8mV    693.3mV    568mV
606.1ps   549mV      693.3mV    1.519V
707.1ps   571.3mV    693.3mV    1.972V
909.1ps   1.823V     693.6mV    2.343V
1.111ns   2.206V     956.6mV    2.496V
1.313ns   2.349V     1.907V     2.566V
1.616ns   2.44V      2.219V     2.608V
2.424ns   2.494V     2.357V     2.629V
10ns      2.5V       2.38V      2.63V
[Falling Waveform]
R_fixture=   50.0000
V_fixture=   2.5000
V_fixture_min=   2.3800
V_fixture_max=   2.6300
|time   V(typ)   V(min)   V(max)
0s        2.5V       2.38V      2.63V
606.1ps   2.5V       2.38V      2.417V
808.1ps   2.501V     2.38V      639.8mV
1.01ns    1.774V     2.38V      484.6mV
1.111ns   1.15V      2.38V      469.1mV
1.313ns   643.9mV    2.383V     459.8mV
1.515ns   578.6mV    2.101V     457.3mV
1.818ns   555.6mV    1.085V     456.6mV
2.222ns   549.9mV    751.2mV    456.5mV
10ns      548.8mV    693.3mV    456.4mV
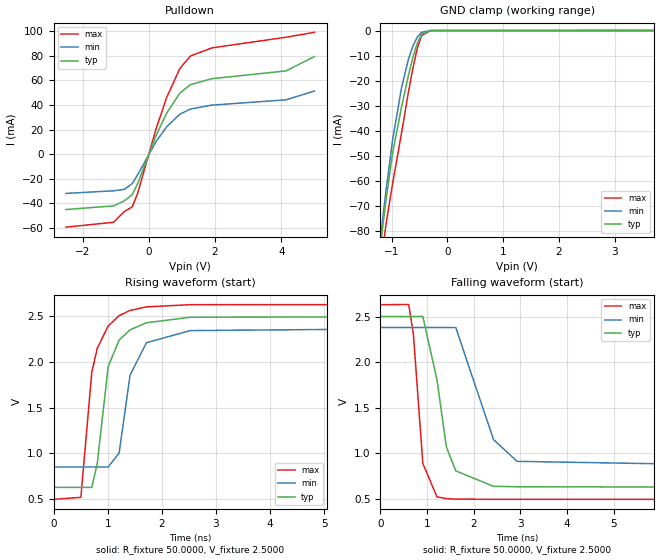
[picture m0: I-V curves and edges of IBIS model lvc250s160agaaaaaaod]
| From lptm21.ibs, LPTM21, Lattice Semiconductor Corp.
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|   Model lvc250s160agaaaaaaod
[Model]   lvc250s160agaaaaaaod
Model_type   I/O_open_drain
Polarity   Non-Inverting
Enable   Active-Low
Vinl =   0.7000V
Vinh =   1.7000V
Vmeas =   1.2500V
Cref =   0.0F
Rref =   1.0000M
Vref =   0.0V
C_comp   4.2000pF   3.8000pF   7.5000pF
[Temperature Range]   25.0000   0.1050k   -40.0000
[Voltage Range]   2.5000V   2.3800V   2.6300V
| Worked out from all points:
|   slope of the pulldown table from 0 to 0.375 V, typ, clamps not added: 15.3 ohm
|   GND clamp passes 1 mA (typ) near -0.44 V on its own axis
|   rising waveform, R_fixture 50.0000, V_fixture 2.5000: 20-80 % time 280ps typ, 290ps min, 289ps max; typ from 0.625 V to 2.5 V
|   falling waveform, R_fixture 50.0000, V_fixture 2.5000: 20-80 % time 316ps typ, 537ps min, 183ps max; typ from 2.5 V to 0.625 V
[Pulldown]
|Voltage   I(typ)   I(min)   I(max)
-2.5V     -45.01mA   -31.89mA   -59.32mA
-1.06V    -42.02mA   -29.78mA   -55.34mA
-740mV    -37.94mA   -28.65mA   -46.63mA
-500mV    -32.92mA   -23.97mA   -42.85mA
-340mV    -24.22mA   -16.99mA   -32.2mA
220mV     15.1mA     10.24mA    20.53mA
540mV     33.4mA     22.28mA    46.08mA
940mV     49.63mA    32.48mA    69.67mA
1.26V     56.49mA    36.69mA    79.75mA
1.9V      61.29mA    39.82mA    86.32mA
4.14V     67.63mA    44.12mA    94.98mA
5V        79.29mA    51.28mA    98.98mA
[GND_clamp]
|Voltage   I(typ)   I(min)   I(max)
-2.5V     -564.7mA   -543.1mA   -585.2mA
-1.18V    -82.35mA   -79.03mA   -91.15mA
-1.14V    -74.88mA   -71.38mA   -83.96mA
-1.1V     -67.69mA   -63.94mA   -77.25mA
-980mV    -48.66mA   -43.36mA   -60.79mA
-820mV    -30.34mA   -22.65mA   -40.66mA
-700mV    -18.09mA   -11.63mA   -24.79mA
-620mV    -10.87mA   -6.335mA   -15.23mA
-540mV    -5.061mA   -2.654mA   -7.227mA
-460mV    -1.446mA   -714.8uA   -1.98mA
-300mV    -18.71uA   -15.93uA   -16.53uA
5V        0A         0A         0A
[Ramp]
| variable   typ   min   max
dV/dt_r  1.1250/0.2769n   0.9191/0.2873n   1.2817/0.2866n
dV/dt_f  1.1250/0.3128n   0.9191/0.5318n   1.2817/0.1840n
R_load = 50.0000
[Rising Waveform]
R_fixture=   50.0000
V_fixture=   2.5000
V_fixture_min=   2.3800
V_fixture_max=   2.6300
|time   V(typ)   V(min)   V(max)
0s        625.1mV    848.2mV    493.8mV
505.1ps   625.1mV    848.2mV    515.6mV
707.1ps   624.8mV    848.2mV    1.888V
808.1ps   888.5mV    848.3mV    2.151V
1.01ns    1.95V      848.4mV    2.395V
1.212ns   2.24V      1.001V     2.508V
1.414ns   2.352V     1.856V     2.565V
1.717ns   2.43V      2.211V     2.604V
2.525ns   2.49V      2.344V     2.628V
10ns      2.5V       2.38V      2.63V
[Falling Waveform]
R_fixture=   50.0000
V_fixture=   2.5000
V_fixture_min=   2.3800
V_fixture_max=   2.6300
|time   V(typ)   V(min)   V(max)
0s        2.5V       2.38V      2.63V
606.1ps   2.5V       2.38V      2.632V
707.1ps   2.5V       2.38V      2.307V
909.1ps   2.501V     2.38V      888.4mV
1.212ns   1.807V     2.38V      520.8mV
1.414ns   1.068V     2.38V      501.7mV
1.616ns   806mV      2.378V     496.3mV
2.424ns   636.7mV    1.149V     493.9mV
2.929ns   631.9mV    910.7mV    493.8mV
10ns      625.1mV    848.2mV    493.8mV
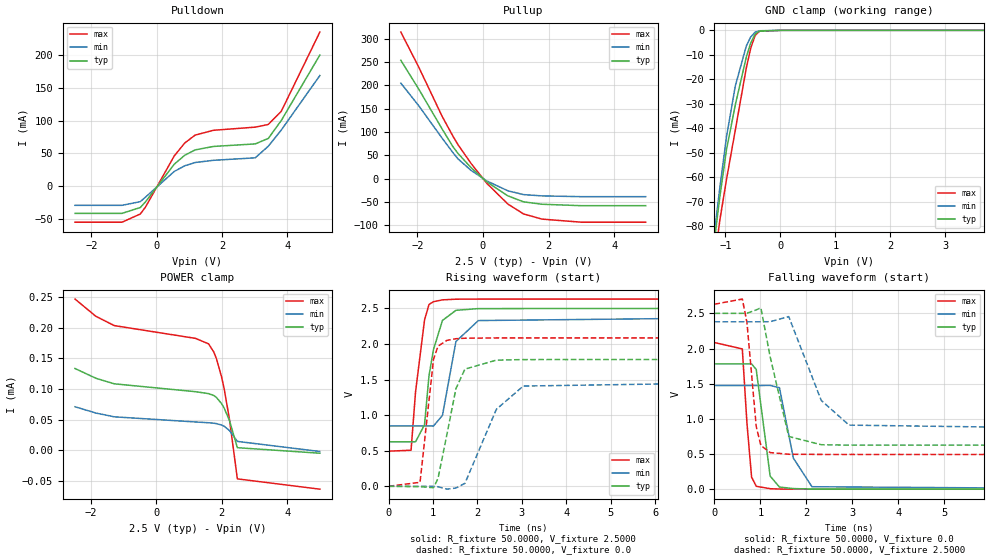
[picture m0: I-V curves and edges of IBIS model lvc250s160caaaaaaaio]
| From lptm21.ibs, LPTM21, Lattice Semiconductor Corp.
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|   Model lvc250s160caaaaaaaio
[Model]   lvc250s160caaaaaaaio
Model_type   I/O
Polarity   Non-Inverting
Enable   Active-Low
Vinl =   0.7000V
Vinh =   1.7000V
Vmeas =   1.2500V
Cref =   0.0F
Rref =   1.0000M
Vref =   0.0V
C_comp   4.2000pF   3.8000pF   7.5000pF
[Temperature Range]   25.0000   0.1050k   -40.0000
[Voltage Range]   2.5000V   2.3800V   2.6300V
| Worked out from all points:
|   slope of the pulldown table from 0 to 0.375 V, typ, clamps not added: 15.3 ohm
|   slope of the pullup table from 0 to 0.375 V, typ, clamps not added: 18 ohm
|   GND clamp passes 1 mA (typ) near -0.44 V on its own axis
|   rising waveform, R_fixture 50.0000, V_fixture 2.5000: 20-80 % time 272ps typ, 308ps min, 221ps max; typ from 0.625 V to 2.5 V
|   rising waveform, R_fixture 50.0000, V_fixture 0.0: 20-80 % time 340ps typ, 590ps min, 210ps max; typ from 0 V to 1.78 V
|   falling waveform, R_fixture 50.0000, V_fixture 0.0: 20-80 % time 209ps typ, 295ps min, 139ps max; typ from 1.78 V to 0 V
|   falling waveform, R_fixture 50.0000, V_fixture 2.5000: 20-80 % time 297ps typ, 529ps min, 177ps max; typ from 2.5 V to 0.625 V
[Pulldown]
|Voltage   I(typ)   I(min)   I(max)
-2.5V     -41.83mA   -29.52mA   -55.3mA
-1.06V    -41.83mA   -29.52mA   -55.3mA
-500mV    -32.86mA   -23.93mA   -42.76mA
-340mV    -24.15mA   -16.95mA   -32.07mA
540mV     33.32mA    22.25mA    45.93mA
860mV     46.94mA    30.84mA    65.66mA
1.18V     55.16mA    35.88mA    77.79mA
1.74V     60.44mA    39.26mA    85.14mA
3.02V     64.33mA    43.06mA    89.95mA
3.42V     72.65mA    60.74mA    94.03mA
3.82V     100.2mA    85.64mA    114.3mA
5V        200.1mA    168.8mA    235.2mA
[Pullup]
|Voltage   I(typ)   I(min)   I(max)
-2.5V     253.9mA    204.9mA    314.6mA
-1.96V    192.7mA    156.8mA    240mA
-1.24V    106.1mA    86.46mA    133.3mA
-920mV    69.18mA    56.22mA    91.82mA
-760mV    53.99mA    42.27mA    72.8mA
-360mV    23.32mA    17.41mA    32.33mA
120mV     -7.275mA   -5.262mA   -10.41mA
760mV     -37.23mA   -26.35mA   -54.81mA
1.24V     -50.1mA    -34.59mA   -76.12mA
1.8V      -55.29mA   -37.33mA   -87.21mA
3V        -58.36mA   -39mA      -93.83mA
4.96V     -58.36mA   -39mA      -93.83mA
[GND_clamp]
|Voltage   I(typ)   I(min)   I(max)
-2.5V     -564.7mA   -543.1mA   -585.2mA
-1.18V    -82.37mA   -79.05mA   -91.19mA
-1.14V    -74.91mA   -71.4mA    -84.01mA
-1.1V     -67.72mA   -63.96mA   -77.3mA
-980mV    -48.69mA   -43.39mA   -60.85mA
-820mV    -30.38mA   -22.68mA   -40.71mA
-620mV    -10.92mA   -6.374mA   -15.3mA
-540mV    -5.123mA   -2.7mA     -7.317mA
-460mV    -1.524mA   -767.4uA   -2.097mA
-380mV    -292.5uA   -172.6uA   -366.3uA
20mV      0A         0A         0A
5V        0A         0A         0A
[POWER_clamp]
|Voltage   I(typ)   I(min)   I(max)
-2.48V    133.3uA    71.04uA    246.4uA
-1.84V    117.4uA    60.8uA     218.2uA
-1.28V    108.4uA    54.67uA    203.2uA
1.2V      95.59uA    46.28uA    182.4uA
1.6V      92.47uA    45.01uA    173.5uA
1.76V     89.3uA     44.22uA    160.2uA
1.84V     86.28uA    43.64uA    149.5uA
2V        76.02uA    41.32uA    119.2uA
2.08V     68.53uA    39.17uA    99.45uA
2.24V     48.41uA    32.29uA    50.16uA
2.48V     4.411uA    14.65uA    -46.36uA
5V        -4.578uA   -1.793uA   -63.13uA
[Ramp]
| variable   typ   min   max
dV/dt_r  1.0688/0.3361n   0.8847/0.5844n   1.2507/0.2078n
dV/dt_f  1.1250/0.2937n   0.9191/0.5242n   1.2817/0.1754n
R_load = 50.0000
[Rising Waveform]
R_fixture=   50.0000
V_fixture=   2.5000
V_fixture_min=   2.3800
V_fixture_max=   2.6300
|time   V(typ)   V(min)   V(max)
0s        625.1mV    848.2mV    493.8mV
505.1ps   625.1mV    848.2mV    506.6mV
606.1ps   625.1mV    848.2mV    1.325V
808.1ps   864.9mV    848.3mV    2.336V
909.1ps   1.554V     848.7mV    2.554V
1.01ns    1.922V     847.3mV    2.593V
1.212ns   2.33V      996.3mV    2.619V
1.515ns   2.472V     2.034V     2.628V
2.02ns    2.496V     2.328V     2.63V
10ns      2.5V       2.38V      2.63V
[Rising Waveform]
R_fixture=   50.0000
V_fixture=   0.0
V_fixture_min=   0.0
V_fixture_max=   0.0
|time   V(typ)   V(min)   V(max)
0s        394.5nV    565.3nV    312nV
707.1ps   -5.27mV    7.859uV    56.14mV
1.01ns    -19.04mV   -648.7uV   1.782V
1.111ns   109.3mV    -5.939mV   1.968V
1.313ns   731.5mV    -40.24mV   2.05V
1.515ns   1.372V     -24.24mV   2.073V
1.717ns   1.646V     41.02mV    2.08V
2.424ns   1.772V     1.081V     2.084V
3.03ns    1.78V      1.408V     2.084V
10ns      1.781V     1.474V     2.084V
[Falling Waveform]
R_fixture=   50.0000
V_fixture=   0.0
V_fixture_min=   0.0
V_fixture_max=   0.0
|time   V(typ)   V(min)   V(max)
0s        1.781V     1.474V     2.085V
606.1ps   1.781V     1.474V     1.994V
707.1ps   1.782V     1.474V     937.7mV
808.1ps   1.78V      1.474V     171.8mV
909.1ps   1.702V     1.474V     41.12mV
1.212ns   185.6mV    1.475V     6.403mV
1.414ns   30.45mV    1.443V     1.915mV
1.717ns   8.322mV    441.2mV    357.2uV
2.121ns   1.731mV    34.79mV    86.71uV
10ns      -26.63uV   17.43uV    -15.71uV
[Falling Waveform]
R_fixture=   50.0000
V_fixture=   2.5000
V_fixture_min=   2.3800
V_fixture_max=   2.6300
|time   V(typ)   V(min)   V(max)
0s        2.5V       2.38V      2.63V
606.1ps   2.5V       2.38V      2.703V
707.1ps   2.501V     2.38V      2.371V
909.1ps   2.549V     2.38V      891mV
1.01ns    2.579V     2.38V      620.9mV
1.212ns   1.882V     2.381V     520mV
1.616ns   748.9mV    2.454V     496.3mV
2.323ns   631.9mV    1.262V     493.9mV
2.929ns   625.8mV    910.5mV    493.8mV
10ns      625.1mV    848.2mV    493.8mV
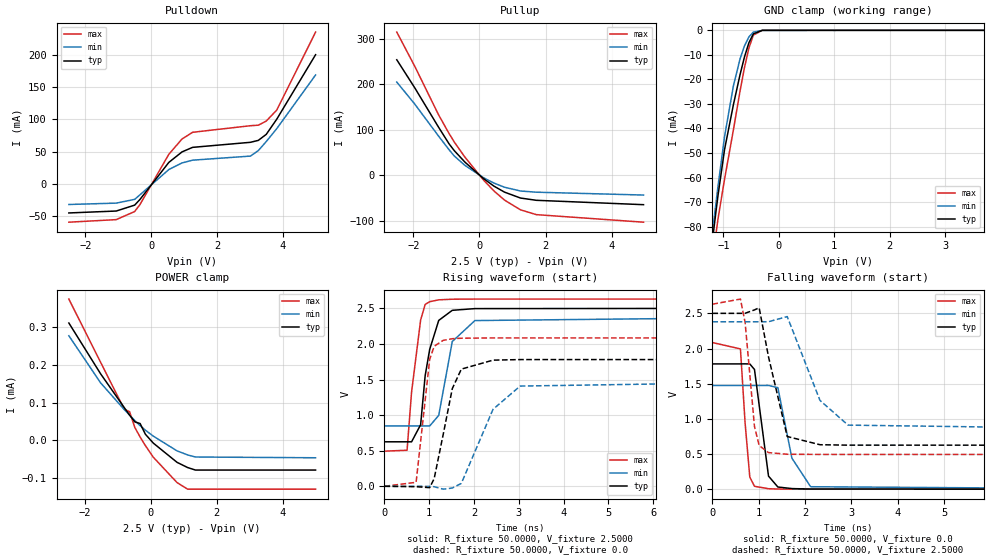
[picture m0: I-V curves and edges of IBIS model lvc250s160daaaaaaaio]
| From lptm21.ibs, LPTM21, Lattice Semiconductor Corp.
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|   Model lvc250s160daaaaaaaio
[Model]   lvc250s160daaaaaaaio
Model_type   I/O
Polarity   Non-Inverting
Enable   Active-Low
Vinl =   0.7000V
Vinh =   1.7000V
Vmeas =   1.2500V
Cref =   0.0F
Rref =   1.0000M
Vref =   0.0V
C_comp   4.2000pF   3.8000pF   7.5000pF
[Temperature Range]   25.0000   0.1050k   -40.0000
[Voltage Range]   2.5000V   2.3800V   2.6300V
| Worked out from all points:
|   slope of the pulldown table from 0 to 0.375 V, typ, clamps not added: 15.3 ohm
|   slope of the pullup table from 0 to 0.375 V, typ, clamps not added: 18.1 ohm
|   GND clamp passes 1 mA (typ) near -0.44 V on its own axis
|   rising waveform, R_fixture 50.0000, V_fixture 2.5000: 20-80 % time 272ps typ, 308ps min, 221ps max; typ from 0.625 V to 2.5 V
|   rising waveform, R_fixture 50.0000, V_fixture 0.0: 20-80 % time 340ps typ, 590ps min, 210ps max; typ from 0 V to 1.78 V
|   falling waveform, R_fixture 50.0000, V_fixture 0.0: 20-80 % time 209ps typ, 295ps min, 139ps max; typ from 1.78 V to 0 V
|   falling waveform, R_fixture 50.0000, V_fixture 2.5000: 20-80 % time 297ps typ, 529ps min, 177ps max; typ from 2.5 V to 0.625 V
[Pulldown]
|Voltage   I(typ)   I(min)   I(max)
-2.5V     -44.97mA   -31.87mA   -59.27mA
-1.06V    -41.99mA   -29.75mA   -55.3mA
-500mV    -32.86mA   -23.93mA   -42.76mA
-340mV    -24.15mA   -16.95mA   -32.07mA
540mV     33.32mA    22.25mA    45.93mA
940mV     49.54mA    32.44mA    69.49mA
1.26V     56.56mA    36.73mA    79.88mA
3.02V     64.38mA    43.06mA    90.07mA
3.26V     67.39mA    51.62mA    90.9mA
3.5V      76.68mA    65.54mA    97.24mA
3.82V     100.2mA    85.57mA    114.3mA
5V        200mA      168.6mA    235mA
[Pullup]
|Voltage   I(typ)   I(min)   I(max)
-2.5V     253.7mA    204.7mA    314.5mA
-1.96V    192.5mA    156.7mA    239.9mA
-1.24V    106mA      86.42mA    133.3mA
-920mV    69.18mA    56.2mA     91.87mA
-760mV    54.01mA    42.27mA    72.88mA
-440mV    28.99mA    21.75mA    39.87mA
120mV     -7.165mA   -5.207mA   -10.2mA
440mV     -23.89mA   -17.16mA   -34.55mA
760mV     -37.08mA   -26.26mA   -54.54mA
1.24V     -49.93mA   -34.5mA    -75.81mA
1.72V     -54.94mA   -37.13mA   -86.41mA
4.96V     -64.54mA   -43.37mA   -103mA
[GND_clamp]
|Voltage   I(typ)   I(min)   I(max)
-2.5V     -564.6mA   -543.1mA   -585.1mA
-1.18V    -82.29mA   -79mA      -91.05mA
-1.14V    -74.82mA   -71.35mA   -83.87mA
-1.1V     -67.64mA   -63.91mA   -77.16mA
-980mV    -48.61mA   -43.34mA   -60.71mA
-820mV    -30.3mA    -22.63mA   -40.57mA
-700mV    -18.05mA   -11.61mA   -24.72mA
-620mV    -10.84mA   -6.326mA   -15.16mA
-540mV    -5.04mA    -2.652mA   -7.178mA
-460mV    -1.44mA    -719uA     -1.958mA
-300mV    -9.986uA   -9.27uA    -5.3uA
5V        0A         0A         0A
[POWER_clamp]
|Voltage   I(typ)   I(min)   I(max)
-2.48V    310.4uA    276.7uA    373.7uA
-1.52V    176.3uA    152.3uA    206.9uA
-800mV    86.61uA    81.35uA    82.18uA
-640mV    66.94uA    66.91uA    75.79uA
-480mV    48.86uA    52.22uA    34.01uA
-320mV    44.51uA    38.99uA    8.918uA
-160mV    16.15uA    26.85uA    -13.85uA
80mV      -7.284uA   11.17uA    -44.64uA
800mV     -58.16uA   -27.83uA   -111.7uA
1.12V     -71.9uA    -38.53uA   -129.1uA
1.36V     -78.59uA   -44.07uA   -129.1uA
5V        -78.59uA   -46.05uA   -129.1uA
[Ramp]
| variable   typ   min   max
dV/dt_r  1.0688/0.3361n   0.8847/0.5844n   1.2507/0.2078n
dV/dt_f  1.1250/0.2937n   0.9191/0.5242n   1.2817/0.1754n
R_load = 50.0000
[Rising Waveform]
R_fixture=   50.0000
V_fixture=   2.5000
V_fixture_min=   2.3800
V_fixture_max=   2.6300
|time   V(typ)   V(min)   V(max)
0s        625.1mV    848.2mV    493.8mV
505.1ps   625.1mV    848.2mV    506.6mV
606.1ps   625.1mV    848.2mV    1.325V
808.1ps   864.9mV    848.3mV    2.336V
909.1ps   1.554V     848.7mV    2.554V
1.01ns    1.922V     847.3mV    2.593V
1.212ns   2.33V      996.3mV    2.619V
1.515ns   2.472V     2.034V     2.628V
2.02ns    2.496V     2.328V     2.63V
10ns      2.5V       2.38V      2.63V
[Rising Waveform]
R_fixture=   50.0000
V_fixture=   0.0
V_fixture_min=   0.0
V_fixture_max=   0.0
|time   V(typ)   V(min)   V(max)
0s        394.5nV    565.3nV    312nV
707.1ps   -5.27mV    7.859uV    56.14mV
1.01ns    -19.04mV   -648.7uV   1.782V
1.111ns   109.3mV    -5.939mV   1.968V
1.313ns   731.5mV    -40.24mV   2.05V
1.515ns   1.372V     -24.24mV   2.073V
1.717ns   1.646V     41.02mV    2.08V
2.424ns   1.772V     1.081V     2.084V
3.03ns    1.78V      1.408V     2.084V
10ns      1.781V     1.474V     2.084V
[Falling Waveform]
R_fixture=   50.0000
V_fixture=   0.0
V_fixture_min=   0.0
V_fixture_max=   0.0
|time   V(typ)   V(min)   V(max)
0s        1.781V     1.474V     2.085V
606.1ps   1.781V     1.474V     1.994V
707.1ps   1.782V     1.474V     937.7mV
808.1ps   1.78V      1.474V     171.8mV
909.1ps   1.702V     1.474V     41.12mV
1.212ns   185.6mV    1.475V     6.403mV
1.414ns   30.45mV    1.443V     1.915mV
1.717ns   8.322mV    441.2mV    357.2uV
2.121ns   1.731mV    34.79mV    86.71uV
10ns      -26.63uV   17.43uV    -15.71uV
[Falling Waveform]
R_fixture=   50.0000
V_fixture=   2.5000
V_fixture_min=   2.3800
V_fixture_max=   2.6300
|time   V(typ)   V(min)   V(max)
0s        2.5V       2.38V      2.63V
606.1ps   2.5V       2.38V      2.703V
707.1ps   2.501V     2.38V      2.371V
909.1ps   2.549V     2.38V      891mV
1.01ns    2.579V     2.38V      620.9mV
1.212ns   1.882V     2.381V     520mV
1.616ns   748.9mV    2.454V     496.3mV
2.323ns   631.9mV    1.262V     493.9mV
2.929ns   625.8mV    910.5mV    493.8mV
10ns      625.1mV    848.2mV    493.8mV
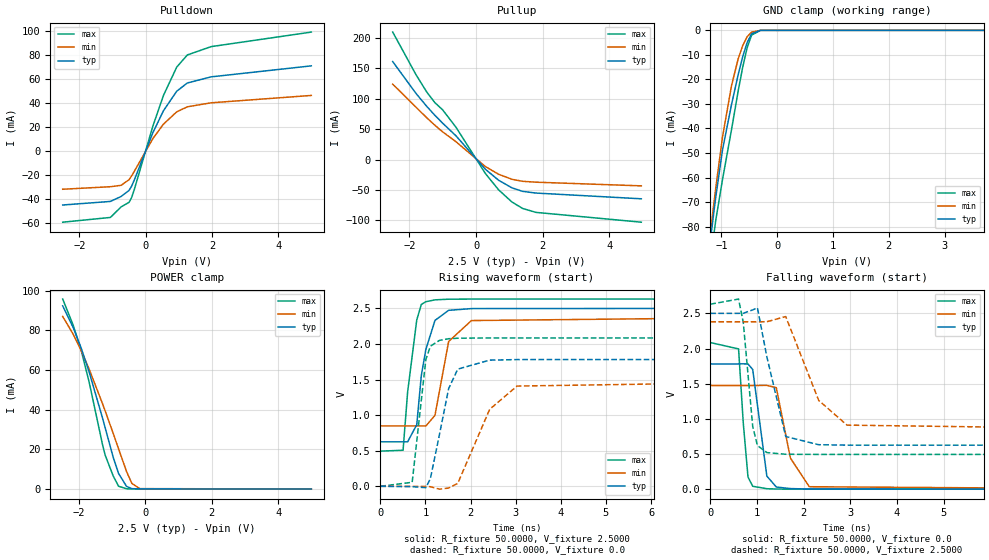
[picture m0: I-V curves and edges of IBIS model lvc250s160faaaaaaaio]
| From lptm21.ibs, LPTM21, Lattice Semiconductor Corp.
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|   Model lvc250s160faaaaaaaio
[Model]   lvc250s160faaaaaaaio
Model_type   I/O
Polarity   Non-Inverting
Enable   Active-Low
Vinl =   0.7000V
Vinh =   1.7000V
Vmeas =   1.2500V
Cref =   0.0F
Rref =   1.0000M
Vref =   0.0V
C_comp   4.2000pF   3.8000pF   7.5000pF
[Temperature Range]   25.0000   0.1050k   -40.0000
[Voltage Range]   2.5000V   2.3800V   2.6300V
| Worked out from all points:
|   slope of the pulldown table from 0 to 0.375 V, typ, clamps not added: 15.3 ohm
|   slope of the pullup table from 0 to 0.375 V, typ, clamps not added: 18.1 ohm
|   GND clamp passes 1 mA (typ) near -0.44 V on its own axis
|   POWER clamp passes 1 mA (typ) near -0.54 V on its own axis
|   rising waveform, R_fixture 50.0000, V_fixture 2.5000: 20-80 % time 272ps typ, 308ps min, 221ps max; typ from 0.625 V to 2.5 V
|   rising waveform, R_fixture 50.0000, V_fixture 0.0: 20-80 % time 340ps typ, 590ps min, 210ps max; typ from 0 V to 1.78 V
|   falling waveform, R_fixture 50.0000, V_fixture 0.0: 20-80 % time 209ps typ, 295ps min, 139ps max; typ from 1.78 V to 0 V
|   falling waveform, R_fixture 50.0000, V_fixture 2.5000: 20-80 % time 297ps typ, 529ps min, 177ps max; typ from 2.5 V to 0.625 V
[Pulldown]
|Voltage   I(typ)   I(min)   I(max)
-2.5V     -44.98mA   -31.87mA   -59.28mA
-1.06V    -42mA      -29.76mA   -55.31mA
-740mV    -37.91mA   -28.62mA   -46.59mA
-500mV    -32.87mA   -23.94mA   -42.77mA
-420mV    -29.26mA   -20.76mA   -38.71mA
-340mV    -24.14mA   -16.94mA   -32.06mA
220mV     15.19mA    10.29mA    20.67mA
540mV     33.48mA    22.33mA    46.22mA
940mV     49.71mA    32.53mA    69.81mA
1.26V     56.56mA    36.73mA    79.88mA
1.98V     61.65mA    40.07mA    86.82mA
5V        70.8mA     46.18mA    98.9mA
[Pullup]
|Voltage   I(typ)   I(min)   I(max)
-2.5V     161mA      123.9mA    209.5mA
-1.8V     108.6mA    86mA       139.4mA
-1.48V    87.5mA     68.71mA    111.1mA
-1.24V    73.02mA    56.63mA    93.84mA
-1V       59.69mA    45.38mA    81.55mA
-600mV    38.88mA    29.21mA    52.98mA
280mV     -15.97mA   -11.54mA   -22.9mA
680mV     -34.12mA   -24.26mA   -49.96mA
1.08V     -46.59mA   -32.48mA   -69.92mA
1.4V      -52.33mA   -35.82mA   -80.45mA
1.8V      -55.12mA   -37.24mA   -86.89mA
4.96V     -64.54mA   -43.28mA   -103mA
[GND_clamp]
|Voltage   I(typ)   I(min)   I(max)
-2.5V     -564.6mA   -543.1mA   -585.1mA
-1.18V    -82.28mA   -79mA      -91.03mA
-1.14V    -74.81mA   -71.35mA   -83.85mA
-1.1V     -67.63mA   -63.91mA   -77.15mA
-980mV    -48.6mA    -43.33mA   -60.69mA
-820mV    -30.29mA   -22.62mA   -40.55mA
-700mV    -18.04mA   -11.6mA    -24.7mA
-620mV    -10.82mA   -6.314mA   -15.14mA
-540mV    -5.025mA   -2.64mA    -7.154mA
-460mV    -1.426mA   -708.3uA   -1.934mA
-300mV    -17.76uA   -15.73uA   -12.8uA
5V        0A         0A         0A
[POWER_clamp]
|Voltage   I(typ)   I(min)   I(max)
-2.48V    92.38mA    87.03mA    95.82mA
-2.16V    81.29mA    77.94mA    82.39mA
-1.92V    70.92mA    69.63mA    69.65mA
-1.68V    58.78mA    60.26mA    53.56mA
-1.28V    35.62mA    42.91mA    22.18mA
-1.2V     30.69mA    39.25mA    16.92mA
-960mV    15.9mA     27.98mA    6.508mA
-800mV    7.821mA    20.25mA    1.349mA
-560mV    1.267mA    8.796mA    53.58uA
-400mV    117.5uA    2.764mA    20.86uA
-160mV    16.15uA    125.2uA    -13.85uA
5V        -83.86uA   -49.55uA   -142.1uA
[Ramp]
| variable   typ   min   max
dV/dt_r  1.0688/0.3361n   0.8847/0.5844n   1.2507/0.2078n
dV/dt_f  1.1250/0.2937n   0.9191/0.5242n   1.2817/0.1754n
R_load = 50.0000
[Rising Waveform]
R_fixture=   50.0000
V_fixture=   2.5000
V_fixture_min=   2.3800
V_fixture_max=   2.6300
|time   V(typ)   V(min)   V(max)
0s        625.1mV    848.2mV    493.8mV
505.1ps   625.1mV    848.2mV    506.6mV
606.1ps   625.1mV    848.2mV    1.325V
808.1ps   864.9mV    848.3mV    2.336V
909.1ps   1.554V     848.7mV    2.554V
1.01ns    1.922V     847.3mV    2.593V
1.212ns   2.33V      996.3mV    2.619V
1.515ns   2.472V     2.034V     2.628V
2.02ns    2.496V     2.328V     2.63V
10ns      2.5V       2.38V      2.63V
[Rising Waveform]
R_fixture=   50.0000
V_fixture=   0.0
V_fixture_min=   0.0
V_fixture_max=   0.0
|time   V(typ)   V(min)   V(max)
0s        394.5nV    565.3nV    312nV
707.1ps   -5.27mV    7.859uV    56.14mV
1.01ns    -19.04mV   -648.7uV   1.782V
1.111ns   109.3mV    -5.939mV   1.968V
1.313ns   731.5mV    -40.24mV   2.05V
1.515ns   1.372V     -24.24mV   2.073V
1.717ns   1.646V     41.02mV    2.08V
2.424ns   1.772V     1.081V     2.084V
3.03ns    1.78V      1.408V     2.084V
10ns      1.781V     1.474V     2.084V
[Falling Waveform]
R_fixture=   50.0000
V_fixture=   0.0
V_fixture_min=   0.0
V_fixture_max=   0.0
|time   V(typ)   V(min)   V(max)
0s        1.781V     1.474V     2.085V
606.1ps   1.781V     1.474V     1.994V
707.1ps   1.782V     1.474V     937.7mV
808.1ps   1.78V      1.474V     171.8mV
909.1ps   1.702V     1.474V     41.12mV
1.212ns   185.6mV    1.475V     6.403mV
1.414ns   30.45mV    1.443V     1.915mV
1.717ns   8.322mV    441.2mV    357.2uV
2.121ns   1.731mV    34.79mV    86.71uV
10ns      -26.63uV   17.43uV    -15.71uV
[Falling Waveform]
R_fixture=   50.0000
V_fixture=   2.5000
V_fixture_min=   2.3800
V_fixture_max=   2.6300
|time   V(typ)   V(min)   V(max)
0s        2.5V       2.38V      2.63V
606.1ps   2.5V       2.38V      2.703V
707.1ps   2.501V     2.38V      2.371V
909.1ps   2.549V     2.38V      891mV
1.01ns    2.579V     2.38V      620.9mV
1.212ns   1.882V     2.381V     520mV
1.616ns   748.9mV    2.454V     496.3mV
2.323ns   631.9mV    1.262V     493.9mV
2.929ns   625.8mV    910.5mV    493.8mV
10ns      625.1mV    848.2mV    493.8mV
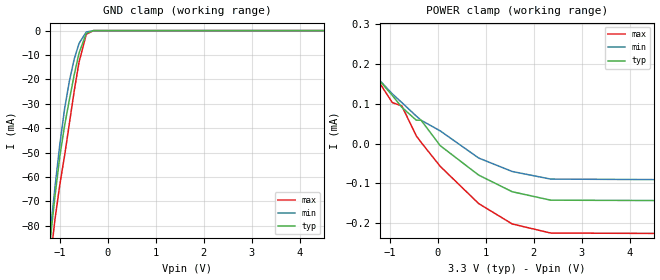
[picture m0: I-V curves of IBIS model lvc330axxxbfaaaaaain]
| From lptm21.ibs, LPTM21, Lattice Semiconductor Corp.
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|   Model lvc330axxxbfaaaaaain
[Model]   lvc330axxxbfaaaaaain
Model_type   Input
Polarity   Non-Inverting
Enable   Active-Low
Vinl =   0.8000V
Vinh =   2.0000V
C_comp   4.2000pF   3.8000pF   7.5000pF
[Temperature Range]   25.0000   0.1050k   -40.0000
[Voltage Range]   3.3000V   3.1400V   3.4700V
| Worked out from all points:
|   GND clamp passes 1 mA (typ) near -0.44 V on its own axis
[GND_clamp]
|Voltage   I(typ)   I(min)   I(max)
-3.3V     -955.2mA   -930.2mA   -977.8mA
-1.2V     -86.07mA   -82.87mA   -94.72mA
-1.15V    -76.63mA   -73.23mA   -85.56mA
-1.1V     -67.6mA    -63.89mA   -77.1mA
-1V       -51.41mA   -46.51mA   -63.05mA
-900mV    -38.77mA   -31.83mA   -51.09mA
-800mV    -28.16mA   -20.53mA   -37.81mA
-700mV    -18.01mA   -11.59mA   -24.66mA
-600mV    -9.192mA   -5.229mA   -12.92mA
-450mV    -1.151mA   -576.6uA   -1.527mA
-300mV    -17.4uA    -15.66uA   -11.6uA
6.6V      0A         0A         0A
[POWER_clamp]
|Voltage   I(typ)   I(min)   I(max)
-3.25V    961.3uA    1.05mA     917.9uA
-2.25V    305.8uA    299.5uA    344.1uA
-1.95V    260.5uA    253.4uA    288.8uA
-950mV    120.7uA    124.7uA    102.8uA
-750mV    90.82uA    102.7uA    94.17uA
-450mV    58.57uA    68.87uA    19.46uA
-350mV    58.57uA    58.54uA    3.121uA
50mV      -5.338uA   31.71uA    -57.16uA
850mV     -79.07uA   -36.24uA   -150.4uA
1.55V     -120.8uA   -70.05uA   -201.6uA
2.35V     -141.9uA   -89.06uA   -224.3uA
6.6V      -143.8uA   -91.66uA   -226.3uA
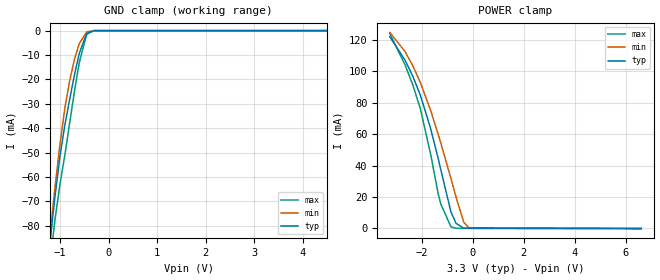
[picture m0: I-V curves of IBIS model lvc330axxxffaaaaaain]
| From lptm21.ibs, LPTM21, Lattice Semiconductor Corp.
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|   Model lvc330axxxffaaaaaain
[Model]   lvc330axxxffaaaaaain
Model_type   Input
Polarity   Non-Inverting
Enable   Active-Low
Vinl =   0.8000V
Vinh =   2.0000V
C_comp   4.2000pF   3.8000pF   7.5000pF
[Temperature Range]   25.0000   0.1050k   -40.0000
[Voltage Range]   3.3000V   3.1400V   3.4700V
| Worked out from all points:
|   GND clamp passes 1 mA (typ) near -0.44 V on its own axis
|   POWER clamp passes 1 mA (typ) near -0.53 V on its own axis
[GND_clamp]
|Voltage   I(typ)   I(min)   I(max)
-3.3V     -955.2mA   -930.2mA   -977.8mA
-1.2V     -86.07mA   -82.87mA   -94.72mA
-1.15V    -76.63mA   -73.23mA   -85.56mA
-1.1V     -67.6mA    -63.89mA   -77.1mA
-1V       -51.41mA   -46.51mA   -63.05mA
-900mV    -38.77mA   -31.83mA   -51.09mA
-800mV    -28.16mA   -20.53mA   -37.81mA
-700mV    -18.01mA   -11.59mA   -24.66mA
-600mV    -9.192mA   -5.229mA   -12.92mA
-450mV    -1.151mA   -576.6uA   -1.527mA
-300mV    -17.4uA    -15.66uA   -11.6uA
6.6V      0A         0A         0A
[POWER_clamp]
|Voltage   I(typ)   I(min)   I(max)
-3.25V    122.1mA    124.8mA    124.2mA
-2.65V    107.1mA    112.6mA    104.1mA
-2.35V    97.06mA    103.7mA    91.56mA
-2.05V    84.81mA    92.86mA    76.2mA
-1.65V    63.69mA    75.19mA    47.4mA
-1.35V    44.32mA    59.82mA    21.89mA
-1.25V    37.38mA    54.39mA    15.53mA
-850mV    10.3mA     31.63mA    860uA
-650mV    3.168mA    19.76mA    65.53uA
-350mV    73.34uA    3.862mA    3.121uA
-150mV    17.77uA    366.8uA    -28.16uA
6.6V      -143.8uA   -91.66uA   -226.3uA
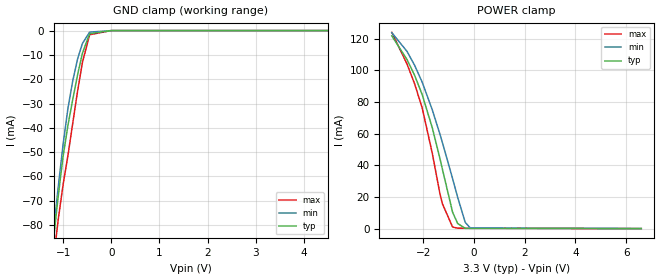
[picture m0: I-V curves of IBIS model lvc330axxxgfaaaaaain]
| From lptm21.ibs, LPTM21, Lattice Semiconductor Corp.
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|   Model lvc330axxxgfaaaaaain
[Model]   lvc330axxxgfaaaaaain
Model_type   Input
Polarity   Non-Inverting
Enable   Active-Low
Vinl =   0.8000V
Vinh =   2.0000V
C_comp   4.2000pF   3.8000pF   7.5000pF
[Temperature Range]   25.0000   0.1050k   -40.0000
[Voltage Range]   3.3000V   3.1400V   3.4700V
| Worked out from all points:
|   GND clamp passes 1 mA (typ) near -0.43 V on its own axis
|   POWER clamp passes 1 mA (typ) near -0.53 V on its own axis
[GND_clamp]
|Voltage   I(typ)   I(min)   I(max)
-3.3V     -955.3mA   -930.3mA   -978mA
-1.2V     -86.21mA   -82.95mA   -94.94mA
-1.15V    -76.76mA   -73.31mA   -85.77mA
-1.1V     -67.73mA   -63.97mA   -77.32mA
-1V       -51.54mA   -46.59mA   -63.26mA
-900mV    -38.9mA    -31.9mA    -51.31mA
-800mV    -28.29mA   -20.61mA   -38.02mA
-700mV    -18.14mA   -11.66mA   -24.86mA
-600mV    -9.315mA   -5.302mA   -13.12mA
-450mV    -1.255mA   -637uA     -1.701mA
0V        0A         0A         0A
6.6V      0A         0A         0A
[POWER_clamp]
|Voltage   I(typ)   I(min)   I(max)
-3.25V    121.9mA    123.9mA    124.1mA
-2.65V    106.9mA    112.1mA    104.1mA
-2.35V    96.95mA    103.3mA    91.59mA
-2.05V    84.73mA    92.58mA    76.25mA
-1.65V    63.65mA    75mA       47.49mA
-1.35V    44.31mA    59.69mA    21.99mA
-1.25V    37.38mA    54.28mA    15.6mA
-850mV    10.32mA    31.58mA    939uA
-650mV    3.193mA    19.74mA    210uA
-350mV    132.1uA    3.862mA    199.7uA
-150mV    104.6uA    375.8uA    197.7uA
6.6V      -56.35nA   -1.463uA   -71.55uA
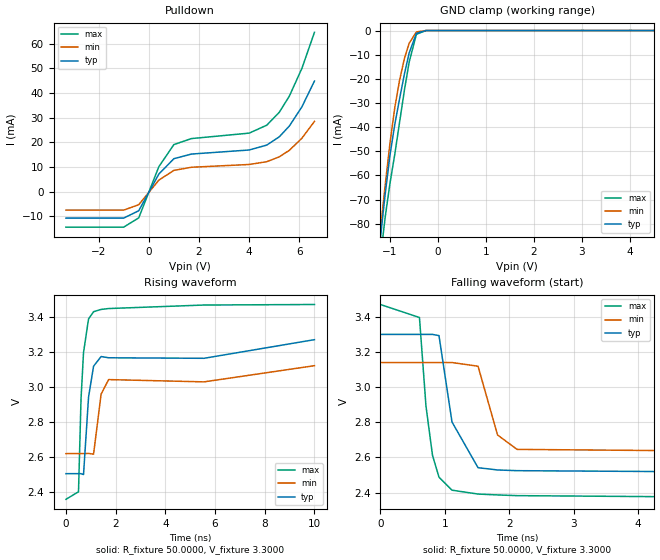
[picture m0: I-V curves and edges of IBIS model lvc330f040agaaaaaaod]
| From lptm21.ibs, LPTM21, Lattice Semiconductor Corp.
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|   Model lvc330f040agaaaaaaod
[Model]   lvc330f040agaaaaaaod
Model_type   I/O_open_drain
Polarity   Non-Inverting
Enable   Active-Low
Vinl =   0.8000V
Vinh =   2.0000V
Vmeas =   1.6500V
Cref =   0.0F
Rref =   1.0000M
Vref =   0.0V
C_comp   4.2000pF   3.8000pF   7.5000pF
[Temperature Range]   25.0000   0.1050k   -40.0000
[Voltage Range]   3.3000V   3.1400V   3.4700V
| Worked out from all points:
|   slope of the pulldown table from 0 to 0.495 V, typ, clamps not added: 58.8 ohm
|   GND clamp passes 1 mA (typ) near -0.44 V on its own axis
|   rising waveform, R_fixture 50.0000, V_fixture 3.3000: 20-80 % time 308ps typ, 343ps min, 208ps max; typ from 2.51 V to 3.27 V
|   falling waveform, R_fixture 50.0000, V_fixture 3.3000: 20-80 % time 222ps typ, 242ps min, 196ps max; typ from 3.3 V to 2.51 V
[Pulldown]
|Voltage   I(typ)   I(min)   I(max)
-3.3V     -10.78mA   -7.548mA   -14.46mA
-1V       -10.78mA   -7.548mA   -14.46mA
-400mV    -7.794mA   -5.358mA   -10.68mA
400mV     7.073mA    4.611mA    10.06mA
1V        13.32mA    8.58mA     19.04mA
1.7V      15.2mA     9.844mA    21.48mA
4V        16.85mA    10.97mA    23.69mA
4.7V      18.84mA    12.1mA     26.91mA
5.2V      22.21mA    14.07mA    32.16mA
5.6V      26.57mA    16.72mA    38.71mA
6.1V      34.35mA    21.62mA    49.96mA
6.6V      44.82mA    28.45mA    64.59mA
[GND_clamp]
|Voltage   I(typ)   I(min)   I(max)
-3.3V     -955.3mA   -930.3mA   -978mA
-1.2V     -86.17mA   -82.92mA   -94.88mA
-1.15V    -76.72mA   -73.28mA   -85.71mA
-1.1V     -67.69mA   -63.94mA   -77.25mA
-1V       -51.5mA    -46.56mA   -63.19mA
-900mV    -38.85mA   -31.87mA   -51.24mA
-800mV    -28.24mA   -20.57mA   -37.95mA
-700mV    -18.09mA   -11.63mA   -24.79mA
-600mV    -9.258mA   -5.26mA    -13.05mA
-450mV    -1.178mA   -585.4uA   -1.585mA
-250mV    -3.51uA    -4.042uA   -2.972uA
6.6V      0A         0A         0A
[Ramp]
| variable   typ   min   max
dV/dt_r  0.4573/0.3047n   0.2816/0.2642n   0.6537/0.3214n
dV/dt_f  0.4756/0.2199n   0.3107/0.2398n   0.6648/0.1942n
R_load = 50.0000
[Rising Waveform]
R_fixture=   50.0000
V_fixture=   3.3000
V_fixture_min=   3.1400
V_fixture_max=   3.4700
|time   V(typ)   V(min)   V(max)
0s        2.507V     2.621V     2.361V
505.1ps   2.507V     2.621V     2.404V
606.1ps   2.507V     2.621V     2.93V
707.1ps   2.502V     2.621V     3.196V
909.1ps   2.942V     2.622V     3.387V
1.111ns   3.118V     2.618V     3.428V
1.414ns   3.173V     2.959V     3.441V
1.717ns   3.166V     3.042V     3.446V
5.556ns   3.163V     3.029V     3.466V
10ns      3.269V     3.121V     3.469V
[Falling Waveform]
R_fixture=   50.0000
V_fixture=   3.3000
V_fixture_min=   3.1400
V_fixture_max=   3.4700
|time   V(typ)   V(min)   V(max)
0s        3.3V       3.14V      3.47V
606.1ps   3.3V       3.14V      3.396V
707.1ps   3.3V       3.14V      2.893V
808.1ps   3.3V       3.14V      2.613V
909.1ps   3.293V     3.14V      2.488V
1.111ns   2.802V     3.14V      2.414V
1.515ns   2.542V     3.119V     2.392V
1.818ns   2.529V     2.728V     2.387V
2.121ns   2.525V     2.646V     2.383V
10ns      2.507V     2.622V     2.362V
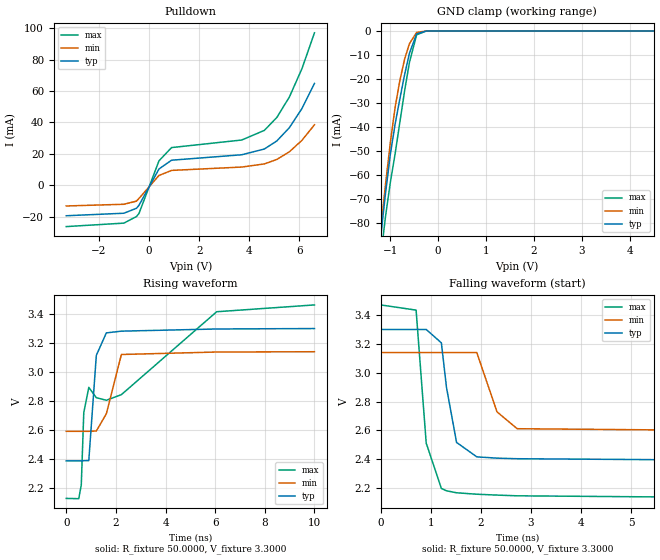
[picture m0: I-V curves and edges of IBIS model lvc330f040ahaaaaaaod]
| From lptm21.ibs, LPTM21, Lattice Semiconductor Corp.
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|   Model lvc330f040ahaaaaaaod
[Model]   lvc330f040ahaaaaaaod
Model_type   I/O_open_drain
Polarity   Non-Inverting
Enable   Active-Low
Vinl =   0.8000V
Vinh =   2.0000V
Vmeas =   1.6500V
Cref =   0.0F
Rref =   1.0000M
Vref =   0.0V
C_comp   4.2000pF   3.8000pF   7.5000pF
[Temperature Range]   25.0000   0.1050k   -40.0000
[Voltage Range]   3.3000V   3.1400V   3.4700V
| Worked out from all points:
|   slope of the pulldown table from 0 to 0.495 V, typ, clamps not added: 41.1 ohm
|   GND clamp passes 1 mA (typ) near -0.44 V on its own axis
|   rising waveform, R_fixture 50.0000, V_fixture 3.3000: 20-80 % time 221ps typ, 244ps min, 4.27ns max; typ from 2.39 V to 3.3 V
|   falling waveform, R_fixture 50.0000, V_fixture 3.3000: 20-80 % time 231ps typ, 278ps min, 213ps max; typ from 3.3 V to 2.39 V
[Pulldown]
|Voltage   I(typ)   I(min)   I(max)
-3.3V     -19.41mA   -13.19mA   -26.31mA
-1V       -17.81mA   -12.1mA    -24.1mA
-500mV    -14.66mA   -10.11mA   -19.91mA
-400mV    -12.76mA   -8.409mA   -17.99mA
400mV     10.37mA    6.259mA    15.57mA
900mV     15.94mA    9.451mA    23.98mA
3.7V      19.41mA    11.59mA    28.8mA
4.6V      23.07mA    13.57mA    34.91mA
5.1V      28.22mA    16.44mA    43.17mA
5.6V      36.67mA    21.32mA    56.18mA
6.1V      48.82mA    28.59mA    74.17mA
6.6V      64.79mA    38.5mA     97.03mA
[GND_clamp]
|Voltage   I(typ)   I(min)   I(max)
-3.3V     -955.3mA   -930.3mA   -978mA
-1.2V     -86.16mA   -82.91mA   -94.88mA
-1.15V    -76.71mA   -73.27mA   -85.71mA
-1.1V     -67.69mA   -63.93mA   -77.25mA
-1V       -51.49mA   -46.56mA   -63.18mA
-900mV    -38.84mA   -31.87mA   -51.23mA
-800mV    -28.23mA   -20.57mA   -37.94mA
-700mV    -18.08mA   -11.62mA   -24.79mA
-600mV    -9.254mA   -5.257mA   -13.04mA
-450mV    -1.176mA   -584.6uA   -1.582mA
-250mV    -3.498uA   -4.034uA   -2.958uA
6.6V      0A         0A         0A
[Ramp]
| variable   typ   min   max
dV/dt_r  0.5477/0.2184n   0.3292/0.2414n   0.8054/0.2057n
dV/dt_f  0.5477/0.2282n   0.3292/0.2749n   0.8054/0.2114n
R_load = 50.0000
[Rising Waveform]
R_fixture=   50.0000
V_fixture=   3.3000
V_fixture_min=   3.1400
V_fixture_max=   3.4700
|time   V(typ)   V(min)   V(max)
0s        2.386V     2.59V      2.127V
505.1ps   2.386V     2.59V      2.125V
606.1ps   2.386V     2.59V      2.22V
707.1ps   2.387V     2.59V      2.719V
909.1ps   2.388V     2.59V      2.893V
1.212ns   3.114V     2.592V     2.822V
1.616ns   3.269V     2.711V     2.804V
2.222ns   3.281V     3.12V      2.843V
6.061ns   3.296V     3.137V     3.415V
10ns      3.299V     3.139V     3.462V
[Falling Waveform]
R_fixture=   50.0000
V_fixture=   3.3000
V_fixture_min=   3.1400
V_fixture_max=   3.4700
|time   V(typ)   V(min)   V(max)
0s        3.3V       3.14V      3.47V
707.1ps   3.3V       3.14V      3.434V
909.1ps   3.3V       3.14V      2.512V
1.212ns   3.207V     3.14V      2.198V
1.313ns   2.901V     3.14V      2.182V
1.515ns   2.517V     3.14V      2.168V
1.919ns   2.417V     3.14V      2.158V
2.323ns   2.408V     2.729V     2.152V
2.727ns   2.404V     2.612V     2.147V
10ns      2.387V     2.591V     2.127V
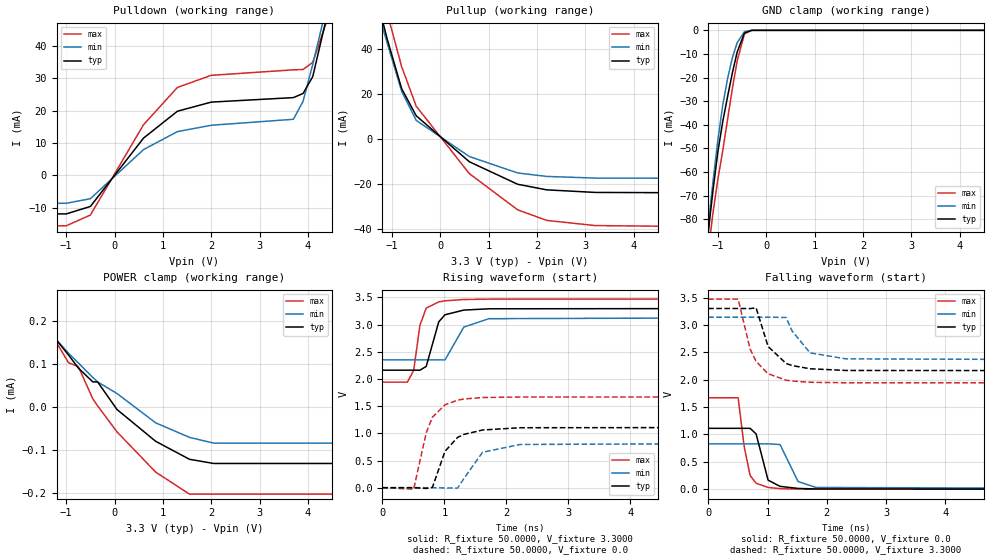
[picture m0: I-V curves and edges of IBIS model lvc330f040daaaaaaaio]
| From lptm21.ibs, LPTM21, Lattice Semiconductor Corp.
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|   Model lvc330f040daaaaaaaio
[Model]   lvc330f040daaaaaaaio
Model_type   I/O
Polarity   Non-Inverting
Enable   Active-Low
Vinl =   0.8000V
Vinh =   2.0000V
Vmeas =   1.500000V
Cref =   0.0F
Rref =   1.0000M
Vref =   0.0V
C_comp   4.2000pF   3.8000pF   7.5000pF
[Temperature Range]   25.0000   0.1050k   -40.0000
[Voltage Range]   3.3000V   3.1400V   3.4700V
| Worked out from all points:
|   slope of the pulldown table from 0 to 0.495 V, typ, clamps not added: 50.7 ohm
|   slope of the pullup table from 0 to 0.495 V, typ, clamps not added: 58.5 ohm
|   GND clamp passes 1 mA (typ) near -0.44 V on its own axis
|   rising waveform, R_fixture 50.0000, V_fixture 3.3000: 20-80 % time 185ps typ, 254ps min, 147ps max; typ from 2.16 V to 3.3 V
|   rising waveform, R_fixture 50.0000, V_fixture 0.0: 20-80 % time 304ps typ, 324ps min, 246ps max; typ from 0 V to 1.11 V
|   falling waveform, R_fixture 50.0000, V_fixture 0.0: 20-80 % time 159ps typ, 213ps min, 148ps max; typ from 1.11 V to 0 V
|   falling waveform, R_fixture 50.0000, V_fixture 3.3000: 20-80 % time 297ps typ, 309ps min, 289ps max; typ from 3.3 V to 2.16 V
[Pulldown]
|Voltage   I(typ)   I(min)   I(max)
-3.3V     -11.92mA   -8.642mA   -15.6mA
-1V       -11.92mA   -8.642mA   -15.6mA
-500mV    -9.624mA   -7.225mA   -12.27mA
600mV     11.49mA    7.938mA    15.62mA
1.3V      19.78mA    13.49mA    27.13mA
2V        22.6mA     15.45mA    30.87mA
3.7V      23.99mA    17.3mA     32.57mA
3.9V      25.28mA    22.85mA    32.67mA
4.1V      30.47mA    34.23mA    34.88mA
4.5V      56mA       59.18mA    52.45mA
4.6V      63.61mA    65.35mA    60.64mA
6.6V      186.5mA    170.3mA    212mA
[Pullup]
|Voltage   I(typ)   I(min)   I(max)
-3.3V     195mA      177.8mA    227.8mA
-1.4V     69.53mA    64.71mA    88.1mA
-1.3V     61.25mA    57.43mA    77.39mA
-1.2V     52.87mA    50.1mA     66.58mA
-1.1V     44.47mA    42.74mA    55.99mA
-800mV    22.38mA    21.23mA    32.17mA
-500mV    10.43mA    8.389mA    14.69mA
600mV     -9.992mA   -7.668mA   -15.26mA
1.6V      -19.98mA   -14.96mA   -31.34mA
2.2V      -22.45mA   -16.49mA   -36.01mA
3.2V      -23.59mA   -17.23mA   -38.3mA
6.55V     -23.86mA   -17.35mA   -39.03mA
[GND_clamp]
|Voltage   I(typ)   I(min)   I(max)
-3.3V     -955.2mA   -930.2mA   -977.8mA
-1.2V     -86.08mA   -82.87mA   -94.74mA
-1.15V    -76.63mA   -73.22mA   -85.57mA
-1.1V     -67.6mA    -63.89mA   -77.12mA
-1V       -51.41mA   -46.51mA   -63.06mA
-900mV    -38.77mA   -31.82mA   -51.11mA
-800mV    -28.16mA   -20.53mA   -37.82mA
-700mV    -18.01mA   -11.58mA   -24.66mA
-600mV    -9.185mA   -5.219mA   -12.92mA
-450mV    -1.125mA   -553.6uA   -1.501mA
-300mV    0A         0A         0A
6.6V      0A         0A         0A
[POWER_clamp]
|Voltage   I(typ)   I(min)   I(max)
-3.25V    961.3uA    1.05mA     917.9uA
-2.05V    275.4uA    268.3uA    307.1uA
-1.75V    231.3uA    224.8uA    252.6uA
-950mV    120.7uA    124.7uA    102.8uA
-750mV    90.82uA    102.7uA    94.17uA
-450mV    58.57uA    68.87uA    19.46uA
-350mV    58.57uA    58.54uA    3.121uA
50mV      -5.338uA   31.71uA    -57.16uA
850mV     -79.07uA   -36.24uA   -150.4uA
1.55V     -120.8uA   -70.05uA   -201.6uA
2.05V     -130.5uA   -83.29uA   -201.6uA
6.6V      -130.5uA   -83.29uA   -201.6uA
[Ramp]
| variable   typ   min   max
dV/dt_r  0.7027/0.3013n   0.4966/0.3205n   1.0018/0.2438n
dV/dt_f  0.6827/0.2942n   0.4730/0.3057n   0.9168/0.2859n
R_load = 50.0000
[Rising Waveform]
R_fixture=   50.0000
V_fixture=   3.3000
V_fixture_min=   3.1400
V_fixture_max=   3.4700
|time   V(typ)   V(min)   V(max)
0s        2.162V     2.352V     1.942V
404ps     2.162V     2.352V     1.942V
505.1ps   2.162V     2.352V     2.158V
606.1ps   2.161V     2.352V     2.988V
707.1ps   2.231V     2.352V     3.303V
909.1ps   3.05V      2.351V     3.417V
1.01ns    3.181V     2.35V      3.438V
1.313ns   3.267V     2.954V     3.462V
1.717ns   3.291V     3.109V     3.469V
10ns      3.3V       3.14V      3.47V
[Rising Waveform]
R_fixture=   50.0000
V_fixture=   0.0
V_fixture_min=   0.0
V_fixture_max=   0.0
|time   V(typ)   V(min)   V(max)
0s        1.288uV    1.554uV    1.323uV
505.1ps   26.26uV    1.514uV    -27.26mV
707.1ps   -14.34mV   18.68uV    1.008V
808.1ps   7.053mV    87.81uV    1.296V
1.01ns    669mV      -4.761mV   1.525V
1.212ns   924mV      -7.52mV    1.61V
1.313ns   979.6mV    165.4mV    1.631V
1.616ns   1.061V     651.6mV    1.659V
2.222ns   1.103V     795.2mV    1.668V
10ns      1.111V     827.7mV    1.67V
[Falling Waveform]
R_fixture=   50.0000
V_fixture=   0.0
V_fixture_min=   0.0
V_fixture_max=   0.0
|time   V(typ)   V(min)   V(max)
0s        1.111V     827.7mV    1.67V
505.1ps   1.111V     827.7mV    1.669V
606.1ps   1.111V     827.7mV    781.7mV
707.1ps   1.111V     827.7mV    249.6mV
808.1ps   1.008V     827.7mV    108.5mV
1.01ns    164.9mV    828.2mV    31.11mV
1.212ns   51.1mV     814.5mV    9.451mV
1.515ns   13.32mV    139.2mV    1.692mV
1.818ns   3.881mV    31.12mV    402.4uV
10ns      -16.78uV   26.97uV    -5.658uV
[Falling Waveform]
R_fixture=   50.0000
V_fixture=   3.3000
V_fixture_min=   3.1400
V_fixture_max=   3.4700
|time   V(typ)   V(min)   V(max)
0s        3.3V       3.14V      3.47V
505.1ps   3.3V       3.14V      3.472V
707.1ps   3.298V     3.14V      2.56V
808.1ps   3.311V     3.14V      2.332V
1.01ns    2.606V     3.141V     2.108V
1.313ns   2.296V     3.136V     1.991V
1.414ns   2.258V     2.89V      1.975V
1.717ns   2.199V     2.49V      1.952V
2.323ns   2.168V     2.38V      1.943V
10ns      2.162V     2.352V     1.942V
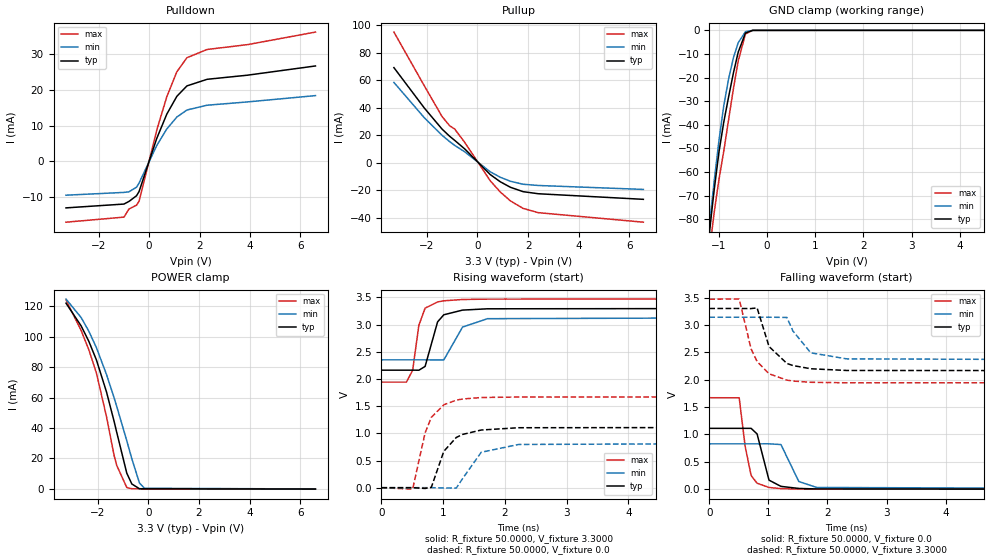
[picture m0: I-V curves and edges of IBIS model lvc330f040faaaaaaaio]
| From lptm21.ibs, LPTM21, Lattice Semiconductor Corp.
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|   Model lvc330f040faaaaaaaio
[Model]   lvc330f040faaaaaaaio
Model_type   I/O
Polarity   Non-Inverting
Enable   Active-Low
Vinl =   0.8000V
Vinh =   2.0000V
Vmeas =   1.500000V
Cref =   0.0F
Rref =   1.0000M
Vref =   0.0V
C_comp   4.2000pF   3.8000pF   7.5000pF
[Temperature Range]   25.0000   0.1050k   -40.0000
[Voltage Range]   3.3000V   3.1400V   3.4700V
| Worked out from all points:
|   slope of the pulldown table from 0 to 0.495 V, typ, clamps not added: 50.3 ohm
|   slope of the pullup table from 0 to 0.495 V, typ, clamps not added: 58.5 ohm
|   GND clamp passes 1 mA (typ) near -0.44 V on its own axis
|   POWER clamp passes 1 mA (typ) near -0.53 V on its own axis
|   rising waveform, R_fixture 50.0000, V_fixture 3.3000: 20-80 % time 185ps typ, 254ps min, 147ps max; typ from 2.16 V to 3.3 V
|   rising waveform, R_fixture 50.0000, V_fixture 0.0: 20-80 % time 304ps typ, 324ps min, 246ps max; typ from 0 V to 1.11 V
|   falling waveform, R_fixture 50.0000, V_fixture 0.0: 20-80 % time 159ps typ, 213ps min, 148ps max; typ from 1.11 V to 0 V
|   falling waveform, R_fixture 50.0000, V_fixture 3.3000: 20-80 % time 297ps typ, 309ps min, 289ps max; typ from 3.3 V to 2.16 V
[Pulldown]
|Voltage   I(typ)   I(min)   I(max)
-3.3V     -13mA      -9.446mA   -17.01mA
-1V       -11.93mA   -8.664mA   -15.59mA
-800mV    -11.19mA   -8.492mA   -13.32mA
-500mV    -9.593mA   -7.199mA   -12.23mA
-400mV    -8.406mA   -6.043mA   -11.13mA
300mV     6.433mA    4.454mA    8.752mA
700mV     13.26mA    9.112mA    18.14mA
1.1V      18.27mA    12.46mA    25.14mA
1.5V      21.18mA    14.43mA    29.08mA
2.3V      23.03mA    15.77mA    31.39mA
3.9V      24.18mA    16.69mA    32.74mA
6.6V      26.77mA    18.46mA    36.26mA
[Pullup]
|Voltage   I(typ)   I(min)   I(max)
-3.3V     69.1mA     58.33mA    94.91mA
-2.1V     39.75mA    32.69mA    55.88mA
-1.4V     24.44mA    19.94mA    33.57mA
-1.1V     19.23mA    15.35mA    26.86mA
-900mV    16.24mA    12.6mA     24.47mA
-500mV    9.951mA    7.871mA    14.67mA
500mV     -8.539mA   -6.567mA   -13.01mA
900mV     -13.85mA   -10.56mA   -21.29mA
1.3V      -17.84mA   -13.47mA   -27.72mA
1.8V      -21.02mA   -15.64mA   -33.19mA
2.4V      -22.54mA   -16.54mA   -36.28mA
6.55V     -26.6mA    -19.4mA    -43.21mA
[GND_clamp]
|Voltage   I(typ)   I(min)   I(max)
-3.3V     -955.2mA   -930.2mA   -977.8mA
-1.2V     -86.07mA   -82.87mA   -94.72mA
-1.15V    -76.63mA   -73.23mA   -85.56mA
-1.1V     -67.6mA    -63.89mA   -77.1mA
-1V       -51.41mA   -46.51mA   -63.05mA
-900mV    -38.77mA   -31.83mA   -51.09mA
-800mV    -28.16mA   -20.53mA   -37.81mA
-700mV    -18.01mA   -11.59mA   -24.66mA
-600mV    -9.192mA   -5.229mA   -12.92mA
-450mV    -1.151mA   -576.6uA   -1.527mA
-300mV    -17.4uA    -15.66uA   -11.6uA
6.6V      0A         0A         0A
[POWER_clamp]
|Voltage   I(typ)   I(min)   I(max)
-3.25V    122.1mA    124.8mA    124.2mA
-2.65V    107.1mA    112.6mA    104.1mA
-2.35V    97.06mA    103.7mA    91.56mA
-2.05V    84.81mA    92.86mA    76.2mA
-1.65V    63.69mA    75.19mA    47.4mA
-1.35V    44.32mA    59.82mA    21.89mA
-1.25V    37.38mA    54.39mA    15.53mA
-850mV    10.3mA     31.63mA    860uA
-650mV    3.168mA    19.76mA    65.53uA
-350mV    73.34uA    3.862mA    3.121uA
-150mV    17.77uA    366.8uA    -28.16uA
6.6V      -143.8uA   -91.66uA   -226.3uA
[Ramp]
| variable   typ   min   max
dV/dt_r  0.7027/0.3013n   0.4966/0.3205n   1.0018/0.2438n
dV/dt_f  0.6827/0.2942n   0.4730/0.3057n   0.9168/0.2859n
R_load = 50.0000
[Rising Waveform]
R_fixture=   50.0000
V_fixture=   3.3000
V_fixture_min=   3.1400
V_fixture_max=   3.4700
|time   V(typ)   V(min)   V(max)
0s        2.162V     2.352V     1.942V
404ps     2.162V     2.352V     1.942V
505.1ps   2.162V     2.352V     2.158V
606.1ps   2.161V     2.352V     2.988V
707.1ps   2.231V     2.352V     3.303V
909.1ps   3.05V      2.351V     3.417V
1.01ns    3.181V     2.35V      3.438V
1.313ns   3.267V     2.954V     3.462V
1.717ns   3.291V     3.109V     3.469V
10ns      3.3V       3.14V      3.47V
[Rising Waveform]
R_fixture=   50.0000
V_fixture=   0.0
V_fixture_min=   0.0
V_fixture_max=   0.0
|time   V(typ)   V(min)   V(max)
0s        1.288uV    1.554uV    1.323uV
505.1ps   26.26uV    1.514uV    -27.26mV
707.1ps   -14.34mV   18.68uV    1.008V
808.1ps   7.053mV    87.81uV    1.296V
1.01ns    669mV      -4.761mV   1.525V
1.212ns   924mV      -7.52mV    1.61V
1.313ns   979.6mV    165.4mV    1.631V
1.616ns   1.061V     651.6mV    1.659V
2.222ns   1.103V     795.2mV    1.668V
10ns      1.111V     827.7mV    1.67V
[Falling Waveform]
R_fixture=   50.0000
V_fixture=   0.0
V_fixture_min=   0.0
V_fixture_max=   0.0
|time   V(typ)   V(min)   V(max)
0s        1.111V     827.7mV    1.67V
505.1ps   1.111V     827.7mV    1.669V
606.1ps   1.111V     827.7mV    781.7mV
707.1ps   1.111V     827.7mV    249.6mV
808.1ps   1.008V     827.7mV    108.5mV
1.01ns    164.9mV    828.2mV    31.11mV
1.212ns   51.1mV     814.5mV    9.451mV
1.515ns   13.32mV    139.2mV    1.692mV
1.818ns   3.881mV    31.12mV    402.4uV
10ns      -16.78uV   26.97uV    -5.658uV
[Falling Waveform]
R_fixture=   50.0000
V_fixture=   3.3000
V_fixture_min=   3.1400
V_fixture_max=   3.4700
|time   V(typ)   V(min)   V(max)
0s        3.3V       3.14V      3.47V
505.1ps   3.3V       3.14V      3.472V
707.1ps   3.298V     3.14V      2.56V
808.1ps   3.311V     3.14V      2.332V
1.01ns    2.606V     3.141V     2.108V
1.313ns   2.296V     3.136V     1.991V
1.414ns   2.258V     2.89V      1.975V
1.717ns   2.199V     2.49V      1.952V
2.323ns   2.168V     2.38V      1.943V
10ns      2.162V     2.352V     1.942V
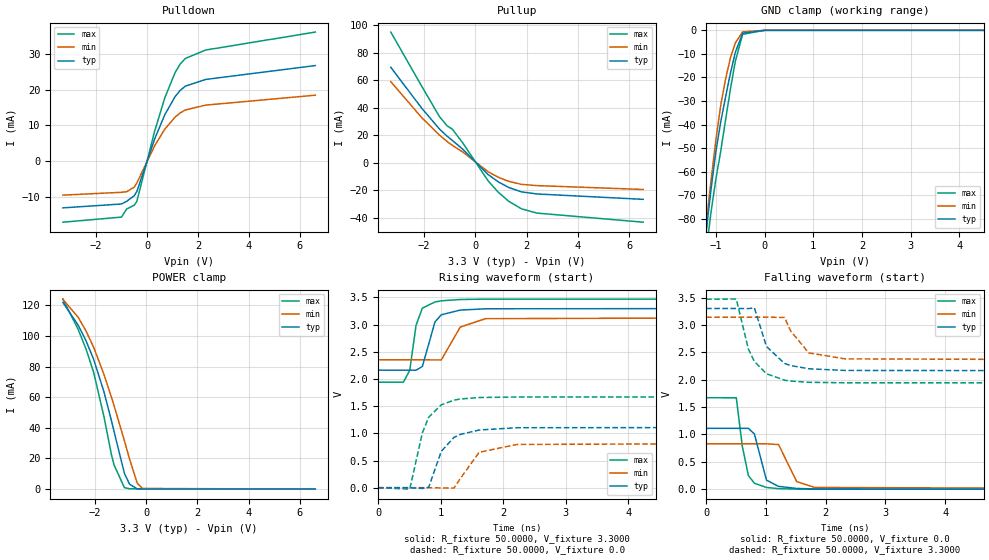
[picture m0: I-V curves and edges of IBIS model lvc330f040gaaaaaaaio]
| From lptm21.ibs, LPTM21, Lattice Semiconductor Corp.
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|   Model lvc330f040gaaaaaaaio
[Model]   lvc330f040gaaaaaaaio
Model_type   I/O
Polarity   Non-Inverting
Enable   Active-Low
Vinl =   0.8000V
Vinh =   2.0000V
Vmeas =   1.500000V
Cref =   0.0F
Rref =   1.0000M
Vref =   0.0V
C_comp   4.2000pF   3.8000pF   7.5000pF
[Temperature Range]   25.0000   0.1050k   -40.0000
[Voltage Range]   3.3000V   3.1400V   3.4700V
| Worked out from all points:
|   slope of the pulldown table from 0 to 0.495 V, typ, clamps not added: 50.7 ohm
|   slope of the pullup table from 0 to 0.495 V, typ, clamps not added: 58.2 ohm
|   GND clamp passes 1 mA (typ) near -0.43 V on its own axis
|   POWER clamp passes 1 mA (typ) near -0.53 V on its own axis
|   rising waveform, R_fixture 50.0000, V_fixture 3.3000: 20-80 % time 185ps typ, 254ps min, 147ps max; typ from 2.16 V to 3.3 V
|   rising waveform, R_fixture 50.0000, V_fixture 0.0: 20-80 % time 304ps typ, 324ps min, 246ps max; typ from 0 V to 1.11 V
|   falling waveform, R_fixture 50.0000, V_fixture 0.0: 20-80 % time 159ps typ, 213ps min, 148ps max; typ from 1.11 V to 0 V
|   falling waveform, R_fixture 50.0000, V_fixture 3.3000: 20-80 % time 297ps typ, 309ps min, 289ps max; typ from 3.3 V to 2.16 V
[Pulldown]
|Voltage   I(typ)   I(min)   I(max)
-3.3V     -13.02mA   -9.459mA   -17.02mA
-1V       -11.94mA   -8.676mA   -15.6mA
-800mV    -11.2mA    -8.504mA   -13.33mA
-500mV    -9.624mA   -7.225mA   -12.27mA
-400mV    -8.456mA   -6.081mA   -11.2mA
300mV     6.235mA    4.335mA    8.424mA
700mV     13.03mA    8.978mA    17.75mA
1.1V      18.03mA    12.33mA    24.74mA
1.3V      19.78mA    13.49mA    27.13mA
1.5V      20.96mA    14.31mA    28.69mA
2.3V      22.84mA    15.67mA    31.05mA
6.6V      26.71mA    18.44mA    36.06mA
[Pullup]
|Voltage   I(typ)   I(min)   I(max)
-3.3V     69.39mA    58.96mA    95.05mA
-2.1V     39.83mA    32.91mA    55.86mA
-1.4V     24.45mA    20.03mA    33.49mA
-1.1V     19.21mA    15.39mA    26.76mA
-900mV    16.22mA    12.62mA    24.4mA
-500mV    9.919mA    7.864mA    14.59mA
500mV     -8.684mA   -6.65mA    -13.28mA
900mV     -14.02mA   -10.66mA   -21.61mA
1.3V      -18.03mA   -13.59mA   -28.07mA
1.8V      -21.24mA   -15.77mA   -33.58mA
2.4V      -22.76mA   -16.68mA   -36.68mA
6.55V     -26.68mA   -19.5mA    -43.31mA
[GND_clamp]
|Voltage   I(typ)   I(min)   I(max)
-3.3V     -955.3mA   -930.3mA   -978mA
-1.2V     -86.21mA   -82.95mA   -94.94mA
-1.15V    -76.76mA   -73.31mA   -85.77mA
-1.1V     -67.73mA   -63.97mA   -77.32mA
-1V       -51.54mA   -46.59mA   -63.26mA
-900mV    -38.9mA    -31.9mA    -51.31mA
-800mV    -28.29mA   -20.61mA   -38.02mA
-700mV    -18.14mA   -11.66mA   -24.86mA
-600mV    -9.315mA   -5.302mA   -13.12mA
-450mV    -1.255mA   -637uA     -1.701mA
0V        0A         0A         0A
6.6V      0A         0A         0A
[POWER_clamp]
|Voltage   I(typ)   I(min)   I(max)
-3.25V    121.9mA    123.9mA    124.1mA
-2.65V    106.9mA    112.1mA    104.1mA
-2.35V    96.95mA    103.3mA    91.59mA
-2.05V    84.73mA    92.58mA    76.25mA
-1.65V    63.65mA    75mA       47.49mA
-1.35V    44.31mA    59.69mA    21.99mA
-1.25V    37.38mA    54.28mA    15.6mA
-850mV    10.32mA    31.58mA    939uA
-650mV    3.193mA    19.74mA    210uA
-350mV    132.1uA    3.862mA    199.7uA
-150mV    104.6uA    375.8uA    197.7uA
6.6V      -56.35nA   -1.463uA   -71.55uA
[Ramp]
| variable   typ   min   max
dV/dt_r  0.7027/0.3013n   0.4966/0.3205n   1.0018/0.2438n
dV/dt_f  0.6827/0.2942n   0.4730/0.3057n   0.9168/0.2859n
R_load = 50.0000
[Rising Waveform]
R_fixture=   50.0000
V_fixture=   3.3000
V_fixture_min=   3.1400
V_fixture_max=   3.4700
|time   V(typ)   V(min)   V(max)
0s        2.162V     2.352V     1.942V
404ps     2.162V     2.352V     1.942V
505.1ps   2.162V     2.352V     2.158V
606.1ps   2.161V     2.352V     2.988V
707.1ps   2.231V     2.352V     3.303V
909.1ps   3.05V      2.351V     3.417V
1.01ns    3.181V     2.35V      3.438V
1.313ns   3.267V     2.954V     3.462V
1.717ns   3.291V     3.109V     3.469V
10ns      3.3V       3.14V      3.47V
[Rising Waveform]
R_fixture=   50.0000
V_fixture=   0.0
V_fixture_min=   0.0
V_fixture_max=   0.0
|time   V(typ)   V(min)   V(max)
0s        1.288uV    1.554uV    1.323uV
505.1ps   26.26uV    1.514uV    -27.26mV
707.1ps   -14.34mV   18.68uV    1.008V
808.1ps   7.053mV    87.81uV    1.296V
1.01ns    669mV      -4.761mV   1.525V
1.212ns   924mV      -7.52mV    1.61V
1.313ns   979.6mV    165.4mV    1.631V
1.616ns   1.061V     651.6mV    1.659V
2.222ns   1.103V     795.2mV    1.668V
10ns      1.111V     827.7mV    1.67V
[Falling Waveform]
R_fixture=   50.0000
V_fixture=   0.0
V_fixture_min=   0.0
V_fixture_max=   0.0
|time   V(typ)   V(min)   V(max)
0s        1.111V     827.7mV    1.67V
505.1ps   1.111V     827.7mV    1.669V
606.1ps   1.111V     827.7mV    781.7mV
707.1ps   1.111V     827.7mV    249.6mV
808.1ps   1.008V     827.7mV    108.5mV
1.01ns    164.9mV    828.2mV    31.11mV
1.212ns   51.1mV     814.5mV    9.451mV
1.515ns   13.32mV    139.2mV    1.692mV
1.818ns   3.881mV    31.12mV    402.4uV
10ns      -16.78uV   26.97uV    -5.658uV
[Falling Waveform]
R_fixture=   50.0000
V_fixture=   3.3000
V_fixture_min=   3.1400
V_fixture_max=   3.4700
|time   V(typ)   V(min)   V(max)
0s        3.3V       3.14V      3.47V
505.1ps   3.3V       3.14V      3.472V
707.1ps   3.298V     3.14V      2.56V
808.1ps   3.311V     3.14V      2.332V
1.01ns    2.606V     3.141V     2.108V
1.313ns   2.296V     3.136V     1.991V
1.414ns   2.258V     2.89V      1.975V
1.717ns   2.199V     2.49V      1.952V
2.323ns   2.168V     2.38V      1.943V
10ns      2.162V     2.352V     1.942V
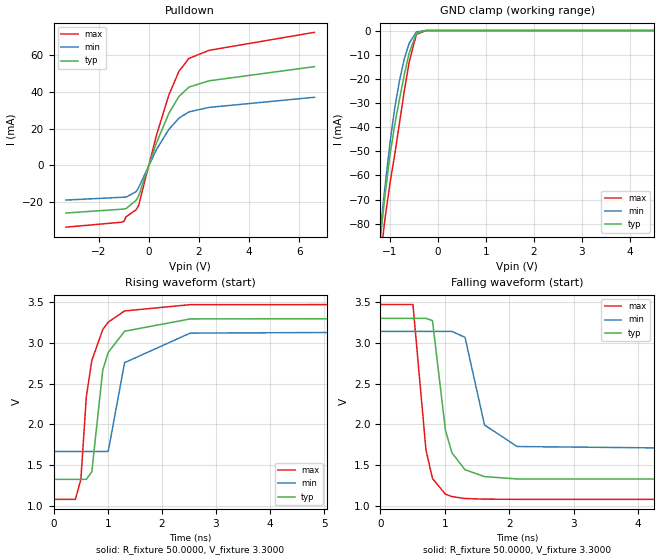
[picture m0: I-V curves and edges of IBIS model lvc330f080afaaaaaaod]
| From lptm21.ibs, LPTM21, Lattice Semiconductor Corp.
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|   Model lvc330f080afaaaaaaod
[Model]   lvc330f080afaaaaaaod
Model_type   I/O_open_drain
Polarity   Non-Inverting
Enable   Active-Low
Vinl =   0.8000V
Vinh =   2.0000V
Vmeas =   1.6500V
Cref =   0.0F
Rref =   1.0000M
Vref =   0.0V
C_comp   4.2000pF   3.8000pF   7.5000pF
[Temperature Range]   25.0000   0.1050k   -40.0000
[Voltage Range]   3.3000V   3.1400V   3.4700V
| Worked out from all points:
|   slope of the pulldown table from 0 to 0.495 V, typ, clamps not added: 26 ohm
|   GND clamp passes 1 mA (typ) near -0.44 V on its own axis
|   rising waveform, R_fixture 50.0000, V_fixture 3.3000: 20-80 % time 283ps typ, 291ps min, 267ps max; typ from 1.32 V to 3.3 V
|   falling waveform, R_fixture 50.0000, V_fixture 3.3000: 20-80 % time 229ps typ, 282ps min, 186ps max; typ from 3.3 V to 1.32 V
[Pulldown]
|Voltage   I(typ)   I(min)   I(max)
-3.3V     -25.87mA   -18.83mA   -33.56mA
-1.1V     -23.82mA   -17.33mA   -30.89mA
-1V       -23.72mA   -17.27mA   -30.52mA
-900mV    -23.42mA   -17.2mA    -27.86mA
-500mV    -18.89mA   -14.22mA   -24.07mA
-400mV    -16.44mA   -11.92mA   -21.58mA
300mV     12.11mA    8.499mA    16.2mA
800mV     28.3mA     19.6mA     38.33mA
1.2V      37.47mA    25.7mA     51.17mA
1.6V      42.61mA    29.13mA    58.23mA
2.4V      46.02mA    31.56mA    62.59mA
6.6V      53.73mA    37.07mA    72.39mA
[GND_clamp]
|Voltage   I(typ)   I(min)   I(max)
-3.3V     -955.3mA   -930.3mA   -978mA
-1.2V     -86.18mA   -82.93mA   -94.91mA
-1.15V    -76.73mA   -73.29mA   -85.74mA
-1.1V     -67.71mA   -63.95mA   -77.28mA
-1V       -51.52mA   -46.57mA   -63.21mA
-900mV    -38.87mA   -31.88mA   -51.26mA
-800mV    -28.25mA   -20.58mA   -37.97mA
-700mV    -18.1mA    -11.63mA   -24.81mA
-600mV    -9.267mA   -5.265mA   -13.06mA
-450mV    -1.181mA   -586.6uA   -1.592mA
-250mV    -3.532uA   -4.055uA   -3.003uA
6.6V      0A         0A         0A
[Ramp]
| variable   typ   min   max
dV/dt_r  1.1855/0.2807n   0.8843/0.2882n   1.4345/0.2646n
dV/dt_f  1.1855/0.2263n   0.8837/0.2462n   1.4345/0.1846n
R_load = 50.0000
[Rising Waveform]
R_fixture=   50.0000
V_fixture=   3.3000
V_fixture_min=   3.1400
V_fixture_max=   3.4700
|time   V(typ)   V(min)   V(max)
0s        1.324V     1.666V     1.079V
404ps     1.324V     1.666V     1.079V
505.1ps   1.324V     1.666V     1.323V
606.1ps   1.324V     1.666V     2.34V
707.1ps   1.416V     1.666V     2.782V
909.1ps   2.664V     1.666V     3.161V
1.01ns    2.881V     1.667V     3.253V
1.313ns   3.142V     2.756V     3.391V
2.525ns   3.293V     3.119V     3.468V
10ns      3.3V       3.14V      3.47V
[Falling Waveform]
R_fixture=   50.0000
V_fixture=   3.3000
V_fixture_min=   3.1400
V_fixture_max=   3.4700
|time   V(typ)   V(min)   V(max)
0s        3.3V       3.14V      3.47V
505.1ps   3.3V       3.14V      3.47V
707.1ps   3.3V       3.14V      1.684V
808.1ps   3.272V     3.14V      1.335V
1.01ns    1.924V     3.14V      1.141V
1.111ns   1.649V     3.14V      1.113V
1.313ns   1.442V     3.067V     1.089V
1.616ns   1.358V     1.991V     1.081V
2.121ns   1.329V     1.727V     1.079V
10ns      1.324V     1.666V     1.079V
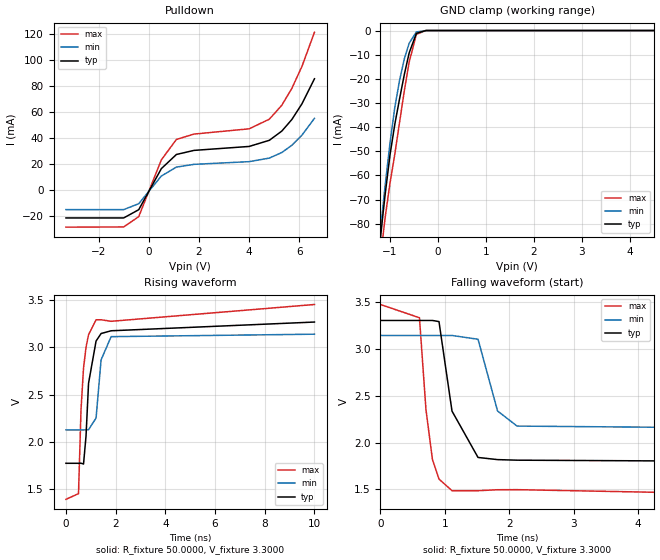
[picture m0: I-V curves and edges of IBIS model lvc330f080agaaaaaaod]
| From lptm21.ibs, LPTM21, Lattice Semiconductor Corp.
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|   Model lvc330f080agaaaaaaod
[Model]   lvc330f080agaaaaaaod
Model_type   I/O_open_drain
Polarity   Non-Inverting
Enable   Active-Low
Vinl =   0.8000V
Vinh =   2.0000V
Vmeas =   1.6500V
Cref =   0.0F
Rref =   1.0000M
Vref =   0.0V
C_comp   4.2000pF   3.8000pF   7.5000pF
[Temperature Range]   25.0000   0.1050k   -40.0000
[Voltage Range]   3.3000V   3.1400V   3.4700V
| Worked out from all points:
|   slope of the pulldown table from 0 to 0.495 V, typ, clamps not added: 30.2 ohm
|   GND clamp passes 1 mA (typ) near -0.44 V on its own axis
|   rising waveform, R_fixture 50.0000, V_fixture 3.3000: 20-80 % time 282ps typ, 232ps min, 294ps max; typ from 1.77 V to 3.26 V
|   falling waveform, R_fixture 50.0000, V_fixture 3.3000: 20-80 % time 218ps typ, 241ps min, 178ps max; typ from 3.3 V to 1.78 V
[Pulldown]
|Voltage   I(typ)   I(min)   I(max)
-3.3V     -21.41mA   -15mA      -28.5mA
-1V       -21.41mA   -15mA      -28.34mA
-400mV    -15.06mA   -10.45mA   -20.4mA
500mV     16.52mA    10.84mA    23.27mA
1.1V      27.41mA    17.71mA    38.96mA
1.8V      30.56mA    19.82mA    43.12mA
4V        33.61mA    21.9mA     47.17mA
4.8V      38.3mA     24.63mA    54.54mA
5.3V      45.42mA    28.93mA    65.29mA
5.7V      54.35mA    34.52mA    78.25mA
6.1V      66.32mA    42.26mA    95.09mA
6.6V      85.66mA    55.2mA     121.4mA
[GND_clamp]
|Voltage   I(typ)   I(min)   I(max)
-3.3V     -955.3mA   -930.3mA   -978mA
-1.2V     -86.17mA   -82.92mA   -94.88mA
-1.15V    -76.72mA   -73.28mA   -85.71mA
-1.1V     -67.69mA   -63.94mA   -77.25mA
-1V       -51.5mA    -46.56mA   -63.19mA
-900mV    -38.85mA   -31.87mA   -51.24mA
-800mV    -28.24mA   -20.57mA   -37.95mA
-700mV    -18.09mA   -11.63mA   -24.79mA
-600mV    -9.258mA   -5.26mA    -13.05mA
-450mV    -1.178mA   -585.4uA   -1.585mA
-250mV    -3.51uA    -4.042uA   -2.972uA
6.6V      0A         0A         0A
[Ramp]
| variable   typ   min   max
dV/dt_r  0.8936/0.2791n   0.5743/0.2655n   1.2327/0.2906n
dV/dt_f  0.9093/0.2162n   0.6061/0.2384n   1.2452/0.1757n
R_load = 50.0000
[Rising Waveform]
R_fixture=   50.0000
V_fixture=   3.3000
V_fixture_min=   3.1400
V_fixture_max=   3.4700
|time   V(typ)   V(min)   V(max)
0s        1.775V     2.127V     1.395V
505.1ps   1.775V     2.127V     1.455V
606.1ps   1.776V     2.127V     2.339V
707.1ps   1.767V     2.127V     2.777V
808.1ps   2.063V     2.128V     2.998V
909.1ps   2.618V     2.129V     3.13V
1.212ns   3.064V     2.252V     3.288V
1.414ns   3.143V     2.866V     3.288V
1.818ns   3.172V     3.11V      3.272V
10ns      3.264V     3.136V     3.449V
[Falling Waveform]
R_fixture=   50.0000
V_fixture=   3.3000
V_fixture_min=   3.1400
V_fixture_max=   3.4700
|time   V(typ)   V(min)   V(max)
0s        3.3V       3.14V      3.47V
606.1ps   3.3V       3.14V      3.329V
707.1ps   3.3V       3.14V      2.35V
808.1ps   3.3V       3.14V      1.817V
909.1ps   3.288V     3.14V      1.611V
1.111ns   2.335V     3.14V      1.487V
1.515ns   1.841V     3.1V       1.487V
1.818ns   1.818V     2.336V     1.497V
2.121ns   1.812V     2.175V     1.498V
10ns      1.784V     2.13V      1.395V
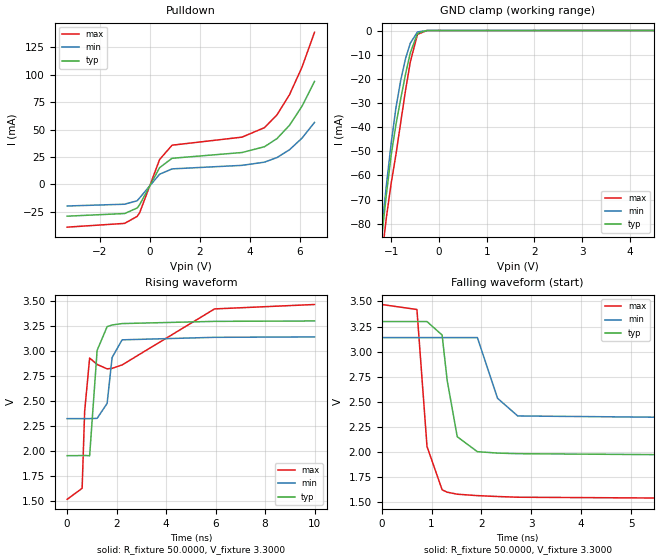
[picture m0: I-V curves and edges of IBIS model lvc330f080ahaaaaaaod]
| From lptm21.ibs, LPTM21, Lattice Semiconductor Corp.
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|   Model lvc330f080ahaaaaaaod
[Model]   lvc330f080ahaaaaaaod
Model_type   I/O_open_drain
Polarity   Non-Inverting
Enable   Active-Low
Vinl =   0.8000V
Vinh =   2.0000V
Vmeas =   1.6500V
Cref =   0.0F
Rref =   1.0000M
Vref =   0.0V
C_comp   4.2000pF   3.8000pF   7.5000pF
[Temperature Range]   25.0000   0.1050k   -40.0000
[Voltage Range]   3.3000V   3.1400V   3.4700V
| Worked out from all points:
|   slope of the pulldown table from 0 to 0.495 V, typ, clamps not added: 27.9 ohm
|   GND clamp passes 1 mA (typ) near -0.44 V on its own axis
|   rising waveform, R_fixture 50.0000, V_fixture 3.3000: 20-80 % time 228ps typ, 244ps min, 3.54ns max; typ from 1.96 V to 3.3 V
|   falling waveform, R_fixture 50.0000, V_fixture 3.3000: 20-80 % time 232ps typ, 280ps min, 208ps max; typ from 3.3 V to 1.96 V
[Pulldown]
|Voltage   I(typ)   I(min)   I(max)
-3.3V     -28.96mA   -19.69mA   -38.97mA
-1V       -26.56mA   -18.06mA   -35.54mA
-500mV    -21.55mA   -14.92mA   -29.2mA
-400mV    -18.59mA   -12.35mA   -25.94mA
400mV     15.25mA    9.284mA    22.67mA
900mV     23.8mA     14.14mA    35.73mA
3.7V      29.06mA    17.36mA    43.08mA
4.6V      34.35mA    20.28mA    51.74mA
5.1V      41.78mA    24.48mA    63.44mA
5.6V      53.92mA    31.6mA     81.78mA
6.1V      71.24mA    42.17mA    106.9mA
6.6V      93.87mA    56.49mA    138.6mA
[GND_clamp]
|Voltage   I(typ)   I(min)   I(max)
-3.3V     -955.3mA   -930.3mA   -978mA
-1.2V     -86.16mA   -82.91mA   -94.88mA
-1.15V    -76.71mA   -73.27mA   -85.71mA
-1.1V     -67.69mA   -63.93mA   -77.25mA
-1V       -51.49mA   -46.56mA   -63.18mA
-900mV    -38.84mA   -31.87mA   -51.23mA
-800mV    -28.23mA   -20.57mA   -37.94mA
-700mV    -18.08mA   -11.62mA   -24.79mA
-600mV    -9.254mA   -5.257mA   -13.04mA
-450mV    -1.176mA   -584.6uA   -1.582mA
-250mV    -3.498uA   -4.034uA   -2.958uA
6.6V      0A         0A         0A
[Ramp]
| variable   typ   min   max
dV/dt_r  0.8051/0.2254n   0.4880/0.2412n   1.1650/3.5016n
dV/dt_f  0.8051/0.2292n   0.4881/0.2769n   1.1649/0.2056n
R_load = 50.0000
[Rising Waveform]
R_fixture=   50.0000
V_fixture=   3.3000
V_fixture_min=   3.1400
V_fixture_max=   3.4700
|time   V(typ)   V(min)   V(max)
0s        1.956V     2.325V     1.521V
606.1ps   1.957V     2.325V     1.631V
707.1ps   1.958V     2.325V     2.395V
909.1ps   1.955V     2.325V     2.929V
1.212ns   3.005V     2.328V     2.865V
1.616ns   3.241V     2.477V     2.821V
1.818ns   3.258V     2.934V     2.826V
2.222ns   3.272V     3.11V      2.86V
5.96ns    3.294V     3.135V     3.418V
10ns      3.298V     3.139V     3.462V
[Falling Waveform]
R_fixture=   50.0000
V_fixture=   3.3000
V_fixture_min=   3.1400
V_fixture_max=   3.4700
|time   V(typ)   V(min)   V(max)
0s        3.3V       3.14V      3.47V
707.1ps   3.3V       3.14V      3.42V
909.1ps   3.3V       3.14V      2.055V
1.212ns   3.165V     3.14V      1.623V
1.313ns   2.715V     3.14V      1.599V
1.515ns   2.152V     3.14V      1.579V
1.919ns   2.003V     3.14V      1.565V
2.323ns   1.989V     2.535V     1.556V
2.727ns   1.983V     2.359V     1.549V
10ns      1.958V     2.326V     1.528V
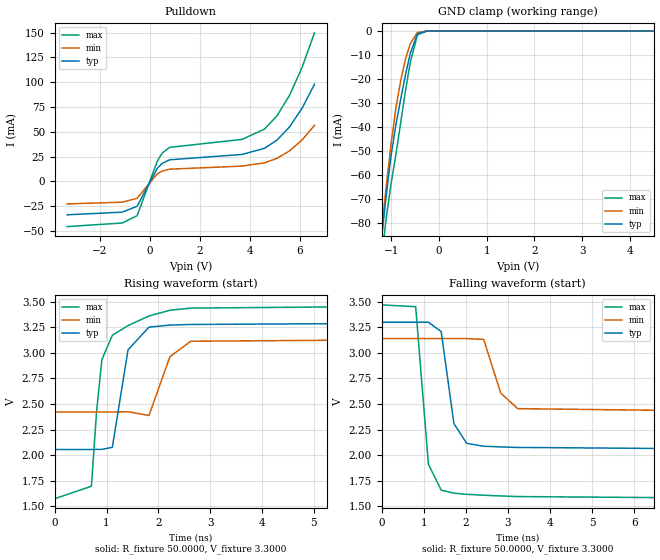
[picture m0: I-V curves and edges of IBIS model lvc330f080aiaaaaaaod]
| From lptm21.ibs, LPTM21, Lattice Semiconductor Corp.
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|   Model lvc330f080aiaaaaaaod
[Model]   lvc330f080aiaaaaaaod
Model_type   I/O_open_drain
Polarity   Non-Inverting
Enable   Active-Low
Vinl =   0.8000V
Vinh =   2.0000V
Vmeas =   1.6500V
Cref =   0.0F
Rref =   1.0000M
Vref =   0.0V
C_comp   4.2000pF   3.8000pF   7.5000pF
[Temperature Range]   25.0000   0.1050k   -40.0000
[Voltage Range]   3.3000V   3.1400V   3.4700V
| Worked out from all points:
|   slope of the pulldown table from 0 to 0.495 V, typ, clamps not added: 27.4 ohm
|   GND clamp passes 1 mA (typ) near -0.44 V on its own axis
|   rising waveform, R_fixture 50.0000, V_fixture 3.3000: 20-80 % time 239ps typ, 268ps min, 258ps max; typ from 2.06 V to 3.3 V
|   falling waveform, R_fixture 50.0000, V_fixture 3.3000: 20-80 % time 255ps typ, 316ps min, 216ps max; typ from 3.3 V to 2.06 V
[Pulldown]
|Voltage   I(typ)   I(min)   I(max)
-3.3V     -33.62mA   -22.67mA   -45.49mA
-1.1V     -30.96mA   -20.88mA   -41.89mA
-500mV    -25.06mA   -17.08mA   -34.54mA
300mV     12.9mA     7.574mA    19.85mA
500mV     18.2mA     10.47mA    28.45mA
800mV     21.8mA     12.34mA    34.32mA
3.7V      27.17mA    15.44mA    42.34mA
4.6V      33.38mA    18.74mA    52.76mA
5.1V      41.66mA    23.27mA    66.16mA
5.6V      54.9mA     30.75mA    86.72mA
6.1V      73.59mA    41.72mA    114.7mA
6.6V      97.9mA     56.51mA    149.7mA
[GND_clamp]
|Voltage   I(typ)   I(min)   I(max)
-3.3V     -955.3mA   -930.3mA   -978mA
-1.2V     -86.15mA   -82.88mA   -94.87mA
-1.15V    -76.7mA    -73.24mA   -85.7mA
-1.1V     -67.68mA   -63.91mA   -77.24mA
-1V       -51.49mA   -46.55mA   -63.18mA
-900mV    -38.84mA   -31.86mA   -51.23mA
-800mV    -28.23mA   -20.57mA   -37.94mA
-700mV    -18.08mA   -11.62mA   -24.78mA
-600mV    -9.252mA   -5.256mA   -13.04mA
-450mV    -1.175mA   -584.3uA   -1.581mA
-250mV    -3.493uA   -4.031uA   -2.954uA
6.6V      0A         0A         0A
[Ramp]
| variable   typ   min   max
dV/dt_r  0.7460/0.2370n   0.4303/0.2653n   1.1363/0.2551n
dV/dt_f  0.7461/0.2521n   0.4302/0.3124n   1.1365/0.2140n
R_load = 50.0000
[Rising Waveform]
R_fixture=   50.0000
V_fixture=   3.3000
V_fixture_min=   3.1400
V_fixture_max=   3.4700
|time   V(typ)   V(min)   V(max)
0s        2.055V     2.421V     1.574V
707.1ps   2.055V     2.421V     1.696V
808.1ps   2.056V     2.421V     2.435V
909.1ps   2.056V     2.421V     2.933V
1.111ns   2.076V     2.421V     3.171V
1.414ns   3.029V     2.424V     3.266V
1.818ns   3.251V     2.387V     3.36V
2.222ns   3.271V     2.962V     3.416V
2.626ns   3.277V     3.113V     3.437V
10ns      3.298V     3.139V     3.468V
[Falling Waveform]
R_fixture=   50.0000
V_fixture=   3.3000
V_fixture_min=   3.1400
V_fixture_max=   3.4700
|time   V(typ)   V(min)   V(max)
0s        3.3V       3.14V      3.469V
808.1ps   3.3V       3.14V      3.452V
1.111ns   3.3V       3.14V      1.912V
1.414ns   3.208V     3.14V      1.659V
1.717ns   2.309V     3.14V      1.629V
2.02ns    2.116V     3.14V      1.618V
2.424ns   2.088V     3.132V     1.609V
2.828ns   2.081V     2.608V     1.602V
3.232ns   2.076V     2.455V     1.596V
10ns      2.056V     2.423V     1.575V
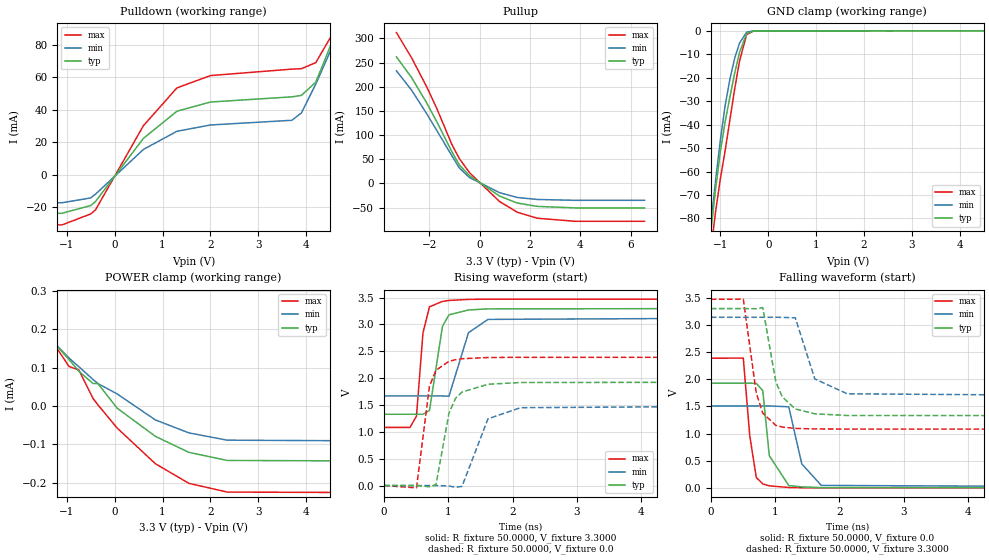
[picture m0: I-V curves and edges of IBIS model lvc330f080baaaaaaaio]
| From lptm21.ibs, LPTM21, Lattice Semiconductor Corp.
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|   Model lvc330f080baaaaaaaio
[Model]   lvc330f080baaaaaaaio
Model_type   I/O
Polarity   Non-Inverting
Enable   Active-Low
Vinl =   0.8000V
Vinh =   2.0000V
Vmeas =   1.500000V
Cref =   0.0F
Rref =   1.0000M
Vref =   0.0V
C_comp   4.2000pF   3.8000pF   7.5000pF
[Temperature Range]   25.0000   0.1050k   -40.0000
[Voltage Range]   3.3000V   3.1400V   3.4700V
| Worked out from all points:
|   slope of the pulldown table from 0 to 0.495 V, typ, clamps not added: 26 ohm
|   slope of the pullup table from 0 to 0.495 V, typ, clamps not added: 28.5 ohm
|   GND clamp passes 1 mA (typ) near -0.44 V on its own axis
|   rising waveform, R_fixture 50.0000, V_fixture 3.3000: 20-80 % time 154ps typ, 210ps min, 114ps max; typ from 1.33 V to 3.3 V
|   rising waveform, R_fixture 50.0000, V_fixture 0.0: 20-80 % time 223ps typ, 283ps min, 159ps max; typ from 0.002 V to 1.93 V
|   falling waveform, R_fixture 50.0000, V_fixture 0.0: 20-80 % time 129ps typ, 176ps min, 130ps max; typ from 1.93 V to 0.002 V
|   falling waveform, R_fixture 50.0000, V_fixture 3.3000: 20-80 % time 229ps typ, 281ps min, 189ps max; typ from 3.3 V to 1.33 V
[Pulldown]
|Voltage   I(typ)   I(min)   I(max)
-3.3V     -23.68mA   -17.2mA    -30.83mA
-1.1V     -23.68mA   -17.2mA    -30.83mA
-500mV    -18.9mA    -14.22mA   -24.09mA
-400mV    -16.44mA   -11.91mA   -21.57mA
600mV     22.44mA    15.62mA    30.24mA
1.3V      39.15mA    26.81mA    53.52mA
2V        44.82mA    30.69mA    61.1mA
3.7V      48.01mA    33.58mA    65.08mA
3.9V      48.91mA    38.12mA    65.34mA
4.2V      57.06mA    55.89mA    69.08mA
4.6V      86.16mA    82.52mA    89.35mA
6.6V      243.1mA    215mA      281.8mA
[Pullup]
|Voltage   I(typ)   I(min)   I(max)
-3.3V     261.7mA    232.8mA    311.9mA
-2.7V     219.1mA    193.2mA    260.1mA
-2.1V     166.7mA    144.4mA    200mA
-1.7V     127.9mA    109.9mA    155.5mA
-1.1V     65.78mA    57.35mA    80.82mA
-800mV    38.2mA     32.09mA    51.33mA
-400mV    16.19mA    12.24mA    22.44mA
800mV     -26.1mA    -19.07mA   -37.51mA
1.5V      -40.42mA   -28.93mA   -59.41mA
2.3V      -47.34mA   -33.02mA   -71.87mA
3.8V      -50.4mA    -34.76mA   -78.12mA
6.55V     -50.4mA    -34.76mA   -78.12mA
[GND_clamp]
|Voltage   I(typ)   I(min)   I(max)
-3.3V     -955.2mA   -930.2mA   -977.8mA
-1.2V     -86.07mA   -82.87mA   -94.72mA
-1.15V    -76.63mA   -73.23mA   -85.56mA
-1.1V     -67.6mA    -63.89mA   -77.1mA
-1V       -51.41mA   -46.51mA   -63.05mA
-900mV    -38.77mA   -31.83mA   -51.09mA
-800mV    -28.16mA   -20.53mA   -37.81mA
-700mV    -18.01mA   -11.59mA   -24.66mA
-600mV    -9.192mA   -5.229mA   -12.92mA
-450mV    -1.151mA   -576.6uA   -1.527mA
-300mV    -17.4uA    -15.66uA   -11.6uA
6.6V      0A         0A         0A
[POWER_clamp]
|Voltage   I(typ)   I(min)   I(max)
-3.25V    961.3uA    1.05mA     917.9uA
-2.25V    305.8uA    299.5uA    344.1uA
-1.95V    260.5uA    253.4uA    288.8uA
-950mV    120.7uA    124.7uA    102.8uA
-750mV    90.82uA    102.7uA    94.17uA
-450mV    58.57uA    68.87uA    19.46uA
-350mV    58.57uA    58.54uA    3.121uA
50mV      -5.338uA   31.71uA    -57.16uA
850mV     -79.07uA   -36.24uA   -150.4uA
1.55V     -120.8uA   -70.05uA   -201.6uA
2.35V     -141.9uA   -89.06uA   -224.3uA
6.6V      -143.8uA   -91.66uA   -226.3uA
[Ramp]
| variable   typ   min   max
dV/dt_r  1.1547/0.2203n   0.9042/0.2800n   1.4307/0.1573n
dV/dt_f  1.1831/0.2265n   0.8824/0.2777n   1.4320/0.1869n
R_load = 50.0000
[Rising Waveform]
R_fixture=   50.0000
V_fixture=   3.3000
V_fixture_min=   3.1400
V_fixture_max=   3.4700
|time   V(typ)   V(min)   V(max)
0s        1.328V     1.669V     1.083V
404ps     1.328V     1.669V     1.083V
505.1ps   1.328V     1.669V     1.295V
606.1ps   1.327V     1.669V     2.845V
707.1ps   1.399V     1.669V     3.328V
909.1ps   2.965V     1.668V     3.427V
1.01ns    3.178V     1.665V     3.445V
1.313ns   3.268V     2.845V     3.465V
1.616ns   3.289V     3.093V     3.469V
10ns      3.3V       3.14V      3.47V
[Rising Waveform]
R_fixture=   50.0000
V_fixture=   0.0
V_fixture_min=   0.0
V_fixture_max=   0.0
|time   V(typ)   V(min)   V(max)
0s        2.075mV    1.701mV    2.581mV
505.1ps   2.09mV     1.701mV    -41.36mV
707.1ps   -21.05mV   1.72mV     1.852V
808.1ps   18.01mV    1.757mV    2.146V
1.01ns    1.35V      -5.938mV   2.314V
1.111ns   1.623V     -29.75mV   2.343V
1.212ns   1.741V     -14.75mV   2.361V
1.616ns   1.886V     1.243V     2.384V
2.121ns   1.919V     1.45V      2.387V
10ns      1.927V     1.509V     2.387V
[Falling Waveform]
R_fixture=   50.0000
V_fixture=   0.0
V_fixture_min=   0.0
V_fixture_max=   0.0
|time   V(typ)   V(min)   V(max)
0s        1.927V     1.509V     2.387V
505.1ps   1.927V     1.509V     2.389V
606.1ps   1.927V     1.509V     956.4mV
707.1ps   1.925V     1.509V     192.3mV
808.1ps   1.789V     1.509V     74.98mV
909.1ps   594.5mV    1.509V     39.04mV
1.212ns   43.91mV    1.493V     8.2mV
1.414ns   19.32mV    442.5mV    4.165mV
1.717ns   6.764mV    47.17mV    2.906mV
10ns      2.087mV    1.704mV    2.585mV
[Falling Waveform]
R_fixture=   50.0000
V_fixture=   3.3000
V_fixture_min=   3.1400
V_fixture_max=   3.4700
|time   V(typ)   V(min)   V(max)
0s        3.3V       3.14V      3.47V
505.1ps   3.3V       3.14V      3.474V
707.1ps   3.297V     3.14V      1.746V
808.1ps   3.318V     3.14V      1.374V
1.01ns    1.956V     3.141V     1.153V
1.111ns   1.675V     3.138V     1.12V
1.313ns   1.453V     3.13V      1.095V
1.616ns   1.364V     2.007V     1.086V
2.121ns   1.333V     1.732V     1.083V
10ns      1.328V     1.669V     1.083V
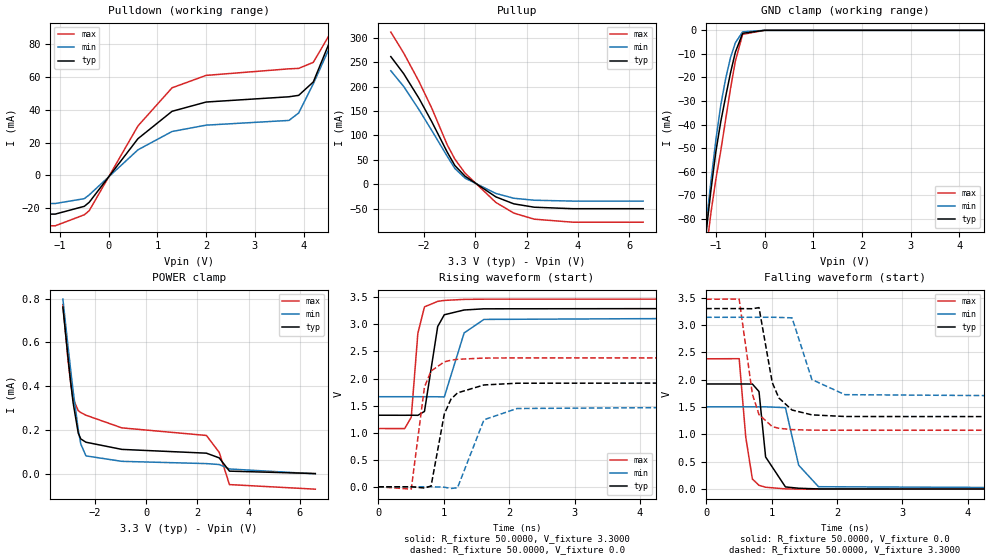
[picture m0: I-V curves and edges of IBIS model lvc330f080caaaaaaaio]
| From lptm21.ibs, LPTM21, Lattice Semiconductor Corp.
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|   Model lvc330f080caaaaaaaio
[Model]   lvc330f080caaaaaaaio
Model_type   I/O
Polarity   Non-Inverting
Enable   Active-Low
Vinl =   0.8000V
Vinh =   2.0000V
Vmeas =   1.500000V
Cref =   0.0F
Rref =   1.0000M
Vref =   0.0V
C_comp   4.2000pF   3.8000pF   7.5000pF
[Temperature Range]   25.0000   0.1050k   -40.0000
[Voltage Range]   3.3000V   3.1400V   3.4700V
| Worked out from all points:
|   slope of the pulldown table from 0 to 0.495 V, typ, clamps not added: 26 ohm
|   slope of the pullup table from 0 to 0.495 V, typ, clamps not added: 28.5 ohm
|   GND clamp passes 1 mA (typ) near -0.43 V on its own axis
|   rising waveform, R_fixture 50.0000, V_fixture 3.3000: 20-80 % time 154ps typ, 210ps min, 115ps max; typ from 1.32 V to 3.3 V
|   rising waveform, R_fixture 50.0000, V_fixture 0.0: 20-80 % time 223ps typ, 283ps min, 159ps max; typ from 0 V to 1.92 V
|   falling waveform, R_fixture 50.0000, V_fixture 0.0: 20-80 % time 129ps typ, 176ps min, 130ps max; typ from 1.92 V to 0 V
|   falling waveform, R_fixture 50.0000, V_fixture 3.3000: 20-80 % time 228ps typ, 280ps min, 188ps max; typ from 3.3 V to 1.32 V
[Pulldown]
|Voltage   I(typ)   I(min)   I(max)
-3.3V     -23.68mA   -17.2mA    -30.83mA
-1.1V     -23.68mA   -17.2mA    -30.83mA
-500mV    -18.9mA    -14.22mA   -24.08mA
-400mV    -16.43mA   -11.91mA   -21.57mA
600mV     22.42mA    15.62mA    30.2mA
1.3V      39.15mA    26.81mA    53.51mA
2V        44.82mA    30.69mA    61.1mA
3.7V      48.03mA    33.58mA    65.1mA
3.9V      48.9mA     38.13mA    65.38mA
4.2V      57.08mA    55.91mA    69.06mA
4.6V      86.22mA    82.52mA    89.41mA
6.6V      243.1mA    214.7mA    281.9mA
[Pullup]
|Voltage   I(typ)   I(min)   I(max)
-3.3V     261.7mA    232.6mA    312mA
-2.8V     226.8mA    200.6mA    269.2mA
-2.2V     176mA      152.8mA    210.6mA
-1.7V     128mA      109.9mA    155.7mA
-1.1V     65.83mA    57.37mA    80.87mA
-800mV    38.21mA    32.1mA     51.32mA
-400mV    16.19mA    12.24mA    22.44mA
800mV     -26.12mA   -19.07mA   -37.54mA
1.5V      -40.43mA   -28.94mA   -59.43mA
2.3V      -47.34mA   -33.02mA   -71.88mA
3.8V      -50.37mA   -34.75mA   -78.05mA
6.55V     -50.37mA   -34.75mA   -78.05mA
[GND_clamp]
|Voltage   I(typ)   I(min)   I(max)
-3.3V     -955.3mA   -930.3mA   -978mA
-1.2V     -86.21mA   -82.95mA   -94.94mA
-1.15V    -76.76mA   -73.31mA   -85.77mA
-1.1V     -67.73mA   -63.97mA   -77.32mA
-1V       -51.54mA   -46.59mA   -63.26mA
-900mV    -38.9mA    -31.9mA    -51.31mA
-800mV    -28.29mA   -20.61mA   -38.02mA
-700mV    -18.14mA   -11.66mA   -24.86mA
-600mV    -9.315mA   -5.302mA   -13.12mA
-450mV    -1.255mA   -637uA     -1.701mA
0V        0A         0A         0A
6.6V      0A         0A         0A
[POWER_clamp]
|Voltage   I(typ)   I(min)   I(max)
-3.25V    761uA      797.6uA    771.5uA
-3.05V    529.8uA    580.8uA    518.2uA
-2.95V    421.6uA    477.3uA    415.1uA
-2.85V    322.5uA    377.6uA    342uA
-2.65V    184.2uA    200uA      287.1uA
-2.55V    157.9uA    134.1uA    278.6uA
-2.35V    143.1uA    80.64uA    266.6uA
-950mV    110.3uA    55.66uA    208.7uA
2.35V     93.03uA    45.33uA    174uA
2.85V     71.52uA    41.08uA    96.73uA
3.25V     10.85uA    20.74uA    -50.58uA
6.6V      -56.35nA   -1.463uA   -71.55uA
[Ramp]
| variable   typ   min   max
dV/dt_r  1.1527/0.2207n   0.9025/0.2802n   1.4288/0.1579n
dV/dt_f  1.1861/0.2256n   0.8848/0.2770n   1.4351/0.1858n
R_load = 50.0000
[Rising Waveform]
R_fixture=   50.0000
V_fixture=   3.3000
V_fixture_min=   3.1400
V_fixture_max=   3.4700
|time   V(typ)   V(min)   V(max)
0s        1.322V     1.664V     1.076V
404ps     1.321V     1.664V     1.075V
505.1ps   1.322V     1.664V     1.284V
606.1ps   1.32V      1.664V     2.837V
707.1ps   1.392V     1.664V     3.324V
909.1ps   2.961V     1.663V     3.425V
1.01ns    3.178V     1.659V     3.443V
1.313ns   3.266V     2.842V     3.462V
1.616ns   3.288V     3.092V     3.466V
10ns      3.298V     3.139V     3.468V
[Rising Waveform]
R_fixture=   50.0000
V_fixture=   0.0
V_fixture_min=   0.0
V_fixture_max=   0.0
|time   V(typ)   V(min)   V(max)
0s        810.2nV    1.051uV    780.3nV
505.1ps   15.26uV    894.5nV    -44.19mV
707.1ps   -23.16mV   20.03uV    1.844V
808.1ps   14.52mV    57.24uV    2.139V
1.01ns    1.343V     -7.634mV   2.308V
1.111ns   1.617V     -31.65mV   2.338V
1.212ns   1.735V     -17.48mV   2.355V
1.616ns   1.881V     1.238V     2.378V
2.121ns   1.913V     1.446V     2.381V
10ns      1.921V     1.504V     2.381V
[Falling Waveform]
R_fixture=   50.0000
V_fixture=   0.0
V_fixture_min=   0.0
V_fixture_max=   0.0
|time   V(typ)   V(min)   V(max)
0s        1.921V     1.504V     2.381V
505.1ps   1.921V     1.504V     2.383V
606.1ps   1.921V     1.504V     947.4mV
707.1ps   1.92V      1.504V     185.7mV
808.1ps   1.783V     1.504V     70.3mV
909.1ps   588mV      1.504V     35.33mV
1.212ns   40.99mV    1.489V     5.341mV
1.414ns   16.89mV    438mV      1.511mV
1.717ns   4.504mV    44.86mV    315.6uV
10ns      4.728uV    13.46uV    -1.503uV
[Falling Waveform]
R_fixture=   50.0000
V_fixture=   3.3000
V_fixture_min=   3.1400
V_fixture_max=   3.4700
|time   V(typ)   V(min)   V(max)
0s        3.298V     3.139V     3.468V
505.1ps   3.298V     3.139V     3.472V
707.1ps   3.295V     3.139V     1.736V
808.1ps   3.316V     3.139V     1.362V
1.01ns    1.949V     3.14V      1.142V
1.111ns   1.667V     3.137V     1.112V
1.313ns   1.445V     3.129V     1.088V
1.616ns   1.357V     2.002V     1.078V
2.121ns   1.327V     1.726V     1.076V
10ns      1.322V     1.664V     1.076V
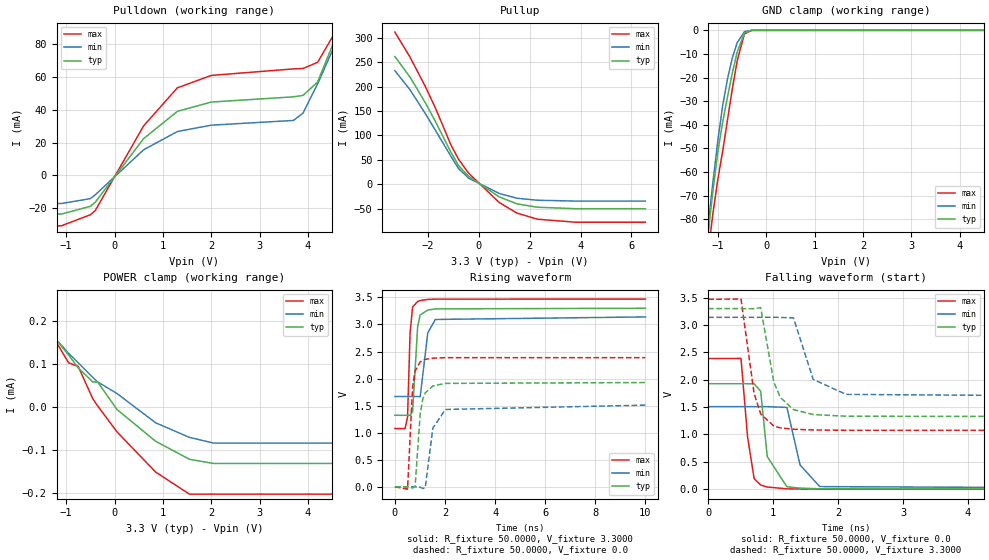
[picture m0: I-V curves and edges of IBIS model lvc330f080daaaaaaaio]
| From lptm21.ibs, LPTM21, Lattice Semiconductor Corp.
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|   Model lvc330f080daaaaaaaio
[Model]   lvc330f080daaaaaaaio
Model_type   I/O
Polarity   Non-Inverting
Enable   Active-Low
Vinl =   0.8000V
Vinh =   2.0000V
Vmeas =   1.500000V
Cref =   0.0F
Rref =   1.0000M
Vref =   0.0V
C_comp   4.2000pF   3.8000pF   7.5000pF
[Temperature Range]   25.0000   0.1050k   -40.0000
[Voltage Range]   3.3000V   3.1400V   3.4700V
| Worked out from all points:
|   slope of the pulldown table from 0 to 0.495 V, typ, clamps not added: 26 ohm
|   slope of the pullup table from 0 to 0.495 V, typ, clamps not added: 28.5 ohm
|   GND clamp passes 1 mA (typ) near -0.44 V on its own axis
|   rising waveform, R_fixture 50.0000, V_fixture 3.3000: 20-80 % time 154ps typ, 210ps min, 115ps max; typ from 1.32 V to 3.3 V
|   rising waveform, R_fixture 50.0000, V_fixture 0.0: 20-80 % time 224ps typ, 285ps min, 161ps max; typ from 0 V to 1.93 V
|   falling waveform, R_fixture 50.0000, V_fixture 0.0: 20-80 % time 130ps typ, 177ps min, 131ps max; typ from 1.93 V to 0 V
|   falling waveform, R_fixture 50.0000, V_fixture 3.3000: 20-80 % time 230ps typ, 281ps min, 190ps max; typ from 3.3 V to 1.32 V
[Pulldown]
|Voltage   I(typ)   I(min)   I(max)
-3.3V     -23.68mA   -17.2mA    -30.83mA
-1.1V     -23.68mA   -17.2mA    -30.83mA
-500mV    -18.9mA    -14.22mA   -24.08mA
-400mV    -16.43mA   -11.91mA   -21.57mA
600mV     22.42mA    15.62mA    30.2mA
1.3V      39.15mA    26.81mA    53.51mA
2V        44.82mA    30.69mA    61.1mA
3.7V      48.01mA    33.58mA    65.08mA
3.9V      48.91mA    38.12mA    65.34mA
4.2V      57.06mA    55.89mA    69.08mA
4.6V      86.16mA    82.52mA    89.35mA
6.6V      243.1mA    215mA      281.8mA
[Pullup]
|Voltage   I(typ)   I(min)   I(max)
-3.3V     261.7mA    232.8mA    311.9mA
-2.7V     219.1mA    193.2mA    260.1mA
-2.1V     166.7mA    144.4mA    200mA
-1.7V     127.9mA    109.9mA    155.5mA
-1.1V     65.78mA    57.35mA    80.82mA
-800mV    38.2mA     32.09mA    51.33mA
-400mV    16.19mA    12.24mA    22.44mA
800mV     -26.1mA    -19.07mA   -37.51mA
1.5V      -40.42mA   -28.93mA   -59.41mA
2.3V      -47.34mA   -33.02mA   -71.88mA
3.8V      -50.37mA   -34.75mA   -78.05mA
6.55V     -50.37mA   -34.75mA   -78.05mA
[GND_clamp]
|Voltage   I(typ)   I(min)   I(max)
-3.3V     -955.2mA   -930.2mA   -977.8mA
-1.2V     -86.08mA   -82.87mA   -94.74mA
-1.15V    -76.63mA   -73.22mA   -85.57mA
-1.1V     -67.6mA    -63.89mA   -77.12mA
-1V       -51.41mA   -46.51mA   -63.06mA
-900mV    -38.77mA   -31.82mA   -51.11mA
-800mV    -28.16mA   -20.53mA   -37.82mA
-700mV    -18.01mA   -11.58mA   -24.66mA
-600mV    -9.185mA   -5.219mA   -12.92mA
-450mV    -1.125mA   -553.6uA   -1.501mA
-300mV    0A         0A         0A
6.6V      0A         0A         0A
[POWER_clamp]
|Voltage   I(typ)   I(min)   I(max)
-3.25V    961.3uA    1.05mA     917.9uA
-2.05V    275.4uA    268.3uA    307.1uA
-1.75V    231.3uA    224.8uA    252.6uA
-950mV    120.7uA    124.7uA    102.8uA
-750mV    90.82uA    102.7uA    94.17uA
-450mV    58.57uA    68.87uA    19.46uA
-350mV    58.57uA    58.54uA    3.121uA
50mV      -5.338uA   31.71uA    -57.16uA
850mV     -79.07uA   -36.24uA   -150.4uA
1.55V     -120.8uA   -70.05uA   -201.6uA
2.05V     -130.5uA   -83.29uA   -201.6uA
6.6V      -130.5uA   -83.29uA   -201.6uA
[Ramp]
| variable   typ   min   max
dV/dt_r  1.1559/0.2222n   0.9052/0.2823n   1.4322/0.1593n
dV/dt_f  1.1870/0.2282n   0.8824/0.2777n   1.4366/0.1884n
R_load = 50.0000
[Rising Waveform]
R_fixture=   50.0000
V_fixture=   3.3000
V_fixture_min=   3.1400
V_fixture_max=   3.4700
|time   V(typ)   V(min)   V(max)
0s        1.322V     1.669V     1.076V
404ps     1.321V     1.669V     1.075V
505.1ps   1.322V     1.669V     1.284V
606.1ps   1.32V      1.669V     2.837V
707.1ps   1.392V     1.669V     3.324V
909.1ps   2.961V     1.668V     3.425V
1.01ns    3.178V     1.665V     3.443V
1.313ns   3.266V     2.845V     3.463V
1.616ns   3.289V     3.093V     3.469V
10ns      3.3V       3.14V      3.47V
[Rising Waveform]
R_fixture=   50.0000
V_fixture=   0.0
V_fixture_min=   0.0
V_fixture_max=   0.0
|time   V(typ)   V(min)   V(max)
0s        810.2nV    1.051uV    780.3nV
505.1ps   15.26uV    894.5nV    -44.19mV
707.1ps   -23.16mV   20.03uV    1.844V
808.1ps   14.52mV    57.24uV    2.139V
1.01ns    1.343V     -7.634mV   2.308V
1.111ns   1.617V     -31.65mV   2.338V
1.212ns   1.735V     -17.48mV   2.355V
1.515ns   1.863V     1.085V     2.378V
2.02ns    1.911V     1.429V     2.387V
10ns      1.927V     1.509V     2.387V
[Falling Waveform]
R_fixture=   50.0000
V_fixture=   0.0
V_fixture_min=   0.0
V_fixture_max=   0.0
|time   V(typ)   V(min)   V(max)
0s        1.927V     1.509V     2.387V
505.1ps   1.927V     1.509V     2.389V
606.1ps   1.927V     1.509V     956.4mV
707.1ps   1.925V     1.509V     192.3mV
808.1ps   1.789V     1.509V     74.98mV
909.1ps   594.5mV    1.509V     39.04mV
1.212ns   43.91mV    1.493V     6.127mV
1.414ns   19.32mV    442.5mV    2.868mV
1.717ns   6.702mV    47.17mV    469uV
10ns      7.375uV    -111.1nV   14.96uV
[Falling Waveform]
R_fixture=   50.0000
V_fixture=   3.3000
V_fixture_min=   3.1400
V_fixture_max=   3.4700
|time   V(typ)   V(min)   V(max)
0s        3.3V       3.14V      3.47V
505.1ps   3.3V       3.14V      3.474V
707.1ps   3.297V     3.14V      1.746V
808.1ps   3.318V     3.14V      1.374V
1.01ns    1.956V     3.141V     1.153V
1.111ns   1.675V     3.138V     1.12V
1.313ns   1.453V     3.13V      1.095V
1.616ns   1.364V     2.007V     1.082V
2.121ns   1.333V     1.732V     1.076V
10ns      1.322V     1.669V     1.076V
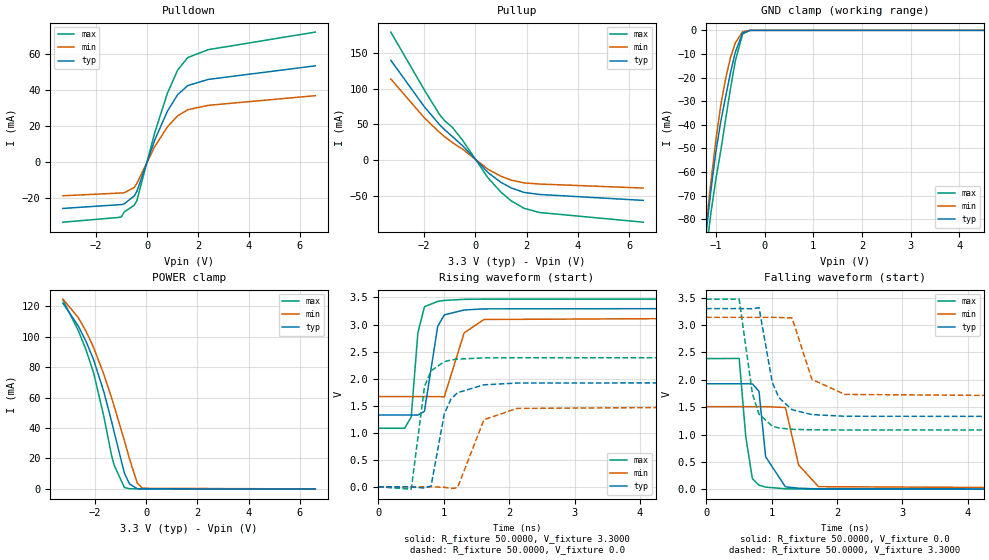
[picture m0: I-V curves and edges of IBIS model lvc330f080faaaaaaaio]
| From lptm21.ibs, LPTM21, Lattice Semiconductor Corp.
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|   Model lvc330f080faaaaaaaio
[Model]   lvc330f080faaaaaaaio
Model_type   I/O
Polarity   Non-Inverting
Enable   Active-Low
Vinl =   0.8000V
Vinh =   2.0000V
Vmeas =   1.500000V
Cref =   0.0F
Rref =   1.0000M
Vref =   0.0V
C_comp   4.2000pF   3.8000pF   7.5000pF
[Temperature Range]   25.0000   0.1050k   -40.0000
[Voltage Range]   3.3000V   3.1400V   3.4700V
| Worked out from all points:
|   slope of the pulldown table from 0 to 0.495 V, typ, clamps not added: 26 ohm
|   slope of the pullup table from 0 to 0.495 V, typ, clamps not added: 28.5 ohm
|   GND clamp passes 1 mA (typ) near -0.44 V on its own axis
|   POWER clamp passes 1 mA (typ) near -0.53 V on its own axis
|   rising waveform, R_fixture 50.0000, V_fixture 3.3000: 20-80 % time 154ps typ, 210ps min, 114ps max; typ from 1.33 V to 3.3 V
|   rising waveform, R_fixture 50.0000, V_fixture 0.0: 20-80 % time 223ps typ, 283ps min, 159ps max; typ from 0.002 V to 1.93 V
|   falling waveform, R_fixture 50.0000, V_fixture 0.0: 20-80 % time 129ps typ, 176ps min, 130ps max; typ from 1.93 V to 0.002 V
|   falling waveform, R_fixture 50.0000, V_fixture 3.3000: 20-80 % time 229ps typ, 281ps min, 189ps max; typ from 3.3 V to 1.33 V
[Pulldown]
|Voltage   I(typ)   I(min)   I(max)
-3.3V     -25.88mA   -18.83mA   -33.55mA
-1.1V     -23.82mA   -17.33mA   -30.89mA
-1V       -23.73mA   -17.27mA   -30.52mA
-900mV    -23.42mA   -17.2mA    -27.86mA
-500mV    -18.9mA    -14.22mA   -24.09mA
-400mV    -16.44mA   -11.91mA   -21.57mA
300mV     12.12mA    8.504mA    16.22mA
800mV     28.3mA     19.6mA     38.34mA
1.2V      37.47mA    25.7mA     51.17mA
1.6V      42.6mA     29.13mA    58.23mA
2.4V      46.01mA    31.56mA    62.58mA
6.6V      53.57mA    36.95mA    72.38mA
[Pullup]
|Voltage   I(typ)   I(min)   I(max)
-3.3V     139.6mA    113.4mA    179mA
-2V       75.04mA    59.46mA    98.6mA
-1.4V     49.68mA    38.84mA    63.78mA
-1.2V     42.54mA    32.82mA    55.06mA
-900mV    33.1mA     24.61mA    45.94mA
-500mV    20.2mA     15.31mA    27.84mA
500mV     -17.54mA   -12.9mA    -25mA
1V        -31mA      -22.53mA   -44.82mA
1.4V      -38.86mA   -27.91mA   -56.91mA
1.9V      -45.06mA   -31.8mA    -67.29mA
2.5V      -47.95mA   -33.38mA   -73.15mA
6.55V     -56.23mA   -38.99mA   -86.71mA
[GND_clamp]
|Voltage   I(typ)   I(min)   I(max)
-3.3V     -955.2mA   -930.2mA   -977.8mA
-1.2V     -86.07mA   -82.87mA   -94.72mA
-1.15V    -76.63mA   -73.23mA   -85.56mA
-1.1V     -67.6mA    -63.89mA   -77.1mA
-1V       -51.41mA   -46.51mA   -63.05mA
-900mV    -38.77mA   -31.83mA   -51.09mA
-800mV    -28.16mA   -20.53mA   -37.81mA
-700mV    -18.01mA   -11.59mA   -24.66mA
-600mV    -9.192mA   -5.229mA   -12.92mA
-450mV    -1.151mA   -576.6uA   -1.527mA
-300mV    -17.4uA    -15.66uA   -11.6uA
6.6V      0A         0A         0A
[POWER_clamp]
|Voltage   I(typ)   I(min)   I(max)
-3.25V    122.1mA    124.8mA    124.2mA
-2.65V    107.1mA    112.6mA    104.1mA
-2.35V    97.06mA    103.7mA    91.56mA
-2.05V    84.81mA    92.86mA    76.2mA
-1.65V    63.69mA    75.19mA    47.4mA
-1.35V    44.32mA    59.82mA    21.89mA
-1.25V    37.38mA    54.39mA    15.53mA
-850mV    10.3mA     31.63mA    860uA
-650mV    3.168mA    19.76mA    65.53uA
-350mV    73.34uA    3.862mA    3.121uA
-150mV    17.77uA    366.8uA    -28.16uA
6.6V      -143.8uA   -91.66uA   -226.3uA
[Ramp]
| variable   typ   min   max
dV/dt_r  1.1547/0.2203n   0.9042/0.2800n   1.4307/0.1573n
dV/dt_f  1.1832/0.2265n   0.8824/0.2777n   1.4320/0.1869n
R_load = 50.0000
[Rising Waveform]
R_fixture=   50.0000
V_fixture=   3.3000
V_fixture_min=   3.1400
V_fixture_max=   3.4700
|time   V(typ)   V(min)   V(max)
0s        1.328V     1.669V     1.083V
404ps     1.328V     1.669V     1.083V
505.1ps   1.328V     1.669V     1.295V
606.1ps   1.327V     1.669V     2.845V
707.1ps   1.399V     1.669V     3.328V
909.1ps   2.965V     1.668V     3.427V
1.01ns    3.178V     1.665V     3.445V
1.313ns   3.268V     2.845V     3.465V
1.616ns   3.289V     3.093V     3.469V
10ns      3.3V       3.14V      3.47V
[Rising Waveform]
R_fixture=   50.0000
V_fixture=   0.0
V_fixture_min=   0.0
V_fixture_max=   0.0
|time   V(typ)   V(min)   V(max)
0s        2.075mV    1.701mV    2.581mV
505.1ps   2.09mV     1.701mV    -41.36mV
707.1ps   -21.05mV   1.72mV     1.852V
808.1ps   18.01mV    1.757mV    2.146V
1.01ns    1.35V      -5.938mV   2.314V
1.111ns   1.623V     -29.75mV   2.343V
1.212ns   1.741V     -14.75mV   2.361V
1.616ns   1.886V     1.243V     2.384V
2.121ns   1.919V     1.45V      2.387V
10ns      1.927V     1.509V     2.387V
[Falling Waveform]
R_fixture=   50.0000
V_fixture=   0.0
V_fixture_min=   0.0
V_fixture_max=   0.0
|time   V(typ)   V(min)   V(max)
0s        1.927V     1.509V     2.387V
505.1ps   1.927V     1.509V     2.389V
606.1ps   1.927V     1.509V     956.4mV
707.1ps   1.925V     1.509V     192.3mV
808.1ps   1.789V     1.509V     74.98mV
909.1ps   594.5mV    1.509V     39.04mV
1.212ns   43.91mV    1.493V     8.2mV
1.414ns   19.32mV    442.5mV    4.165mV
1.717ns   6.764mV    47.17mV    2.906mV
10ns      2.085mV    1.696mV    2.571mV
[Falling Waveform]
R_fixture=   50.0000
V_fixture=   3.3000
V_fixture_min=   3.1400
V_fixture_max=   3.4700
|time   V(typ)   V(min)   V(max)
0s        3.3V       3.14V      3.47V
505.1ps   3.3V       3.14V      3.474V
707.1ps   3.297V     3.14V      1.746V
808.1ps   3.318V     3.14V      1.374V
1.01ns    1.956V     3.141V     1.153V
1.111ns   1.675V     3.138V     1.12V
1.313ns   1.453V     3.13V      1.095V
1.616ns   1.364V     2.007V     1.086V
2.121ns   1.333V     1.732V     1.083V
10ns      1.328V     1.669V     1.083V
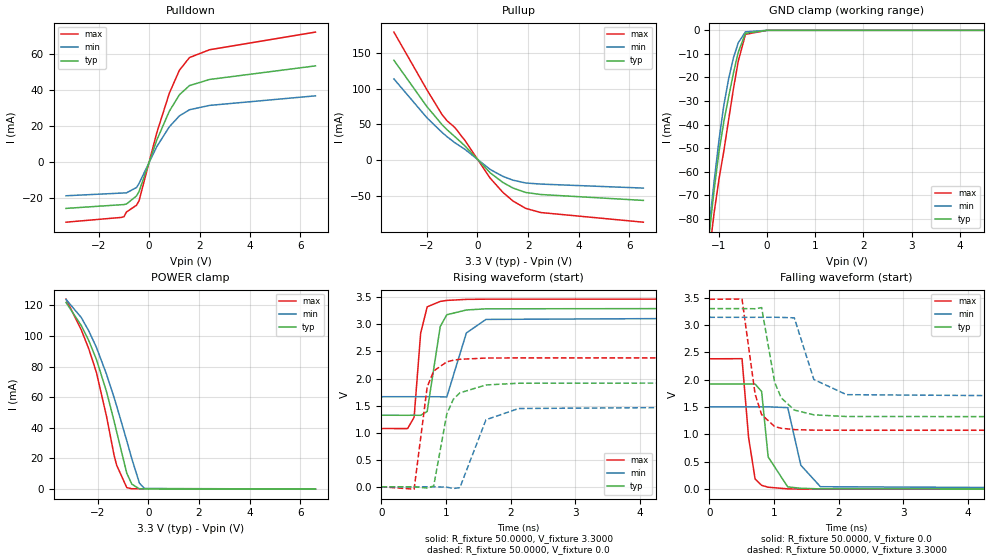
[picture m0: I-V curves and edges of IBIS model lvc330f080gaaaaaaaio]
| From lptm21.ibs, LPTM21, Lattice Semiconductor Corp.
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|   Model lvc330f080gaaaaaaaio
[Model]   lvc330f080gaaaaaaaio
Model_type   I/O
Polarity   Non-Inverting
Enable   Active-Low
Vinl =   0.8000V
Vinh =   2.0000V
Vmeas =   1.500000V
Cref =   0.0F
Rref =   1.0000M
Vref =   0.0V
C_comp   4.2000pF   3.8000pF   7.5000pF
[Temperature Range]   25.0000   0.1050k   -40.0000
[Voltage Range]   3.3000V   3.1400V   3.4700V
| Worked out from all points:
|   slope of the pulldown table from 0 to 0.495 V, typ, clamps not added: 26 ohm
|   slope of the pullup table from 0 to 0.495 V, typ, clamps not added: 28.5 ohm
|   GND clamp passes 1 mA (typ) near -0.43 V on its own axis
|   POWER clamp passes 1 mA (typ) near -0.53 V on its own axis
|   rising waveform, R_fixture 50.0000, V_fixture 3.3000: 20-80 % time 154ps typ, 210ps min, 115ps max; typ from 1.32 V to 3.3 V
|   rising waveform, R_fixture 50.0000, V_fixture 0.0: 20-80 % time 223ps typ, 283ps min, 159ps max; typ from 0 V to 1.92 V
|   falling waveform, R_fixture 50.0000, V_fixture 0.0: 20-80 % time 129ps typ, 176ps min, 130ps max; typ from 1.92 V to 0 V
|   falling waveform, R_fixture 50.0000, V_fixture 3.3000: 20-80 % time 228ps typ, 280ps min, 188ps max; typ from 3.3 V to 1.32 V
[Pulldown]
|Voltage   I(typ)   I(min)   I(max)
-3.3V     -25.87mA   -18.83mA   -33.56mA
-1.1V     -23.82mA   -17.33mA   -30.89mA
-1V       -23.73mA   -17.27mA   -30.52mA
-900mV    -23.42mA   -17.2mA    -27.86mA
-500mV    -18.9mA    -14.22mA   -24.08mA
-400mV    -16.43mA   -11.91mA   -21.57mA
300mV     12.1mA     8.496mA    16.18mA
800mV     28.29mA    19.6mA     38.31mA
1.2V      37.46mA    25.7mA     51.16mA
1.6V      42.6mA     29.13mA    58.23mA
2.4V      46.02mA    31.56mA    62.59mA
6.6V      53.59mA    36.89mA    72.43mA
[Pullup]
|Voltage   I(typ)   I(min)   I(max)
-3.3V     139.7mA    113.6mA    179.1mA
-2V       75.06mA    59.5mA     98.61mA
-1.4V     49.7mA     38.86mA    63.78mA
-1.2V     42.55mA    32.83mA    55.05mA
-900mV    33.1mA     24.62mA    45.94mA
-500mV    20.21mA    15.31mA    27.84mA
500mV     -17.55mA   -12.91mA   -25.03mA
1V        -31.02mA   -22.53mA   -44.85mA
1.4V      -38.87mA   -27.91mA   -56.94mA
1.9V      -45.07mA   -31.81mA   -67.31mA
2.5V      -47.95mA   -33.38mA   -73.15mA
6.55V     -56.2mA    -38.98mA   -86.64mA
[GND_clamp]
|Voltage   I(typ)   I(min)   I(max)
-3.3V     -955.3mA   -930.3mA   -978mA
-1.2V     -86.21mA   -82.95mA   -94.94mA
-1.15V    -76.76mA   -73.31mA   -85.77mA
-1.1V     -67.73mA   -63.97mA   -77.32mA
-1V       -51.54mA   -46.59mA   -63.26mA
-900mV    -38.9mA    -31.9mA    -51.31mA
-800mV    -28.29mA   -20.61mA   -38.02mA
-700mV    -18.14mA   -11.66mA   -24.86mA
-600mV    -9.315mA   -5.302mA   -13.12mA
-450mV    -1.255mA   -637uA     -1.701mA
0V        0A         0A         0A
6.6V      0A         0A         0A
[POWER_clamp]
|Voltage   I(typ)   I(min)   I(max)
-3.25V    121.9mA    123.9mA    124.1mA
-2.65V    106.9mA    112.1mA    104.1mA
-2.35V    96.95mA    103.3mA    91.59mA
-2.05V    84.73mA    92.58mA    76.25mA
-1.65V    63.65mA    75mA       47.49mA
-1.35V    44.31mA    59.69mA    21.99mA
-1.25V    37.38mA    54.28mA    15.6mA
-850mV    10.32mA    31.58mA    939uA
-650mV    3.193mA    19.74mA    210uA
-350mV    132.1uA    3.862mA    199.7uA
-150mV    104.6uA    375.8uA    197.7uA
6.6V      -56.35nA   -1.463uA   -71.55uA
[Ramp]
| variable   typ   min   max
dV/dt_r  1.1527/0.2207n   0.9025/0.2802n   1.4288/0.1579n
dV/dt_f  1.1861/0.2256n   0.8848/0.2770n   1.4351/0.1858n
R_load = 50.0000
[Rising Waveform]
R_fixture=   50.0000
V_fixture=   3.3000
V_fixture_min=   3.1400
V_fixture_max=   3.4700
|time   V(typ)   V(min)   V(max)
0s        1.322V     1.664V     1.076V
404ps     1.321V     1.664V     1.075V
505.1ps   1.322V     1.664V     1.284V
606.1ps   1.32V      1.664V     2.837V
707.1ps   1.392V     1.664V     3.324V
909.1ps   2.961V     1.663V     3.425V
1.01ns    3.178V     1.659V     3.443V
1.313ns   3.266V     2.842V     3.462V
1.616ns   3.288V     3.092V     3.466V
10ns      3.298V     3.139V     3.468V
[Rising Waveform]
R_fixture=   50.0000
V_fixture=   0.0
V_fixture_min=   0.0
V_fixture_max=   0.0
|time   V(typ)   V(min)   V(max)
0s        810.2nV    1.051uV    780.3nV
505.1ps   15.26uV    894.5nV    -44.19mV
707.1ps   -23.16mV   20.03uV    1.844V
808.1ps   14.52mV    57.24uV    2.139V
1.01ns    1.343V     -7.634mV   2.308V
1.111ns   1.617V     -31.65mV   2.338V
1.212ns   1.735V     -17.48mV   2.355V
1.616ns   1.881V     1.238V     2.378V
2.121ns   1.913V     1.446V     2.381V
10ns      1.921V     1.504V     2.381V
[Falling Waveform]
R_fixture=   50.0000
V_fixture=   0.0
V_fixture_min=   0.0
V_fixture_max=   0.0
|time   V(typ)   V(min)   V(max)
0s        1.921V     1.504V     2.381V
505.1ps   1.921V     1.504V     2.383V
606.1ps   1.921V     1.504V     947.4mV
707.1ps   1.92V      1.504V     185.7mV
808.1ps   1.783V     1.504V     70.3mV
909.1ps   588mV      1.504V     35.33mV
1.212ns   40.99mV    1.489V     5.341mV
1.414ns   16.89mV    438mV      1.511mV
1.717ns   4.504mV    44.86mV    315.6uV
10ns      -7.653uV   12.7uV     -3.759uV
[Falling Waveform]
R_fixture=   50.0000
V_fixture=   3.3000
V_fixture_min=   3.1400
V_fixture_max=   3.4700
|time   V(typ)   V(min)   V(max)
0s        3.298V     3.139V     3.468V
505.1ps   3.298V     3.139V     3.472V
707.1ps   3.295V     3.139V     1.736V
808.1ps   3.316V     3.139V     1.362V
1.01ns    1.949V     3.14V      1.142V
1.111ns   1.667V     3.137V     1.112V
1.313ns   1.445V     3.129V     1.088V
1.616ns   1.357V     2.002V     1.078V
2.121ns   1.327V     1.726V     1.076V
10ns      1.322V     1.664V     1.076V
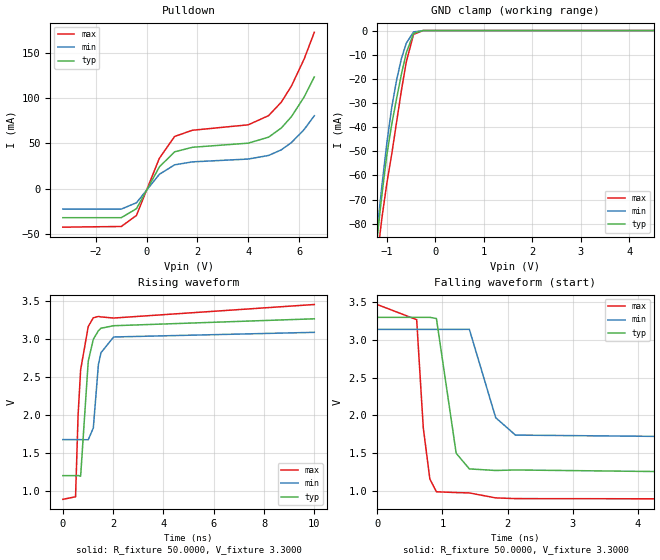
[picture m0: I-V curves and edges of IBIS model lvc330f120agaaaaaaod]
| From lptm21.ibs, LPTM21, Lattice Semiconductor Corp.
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|   Model lvc330f120agaaaaaaod
[Model]   lvc330f120agaaaaaaod
Model_type   I/O_open_drain
Polarity   Non-Inverting
Enable   Active-Low
Vinl =   0.8000V
Vinh =   2.0000V
Vmeas =   1.6500V
Cref =   0.0F
Rref =   1.0000M
Vref =   0.0V
C_comp   4.2000pF   3.8000pF   7.5000pF
[Temperature Range]   25.0000   0.1050k   -40.0000
[Voltage Range]   3.3000V   3.1400V   3.4700V
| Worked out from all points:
|   slope of the pulldown table from 0 to 0.495 V, typ, clamps not added: 20.7 ohm
|   GND clamp passes 1 mA (typ) near -0.44 V on its own axis
|   rising waveform, R_fixture 50.0000, V_fixture 3.3000: 20-80 % time 272ps typ, 267ps min, 289ps max; typ from 1.2 V to 3.26 V
|   falling waveform, R_fixture 50.0000, V_fixture 3.3000: 20-80 % time 206ps typ, 236ps min, 143ps max; typ from 3.3 V to 1.2 V
[Pulldown]
|Voltage   I(typ)   I(min)   I(max)
-3.3V     -31.78mA   -22.34mA   -42.2mA
-1V       -31.78mA   -22.34mA   -41.47mA
-400mV    -21.83mA   -15.28mA   -29.25mA
500mV     24.14mA    15.99mA    33.61mA
1.1V      40.71mA    26.41mA    57.65mA
1.8V      45.73mA    29.68mA    64.49mA
4V        50.28mA    32.79mA    70.48mA
4.8V      56.87mA    36.73mA    80.58mA
5.3V      66.92mA    42.91mA    95.39mA
5.7V      79.48mA    50.94mA    113.2mA
6.2V      101.1mA    65.3mA     142.9mA
6.6V      123.2mA    80.45mA    172.3mA
[GND_clamp]
|Voltage   I(typ)   I(min)   I(max)
-3.3V     -955.3mA   -930.3mA   -978mA
-1.2V     -86.17mA   -82.92mA   -94.88mA
-1.15V    -76.72mA   -73.28mA   -85.71mA
-1.1V     -67.69mA   -63.94mA   -77.25mA
-1V       -51.5mA    -46.56mA   -63.19mA
-900mV    -38.85mA   -31.87mA   -51.24mA
-800mV    -28.24mA   -20.57mA   -37.95mA
-700mV    -18.09mA   -11.63mA   -24.79mA
-600mV    -9.258mA   -5.26mA    -13.05mA
-450mV    -1.178mA   -585.4uA   -1.585mA
-250mV    -3.51uA    -4.042uA   -2.972uA
6.6V      0A         0A         0A
[Ramp]
| variable   typ   min   max
dV/dt_r  1.2370/0.2698n   0.8464/0.2638n   1.5364/0.2865n
dV/dt_f  1.2602/0.2036n   0.8780/0.2341n   1.5493/0.1417n
R_load = 50.0000
[Rising Waveform]
R_fixture=   50.0000
V_fixture=   3.3000
V_fixture_min=   3.1400
V_fixture_max=   3.4700
|time   V(typ)   V(min)   V(max)
0s        1.199V     1.673V     887.7mV
505.1ps   1.199V     1.673V     921.4mV
606.1ps   1.201V     1.673V     1.993V
707.1ps   1.191V     1.672V     2.59V
1.01ns    2.704V     1.671V     3.16V
1.212ns   2.992V     1.826V     3.274V
1.414ns   3.104V     2.659V     3.292V
1.515ns   3.137V     2.815V     3.286V
2.02ns    3.17V      3.022V     3.271V
10ns      3.261V     3.083V     3.449V
[Falling Waveform]
R_fixture=   50.0000
V_fixture=   3.3000
V_fixture_min=   3.1400
V_fixture_max=   3.4700
|time   V(typ)   V(min)   V(max)
0s        3.3V       3.14V      3.47V
606.1ps   3.3V       3.14V      3.269V
707.1ps   3.3V       3.14V      1.839V
808.1ps   3.3V       3.14V      1.157V
909.1ps   3.284V     3.14V      987.8mV
1.212ns   1.498V     3.14V      977.5mV
1.414ns   1.291V     3.141V     972.6mV
1.818ns   1.27V      1.97V      906.7mV
2.121ns   1.277V     1.739V     897.3mV
10ns      1.2V       1.677V     887.7mV
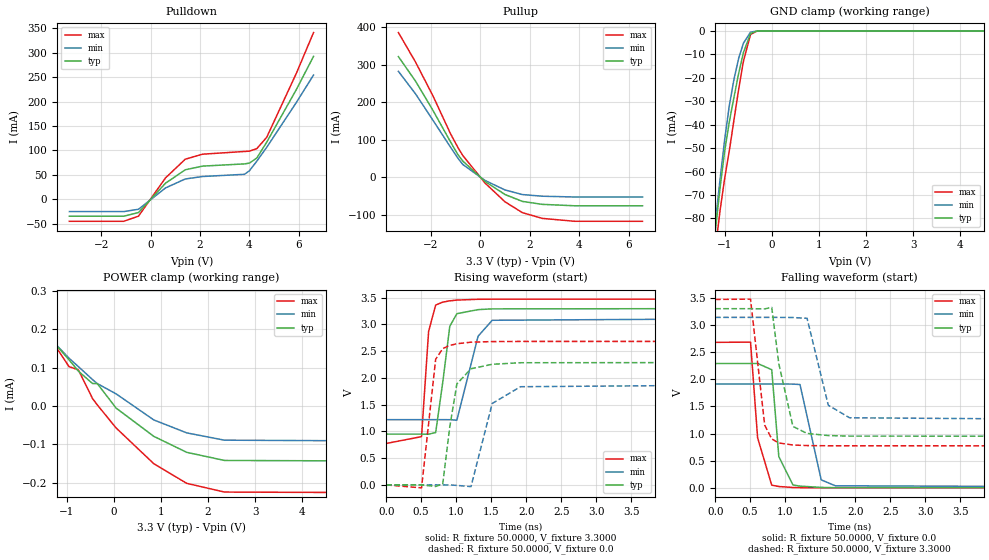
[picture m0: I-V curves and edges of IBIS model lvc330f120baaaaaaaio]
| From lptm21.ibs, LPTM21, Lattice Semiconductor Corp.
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|   Model lvc330f120baaaaaaaio
[Model]   lvc330f120baaaaaaaio
Model_type   I/O
Polarity   Non-Inverting
Enable   Active-Low
Vinl =   0.8000V
Vinh =   2.0000V
Vmeas =   1.500000V
Cref =   0.0F
Rref =   1.0000M
Vref =   0.0V
C_comp   4.2000pF   3.8000pF   7.5000pF
[Temperature Range]   25.0000   0.1050k   -40.0000
[Voltage Range]   3.3000V   3.1400V   3.4700V
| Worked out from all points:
|   slope of the pulldown table from 0 to 0.495 V, typ, clamps not added: 17.9 ohm
|   slope of the pullup table from 0 to 0.495 V, typ, clamps not added: 19.6 ohm
|   GND clamp passes 1 mA (typ) near -0.44 V on its own axis
|   rising waveform, R_fixture 50.0000, V_fixture 3.3000: 20-80 % time 142ps typ, 189ps min, 92.9ps max; typ from 0.948 V to 3.3 V
|   rising waveform, R_fixture 50.0000, V_fixture 0.0: 20-80 % time 154ps typ, 219ps min, 135ps max; typ from 0 V to 2.29 V
|   falling waveform, R_fixture 50.0000, V_fixture 0.0: 20-80 % time 106ps typ, 152ps min, 119ps max; typ from 2.29 V to 0 V
|   falling waveform, R_fixture 50.0000, V_fixture 3.3000: 20-80 % time 162ps typ, 221ps min, 138ps max; typ from 3.3 V to 0.948 V
[Pulldown]
|Voltage   I(typ)   I(min)   I(max)
-3.3V     -35.02mA   -25.52mA   -45.41mA
-1.1V     -35.02mA   -25.52mA   -45.41mA
-500mV    -27.5mA    -20.77mA   -34.92mA
600mV     32.75mA    23.02mA    43.67mA
1.4V      60.17mA    41.34mA    81.89mA
2.1V      67.64mA    46.37mA    92.1mA
3.8V      72.22mA    50.9mA     97.67mA
4V        73.8mA     58.16mA    98.31mA
4.3V      84.28mA    77.8mA     103.5mA
4.7V      116.6mA    106.1mA    126.6mA
5.9V      224.3mA    197.8mA    257.5mA
6.6V      292.6mA    254.3mA    341.3mA
[Pullup]
|Voltage   I(typ)   I(min)   I(max)
-3.3V     321.7mA    282.5mA    385.7mA
-2.6V     255.5mA    221.7mA    306.1mA
-1.9V     177.8mA    151.7mA    216.3mA
-1.2V     94.97mA    80.83mA    116.7mA
-900mV    60.8mA     51.35mA    79.83mA
-700mV    43.55mA    34.41mA    58.32mA
200mV     -10.85mA   -8.11mA    -15.13mA
1V        -45.38mA   -33.2mA    -64.85mA
1.7V      -63.71mA   -45.51mA   -93.58mA
2.5V      -71.58mA   -49.9mA    -108.9mA
3.8V      -75.35mA   -52.01mA   -116.6mA
6.55V     -75.35mA   -52.01mA   -116.7mA
[GND_clamp]
|Voltage   I(typ)   I(min)   I(max)
-3.3V     -955.2mA   -930.2mA   -977.8mA
-1.2V     -86.07mA   -82.87mA   -94.72mA
-1.15V    -76.63mA   -73.23mA   -85.56mA
-1.1V     -67.6mA    -63.89mA   -77.1mA
-1V       -51.41mA   -46.51mA   -63.05mA
-900mV    -38.77mA   -31.83mA   -51.09mA
-800mV    -28.16mA   -20.53mA   -37.81mA
-700mV    -18.01mA   -11.59mA   -24.66mA
-600mV    -9.192mA   -5.229mA   -12.92mA
-450mV    -1.151mA   -576.6uA   -1.527mA
-300mV    -17.4uA    -15.66uA   -11.6uA
6.6V      0A         0A         0A
[POWER_clamp]
|Voltage   I(typ)   I(min)   I(max)
-3.25V    961.3uA    1.05mA     917.9uA
-2.25V    305.8uA    299.5uA    344.1uA
-1.95V    260.5uA    253.4uA    288.8uA
-950mV    120.7uA    124.7uA    102.8uA
-750mV    90.82uA    102.7uA    94.17uA
-450mV    58.57uA    68.87uA    19.46uA
-350mV    58.57uA    58.54uA    3.121uA
50mV      -5.338uA   31.71uA    -57.16uA
850mV     -79.07uA   -36.24uA   -150.4uA
1.55V     -120.8uA   -70.05uA   -201.6uA
2.35V     -141.9uA   -89.06uA   -224.3uA
6.6V      -143.8uA   -91.66uA   -226.3uA
[Ramp]
| variable   typ   min   max
dV/dt_r  1.3741/0.1523n   1.1475/0.2167n   1.6081/0.1334n
dV/dt_f  1.4109/0.1604n   1.1528/0.2187n   1.6174/0.1371n
R_load = 50.0000
[Rising Waveform]
R_fixture=   50.0000
V_fixture=   3.3000
V_fixture_min=   3.1400
V_fixture_max=   3.4700
|time   V(typ)   V(min)   V(max)
0s        948.5mV    1.219V     774.4mV
505.1ps   948.6mV    1.219V     901.5mV
606.1ps   947.4mV    1.219V     2.868V
707.1ps   978.4mV    1.219V     3.359V
808.1ps   1.916V     1.219V     3.414V
909.1ps   2.964V     1.218V     3.438V
1.01ns    3.198V     1.209V     3.452V
1.313ns   3.274V     2.777V     3.467V
1.515ns   3.288V     3.075V     3.469V
10ns      3.3V       3.14V      3.47V
[Rising Waveform]
R_fixture=   50.0000
V_fixture=   0.0
V_fixture_min=   0.0
V_fixture_max=   0.0
|time   V(typ)   V(min)   V(max)
0s        612.2nV    810.3nV    586nV
505.1ps   6.89uV     581.8nV    -55.02mV
707.1ps   -28.66mV   21.56uV    2.347V
808.1ps   19.37mV    33.24uV    2.547V
909.1ps   1.09V      -246uV     2.605V
1.01ns    1.886V     -9.334mV   2.637V
1.212ns   2.17V      -31.42mV   2.666V
1.515ns   2.253V     1.521V     2.677V
1.919ns   2.282V     1.834V     2.68V
10ns      2.29V      1.913V     2.68V
[Falling Waveform]
R_fixture=   50.0000
V_fixture=   0.0
V_fixture_min=   0.0
V_fixture_max=   0.0
|time   V(typ)   V(min)   V(max)
0s        2.29V      1.913V     2.68V
505.1ps   2.29V      1.913V     2.684V
606.1ps   2.291V     1.913V     921.4mV
808.1ps   2.176V     1.913V     48.9mV
909.1ps   576.5mV    1.913V     24.86mV
1.111ns   53.25mV    1.911V     6.882mV
1.212ns   31.86mV    1.903V     3.558mV
1.515ns   8.387mV    147.3mV    528.7uV
1.717ns   3.408mV    38.01mV    195.1uV
10ns      -6.496uV   -3.412uV   -8.132uV
[Falling Waveform]
R_fixture=   50.0000
V_fixture=   3.3000
V_fixture_min=   3.1400
V_fixture_max=   3.4700
|time   V(typ)   V(min)   V(max)
0s        3.3V       3.14V      3.47V
505.1ps   3.3V       3.14V      3.476V
707.1ps   3.296V     3.14V      1.158V
808.1ps   3.324V     3.14V      900.6mV
909.1ps   2.287V     3.14V      826.5mV
1.111ns   1.132V     3.137V     789.5mV
1.313ns   1.002V     3.123V     778.8mV
1.616ns   963.4mV    1.522V     775.1mV
1.919ns   953mV      1.291V     774.6mV
10ns      948.5mV    1.219V     774.4mV
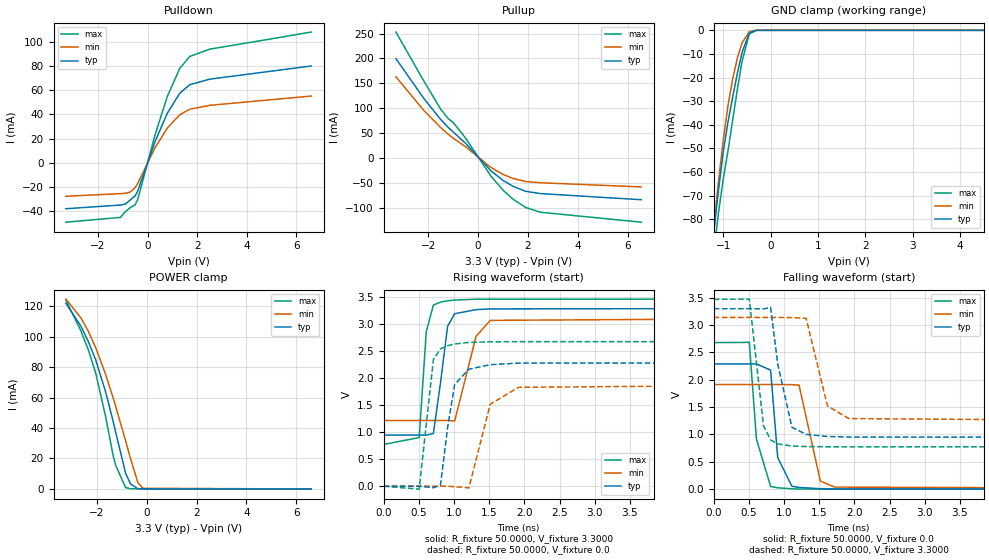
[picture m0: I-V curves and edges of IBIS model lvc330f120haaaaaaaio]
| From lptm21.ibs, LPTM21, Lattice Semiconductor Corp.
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|   Model lvc330f120haaaaaaaio
[Model]   lvc330f120haaaaaaaio
Model_type   I/O
Polarity   Non-Inverting
Enable   Active-Low
Vinl =   0.8000V
Vinh =   2.0000V
Vmeas =   1.500000V
Cref =   0.0F
Rref =   1.0000M
Vref =   0.0V
C_comp   4.2000pF   3.8000pF   7.5000pF
[Temperature Range]   25.0000   0.1050k   -40.0000
[Voltage Range]   3.3000V   3.1400V   3.4700V
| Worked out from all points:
|   slope of the pulldown table from 0 to 0.495 V, typ, clamps not added: 18 ohm
|   slope of the pullup table from 0 to 0.495 V, typ, clamps not added: 19.6 ohm
|   GND clamp passes 1 mA (typ) near -0.44 V on its own axis
|   POWER clamp passes 1 mA (typ) near -0.53 V on its own axis
|   rising waveform, R_fixture 50.0000, V_fixture 3.3000: 20-80 % time 142ps typ, 189ps min, 92.9ps max; typ from 0.948 V to 3.3 V
|   rising waveform, R_fixture 50.0000, V_fixture 0.0: 20-80 % time 154ps typ, 219ps min, 135ps max; typ from 0 V to 2.29 V
|   falling waveform, R_fixture 50.0000, V_fixture 0.0: 20-80 % time 106ps typ, 152ps min, 119ps max; typ from 2.29 V to 0 V
|   falling waveform, R_fixture 50.0000, V_fixture 3.3000: 20-80 % time 162ps typ, 221ps min, 138ps max; typ from 3.3 V to 0.948 V
[Pulldown]
|Voltage   I(typ)   I(min)   I(max)
-3.3V     -38.3mA    -27.97mA   -49.48mA
-1.1V     -35.24mA   -25.74mA   -45.51mA
-900mV    -34.46mA   -25.54mA   -40.82mA
-700mV    -31.01mA   -24.39mA   -37.34mA
-500mV    -27.54mA   -20.79mA   -34.96mA
-400mV    -23.68mA   -17.33mA   -30.73mA
300mV     17.45mA    12.4mA     23.02mA
800mV     41.22mA    28.82mA    55.19mA
1.3V      57.71mA    39.75mA    78.32mA
1.7V      64.68mA    44.32mA    88.18mA
2.5V      69.29mA    47.56mA    94.17mA
6.6V      80.25mA    55.27mA    108.4mA
[Pullup]
|Voltage   I(typ)   I(min)   I(max)
-3.3V     199.6mA    163mA      252.9mA
-2.2V     120.9mA    96.56mA    156.3mA
-1.5V     76.78mA    60.66mA    97.67mA
-1.2V     61.27mA    47.55mA    78.9mA
-1V       51.9mA     39.53mA    70.97mA
-500mV    29.08mA    22.24mA    39.54mA
500mV     -25.47mA   -18.9mA    -35.82mA
1V        -45.38mA   -33.2mA    -64.85mA
1.4V      -57.23mA   -41.33mA   -83.01mA
1.9V      -67.11mA   -47.52mA   -99.54mA
2.5V      -71.81mA   -50.03mA   -109.3mA
6.55V     -84.14mA   -58.39mA   -129.3mA
[GND_clamp]
|Voltage   I(typ)   I(min)   I(max)
-3.3V     -955.2mA   -930.2mA   -977.8mA
-1.2V     -86.08mA   -82.87mA   -94.74mA
-1.15V    -76.63mA   -73.22mA   -85.57mA
-1.1V     -67.6mA    -63.89mA   -77.12mA
-1V       -51.41mA   -46.51mA   -63.06mA
-900mV    -38.77mA   -31.82mA   -51.11mA
-800mV    -28.16mA   -20.53mA   -37.82mA
-700mV    -18.01mA   -11.58mA   -24.66mA
-600mV    -9.185mA   -5.219mA   -12.92mA
-450mV    -1.125mA   -553.6uA   -1.501mA
-300mV    0A         0A         0A
6.6V      0A         0A         0A
[POWER_clamp]
|Voltage   I(typ)   I(min)   I(max)
-3.25V    122.1mA    124.8mA    124.2mA
-2.65V    107.1mA    112.6mA    104.1mA
-2.35V    97.06mA    103.7mA    91.56mA
-2.05V    84.81mA    92.86mA    76.2mA
-1.65V    63.69mA    75.19mA    47.4mA
-1.35V    44.32mA    59.82mA    21.89mA
-1.25V    37.38mA    54.39mA    15.53mA
-850mV    10.3mA     31.63mA    860uA
-650mV    3.168mA    19.76mA    65.53uA
-350mV    73.34uA    3.862mA    3.121uA
-150mV    17.77uA    366.8uA    -28.16uA
6.6V      -130.5uA   -83.29uA   -201.6uA
[Ramp]
| variable   typ   min   max
dV/dt_r  1.3741/0.1523n   1.1475/0.2167n   1.6081/0.1334n
dV/dt_f  1.4109/0.1604n   1.1528/0.2187n   1.6174/0.1371n
R_load = 50.0000
[Rising Waveform]
R_fixture=   50.0000
V_fixture=   3.3000
V_fixture_min=   3.1400
V_fixture_max=   3.4700
|time   V(typ)   V(min)   V(max)
0s        948.5mV    1.219V     774.4mV
505.1ps   948.6mV    1.219V     901.5mV
606.1ps   947.4mV    1.219V     2.868V
707.1ps   978.4mV    1.219V     3.359V
808.1ps   1.916V     1.219V     3.414V
909.1ps   2.964V     1.218V     3.438V
1.01ns    3.198V     1.209V     3.452V
1.313ns   3.274V     2.777V     3.467V
1.515ns   3.288V     3.075V     3.469V
10ns      3.3V       3.14V      3.47V
[Rising Waveform]
R_fixture=   50.0000
V_fixture=   0.0
V_fixture_min=   0.0
V_fixture_max=   0.0
|time   V(typ)   V(min)   V(max)
0s        612.2nV    810.3nV    586nV
505.1ps   6.89uV     581.8nV    -55.02mV
707.1ps   -28.66mV   21.56uV    2.347V
808.1ps   19.37mV    33.24uV    2.547V
909.1ps   1.09V      -246uV     2.605V
1.01ns    1.886V     -9.334mV   2.637V
1.212ns   2.17V      -31.42mV   2.666V
1.515ns   2.253V     1.521V     2.677V
1.919ns   2.282V     1.834V     2.68V
10ns      2.29V      1.913V     2.68V
[Falling Waveform]
R_fixture=   50.0000
V_fixture=   0.0
V_fixture_min=   0.0
V_fixture_max=   0.0
|time   V(typ)   V(min)   V(max)
0s        2.29V      1.913V     2.68V
505.1ps   2.29V      1.913V     2.684V
606.1ps   2.291V     1.913V     921.4mV
808.1ps   2.176V     1.913V     48.9mV
909.1ps   576.5mV    1.913V     24.86mV
1.111ns   53.25mV    1.911V     6.882mV
1.212ns   31.86mV    1.903V     3.558mV
1.515ns   8.387mV    147.3mV    528.7uV
1.717ns   3.408mV    38.01mV    195.1uV
10ns      -6.496uV   -3.412uV   -8.132uV
[Falling Waveform]
R_fixture=   50.0000
V_fixture=   3.3000
V_fixture_min=   3.1400
V_fixture_max=   3.4700
|time   V(typ)   V(min)   V(max)
0s        3.3V       3.14V      3.47V
505.1ps   3.3V       3.14V      3.476V
707.1ps   3.296V     3.14V      1.158V
808.1ps   3.324V     3.14V      900.6mV
909.1ps   2.287V     3.14V      826.5mV
1.111ns   1.132V     3.137V     789.5mV
1.313ns   1.002V     3.123V     778.8mV
1.616ns   963.4mV    1.522V     775.1mV
1.919ns   953mV      1.291V     774.6mV
10ns      948.5mV    1.219V     774.4mV
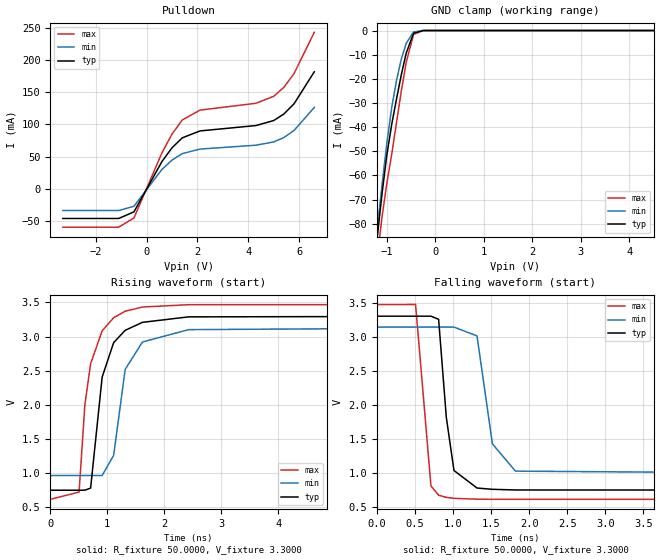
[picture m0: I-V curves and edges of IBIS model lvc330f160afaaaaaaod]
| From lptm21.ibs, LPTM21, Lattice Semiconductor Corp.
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|   Model lvc330f160afaaaaaaod
[Model]   lvc330f160afaaaaaaod
Model_type   I/O_open_drain
Polarity   Non-Inverting
Enable   Active-Low
Vinl =   0.8000V
Vinh =   2.0000V
Vmeas =   1.6500V
Cref =   0.0F
Rref =   1.0000M
Vref =   0.0V
C_comp   4.2000pF   3.8000pF   7.5000pF
[Temperature Range]   25.0000   0.1050k   -40.0000
[Voltage Range]   3.3000V   3.1400V   3.4700V
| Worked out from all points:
|   slope of the pulldown table from 0 to 0.495 V, typ, clamps not added: 13.9 ohm
|   GND clamp passes 1 mA (typ) near -0.44 V on its own axis
|   rising waveform, R_fixture 50.0000, V_fixture 3.3000: 20-80 % time 283ps typ, 276ps min, 264ps max; typ from 0.752 V to 3.3 V
|   falling waveform, R_fixture 50.0000, V_fixture 3.3000: 20-80 % time 141ps typ, 178ps min, 128ps max; typ from 3.3 V to 0.752 V
[Pulldown]
|Voltage   I(typ)   I(min)   I(max)
-3.3V     -46.05mA   -33.74mA   -59.55mA
-1.1V     -46.05mA   -33.74mA   -59.55mA
-500mV    -35.8mA    -27.15mA   -45.23mA
600mV     42.17mA    29.94mA    55.58mA
1V        63.65mA    44.54mA    85.02mA
1.4V      78.94mA    54.52mA    106.7mA
2.1V      89.73mA    61.59mA    122mA
4.3V      98.06mA    67.59mA    132.6mA
5V        105.8mA    72.7mA     143.4mA
5.4V      115.9mA    79.45mA    157.3mA
5.8V      131.7mA    90.34mA    178.6mA
6.6V      181.5mA    126.2mA    242.7mA
[GND_clamp]
|Voltage   I(typ)   I(min)   I(max)
-3.3V     -955.3mA   -930.3mA   -978mA
-1.2V     -86.18mA   -82.93mA   -94.91mA
-1.15V    -76.73mA   -73.29mA   -85.74mA
-1.1V     -67.71mA   -63.95mA   -77.28mA
-1V       -51.52mA   -46.57mA   -63.21mA
-900mV    -38.87mA   -31.88mA   -51.26mA
-800mV    -28.25mA   -20.58mA   -37.97mA
-700mV    -18.1mA    -11.63mA   -24.81mA
-600mV    -9.267mA   -5.265mA   -13.06mA
-450mV    -1.181mA   -586.6uA   -1.592mA
-250mV    -3.532uA   -4.055uA   -3.003uA
6.6V      0A         0A         0A
[Ramp]
| variable   typ   min   max
dV/dt_r  1.5290/0.2803n   1.3043/0.2732n   1.7112/0.2618n
dV/dt_f  1.5290/0.1393n   1.3043/0.1760n   1.7111/0.1271n
R_load = 50.0000
[Rising Waveform]
R_fixture=   50.0000
V_fixture=   3.3000
V_fixture_min=   3.1400
V_fixture_max=   3.4700
|time   V(typ)   V(min)   V(max)
0s        751.6mV    966.1mV    618mV
505.1ps   751.7mV    966.1mV    725.2mV
606.1ps   751.9mV    966.1mV    2V
707.1ps   782.2mV    966.1mV    2.603V
909.1ps   2.407V     966.4mV    3.084V
1.111ns   2.912V     1.263V     3.277V
1.313ns   3.092V     2.521V     3.372V
1.616ns   3.209V     2.921V     3.433V
2.424ns   3.289V     3.102V     3.467V
10ns      3.3V       3.14V      3.47V
[Falling Waveform]
R_fixture=   50.0000
V_fixture=   3.3000
V_fixture_min=   3.1400
V_fixture_max=   3.4700
|time   V(typ)   V(min)   V(max)
0s        3.3V       3.14V      3.47V
505.1ps   3.3V       3.14V      3.471V
707.1ps   3.3V       3.14V      814.5mV
808.1ps   3.254V     3.14V      678.1mV
909.1ps   1.818V     3.14V      646.9mV
1.01ns    1.04V      3.14V      632.9mV
1.313ns   783.4mV    3.011V     620.1mV
1.515ns   764.6mV    1.431V     618.6mV
1.818ns   755.2mV    1.031V     618.1mV
10ns      751.6mV    966.1mV    618mV
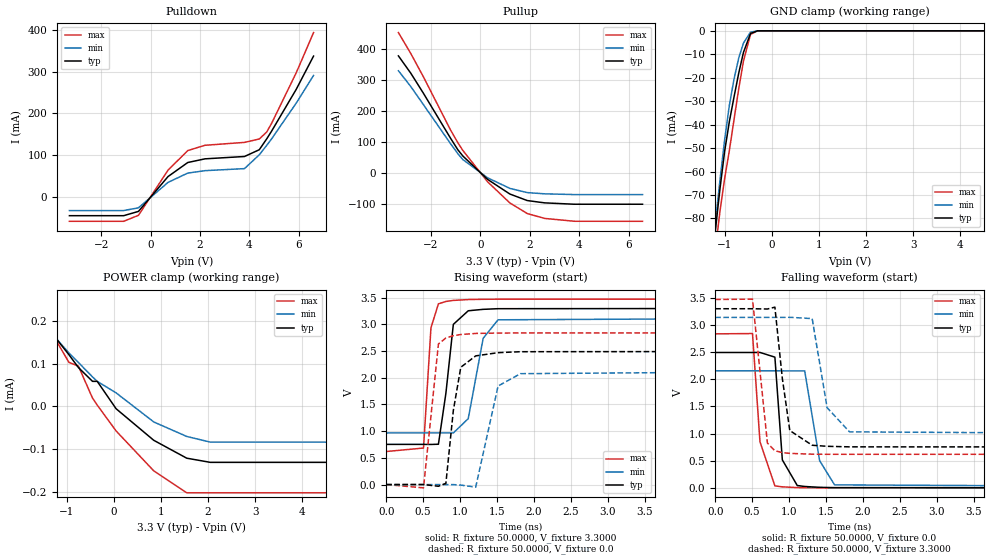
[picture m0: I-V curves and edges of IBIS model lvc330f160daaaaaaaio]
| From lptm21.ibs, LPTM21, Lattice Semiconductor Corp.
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|   Model lvc330f160daaaaaaaio
[Model]   lvc330f160daaaaaaaio
Model_type   I/O
Polarity   Non-Inverting
Enable   Active-Low
Vinl =   0.8000V
Vinh =   2.0000V
Vmeas =   1.500000V
Cref =   0.0F
Rref =   1.0000M
Vref =   0.0V
C_comp   4.2000pF   3.8000pF   7.5000pF
[Temperature Range]   25.0000   0.1050k   -40.0000
[Voltage Range]   3.3000V   3.1400V   3.4700V
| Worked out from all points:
|   slope of the pulldown table from 0 to 0.495 V, typ, clamps not added: 13.9 ohm
|   slope of the pullup table from 0 to 0.495 V, typ, clamps not added: 15.2 ohm
|   GND clamp passes 1 mA (typ) near -0.44 V on its own axis
|   rising waveform, R_fixture 50.0000, V_fixture 3.3000: 20-80 % time 132ps typ, 176ps min, 76.8ps max; typ from 0.752 V to 3.3 V
|   rising waveform, R_fixture 50.0000, V_fixture 0.0: 20-80 % time 142ps typ, 192ps min, 129ps max; typ from 0 V to 2.49 V
|   falling waveform, R_fixture 50.0000, V_fixture 0.0: 20-80 % time 82.9ps typ, 125ps min, 110ps max; typ from 2.49 V to 0 V
|   falling waveform, R_fixture 50.0000, V_fixture 3.3000: 20-80 % time 139ps typ, 180ps min, 131ps max; typ from 3.3 V to 0.752 V
[Pulldown]
|Voltage   I(typ)   I(min)   I(max)
-3.3V     -46.02mA   -33.72mA   -59.51mA
-1.1V     -46.02mA   -33.72mA   -59.51mA
-500mV    -35.74mA   -27.1mA    -45.14mA
700mV     47.97mA    33.96mA    63.38mA
1.5V      81.7mA     56.28mA    110.4mA
2.2V      90.52mA    62.13mA    123.1mA
3.8V      96.15mA    67.01mA    130mA
4.4V      112.4mA    100.3mA    138.2mA
4.7V      138.4mA    122.8mA    154.9mA
4.9V      157.1mA    138.5mA    175.8mA
5.9V      257.7mA    224.6mA    297.5mA
6.6V      337.3mA    290.8mA    393.8mA
[Pullup]
|Voltage   I(typ)   I(min)   I(max)
-3.3V     376.8mA    329mA      451.8mA
-2.8V     321mA      278.1mA    384.3mA
-2.3V     257.7mA    221mA      310.8mA
-1.2V     112.4mA    94.81mA    138.9mA
-900mV    74.54mA    62.01mA    97.14mA
-700mV    54.79mA    43.27mA    72.61mA
300mV     -20.58mA   -15.48mA   -28.4mA
1.2V      -67.69mA   -49.52mA   -96.41mA
1.9V      -88.62mA   -63.01mA   -130.4mA
2.6V      -96.01mA   -66.92mA   -146mA
3.8V      -100.4mA   -69.35mA   -155.2mA
6.55V     -100.4mA   -69.35mA   -155.3mA
[GND_clamp]
|Voltage   I(typ)   I(min)   I(max)
-3.3V     -955.2mA   -930.2mA   -977.8mA
-1.2V     -86.08mA   -82.87mA   -94.74mA
-1.15V    -76.63mA   -73.22mA   -85.57mA
-1.1V     -67.6mA    -63.89mA   -77.12mA
-1V       -51.41mA   -46.51mA   -63.06mA
-900mV    -38.77mA   -31.82mA   -51.11mA
-800mV    -28.16mA   -20.53mA   -37.82mA
-700mV    -18.01mA   -11.58mA   -24.66mA
-600mV    -9.185mA   -5.219mA   -12.92mA
-450mV    -1.125mA   -553.6uA   -1.501mA
-300mV    0A         0A         0A
6.6V      0A         0A         0A
[POWER_clamp]
|Voltage   I(typ)   I(min)   I(max)
-3.25V    961.3uA    1.05mA     917.9uA
-2.05V    275.4uA    268.3uA    307.1uA
-1.75V    231.3uA    224.8uA    252.6uA
-950mV    120.7uA    124.7uA    102.8uA
-750mV    90.82uA    102.7uA    94.17uA
-450mV    58.57uA    68.87uA    19.46uA
-350mV    58.57uA    58.54uA    3.121uA
50mV      -5.338uA   31.71uA    -57.16uA
850mV     -79.07uA   -36.24uA   -150.4uA
1.55V     -120.8uA   -70.05uA   -201.6uA
2.05V     -130.5uA   -83.29uA   -201.6uA
6.6V      -130.5uA   -83.29uA   -201.6uA
[Ramp]
| variable   typ   min   max
dV/dt_r  1.4966/0.1403n   1.2936/0.1899n   1.7022/0.1278n
dV/dt_f  1.5290/0.1376n   1.3043/0.1782n   1.7112/0.1294n
R_load = 50.0000
[Rising Waveform]
R_fixture=   50.0000
V_fixture=   3.3000
V_fixture_min=   3.1400
V_fixture_max=   3.4700
|time   V(typ)   V(min)   V(max)
0s        751.6mV    966.1mV    618mV
505.1ps   751.7mV    966.1mV    683.2mV
606.1ps   750.6mV    966.1mV    2.934V
707.1ps   754.6mV    966.1mV    3.382V
808.1ps   1.707V     966.5mV    3.426V
909.1ps   2.998V     965.3mV    3.446V
1.111ns   3.252V     1.234V     3.462V
1.313ns   3.279V     2.738V     3.467V
1.515ns   3.291V     3.083V     3.469V
10ns      3.3V       3.14V      3.47V
[Rising Waveform]
R_fixture=   50.0000
V_fixture=   0.0
V_fixture_min=   0.0
V_fixture_max=   0.0
|time   V(typ)   V(min)   V(max)
0s        484.9nV    653.8nV    458.4nV
505.1ps   965.7nV    396.4nV    -61.92mV
707.1ps   -31.85mV   22.19uV    2.63V
808.1ps   22.23mV    16.02uV    2.743V
909.1ps   1.387V     -277.4uV   2.786V
1.01ns    2.195V     -10.24mV   2.808V
1.212ns   2.408V     -48.56mV   2.828V
1.515ns   2.468V     1.844V     2.835V
1.818ns   2.486V     2.075V     2.837V
10ns      2.494V     2.156V     2.837V
[Falling Waveform]
R_fixture=   50.0000
V_fixture=   0.0
V_fixture_min=   0.0
V_fixture_max=   0.0
|time   V(typ)   V(min)   V(max)
0s        2.494V     2.156V     2.837V
505.1ps   2.494V     2.156V     2.843V
606.1ps   2.495V     2.156V     849.6mV
808.1ps   2.408V     2.156V     36.53mV
909.1ps   515.2mV    2.156V     18.56mV
1.111ns   43.14mV    2.154V     4.92mV
1.212ns   25.35mV    2.154V     2.505mV
1.414ns   10.16mV    501mV      696.7uV
1.616ns   4.103mV    54.88mV    252.1uV
10ns      13.46uV    3.911uV    -10.62uV
[Falling Waveform]
R_fixture=   50.0000
V_fixture=   3.3000
V_fixture_min=   3.1400
V_fixture_max=   3.4700
|time   V(typ)   V(min)   V(max)
0s        3.3V       3.14V      3.47V
505.1ps   3.3V       3.14V      3.477V
707.1ps   3.295V     3.14V      824.1mV
808.1ps   3.329V     3.14V      683.9mV
909.1ps   2.014V     3.14V      649.9mV
1.01ns    1.056V     3.142V     634.8mV
1.313ns   784.9mV    3.118V     620.4mV
1.515ns   765.5mV    1.478V     618.6mV
1.818ns   755.5mV    1.032V     618.1mV
10ns      751.6mV    966.1mV    617.9mV
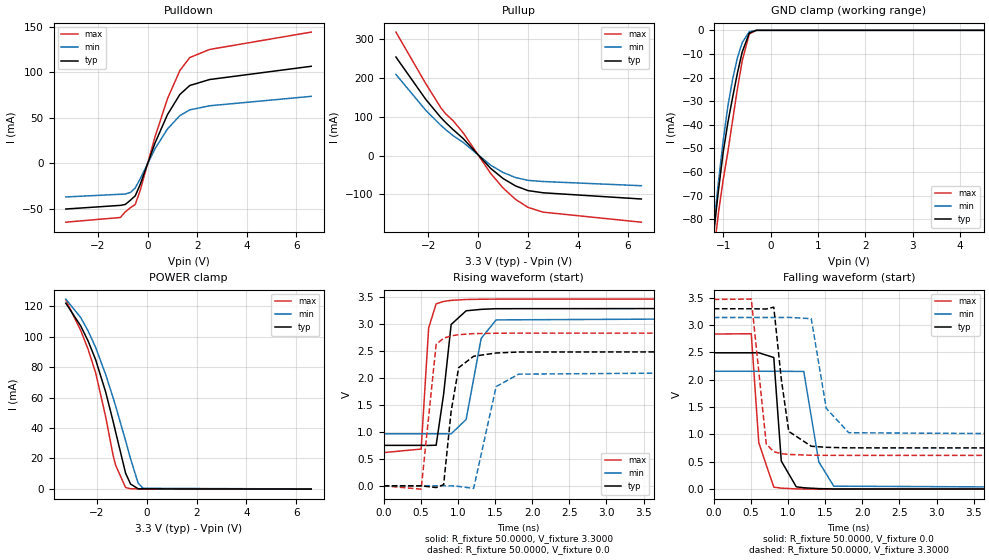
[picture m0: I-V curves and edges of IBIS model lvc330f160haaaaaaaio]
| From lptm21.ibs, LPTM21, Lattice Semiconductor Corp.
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|   Model lvc330f160haaaaaaaio
[Model]   lvc330f160haaaaaaaio
Model_type   I/O
Polarity   Non-Inverting
Enable   Active-Low
Vinl =   0.8000V
Vinh =   2.0000V
Vmeas =   1.500000V
Cref =   0.0F
Rref =   1.0000M
Vref =   0.0V
C_comp   4.2000pF   3.8000pF   7.5000pF
[Temperature Range]   25.0000   0.1050k   -40.0000
[Voltage Range]   3.3000V   3.1400V   3.4700V
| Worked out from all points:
|   slope of the pulldown table from 0 to 0.495 V, typ, clamps not added: 13.9 ohm
|   slope of the pullup table from 0 to 0.495 V, typ, clamps not added: 15.2 ohm
|   GND clamp passes 1 mA (typ) near -0.44 V on its own axis
|   POWER clamp passes 1 mA (typ) near -0.53 V on its own axis
|   rising waveform, R_fixture 50.0000, V_fixture 3.3000: 20-80 % time 132ps typ, 176ps min, 76.8ps max; typ from 0.752 V to 3.3 V
|   rising waveform, R_fixture 50.0000, V_fixture 0.0: 20-80 % time 142ps typ, 192ps min, 129ps max; typ from 0 V to 2.49 V
|   falling waveform, R_fixture 50.0000, V_fixture 0.0: 20-80 % time 82.9ps typ, 125ps min, 110ps max; typ from 2.49 V to 0 V
|   falling waveform, R_fixture 50.0000, V_fixture 3.3000: 20-80 % time 139ps typ, 180ps min, 131ps max; typ from 3.3 V to 0.752 V
[Pulldown]
|Voltage   I(typ)   I(min)   I(max)
-3.3V     -50.2mA    -36.94mA   -64.68mA
-1.1V     -46.2mA    -33.99mA   -59.51mA
-900mV    -45.16mA   -33.72mA   -53.33mA
-700mV    -40.66mA   -32.09mA   -48.9mA
-500mV    -35.74mA   -27.1mA    -45.14mA
-300mV    -23.24mA   -17.03mA   -29.89mA
300mV     22.47mA    16.13mA    29.3mA
800mV     53.52mA    37.74mA    70.95mA
1.3V      75.7mA     52.45mA    102mA
1.7V      85.57mA    58.78mA    116.3mA
2.5V      92.15mA    63.29mA    125.2mA
6.6V      106.7mA    73.66mA    144.3mA
[Pullup]
|Voltage   I(typ)   I(min)   I(max)
-3.3V     254.6mA    209.6mA    319mA
-2.1V     145mA      116.8mA    185.6mA
-1.5V     98.49mA    78.31mA    123.9mA
-1.3V     85.12mA    66.96mA    107.7mA
-1V       66.75mA    51.24mA    89.85mA
-600mV    44.1mA     34.07mA    58.63mA
500mV     -32.97mA   -24.66mA   -45.79mA
1V        -59.17mA   -43.58mA   -83.62mA
1.5V      -78.31mA   -56.66mA   -113mA
2V        -90.39mA   -63.99mA   -133.7mA
2.6V      -96.01mA   -66.92mA   -146mA
6.55V     -112.1mA   -77.8mA    -172mA
[GND_clamp]
|Voltage   I(typ)   I(min)   I(max)
-3.3V     -955.2mA   -930.2mA   -977.8mA
-1.2V     -86.08mA   -82.87mA   -94.74mA
-1.15V    -76.63mA   -73.22mA   -85.57mA
-1.1V     -67.6mA    -63.89mA   -77.12mA
-1V       -51.41mA   -46.51mA   -63.06mA
-900mV    -38.77mA   -31.82mA   -51.11mA
-800mV    -28.16mA   -20.53mA   -37.82mA
-700mV    -18.01mA   -11.58mA   -24.66mA
-600mV    -9.185mA   -5.219mA   -12.92mA
-450mV    -1.125mA   -553.6uA   -1.501mA
-300mV    0A         0A         0A
6.6V      0A         0A         0A
[POWER_clamp]
|Voltage   I(typ)   I(min)   I(max)
-3.25V    122.1mA    124.8mA    124.2mA
-2.65V    107.1mA    112.6mA    104.1mA
-2.35V    97.06mA    103.7mA    91.56mA
-2.05V    84.81mA    92.86mA    76.2mA
-1.65V    63.69mA    75.19mA    47.4mA
-1.35V    44.32mA    59.82mA    21.89mA
-1.25V    37.38mA    54.39mA    15.53mA
-850mV    10.3mA     31.63mA    860uA
-650mV    3.168mA    19.76mA    65.53uA
-350mV    73.34uA    3.862mA    3.121uA
-150mV    17.77uA    366.8uA    -28.16uA
6.6V      -130.5uA   -83.29uA   -201.6uA
[Ramp]
| variable   typ   min   max
dV/dt_r  1.4966/0.1403n   1.2936/0.1899n   1.7022/0.1278n
dV/dt_f  1.5290/0.1376n   1.3043/0.1782n   1.7112/0.1294n
R_load = 50.0000
[Rising Waveform]
R_fixture=   50.0000
V_fixture=   3.3000
V_fixture_min=   3.1400
V_fixture_max=   3.4700
|time   V(typ)   V(min)   V(max)
0s        751.6mV    966.1mV    618mV
505.1ps   751.7mV    966.1mV    683.2mV
606.1ps   750.6mV    966.1mV    2.934V
707.1ps   754.6mV    966.1mV    3.382V
808.1ps   1.707V     966.5mV    3.426V
909.1ps   2.998V     965.3mV    3.446V
1.111ns   3.252V     1.234V     3.462V
1.313ns   3.279V     2.738V     3.467V
1.515ns   3.291V     3.083V     3.469V
10ns      3.3V       3.14V      3.47V
[Rising Waveform]
R_fixture=   50.0000
V_fixture=   0.0
V_fixture_min=   0.0
V_fixture_max=   0.0
|time   V(typ)   V(min)   V(max)
0s        484.9nV    653.8nV    458.4nV
505.1ps   965.7nV    396.4nV    -61.92mV
707.1ps   -31.85mV   22.19uV    2.63V
808.1ps   22.23mV    16.02uV    2.743V
909.1ps   1.387V     -277.4uV   2.786V
1.01ns    2.195V     -10.24mV   2.808V
1.212ns   2.408V     -48.56mV   2.828V
1.515ns   2.468V     1.844V     2.835V
1.818ns   2.486V     2.075V     2.837V
10ns      2.494V     2.156V     2.837V
[Falling Waveform]
R_fixture=   50.0000
V_fixture=   0.0
V_fixture_min=   0.0
V_fixture_max=   0.0
|time   V(typ)   V(min)   V(max)
0s        2.494V     2.156V     2.837V
505.1ps   2.494V     2.156V     2.843V
606.1ps   2.495V     2.156V     849.6mV
808.1ps   2.408V     2.156V     36.53mV
909.1ps   515.2mV    2.156V     18.56mV
1.111ns   43.14mV    2.154V     4.92mV
1.212ns   25.35mV    2.154V     2.505mV
1.414ns   10.16mV    501mV      696.7uV
1.616ns   4.103mV    54.88mV    252.1uV
10ns      13.46uV    3.911uV    -10.62uV
[Falling Waveform]
R_fixture=   50.0000
V_fixture=   3.3000
V_fixture_min=   3.1400
V_fixture_max=   3.4700
|time   V(typ)   V(min)   V(max)
0s        3.3V       3.14V      3.47V
505.1ps   3.3V       3.14V      3.477V
707.1ps   3.295V     3.14V      824.1mV
808.1ps   3.329V     3.14V      683.9mV
909.1ps   2.014V     3.14V      649.9mV
1.01ns    1.056V     3.142V     634.8mV
1.313ns   784.9mV    3.118V     620.4mV
1.515ns   765.5mV    1.478V     618.6mV
1.818ns   755.5mV    1.032V     618.1mV
10ns      751.6mV    966.1mV    617.9mV
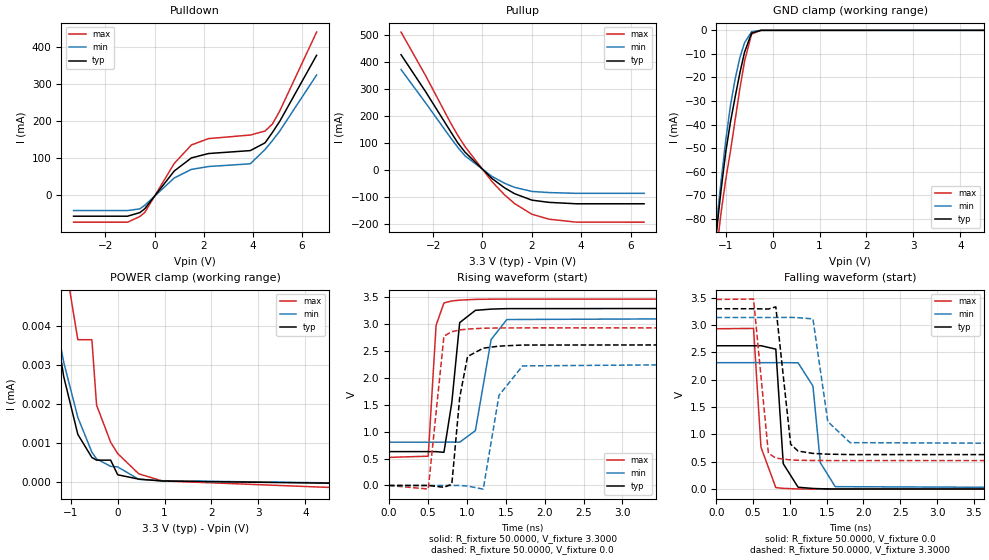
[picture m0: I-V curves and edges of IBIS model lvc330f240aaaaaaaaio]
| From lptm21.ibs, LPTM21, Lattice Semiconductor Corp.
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|   Model lvc330f240aaaaaaaaio
[Model]   lvc330f240aaaaaaaaio
Model_type   I/O
Polarity   Non-Inverting
Enable   Active-Low
Vinl =   0.8000V
Vinh =   2.0000V
Vmeas =   1.6500V
Cref =   0.0F
Rref =   1.0000M
Vref =   0.0V
C_comp   4.2000pF   3.8000pF   7.5000pF
[Temperature Range]   25.0000   0.1050k   -40.0000
[Voltage Range]   3.3000V   3.1400V   3.4700V
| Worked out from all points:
|   slope of the pulldown table from 0 to 0.495 V, typ, clamps not added: 11.5 ohm
|   slope of the pullup table from 0 to 0.495 V, typ, clamps not added: 12.5 ohm
|   GND clamp passes 1 mA (typ) near -0.44 V on its own axis
|   rising waveform, R_fixture 50.0000, V_fixture 3.3000: 20-80 % time 125ps typ, 166ps min, 73.3ps max; typ from 0.63 V to 3.3 V
|   rising waveform, R_fixture 50.0000, V_fixture 0.0: 20-80 % time 131ps typ, 168ps min, 125ps max; typ from 0 V to 2.62 V
|   falling waveform, R_fixture 50.0000, V_fixture 0.0: 20-80 % time 75.9ps typ, 104ps min, 99.7ps max; typ from 2.62 V to 0 V
|   falling waveform, R_fixture 50.0000, V_fixture 3.3000: 20-80 % time 129ps typ, 155ps min, 127ps max; typ from 3.3 V to 0.63 V
[Pulldown]
|Voltage   I(typ)   I(min)   I(max)
-3.3V     -56.93mA   -41.75mA   -73.18mA
-1.1V     -56.93mA   -41.75mA   -73.18mA
-600mV    -47.24mA   -37.04mA   -57.86mA
-400mV    -36.86mA   -27.43mA   -46.9mA
800mV     65.24mA    46.38mA    85.71mA
1.5V      100.7mA    69.7mA     135.7mA
2.2V      112.6mA    77.41mA    153mA
3.9V      120.5mA    84.82mA    162.6mA
4.5V      141.5mA    123.4mA    173.4mA
4.8V      169.6mA    147.5mA    192.3mA
5.1V      199.9mA    173.4mA    227.9mA
6.6V      378.3mA    325mA      441.1mA
[Pullup]
|Voltage   I(typ)   I(min)   I(max)
-3.3V     427.5mA    372.5mA    511.4mA
-2.3V     289.7mA    248.1mA    349.1mA
-1.3V     143.5mA    120.4mA    175.8mA
-1V       100.3mA    83.87mA    128.1mA
-700mV    65.36mA    51.75mA    85.79mA
400mV     -32.67mA   -24.69mA   -44.68mA
900mV     -66.59mA   -49.53mA   -92.73mA
1.3V      -87.89mA   -64.44mA   -124.5mA
2V        -111.9mA   -79.57mA   -164.2mA
2.7V      -120.2mA   -83.87mA   -182.6mA
3.8V      -125.4mA   -86.65mA   -193.5mA
6.55V     -125.4mA   -86.65mA   -193.7mA
[GND_clamp]
|Voltage   I(typ)   I(min)   I(max)
-3.3V     -955.3mA   -930.3mA   -978mA
-1.2V     -86.18mA   -82.93mA   -94.91mA
-1.15V    -76.73mA   -73.29mA   -85.74mA
-1.1V     -67.71mA   -63.95mA   -77.28mA
-1V       -51.52mA   -46.57mA   -63.21mA
-900mV    -38.87mA   -31.88mA   -51.26mA
-800mV    -28.25mA   -20.58mA   -37.97mA
-700mV    -18.1mA    -11.63mA   -24.81mA
-600mV    -9.267mA   -5.265mA   -13.06mA
-450mV    -1.181mA   -586.6uA   -1.592mA
-250mV    -3.532uA   -4.055uA   -3.003uA
6.6V      0A         0A         0A
[POWER_clamp]
|Voltage   I(typ)   I(min)   I(max)
-3.25V    664.8uA    749.4uA    597.1uA
-1.55V    5.917uA    5.715uA    11.4uA
-1.45V    4.99uA     4.976uA    9.754uA
-1.15V    2.706uA    3.076uA    5.866uA
-850mV    1.228uA    1.664uA    3.657uA
-550mV    633.7nA    768.9nA    3.657uA
-450mV    565.9nA    597.8nA    1.977uA
-150mV    565.9nA    406.5nA    1.026uA
0V        190.5nA    393.3nA    734.7nA
450mV     79.23nA    72.94nA    213.9nA
950mV     30.32nA    38.42nA    33.55nA
6.6V      -57.56nA   -49.34nA   -232.5nA
[Ramp]
| variable   typ   min   max
dV/dt_r  1.5736/0.1294n   1.3885/0.1665n   1.7602/0.1234n
dV/dt_f  1.6018/0.1273n   1.4002/0.1530n   1.7684/0.1254n
R_load = 50.0000
[Rising Waveform]
R_fixture=   50.0000
V_fixture=   3.3000
V_fixture_min=   3.1400
V_fixture_max=   3.4700
|time   V(typ)   V(min)   V(max)
0s        630.4mV    806.4mV    522.7mV
505.1ps   630.4mV    806.4mV    545.1mV
606.1ps   629.4mV    806.4mV    2.982V
707.1ps   617.4mV    806.4mV    3.398V
808.1ps   1.546V     806.7mV    3.435V
909.1ps   3.031V     805.7mV    3.45V
1.111ns   3.26V      1.021V     3.464V
1.313ns   3.283V     2.717V     3.468V
1.515ns   3.292V     3.089V     3.469V
10ns      3.3V       3.14V      3.47V
[Rising Waveform]
R_fixture=   50.0000
V_fixture=   0.0
V_fixture_min=   0.0
V_fixture_max=   0.0
|time   V(typ)   V(min)   V(max)
0s        401.5nV    548nV      376.4nV
505.1ps   -3.491uV   225.2nV    -66.27mV
707.1ps   -33.52mV   22.87uV    2.78V
808.1ps   22.39mV    2.363uV    2.863V
909.1ps   1.635V     -332.3uV   2.895V
1.01ns    2.4V       -10.53mV   2.912V
1.212ns   2.556V     -68.72mV   2.927V
1.414ns   2.594V     1.678V     2.932V
1.717ns   2.614V     2.226V     2.933V
10ns      2.623V     2.314V     2.934V
[Falling Waveform]
R_fixture=   50.0000
V_fixture=   0.0
V_fixture_min=   0.0
V_fixture_max=   0.0
|time   V(typ)   V(min)   V(max)
0s        2.623V     2.314V     2.934V
505.1ps   2.623V     2.314V     2.94V
606.1ps   2.624V     2.314V     767.1mV
808.1ps   2.561V     2.314V     29.09mV
909.1ps   465.6mV    2.314V     14.73mV
1.111ns   35.21mV    2.311V     3.87mV
1.313ns   13.04mV    1.886V     989.1uV
1.414ns   8.239mV    482mV      457.3uV
1.616ns   3.311mV    45.79mV    127.1uV
10ns      -17.41uV   5.463uV    -12.38uV
[Falling Waveform]
R_fixture=   50.0000
V_fixture=   3.3000
V_fixture_min=   3.1400
V_fixture_max=   3.4700
|time   V(typ)   V(min)   V(max)
0s        3.3V       3.14V      3.47V
505.1ps   3.3V       3.14V      3.477V
707.1ps   3.295V     3.14V      656.7mV
808.1ps   3.334V     3.14V      568mV
1.01ns    820.7mV    3.142V     534.4mV
1.111ns   697mV      3.136V     528.8mV
1.313ns   653.9mV    3.114V     524.3mV
1.515ns   640.1mV    1.236V     523.2mV
1.818ns   632.9mV    850.9mV    522.8mV
10ns      630.4mV    806.4mV    522.7mV
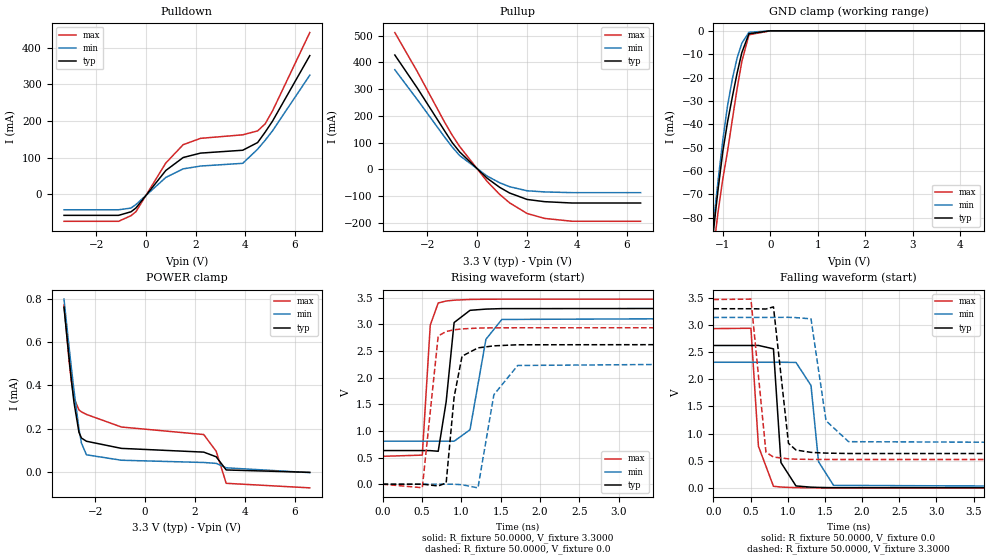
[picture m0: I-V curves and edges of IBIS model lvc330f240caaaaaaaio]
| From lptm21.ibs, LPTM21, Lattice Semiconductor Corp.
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|   Model lvc330f240caaaaaaaio
[Model]   lvc330f240caaaaaaaio
Model_type   I/O
Polarity   Non-Inverting
Enable   Active-Low
Vinl =   0.8000V
Vinh =   2.0000V
Vmeas =   1.6500V
Cref =   0.0F
Rref =   1.0000M
Vref =   0.0V
C_comp   4.2000pF   3.8000pF   7.5000pF
[Temperature Range]   25.0000   0.1050k   -40.0000
[Voltage Range]   3.3000V   3.1400V   3.4700V
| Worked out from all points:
|   slope of the pulldown table from 0 to 0.495 V, typ, clamps not added: 11.5 ohm
|   slope of the pullup table from 0 to 0.495 V, typ, clamps not added: 12.5 ohm
|   GND clamp passes 1 mA (typ) near -0.43 V on its own axis
|   rising waveform, R_fixture 50.0000, V_fixture 3.3000: 20-80 % time 125ps typ, 166ps min, 73.3ps max; typ from 0.63 V to 3.3 V
|   rising waveform, R_fixture 50.0000, V_fixture 0.0: 20-80 % time 131ps typ, 168ps min, 125ps max; typ from 0 V to 2.62 V
|   falling waveform, R_fixture 50.0000, V_fixture 0.0: 20-80 % time 75.9ps typ, 104ps min, 99.7ps max; typ from 2.62 V to 0 V
|   falling waveform, R_fixture 50.0000, V_fixture 3.3000: 20-80 % time 129ps typ, 155ps min, 127ps max; typ from 3.3 V to 0.63 V
[Pulldown]
|Voltage   I(typ)   I(min)   I(max)
-3.3V     -56.91mA   -41.73mA   -73.14mA
-1.1V     -56.91mA   -41.73mA   -73.14mA
-600mV    -47.19mA   -37.01mA   -57.8mA
-400mV    -36.78mA   -27.38mA   -46.77mA
800mV     65.15mA    46.34mA    85.54mA
1.5V      100.6mA    69.66mA    135.5mA
2.2V      112.6mA    77.36mA    152.8mA
3.9V      120.4mA    84.77mA    162.4mA
4.5V      141.4mA    123.3mA    173.2mA
4.8V      169.5mA    147.4mA    192.1mA
5.1V      199.8mA    173.3mA    227.7mA
6.6V      378.2mA    324.9mA    440.9mA
[Pullup]
|Voltage   I(typ)   I(min)   I(max)
-3.3V     427.4mA    372.4mA    511.2mA
-2.4V     304.1mA    261mA      365.6mA
-1.3V     143.4mA    120.4mA    175.6mA
-1V       100.2mA    83.82mA    127.9mA
-700mV    65.25mA    51.69mA    85.58mA
400mV     -32.78mA   -24.74mA   -44.88mA
900mV     -66.69mA   -49.58mA   -92.92mA
1.3V      -87.99mA   -64.49mA   -124.7mA
2V        -112mA     -79.62mA   -164.4mA
2.7V      -120.3mA   -83.91mA   -182.8mA
3.8V      -125.3mA   -86.6mA    -193.4mA
6.55V     -125.3mA   -86.6mA    -193.6mA
[GND_clamp]
|Voltage   I(typ)   I(min)   I(max)
-3.3V     -955.3mA   -930.3mA   -978mA
-1.2V     -86.21mA   -82.95mA   -94.94mA
-1.15V    -76.76mA   -73.31mA   -85.77mA
-1.1V     -67.73mA   -63.97mA   -77.32mA
-1V       -51.54mA   -46.59mA   -63.26mA
-900mV    -38.9mA    -31.9mA    -51.31mA
-800mV    -28.29mA   -20.61mA   -38.02mA
-700mV    -18.14mA   -11.66mA   -24.86mA
-600mV    -9.315mA   -5.302mA   -13.12mA
-450mV    -1.255mA   -637uA     -1.701mA
0V        0A         0A         0A
6.6V      0A         0A         0A
[POWER_clamp]
|Voltage   I(typ)   I(min)   I(max)
-3.25V    761uA      797.6uA    771.5uA
-3.05V    529.8uA    580.8uA    518.2uA
-2.95V    421.6uA    477.3uA    415.1uA
-2.85V    322.5uA    377.6uA    342uA
-2.65V    184.2uA    200uA      287.1uA
-2.55V    157.9uA    134.1uA    278.6uA
-2.35V    143.1uA    80.64uA    266.6uA
-950mV    110.3uA    55.66uA    208.7uA
2.35V     93.03uA    45.33uA    174uA
2.85V     71.52uA    41.08uA    96.73uA
3.25V     10.85uA    20.74uA    -50.58uA
6.6V      -56.35nA   -1.463uA   -71.55uA
[Ramp]
| variable   typ   min   max
dV/dt_r  1.5736/0.1294n   1.3885/0.1665n   1.7602/0.1234n
dV/dt_f  1.6018/0.1273n   1.4002/0.1530n   1.7684/0.1254n
R_load = 50.0000
[Rising Waveform]
R_fixture=   50.0000
V_fixture=   3.3000
V_fixture_min=   3.1400
V_fixture_max=   3.4700
|time   V(typ)   V(min)   V(max)
0s        630.4mV    806.4mV    522.7mV
505.1ps   630.4mV    806.4mV    545.1mV
606.1ps   629.4mV    806.4mV    2.982V
707.1ps   617.4mV    806.4mV    3.398V
808.1ps   1.546V     806.7mV    3.435V
909.1ps   3.031V     805.7mV    3.45V
1.111ns   3.26V      1.021V     3.464V
1.313ns   3.283V     2.717V     3.468V
1.515ns   3.292V     3.089V     3.469V
10ns      3.3V       3.14V      3.47V
[Rising Waveform]
R_fixture=   50.0000
V_fixture=   0.0
V_fixture_min=   0.0
V_fixture_max=   0.0
|time   V(typ)   V(min)   V(max)
0s        401.5nV    548nV      376.4nV
505.1ps   -3.491uV   225.2nV    -66.27mV
707.1ps   -33.52mV   22.87uV    2.78V
808.1ps   22.39mV    2.363uV    2.863V
909.1ps   1.635V     -332.3uV   2.895V
1.01ns    2.4V       -10.53mV   2.912V
1.212ns   2.556V     -68.72mV   2.927V
1.414ns   2.594V     1.678V     2.932V
1.717ns   2.614V     2.226V     2.933V
10ns      2.623V     2.314V     2.934V
[Falling Waveform]
R_fixture=   50.0000
V_fixture=   0.0
V_fixture_min=   0.0
V_fixture_max=   0.0
|time   V(typ)   V(min)   V(max)
0s        2.623V     2.314V     2.934V
505.1ps   2.623V     2.314V     2.94V
606.1ps   2.624V     2.314V     767.1mV
808.1ps   2.561V     2.314V     29.09mV
909.1ps   465.6mV    2.314V     14.73mV
1.111ns   35.21mV    2.311V     3.87mV
1.313ns   13.04mV    1.886V     989.1uV
1.414ns   8.239mV    482mV      457.3uV
1.616ns   3.311mV    45.79mV    127.1uV
10ns      -17.41uV   5.463uV    -12.38uV
[Falling Waveform]
R_fixture=   50.0000
V_fixture=   3.3000
V_fixture_min=   3.1400
V_fixture_max=   3.4700
|time   V(typ)   V(min)   V(max)
0s        3.3V       3.14V      3.47V
505.1ps   3.3V       3.14V      3.477V
707.1ps   3.295V     3.14V      656.7mV
808.1ps   3.334V     3.14V      568mV
1.01ns    820.7mV    3.142V     534.4mV
1.111ns   697mV      3.136V     528.8mV
1.313ns   653.9mV    3.114V     524.3mV
1.515ns   640.1mV    1.236V     523.2mV
1.818ns   632.9mV    850.9mV    522.8mV
10ns      630.4mV    806.4mV    522.7mV
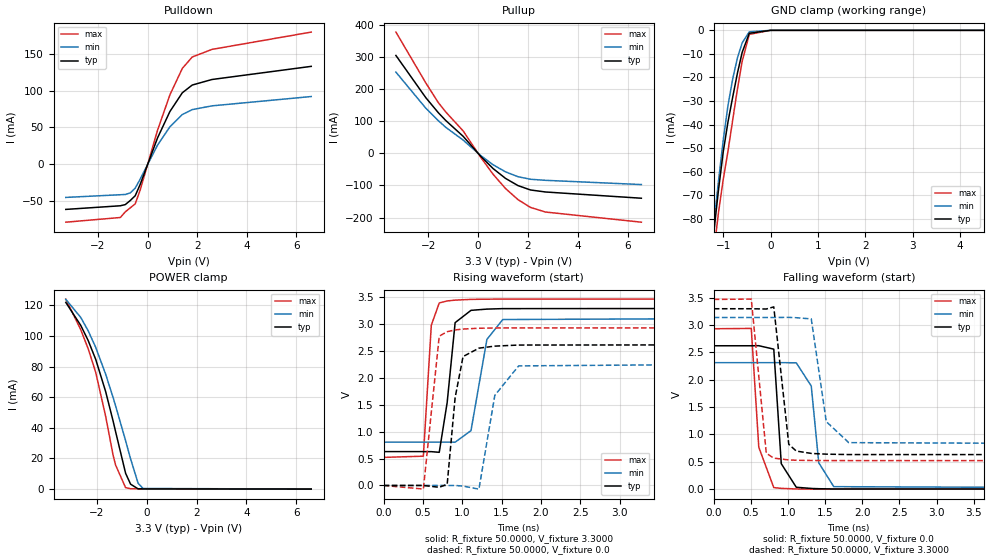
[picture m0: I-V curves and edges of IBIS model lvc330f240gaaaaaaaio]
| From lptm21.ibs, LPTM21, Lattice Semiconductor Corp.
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|   Model lvc330f240gaaaaaaaio
[Model]   lvc330f240gaaaaaaaio
Model_type   I/O
Polarity   Non-Inverting
Enable   Active-Low
Vinl =   0.8000V
Vinh =   2.0000V
Vmeas =   1.6500V
Cref =   0.0F
Rref =   1.0000M
Vref =   0.0V
C_comp   4.2000pF   3.8000pF   7.5000pF
[Temperature Range]   25.0000   0.1050k   -40.0000
[Voltage Range]   3.3000V   3.1400V   3.4700V
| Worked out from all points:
|   slope of the pulldown table from 0 to 0.495 V, typ, clamps not added: 11.5 ohm
|   slope of the pullup table from 0 to 0.495 V, typ, clamps not added: 12.5 ohm
|   GND clamp passes 1 mA (typ) near -0.43 V on its own axis
|   POWER clamp passes 1 mA (typ) near -0.53 V on its own axis
|   rising waveform, R_fixture 50.0000, V_fixture 3.3000: 20-80 % time 125ps typ, 166ps min, 73.3ps max; typ from 0.63 V to 3.3 V
|   rising waveform, R_fixture 50.0000, V_fixture 0.0: 20-80 % time 131ps typ, 168ps min, 125ps max; typ from 0 V to 2.62 V
|   falling waveform, R_fixture 50.0000, V_fixture 0.0: 20-80 % time 75.9ps typ, 104ps min, 99.7ps max; typ from 2.62 V to 0 V
|   falling waveform, R_fixture 50.0000, V_fixture 3.3000: 20-80 % time 129ps typ, 155ps min, 127ps max; typ from 3.3 V to 0.63 V
[Pulldown]
|Voltage   I(typ)   I(min)   I(max)
-3.3V     -62.09mA   -45.73mA   -79.55mA
-1.1V     -57.13mA   -42.06mA   -73.14mA
-900mV    -55.52mA   -41.73mA   -65.42mA
-700mV    -49.95mA   -39.56mA   -59.98mA
-500mV    -43.44mA   -33.11mA   -54.53mA
-300mV    -28mA      -20.72mA   -35.65mA
400mV     35.48mA    25.62mA    45.94mA
900mV     71.6mA     50.72mA    94.35mA
1.4V      97.13mA    67.46mA    130.4mA
1.8V      107.7mA    74.16mA    146mA
2.6V      115.3mA    79.29mA    156.4mA
6.6V      133.2mA    92.01mA    180mA
[Pullup]
|Voltage   I(typ)   I(min)   I(max)
-3.3V     305.4mA    253.4mA    378.3mA
-2.1V     173.7mA    141mA      219.7mA
-1.6V     127mA      102.1mA    158.6mA
-1.3V     102.6mA    81.31mA    129.2mA
-600mV    53.18mA    41.44mA    69.93mA
100mV     -8.72mA    -6.618mA   -11.87mA
600mV     -47.29mA   -35.49mA   -65.17mA
1.1V      -78mA      -57.59mA   -109.6mA
1.6V      -100.4mA   -72.69mA   -144.2mA
2.1V      -114mA     -80.65mA   -168.4mA
2.7V      -120.3mA   -83.91mA   -182.8mA
6.55V     -139.8mA   -97.16mA   -214.5mA
[GND_clamp]
|Voltage   I(typ)   I(min)   I(max)
-3.3V     -955.3mA   -930.3mA   -978mA
-1.2V     -86.21mA   -82.95mA   -94.94mA
-1.15V    -76.76mA   -73.31mA   -85.77mA
-1.1V     -67.73mA   -63.97mA   -77.32mA
-1V       -51.54mA   -46.59mA   -63.26mA
-900mV    -38.9mA    -31.9mA    -51.31mA
-800mV    -28.29mA   -20.61mA   -38.02mA
-700mV    -18.14mA   -11.66mA   -24.86mA
-600mV    -9.315mA   -5.302mA   -13.12mA
-450mV    -1.255mA   -637uA     -1.701mA
0V        0A         0A         0A
6.6V      0A         0A         0A
[POWER_clamp]
|Voltage   I(typ)   I(min)   I(max)
-3.25V    121.9mA    123.9mA    124.1mA
-2.65V    106.9mA    112.1mA    104.1mA
-2.35V    96.95mA    103.3mA    91.59mA
-2.05V    84.73mA    92.58mA    76.25mA
-1.65V    63.65mA    75mA       47.49mA
-1.35V    44.31mA    59.69mA    21.99mA
-1.25V    37.38mA    54.28mA    15.6mA
-850mV    10.32mA    31.58mA    939uA
-650mV    3.193mA    19.74mA    210uA
-350mV    132.1uA    3.862mA    199.7uA
-150mV    104.6uA    375.8uA    197.7uA
6.6V      -56.35nA   -1.463uA   -71.55uA
[Ramp]
| variable   typ   min   max
dV/dt_r  1.5736/0.1294n   1.3885/0.1665n   1.7602/0.1234n
dV/dt_f  1.6018/0.1273n   1.4002/0.1530n   1.7684/0.1254n
R_load = 50.0000
[Rising Waveform]
R_fixture=   50.0000
V_fixture=   3.3000
V_fixture_min=   3.1400
V_fixture_max=   3.4700
|time   V(typ)   V(min)   V(max)
0s        630.4mV    806.4mV    522.7mV
505.1ps   630.4mV    806.4mV    545.1mV
606.1ps   629.4mV    806.4mV    2.982V
707.1ps   617.4mV    806.4mV    3.398V
808.1ps   1.546V     806.7mV    3.435V
909.1ps   3.031V     805.7mV    3.45V
1.111ns   3.26V      1.021V     3.464V
1.313ns   3.283V     2.717V     3.468V
1.515ns   3.292V     3.089V     3.469V
10ns      3.3V       3.14V      3.47V
[Rising Waveform]
R_fixture=   50.0000
V_fixture=   0.0
V_fixture_min=   0.0
V_fixture_max=   0.0
|time   V(typ)   V(min)   V(max)
0s        401.5nV    548nV      376.4nV
505.1ps   -3.491uV   225.2nV    -66.27mV
707.1ps   -33.52mV   22.87uV    2.78V
808.1ps   22.39mV    2.363uV    2.863V
909.1ps   1.635V     -332.3uV   2.895V
1.01ns    2.4V       -10.53mV   2.912V
1.212ns   2.556V     -68.72mV   2.927V
1.414ns   2.594V     1.678V     2.932V
1.717ns   2.614V     2.226V     2.933V
10ns      2.623V     2.314V     2.934V
[Falling Waveform]
R_fixture=   50.0000
V_fixture=   0.0
V_fixture_min=   0.0
V_fixture_max=   0.0
|time   V(typ)   V(min)   V(max)
0s        2.623V     2.314V     2.934V
505.1ps   2.623V     2.314V     2.94V
606.1ps   2.624V     2.314V     767.1mV
808.1ps   2.561V     2.314V     29.09mV
909.1ps   465.6mV    2.314V     14.73mV
1.111ns   35.21mV    2.311V     3.87mV
1.313ns   13.04mV    1.886V     989.1uV
1.414ns   8.239mV    482mV      457.3uV
1.616ns   3.311mV    45.79mV    127.1uV
10ns      -17.41uV   5.463uV    -12.38uV
[Falling Waveform]
R_fixture=   50.0000
V_fixture=   3.3000
V_fixture_min=   3.1400
V_fixture_max=   3.4700
|time   V(typ)   V(min)   V(max)
0s        3.3V       3.14V      3.47V
505.1ps   3.3V       3.14V      3.477V
707.1ps   3.295V     3.14V      656.7mV
808.1ps   3.334V     3.14V      568mV
1.01ns    820.7mV    3.142V     534.4mV
1.111ns   697mV      3.136V     528.8mV
1.313ns   653.9mV    3.114V     524.3mV
1.515ns   640.1mV    1.236V     523.2mV
1.818ns   632.9mV    850.9mV    522.8mV
10ns      630.4mV    806.4mV    522.7mV
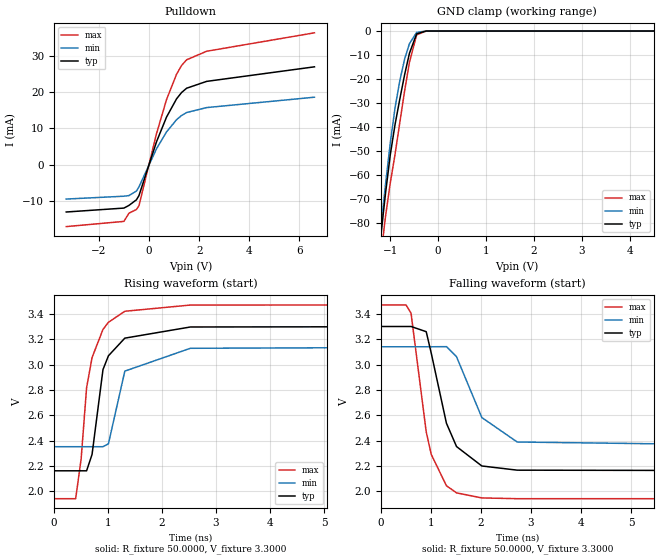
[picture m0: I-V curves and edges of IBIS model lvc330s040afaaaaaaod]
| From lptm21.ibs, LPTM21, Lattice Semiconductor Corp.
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|   Model lvc330s040afaaaaaaod
[Model]   lvc330s040afaaaaaaod
Model_type   I/O_open_drain
Polarity   Non-Inverting
Enable   Active-Low
Vinl =   0.8000V
Vinh =   2.0000V
Vmeas =   1.6500V
Cref =   0.0F
Rref =   1.0000M
Vref =   0.0V
C_comp   4.2000pF   3.8000pF   7.5000pF
[Temperature Range]   25.0000   0.1050k   -40.0000
[Voltage Range]   3.3000V   3.1400V   3.4700V
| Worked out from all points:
|   slope of the pulldown table from 0 to 0.495 V, typ, clamps not added: 50.3 ohm
|   GND clamp passes 1 mA (typ) near -0.44 V on its own axis
|   rising waveform, R_fixture 50.0000, V_fixture 3.3000: 20-80 % time 286ps typ, 308ps min, 285ps max; typ from 2.16 V to 3.3 V
|   falling waveform, R_fixture 50.0000, V_fixture 3.3000: 20-80 % time 448ps typ, 575ps min, 366ps max; typ from 3.3 V to 2.16 V
[Pulldown]
|Voltage   I(typ)   I(min)   I(max)
-3.3V     -13.05mA   -9.484mA   -17.07mA
-1V       -11.97mA   -8.699mA   -15.64mA
-800mV    -11.24mA   -8.53mA    -13.38mA
-500mV    -9.688mA   -7.272mA   -12.36mA
-400mV    -8.535mA   -6.131mA   -11.32mA
300mV     6.289mA    4.363mA    8.526mA
700mV     13.11mA    9.021mA    17.92mA
1.1V      18.13mA    12.38mA    24.92mA
1.3V      19.87mA    13.54mA    27.32mA
1.5V      21.05mA    14.35mA    28.88mA
2.3V      22.94mA    15.72mA    31.24mA
6.6V      26.95mA    18.58mA    36.32mA
[GND_clamp]
|Voltage   I(typ)   I(min)   I(max)
-3.3V     -955.3mA   -930.3mA   -978mA
-1.2V     -86.18mA   -82.93mA   -94.91mA
-1.15V    -76.73mA   -73.29mA   -85.74mA
-1.1V     -67.71mA   -63.95mA   -77.28mA
-1V       -51.52mA   -46.57mA   -63.21mA
-900mV    -38.87mA   -31.88mA   -51.26mA
-800mV    -28.25mA   -20.58mA   -37.97mA
-700mV    -18.1mA    -11.63mA   -24.81mA
-600mV    -9.267mA   -5.265mA   -13.06mA
-450mV    -1.181mA   -586.6uA   -1.592mA
-250mV    -3.532uA   -4.055uA   -3.003uA
6.6V      0A         0A         0A
[Ramp]
| variable   typ   min   max
dV/dt_r  0.6827/0.2835n   0.4730/0.3052n   0.9167/0.2822n
dV/dt_f  0.6827/0.4438n   0.4730/0.5693n   0.9167/0.3628n
R_load = 50.0000
[Rising Waveform]
R_fixture=   50.0000
V_fixture=   3.3000
V_fixture_min=   3.1400
V_fixture_max=   3.4700
|time   V(typ)   V(min)   V(max)
0s        2.162V     2.352V     1.942V
404ps     2.162V     2.352V     1.942V
505.1ps   2.162V     2.352V     2.256V
606.1ps   2.162V     2.352V     2.817V
707.1ps   2.291V     2.352V     3.055V
909.1ps   2.96V      2.352V     3.277V
1.01ns    3.069V     2.375V     3.333V
1.313ns   3.208V     2.948V     3.42V
2.525ns   3.296V     3.128V     3.469V
10ns      3.3V       3.14V      3.47V
[Falling Waveform]
R_fixture=   50.0000
V_fixture=   3.3000
V_fixture_min=   3.1400
V_fixture_max=   3.4700
|time   V(typ)   V(min)   V(max)
0s        3.3V       3.14V      3.47V
505.1ps   3.3V       3.14V      3.47V
606.1ps   3.3V       3.14V      3.405V
909.1ps   3.259V     3.14V      2.469V
1.01ns    3.089V     3.14V      2.291V
1.313ns   2.537V     3.141V     2.044V
1.515ns   2.353V     3.061V     1.988V
2.02ns    2.2V       2.582V     1.948V
2.727ns   2.167V     2.389V     1.942V
10ns      2.162V     2.352V     1.942V
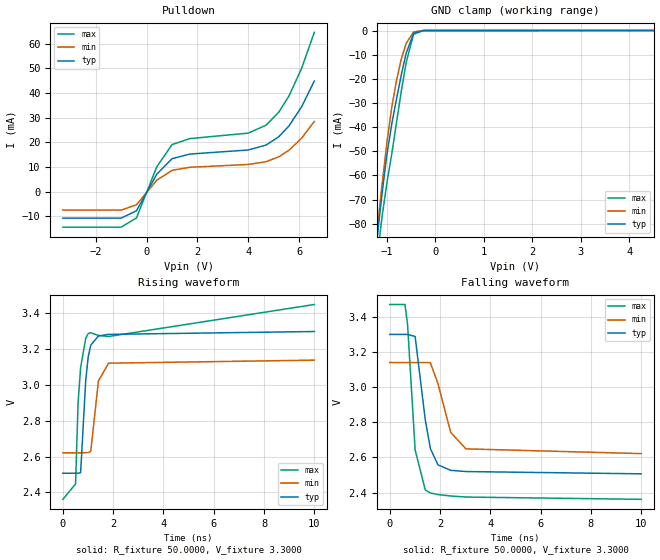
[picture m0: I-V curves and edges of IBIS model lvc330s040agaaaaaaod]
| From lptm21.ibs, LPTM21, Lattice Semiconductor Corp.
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|   Model lvc330s040agaaaaaaod
[Model]   lvc330s040agaaaaaaod
Model_type   I/O_open_drain
Polarity   Non-Inverting
Enable   Active-Low
Vinl =   0.8000V
Vinh =   2.0000V
Vmeas =   1.6500V
Cref =   0.0F
Rref =   1.0000M
Vref =   0.0V
C_comp   4.2000pF   3.8000pF   7.5000pF
[Temperature Range]   25.0000   0.1050k   -40.0000
[Voltage Range]   3.3000V   3.1400V   3.4700V
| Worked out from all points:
|   slope of the pulldown table from 0 to 0.495 V, typ, clamps not added: 58.8 ohm
|   GND clamp passes 1 mA (typ) near -0.44 V on its own axis
|   rising waveform, R_fixture 50.0000, V_fixture 3.3000: 20-80 % time 219ps typ, 236ps min, 325ps max; typ from 2.51 V to 3.3 V
|   falling waveform, R_fixture 50.0000, V_fixture 3.3000: 20-80 % time 421ps typ, 592ps min, 316ps max; typ from 3.3 V to 2.51 V
[Pulldown]
|Voltage   I(typ)   I(min)   I(max)
-3.3V     -10.78mA   -7.548mA   -14.46mA
-1V       -10.78mA   -7.548mA   -14.46mA
-400mV    -7.794mA   -5.358mA   -10.68mA
400mV     7.073mA    4.611mA    10.06mA
1V        13.32mA    8.58mA     19.04mA
1.7V      15.2mA     9.844mA    21.48mA
4V        16.85mA    10.97mA    23.69mA
4.7V      18.84mA    12.1mA     26.91mA
5.2V      22.21mA    14.07mA    32.16mA
5.6V      26.57mA    16.72mA    38.71mA
6.1V      34.35mA    21.62mA    49.96mA
6.6V      44.82mA    28.45mA    64.59mA
[GND_clamp]
|Voltage   I(typ)   I(min)   I(max)
-3.3V     -955.3mA   -930.3mA   -978mA
-1.2V     -86.17mA   -82.92mA   -94.88mA
-1.15V    -76.72mA   -73.28mA   -85.71mA
-1.1V     -67.69mA   -63.94mA   -77.25mA
-1V       -51.5mA    -46.56mA   -63.19mA
-900mV    -38.85mA   -31.87mA   -51.24mA
-800mV    -28.24mA   -20.57mA   -37.95mA
-700mV    -18.09mA   -11.63mA   -24.79mA
-600mV    -9.258mA   -5.26mA    -13.05mA
-450mV    -1.178mA   -585.4uA   -1.585mA
-250mV    -3.51uA    -4.042uA   -2.972uA
6.6V      0A         0A         0A
[Ramp]
| variable   typ   min   max
dV/dt_r  0.4578/0.3114n   0.2818/0.2727n   0.6647/0.2014n
dV/dt_f  0.4756/0.4166n   0.3106/0.5856n   0.6648/0.3125n
R_load = 50.0000
[Rising Waveform]
R_fixture=   50.0000
V_fixture=   3.3000
V_fixture_min=   3.1400
V_fixture_max=   3.4700
|time   V(typ)   V(min)   V(max)
0s        2.507V     2.621V     2.361V
505.1ps   2.507V     2.621V     2.447V
606.1ps   2.507V     2.621V     2.901V
707.1ps   2.51V      2.621V     3.098V
909.1ps   3.026V     2.622V     3.261V
1.01ns    3.159V     2.622V     3.288V
1.111ns   3.223V     2.63V      3.292V
1.414ns   3.274V     3.022V     3.277V
1.818ns   3.283V     3.122V     3.271V
10ns      3.299V     3.139V     3.45V
[Falling Waveform]
R_fixture=   50.0000
V_fixture=   3.3000
V_fixture_min=   3.1400
V_fixture_max=   3.4700
|time   V(typ)   V(min)   V(max)
0s        3.3V       3.14V      3.47V
606.1ps   3.3V       3.14V      3.47V
707.1ps   3.3V       3.14V      3.361V
1.01ns    3.288V     3.14V      2.644V
1.414ns   2.814V     3.14V      2.415V
1.616ns   2.651V     3.139V     2.398V
1.919ns   2.558V     3.019V     2.389V
2.424ns   2.527V     2.743V     2.381V
3.03ns    2.52V      2.649V     2.375V
10ns      2.507V     2.622V     2.362V
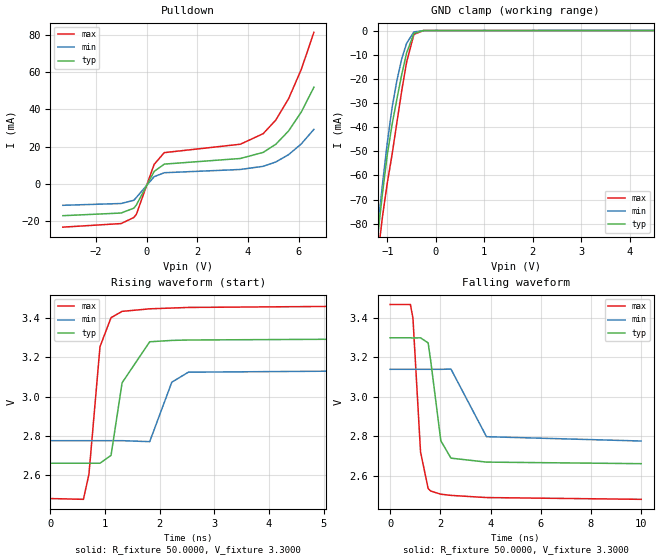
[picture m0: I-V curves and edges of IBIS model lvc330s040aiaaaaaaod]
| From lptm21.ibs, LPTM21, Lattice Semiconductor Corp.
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|   Model lvc330s040aiaaaaaaod
[Model]   lvc330s040aiaaaaaaod
Model_type   I/O_open_drain
Polarity   Non-Inverting
Enable   Active-Low
Vinl =   0.8000V
Vinh =   2.0000V
Vmeas =   1.6500V
Cref =   0.0F
Rref =   1.0000M
Vref =   0.0V
C_comp   4.2000pF   3.8000pF   7.5000pF
[Temperature Range]   25.0000   0.1050k   -40.0000
[Voltage Range]   3.3000V   3.1400V   3.4700V
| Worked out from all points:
|   slope of the pulldown table from 0 to 0.495 V, typ, clamps not added: 53.7 ohm
|   GND clamp passes 1 mA (typ) near -0.44 V on its own axis
|   rising waveform, R_fixture 50.0000, V_fixture 3.3000: 20-80 % time 238ps typ, 261ps min, 201ps max; typ from 2.66 V to 3.3 V
|   falling waveform, R_fixture 50.0000, V_fixture 3.3000: 20-80 % time 377ps typ, 553ps min, 284ps max; typ from 3.3 V to 2.66 V
[Pulldown]
|Voltage   I(typ)   I(min)   I(max)
-3.3V     -17.05mA   -11.48mA   -23.2mA
-1V       -15.62mA   -10.52mA   -21.27mA
-500mV    -13mA      -8.8mA     -18.01mA
-400mV    -11.29mA   -7.269mA   -16.31mA
300mV     6.67mA     3.859mA    10.47mA
700mV     10.61mA    5.993mA    16.77mA
3.7V      13.63mA    7.731mA    21.28mA
4.6V      16.9mA     9.432mA    26.94mA
5.1V      21.29mA    11.77mA    34.27mA
5.6V      28.37mA    15.67mA    45.65mA
6.1V      38.49mA    21.42mA    61.31mA
6.6V      51.83mA    29.25mA    81.29mA
[GND_clamp]
|Voltage   I(typ)   I(min)   I(max)
-3.3V     -955.3mA   -930.3mA   -978mA
-1.2V     -86.15mA   -82.88mA   -94.87mA
-1.15V    -76.7mA    -73.24mA   -85.7mA
-1.1V     -67.68mA   -63.91mA   -77.24mA
-1V       -51.49mA   -46.55mA   -63.18mA
-900mV    -38.84mA   -31.86mA   -51.23mA
-800mV    -28.23mA   -20.57mA   -37.94mA
-700mV    -18.08mA   -11.62mA   -24.78mA
-600mV    -9.252mA   -5.256mA   -13.04mA
-450mV    -1.175mA   -584.3uA   -1.581mA
-250mV    -3.493uA   -4.031uA   -2.954uA
6.6V      0A         0A         0A
[Ramp]
| variable   typ   min   max
dV/dt_r  0.3833/0.2358n   0.2186/0.2587n   0.5933/0.1986n
dV/dt_f  0.3832/0.3728n   0.2185/0.5471n   0.5933/0.2810n
R_load = 50.0000
[Rising Waveform]
R_fixture=   50.0000
V_fixture=   3.3000
V_fixture_min=   3.1400
V_fixture_max=   3.4700
|time   V(typ)   V(min)   V(max)
0s        2.66V      2.775V     2.48V
606.1ps   2.66V      2.775V     2.476V
707.1ps   2.66V      2.775V     2.604V
909.1ps   2.66V      2.775V     3.254V
1.111ns   2.7V       2.775V     3.402V
1.313ns   3.07V      2.775V     3.434V
1.818ns   3.279V     2.77V      3.447V
2.222ns   3.286V     3.073V     3.451V
2.525ns   3.288V     3.124V     3.454V
10ns      3.299V     3.139V     3.469V
[Falling Waveform]
R_fixture=   50.0000
V_fixture=   3.3000
V_fixture_min=   3.1400
V_fixture_max=   3.4700
|time   V(typ)   V(min)   V(max)
0s        3.3V       3.14V      3.469V
808.1ps   3.3V       3.14V      3.469V
909.1ps   3.299V     3.14V      3.4V
1.212ns   3.3V       3.14V      2.72V
1.515ns   3.274V     3.14V      2.535V
1.616ns   3.184V     3.14V      2.522V
2.02ns    2.777V     3.14V      2.506V
2.424ns   2.689V     3.141V     2.5V
3.838ns   2.669V     2.798V     2.489V
10ns      2.661V     2.776V     2.48V
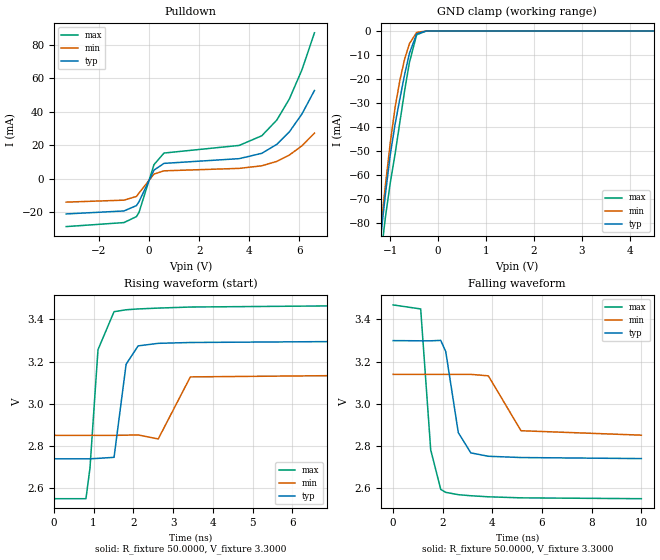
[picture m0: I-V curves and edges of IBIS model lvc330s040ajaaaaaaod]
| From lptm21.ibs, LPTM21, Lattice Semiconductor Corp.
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|   Model lvc330s040ajaaaaaaod
[Model]   lvc330s040ajaaaaaaod
Model_type   I/O_open_drain
Polarity   Non-Inverting
Enable   Active-Low
Vinl =   0.8000V
Vinh =   2.0000V
Vmeas =   1.6500V
Cref =   0.0F
Rref =   1.0000M
Vref =   0.0V
C_comp   4.2000pF   3.8000pF   7.5000pF
[Temperature Range]   25.0000   0.1050k   -40.0000
[Voltage Range]   3.3000V   3.1400V   3.4700V
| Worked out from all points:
|   slope of the pulldown table from 0 to 0.495 V, typ, clamps not added: 57.4 ohm
|   GND clamp passes 1 mA (typ) near -0.44 V on its own axis
|   rising waveform, R_fixture 50.0000, V_fixture 3.3000: 20-80 % time 228ps typ, 290ps min, 217ps max; typ from 2.74 V to 3.3 V
|   falling waveform, R_fixture 50.0000, V_fixture 3.3000: 20-80 % time 462ps typ, 722ps min, 326ps max; typ from 3.3 V to 2.74 V
[Pulldown]
|Voltage   I(typ)   I(min)   I(max)
-3.3V     -21.07mA   -14.02mA   -28.63mA
-1V       -19.3mA    -12.84mA   -26.24mA
-500mV    -16.11mA   -10.65mA   -22.67mA
-400mV    -13.8mA    -8.654mA   -20.23mA
200mV     5.106mA    2.747mA    8.391mA
600mV     9.114mA    4.67mA     15.29mA
3.6V      11.95mA    6.135mA    19.85mA
4.5V      15.13mA    7.672mA    25.61mA
5.1V      20.5mA     10.32mA    35.02mA
5.6V      27.97mA    14.1mA     47.63mA
6.1V      38.6mA     19.64mA    64.95mA
6.6V      52.65mA    27.19mA    87.09mA
[GND_clamp]
|Voltage   I(typ)   I(min)   I(max)
-3.3V     -955.3mA   -930.3mA   -978mA
-1.2V     -86.08mA   -82.81mA   -94.85mA
-1.15V    -76.64mA   -73.18mA   -85.69mA
-1.1V     -67.62mA   -63.85mA   -77.23mA
-1V       -51.45mA   -46.5mA    -63.17mA
-900mV    -38.82mA   -31.83mA   -51.22mA
-800mV    -28.22mA   -20.56mA   -37.94mA
-700mV    -18.08mA   -11.62mA   -24.78mA
-600mV    -9.25mA    -5.255mA   -13.04mA
-450mV    -1.175mA   -584uA     -1.58mA
-250mV    -3.488uA   -4.028uA   -2.949uA
6.6V      0A         0A         0A
[Ramp]
| variable   typ   min   max
dV/dt_r  0.3351/0.2255n   0.1729/0.2876n   0.5507/0.2145n
dV/dt_f  0.3350/0.4571n   0.1727/0.7152n   0.5507/0.3223n
R_load = 50.0000
[Rising Waveform]
R_fixture=   50.0000
V_fixture=   3.3000
V_fixture_min=   3.1400
V_fixture_max=   3.4700
|time   V(typ)   V(min)   V(max)
0s        2.74V      2.851V     2.551V
808.1ps   2.74V      2.851V     2.551V
909.1ps   2.74V      2.851V     2.696V
1.111ns   2.742V     2.851V     3.257V
1.515ns   2.747V     2.851V     3.437V
1.818ns   3.188V     2.852V     3.446V
2.121ns   3.275V     2.853V     3.45V
2.626ns   3.287V     2.834V     3.454V
3.434ns   3.291V     3.128V     3.459V
10ns      3.299V     3.139V     3.469V
[Falling Waveform]
R_fixture=   50.0000
V_fixture=   3.3000
V_fixture_min=   3.1400
V_fixture_max=   3.4700
|time   V(typ)   V(min)   V(max)
0s        3.3V       3.14V      3.469V
1.111ns   3.299V     3.14V      3.45V
1.515ns   3.299V     3.14V      2.782V
1.919ns   3.301V     3.14V      2.595V
2.121ns   3.248V     3.14V      2.581V
2.626ns   2.864V     3.14V      2.57V
3.131ns   2.768V     3.14V      2.565V
3.838ns   2.752V     3.133V     2.56V
5.152ns   2.746V     2.873V     2.555V
10ns      2.741V     2.852V     2.551V
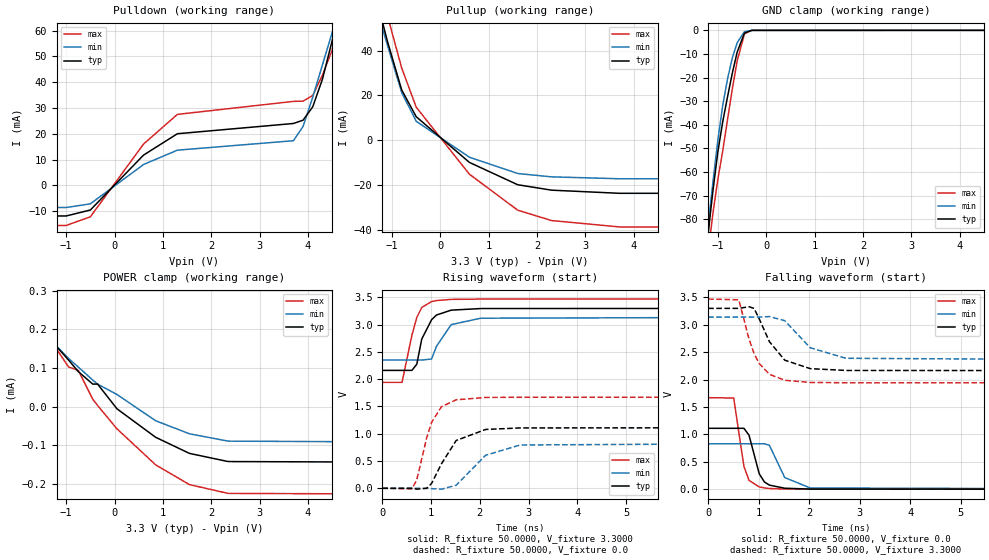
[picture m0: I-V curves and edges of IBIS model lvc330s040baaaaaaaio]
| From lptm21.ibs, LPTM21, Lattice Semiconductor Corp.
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|   Model lvc330s040baaaaaaaio
[Model]   lvc330s040baaaaaaaio
Model_type   I/O
Polarity   Non-Inverting
Enable   Active-Low
Vinl =   0.8000V
Vinh =   2.0000V
Vmeas =   1.500000V
Cref =   0.0F
Rref =   1.0000M
Vref =   0.0V
C_comp   4.2000pF   3.8000pF   7.5000pF
[Temperature Range]   25.0000   0.1050k   -40.0000
[Voltage Range]   3.3000V   3.1400V   3.4700V
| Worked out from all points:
|   slope of the pulldown table from 0 to 0.495 V, typ, clamps not added: 50.3 ohm
|   slope of the pullup table from 0 to 0.495 V, typ, clamps not added: 58.5 ohm
|   GND clamp passes 1 mA (typ) near -0.44 V on its own axis
|   rising waveform, R_fixture 50.0000, V_fixture 3.3000: 20-80 % time 264ps typ, 311ps min, 218ps max; typ from 2.16 V to 3.3 V
|   rising waveform, R_fixture 50.0000, V_fixture 0.0: 20-80 % time 438ps typ, 579ps min, 327ps max; typ from 0 V to 1.11 V
|   falling waveform, R_fixture 50.0000, V_fixture 0.0: 20-80 % time 219ps typ, 291ps min, 181ps max; typ from 1.11 V to 0 V
|   falling waveform, R_fixture 50.0000, V_fixture 3.3000: 20-80 % time 443ps typ, 565ps min, 361ps max; typ from 3.3 V to 2.16 V
[Pulldown]
|Voltage   I(typ)   I(min)   I(max)
-3.3V     -11.91mA   -8.63mA    -15.59mA
-1V       -11.91mA   -8.63mA    -15.59mA
-500mV    -9.593mA   -7.199mA   -12.23mA
600mV     11.72mA    8.07mA     16.01mA
1.3V      20.01mA    13.63mA    27.53mA
3.7V      23.99mA    17.3mA     32.57mA
3.9V      25.28mA    22.85mA    32.67mA
4.1V      30.47mA    34.23mA    34.88mA
4.3V      41.15mA    46.72mA    42.72mA
4.5V      56mA       59.18mA    52.45mA
4.6V      63.61mA    65.35mA    60.64mA
6.6V      186.4mA    170.2mA    211.9mA
[Pullup]
|Voltage   I(typ)   I(min)   I(max)
-3.3V     181.6mA    129.5mA    218.7mA
-1.4V     69.53mA    64.71mA    88.1mA
-1.3V     61.25mA    57.43mA    77.39mA
-1.2V     52.87mA    50.1mA     66.58mA
-1.1V     44.47mA    42.74mA    55.99mA
-800mV    22.38mA    21.23mA    32.17mA
-500mV    10.43mA    8.389mA    14.69mA
600mV     -9.992mA   -7.668mA   -15.26mA
1.6V      -19.98mA   -14.96mA   -31.34mA
2.3V      -22.4mA    -16.45mA   -35.98mA
3.7V      -23.8mA    -17.3mA    -38.82mA
6.55V     -23.8mA    -17.3mA    -38.94mA
[GND_clamp]
|Voltage   I(typ)   I(min)   I(max)
-3.3V     -955.2mA   -930.2mA   -977.8mA
-1.2V     -86.07mA   -82.87mA   -94.72mA
-1.15V    -76.63mA   -73.23mA   -85.56mA
-1.1V     -67.6mA    -63.89mA   -77.1mA
-1V       -51.41mA   -46.51mA   -63.05mA
-900mV    -38.77mA   -31.83mA   -51.09mA
-800mV    -28.16mA   -20.53mA   -37.81mA
-700mV    -18.01mA   -11.59mA   -24.66mA
-600mV    -9.192mA   -5.229mA   -12.92mA
-450mV    -1.151mA   -576.6uA   -1.527mA
-300mV    -17.4uA    -15.66uA   -11.6uA
6.6V      0A         0A         0A
[POWER_clamp]
|Voltage   I(typ)   I(min)   I(max)
-3.25V    961.3uA    1.05mA     917.9uA
-2.25V    305.8uA    299.5uA    344.1uA
-1.95V    260.5uA    253.4uA    288.8uA
-950mV    120.7uA    124.7uA    102.8uA
-750mV    90.82uA    102.7uA    94.17uA
-450mV    58.57uA    68.87uA    19.46uA
-350mV    58.57uA    58.54uA    3.121uA
50mV      -5.338uA   31.71uA    -57.16uA
850mV     -79.07uA   -36.24uA   -150.4uA
1.55V     -120.8uA   -70.05uA   -201.6uA
2.35V     -141.9uA   -89.06uA   -224.3uA
6.6V      -143.8uA   -91.66uA   -226.3uA
[Ramp]
| variable   typ   min   max
dV/dt_r  0.7026/0.4330n   0.4966/0.5731n   1.0018/0.3242n
dV/dt_f  0.6827/0.4387n   0.4730/0.5599n   0.9168/0.3576n
R_load = 50.0000
[Rising Waveform]
R_fixture=   50.0000
V_fixture=   3.3000
V_fixture_min=   3.1400
V_fixture_max=   3.4700
|time   V(typ)   V(min)   V(max)
0s        2.162V     2.352V     1.942V
404ps     2.162V     2.352V     1.942V
606.1ps   2.162V     2.352V     2.806V
707.1ps   2.276V     2.352V     3.134V
808.1ps   2.736V     2.352V     3.316V
1.01ns    3.091V     2.37V      3.424V
1.111ns   3.177V     2.605V     3.443V
1.414ns   3.267V     3.002V     3.464V
2.02ns    3.296V     3.119V     3.47V
10ns      3.3V       3.14V      3.47V
[Rising Waveform]
R_fixture=   50.0000
V_fixture=   0.0
V_fixture_min=   0.0
V_fixture_max=   0.0
|time   V(typ)   V(min)   V(max)
0s        1.288uV    1.554uV    1.323uV
606.1ps   -395.5uV   2.808uV    -9.94mV
707.1ps   -15.72mV   17.67uV    156.1mV
909.1ps   -458.6uV   -207.2uV   922.6mV
1.01ns    88.34mV    -6.184mV   1.209V
1.212ns   447.1mV    -16.04mV   1.495V
1.515ns   876.6mV    55.59mV    1.623V
2.121ns   1.079V     606.6mV    1.666V
2.828ns   1.107V     794.2mV    1.669V
10ns      1.111V     827.7mV    1.67V
[Falling Waveform]
R_fixture=   50.0000
V_fixture=   0.0
V_fixture_min=   0.0
V_fixture_max=   0.0
|time   V(typ)   V(min)   V(max)
0s        1.111V     827.7mV    1.67V
505.1ps   1.111V     827.7mV    1.664V
707.1ps   1.111V     827.7mV    415.7mV
808.1ps   985.1mV    827.7mV    161.2mV
1.01ns    281.4mV    828.2mV    40.87mV
1.111ns   132.9mV    828.5mV    22.94mV
1.212ns   73.68mV    799.7mV    12.45mV
1.515ns   17.1mV     211.6mV    2.151mV
2.02ns    2.152mV    21.8mV     239.2uV
10ns      -1.071uV   8.416uV    -6.671uV
[Falling Waveform]
R_fixture=   50.0000
V_fixture=   3.3000
V_fixture_min=   3.1400
V_fixture_max=   3.4700
|time   V(typ)   V(min)   V(max)
0s        3.3V       3.14V      3.47V
606.1ps   3.3V       3.14V      3.457V
808.1ps   3.33V      3.14V      2.74V
909.1ps   3.299V     3.14V      2.475V
1.01ns    3.108V     3.141V     2.293V
1.212ns   2.692V     3.151V     2.097V
1.515ns   2.355V     3.075V     1.988V
2.02ns    2.2V       2.581V     1.948V
2.727ns   2.167V     2.389V     1.942V
10ns      2.162V     2.352V     1.942V
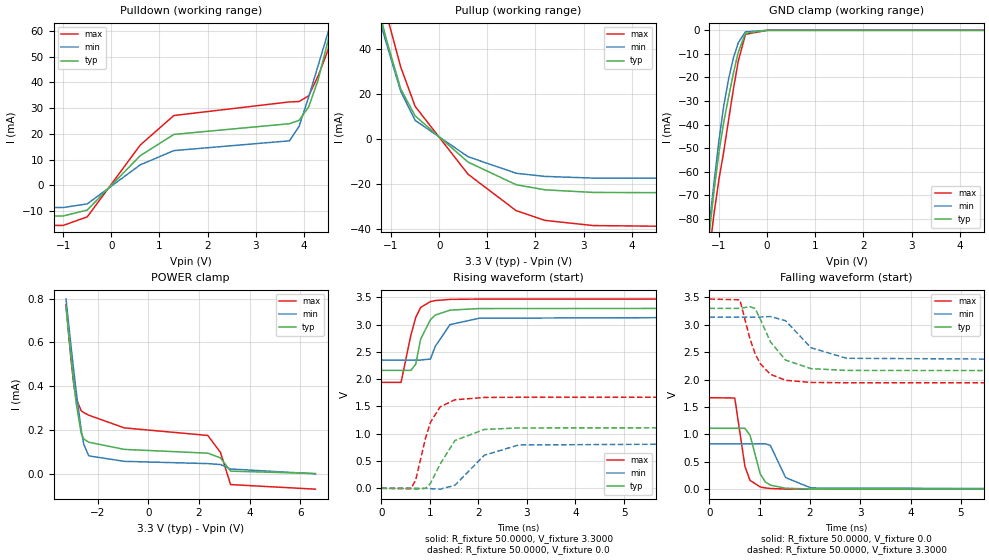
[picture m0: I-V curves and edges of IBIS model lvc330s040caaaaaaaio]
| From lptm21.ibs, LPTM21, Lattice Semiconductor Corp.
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|   Model lvc330s040caaaaaaaio
[Model]   lvc330s040caaaaaaaio
Model_type   I/O
Polarity   Non-Inverting
Enable   Active-Low
Vinl =   0.8000V
Vinh =   2.0000V
Vmeas =   1.500000V
Cref =   0.0F
Rref =   1.0000M
Vref =   0.0V
C_comp   4.2000pF   3.8000pF   7.5000pF
[Temperature Range]   25.0000   0.1050k   -40.0000
[Voltage Range]   3.3000V   3.1400V   3.4700V
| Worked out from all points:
|   slope of the pulldown table from 0 to 0.495 V, typ, clamps not added: 50.7 ohm
|   slope of the pullup table from 0 to 0.495 V, typ, clamps not added: 58.2 ohm
|   GND clamp passes 1 mA (typ) near -0.43 V on its own axis
|   rising waveform, R_fixture 50.0000, V_fixture 3.3000: 20-80 % time 264ps typ, 311ps min, 218ps max; typ from 2.16 V to 3.3 V
|   rising waveform, R_fixture 50.0000, V_fixture 0.0: 20-80 % time 438ps typ, 579ps min, 327ps max; typ from 0 V to 1.11 V
|   falling waveform, R_fixture 50.0000, V_fixture 0.0: 20-80 % time 219ps typ, 291ps min, 181ps max; typ from 1.11 V to 0 V
|   falling waveform, R_fixture 50.0000, V_fixture 3.3000: 20-80 % time 443ps typ, 565ps min, 361ps max; typ from 3.3 V to 2.16 V
[Pulldown]
|Voltage   I(typ)   I(min)   I(max)
-3.3V     -11.92mA   -8.642mA   -15.6mA
-1V       -11.92mA   -8.642mA   -15.6mA
-500mV    -9.624mA   -7.225mA   -12.27mA
600mV     11.49mA    7.938mA    15.62mA
1.3V      19.78mA    13.49mA    27.13mA
3.7V      23.94mA    17.29mA    32.41mA
3.9V      25.25mA    22.86mA    32.56mA
4.1V      30.46mA    34.27mA    34.78mA
4.3V      41.17mA    46.78mA    42.65mA
4.5V      56.04mA    59.26mA    52.42mA
4.6V      63.66mA    65.44mA    60.61mA
6.6V      186.6mA    170.5mA    212mA
[Pullup]
|Voltage   I(typ)   I(min)   I(max)
-3.3V     181.8mA    129.8mA    218.9mA
-1.4V     69.59mA    64.79mA    88.11mA
-1.3V     61.3mA     57.5mA     77.39mA
-1.2V     52.91mA    50.16mA    66.57mA
-1.1V     44.5mA     42.79mA    55.96mA
-800mV    22.37mA    21.25mA    32.1mA
-500mV    10.38mA    8.38mA     14.6mA
600mV     -10.14mA   -7.757mA   -15.54mA
1.6V      -20.19mA   -15.09mA   -31.71mA
2.2V      -22.45mA   -16.49mA   -36.01mA
3.2V      -23.59mA   -17.23mA   -38.3mA
6.55V     -23.86mA   -17.35mA   -39.03mA
[GND_clamp]
|Voltage   I(typ)   I(min)   I(max)
-3.3V     -955.3mA   -930.3mA   -978mA
-1.2V     -86.21mA   -82.95mA   -94.94mA
-1.15V    -76.76mA   -73.31mA   -85.77mA
-1.1V     -67.73mA   -63.97mA   -77.32mA
-1V       -51.54mA   -46.59mA   -63.26mA
-900mV    -38.9mA    -31.9mA    -51.31mA
-800mV    -28.29mA   -20.61mA   -38.02mA
-700mV    -18.14mA   -11.66mA   -24.86mA
-600mV    -9.315mA   -5.302mA   -13.12mA
-450mV    -1.255mA   -637uA     -1.701mA
0V        0A         0A         0A
6.6V      0A         0A         0A
[POWER_clamp]
|Voltage   I(typ)   I(min)   I(max)
-3.25V    761uA      797.6uA    771.5uA
-3.05V    529.8uA    580.8uA    518.2uA
-2.95V    421.6uA    477.3uA    415.1uA
-2.85V    322.5uA    377.6uA    342uA
-2.65V    184.2uA    200uA      287.1uA
-2.55V    157.9uA    134.1uA    278.6uA
-2.35V    143.1uA    80.64uA    266.6uA
-950mV    110.3uA    55.66uA    208.7uA
2.35V     93.03uA    45.33uA    174uA
2.85V     71.52uA    41.08uA    96.73uA
3.25V     10.85uA    20.74uA    -50.58uA
6.6V      -56.35nA   -1.463uA   -71.55uA
[Ramp]
| variable   typ   min   max
dV/dt_r  0.7026/0.4330n   0.4966/0.5731n   1.0018/0.3242n
dV/dt_f  0.6827/0.4387n   0.4730/0.5599n   0.9168/0.3576n
R_load = 50.0000
[Rising Waveform]
R_fixture=   50.0000
V_fixture=   3.3000
V_fixture_min=   3.1400
V_fixture_max=   3.4700
|time   V(typ)   V(min)   V(max)
0s        2.162V     2.352V     1.942V
404ps     2.162V     2.352V     1.942V
606.1ps   2.162V     2.352V     2.806V
707.1ps   2.276V     2.352V     3.134V
808.1ps   2.736V     2.352V     3.316V
1.01ns    3.091V     2.37V      3.424V
1.111ns   3.177V     2.605V     3.443V
1.414ns   3.267V     3.002V     3.464V
2.02ns    3.296V     3.119V     3.47V
10ns      3.3V       3.14V      3.47V
[Rising Waveform]
R_fixture=   50.0000
V_fixture=   0.0
V_fixture_min=   0.0
V_fixture_max=   0.0
|time   V(typ)   V(min)   V(max)
0s        1.288uV    1.554uV    1.323uV
606.1ps   -395.5uV   2.808uV    -9.94mV
707.1ps   -15.72mV   17.67uV    156.1mV
909.1ps   -458.6uV   -207.2uV   922.6mV
1.01ns    88.34mV    -6.184mV   1.209V
1.212ns   447.1mV    -16.04mV   1.495V
1.515ns   876.6mV    55.59mV    1.623V
2.121ns   1.079V     606.6mV    1.666V
2.828ns   1.107V     794.2mV    1.669V
10ns      1.111V     827.7mV    1.67V
[Falling Waveform]
R_fixture=   50.0000
V_fixture=   0.0
V_fixture_min=   0.0
V_fixture_max=   0.0
|time   V(typ)   V(min)   V(max)
0s        1.111V     827.7mV    1.67V
505.1ps   1.111V     827.7mV    1.664V
707.1ps   1.111V     827.7mV    415.7mV
808.1ps   985.1mV    827.7mV    161.2mV
1.01ns    281.4mV    828.2mV    40.87mV
1.111ns   132.9mV    828.5mV    22.94mV
1.212ns   73.68mV    799.7mV    12.45mV
1.515ns   17.1mV     211.6mV    2.151mV
2.02ns    2.152mV    21.8mV     239.2uV
10ns      -1.071uV   8.416uV    -6.671uV
[Falling Waveform]
R_fixture=   50.0000
V_fixture=   3.3000
V_fixture_min=   3.1400
V_fixture_max=   3.4700
|time   V(typ)   V(min)   V(max)
0s        3.3V       3.14V      3.47V
606.1ps   3.3V       3.14V      3.457V
808.1ps   3.33V      3.14V      2.74V
909.1ps   3.299V     3.14V      2.475V
1.01ns    3.108V     3.141V     2.293V
1.212ns   2.692V     3.151V     2.097V
1.515ns   2.355V     3.075V     1.988V
2.02ns    2.2V       2.581V     1.948V
2.727ns   2.167V     2.389V     1.942V
10ns      2.162V     2.352V     1.942V
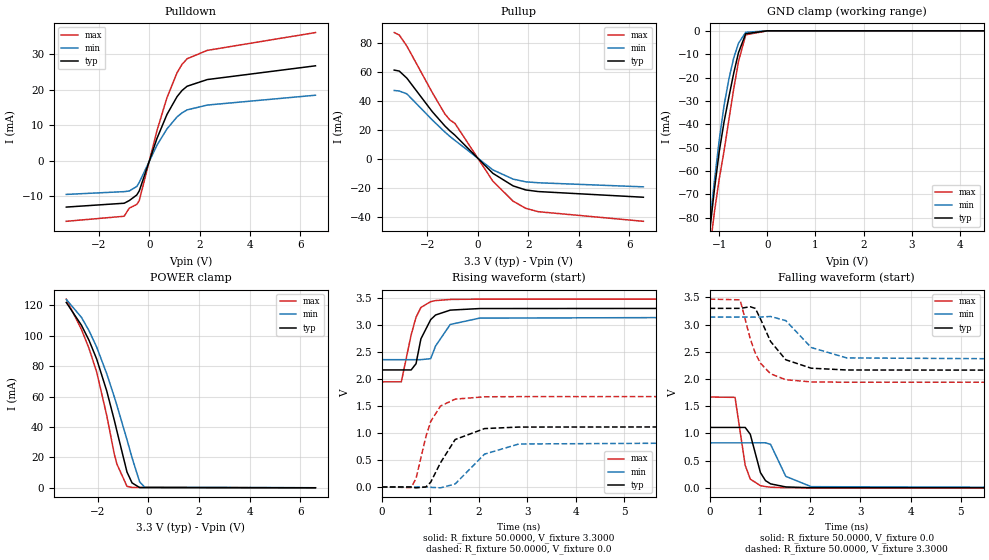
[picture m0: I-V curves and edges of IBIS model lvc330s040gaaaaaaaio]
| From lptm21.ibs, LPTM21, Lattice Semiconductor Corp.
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|   Model lvc330s040gaaaaaaaio
[Model]   lvc330s040gaaaaaaaio
Model_type   I/O
Polarity   Non-Inverting
Enable   Active-Low
Vinl =   0.8000V
Vinh =   2.0000V
Vmeas =   1.500000V
Cref =   0.0F
Rref =   1.0000M
Vref =   0.0V
C_comp   4.2000pF   3.8000pF   7.5000pF
[Temperature Range]   25.0000   0.1050k   -40.0000
[Voltage Range]   3.3000V   3.1400V   3.4700V
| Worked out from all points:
|   slope of the pulldown table from 0 to 0.495 V, typ, clamps not added: 50.7 ohm
|   slope of the pullup table from 0 to 0.495 V, typ, clamps not added: 58.2 ohm
|   GND clamp passes 1 mA (typ) near -0.43 V on its own axis
|   POWER clamp passes 1 mA (typ) near -0.53 V on its own axis
|   rising waveform, R_fixture 50.0000, V_fixture 3.3000: 20-80 % time 264ps typ, 311ps min, 218ps max; typ from 2.16 V to 3.3 V
|   rising waveform, R_fixture 50.0000, V_fixture 0.0: 20-80 % time 438ps typ, 579ps min, 327ps max; typ from 0 V to 1.11 V
|   falling waveform, R_fixture 50.0000, V_fixture 0.0: 20-80 % time 219ps typ, 291ps min, 181ps max; typ from 1.11 V to 0 V
|   falling waveform, R_fixture 50.0000, V_fixture 3.3000: 20-80 % time 443ps typ, 565ps min, 361ps max; typ from 3.3 V to 2.16 V
[Pulldown]
|Voltage   I(typ)   I(min)   I(max)
-3.3V     -13.02mA   -9.459mA   -17.02mA
-1V       -11.94mA   -8.676mA   -15.6mA
-800mV    -11.2mA    -8.504mA   -13.33mA
-500mV    -9.624mA   -7.225mA   -12.27mA
-400mV    -8.456mA   -6.081mA   -11.2mA
300mV     6.235mA    4.335mA    8.424mA
700mV     13.03mA    8.978mA    17.75mA
1.1V      18.03mA    12.33mA    24.74mA
1.3V      19.78mA    13.49mA    27.13mA
1.5V      20.96mA    14.31mA    28.69mA
2.3V      22.84mA    15.67mA    31.05mA
6.6V      26.71mA    18.44mA    36.06mA
[Pullup]
|Voltage   I(typ)   I(min)   I(max)
-3.3V     61.21mA    47.12mA    87.14mA
-3.1V     60.53mA    46.75mA    85.44mA
-2.8V     55.64mA    44.79mA    77.82mA
-1.8V     32.58mA    26.84mA    45.85mA
-1.3V     22.64mA    18.43mA    30.97mA
-1.1V     19.21mA    15.39mA    26.76mA
-900mV    16.22mA    12.62mA    24.4mA
600mV     -10.14mA   -7.757mA   -15.54mA
1.4V      -18.83mA   -14.15mA   -29.4mA
1.9V      -21.64mA   -16.02mA   -34.34mA
2.4V      -22.76mA   -16.68mA   -36.68mA
6.55V     -26.68mA   -19.5mA    -43.31mA
[GND_clamp]
|Voltage   I(typ)   I(min)   I(max)
-3.3V     -955.3mA   -930.3mA   -978mA
-1.2V     -86.21mA   -82.95mA   -94.94mA
-1.15V    -76.76mA   -73.31mA   -85.77mA
-1.1V     -67.73mA   -63.97mA   -77.32mA
-1V       -51.54mA   -46.59mA   -63.26mA
-900mV    -38.9mA    -31.9mA    -51.31mA
-800mV    -28.29mA   -20.61mA   -38.02mA
-700mV    -18.14mA   -11.66mA   -24.86mA
-600mV    -9.315mA   -5.302mA   -13.12mA
-450mV    -1.255mA   -637uA     -1.701mA
0V        0A         0A         0A
6.6V      0A         0A         0A
[POWER_clamp]
|Voltage   I(typ)   I(min)   I(max)
-3.25V    121.9mA    123.9mA    124.1mA
-2.65V    106.9mA    112.1mA    104.1mA
-2.35V    96.95mA    103.3mA    91.59mA
-2.05V    84.73mA    92.58mA    76.25mA
-1.65V    63.65mA    75mA       47.49mA
-1.35V    44.31mA    59.69mA    21.99mA
-1.25V    37.38mA    54.28mA    15.6mA
-850mV    10.32mA    31.58mA    939uA
-650mV    3.193mA    19.74mA    210uA
-350mV    132.1uA    3.862mA    199.7uA
-150mV    104.6uA    375.8uA    197.7uA
6.6V      -56.35nA   -1.463uA   -71.55uA
[Ramp]
| variable   typ   min   max
dV/dt_r  0.7026/0.4330n   0.4966/0.5731n   1.0018/0.3242n
dV/dt_f  0.6827/0.4387n   0.4730/0.5599n   0.9168/0.3576n
R_load = 50.0000
[Rising Waveform]
R_fixture=   50.0000
V_fixture=   3.3000
V_fixture_min=   3.1400
V_fixture_max=   3.4700
|time   V(typ)   V(min)   V(max)
0s        2.162V     2.352V     1.942V
404ps     2.162V     2.352V     1.942V
606.1ps   2.162V     2.352V     2.806V
707.1ps   2.276V     2.352V     3.134V
808.1ps   2.736V     2.352V     3.316V
1.01ns    3.091V     2.37V      3.424V
1.111ns   3.177V     2.605V     3.443V
1.414ns   3.267V     3.002V     3.464V
2.02ns    3.296V     3.119V     3.47V
10ns      3.3V       3.14V      3.47V
[Rising Waveform]
R_fixture=   50.0000
V_fixture=   0.0
V_fixture_min=   0.0
V_fixture_max=   0.0
|time   V(typ)   V(min)   V(max)
0s        1.288uV    1.554uV    1.323uV
606.1ps   -395.5uV   2.808uV    -9.94mV
707.1ps   -15.72mV   17.67uV    156.1mV
909.1ps   -458.6uV   -207.2uV   922.6mV
1.01ns    88.34mV    -6.184mV   1.209V
1.212ns   447.1mV    -16.04mV   1.495V
1.515ns   876.6mV    55.59mV    1.623V
2.121ns   1.079V     606.6mV    1.666V
2.828ns   1.107V     794.2mV    1.669V
10ns      1.111V     827.7mV    1.67V
[Falling Waveform]
R_fixture=   50.0000
V_fixture=   0.0
V_fixture_min=   0.0
V_fixture_max=   0.0
|time   V(typ)   V(min)   V(max)
0s        1.111V     827.7mV    1.67V
505.1ps   1.111V     827.7mV    1.664V
707.1ps   1.111V     827.7mV    415.7mV
808.1ps   985.1mV    827.7mV    161.2mV
1.01ns    281.4mV    828.2mV    40.87mV
1.111ns   132.9mV    828.5mV    22.94mV
1.212ns   73.68mV    799.7mV    12.45mV
1.515ns   17.1mV     211.6mV    2.151mV
2.02ns    2.152mV    21.8mV     239.2uV
10ns      -1.071uV   8.416uV    -6.671uV
[Falling Waveform]
R_fixture=   50.0000
V_fixture=   3.3000
V_fixture_min=   3.1400
V_fixture_max=   3.4700
|time   V(typ)   V(min)   V(max)
0s        3.3V       3.14V      3.47V
606.1ps   3.3V       3.14V      3.457V
808.1ps   3.33V      3.14V      2.74V
909.1ps   3.299V     3.14V      2.475V
1.01ns    3.108V     3.141V     2.293V
1.212ns   2.692V     3.151V     2.097V
1.515ns   2.355V     3.075V     1.988V
2.02ns    2.2V       2.581V     1.948V
2.727ns   2.167V     2.389V     1.942V
10ns      2.162V     2.352V     1.942V
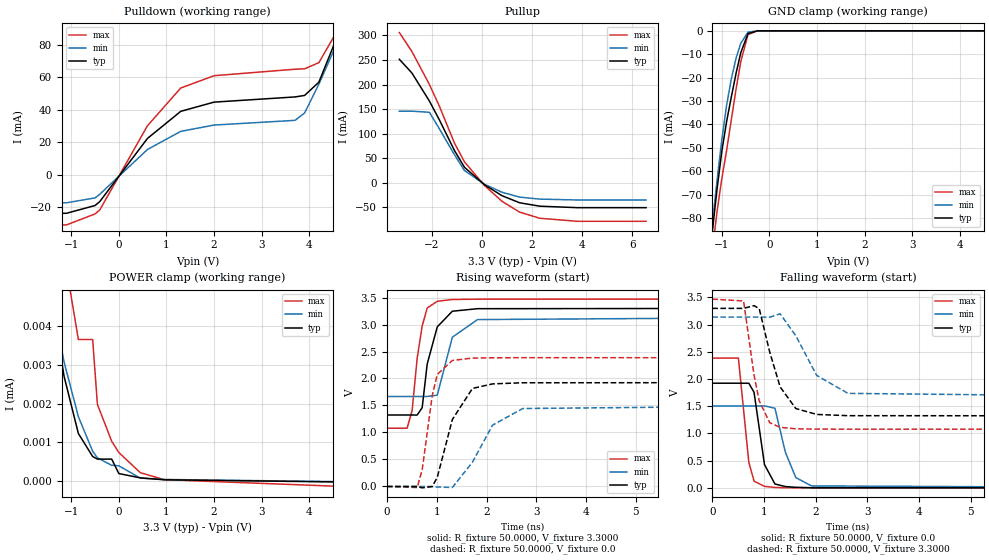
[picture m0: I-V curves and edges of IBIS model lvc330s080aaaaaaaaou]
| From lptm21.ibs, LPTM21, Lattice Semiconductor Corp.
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|   Model lvc330s080aaaaaaaaou
[Model]   lvc330s080aaaaaaaaou
Model_type   Output
Polarity   Non-Inverting
Enable   Active-Low
Vmeas =   1.500000V
Cref =   0.0F
Rref =   1.0000M
Vref =   0.0V
C_comp   4.2000pF   3.8000pF   7.5000pF
[Temperature Range]   25.0000   0.1050k   -40.0000
[Voltage Range]   3.3000V   3.1400V   3.4700V
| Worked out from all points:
|   slope of the pulldown table from 0 to 0.495 V, typ, clamps not added: 26 ohm
|   slope of the pullup table from 0 to 0.495 V, typ, clamps not added: 28.5 ohm
|   GND clamp passes 1 mA (typ) near -0.44 V on its own axis
|   rising waveform, R_fixture 50.0000, V_fixture 3.3000: 20-80 % time 251ps typ, 301ps min, 192ps max; typ from 1.32 V to 3.3 V
|   rising waveform, R_fixture 50.0000, V_fixture 0.0: 20-80 % time 363ps typ, 551ps min, 235ps max; typ from 0 V to 1.92 V
|   falling waveform, R_fixture 50.0000, V_fixture 0.0: 20-80 % time 188ps typ, 267ps min, 144ps max; typ from 1.92 V to 0 V
|   falling waveform, R_fixture 50.0000, V_fixture 3.3000: 20-80 % time 370ps typ, 535ps min, 253ps max; typ from 3.3 V to 1.32 V
[Pulldown]
|Voltage   I(typ)   I(min)   I(max)
-3.3V     -23.68mA   -17.2mA    -30.83mA
-1.1V     -23.68mA   -17.2mA    -30.83mA
-500mV    -18.89mA   -14.22mA   -24.07mA
-400mV    -16.44mA   -11.92mA   -21.58mA
600mV     22.43mA    15.62mA    30.22mA
1.3V      39.15mA    26.81mA    53.52mA
2V        44.82mA    30.69mA    61.1mA
3.7V      48.02mA    33.59mA    65.1mA
3.9V      48.94mA    38.13mA    65.35mA
4.2V      57.11mA    55.89mA    69.15mA
4.6V      86.19mA    82.47mA    89.45mA
6.6V      242.9mA    214.5mA    281.7mA
[Pullup]
|Voltage   I(typ)   I(min)   I(max)
-3.3V     251.3mA    145.8mA    305.6mA
-2.8V     223.5mA    145.8mA    267.3mA
-2.1V     166.4mA    143.5mA    200mA
-1.7V     127.9mA    109.7mA    155.7mA
-1.1V     65.82mA    57.34mA    80.93mA
-700mV    31.56mA    25.14mA    42.75mA
100mV     -3.836mA   -2.847mA   -5.414mA
800mV     -26.11mA   -19.07mA   -37.53mA
1.5V      -40.43mA   -28.94mA   -59.42mA
2.3V      -47.34mA   -33.02mA   -71.88mA
3.8V      -50.39mA   -34.76mA   -78.11mA
6.55V     -50.39mA   -34.76mA   -78.11mA
[GND_clamp]
|Voltage   I(typ)   I(min)   I(max)
-3.3V     -955.3mA   -930.3mA   -978mA
-1.2V     -86.18mA   -82.93mA   -94.91mA
-1.15V    -76.73mA   -73.29mA   -85.74mA
-1.1V     -67.71mA   -63.95mA   -77.28mA
-1V       -51.52mA   -46.57mA   -63.21mA
-900mV    -38.87mA   -31.88mA   -51.26mA
-800mV    -28.25mA   -20.58mA   -37.97mA
-700mV    -18.1mA    -11.63mA   -24.81mA
-600mV    -9.267mA   -5.265mA   -13.06mA
-450mV    -1.181mA   -586.6uA   -1.592mA
-250mV    -3.532uA   -4.055uA   -3.003uA
6.6V      0A         0A         0A
[POWER_clamp]
|Voltage   I(typ)   I(min)   I(max)
-3.25V    664.8uA    749.4uA    597.1uA
-1.55V    5.914uA    5.712uA    11.4uA
-1.45V    4.987uA    4.974uA    9.751uA
-1.15V    2.703uA    3.073uA    5.863uA
-850mV    1.226uA    1.662uA    3.655uA
-550mV    631.3nA    766.5nA    3.655uA
-450mV    563.6nA    595.5nA    1.977uA
-150mV    563.6nA    404.4nA    1.026uA
0V        190.5nA    391.2nA    734.7nA
450mV     79.23nA    72.94nA    213.9nA
950mV     30.32nA    38.42nA    33.55nA
6.6V      -57.56nA   -49.34nA   -232.5nA
[Ramp]
| variable   typ   min   max
dV/dt_r  1.1542/0.3590n   0.9035/0.5460n   1.4308/0.2329n
dV/dt_f  1.1855/0.3662n   0.8843/0.5297n   1.4345/0.2507n
R_load = 50.0000
[Rising Waveform]
R_fixture=   50.0000
V_fixture=   3.3000
V_fixture_min=   3.1400
V_fixture_max=   3.4700
|time   V(typ)   V(min)   V(max)
0s        1.324V     1.666V     1.079V
404ps     1.324V     1.666V     1.079V
505.1ps   1.324V     1.666V     1.407V
606.1ps   1.323V     1.666V     2.373V
707.1ps   1.46V      1.666V     2.973V
808.1ps   2.269V     1.667V     3.306V
1.01ns    2.956V     1.691V     3.43V
1.313ns   3.246V     2.765V     3.463V
1.818ns   3.293V     3.091V     3.469V
10ns      3.3V       3.14V      3.47V
[Rising Waveform]
R_fixture=   50.0000
V_fixture=   0.0
V_fixture_min=   0.0
V_fixture_max=   0.0
|time   V(typ)   V(min)   V(max)
0s        830nV      1.065uV    812.2nV
606.1ps   -647.3uV   2.343uV    -19.28mV
707.1ps   -25.56mV   18.24uV    307.2mV
909.1ps   -1.644mV   -352.6uV   1.685V
1.01ns    168.3mV    -10.05mV   2.075V
1.313ns   1.24V      -19.03mV   2.334V
1.717ns   1.816V     450.2mV    2.378V
2.121ns   1.9V       1.136V     2.384V
2.727ns   1.921V     1.444V     2.385V
10ns      1.924V     1.506V     2.385V
[Falling Waveform]
R_fixture=   50.0000
V_fixture=   0.0
V_fixture_min=   0.0
V_fixture_max=   0.0
|time   V(typ)   V(min)   V(max)
0s        1.924V     1.506V     2.385V
505.1ps   1.924V     1.506V     2.387V
707.1ps   1.923V     1.506V     469.1mV
808.1ps   1.757V     1.506V     123.1mV
1.01ns    427.9mV    1.507V     27.45mV
1.212ns   71.02mV    1.464V     7.412mV
1.414ns   24.43mV    655.3mV    2.129mV
1.616ns   9.884mV    189mV      652.9uV
1.919ns   2.628mV    35.9mV     184.5uV
10ns      -6.753uV   -8.585uV   -14.06uV
[Falling Waveform]
R_fixture=   50.0000
V_fixture=   3.3000
V_fixture_min=   3.1400
V_fixture_max=   3.4700
|time   V(typ)   V(min)   V(max)
0s        3.3V       3.14V      3.47V
606.1ps   3.3V       3.14V      3.436V
808.1ps   3.351V     3.14V      2.072V
909.1ps   3.292V     3.14V      1.597V
1.111ns   2.497V     3.138V     1.198V
1.313ns   1.855V     3.2V       1.113V
1.616ns   1.458V     2.796V     1.086V
2.02ns    1.35V      2.067V     1.08V
2.626ns   1.327V     1.737V     1.079V
10ns      1.324V     1.666V     1.079V
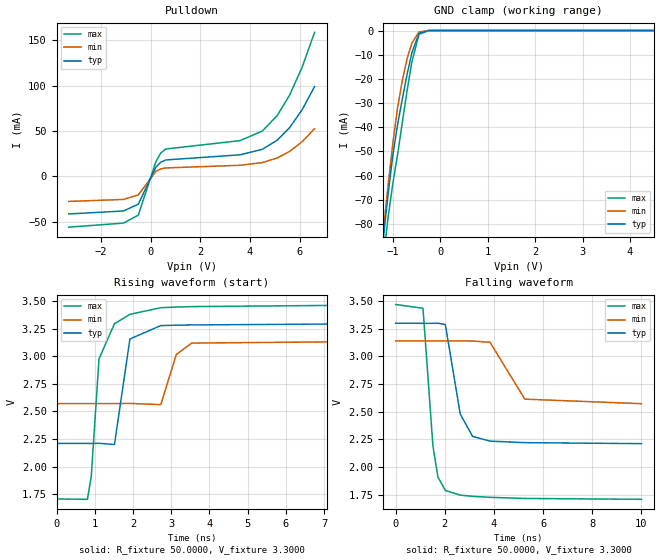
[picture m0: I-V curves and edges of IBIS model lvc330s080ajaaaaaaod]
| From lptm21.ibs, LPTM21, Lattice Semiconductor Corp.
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|   Model lvc330s080ajaaaaaaod
[Model]   lvc330s080ajaaaaaaod
Model_type   I/O_open_drain
Polarity   Non-Inverting
Enable   Active-Low
Vinl =   0.8000V
Vinh =   2.0000V
Vmeas =   1.6500V
Cref =   0.0F
Rref =   1.0000M
Vref =   0.0V
C_comp   4.2000pF   3.8000pF   7.5000pF
[Temperature Range]   25.0000   0.1050k   -40.0000
[Voltage Range]   3.3000V   3.1400V   3.4700V
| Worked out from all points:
|   slope of the pulldown table from 0 to 0.495 V, typ, clamps not added: 29 ohm
|   GND clamp passes 1 mA (typ) near -0.44 V on its own axis
|   rising waveform, R_fixture 50.0000, V_fixture 3.3000: 20-80 % time 236ps typ, 294ps min, 252ps max; typ from 2.21 V to 3.3 V
|   falling waveform, R_fixture 50.0000, V_fixture 3.3000: 20-80 % time 494ps typ, 760ps min, 344ps max; typ from 3.3 V to 2.21 V
[Pulldown]
|Voltage   I(typ)   I(min)   I(max)
-3.3V     -41.48mA   -27.64mA   -56.05mA
-1.1V     -38.19mA   -25.45mA   -51.59mA
-500mV    -30.67mA   -20.47mA   -42.72mA
200mV     9.819mA    5.383mA    15.71mA
400mV     15.59mA    8.207mA    25.68mA
600mV     18.09mA    9.309mA    30.19mA
3.6V      23.82mA    12.25mA    39.48mA
4.5V      29.89mA    15.25mA    50.13mA
5.1V      40.06mA    20.39mA    67.35mA
5.6V      54.03mA    27.69mA    90.03mA
6.1V      73.64mA    38.28mA    120.6mA
6.6V      99.15mA    52.58mA    159mA
[GND_clamp]
|Voltage   I(typ)   I(min)   I(max)
-3.3V     -955.3mA   -930.3mA   -978mA
-1.2V     -86.08mA   -82.81mA   -94.85mA
-1.15V    -76.64mA   -73.18mA   -85.69mA
-1.1V     -67.62mA   -63.85mA   -77.23mA
-1V       -51.45mA   -46.5mA    -63.17mA
-900mV    -38.82mA   -31.83mA   -51.22mA
-800mV    -28.22mA   -20.56mA   -37.94mA
-700mV    -18.08mA   -11.62mA   -24.78mA
-600mV    -9.25mA    -5.255mA   -13.04mA
-450mV    -1.175mA   -584uA     -1.58mA
-250mV    -3.488uA   -4.028uA   -2.949uA
6.6V      0A         0A         0A
[Ramp]
| variable   typ   min   max
dV/dt_r  0.6524/0.2341n   0.3406/0.2910n   1.0558/0.2493n
dV/dt_f  0.6524/0.4892n   0.3401/0.7521n   1.0558/0.3407n
R_load = 50.0000
[Rising Waveform]
R_fixture=   50.0000
V_fixture=   3.3000
V_fixture_min=   3.1400
V_fixture_max=   3.4700
|time   V(typ)   V(min)   V(max)
0s        2.211V     2.571V     1.708V
808.1ps   2.211V     2.571V     1.705V
909.1ps   2.21V      2.571V     1.917V
1.111ns   2.212V     2.571V     2.976V
1.515ns   2.201V     2.571V     3.294V
1.919ns   3.156V     2.573V     3.379V
2.727ns   3.277V     2.562V     3.439V
3.131ns   3.281V     3.015V     3.445V
3.535ns   3.283V     3.119V     3.449V
10ns      3.298V     3.138V     3.468V
[Falling Waveform]
R_fixture=   50.0000
V_fixture=   3.3000
V_fixture_min=   3.1400
V_fixture_max=   3.4700
|time   V(typ)   V(min)   V(max)
0s        3.3V       3.14V      3.469V
1.111ns   3.299V     3.14V      3.435V
1.515ns   3.299V     3.14V      2.192V
1.717ns   3.3V       3.14V      1.911V
2.02ns    3.288V     3.14V      1.789V
2.626ns   2.479V     3.14V      1.747V
3.131ns   2.277V     3.139V     1.736V
3.838ns   2.235V     3.128V     1.727V
5.253ns   2.221V     2.614V     1.717V
10ns      2.212V     2.573V     1.709V
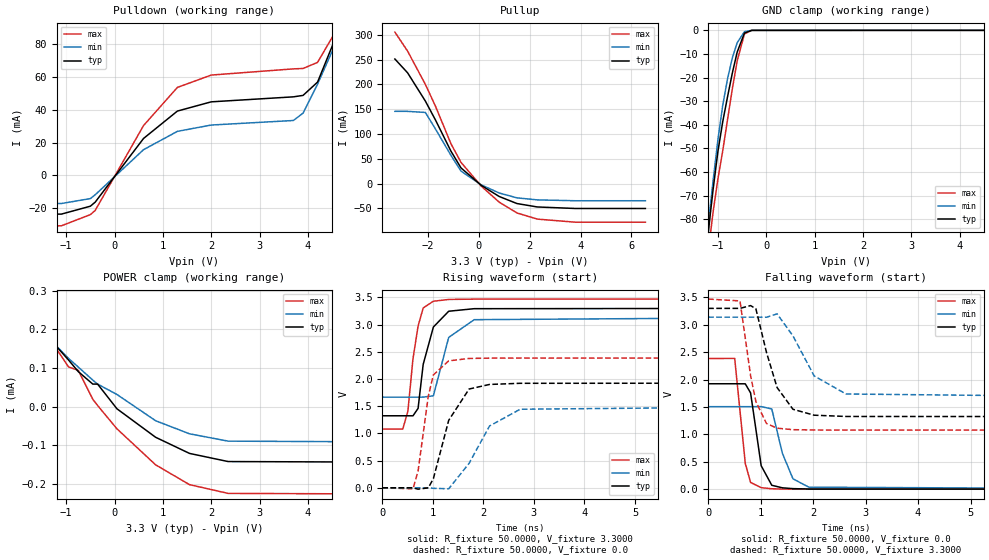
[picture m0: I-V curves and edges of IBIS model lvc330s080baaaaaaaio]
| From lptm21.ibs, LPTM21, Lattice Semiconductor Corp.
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|   Model lvc330s080baaaaaaaio
[Model]   lvc330s080baaaaaaaio
Model_type   I/O
Polarity   Non-Inverting
Enable   Active-Low
Vinl =   0.8000V
Vinh =   2.0000V
Vmeas =   1.500000V
Cref =   0.0F
Rref =   1.0000M
Vref =   0.0V
C_comp   4.2000pF   3.8000pF   7.5000pF
[Temperature Range]   25.0000   0.1050k   -40.0000
[Voltage Range]   3.3000V   3.1400V   3.4700V
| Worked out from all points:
|   slope of the pulldown table from 0 to 0.495 V, typ, clamps not added: 26 ohm
|   slope of the pullup table from 0 to 0.495 V, typ, clamps not added: 28.6 ohm
|   GND clamp passes 1 mA (typ) near -0.44 V on its own axis
|   rising waveform, R_fixture 50.0000, V_fixture 3.3000: 20-80 % time 251ps typ, 301ps min, 192ps max; typ from 1.32 V to 3.3 V
|   rising waveform, R_fixture 50.0000, V_fixture 0.0: 20-80 % time 363ps typ, 551ps min, 235ps max; typ from 0 V to 1.92 V
|   falling waveform, R_fixture 50.0000, V_fixture 0.0: 20-80 % time 188ps typ, 267ps min, 144ps max; typ from 1.92 V to 0 V
|   falling waveform, R_fixture 50.0000, V_fixture 3.3000: 20-80 % time 370ps typ, 535ps min, 253ps max; typ from 3.3 V to 1.32 V
[Pulldown]
|Voltage   I(typ)   I(min)   I(max)
-3.3V     -23.64mA   -17.16mA   -30.78mA
-1.1V     -23.64mA   -17.16mA   -30.78mA
-500mV    -18.8mA    -14.15mA   -23.94mA
-400mV    -16.31mA   -11.83mA   -21.38mA
600mV     22.57mA    15.71mA    30.45mA
1.3V      39.29mA    26.9mA     53.73mA
2V        44.93mA    30.76mA    61.28mA
3.7V      47.98mA    33.54mA    65.06mA
3.9V      48.87mA    38.07mA    65.3mA
4.2V      57mA       55.79mA    69.03mA
4.6V      86.02mA    82.33mA    89.26mA
6.6V      242.6mA    214.2mA    281.4mA
[Pullup]
|Voltage   I(typ)   I(min)   I(max)
-3.3V     251mA      145.5mA    305.3mA
-2.8V     223.2mA    145.5mA    266.9mA
-2.1V     166.1mA    143.3mA    199.7mA
-1.7V     127.7mA    109.5mA    155.4mA
-1.1V     65.68mA    57.23mA    80.74mA
-700mV    31.48mA    25.08mA    42.64mA
100mV     -3.825mA   -2.839mA   -5.398mA
800mV     -26.04mA   -19.02mA   -37.42mA
1.5V      -40.31mA   -28.86mA   -59.25mA
2.3V      -47.2mA    -32.93mA   -71.66mA
3.8V      -50.26mA   -34.67mA   -77.89mA
6.55V     -50.26mA   -34.67mA   -77.89mA
[GND_clamp]
|Voltage   I(typ)   I(min)   I(max)
-3.3V     -955.2mA   -930.2mA   -977.8mA
-1.2V     -86.07mA   -82.87mA   -94.72mA
-1.15V    -76.63mA   -73.23mA   -85.56mA
-1.1V     -67.6mA    -63.89mA   -77.1mA
-1V       -51.41mA   -46.51mA   -63.05mA
-900mV    -38.77mA   -31.83mA   -51.09mA
-800mV    -28.16mA   -20.53mA   -37.81mA
-700mV    -18.01mA   -11.59mA   -24.66mA
-600mV    -9.192mA   -5.229mA   -12.92mA
-450mV    -1.151mA   -576.6uA   -1.527mA
-300mV    -17.4uA    -15.66uA   -11.6uA
6.6V      0A         0A         0A
[POWER_clamp]
|Voltage   I(typ)   I(min)   I(max)
-3.25V    961.3uA    1.05mA     917.9uA
-2.25V    305.8uA    299.5uA    344.1uA
-1.95V    260.5uA    253.4uA    288.8uA
-950mV    120.7uA    124.7uA    102.8uA
-750mV    90.82uA    102.7uA    94.17uA
-450mV    58.57uA    68.87uA    19.46uA
-350mV    58.57uA    58.54uA    3.121uA
50mV      -5.338uA   31.71uA    -57.16uA
850mV     -79.07uA   -36.24uA   -150.4uA
1.55V     -120.8uA   -70.05uA   -201.6uA
2.35V     -141.9uA   -89.06uA   -224.3uA
6.6V      -143.8uA   -91.66uA   -226.3uA
[Ramp]
| variable   typ   min   max
dV/dt_r  1.1542/0.3590n   0.9035/0.5460n   1.4308/0.2329n
dV/dt_f  1.1855/0.3662n   0.8843/0.5297n   1.4345/0.2507n
R_load = 50.0000
[Rising Waveform]
R_fixture=   50.0000
V_fixture=   3.3000
V_fixture_min=   3.1400
V_fixture_max=   3.4700
|time   V(typ)   V(min)   V(max)
0s        1.324V     1.666V     1.079V
404ps     1.324V     1.666V     1.079V
505.1ps   1.324V     1.666V     1.407V
606.1ps   1.323V     1.666V     2.373V
707.1ps   1.46V      1.666V     2.973V
808.1ps   2.269V     1.667V     3.306V
1.01ns    2.956V     1.691V     3.43V
1.313ns   3.246V     2.765V     3.463V
1.818ns   3.293V     3.091V     3.469V
10ns      3.3V       3.14V      3.47V
[Rising Waveform]
R_fixture=   50.0000
V_fixture=   0.0
V_fixture_min=   0.0
V_fixture_max=   0.0
|time   V(typ)   V(min)   V(max)
0s        830nV      1.065uV    812.2nV
606.1ps   -647.3uV   2.343uV    -19.28mV
707.1ps   -25.56mV   18.24uV    307.2mV
909.1ps   -1.644mV   -352.6uV   1.685V
1.01ns    168.3mV    -10.05mV   2.075V
1.313ns   1.24V      -19.03mV   2.334V
1.717ns   1.816V     450.2mV    2.378V
2.121ns   1.9V       1.136V     2.384V
2.727ns   1.921V     1.444V     2.385V
10ns      1.924V     1.506V     2.385V
[Falling Waveform]
R_fixture=   50.0000
V_fixture=   0.0
V_fixture_min=   0.0
V_fixture_max=   0.0
|time   V(typ)   V(min)   V(max)
0s        1.924V     1.506V     2.385V
505.1ps   1.924V     1.506V     2.387V
707.1ps   1.923V     1.506V     469.1mV
808.1ps   1.757V     1.506V     123.1mV
1.01ns    427.9mV    1.507V     27.45mV
1.212ns   71.02mV    1.464V     7.412mV
1.414ns   24.43mV    655.3mV    2.129mV
1.616ns   9.884mV    189mV      652.9uV
1.919ns   2.628mV    35.9mV     184.5uV
10ns      -6.753uV   -8.585uV   -14.06uV
[Falling Waveform]
R_fixture=   50.0000
V_fixture=   3.3000
V_fixture_min=   3.1400
V_fixture_max=   3.4700
|time   V(typ)   V(min)   V(max)
0s        3.3V       3.14V      3.47V
606.1ps   3.3V       3.14V      3.436V
808.1ps   3.351V     3.14V      2.072V
909.1ps   3.292V     3.14V      1.597V
1.111ns   2.497V     3.138V     1.198V
1.313ns   1.855V     3.2V       1.113V
1.616ns   1.458V     2.796V     1.086V
2.02ns    1.35V      2.067V     1.08V
2.626ns   1.327V     1.737V     1.079V
10ns      1.324V     1.666V     1.079V
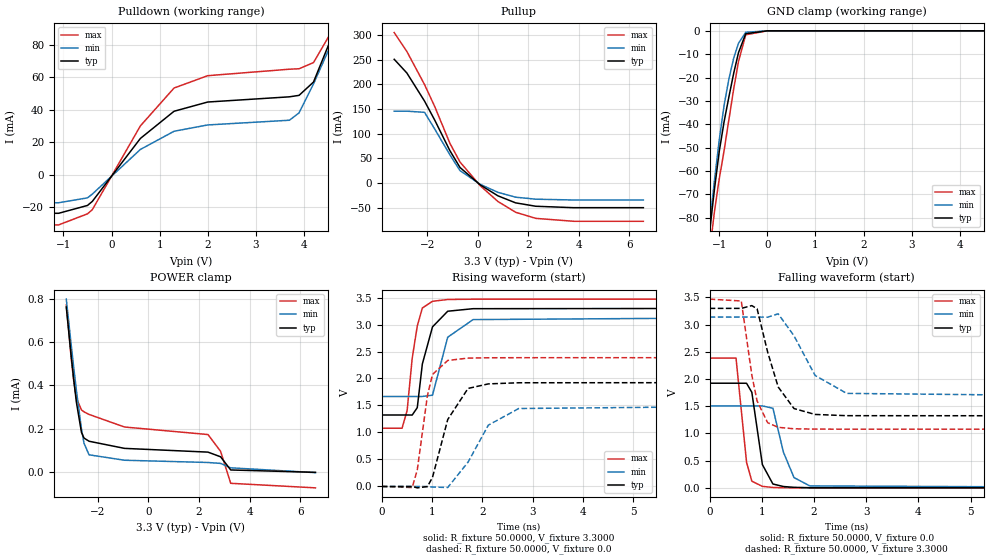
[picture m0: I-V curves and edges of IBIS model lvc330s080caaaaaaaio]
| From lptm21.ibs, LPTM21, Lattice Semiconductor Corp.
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|   Model lvc330s080caaaaaaaio
[Model]   lvc330s080caaaaaaaio
Model_type   I/O
Polarity   Non-Inverting
Enable   Active-Low
Vinl =   0.8000V
Vinh =   2.0000V
Vmeas =   1.500000V
Cref =   0.0F
Rref =   1.0000M
Vref =   0.0V
C_comp   4.2000pF   3.8000pF   7.5000pF
[Temperature Range]   25.0000   0.1050k   -40.0000
[Voltage Range]   3.3000V   3.1400V   3.4700V
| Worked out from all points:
|   slope of the pulldown table from 0 to 0.495 V, typ, clamps not added: 26.1 ohm
|   slope of the pullup table from 0 to 0.495 V, typ, clamps not added: 28.5 ohm
|   GND clamp passes 1 mA (typ) near -0.43 V on its own axis
|   rising waveform, R_fixture 50.0000, V_fixture 3.3000: 20-80 % time 251ps typ, 301ps min, 192ps max; typ from 1.32 V to 3.3 V
|   rising waveform, R_fixture 50.0000, V_fixture 0.0: 20-80 % time 363ps typ, 551ps min, 235ps max; typ from 0 V to 1.92 V
|   falling waveform, R_fixture 50.0000, V_fixture 0.0: 20-80 % time 188ps typ, 267ps min, 144ps max; typ from 1.92 V to 0 V
|   falling waveform, R_fixture 50.0000, V_fixture 3.3000: 20-80 % time 370ps typ, 535ps min, 253ps max; typ from 3.3 V to 1.32 V
[Pulldown]
|Voltage   I(typ)   I(min)   I(max)
-3.3V     -23.65mA   -17.18mA   -30.79mA
-1.1V     -23.65mA   -17.18mA   -30.79mA
-500mV    -18.83mA   -14.17mA   -23.98mA
-400mV    -16.36mA   -11.87mA   -21.45mA
600mV     22.34mA    15.58mA    30.06mA
1.3V      39.05mA    26.76mA    53.33mA
2V        44.73mA    30.64mA    60.92mA
3.7V      47.93mA    33.54mA    64.9mA
3.9V      48.83mA    38.08mA    65.19mA
4.2V      57mA       55.83mA    68.95mA
4.6V      86.08mA    82.42mA    89.23mA
6.6V      242.8mA    214.4mA    281.6mA
[Pullup]
|Voltage   I(typ)   I(min)   I(max)
-3.3V     251.2mA    145.8mA    305.5mA
-2.8V     223.4mA    145.8mA    267.1mA
-2.1V     166.2mA    143.4mA    199.8mA
-1.7V     127.8mA    109.6mA    155.4mA
-1.1V     65.71mA    57.29mA    80.71mA
-700mV    31.45mA    25.09mA    42.55mA
100mV     -3.939mA   -2.896mA   -5.611mA
800mV     -26.21mA   -19.12mA   -37.72mA
1.5V      -40.52mA   -28.98mA   -59.61mA
2.3V      -47.43mA   -33.07mA   -72.06mA
3.8V      -50.32mA   -34.71mA   -77.98mA
6.55V     -50.32mA   -34.71mA   -77.98mA
[GND_clamp]
|Voltage   I(typ)   I(min)   I(max)
-3.3V     -955.3mA   -930.3mA   -978mA
-1.2V     -86.21mA   -82.95mA   -94.94mA
-1.15V    -76.76mA   -73.31mA   -85.77mA
-1.1V     -67.73mA   -63.97mA   -77.32mA
-1V       -51.54mA   -46.59mA   -63.26mA
-900mV    -38.9mA    -31.9mA    -51.31mA
-800mV    -28.29mA   -20.61mA   -38.02mA
-700mV    -18.14mA   -11.66mA   -24.86mA
-600mV    -9.315mA   -5.302mA   -13.12mA
-450mV    -1.255mA   -637uA     -1.701mA
0V        0A         0A         0A
6.6V      0A         0A         0A
[POWER_clamp]
|Voltage   I(typ)   I(min)   I(max)
-3.25V    761uA      797.6uA    771.5uA
-3.05V    529.8uA    580.8uA    518.2uA
-2.95V    421.6uA    477.3uA    415.1uA
-2.85V    322.5uA    377.6uA    342uA
-2.65V    184.2uA    200uA      287.1uA
-2.55V    157.9uA    134.1uA    278.6uA
-2.35V    143.1uA    80.64uA    266.6uA
-950mV    110.3uA    55.66uA    208.7uA
2.35V     93.03uA    45.33uA    174uA
2.85V     71.52uA    41.08uA    96.73uA
3.25V     10.85uA    20.74uA    -50.58uA
6.6V      -56.35nA   -1.463uA   -71.55uA
[Ramp]
| variable   typ   min   max
dV/dt_r  1.1542/0.3590n   0.9035/0.5460n   1.4308/0.2329n
dV/dt_f  1.1855/0.3662n   0.8843/0.5297n   1.4345/0.2507n
R_load = 50.0000
[Rising Waveform]
R_fixture=   50.0000
V_fixture=   3.3000
V_fixture_min=   3.1400
V_fixture_max=   3.4700
|time   V(typ)   V(min)   V(max)
0s        1.324V     1.666V     1.079V
404ps     1.324V     1.666V     1.079V
505.1ps   1.324V     1.666V     1.407V
606.1ps   1.323V     1.666V     2.373V
707.1ps   1.46V      1.666V     2.973V
808.1ps   2.269V     1.667V     3.306V
1.01ns    2.956V     1.691V     3.43V
1.313ns   3.246V     2.765V     3.463V
1.818ns   3.293V     3.091V     3.469V
10ns      3.3V       3.14V      3.47V
[Rising Waveform]
R_fixture=   50.0000
V_fixture=   0.0
V_fixture_min=   0.0
V_fixture_max=   0.0
|time   V(typ)   V(min)   V(max)
0s        830nV      1.065uV    812.2nV
606.1ps   -647.3uV   2.343uV    -19.28mV
707.1ps   -25.56mV   18.24uV    307.2mV
909.1ps   -1.644mV   -352.6uV   1.685V
1.01ns    168.3mV    -10.05mV   2.075V
1.313ns   1.24V      -19.03mV   2.334V
1.717ns   1.816V     450.2mV    2.378V
2.121ns   1.9V       1.136V     2.384V
2.727ns   1.921V     1.444V     2.385V
10ns      1.924V     1.506V     2.385V
[Falling Waveform]
R_fixture=   50.0000
V_fixture=   0.0
V_fixture_min=   0.0
V_fixture_max=   0.0
|time   V(typ)   V(min)   V(max)
0s        1.924V     1.506V     2.385V
505.1ps   1.924V     1.506V     2.387V
707.1ps   1.923V     1.506V     469.1mV
808.1ps   1.757V     1.506V     123.1mV
1.01ns    427.9mV    1.507V     27.45mV
1.212ns   71.02mV    1.464V     7.412mV
1.414ns   24.43mV    655.3mV    2.129mV
1.616ns   9.884mV    189mV      652.9uV
1.919ns   2.628mV    35.9mV     184.5uV
10ns      -6.753uV   -8.585uV   -14.06uV
[Falling Waveform]
R_fixture=   50.0000
V_fixture=   3.3000
V_fixture_min=   3.1400
V_fixture_max=   3.4700
|time   V(typ)   V(min)   V(max)
0s        3.3V       3.14V      3.47V
606.1ps   3.3V       3.14V      3.436V
808.1ps   3.351V     3.14V      2.072V
909.1ps   3.292V     3.14V      1.597V
1.111ns   2.497V     3.138V     1.198V
1.313ns   1.855V     3.2V       1.113V
1.616ns   1.458V     2.796V     1.086V
2.02ns    1.35V      2.067V     1.08V
2.626ns   1.327V     1.737V     1.079V
10ns      1.324V     1.666V     1.079V
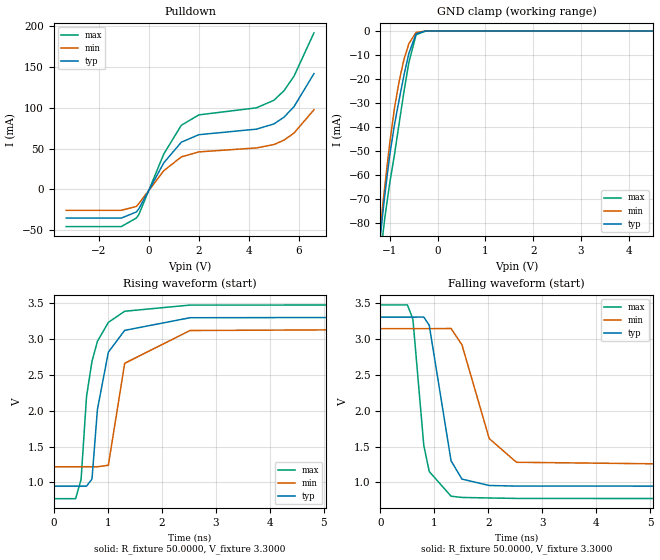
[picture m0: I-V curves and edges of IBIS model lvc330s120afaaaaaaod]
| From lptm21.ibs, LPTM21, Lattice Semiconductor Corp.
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|   Model lvc330s120afaaaaaaod
[Model]   lvc330s120afaaaaaaod
Model_type   I/O_open_drain
Polarity   Non-Inverting
Enable   Active-Low
Vinl =   0.8000V
Vinh =   2.0000V
Vmeas =   1.6500V
Cref =   0.0F
Rref =   1.0000M
Vref =   0.0V
C_comp   4.2000pF   3.8000pF   7.5000pF
[Temperature Range]   25.0000   0.1050k   -40.0000
[Voltage Range]   3.3000V   3.1400V   3.4700V
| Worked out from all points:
|   slope of the pulldown table from 0 to 0.495 V, typ, clamps not added: 17.9 ohm
|   GND clamp passes 1 mA (typ) near -0.44 V on its own axis
|   rising waveform, R_fixture 50.0000, V_fixture 3.3000: 20-80 % time 276ps typ, 289ps min, 267ps max; typ from 0.948 V to 3.3 V
|   falling waveform, R_fixture 50.0000, V_fixture 3.3000: 20-80 % time 294ps typ, 457ps min, 223ps max; typ from 3.3 V to 0.948 V
[Pulldown]
|Voltage   I(typ)   I(min)   I(max)
-3.3V     -35.06mA   -25.56mA   -45.46mA
-1.1V     -35.06mA   -25.56mA   -45.46mA
-500mV    -27.6mA    -20.84mA   -35.05mA
-400mV    -23.76mA   -17.38mA   -30.85mA
600mV     32.61mA    22.93mA    43.45mA
1.3V      57.8mA     39.8mA     78.5mA
2V        66.97mA    45.91mA    91.2mA
4.3V      73.75mA    50.79mA    99.83mA
5V        80.13mA    54.88mA    109.1mA
5.4V      88.36mA    60.26mA    120.7mA
5.8V      101.2mA    68.92mA    138.4mA
6.6V      141.7mA    97.49mA    191.6mA
[GND_clamp]
|Voltage   I(typ)   I(min)   I(max)
-3.3V     -955.3mA   -930.3mA   -978mA
-1.2V     -86.18mA   -82.93mA   -94.91mA
-1.15V    -76.73mA   -73.29mA   -85.74mA
-1.1V     -67.71mA   -63.95mA   -77.28mA
-1V       -51.52mA   -46.57mA   -63.21mA
-900mV    -38.87mA   -31.88mA   -51.26mA
-800mV    -28.25mA   -20.58mA   -37.97mA
-700mV    -18.1mA    -11.63mA   -24.81mA
-600mV    -9.267mA   -5.265mA   -13.06mA
-450mV    -1.181mA   -586.6uA   -1.592mA
-250mV    -3.532uA   -4.055uA   -3.003uA
6.6V      0A         0A         0A
[Ramp]
| variable   typ   min   max
dV/dt_r  1.4109/0.2735n   1.1528/0.2860n   1.6173/0.2647n
dV/dt_f  1.4109/0.2909n   1.1527/0.5154n   1.6173/0.1932n
R_load = 50.0000
[Rising Waveform]
R_fixture=   50.0000
V_fixture=   3.3000
V_fixture_min=   3.1400
V_fixture_max=   3.4700
|time   V(typ)   V(min)   V(max)
0s        948.5mV    1.219V     774.4mV
404ps     948.5mV    1.219V     774.6mV
505.1ps   948.5mV    1.219V     1.043V
606.1ps   948.8mV    1.219V     2.196V
707.1ps   1.048V     1.219V     2.686V
808.1ps   2.017V     1.219V     2.964V
1.01ns    2.812V     1.239V     3.227V
1.313ns   3.116V     2.658V     3.382V
2.525ns   3.292V     3.114V     3.468V
10ns      3.3V       3.14V      3.47V
[Falling Waveform]
R_fixture=   50.0000
V_fixture=   3.3000
V_fixture_min=   3.1400
V_fixture_max=   3.4700
|time   V(typ)   V(min)   V(max)
0s        3.3V       3.14V      3.47V
505.1ps   3.3V       3.14V      3.47V
606.1ps   3.3V       3.14V      3.271V
808.1ps   3.301V     3.14V      1.514V
909.1ps   3.186V     3.14V      1.152V
1.313ns   1.302V     3.142V     809.3mV
1.515ns   1.047V     2.915V     791.7mV
2.02ns    958.2mV    1.611V     784.3mV
2.525ns   949.7mV    1.281V     778.2mV
10ns      948.5mV    1.219V     774.4mV
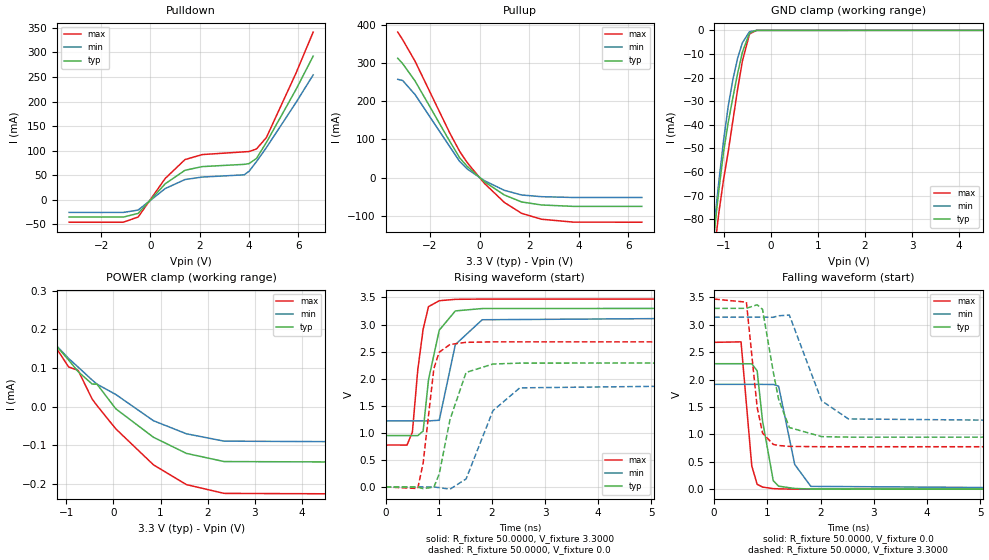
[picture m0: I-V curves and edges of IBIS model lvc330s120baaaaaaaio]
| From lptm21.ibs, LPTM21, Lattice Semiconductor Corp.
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|   Model lvc330s120baaaaaaaio
[Model]   lvc330s120baaaaaaaio
Model_type   I/O
Polarity   Non-Inverting
Enable   Active-Low
Vinl =   0.8000V
Vinh =   2.0000V
Vmeas =   1.500000V
Cref =   0.0F
Rref =   1.0000M
Vref =   0.0V
C_comp   4.2000pF   3.8000pF   7.5000pF
[Temperature Range]   25.0000   0.1050k   -40.0000
[Voltage Range]   3.3000V   3.1400V   3.4700V
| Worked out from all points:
|   slope of the pulldown table from 0 to 0.495 V, typ, clamps not added: 17.9 ohm
|   slope of the pullup table from 0 to 0.495 V, typ, clamps not added: 19.6 ohm
|   GND clamp passes 1 mA (typ) near -0.44 V on its own axis
|   rising waveform, R_fixture 50.0000, V_fixture 3.3000: 20-80 % time 244ps typ, 294ps min, 180ps max; typ from 0.948 V to 3.3 V
|   rising waveform, R_fixture 50.0000, V_fixture 0.0: 20-80 % time 304ps typ, 473ps min, 186ps max; typ from 0 V to 2.29 V
|   falling waveform, R_fixture 50.0000, V_fixture 0.0: 20-80 % time 168ps typ, 249ps min, 132ps max; typ from 2.29 V to 0 V
|   falling waveform, R_fixture 50.0000, V_fixture 3.3000: 20-80 % time 283ps typ, 451ps min, 193ps max; typ from 3.3 V to 0.948 V
[Pulldown]
|Voltage   I(typ)   I(min)   I(max)
-3.3V     -35.02mA   -25.52mA   -45.41mA
-1.1V     -35.02mA   -25.52mA   -45.41mA
-500mV    -27.5mA    -20.77mA   -34.92mA
600mV     32.75mA    23.02mA    43.67mA
1.4V      60.17mA    41.34mA    81.89mA
2.1V      67.64mA    46.37mA    92.1mA
3.8V      72.22mA    50.9mA     97.67mA
4V        73.8mA     58.16mA    98.31mA
4.3V      84.28mA    77.8mA     103.5mA
4.7V      116.6mA    106.1mA    126.6mA
5.9V      224.2mA    197.7mA    257.4mA
6.6V      292.4mA    254.1mA    341.2mA
[Pullup]
|Voltage   I(typ)   I(min)   I(max)
-3.3V     312.6mA    257.4mA    381.1mA
-3.1V     298.3mA    254.2mA    361mA
-2.6V     253mA      217.4mA    304.6mA
-1.2V     94.97mA    80.83mA    116.7mA
-800mV    51.64mA    42.26mA    68.62mA
-500mV    29.58mA    22.76mA    39.55mA
200mV     -10.85mA   -8.11mA    -15.13mA
1V        -45.38mA   -33.2mA    -64.85mA
1.7V      -63.71mA   -45.5mA    -93.58mA
2.5V      -71.58mA   -49.9mA    -108.9mA
3.8V      -75.35mA   -52.01mA   -116.6mA
6.55V     -75.35mA   -52.01mA   -116.7mA
[GND_clamp]
|Voltage   I(typ)   I(min)   I(max)
-3.3V     -955.2mA   -930.2mA   -977.8mA
-1.2V     -86.07mA   -82.87mA   -94.72mA
-1.15V    -76.63mA   -73.23mA   -85.56mA
-1.1V     -67.6mA    -63.89mA   -77.1mA
-1V       -51.41mA   -46.51mA   -63.05mA
-900mV    -38.77mA   -31.83mA   -51.09mA
-800mV    -28.16mA   -20.53mA   -37.81mA
-700mV    -18.01mA   -11.59mA   -24.66mA
-600mV    -9.192mA   -5.229mA   -12.92mA
-450mV    -1.151mA   -576.6uA   -1.527mA
-300mV    -17.4uA    -15.66uA   -11.6uA
6.6V      0A         0A         0A
[POWER_clamp]
|Voltage   I(typ)   I(min)   I(max)
-3.25V    961.3uA    1.05mA     917.9uA
-2.25V    305.8uA    299.5uA    344.1uA
-1.95V    260.5uA    253.4uA    288.8uA
-950mV    120.7uA    124.7uA    102.8uA
-750mV    90.82uA    102.7uA    94.17uA
-450mV    58.57uA    68.87uA    19.46uA
-350mV    58.57uA    58.54uA    3.121uA
50mV      -5.338uA   31.71uA    -57.16uA
850mV     -79.07uA   -36.24uA   -150.4uA
1.55V     -120.8uA   -70.05uA   -201.6uA
2.35V     -141.9uA   -89.06uA   -224.3uA
6.6V      -143.8uA   -91.66uA   -226.3uA
[Ramp]
| variable   typ   min   max
dV/dt_r  1.3741/0.3012n   1.1475/0.4684n   1.6081/0.1845n
dV/dt_f  1.4109/0.2806n   1.1527/0.4461n   1.6174/0.1908n
R_load = 50.0000
[Rising Waveform]
R_fixture=   50.0000
V_fixture=   3.3000
V_fixture_min=   3.1400
V_fixture_max=   3.4700
|time   V(typ)   V(min)   V(max)
0s        948.5mV    1.219V     774.4mV
404ps     948.5mV    1.219V     773.7mV
505.1ps   948.6mV    1.219V     1.014V
606.1ps   947.4mV    1.219V     2.161V
707.1ps   1.032V     1.219V     2.914V
808.1ps   1.981V     1.219V     3.33V
1.01ns    2.895V     1.232V     3.439V
1.313ns   3.251V     2.63V      3.465V
1.818ns   3.295V     3.088V     3.47V
10ns      3.3V       3.14V      3.47V
[Rising Waveform]
R_fixture=   50.0000
V_fixture=   0.0
V_fixture_min=   0.0
V_fixture_max=   0.0
|time   V(typ)   V(min)   V(max)
0s        612.2nV    810.3nV    586nV
606.1ps   -814.1uV   2.155uV    -28.5mV
707.1ps   -31.91mV   19.12uV    442.4mV
909.1ps   -3.978mV   -498.9uV   2.189V
1.01ns    240.4mV    -12.47mV   2.489V
1.212ns   1.244V     -41.1mV    2.631V
1.515ns   2.115V     148mV      2.671V
2.02ns    2.27V      1.408V     2.68V
2.525ns   2.287V     1.83V      2.68V
10ns      2.29V      1.913V     2.68V
[Falling Waveform]
R_fixture=   50.0000
V_fixture=   0.0
V_fixture_min=   0.0
V_fixture_max=   0.0
|time   V(typ)   V(min)   V(max)
0s        2.29V      1.913V     2.68V
505.1ps   2.29V      1.913V     2.689V
707.1ps   2.288V     1.913V     423.2mV
808.1ps   2.161V     1.913V     89.39mV
909.1ps   1.25V      1.913V     38.11mV
1.111ns   154.6mV    1.911V     10.1mV
1.212ns   54.48mV    1.881V     5.298mV
1.515ns   12.41mV    450.5mV    742.1uV
1.818ns   3.109mV    50.96mV    174.6uV
10ns      3.259uV    2.082uV    -608.2nV
[Falling Waveform]
R_fixture=   50.0000
V_fixture=   3.3000
V_fixture_min=   3.1400
V_fixture_max=   3.4700
|time   V(typ)   V(min)   V(max)
0s        3.3V       3.14V      3.47V
606.1ps   3.301V     3.14V      3.413V
808.1ps   3.366V     3.14V      1.496V
909.1ps   3.282V     3.14V      1.025V
1.111ns   2.142V     3.137V     816.9mV
1.212ns   1.64V      3.165V     797mV
1.414ns   1.125V     3.177V     781mV
2.02ns    958.8mV    1.614V     774.6mV
2.525ns   949.9mV    1.282V     774.5mV
10ns      948.5mV    1.219V     774.4mV
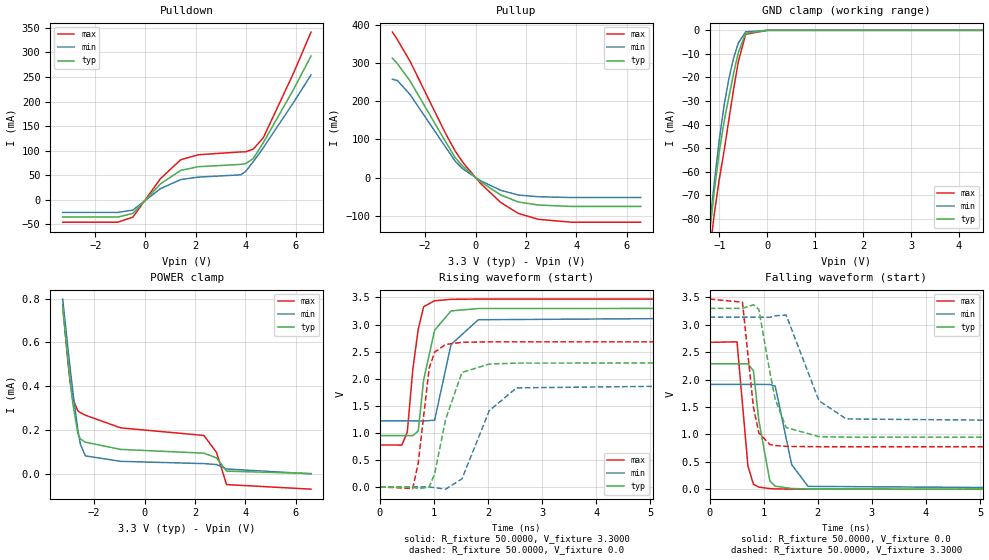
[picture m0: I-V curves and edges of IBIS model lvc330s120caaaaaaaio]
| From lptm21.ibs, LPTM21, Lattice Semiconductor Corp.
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|   Model lvc330s120caaaaaaaio
[Model]   lvc330s120caaaaaaaio
Model_type   I/O
Polarity   Non-Inverting
Enable   Active-Low
Vinl =   0.8000V
Vinh =   2.0000V
Vmeas =   1.500000V
Cref =   0.0F
Rref =   1.0000M
Vref =   0.0V
C_comp   4.2000pF   3.8000pF   7.5000pF
[Temperature Range]   25.0000   0.1050k   -40.0000
[Voltage Range]   3.3000V   3.1400V   3.4700V
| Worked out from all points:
|   slope of the pulldown table from 0 to 0.495 V, typ, clamps not added: 18 ohm
|   slope of the pullup table from 0 to 0.495 V, typ, clamps not added: 19.6 ohm
|   GND clamp passes 1 mA (typ) near -0.43 V on its own axis
|   rising waveform, R_fixture 50.0000, V_fixture 3.3000: 20-80 % time 244ps typ, 294ps min, 180ps max; typ from 0.948 V to 3.3 V
|   rising waveform, R_fixture 50.0000, V_fixture 0.0: 20-80 % time 304ps typ, 473ps min, 186ps max; typ from 0 V to 2.29 V
|   falling waveform, R_fixture 50.0000, V_fixture 0.0: 20-80 % time 168ps typ, 249ps min, 132ps max; typ from 2.29 V to 0 V
|   falling waveform, R_fixture 50.0000, V_fixture 3.3000: 20-80 % time 283ps typ, 451ps min, 193ps max; typ from 3.3 V to 0.948 V
[Pulldown]
|Voltage   I(typ)   I(min)   I(max)
-3.3V     -35.03mA   -25.54mA   -45.42mA
-1.1V     -35.03mA   -25.54mA   -45.42mA
-500mV    -27.54mA   -20.79mA   -34.96mA
600mV     32.53mA    22.89mA    43.29mA
1.4V      59.94mA    41.21mA    81.5mA
2.1V      67.44mA    46.26mA    91.74mA
3.8V      72.18mA    50.91mA    97.53mA
4V        73.78mA    58.19mA    97.72mA
4.3V      84.29mA    77.85mA    103.4mA
4.7V      116.6mA    106.2mA    126.6mA
5.9V      224.4mA    198mA      257.6mA
6.6V      292.6mA    254.3mA    341.3mA
[Pullup]
|Voltage   I(typ)   I(min)   I(max)
-3.3V     312.8mA    257.6mA    381.2mA
-3.1V     298.5mA    254.4mA    361.1mA
-2.6V     253.2mA    217.7mA    304.7mA
-1.2V     95.01mA    80.89mA    116.7mA
-800mV    51.63mA    42.28mA    68.54mA
-500mV    29.54mA    22.75mA    39.47mA
200mV     -10.97mA   -8.174mA   -15.35mA
1V        -45.57mA   -33.3mA    -65.18mA
1.7V      -63.93mA   -45.63mA   -93.96mA
2.5V      -71.81mA   -50.03mA   -109.3mA
3.8V      -75.41mA   -52.05mA   -116.7mA
6.55V     -75.41mA   -52.05mA   -116.7mA
[GND_clamp]
|Voltage   I(typ)   I(min)   I(max)
-3.3V     -955.3mA   -930.3mA   -978mA
-1.2V     -86.21mA   -82.95mA   -94.94mA
-1.15V    -76.76mA   -73.31mA   -85.77mA
-1.1V     -67.73mA   -63.97mA   -77.32mA
-1V       -51.54mA   -46.59mA   -63.26mA
-900mV    -38.9mA    -31.9mA    -51.31mA
-800mV    -28.29mA   -20.61mA   -38.02mA
-700mV    -18.14mA   -11.66mA   -24.86mA
-600mV    -9.315mA   -5.302mA   -13.12mA
-450mV    -1.255mA   -637uA     -1.701mA
0V        0A         0A         0A
6.6V      0A         0A         0A
[POWER_clamp]
|Voltage   I(typ)   I(min)   I(max)
-3.25V    761uA      797.6uA    771.5uA
-3.05V    529.8uA    580.8uA    518.2uA
-2.95V    421.6uA    477.3uA    415.1uA
-2.85V    322.5uA    377.6uA    342uA
-2.65V    184.2uA    200uA      287.1uA
-2.55V    157.9uA    134.1uA    278.6uA
-2.35V    143.1uA    80.64uA    266.6uA
-950mV    110.3uA    55.66uA    208.7uA
2.35V     93.03uA    45.33uA    174uA
2.85V     71.52uA    41.08uA    96.73uA
3.25V     10.85uA    20.74uA    -50.58uA
6.6V      -56.35nA   -1.463uA   -71.55uA
[Ramp]
| variable   typ   min   max
dV/dt_r  1.3741/0.3012n   1.1475/0.4684n   1.6081/0.1845n
dV/dt_f  1.4109/0.2806n   1.1527/0.4461n   1.6174/0.1908n
R_load = 50.0000
[Rising Waveform]
R_fixture=   50.0000
V_fixture=   3.3000
V_fixture_min=   3.1400
V_fixture_max=   3.4700
|time   V(typ)   V(min)   V(max)
0s        948.5mV    1.219V     774.4mV
404ps     948.5mV    1.219V     773.7mV
505.1ps   948.6mV    1.219V     1.014V
606.1ps   947.4mV    1.219V     2.161V
707.1ps   1.032V     1.219V     2.914V
808.1ps   1.981V     1.219V     3.33V
1.01ns    2.895V     1.232V     3.439V
1.313ns   3.251V     2.63V      3.465V
1.818ns   3.295V     3.088V     3.47V
10ns      3.3V       3.14V      3.47V
[Rising Waveform]
R_fixture=   50.0000
V_fixture=   0.0
V_fixture_min=   0.0
V_fixture_max=   0.0
|time   V(typ)   V(min)   V(max)
0s        612.2nV    810.3nV    586nV
606.1ps   -814.1uV   2.155uV    -28.5mV
707.1ps   -31.91mV   19.12uV    442.4mV
909.1ps   -3.978mV   -498.9uV   2.189V
1.01ns    240.4mV    -12.47mV   2.489V
1.212ns   1.244V     -41.1mV    2.631V
1.515ns   2.115V     148mV      2.671V
2.02ns    2.27V      1.408V     2.68V
2.525ns   2.287V     1.83V      2.68V
10ns      2.29V      1.913V     2.68V
[Falling Waveform]
R_fixture=   50.0000
V_fixture=   0.0
V_fixture_min=   0.0
V_fixture_max=   0.0
|time   V(typ)   V(min)   V(max)
0s        2.29V      1.913V     2.68V
505.1ps   2.29V      1.913V     2.689V
707.1ps   2.288V     1.913V     423.2mV
808.1ps   2.161V     1.913V     89.39mV
909.1ps   1.25V      1.913V     38.11mV
1.111ns   154.6mV    1.911V     10.1mV
1.212ns   54.48mV    1.881V     5.298mV
1.515ns   12.41mV    450.5mV    742.1uV
1.818ns   3.109mV    50.96mV    174.6uV
10ns      3.259uV    2.082uV    -608.2nV
[Falling Waveform]
R_fixture=   50.0000
V_fixture=   3.3000
V_fixture_min=   3.1400
V_fixture_max=   3.4700
|time   V(typ)   V(min)   V(max)
0s        3.3V       3.14V      3.47V
606.1ps   3.301V     3.14V      3.413V
808.1ps   3.366V     3.14V      1.496V
909.1ps   3.282V     3.14V      1.025V
1.111ns   2.142V     3.137V     816.9mV
1.212ns   1.64V      3.165V     797mV
1.414ns   1.125V     3.177V     781mV
2.02ns    958.8mV    1.614V     774.6mV
2.525ns   949.9mV    1.282V     774.5mV
10ns      948.5mV    1.219V     774.4mV
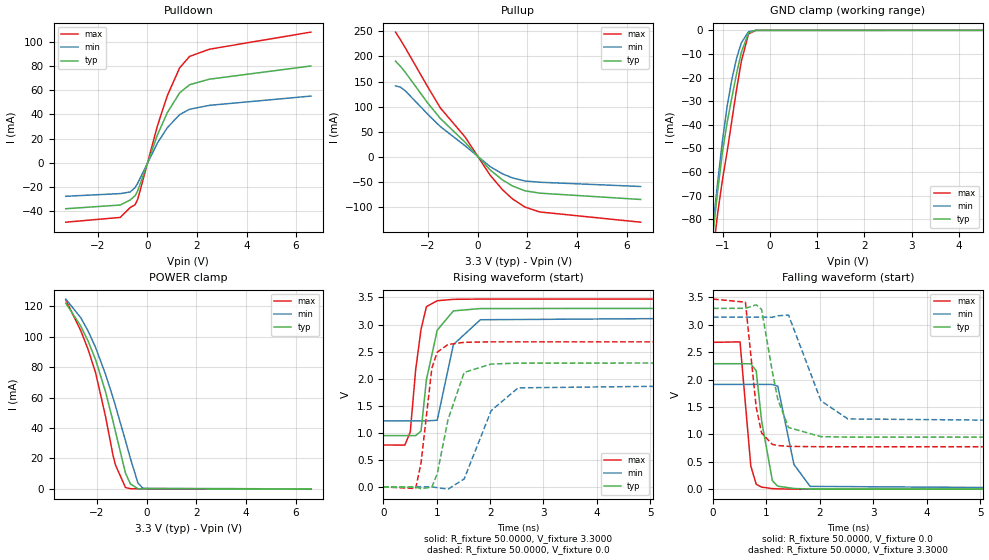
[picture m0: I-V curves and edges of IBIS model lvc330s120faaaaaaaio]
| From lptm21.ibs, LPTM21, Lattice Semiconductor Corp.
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|   Model lvc330s120faaaaaaaio
[Model]   lvc330s120faaaaaaaio
Model_type   I/O
Polarity   Non-Inverting
Enable   Active-Low
Vinl =   0.8000V
Vinh =   2.0000V
Vmeas =   1.500000V
Cref =   0.0F
Rref =   1.0000M
Vref =   0.0V
C_comp   4.2000pF   3.8000pF   7.5000pF
[Temperature Range]   25.0000   0.1050k   -40.0000
[Voltage Range]   3.3000V   3.1400V   3.4700V
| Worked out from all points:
|   slope of the pulldown table from 0 to 0.495 V, typ, clamps not added: 17.9 ohm
|   slope of the pullup table from 0 to 0.495 V, typ, clamps not added: 19.6 ohm
|   GND clamp passes 1 mA (typ) near -0.44 V on its own axis
|   POWER clamp passes 1 mA (typ) near -0.53 V on its own axis
|   rising waveform, R_fixture 50.0000, V_fixture 3.3000: 20-80 % time 244ps typ, 294ps min, 180ps max; typ from 0.948 V to 3.3 V
|   rising waveform, R_fixture 50.0000, V_fixture 0.0: 20-80 % time 304ps typ, 473ps min, 186ps max; typ from 0 V to 2.29 V
|   falling waveform, R_fixture 50.0000, V_fixture 0.0: 20-80 % time 168ps typ, 249ps min, 132ps max; typ from 2.29 V to 0 V
|   falling waveform, R_fixture 50.0000, V_fixture 3.3000: 20-80 % time 283ps typ, 451ps min, 193ps max; typ from 3.3 V to 0.948 V
[Pulldown]
|Voltage   I(typ)   I(min)   I(max)
-3.3V     -38.29mA   -27.95mA   -49.47mA
-1.1V     -35.22mA   -25.73mA   -45.5mA
-700mV    -31mA      -24.37mA   -37.32mA
-500mV    -27.5mA    -20.77mA   -34.92mA
-400mV    -23.63mA   -17.29mA   -30.66mA
-300mV    -18.03mA   -13.08mA   -23.43mA
400mV     22.96mA    16.23mA    30.44mA
800mV     41.45mA    28.96mA    55.59mA
1.3V      57.94mA    39.89mA    78.72mA
1.7V      64.68mA    44.32mA    88.18mA
2.5V      69.29mA    47.56mA    94.17mA
6.6V      80.25mA    55.27mA    108.4mA
[Pullup]
|Voltage   I(typ)   I(min)   I(max)
-3.3V     190.5mA    141.3mA    248.2mA
-3.1V     180.1mA    138.9mA    232.7mA
-2.9V     167.8mA    131.2mA    216.2mA
-2V       106.9mA    84.86mA    138.9mA
-1.5V     76.78mA    60.65mA    97.67mA
-500mV    29.08mA    22.24mA    39.54mA
500mV     -25.47mA   -18.9mA    -35.82mA
1V        -45.38mA   -33.2mA    -64.85mA
1.4V      -57.23mA   -41.33mA   -83.01mA
1.9V      -66.88mA   -47.39mA   -99.15mA
2.5V      -71.58mA   -49.9mA    -108.9mA
6.55V     -84.08mA   -58.34mA   -129.2mA
[GND_clamp]
|Voltage   I(typ)   I(min)   I(max)
-3.3V     -955.2mA   -930.2mA   -977.8mA
-1.2V     -86.07mA   -82.87mA   -94.72mA
-1.15V    -76.63mA   -73.23mA   -85.56mA
-1.1V     -67.6mA    -63.89mA   -77.1mA
-1V       -51.41mA   -46.51mA   -63.05mA
-900mV    -38.77mA   -31.83mA   -51.09mA
-800mV    -28.16mA   -20.53mA   -37.81mA
-700mV    -18.01mA   -11.59mA   -24.66mA
-600mV    -9.192mA   -5.229mA   -12.92mA
-450mV    -1.151mA   -576.6uA   -1.527mA
-300mV    -17.4uA    -15.66uA   -11.6uA
6.6V      0A         0A         0A
[POWER_clamp]
|Voltage   I(typ)   I(min)   I(max)
-3.25V    122.1mA    124.8mA    124.2mA
-2.65V    107.1mA    112.6mA    104.1mA
-2.35V    97.06mA    103.7mA    91.56mA
-2.05V    84.81mA    92.86mA    76.2mA
-1.65V    63.69mA    75.19mA    47.4mA
-1.35V    44.32mA    59.82mA    21.89mA
-1.25V    37.38mA    54.39mA    15.53mA
-850mV    10.3mA     31.63mA    860uA
-650mV    3.168mA    19.76mA    65.53uA
-350mV    73.34uA    3.862mA    3.121uA
-150mV    17.77uA    366.8uA    -28.16uA
6.6V      -143.8uA   -91.66uA   -226.3uA
[Ramp]
| variable   typ   min   max
dV/dt_r  1.3741/0.3012n   1.1475/0.4684n   1.6081/0.1845n
dV/dt_f  1.4109/0.2806n   1.1527/0.4461n   1.6174/0.1908n
R_load = 50.0000
[Rising Waveform]
R_fixture=   50.0000
V_fixture=   3.3000
V_fixture_min=   3.1400
V_fixture_max=   3.4700
|time   V(typ)   V(min)   V(max)
0s        948.5mV    1.219V     774.4mV
404ps     948.5mV    1.219V     773.7mV
505.1ps   948.6mV    1.219V     1.014V
606.1ps   947.4mV    1.219V     2.161V
707.1ps   1.032V     1.219V     2.914V
808.1ps   1.981V     1.219V     3.33V
1.01ns    2.895V     1.232V     3.439V
1.313ns   3.251V     2.63V      3.465V
1.818ns   3.295V     3.088V     3.47V
10ns      3.3V       3.14V      3.47V
[Rising Waveform]
R_fixture=   50.0000
V_fixture=   0.0
V_fixture_min=   0.0
V_fixture_max=   0.0
|time   V(typ)   V(min)   V(max)
0s        612.2nV    810.3nV    586nV
606.1ps   -814.1uV   2.155uV    -28.5mV
707.1ps   -31.91mV   19.12uV    442.4mV
909.1ps   -3.978mV   -498.9uV   2.189V
1.01ns    240.4mV    -12.47mV   2.489V
1.212ns   1.244V     -41.1mV    2.631V
1.515ns   2.115V     148mV      2.671V
2.02ns    2.27V      1.408V     2.68V
2.525ns   2.287V     1.83V      2.68V
10ns      2.29V      1.913V     2.68V
[Falling Waveform]
R_fixture=   50.0000
V_fixture=   0.0
V_fixture_min=   0.0
V_fixture_max=   0.0
|time   V(typ)   V(min)   V(max)
0s        2.29V      1.913V     2.68V
505.1ps   2.29V      1.913V     2.689V
707.1ps   2.288V     1.913V     423.2mV
808.1ps   2.161V     1.913V     89.39mV
909.1ps   1.25V      1.913V     38.11mV
1.111ns   154.6mV    1.911V     10.1mV
1.212ns   54.48mV    1.881V     5.298mV
1.515ns   12.41mV    450.5mV    742.1uV
1.818ns   3.109mV    50.96mV    174.6uV
10ns      3.259uV    2.082uV    -608.2nV
[Falling Waveform]
R_fixture=   50.0000
V_fixture=   3.3000
V_fixture_min=   3.1400
V_fixture_max=   3.4700
|time   V(typ)   V(min)   V(max)
0s        3.3V       3.14V      3.47V
606.1ps   3.301V     3.14V      3.413V
808.1ps   3.366V     3.14V      1.496V
909.1ps   3.282V     3.14V      1.025V
1.111ns   2.142V     3.137V     816.9mV
1.212ns   1.64V      3.165V     797mV
1.414ns   1.125V     3.177V     781mV
2.02ns    958.8mV    1.614V     774.6mV
2.525ns   949.9mV    1.282V     774.5mV
10ns      948.5mV    1.219V     774.4mV
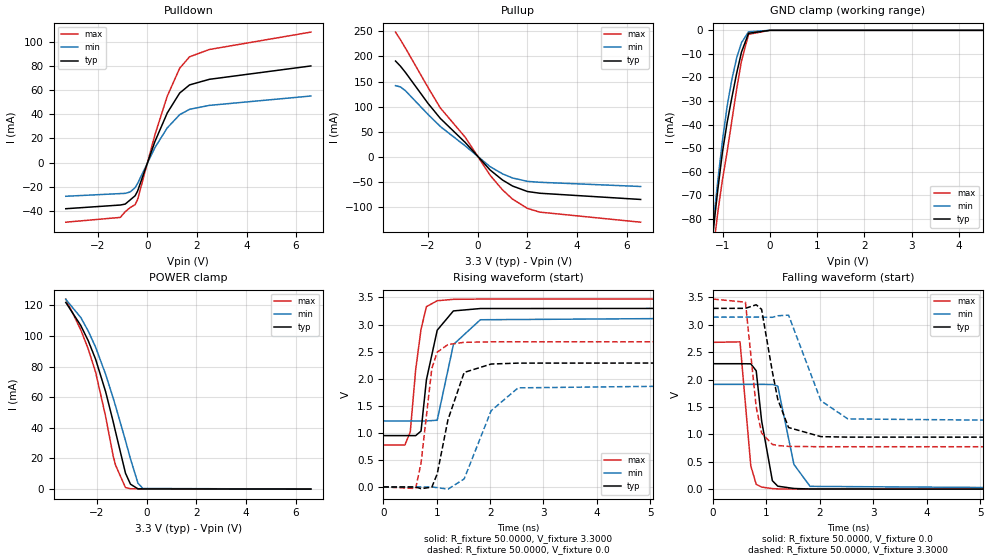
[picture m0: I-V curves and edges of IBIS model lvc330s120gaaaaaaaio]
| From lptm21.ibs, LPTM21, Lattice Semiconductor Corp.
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|   Model lvc330s120gaaaaaaaio
[Model]   lvc330s120gaaaaaaaio
Model_type   I/O
Polarity   Non-Inverting
Enable   Active-Low
Vinl =   0.8000V
Vinh =   2.0000V
Vmeas =   1.500000V
Cref =   0.0F
Rref =   1.0000M
Vref =   0.0V
C_comp   4.2000pF   3.8000pF   7.5000pF
[Temperature Range]   25.0000   0.1050k   -40.0000
[Voltage Range]   3.3000V   3.1400V   3.4700V
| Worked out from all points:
|   slope of the pulldown table from 0 to 0.495 V, typ, clamps not added: 18 ohm
|   slope of the pullup table from 0 to 0.495 V, typ, clamps not added: 19.6 ohm
|   GND clamp passes 1 mA (typ) near -0.43 V on its own axis
|   POWER clamp passes 1 mA (typ) near -0.53 V on its own axis
|   rising waveform, R_fixture 50.0000, V_fixture 3.3000: 20-80 % time 244ps typ, 294ps min, 180ps max; typ from 0.948 V to 3.3 V
|   rising waveform, R_fixture 50.0000, V_fixture 0.0: 20-80 % time 304ps typ, 473ps min, 186ps max; typ from 0 V to 2.29 V
|   falling waveform, R_fixture 50.0000, V_fixture 0.0: 20-80 % time 168ps typ, 249ps min, 132ps max; typ from 2.29 V to 0 V
|   falling waveform, R_fixture 50.0000, V_fixture 3.3000: 20-80 % time 283ps typ, 451ps min, 193ps max; typ from 3.3 V to 0.948 V
[Pulldown]
|Voltage   I(typ)   I(min)   I(max)
-3.3V     -38.3mA    -27.97mA   -49.48mA
-1.1V     -35.24mA   -25.74mA   -45.51mA
-900mV    -34.46mA   -25.54mA   -40.82mA
-700mV    -31.01mA   -24.39mA   -37.34mA
-500mV    -27.54mA   -20.79mA   -34.96mA
-400mV    -23.68mA   -17.33mA   -30.73mA
300mV     17.45mA    12.4mA     23.02mA
800mV     41.22mA    28.82mA    55.19mA
1.3V      57.71mA    39.75mA    78.32mA
1.7V      64.46mA    44.2mA     87.8mA
2.5V      69.11mA    47.47mA    93.85mA
6.6V      80.2mA     55.25mA    108.3mA
[Pullup]
|Voltage   I(typ)   I(min)   I(max)
-3.3V     190.8mA    141.9mA    248.3mA
-3.1V     180.4mA    139.4mA    232.8mA
-2.9V     168mA      131.7mA    216.3mA
-2V       107mA      85.06mA    138.8mA
-1.5V     76.81mA    60.76mA    97.6mA
-500mV    29.05mA    22.23mA    39.45mA
500mV     -25.62mA   -18.98mA   -36.09mA
1V        -45.57mA   -33.3mA    -65.18mA
1.4V      -57.44mA   -41.45mA   -83.37mA
2V        -68.35mA   -48.2mA    -101.9mA
2.5V      -71.81mA   -50.03mA   -109.3mA
6.55V     -84.14mA   -58.39mA   -129.3mA
[GND_clamp]
|Voltage   I(typ)   I(min)   I(max)
-3.3V     -955.3mA   -930.3mA   -978mA
-1.2V     -86.21mA   -82.95mA   -94.94mA
-1.15V    -76.76mA   -73.31mA   -85.77mA
-1.1V     -67.73mA   -63.97mA   -77.32mA
-1V       -51.54mA   -46.59mA   -63.26mA
-900mV    -38.9mA    -31.9mA    -51.31mA
-800mV    -28.29mA   -20.61mA   -38.02mA
-700mV    -18.14mA   -11.66mA   -24.86mA
-600mV    -9.315mA   -5.302mA   -13.12mA
-450mV    -1.255mA   -637uA     -1.701mA
0V        0A         0A         0A
6.6V      0A         0A         0A
[POWER_clamp]
|Voltage   I(typ)   I(min)   I(max)
-3.25V    121.9mA    123.9mA    124.1mA
-2.65V    106.9mA    112.1mA    104.1mA
-2.35V    96.95mA    103.3mA    91.59mA
-2.05V    84.73mA    92.58mA    76.25mA
-1.65V    63.65mA    75mA       47.49mA
-1.35V    44.31mA    59.69mA    21.99mA
-1.25V    37.38mA    54.28mA    15.6mA
-850mV    10.32mA    31.58mA    939uA
-650mV    3.193mA    19.74mA    210uA
-350mV    132.1uA    3.862mA    199.7uA
-150mV    104.6uA    375.8uA    197.7uA
6.6V      -56.35nA   -1.463uA   -71.55uA
[Ramp]
| variable   typ   min   max
dV/dt_r  1.3741/0.3012n   1.1475/0.4684n   1.6081/0.1845n
dV/dt_f  1.4109/0.2806n   1.1527/0.4461n   1.6174/0.1908n
R_load = 50.0000
[Rising Waveform]
R_fixture=   50.0000
V_fixture=   3.3000
V_fixture_min=   3.1400
V_fixture_max=   3.4700
|time   V(typ)   V(min)   V(max)
0s        948.5mV    1.219V     774.4mV
404ps     948.5mV    1.219V     773.7mV
505.1ps   948.6mV    1.219V     1.014V
606.1ps   947.4mV    1.219V     2.161V
707.1ps   1.032V     1.219V     2.914V
808.1ps   1.981V     1.219V     3.33V
1.01ns    2.895V     1.232V     3.439V
1.313ns   3.251V     2.63V      3.465V
1.818ns   3.295V     3.088V     3.47V
10ns      3.3V       3.14V      3.47V
[Rising Waveform]
R_fixture=   50.0000
V_fixture=   0.0
V_fixture_min=   0.0
V_fixture_max=   0.0
|time   V(typ)   V(min)   V(max)
0s        612.2nV    810.3nV    586nV
606.1ps   -814.1uV   2.155uV    -28.5mV
707.1ps   -31.91mV   19.12uV    442.4mV
909.1ps   -3.978mV   -498.9uV   2.189V
1.01ns    240.4mV    -12.47mV   2.489V
1.212ns   1.244V     -41.1mV    2.631V
1.515ns   2.115V     148mV      2.671V
2.02ns    2.27V      1.408V     2.68V
2.525ns   2.287V     1.83V      2.68V
10ns      2.29V      1.913V     2.68V
[Falling Waveform]
R_fixture=   50.0000
V_fixture=   0.0
V_fixture_min=   0.0
V_fixture_max=   0.0
|time   V(typ)   V(min)   V(max)
0s        2.29V      1.913V     2.68V
505.1ps   2.29V      1.913V     2.689V
707.1ps   2.288V     1.913V     423.2mV
808.1ps   2.161V     1.913V     89.39mV
909.1ps   1.25V      1.913V     38.11mV
1.111ns   154.6mV    1.911V     10.1mV
1.212ns   54.48mV    1.881V     5.298mV
1.515ns   12.41mV    450.5mV    742.1uV
1.818ns   3.109mV    50.96mV    174.6uV
10ns      3.259uV    2.082uV    -608.2nV
[Falling Waveform]
R_fixture=   50.0000
V_fixture=   3.3000
V_fixture_min=   3.1400
V_fixture_max=   3.4700
|time   V(typ)   V(min)   V(max)
0s        3.3V       3.14V      3.47V
606.1ps   3.301V     3.14V      3.413V
808.1ps   3.366V     3.14V      1.496V
909.1ps   3.282V     3.14V      1.025V
1.111ns   2.142V     3.137V     816.9mV
1.212ns   1.64V      3.165V     797mV
1.414ns   1.125V     3.177V     781mV
2.02ns    958.8mV    1.614V     774.6mV
2.525ns   949.9mV    1.282V     774.5mV
10ns      948.5mV    1.219V     774.4mV
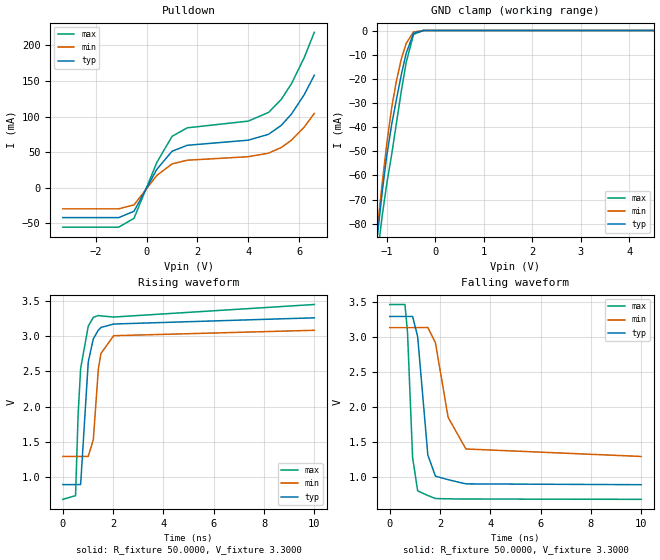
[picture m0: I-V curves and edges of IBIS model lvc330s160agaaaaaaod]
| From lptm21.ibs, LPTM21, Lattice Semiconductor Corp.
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|   Model lvc330s160agaaaaaaod
[Model]   lvc330s160agaaaaaaod
Model_type   I/O_open_drain
Polarity   Non-Inverting
Enable   Active-Low
Vinl =   0.8000V
Vinh =   2.0000V
Vmeas =   1.6500V
Cref =   0.0F
Rref =   1.0000M
Vref =   0.0V
C_comp   4.2000pF   3.8000pF   7.5000pF
[Temperature Range]   25.0000   0.1050k   -40.0000
[Voltage Range]   3.3000V   3.1400V   3.4700V
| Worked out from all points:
|   slope of the pulldown table from 0 to 0.495 V, typ, clamps not added: 15.9 ohm
|   GND clamp passes 1 mA (typ) near -0.44 V on its own axis
|   rising waveform, R_fixture 50.0000, V_fixture 3.3000: 20-80 % time 269ps typ, 268ps min, 285ps max; typ from 0.893 V to 3.26 V
|   falling waveform, R_fixture 50.0000, V_fixture 3.3000: 20-80 % time 344ps typ, 605ps min, 196ps max; typ from 3.3 V to 0.893 V
[Pulldown]
|Voltage   I(typ)   I(min)   I(max)
-3.3V     -41.85mA   -29.54mA   -55.24mA
-1.1V     -41.85mA   -29.54mA   -55.24mA
-500mV    -32.92mA   -23.97mA   -42.85mA
400mV     25.94mA    17.43mA    35.56mA
1V        51.34mA    33.53mA    72.2mA
1.6V      59.71mA    38.76mA    84.24mA
4V        66.88mA    43.66mA    93.63mA
4.8V      75.12mA    48.69mA    105.9mA
5.3V      87.73mA    56.61mA    124.1mA
5.7V      103.5mA    66.87mA    146.1mA
6.2V      130.6mA    85.17mA    182.5mA
6.6V      158mA      104.4mA    218.3mA
[GND_clamp]
|Voltage   I(typ)   I(min)   I(max)
-3.3V     -955.3mA   -930.3mA   -978mA
-1.2V     -86.17mA   -82.92mA   -94.88mA
-1.15V    -76.72mA   -73.28mA   -85.71mA
-1.1V     -67.69mA   -63.94mA   -77.25mA
-1V       -51.5mA    -46.56mA   -63.19mA
-900mV    -38.85mA   -31.87mA   -51.24mA
-800mV    -28.24mA   -20.57mA   -37.95mA
-700mV    -18.09mA   -11.63mA   -24.79mA
-600mV    -9.258mA   -5.26mA    -13.05mA
-450mV    -1.178mA   -585.4uA   -1.585mA
-250mV    -3.51uA    -4.042uA   -2.972uA
6.6V      0A         0A         0A
[Ramp]
| variable   typ   min   max
dV/dt_r  1.4204/0.2661n   1.0742/0.2657n   1.6590/0.2818n
dV/dt_f  1.4443/0.3402n   1.1057/0.5990n   1.6719/0.1944n
R_load = 50.0000
[Rising Waveform]
R_fixture=   50.0000
V_fixture=   3.3000
V_fixture_min=   3.1400
V_fixture_max=   3.4700
|time   V(typ)   V(min)   V(max)
0s        892.8mV    1.292V     683.5mV
505.1ps   892.8mV    1.292V     735.7mV
606.1ps   893.4mV    1.292V     1.879V
707.1ps   893.8mV    1.292V     2.539V
1.01ns    2.633V     1.293V     3.141V
1.212ns   2.962V     1.53V      3.267V
1.414ns   3.086V     2.542V     3.293V
1.515ns   3.123V     2.753V     3.287V
2.02ns    3.172V     3.006V     3.271V
10ns      3.26V      3.083V     3.449V
[Falling Waveform]
R_fixture=   50.0000
V_fixture=   3.3000
V_fixture_min=   3.1400
V_fixture_max=   3.4700
|time   V(typ)   V(min)   V(max)
0s        3.3V       3.14V      3.47V
606.1ps   3.3V       3.14V      3.471V
707.1ps   3.3V       3.14V      3.075V
909.1ps   3.3V       3.14V      1.283V
1.111ns   3.013V     3.14V      804.5mV
1.515ns   1.319V     3.142V     738.1mV
1.818ns   1.015V     2.923V     695.3mV
2.323ns   964.5mV    1.856V     690.5mV
3.03ns    904.5mV    1.404V     687.9mV
10ns      892.9mV    1.297V     683.5mV
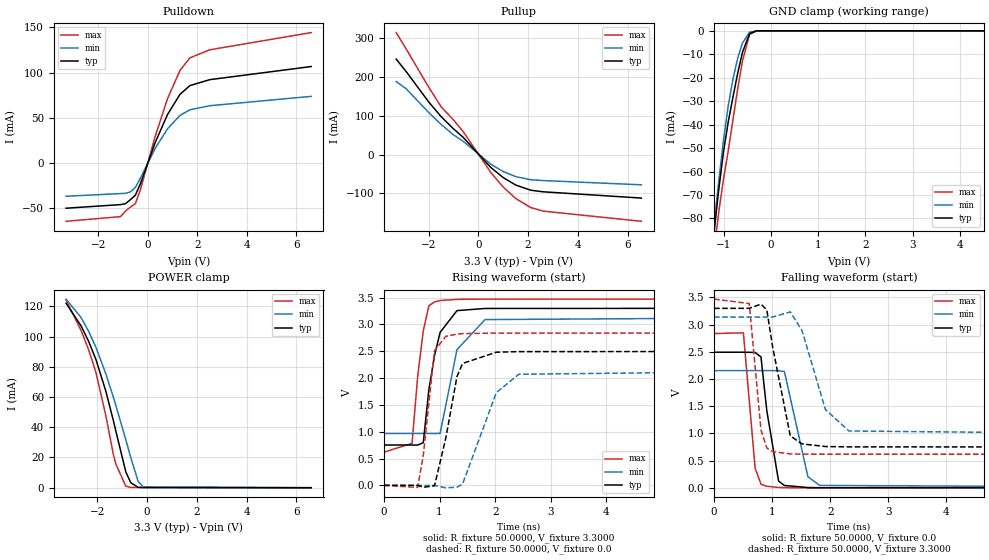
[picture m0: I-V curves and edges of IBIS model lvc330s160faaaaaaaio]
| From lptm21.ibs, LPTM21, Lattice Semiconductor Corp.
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|   Model lvc330s160faaaaaaaio
[Model]   lvc330s160faaaaaaaio
Model_type   I/O
Polarity   Non-Inverting
Enable   Active-Low
Vinl =   0.8000V
Vinh =   2.0000V
Vmeas =   1.500000V
Cref =   0.0F
Rref =   1.0000M
Vref =   0.0V
C_comp   4.2000pF   3.8000pF   7.5000pF
[Temperature Range]   25.0000   0.1050k   -40.0000
[Voltage Range]   3.3000V   3.1400V   3.4700V
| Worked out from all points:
|   slope of the pulldown table from 0 to 0.495 V, typ, clamps not added: 13.9 ohm
|   slope of the pullup table from 0 to 0.495 V, typ, clamps not added: 15.2 ohm
|   GND clamp passes 1 mA (typ) near -0.44 V on its own axis
|   POWER clamp passes 1 mA (typ) near -0.53 V on its own axis
|   rising waveform, R_fixture 50.0000, V_fixture 3.3000: 20-80 % time 241ps typ, 285ps min, 173ps max; typ from 0.752 V to 3.3 V
|   rising waveform, R_fixture 50.0000, V_fixture 0.0: 20-80 % time 262ps typ, 413ps min, 170ps max; typ from 0 V to 2.49 V
|   falling waveform, R_fixture 50.0000, V_fixture 0.0: 20-80 % time 158ps typ, 236ps min, 124ps max; typ from 2.49 V to 0 V
|   falling waveform, R_fixture 50.0000, V_fixture 3.3000: 20-80 % time 230ps typ, 378ps min, 152ps max; typ from 3.3 V to 0.752 V
[Pulldown]
|Voltage   I(typ)   I(min)   I(max)
-3.3V     -50.19mA   -36.93mA   -64.67mA
-1.1V     -46.19mA   -33.97mA   -59.5mA
-900mV    -45.15mA   -33.71mA   -53.32mA
-700mV    -40.64mA   -32.07mA   -48.88mA
-500mV    -35.7mA    -27.08mA   -45.1mA
-300mV    -23.17mA   -16.98mA   -29.79mA
300mV     22.67mA    16.24mA    29.63mA
800mV     53.75mA    37.88mA    71.35mA
1.3V      75.94mA    52.58mA    102.4mA
1.7V      85.57mA    58.78mA    116.3mA
2.5V      92.15mA    63.29mA    125.2mA
6.6V      106.7mA    73.66mA    144.3mA
[Pullup]
|Voltage   I(typ)   I(min)   I(max)
-3.3V     246.4mA    188.7mA    315mA
-2.9V     214.4mA    170mA      272.6mA
-2V       136.4mA    109.3mA    174.8mA
-1.5V     98.49mA    78.3mA     123.9mA
-1V       66.75mA    51.24mA    89.85mA
-600mV    44.1mA     34.07mA    58.63mA
500mV     -32.97mA   -24.66mA   -45.79mA
1V        -59.17mA   -43.58mA   -83.62mA
1.5V      -78.31mA   -56.66mA   -113mA
2.1V      -91.65mA   -64.62mA   -136.3mA
2.6V      -95.78mA   -66.79mA   -145.6mA
6.55V     -112mA     -77.75mA   -171.9mA
[GND_clamp]
|Voltage   I(typ)   I(min)   I(max)
-3.3V     -955.2mA   -930.2mA   -977.8mA
-1.2V     -86.07mA   -82.87mA   -94.72mA
-1.15V    -76.63mA   -73.23mA   -85.56mA
-1.1V     -67.6mA    -63.89mA   -77.1mA
-1V       -51.41mA   -46.51mA   -63.05mA
-900mV    -38.77mA   -31.83mA   -51.09mA
-800mV    -28.16mA   -20.53mA   -37.81mA
-700mV    -18.01mA   -11.59mA   -24.66mA
-600mV    -9.192mA   -5.229mA   -12.92mA
-450mV    -1.151mA   -576.6uA   -1.527mA
-300mV    -17.4uA    -15.66uA   -11.6uA
6.6V      0A         0A         0A
[POWER_clamp]
|Voltage   I(typ)   I(min)   I(max)
-3.25V    122.1mA    124.8mA    124.2mA
-2.65V    107.1mA    112.6mA    104.1mA
-2.35V    97.06mA    103.7mA    91.56mA
-2.05V    84.81mA    92.86mA    76.2mA
-1.65V    63.69mA    75.19mA    47.4mA
-1.35V    44.32mA    59.82mA    21.89mA
-1.25V    37.38mA    54.39mA    15.53mA
-850mV    10.3mA     31.63mA    860uA
-650mV    3.168mA    19.76mA    65.53uA
-350mV    73.34uA    3.862mA    3.121uA
-150mV    17.77uA    366.8uA    -28.16uA
6.6V      -143.8uA   -91.66uA   -226.3uA
[Ramp]
| variable   typ   min   max
dV/dt_r  1.4966/0.2592n   1.2936/0.4087n   1.7021/0.1678n
dV/dt_f  1.5290/0.2281n   1.3043/0.3741n   1.7112/0.1501n
R_load = 50.0000
[Rising Waveform]
R_fixture=   50.0000
V_fixture=   3.3000
V_fixture_min=   3.1400
V_fixture_max=   3.4700
|time   V(typ)   V(min)   V(max)
0s        751.6mV    966.1mV    618mV
505.1ps   751.7mV    966.1mV    782.9mV
606.1ps   750.5mV    966.1mV    2.026V
707.1ps   795mV      966.1mV    2.88V
808.1ps   1.786V     966.4mV    3.346V
909.1ps   2.419V     965.5mV    3.418V
1.01ns    2.851V     968.1mV    3.444V
1.313ns   3.256V     2.529V     3.466V
1.818ns   3.296V     3.089V     3.47V
10ns      3.3V       3.14V      3.47V
[Rising Waveform]
R_fixture=   50.0000
V_fixture=   0.0
V_fixture_min=   0.0
V_fixture_max=   0.0
|time   V(typ)   V(min)   V(max)
0s        484.9nV    653.8nV    458.4nV
606.1ps   -928.3uV   2.015uV    -38.81mV
707.1ps   -36.03mV   19.4uV     559mV
909.1ps   -7.501mV   -591.8uV   2.51V
1.111ns   876.5mV    -46.71mV   2.776V
1.313ns   2.029V     -34.83mV   2.819V
1.414ns   2.272V     25.73mV    2.827V
2.02ns    2.481V     1.727V     2.837V
2.424ns   2.492V     2.07V      2.837V
10ns      2.494V     2.156V     2.837V
[Falling Waveform]
R_fixture=   50.0000
V_fixture=   0.0
V_fixture_min=   0.0
V_fixture_max=   0.0
|time   V(typ)   V(min)   V(max)
0s        2.494V     2.156V     2.837V
505.1ps   2.494V     2.156V     2.85V
707.1ps   2.49V      2.156V     363.7mV
808.1ps   2.407V     2.156V     67.81mV
909.1ps   1.413V     2.156V     29.42mV
1.111ns   126.2mV    2.154V     7.547mV
1.212ns   43.67mV    2.138V     3.842mV
1.616ns   6.181mV    206.6mV    298.8uV
1.818ns   2.479mV    45.08mV    130.9uV
10ns      9.129uV    5.31uV     7.474uV
[Falling Waveform]
R_fixture=   50.0000
V_fixture=   3.3000
V_fixture_min=   3.1400
V_fixture_max=   3.4700
|time   V(typ)   V(min)   V(max)
0s        3.3V       3.14V      3.47V
606.1ps   3.301V     3.14V      3.389V
808.1ps   3.378V     3.14V      1.064V
909.1ps   3.27V      3.14V      731.6mV
1.01ns    2.584V     3.142V     666.6mV
1.313ns   955.6mV    3.235V     624.4mV
1.515ns   808.3mV    2.893V     619.6mV
1.919ns   760.1mV    1.439V     618.1mV
2.323ns   753.1mV    1.046V     618mV
10ns      751.7mV    966.1mV    618mV
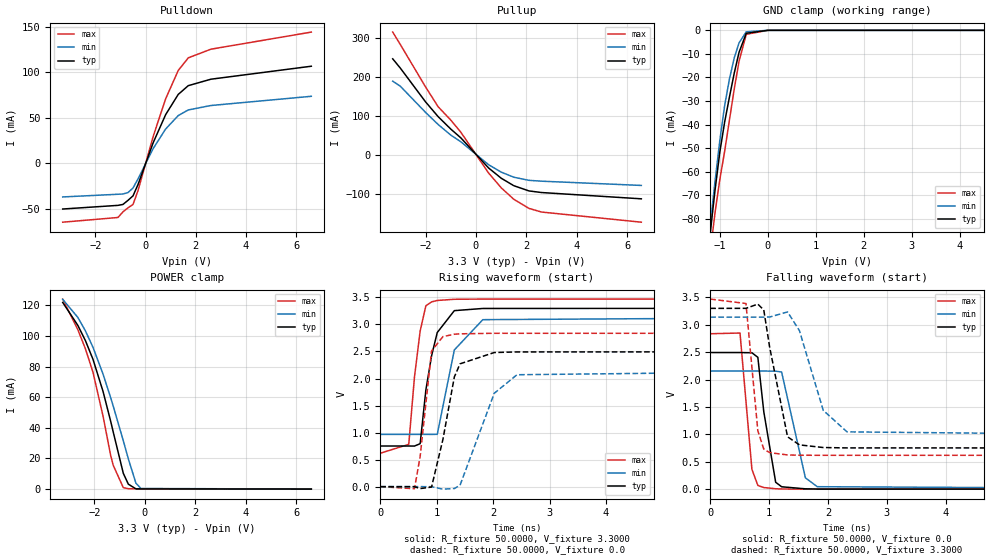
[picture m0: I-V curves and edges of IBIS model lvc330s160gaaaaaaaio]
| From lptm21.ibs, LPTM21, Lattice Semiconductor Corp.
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|   Model lvc330s160gaaaaaaaio
[Model]   lvc330s160gaaaaaaaio
Model_type   I/O
Polarity   Non-Inverting
Enable   Active-Low
Vinl =   0.8000V
Vinh =   2.0000V
Vmeas =   1.500000V
Cref =   0.0F
Rref =   1.0000M
Vref =   0.0V
C_comp   4.2000pF   3.8000pF   7.5000pF
[Temperature Range]   25.0000   0.1050k   -40.0000
[Voltage Range]   3.3000V   3.1400V   3.4700V
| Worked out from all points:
|   slope of the pulldown table from 0 to 0.495 V, typ, clamps not added: 13.9 ohm
|   slope of the pullup table from 0 to 0.495 V, typ, clamps not added: 15.1 ohm
|   GND clamp passes 1 mA (typ) near -0.43 V on its own axis
|   POWER clamp passes 1 mA (typ) near -0.53 V on its own axis
|   rising waveform, R_fixture 50.0000, V_fixture 3.3000: 20-80 % time 241ps typ, 285ps min, 173ps max; typ from 0.752 V to 3.3 V
|   rising waveform, R_fixture 50.0000, V_fixture 0.0: 20-80 % time 262ps typ, 413ps min, 170ps max; typ from 0 V to 2.49 V
|   falling waveform, R_fixture 50.0000, V_fixture 0.0: 20-80 % time 158ps typ, 236ps min, 124ps max; typ from 2.49 V to 0 V
|   falling waveform, R_fixture 50.0000, V_fixture 3.3000: 20-80 % time 230ps typ, 378ps min, 152ps max; typ from 3.3 V to 0.752 V
[Pulldown]
|Voltage   I(typ)   I(min)   I(max)
-3.3V     -50.2mA    -36.94mA   -64.68mA
-1.1V     -46.2mA    -33.99mA   -59.51mA
-900mV    -45.16mA   -33.72mA   -53.33mA
-700mV    -40.66mA   -32.09mA   -48.9mA
-500mV    -35.74mA   -27.1mA    -45.14mA
-300mV    -23.24mA   -17.03mA   -29.89mA
300mV     22.47mA    16.13mA    29.3mA
800mV     53.52mA    37.74mA    70.95mA
1.3V      75.7mA     52.45mA    102mA
1.7V      85.35mA    58.66mA    115.9mA
2.6V      92.42mA    63.52mA    125.4mA
6.6V      106.7mA    73.65mA    144.2mA
[Pullup]
|Voltage   I(typ)   I(min)   I(max)
-3.3V     246.7mA    189.4mA    315.2mA
-3V       223mA      176.6mA    283.5mA
-2V       136.5mA    109.5mA    174.8mA
-1.5V     98.51mA    78.41mA    123.9mA
-1V       66.73mA    51.27mA    89.76mA
-600mV    44.07mA    34.07mA    58.56mA
500mV     -33.12mA   -24.74mA   -46.06mA
1V        -59.36mA   -43.69mA   -83.94mA
1.5V      -78.53mA   -56.78mA   -113.4mA
2.1V      -91.88mA   -64.76mA   -136.7mA
2.6V      -96.01mA   -66.92mA   -146mA
6.55V     -112.1mA   -77.8mA    -172mA
[GND_clamp]
|Voltage   I(typ)   I(min)   I(max)
-3.3V     -955.3mA   -930.3mA   -978mA
-1.2V     -86.21mA   -82.95mA   -94.94mA
-1.15V    -76.76mA   -73.31mA   -85.77mA
-1.1V     -67.73mA   -63.97mA   -77.32mA
-1V       -51.54mA   -46.59mA   -63.26mA
-900mV    -38.9mA    -31.9mA    -51.31mA
-800mV    -28.29mA   -20.61mA   -38.02mA
-700mV    -18.14mA   -11.66mA   -24.86mA
-600mV    -9.315mA   -5.302mA   -13.12mA
-450mV    -1.255mA   -637uA     -1.701mA
0V        0A         0A         0A
6.6V      0A         0A         0A
[POWER_clamp]
|Voltage   I(typ)   I(min)   I(max)
-3.25V    121.9mA    123.9mA    124.1mA
-2.65V    106.9mA    112.1mA    104.1mA
-2.35V    96.95mA    103.3mA    91.59mA
-2.05V    84.73mA    92.58mA    76.25mA
-1.65V    63.65mA    75mA       47.49mA
-1.35V    44.31mA    59.69mA    21.99mA
-1.25V    37.38mA    54.28mA    15.6mA
-850mV    10.32mA    31.58mA    939uA
-650mV    3.193mA    19.74mA    210uA
-350mV    132.1uA    3.862mA    199.7uA
-150mV    104.6uA    375.8uA    197.7uA
6.6V      -56.35nA   -1.463uA   -71.55uA
[Ramp]
| variable   typ   min   max
dV/dt_r  1.4966/0.2592n   1.2936/0.4087n   1.7021/0.1678n
dV/dt_f  1.5290/0.2281n   1.3043/0.3741n   1.7112/0.1501n
R_load = 50.0000
[Rising Waveform]
R_fixture=   50.0000
V_fixture=   3.3000
V_fixture_min=   3.1400
V_fixture_max=   3.4700
|time   V(typ)   V(min)   V(max)
0s        751.6mV    966.1mV    618mV
505.1ps   751.7mV    966.1mV    782.9mV
606.1ps   750.5mV    966.1mV    2.026V
707.1ps   795mV      966.1mV    2.88V
808.1ps   1.786V     966.4mV    3.346V
909.1ps   2.419V     965.5mV    3.418V
1.01ns    2.851V     968.1mV    3.444V
1.313ns   3.256V     2.529V     3.466V
1.818ns   3.296V     3.089V     3.47V
10ns      3.3V       3.14V      3.47V
[Rising Waveform]
R_fixture=   50.0000
V_fixture=   0.0
V_fixture_min=   0.0
V_fixture_max=   0.0
|time   V(typ)   V(min)   V(max)
0s        484.9nV    653.8nV    458.4nV
606.1ps   -928.3uV   2.015uV    -38.81mV
707.1ps   -36.03mV   19.4uV     559mV
909.1ps   -7.501mV   -591.8uV   2.51V
1.111ns   876.5mV    -46.71mV   2.776V
1.313ns   2.029V     -34.83mV   2.819V
1.414ns   2.272V     25.73mV    2.827V
2.02ns    2.481V     1.727V     2.837V
2.424ns   2.492V     2.07V      2.837V
10ns      2.494V     2.156V     2.837V
[Falling Waveform]
R_fixture=   50.0000
V_fixture=   0.0
V_fixture_min=   0.0
V_fixture_max=   0.0
|time   V(typ)   V(min)   V(max)
0s        2.494V     2.156V     2.837V
505.1ps   2.494V     2.156V     2.85V
707.1ps   2.49V      2.156V     363.7mV
808.1ps   2.407V     2.156V     67.81mV
909.1ps   1.413V     2.156V     29.42mV
1.111ns   126.2mV    2.154V     7.547mV
1.212ns   43.67mV    2.138V     3.842mV
1.616ns   6.181mV    206.6mV    298.8uV
1.818ns   2.479mV    45.08mV    130.9uV
10ns      9.129uV    5.31uV     7.474uV
[Falling Waveform]
R_fixture=   50.0000
V_fixture=   3.3000
V_fixture_min=   3.1400
V_fixture_max=   3.4700
|time   V(typ)   V(min)   V(max)
0s        3.3V       3.14V      3.47V
606.1ps   3.301V     3.14V      3.389V
808.1ps   3.378V     3.14V      1.064V
909.1ps   3.27V      3.14V      731.6mV
1.01ns    2.584V     3.142V     666.6mV
1.313ns   955.6mV    3.235V     624.4mV
1.515ns   808.3mV    2.893V     619.6mV
1.919ns   760.1mV    1.439V     618.1mV
2.323ns   753.1mV    1.046V     618mV
10ns      751.7mV    966.1mV    618mV
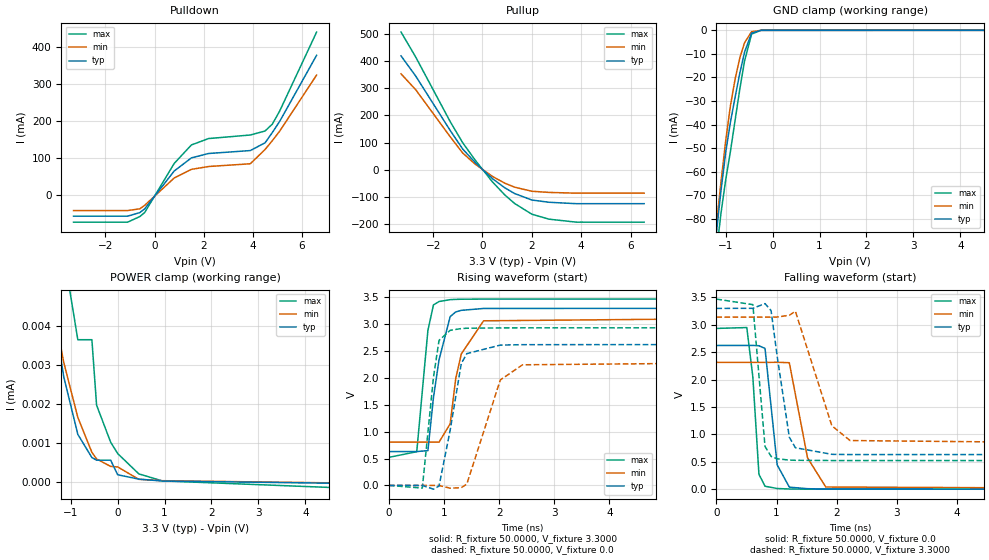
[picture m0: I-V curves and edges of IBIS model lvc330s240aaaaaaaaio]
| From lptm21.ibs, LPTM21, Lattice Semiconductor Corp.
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|   Model lvc330s240aaaaaaaaio
[Model]   lvc330s240aaaaaaaaio
Model_type   I/O
Polarity   Non-Inverting
Enable   Active-Low
Vinl =   0.8000V
Vinh =   2.0000V
Vmeas =   1.6500V
Cref =   0.0F
Rref =   1.0000M
Vref =   0.0V
C_comp   4.2000pF   3.8000pF   7.5000pF
[Temperature Range]   25.0000   0.1050k   -40.0000
[Voltage Range]   3.3000V   3.1400V   3.4700V
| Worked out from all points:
|   slope of the pulldown table from 0 to 0.495 V, typ, clamps not added: 11.5 ohm
|   slope of the pullup table from 0 to 0.495 V, typ, clamps not added: 12.5 ohm
|   GND clamp passes 1 mA (typ) near -0.44 V on its own axis
|   rising waveform, R_fixture 50.0000, V_fixture 3.3000: 20-80 % time 239ps typ, 284ps min, 164ps max; typ from 0.63 V to 3.3 V
|   rising waveform, R_fixture 50.0000, V_fixture 0.0: 20-80 % time 241ps typ, 381ps min, 160ps max; typ from 0 V to 2.62 V
|   falling waveform, R_fixture 50.0000, V_fixture 0.0: 20-80 % time 149ps typ, 223ps min, 117ps max; typ from 2.62 V to 0 V
|   falling waveform, R_fixture 50.0000, V_fixture 3.3000: 20-80 % time 205ps typ, 328ps min, 138ps max; typ from 3.3 V to 0.63 V
[Pulldown]
|Voltage   I(typ)   I(min)   I(max)
-3.3V     -56.93mA   -41.75mA   -73.18mA
-1.1V     -56.93mA   -41.75mA   -73.18mA
-600mV    -47.24mA   -37.04mA   -57.86mA
-400mV    -36.86mA   -27.43mA   -46.9mA
800mV     65.24mA    46.38mA    85.71mA
1.5V      100.7mA    69.7mA     135.7mA
2.2V      112.6mA    77.41mA    153mA
3.9V      120.5mA    84.82mA    162.6mA
4.5V      141.5mA    123.4mA    173.4mA
4.8V      169.6mA    147.5mA    192.3mA
5.1V      199.9mA    173.4mA    227.9mA
6.6V      378.1mA    324.7mA    440.9mA
[Pullup]
|Voltage   I(typ)   I(min)   I(max)
-3.3V     419.7mA    353.5mA    507.6mA
-2.7V     344.5mA    294.3mA    414.5mA
-1.3V     143.5mA    120.4mA    175.8mA
-800mV    76.04mA    61.31mA    99.18mA
-300mV    26.81mA    20.74mA    35.83mA
400mV     -32.67mA   -24.69mA   -44.68mA
900mV     -66.59mA   -49.53mA   -92.73mA
1.3V      -87.89mA   -64.44mA   -124.5mA
2V        -111.9mA   -79.57mA   -164.2mA
2.7V      -120.2mA   -83.87mA   -182.6mA
3.8V      -125.4mA   -86.65mA   -193.5mA
6.55V     -125.4mA   -86.65mA   -193.7mA
[GND_clamp]
|Voltage   I(typ)   I(min)   I(max)
-3.3V     -955.3mA   -930.3mA   -978mA
-1.2V     -86.18mA   -82.93mA   -94.91mA
-1.15V    -76.73mA   -73.29mA   -85.74mA
-1.1V     -67.71mA   -63.95mA   -77.28mA
-1V       -51.52mA   -46.57mA   -63.21mA
-900mV    -38.87mA   -31.88mA   -51.26mA
-800mV    -28.25mA   -20.58mA   -37.97mA
-700mV    -18.1mA    -11.63mA   -24.81mA
-600mV    -9.267mA   -5.265mA   -13.06mA
-450mV    -1.181mA   -586.6uA   -1.592mA
-250mV    -3.532uA   -4.055uA   -3.003uA
6.6V      0A         0A         0A
[POWER_clamp]
|Voltage   I(typ)   I(min)   I(max)
-3.25V    664.8uA    749.4uA    597.1uA
-1.55V    5.915uA    5.713uA    11.4uA
-1.45V    4.988uA    4.975uA    9.752uA
-1.15V    2.704uA    3.074uA    5.864uA
-850mV    1.227uA    1.662uA    3.655uA
-550mV    632.1nA    767.3nA    3.655uA
-450mV    564.4nA    596.3nA    1.977uA
-150mV    564.4nA    405.1nA    1.026uA
0V        190.5nA    391.9nA    734.7nA
450mV     79.23nA    72.94nA    213.9nA
950mV     30.32nA    38.42nA    33.55nA
6.6V      -57.56nA   -49.34nA   -232.5nA
[Ramp]
| variable   typ   min   max
dV/dt_r  1.5736/0.2383n   1.3885/0.3774n   1.7602/0.1582n
dV/dt_f  1.6018/0.2035n   1.4002/0.3250n   1.7683/0.1365n
R_load = 50.0000
[Rising Waveform]
R_fixture=   50.0000
V_fixture=   3.3000
V_fixture_min=   3.1400
V_fixture_max=   3.4700
|time   V(typ)   V(min)   V(max)
0s        630.4mV    806.4mV    522.7mV
505.1ps   630.4mV    806.4mV    627.7mV
707.1ps   648mV      806.4mV    2.886V
808.1ps   1.637V     806.6mV    3.361V
909.1ps   2.339V     805.7mV    3.424V
1.111ns   3.143V     1.147V     3.459V
1.212ns   3.231V     1.991V     3.464V
1.313ns   3.26V      2.448V     3.467V
1.717ns   3.295V     3.065V     3.47V
10ns      3.3V       3.14V      3.47V
[Rising Waveform]
R_fixture=   50.0000
V_fixture=   0.0
V_fixture_min=   0.0
V_fixture_max=   0.0
|time   V(typ)   V(min)   V(max)
0s        401.5nV    548nV      376.4nV
606.1ps   -996.4uV   1.903uV    -49.11mV
808.1ps   -69.74mV   35.14uV    2.014V
909.1ps   -12.04mV   -665.6uV   2.7V
1.111ns   1.028V     -51.28mV   2.888V
1.313ns   2.272V     -42.1mV    2.921V
1.414ns   2.454V     27.78mV    2.927V
2.02ns    2.613V     1.964V     2.933V
2.424ns   2.621V     2.246V     2.934V
10ns      2.623V     2.314V     2.934V
[Falling Waveform]
R_fixture=   50.0000
V_fixture=   0.0
V_fixture_min=   0.0
V_fixture_max=   0.0
|time   V(typ)   V(min)   V(max)
0s        2.623V     2.314V     2.934V
505.1ps   2.623V     2.314V     2.95V
606.1ps   2.624V     2.314V     2.045V
707.1ps   2.618V     2.314V     271.6mV
808.1ps   2.569V     2.314V     53.37mV
1.01ns    444.4mV    2.316V     12.03mV
1.212ns   37.3mV     2.308V     3.037mV
1.515ns   8.564mV    570.8mV    402.1uV
1.818ns   2.036mV    39.47mV    101.5uV
10ns      15.97uV    1.318uV    6.3uV
[Falling Waveform]
R_fixture=   50.0000
V_fixture=   3.3000
V_fixture_min=   3.1400
V_fixture_max=   3.4700
|time   V(typ)   V(min)   V(max)
0s        3.3V       3.14V      3.47V
606.1ps   3.301V     3.14V      3.368V
808.1ps   3.387V     3.14V      779.3mV
909.1ps   3.259V     3.14V      598.5mV
1.01ns    2.427V     3.142V     554.8mV
1.212ns   948.8mV    3.174V     530.7mV
1.313ns   756.2mV    3.247V     526.9mV
1.919ns   635.8mV    1.157V     522.9mV
2.222ns   631.7mV    887.6mV    522.8mV
10ns      630.4mV    806.4mV    522.8mV
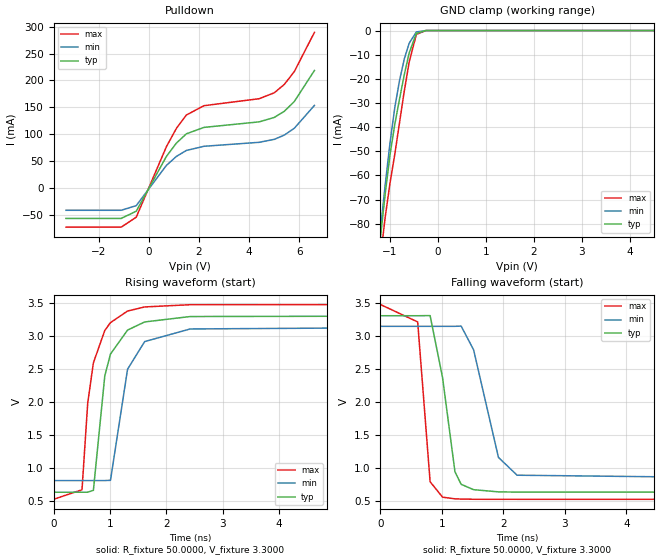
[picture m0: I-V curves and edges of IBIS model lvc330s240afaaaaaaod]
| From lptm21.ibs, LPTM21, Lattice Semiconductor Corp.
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|   Model lvc330s240afaaaaaaod
[Model]   lvc330s240afaaaaaaod
Model_type   I/O_open_drain
Polarity   Non-Inverting
Enable   Active-Low
Vinl =   0.8000V
Vinh =   2.0000V
Vmeas =   1.6500V
Cref =   0.0F
Rref =   1.0000M
Vref =   0.0V
C_comp   4.2000pF   3.8000pF   7.5000pF
[Temperature Range]   25.0000   0.1050k   -40.0000
[Voltage Range]   3.3000V   3.1400V   3.4700V
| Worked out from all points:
|   slope of the pulldown table from 0 to 0.495 V, typ, clamps not added: 11.5 ohm
|   GND clamp passes 1 mA (typ) near -0.44 V on its own axis
|   rising waveform, R_fixture 50.0000, V_fixture 3.3000: 20-80 % time 279ps typ, 276ps min, 264ps max; typ from 0.63 V to 3.3 V
|   falling waveform, R_fixture 50.0000, V_fixture 3.3000: 20-80 % time 215ps typ, 338ps min, 146ps max; typ from 3.3 V to 0.63 V
[Pulldown]
|Voltage   I(typ)   I(min)   I(max)
-3.3V     -56.93mA   -41.75mA   -73.18mA
-1.1V     -56.93mA   -41.75mA   -73.18mA
-500mV    -43.5mA    -33.15mA   -54.62mA
700mV     58.39mA    41.67mA    76.44mA
1.1V      83.34mA    58.54mA    110.7mA
1.5V      100.7mA    69.7mA     135.7mA
2.2V      112.6mA    77.41mA    153mA
4.4V      122.9mA    84.81mA    166mA
5V        131.1mA    90.33mA    177mA
5.4V      142.6mA    98.27mA    192.6mA
5.8V      160.9mA    111.1mA    216.7mA
6.6V      218.6mA    153.5mA    289.6mA
[GND_clamp]
|Voltage   I(typ)   I(min)   I(max)
-3.3V     -955.3mA   -930.3mA   -978mA
-1.2V     -86.18mA   -82.93mA   -94.91mA
-1.15V    -76.73mA   -73.29mA   -85.74mA
-1.1V     -67.71mA   -63.95mA   -77.28mA
-1V       -51.52mA   -46.57mA   -63.21mA
-900mV    -38.87mA   -31.88mA   -51.26mA
-800mV    -28.25mA   -20.58mA   -37.97mA
-700mV    -18.1mA    -11.63mA   -24.81mA
-600mV    -9.267mA   -5.265mA   -13.06mA
-450mV    -1.181mA   -586.6uA   -1.592mA
-250mV    -3.532uA   -4.055uA   -3.003uA
6.6V      0A         0A         0A
[Ramp]
| variable   typ   min   max
dV/dt_r  1.6018/0.2767n   1.4002/0.2734n   1.7683/0.2615n
dV/dt_f  1.6018/0.2131n   1.4002/0.3342n   1.7683/0.1445n
R_load = 50.0000
[Rising Waveform]
R_fixture=   50.0000
V_fixture=   3.3000
V_fixture_min=   3.1400
V_fixture_max=   3.4700
|time   V(typ)   V(min)   V(max)
0s        630.4mV    806.4mV    522.7mV
505.1ps   630.4mV    806.4mV    667.1mV
606.1ps   630.6mV    806.4mV    1.976V
707.1ps   659mV      806.4mV    2.588V
909.1ps   2.39V      806.8mV    3.077V
1.01ns    2.72V      810.1mV    3.196V
1.313ns   3.083V     2.491V     3.371V
1.616ns   3.206V     2.909V     3.433V
2.424ns   3.288V     3.1V       3.467V
10ns      3.3V       3.14V      3.47V
[Falling Waveform]
R_fixture=   50.0000
V_fixture=   3.3000
V_fixture_min=   3.1400
V_fixture_max=   3.4700
|time   V(typ)   V(min)   V(max)
0s        3.3V       3.14V      3.47V
606.1ps   3.3V       3.14V      3.206V
808.1ps   3.302V     3.14V      789.3mV
1.01ns    2.367V     3.14V      555.3mV
1.212ns   940mV      3.14V      530.3mV
1.313ns   749.9mV    3.143V     526.6mV
1.515ns   668.6mV    2.785V     523.7mV
1.919ns   635.8mV    1.157V     522.9mV
2.222ns   631.8mV    887.6mV    522.8mV
10ns      630.4mV    806.4mV    522.7mV
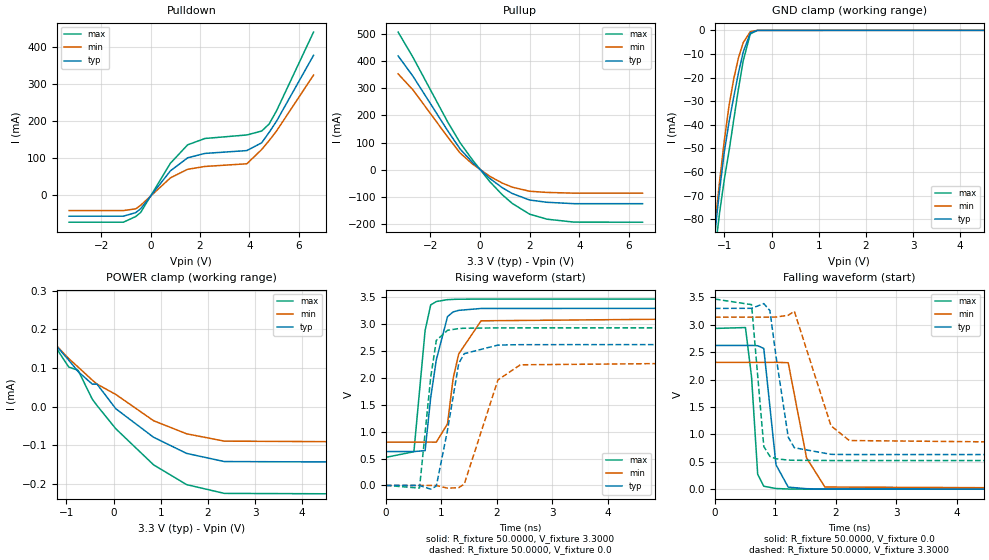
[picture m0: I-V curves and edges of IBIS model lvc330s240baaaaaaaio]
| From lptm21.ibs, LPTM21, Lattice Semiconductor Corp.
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|   Model lvc330s240baaaaaaaio
[Model]   lvc330s240baaaaaaaio
Model_type   I/O
Polarity   Non-Inverting
Enable   Active-Low
Vinl =   0.8000V
Vinh =   2.0000V
Vmeas =   1.6500V
Cref =   0.0F
Rref =   1.0000M
Vref =   0.0V
C_comp   4.2000pF   3.8000pF   7.5000pF
[Temperature Range]   25.0000   0.1050k   -40.0000
[Voltage Range]   3.3000V   3.1400V   3.4700V
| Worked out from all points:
|   slope of the pulldown table from 0 to 0.495 V, typ, clamps not added: 11.5 ohm
|   slope of the pullup table from 0 to 0.495 V, typ, clamps not added: 12.5 ohm
|   GND clamp passes 1 mA (typ) near -0.44 V on its own axis
|   rising waveform, R_fixture 50.0000, V_fixture 3.3000: 20-80 % time 239ps typ, 284ps min, 164ps max; typ from 0.63 V to 3.3 V
|   rising waveform, R_fixture 50.0000, V_fixture 0.0: 20-80 % time 241ps typ, 381ps min, 160ps max; typ from 0 V to 2.62 V
|   falling waveform, R_fixture 50.0000, V_fixture 0.0: 20-80 % time 149ps typ, 223ps min, 117ps max; typ from 2.62 V to 0 V
|   falling waveform, R_fixture 50.0000, V_fixture 3.3000: 20-80 % time 205ps typ, 328ps min, 138ps max; typ from 3.3 V to 0.63 V
[Pulldown]
|Voltage   I(typ)   I(min)   I(max)
-3.3V     -56.89mA   -41.72mA   -73.13mA
-1.1V     -56.89mA   -41.72mA   -73.13mA
-600mV    -47.17mA   -36.99mA   -57.77mA
-400mV    -36.73mA   -27.35mA   -46.71mA
800mV     65.38mA    46.47mA    85.94mA
1.5V      100.8mA    69.79mA    135.9mA
2.2V      112.7mA    77.47mA    153.1mA
3.9V      120.4mA    84.75mA    162.6mA
4.5V      141.4mA    123.3mA    173.2mA
4.8V      169.4mA    147.3mA    192.1mA
5.1V      199.7mA    173.2mA    227.6mA
6.6V      377.8mA    324.4mA    440.6mA
[Pullup]
|Voltage   I(typ)   I(min)   I(max)
-3.3V     419.4mA    353.2mA    507.2mA
-2.7V     344.2mA    294mA      414.1mA
-1.3V     143.3mA    120.3mA    175.6mA
-800mV    75.94mA    61.23mA    99.05mA
-300mV    26.78mA    20.72mA    35.78mA
400mV     -32.63mA   -24.67mA   -44.63mA
900mV     -66.5mA    -49.48mA   -92.61mA
1.3V      -87.78mA   -64.37mA   -124.3mA
2V        -111.8mA   -79.48mA   -164mA
2.7V      -120.1mA   -83.78mA   -182.4mA
3.8V      -125.3mA   -86.56mA   -193.3mA
6.55V     -125.3mA   -86.56mA   -193.5mA
[GND_clamp]
|Voltage   I(typ)   I(min)   I(max)
-3.3V     -955.2mA   -930.2mA   -977.8mA
-1.2V     -86.07mA   -82.87mA   -94.72mA
-1.15V    -76.63mA   -73.23mA   -85.56mA
-1.1V     -67.6mA    -63.89mA   -77.1mA
-1V       -51.41mA   -46.51mA   -63.05mA
-900mV    -38.77mA   -31.83mA   -51.09mA
-800mV    -28.16mA   -20.53mA   -37.81mA
-700mV    -18.01mA   -11.59mA   -24.66mA
-600mV    -9.192mA   -5.229mA   -12.92mA
-450mV    -1.151mA   -576.6uA   -1.527mA
-300mV    -17.4uA    -15.66uA   -11.6uA
6.6V      0A         0A         0A
[POWER_clamp]
|Voltage   I(typ)   I(min)   I(max)
-3.25V    961.3uA    1.05mA     917.9uA
-2.25V    305.8uA    299.5uA    344.1uA
-1.95V    260.5uA    253.4uA    288.8uA
-950mV    120.7uA    124.7uA    102.8uA
-750mV    90.82uA    102.7uA    94.17uA
-450mV    58.57uA    68.87uA    19.46uA
-350mV    58.57uA    58.54uA    3.121uA
50mV      -5.338uA   31.71uA    -57.16uA
850mV     -79.07uA   -36.24uA   -150.4uA
1.55V     -120.8uA   -70.05uA   -201.6uA
2.35V     -141.9uA   -89.06uA   -224.3uA
6.6V      -143.8uA   -91.66uA   -226.3uA
[Ramp]
| variable   typ   min   max
dV/dt_r  1.5736/0.2383n   1.3885/0.3774n   1.7602/0.1582n
dV/dt_f  1.6018/0.2035n   1.4002/0.3250n   1.7683/0.1365n
R_load = 50.0000
[Rising Waveform]
R_fixture=   50.0000
V_fixture=   3.3000
V_fixture_min=   3.1400
V_fixture_max=   3.4700
|time   V(typ)   V(min)   V(max)
0s        630.4mV    806.4mV    522.7mV
505.1ps   630.4mV    806.4mV    627.7mV
707.1ps   648mV      806.4mV    2.886V
808.1ps   1.637V     806.6mV    3.361V
909.1ps   2.339V     805.7mV    3.424V
1.111ns   3.143V     1.147V     3.459V
1.212ns   3.231V     1.991V     3.464V
1.313ns   3.26V      2.448V     3.467V
1.717ns   3.295V     3.065V     3.47V
10ns      3.3V       3.14V      3.47V
[Rising Waveform]
R_fixture=   50.0000
V_fixture=   0.0
V_fixture_min=   0.0
V_fixture_max=   0.0
|time   V(typ)   V(min)   V(max)
0s        401.5nV    548nV      376.4nV
606.1ps   -996.4uV   1.903uV    -49.11mV
808.1ps   -69.74mV   35.14uV    2.014V
909.1ps   -12.04mV   -665.6uV   2.7V
1.111ns   1.028V     -51.28mV   2.888V
1.313ns   2.272V     -42.1mV    2.921V
1.414ns   2.454V     27.78mV    2.927V
2.02ns    2.613V     1.964V     2.933V
2.424ns   2.621V     2.246V     2.934V
10ns      2.623V     2.314V     2.934V
[Falling Waveform]
R_fixture=   50.0000
V_fixture=   0.0
V_fixture_min=   0.0
V_fixture_max=   0.0
|time   V(typ)   V(min)   V(max)
0s        2.623V     2.314V     2.934V
505.1ps   2.623V     2.314V     2.95V
606.1ps   2.624V     2.314V     2.045V
707.1ps   2.618V     2.314V     271.6mV
808.1ps   2.569V     2.314V     53.37mV
1.01ns    444.4mV    2.316V     12.03mV
1.212ns   37.3mV     2.308V     3.037mV
1.515ns   8.564mV    570.8mV    402.1uV
1.818ns   2.036mV    39.47mV    101.5uV
10ns      15.97uV    1.318uV    6.3uV
[Falling Waveform]
R_fixture=   50.0000
V_fixture=   3.3000
V_fixture_min=   3.1400
V_fixture_max=   3.4700
|time   V(typ)   V(min)   V(max)
0s        3.3V       3.14V      3.47V
606.1ps   3.301V     3.14V      3.368V
808.1ps   3.387V     3.14V      779.3mV
909.1ps   3.259V     3.14V      598.5mV
1.01ns    2.427V     3.142V     554.8mV
1.212ns   948.8mV    3.174V     530.7mV
1.313ns   756.2mV    3.247V     526.9mV
1.919ns   635.8mV    1.157V     522.9mV
2.222ns   631.7mV    887.6mV    522.8mV
10ns      630.4mV    806.4mV    522.8mV
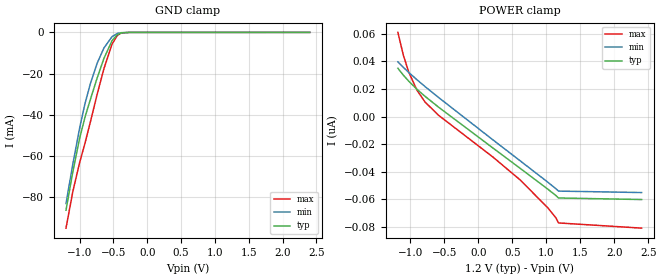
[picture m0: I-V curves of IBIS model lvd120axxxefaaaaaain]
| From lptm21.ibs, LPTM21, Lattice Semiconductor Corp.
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|   Model lvd120axxxefaaaaaain
[Model]   lvd120axxxefaaaaaain
Model_type   Input
Polarity   Non-Inverting
Enable   Active-Low
Vinl =   0.4200V
Vinh =   0.7800V
C_comp   4.2000pF   3.8000pF   7.5000pF
[Temperature Range]   25.0000   0.1050k   -40.0000
[Voltage Range]   1.2000V   1.1400V   1.2600V
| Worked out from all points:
|   GND clamp passes 1 mA (typ) near -0.44 V on its own axis
[GND_clamp]
|Voltage   I(typ)   I(min)   I(max)
-1.2V     -86.25mA   -83.03mA   -94.99mA
-1.1V     -67.78mA   -64.03mA   -77.37mA
-1V       -51.59mA   -46.65mA   -63.32mA
-920mV    -41.19mA   -34.61mA   -53.84mA
-840mV    -32.56mA   -24.89mA   -43.48mA
-740mV    -22.14mA   -14.98mA   -30.07mA
-640mV    -12.66mA   -7.593mA   -17.63mA
-520mV    -4.01mA    -2.071mA   -5.723mA
-440mV    -1.017mA   -516.3uA   -1.361mA
-380mV    -248.6uA   -140.8uA   -305.9uA
-260mV    -8.321uA   -6.867uA   -12.82uA
2.4V      0A         0A         0A
[POWER_clamp]
|Voltage   I(typ)   I(min)   I(max)
-1.18V    35.05nA    39.65nA    61.08nA
-1.1V     30.06nA    35.71nA    44.57nA
-1.02V    25.65nA    31.99nA    32.16nA
-900mV    19.82nA    26.73nA    19.14nA
-780mV    14.64nA    21.74nA    10.51nA
-580mV    6.753nA    13.77nA    847.6pA
220mV     -22.96nA   -17.03nA   -29.5nA
620mV     -37.66nA   -32.23nA   -46.11nA
1.02V     -52.55nA   -47.49nA   -66.06nA
1.14V     -57.21nA   -52.27nA   -73.33nA
1.18V     -59.05nA   -54.06nA   -77.15nA
2.4V      -60.17nA   -55.11nA   -80.92nA
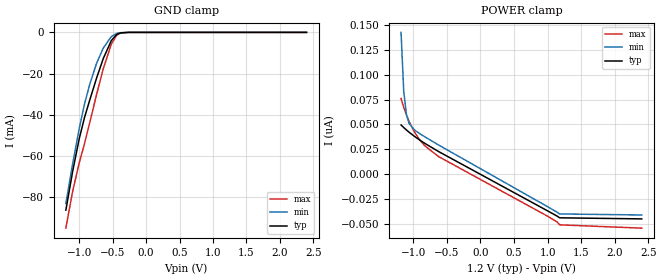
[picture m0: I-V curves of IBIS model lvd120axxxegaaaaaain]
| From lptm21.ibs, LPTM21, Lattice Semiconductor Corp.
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|   Model lvd120axxxegaaaaaain
[Model]   lvd120axxxegaaaaaain
Model_type   Input
Polarity   Non-Inverting
Enable   Active-Low
Vinl =   0.4200V
Vinh =   0.7800V
C_comp   4.2000pF   3.8000pF   7.5000pF
[Temperature Range]   25.0000   0.1050k   -40.0000
[Voltage Range]   1.2000V   1.1400V   1.2600V
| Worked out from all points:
|   GND clamp passes 1 mA (typ) near -0.44 V on its own axis
[GND_clamp]
|Voltage   I(typ)   I(min)   I(max)
-1.2V     -86.24mA   -83.01mA   -94.97mA
-1.1V     -67.77mA   -64.02mA   -77.35mA
-1V       -51.58mA   -46.64mA   -63.3mA
-920mV    -41.17mA   -34.6mA    -53.83mA
-840mV    -32.55mA   -24.88mA   -43.46mA
-740mV    -22.13mA   -14.97mA   -30.05mA
-640mV    -12.66mA   -7.586mA   -17.62mA
-520mV    -4.005mA   -2.068mA   -5.717mA
-440mV    -1.015mA   -514.9uA   -1.358mA
-380mV    -247.6uA   -140.4uA   -304.6uA
-260mV    -8.287uA   -6.849uA   -12.77uA
2.4V      0A         0A         0A
[POWER_clamp]
|Voltage   I(typ)   I(min)   I(max)
-1.18V    49.5nA     142.7nA    76.16nA
-1.14V    46.88nA    83.34nA    67.33nA
-1.1V     44.45nA    60.04nA    59.65nA
-1.06V    42.18nA    50.98nA    52.99nA
-980mV    38nA       44.45nA    42.26nA
-900mV    34.21nA    40.69nA    34.22nA
-820mV    30.7nA     37.31nA    28.11nA
-620mV    22.67nA    29.25nA    17.61nA
980mV     -36.25nA   -32.03nA   -41.62nA
1.14V     -42.2nA    -38.31nA   -48.09nA
1.18V     -43.98nA   -40.09nA   -51.05nA
2.4V      -45.06nA   -41.13nA   -54.37nA
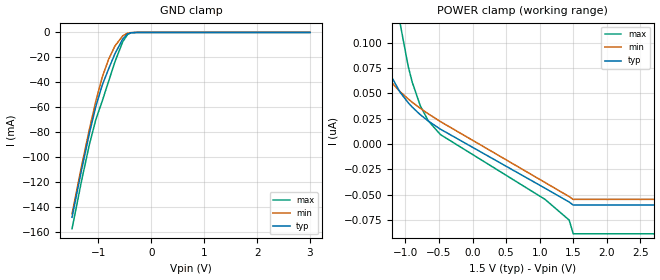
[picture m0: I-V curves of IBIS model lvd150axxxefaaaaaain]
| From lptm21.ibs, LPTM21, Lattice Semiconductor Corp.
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|   Model lvd150axxxefaaaaaain
[Model]   lvd150axxxefaaaaaain
Model_type   Input
Polarity   Non-Inverting
Enable   Active-Low
Vinl =   0.3750V
Vinh =   1.1250V
C_comp   4.2000pF   3.8000pF   7.5000pF
[Temperature Range]   25.0000   0.1050k   -40.0000
[Voltage Range]   1.5000V   1.4300V   1.5800V
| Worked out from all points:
|   GND clamp passes 1 mA (typ) near -0.44 V on its own axis
[GND_clamp]
|Voltage   I(typ)   I(min)   I(max)
-1.5V     -148.1mA   -145.3mA   -157.2mA
-1.32V    -110.1mA   -107.1mA   -118.8mA
-1.17V    -80.54mA   -77.2mA    -89.42mA
-1.05V    -59.32mA   -55.09mA   -69.84mA
-930mV    -42.35mA   -35.99mA   -55.05mA
-810mV    -29.39mA   -21.69mA   -39.42mA
-690mV    -17.23mA   -10.96mA   -23.66mA
-540mV    -5.153mA   -2.725mA   -7.352mA
-450mV    -1.251mA   -629.5uA   -1.7mA
-390mV    -319.3uA   -176.8uA   -395.6uA
-270mV    -11.4uA    -9.003uA   -17.31uA
3V        0A         0A         0A
[POWER_clamp]
|Voltage   I(typ)   I(min)   I(max)
-1.5V     110.5nA    88.5nA     437.8nA
-1.32V    79.6nA     68.83nA    261.7nA
-1.08V    51nA       51.5nA     119nA
-960mV    40.77nA    44.43nA    76.78nA
-900mV    36.42nA    41.2nA     61.06nA
-780mV    28.93nA    35.23nA    37.89nA
-660mV    22.65nA    29.75nA    22.85nA
-480mV    14.66nA    22.15nA    9.325nA
1.08V     -43.56nA   -37.93nA   -54.57nA
1.44V     -57.19nA   -51.85nA   -74.97nA
1.5V      -60.15nA   -54.56nA   -88.48nA
3V        -60.15nA   -54.56nA   -88.48nA
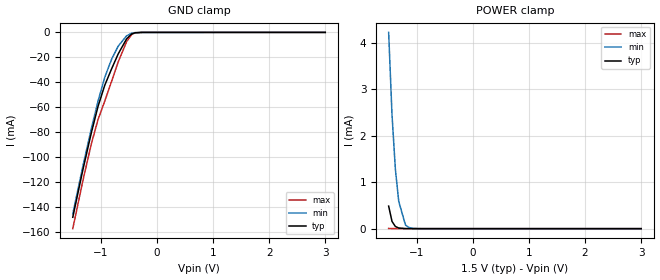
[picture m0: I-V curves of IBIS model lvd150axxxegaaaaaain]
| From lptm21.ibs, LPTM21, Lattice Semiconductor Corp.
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|   Model lvd150axxxegaaaaaain
[Model]   lvd150axxxegaaaaaain
Model_type   Input
Polarity   Non-Inverting
Enable   Active-Low
Vinl =   0.3750V
Vinh =   1.1250V
C_comp   4.2000pF   3.8000pF   7.5000pF
[Temperature Range]   25.0000   0.1050k   -40.0000
[Voltage Range]   1.5000V   1.4300V   1.5800V
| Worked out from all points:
|   GND clamp passes 1 mA (typ) near -0.44 V on its own axis
[GND_clamp]
|Voltage   I(typ)   I(min)   I(max)
-1.5V     -148.1mA   -145.3mA   -157.2mA
-1.32V    -110.1mA   -107.1mA   -118.8mA
-1.17V    -80.53mA   -77.19mA   -89.4mA
-1.05V    -59.3mA    -55.08mA   -69.82mA
-930mV    -42.34mA   -35.98mA   -55.03mA
-810mV    -29.38mA   -21.68mA   -39.41mA
-690mV    -17.22mA   -10.95mA   -23.65mA
-540mV    -5.147mA   -2.721mA   -7.346mA
-450mV    -1.248mA   -627.9uA   -1.697mA
-390mV    -318.2uA   -176.3uA   -394.1uA
-270mV    -11.35uA   -8.979uA   -17.24uA
3V        0A         0A         0A
[POWER_clamp]
|Voltage   I(typ)   I(min)   I(max)
-1.5V     485.2uA    4.227mA    5.252uA
-1.44V    155.9uA    2.45mA     1.5uA
-1.38V    46.28uA    1.278mA    578.7nA
-1.32V    13.61uA    585.3uA    324.6nA
-1.2V     1.151uA    78.59uA    194.7nA
-1.14V    344.2nA    25.71uA    161.6nA
-1.08V    121.5nA    8.159uA    134nA
-1.02V    68.82nA    2.519uA    111nA
-960mV    56.25nA    761.7nA    91.83nA
-900mV    50.9nA     236.9nA    76.11nA
-780mV    43.29nA    56.88nA    52.94nA
3V        -45.07nA   -40.52nA   -61.47nA
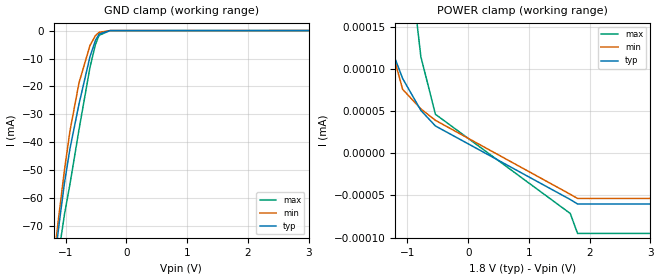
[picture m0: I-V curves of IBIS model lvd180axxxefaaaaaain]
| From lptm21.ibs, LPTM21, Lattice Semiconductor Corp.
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|   Model lvd180axxxefaaaaaain
[Model]   lvd180axxxefaaaaaain
Model_type   Input
Polarity   Non-Inverting
Enable   Active-Low
Vinl =   0.6300V
Vinh =   1.1700V
C_comp   4.2000pF   3.8000pF   7.5000pF
[Temperature Range]   25.0000   0.1050k   -40.0000
[Voltage Range]   1.8000V   1.7100V   1.8900V
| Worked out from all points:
|   GND clamp passes 1 mA (typ) near -0.44 V on its own axis
[GND_clamp]
|Voltage   I(typ)   I(min)   I(max)
-1.8V     -240.3mA   -229.5mA   -254.3mA
-1.2V     -86.25mA   -83.02mA   -94.99mA
-1.17V    -80.54mA   -77.2mA    -89.42mA
-1.11V    -69.55mA   -65.87mA   -78.99mA
-1.02V    -54.58mA   -49.95mA   -65.82mA
-930mV    -42.35mA   -35.99mA   -55.05mA
-780mV    -26.24mA   -18.67mA   -35.38mA
-600mV    -9.354mA   -5.34mA    -13.17mA
-510mV    -3.494mA   -1.787mA   -4.979mA
-450mV    -1.251mA   -629.4uA   -1.7mA
-270mV    -11.4uA    -9.004uA   -17.31uA
3.6V      0A         0A         0A
[POWER_clamp]
|Voltage   I(typ)   I(min)   I(max)
-1.8V     10.77uA    1.038mA    1.632uA
-1.62V    442.9nA    57.63uA    1.147uA
-1.5V     192.4nA    6.24uA     888.3nA
-1.38V    151.9nA    646.2nA    673.9nA
-1.32V    136.8nA    237.1nA    582nA
-1.26V    123nA      123.5nA    499.6nA
-1.08V    88.87nA    75.96nA    303.8nA
-780mV    50.98nA    52.78nA    114.8nA
-540mV    32.48nA    39.16nA    46.35nA
1.68V     -54.84nA   -48.63nA   -71.43nA
1.8V      -60.16nA   -53.56nA   -95.12nA
3.6V      -60.16nA   -53.56nA   -95.12nA
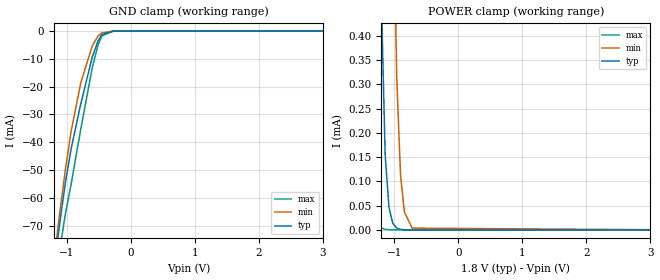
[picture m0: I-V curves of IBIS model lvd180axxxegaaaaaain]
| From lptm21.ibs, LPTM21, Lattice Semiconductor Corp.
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|   Model lvd180axxxegaaaaaain
[Model]   lvd180axxxegaaaaaain
Model_type   Input
Polarity   Non-Inverting
Enable   Active-Low
Vinl =   0.6300V
Vinh =   1.1700V
C_comp   4.2000pF   3.8000pF   7.5000pF
[Temperature Range]   25.0000   0.1050k   -40.0000
[Voltage Range]   1.8000V   1.7100V   1.8900V
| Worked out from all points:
|   GND clamp passes 1 mA (typ) near -0.44 V on its own axis
|   POWER clamp passes 1 mA (typ) near -1.24 V on its own axis
[GND_clamp]
|Voltage   I(typ)   I(min)   I(max)
-1.8V     -240.3mA   -229.5mA   -254.3mA
-1.2V     -86.24mA   -83.01mA   -94.97mA
-1.17V    -80.52mA   -77.19mA   -89.39mA
-1.11V    -69.53mA   -65.86mA   -78.97mA
-1.02V    -54.57mA   -49.94mA   -65.8mA
-930mV    -42.34mA   -35.98mA   -55.03mA
-780mV    -26.23mA   -18.66mA   -35.36mA
-600mV    -9.346mA   -5.334mA   -13.16mA
-510mV    -3.489mA   -1.783mA   -4.974mA
-450mV    -1.248mA   -627.9uA   -1.697mA
-270mV    -11.35uA   -8.979uA   -17.24uA
3.6V      0A         0A         0A
[POWER_clamp]
|Voltage   I(typ)   I(min)   I(max)
-1.8V     24.19mA    33.01mA    13.94mA
-1.44V    5.573mA    15.72mA    900.5uA
-1.32V    2.321mA    10.03mA    65.79uA
-1.2V     480uA      4.923mA    4.186uA
-1.14V    154.2uA    2.957mA    1.246uA
-1.08V    45.9uA     1.597mA    511.8nA
-1.02V    13.54uA    767.1uA    304nA
-960mV    3.924uA    315.3uA    229.8nA
-900mV    1.148uA    112.2uA    188.7nA
-840mV    343.6nA    37.19uA    156.6nA
-720mV    68.79nA    3.72uA     107.5nA
3.6V      -45.08nA   -39.53nA   -67.84nA
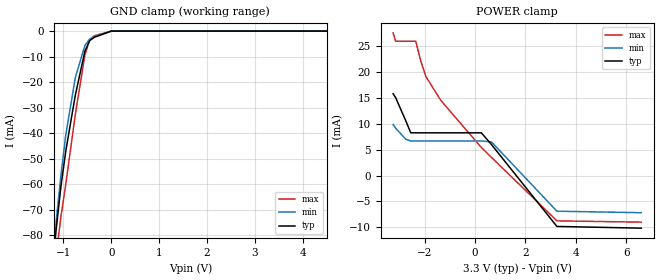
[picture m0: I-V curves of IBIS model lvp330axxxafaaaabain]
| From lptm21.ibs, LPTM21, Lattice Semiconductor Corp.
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|   Model lvp330axxxafaaaabain
[Model]   lvp330axxxafaaaabain
Model_type   Input
Polarity   Non-Inverting
Enable   Active-Low
Vinl =   1.8400V
Vinh =   2.1400V
C_comp   3.0000pF   2.7000pF   3.3000pF
[Temperature Range]   25.0000   0.1050k   -40.0000
[Voltage Range]   3.3000V   3.1400V   3.4700V
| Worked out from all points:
|   GND clamp passes 1 mA (typ) near -0.15 V on its own axis
[GND_clamp]
|Voltage   I(typ)   I(min)   I(max)
-3.3V     -946.4mA   -923.8mA   -970.8mA
-1.25V    -96.54mA   -93.69mA   -106.1mA
-1.2V     -86.84mA   -83.84mA   -96.64mA
-1.15V    -77.54mA   -74.24mA   -87.67mA
-1.05V    -60.58mA   -56.19mA   -72.41mA
-950mV    -46.9mA    -40.46mA   -59.9mA
-750mV    -24.97mA   -18.12mA   -32.43mA
-550mV    -7.78mA    -5.579mA   -9.223mA
-450mV    -3.712mA   -3.095mA   -3.305mA
-350mV    -2.39mA    -2.125mA   -1.807mA
0V        0A         0A         0A
6.6V      0A         0A         0A
[POWER_clamp]
|Voltage   I(typ)   I(min)   I(max)
-3.25V    15.78mA    9.85mA     27.52mA
-3.15V    15.03mA    9.143mA    25.91mA
-2.75V    10.59mA    7.009mA    25.91mA
-2.55V    8.238mA    6.659mA    25.91mA
-2.35V    8.238mA    6.659mA    25.91mA
-2.15V    8.238mA    6.659mA    22.03mA
-1.95V    8.238mA    6.659mA    19.1mA
-1.35V    8.238mA    6.659mA    14.45mA
250mV     8.238mA    6.659mA    5.415mA
650mV     5.991mA    6.495mA    3.515mA
3.25V     -9.826mA   -6.888mA   -8.751mA
6.6V      -10.16mA   -7.176mA   -8.997mA
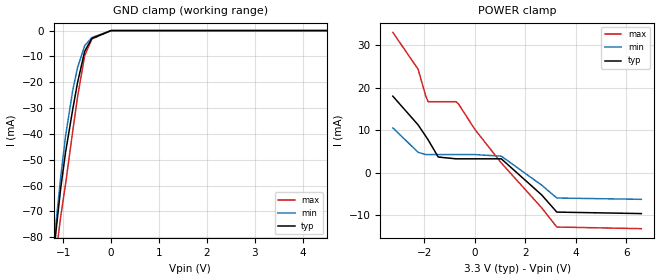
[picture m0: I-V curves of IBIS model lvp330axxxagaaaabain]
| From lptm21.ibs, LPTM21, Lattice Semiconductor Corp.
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|   Model lvp330axxxagaaaabain
[Model]   lvp330axxxagaaaabain
Model_type   Input
Polarity   Non-Inverting
Enable   Active-Low
Vinl =   1.8400V
Vinh =   2.1400V
C_comp   3.0000pF   2.7000pF   3.3000pF
[Temperature Range]   25.0000   0.1050k   -40.0000
[Voltage Range]   3.3000V   3.1400V   3.4700V
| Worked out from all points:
|   GND clamp passes 1 mA (typ) near -0.14 V on its own axis
[GND_clamp]
|Voltage   I(typ)   I(min)   I(max)
-3.3V     -947mA     -924.7mA   -967.3mA
-1.25V    -96.93mA   -94.18mA   -105.1mA
-1.2V     -87.23mA   -84.35mA   -95.58mA
-1.15V    -77.92mA   -74.75mA   -86.83mA
-1.05V    -60.95mA   -56.69mA   -71.94mA
-950mV    -47.24mA   -40.92mA   -59.53mA
-800mV    -30.57mA   -23.21mA   -39.01mA
-700mV    -20.22mA   -14.4mA    -25.77mA
-550mV    -7.999mA   -5.83mA    -9.68mA
-400mV    -3.021mA   -2.684mA   -3.269mA
0V        0A         0A         0A
6.6V      0A         0A         0A
[POWER_clamp]
|Voltage   I(typ)   I(min)   I(max)
-3.25V    17.98mA    10.55mA    32.95mA
-2.25V    11.26mA    4.819mA    24.33mA
-1.95V    8.628mA    4.273mA    18.1mA
-1.85V    7.724mA    4.273mA    16.69mA
-1.45V    3.7mA      4.273mA    16.69mA
-750mV    3.284mA    4.273mA    16.69mA
-650mV    3.284mA    4.273mA    16.19mA
0V        3.284mA    4.273mA    10.2mA
1.05V     3.284mA    3.908mA    2.304mA
2.65V     -5.193mA   -2.899mA   -8.213mA
3.25V     -9.224mA   -5.919mA   -12.73mA
6.6V      -9.572mA   -6.226mA   -13.11mA
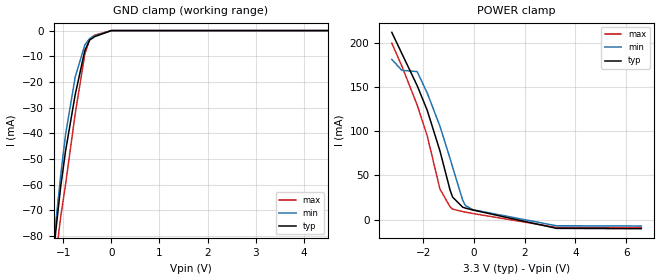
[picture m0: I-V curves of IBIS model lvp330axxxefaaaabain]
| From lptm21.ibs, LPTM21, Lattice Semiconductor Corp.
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|   Model lvp330axxxefaaaabain
[Model]   lvp330axxxefaaaabain
Model_type   Input
Polarity   Non-Inverting
Enable   Active-Low
Vinl =   1.8400V
Vinh =   2.1400V
C_comp   3.0000pF   2.7000pF   3.3000pF
[Temperature Range]   25.0000   0.1050k   -40.0000
[Voltage Range]   3.3000V   3.1400V   3.4700V
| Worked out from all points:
|   GND clamp passes 1 mA (typ) near -0.15 V on its own axis
[GND_clamp]
|Voltage   I(typ)   I(min)   I(max)
-3.3V     -946.4mA   -923.8mA   -970.8mA
-1.25V    -96.54mA   -93.69mA   -106.1mA
-1.2V     -86.84mA   -83.84mA   -96.64mA
-1.15V    -77.54mA   -74.24mA   -87.67mA
-1.05V    -60.58mA   -56.19mA   -72.41mA
-950mV    -46.9mA    -40.46mA   -59.9mA
-750mV    -24.97mA   -18.12mA   -32.43mA
-550mV    -7.78mA    -5.579mA   -9.223mA
-450mV    -3.712mA   -3.095mA   -3.305mA
-350mV    -2.39mA    -2.125mA   -1.807mA
0V        0A         0A         0A
6.6V      0A         0A         0A
[POWER_clamp]
|Voltage   I(typ)   I(min)   I(max)
-3.25V    211.7mA    181.1mA    199.5mA
-2.85V    187.6mA    168.8mA    173.4mA
-2.25V    151.6mA    167.4mA    129.7mA
-1.85V    123.5mA    143.1mA    94.61mA
-1.35V    77.76mA    105.7mA    34.61mA
-950mV    33.5mA     69.13mA    14.53mA
-850mV    25.51mA    59.42mA    11.89mA
-450mV    14.04mA    21.9mA     9.103mA
-350mV    13.16mA    16.09mA    8.566mA
-50mV     10.92mA    11.27mA    6.976mA
3.25V     -9.826mA   -6.888mA   -8.751mA
6.6V      -10.16mA   -7.176mA   -8.997mA
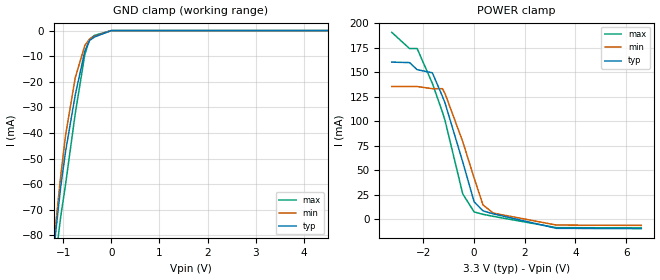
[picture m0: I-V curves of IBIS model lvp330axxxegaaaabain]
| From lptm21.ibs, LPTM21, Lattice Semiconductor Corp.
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|   Model lvp330axxxegaaaabain
[Model]   lvp330axxxegaaaabain
Model_type   Input
Polarity   Non-Inverting
Enable   Active-Low
Vinl =   1.8400V
Vinh =   2.1400V
C_comp   3.0000pF   2.7000pF   3.3000pF
[Temperature Range]   25.0000   0.1050k   -40.0000
[Voltage Range]   3.3000V   3.1400V   3.4700V
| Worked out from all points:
|   GND clamp passes 1 mA (typ) near -0.14 V on its own axis
[GND_clamp]
|Voltage   I(typ)   I(min)   I(max)
-3.3V     -947mA     -924.7mA   -971.1mA
-1.25V    -96.93mA   -94.18mA   -106.3mA
-1.2V     -87.23mA   -84.35mA   -96.78mA
-1.15V    -77.92mA   -74.75mA   -87.84mA
-1.05V    -60.95mA   -56.69mA   -72.56mA
-950mV    -47.24mA   -40.92mA   -60.05mA
-750mV    -25.26mA   -18.49mA   -32.57mA
-550mV    -7.999mA   -5.83mA    -9.332mA
-450mV    -3.874mA   -3.282mA   -3.386mA
-350mV    -2.509mA   -2.264mA   -1.867mA
0V        0A         0A         0A
6.6V      0A         0A         0A
[POWER_clamp]
|Voltage   I(typ)   I(min)   I(max)
-3.25V    160.3mA    135.4mA    190.6mA
-2.55V    159.8mA    135.4mA    174.1mA
-2.25V    152.6mA    135.4mA    174.1mA
-1.65V    149.4mA    133.2mA    138.7mA
-1.25V    125.3mA    133.2mA    109.2mA
-1.15V    118.7mA    128.3mA    100.9mA
-450mV    58.46mA    79.22mA    25.92mA
0V        17.82mA    42.05mA    7.497mA
350mV     8.585mA    14.62mA    5.055mA
750mV     5.557mA    6.334mA    3.004mA
3.25V     -9.224mA   -5.919mA   -8.53mA
6.6V      -9.572mA   -6.226mA   -8.784mA
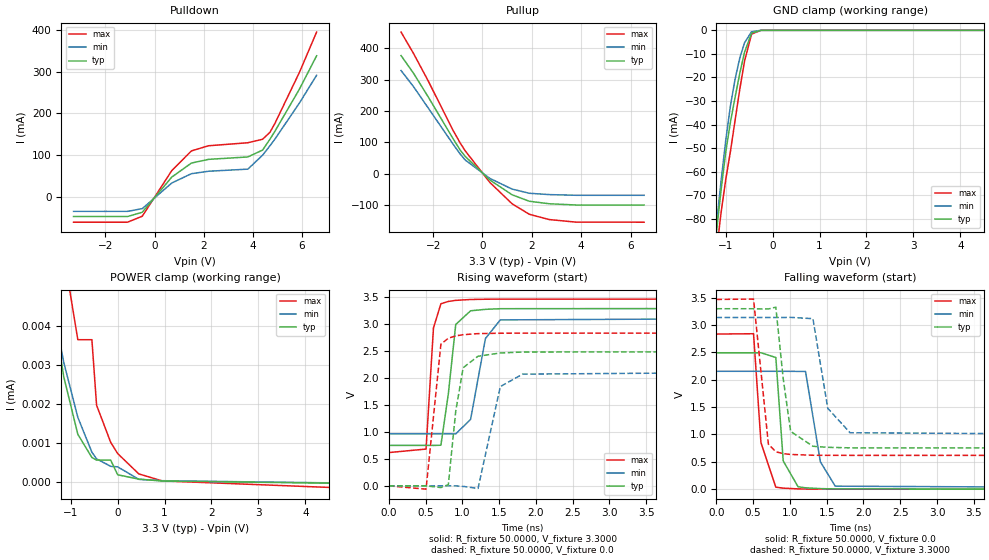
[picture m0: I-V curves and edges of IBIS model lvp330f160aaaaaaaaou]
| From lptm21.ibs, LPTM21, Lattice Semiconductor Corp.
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|   Model lvp330f160aaaaaaaaou
[Model]   lvp330f160aaaaaaaaou
Model_type   Output
Polarity   Non-Inverting
Enable   Active-Low
Vmeas =   1.9900V
Cref =   3.0000pF
Rref =   50.0000
Vref =   1.9900V
C_comp   4.2000pF   3.8000pF   7.5000pF
[Temperature Range]   25.0000   0.1050k   -40.0000
[Voltage Range]   3.3000V   3.1400V   3.4700V
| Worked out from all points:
|   slope of the pulldown table from 0 to 0.495 V, typ, clamps not added: 13.9 ohm
|   slope of the pullup table from 0 to 0.495 V, typ, clamps not added: 15.1 ohm
|   GND clamp passes 1 mA (typ) near -0.44 V on its own axis
|   rising waveform, R_fixture 50.0000, V_fixture 3.3000: 20-80 % time 132ps typ, 176ps min, 76.8ps max; typ from 0.752 V to 3.3 V
|   rising waveform, R_fixture 50.0000, V_fixture 0.0: 20-80 % time 142ps typ, 192ps min, 129ps max; typ from 0 V to 2.49 V
|   falling waveform, R_fixture 50.0000, V_fixture 0.0: 20-80 % time 82.9ps typ, 125ps min, 110ps max; typ from 2.49 V to 0 V
|   falling waveform, R_fixture 50.0000, V_fixture 3.3000: 20-80 % time 139ps typ, 180ps min, 131ps max; typ from 3.3 V to 0.752 V
[Pulldown]
|Voltage   I(typ)   I(min)   I(max)
-3.3V     -46.05mA   -33.74mA   -59.55mA
-1.1V     -46.05mA   -33.74mA   -59.55mA
-500mV    -35.8mA    -27.15mA   -45.23mA
700mV     48.06mA    34mA       63.55mA
1.5V      81.57mA    56.2mA     110.6mA
2.2V      90.42mA    62.08mA    122.9mA
3.8V      96.2mA     67.07mA    130.1mA
4.4V      112.6mA    100.4mA    138.4mA
4.7V      138.5mA    122.9mA    155.1mA
4.9V      157.3mA    138.6mA    176mA
5.9V      258mA      224.9mA    297.9mA
6.6V      337.6mA    291.1mA    394.2mA
[Pullup]
|Voltage   I(typ)   I(min)   I(max)
-3.3V     377.1mA    329.3mA    452.2mA
-2.8V     321.3mA    278.4mA    384.6mA
-2.2V     245.1mA    209.7mA    296.2mA
-1.2V     112.6mA    94.92mA    139.1mA
-900mV    74.65mA    62.1mA     97.29mA
-700mV    54.88mA    43.33mA    72.73mA
300mV     -20.61mA   -15.5mA    -28.44mA
1.2V      -67.79mA   -49.58mA   -96.57mA
1.9V      -88.52mA   -62.97mA   -130.2mA
2.7V      -96.45mA   -67.2mA    -146.9mA
3.8V      -100.5mA   -69.39mA   -155.3mA
6.55V     -100.5mA   -69.39mA   -155.4mA
[GND_clamp]
|Voltage   I(typ)   I(min)   I(max)
-3.3V     -955.3mA   -930.3mA   -978mA
-1.2V     -86.18mA   -82.93mA   -94.91mA
-1.15V    -76.73mA   -73.29mA   -85.74mA
-1.1V     -67.71mA   -63.95mA   -77.28mA
-1V       -51.52mA   -46.57mA   -63.21mA
-900mV    -38.87mA   -31.88mA   -51.26mA
-800mV    -28.25mA   -20.58mA   -37.97mA
-700mV    -18.1mA    -11.63mA   -24.81mA
-600mV    -9.267mA   -5.265mA   -13.06mA
-450mV    -1.181mA   -586.6uA   -1.592mA
-250mV    -3.532uA   -4.055uA   -3.003uA
6.6V      0A         0A         0A
[POWER_clamp]
|Voltage   I(typ)   I(min)   I(max)
-3.25V    664.8uA    749.4uA    597.1uA
-1.55V    5.919uA    5.717uA    11.4uA
-1.45V    4.992uA    4.978uA    9.755uA
-1.15V    2.708uA    3.077uA    5.867uA
-850mV    1.23uA     1.666uA    3.658uA
-550mV    635nA      770.2nA    3.658uA
-450mV    567.2nA    599.1nA    1.977uA
-150mV    567.2nA    407.7nA    1.026uA
0V        190.5nA    394.5nA    734.7nA
450mV     79.23nA    72.94nA    213.9nA
950mV     30.32nA    38.42nA    33.55nA
6.6V      -57.56nA   -49.34nA   -232.5nA
[Ramp]
| variable   typ   min   max
dV/dt_r  1.4966/0.1403n   1.2936/0.1899n   1.7022/0.1278n
dV/dt_f  1.5290/0.1376n   1.3043/0.1782n   1.7112/0.1294n
R_load = 50.0000
[Rising Waveform]
R_fixture=   50.0000
V_fixture=   3.3000
V_fixture_min=   3.1400
V_fixture_max=   3.4700
|time   V(typ)   V(min)   V(max)
0s        751.6mV    966.1mV    618mV
505.1ps   751.7mV    966.1mV    683.2mV
606.1ps   750.6mV    966.1mV    2.934V
707.1ps   754.6mV    966.1mV    3.382V
808.1ps   1.707V     966.5mV    3.426V
909.1ps   2.998V     965.3mV    3.446V
1.111ns   3.252V     1.234V     3.462V
1.313ns   3.279V     2.738V     3.467V
1.515ns   3.291V     3.083V     3.469V
10ns      3.3V       3.14V      3.47V
[Rising Waveform]
R_fixture=   50.0000
V_fixture=   0.0
V_fixture_min=   0.0
V_fixture_max=   0.0
|time   V(typ)   V(min)   V(max)
0s        484.9nV    653.8nV    458.4nV
505.1ps   965.7nV    396.4nV    -61.92mV
707.1ps   -31.85mV   22.19uV    2.63V
808.1ps   22.23mV    16.02uV    2.743V
909.1ps   1.387V     -277.4uV   2.786V
1.01ns    2.195V     -10.24mV   2.808V
1.212ns   2.408V     -48.56mV   2.828V
1.515ns   2.468V     1.844V     2.835V
1.818ns   2.486V     2.075V     2.837V
10ns      2.494V     2.156V     2.837V
[Falling Waveform]
R_fixture=   50.0000
V_fixture=   0.0
V_fixture_min=   0.0
V_fixture_max=   0.0
|time   V(typ)   V(min)   V(max)
0s        2.494V     2.156V     2.837V
505.1ps   2.494V     2.156V     2.843V
606.1ps   2.495V     2.156V     849.6mV
808.1ps   2.408V     2.156V     36.53mV
909.1ps   515.2mV    2.156V     18.56mV
1.111ns   43.14mV    2.154V     4.92mV
1.212ns   25.35mV    2.154V     2.505mV
1.414ns   10.16mV    501mV      696.7uV
1.616ns   4.103mV    54.88mV    252.1uV
10ns      13.46uV    3.911uV    -10.62uV
[Falling Waveform]
R_fixture=   50.0000
V_fixture=   3.3000
V_fixture_min=   3.1400
V_fixture_max=   3.4700
|time   V(typ)   V(min)   V(max)
0s        3.3V       3.14V      3.47V
505.1ps   3.3V       3.14V      3.477V
707.1ps   3.295V     3.14V      824.1mV
808.1ps   3.329V     3.14V      683.9mV
909.1ps   2.014V     3.14V      649.9mV
1.01ns    1.056V     3.142V     634.8mV
1.313ns   784.9mV    3.118V     620.4mV
1.515ns   765.5mV    1.478V     618.6mV
1.818ns   755.5mV    1.032V     618.1mV
10ns      751.6mV    966.1mV    617.9mV
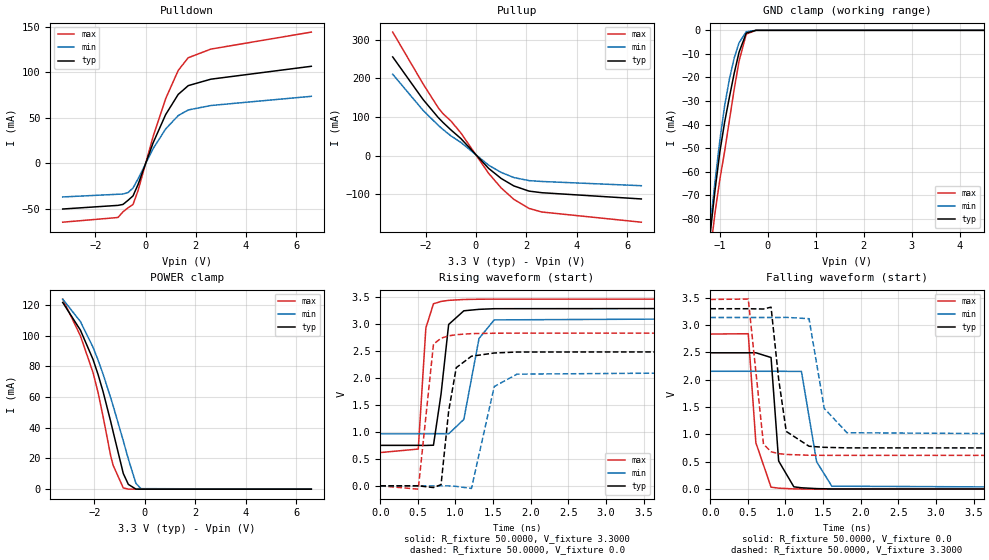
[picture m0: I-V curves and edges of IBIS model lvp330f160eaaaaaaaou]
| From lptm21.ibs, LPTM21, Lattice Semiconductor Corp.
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|   Model lvp330f160eaaaaaaaou
[Model]   lvp330f160eaaaaaaaou
Model_type   Output
Polarity   Non-Inverting
Enable   Active-Low
Vmeas =   1.9900V
Cref =   3.0000pF
Rref =   50.0000
Vref =   1.9900V
C_comp   4.2000pF   3.8000pF   7.5000pF
[Temperature Range]   25.0000   0.1050k   -40.0000
[Voltage Range]   3.3000V   3.1400V   3.4700V
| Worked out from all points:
|   slope of the pulldown table from 0 to 0.495 V, typ, clamps not added: 13.9 ohm
|   slope of the pullup table from 0 to 0.495 V, typ, clamps not added: 15.1 ohm
|   GND clamp passes 1 mA (typ) near -0.44 V on its own axis
|   POWER clamp passes 1 mA (typ) near -0.54 V on its own axis
|   rising waveform, R_fixture 50.0000, V_fixture 3.3000: 20-80 % time 132ps typ, 176ps min, 76.8ps max; typ from 0.752 V to 3.3 V
|   rising waveform, R_fixture 50.0000, V_fixture 0.0: 20-80 % time 142ps typ, 192ps min, 129ps max; typ from 0 V to 2.49 V
|   falling waveform, R_fixture 50.0000, V_fixture 0.0: 20-80 % time 82.9ps typ, 125ps min, 110ps max; typ from 2.49 V to 0 V
|   falling waveform, R_fixture 50.0000, V_fixture 3.3000: 20-80 % time 139ps typ, 180ps min, 131ps max; typ from 3.3 V to 0.752 V
[Pulldown]
|Voltage   I(typ)   I(min)   I(max)
-3.3V     -50.23mA   -36.96mA   -64.72mA
-1.1V     -46.23mA   -34.01mA   -59.55mA
-900mV    -45.2mA    -33.74mA   -53.38mA
-700mV    -40.7mA    -32.12mA   -48.95mA
-500mV    -35.8mA    -27.15mA   -45.23mA
-300mV    -23.31mA   -17.07mA   -30.01mA
300mV     22.52mA    16.15mA    29.41mA
800mV     53.61mA    37.79mA    71.12mA
1.3V      75.8mA     52.5mA     102.2mA
1.7V      85.44mA    58.7mA     116.1mA
2.6V      92.52mA    63.57mA    125.6mA
6.6V      106.7mA    73.69mA    144.3mA
[Pullup]
|Voltage   I(typ)   I(min)   I(max)
-3.3V     255.2mA    210.4mA    319.4mA
-2.1V     145.3mA    117.2mA    185.8mA
-1.5V     98.69mA    78.53mA    124.1mA
-1.3V     85.28mA    67.13mA    107.9mA
-1V       66.86mA    51.35mA    89.96mA
-600mV    44.14mA    34.11mA    58.68mA
500mV     -33.02mA   -24.69mA   -45.86mA
1V        -59.26mA   -43.64mA   -83.75mA
1.5V      -78.43mA   -56.74mA   -113.2mA
2.1V      -91.79mA   -64.71mA   -136.5mA
2.6V      -95.92mA   -66.88mA   -145.8mA
6.55V     -112.1mA   -77.85mA   -172.2mA
[GND_clamp]
|Voltage   I(typ)   I(min)   I(max)
-3.3V     -955.3mA   -930.3mA   -978mA
-1.2V     -86.18mA   -82.93mA   -94.91mA
-1.15V    -76.73mA   -73.29mA   -85.74mA
-1.1V     -67.71mA   -63.95mA   -77.28mA
-1V       -51.52mA   -46.57mA   -63.21mA
-900mV    -38.87mA   -31.88mA   -51.26mA
-800mV    -28.25mA   -20.58mA   -37.97mA
-700mV    -18.1mA    -11.63mA   -24.81mA
-600mV    -9.267mA   -5.265mA   -13.06mA
-450mV    -1.181mA   -586.6uA   -1.592mA
-250mV    -3.532uA   -4.055uA   -3.003uA
6.6V      0A         0A         0A
[POWER_clamp]
|Voltage   I(typ)   I(min)   I(max)
-3.25V    121.6mA    123.7mA    123.8mA
-2.55V    103.6mA    109.2mA    99.91mA
-2.05V    84.55mA    92.42mA    76.01mA
-1.85V    74.75mA    84.09mA    62.98mA
-1.65V    63.47mA    74.86mA    47.24mA
-1.35V    44.14mA    59.56mA    21.79mA
-1.25V    37.23mA    54.16mA    15.46mA
-850mV    10.22mA    31.49mA    813uA
-650mV    3.122mA    19.66mA    19.66uA
-350mV    37.56uA    3.815mA    1.535uA
-150mV    934.2nA    336.7uA    1.026uA
6.6V      -57.56nA   -49.34nA   -232.5nA
[Ramp]
| variable   typ   min   max
dV/dt_r  1.4966/0.1403n   1.2936/0.1899n   1.7022/0.1278n
dV/dt_f  1.5290/0.1376n   1.3043/0.1782n   1.7112/0.1294n
R_load = 50.0000
[Rising Waveform]
R_fixture=   50.0000
V_fixture=   3.3000
V_fixture_min=   3.1400
V_fixture_max=   3.4700
|time   V(typ)   V(min)   V(max)
0s        751.6mV    966.1mV    618mV
505.1ps   751.7mV    966.1mV    683.2mV
606.1ps   750.6mV    966.1mV    2.934V
707.1ps   754.6mV    966.1mV    3.382V
808.1ps   1.707V     966.5mV    3.426V
909.1ps   2.998V     965.3mV    3.446V
1.111ns   3.252V     1.234V     3.462V
1.313ns   3.279V     2.738V     3.467V
1.515ns   3.291V     3.083V     3.469V
10ns      3.3V       3.14V      3.47V
[Rising Waveform]
R_fixture=   50.0000
V_fixture=   0.0
V_fixture_min=   0.0
V_fixture_max=   0.0
|time   V(typ)   V(min)   V(max)
0s        484.9nV    653.8nV    458.4nV
505.1ps   965.7nV    396.4nV    -61.92mV
707.1ps   -31.85mV   22.19uV    2.63V
808.1ps   22.23mV    16.02uV    2.743V
909.1ps   1.387V     -277.4uV   2.786V
1.01ns    2.195V     -10.24mV   2.808V
1.212ns   2.408V     -48.56mV   2.828V
1.515ns   2.468V     1.844V     2.835V
1.818ns   2.486V     2.075V     2.837V
10ns      2.494V     2.156V     2.837V
[Falling Waveform]
R_fixture=   50.0000
V_fixture=   0.0
V_fixture_min=   0.0
V_fixture_max=   0.0
|time   V(typ)   V(min)   V(max)
0s        2.494V     2.156V     2.837V
505.1ps   2.494V     2.156V     2.843V
606.1ps   2.495V     2.156V     849.6mV
808.1ps   2.408V     2.156V     36.53mV
909.1ps   515.2mV    2.156V     18.56mV
1.111ns   43.14mV    2.154V     4.92mV
1.212ns   25.35mV    2.154V     2.505mV
1.414ns   10.16mV    501mV      696.7uV
1.616ns   4.103mV    54.88mV    252.1uV
10ns      13.46uV    3.911uV    -10.62uV
[Falling Waveform]
R_fixture=   50.0000
V_fixture=   3.3000
V_fixture_min=   3.1400
V_fixture_max=   3.4700
|time   V(typ)   V(min)   V(max)
0s        3.3V       3.14V      3.47V
505.1ps   3.3V       3.14V      3.477V
707.1ps   3.295V     3.14V      824.1mV
808.1ps   3.329V     3.14V      683.9mV
909.1ps   2.014V     3.14V      649.9mV
1.01ns    1.056V     3.142V     634.8mV
1.313ns   784.9mV    3.118V     620.4mV
1.515ns   765.5mV    1.478V     618.6mV
1.818ns   755.5mV    1.032V     618.1mV
10ns      751.6mV    966.1mV    617.9mV
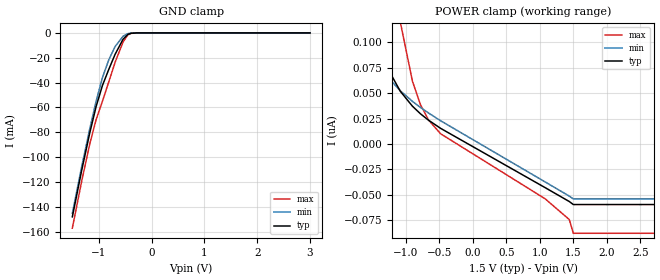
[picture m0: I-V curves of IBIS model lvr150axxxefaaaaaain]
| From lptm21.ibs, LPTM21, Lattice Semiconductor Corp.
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|   Model lvr150axxxefaaaaaain
[Model]   lvr150axxxefaaaaaain
Model_type   Input
Polarity   Non-Inverting
Enable   Active-Low
Vinl =   0.3750V
Vinh =   1.1250V
C_comp   4.2000pF   3.8000pF   7.5000pF
[Temperature Range]   25.0000   0.1050k   -40.0000
[Voltage Range]   1.5000V   1.4300V   1.5800V
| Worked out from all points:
|   GND clamp passes 1 mA (typ) near -0.44 V on its own axis
[GND_clamp]
|Voltage   I(typ)   I(min)   I(max)
-1.5V     -148.1mA   -145.3mA   -157.2mA
-1.32V    -110.1mA   -107.1mA   -118.8mA
-1.17V    -80.54mA   -77.2mA    -89.42mA
-1.05V    -59.32mA   -55.09mA   -69.84mA
-930mV    -42.35mA   -35.99mA   -55.05mA
-810mV    -29.39mA   -21.69mA   -39.42mA
-690mV    -17.23mA   -10.96mA   -23.66mA
-540mV    -5.153mA   -2.725mA   -7.352mA
-450mV    -1.251mA   -629.5uA   -1.7mA
-390mV    -319.3uA   -176.8uA   -395.6uA
-270mV    -11.4uA    -9.004uA   -17.31uA
3V        0A         0A         0A
[POWER_clamp]
|Voltage   I(typ)   I(min)   I(max)
-1.5V     111.4nA    89.35nA    438.6nA
-1.44V    100nA      80.89nA    372.2nA
-1.32V    80.44nA    69.66nA    262.5nA
-1.08V    51.8nA     52.29nA    119.8nA
-900mV    37.19nA    41.96nA    61.84nA
-780mV    29.68nA    35.97nA    38.66nA
-660mV    23.39nA    30.48nA    23.6nA
-480mV    15.37nA    22.85nA    10.04nA
1.08V     -43.09nA   -37.46nA   -54.09nA
1.44V     -56.77nA   -51.44nA   -74.53nA
1.5V      -59.73nA   -54.16nA   -88.06nA
3V        -59.73nA   -54.16nA   -88.06nA
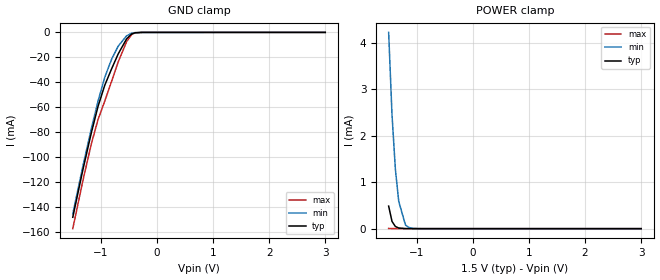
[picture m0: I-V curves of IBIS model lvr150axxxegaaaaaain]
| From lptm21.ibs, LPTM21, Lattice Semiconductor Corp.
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|   Model lvr150axxxegaaaaaain
[Model]   lvr150axxxegaaaaaain
Model_type   Input
Polarity   Non-Inverting
Enable   Active-Low
Vinl =   0.3750V
Vinh =   1.1250V
C_comp   4.2000pF   3.8000pF   7.5000pF
[Temperature Range]   25.0000   0.1050k   -40.0000
[Voltage Range]   1.5000V   1.4300V   1.5800V
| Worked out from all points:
|   GND clamp passes 1 mA (typ) near -0.44 V on its own axis
[GND_clamp]
|Voltage   I(typ)   I(min)   I(max)
-1.5V     -148.1mA   -145.3mA   -157.2mA
-1.32V    -110.1mA   -107.1mA   -118.8mA
-1.17V    -80.53mA   -77.19mA   -89.4mA
-1.05V    -59.3mA    -55.08mA   -69.82mA
-930mV    -42.34mA   -35.98mA   -55.03mA
-810mV    -29.38mA   -21.68mA   -39.41mA
-690mV    -17.22mA   -10.95mA   -23.65mA
-540mV    -5.147mA   -2.721mA   -7.346mA
-450mV    -1.248mA   -627.9uA   -1.697mA
-390mV    -318.2uA   -176.3uA   -394.1uA
-270mV    -11.35uA   -8.979uA   -17.24uA
3V        0A         0A         0A
[POWER_clamp]
|Voltage   I(typ)   I(min)   I(max)
-1.5V     485.2uA    4.227mA    5.258uA
-1.44V    155.9uA    2.45mA     1.506uA
-1.38V    46.29uA    1.278mA    579.7nA
-1.32V    13.62uA    585.3uA    325.3nA
-1.2V     1.156uA    78.6uA     195.4nA
-1.14V    345.2nA    25.72uA    162.3nA
-1.08V    122.2nA    8.164uA    134.7nA
-1.02V    69.51nA    2.524uA    111.7nA
-960mV    56.93nA    765.8nA    92.52nA
-900mV    51.57nA    237.9nA    76.78nA
-780mV    43.94nA    57.54nA    53.6nA
3V        -44.76nA   -40.22nA   -61.16nA
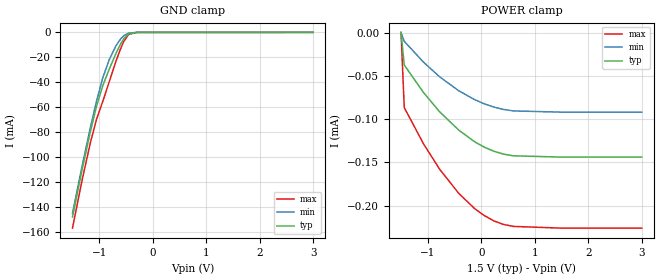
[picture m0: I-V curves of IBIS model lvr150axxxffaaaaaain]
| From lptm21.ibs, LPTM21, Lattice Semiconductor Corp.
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|   Model lvr150axxxffaaaaaain
[Model]   lvr150axxxffaaaaaain
Model_type   Input
Polarity   Non-Inverting
Enable   Active-Low
Vinl =   0.3750V
Vinh =   1.1250V
C_comp   4.2000pF   3.8000pF   7.5000pF
[Temperature Range]   25.0000   0.1050k   -40.0000
[Voltage Range]   1.5000V   1.4300V   1.5800V
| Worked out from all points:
|   GND clamp passes 1 mA (typ) near -0.44 V on its own axis
[GND_clamp]
|Voltage   I(typ)   I(min)   I(max)
-1.5V     -148.1mA   -145.2mA   -157mA
-1.32V    -110.1mA   -107.1mA   -118.6mA
-1.17V    -80.43mA   -77.13mA   -89.24mA
-1.05V    -59.21mA   -55.02mA   -69.67mA
-930mV    -42.25mA   -35.93mA   -54.89mA
-810mV    -29.29mA   -21.64mA   -39.26mA
-690mV    -17.14mA   -10.92mA   -23.51mA
-600mV    -9.276mA   -5.3mA     -13.03mA
-540mV    -5.085mA   -2.692mA   -7.226mA
-450mV    -1.204mA   -610.1uA   -1.607mA
-300mV    -21.1uA    -17.86uA   -17.4uA
3V        0A         0A         0A
[POWER_clamp]
|Voltage   I(typ)   I(min)   I(max)
-1.5V     323nA      234.7nA    718nA
-1.44V    -37.16uA   -9.677uA   -86.43uA
-1.08V    -68.96uA   -33.82uA   -128.4uA
-780mV    -91.18uA   -50.68uA   -157.7uA
-420mV    -112.6uA   -67uA      -185.9uA
-120mV    -126.2uA   -77.35uA   -203.7uA
60mV      -132.4uA   -82.14uA   -211.7uA
240mV     -137.1uA   -85.89uA   -217.8uA
420mV     -140.4uA   -88.59uA   -221.9uA
600mV     -142.3uA   -90.31uA   -224.1uA
1.5V      -143.8uA   -91.7uA    -226.1uA
3V        -143.8uA   -91.7uA    -226.1uA
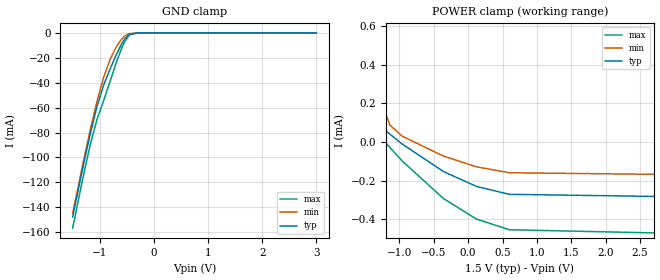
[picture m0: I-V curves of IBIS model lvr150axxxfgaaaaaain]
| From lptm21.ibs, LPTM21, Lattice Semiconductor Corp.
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|   Model lvr150axxxfgaaaaaain
[Model]   lvr150axxxfgaaaaaain
Model_type   Input
Polarity   Non-Inverting
Enable   Active-Low
Vinl =   0.3750V
Vinh =   1.1250V
C_comp   4.2000pF   3.8000pF   7.5000pF
[Temperature Range]   25.0000   0.1050k   -40.0000
[Voltage Range]   1.5000V   1.4300V   1.5800V
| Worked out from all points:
|   GND clamp passes 1 mA (typ) near -0.44 V on its own axis
[GND_clamp]
|Voltage   I(typ)   I(min)   I(max)
-1.5V     -147.9mA   -145.1mA   -156.8mA
-1.29V    -103.8mA   -100.8mA   -112.2mA
-1.17V    -80.31mA   -77.07mA   -89.02mA
-1.05V    -59.1mA    -54.96mA   -69.47mA
-930mV    -42.15mA   -35.87mA   -54.7mA
-810mV    -29.2mA    -21.58mA   -39.08mA
-690mV    -17.05mA   -10.87mA   -23.34mA
-600mV    -9.201mA   -5.265mA   -12.89mA
-540mV    -5.022mA   -2.665mA   -7.103mA
-450mV    -1.167mA   -596.1uA   -1.527mA
-300mV    -19.4uA    -17.4uA    -13.5uA
3V        0A         0A         0A
[POWER_clamp]
|Voltage   I(typ)   I(min)   I(max)
-1.5V     591uA      4.361mA    126uA
-1.44V    260.5uA    2.555mA    98.23uA
-1.38V    146.7uA    1.364mA    72.05uA
-1.32V    103.4uA    662.5uA    46.42uA
-1.26V    78.56uA    301uA      21.1uA
-1.2V     58.74uA    147.3uA    -3.956uA
-1.14V    40.49uA    87.26uA    -28.56uA
-960mV    -11.12uA   29.43uA    -98.86uA
-360mV    -153.4uA   -73.5uA    -293.2uA
120mV     -230.6uA   -129uA     -399.5uA
600mV     -271.5uA   -159.7uA   -454.9uA
3V        -283.8uA   -169.1uA   -473.6uA
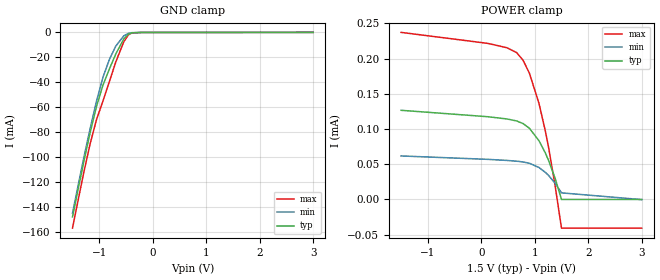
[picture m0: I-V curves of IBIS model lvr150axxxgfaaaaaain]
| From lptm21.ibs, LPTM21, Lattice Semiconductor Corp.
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|   Model lvr150axxxgfaaaaaain
[Model]   lvr150axxxgfaaaaaain
Model_type   Input
Polarity   Non-Inverting
Enable   Active-Low
Vinl =   0.3750V
Vinh =   1.1250V
C_comp   4.2000pF   3.8000pF   7.5000pF
[Temperature Range]   25.0000   0.1050k   -40.0000
[Voltage Range]   1.5000V   1.4300V   1.5800V
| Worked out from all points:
|   GND clamp passes 1 mA (typ) near -0.43 V on its own axis
[GND_clamp]
|Voltage   I(typ)   I(min)   I(max)
-1.5V     -148.2mA   -145.3mA   -157.2mA
-1.29V    -104.1mA   -101mA     -112.7mA
-1.17V    -80.57mA   -77.22mA   -89.46mA
-1.05V    -59.35mA   -55.11mA   -69.9mA
-930mV    -42.4mA    -36.02mA   -55.11mA
-810mV    -29.43mA   -21.72mA   -39.49mA
-690mV    -17.28mA   -11mA      -23.73mA
-540mV    -5.218mA   -2.773mA   -7.441mA
-450mV    -1.328mA   -683uA     -1.811mA
-390mV    -402.4uA   -230.6uA   -519.4uA
-210mV    -60.73uA   -33.9uA    -106.8uA
3V        0A         0A         0A
[POWER_clamp]
|Voltage   I(typ)   I(min)   I(max)
-1.5V     126.5uA    61.7uA     237.1uA
120mV     117.4uA    56.86uA    221.5uA
480mV     114.2uA    55.33uA    215.3uA
660mV     111.4uA    54.26uA    208.4uA
780mV     107.7uA    53.19uA    197.7uA
900mV     101uA      51.31uA    179.2uA
1.08V     83.2uA     45.23uA    136uA
1.2V      65.66uA    38.31uA    96.41uA
1.26V     55.06uA    33.89uA    73.22uA
1.38V     30.1uA     23.01uA    19.84uA
1.5V      -58.12nA   9.3uA      -40.77uA
3V        -58.12nA   -299.6nA   -40.77uA
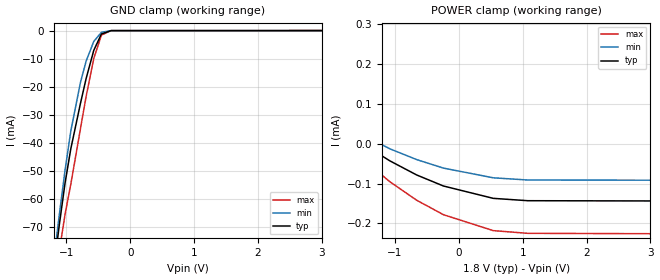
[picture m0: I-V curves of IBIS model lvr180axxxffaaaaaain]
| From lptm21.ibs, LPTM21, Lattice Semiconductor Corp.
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|   Model lvr180axxxffaaaaaain
[Model]   lvr180axxxffaaaaaain
Model_type   Input
Polarity   Non-Inverting
Enable   Active-Low
Vinl =   0.6300V
Vinh =   1.1700V
C_comp   4.2000pF   3.8000pF   7.5000pF
[Temperature Range]   25.0000   0.1050k   -40.0000
[Voltage Range]   1.8000V   1.7100V   1.8900V
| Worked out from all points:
|   GND clamp passes 1 mA (typ) near -0.44 V on its own axis
[GND_clamp]
|Voltage   I(typ)   I(min)   I(max)
-1.8V     -240.2mA   -229.4mA   -254.1mA
-1.2V     -86.14mA   -82.96mA   -94.81mA
-1.17V    -80.43mA   -77.13mA   -89.24mA
-1.11V    -69.44mA   -65.81mA   -78.81mA
-1.02V    -54.48mA   -49.89mA   -65.65mA
-930mV    -42.25mA   -35.93mA   -54.89mA
-780mV    -26.15mA   -18.62mA   -35.22mA
-690mV    -17.14mA   -10.92mA   -23.51mA
-570mV    -7.048mA   -3.877mA   -9.974mA
-450mV    -1.204mA   -610.1uA   -1.607mA
-300mV    -21.1uA    -17.86uA   -17.4uA
3.6V      0A         0A         0A
[POWER_clamp]
|Voltage   I(typ)   I(min)   I(max)
-1.8V     43.72uA    1.05mA     7.983uA
-1.74V    30.28uA    471.5uA    -1.71uA
-1.68V    21.37uA    194.3uA    -11.23uA
-1.62V    13.91uA    84.2uA     -20.54uA
-1.56V    6.949uA    43.11uA    -29.65uA
-1.44V    -6.422uA   17.07uA    -47.26uA
-1.08V    -42.85uA   -12.57uA   -95.17uA
-660mV    -78.32uA   -39.77uA   -141.7uA
-240mV    -106.1uA   -61.16uA   -178.1uA
540mV     -137.1uA   -85.52uA   -218.1uA
1.08V     -143uA     -91.08uA   -224.9uA
3.6V      -143.8uA   -91.69uA   -226.1uA
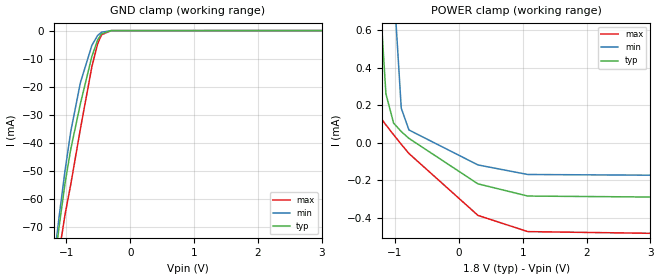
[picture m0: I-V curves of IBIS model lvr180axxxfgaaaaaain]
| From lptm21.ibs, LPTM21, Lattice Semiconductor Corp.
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|   Model lvr180axxxfgaaaaaain
[Model]   lvr180axxxfgaaaaaain
Model_type   Input
Polarity   Non-Inverting
Enable   Active-Low
Vinl =   0.6300V
Vinh =   1.1700V
C_comp   4.2000pF   3.8000pF   7.5000pF
[Temperature Range]   25.0000   0.1050k   -40.0000
[Voltage Range]   1.8000V   1.7100V   1.8900V
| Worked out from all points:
|   GND clamp passes 1 mA (typ) near -0.44 V on its own axis
|   POWER clamp passes 1 mA (typ) near -1.23 V on its own axis
[GND_clamp]
|Voltage   I(typ)   I(min)   I(max)
-1.8V     -240mA     -229.3mA   -253.8mA
-1.2V     -86.02mA   -82.89mA   -94.58mA
-1.17V    -80.3mA    -77.06mA   -89.02mA
-1.11V    -69.31mA   -65.74mA   -78.6mA
-1.02V    -54.36mA   -49.82mA   -65.44mA
-930mV    -42.14mA   -35.87mA   -54.69mA
-780mV    -26.05mA   -18.56mA   -35.03mA
-600mV    -9.198mA   -5.263mA   -12.88mA
-510mV    -3.375mA   -1.734mA   -4.747mA
-450mV    -1.166mA   -595.4uA   -1.525mA
-300mV    -19.5uA    -17.4uA    -13.6uA
3.6V      0A         0A         0A
[POWER_clamp]
|Voltage   I(typ)   I(min)   I(max)
-1.8V     24.58mA    33.52mA    14.14mA
-1.44V    5.727mA    16.01mA    1.044mA
-1.32V    2.445mA    10.24mA    214uA
-1.26V    1.303mA    7.528mA    155uA
-1.2V     587.2uA    5.071mA    122.4uA
-1.14V    260.2uA    3.074mA    94.83uA
-1.02V    104.5uA    848uA      42.66uA
-900mV    59.52uA    183.8uA    -8.195uA
-780mV    23.23uA    68.1uA     -57.24uA
300mV     -218.8uA   -118.1uA   -386.6uA
1.08V     -283.7uA   -169uA     -473uA
3.6V      -290.6uA   -173.9uA   -484.9uA
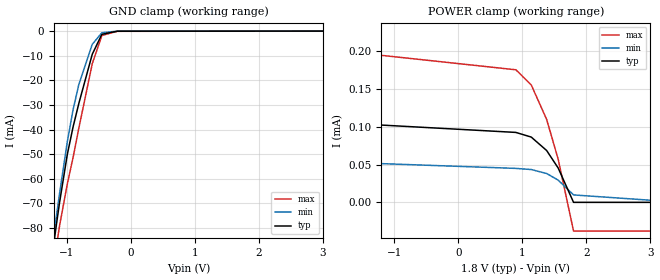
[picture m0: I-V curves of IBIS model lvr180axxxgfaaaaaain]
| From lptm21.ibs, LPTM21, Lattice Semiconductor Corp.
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|   Model lvr180axxxgfaaaaaain
[Model]   lvr180axxxgfaaaaaain
Model_type   Input
Polarity   Non-Inverting
Enable   Active-Low
Vinl =   0.6300V
Vinh =   1.1700V
C_comp   4.2000pF   3.8000pF   7.5000pF
[Temperature Range]   25.0000   0.1050k   -40.0000
[Voltage Range]   1.8000V   1.7100V   1.8900V
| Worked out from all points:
|   GND clamp passes 1 mA (typ) near -0.43 V on its own axis
[GND_clamp]
|Voltage   I(typ)   I(min)   I(max)
-1.8V     -240.3mA   -229.5mA   -254.3mA
-1.2V     -86.28mA   -83.04mA   -95.02mA
-1.17V    -80.56mA   -77.21mA   -89.45mA
-1.14V    -74.99mA   -71.49mA   -84.11mA
-1.11V    -69.57mA   -65.89mA   -79.03mA
-990mV    -50.18mA   -45.05mA   -62.15mA
-900mV    -38.98mA   -31.98mA   -51.41mA
-810mV    -29.42mA   -21.72mA   -39.47mA
-600mV    -9.399mA   -5.375mA   -13.23mA
-450mV    -1.313mA   -673.3uA   -1.788mA
-210mV    -50.64uA   -28.53uA   -89.07uA
3.6V      0A         0A         0A
[POWER_clamp]
|Voltage   I(typ)   I(min)   I(max)
-1.8V     112uA      1.077mA    200uA
-1.74V    106.6uA    490.4uA    199.4uA
-1.68V    104.9uA    210.9uA    198.7uA
-1.62V    104.2uA    103.5uA    198.2uA
-1.56V    103.9uA    67.39uA    197.6uA
-1.44V    103.3uA    51.89uA    196.6uA
900mV     92.45uA    44.87uA    175.3uA
1.14V     86.27uA    43.34uA    155.2uA
1.38V     68.52uA    38.14uA    109.7uA
1.56V     45.38uA    29.35uA    57.03uA
1.8V      -58.42nA   9.773uA    -37.99uA
3.6V      -58.42nA   -772.5nA   -37.99uA
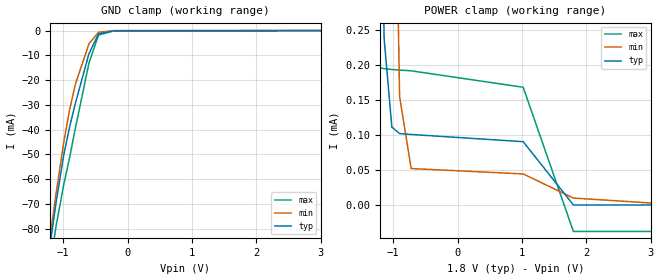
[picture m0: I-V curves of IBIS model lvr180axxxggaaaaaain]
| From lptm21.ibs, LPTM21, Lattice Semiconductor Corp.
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|   Model lvr180axxxggaaaaaain
[Model]   lvr180axxxggaaaaaain
Model_type   Input
Polarity   Non-Inverting
Enable   Active-Low
Vinl =   0.6300V
Vinh =   1.1700V
C_comp   4.2000pF   3.8000pF   7.5000pF
[Temperature Range]   25.0000   0.1050k   -40.0000
[Voltage Range]   1.8000V   1.7100V   1.8900V
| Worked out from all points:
|   GND clamp passes 1 mA (typ) near -0.43 V on its own axis
|   POWER clamp passes 1 mA (typ) near -1.24 V on its own axis
[GND_clamp]
|Voltage   I(typ)   I(min)   I(max)
-1.8V     -240.3mA   -229.5mA   -254.3mA
-1.2V     -86.26mA   -83.03mA   -95mA
-1.17V    -80.55mA   -77.2mA    -89.43mA
-1.14V    -74.97mA   -71.48mA   -84.08mA
-1.11V    -69.56mA   -65.88mA   -79.01mA
-990mV    -50.17mA   -45.04mA   -62.13mA
-900mV    -38.97mA   -31.97mA   -51.39mA
-810mV    -29.41mA   -21.71mA   -39.46mA
-600mV    -9.393mA   -5.37mA    -13.23mA
-450mV    -1.311mA   -672.1uA   -1.786mA
-210mV    -50.63uA   -28.53uA   -89.06uA
3.6V      0A         0A         0A
[POWER_clamp]
|Voltage   I(typ)   I(min)   I(max)
-1.8V     24.36mA    33.14mA    14.08mA
-1.44V    5.661mA    15.81mA    1.032mA
-1.38V    3.886mA    12.93mA    411.3uA
-1.32V    2.397mA    10.11mA    236.1uA
-1.2V     555.5uA    4.982mA    196.2uA
-1.14V    237.5uA    3.006mA    194.7uA
-1.02V    111.2uA    806uA      193.6uA
-900mV    102uA      154.9uA    192.8uA
-720mV    100.7uA    51.98uA    191.7uA
1.02V     90.38uA    44.28uA    168.2uA
1.8V      -43.76nA   9.786uA    -37.97uA
3.6V      -43.76nA   -786.3nA   -37.97uA
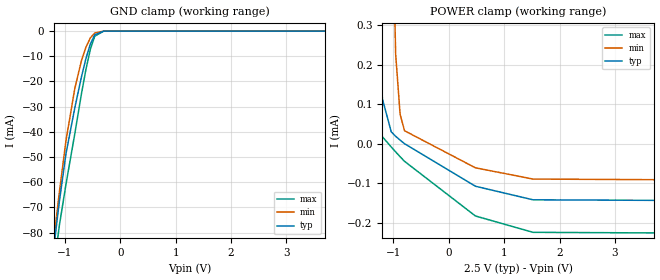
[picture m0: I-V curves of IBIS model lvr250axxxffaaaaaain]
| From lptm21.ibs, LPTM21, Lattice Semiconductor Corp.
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|   Model lvr250axxxffaaaaaain
[Model]   lvr250axxxffaaaaaain
Model_type   Input
Polarity   Non-Inverting
Enable   Active-Low
Vinl =   0.7000V
Vinh =   1.7000V
C_comp   4.2000pF   3.8000pF   7.5000pF
[Temperature Range]   25.0000   0.1050k   -40.0000
[Voltage Range]   2.5000V   2.3800V   2.6300V
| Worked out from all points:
|   GND clamp passes 1 mA (typ) near -0.44 V on its own axis
|   POWER clamp passes 1 mA (typ) near -1.34 V on its own axis
[GND_clamp]
|Voltage   I(typ)   I(min)   I(max)
-2.5V     -564.7mA   -543mA     -585mA
-1.18V    -82.32mA   -79.06mA   -91.07mA
-1.14V    -74.85mA   -71.41mA   -83.89mA
-1.1V     -67.67mA   -63.97mA   -77.19mA
-980mV    -48.65mA   -43.39mA   -60.75mA
-820mV    -30.35mA   -22.68mA   -40.61mA
-700mV    -18.1mA    -11.66mA   -24.76mA
-620mV    -10.89mA   -6.376mA   -15.21mA
-540mV    -5.085mA   -2.692mA   -7.226mA
-460mV    -1.473mA   -741.7uA   -2mA
-300mV    -21.1uA    -17.87uA   -17.4uA
5V        0A         0A         0A
[POWER_clamp]
|Voltage   I(typ)   I(min)   I(max)
-2.48V    65.42mA    74.7mA     52.99mA
-1.6V     7.875mA    26.24mA    683.6uA
-1.44V    2.861mA    16.73mA    72.53uA
-1.28V    383.8uA    7.77mA     31.15uA
-1.2V     113.3uA    4.183mA    17.76uA
-1.04V    30.28uA    714.2uA    -8.079uA
-960mV    18.79uA    225.5uA    -20.54uA
-880mV    9.237uA    74.34uA    -32.64uA
-800mV    192.4nA    32.94uA    -44.38uA
480mV     -107.3uA   -60.72uA   -182.5uA
1.52V     -141.6uA   -89.17uA   -223.8uA
5V        -143.8uA   -91.69uA   -226.2uA
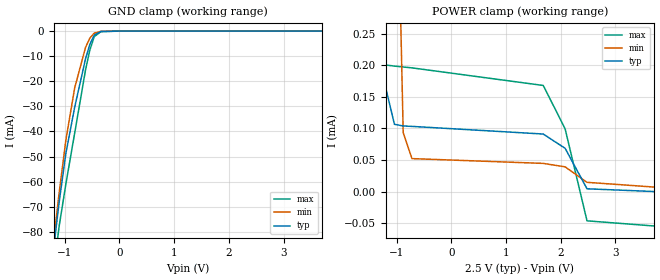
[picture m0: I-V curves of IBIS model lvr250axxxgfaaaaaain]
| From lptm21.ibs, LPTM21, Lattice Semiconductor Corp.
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|   Model lvr250axxxgfaaaaaain
[Model]   lvr250axxxgfaaaaaain
Model_type   Input
Polarity   Non-Inverting
Enable   Active-Low
Vinl =   0.7000V
Vinh =   1.7000V
C_comp   4.2000pF   3.8000pF   7.5000pF
[Temperature Range]   25.0000   0.1050k   -40.0000
[Voltage Range]   2.5000V   2.3800V   2.6300V
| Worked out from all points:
|   GND clamp passes 1 mA (typ) near -0.43 V on its own axis
|   POWER clamp passes 1 mA (typ) near -1.33 V on its own axis
[GND_clamp]
|Voltage   I(typ)   I(min)   I(max)
-2.5V     -564.8mA   -543.1mA   -585.2mA
-1.18V    -82.46mA   -79.15mA   -91.3mA
-1.14V    -74.99mA   -71.5mA    -84.11mA
-1.1V     -67.81mA   -64.05mA   -77.42mA
-980mV    -48.79mA   -43.47mA   -60.98mA
-820mV    -30.48mA   -22.76mA   -40.83mA
-620mV    -11.02mA   -6.453mA   -15.42mA
-540mV    -5.209mA   -2.766mA   -7.431mA
-460mV    -1.588mA   -808.3uA   -2.192mA
-340mV    -160.6uA   -99.03uA   -224.8uA
20mV      0A         0A         0A
5V        0A         0A         0A
[POWER_clamp]
|Voltage   I(typ)   I(min)   I(max)
-2.48V    65.38mA    74.51mA    53.08mA
-1.6V     7.899mA    26.19mA    769.7uA
-1.44V    2.888mA    16.7mA     212.3uA
-1.28V    421.4uA    7.762mA    201.8uA
-1.2V     164.6uA    4.181mA    200.7uA
-1.04V    106.6uA    719.9uA    198.9uA
-880mV    104uA      93.31uA    197.5uA
-720mV    103.3uA    52.24uA    196.1uA
1.68V     91.21uA    44.64uA    168.2uA
2.08V     68.52uA    39.16uA    99.42uA
2.48V     4.395uA    14.63uA    -46.4uA
5V        -4.594uA   -779nA     -63.24uA
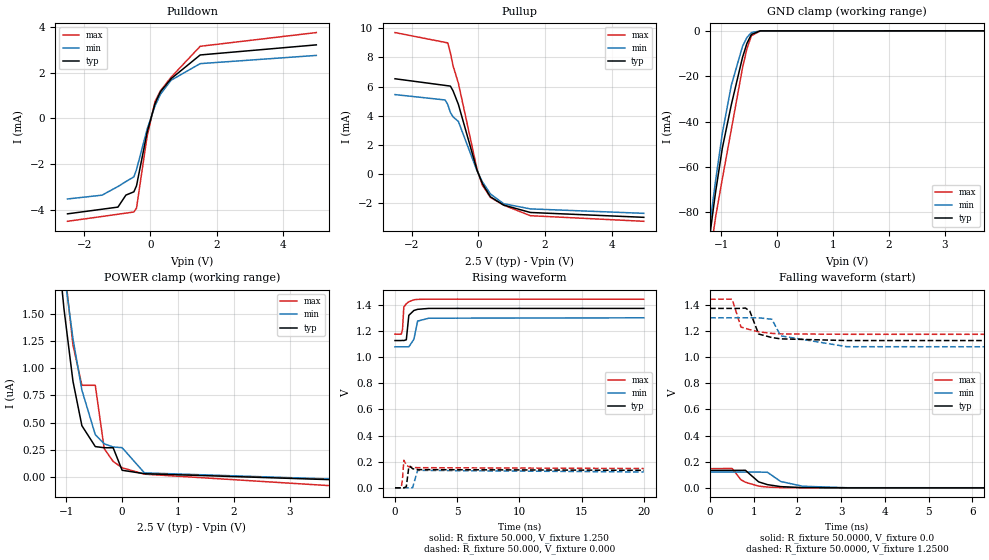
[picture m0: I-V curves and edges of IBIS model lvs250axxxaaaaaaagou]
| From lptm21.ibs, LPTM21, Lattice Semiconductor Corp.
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|   Model lvs250axxxaaaaaaagou
[Model]   lvs250axxxaaaaaaagou
Model_type   Output
Polarity   Non-Inverting
Enable   Active-Low
Vmeas =   1.2500V
Cref =   3.0000pF
Rref =   50.0000
Vref =   1.2500V
C_comp   4.2000pF   3.8000pF   7.5000pF
[Temperature Range]   25.0000   0.1050k   -40.0000
[Voltage Range]   2.5000V   2.3800V   2.6300V
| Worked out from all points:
|   slope of the pulldown table from 0 to 0.375 V, typ, clamps not added: 281 ohm
|   slope of the pullup table from 0 to 0.375 V, typ, clamps not added: 234 ohm
|   GND clamp passes 1 mA (typ) near -0.43 V on its own axis
|   rising waveform, R_fixture 50.000, V_fixture 1.250: 20-80 % time 176ps typ, 247ps min, 127ps max; typ from 1.13 V to 1.37 V
|   rising waveform, R_fixture 50.000, V_fixture 0.000: 20-80 % time 82.1ps typ, 156ps min, 92.7ps max; typ from 0 V to 0.134 V
|   falling waveform, R_fixture 50.0000, V_fixture 0.0: 20-80 % time 371ps typ, 430ps min, 330ps max; typ from 0.134 V to 0 V
|   falling waveform, R_fixture 50.0000, V_fixture 1.2500: 20-80 % time 184ps typ, 262ps min, 140ps max; typ from 1.37 V to 1.13 V
[Pulldown]
|Voltage   I(typ)   I(min)   I(max)
-2.5V     -4.178mA   -3.527mA   -4.505mA
-1.46V    -3.976mA   -3.36mA    -4.294mA
-980mV    -3.883mA   -2.982mA   -4.196mA
-740mV    -3.357mA   -2.765mA   -4.147mA
-500mV    -3.214mA   -2.559mA   -4.099mA
-420mV    -2.95mA    -2.239mA   -3.926mA
-100mV    -603.1uA   -467.1uA   -779.2uA
140mV     661uA      555.4uA    753.5uA
300mV     1.167mA    1.054mA    1.205mA
620mV     1.74mA     1.673mA    1.803mA
1.5V      2.782mA    2.402mA    3.162mA
5V        3.224mA    2.762mA    3.763mA
[Pullup]
|Voltage   I(typ)   I(min)   I(max)
-2.5V     6.532mA    5.445mA    9.704mA
-1V       6.077mA    5.077mA    9.032mA
-920mV    6.053mA    4.772mA    8.996mA
-840mV    6.029mA    4.225mA    8.323mA
-760mV    5.707mA    3.916mA    7.426mA
-600mV    4.772mA    3.604mA    6.228mA
-40mV     253uA      200.2uA    312.8uA
120mV     -665.4uA   -542.7uA   -777uA
360mV     -1.572mA   -1.373mA   -1.615mA
760mV     -2.143mA   -2.049mA   -2.148mA
1.56V     -2.649mA   -2.403mA   -2.87mA
4.96V     -2.981mA   -2.707mA   -3.254mA
[GND_clamp]
|Voltage   I(typ)   I(min)   I(max)
-2.5V     -566.3mA   -544.9mA   -586.5mA
-1.22V    -93.5mA    -88.96mA   -103.6mA
-1.18V    -85.7mA    -81.06mA   -95.97mA
-1.14V    -78.15mA   -73.33mA   -88.73mA
-1.1V     -70.88mA   -65.82mA   -81.98mA
-980mV    -51.66mA   -45.05mA   -65.2mA
-820mV    -32.63mA   -24.07mA   -43.52mA
-620mV    -11.79mA   -6.899mA   -16.43mA
-540mV    -5.523mA   -2.909mA   -7.852mA
-460mV    -1.591mA   -787.7uA   -2.174mA
-300mV    -20.61uA   -17.6uA    -17.71uA
5V        0A         0A         0A
[POWER_clamp]
|Voltage   I(typ)   I(min)   I(max)
-2.48V    16.67uA    13.46uA    27.27uA
-1.2V     2.435uA    2.651uA    3.191uA
-1.12V    1.959uA    2.254uA    2.522uA
-1.04V    1.541uA    1.891uA    1.967uA
-880mV    880.7nA    1.272uA    1.212uA
-720mV    472.2nA    798.5nA    842.6nA
-480mV    280.5nA    389.6nA    842.6nA
-320mV    269.7nA    306.1nA    260.6nA
-160mV    269.7nA    276.4nA    144nA
0V        63.22nA    270.6nA    86.34nA
400mV     31.61nA    39.07nA    27.38nA
5V        -44.09nA   -38.33nA   -118.7nA
[Ramp]
| variable   typ   min   max
dV/dt_r  85.6247m/92.0154p   76.8346m/0.1678n   94.4387m/94.1463p
dV/dt_f  88.6200m/0.1344n   75.1200m/0.1847n   0.1044/0.1103n
R_load = 50.0000
[Rising Waveform]
R_fixture = 50.000
V_fixture = 1.250
V_fixture_min = 1.188
V_fixture_max = 1.313
|  time   V(typ)   V(min)   V(max)
0s        1.127V     1.079V     1.176V
505.1ps   1.127V     1.079V     1.176V
606.1ps   1.128V     1.079V     1.215V
707.1ps   1.127V     1.079V     1.383V
909.1ps   1.133V     1.079V     1.409V
1.111ns   1.32V      1.079V     1.424V
1.515ns   1.357V     1.136V     1.439V
1.818ns   1.366V     1.276V     1.442V
2.727ns   1.373V     1.298V     1.444V
20ns      1.373V     1.301V     1.443V
[Rising Waveform]
R_fixture = 50.000
V_fixture = 0.000
V_fixture_min = 0.000
V_fixture_max = 0.000
|  time   V(typ)   V(min)   V(max)
0s        2.201uV    2.355uV    2.228uV
505.1ps   14.28uV    4.746uV    -472.4uV
606.1ps   143.4uV    697.9nV    72.53mV
707.1ps   -42.39uV   -4.439uV   210.9mV
909.1ps   8.457mV    166.7uV    174.2mV
1.111ns   160.6mV    64.09uV    161mV
1.212ns   164.2mV    -113.4uV   158.5mV
1.414ns   145.9mV    1.514mV    155.9mV
1.818ns   139.3mV    133.4mV    154.1mV
20ns      133.7mV    120.8mV    147.4mV
[Falling Waveform]
R_fixture=   50.0000
V_fixture=   0.0
V_fixture_min=   0.0
V_fixture_max=   0.0
|time   V(typ)   V(min)   V(max)
0s        133.7mV    120.8mV    147mV
505.1ps   133.7mV    120.8mV    148.1mV
707.1ps   133.8mV    120.8mV    61.73mV
808.1ps   134.5mV    120.8mV    42.87mV
1.111ns   45.88mV    120.7mV    13.19mV
1.313ns   24.6mV     119.1mV    6.024mV
1.616ns   9.347mV    48.65mV    1.933mV
2.121ns   2.011mV    12.31mV    331.6uV
3.131ns   128.1uV    1.135mV    54.34uV
20ns      -26.28uV   -8.068uV   14.11uV
[Falling Waveform]
R_fixture=   50.0000
V_fixture=   1.2500
V_fixture_min=   1.1880
V_fixture_max=   1.3130
|time   V(typ)   V(min)   V(max)
0s        1.373V     1.301V     1.443V
505.1ps   1.373V     1.301V     1.444V
707.1ps   1.373V     1.301V     1.23V
808.1ps   1.376V     1.301V     1.221V
909.1ps   1.352V     1.301V     1.21V
1.111ns   1.177V     1.301V     1.194V
1.414ns   1.15V      1.29V      1.182V
1.616ns   1.14V      1.163V     1.178V
3.131ns   1.127V     1.08V      1.175V
20ns      1.127V     1.078V     1.175V
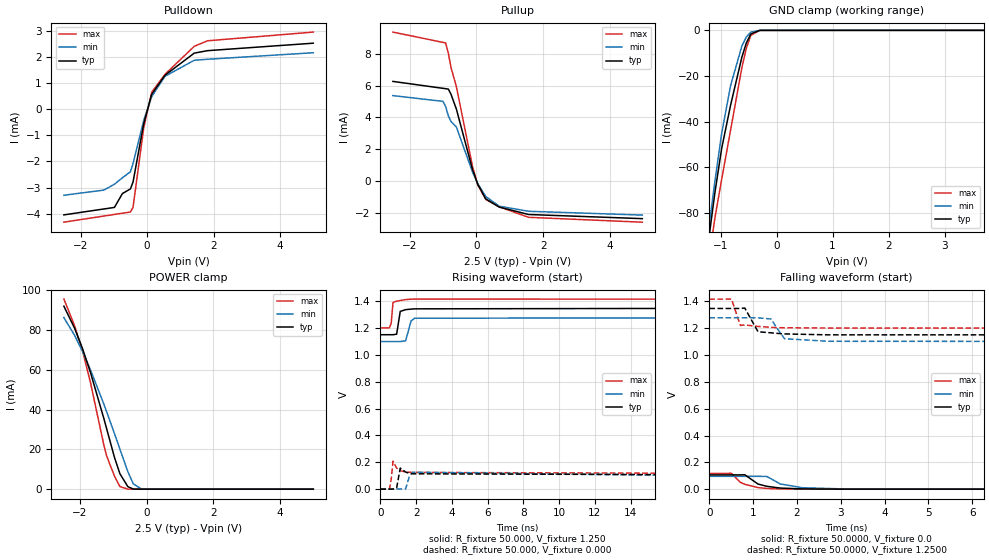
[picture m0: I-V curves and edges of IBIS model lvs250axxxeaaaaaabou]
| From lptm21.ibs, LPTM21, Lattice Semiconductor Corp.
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|   Model lvs250axxxeaaaaaabou
[Model]   lvs250axxxeaaaaaabou
Model_type   Output
Polarity   Non-Inverting
Enable   Active-Low
Vmeas =   1.2500V
Cref =   3.0000pF
Rref =   50.0000
Vref =   1.2500V
C_comp   4.2000pF   3.8000pF   7.5000pF
[Temperature Range]   25.0000   0.1050k   -40.0000
[Voltage Range]   2.5000V   2.3800V   2.6300V
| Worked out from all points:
|   slope of the pulldown table from 0 to 0.375 V, typ, clamps not added: 339 ohm
|   slope of the pullup table from 0 to 0.375 V, typ, clamps not added: 283 ohm
|   GND clamp passes 1 mA (typ) near -0.43 V on its own axis
|   POWER clamp passes 1 mA (typ) near -0.54 V on its own axis
|   rising waveform, R_fixture 50.000, V_fixture 1.250: 20-80 % time 142ps typ, 209ps min, 84.2ps max; typ from 1.15 V to 1.35 V
|   rising waveform, R_fixture 50.000, V_fixture 0.000: 20-80 % time 65.5ps typ, 127ps min, 83.6ps max; typ from 0 V to 0.106 V
|   falling waveform, R_fixture 50.0000, V_fixture 0.0: 20-80 % time 392ps typ, 455ps min, 348ps max; typ from 0.106 V to 0 V
|   falling waveform, R_fixture 50.0000, V_fixture 1.2500: 20-80 % time 146ps typ, 213ps min, 121ps max; typ from 1.35 V to 1.15 V
[Pulldown]
|Voltage   I(typ)   I(min)   I(max)
-2.5V     -4.05mA    -3.296mA   -4.331mA
-1.3V     -3.824mA   -3.1mA     -4.096mA
-980mV    -3.764mA   -2.875mA   -4.033mA
-740mV    -3.232mA   -2.626mA   -3.986mA
-500mV    -3.054mA   -2.396mA   -3.94mA
-420mV    -2.788mA   -2.084mA   -3.757mA
-100mV    -551.4uA   -421.9uA   -720.2uA
140mV     577.8uA    485.7uA    654.8uA
540mV     1.311mA    1.271mA    1.346mA
1.42V     2.16mA     1.886mA    2.422mA
1.82V     2.255mA    1.925mA    2.634mA
5V        2.542mA    2.175mA    2.968mA
[Pullup]
|Voltage   I(typ)   I(min)   I(max)
-2.5V     6.264mA    5.371mA    9.366mA
-1V       5.827mA    5.007mA    8.717mA
-920mV    5.804mA    4.671mA    8.683mA
-840mV    5.781mA    4.087mA    8.021mA
-760mV    5.449mA    3.738mA    7.133mA
-600mV    4.522mA    3.395mA    5.935mA
-120mV    734.5uA    573.7uA    926.7uA
40mV      -210.5uA   -170uA     -250.1uA
280mV     -1.129mA   -982.7uA   -1.165mA
680mV     -1.641mA   -1.585mA   -1.623mA
1.56V     -2.109mA   -1.907mA   -2.287mA
4.96V     -2.37mA    -2.146mA   -2.593mA
[GND_clamp]
|Voltage   I(typ)   I(min)   I(max)
-2.5V     -566.3mA   -544.9mA   -586.5mA
-1.22V    -93.48mA   -88.94mA   -103.6mA
-1.18V    -85.68mA   -81.04mA   -95.95mA
-1.14V    -78.13mA   -73.32mA   -88.71mA
-1.1V     -70.86mA   -65.81mA   -81.96mA
-980mV    -51.63mA   -45.04mA   -65.17mA
-820mV    -32.62mA   -24.06mA   -43.5mA
-620mV    -11.79mA   -6.897mA   -16.42mA
-540mV    -5.522mA   -2.909mA   -7.851mA
-460mV    -1.591mA   -787.7uA   -2.174mA
-300mV    -20.61uA   -17.6uA    -17.71uA
5V        0A         0A         0A
[POWER_clamp]
|Voltage   I(typ)   I(min)   I(max)
-2.48V    91.96mA    86.23mA    95.54mA
-2.16V    80.94mA    77.35mA    82.15mA
-1.92V    70.61mA    69.17mA    69.43mA
-1.68V    58.52mA    59.9mA     53.37mA
-1.28V    35.44mA    42.67mA    22.07mA
-1.2V     30.53mA    39.03mA    16.84mA
-960mV    15.8mA     27.82mA    6.447mA
-800mV    7.76mA     20.14mA    1.303mA
-560mV    1.23mA     8.728mA    11.53uA
-400mV    83.98uA    2.726mA    532.6nA
-160mV    776.1nA    102uA      144nA
5V        -44.09nA   -38.33nA   -118.7nA
[Ramp]
| variable   typ   min   max
dV/dt_r  69.1786m/70.1568p   61.7926m/0.1317n   76.5046m/85.8090p
dV/dt_f  70.2600m/83.1741p   59.5200m/0.1225n   82.9200m/0.1012n
R_load = 50.0000
[Rising Waveform]
R_fixture = 50.000
V_fixture = 1.250
V_fixture_min = 1.188
V_fixture_max = 1.313
|  time   V(typ)   V(min)   V(max)
0s        1.152V     1.101V     1.203V
505.1ps   1.152V     1.101V     1.203V
606.1ps   1.152V     1.101V     1.239V
707.1ps   1.152V     1.101V     1.393V
909.1ps   1.156V     1.101V     1.402V
1.111ns   1.326V     1.101V     1.407V
1.414ns   1.339V     1.107V     1.414V
1.717ns   1.343V     1.255V     1.417V
1.919ns   1.345V     1.275V     1.418V
20ns      1.349V     1.278V     1.417V
[Rising Waveform]
R_fixture = 50.000
V_fixture = 0.000
V_fixture_min = 0.000
V_fixture_max = 0.000
|  time   V(typ)   V(min)   V(max)
0s        2.255uV    2.407uV    2.29uV
505.1ps   14.26uV    4.804uV    -469.6uV
606.1ps   144.1uV    810.4nV    72.97mV
707.1ps   -41.26uV   -4.5uV     207.9mV
909.1ps   8.629mV    167.2uV    157.4mV
1.111ns   156.8mV    66.1uV     137.3mV
1.414ns   127.2mV    1.635mV    128.1mV
1.616ns   117.5mV    92.73mV    125.8mV
1.818ns   114.2mV    126.3mV    124.5mV
20ns      106.4mV    96.56mV    117mV
[Falling Waveform]
R_fixture=   50.0000
V_fixture=   0.0
V_fixture_min=   0.0
V_fixture_max=   0.0
|time   V(typ)   V(min)   V(max)
0s        106.4mV    95.87mV    117.2mV
505.1ps   106.4mV    95.88mV    118.2mV
707.1ps   106.4mV    95.87mV    50.95mV
808.1ps   107.3mV    95.88mV    36.34mV
1.111ns   37.97mV    95.75mV    11.6mV
1.313ns   21.27mV    94.79mV    5.378mV
1.616ns   8.273mV    39.02mV    1.736mV
2.121ns   1.802mV    10.79mV    310.7uV
3.131ns   111.1uV    1.004mV    61.32uV
20ns      -6.885uV   4.112uV    -14.28uV
[Falling Waveform]
R_fixture=   50.0000
V_fixture=   1.2500
V_fixture_min=   1.1880
V_fixture_max=   1.3130
|time   V(typ)   V(min)   V(max)
0s        1.348V     1.278V     1.417V
505.1ps   1.348V     1.278V     1.418V
707.1ps   1.348V     1.278V     1.221V
808.1ps   1.351V     1.278V     1.225V
1.111ns   1.174V     1.278V     1.214V
1.414ns   1.166V     1.269V     1.207V
1.515ns   1.163V     1.213V     1.205V
1.717ns   1.158V     1.122V     1.204V
2.727ns   1.151V     1.103V     1.202V
20ns      1.151V     1.1V       1.202V
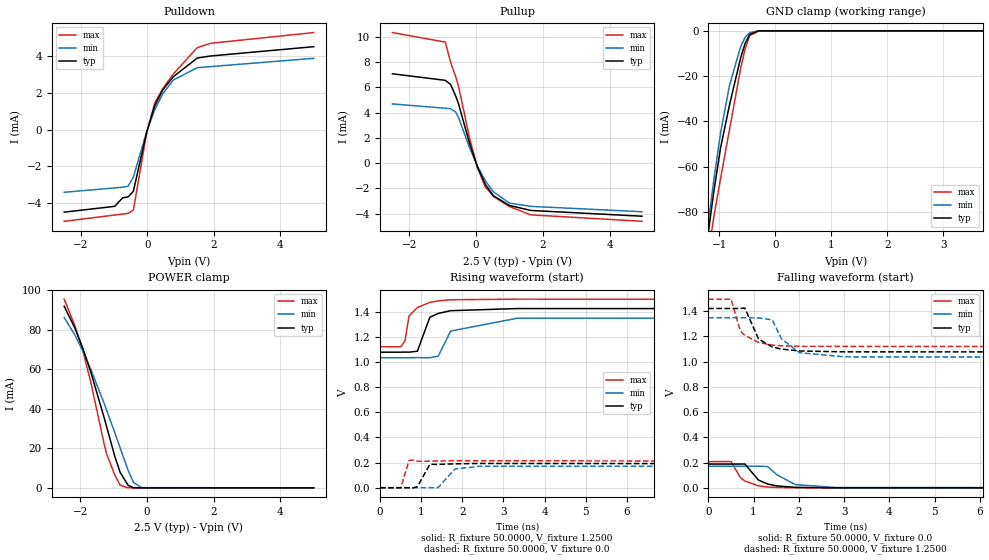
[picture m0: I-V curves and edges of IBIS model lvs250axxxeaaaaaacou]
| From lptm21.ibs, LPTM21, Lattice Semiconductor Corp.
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|   Model lvs250axxxeaaaaaacou
[Model]   lvs250axxxeaaaaaacou
Model_type   Output
Polarity   Non-Inverting
Enable   Active-Low
Vmeas =   1.2500V
Cref =   3.0000pF
Rref =   50.0000
Vref =   1.2500V
C_comp   4.2000pF   3.8000pF   7.5000pF
[Temperature Range]   25.0000   0.1050k   -40.0000
[Voltage Range]   2.5000V   2.3800V   2.6300V
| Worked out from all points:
|   slope of the pulldown table from 0 to 0.375 V, typ, clamps not added: 196 ohm
|   slope of the pullup table from 0 to 0.375 V, typ, clamps not added: 178 ohm
|   GND clamp passes 1 mA (typ) near -0.43 V on its own axis
|   POWER clamp passes 1 mA (typ) near -0.54 V on its own axis
|   rising waveform, R_fixture 50.0000, V_fixture 1.2500: 20-80 % time 250ps typ, 331ps min, 240ps max; typ from 1.08 V to 1.42 V
|   rising waveform, R_fixture 50.0000, V_fixture 0.0: 20-80 % time 142ps typ, 257ps min, 107ps max; typ from 0 V to 0.189 V
|   falling waveform, R_fixture 50.0000, V_fixture 0.0: 20-80 % time 337ps typ, 394ps min, 304ps max; typ from 0.189 V to 0 V
|   falling waveform, R_fixture 50.0000, V_fixture 1.2500: 20-80 % time 293ps typ, 357ps min, 263ps max; typ from 1.42 V to 1.08 V
[Pulldown]
|Voltage   I(typ)   I(min)   I(max)
-2.5V     -4.512mA   -3.425mA   -5.012mA
-980mV    -4.194mA   -3.187mA   -4.669mA
-740mV    -3.725mA   -3.149mA   -4.615mA
-580mV    -3.684mA   -3.097mA   -4.579mA
-420mV    -3.371mA   -2.597mA   -4.4mA
-20mV     -141.1uA   -110.8uA   -176.9uA
220mV     1.286mA    1.074mA    1.445mA
460mV     2.167mA    1.953mA    2.23mA
780mV     2.888mA    2.708mA    3.037mA
1.5V      3.914mA    3.386mA    4.482mA
1.9V      4.025mA    3.445mA    4.718mA
5V        4.534mA    3.898mA    5.306mA
[Pullup]
|Voltage   I(typ)   I(min)   I(max)
-2.5V     7.076mA    4.69mA     10.34mA
-920mV    6.558mA    4.346mA    9.584mA
-760mV    6.227mA    4.311mA    7.991mA
-600mV    5.26mA     4.027mA    6.776mA
-520mV    4.668mA    3.581mA    6.055mA
-200mV    1.619mA    1.266mA    2.057mA
40mV      -284.3uA   -227.6uA   -345.1uA
280mV     -1.693mA   -1.407mA   -1.9mA
520mV     -2.586mA   -2.273mA   -2.629mA
1V        -3.353mA   -3.163mA   -3.442mA
1.64V     -3.746mA   -3.422mA   -4.094mA
4.96V     -4.201mA   -3.848mA   -4.604mA
[GND_clamp]
|Voltage   I(typ)   I(min)   I(max)
-2.5V     -566.3mA   -544.9mA   -586.5mA
-1.22V    -93.54mA   -88.99mA   -103.7mA
-1.18V    -85.75mA   -81.09mA   -96.02mA
-1.14V    -78.19mA   -73.36mA   -88.78mA
-1.1V     -70.93mA   -65.85mA   -82.04mA
-980mV    -51.7mA    -45.08mA   -65.26mA
-820mV    -32.67mA   -24.09mA   -43.56mA
-620mV    -11.8mA    -6.902mA   -16.44mA
-540mV    -5.525mA   -2.91mA    -7.855mA
-460mV    -1.591mA   -787.8uA   -2.175mA
-300mV    -20.61uA   -17.6uA    -17.71uA
5V        0A         0A         0A
[POWER_clamp]
|Voltage   I(typ)   I(min)   I(max)
-2.48V    91.96mA    86.23mA    95.54mA
-2.16V    80.94mA    77.35mA    82.15mA
-1.92V    70.61mA    69.17mA    69.43mA
-1.68V    58.52mA    59.9mA     53.37mA
-1.28V    35.44mA    42.67mA    22.07mA
-1.2V     30.53mA    39.03mA    16.84mA
-960mV    15.8mA     27.82mA    6.447mA
-800mV    7.76mA     20.14mA    1.303mA
-560mV    1.23mA     8.728mA    11.53uA
-400mV    83.98uA    2.726mA    532.6nA
-160mV    776.1nA    102uA      144nA
5V        -44.09nA   -38.33nA   -118.7nA
[Ramp]
| variable   typ   min   max
dV/dt_r  0.1193/0.1485n   0.1077/0.2718n   0.1318/0.1078n
dV/dt_f  0.1239/0.3118n   0.1055/0.3867n   0.1459/0.2628n
R_load = 50.0000
[Rising Waveform]
R_fixture=   50.0000
V_fixture=   1.2500
V_fixture_min=   1.1880
V_fixture_max=   1.3130
|time   V(typ)   V(min)   V(max)
0s        1.078V     1.034V     1.122V
505.1ps   1.078V     1.034V     1.121V
606.1ps   1.079V     1.034V     1.167V
707.1ps   1.078V     1.034V     1.367V
909.1ps   1.086V     1.035V     1.433V
1.212ns   1.356V     1.034V     1.474V
1.414ns   1.386V     1.046V     1.486V
1.717ns   1.408V     1.246V     1.495V
3.333ns   1.425V     1.348V     1.5V
20ns      1.424V     1.35V      1.498V
[Rising Waveform]
R_fixture=   50.0000
V_fixture=   0.0
V_fixture_min=   0.0
V_fixture_max=   0.0
|time   V(typ)   V(min)   V(max)
0s        2.071uV    2.243uV    2.073uV
505.1ps   14.44uV    4.611uV    -481.2uV
707.1ps   -45.33uV   -4.092uV   217.3mV
808.1ps   -1.147mV   51.65uV    219.4mV
909.1ps   7.837mV    164.8uV    210.9mV
1.212ns   186.1mV    -124.4uV   211.2mV
1.414ns   185.6mV    1.15mV     212.8mV
1.818ns   190mV      148.7mV    214.2mV
2.424ns   193.1mV    170.2mV    214.5mV
20ns      188.9mV    172.1mV    208mV
[Falling Waveform]
R_fixture=   50.0000
V_fixture=   0.0
V_fixture_min=   0.0
V_fixture_max=   0.0
|time   V(typ)   V(min)   V(max)
0s        188.7mV    172mV      207.8mV
505.1ps   188.7mV    172mV      208.8mV
707.1ps   188.7mV    172mV      82.94mV
808.1ps   189.2mV    172mV      54.65mV
1.111ns   61.05mV    171.9mV    15.45mV
1.313ns   30.34mV    169mV      6.782mV
1.515ns   15.33mV    104.1mV    3.045mV
1.919ns   4.207mV    26.15mV    651.3uV
2.828ns   309.8uV    2.656mV    76.73uV
20ns      3.092uV    3.435uV    -1.99uV
[Falling Waveform]
R_fixture=   50.0000
V_fixture=   1.2500
V_fixture_min=   1.1880
V_fixture_max=   1.3130
|time   V(typ)   V(min)   V(max)
0s        1.422V     1.348V     1.495V
505.1ps   1.422V     1.348V     1.496V
707.1ps   1.422V     1.348V     1.244V
808.1ps   1.425V     1.348V     1.208V
1.111ns   1.18V      1.347V     1.153V
1.414ns   1.117V     1.332V     1.132V
1.616ns   1.1V       1.182V     1.126V
2.02ns    1.085V     1.071V     1.122V
3.03ns    1.078V     1.038V     1.121V
20ns      1.077V     1.034V     1.121V
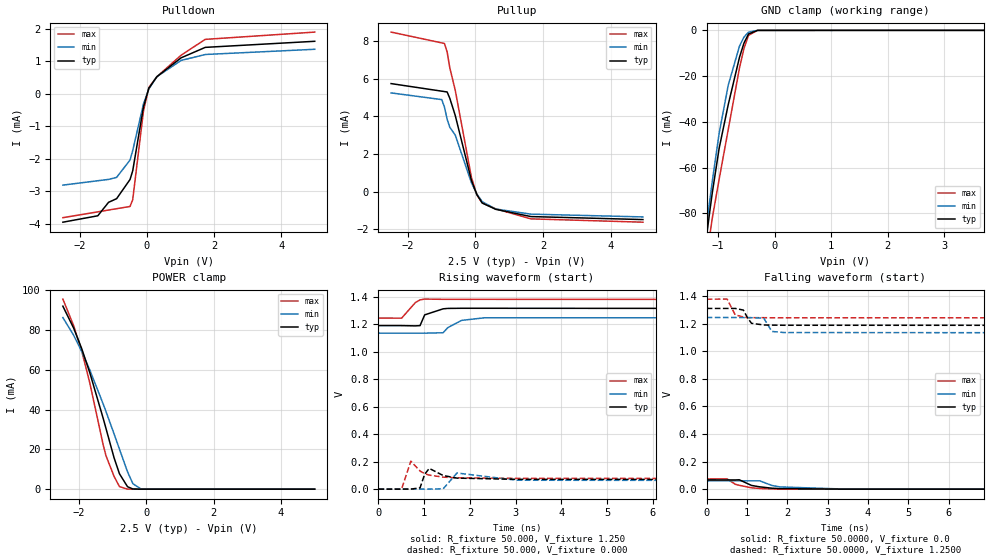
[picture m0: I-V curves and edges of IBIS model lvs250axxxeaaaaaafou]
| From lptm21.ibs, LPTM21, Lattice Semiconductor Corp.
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|   Model lvs250axxxeaaaaaafou
[Model]   lvs250axxxeaaaaaafou
Model_type   Output
Polarity   Non-Inverting
Enable   Active-Low
Vmeas =   1.2500V
Cref =   3.0000pF
Rref =   50.0000
Vref =   1.2500V
C_comp   4.2000pF   3.8000pF   7.5000pF
[Temperature Range]   25.0000   0.1050k   -40.0000
[Voltage Range]   2.5000V   2.3800V   2.6300V
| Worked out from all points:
|   slope of the pulldown table from 0 to 0.375 V, typ, clamps not added: 625 ohm
|   slope of the pullup table from 0 to 0.375 V, typ, clamps not added: 462 ohm
|   GND clamp passes 1 mA (typ) near -0.43 V on its own axis
|   POWER clamp passes 1 mA (typ) near -0.54 V on its own axis
|   rising waveform, R_fixture 50.000, V_fixture 1.250: 20-80 % time 167ps typ, 327ps min, 197ps max; typ from 1.19 V to 1.31 V
|   rising waveform, R_fixture 50.000, V_fixture 0.000: 20-80 % time 41.1ps typ, 87.4ps min, 59.3ps max; typ from 0 V to 0.067 V
|   falling waveform, R_fixture 50.0000, V_fixture 0.0: 20-80 % time 461ps typ, 536ps min, 392ps max; typ from 0.067 V to 0 V
|   falling waveform, R_fixture 50.0000, V_fixture 1.2500: 20-80 % time 156ps typ, 141ps min, 144ps max; typ from 1.31 V to 1.19 V
[Pulldown]
|Voltage   I(typ)   I(min)   I(max)
-2.5V     -3.947mA   -2.807mA   -3.808mA
-1.46V    -3.75mA    -2.672mA   -3.629mA
-1.14V    -3.336mA   -2.631mA   -3.573mA
-900mV    -3.224mA   -2.569mA   -3.532mA
-500mV    -2.634mA   -2.036mA   -3.463mA
-420mV    -2.366mA   -1.742mA   -3.256mA
-100mV    -403.9uA   -312.3uA   -529.5uA
60mV      172.5uA    148.5uA    195.9uA
300mV     526.7uA    529.2uA    527uA
1.02V     1.107mA    1.027mA    1.188mA
1.74V     1.429mA    1.21mA     1.675mA
5V        1.616mA    1.37mA     1.899mA
[Pullup]
|Voltage   I(typ)   I(min)   I(max)
-2.5V     5.736mA    5.242mA    8.473mA
-1V       5.334mA    4.886mA    7.899mA
-920mV    5.313mA    4.496mA    7.869mA
-840mV    5.291mA    3.843mA    7.421mA
-760mV    4.952mA    3.413mA    6.567mA
-600mV    4.048mA    3.004mA    5.388mA
-120mV    595.2uA    464.6uA    752.4uA
40mV      -157.3uA   -129.7uA   -181.1uA
200mV     -607.8uA   -541.1uA   -612.9uA
600mV     -944.6uA   -927.5uA   -919.4uA
1.64V     -1.329mA   -1.2mA     -1.451mA
4.96V     -1.489mA   -1.348mA   -1.628mA
[GND_clamp]
|Voltage   I(typ)   I(min)   I(max)
-2.5V     -566.3mA   -544.9mA   -586.5mA
-1.22V    -93.43mA   -88.91mA   -103.5mA
-1.18V    -85.63mA   -81.01mA   -95.89mA
-1.14V    -78.07mA   -73.29mA   -88.64mA
-1.1V     -70.81mA   -65.78mA   -81.89mA
-980mV    -51.57mA   -45.01mA   -65.09mA
-820mV    -32.56mA   -24.03mA   -43.45mA
-620mV    -11.77mA   -6.892mA   -16.41mA
-540mV    -5.518mA   -2.907mA   -7.846mA
-460mV    -1.59mA    -787.5uA   -2.173mA
-300mV    -20.61uA   -17.6uA    -17.71uA
5V        0A         0A         0A
[POWER_clamp]
|Voltage   I(typ)   I(min)   I(max)
-2.48V    91.96mA    86.23mA    95.54mA
-2.16V    80.94mA    77.35mA    82.15mA
-1.92V    70.61mA    69.17mA    69.43mA
-1.68V    58.52mA    59.9mA     53.37mA
-1.28V    35.44mA    42.67mA    22.07mA
-1.2V     30.53mA    39.03mA    16.84mA
-960mV    15.8mA     27.82mA    6.447mA
-800mV    7.76mA     20.14mA    1.303mA
-560mV    1.23mA     8.728mA    11.53uA
-400mV    83.98uA    2.726mA    532.6nA
-160mV    776.1nA    102uA      144nA
5V        -44.09nA   -38.33nA   -118.7nA
[Ramp]
| variable   typ   min   max
dV/dt_r  44.7261m/45.2342p   39.7851m/93.0361p   49.0611m/65.2350p
dV/dt_f  44.9400m/50.3247p   37.6800m/86.9113p   53.6400m/85.5151p
R_load = 50.0000
[Rising Waveform]
R_fixture = 50.000
V_fixture = 1.250
V_fixture_min = 1.188
V_fixture_max = 1.313
|  time   V(typ)   V(min)   V(max)
0s        1.189V     1.134V     1.244V
505.1ps   1.189V     1.134V     1.243V
808.1ps   1.187V     1.134V     1.357V
909.1ps   1.189V     1.134V     1.376V
1.01ns    1.267V     1.134V     1.382V
1.414ns   1.311V     1.137V     1.38V
1.515ns   1.314V     1.174V     1.38V
1.818ns   1.315V     1.227V     1.38V
2.323ns   1.315V     1.246V     1.38V
20ns      1.312V     1.245V     1.378V
[Rising Waveform]
R_fixture = 50.000
V_fixture = 0.000
V_fixture_min = 0.000
V_fixture_max = 0.000
|  time   V(typ)   V(min)   V(max)
0s        2.432uV    2.549uV    2.523uV
505.1ps   14.12uV    4.97uV     -458.8uV
707.1ps   -37.59uV   -4.86uV    203.2mV
909.1ps   9.335mV    169.2uV    131.5mV
1.01ns    108mV      23.38uV    112.3mV
1.111ns   150.6mV    71.94uV    101.8mV
1.414ns   98.89mV    2mV        87.05mV
1.717ns   79.88mV    116.9mV    81.82mV
3.03ns    70.96mV    64.46mV    78.3mV
20ns      67.06mV    60.29mV    73.63mV
[Falling Waveform]
R_fixture=   50.0000
V_fixture=   0.0
V_fixture_min=   0.0
V_fixture_max=   0.0
|time   V(typ)   V(min)   V(max)
0s        66.86mV    60.29mV    73.62mV
505.1ps   66.86mV    60.29mV    74.59mV
707.1ps   66.86mV    60.29mV    35.72mV
808.1ps   68.08mV    60.29mV    27.67mV
1.111ns   27.05mV    60.15mV    9.951mV
1.313ns   16.81mV    60.53mV    4.84mV
1.616ns   7mV        26.78mV    1.667mV
1.818ns   3.828mV    16.3mV     835.2uV
3.434ns   40.28uV    424.6uV    10.35uV
20ns      -4.642uV   -23.54uV   29.9uV
[Falling Waveform]
R_fixture=   50.0000
V_fixture=   1.2500
V_fixture_min=   1.1880
V_fixture_max=   1.3130
|time   V(typ)   V(min)   V(max)
0s        1.311V     1.245V     1.378V
505.1ps   1.311V     1.245V     1.379V
707.1ps   1.311V     1.245V     1.264V
909.1ps   1.299V     1.245V     1.249V
1.01ns    1.244V     1.244V     1.244V
1.111ns   1.203V     1.244V     1.244V
1.414ns   1.191V     1.24V      1.244V
1.616ns   1.19V      1.144V     1.243V
1.919ns   1.189V     1.136V     1.243V
20ns      1.188V     1.133V     1.243V
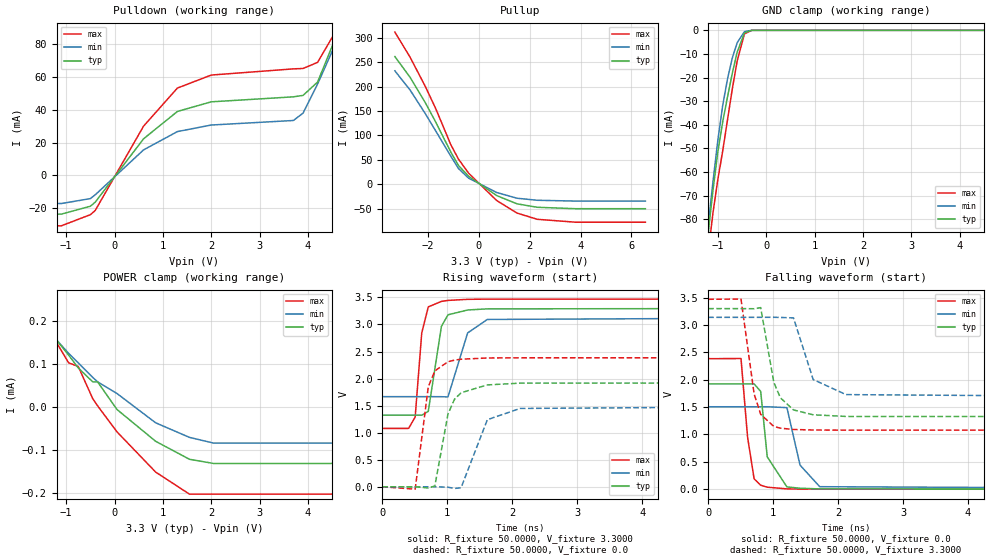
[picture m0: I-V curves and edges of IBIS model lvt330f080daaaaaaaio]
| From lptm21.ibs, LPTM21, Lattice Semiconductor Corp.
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|   Model lvt330f080daaaaaaaio
[Model]   lvt330f080daaaaaaaio
Model_type   I/O
Polarity   Non-Inverting
Enable   Active-Low
Vinl =   0.8000V
Vinh =   2.0000V
Vmeas =   1.500000V
Cref =   0.0F
Rref =   1.0000M
Vref =   0.0V
C_comp   4.2000pF   3.8000pF   7.5000pF
[Temperature Range]   25.0000   0.1050k   -40.0000
[Voltage Range]   3.3000V   3.1400V   3.4700V
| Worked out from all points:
|   slope of the pulldown table from 0 to 0.495 V, typ, clamps not added: 26.1 ohm
|   slope of the pullup table from 0 to 0.495 V, typ, clamps not added: 28.6 ohm
|   GND clamp passes 1 mA (typ) near -0.44 V on its own axis
|   rising waveform, R_fixture 50.0000, V_fixture 3.3000: 20-80 % time 154ps typ, 209ps min, 115ps max; typ from 1.32 V to 3.3 V
|   rising waveform, R_fixture 50.0000, V_fixture 0.0: 20-80 % time 223ps typ, 283ps min, 159ps max; typ from 0 V to 1.92 V
|   falling waveform, R_fixture 50.0000, V_fixture 0.0: 20-80 % time 129ps typ, 176ps min, 130ps max; typ from 1.92 V to 0 V
|   falling waveform, R_fixture 50.0000, V_fixture 3.3000: 20-80 % time 228ps typ, 280ps min, 188ps max; typ from 3.3 V to 1.32 V
[Pulldown]
|Voltage   I(typ)   I(min)   I(max)
-3.3V     -23.65mA   -17.18mA   -30.79mA
-1.1V     -23.65mA   -17.18mA   -30.79mA
-500mV    -18.83mA   -14.17mA   -23.98mA
-400mV    -16.36mA   -11.87mA   -21.45mA
600mV     22.34mA    15.58mA    30.06mA
1.3V      39.05mA    26.76mA    53.33mA
2V        44.93mA    30.76mA    61.28mA
3.7V      47.98mA    33.54mA    65.06mA
3.9V      48.87mA    38.07mA    65.3mA
4.2V      57mA       55.79mA    69.03mA
4.6V      86.02mA    82.33mA    89.26mA
6.6V      242.8mA    214.3mA    281.5mA
[Pullup]
|Voltage   I(typ)   I(min)   I(max)
-3.3V     261.4mA    232.2mA    311.6mA
-2.7V     218.8mA    192.7mA    259.9mA
-2.1V     166.5mA    144.1mA    199.8mA
-1.7V     127.7mA    109.6mA    155.4mA
-1.1V     65.68mA    57.23mA    80.74mA
-800mV    38.15mA    32.03mA    51.27mA
-400mV    16.16mA    12.21mA    22.4mA
700mV     -23.35mA   -17.1mA    -33.47mA
1.5V      -40.31mA   -28.86mA   -59.25mA
2.3V      -47.43mA   -33.07mA   -72.06mA
3.8V      -50.32mA   -34.71mA   -77.98mA
6.55V     -50.32mA   -34.71mA   -77.98mA
[GND_clamp]
|Voltage   I(typ)   I(min)   I(max)
-3.3V     -955.2mA   -930.2mA   -977.8mA
-1.2V     -86.08mA   -82.87mA   -94.74mA
-1.15V    -76.63mA   -73.22mA   -85.57mA
-1.1V     -67.6mA    -63.89mA   -77.12mA
-1V       -51.41mA   -46.51mA   -63.06mA
-900mV    -38.77mA   -31.82mA   -51.11mA
-800mV    -28.16mA   -20.53mA   -37.82mA
-700mV    -18.01mA   -11.58mA   -24.66mA
-600mV    -9.185mA   -5.219mA   -12.92mA
-450mV    -1.125mA   -553.6uA   -1.501mA
-300mV    0A         0A         0A
6.6V      0A         0A         0A
[POWER_clamp]
|Voltage   I(typ)   I(min)   I(max)
-3.25V    961.3uA    1.05mA     917.9uA
-2.05V    275.4uA    268.3uA    307.1uA
-1.75V    231.3uA    224.8uA    252.6uA
-950mV    120.7uA    124.7uA    102.8uA
-750mV    90.82uA    102.7uA    94.17uA
-450mV    58.57uA    68.87uA    19.46uA
-350mV    58.57uA    58.54uA    3.121uA
50mV      -5.338uA   31.71uA    -57.16uA
850mV     -79.07uA   -36.24uA   -150.4uA
1.55V     -120.8uA   -70.05uA   -201.6uA
2.05V     -130.5uA   -83.29uA   -201.6uA
6.6V      -130.5uA   -83.29uA   -201.6uA
[Ramp]
| variable   typ   min   max
dV/dt_r  1.1542/0.2206n   0.9035/0.2801n   1.4308/0.1578n
dV/dt_f  1.1855/0.2259n   0.8843/0.2771n   1.4345/0.1863n
R_load = 50.0000
[Rising Waveform]
R_fixture=   50.0000
V_fixture=   3.3000
V_fixture_min=   3.1400
V_fixture_max=   3.4700
|time   V(typ)   V(min)   V(max)
0s        1.324V     1.666V     1.079V
404ps     1.324V     1.666V     1.079V
505.1ps   1.324V     1.666V     1.289V
606.1ps   1.323V     1.666V     2.842V
707.1ps   1.395V     1.666V     3.326V
909.1ps   2.964V     1.665V     3.427V
1.01ns    3.179V     1.661V     3.445V
1.313ns   3.268V     2.844V     3.465V
1.616ns   3.289V     3.093V     3.469V
10ns      3.3V       3.14V      3.47V
[Rising Waveform]
R_fixture=   50.0000
V_fixture=   0.0
V_fixture_min=   0.0
V_fixture_max=   0.0
|time   V(typ)   V(min)   V(max)
0s        830nV      1.065uV    812.2nV
505.1ps   15.3uV     909.1nV    -44.25mV
707.1ps   -23.18mV   20.06uV    1.847V
808.1ps   14.4mV     57.31uV    2.142V
1.01ns    1.345V     -7.638mV   2.312V
1.111ns   1.619V     -31.67mV   2.341V
1.212ns   1.738V     -17.55mV   2.358V
1.616ns   1.883V     1.24V      2.381V
2.121ns   1.916V     1.448V     2.384V
10ns      1.924V     1.506V     2.385V
[Falling Waveform]
R_fixture=   50.0000
V_fixture=   0.0
V_fixture_min=   0.0
V_fixture_max=   0.0
|time   V(typ)   V(min)   V(max)
0s        1.924V     1.506V     2.385V
505.1ps   1.924V     1.506V     2.387V
606.1ps   1.924V     1.506V     952mV
707.1ps   1.923V     1.506V     188.5mV
808.1ps   1.786V     1.506V     71.9mV
909.1ps   590.5mV    1.506V     36.28mV
1.212ns   41.57mV    1.49V      5.293mV
1.414ns   17.1mV     439.3mV    1.518mV
1.717ns   4.623mV    45.24mV    316.1uV
10ns      -628.1nV   9.184uV    2.185uV
[Falling Waveform]
R_fixture=   50.0000
V_fixture=   3.3000
V_fixture_min=   3.1400
V_fixture_max=   3.4700
|time   V(typ)   V(min)   V(max)
0s        3.3V       3.14V      3.47V
505.1ps   3.3V       3.14V      3.474V
707.1ps   3.297V     3.14V      1.741V
808.1ps   3.318V     3.14V      1.368V
1.01ns    1.953V     3.141V     1.147V
1.111ns   1.67V      3.138V     1.115V
1.313ns   1.448V     3.13V      1.091V
1.616ns   1.359V     2.004V     1.081V
2.121ns   1.329V     1.728V     1.079V
10ns      1.324V     1.666V     1.079V
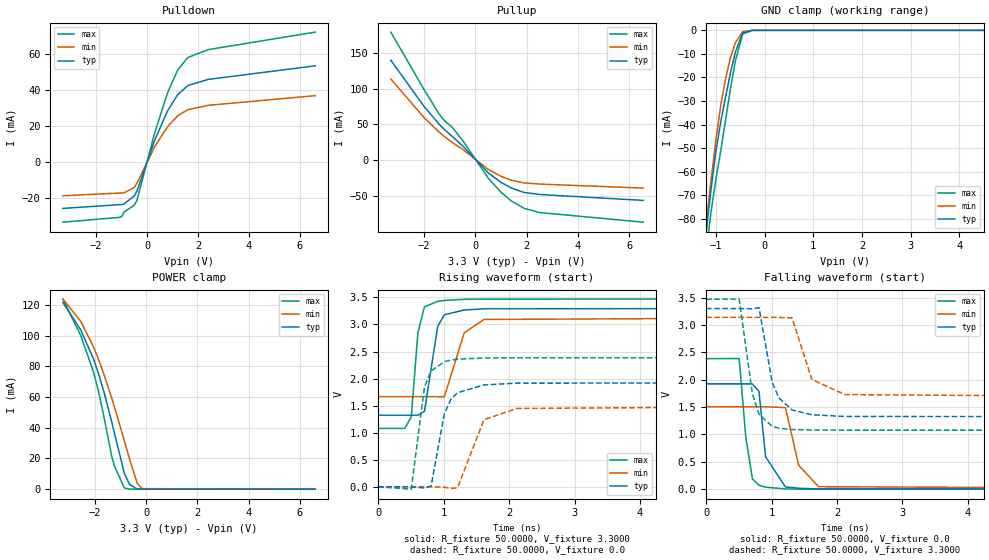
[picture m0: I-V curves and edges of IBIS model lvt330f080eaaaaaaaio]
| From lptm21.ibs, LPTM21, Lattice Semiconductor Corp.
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|   Model lvt330f080eaaaaaaaio
[Model]   lvt330f080eaaaaaaaio
Model_type   I/O
Polarity   Non-Inverting
Enable   Active-Low
Vinl =   0.8000V
Vinh =   2.0000V
Vmeas =   1.500000V
Cref =   0.0F
Rref =   1.0000M
Vref =   0.0V
C_comp   4.2000pF   3.8000pF   7.5000pF
[Temperature Range]   25.0000   0.1050k   -40.0000
[Voltage Range]   3.3000V   3.1400V   3.4700V
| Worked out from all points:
|   slope of the pulldown table from 0 to 0.495 V, typ, clamps not added: 26 ohm
|   slope of the pullup table from 0 to 0.495 V, typ, clamps not added: 28.5 ohm
|   GND clamp passes 1 mA (typ) near -0.44 V on its own axis
|   POWER clamp passes 1 mA (typ) near -0.54 V on its own axis
|   rising waveform, R_fixture 50.0000, V_fixture 3.3000: 20-80 % time 154ps typ, 209ps min, 115ps max; typ from 1.32 V to 3.3 V
|   rising waveform, R_fixture 50.0000, V_fixture 0.0: 20-80 % time 223ps typ, 283ps min, 159ps max; typ from 0 V to 1.92 V
|   falling waveform, R_fixture 50.0000, V_fixture 0.0: 20-80 % time 129ps typ, 176ps min, 130ps max; typ from 1.92 V to 0 V
|   falling waveform, R_fixture 50.0000, V_fixture 3.3000: 20-80 % time 228ps typ, 280ps min, 188ps max; typ from 3.3 V to 1.32 V
[Pulldown]
|Voltage   I(typ)   I(min)   I(max)
-3.3V     -25.87mA   -18.83mA   -33.56mA
-1.1V     -23.82mA   -17.33mA   -30.89mA
-1V       -23.72mA   -17.27mA   -30.52mA
-900mV    -23.42mA   -17.2mA    -27.86mA
-500mV    -18.89mA   -14.22mA   -24.07mA
-400mV    -16.44mA   -11.92mA   -21.58mA
300mV     12.11mA    8.499mA    16.2mA
800mV     28.3mA     19.6mA     38.33mA
1.2V      37.47mA    25.7mA     51.17mA
1.6V      42.61mA    29.13mA    58.23mA
2.4V      46.02mA    31.56mA    62.59mA
6.6V      53.58mA    36.95mA    72.38mA
[Pullup]
|Voltage   I(typ)   I(min)   I(max)
-3.3V     139.8mA    113.6mA    179.2mA
-2V       75.09mA    59.5mA     98.63mA
-1.4V     49.72mA    38.87mA    63.81mA
-1.2V     42.57mA    32.84mA    55.1mA
-900mV    33.12mA    24.63mA    45.95mA
-500mV    20.21mA    15.31mA    27.84mA
500mV     -17.54mA   -12.91mA   -25.01mA
1V        -31.01mA   -22.53mA   -44.83mA
1.4V      -38.87mA   -27.91mA   -56.93mA
1.9V      -45.07mA   -31.81mA   -67.31mA
2.5V      -47.95mA   -33.38mA   -73.15mA
6.55V     -56.22mA   -38.99mA   -86.7mA
[GND_clamp]
|Voltage   I(typ)   I(min)   I(max)
-3.3V     -955.3mA   -930.3mA   -978mA
-1.2V     -86.18mA   -82.93mA   -94.91mA
-1.15V    -76.73mA   -73.29mA   -85.74mA
-1.1V     -67.71mA   -63.95mA   -77.28mA
-1V       -51.52mA   -46.57mA   -63.21mA
-900mV    -38.87mA   -31.88mA   -51.26mA
-800mV    -28.25mA   -20.58mA   -37.97mA
-700mV    -18.1mA    -11.63mA   -24.81mA
-600mV    -9.267mA   -5.265mA   -13.06mA
-450mV    -1.181mA   -586.6uA   -1.592mA
-250mV    -3.532uA   -4.055uA   -3.003uA
6.6V      0A         0A         0A
[POWER_clamp]
|Voltage   I(typ)   I(min)   I(max)
-3.25V    121.6mA    123.7mA    123.8mA
-2.55V    103.6mA    109.2mA    99.91mA
-2.05V    84.55mA    92.42mA    76.01mA
-1.85V    74.75mA    84.09mA    62.98mA
-1.65V    63.47mA    74.86mA    47.24mA
-1.35V    44.14mA    59.56mA    21.79mA
-1.25V    37.23mA    54.16mA    15.46mA
-850mV    10.22mA    31.49mA    813uA
-650mV    3.122mA    19.66mA    19.66uA
-350mV    37.56uA    3.815mA    1.535uA
-150mV    934.2nA    336.7uA    1.026uA
6.6V      -57.56nA   -49.34nA   -232.5nA
[Ramp]
| variable   typ   min   max
dV/dt_r  1.1542/0.2206n   0.9035/0.2801n   1.4308/0.1578n
dV/dt_f  1.1855/0.2259n   0.8843/0.2771n   1.4345/0.1863n
R_load = 50.0000
[Rising Waveform]
R_fixture=   50.0000
V_fixture=   3.3000
V_fixture_min=   3.1400
V_fixture_max=   3.4700
|time   V(typ)   V(min)   V(max)
0s        1.324V     1.666V     1.079V
404ps     1.324V     1.666V     1.079V
505.1ps   1.324V     1.666V     1.289V
606.1ps   1.323V     1.666V     2.842V
707.1ps   1.395V     1.666V     3.326V
909.1ps   2.964V     1.665V     3.427V
1.01ns    3.179V     1.661V     3.445V
1.313ns   3.268V     2.844V     3.465V
1.616ns   3.289V     3.093V     3.469V
10ns      3.3V       3.14V      3.47V
[Rising Waveform]
R_fixture=   50.0000
V_fixture=   0.0
V_fixture_min=   0.0
V_fixture_max=   0.0
|time   V(typ)   V(min)   V(max)
0s        830nV      1.065uV    812.2nV
505.1ps   15.3uV     909.1nV    -44.25mV
707.1ps   -23.18mV   20.06uV    1.847V
808.1ps   14.4mV     57.31uV    2.142V
1.01ns    1.345V     -7.638mV   2.312V
1.111ns   1.619V     -31.67mV   2.341V
1.212ns   1.738V     -17.55mV   2.358V
1.616ns   1.883V     1.24V      2.381V
2.121ns   1.916V     1.448V     2.384V
10ns      1.924V     1.506V     2.385V
[Falling Waveform]
R_fixture=   50.0000
V_fixture=   0.0
V_fixture_min=   0.0
V_fixture_max=   0.0
|time   V(typ)   V(min)   V(max)
0s        1.924V     1.506V     2.385V
505.1ps   1.924V     1.506V     2.387V
606.1ps   1.924V     1.506V     952mV
707.1ps   1.923V     1.506V     188.5mV
808.1ps   1.786V     1.506V     71.9mV
909.1ps   590.5mV    1.506V     36.28mV
1.212ns   41.57mV    1.49V      5.293mV
1.414ns   17.1mV     439.3mV    1.518mV
1.717ns   4.623mV    45.24mV    316.1uV
10ns      -628.1nV   9.184uV    2.185uV
[Falling Waveform]
R_fixture=   50.0000
V_fixture=   3.3000
V_fixture_min=   3.1400
V_fixture_max=   3.4700
|time   V(typ)   V(min)   V(max)
0s        3.3V       3.14V      3.47V
505.1ps   3.3V       3.14V      3.474V
707.1ps   3.297V     3.14V      1.741V
808.1ps   3.318V     3.14V      1.368V
1.01ns    1.953V     3.141V     1.147V
1.111ns   1.67V      3.138V     1.115V
1.313ns   1.448V     3.13V      1.091V
1.616ns   1.359V     2.004V     1.081V
2.121ns   1.329V     1.728V     1.079V
10ns      1.324V     1.666V     1.079V
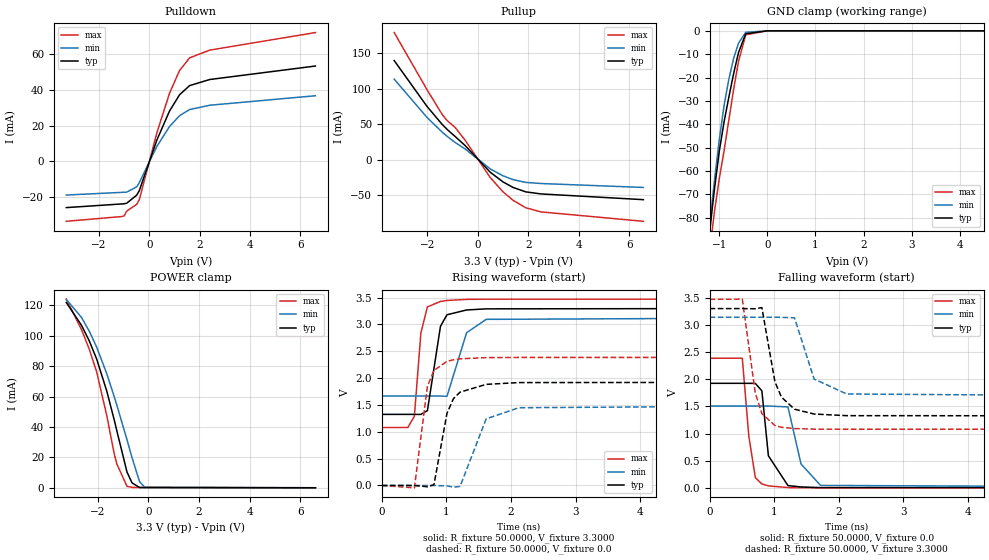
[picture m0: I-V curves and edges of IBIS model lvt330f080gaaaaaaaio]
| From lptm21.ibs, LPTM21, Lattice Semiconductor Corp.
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|   Model lvt330f080gaaaaaaaio
[Model]   lvt330f080gaaaaaaaio
Model_type   I/O
Polarity   Non-Inverting
Enable   Active-Low
Vinl =   0.8000V
Vinh =   2.0000V
Vmeas =   1.500000V
Cref =   0.0F
Rref =   1.0000M
Vref =   0.0V
C_comp   4.2000pF   3.8000pF   7.5000pF
[Temperature Range]   25.0000   0.1050k   -40.0000
[Voltage Range]   3.3000V   3.1400V   3.4700V
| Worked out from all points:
|   slope of the pulldown table from 0 to 0.495 V, typ, clamps not added: 26.1 ohm
|   slope of the pullup table from 0 to 0.495 V, typ, clamps not added: 28.5 ohm
|   GND clamp passes 1 mA (typ) near -0.43 V on its own axis
|   POWER clamp passes 1 mA (typ) near -0.53 V on its own axis
|   rising waveform, R_fixture 50.0000, V_fixture 3.3000: 20-80 % time 154ps typ, 209ps min, 115ps max; typ from 1.32 V to 3.3 V
|   rising waveform, R_fixture 50.0000, V_fixture 0.0: 20-80 % time 223ps typ, 283ps min, 159ps max; typ from 0 V to 1.92 V
|   falling waveform, R_fixture 50.0000, V_fixture 0.0: 20-80 % time 129ps typ, 176ps min, 130ps max; typ from 1.92 V to 0 V
|   falling waveform, R_fixture 50.0000, V_fixture 3.3000: 20-80 % time 228ps typ, 280ps min, 188ps max; typ from 3.3 V to 1.32 V
[Pulldown]
|Voltage   I(typ)   I(min)   I(max)
-3.3V     -25.84mA   -18.8mA    -33.51mA
-1.1V     -23.79mA   -17.31mA   -30.85mA
-1V       -23.69mA   -17.24mA   -30.48mA
-900mV    -23.39mA   -17.18mA   -27.82mA
-500mV    -18.83mA   -14.17mA   -23.98mA
-400mV    -16.36mA   -11.87mA   -21.45mA
300mV     12.05mA    8.472mA    16.09mA
800mV     28.21mA    19.56mA    38.15mA
1.2V      37.37mA    25.65mA    50.98mA
1.6V      42.51mA    29.09mA    58.05mA
2.4V      45.92mA    31.51mA    62.4mA
6.6V      53.48mA    36.83mA    72.22mA
[Pullup]
|Voltage   I(typ)   I(min)   I(max)
-3.3V     139.5mA    113.4mA    178.9mA
-2V       74.9mA     59.36mA    98.4mA
-1.4V     49.55mA    38.76mA    63.56mA
-1.2V     42.42mA    32.74mA    54.86mA
-900mV    33.01mA    24.56mA    45.81mA
-500mV    20.13mA    15.27mA    27.71mA
500mV     -17.65mA   -12.95mA   -25.2mA
1V        -31.11mA   -22.58mA   -45.03mA
1.4V      -38.97mA   -27.96mA   -57.12mA
1.9V      -45.16mA   -31.85mA   -67.49mA
2.5V      -48.04mA   -33.43mA   -73.33mA
6.55V     -56.13mA   -38.94mA   -86.56mA
[GND_clamp]
|Voltage   I(typ)   I(min)   I(max)
-3.3V     -955.3mA   -930.3mA   -978mA
-1.2V     -86.21mA   -82.95mA   -94.94mA
-1.15V    -76.76mA   -73.31mA   -85.77mA
-1.1V     -67.73mA   -63.97mA   -77.32mA
-1V       -51.54mA   -46.59mA   -63.26mA
-900mV    -38.9mA    -31.9mA    -51.31mA
-800mV    -28.29mA   -20.61mA   -38.02mA
-700mV    -18.14mA   -11.66mA   -24.86mA
-600mV    -9.315mA   -5.302mA   -13.12mA
-450mV    -1.255mA   -637uA     -1.701mA
0V        0A         0A         0A
6.6V      0A         0A         0A
[POWER_clamp]
|Voltage   I(typ)   I(min)   I(max)
-3.25V    121.9mA    123.9mA    124.1mA
-2.65V    106.9mA    112.1mA    104.1mA
-2.35V    96.95mA    103.3mA    91.59mA
-2.05V    84.73mA    92.58mA    76.25mA
-1.65V    63.65mA    75mA       47.49mA
-1.35V    44.31mA    59.69mA    21.99mA
-1.25V    37.38mA    54.28mA    15.6mA
-850mV    10.32mA    31.58mA    939uA
-650mV    3.193mA    19.74mA    210uA
-350mV    132.1uA    3.862mA    199.7uA
-150mV    104.6uA    375.8uA    197.7uA
6.6V      -56.35nA   -1.463uA   -71.55uA
[Ramp]
| variable   typ   min   max
dV/dt_r  1.1542/0.2206n   0.9035/0.2801n   1.4308/0.1578n
dV/dt_f  1.1855/0.2259n   0.8843/0.2771n   1.4345/0.1863n
R_load = 50.0000
[Rising Waveform]
R_fixture=   50.0000
V_fixture=   3.3000
V_fixture_min=   3.1400
V_fixture_max=   3.4700
|time   V(typ)   V(min)   V(max)
0s        1.324V     1.666V     1.079V
404ps     1.324V     1.666V     1.079V
505.1ps   1.324V     1.666V     1.289V
606.1ps   1.323V     1.666V     2.842V
707.1ps   1.395V     1.666V     3.326V
909.1ps   2.964V     1.665V     3.427V
1.01ns    3.179V     1.661V     3.445V
1.313ns   3.268V     2.844V     3.465V
1.616ns   3.289V     3.093V     3.469V
10ns      3.3V       3.14V      3.47V
[Rising Waveform]
R_fixture=   50.0000
V_fixture=   0.0
V_fixture_min=   0.0
V_fixture_max=   0.0
|time   V(typ)   V(min)   V(max)
0s        830nV      1.065uV    812.2nV
505.1ps   15.3uV     909.1nV    -44.25mV
707.1ps   -23.18mV   20.06uV    1.847V
808.1ps   14.4mV     57.31uV    2.142V
1.01ns    1.345V     -7.638mV   2.312V
1.111ns   1.619V     -31.67mV   2.341V
1.212ns   1.738V     -17.55mV   2.358V
1.616ns   1.883V     1.24V      2.381V
2.121ns   1.916V     1.448V     2.384V
10ns      1.924V     1.506V     2.385V
[Falling Waveform]
R_fixture=   50.0000
V_fixture=   0.0
V_fixture_min=   0.0
V_fixture_max=   0.0
|time   V(typ)   V(min)   V(max)
0s        1.924V     1.506V     2.385V
505.1ps   1.924V     1.506V     2.387V
606.1ps   1.924V     1.506V     952mV
707.1ps   1.923V     1.506V     188.5mV
808.1ps   1.786V     1.506V     71.9mV
909.1ps   590.5mV    1.506V     36.28mV
1.212ns   41.57mV    1.49V      5.293mV
1.414ns   17.1mV     439.3mV    1.518mV
1.717ns   4.623mV    45.24mV    316.1uV
10ns      -628.1nV   9.184uV    2.185uV
[Falling Waveform]
R_fixture=   50.0000
V_fixture=   3.3000
V_fixture_min=   3.1400
V_fixture_max=   3.4700
|time   V(typ)   V(min)   V(max)
0s        3.3V       3.14V      3.47V
505.1ps   3.3V       3.14V      3.474V
707.1ps   3.297V     3.14V      1.741V
808.1ps   3.318V     3.14V      1.368V
1.01ns    1.953V     3.141V     1.147V
1.111ns   1.67V      3.138V     1.115V
1.313ns   1.448V     3.13V      1.091V
1.616ns   1.359V     2.004V     1.081V
2.121ns   1.329V     1.728V     1.079V
10ns      1.324V     1.666V     1.079V
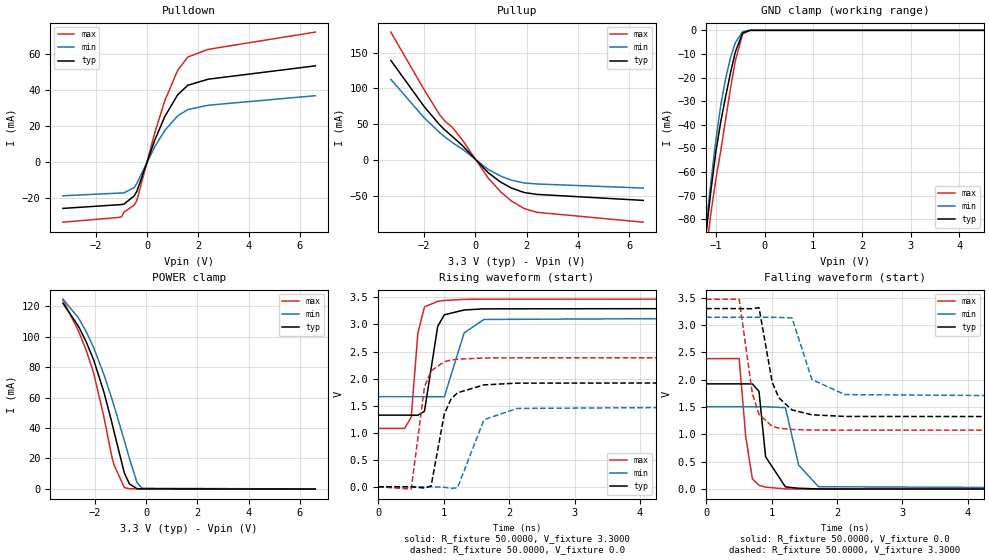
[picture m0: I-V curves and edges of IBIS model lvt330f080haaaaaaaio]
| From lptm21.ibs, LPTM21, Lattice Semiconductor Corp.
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|   Model lvt330f080haaaaaaaio
[Model]   lvt330f080haaaaaaaio
Model_type   I/O
Polarity   Non-Inverting
Enable   Active-Low
Vinl =   0.8000V
Vinh =   2.0000V
Vmeas =   1.500000V
Cref =   0.0F
Rref =   1.0000M
Vref =   0.0V
C_comp   4.2000pF   3.8000pF   7.5000pF
[Temperature Range]   25.0000   0.1050k   -40.0000
[Voltage Range]   3.3000V   3.1400V   3.4700V
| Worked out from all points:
|   slope of the pulldown table from 0 to 0.495 V, typ, clamps not added: 26.1 ohm
|   slope of the pullup table from 0 to 0.495 V, typ, clamps not added: 28.6 ohm
|   GND clamp passes 1 mA (typ) near -0.44 V on its own axis
|   POWER clamp passes 1 mA (typ) near -0.53 V on its own axis
|   rising waveform, R_fixture 50.0000, V_fixture 3.3000: 20-80 % time 154ps typ, 209ps min, 115ps max; typ from 1.32 V to 3.3 V
|   rising waveform, R_fixture 50.0000, V_fixture 0.0: 20-80 % time 223ps typ, 283ps min, 159ps max; typ from 0 V to 1.92 V
|   falling waveform, R_fixture 50.0000, V_fixture 0.0: 20-80 % time 129ps typ, 176ps min, 130ps max; typ from 1.92 V to 0 V
|   falling waveform, R_fixture 50.0000, V_fixture 3.3000: 20-80 % time 228ps typ, 280ps min, 188ps max; typ from 3.3 V to 1.32 V
[Pulldown]
|Voltage   I(typ)   I(min)   I(max)
-3.3V     -25.84mA   -18.8mA    -33.51mA
-1.1V     -23.79mA   -17.31mA   -30.85mA
-1V       -23.69mA   -17.24mA   -30.48mA
-900mV    -23.39mA   -17.18mA   -27.82mA
-500mV    -18.83mA   -14.17mA   -23.98mA
-400mV    -16.36mA   -11.87mA   -21.45mA
300mV     12.05mA    8.472mA    16.09mA
700mV     25.38mA    17.64mA    34.23mA
1.2V      37.37mA    25.65mA    50.98mA
1.6V      42.73mA    29.21mA    58.43mA
2.4V      46.1mA     31.61mA    62.73mA
6.6V      53.54mA    36.92mA    72.33mA
[Pullup]
|Voltage   I(typ)   I(min)   I(max)
-3.3V     139.2mA    112.8mA    178.7mA
-2V       74.83mA    59.16mA    98.43mA
-1.4V     49.54mA    38.67mA    63.64mA
-1.2V     42.42mA    32.69mA    54.96mA
-900mV    33.03mA    24.54mA    45.88mA
-500mV    20.17mA    15.28mA    27.8mA
500mV     -17.49mA   -12.87mA   -24.94mA
1V        -30.92mA   -22.47mA   -44.7mA
1.4V      -38.75mA   -27.83mA   -56.76mA
1.9V      -45.16mA   -31.85mA   -67.49mA
2.4V      -47.76mA   -33.25mA   -72.75mA
6.55V     -56.13mA   -38.94mA   -86.56mA
[GND_clamp]
|Voltage   I(typ)   I(min)   I(max)
-3.3V     -955.2mA   -930.2mA   -977.8mA
-1.2V     -86.08mA   -82.87mA   -94.74mA
-1.15V    -76.63mA   -73.22mA   -85.57mA
-1.1V     -67.6mA    -63.89mA   -77.12mA
-1V       -51.41mA   -46.51mA   -63.06mA
-900mV    -38.77mA   -31.82mA   -51.11mA
-800mV    -28.16mA   -20.53mA   -37.82mA
-700mV    -18.01mA   -11.58mA   -24.66mA
-600mV    -9.185mA   -5.219mA   -12.92mA
-450mV    -1.125mA   -553.6uA   -1.501mA
-300mV    0A         0A         0A
6.6V      0A         0A         0A
[POWER_clamp]
|Voltage   I(typ)   I(min)   I(max)
-3.25V    122.1mA    124.8mA    124.2mA
-2.65V    107.1mA    112.6mA    104.1mA
-2.35V    97.06mA    103.7mA    91.56mA
-2.05V    84.81mA    92.86mA    76.2mA
-1.65V    63.69mA    75.19mA    47.4mA
-1.35V    44.32mA    59.82mA    21.89mA
-1.25V    37.38mA    54.39mA    15.53mA
-850mV    10.3mA     31.63mA    860uA
-650mV    3.168mA    19.76mA    65.53uA
-350mV    73.34uA    3.862mA    3.121uA
-150mV    17.77uA    366.8uA    -28.16uA
6.6V      -130.5uA   -83.29uA   -201.6uA
[Ramp]
| variable   typ   min   max
dV/dt_r  1.1542/0.2206n   0.9035/0.2801n   1.4308/0.1578n
dV/dt_f  1.1855/0.2259n   0.8843/0.2771n   1.4345/0.1863n
R_load = 50.0000
[Rising Waveform]
R_fixture=   50.0000
V_fixture=   3.3000
V_fixture_min=   3.1400
V_fixture_max=   3.4700
|time   V(typ)   V(min)   V(max)
0s        1.324V     1.666V     1.079V
404ps     1.324V     1.666V     1.079V
505.1ps   1.324V     1.666V     1.289V
606.1ps   1.323V     1.666V     2.842V
707.1ps   1.395V     1.666V     3.326V
909.1ps   2.964V     1.665V     3.427V
1.01ns    3.179V     1.661V     3.445V
1.313ns   3.268V     2.844V     3.465V
1.616ns   3.289V     3.093V     3.469V
10ns      3.3V       3.14V      3.47V
[Rising Waveform]
R_fixture=   50.0000
V_fixture=   0.0
V_fixture_min=   0.0
V_fixture_max=   0.0
|time   V(typ)   V(min)   V(max)
0s        830nV      1.065uV    812.2nV
505.1ps   15.3uV     909.1nV    -44.25mV
707.1ps   -23.18mV   20.06uV    1.847V
808.1ps   14.4mV     57.31uV    2.142V
1.01ns    1.345V     -7.638mV   2.312V
1.111ns   1.619V     -31.67mV   2.341V
1.212ns   1.738V     -17.55mV   2.358V
1.616ns   1.883V     1.24V      2.381V
2.121ns   1.916V     1.448V     2.384V
10ns      1.924V     1.506V     2.385V
[Falling Waveform]
R_fixture=   50.0000
V_fixture=   0.0
V_fixture_min=   0.0
V_fixture_max=   0.0
|time   V(typ)   V(min)   V(max)
0s        1.924V     1.506V     2.385V
505.1ps   1.924V     1.506V     2.387V
606.1ps   1.924V     1.506V     952mV
707.1ps   1.923V     1.506V     188.5mV
808.1ps   1.786V     1.506V     71.9mV
909.1ps   590.5mV    1.506V     36.28mV
1.212ns   41.57mV    1.49V      5.293mV
1.414ns   17.1mV     439.3mV    1.518mV
1.717ns   4.623mV    45.24mV    316.1uV
10ns      -628.1nV   9.184uV    2.185uV
[Falling Waveform]
R_fixture=   50.0000
V_fixture=   3.3000
V_fixture_min=   3.1400
V_fixture_max=   3.4700
|time   V(typ)   V(min)   V(max)
0s        3.3V       3.14V      3.47V
505.1ps   3.3V       3.14V      3.474V
707.1ps   3.297V     3.14V      1.741V
808.1ps   3.318V     3.14V      1.368V
1.01ns    1.953V     3.141V     1.147V
1.111ns   1.67V      3.138V     1.115V
1.313ns   1.448V     3.13V      1.091V
1.616ns   1.359V     2.004V     1.081V
2.121ns   1.329V     1.728V     1.079V
10ns      1.324V     1.666V     1.079V
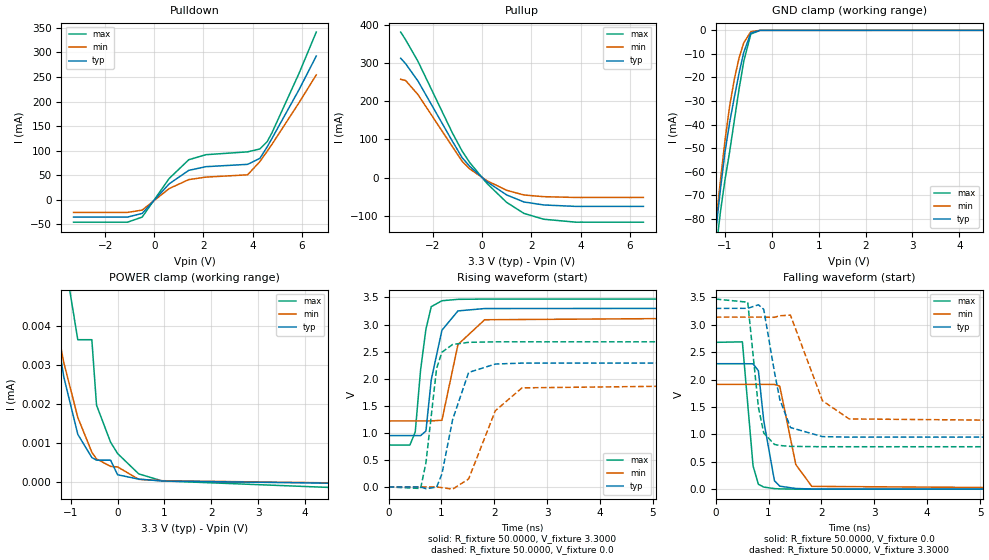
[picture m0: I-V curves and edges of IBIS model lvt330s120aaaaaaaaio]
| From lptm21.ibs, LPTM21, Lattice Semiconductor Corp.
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|   Model lvt330s120aaaaaaaaio
[Model]   lvt330s120aaaaaaaaio
Model_type   I/O
Polarity   Non-Inverting
Enable   Active-Low
Vinl =   0.8000V
Vinh =   2.0000V
Vmeas =   1.500000V
Cref =   0.0F
Rref =   1.0000M
Vref =   0.0V
C_comp   4.2000pF   3.8000pF   7.5000pF
[Temperature Range]   25.0000   0.1050k   -40.0000
[Voltage Range]   3.3000V   3.1400V   3.4700V
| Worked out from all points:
|   slope of the pulldown table from 0 to 0.495 V, typ, clamps not added: 17.9 ohm
|   slope of the pullup table from 0 to 0.495 V, typ, clamps not added: 19.6 ohm
|   GND clamp passes 1 mA (typ) near -0.44 V on its own axis
|   rising waveform, R_fixture 50.0000, V_fixture 3.3000: 20-80 % time 244ps typ, 294ps min, 180ps max; typ from 0.948 V to 3.3 V
|   rising waveform, R_fixture 50.0000, V_fixture 0.0: 20-80 % time 304ps typ, 473ps min, 186ps max; typ from 0 V to 2.29 V
|   falling waveform, R_fixture 50.0000, V_fixture 0.0: 20-80 % time 168ps typ, 249ps min, 132ps max; typ from 2.29 V to 0 V
|   falling waveform, R_fixture 50.0000, V_fixture 3.3000: 20-80 % time 283ps typ, 451ps min, 193ps max; typ from 3.3 V to 0.948 V
[Pulldown]
|Voltage   I(typ)   I(min)   I(max)
-3.3V     -35.06mA   -25.56mA   -45.46mA
-1.1V     -35.06mA   -25.56mA   -45.46mA
-500mV    -27.6mA    -20.84mA   -35.05mA
600mV     32.61mA    22.93mA    43.45mA
1.4V      60.04mA    41.26mA    81.68mA
2.1V      67.54mA    46.31mA    91.93mA
3.8V      72.28mA    50.96mA    97.72mA
4.3V      84.4mA     77.91mA    103.6mA
4.6V      108mA      99.08mA    118.6mA
4.8V      125.6mA    113.5mA    137.2mA
5.9V      224.5mA    198mA      257.8mA
6.6V      292.7mA    254.4mA    341.5mA
[Pullup]
|Voltage   I(typ)   I(min)   I(max)
-3.3V     312.9mA    257.6mA    381.4mA
-3.1V     298.6mA    254.5mA    361.3mA
-2.6V     253.3mA    217.7mA    304.9mA
-1.2V     95.13mA    80.94mA    116.9mA
-800mV    51.73mA    42.33mA    68.75mA
-500mV    29.64mA    22.8mA     39.61mA
200mV     -10.87mA   -8.125mA   -15.16mA
1V        -45.47mA   -33.26mA   -64.98mA
1.7V      -63.84mA   -45.59mA   -93.77mA
2.5V      -71.72mA   -49.99mA   -109.1mA
3.8V      -75.49mA   -52.1mA    -116.8mA
6.55V     -75.49mA   -52.1mA    -116.9mA
[GND_clamp]
|Voltage   I(typ)   I(min)   I(max)
-3.3V     -955.3mA   -930.3mA   -978mA
-1.2V     -86.18mA   -82.93mA   -94.91mA
-1.15V    -76.73mA   -73.29mA   -85.74mA
-1.1V     -67.71mA   -63.95mA   -77.28mA
-1V       -51.52mA   -46.57mA   -63.21mA
-900mV    -38.87mA   -31.88mA   -51.26mA
-800mV    -28.25mA   -20.58mA   -37.97mA
-700mV    -18.1mA    -11.63mA   -24.81mA
-600mV    -9.267mA   -5.265mA   -13.06mA
-450mV    -1.181mA   -586.6uA   -1.592mA
-250mV    -3.532uA   -4.055uA   -3.003uA
6.6V      0A         0A         0A
[POWER_clamp]
|Voltage   I(typ)   I(min)   I(max)
-3.25V    664.8uA    749.4uA    597.1uA
-1.55V    5.916uA    5.714uA    11.4uA
-1.45V    4.989uA    4.976uA    9.753uA
-1.15V    2.705uA    3.075uA    5.865uA
-850mV    1.228uA    1.663uA    3.656uA
-550mV    632.9nA    768.1nA    3.656uA
-450mV    565.1nA    597.1nA    1.977uA
-150mV    565.1nA    405.8nA    1.026uA
0V        190.5nA    392.6nA    734.7nA
450mV     79.23nA    72.94nA    213.9nA
950mV     30.32nA    38.42nA    33.55nA
6.6V      -57.56nA   -49.34nA   -232.5nA
[Ramp]
| variable   typ   min   max
dV/dt_r  1.3741/0.3012n   1.1475/0.4684n   1.6081/0.1845n
dV/dt_f  1.4109/0.2806n   1.1527/0.4461n   1.6174/0.1908n
R_load = 50.0000
[Rising Waveform]
R_fixture=   50.0000
V_fixture=   3.3000
V_fixture_min=   3.1400
V_fixture_max=   3.4700
|time   V(typ)   V(min)   V(max)
0s        948.5mV    1.219V     774.4mV
404ps     948.5mV    1.219V     773.7mV
505.1ps   948.6mV    1.219V     1.014V
606.1ps   947.4mV    1.219V     2.161V
707.1ps   1.032V     1.219V     2.914V
808.1ps   1.981V     1.219V     3.33V
1.01ns    2.895V     1.232V     3.439V
1.313ns   3.251V     2.63V      3.465V
1.818ns   3.295V     3.088V     3.47V
10ns      3.3V       3.14V      3.47V
[Rising Waveform]
R_fixture=   50.0000
V_fixture=   0.0
V_fixture_min=   0.0
V_fixture_max=   0.0
|time   V(typ)   V(min)   V(max)
0s        612.2nV    810.3nV    586nV
606.1ps   -814.1uV   2.155uV    -28.5mV
707.1ps   -31.91mV   19.12uV    442.4mV
909.1ps   -3.978mV   -498.9uV   2.189V
1.01ns    240.4mV    -12.47mV   2.489V
1.212ns   1.244V     -41.1mV    2.631V
1.515ns   2.115V     148mV      2.671V
2.02ns    2.27V      1.408V     2.68V
2.525ns   2.287V     1.83V      2.68V
10ns      2.29V      1.913V     2.68V
[Falling Waveform]
R_fixture=   50.0000
V_fixture=   0.0
V_fixture_min=   0.0
V_fixture_max=   0.0
|time   V(typ)   V(min)   V(max)
0s        2.29V      1.913V     2.68V
505.1ps   2.29V      1.913V     2.689V
707.1ps   2.288V     1.913V     423.2mV
808.1ps   2.161V     1.913V     89.39mV
909.1ps   1.25V      1.913V     38.11mV
1.111ns   154.6mV    1.911V     10.1mV
1.212ns   54.48mV    1.881V     5.298mV
1.515ns   12.41mV    450.5mV    742.1uV
1.818ns   3.109mV    50.96mV    174.6uV
10ns      3.259uV    2.082uV    -608.2nV
[Falling Waveform]
R_fixture=   50.0000
V_fixture=   3.3000
V_fixture_min=   3.1400
V_fixture_max=   3.4700
|time   V(typ)   V(min)   V(max)
0s        3.3V       3.14V      3.47V
606.1ps   3.301V     3.14V      3.413V
808.1ps   3.366V     3.14V      1.496V
909.1ps   3.282V     3.14V      1.025V
1.111ns   2.142V     3.137V     816.9mV
1.212ns   1.64V      3.165V     797mV
1.414ns   1.125V     3.177V     781mV
2.02ns    958.8mV    1.614V     774.6mV
2.525ns   949.9mV    1.282V     774.5mV
10ns      948.5mV    1.219V     774.4mV
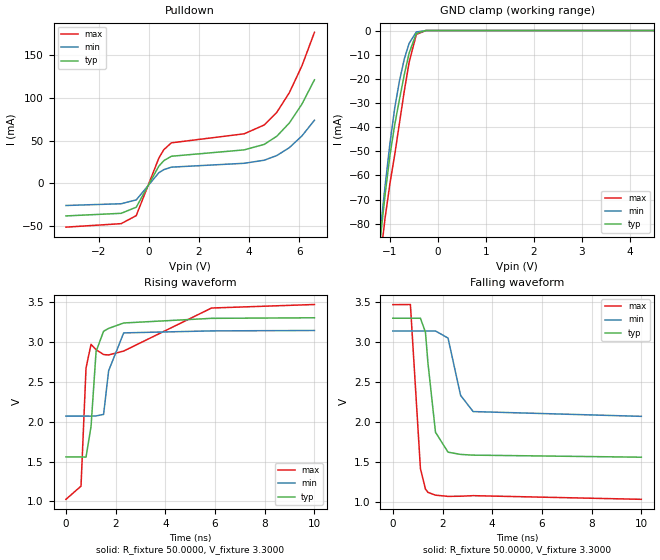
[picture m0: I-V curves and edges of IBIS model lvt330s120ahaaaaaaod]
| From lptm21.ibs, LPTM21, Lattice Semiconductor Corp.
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|   Model lvt330s120ahaaaaaaod
[Model]   lvt330s120ahaaaaaaod
Model_type   I/O_open_drain
Polarity   Non-Inverting
Enable   Active-Low
Vinl =   0.8000V
Vinh =   2.0000V
Vmeas =   1.6500V
Cref =   0.0F
Rref =   1.0000M
Vref =   0.0V
C_comp   4.2000pF   3.8000pF   7.5000pF
[Temperature Range]   25.0000   0.1050k   -40.0000
[Voltage Range]   3.3000V   3.1400V   3.4700V
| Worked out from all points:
|   slope of the pulldown table from 0 to 0.495 V, typ, clamps not added: 21.2 ohm
|   GND clamp passes 1 mA (typ) near -0.44 V on its own axis
|   rising waveform, R_fixture 50.0000, V_fixture 3.3000: 20-80 % time 259ps typ, 250ps min, 2.76ns max; typ from 1.56 V to 3.3 V
|   falling waveform, R_fixture 50.0000, V_fixture 3.3000: 20-80 % time 340ps typ, 489ps min, 250ps max; typ from 3.3 V to 1.56 V
[Pulldown]
|Voltage   I(typ)   I(min)   I(max)
-3.3V     -38.32mA   -26.11mA   -51.47mA
-1.1V     -35.26mA   -24.04mA   -47.36mA
-500mV    -28.13mA   -19.55mA   -37.97mA
400mV     19.95mA    12.24mA    29.35mA
600mV     26.4mA     15.93mA    39.3mA
900mV     31.58mA    18.8mA     47.29mA
3.8V      39.03mA    23.32mA    57.84mA
4.6V      45.48mA    26.93mA    68.21mA
5.1V      55.01mA    32.4mA     82.97mA
5.6V      70.52mA    41.65mA    106mA
6.1V      92.55mA    55.32mA    137.4mA
6.6V      121.1mA    73.73mA    176.7mA
[GND_clamp]
|Voltage   I(typ)   I(min)   I(max)
-3.3V     -955.3mA   -930.3mA   -978mA
-1.2V     -86.16mA   -82.91mA   -94.88mA
-1.15V    -76.71mA   -73.27mA   -85.71mA
-1.1V     -67.69mA   -63.93mA   -77.25mA
-1V       -51.49mA   -46.56mA   -63.18mA
-900mV    -38.84mA   -31.87mA   -51.23mA
-800mV    -28.23mA   -20.57mA   -37.94mA
-700mV    -18.08mA   -11.62mA   -24.79mA
-600mV    -9.254mA   -5.257mA   -13.04mA
-450mV    -1.176mA   -584.6uA   -1.582mA
-250mV    -3.498uA   -4.034uA   -2.958uA
6.6V      0A         0A         0A
[Ramp]
| variable   typ   min   max
dV/dt_r  1.0442/0.2563n   0.6422/0.2478n   1.4616/2.7300n
dV/dt_f  1.0449/0.3362n   0.6422/0.4839n   1.4640/0.2471n
R_load = 50.0000
[Rising Waveform]
R_fixture=   50.0000
V_fixture=   3.3000
V_fixture_min=   3.1400
V_fixture_max=   3.4700
|time   V(typ)   V(min)   V(max)
0s        1.557V     2.068V     1.027V
606.1ps   1.557V     2.068V     1.192V
808.1ps   1.555V     2.068V     2.67V
1.01ns    1.94V      2.067V     2.965V
1.212ns   2.875V     2.07V      2.898V
1.515ns   3.129V     2.089V     2.837V
1.717ns   3.164V     2.634V     2.832V
2.323ns   3.232V     3.108V     2.881V
5.859ns   3.29V      3.133V     3.419V
10ns      3.297V     3.138V     3.463V
[Falling Waveform]
R_fixture=   50.0000
V_fixture=   3.3000
V_fixture_min=   3.1400
V_fixture_max=   3.4700
|time   V(typ)   V(min)   V(max)
0s        3.3V       3.14V      3.47V
707.1ps   3.3V       3.14V      3.472V
1.111ns   3.3V       3.14V      1.415V
1.313ns   3.124V     3.14V      1.158V
1.414ns   2.737V     3.14V      1.117V
1.717ns   1.871V     3.14V      1.082V
2.222ns   1.621V     3.051V     1.067V
2.727ns   1.593V     2.333V     1.069V
3.232ns   1.584V     2.13V      1.076V
10ns      1.558V     2.07V      1.03V
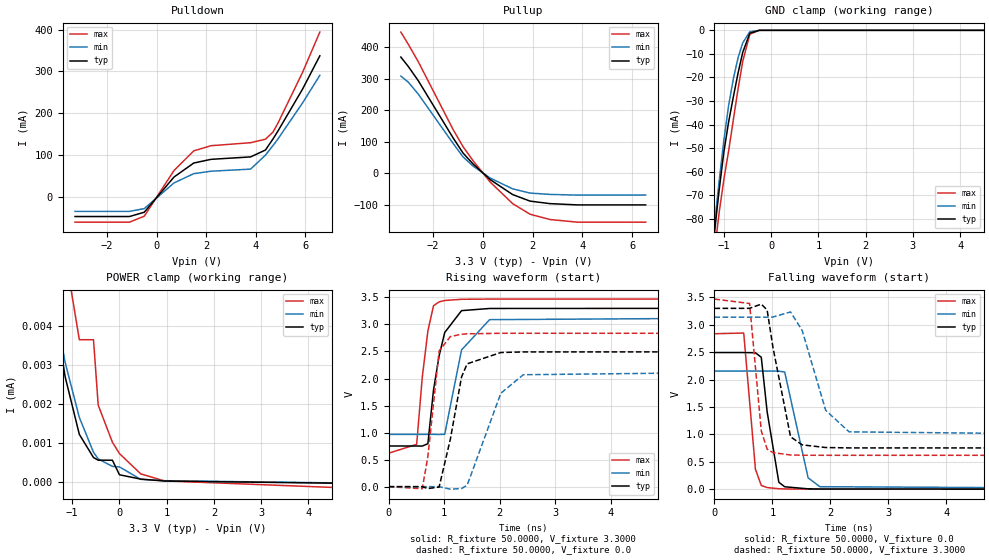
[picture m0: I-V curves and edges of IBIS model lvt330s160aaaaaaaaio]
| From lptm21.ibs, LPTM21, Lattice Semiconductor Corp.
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|   Model lvt330s160aaaaaaaaio
[Model]   lvt330s160aaaaaaaaio
Model_type   I/O
Polarity   Non-Inverting
Enable   Active-Low
Vinl =   0.8000V
Vinh =   2.0000V
Vmeas =   1.500000V
Cref =   0.0F
Rref =   1.0000M
Vref =   0.0V
C_comp   4.2000pF   3.8000pF   7.5000pF
[Temperature Range]   25.0000   0.1050k   -40.0000
[Voltage Range]   3.3000V   3.1400V   3.4700V
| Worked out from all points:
|   slope of the pulldown table from 0 to 0.495 V, typ, clamps not added: 13.9 ohm
|   slope of the pullup table from 0 to 0.495 V, typ, clamps not added: 15.1 ohm
|   GND clamp passes 1 mA (typ) near -0.44 V on its own axis
|   rising waveform, R_fixture 50.0000, V_fixture 3.3000: 20-80 % time 241ps typ, 285ps min, 173ps max; typ from 0.752 V to 3.3 V
|   rising waveform, R_fixture 50.0000, V_fixture 0.0: 20-80 % time 262ps typ, 413ps min, 170ps max; typ from 0 V to 2.49 V
|   falling waveform, R_fixture 50.0000, V_fixture 0.0: 20-80 % time 158ps typ, 236ps min, 124ps max; typ from 2.49 V to 0 V
|   falling waveform, R_fixture 50.0000, V_fixture 3.3000: 20-80 % time 230ps typ, 378ps min, 152ps max; typ from 3.3 V to 0.752 V
[Pulldown]
|Voltage   I(typ)   I(min)   I(max)
-3.3V     -46.05mA   -33.74mA   -59.55mA
-1.1V     -46.05mA   -33.74mA   -59.55mA
-500mV    -35.8mA    -27.15mA   -45.23mA
700mV     48.06mA    34mA       63.55mA
1.5V      81.57mA    56.2mA     110.6mA
2.2V      90.42mA    62.08mA    122.9mA
3.8V      96.2mA     67.07mA    130.1mA
4.4V      112.6mA    100.4mA    138.4mA
4.7V      138.5mA    122.9mA    155.1mA
4.9V      157.3mA    138.6mA    176mA
5.9V      257.9mA    224.8mA    297.8mA
6.6V      337.4mA    290.9mA    394mA
[Pullup]
|Voltage   I(typ)   I(min)   I(max)
-3.3V     368.8mA    308.5mA    448.2mA
-3V       339mA      289.2mA    409.4mA
-2.6V     293.9mA    251.4mA    354.3mA
-1.2V     112.6mA    94.92mA    139.1mA
-800mV    64.3mA     52.05mA    84.62mA
-400mV    29.88mA    23.1mA     40.29mA
300mV     -20.61mA   -15.5mA    -28.44mA
1.2V      -67.79mA   -49.58mA   -96.57mA
1.9V      -88.52mA   -62.97mA   -130.2mA
2.7V      -96.45mA   -67.2mA    -146.9mA
3.8V      -100.5mA   -69.39mA   -155.3mA
6.55V     -100.5mA   -69.39mA   -155.4mA
[GND_clamp]
|Voltage   I(typ)   I(min)   I(max)
-3.3V     -955.3mA   -930.3mA   -978mA
-1.2V     -86.18mA   -82.93mA   -94.91mA
-1.15V    -76.73mA   -73.29mA   -85.74mA
-1.1V     -67.71mA   -63.95mA   -77.28mA
-1V       -51.52mA   -46.57mA   -63.21mA
-900mV    -38.87mA   -31.88mA   -51.26mA
-800mV    -28.25mA   -20.58mA   -37.97mA
-700mV    -18.1mA    -11.63mA   -24.81mA
-600mV    -9.267mA   -5.265mA   -13.06mA
-450mV    -1.181mA   -586.6uA   -1.592mA
-250mV    -3.532uA   -4.055uA   -3.003uA
6.6V      0A         0A         0A
[POWER_clamp]
|Voltage   I(typ)   I(min)   I(max)
-3.25V    664.8uA    749.4uA    597.1uA
-1.55V    5.916uA    5.714uA    11.4uA
-1.45V    4.989uA    4.976uA    9.753uA
-1.15V    2.705uA    3.075uA    5.865uA
-850mV    1.228uA    1.663uA    3.656uA
-550mV    632.9nA    768.1nA    3.656uA
-450mV    565.1nA    597.1nA    1.977uA
-150mV    565.1nA    405.8nA    1.026uA
0V        190.5nA    392.6nA    734.7nA
450mV     79.23nA    72.94nA    213.9nA
950mV     30.32nA    38.42nA    33.55nA
6.6V      -57.56nA   -49.34nA   -232.5nA
[Ramp]
| variable   typ   min   max
dV/dt_r  1.4966/0.2592n   1.2936/0.4087n   1.7021/0.1678n
dV/dt_f  1.5290/0.2281n   1.3043/0.3741n   1.7112/0.1501n
R_load = 50.0000
[Rising Waveform]
R_fixture=   50.0000
V_fixture=   3.3000
V_fixture_min=   3.1400
V_fixture_max=   3.4700
|time   V(typ)   V(min)   V(max)
0s        751.6mV    966.1mV    618mV
505.1ps   751.7mV    966.1mV    782.9mV
606.1ps   750.5mV    966.1mV    2.026V
707.1ps   795mV      966.1mV    2.88V
808.1ps   1.786V     966.4mV    3.346V
909.1ps   2.419V     965.5mV    3.418V
1.01ns    2.851V     968.1mV    3.444V
1.313ns   3.256V     2.529V     3.466V
1.818ns   3.296V     3.089V     3.47V
10ns      3.3V       3.14V      3.47V
[Rising Waveform]
R_fixture=   50.0000
V_fixture=   0.0
V_fixture_min=   0.0
V_fixture_max=   0.0
|time   V(typ)   V(min)   V(max)
0s        484.9nV    653.8nV    458.4nV
606.1ps   -928.3uV   2.015uV    -38.81mV
707.1ps   -36.03mV   19.4uV     559mV
909.1ps   -7.501mV   -591.8uV   2.51V
1.111ns   876.5mV    -46.71mV   2.776V
1.313ns   2.029V     -34.83mV   2.819V
1.414ns   2.272V     25.73mV    2.827V
2.02ns    2.481V     1.727V     2.837V
2.424ns   2.492V     2.07V      2.837V
10ns      2.494V     2.156V     2.837V
[Falling Waveform]
R_fixture=   50.0000
V_fixture=   0.0
V_fixture_min=   0.0
V_fixture_max=   0.0
|time   V(typ)   V(min)   V(max)
0s        2.494V     2.156V     2.837V
505.1ps   2.494V     2.156V     2.85V
707.1ps   2.49V      2.156V     363.7mV
808.1ps   2.407V     2.156V     67.81mV
909.1ps   1.413V     2.156V     29.42mV
1.111ns   126.2mV    2.154V     7.547mV
1.212ns   43.67mV    2.138V     3.842mV
1.616ns   6.181mV    206.6mV    298.8uV
1.818ns   2.479mV    45.08mV    130.9uV
10ns      9.129uV    5.31uV     7.474uV
[Falling Waveform]
R_fixture=   50.0000
V_fixture=   3.3000
V_fixture_min=   3.1400
V_fixture_max=   3.4700
|time   V(typ)   V(min)   V(max)
0s        3.3V       3.14V      3.47V
606.1ps   3.301V     3.14V      3.389V
808.1ps   3.378V     3.14V      1.064V
909.1ps   3.27V      3.14V      731.6mV
1.01ns    2.584V     3.142V     666.6mV
1.313ns   955.6mV    3.235V     624.4mV
1.515ns   808.3mV    2.893V     619.6mV
1.919ns   760.1mV    1.439V     618.1mV
2.323ns   753.1mV    1.046V     618mV
10ns      751.7mV    966.1mV    618mV
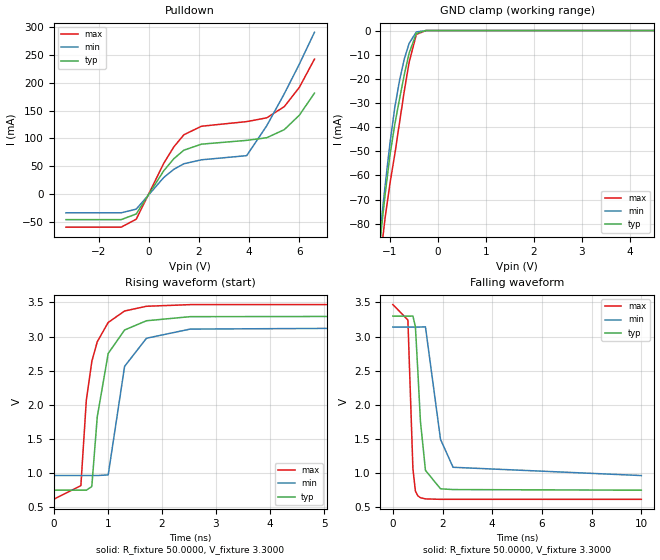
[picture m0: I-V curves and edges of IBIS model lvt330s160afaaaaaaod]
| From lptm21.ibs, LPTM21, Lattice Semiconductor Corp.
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|   Model lvt330s160afaaaaaaod
[Model]   lvt330s160afaaaaaaod
Model_type   I/O_open_drain
Polarity   Non-Inverting
Enable   Active-Low
Vinl =   0.8000V
Vinh =   2.0000V
Vmeas =   1.6500V
Cref =   0.0F
Rref =   1.0000M
Vref =   0.0V
C_comp   4.2000pF   3.8000pF   7.5000pF
[Temperature Range]   25.0000   0.1050k   -40.0000
[Voltage Range]   3.3000V   3.1400V   3.4700V
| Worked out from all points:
|   slope of the pulldown table from 0 to 0.495 V, typ, clamps not added: 13.9 ohm
|   GND clamp passes 1 mA (typ) near -0.44 V on its own axis
|   rising waveform, R_fixture 50.0000, V_fixture 3.3000: 20-80 % time 280ps typ, 278ps min, 264ps max; typ from 0.752 V to 3.3 V
|   falling waveform, R_fixture 50.0000, V_fixture 3.3000: 20-80 % time 263ps typ, 432ps min, 160ps max; typ from 3.3 V to 0.752 V
[Pulldown]
|Voltage   I(typ)   I(min)   I(max)
-3.3V     -46.05mA   -33.74mA   -59.55mA
-1.1V     -46.05mA   -33.74mA   -59.55mA
-500mV    -35.8mA    -27.15mA   -45.23mA
600mV     42.17mA    29.94mA    55.58mA
1V        63.65mA    44.54mA    85.02mA
1.4V      78.94mA    54.52mA    106.7mA
2.1V      89.73mA    61.59mA    122mA
3.9V      96.57mA    69.06mA    130.3mA
4.7V      101.3mA    122.9mA    137.1mA
5.4V      115.9mA    180.5mA    157.3mA
6V        141.9mA    233.9mA    192mA
6.6V      181.5mA    290.9mA    242.7mA
[GND_clamp]
|Voltage   I(typ)   I(min)   I(max)
-3.3V     -955.3mA   -930.3mA   -978mA
-1.2V     -86.18mA   -82.93mA   -94.91mA
-1.15V    -76.73mA   -73.29mA   -85.74mA
-1.1V     -67.71mA   -63.95mA   -77.28mA
-1V       -51.52mA   -46.57mA   -63.21mA
-900mV    -38.87mA   -31.88mA   -51.26mA
-800mV    -28.25mA   -20.58mA   -37.97mA
-700mV    -18.1mA    -11.63mA   -24.81mA
-600mV    -9.267mA   -5.265mA   -13.06mA
-450mV    -1.181mA   -586.6uA   -1.592mA
-250mV    -3.532uA   -4.055uA   -3.003uA
6.6V      0A         0A         0A
[Ramp]
| variable   typ   min   max
dV/dt_r  1.5290/0.2772n   1.3043/0.2754n   1.7112/0.2616n
dV/dt_f  1.5290/0.2604n   1.3043/0.4282n   1.7112/0.1589n
R_load = 50.0000
[Rising Waveform]
R_fixture=   50.0000
V_fixture=   3.3000
V_fixture_min=   3.1400
V_fixture_max=   3.4700
|time   V(typ)   V(min)   V(max)
0s        751.6mV    966.1mV    618mV
505.1ps   751.7mV    966.1mV    818.6mV
606.1ps   751.9mV    966.1mV    2.07V
707.1ps   805.9mV    966.1mV    2.636V
808.1ps   1.827V     966.4mV    2.925V
1.01ns    2.753V     975.3mV    3.207V
1.313ns   3.097V     2.565V     3.375V
1.717ns   3.232V     2.976V     3.444V
2.525ns   3.292V     3.11V      3.468V
10ns      3.3V       3.14V      3.47V
[Falling Waveform]
R_fixture=   50.0000
V_fixture=   3.3000
V_fixture_min=   3.1400
V_fixture_max=   3.4700
|time   V(typ)   V(min)   V(max)
0s        3.3V       3.14V      3.47V
606.1ps   3.299V     3.14V      3.243V
808.1ps   3.301V     3.14V      1.068V
909.1ps   3.142V     3.139V     736.3mV
1.01ns    2.469V     3.14V      667.8mV
1.111ns   1.762V     3.14V      642.4mV
1.313ns   1.042V     3.143V     624.1mV
1.919ns   772mV      1.496V     618.1mV
2.424ns   760.8mV    1.087V     618mV
10ns      751.7mV    966.1mV    617.9mV
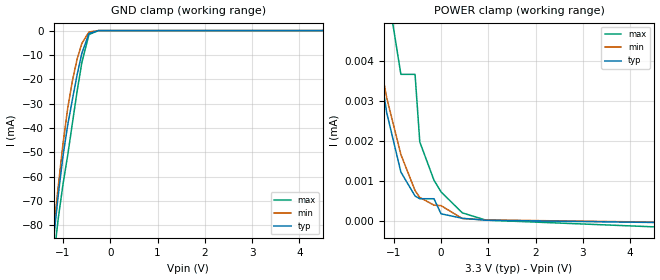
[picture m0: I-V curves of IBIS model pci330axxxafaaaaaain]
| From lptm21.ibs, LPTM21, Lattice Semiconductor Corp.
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|   Model pci330axxxafaaaaaain
[Model]   pci330axxxafaaaaaain
Model_type   Input
Polarity   Non-Inverting
Enable   Active-Low
Vinl =   0.9900V
Vinh =   1.6500V
C_comp   4.2000pF   3.8000pF   7.5000pF
[Temperature Range]   25.0000   0.1050k   -40.0000
[Voltage Range]   3.3000V   3.1400V   3.4700V
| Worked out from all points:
|   GND clamp passes 1 mA (typ) near -0.44 V on its own axis
[GND_clamp]
|Voltage   I(typ)   I(min)   I(max)
-3.3V     -955.3mA   -930.3mA   -978mA
-1.2V     -86.18mA   -82.93mA   -94.91mA
-1.15V    -76.73mA   -73.29mA   -85.74mA
-1.1V     -67.71mA   -63.95mA   -77.28mA
-1V       -51.52mA   -46.57mA   -63.21mA
-900mV    -38.87mA   -31.88mA   -51.26mA
-800mV    -28.25mA   -20.58mA   -37.97mA
-700mV    -18.1mA    -11.63mA   -24.81mA
-600mV    -9.267mA   -5.265mA   -13.06mA
-450mV    -1.181mA   -586.6uA   -1.592mA
-250mV    -3.532uA   -4.055uA   -3.003uA
6.6V      0A         0A         0A
[POWER_clamp]
|Voltage   I(typ)   I(min)   I(max)
-3.25V    664.8uA    749.4uA    597.1uA
-1.55V    5.916uA    5.714uA    11.4uA
-1.45V    4.989uA    4.976uA    9.753uA
-1.15V    2.705uA    3.075uA    5.865uA
-850mV    1.228uA    1.663uA    3.656uA
-550mV    632.9nA    768.1nA    3.656uA
-450mV    565.1nA    597.1nA    1.977uA
-150mV    565.1nA    405.8nA    1.026uA
0V        190.5nA    392.6nA    734.7nA
450mV     79.23nA    72.94nA    213.9nA
950mV     30.32nA    38.42nA    33.55nA
6.6V      -57.56nA   -49.34nA   -232.5nA
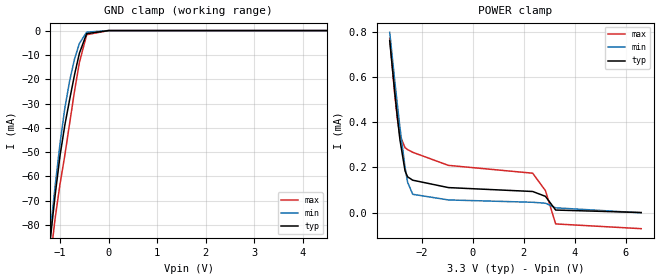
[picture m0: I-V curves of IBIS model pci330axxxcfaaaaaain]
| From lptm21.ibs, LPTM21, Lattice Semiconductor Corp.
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|   Model pci330axxxcfaaaaaain
[Model]   pci330axxxcfaaaaaain
Model_type   Input
Polarity   Non-Inverting
Enable   Active-Low
Vinl =   0.9900V
Vinh =   1.6500V
C_comp   4.2000pF   3.8000pF   7.5000pF
[Temperature Range]   25.0000   0.1050k   -40.0000
[Voltage Range]   3.3000V   3.1400V   3.4700V
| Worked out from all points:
|   GND clamp passes 1 mA (typ) near -0.43 V on its own axis
[GND_clamp]
|Voltage   I(typ)   I(min)   I(max)
-3.3V     -955.3mA   -930.3mA   -978mA
-1.2V     -86.21mA   -82.95mA   -94.94mA
-1.15V    -76.76mA   -73.31mA   -85.77mA
-1.1V     -67.73mA   -63.97mA   -77.32mA
-1V       -51.54mA   -46.59mA   -63.26mA
-900mV    -38.9mA    -31.9mA    -51.31mA
-800mV    -28.29mA   -20.61mA   -38.02mA
-700mV    -18.14mA   -11.66mA   -24.86mA
-600mV    -9.315mA   -5.302mA   -13.12mA
-450mV    -1.255mA   -637uA     -1.701mA
0V        0A         0A         0A
6.6V      0A         0A         0A
[POWER_clamp]
|Voltage   I(typ)   I(min)   I(max)
-3.25V    761uA      797.6uA    771.5uA
-3.05V    529.8uA    580.8uA    518.2uA
-2.95V    421.6uA    477.3uA    415.1uA
-2.85V    322.5uA    377.6uA    342uA
-2.65V    184.2uA    200uA      287.1uA
-2.55V    157.9uA    134.1uA    278.6uA
-2.35V    143.1uA    80.64uA    266.6uA
-950mV    110.3uA    55.66uA    208.7uA
2.35V     93.03uA    45.33uA    174uA
2.85V     71.52uA    41.08uA    96.73uA
3.25V     10.85uA    20.74uA    -50.58uA
6.6V      -56.35nA   -1.463uA   -71.55uA
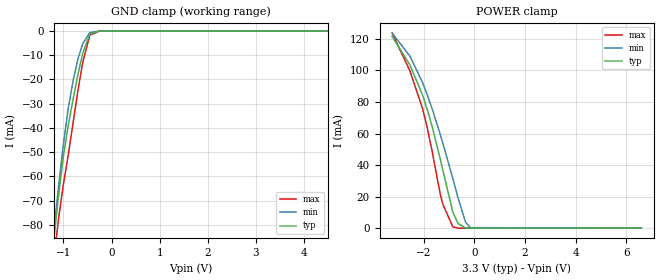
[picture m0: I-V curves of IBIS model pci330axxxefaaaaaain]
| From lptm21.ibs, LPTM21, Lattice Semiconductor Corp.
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|   Model pci330axxxefaaaaaain
[Model]   pci330axxxefaaaaaain
Model_type   Input
Polarity   Non-Inverting
Enable   Active-Low
Vinl =   0.9900V
Vinh =   1.6500V
C_comp   4.2000pF   3.8000pF   7.5000pF
[Temperature Range]   25.0000   0.1050k   -40.0000
[Voltage Range]   3.3000V   3.1400V   3.4700V
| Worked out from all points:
|   GND clamp passes 1 mA (typ) near -0.44 V on its own axis
|   POWER clamp passes 1 mA (typ) near -0.54 V on its own axis
[GND_clamp]
|Voltage   I(typ)   I(min)   I(max)
-3.3V     -955.3mA   -930.3mA   -978mA
-1.2V     -86.18mA   -82.93mA   -94.91mA
-1.15V    -76.73mA   -73.29mA   -85.74mA
-1.1V     -67.71mA   -63.95mA   -77.28mA
-1V       -51.52mA   -46.57mA   -63.21mA
-900mV    -38.87mA   -31.88mA   -51.26mA
-800mV    -28.25mA   -20.58mA   -37.97mA
-700mV    -18.1mA    -11.63mA   -24.81mA
-600mV    -9.267mA   -5.265mA   -13.06mA
-450mV    -1.181mA   -586.6uA   -1.592mA
-250mV    -3.532uA   -4.055uA   -3.003uA
6.6V      0A         0A         0A
[POWER_clamp]
|Voltage   I(typ)   I(min)   I(max)
-3.25V    121.6mA    123.7mA    123.8mA
-2.55V    103.6mA    109.2mA    99.91mA
-2.05V    84.55mA    92.42mA    76.01mA
-1.85V    74.75mA    84.09mA    62.98mA
-1.65V    63.47mA    74.86mA    47.24mA
-1.35V    44.14mA    59.56mA    21.79mA
-1.25V    37.23mA    54.16mA    15.46mA
-850mV    10.22mA    31.49mA    813uA
-650mV    3.122mA    19.66mA    19.66uA
-350mV    37.56uA    3.815mA    1.535uA
-150mV    934.2nA    336.7uA    1.026uA
6.6V      -57.56nA   -49.34nA   -232.5nA
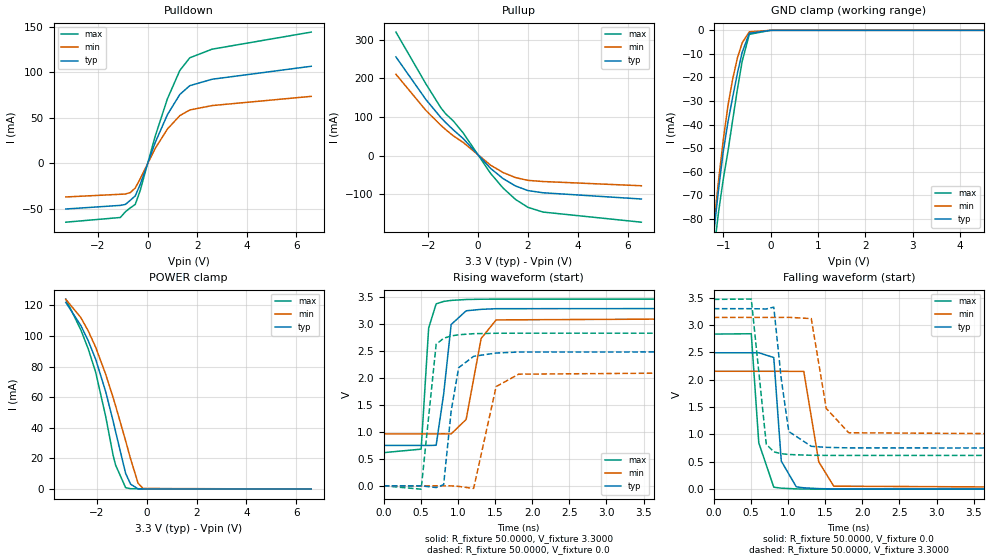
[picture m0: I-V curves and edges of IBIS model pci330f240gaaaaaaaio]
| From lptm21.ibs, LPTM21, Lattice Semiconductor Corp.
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|   Model pci330f240gaaaaaaaio
[Model]   pci330f240gaaaaaaaio
Model_type   I/O
Polarity   Non-Inverting
Enable   Active-Low
Vinl =   0.9900V
Vinh =   1.6500V
Vmeas =   1.5000V
Cref =   10.0000pF
Rref =   25.0000
Vref =   1.5000V
C_comp   4.2000pF   3.8000pF   7.5000pF
[Temperature Range]   25.0000   0.1050k   -40.0000
[Voltage Range]   3.3000V   3.1400V   3.4700V
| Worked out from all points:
|   slope of the pulldown table from 0 to 0.495 V, typ, clamps not added: 13.9 ohm
|   slope of the pullup table from 0 to 0.495 V, typ, clamps not added: 15.1 ohm
|   GND clamp passes 1 mA (typ) near -0.43 V on its own axis
|   POWER clamp passes 1 mA (typ) near -0.53 V on its own axis
|   rising waveform, R_fixture 50.0000, V_fixture 3.3000: 20-80 % time 132ps typ, 176ps min, 76.8ps max; typ from 0.751 V to 3.3 V
|   rising waveform, R_fixture 50.0000, V_fixture 0.0: 20-80 % time 142ps typ, 192ps min, 129ps max; typ from 0 V to 2.49 V
|   falling waveform, R_fixture 50.0000, V_fixture 0.0: 20-80 % time 82.6ps typ, 125ps min, 110ps max; typ from 2.49 V to 0 V
|   falling waveform, R_fixture 50.0000, V_fixture 3.3000: 20-80 % time 139ps typ, 180ps min, 131ps max; typ from 3.3 V to 0.751 V
[Pulldown]
|Voltage   I(typ)   I(min)   I(max)
-3.3V     -50.23mA   -36.97mA   -64.72mA
-1.1V     -46.23mA   -34.01mA   -59.55mA
-900mV    -45.2mA    -33.74mA   -53.38mA
-700mV    -40.7mA    -32.12mA   -48.96mA
-500mV    -35.8mA    -27.15mA   -45.25mA
-300mV    -23.29mA   -17.06mA   -29.97mA
300mV     22.51mA    16.15mA    29.37mA
800mV     53.6mA     37.78mA    71.09mA
1.3V      75.79mA    52.5mA     102.2mA
1.7V      85.44mA    58.7mA     116.1mA
2.6V      92.52mA    63.57mA    125.6mA
6.6V      106.8mA    73.7mA     144.4mA
[Pullup]
|Voltage   I(typ)   I(min)   I(max)
-3.3V     255.1mA    210.3mA    319.3mA
-2.1V     145.3mA    117.1mA    185.8mA
-1.5V     98.65mA    78.52mA    124mA
-1.3V     85.24mA    67.12mA    107.8mA
-1V       66.82mA    51.34mA    89.89mA
-600mV    44.13mA    34.1mA     58.67mA
500mV     -33.03mA   -24.7mA    -45.89mA
1V        -59.27mA   -43.64mA   -83.78mA
1.5V      -78.44mA   -56.74mA   -113.2mA
2V        -90.3mA    -63.94mA   -133.6mA
2.6V      -95.92mA   -66.88mA   -145.8mA
6.55V     -112.1mA   -77.83mA   -172mA
[GND_clamp]
|Voltage   I(typ)   I(min)   I(max)
-3.3V     -955.3mA   -930.3mA   -978mA
-1.2V     -86.21mA   -82.95mA   -94.94mA
-1.15V    -76.76mA   -73.31mA   -85.77mA
-1.1V     -67.73mA   -63.97mA   -77.32mA
-1V       -51.54mA   -46.59mA   -63.26mA
-900mV    -38.9mA    -31.9mA    -51.31mA
-800mV    -28.29mA   -20.61mA   -38.02mA
-700mV    -18.14mA   -11.66mA   -24.86mA
-600mV    -9.315mA   -5.302mA   -13.12mA
-450mV    -1.255mA   -637uA     -1.701mA
0V        0A         0A         0A
6.6V      0A         0A         0A
[POWER_clamp]
|Voltage   I(typ)   I(min)   I(max)
-3.25V    121.9mA    123.9mA    124.1mA
-2.65V    106.9mA    112.1mA    104.1mA
-2.35V    96.95mA    103.3mA    91.59mA
-2.05V    84.73mA    92.58mA    76.25mA
-1.65V    63.65mA    75mA       47.49mA
-1.35V    44.31mA    59.69mA    21.99mA
-1.25V    37.38mA    54.28mA    15.6mA
-850mV    10.32mA    31.58mA    939uA
-650mV    3.193mA    19.74mA    210uA
-350mV    132.1uA    3.862mA    199.7uA
-150mV    104.6uA    375.8uA    197.7uA
6.6V      -56.35nA   -1.463uA   -71.55uA
[Ramp]
| variable   typ   min   max
dV/dt_r  1.1326/0.1412n   0.8926/0.1917n   1.3951/0.1300n
dV/dt_f  1.1655/0.1404n   0.8774/0.1587n   1.4011/0.1327n
R_load = 25.0000
[Rising Waveform]
R_fixture=   50.0000
V_fixture=   3.3000
V_fixture_min=   3.1400
V_fixture_max=   3.4700
|time   V(typ)   V(min)   V(max)
0s        750.6mV    965.3mV    616.8mV
505.1ps   750.7mV    965.3mV    681.5mV
606.1ps   749.6mV    965.3mV    2.931V
707.1ps   753.5mV    965.3mV    3.38V
808.1ps   1.704V     965.7mV    3.425V
909.1ps   2.996V     964.5mV    3.444V
1.111ns   3.251V     1.233V     3.461V
1.313ns   3.278V     2.737V     3.466V
1.515ns   3.29V      3.082V     3.468V
10ns      3.299V     3.139V     3.469V
[Rising Waveform]
R_fixture=   50.0000
V_fixture=   0.0
V_fixture_min=   0.0
V_fixture_max=   0.0
|time   V(typ)   V(min)   V(max)
0s        474nV      645.4nV    441.4nV
505.1ps   939.8nV    388.1nV    -61.85mV
707.1ps   -31.82mV   22.18uV    2.629V
808.1ps   22.39mV    15.99uV    2.741V
909.1ps   1.387V     -277.1uV   2.784V
1.01ns    2.194V     -10.23mV   2.806V
1.212ns   2.406V     -48.44mV   2.826V
1.515ns   2.467V     1.843V     2.834V
1.818ns   2.485V     2.074V     2.835V
10ns      2.493V     2.155V     2.835V
[Falling Waveform]
R_fixture=   50.0000
V_fixture=   0.0
V_fixture_min=   0.0
V_fixture_max=   0.0
|time   V(typ)   V(min)   V(max)
0s        2.493V     2.155V     2.835V
505.1ps   2.493V     2.155V     2.841V
606.1ps   2.494V     2.155V     846.8mV
808.1ps   2.406V     2.155V     36.11mV
909.1ps   513.6mV    2.155V     18.31mV
1.111ns   42.86mV    2.153V     4.852mV
1.212ns   25.16mV    2.154V     2.526mV
1.414ns   10.19mV    500mV      670.4uV
1.616ns   4.031mV    54.58mV    215.5uV
10ns      13.5uV     -3.901uV   13.95uV
[Falling Waveform]
R_fixture=   50.0000
V_fixture=   3.3000
V_fixture_min=   3.1400
V_fixture_max=   3.4700
|time   V(typ)   V(min)   V(max)
0s        3.299V     3.139V     3.469V
505.1ps   3.299V     3.139V     3.475V
707.1ps   3.294V     3.139V     821.7mV
808.1ps   3.327V     3.139V     682.3mV
909.1ps   2.012V     3.139V     648.4mV
1.01ns    1.054V     3.141V     633.5mV
1.313ns   783.5mV    3.118V     619.2mV
1.515ns   764.5mV    1.476V     617.4mV
1.818ns   754.4mV    1.031V     616.9mV
10ns      750.6mV    965.3mV    616.8mV
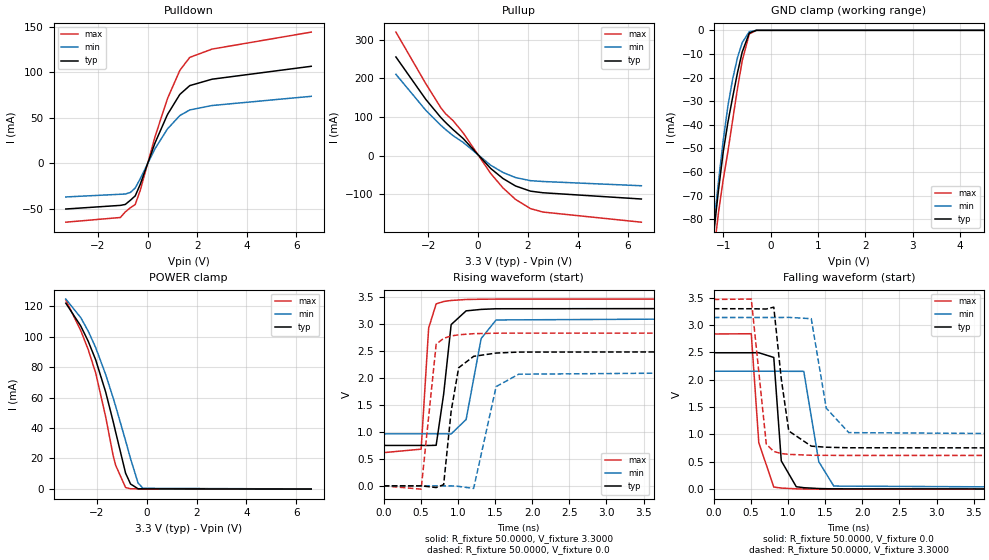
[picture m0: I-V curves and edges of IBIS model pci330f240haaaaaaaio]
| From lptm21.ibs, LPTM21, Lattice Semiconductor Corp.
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|   Model pci330f240haaaaaaaio
[Model]   pci330f240haaaaaaaio
Model_type   I/O
Polarity   Non-Inverting
Enable   Active-Low
Vinl =   0.9900V
Vinh =   1.6500V
Vmeas =   1.5000V
Cref =   10.0000pF
Rref =   25.0000
Vref =   1.5000V
C_comp   4.2000pF   3.8000pF   7.5000pF
[Temperature Range]   25.0000   0.1050k   -40.0000
[Voltage Range]   3.3000V   3.1400V   3.4700V
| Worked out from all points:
|   slope of the pulldown table from 0 to 0.495 V, typ, clamps not added: 13.9 ohm
|   slope of the pullup table from 0 to 0.495 V, typ, clamps not added: 15.1 ohm
|   GND clamp passes 1 mA (typ) near -0.44 V on its own axis
|   POWER clamp passes 1 mA (typ) near -0.53 V on its own axis
|   rising waveform, R_fixture 50.0000, V_fixture 3.3000: 20-80 % time 132ps typ, 176ps min, 76.9ps max; typ from 0.751 V to 3.3 V
|   rising waveform, R_fixture 50.0000, V_fixture 0.0: 20-80 % time 142ps typ, 192ps min, 129ps max; typ from 0 V to 2.5 V
|   falling waveform, R_fixture 50.0000, V_fixture 0.0: 20-80 % time 83.5ps typ, 125ps min, 110ps max; typ from 2.5 V to 0 V
|   falling waveform, R_fixture 50.0000, V_fixture 3.3000: 20-80 % time 140ps typ, 181ps min, 131ps max; typ from 3.3 V to 0.751 V
[Pulldown]
|Voltage   I(typ)   I(min)   I(max)
-3.3V     -50.23mA   -36.97mA   -64.72mA
-1.1V     -46.23mA   -34.01mA   -59.55mA
-900mV    -45.2mA    -33.74mA   -53.38mA
-700mV    -40.7mA    -32.12mA   -48.96mA
-500mV    -35.8mA    -27.15mA   -45.25mA
-300mV    -23.29mA   -17.06mA   -29.97mA
300mV     22.51mA    16.15mA    29.37mA
800mV     53.6mA     37.78mA    71.09mA
1.3V      75.79mA    52.5mA     102.2mA
1.7V      85.44mA    58.7mA     116.5mA
2.6V      92.51mA    63.57mA    125.6mA
6.6V      106.7mA    73.69mA    144.3mA
[Pullup]
|Voltage   I(typ)   I(min)   I(max)
-3.3V     254.9mA    210mA      319.2mA
-2.1V     145.2mA    117.1mA    185.8mA
-1.5V     98.63mA    78.48mA    124mA
-1.3V     85.23mA    67.1mA     107.8mA
-1V       66.82mA    51.33mA    89.91mA
-600mV    44.13mA    34.1mA     58.67mA
500mV     -33.01mA   -24.69mA   -45.84mA
1V        -59.24mA   -43.63mA   -83.72mA
1.5V      -78.42mA   -56.73mA   -113.1mA
2.1V      -91.79mA   -64.71mA   -136.9mA
2.6V      -95.92mA   -66.88mA   -145.8mA
6.55V     -112.1mA   -77.83mA   -172mA
[GND_clamp]
|Voltage   I(typ)   I(min)   I(max)
-3.3V     -955.2mA   -930.2mA   -977.8mA
-1.2V     -86.08mA   -82.87mA   -94.74mA
-1.15V    -76.63mA   -73.22mA   -85.57mA
-1.1V     -67.6mA    -63.89mA   -77.12mA
-1V       -51.41mA   -46.51mA   -63.06mA
-900mV    -38.77mA   -31.82mA   -51.11mA
-800mV    -28.16mA   -20.53mA   -37.82mA
-700mV    -18.01mA   -11.58mA   -24.66mA
-600mV    -9.185mA   -5.219mA   -12.92mA
-450mV    -1.125mA   -553.6uA   -1.501mA
-300mV    0A         0A         0A
6.6V      0A         0A         0A
[POWER_clamp]
|Voltage   I(typ)   I(min)   I(max)
-3.25V    122.1mA    124.8mA    124.2mA
-2.65V    107.1mA    112.6mA    104.1mA
-2.35V    97.06mA    103.7mA    91.56mA
-2.05V    84.81mA    92.86mA    76.2mA
-1.65V    63.69mA    75.19mA    47.4mA
-1.35V    44.32mA    59.82mA    21.89mA
-1.25V    37.38mA    54.39mA    15.53mA
-850mV    10.3mA     31.63mA    860uA
-650mV    3.168mA    19.76mA    65.53uA
-350mV    73.34uA    3.862mA    3.121uA
-150mV    17.77uA    366.8uA    -28.16uA
6.6V      -130.5uA   -83.29uA   -201.6uA
[Ramp]
| variable   typ   min   max
dV/dt_r  1.1341/0.1415n   0.8939/0.1922n   1.3967/0.1302n
dV/dt_f  1.1660/0.1410n   0.8762/0.1589n   1.4017/0.1331n
R_load = 25.0000
[Rising Waveform]
R_fixture=   50.0000
V_fixture=   3.3000
V_fixture_min=   3.1400
V_fixture_max=   3.4700
|time   V(typ)   V(min)   V(max)
0s        750.6mV    965.3mV    616.8mV
505.1ps   750.7mV    965.3mV    681.5mV
606.1ps   749.6mV    965.3mV    2.931V
707.1ps   753.5mV    965.3mV    3.38V
808.1ps   1.704V     965.7mV    3.425V
909.1ps   2.996V     964.5mV    3.444V
1.111ns   3.251V     1.233V     3.462V
1.313ns   3.278V     2.737V     3.467V
1.515ns   3.29V      3.082V     3.469V
10ns      3.3V       3.14V      3.47V
[Rising Waveform]
R_fixture=   50.0000
V_fixture=   0.0
V_fixture_min=   0.0
V_fixture_max=   0.0
|time   V(typ)   V(min)   V(max)
0s        474nV      645.4nV    441.4nV
505.1ps   939.8nV    388.1nV    -61.85mV
707.1ps   -31.82mV   22.18uV    2.629V
808.1ps   22.39mV    15.99uV    2.741V
909.1ps   1.387V     -277.1uV   2.784V
1.01ns    2.194V     -10.23mV   2.806V
1.212ns   2.406V     -48.44mV   2.827V
1.515ns   2.467V     1.843V     2.836V
1.818ns   2.485V     2.074V     2.837V
10ns      2.495V     2.157V     2.838V
[Falling Waveform]
R_fixture=   50.0000
V_fixture=   0.0
V_fixture_min=   0.0
V_fixture_max=   0.0
|time   V(typ)   V(min)   V(max)
0s        2.495V     2.157V     2.838V
505.1ps   2.495V     2.157V     2.843V
606.1ps   2.496V     2.157V     852.2mV
808.1ps   2.409V     2.157V     38.79mV
909.1ps   517.9mV    2.157V     20.04mV
1.111ns   44.69mV    2.155V     6.356mV
1.212ns   26.77mV    2.155V     2.715mV
1.414ns   11.47mV    503.6mV    1.404mV
1.616ns   5.313mV    56.38mV    367.5uV
10ns      9.836uV    24.21uV    -11.05uV
[Falling Waveform]
R_fixture=   50.0000
V_fixture=   3.3000
V_fixture_min=   3.1400
V_fixture_max=   3.4700
|time   V(typ)   V(min)   V(max)
0s        3.3V       3.14V      3.47V
505.1ps   3.3V       3.14V      3.477V
707.1ps   3.295V     3.14V      824.3mV
808.1ps   3.329V     3.14V      689.2mV
909.1ps   2.016V     3.14V      651.6mV
1.01ns    1.064V     3.142V     636.6mV
1.313ns   786.8mV    3.118V     619.9mV
1.515ns   767.1mV    1.481V     618.5mV
1.818ns   757.2mV    1.034V     617mV
10ns      750.6mV    965.3mV    616.8mV
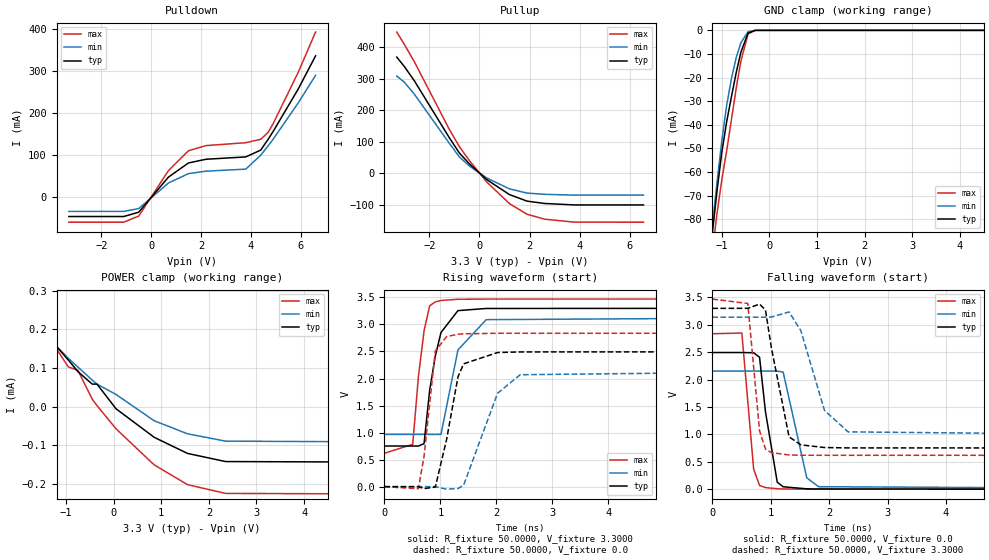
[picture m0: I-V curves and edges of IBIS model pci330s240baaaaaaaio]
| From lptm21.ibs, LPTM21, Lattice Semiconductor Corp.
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|   Model pci330s240baaaaaaaio
[Model]   pci330s240baaaaaaaio
Model_type   I/O
Polarity   Non-Inverting
Enable   Active-Low
Vinl =   0.9900V
Vinh =   1.6500V
Vmeas =   1.5000V
Cref =   10.0000pF
Rref =   25.0000
Vref =   1.5000V
C_comp   4.2000pF   3.8000pF   7.5000pF
[Temperature Range]   25.0000   0.1050k   -40.0000
[Voltage Range]   3.3000V   3.1400V   3.4700V
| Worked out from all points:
|   slope of the pulldown table from 0 to 0.495 V, typ, clamps not added: 13.9 ohm
|   slope of the pullup table from 0 to 0.495 V, typ, clamps not added: 15.2 ohm
|   GND clamp passes 1 mA (typ) near -0.44 V on its own axis
|   rising waveform, R_fixture 50.0000, V_fixture 3.3000: 20-80 % time 241ps typ, 285ps min, 173ps max; typ from 0.752 V to 3.3 V
|   rising waveform, R_fixture 50.0000, V_fixture 0.0: 20-80 % time 262ps typ, 413ps min, 170ps max; typ from 0 V to 2.49 V
|   falling waveform, R_fixture 50.0000, V_fixture 0.0: 20-80 % time 158ps typ, 236ps min, 124ps max; typ from 2.49 V to 0 V
|   falling waveform, R_fixture 50.0000, V_fixture 3.3000: 20-80 % time 230ps typ, 378ps min, 152ps max; typ from 3.3 V to 0.752 V
[Pulldown]
|Voltage   I(typ)   I(min)   I(max)
-3.3V     -46.01mA   -33.71mA   -59.5mA
-1.1V     -46.01mA   -33.71mA   -59.5mA
-500mV    -35.7mA    -27.08mA   -45.1mA
700mV     48.2mA     34.09mA    63.77mA
1.5V      81.7mA     56.28mA    110.8mA
2.2V      90.52mA    62.13mA    123.1mA
3.8V      96.15mA    67.01mA    130mA
4.4V      112.4mA    100.3mA    138.2mA
4.7V      138.4mA    122.8mA    154.9mA
4.9V      157.1mA    138.5mA    175.8mA
5.9V      257.6mA    224.5mA    297.4mA
6.6V      337.1mA    290.6mA    393.7mA
[Pullup]
|Voltage   I(typ)   I(min)   I(max)
-3.3V     368.5mA    308.2mA    447.9mA
-3V       338.8mA    289mA      409.1mA
-2.6V     293.6mA    251.1mA    353.9mA
-1.2V     112.4mA    94.81mA    138.9mA
-800mV    64.2mA     51.98mA    84.48mA
-400mV    29.85mA    22.98mA    40.24mA
300mV     -20.58mA   -15.48mA   -28.4mA
1.2V      -67.69mA   -49.52mA   -96.41mA
1.9V      -88.38mA   -62.88mA   -130mA
2.6V      -95.78mA   -66.79mA   -145.6mA
3.8V      -100.4mA   -69.3mA    -155.1mA
6.55V     -100.4mA   -69.3mA    -155.2mA
[GND_clamp]
|Voltage   I(typ)   I(min)   I(max)
-3.3V     -955.2mA   -930.2mA   -977.8mA
-1.2V     -86.07mA   -82.87mA   -94.72mA
-1.15V    -76.63mA   -73.23mA   -85.56mA
-1.1V     -67.6mA    -63.89mA   -77.1mA
-1V       -51.41mA   -46.51mA   -63.05mA
-900mV    -38.77mA   -31.83mA   -51.09mA
-800mV    -28.16mA   -20.53mA   -37.81mA
-700mV    -18.01mA   -11.59mA   -24.66mA
-600mV    -9.192mA   -5.229mA   -12.92mA
-450mV    -1.151mA   -576.6uA   -1.527mA
-300mV    -17.4uA    -15.66uA   -11.6uA
6.6V      0A         0A         0A
[POWER_clamp]
|Voltage   I(typ)   I(min)   I(max)
-3.25V    961.3uA    1.05mA     917.9uA
-2.25V    305.8uA    299.5uA    344.1uA
-1.95V    260.5uA    253.4uA    288.8uA
-950mV    120.7uA    124.7uA    102.8uA
-750mV    90.82uA    102.7uA    94.17uA
-450mV    58.57uA    68.87uA    19.46uA
-350mV    58.57uA    58.54uA    3.121uA
50mV      -5.338uA   31.71uA    -57.16uA
850mV     -79.07uA   -36.24uA   -150.4uA
1.55V     -120.8uA   -70.05uA   -201.6uA
2.35V     -141.9uA   -89.06uA   -224.3uA
6.6V      -143.8uA   -91.66uA   -226.3uA
[Ramp]
| variable   typ   min   max
dV/dt_r  1.1333/0.3032n   0.8931/0.4806n   1.3960/0.1862n
dV/dt_f  1.1652/0.2913n   0.8771/0.4464n   1.4008/0.1868n
R_load = 25.0000
[Rising Waveform]
R_fixture=   50.0000
V_fixture=   3.3000
V_fixture_min=   3.1400
V_fixture_max=   3.4700
|time   V(typ)   V(min)   V(max)
0s        751.6mV    966.1mV    618mV
505.1ps   751.7mV    966.1mV    782.9mV
606.1ps   750.5mV    966.1mV    2.026V
707.1ps   795mV      966.1mV    2.88V
808.1ps   1.786V     966.4mV    3.346V
909.1ps   2.419V     965.5mV    3.418V
1.01ns    2.851V     968.1mV    3.444V
1.313ns   3.256V     2.529V     3.466V
1.818ns   3.296V     3.089V     3.47V
10ns      3.3V       3.14V      3.47V
[Rising Waveform]
R_fixture=   50.0000
V_fixture=   0.0
V_fixture_min=   0.0
V_fixture_max=   0.0
|time   V(typ)   V(min)   V(max)
0s        484.9nV    653.8nV    458.4nV
606.1ps   -928.3uV   2.015uV    -38.81mV
707.1ps   -36.03mV   19.4uV     559mV
909.1ps   -7.501mV   -591.8uV   2.51V
1.111ns   876.5mV    -46.71mV   2.776V
1.313ns   2.029V     -34.83mV   2.819V
1.414ns   2.272V     25.73mV    2.827V
2.02ns    2.481V     1.727V     2.837V
2.424ns   2.492V     2.07V      2.837V
10ns      2.494V     2.156V     2.837V
[Falling Waveform]
R_fixture=   50.0000
V_fixture=   0.0
V_fixture_min=   0.0
V_fixture_max=   0.0
|time   V(typ)   V(min)   V(max)
0s        2.494V     2.156V     2.837V
505.1ps   2.494V     2.156V     2.85V
707.1ps   2.49V      2.156V     363.7mV
808.1ps   2.407V     2.156V     67.81mV
909.1ps   1.413V     2.156V     29.42mV
1.111ns   126.2mV    2.154V     7.547mV
1.212ns   43.67mV    2.138V     3.842mV
1.616ns   6.181mV    206.6mV    298.8uV
1.818ns   2.479mV    45.08mV    130.9uV
10ns      15.78uV    3.22uV     5.067uV
[Falling Waveform]
R_fixture=   50.0000
V_fixture=   3.3000
V_fixture_min=   3.1400
V_fixture_max=   3.4700
|time   V(typ)   V(min)   V(max)
0s        3.3V       3.14V      3.47V
606.1ps   3.301V     3.14V      3.389V
808.1ps   3.378V     3.14V      1.064V
909.1ps   3.27V      3.14V      731.6mV
1.01ns    2.584V     3.142V     666.6mV
1.313ns   955.6mV    3.235V     624.4mV
1.515ns   808.3mV    2.893V     619.6mV
1.919ns   760.1mV    1.439V     618.1mV
2.323ns   753.1mV    1.046V     618mV
10ns      751.6mV    966.1mV    618mV
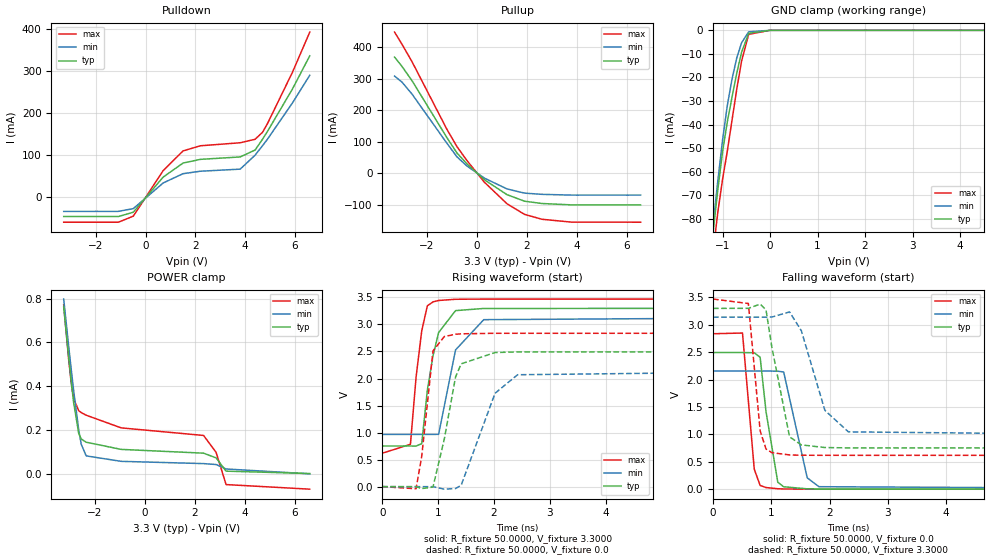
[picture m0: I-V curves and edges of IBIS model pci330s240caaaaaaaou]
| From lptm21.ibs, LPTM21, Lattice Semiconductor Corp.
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|   Model pci330s240caaaaaaaou
[Model]   pci330s240caaaaaaaou
Model_type   Output
Polarity   Non-Inverting
Enable   Active-Low
Vmeas =   1.5000V
Cref =   10.0000pF
Rref =   25.0000
Vref =   1.5000V
C_comp   4.2000pF   3.8000pF   7.5000pF
[Temperature Range]   25.0000   0.1050k   -40.0000
[Voltage Range]   3.3000V   3.1400V   3.4700V
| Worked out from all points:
|   slope of the pulldown table from 0 to 0.495 V, typ, clamps not added: 13.9 ohm
|   slope of the pullup table from 0 to 0.495 V, typ, clamps not added: 15.1 ohm
|   GND clamp passes 1 mA (typ) near -0.43 V on its own axis
|   rising waveform, R_fixture 50.0000, V_fixture 3.3000: 20-80 % time 241ps typ, 285ps min, 173ps max; typ from 0.752 V to 3.3 V
|   rising waveform, R_fixture 50.0000, V_fixture 0.0: 20-80 % time 262ps typ, 413ps min, 170ps max; typ from 0 V to 2.49 V
|   falling waveform, R_fixture 50.0000, V_fixture 0.0: 20-80 % time 158ps typ, 236ps min, 124ps max; typ from 2.49 V to 0 V
|   falling waveform, R_fixture 50.0000, V_fixture 3.3000: 20-80 % time 230ps typ, 378ps min, 152ps max; typ from 3.3 V to 0.752 V
[Pulldown]
|Voltage   I(typ)   I(min)   I(max)
-3.3V     -46.02mA   -33.72mA   -59.51mA
-1.1V     -46.02mA   -33.72mA   -59.51mA
-500mV    -35.74mA   -27.1mA    -45.14mA
700mV     47.97mA    33.96mA    63.38mA
1.5V      81.47mA    56.15mA    110.4mA
2.2V      90.32mA    62.03mA    122.7mA
3.8V      96.1mA     67.01mA    129.9mA
4.4V      112.5mA    100.3mA    138.2mA
4.7V      138.4mA    122.9mA    154.9mA
4.9V      157.2mA    138.6mA    175.8mA
5.9V      257.8mA    224.7mA    297.6mA
6.6V      337.3mA    290.9mA    393.8mA
[Pullup]
|Voltage   I(typ)   I(min)   I(max)
-3.3V     368.7mA    308.4mA    448.1mA
-3V       338.9mA    289.2mA    409.2mA
-2.6V     293.8mA    251.3mA    354.1mA
-1.2V     112.5mA    94.87mA    138.9mA
-800mV    64.19mA    52mA       84.41mA
-400mV    29.8mA     22.96mA    40.12mA
300mV     -20.72mA   -15.55mA   -28.64mA
1.2V      -67.89mA   -49.63mA   -96.76mA
1.9V      -88.61mA   -63.01mA   -130.4mA
2.6V      -96.01mA   -66.92mA   -146mA
3.8V      -100.4mA   -69.35mA   -155.2mA
6.55V     -100.4mA   -69.35mA   -155.3mA
[GND_clamp]
|Voltage   I(typ)   I(min)   I(max)
-3.3V     -955.3mA   -930.3mA   -978mA
-1.2V     -86.21mA   -82.95mA   -94.94mA
-1.15V    -76.76mA   -73.31mA   -85.77mA
-1.1V     -67.73mA   -63.97mA   -77.32mA
-1V       -51.54mA   -46.59mA   -63.26mA
-900mV    -38.9mA    -31.9mA    -51.31mA
-800mV    -28.29mA   -20.61mA   -38.02mA
-700mV    -18.14mA   -11.66mA   -24.86mA
-600mV    -9.315mA   -5.302mA   -13.12mA
-450mV    -1.255mA   -637uA     -1.701mA
0V        0A         0A         0A
6.6V      0A         0A         0A
[POWER_clamp]
|Voltage   I(typ)   I(min)   I(max)
-3.25V    761uA      797.6uA    771.5uA
-3.05V    529.8uA    580.8uA    518.2uA
-2.95V    421.6uA    477.3uA    415.1uA
-2.85V    322.5uA    377.6uA    342uA
-2.65V    184.2uA    200uA      287.1uA
-2.55V    157.9uA    134.1uA    278.6uA
-2.35V    143.1uA    80.64uA    266.6uA
-950mV    110.3uA    55.66uA    208.7uA
2.35V     93.03uA    45.33uA    174uA
2.85V     71.52uA    41.08uA    96.73uA
3.25V     10.85uA    20.74uA    -50.58uA
6.6V      -56.35nA   -1.463uA   -71.55uA
[Ramp]
| variable   typ   min   max
dV/dt_r  1.1333/0.3032n   0.8931/0.4806n   1.3960/0.1862n
dV/dt_f  1.1652/0.2913n   0.8771/0.4464n   1.4008/0.1868n
R_load = 25.0000
[Rising Waveform]
R_fixture=   50.0000
V_fixture=   3.3000
V_fixture_min=   3.1400
V_fixture_max=   3.4700
|time   V(typ)   V(min)   V(max)
0s        751.6mV    966.1mV    618mV
505.1ps   751.7mV    966.1mV    782.9mV
606.1ps   750.5mV    966.1mV    2.026V
707.1ps   795mV      966.1mV    2.88V
808.1ps   1.786V     966.4mV    3.346V
909.1ps   2.419V     965.5mV    3.418V
1.01ns    2.851V     968.1mV    3.444V
1.313ns   3.256V     2.529V     3.466V
1.818ns   3.296V     3.089V     3.47V
10ns      3.3V       3.14V      3.47V
[Rising Waveform]
R_fixture=   50.0000
V_fixture=   0.0
V_fixture_min=   0.0
V_fixture_max=   0.0
|time   V(typ)   V(min)   V(max)
0s        484.9nV    653.8nV    458.4nV
606.1ps   -928.3uV   2.015uV    -38.81mV
707.1ps   -36.03mV   19.4uV     559mV
909.1ps   -7.501mV   -591.8uV   2.51V
1.111ns   876.5mV    -46.71mV   2.776V
1.313ns   2.029V     -34.83mV   2.819V
1.414ns   2.272V     25.73mV    2.827V
2.02ns    2.481V     1.727V     2.837V
2.424ns   2.492V     2.07V      2.837V
10ns      2.494V     2.156V     2.837V
[Falling Waveform]
R_fixture=   50.0000
V_fixture=   0.0
V_fixture_min=   0.0
V_fixture_max=   0.0
|time   V(typ)   V(min)   V(max)
0s        2.494V     2.156V     2.837V
505.1ps   2.494V     2.156V     2.85V
707.1ps   2.49V      2.156V     363.7mV
808.1ps   2.407V     2.156V     67.81mV
909.1ps   1.413V     2.156V     29.42mV
1.111ns   126.2mV    2.154V     7.547mV
1.212ns   43.67mV    2.138V     3.842mV
1.616ns   6.181mV    206.6mV    298.8uV
1.818ns   2.479mV    45.08mV    130.9uV
10ns      15.78uV    3.22uV     5.067uV
[Falling Waveform]
R_fixture=   50.0000
V_fixture=   3.3000
V_fixture_min=   3.1400
V_fixture_max=   3.4700
|time   V(typ)   V(min)   V(max)
0s        3.3V       3.14V      3.47V
606.1ps   3.301V     3.14V      3.389V
808.1ps   3.378V     3.14V      1.064V
909.1ps   3.27V      3.14V      731.6mV
1.01ns    2.584V     3.142V     666.6mV
1.313ns   955.6mV    3.235V     624.4mV
1.515ns   808.3mV    2.893V     619.6mV
1.919ns   760.1mV    1.439V     618.1mV
2.323ns   753.1mV    1.046V     618mV
10ns      751.6mV    966.1mV    618mV
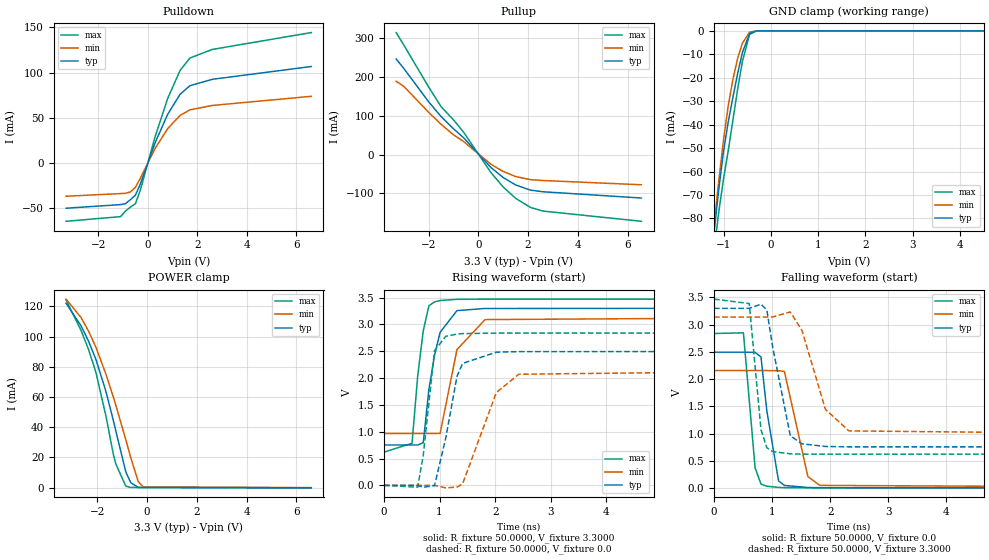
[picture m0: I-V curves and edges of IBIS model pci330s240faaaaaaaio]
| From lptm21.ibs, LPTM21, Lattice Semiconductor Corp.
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|   Model pci330s240faaaaaaaio
[Model]   pci330s240faaaaaaaio
Model_type   I/O
Polarity   Non-Inverting
Enable   Active-Low
Vinl =   0.9900V
Vinh =   1.6500V
Vmeas =   1.5000V
Cref =   10.0000pF
Rref =   25.0000
Vref =   1.5000V
C_comp   4.2000pF   3.8000pF   7.5000pF
[Temperature Range]   25.0000   0.1050k   -40.0000
[Voltage Range]   3.3000V   3.1400V   3.4700V
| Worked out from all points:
|   slope of the pulldown table from 0 to 0.495 V, typ, clamps not added: 13.9 ohm
|   slope of the pullup table from 0 to 0.495 V, typ, clamps not added: 15.1 ohm
|   GND clamp passes 1 mA (typ) near -0.44 V on its own axis
|   POWER clamp passes 1 mA (typ) near -0.53 V on its own axis
|   rising waveform, R_fixture 50.0000, V_fixture 3.3000: 20-80 % time 241ps typ, 285ps min, 173ps max; typ from 0.753 V to 3.3 V
|   rising waveform, R_fixture 50.0000, V_fixture 0.0: 20-80 % time 262ps typ, 413ps min, 170ps max; typ from 0.001 V to 2.5 V
|   falling waveform, R_fixture 50.0000, V_fixture 0.0: 20-80 % time 158ps typ, 236ps min, 124ps max; typ from 2.5 V to 0.001 V
|   falling waveform, R_fixture 50.0000, V_fixture 3.3000: 20-80 % time 231ps typ, 379ps min, 152ps max; typ from 3.3 V to 0.753 V
[Pulldown]
|Voltage   I(typ)   I(min)   I(max)
-3.3V     -50.23mA   -36.97mA   -64.72mA
-1.1V     -46.24mA   -34.01mA   -59.55mA
-900mV    -45.2mA    -33.74mA   -53.38mA
-700mV    -40.71mA   -32.12mA   -48.97mA
-500mV    -35.81mA   -27.15mA   -45.26mA
-300mV    -23.29mA   -17.06mA   -29.97mA
300mV     22.54mA    16.16mA    29.45mA
800mV     53.62mA    37.8mA     71.16mA
1.3V      75.81mA    52.5mA     102.2mA
1.7V      85.44mA    58.7mA     116.1mA
2.6V      92.51mA    63.57mA    125.6mA
6.6V      106.7mA    73.69mA    144.3mA
[Pullup]
|Voltage   I(typ)   I(min)   I(max)
-3.3V     246.7mA    189.4mA    315.2mA
-3V       223.1mA    176.6mA    283.6mA
-2V       136.6mA    109.5mA    175mA
-1.5V     98.63mA    78.47mA    124mA
-1V       66.82mA    51.33mA    89.91mA
-600mV    44.13mA    34.1mA     58.67mA
500mV     -33.01mA   -24.69mA   -45.84mA
1V        -59.24mA   -43.63mA   -83.72mA
1.5V      -78.42mA   -56.73mA   -113.1mA
2.1V      -91.78mA   -64.71mA   -136.5mA
2.6V      -95.92mA   -66.88mA   -145.8mA
6.55V     -112.1mA   -77.85mA   -172.2mA
[GND_clamp]
|Voltage   I(typ)   I(min)   I(max)
-3.3V     -955.2mA   -930.2mA   -977.8mA
-1.2V     -86.07mA   -82.87mA   -94.72mA
-1.15V    -76.63mA   -73.23mA   -85.56mA
-1.1V     -67.6mA    -63.89mA   -77.1mA
-1V       -51.41mA   -46.51mA   -63.05mA
-900mV    -38.77mA   -31.83mA   -51.09mA
-800mV    -28.16mA   -20.53mA   -37.81mA
-700mV    -18.01mA   -11.59mA   -24.66mA
-600mV    -9.192mA   -5.229mA   -12.92mA
-450mV    -1.151mA   -576.6uA   -1.527mA
-300mV    -17.4uA    -15.66uA   -11.6uA
6.6V      0A         0A         0A
[POWER_clamp]
|Voltage   I(typ)   I(min)   I(max)
-3.25V    122.1mA    124.8mA    124.2mA
-2.65V    107.1mA    112.6mA    104.1mA
-2.35V    97.06mA    103.7mA    91.56mA
-2.05V    84.81mA    92.86mA    76.2mA
-1.65V    63.69mA    75.19mA    47.4mA
-1.35V    44.32mA    59.82mA    21.89mA
-1.25V    37.38mA    54.39mA    15.53mA
-850mV    10.3mA     31.63mA    860uA
-650mV    3.168mA    19.76mA    65.53uA
-350mV    73.34uA    3.862mA    3.121uA
-150mV    17.77uA    366.8uA    -28.16uA
6.6V      -143.8uA   -91.66uA   -226.3uA
[Ramp]
| variable   typ   min   max
dV/dt_r  1.1335/0.3033n   0.8934/0.4808n   1.3960/0.1865n
dV/dt_f  1.1641/0.2919n   0.8762/0.4469n   1.3996/0.1875n
R_load = 25.0000
[Rising Waveform]
R_fixture=   50.0000
V_fixture=   3.3000
V_fixture_min=   3.1400
V_fixture_max=   3.4700
|time   V(typ)   V(min)   V(max)
0s        753.3mV    967.7mV    619.8mV
505.1ps   753.4mV    967.7mV    786.1mV
606.1ps   752.2mV    967.7mV    2.032V
707.1ps   797mV      967.7mV    2.884V
808.1ps   1.79V      968mV      3.346V
909.1ps   2.422V     967.1mV    3.418V
1.01ns    2.853V     969.8mV    3.444V
1.313ns   3.256V     2.531V     3.466V
1.818ns   3.296V     3.089V     3.47V
10ns      3.3V       3.14V      3.47V
[Rising Waveform]
R_fixture=   50.0000
V_fixture=   0.0
V_fixture_min=   0.0
V_fixture_max=   0.0
|time   V(typ)   V(min)   V(max)
0s        1.212mV    1.044mV    1.456mV
606.1ps   284.8uV    1.045mV    -33.23mV
707.1ps   -34.73mV   1.063mV    566.4mV
909.1ps   -2.966mV   452.7uV    2.51V
1.111ns   882.2mV    -45.36mV   2.777V
1.313ns   2.032V     -31.66mV   2.82V
1.414ns   2.273V     29.37mV    2.828V
2.02ns    2.482V     1.729V     2.837V
2.424ns   2.492V     2.071V     2.837V
10ns      2.495V     2.157V     2.838V
[Falling Waveform]
R_fixture=   50.0000
V_fixture=   0.0
V_fixture_min=   0.0
V_fixture_max=   0.0
|time   V(typ)   V(min)   V(max)
0s        2.495V     2.157V     2.838V
505.1ps   2.495V     2.157V     2.851V
707.1ps   2.491V     2.157V     368.2mV
808.1ps   2.408V     2.157V     70.48mV
909.1ps   1.416V     2.157V     31.08mV
1.111ns   129mV      2.155V     8.985mV
1.212ns   45.71mV    2.139V     5.332mV
1.616ns   7.492mV    209.6mV    1.753mV
1.818ns   3.68mV     46.55mV    1.584mV
10ns      1.224mV    1.031mV    1.457mV
[Falling Waveform]
R_fixture=   50.0000
V_fixture=   3.3000
V_fixture_min=   3.1400
V_fixture_max=   3.4700
|time   V(typ)   V(min)   V(max)
0s        3.3V       3.14V      3.47V
606.1ps   3.301V     3.14V      3.389V
808.1ps   3.378V     3.14V      1.072V
909.1ps   3.27V      3.14V      737.6mV
1.01ns    2.585V     3.142V     668.5mV
1.313ns   958.5mV    3.235V     626.2mV
1.515ns   810.3mV    2.893V     621.5mV
1.919ns   762mV      1.442V     620mV
2.323ns   754.8mV    1.048V     619.9mV
10ns      753.3mV    967.8mV    619.8mV
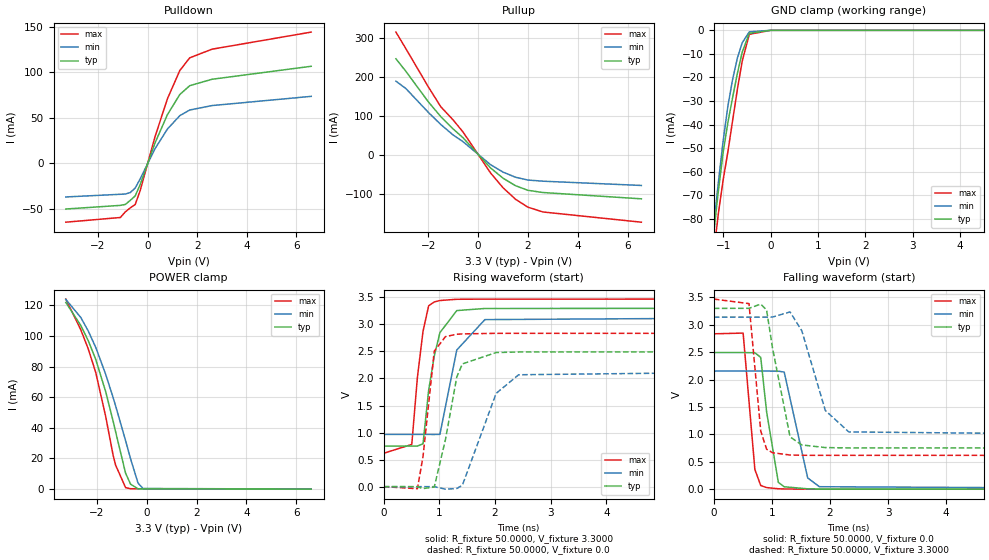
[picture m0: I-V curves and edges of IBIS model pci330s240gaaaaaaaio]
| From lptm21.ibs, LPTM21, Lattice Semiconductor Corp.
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|   Model pci330s240gaaaaaaaio
[Model]   pci330s240gaaaaaaaio
Model_type   I/O
Polarity   Non-Inverting
Enable   Active-Low
Vinl =   0.9900V
Vinh =   1.6500V
Vmeas =   1.5000V
Cref =   10.0000pF
Rref =   25.0000
Vref =   1.5000V
C_comp   4.2000pF   3.8000pF   7.5000pF
[Temperature Range]   25.0000   0.1050k   -40.0000
[Voltage Range]   3.3000V   3.1400V   3.4700V
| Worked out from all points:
|   slope of the pulldown table from 0 to 0.495 V, typ, clamps not added: 13.9 ohm
|   slope of the pullup table from 0 to 0.495 V, typ, clamps not added: 15.1 ohm
|   GND clamp passes 1 mA (typ) near -0.43 V on its own axis
|   POWER clamp passes 1 mA (typ) near -0.53 V on its own axis
|   rising waveform, R_fixture 50.0000, V_fixture 3.3000: 20-80 % time 242ps typ, 286ps min, 174ps max; typ from 0.751 V to 3.3 V
|   rising waveform, R_fixture 50.0000, V_fixture 0.0: 20-80 % time 262ps typ, 413ps min, 170ps max; typ from 0 V to 2.49 V
|   falling waveform, R_fixture 50.0000, V_fixture 0.0: 20-80 % time 158ps typ, 235ps min, 124ps max; typ from 2.49 V to 0 V
|   falling waveform, R_fixture 50.0000, V_fixture 3.3000: 20-80 % time 230ps typ, 378ps min, 152ps max; typ from 3.3 V to 0.751 V
[Pulldown]
|Voltage   I(typ)   I(min)   I(max)
-3.3V     -50.23mA   -36.97mA   -64.72mA
-1.1V     -46.23mA   -34.01mA   -59.55mA
-900mV    -45.2mA    -33.74mA   -53.38mA
-700mV    -40.7mA    -32.12mA   -48.96mA
-500mV    -35.8mA    -27.15mA   -45.25mA
-300mV    -23.29mA   -17.06mA   -29.97mA
300mV     22.51mA    16.15mA    29.37mA
800mV     53.6mA     37.78mA    71.09mA
1.3V      75.79mA    52.5mA     102.2mA
1.7V      85.44mA    58.7mA     116.1mA
2.6V      92.52mA    63.57mA    125.6mA
6.6V      106.8mA    73.7mA     144.4mA
[Pullup]
|Voltage   I(typ)   I(min)   I(max)
-3.3V     246.9mA    189.6mA    315.4mA
-2.9V     214.8mA    170.6mA    272.8mA
-2V       136.6mA    109.6mA    175mA
-1.5V     98.65mA    78.51mA    124mA
-1V       66.82mA    51.34mA    89.89mA
-600mV    44.13mA    34.1mA     58.67mA
500mV     -33.03mA   -24.7mA    -45.89mA
1V        -59.27mA   -43.64mA   -83.78mA
1.5V      -78.44mA   -56.74mA   -113.2mA
2V        -90.3mA    -63.94mA   -133.6mA
2.6V      -95.92mA   -66.87mA   -145.8mA
6.55V     -112.1mA   -77.83mA   -172mA
[GND_clamp]
|Voltage   I(typ)   I(min)   I(max)
-3.3V     -955.3mA   -930.3mA   -978mA
-1.2V     -86.21mA   -82.95mA   -94.94mA
-1.15V    -76.76mA   -73.31mA   -85.77mA
-1.1V     -67.73mA   -63.97mA   -77.32mA
-1V       -51.54mA   -46.59mA   -63.26mA
-900mV    -38.9mA    -31.9mA    -51.31mA
-800mV    -28.29mA   -20.61mA   -38.02mA
-700mV    -18.14mA   -11.66mA   -24.86mA
-600mV    -9.315mA   -5.302mA   -13.12mA
-450mV    -1.255mA   -637uA     -1.701mA
0V        0A         0A         0A
6.6V      0A         0A         0A
[POWER_clamp]
|Voltage   I(typ)   I(min)   I(max)
-3.25V    121.9mA    123.9mA    124.1mA
-2.65V    106.9mA    112.1mA    104.1mA
-2.35V    96.95mA    103.3mA    91.59mA
-2.05V    84.73mA    92.58mA    76.25mA
-1.65V    63.65mA    75mA       47.49mA
-1.35V    44.31mA    59.69mA    21.99mA
-1.25V    37.38mA    54.28mA    15.6mA
-850mV    10.32mA    31.58mA    939uA
-650mV    3.193mA    19.74mA    210uA
-350mV    132.1uA    3.862mA    199.7uA
-150mV    104.6uA    375.8uA    197.7uA
6.6V      -56.35nA   -1.463uA   -71.55uA
[Ramp]
| variable   typ   min   max
dV/dt_r  1.1326/0.3034n   0.8926/0.4808n   1.3951/0.1863n
dV/dt_f  1.1655/0.2912n   0.8774/0.4464n   1.4011/0.1866n
R_load = 25.0000
[Rising Waveform]
R_fixture=   50.0000
V_fixture=   3.3000
V_fixture_min=   3.1400
V_fixture_max=   3.4700
|time   V(typ)   V(min)   V(max)
0s        750.6mV    965.3mV    616.8mV
505.1ps   750.7mV    965.3mV    780.9mV
606.1ps   749.5mV    965.3mV    2.02V
707.1ps   793.7mV    965.3mV    2.874V
808.1ps   1.783V     965.6mV    3.345V
909.1ps   2.416V     964.7mV    3.416V
1.01ns    2.847V     967.3mV    3.442V
1.313ns   3.256V     2.527V     3.465V
1.818ns   3.295V     3.089V     3.468V
10ns      3.299V     3.139V     3.469V
[Rising Waveform]
R_fixture=   50.0000
V_fixture=   0.0
V_fixture_min=   0.0
V_fixture_max=   0.0
|time   V(typ)   V(min)   V(max)
0s        474nV      645.4nV    441.4nV
606.1ps   -927.7uV   2.006uV    -38.37mV
707.1ps   -36.01mV   19.39uV    558.7mV
909.1ps   -7.211mV   -591.5uV   2.507V
1.111ns   875.6mV    -46.68mV   2.775V
1.313ns   2.027V     -34.65mV   2.818V
1.414ns   2.27V      25.88mV    2.825V
2.02ns    2.48V      1.725V     2.835V
2.424ns   2.49V      2.069V     2.835V
10ns      2.493V     2.155V     2.835V
[Falling Waveform]
R_fixture=   50.0000
V_fixture=   0.0
V_fixture_min=   0.0
V_fixture_max=   0.0
|time   V(typ)   V(min)   V(max)
0s        2.493V     2.155V     2.835V
505.1ps   2.493V     2.155V     2.848V
707.1ps   2.489V     2.155V     360.4mV
808.1ps   2.405V     2.155V     66.53mV
909.1ps   1.41V      2.155V     29mV
1.111ns   124.5mV    2.153V     7.373mV
1.212ns   43.68mV    2.137V     3.764mV
1.616ns   6.133mV    205.5mV    298.4uV
1.818ns   2.455mV    44.8mV     131.4uV
10ns      4.316uV    8.884uV    -1.604uV
[Falling Waveform]
R_fixture=   50.0000
V_fixture=   3.3000
V_fixture_min=   3.1400
V_fixture_max=   3.4700
|time   V(typ)   V(min)   V(max)
0s        3.299V     3.139V     3.469V
606.1ps   3.3V       3.139V     3.386V
808.1ps   3.377V     3.139V     1.06V
909.1ps   3.268V     3.139V     730.4mV
1.01ns    2.58V      3.141V     664.8mV
1.313ns   953.7mV    3.234V     622.9mV
1.515ns   807.1mV    2.891V     618.4mV
1.919ns   759.1mV    1.437V     616.9mV
2.323ns   752.1mV    1.045V     616.8mV
10ns      750.6mV    965.3mV    616.7mV
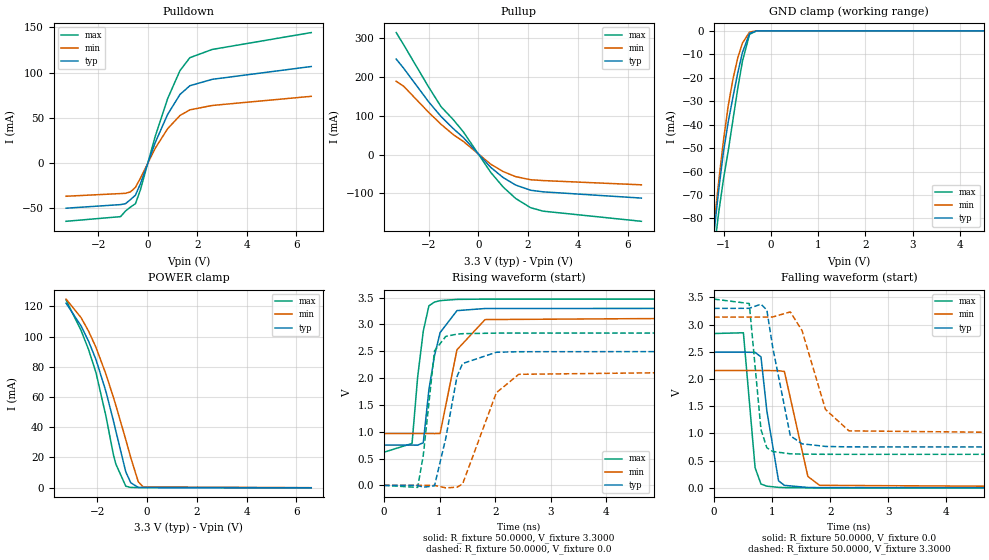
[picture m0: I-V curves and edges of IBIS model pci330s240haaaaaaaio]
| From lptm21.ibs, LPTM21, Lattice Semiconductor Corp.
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|   Model pci330s240haaaaaaaio
[Model]   pci330s240haaaaaaaio
Model_type   I/O
Polarity   Non-Inverting
Enable   Active-Low
Vinl =   0.9900V
Vinh =   1.6500V
Vmeas =   1.5000V
Cref =   10.0000pF
Rref =   25.0000
Vref =   1.5000V
C_comp   4.2000pF   3.8000pF   7.5000pF
[Temperature Range]   25.0000   0.1050k   -40.0000
[Voltage Range]   3.3000V   3.1400V   3.4700V
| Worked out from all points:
|   slope of the pulldown table from 0 to 0.495 V, typ, clamps not added: 13.9 ohm
|   slope of the pullup table from 0 to 0.495 V, typ, clamps not added: 15.1 ohm
|   GND clamp passes 1 mA (typ) near -0.44 V on its own axis
|   POWER clamp passes 1 mA (typ) near -0.53 V on its own axis
|   rising waveform, R_fixture 50.0000, V_fixture 3.3000: 20-80 % time 242ps typ, 286ps min, 174ps max; typ from 0.751 V to 3.3 V
|   rising waveform, R_fixture 50.0000, V_fixture 0.0: 20-80 % time 262ps typ, 414ps min, 170ps max; typ from 0 V to 2.5 V
|   falling waveform, R_fixture 50.0000, V_fixture 0.0: 20-80 % time 158ps typ, 236ps min, 124ps max; typ from 2.5 V to 0 V
|   falling waveform, R_fixture 50.0000, V_fixture 3.3000: 20-80 % time 231ps typ, 380ps min, 152ps max; typ from 3.3 V to 0.751 V
[Pulldown]
|Voltage   I(typ)   I(min)   I(max)
-3.3V     -50.23mA   -36.97mA   -64.72mA
-1.1V     -46.23mA   -34.01mA   -59.55mA
-900mV    -45.2mA    -33.74mA   -53.38mA
-700mV    -40.7mA    -32.12mA   -48.96mA
-500mV    -35.8mA    -27.15mA   -45.25mA
-300mV    -23.29mA   -17.06mA   -29.97mA
300mV     22.51mA    16.15mA    29.37mA
800mV     53.6mA     37.78mA    71.09mA
1.3V      75.79mA    52.5mA     102.2mA
1.7V      85.44mA    58.7mA     116.5mA
2.6V      92.51mA    63.57mA    125.6mA
6.6V      106.7mA    73.69mA    144.3mA
[Pullup]
|Voltage   I(typ)   I(min)   I(max)
-3.3V     246.7mA    189.4mA    315.2mA
-3V       223.1mA    176.6mA    283.6mA
-2V       136.6mA    109.5mA    175mA
-1.5V     98.63mA    78.47mA    124mA
-1V       66.82mA    51.33mA    89.91mA
-600mV    44.13mA    34.1mA     58.67mA
500mV     -33.01mA   -24.69mA   -45.84mA
1V        -59.24mA   -43.63mA   -83.72mA
1.5V      -78.42mA   -56.73mA   -113.1mA
2.1V      -91.79mA   -64.71mA   -136.9mA
2.6V      -95.92mA   -66.87mA   -145.8mA
6.55V     -112.1mA   -77.83mA   -172mA
[GND_clamp]
|Voltage   I(typ)   I(min)   I(max)
-3.3V     -955.2mA   -930.2mA   -977.8mA
-1.2V     -86.08mA   -82.87mA   -94.74mA
-1.15V    -76.63mA   -73.22mA   -85.57mA
-1.1V     -67.6mA    -63.89mA   -77.12mA
-1V       -51.41mA   -46.51mA   -63.06mA
-900mV    -38.77mA   -31.82mA   -51.11mA
-800mV    -28.16mA   -20.53mA   -37.82mA
-700mV    -18.01mA   -11.58mA   -24.66mA
-600mV    -9.185mA   -5.219mA   -12.92mA
-450mV    -1.125mA   -553.6uA   -1.501mA
-300mV    0A         0A         0A
6.6V      0A         0A         0A
[POWER_clamp]
|Voltage   I(typ)   I(min)   I(max)
-3.25V    122.1mA    124.8mA    124.2mA
-2.65V    107.1mA    112.6mA    104.1mA
-2.35V    97.06mA    103.7mA    91.56mA
-2.05V    84.81mA    92.86mA    76.2mA
-1.65V    63.69mA    75.19mA    47.4mA
-1.35V    44.32mA    59.82mA    21.89mA
-1.25V    37.38mA    54.39mA    15.53mA
-850mV    10.3mA     31.63mA    860uA
-650mV    3.168mA    19.76mA    65.53uA
-350mV    73.34uA    3.862mA    3.121uA
-150mV    17.77uA    366.8uA    -28.16uA
6.6V      -130.5uA   -83.29uA   -201.6uA
[Ramp]
| variable   typ   min   max
dV/dt_r  1.1341/0.3043n   0.8939/0.4821n   1.3967/0.1866n
dV/dt_f  1.1660/0.2928n   0.8762/0.4469n   1.4017/0.1882n
R_load = 25.0000
[Rising Waveform]
R_fixture=   50.0000
V_fixture=   3.3000
V_fixture_min=   3.1400
V_fixture_max=   3.4700
|time   V(typ)   V(min)   V(max)
0s        750.6mV    965.3mV    616.8mV
505.1ps   750.7mV    965.3mV    780.9mV
606.1ps   749.5mV    965.3mV    2.02V
707.1ps   793.7mV    965.3mV    2.874V
808.1ps   1.783V     965.6mV    3.345V
909.1ps   2.416V     964.7mV    3.416V
1.01ns    2.847V     967.3mV    3.442V
1.313ns   3.256V     2.527V     3.465V
1.818ns   3.295V     3.089V     3.47V
10ns      3.3V       3.14V      3.47V
[Rising Waveform]
R_fixture=   50.0000
V_fixture=   0.0
V_fixture_min=   0.0
V_fixture_max=   0.0
|time   V(typ)   V(min)   V(max)
0s        474nV      645.4nV    441.4nV
606.1ps   -927.7uV   2.006uV    -38.37mV
707.1ps   -36.01mV   19.39uV    558.7mV
909.1ps   -7.211mV   -591.5uV   2.507V
1.111ns   875.6mV    -46.68mV   2.775V
1.313ns   2.027V     -34.65mV   2.818V
1.414ns   2.27V      25.88mV    2.826V
2.02ns    2.48V      1.725V     2.837V
2.424ns   2.49V      2.069V     2.837V
10ns      2.495V     2.157V     2.838V
[Falling Waveform]
R_fixture=   50.0000
V_fixture=   0.0
V_fixture_min=   0.0
V_fixture_max=   0.0
|time   V(typ)   V(min)   V(max)
0s        2.495V     2.157V     2.838V
505.1ps   2.495V     2.157V     2.851V
707.1ps   2.491V     2.157V     368.2mV
808.1ps   2.408V     2.157V     70.48mV
909.1ps   1.416V     2.157V     31.08mV
1.111ns   129mV      2.155V     8.984mV
1.212ns   45.71mV    2.139V     4.945mV
1.616ns   7.492mV    209.6mV    514.2uV
1.818ns   3.678mV    46.55mV    179.8uV
10ns      4.315uV    -619.5nV   7.094uV
[Falling Waveform]
R_fixture=   50.0000
V_fixture=   3.3000
V_fixture_min=   3.1400
V_fixture_max=   3.4700
|time   V(typ)   V(min)   V(max)
0s        3.3V       3.14V      3.47V
606.1ps   3.301V     3.14V      3.389V
808.1ps   3.378V     3.14V      1.072V
909.1ps   3.27V      3.14V      737.6mV
1.01ns    2.585V     3.142V     668.5mV
1.313ns   958.5mV    3.235V     626.2mV
1.515ns   810.3mV    2.893V     620mV
1.919ns   762mV      1.442V     617mV
2.323ns   752.9mV    1.048V     616.8mV
10ns      750.6mV    965.3mV    616.8mV
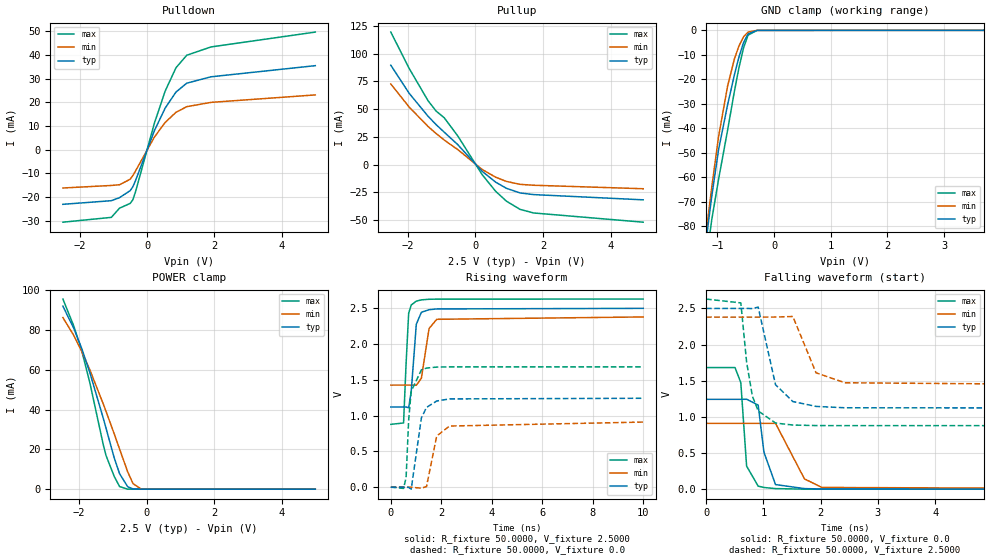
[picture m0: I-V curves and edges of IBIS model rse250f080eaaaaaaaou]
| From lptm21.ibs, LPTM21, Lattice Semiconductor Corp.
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|   Model rse250f080eaaaaaaaou
[Model]   rse250f080eaaaaaaaou
Model_type   Output
Polarity   Non-Inverting
Enable   Active-Low
Vmeas =   1.2500V
Cref =   3.0000pF
Rref =   50.0000
Vref =   1.2500V
C_comp   4.2000pF   3.8000pF   7.5000pF
[Temperature Range]   25.0000   0.1050k   -40.0000
[Voltage Range]   2.5000V   2.3800V   2.6300V
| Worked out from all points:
|   slope of the pulldown table from 0 to 0.375 V, typ, clamps not added: 28.8 ohm
|   slope of the pullup table from 0 to 0.375 V, typ, clamps not added: 35 ohm
|   GND clamp passes 1 mA (typ) near -0.44 V on its own axis
|   POWER clamp passes 1 mA (typ) near -0.54 V on its own axis
|   rising waveform, R_fixture 50.0000, V_fixture 2.5000: 20-80 % time 177ps typ, 254ps min, 140ps max; typ from 1.12 V to 2.5 V
|   rising waveform, R_fixture 50.0000, V_fixture 0.0: 20-80 % time 281ps typ, 339ps min, 180ps max; typ from 0 V to 1.24 V
|   falling waveform, R_fixture 50.0000, V_fixture 0.0: 20-80 % time 147ps typ, 204ps min, 88.3ps max; typ from 1.24 V to 0 V
|   falling waveform, R_fixture 50.0000, V_fixture 2.5000: 20-80 % time 254ps typ, 299ps min, 194ps max; typ from 2.5 V to 1.12 V
[Pulldown]
|Voltage   I(typ)   I(min)   I(max)
-2.5V     -23.08mA   -16.19mA   -30.63mA
-1.06V    -21.55mA   -15.12mA   -28.59mA
-820mV    -20.29mA   -14.82mA   -24.74mA
-500mV    -17.29mA   -12.49mA   -22.68mA
-420mV    -15.65mA   -10.92mA   -21.14mA
-340mV    -13.01mA   -8.939mA   -17.7mA
220mV     8.066mA    5.348mA    11.25mA
540mV     17.57mA    11.51mA    24.77mA
860mV     24.33mA    15.77mA    34.59mA
1.18V     28.07mA    18.15mA    39.87mA
1.9V      30.77mA    19.97mA    43.38mA
5V        35.47mA    23.12mA    49.65mA
[Pullup]
|Voltage   I(typ)   I(min)   I(max)
-2.5V     89.47mA    72.58mA    119.3mA
-1.96V    64.29mA    51.88mA    86.71mA
-1.4V     43.55mA    34.34mA    57.52mA
-1.16V    35.96mA    27.95mA    48.16mA
-920mV    29.16mA    22.05mA    42.11mA
-520mV    17.92mA    13.48mA    25.76mA
200mV     -6.061mA   -4.41mA    -9.073mA
600mV     -15.83mA   -11.37mA   -24.07mA
920mV     -21.38mA   -15.18mA   -33mA
1.32V     -25.51mA   -17.78mA   -40.3mA
1.72V     -27mA      -18.59mA   -43.55mA
4.96V     -31.72mA   -21.73mA   -51.85mA
[GND_clamp]
|Voltage   I(typ)   I(min)   I(max)
-2.5V     -564.7mA   -543.1mA   -585.2mA
-1.18V    -82.35mA   -79.03mA   -91.15mA
-1.14V    -74.88mA   -71.38mA   -83.96mA
-1.1V     -67.69mA   -63.94mA   -77.25mA
-980mV    -48.66mA   -43.36mA   -60.79mA
-820mV    -30.34mA   -22.65mA   -40.66mA
-700mV    -18.09mA   -11.63mA   -24.79mA
-620mV    -10.87mA   -6.335mA   -15.23mA
-540mV    -5.061mA   -2.654mA   -7.227mA
-460mV    -1.446mA   -714.8uA   -1.98mA
-300mV    -18.71uA   -15.93uA   -16.53uA
5V        0A         0A         0A
[POWER_clamp]
|Voltage   I(typ)   I(min)   I(max)
-2.48V    91.96mA    86.23mA    95.54mA
-2.16V    80.94mA    77.35mA    82.15mA
-1.92V    70.61mA    69.17mA    69.43mA
-1.68V    58.52mA    59.9mA     53.37mA
-1.28V    35.44mA    42.67mA    22.07mA
-1.2V     30.53mA    39.03mA    16.84mA
-960mV    15.8mA     27.82mA    6.447mA
-800mV    7.76mA     20.14mA    1.303mA
-560mV    1.23mA     8.728mA    11.53uA
-400mV    83.98uA    2.726mA    532.6nA
-160mV    776.1nA    102uA      144nA
5V        -44.09nA   -38.33nA   -118.7nA
[Ramp]
| variable   typ   min   max
dV/dt_r  0.7610/0.2778n   0.5462/0.3354n   1.0094/0.1786n
dV/dt_f  0.8277/0.2512n   0.5716/0.2962n   1.0508/0.1921n
R_load = 50.0000
[Rising Waveform]
R_fixture=   50.0000
V_fixture=   2.5000
V_fixture_min=   2.3800
V_fixture_max=   2.6300
|time   V(typ)   V(min)   V(max)
0s        1.121V     1.427V     878.6mV
505.1ps   1.121V     1.427V     897.8mV
606.1ps   1.121V     1.427V     1.734V
707.1ps   1.111V     1.427V     2.431V
808.1ps   1.335V     1.427V     2.547V
1.01ns    2.278V     1.425V     2.601V
1.212ns   2.446V     1.524V     2.619V
1.515ns   2.481V     2.217V     2.627V
1.818ns   2.492V     2.347V     2.629V
10ns      2.5V       2.38V      2.63V
[Rising Waveform]
R_fixture=   50.0000
V_fixture=   0.0
V_fixture_min=   0.0
V_fixture_max=   0.0
|time   V(typ)   V(min)   V(max)
0s        666.9nV    899.8nV    549.6nV
505.1ps   22.6uV     1.285uV    -17.11mV
606.1ps   -46.33uV   988.8nV    136.4mV
707.1ps   -3.152mV   8.393uV    939.9mV
808.1ps   -27.71mV   22.98uV    1.34V
1.212ns   969.8mV    -14.56mV   1.641V
1.414ns   1.115V     9.244mV    1.665V
1.818ns   1.205V     714.8mV    1.679V
2.323ns   1.234V     854.8mV    1.682V
10ns      1.243V     910.3mV    1.682V
[Falling Waveform]
R_fixture=   50.0000
V_fixture=   0.0
V_fixture_min=   0.0
V_fixture_max=   0.0
|time   V(typ)   V(min)   V(max)
0s        1.243V     910.4mV    1.682V
505.1ps   1.243V     910.4mV    1.682V
606.1ps   1.243V     910.4mV    1.473V
707.1ps   1.244V     910.4mV    319.2mV
909.1ps   1.163V     910.3mV    41.68mV
1.01ns    510.6mV    910.3mV    23.4mV
1.212ns   63.63mV    910.5mV    7.931mV
1.717ns   7.747mV    142.5mV    532.8uV
2.02ns    2.628mV    23.7mV     163.4uV
10ns      -3.158uV   12.07uV    18.67uV
[Falling Waveform]
R_fixture=   50.0000
V_fixture=   2.5000
V_fixture_min=   2.3800
V_fixture_max=   2.6300
|time   V(typ)   V(min)   V(max)
0s        2.5V       2.38V      2.63V
606.1ps   2.5V       2.38V      2.577V
707.1ps   2.501V     2.38V      1.757V
808.1ps   2.498V     2.38V      1.287V
909.1ps   2.519V     2.38V      1.083V
1.212ns   1.445V     2.381V     914.9mV
1.515ns   1.212V     2.389V     887.1mV
1.919ns   1.145V     1.61V      880mV
2.424ns   1.126V     1.472V     878.8mV
10ns      1.121V     1.427V     878.6mV
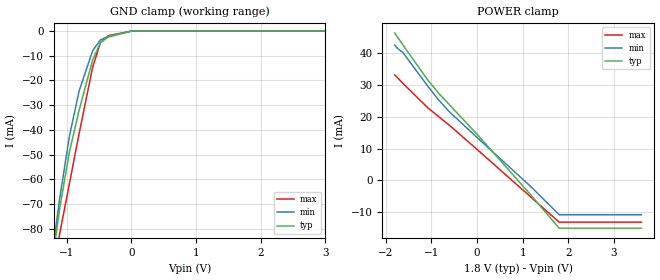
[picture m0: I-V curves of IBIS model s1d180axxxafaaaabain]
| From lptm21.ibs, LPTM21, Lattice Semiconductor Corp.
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|   Model s1d180axxxafaaaabain
[Model]   s1d180axxxafaaaabain
Model_type   Input
Polarity   Non-Inverting
Enable   Active-Low
Vinl =   0.7750V
Vinh =   1.0250V
C_comp   4.2000pF   3.8000pF   7.5000pF
[Temperature Range]   25.0000   0.1050k   -40.0000
[Voltage Range]   1.8000V   1.7100V   1.8900V
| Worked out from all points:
|   GND clamp passes 1 mA (typ) near -0.15 V on its own axis
[GND_clamp]
|Voltage   I(typ)   I(min)   I(max)
-1.8V     -238.2mA   -228.9mA   -252.4mA
-1.68V    -195.3mA   -190.6mA   -206.4mA
-1.59V    -170.8mA   -167.7mA   -180.8mA
-1.32V    -112.3mA   -109.2mA   -121.6mA
-1.11V    -71.87mA   -67.95mA   -82.14mA
-960mV    -49.07mA   -42.75mA   -61.96mA
-810mV    -32.19mA   -24.39mA   -41.64mA
-600mV    -11.77mA   -7.992mA   -14.75mA
-480mV    -4.723mA   -3.605mA   -4.773mA
-360mV    -2.446mA   -2.128mA   -1.886mA
0V        0A         0A         0A
3.6V      0A         0A         0A
[POWER_clamp]
|Voltage   I(typ)   I(min)   I(max)
-1.8V     46.34mA    42.53mA    33.16mA
-1.74V    45.07mA    41.47mA    32.27mA
-1.62V    42.57mA    40.18mA    30.5mA
-1.08V    31.63mA    29.68mA    22.88mA
-840mV    27.44mA    25.31mA    20.07mA
-600mV    23.74mA    21.53mA    17.3mA
0V        14.55mA    13.52mA    9.788mA
1.14V     -3.886mA   -1.395mA   -4.684mA
1.8V      -14.97mA   -10.75mA   -13.08mA
3.6V      -14.97mA   -10.75mA   -13.08mA
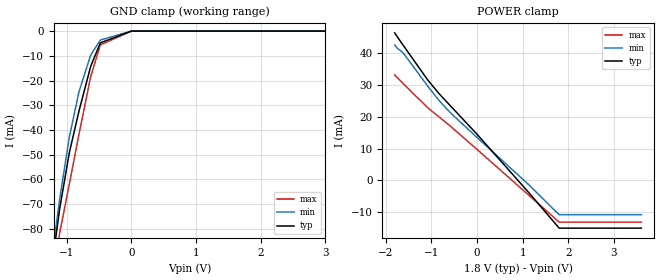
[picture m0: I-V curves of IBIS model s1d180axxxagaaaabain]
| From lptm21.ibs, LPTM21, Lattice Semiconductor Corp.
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|   Model s1d180axxxagaaaabain
[Model]   s1d180axxxagaaaabain
Model_type   Input
Polarity   Non-Inverting
Enable   Active-Low
Vinl =   0.7750V
Vinh =   1.0250V
C_comp   4.2000pF   3.8000pF   7.5000pF
[Temperature Range]   25.0000   0.1050k   -40.0000
[Voltage Range]   1.8000V   1.7100V   1.8900V
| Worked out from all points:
|   GND clamp passes 1 mA (typ) near -0.15 V on its own axis
[GND_clamp]
|Voltage   I(typ)   I(min)   I(max)
-1.8V     -238.3mA   -229.2mA   -250.7mA
-1.74V    -215.5mA   -208.8mA   -226.4mA
-1.68V    -195.4mA   -190.9mA   -205mA
-1.59V    -171mA     -167.9mA   -179.9mA
-1.32V    -112.4mA   -109.4mA   -120.9mA
-1.11V    -71.99mA   -68.08mA   -81.81mA
-960mV    -49.17mA   -42.87mA   -61.89mA
-810mV    -32.28mA   -24.48mA   -41.64mA
-630mV    -14.3mA    -9.724mA   -18.46mA
-480mV    -4.761mA   -3.622mA   -5.581mA
0V        0A         0A         0A
3.6V      0A         0A         0A
[POWER_clamp]
|Voltage   I(typ)   I(min)   I(max)
-1.8V     46.34mA    42.53mA    33.16mA
-1.74V    45.07mA    41.47mA    32.27mA
-1.62V    42.57mA    40.18mA    30.5mA
-1.08V    31.63mA    29.68mA    22.88mA
-840mV    27.44mA    25.31mA    20.07mA
-600mV    23.74mA    21.53mA    17.3mA
0V        14.55mA    13.52mA    9.788mA
1.14V     -3.886mA   -1.395mA   -4.684mA
1.8V      -14.97mA   -10.75mA   -13.08mA
3.6V      -14.97mA   -10.75mA   -13.08mA
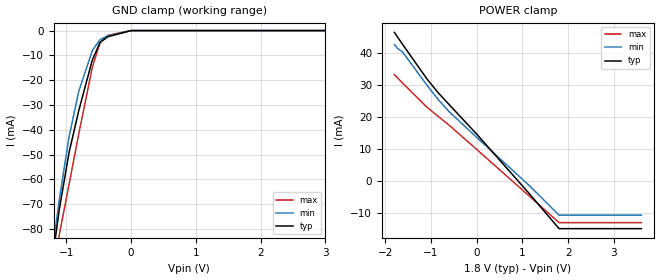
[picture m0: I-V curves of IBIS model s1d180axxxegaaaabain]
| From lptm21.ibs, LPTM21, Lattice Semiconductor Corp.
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|   Model s1d180axxxegaaaabain
[Model]   s1d180axxxegaaaabain
Model_type   Input
Polarity   Non-Inverting
Enable   Active-Low
Vinl =   0.7750V
Vinh =   1.0250V
C_comp   4.2000pF   3.8000pF   7.5000pF
[Temperature Range]   25.0000   0.1050k   -40.0000
[Voltage Range]   1.8000V   1.7100V   1.8900V
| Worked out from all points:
|   GND clamp passes 1 mA (typ) near -0.15 V on its own axis
[GND_clamp]
|Voltage   I(typ)   I(min)   I(max)
-1.8V     -238.3mA   -229.2mA   -252.5mA
-1.68V    -195.4mA   -190.9mA   -206.5mA
-1.59V    -171mA     -167.9mA   -180.9mA
-1.29V    -106.3mA   -103.2mA   -115.5mA
-1.11V    -71.99mA   -68.08mA   -82.19mA
-960mV    -49.17mA   -42.87mA   -62mA
-810mV    -32.28mA   -24.48mA   -41.68mA
-600mV    -11.83mA   -8.037mA   -14.78mA
-480mV    -4.761mA   -3.622mA   -4.797mA
-360mV    -2.465mA   -2.129mA   -1.9mA
0V        0A         0A         0A
3.6V      0A         0A         0A
[POWER_clamp]
|Voltage   I(typ)   I(min)   I(max)
-1.8V     46.34mA    42.53mA    33.16mA
-1.74V    45.07mA    41.47mA    32.27mA
-1.62V    42.57mA    40.18mA    30.5mA
-1.08V    31.63mA    29.68mA    22.88mA
-840mV    27.44mA    25.31mA    20.07mA
-600mV    23.74mA    21.53mA    17.3mA
0V        14.55mA    13.52mA    9.788mA
1.14V     -3.886mA   -1.395mA   -4.684mA
1.8V      -14.97mA   -10.75mA   -13.08mA
3.6V      -14.97mA   -10.75mA   -13.08mA
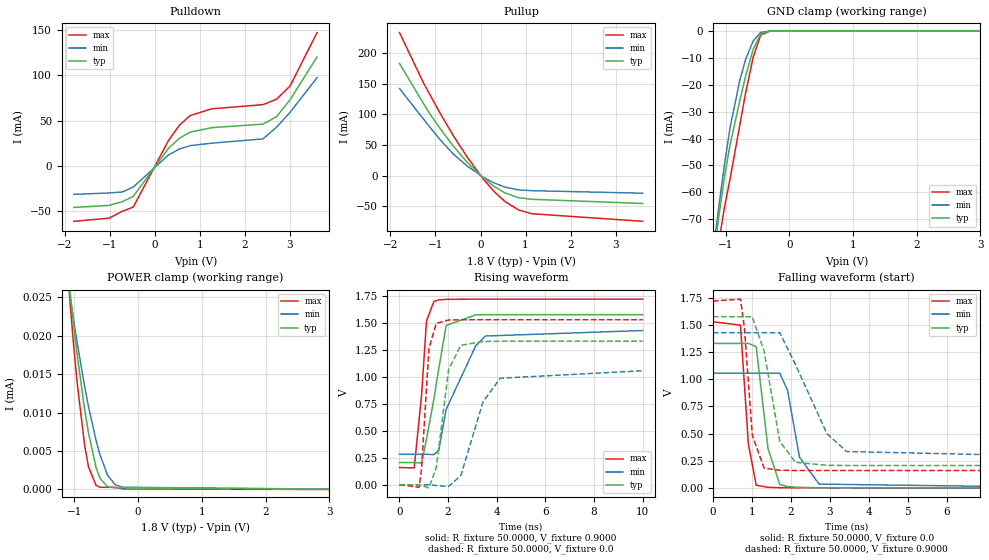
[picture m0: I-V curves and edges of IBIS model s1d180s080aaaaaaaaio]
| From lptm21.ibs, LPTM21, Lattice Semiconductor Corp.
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|   Model s1d180s080aaaaaaaaio
[Model]   s1d180s080aaaaaaaaio
Model_type   I/O
Polarity   Non-Inverting
Enable   Active-Low
Vinl =   0.7750V
Vinh =   1.0250V
Vmeas =   0.9000V
Cref =   30.0000pF
Rref =   50.0000
Vref =   0.9000V
C_comp   4.2000pF   3.8000pF   7.5000pF
[Temperature Range]   25.0000   0.1050k   -40.0000
[Voltage Range]   1.8000V   1.7100V   1.8900V
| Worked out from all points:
|   slope of the pulldown table from 0 to 0.27 V, typ, clamps not added: 15.3 ohm
|   slope of the pullup table from 0 to 0.27 V, typ, clamps not added: 16.6 ohm
|   GND clamp passes 1 mA (typ) near -0.44 V on its own axis
|   rising waveform, R_fixture 50.0000, V_fixture 0.9000: 20-80 % time 604ps typ, 1.22ns min, 329ps max; typ from 0.205 V to 1.58 V
|   rising waveform, R_fixture 50.0000, V_fixture 0.0: 20-80 % time 444ps typ, 896ps min, 248ps max; typ from 0 V to 1.33 V
|   falling waveform, R_fixture 50.0000, V_fixture 0.0: 20-80 % time 277ps typ, 363ps min, 183ps max; typ from 1.33 V to 0 V
|   falling waveform, R_fixture 50.0000, V_fixture 0.9000: 20-80 % time 395ps typ, 837ps min, 195ps max; typ from 1.58 V to 0.205 V
[Pulldown]
|Voltage   I(typ)   I(min)   I(max)
-1.8V     -45.94mA   -31.47mA   -61.23mA
-1.02V    -43.68mA   -29.93mA   -57.79mA
-720mV    -39.44mA   -28.75mA   -50.1mA
-480mV    -33.68mA   -23.32mA   -45.45mA
300mV     19.35mA    12.08mA    27.97mA
540mV     30.45mA    18.58mA    44.82mA
780mV     37.3mA     22.36mA    55.59mA
1.26V     42.28mA    25.14mA    63.12mA
2.4V      46.18mA    29.86mA    67.7mA
2.7V      54.41mA    42.72mA    73.7mA
3V        73.03mA    59.16mA    88.27mA
3.6V      120.4mA    97.57mA    147.4mA
[Pullup]
|Voltage   I(typ)   I(min)   I(max)
-1.8V     183.2mA    142.3mA    233.8mA
-1.26V    116.8mA    91.69mA    150.5mA
-1.14V    102.5mA    80.56mA    134.4mA
-900mV    77.2mA     58.82mA    102.2mA
-600mV    47.77mA    34.83mA    64.66mA
-300mV    22.14mA    15.76mA    30.71mA
60mV      -3.977mA   -2.74mA    -5.698mA
300mV     -17.84mA   -12.11mA   -26.07mA
540mV     -28.26mA   -18.85mA   -42.29mA
840mV     -36.15mA   -23.48mA   -56.13mA
1.14V     -38.83mA   -24.75mA   -62.45mA
3.6V      -45.64mA   -28.87mA   -74.81mA
[GND_clamp]
|Voltage   I(typ)   I(min)   I(max)
-1.8V     -240.2mA   -229.4mA   -254.3mA
-1.2V     -86.16mA   -82.91mA   -94.88mA
-1.17V    -80.45mA   -77.09mA   -89.3mA
-1.11V    -69.45mA   -65.77mA   -78.87mA
-1.02V    -54.48mA   -49.86mA   -65.69mA
-930mV    -42.25mA   -35.9mA    -54.92mA
-780mV    -26.14mA   -18.58mA   -35.25mA
-690mV    -17.13mA   -10.87mA   -23.53mA
-570mV    -7.024mA   -3.834mA   -9.978mA
-450mV    -1.176mA   -584.6uA   -1.582mA
-300mV    -18.65uA   -15.9uA    -16.44uA
3.6V      0A         0A         0A
[POWER_clamp]
|Voltage   I(typ)   I(min)   I(max)
-1.8V     102.4uA    78.03uA    133.9uA
-1.08V    26.57uA    25.91uA    25.52uA
-1.02V    21.97uA    22.48uA    19.47uA
-960mV    17.73uA    19.24uA    14.09uA
-840mV    10.4uA     13.41uA    5.722uA
-780mV    7.368uA    10.82uA    2.954uA
-660mV    2.829uA    6.357uA    503.7nA
-600mV    1.451uA    4.527uA    262.8nA
-480mV    333.1nA    1.844uA    262.8nA
-360mV    178.5nA    588.1nA    262.8nA
-240mV    178.5nA    271.5nA    57.44nA
3.6V      -31nA      -27.04nA   -40.53nA
[Ramp]
| variable   typ   min   max
dV/dt_r  0.7825/0.4393n   0.6334/0.8871n   0.9175/0.2454n
dV/dt_f  0.8078/0.3845n   0.6265/0.7902n   0.9309/0.2125n
R_load = 50.0000
[Rising Waveform]
R_fixture=   50.0000
V_fixture=   0.9000
V_fixture_min=   0.8560
V_fixture_max=   0.9460
|time   V(typ)   V(min)   V(max)
0s        205.4mV    282.1mV    159.2mV
606.1ps   205.5mV    282.1mV    155.5mV
909.1ps   200.1mV    282.1mV    831.5mV
1.111ns   422mV      282.2mV    1.516V
1.414ns   791.6mV    277.9mV    1.698V
1.616ns   1.076V     319.3mV    1.713V
1.919ns   1.475V     697.2mV    1.718V
3.131ns   1.574V     1.285V     1.72V
3.535ns   1.576V     1.378V     1.72V
10ns      1.576V     1.429V     1.72V
[Rising Waveform]
R_fixture=   50.0000
V_fixture=   0.0
V_fixture_min=   0.0
V_fixture_max=   0.0
|time   V(typ)   V(min)   V(max)
0s        291.2nV    449.5nV    213.5nV
808.1ps   -1.107mV   1.282uV    -24.12mV
909.1ps   -6.852mV   11.85uV    153.6mV
1.212ns   -29.24mV   -302.2uV   1.262V
1.515ns   159.7mV    -7.825mV   1.496V
2.02ns    1.067V     -16.68mV   1.526V
2.525ns   1.292V     86.04mV    1.529V
3.434ns   1.327V     767.5mV    1.529V
4.141ns   1.33V      986.9mV    1.529V
10ns      1.33V      1.056V     1.529V
[Falling Waveform]
R_fixture=   50.0000
V_fixture=   0.0
V_fixture_min=   0.0
V_fixture_max=   0.0
|time   V(typ)   V(min)   V(max)
0s        1.33V      1.056V     1.529V
707.1ps   1.33V      1.056V     1.499V
909.1ps   1.331V     1.056V     406.9mV
1.111ns   1.3V       1.056V     23.75mV
1.414ns   362.7mV    1.056V     5.113mV
1.717ns   31.09mV    1.056V     1.154mV
1.919ns   12.12mV    895mV      449.9uV
2.222ns   4.456mV    282.8mV    103.6uV
2.727ns   962.4uV    34.48mV    47.53uV
10ns      1.938uV    -7.464uV   -8.517uV
[Falling Waveform]
R_fixture=   50.0000
V_fixture=   0.9000
V_fixture_min=   0.8560
V_fixture_max=   0.9460
|time   V(typ)   V(min)   V(max)
0s        1.576V     1.429V     1.72V
707.1ps   1.576V     1.429V     1.738V
808.1ps   1.577V     1.429V     1.475V
1.01ns    1.575V     1.429V     486.9mV
1.313ns   1.26V      1.429V     181.9mV
1.717ns   426.2mV    1.428V     162mV
2.121ns   235.2mV    1.134V     159.6mV
2.929ns   207.6mV    497.9mV    159.3mV
3.434ns   205.9mV    334.6mV    159.2mV
10ns      205.4mV    282.1mV    159.2mV
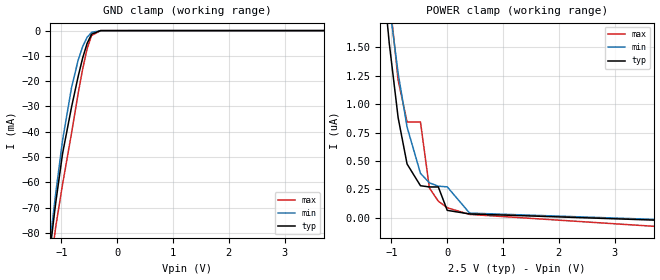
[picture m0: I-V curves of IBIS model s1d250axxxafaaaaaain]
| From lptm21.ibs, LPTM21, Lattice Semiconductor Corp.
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|   Model s1d250axxxafaaaaaain
[Model]   s1d250axxxafaaaaaain
Model_type   Input
Polarity   Non-Inverting
Enable   Active-Low
Vinl =   1.0700V
Vinh =   1.4300V
C_comp   4.2000pF   3.8000pF   7.5000pF
[Temperature Range]   25.0000   0.1050k   -40.0000
[Voltage Range]   2.5000V   2.3800V   2.6300V
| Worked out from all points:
|   GND clamp passes 1 mA (typ) near -0.44 V on its own axis
[GND_clamp]
|Voltage   I(typ)   I(min)   I(max)
-2.5V     -564.7mA   -543.1mA   -585.2mA
-1.18V    -82.35mA   -79.03mA   -91.15mA
-1.14V    -74.88mA   -71.38mA   -83.96mA
-1.1V     -67.69mA   -63.94mA   -77.25mA
-980mV    -48.66mA   -43.36mA   -60.79mA
-820mV    -30.34mA   -22.65mA   -40.66mA
-700mV    -18.09mA   -11.63mA   -24.79mA
-620mV    -10.87mA   -6.335mA   -15.23mA
-540mV    -5.061mA   -2.654mA   -7.227mA
-460mV    -1.446mA   -714.8uA   -1.98mA
-300mV    -18.71uA   -15.93uA   -16.53uA
5V        0A         0A         0A
[POWER_clamp]
|Voltage   I(typ)   I(min)   I(max)
-2.48V    16.67uA    13.46uA    27.27uA
-1.2V     2.435uA    2.651uA    3.191uA
-1.12V    1.959uA    2.254uA    2.522uA
-1.04V    1.541uA    1.891uA    1.967uA
-880mV    880.7nA    1.272uA    1.212uA
-720mV    472.2nA    798.5nA    842.6nA
-480mV    280.5nA    389.6nA    842.6nA
-320mV    269.7nA    306.1nA    260.6nA
-160mV    269.7nA    276.4nA    144nA
0V        63.22nA    270.6nA    86.34nA
400mV     31.61nA    39.07nA    27.38nA
5V        -44.09nA   -38.33nA   -118.7nA
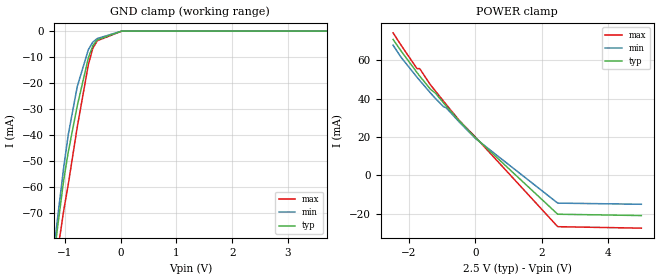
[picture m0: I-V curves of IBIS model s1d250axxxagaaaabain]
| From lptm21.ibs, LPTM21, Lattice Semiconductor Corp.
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|   Model s1d250axxxagaaaabain
[Model]   s1d250axxxagaaaabain
Model_type   Input
Polarity   Non-Inverting
Enable   Active-Low
Vinl =   1.0700V
Vinh =   1.4300V
C_comp   4.2000pF   3.8000pF   7.5000pF
[Temperature Range]   25.0000   0.1050k   -40.0000
[Voltage Range]   2.5000V   2.3800V   2.6300V
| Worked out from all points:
|   GND clamp passes 1 mA (typ) near -0.13 V on its own axis
[GND_clamp]
|Voltage   I(typ)   I(min)   I(max)
-2.5V     -559mA     -539.3mA   -577.6mA
-1.22V    -91.87mA   -88.8mA    -100.4mA
-1.18V    -84.23mA   -80.98mA   -92.97mA
-1.14V    -76.86mA   -73.36mA   -86.09mA
-1.02V    -57.03mA   -52.06mA   -68.84mA
-940mV    -46.52mA   -39.84mA   -58.98mA
-780mV    -28.85mA   -21.43mA   -37.05mA
-580mV    -10.26mA   -7.144mA   -12.89mA
-500mV    -5.622mA   -4.259mA   -6.605mA
-420mV    -3.366mA   -2.868mA   -3.715mA
20mV      0A         0A         0A
5V        0A         0A         0A
[POWER_clamp]
|Voltage   I(typ)   I(min)   I(max)
-2.48V    70.8mA     67.79mA    74.22mA
-2.24V    64.81mA    61.5mA     67.79mA
-1.76V    53.56mA    51.12mA    55.62mA
-1.68V    51.75mA    49.46mA    55.62mA
-1.36V    44.95mA    43.02mA    47.29mA
-1.2V     42.73mA    39.97mA    43.79mA
-960mV    37.69mA    35.72mA    38.61mA
-880mV    36.09mA    35.18mA    36.9mA
-480mV    28.21mA    27.66mA    28.47mA
0V        19.67mA    19.21mA    19.91mA
2.48V     -20.27mA   -14.48mA   -26.76mA
5V        -20.96mA   -15.08mA   -27.53mA
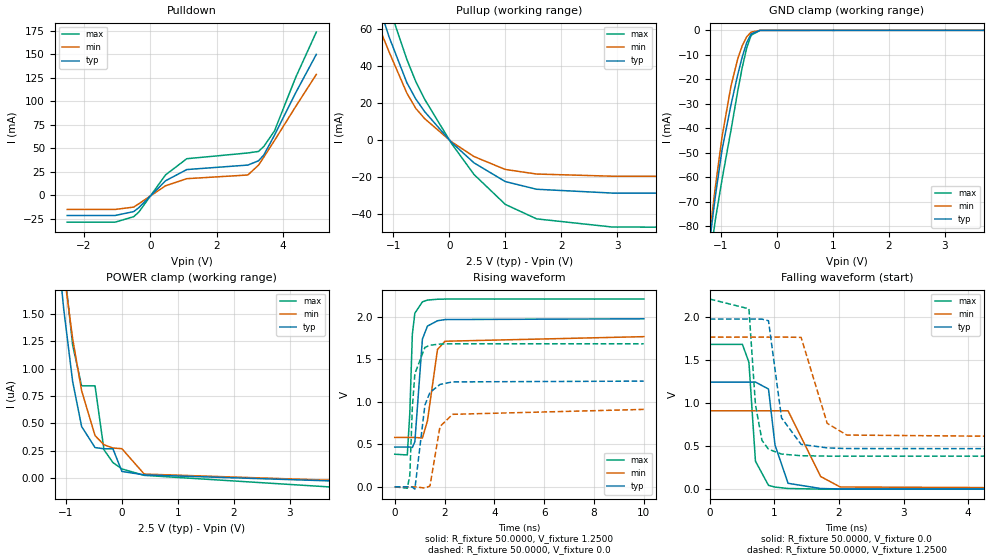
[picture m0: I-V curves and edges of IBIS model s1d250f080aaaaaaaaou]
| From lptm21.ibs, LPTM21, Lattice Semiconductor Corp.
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|   Model s1d250f080aaaaaaaaou
[Model]   s1d250f080aaaaaaaaou
Model_type   Output
Polarity   Non-Inverting
Enable   Active-Low
Vmeas =   1.2500V
Cref =   30.0000pF
Rref =   50.0000
Vref =   1.2500V
C_comp   4.2000pF   3.8000pF   7.5000pF
[Temperature Range]   25.0000   0.1050k   -40.0000
[Voltage Range]   2.5000V   2.3800V   2.6300V
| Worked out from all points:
|   slope of the pulldown table from 0 to 0.375 V, typ, clamps not added: 28.8 ohm
|   slope of the pullup table from 0 to 0.375 V, typ, clamps not added: 35 ohm
|   GND clamp passes 1 mA (typ) near -0.44 V on its own axis
|   rising waveform, R_fixture 50.0000, V_fixture 1.2500: 20-80 % time 213ps typ, 314ps min, 146ps max; typ from 0.468 V to 1.98 V
|   rising waveform, R_fixture 50.0000, V_fixture 0.0: 20-80 % time 289ps typ, 348ps min, 186ps max; typ from 0 V to 1.24 V
|   falling waveform, R_fixture 50.0000, V_fixture 0.0: 20-80 % time 148ps typ, 206ps min, 88.8ps max; typ from 1.24 V to 0 V
|   falling waveform, R_fixture 50.0000, V_fixture 1.2500: 20-80 % time 181ps typ, 241ps min, 135ps max; typ from 1.98 V to 0.468 V
[Pulldown]
|Voltage   I(typ)   I(min)   I(max)
-2.5V     -21.51mA   -15.08mA   -28.63mA
-1.06V    -21.51mA   -15.08mA   -28.63mA
-500mV    -17.35mA   -12.54mA   -22.78mA
-340mV    -13.02mA   -8.945mA   -17.72mA
460mV     15.44mA    10.15mA    21.72mA
1.1V      27.41mA    17.71mA    38.96mA
2.94V     32.21mA    21.62mA    45.09mA
3.26V     36.74mA    32.14mA    46.73mA
3.42V     42.91mA    40.65mA    52.04mA
3.74V     63.96mA    58.33mA    68.49mA
4.38V     109.2mA    94.56mA    125.6mA
5V        150mA      128.7mA    173.8mA
[Pullup]
|Voltage   I(typ)   I(min)   I(max)
-2.5V     183.8mA    153mA      224.3mA
-1.8V     123.7mA    101.3mA    154.8mA
-1.08V    56.04mA    47.91mA    72.27mA
-760mV    31.08mA    25.44mA    43.69mA
-600mV    22.24mA    17.14mA    31.67mA
-440mV    15.35mA    11.58mA    22.02mA
40mV      -1.275mA   -931.8uA   -1.898mA
440mV     -12.3mA    -8.882mA   -18.58mA
1V        -22.45mA   -15.89mA   -34.81mA
1.56V     -26.61mA   -18.37mA   -42.65mA
2.92V     -28.69mA   -19.55mA   -47.09mA
4.96V     -28.69mA   -19.55mA   -47.15mA
[GND_clamp]
|Voltage   I(typ)   I(min)   I(max)
-2.5V     -564.7mA   -543.1mA   -585.2mA
-1.18V    -82.35mA   -79.03mA   -91.15mA
-1.14V    -74.88mA   -71.38mA   -83.96mA
-1.1V     -67.69mA   -63.94mA   -77.25mA
-980mV    -48.66mA   -43.36mA   -60.79mA
-820mV    -30.34mA   -22.65mA   -40.66mA
-700mV    -18.09mA   -11.63mA   -24.79mA
-620mV    -10.87mA   -6.335mA   -15.23mA
-540mV    -5.061mA   -2.654mA   -7.227mA
-460mV    -1.446mA   -714.8uA   -1.98mA
-300mV    -18.71uA   -15.93uA   -16.53uA
5V        0A         0A         0A
[POWER_clamp]
|Voltage   I(typ)   I(min)   I(max)
-2.48V    16.67uA    13.46uA    27.27uA
-1.2V     2.435uA    2.651uA    3.191uA
-1.12V    1.959uA    2.254uA    2.522uA
-1.04V    1.541uA    1.891uA    1.967uA
-880mV    880.7nA    1.272uA    1.212uA
-720mV    472.2nA    798.5nA    842.6nA
-480mV    280.5nA    389.6nA    842.6nA
-320mV    269.7nA    306.1nA    260.6nA
-160mV    269.7nA    276.4nA    144nA
0V        63.22nA    270.6nA    86.34nA
400mV     31.61nA    39.07nA    27.38nA
5V        -44.09nA   -38.33nA   -118.7nA
[Ramp]
| variable   typ   min   max
dV/dt_r  0.7610/0.2858n   0.5462/0.3448n   1.0094/0.1845n
dV/dt_f  0.8277/0.2560n   0.5716/0.3001n   1.0508/0.1959n
R_load = 50.0000
[Rising Waveform]
R_fixture=   50.0000
V_fixture=   1.2500
V_fixture_min=   1.1880
V_fixture_max=   1.3130
|time   V(typ)   V(min)   V(max)
0s        467.6mV    580.4mV    383.5mV
505.1ps   467.6mV    580.4mV    374.8mV
606.1ps   467.7mV    580.4mV    870.4mV
707.1ps   462.6mV    580.4mV    1.793V
808.1ps   530.4mV    580.4mV    2.042V
1.111ns   1.737V     574.4mV    2.175V
1.313ns   1.89V      774.8mV    2.196V
1.717ns   1.953V     1.615V     2.206V
2.02ns    1.967V     1.712V     2.208V
10ns      1.976V     1.766V     2.208V
[Rising Waveform]
R_fixture=   50.0000
V_fixture=   0.0
V_fixture_min=   0.0
V_fixture_max=   0.0
|time   V(typ)   V(min)   V(max)
0s        693.1nV    932.7nV    570.7nV
505.1ps   22.52uV    1.286uV    -17.06mV
606.1ps   -46.28uV   904.5nV    136.2mV
707.1ps   -3.139mV   8.449uV    933.3mV
808.1ps   -27.6mV    22.87uV    1.33V
1.212ns   962.1mV    -14.5mV    1.639V
1.414ns   1.11V      9.283mV    1.665V
1.818ns   1.204V     709.4mV    1.679V
2.323ns   1.234V     852.6mV    1.682V
10ns      1.243V     910.4mV    1.682V
[Falling Waveform]
R_fixture=   50.0000
V_fixture=   0.0
V_fixture_min=   0.0
V_fixture_max=   0.0
|time   V(typ)   V(min)   V(max)
0s        1.243V     910.4mV    1.682V
505.1ps   1.243V     910.4mV    1.682V
606.1ps   1.243V     910.4mV    1.474V
707.1ps   1.244V     910.4mV    325.2mV
909.1ps   1.163V     910.3mV    44.35mV
1.01ns    513.8mV    910.3mV    24.12mV
1.212ns   68.09mV    910.5mV    7.804mV
1.717ns   7.65mV     146.7mV    488uV
2.02ns    2.548mV    25.36mV    169.1uV
10ns      1.061uV    -9.929uV   -14.19uV
[Falling Waveform]
R_fixture=   50.0000
V_fixture=   1.2500
V_fixture_min=   1.1880
V_fixture_max=   1.3130
|time   V(typ)   V(min)   V(max)
0s        1.976V     1.766V     2.208V
606.1ps   1.976V     1.766V     2.095V
707.1ps   1.976V     1.766V     981.3mV
808.1ps   1.975V     1.766V     566.9mV
909.1ps   1.956V     1.766V     464.1mV
1.111ns   828mV      1.767V     407.7mV
1.414ns   520.3mV    1.763V     388.3mV
1.818ns   479.4mV    764.6mV    384.1mV
2.121ns   471.7mV    628.4mV    383.7mV
10ns      467.5mV    580.4mV    383.5mV
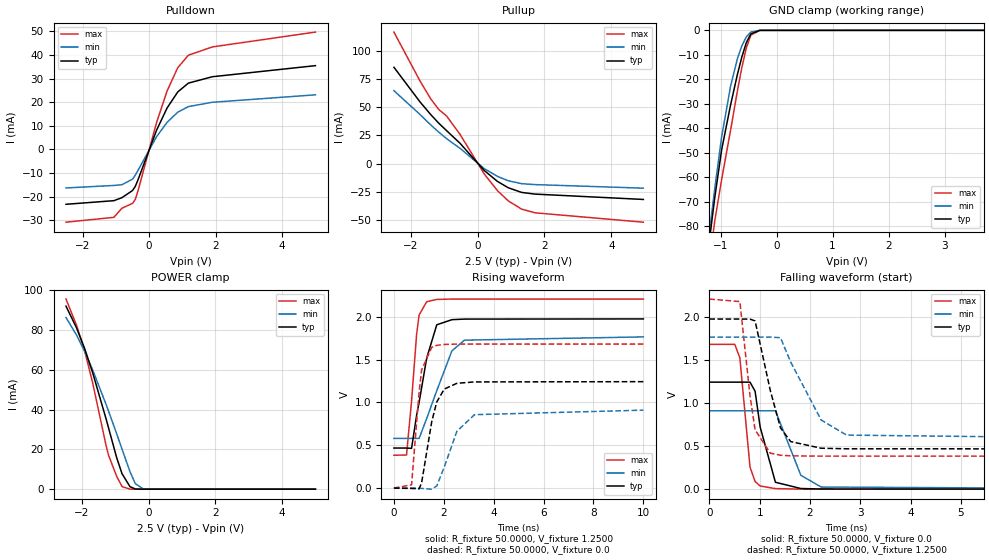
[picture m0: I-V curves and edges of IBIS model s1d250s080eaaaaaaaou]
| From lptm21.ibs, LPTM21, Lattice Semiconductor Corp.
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|   Model s1d250s080eaaaaaaaou
[Model]   s1d250s080eaaaaaaaou
Model_type   Output
Polarity   Non-Inverting
Enable   Active-Low
Vmeas =   1.2500V
Cref =   30.0000pF
Rref =   50.0000
Vref =   1.2500V
C_comp   4.2000pF   3.8000pF   7.5000pF
[Temperature Range]   25.0000   0.1050k   -40.0000
[Voltage Range]   2.5000V   2.3800V   2.6300V
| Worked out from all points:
|   slope of the pulldown table from 0 to 0.375 V, typ, clamps not added: 28.8 ohm
|   slope of the pullup table from 0 to 0.375 V, typ, clamps not added: 35 ohm
|   GND clamp passes 1 mA (typ) near -0.44 V on its own axis
|   POWER clamp passes 1 mA (typ) near -0.54 V on its own axis
|   rising waveform, R_fixture 50.0000, V_fixture 1.2500: 20-80 % time 521ps typ, 890ps min, 322ps max; typ from 0.468 V to 1.98 V
|   rising waveform, R_fixture 50.0000, V_fixture 0.0: 20-80 % time 470ps typ, 715ps min, 288ps max; typ from 0 V to 1.24 V
|   falling waveform, R_fixture 50.0000, V_fixture 0.0: 20-80 % time 235ps typ, 316ps min, 162ps max; typ from 1.24 V to 0 V
|   falling waveform, R_fixture 50.0000, V_fixture 1.2500: 20-80 % time 358ps typ, 620ps min, 222ps max; typ from 1.98 V to 0.468 V
[Pulldown]
|Voltage   I(typ)   I(min)   I(max)
-2.5V     -23.17mA   -16.27mA   -30.74mA
-1.06V    -21.64mA   -15.2mA    -28.69mA
-820mV    -20.38mA   -14.9mA    -24.84mA
-500mV    -17.35mA   -12.54mA   -22.78mA
-420mV    -15.69mA   -10.94mA   -21.2mA
-340mV    -13.02mA   -8.945mA   -17.72mA
220mV     8.066mA    5.348mA    11.25mA
540mV     17.57mA    11.51mA    24.77mA
860mV     24.33mA    15.77mA    34.59mA
1.18V     28.07mA    18.15mA    39.87mA
1.9V      30.77mA    19.97mA    43.38mA
5V        35.46mA    23.12mA    49.65mA
[Pullup]
|Voltage   I(typ)   I(min)   I(max)
-2.5V     85.26mA    64.56mA    116.4mA
-1.72V    54.62mA    43.49mA    73.15mA
-1.4V     43.42mA    34.27mA    57.3mA
-1.16V    35.8mA     27.87mA    47.92mA
-920mV    29.03mA    21.97mA    41.97mA
-520mV    17.89mA    13.46mA    25.73mA
200mV     -6.061mA   -4.41mA    -9.073mA
600mV     -15.83mA   -11.37mA   -24.07mA
920mV     -21.38mA   -15.18mA   -33mA
1.32V     -25.51mA   -17.78mA   -40.3mA
1.72V     -27mA      -18.59mA   -43.55mA
4.96V     -31.73mA   -21.74mA   -51.86mA
[GND_clamp]
|Voltage   I(typ)   I(min)   I(max)
-2.5V     -564.7mA   -543.1mA   -585.2mA
-1.18V    -82.35mA   -79.03mA   -91.15mA
-1.14V    -74.88mA   -71.38mA   -83.96mA
-1.1V     -67.69mA   -63.94mA   -77.25mA
-980mV    -48.66mA   -43.36mA   -60.79mA
-820mV    -30.34mA   -22.65mA   -40.66mA
-700mV    -18.09mA   -11.63mA   -24.79mA
-620mV    -10.87mA   -6.335mA   -15.23mA
-540mV    -5.061mA   -2.654mA   -7.227mA
-460mV    -1.446mA   -714.8uA   -1.98mA
-300mV    -18.71uA   -15.93uA   -16.53uA
5V        0A         0A         0A
[POWER_clamp]
|Voltage   I(typ)   I(min)   I(max)
-2.48V    91.96mA    86.23mA    95.54mA
-2.16V    80.94mA    77.35mA    82.15mA
-1.92V    70.61mA    69.17mA    69.43mA
-1.68V    58.52mA    59.9mA     53.37mA
-1.28V    35.44mA    42.67mA    22.07mA
-1.2V     30.53mA    39.03mA    16.84mA
-960mV    15.8mA     27.82mA    6.447mA
-800mV    7.76mA     20.14mA    1.303mA
-560mV    1.23mA     8.728mA    11.53uA
-400mV    83.98uA    2.726mA    532.6nA
-160mV    776.1nA    102uA      144nA
5V        -44.09nA   -38.33nA   -118.7nA
[Ramp]
| variable   typ   min   max
dV/dt_r  0.7610/0.4652n   0.5462/0.7078n   1.0094/0.2854n
dV/dt_f  0.8277/0.4526n   0.5716/0.6695n   1.0508/0.3023n
R_load = 50.0000
[Rising Waveform]
R_fixture=   50.0000
V_fixture=   1.2500
V_fixture_min=   1.1880
V_fixture_max=   1.3130
|time   V(typ)   V(min)   V(max)
0s        467.6mV    580.4mV    383.5mV
505.1ps   467.6mV    580.4mV    386.3mV
707.1ps   463.8mV    580.4mV    1.017V
909.1ps   848.7mV    580.6mV    1.794V
1.01ns    1.001V     579.8mV    2.022V
1.313ns   1.517V     811.8mV    2.177V
1.717ns   1.907V     1.137V     2.204V
2.323ns   1.967V     1.602V     2.208V
2.828ns   1.974V     1.728V     2.208V
10ns      1.976V     1.766V     2.208V
[Rising Waveform]
R_fixture=   50.0000
V_fixture=   0.0
V_fixture_min=   0.0
V_fixture_max=   0.0
|time   V(typ)   V(min)   V(max)
0s        693.1nV    932.7nV    570.7nV
707.1ps   -4.266mV   7.527uV    38.32mV
1.01ns    -9.218mV   -450.4uV   1.123V
1.111ns   62.45mV    -4.51mV    1.38V
1.515ns   773.4mV    -12.82mV   1.644V
1.717ns   1.006V     24.27mV    1.667V
2.02ns    1.157V     247.5mV    1.678V
2.525ns   1.224V     663.6mV    1.682V
3.232ns   1.24V      857.5mV    1.682V
10ns      1.243V     910.3mV    1.682V
[Falling Waveform]
R_fixture=   50.0000
V_fixture=   0.0
V_fixture_min=   0.0
V_fixture_max=   0.0
|time   V(typ)   V(min)   V(max)
0s        1.243V     910.3mV    1.682V
505.1ps   1.243V     910.3mV    1.682V
606.1ps   1.243V     910.3mV    1.525V
808.1ps   1.243V     910.4mV    255.8mV
909.1ps   1.137V     910.3mV    88.44mV
1.01ns    721.1mV    910.3mV    36.93mV
1.313ns   80.15mV    910.8mV    6.403mV
1.818ns   7.602mV    161.3mV    418.7uV
2.222ns   1.69mV     24.92mV    110uV
10ns      3.659uV    -12.37uV   15.6uV
[Falling Waveform]
R_fixture=   50.0000
V_fixture=   1.2500
V_fixture_min=   1.1880
V_fixture_max=   1.3130
|time   V(typ)   V(min)   V(max)
0s        1.976V     1.766V     2.208V
606.1ps   1.976V     1.766V     2.179V
808.1ps   1.975V     1.766V     1.085V
909.1ps   1.954V     1.766V     688.5mV
1.212ns   1.145V     1.767V     417.8mV
1.414ns   712.4mV    1.759V     394.1mV
1.616ns   552.7mV    1.477V     387mV
2.222ns   475.5mV    803.2mV    383.7mV
2.727ns   468.9mV    628.1mV    383.5mV
10ns      467.6mV    580.4mV    383.5mV
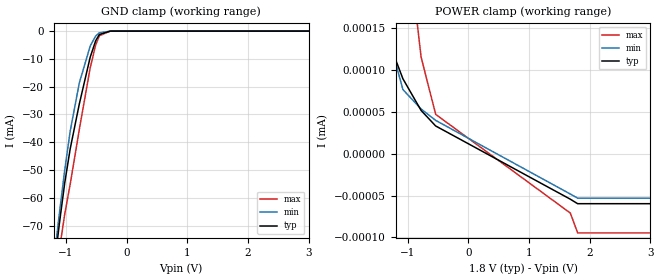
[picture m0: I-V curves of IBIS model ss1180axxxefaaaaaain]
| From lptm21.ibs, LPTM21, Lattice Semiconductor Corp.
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|   Model ss1180axxxefaaaaaain
[Model]   ss1180axxxefaaaaaain
Model_type   Input
Polarity   Non-Inverting
Enable   Active-Low
Vinl =   0.7750V
Vinh =   1.0250V
C_comp   4.2000pF   3.8000pF   7.5000pF
[Temperature Range]   25.0000   0.1050k   -40.0000
[Voltage Range]   1.8000V   1.7100V   1.8900V
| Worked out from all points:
|   GND clamp passes 1 mA (typ) near -0.44 V on its own axis
[GND_clamp]
|Voltage   I(typ)   I(min)   I(max)
-1.8V     -240.3mA   -229.5mA   -254.3mA
-1.2V     -86.25mA   -83.02mA   -94.99mA
-1.17V    -80.54mA   -77.2mA    -89.42mA
-1.11V    -69.55mA   -65.87mA   -78.99mA
-1.02V    -54.58mA   -49.95mA   -65.82mA
-930mV    -42.35mA   -35.99mA   -55.05mA
-780mV    -26.24mA   -18.67mA   -35.38mA
-600mV    -9.354mA   -5.34mA    -13.17mA
-510mV    -3.494mA   -1.787mA   -4.979mA
-450mV    -1.251mA   -629.4uA   -1.7mA
-270mV    -11.4uA    -9.003uA   -17.31uA
3.6V      0A         0A         0A
[POWER_clamp]
|Voltage   I(typ)   I(min)   I(max)
-1.8V     10.78uA    1.038mA    1.633uA
-1.62V    444nA      57.64uA    1.148uA
-1.5V     193.4nA    6.247uA    889.3nA
-1.38V    152.8nA    648.8nA    674.8nA
-1.32V    137.7nA    238.2nA    582.9nA
-1.26V    123.9nA    124.4nA    500.4nA
-1.08V    89.72nA    76.79nA    304.6nA
-780mV    51.78nA    53.57nA    115.6nA
-540mV    33.24nA    39.92nA    47.12nA
1.68V     -54.41nA   -48.21nA   -70.99nA
1.8V      -59.75nA   -53.16nA   -94.7nA
3.6V      -59.75nA   -53.16nA   -94.7nA
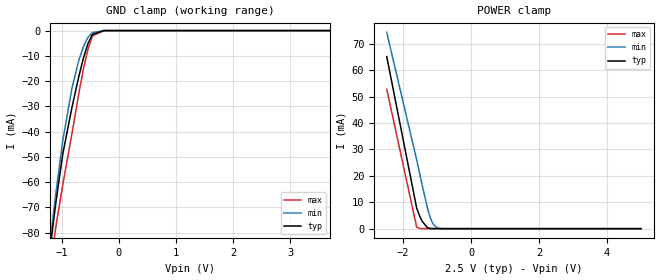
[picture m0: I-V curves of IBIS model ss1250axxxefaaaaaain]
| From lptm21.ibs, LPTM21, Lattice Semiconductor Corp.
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|   Model ss1250axxxefaaaaaain
[Model]   ss1250axxxefaaaaaain
Model_type   Input
Polarity   Non-Inverting
Enable   Active-Low
Vinl =   1.0700V
Vinh =   1.4300V
C_comp   4.2000pF   3.8000pF   7.5000pF
[Temperature Range]   25.0000   0.1050k   -40.0000
[Voltage Range]   2.5000V   2.3800V   2.6300V
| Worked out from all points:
|   GND clamp passes 1 mA (typ) near -0.44 V on its own axis
|   POWER clamp passes 1 mA (typ) near -1.34 V on its own axis
[GND_clamp]
|Voltage   I(typ)   I(min)   I(max)
-2.5V     -564.7mA   -543.1mA   -585.2mA
-1.18V    -82.43mA   -79.13mA   -91.25mA
-1.14V    -74.96mA   -71.48mA   -84.07mA
-1.1V     -67.78mA   -64.03mA   -77.37mA
-980mV    -48.75mA   -43.45mA   -60.92mA
-820mV    -30.44mA   -22.74mA   -40.78mA
-700mV    -18.19mA   -11.71mA   -24.91mA
-620mV    -10.97mA   -6.417mA   -15.35mA
-540mV    -5.153mA   -2.725mA   -7.352mA
-460mV    -1.523mA   -762.5uA   -2.097mA
-260mV    -8.322uA   -6.87uA    -12.82uA
5V        0A         0A         0A
[POWER_clamp]
|Voltage   I(typ)   I(min)   I(max)
-2.48V    65.19mA    74.36mA    52.81mA
-1.6V     7.807mA    26.1mA     631.8uA
-1.52V    5.015mA    21.36mA    114.1uA
-1.44V    2.812mA    16.63mA    21.97uA
-1.28V    342.3uA    7.7mA      2.522uA
-1.2V     73.31uA    4.13mA     1.862uA
-1.12V    15.66uA    1.836mA    1.57uA
-1.04V    3.339uA    680.9uA    1.346uA
-960mV    798.5nA    194.8uA    1.148uA
-880mV    287.8nA    46.96uA    970.3nA
-720mV    163.9nA    2.395uA    674.8nA
5V        -61.3nA    -52.64nA   -306.8nA
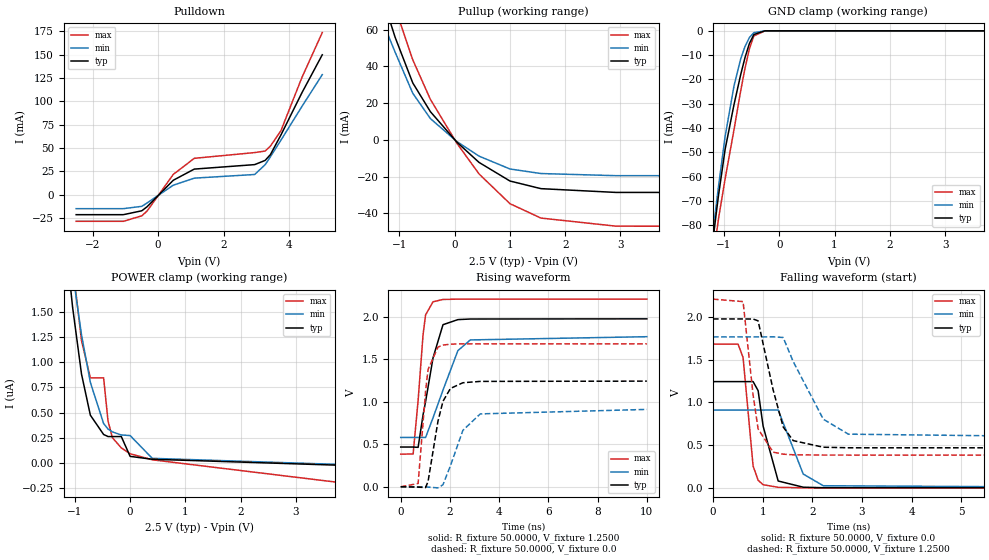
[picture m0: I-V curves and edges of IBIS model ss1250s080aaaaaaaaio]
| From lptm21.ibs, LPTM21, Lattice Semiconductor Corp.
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|   Model ss1250s080aaaaaaaaio
[Model]   ss1250s080aaaaaaaaio
Model_type   I/O
Polarity   Non-Inverting
Enable   Active-Low
Vinl =   1.0700V
Vinh =   1.4300V
Vmeas =   1.2500V
Cref =   30.0000pF
Rref =   50.0000
Vref =   1.2500V
C_comp   4.2000pF   3.8000pF   7.5000pF
[Temperature Range]   25.0000   0.1050k   -40.0000
[Voltage Range]   2.5000V   2.3800V   2.6300V
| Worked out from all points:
|   slope of the pulldown table from 0 to 0.375 V, typ, clamps not added: 28.8 ohm
|   slope of the pullup table from 0 to 0.375 V, typ, clamps not added: 35 ohm
|   GND clamp passes 1 mA (typ) near -0.44 V on its own axis
|   rising waveform, R_fixture 50.0000, V_fixture 1.2500: 20-80 % time 521ps typ, 890ps min, 322ps max; typ from 0.468 V to 1.98 V
|   rising waveform, R_fixture 50.0000, V_fixture 0.0: 20-80 % time 470ps typ, 715ps min, 288ps max; typ from 0 V to 1.24 V
|   falling waveform, R_fixture 50.0000, V_fixture 0.0: 20-80 % time 235ps typ, 316ps min, 162ps max; typ from 1.24 V to 0 V
|   falling waveform, R_fixture 50.0000, V_fixture 1.2500: 20-80 % time 358ps typ, 620ps min, 222ps max; typ from 1.98 V to 0.468 V
[Pulldown]
|Voltage   I(typ)   I(min)   I(max)
-2.5V     -21.43mA   -15mA      -28.53mA
-1.06V    -21.43mA   -15mA      -28.53mA
-500mV    -17.27mA   -12.48mA   -22.67mA
-340mV    -13mA      -8.935mA   -17.68mA
460mV     15.44mA    10.15mA    21.72mA
1.1V      27.41mA    17.71mA    38.96mA
2.94V     32.21mA    21.62mA    45.1mA
3.26V     36.74mA    32.14mA    46.73mA
3.42V     42.91mA    40.65mA    52.04mA
3.74V     63.96mA    58.33mA    68.49mA
4.38V     109.2mA    94.52mA    125.6mA
5V        149.9mA    128.6mA    173.7mA
[Pullup]
|Voltage   I(typ)   I(min)   I(max)
-2.5V     179.5mA    144.9mA    221.4mA
-1.96V    137.6mA    112.1mA    171.5mA
-1.64V    109.1mA    89.15mA    137.1mA
-1.08V    56.04mA    47.91mA    72.27mA
-760mV    31.08mA    25.44mA    43.69mA
-440mV    15.35mA    11.58mA    22.05mA
40mV      -1.275mA   -931.8uA   -1.898mA
440mV     -12.3mA    -8.882mA   -18.58mA
1V        -22.45mA   -15.89mA   -34.81mA
1.56V     -26.61mA   -18.37mA   -42.65mA
2.92V     -28.67mA   -19.54mA   -47.07mA
4.96V     -28.67mA   -19.54mA   -47.11mA
[GND_clamp]
|Voltage   I(typ)   I(min)   I(max)
-2.5V     -564.7mA   -543.1mA   -585.2mA
-1.18V    -82.42mA   -79.12mA   -91.23mA
-1.14V    -74.95mA   -71.46mA   -84.05mA
-1.1V     -67.77mA   -64.02mA   -77.35mA
-980mV    -48.74mA   -43.44mA   -60.9mA
-820mV    -30.43mA   -22.73mA   -40.76mA
-700mV    -18.18mA   -11.7mA    -24.9mA
-620mV    -10.96mA   -6.411mA   -15.34mA
-540mV    -5.147mA   -2.721mA   -7.345mA
-460mV    -1.52mA    -760.7uA   -2.094mA
-260mV    -8.288uA   -6.851uA   -12.77uA
5V        0A         0A         0A
[POWER_clamp]
|Voltage   I(typ)   I(min)   I(max)
-2.48V    16.7uA     13.49uA    27.31uA
-1.12V    1.963uA    2.259uA    2.527uA
-1.04V    1.544uA    1.895uA    1.972uA
-880mV    883.4nA    1.275uA    1.216uA
-720mV    474.1nA    800.8nA    845.7nA
-480mV    281.5nA    390.9nA    845.7nA
-400mV    261nA      336nA      415nA
-320mV    261nA      306.9nA    249.1nA
-160mV    261nA      276.7nA    147.9nA
0V        63.49nA    270.9nA    89.65nA
400mV     34.81nA    44.11nA    29.35nA
5V        -46.25nA   -38.77nA   -277.8nA
[Ramp]
| variable   typ   min   max
dV/dt_r  0.7610/0.4652n   0.5462/0.7078n   1.0094/0.2854n
dV/dt_f  0.8277/0.4526n   0.5716/0.6695n   1.0508/0.3023n
R_load = 50.0000
[Rising Waveform]
R_fixture=   50.0000
V_fixture=   1.2500
V_fixture_min=   1.1880
V_fixture_max=   1.3130
|time   V(typ)   V(min)   V(max)
0s        467.6mV    580.4mV    383.5mV
505.1ps   467.6mV    580.4mV    386.3mV
707.1ps   463.8mV    580.4mV    1.017V
909.1ps   848.7mV    580.6mV    1.794V
1.01ns    1.001V     579.8mV    2.022V
1.313ns   1.517V     811.8mV    2.177V
1.717ns   1.907V     1.137V     2.204V
2.323ns   1.967V     1.602V     2.208V
2.828ns   1.974V     1.728V     2.208V
10ns      1.976V     1.766V     2.208V
[Rising Waveform]
R_fixture=   50.0000
V_fixture=   0.0
V_fixture_min=   0.0
V_fixture_max=   0.0
|time   V(typ)   V(min)   V(max)
0s        693.1nV    932.7nV    570.7nV
707.1ps   -4.266mV   7.527uV    38.32mV
1.01ns    -9.218mV   -450.4uV   1.123V
1.111ns   62.45mV    -4.51mV    1.38V
1.515ns   773.4mV    -12.82mV   1.644V
1.717ns   1.006V     24.27mV    1.667V
2.02ns    1.157V     247.5mV    1.678V
2.525ns   1.224V     663.6mV    1.682V
3.232ns   1.24V      857.5mV    1.682V
10ns      1.243V     910.3mV    1.682V
[Falling Waveform]
R_fixture=   50.0000
V_fixture=   0.0
V_fixture_min=   0.0
V_fixture_max=   0.0
|time   V(typ)   V(min)   V(max)
0s        1.243V     910.3mV    1.682V
505.1ps   1.243V     910.3mV    1.682V
606.1ps   1.243V     910.3mV    1.525V
808.1ps   1.243V     910.4mV    255.8mV
909.1ps   1.137V     910.3mV    88.44mV
1.01ns    721.1mV    910.3mV    36.93mV
1.313ns   80.15mV    910.8mV    6.403mV
1.818ns   7.602mV    161.3mV    418.7uV
2.222ns   1.69mV     24.92mV    110uV
10ns      3.659uV    -12.37uV   15.6uV
[Falling Waveform]
R_fixture=   50.0000
V_fixture=   1.2500
V_fixture_min=   1.1880
V_fixture_max=   1.3130
|time   V(typ)   V(min)   V(max)
0s        1.976V     1.766V     2.208V
606.1ps   1.976V     1.766V     2.179V
808.1ps   1.975V     1.766V     1.085V
909.1ps   1.954V     1.766V     688.5mV
1.212ns   1.145V     1.767V     417.8mV
1.414ns   712.4mV    1.759V     394.1mV
1.616ns   552.7mV    1.477V     387mV
2.222ns   475.5mV    803.2mV    383.7mV
2.727ns   468.9mV    628.1mV    383.5mV
10ns      467.6mV    580.4mV    383.5mV
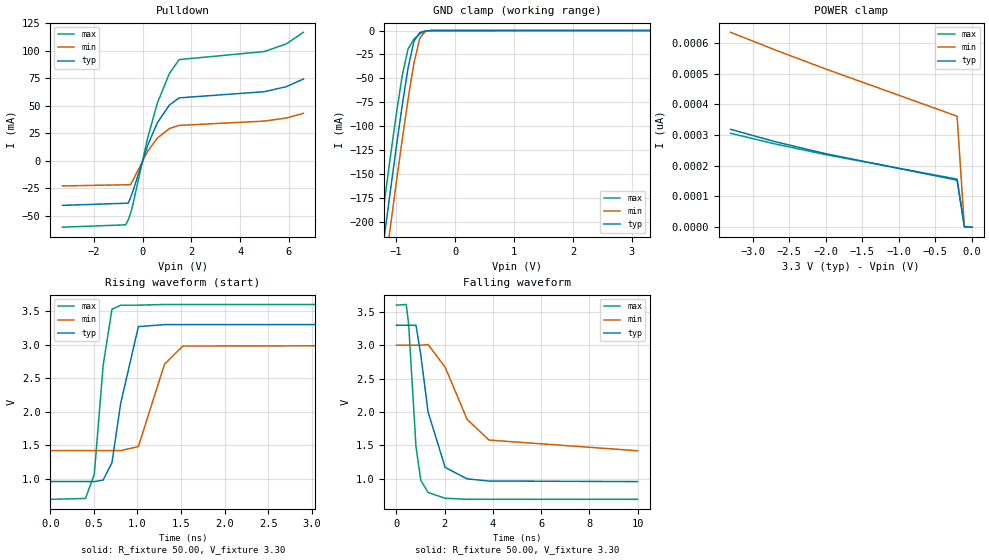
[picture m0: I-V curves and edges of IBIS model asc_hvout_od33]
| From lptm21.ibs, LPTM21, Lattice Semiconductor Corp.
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|   Model asc_hvout_od33
[Model]   asc_hvout_od33
Model_type   Open_drain
Polarity   Non-Inverting
Enable   Active-Low
Vmeas =   1.65V
Rref =   2.50k
Vref =   3.30V
C_comp   10.00pF   7.00pF   15.00pF
[Temperature Range]   50.00   100.00   0.000
[Voltage Range]   3.30V   3.00V   3.60V
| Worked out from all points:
|   slope of the pulldown table from 0 to 0.495 V, typ, clamps not added: 16.8 ohm
|   GND clamp passes 1 mA (typ) near -0.54 V on its own axis
|   rising waveform, R_fixture 50.00, V_fixture 3.30: 20-80 % time 159ps typ, 209ps min, 128ps max; typ from 0.958 V to 3.3 V
|   falling waveform, R_fixture 50.00, V_fixture 3.30: 20-80 % time 658ps typ, 1.24ns min, 327ps max; typ from 3.3 V to 0.958 V
[Pulldown]
| voltage   I(typ)   I(min)   I(max)
-3.3V     -40.73mA   -23.07mA   -60.54mA
-700mV    -38.81mA   -22mA      -58.44mA
-600mV    -38.74mA   -21.95mA   -54.28mA
-500mV    -33.99mA   -21.91mA   -48.21mA
-400mV    -27.79mA   -17.98mA   -39.86mA
200mV     13.54mA    8.29mA     20.17mA
600mV     34.22mA    20.43mA    52.15mA
1.1V      50.56mA    29.13mA    79.29mA
1.5V      57mA       31.97mA    91.8mA
5V        62.63mA    35.9mA     99.14mA
5.9V      67.18mA    38.69mA    106.1mA
6.6V      74.12mA    42.91mA    116.6mA
[GND_clamp]
| voltage   I(typ)   I(min)   I(max)
-3.3V     -1.24A     -1.28A     -1.2A
-1.3V     -261.1mA   -299mA     -224.9mA
-1.2V     -213.9mA   -251.8mA   -177.9mA
-1.1V     -167.5mA   -205.1mA   -132mA
-1V       -122.1mA   -159.2mA   -87.77mA
-900mV    -78.67mA   -114.5mA   -47.65mA
-800mV    -39.4mA    -72.06mA   -19.39mA
-700mV    -11.32mA   -34.17mA   -8.94mA
-600mV    -2.08mA    -7.95mA    -3.57mA
-500mV    -296.8uA   -591.4uA   -716.2uA
-400mV    -23.18uA   -29.44uA   -55.49uA
3.3V      144.2pA    369.4pA    135.4pA
[POWER_clamp]
| voltage   I(typ)   I(min)   I(max)
-3.3V     318.3pA    634pA      305.4pA
-2.7V     278.7pA    577.5pA    271.2pA
-2V       239.1pA    514.8pA    236pA
-200mV    153pA      361pA      156.4pA
-100mV    1.5pA      1.2pA      1.8pA
0V        0A         0A         0A
[Ramp]
| variable   typ   min   max
dV/dt_r   1.94/2.88n   1.72/3.31n   2.14/2.38n
dV/dt_f   1.97/190.62p   1.78/364.06p   2.15/108.23p
R_load = 2.50k
[Rising Waveform]
R_fixture = 50.00
V_fixture = 3.30
V_fixture_min = 3.00
V_fixture_max = 3.60
C_fixture = 0.000F
| time   V(typ)   V(min)   V(max)
0s        958.2mV    1.42V      692.6mV
404ps     958.2mV    1.42V      705.9mV
505.1ps   956.8mV    1.42V      1.07V
606.1ps   980.3mV    1.42V      2.69V
707.1ps   1.24V      1.42V      3.53V
808.1ps   2.13V      1.42V      3.59V
1.01ns    3.27V      1.48V      3.59V
1.31ns    3.3V       2.71V      3.6V
1.52ns    3.3V       2.98V      3.6V
10ns      3.3V       3V         3.6V
[Falling Waveform]
R_fixture = 50.00
V_fixture = 3.30
V_fixture_min = 3.00
V_fixture_max = 3.60
C_fixture = 0.000F
| time   V(typ)   V(min)   V(max)
0s        3.3V       3V         3.6V
404ps     3.3V       3V         3.61V
505.1ps   3.3V       3V         3.31V
808.1ps   3.3V       3V         1.48V
1.01ns    2.85V      3V         977.1mV
1.31ns    2V         3.01V      795.3mV
2.02ns    1.17V      2.67V      708.3mV
2.93ns    999.2mV    1.89V      694.1mV
3.84ns    966.5mV    1.58V      692.7mV
10ns      958.2mV    1.42V      692.6mV
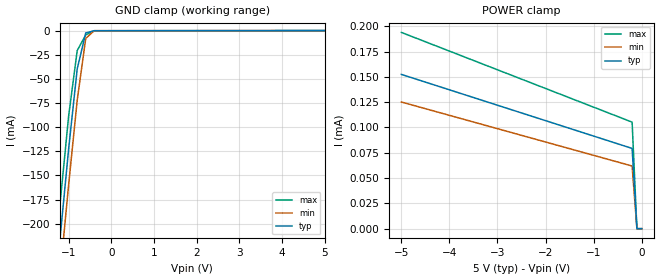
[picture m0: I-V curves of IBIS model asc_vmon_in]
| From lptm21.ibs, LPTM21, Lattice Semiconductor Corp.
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|   Model asc_vmon_in
[Model]   asc_vmon_in
Model_type   Terminator
C_comp   10.00pF   7.00pF   15.00pF
[Temperature Range]   50.00   100.00   0.000
[Voltage Range]   5.00V   4.50V   5.50V
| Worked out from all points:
|   GND clamp passes 1 mA (typ) near -0.48 V on its own axis
[GND_clamp]
| voltage   I(typ)   I(min)   I(max)
-5V       -2.08A     -2.12A     -2.05A
-1.4V     -308.7mA   -346.7mA   -272.5mA
-1.2V     -214mA     -251.8mA   -178.1mA
-1V       -122.2mA   -159.3mA   -88.12mA
-800mV    -39.63mA   -72.1mA    -20.65mA
-600mV    -2.4mA     -8.02mA    -4.34mA
-400mV    -39.51uA   -37.71uA   -101.1uA
5V        76.25uA    65.87uA    92.4uA
[POWER_clamp]
| voltage   I(typ)   I(min)   I(max)
-5V       152.5uA    125.2uA    194uA
-200mV    79.31uA    61.92uA    105.3uA
-100mV    1.5pA      1.2pA      1.8pA
0V        0A         0A         0A
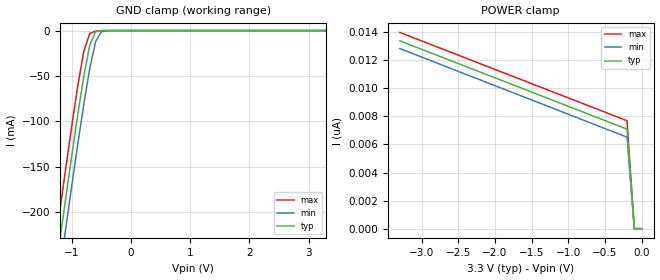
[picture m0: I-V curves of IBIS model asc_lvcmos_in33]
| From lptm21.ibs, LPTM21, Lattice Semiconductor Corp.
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|   Model asc_lvcmos_in33
|Copied from 1208 IBIS
[Model]   asc_lvcmos_in33
Model_type   Input
Vinl = 800.00mV
Vinh =   2.00V
C_comp   10.00pF   7.00pF   15.00pF
[Temperature Range]   50.00   100.00   0.000
[Voltage Range]   3.30V   3.00V   3.60V
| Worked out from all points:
|   GND clamp passes 1 mA (typ) near -0.57 V on its own axis
[GND_clamp]
| voltage   I(typ)   I(min)   I(max)
-3.3V     -1.25A     -1.29A     -1.22A
-1.3V     -276.3mA   -309.8mA   -243.4mA
-1.2V     -229mA     -262.5mA   -196mA
-1.1V     -182.2mA   -215.6mA   -149.3mA
-1V       -136.2mA   -169.5mA   -103.7mA
-900mV    -91.76mA   -124.5mA   -60.33mA
-800mV    -50.21mA   -81.31mA   -22.76mA
-700mV    -16.19mA   -41.97mA   -3.22mA
-600mV    -1.41mA    -12.07mA   -501.2uA
-500mV    -62.47uA   -1.09mA    -65.4uA
-300mV    -215.1nA   -2.63uA    -276.8nA
3.3V      6.68nA     6.72nA     6.67nA
[POWER_clamp]
| voltage   I(typ)   I(min)   I(max)
-3.3V     13.38nA    12.83nA    13.98nA
-200mV    7.09nA     6.52nA     7.69nA
-100mV    1.5pA      1.2pA      1.8pA
0V        0A         0A         0A
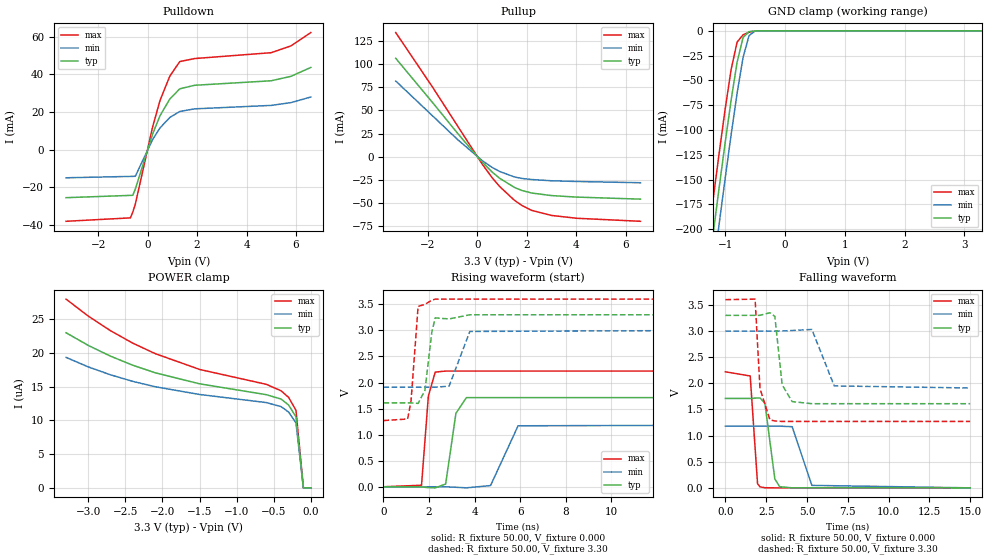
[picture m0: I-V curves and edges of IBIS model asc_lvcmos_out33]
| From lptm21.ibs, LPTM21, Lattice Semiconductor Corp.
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|   Model asc_lvcmos_out33
[Model]   asc_lvcmos_out33
Model_type   3-state
Enable   Active-Low
Vmeas =   1.65V
C_comp   10.00pF   7.00pF   15.00pF
[Temperature Range]   50.00   100.00   0.000
[Voltage Range]   3.30V   3.00V   3.60V
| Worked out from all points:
|   slope of the pulldown table from 0 to 0.495 V, typ, clamps not added: 27.6 ohm
|   slope of the pullup table from 0 to 0.495 V, typ, clamps not added: 35.3 ohm
|   GND clamp passes 1 mA (typ) near -0.60 V on its own axis
|   rising waveform, R_fixture 50.00, V_fixture 0.000: 20-80 % time 317ps typ, 502ps min, 226ps max; typ from 0 V to 1.71 V
|   rising waveform, R_fixture 50.00, V_fixture 3.30: 20-80 % time 272ps typ, 380ps min, 233ps max; typ from 1.61 V to 3.3 V
|   falling waveform, R_fixture 50.00, V_fixture 0.000: 20-80 % time 391ps typ, 575ps min, 263ps max; typ from 1.71 V to 0 V
|   falling waveform, R_fixture 50.00, V_fixture 3.30: 20-80 % time 375ps typ, 528ps min, 285ps max; typ from 3.3 V to 1.61 V
[Pulldown]
| voltage   I(typ)   I(min)   I(max)
-3.3V     -25.49mA   -14.92mA   -38.04mA
-700mV    -24.27mA   -14.19mA   -36.22mA
-600mV    -24.22mA   -14.16mA   -33.16mA
-500mV    -21.01mA   -14.13mA   -29.05mA
200mV     8.33mA     5.36mA     12.03mA
500mV     18.06mA    11.58mA    26.13mA
900mV     26.99mA    17.15mA    39.15mA
1.3V      32.35mA    20.31mA    46.82mA
1.9V      34.23mA    21.71mA    48.43mA
5V        36.63mA    23.54mA    51.55mA
5.8V      39mA       25.02mA    55.19mA
6.6V      43.71mA    27.99mA    62.24mA
[Pullup]
| voltage   I(typ)   I(min)   I(max)
-3.3V     106.3mA    81.75mA    134.1mA
-1.8V     58.17mA    43.84mA    74.71mA
-800mV    25.28mA    18.53mA    33.23mA
200mV     -6.06mA    -4.31mA    -8.16mA
600mV     -16.63mA   -11.6mA    -22.72mA
900mV     -23.28mA   -15.98mA   -32.16mA
1.5V      -33.21mA   -21.93mA   -47.15mA
1.8V      -36.52mA   -23.55mA   -52.7mA
2.2V      -39.32mA   -24.73mA   -58.08mA
3V        -42.07mA   -26.05mA   -63.51mA
4V        -43.68mA   -26.82mA   -66.55mA
6.6V      -45.91mA   -28.19mA   -69.86mA
[GND_clamp]
| voltage   I(typ)   I(min)   I(max)
-3.3V     -1.23A     -1.26A     -1.2A
-1.3V     -251.7mA   -288.4mA   -216.5mA
-1.2V     -204.6mA   -241.3mA   -169.5mA
-1.1V     -158.2mA   -194.8mA   -123.5mA
-1V       -113mA     -149.1mA   -79.25mA
-900mV    -69.98mA   -104.8mA   -39.06mA
-800mV    -31.69mA   -62.98mA   -11.46mA
-700mV    -6.75mA    -26.8mA    -4mA
-600mV    -866.4uA   -4.78mA    -1.38mA
-500mV    -98.89uA   -292.8uA   -213.3uA
-400mV    -6.67uA    -13.94uA   -12.68uA
3.3V      166pA      55.14nA    58.43pA
[POWER_clamp]
| voltage   I(typ)   I(min)   I(max)
-3.3V     22.97uA    19.32uA    27.95uA
-3V       21.09uA    17.91uA    25.43uA
-2.7V     19.5uA     16.74uA    23.27uA
-2.4V     18.16uA    15.77uA    21.43uA
-2.1V     17.05uA    14.98uA    19.89uA
-1.5V     15.41uA    13.83uA    17.54uA
-600mV    13.8uA     12.63uA    15.33uA
-400mV    13.15uA    12.03uA    14.37uA
-300mV    12.27uA    11.23uA    13.41uA
-200mV    10.52uA    9.62uA     11.49uA
-100mV    1.5pA      1.2pA      1.8pA
0V        0A         0A         0A
[Ramp]
| variable   typ   min   max
dV/dt_r   1.89/188.82p   1.68/319.12p   2.08/120.53p
dV/dt_f   1.92/162.00p   1.71/273.76p   2.11/102.53p
R_load = 680.00
[Rising Waveform]
R_fixture = 50.00
V_fixture = 0.000
V_fixture_min = 0.000
V_fixture_max = 0.000
C_fixture = 0.000F
| time   V(typ)   V(min)   V(max)
0s        50.93nV    66.29nV    -7.55nV
1.67ns    -3.62mV    -2.96uV    29.26mV
1.97ns    -16.64mV   -6.95uV    1.74V
2.27ns    -21mV      88.04uV    2.2V
2.73ns    53.1mV     -573.4uV   2.22V
3.18ns    1.41V      -9.86mV    2.22V
3.64ns    1.71V      -20.46mV   2.22V
4.7ns     1.71V      22.89mV    2.22V
5.91ns    1.71V      1.17V      2.22V
15ns      1.71V      1.18V      2.22V
[Rising Waveform]
R_fixture = 50.00
V_fixture = 3.30
V_fixture_min = 3.00
V_fixture_max = 3.60
C_fixture = 0.000F
| time   V(typ)   V(min)   V(max)
0s        1.61V      1.91V      1.27V
1.06ns    1.61V      1.91V      1.3V
1.21ns    1.61V      1.91V      1.65V
1.52ns    1.6V       1.91V      3.46V
1.82ns    1.85V      1.91V      3.5V
2.12ns    2.96V      1.91V      3.58V
2.27ns    3.24V      1.91V      3.6V
2.88ns    3.22V      1.93V      3.6V
3.79ns    3.3V       2.98V      3.6V
15ns      3.3V       3V         3.6V
[Falling Waveform]
R_fixture = 50.00
V_fixture = 0.000
V_fixture_min = 0.000
V_fixture_max = 0.000
C_fixture = 0.000F
| time   V(typ)   V(min)   V(max)
0s        1.71V      1.18V      2.22V
1.52ns    1.71V      1.18V      2.14V
1.97ns    1.72V      1.18V      81.54mV
2.12ns    1.72V      1.18V      19.16mV
2.42ns    1.62V      1.18V      2.64mV
3.03ns    169.6mV    1.18V      18.46uV
3.33ns    21.38mV    1.18V      -45.03uV
4.09ns    536.9uV    1.17V      -33.41uV
5.3ns     -121.9uV   47.31mV    -9.97uV
15ns      -1.8uV     -5.4uV     -1.09uV
[Falling Waveform]
R_fixture = 50.00
V_fixture = 3.30
V_fixture_min = 3.00
V_fixture_max = 3.60
C_fixture = 0.000F
| time   V(typ)   V(min)   V(max)
0s        3.3V       3V         3.6V
1.82ns    3.3V       3V         3.61V
2.12ns    3.3V       3V         1.9V
2.73ns    3.35V      3V         1.3V
3.03ns    3.28V      3V         1.28V
3.48ns    1.97V      3V         1.27V
4.09ns    1.65V      3.01V      1.27V
5.3ns     1.61V      3.03V      1.27V
6.67ns    1.61V      1.95V      1.27V
15ns      1.61V      1.91V      1.27V
